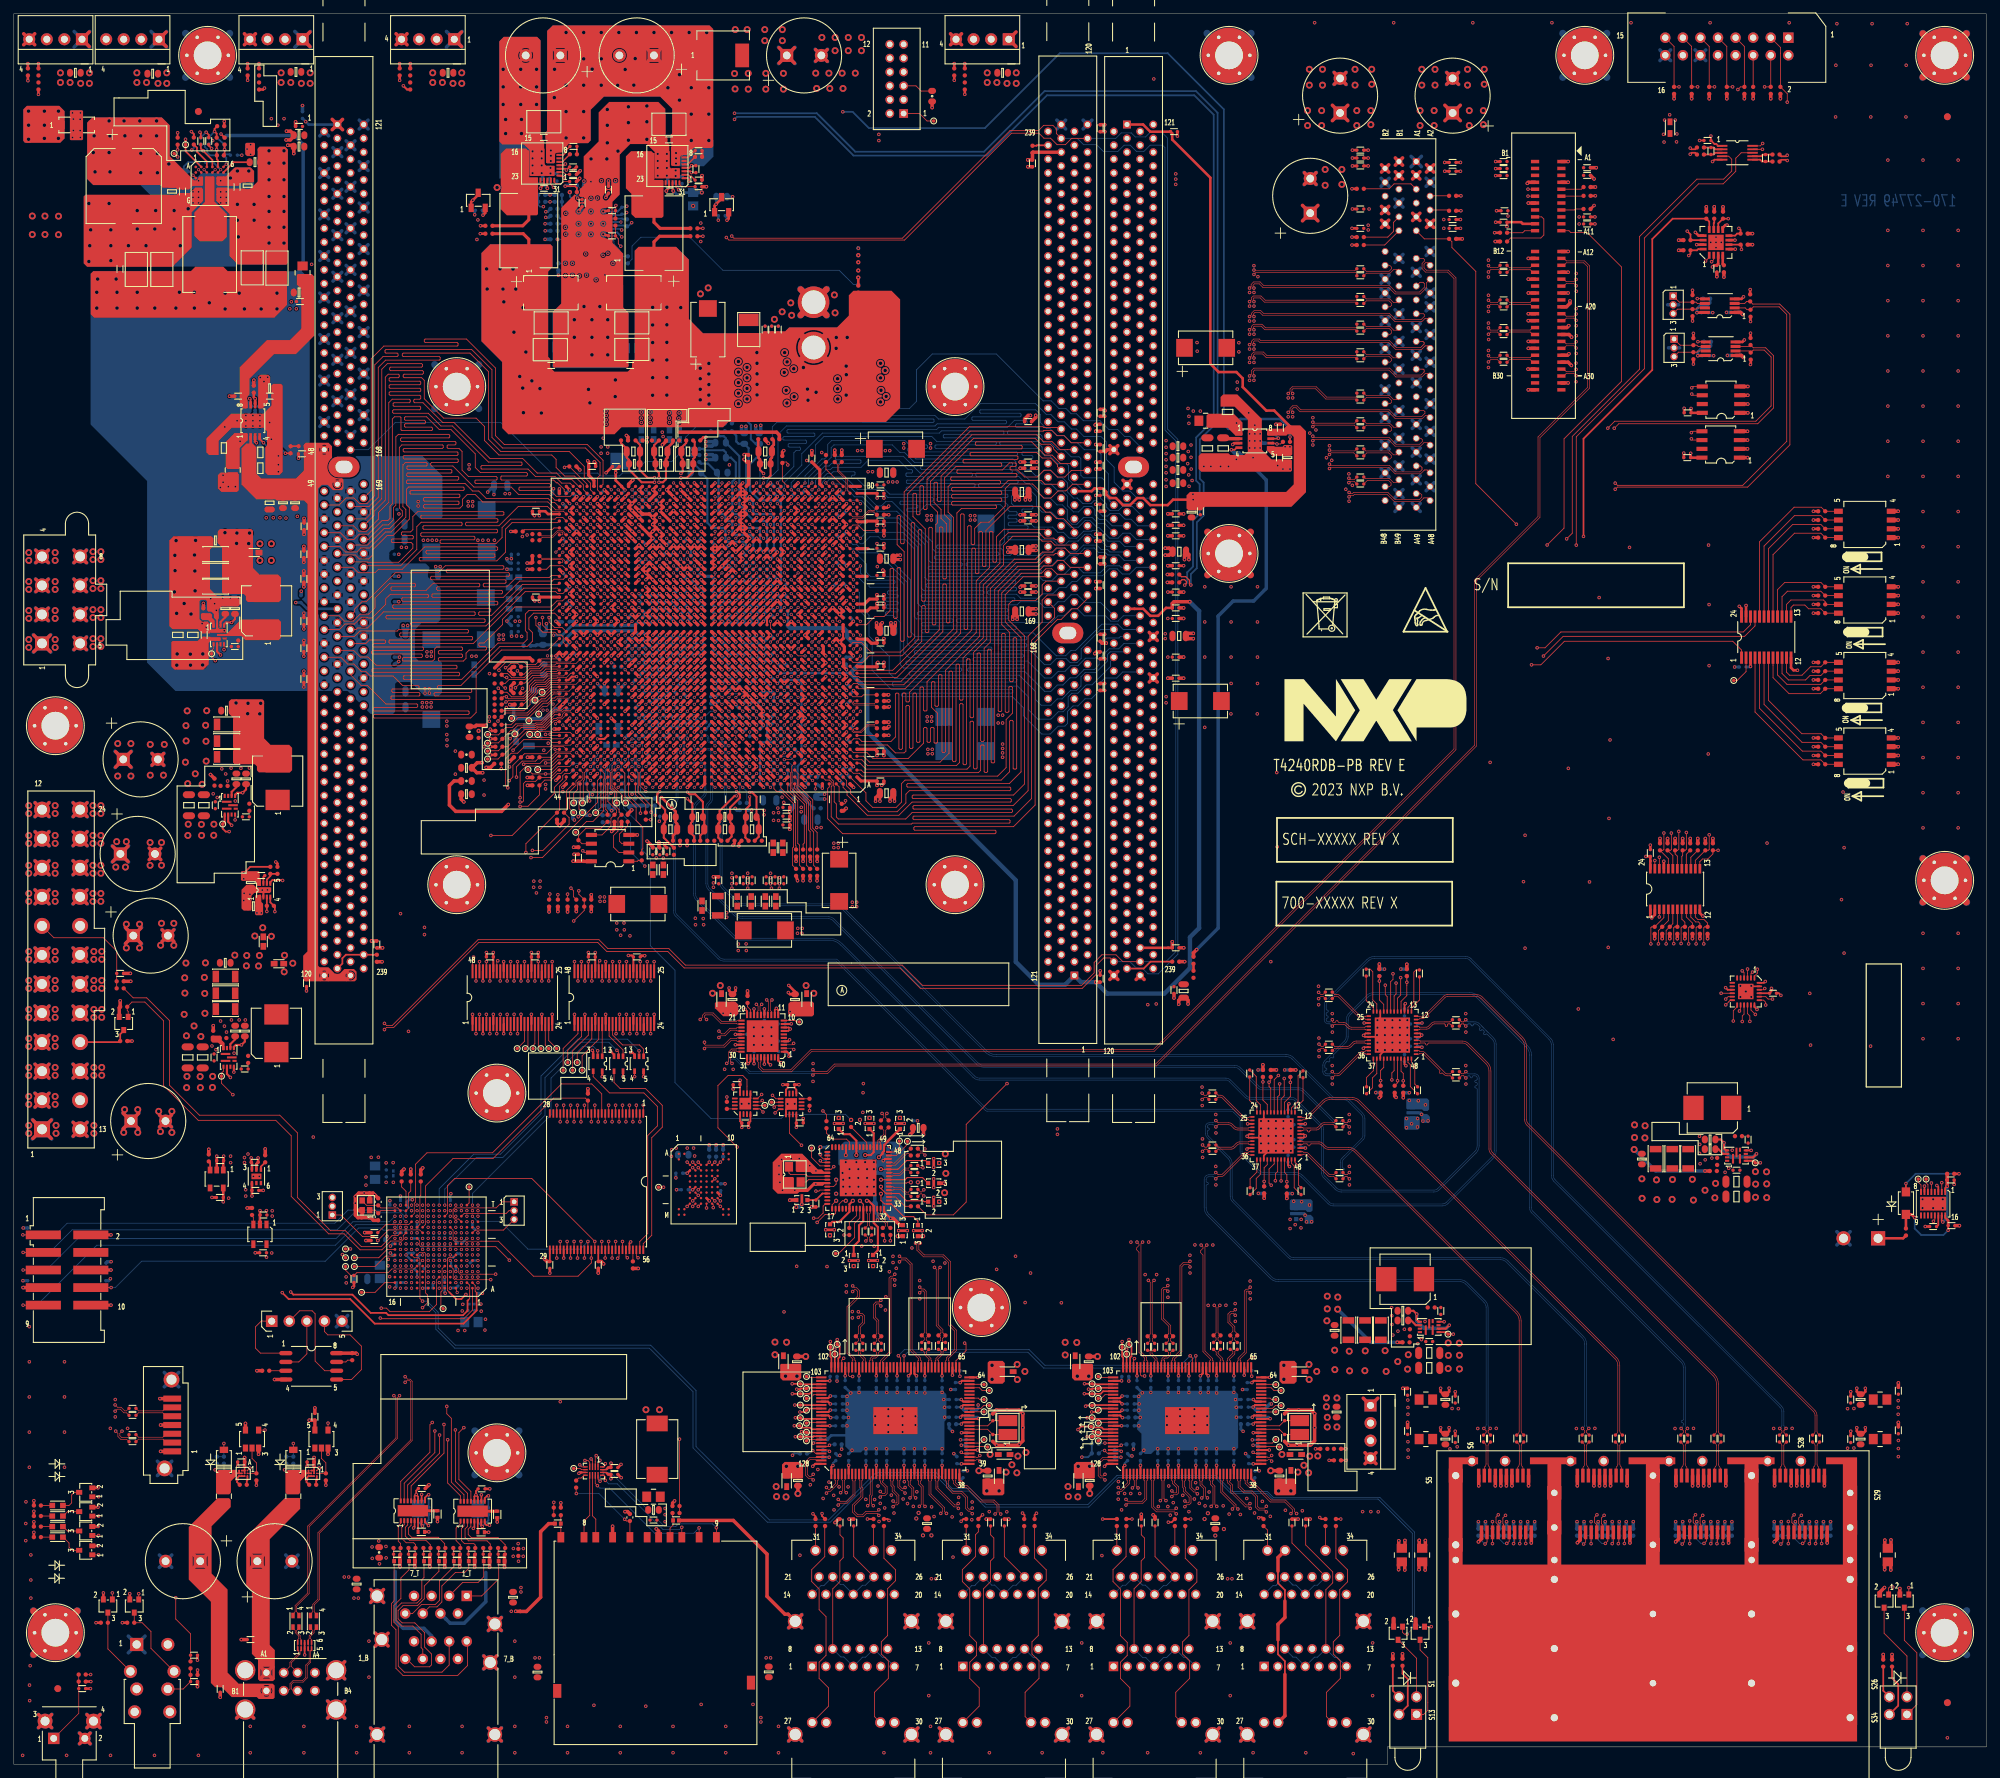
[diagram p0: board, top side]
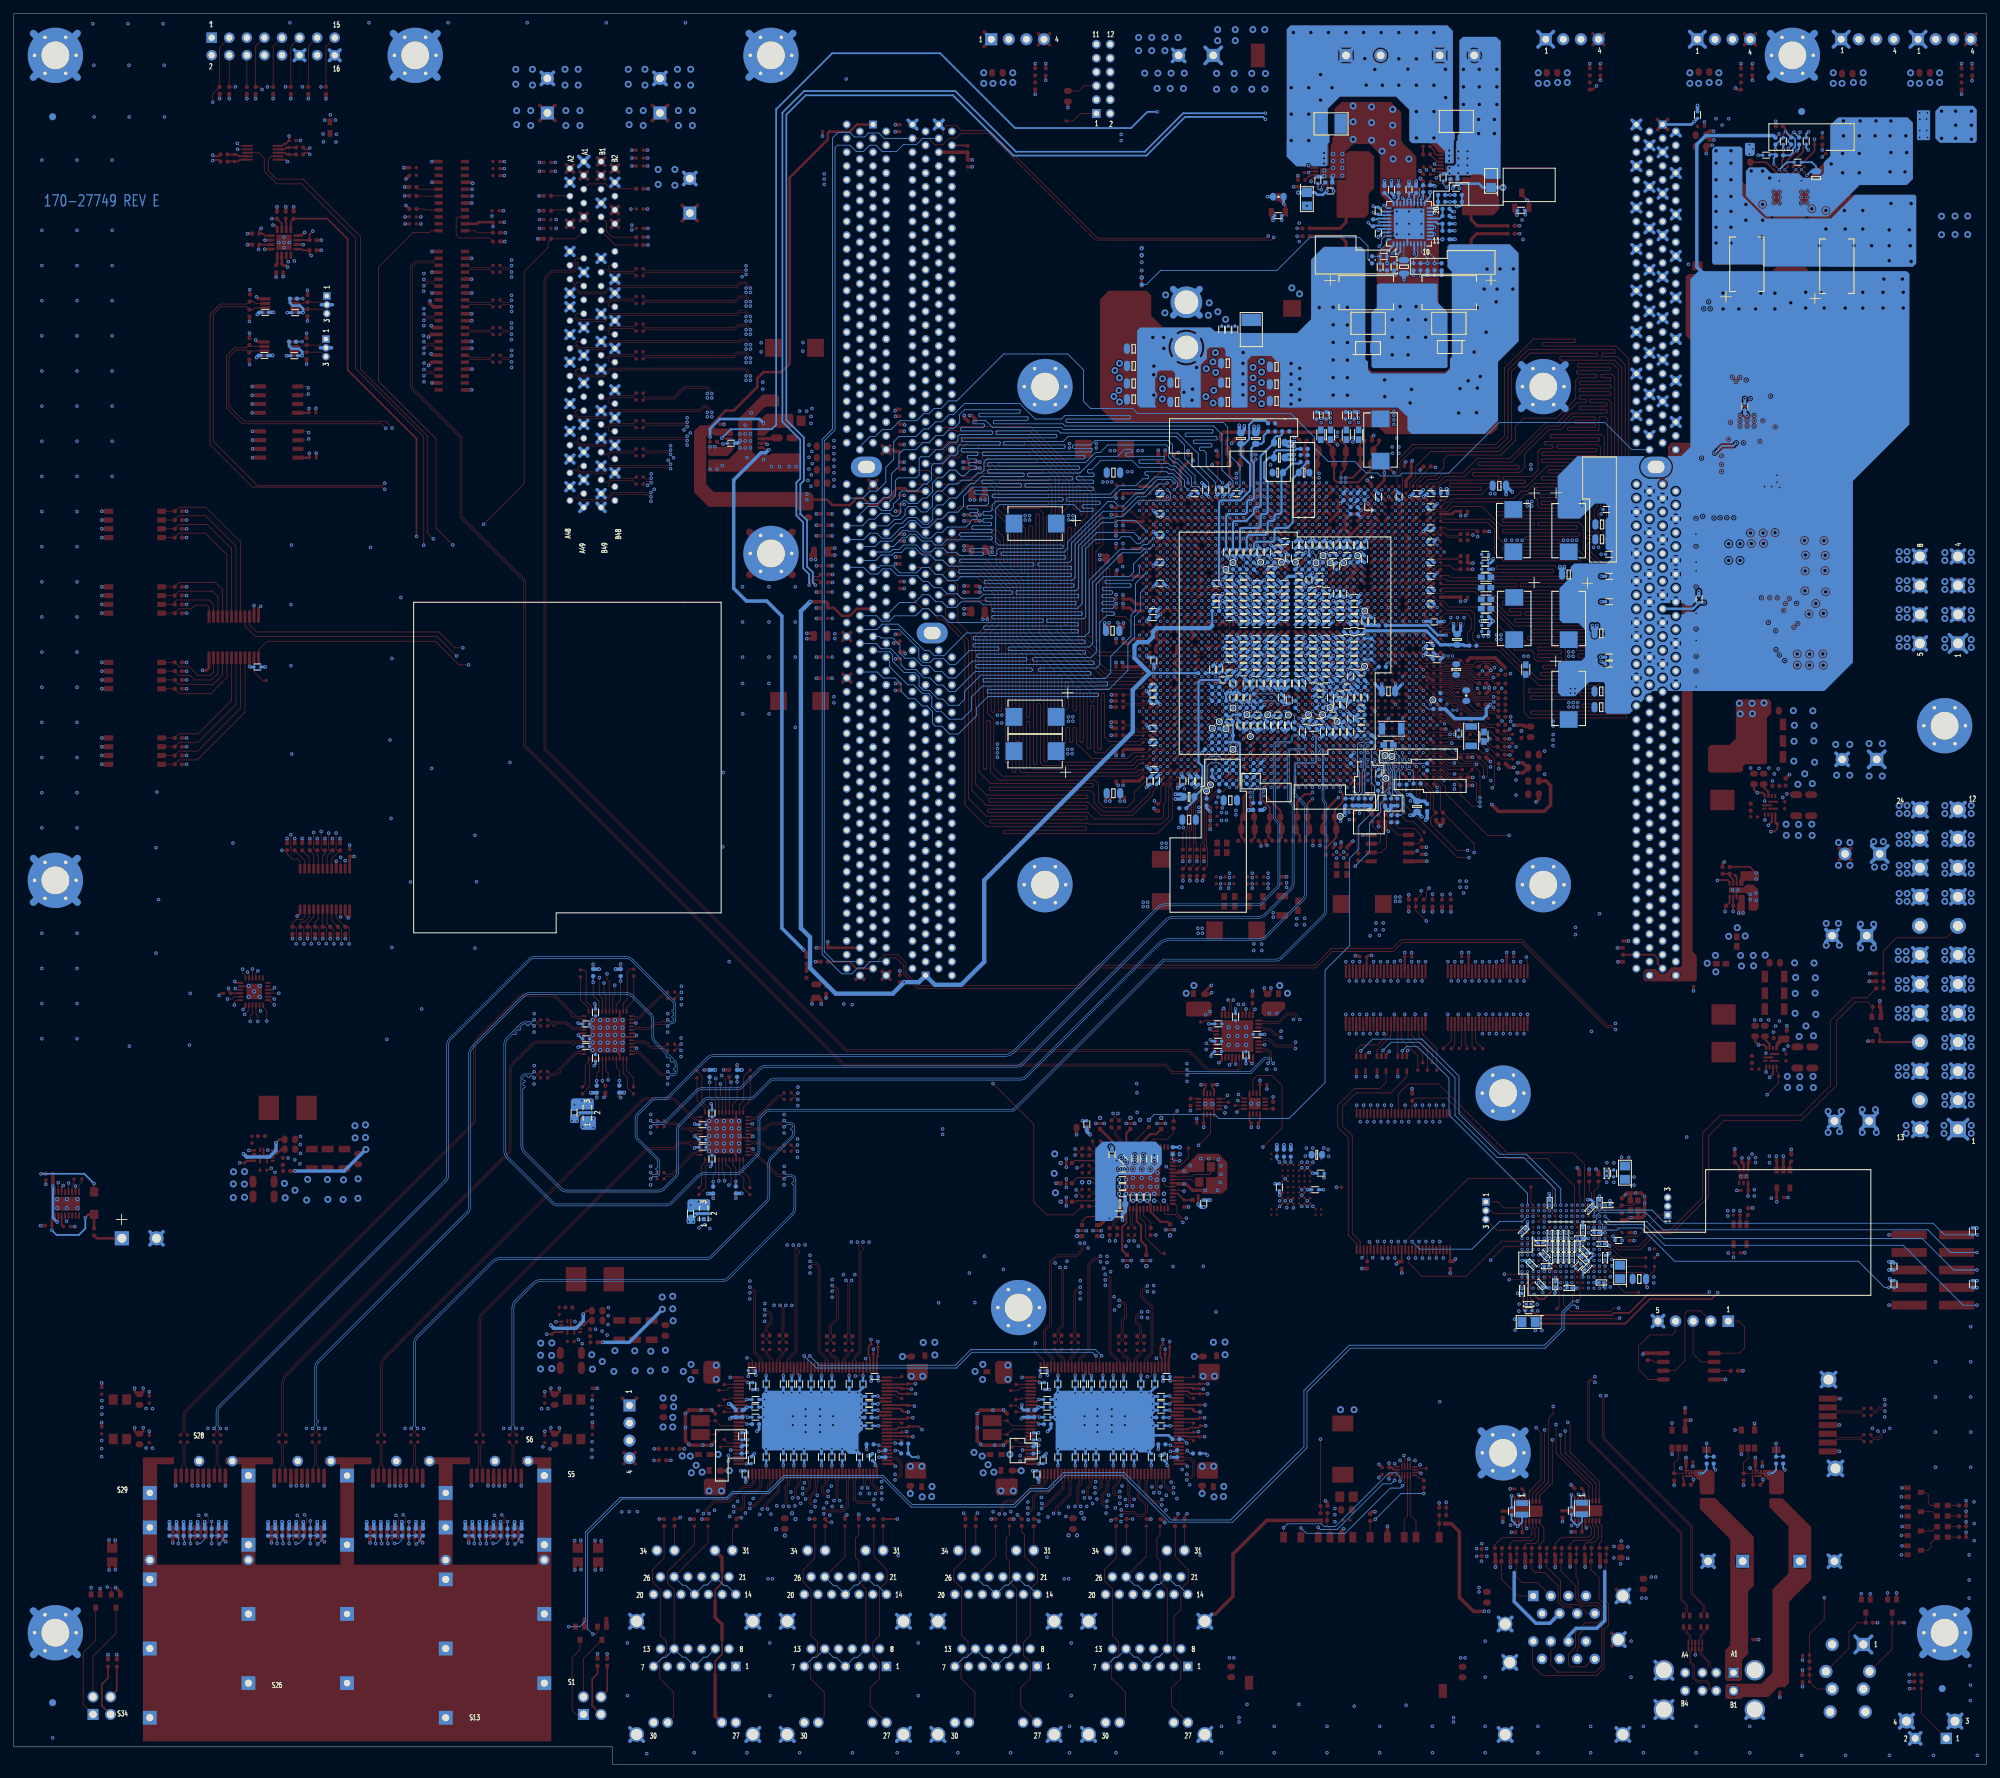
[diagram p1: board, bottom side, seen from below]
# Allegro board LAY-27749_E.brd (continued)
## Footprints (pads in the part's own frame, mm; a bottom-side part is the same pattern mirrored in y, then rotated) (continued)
CAP_5X19P2_TH
  rect 2.057x2.057 hole 1.295: 1(2.5,0)
  round 2.057 hole 1.295: 2(-2.5,0)
CAP_10P5_RAD
  rect 1.88x1.88 hole 1.118: 1(0,0)
  round 1.88 hole 1.118: 2(5,0)
CC0201
  rect 0.47x0.381 smd: 1(-0.343,0) 2(0.343,0)
CC0402_25
  round 0.635 smd: 1(-0.508,0) 2(0.508,0)
CC0402_HD
  round 0.508 smd: 1(-0.5,0) 2(0.5,0)
CC0402_TOL0P2
  rect 0.457x0.61 smd: 1(-0.475,0) 2(0.475,0)
CC0603_NFM18PC
  rect 0.61x0.61 smd: 1(-0.8,0) 3(0.8,0)
  rect 0.406x1.702 smd: 2(0,0)
CC0603_OV
  oval 0.889x1.143 smd: 1(-0.762,0) 2(0.762,0)
CC0805
  rect 1.295x1.499 smd: 1(-0.965,0) 2(0.965,0)
CC0805_OV
  oval 0.889x1.524 smd: 1(-0.965,0) 2(0.965,0)
CC1206_OV
  oval 1.016x1.778 smd: 1(-1.524,0) 2(1.524,0)
CC1210
  rect 1.778x2.845 smd: 1(-1.397,0) 2(1.397,0)
CC7343A
  rect 2.413x2.591 smd: 1(-3.05,0) 2(3.05,0)
CC7343A_LP
  rect 2.413x2.591 smd: 1(-3.05,0) 2(3.05,0)
CC_NFM41P_1806
  rect 1.295x1.219 smd: 1(-2.375,0) 3(2.375,0)
  rect 1.524x1.016 smd: 2A(0,-0.813) 2B(0,0.813)
CCE10_3X10_3
  rect 4.394x1.905 smd: 1(-4.343,0) 2(4.343,0)
CON12_SHRD_2MM_TH
  rect 1.27x1.27 hole 0.813: 1(0,0)
  round 1.27 hole 0.813: 2(0,2) 3(2,0) 4(2,2) 5(4,0) 6(4,2) 7(6,0) 8(6,2) 9(8,0) 10(8,2) 11(10,0) 12(10,2)
CON16_RJ45_JACK_50MIL_RA_TH
  round 0 hole 3.251 unplated: (-10.16,-15.46) (1.27,-15.46)
  round 1.524 hole 0.889: 1_B(-8.89,-9.11) 2_B(-7.62,-6.57) 2_T(-1.27,-2.54) 3_B(-6.35,-9.11) 3_T(-2.54,0) 4_B(-5.08,-6.57) 4_T(-3.81,-2.54) 5_B(-3.81,-9.11) 5_T(-5.08,0) 6_B(-2.54,-6.57) 6_T(-6.35,-2.54) 7_B(-1.27,-9.11) 7_T(-7.62,0) 8_B(0,-6.57) 8_T(-8.89,-2.54)
  rect 1.524x1.524 hole 0.889: 1_T(0,0)
  round 2.108 hole 1.6: S1(-12.95,0) S2(4.06,-4.06) S3(-12.285,-6.31) S4(3.395,-9.61) S5(-12.95,-20.03) S6(4.06,-20.03)
CON64_1MM_SM_PCIE_LP
  round 0 hole 1.27 unplated: (-17.85,0) (17.85,-1)
  rect 0.508x1.194 smd: A1(-16.5,1.9) A2(-15.5,1.9) A3(-14.5,1.9) A4(-13.5,1.9) A5(-12.5,1.9) A6(-11.5,1.9) A7(-10.5,1.9) A8(-9.5,1.9) A9(-8.5,1.9) A10(-7.5,1.9) A11(-6.5,1.9) A12(-3.5,1.9) A13(-2.5,1.9) A14(-1.5,1.9) A15(-0.5,1.9) A16(0.5,1.9) A17(1.5,1.9) A18(2.5,1.9) A19(3.5,1.9) A20(4.5,1.9) A21(5.5,1.9) A22(6.5,1.9) A23(7.5,1.9) A24(8.5,1.9) A25(9.5,1.9) A26(10.5,1.9) A27(11.5,1.9) A28(12.5,1.9) A29(13.5,1.9) A30(14.5,1.9) A31(15.5,1.9) A32(16.5,1.9) B1(-16.5,-1.9) B2(-15.5,-1.9) B3(-14.5,-1.9) B4(-13.5,-1.9) B5(-12.5,-1.9) B6(-11.5,-1.9) B7(-10.5,-1.9) B8(-9.5,-1.9) B9(-8.5,-1.9) B10(-7.5,-1.9) B11(-6.5,-1.9) B12(-3.5,-1.9) B13(-2.5,-1.9) B14(-1.5,-1.9) B15(-0.5,-1.9) B16(0.5,-1.9) B17(1.5,-1.9) B18(2.5,-1.9) B19(3.5,-1.9) B20(4.5,-1.9) B21(5.5,-1.9) B22(6.5,-1.9) B23(7.5,-1.9) B24(8.5,-1.9) B25(9.5,-1.9) B26(10.5,-1.9) B27(11.5,-1.9) B28(12.5,-1.9) B29(13.5,-1.9) B30(14.5,-1.9) B31(15.5,-1.9) B32(16.5,-1.9)
CON_7_SATA_V_SM
  rect 0.889x2.591 smd: 1(3.81,0.1) 2(2.54,0.1) 3(1.27,0.1) 4(0,0.1) 5(-1.27,0.1) 6(-2.54,0.1) 7(-3.81,0.1)
  round 2.286 hole 1.448: M1(-6.56,0) M2(6.27,-1)
CON_240_DDR3_DIMM_SKT
  round 0 hole 2.438 unplated: (-7.5,0.95) (130.5,0.95)
  oval 2.997x4.496 hole 1.803x2.438: (49.5,0.95)
  rect 1.143x1.143 hole 0.711: 1(0,0)
  round 1.143 hole 0.711: 2(1,-1.9) 3(2,0) 4(3,-1.9) 5(4,0) 6(5,-1.9) 7(6,0) 8(7,-1.9) 9(8,0) 10(9,-1.9) 11(10,0) 12(11,-1.9) 13(12,0) 14(13,-1.9) 15(14,0) 16(15,-1.9) 17(16,0) 18(17,-1.9) 19(18,0) 20(19,-1.9) 21(20,0) 22(21,-1.9) 23(22,0) 24(23,-1.9) 25(24,0) 26(25,-1.9) 27(26,0) 28(27,-1.9) 29(28,0) 30(29,-1.9) 31(30,0) 32(31,-1.9) 33(32,0) 34(33,-1.9) 35(34,0) 36(35,-1.9) 37(36,0) 38(37,-1.9) 39(38,0) 40(39,-1.9) 41(40,0) 42(41,-1.9) 43(42,0) 44(43,-1.9) 45(44,0) 46(45,-1.9) 47(46,0) 48(47,-1.9) 49(52,0) 50(53,-1.9) 51(54,0) 52(55,-1.9) 53(56,0) 54(57,-1.9) 55(58,0) 56(59,-1.9) 57(60,0) 58(61,-1.9) 59(62,0) 60(63,-1.9) 61(64,0) 62(65,-1.9) 63(66,0) 64(67,-1.9) 65(68,0) 66(69,-1.9) 67(70,0) 68(71,-1.9) 69(72,0) 70(73,-1.9) 71(74,0) 72(75,-1.9) 73(76,0) 74(77,-1.9) 75(78,0) 76(79,-1.9) 77(80,0) 78(81,-1.9) 79(82,0) 80(83,-1.9) 81(84,0) 82(85,-1.9) 83(86,0) 84(87,-1.9) 85(88,0) 86(89,-1.9) 87(90,0) 88(91,-1.9) 89(92,0) 90(93,-1.9) 91(94,0) 92(95,-1.9) 93(96,0) 94(97,-1.9) 95(98,0) 96(99,-1.9) 97(100,0) 98(101,-1.9) 99(102,0) 100(103,-1.9) 101(104,0) 102(105,-1.9) 103(106,0) 104(107,-1.9) 105(108,0) 106(109,-1.9) 107(110,0) 108(111,-1.9) 109(112,0) 110(113,-1.9) 111(114,0) 112(115,-1.9) 113(116,0) 114(117,-1.9) 115(118,0) 116(119,-1.9) 117(120,0) 118(121,-1.9) 119(122,0) 120(123,-1.9) 121(0,3.8) 122(1,1.9) 123(2,3.8) 124(3,1.9) 125(4,3.8) 126(5,1.9) 127(6,3.8) 128(7,1.9) 129(8,3.8) 130(9,1.9) 131(10,3.8) 132(11,1.9) 133(12,3.8) 134(13,1.9) 135(14,3.8) 136(15,1.9) 137(16,3.8) 138(17,1.9) 139(18,3.8) 140(19,1.9) 141(20,3.8) 142(21,1.9) 143(22,3.8) 144(23,1.9) 145(24,3.8) 146(25,1.9) 147(26,3.8) 148(27,1.9) 149(28,3.8) 150(29,1.9) 151(30,3.8) 152(31,1.9) 153(32,3.8) 154(33,1.9) 155(34,3.8) 156(35,1.9) 157(36,3.8) 158(37,1.9) 159(38,3.8) 160(39,1.9) 161(40,3.8) 162(41,1.9) 163(42,3.8) 164(43,1.9) 165(44,3.8) 166(45,1.9) 167(46,3.8) 168(47,1.9) 169(52,3.8) 170(53,1.9) 171(54,3.8) 172(55,1.9) 173(56,3.8) 174(57,1.9) 175(58,3.8) 176(59,1.9) 177(60,3.8) 178(61,1.9) 179(62,3.8) 180(63,1.9) 181(64,3.8) 182(65,1.9) 183(66,3.8) 184(67,1.9) 185(68,3.8) 186(69,1.9) 187(70,3.8) 188(71,1.9) 189(72,3.8) 190(73,1.9) 191(74,3.8) 192(75,1.9) 193(76,3.8) 194(77,1.9) 195(78,3.8) 196(79,1.9) 197(80,3.8) 198(81,1.9) 199(82,3.8) 200(83,1.9) 201(84,3.8) 202(85,1.9) 203(86,3.8) 204(87,1.9) 205(88,3.8) 206(89,1.9) 207(90,3.8) 208(91,1.9) 209(92,3.8) 210(93,1.9) 211(94,3.8) 212(95,1.9) 213(96,3.8) 214(97,1.9) 215(98,3.8) 216(99,1.9) 217(100,3.8) 218(101,1.9) 219(102,3.8) 220(103,1.9) 221(104,3.8) 222(105,1.9) 223(106,3.8) 224(107,1.9) 225(108,3.8) 226(109,1.9) 227(110,3.8) 228(111,1.9) 229(112,3.8) 230(113,1.9) 231(114,3.8) 232(115,1.9) 233(116,3.8) 234(117,1.9) 235(118,3.8) 236(119,1.9) 237(120,3.8) 238(121,1.9) 239(122,3.8) 240(123,1.9)
CON_ATXPWR_2X12_A
  round 0 hole 3.048 unplated: (-5.04,4.7) (-5.04,-50.9)
  rect 2.311x2.311 hole 1.422: 1(0,0)
  round 2.311 hole 1.422: 2(0,-4.2) 3(0,-8.4) 4(0,-12.6) 5(0,-16.8) 6(0,-21) 7(0,-25.2) 8(0,-29.4) 9(0,-33.6) 10(0,-37.8) 11(0,-42) 12(0,-46.2) 13(-5.5,0) 14(-5.5,-4.2) 15(-5.5,-8.4) 16(-5.5,-12.6) 17(-5.5,-16.8) 18(-5.5,-21) 19(-5.5,-25.2) 20(-5.5,-29.4) 21(-5.5,-33.6) 22(-5.5,-37.8) 23(-5.5,-42) 24(-5.5,-46.2)
CON_PCIE_98_1MM_TH_122L
  round 0 hole 2.362 unplated: (11.65,-1.25) (51.8,-1.25)
  rect 0.991x0.991 hole 0.711: A1(0,0)
  round 0.991 hole 0.711: A2(1,2) A3(2,0) A4(3,2) A5(4,0) A6(5,2) A7(6,0) A8(7,2) A9(8,0) A10(9,2) A11(10,0) A12(13,2) A13(14,0) A14(15,2) A15(16,0) A16(17,2) A17(18,0) A18(19,2) A19(20,0) A20(21,2) A21(22,0) A22(23,2) A23(24,0) A24(25,2) A25(26,0) A26(27,2) A27(28,0) A28(29,2) A29(30,0) A30(31,2) A31(32,0) A32(33,2) A33(34,0) A34(35,2) A35(36,0) A36(37,2) A37(38,0) A38(39,2) A39(40,0) A40(41,2) A41(42,0) A42(43,2) A43(44,0) A44(45,2) A45(46,0) A46(47,2) A47(48,0) A48(49,2) A49(50,0) B1(0,-2.5) B2(1,-4.5) B3(2,-2.5) B4(3,-4.5) B5(4,-2.5) B6(5,-4.5) B7(6,-2.5) B8(7,-4.5) B9(8,-2.5) B10(9,-4.5) B11(10,-2.5) B12(13,-4.5) B13(14,-2.5) B14(15,-4.5) B15(16,-2.5) B16(17,-4.5) B17(18,-2.5) B18(19,-4.5) B19(20,-2.5) B20(21,-4.5) B21(22,-2.5) B22(23,-4.5) B23(24,-2.5) B24(25,-4.5) B25(26,-2.5) B26(27,-4.5) B27(28,-2.5) B28(29,-4.5) B29(30,-2.5) B30(31,-4.5) B31(32,-2.5) B32(33,-4.5) B33(34,-2.5) B34(35,-4.5) B35(36,-2.5) B36(37,-4.5) B37(38,-2.5) B38(39,-4.5) B39(40,-2.5) B40(41,-4.5) B41(42,-2.5) B42(43,-4.5) B43(44,-2.5) B44(45,-4.5) B45(46,-2.5) B46(47,-4.5) B47(48,-2.5) B48(49,-4.5) B49(50,-2.5)
CON_RJ45_2X1_MAG_LED
  round 0 hole 3.251 unplated: (-0.61,-5.258) (12.497,-5.258)
  rect 1.372x1.372 hole 0.889: 1(0,0)
  round 1.372 hole 0.889: 2(1.981,0) 3(3.962,0) 4(5.944,0) 5(7.925,0) 6(9.906,0) 7(11.887,0) 8(0.991,2.54) 9(2.972,2.54) 10(4.953,2.54) 11(6.934,2.54) 12(8.915,2.54) 13(10.897,2.54) 14(0,10.414) 15(1.981,10.414) 16(3.962,10.414) 17(5.944,10.414) 18(7.925,10.414) 19(9.906,10.414) 20(11.887,10.414) 21(0.991,12.954) 22(2.972,12.954) 23(4.953,12.954) 24(6.934,12.954) 25(8.915,12.954) 26(10.897,12.954)
  round 1.524 hole 1.016: 27(0,-8.103) 28(2.032,-8.103) 29(9.855,-8.103) 30(11.887,-8.103) 31(0.483,16.764) 32(3.023,16.764) 33(8.865,16.764) 34(11.405,16.764)
  round 2.134 hole 1.626: S1(14.338,-9.83) S2(-2.451,-9.83) S3(14.338,6.528) S4(-2.451,6.528)
CON_SDCARD_28P9X29_SM_RA
  round 0 hole 1.499 unplated: (-12.675,-9.05) (11.525,-9.05)
  rect 0.991x1.499 smd: 1(6.325,15.26) 2(3.825,15.26) 3(0.475,15.26) 4(-1.175,15.26) 5(-3.675,15.26) 6(-6.175,15.26) 7(-8.605,15.26) 8(-10.305,15.26) 9(8.825,15.26) 10(2.125,15.26) 11(-13.655,15.26)
  rect 1.194x2.007 smd: G1(-14.175,-6.95) G2(13.825,-5.75)
CON_USB_8F_TH_RA
  rect 1.422x1.422 hole 0.914: A1(0,0)
  round 1.422 hole 0.914: A2(2.5,0) A3(4.5,0) A4(7,0) B1(0,-2.62) B2(2.5,-2.62) B3(4.5,-2.62) B4(7,-2.62)
  round 2.946 hole 2.311: M1(-3.07,0.35) M2(10.07,0.35) M3(-3.07,-5.33) M4(10.07,-5.33)
CONN_2X4_165_TH
  round 0 hole 2.997 unplated: (-17.285,5.055) (4.712,5.055)
  rect 2.032x2.032 hole 1.422: 1(0,0)
  round 2.032 hole 1.422: 2(-4.191,0) 3(-8.382,0) 4(-12.573,0) 5(0,5.512) 6(-4.191,5.512) 7(-8.382,5.512) 8(-12.573,5.512)
DFN6_0P65_2X2_EP
  rect 0.356x0.635 smd: 1(-0.65,-0.967) 2(0,-0.967) 3(0.65,-0.967) 4(0.65,0.967) 5(0,0.967) 6(-0.65,0.967)
  rect 1.448x0.838 smd: 7(0,0)
DFN16_0P5_3X5
  rect 0.711x0.305 smd: 1(-1.425,1.75) 2(-1.425,1.25) 3(-1.425,0.75) 4(-1.425,0.25) 5(-1.425,-0.25) 6(-1.425,-0.75) 7(-1.425,-1.25) 8(-1.425,-1.75) 9(1.425,-1.75) 10(1.425,-1.25) 11(1.425,-0.75) 12(1.425,-0.25) 13(1.425,0.25) 14(1.425,0.75) 15(1.425,1.25) 16(1.425,1.75)
  rect 1.65x4.4 smd: 17(0,0)
DIODE_BIDIR_0402
  rect 0.559x0.61 smd: 1(-0.425,0) 2(0.425,0)
FUSE_SMD050
  rect 2.286x3.048 smd: 1(-3.708,0) 2(3.708,0)
HDR1X3_50MIL_335H
  rect 1.092x1.092 hole 0.66: 1(0,0)
  round 1.092 hole 0.66: 2(-1.27,0) 3(-2.54,0)
HDR4_2P54_TH
  rect 1.753x1.753 hole 1.016: 1(0,0)
  round 1.753 hole 1.016: 2(2.54,0) 3(5.08,0) 4(7.62,0)
HDR105
  rect 1.676x1.676 hole 1.016: 1(0,0)
  round 1.676 hole 1.016: 2(0,-2.54) 3(0,-5.08) 4(0,-7.62) 5(0,-10.16)
HDR205_HTST_SM
  rect 5.08x1.27 smd: 1(-3.429,5.08) 2(3.429,5.08) 3(-3.429,2.54) 4(3.429,2.54) 5(-3.429,0) 6(3.429,0) 7(-3.429,-2.54) 8(3.429,-2.54) 9(-3.429,-5.08) 10(3.429,-5.08)
HDR208_4W
  rect 1.524x1.524 hole 0.914: 1(0,0)
  round 1.524 hole 0.914: 2(2.54,0) 3(0,-2.54) 4(2.54,-2.54) 5(0,-5.08) 6(2.54,-5.08) 7(0,-7.62) 8(2.54,-7.62) 9(0,-10.16) 10(2.54,-10.16) 11(0,-12.7) 12(2.54,-12.7) 13(0,-15.24) 14(2.54,-15.24) 15(0,-17.78) 16(2.54,-17.78)
IND2_10P4X8
  rect 2.997x2.54 smd: 1(-3.85,0) 2(3.85,0)
IND2_744308033
  rect 2.591x3.607 smd: 1(0,3.8) 2(0,-3.8)
IND2_SQ6P9_3_SM
  rect 2.946x3.505 smd: 1(-2.725,0) 2(2.725,0)
IND_1P8X1MM_SM
  rect 0.991x0.711 smd: 1(-0.845,0) 2(0.845,0)
IND_0603
  rect 0.991x0.813 smd: 1(-0.69,0) 2(0.69,0)
IND_0805
  rect 1.295x1.499 smd: 1(-0.978,0) 2(0.978,0)
IND_0805_4P
  rect 0.813x0.508 smd: 1(0.835,0.435) 2(-0.835,0.435) 3(-0.835,-0.435) 4(0.835,-0.435)
IND_2016A
  rect 0.864x1.803 smd: 1(-0.835,0) 2(0.835,0)
IND_IHLP
  rect 2.007x3.429 smd: 1(-2.794,0) 2(2.743,0)
LED_0603
  rect 0.838x0.787 smd: A(-0.775,0) C(0.775,0)
LED_DUAL_553_TH
  rect 1.6x1.6 hole 1.092: 1(0,0)
  round 1.6 hole 1.092: 2(-2.54,0) 3(0,2.54) 4(-2.54,2.54)
LQFP128_0P5_20X14_EPAD
  rect 0.305x1.499 smd: 1(-9.25,-7.7) 2(-8.75,-7.7) 3(-8.25,-7.7) 4(-7.75,-7.7) 5(-7.25,-7.7) 6(-6.75,-7.7) 7(-6.25,-7.7) 8(-5.75,-7.7) 9(-5.25,-7.7) 10(-4.75,-7.7) 11(-4.25,-7.7) 12(-3.75,-7.7) 13(-3.25,-7.7) 14(-2.75,-7.7) 15(-2.25,-7.7) 16(-1.75,-7.7) 17(-1.25,-7.7) 18(-0.75,-7.7) 19(-0.25,-7.7) 20(0.25,-7.7) 21(0.75,-7.7) 22(1.25,-7.7) 23(1.75,-7.7) 24(2.25,-7.7) 25(2.75,-7.7) 26(3.25,-7.7) 27(3.75,-7.7) 28(4.25,-7.7) 29(4.75,-7.7) 30(5.25,-7.7) 31(5.75,-7.7) 32(6.25,-7.7) 33(6.75,-7.7) 34(7.25,-7.7) 35(7.75,-7.7) 36(8.25,-7.7) 37(8.75,-7.7) 38(9.25,-7.7) 65(9.25,7.7) 66(8.75,7.7) 67(8.25,7.7) 68(7.75,7.7) 69(7.25,7.7) 70(6.75,7.7) 71(6.25,7.7) 72(5.75,7.7) 73(5.25,7.7) 74(4.75,7.7) 75(4.25,7.7) 76(3.75,7.7) 77(3.25,7.7) 78(2.75,7.7) 79(2.25,7.7) 80(1.75,7.7) 81(1.25,7.7) 82(0.75,7.7) 83(0.25,7.7) 84(-0.25,7.7) 85(-0.75,7.7) 86(-1.25,7.7) 87(-1.75,7.7) 88(-2.25,7.7) 89(-2.75,7.7) 90(-3.25,7.7) 91(-3.75,7.7) 92(-4.25,7.7) 93(-4.75,7.7) 94(-5.25,7.7) 95(-5.75,7.7) 96(-6.25,7.7) 97(-6.75,7.7) 98(-7.25,7.7) 99(-7.75,7.7) 100(-8.25,7.7) 101(-8.75,7.7) 102(-9.25,7.7)
  rect 1.499x0.305 smd: 39(10.7,-6.25) 40(10.7,-5.75) 41(10.7,-5.25) 42(10.7,-4.75) 43(10.7,-4.25) 44(10.7,-3.75) 45(10.7,-3.25) 46(10.7,-2.75) 47(10.7,-2.25) 48(10.7,-1.75) 49(10.7,-1.25) 50(10.7,-0.75) 51(10.7,-0.25) 52(10.7,0.25) 53(10.7,0.75) 54(10.7,1.25) 55(10.7,1.75) 56(10.7,2.25) 57(10.7,2.75) 58(10.7,3.25) 59(10.7,3.75) 60(10.7,4.25) 61(10.7,4.75) 62(10.7,5.25) 63(10.7,5.75) 64(10.7,6.25) 103(-10.7,6.25) 104(-10.7,5.75) 105(-10.7,5.25) 106(-10.7,4.75) 107(-10.7,4.25) 108(-10.7,3.75) 109(-10.7,3.25) 110(-10.7,2.75) 111(-10.7,2.25) 112(-10.7,1.75) 113(-10.7,1.25) 114(-10.7,0.75) 115(-10.7,0.25) 116(-10.7,-0.25) 117(-10.7,-0.75) 118(-10.7,-1.25) 119(-10.7,-1.75) 120(-10.7,-2.25) 121(-10.7,-2.75) 122(-10.7,-3.25) 123(-10.7,-3.75) 124(-10.7,-4.25) 125(-10.7,-4.75) 126(-10.7,-5.25) 127(-10.7,-5.75) 128(-10.7,-6.25)
  rect 6.401x3.912 smd: 129(0,0)
MH180-135P
  round 4.572 hole 3.429: 1(0,0)
MH315-158T_6P
  round 8.001 hole 4.013: 1(0,0)
  round 1.016 hole 0.508: 2(1.502,2.601) 3(3.004,0) 4(1.502,-2.601) 5(-1.502,-2.601) 6(-3.004,0) 7(-1.502,2.601)
MSOP8_0P65_3P1X3P1_EPAD
  rect 1.016x0.406 smd: 1(-2.3,0.975) 2(-2.3,0.325) 3(-2.3,-0.325) 4(-2.3,-0.975) 5(2.3,-0.975) 6(2.3,-0.325) 7(2.3,0.325) 8(2.3,0.975)
  rect 2.007x2.591 smd: 9(0,0)
MSOP10_60X12
  rect 1.524x0.279 smd: 1(-2.197,1.001) 2(-2.197,0.501) 3(-2.197,0.001) 4(-2.197,-0.499) 5(-2.197,-0.999) 6(2.197,-0.999) 7(2.197,-0.499) 8(2.197,0.001) 9(2.197,0.501) 10(2.197,1.001)
POWERPAK_MLP55
  oval 0.762x0.305 smd: 1(-2.419,1.75)
  rect 0.762x0.305 smd: 2(-2.419,1.25) 3(-2.419,0.75) 4(-2.419,0.25) 5(-2.419,-0.25) 6(-2.419,-0.75) 7(-2.419,-1.25) 8(-2.419,-1.75)
  custom 0.188x0.188 smd: 16(2.215,0)
  custom 0.187x0.187 smd: 26(1.255,2.425)
  rect 0.305x0.762 smd: 27(0.255,2.419) 28(-0.245,2.419) 29(-0.745,2.419) 30(-1.245,2.419)
  oval 0.305x0.762 smd: 31(-1.745,2.419)
  rect 1.143x1.422 smd: 32(-1.19,1.041)
  custom 0.326x0.326 smd: 34(-1.19,-1.435)
  custom 0.544x0.544 smd: 35(0.74,-0.525)
QFN12_0P5_2P05X3P05MM
  rect 1.397x0.305 smd: 1(0.453,-0.5) 2(0.453,0.5) 8(-0.453,0)
  rect 0.305x0.61 smd: 3(0.75,1.35) 4(0.25,1.35) 5(-0.25,1.35) 6(-0.75,1.35) 9(-0.75,-1.35) 10(-0.25,-1.35) 11(0.25,-1.35) 12(0.75,-1.35)
  rect 0.61x0.305 smd: 7(-0.847,0.5)
QFN16_0P5_3X3MM
  custom 0.07x0.07 smd: 1(-1.496,0.75) 2(-1.496,0.25) 3(-1.496,-0.25) 4(-1.496,-0.75) 5(-0.75,-1.496) 6(-0.25,-1.496) 7(0.25,-1.496) 8(0.75,-1.496) 9(1.496,-0.75) 10(1.496,-0.25) 11(1.496,0.25) 12(1.496,0.75) 13(0.75,1.496) 14(0.25,1.496) 15(-0.25,1.496) 16(-0.75,1.496)
  rect 1.702x1.702 smd: 17(0,0)
QFN24_4X4_EP2P25MM
  oval 0.279x0.813 smd: 1(-1.25,-1.956) 2(-0.75,-1.956) 3(-0.25,-1.956) 4(0.25,-1.956) 5(0.75,-1.956) 6(1.25,-1.956) 13(1.25,1.956) 14(0.75,1.956) 15(0.25,1.956) 16(-0.25,1.956) 17(-0.75,1.956) 18(-1.25,1.956)
  oval 0.813x0.279 smd: 7(1.956,-1.25) 8(1.956,-0.75) 9(1.956,-0.25) 10(1.956,0.25) 11(1.956,0.75) 12(1.956,1.25) 19(-1.956,1.25) 20(-1.956,0.75) 21(-1.956,0.25) 22(-1.956,-0.25) 23(-1.956,-0.75) 24(-1.956,-1.25)
  rect 2.235x2.235 smd: 25(0,0)
QFN40_0P5_6P1X6P1
  rect 0.711x0.254 smd: 1(-2.9,2.25) 2(-2.9,1.75) 3(-2.9,1.25) 4(-2.9,0.75) 5(-2.9,0.25) 6(-2.9,-0.25) 7(-2.9,-0.75) 8(-2.9,-1.25) 9(-2.9,-1.75) 10(-2.9,-2.25) 21(2.9,-2.25) 22(2.9,-1.75) 23(2.9,-1.25) 24(2.9,-0.75) 25(2.9,-0.25) 26(2.9,0.25) 27(2.9,0.75) 28(2.9,1.25) 29(2.9,1.75) 30(2.9,2.25)
  rect 0.254x0.711 smd: 11(-2.25,-2.9) 12(-1.75,-2.9) 13(-1.25,-2.9) 14(-0.75,-2.9) 15(-0.25,-2.9) 16(0.25,-2.9) 17(0.75,-2.9) 18(1.25,-2.9) 19(1.75,-2.9) 20(2.25,-2.9) 31(2.25,2.9) 32(1.75,2.9) 33(1.25,2.9) 34(0.75,2.9) 35(0.25,2.9) 36(-0.25,2.9) 37(-0.75,2.9) 38(-1.25,2.9) 39(-1.75,2.9) 40(-2.25,2.9)
  custom 1.105x1.105 smd: 41(0,0)
QFN40_0P5_6X6_4P6EP
  rect 0.914x0.305 smd: 1(-3.057,2.25) 2(-3.057,1.75) 3(-3.057,1.25) 4(-3.057,0.75) 5(-3.057,0.25) 6(-3.057,-0.25) 7(-3.057,-0.75) 8(-3.057,-1.25) 9(-3.057,-1.75) 10(-3.057,-2.25) 21(3.057,-2.25) 22(3.057,-1.75) 23(3.057,-1.25) 24(3.057,-0.75) 25(3.057,-0.25) 26(3.057,0.25) 27(3.057,0.75) 28(3.057,1.25) 29(3.057,1.75) 30(3.057,2.25)
  rect 0.305x0.914 smd: 11(-2.25,-3.057) 12(-1.75,-3.057) 13(-1.25,-3.057) 14(-0.75,-3.057) 15(-0.25,-3.057) 16(0.25,-3.057) 17(0.75,-3.057) 18(1.25,-3.057) 19(1.75,-3.057) 20(2.25,-3.057) 31(2.25,3.057) 32(1.75,3.057) 33(1.25,3.057) 34(0.75,3.057) 35(0.25,3.057) 36(-0.25,3.057) 37(-0.75,3.057) 38(-1.25,3.057) 39(-1.75,3.057) 40(-2.25,3.057)
  rect 4.597x4.597 smd: 41(0,0)
QFN48_0P5_7X7_EP5P1
  rect 0.61x0.254 smd: 1(-3.4,2.75) 2(-3.4,2.25) 3(-3.4,1.75) 4(-3.4,1.25) 5(-3.4,0.75) 6(-3.4,0.25) 7(-3.4,-0.25) 8(-3.4,-0.75) 9(-3.4,-1.25) 10(-3.4,-1.75) 11(-3.4,-2.25) 12(-3.4,-2.75) 25(3.4,-2.75) 26(3.4,-2.25) 27(3.4,-1.75) 28(3.4,-1.25) 29(3.4,-0.75) 30(3.4,-0.25) 31(3.4,0.25) 32(3.4,0.75) 33(3.4,1.25) 34(3.4,1.75) 35(3.4,2.25) 36(3.4,2.75)
  rect 0.254x0.61 smd: 13(-2.75,-3.4) 14(-2.25,-3.4) 15(-1.75,-3.4) 16(-1.25,-3.4) 17(-0.75,-3.4) 18(-0.25,-3.4) 19(0.25,-3.4) 20(0.75,-3.4) 21(1.25,-3.4) 22(1.75,-3.4) 23(2.25,-3.4) 24(2.75,-3.4) 37(2.75,3.4) 38(2.25,3.4) 39(1.75,3.4) 40(1.25,3.4) 41(0.75,3.4) 42(0.25,3.4) 43(-0.25,3.4) 44(-0.75,3.4) 45(-1.25,3.4) 46(-1.75,3.4) 47(-2.25,3.4) 48(-2.75,3.4)
  rect 5.105x5.105 smd: 49(0,0)
QFN64_0P5_9X9C
  oval 0.889x0.305 smd: 1(-4.45,3.75) 2(-4.45,3.25) 3(-4.45,2.75) 4(-4.45,2.25) 5(-4.45,1.75) 6(-4.45,1.25) 7(-4.45,0.75) 8(-4.45,0.25) 9(-4.45,-0.25) 10(-4.45,-0.75) 11(-4.45,-1.25) 12(-4.45,-1.75) 13(-4.45,-2.25) 14(-4.45,-2.75) 15(-4.45,-3.25) 16(-4.45,-3.75) 33(4.45,-3.75) 34(4.45,-3.25) 35(4.45,-2.75) 36(4.45,-2.25) 37(4.45,-1.75) 38(4.45,-1.25) 39(4.45,-0.75) 40(4.45,-0.25) 41(4.45,0.25) 42(4.45,0.75) 43(4.45,1.25) 44(4.45,1.75) 45(4.45,2.25) 46(4.45,2.75) 47(4.45,3.25) 48(4.45,3.75)
  oval 0.305x0.889 smd: 17(-3.75,-4.45) 18(-3.25,-4.45) 19(-2.75,-4.45) 20(-2.25,-4.45) 21(-1.75,-4.45) 22(-1.25,-4.45) 23(-0.75,-4.45) 24(-0.25,-4.45) 25(0.25,-4.45) 26(0.75,-4.45) 27(1.25,-4.45) 28(1.75,-4.45) 29(2.25,-4.45) 30(2.75,-4.45) 31(3.25,-4.45) 32(3.75,-4.45) 49(3.75,4.45) 50(3.25,4.45) 51(2.75,4.45) 52(2.25,4.45) 53(1.75,4.45) 54(1.25,4.45) 55(0.75,4.45) 56(0.25,4.45) 57(-0.25,4.45) 58(-0.75,4.45) 59(-1.25,4.45) 60(-1.75,4.45) 61(-2.25,4.45) 62(-2.75,4.45) 63(-3.25,4.45) 64(-3.75,4.45)
  rect 5.309x5.309 smd: 65(0,0)
RC0402_25
  round 0.635 smd: 1(-0.508,0) 2(0.508,0)
RC0402_HD
  round 0.508 smd: 1(-0.5,0) 2(0.5,0)
RC0603_OV
  oval 0.889x1.143 smd: 1(-0.762,0) 2(0.762,0)
RC0805_OV
  oval 0.889x1.524 smd: 1(-0.965,0) 2(0.965,0)
SC70-5
  rect 0.406x0.813 smd: 1(-0.65,-1.079) 2(0,-1.079) 3(0.65,-1.079) 4(0.65,1.079) 5(-0.65,1.079)
SC70_3
  rect 0.711x0.889 smd: 1(-0.648,-0.952) 2(0.648,-0.952) 3(0,0.952)
SO8-25X75-200
  oval 0.635x1.905 smd: 1(-1.905,-3.67) 2(-0.635,-3.67) 3(0.635,-3.67) 4(1.905,-3.67) 5(1.905,3.67) 6(0.635,3.67) 7(-0.635,3.67) 8(-1.905,3.67)
SO8_1P27_4X5
  rect 1.6x0.61 smd: 1(-2.7,1.905) 2(-2.7,0.635) 3(-2.7,-0.635) 4(-2.7,-1.905) 5(2.7,-1.905) 6(2.7,-0.635) 7(2.7,0.635) 8(2.7,1.905)
SO16_0P5_3P5X4P5_MM
  rect 0.889x0.279 smd: 1(-1.7,1.75) 2(-1.7,1.25) 3(-1.7,0.75) 4(-1.7,0.25) 5(-1.7,-0.25) 6(-1.7,-0.75) 7(-1.7,-1.25) 8(-1.7,-1.75) 9(1.7,-1.75) 10(1.7,-1.25) 11(1.7,-0.75) 12(1.7,-0.25) 13(1.7,0.25) 14(1.7,0.75) 15(1.7,1.25) 16(1.7,1.75)
  rect 2x3.8 smd: 17(0,0)
SOD123_A
  rect 0.914x1.219 smd: A(1.7,0) C(-1.7,0)
SOD-123
  rect 1.321x1.219 smd: A(-1.626,0) C(1.626,0)
SOT23
  rect 0.762x1.219 smd: 1(-1.016,-1.092) 2(1.016,-1.092) 3(0,1.092)
SOT23-5
  rect 0.61x1.118 smd: 1(-0.95,-1.425) 2(0,-1.425) 3(0.95,-1.425) 4(0.95,1.425) 5(-0.95,1.425)
SOT23-5_A
  rect 1.016x0.762 smd: 1(-1.3,0.95) 2(-1.3,0) 3(-1.3,-0.95) 4(1.3,-0.95) 5(1.3,0.95)
SOT-23-5
  rect 0.686x0.991 smd: 1(-0.953,-1.295) 2(0,-1.295) 3(0.953,-1.295) 4(0.953,1.295) 5(-0.953,1.295)
SUBASSY_SFP_34_CAGE_1X4_49P8X61P85
  round 0 hole 1.549 unplated: (25.9,-2.325) (25.9,-11.925) (25.9,-16.575) (25.9,-26.175) (25.9,-30.825) (25.9,-40.425) (25.9,-45.075) (25.9,-54.675)
  rect 2.007x0.508 smd: 1A(21.8,-3.725) 1B(21.8,-17.975) 1C(21.8,-32.225) 1D(21.8,-46.475) 2A(21.8,-4.525) 2B(21.8,-18.775) 2C(21.8,-33.025) 2D(21.8,-47.275) 3A(21.8,-5.325) 3B(21.8,-19.575) 3C(21.8,-33.825) 3D(21.8,-48.075) 4A(21.8,-6.125) 4B(21.8,-20.375) 4C(21.8,-34.625) 4D(21.8,-48.875) 5A(21.8,-6.925) 5B(21.8,-21.175) 5C(21.8,-35.425) 5D(21.8,-49.675) 6A(21.8,-7.725) 6B(21.8,-21.975) 6C(21.8,-36.225) 6D(21.8,-50.475) 7A(21.8,-8.525) 7B(21.8,-22.775) 7C(21.8,-37.025) 7D(21.8,-51.275) 8A(21.8,-9.325) 8B(21.8,-23.575) 8C(21.8,-37.825) 8D(21.8,-52.075) 9A(21.8,-10.125) 9B(21.8,-24.375) 9C(21.8,-38.625) 9D(21.8,-52.875) 10A(21.8,-10.925) 10B(21.8,-25.175) 10C(21.8,-39.425) 10D(21.8,-53.675) 11A(30,-10.525) 11B(30,-24.775) 11C(30,-39.025) 11D(30,-53.275) 12A(30,-9.725) 12B(30,-23.975) 12C(30,-38.225) 12D(30,-52.475) 13A(30,-8.925) 13B(30,-23.175) 13C(30,-37.425) 13D(30,-51.675) 14A(30,-8.125) 14B(30,-22.375) 14C(30,-36.625) 14D(30,-50.875) 15A(30,-7.325) 15B(30,-21.575) 15C(30,-35.825) 15D(30,-50.075) 16A(30,-6.525) 16B(30,-20.775) 16C(30,-35.025) 16D(30,-49.275) 17A(30,-5.725) 17B(30,-19.975) 17C(30,-34.225) 17D(30,-48.475) 18A(30,-4.925) 18B(30,-19.175) 18C(30,-33.425) 18D(30,-47.675) 19A(30,-4.125) 19B(30,-18.375) 19C(30,-32.625) 19D(30,-46.875) 20A(30,-3.325) 20B(30,-17.575) 20C(30,-31.825) 20D(30,-46.075)
  rect 2.007x2.007 hole 1.041: S1(0,0) S2(10,0) S4(20,0) S5(30,0) S11(15,-14.25) S12(5,-14.25) S13(-5,-14.25) S22(30,-42.75) S23(20,-42.75) S25(10,-42.75) S26(0,-42.75) S32(15,-57) S33(5,-57) S34(-5,-57)
  round 1.524 hole 0.94: S3(17.8,0) S6(32.1,-2.33) S7(32.1,-7.13) S10(17.8,-14.25) S14(32.1,-16.58) S15(32.1,-21.38) S20(32.1,-30.83) S21(32.1,-35.63) S24(17.8,-42.75) S27(32.1,-45.08) S28(32.1,-49.88) S31(17.8,-57)
  rect 2.007x2.007 hole 0.94: S8(27.5,-14.25) S9(22.5,-14.25) S16(30,-28.5) S17(20,-28.5) S18(10,-28.5) S19(0,-28.5) S29(27.5,-57) S30(22.5,-57)
SW2_TL1105S
  rect 1.651x1.651 hole 0.991: 1(0,0)
  round 1.651 hole 0.991: 2(4.5,0)
  round 2.159 hole 1.295: 3(-1.25,2.5) 4(5.75,2.5)
SW4_DIP_1P27_6P3X5P7
  rect 0.762x1.27 smd: 1(-1.905,-3.81) 2(-0.635,-3.81) 3(0.635,-3.81) 4(1.905,-3.81) 5(1.905,3.81) 6(0.635,3.81) 7(-0.635,3.81) 8(-1.905,3.81)
SW6_TACT_LED_TH
  rect 1.905x1.905 hole 1.194: 1(0,0)
  round 1.905 hole 1.194: 2(-6.44,0) 3(0,-4.5) 4(-6.44,-4.5) 5(-3.9,0.9) 6(-3.9,-5.4) MH1(-9.74,0.29) MH2(-9.74,-4.79)
TDFN8_1P98_2P10X2P10
  rect 0.711x0.305 smd: 1(-0.99,0.75) 2(-0.99,0.25) 3(-0.99,-0.25) 4(-0.99,-0.75) 5(0.99,-0.75) 6(0.99,-0.25) 7(0.99,0.25) 8(0.99,0.75)
  rect 0.787x1.372 smd: 9(0,0)
TPAD_020_TOP
  round 0.508 smd: 1(0,0)
TQFN16_0P65_4X4MM_TAB
  rect 0.406x1.016 smd: 1(-0.975,-1.863) 2(-0.325,-1.863) 3(0.325,-1.863) 4(0.975,-1.863) 9(0.975,1.863) 10(0.325,1.863) 11(-0.325,1.863) 12(-0.975,1.863)
  rect 1.016x0.406 smd: 5(1.863,-0.975) 6(1.863,-0.325) 7(1.863,0.325) 8(1.863,0.975) 13(-1.863,0.975) 14(-1.863,0.325) 15(-1.863,-0.325) 16(-1.863,-0.975)
  rect 2.235x2.235 smd: 17(0,0)
TSOP56_0P5_14X18
  rect 1.219x0.279 smd: 1(-9.85,6.75) 2(-9.85,6.25) 3(-9.85,5.75) 4(-9.85,5.25) 5(-9.85,4.75) 6(-9.85,4.25) 7(-9.85,3.75) 8(-9.85,3.25) 9(-9.85,2.75) 10(-9.85,2.25) 11(-9.85,1.75) 12(-9.85,1.25) 13(-9.85,0.75) 14(-9.85,0.25) 15(-9.85,-0.25) 16(-9.85,-0.75) 17(-9.85,-1.25) 18(-9.85,-1.75) 19(-9.85,-2.25) 20(-9.85,-2.75) 21(-9.85,-3.25) 22(-9.85,-3.75) 23(-9.85,-4.25) 24(-9.85,-4.75) 25(-9.85,-5.25) 26(-9.85,-5.75) 27(-9.85,-6.25) 28(-9.85,-6.75) 29(9.85,-6.75) 30(9.85,-6.25) 31(9.85,-5.75) 32(9.85,-5.25) 33(9.85,-4.75) 34(9.85,-4.25) 35(9.85,-3.75) 36(9.85,-3.25) 37(9.85,-2.75) 38(9.85,-2.25) 39(9.85,-1.75) 40(9.85,-1.25) 41(9.85,-0.75) 42(9.85,-0.25) 43(9.85,0.25) 44(9.85,0.75) 45(9.85,1.25) 46(9.85,1.75) 47(9.85,2.25) 48(9.85,2.75) 49(9.85,3.25) 50(9.85,3.75) 51(9.85,4.25) 52(9.85,4.75) 53(9.85,5.25) 54(9.85,5.75) 55(9.85,6.25) 56(9.85,6.75)
TSSOP8_A
  rect 1.448x0.457 smd: 1(-2.15,0.975) 2(-2.15,0.325) 3(-2.15,-0.325) 4(-2.15,-0.975) 5(2.15,-0.975) 6(2.15,-0.325) 7(2.15,0.325) 8(2.15,0.975)
TSSOP24_0P65_7P9X4P5
  rect 1.372x0.406 smd: 1(-2.927,3.575) 2(-2.927,2.925) 3(-2.927,2.275) 4(-2.927,1.625) 5(-2.927,0.975) 6(-2.927,0.325) 7(-2.927,-0.325) 8(-2.927,-0.975) 9(-2.927,-1.625) 10(-2.927,-2.275) 11(-2.927,-2.925) 12(-2.927,-3.575) 13(2.927,-3.575) 14(2.927,-2.925) 15(2.927,-2.275) 16(2.927,-1.625) 17(2.927,-0.975) 18(2.927,-0.325) 19(2.927,0.325) 20(2.927,0.975) 21(2.927,1.625) 22(2.927,2.275) 23(2.927,2.925) 24(2.927,3.575)
TSSOP48_PH
  rect 2.032x0.305 smd: 1(-3.81,5.753) 2(-3.81,5.253) 3(-3.81,4.752) 4(-3.81,4.252) 5(-3.81,3.752) 6(-3.81,3.251) 7(-3.81,2.751) 8(-3.81,2.25) 9(-3.81,1.75) 10(-3.81,1.25) 11(-3.81,0.749) 12(-3.81,0.249) 13(-3.81,-0.251) 14(-3.81,-0.752) 15(-3.81,-1.252) 16(-3.81,-1.753) 17(-3.81,-2.253) 18(-3.81,-2.753) 19(-3.81,-3.254) 20(-3.81,-3.754) 21(-3.81,-4.255) 22(-3.81,-4.755) 23(-3.81,-5.255) 24(-3.81,-5.756) 25(3.81,-5.756) 26(3.81,-5.255) 27(3.81,-4.755) 28(3.81,-4.255) 29(3.81,-3.754) 30(3.81,-3.254) 31(3.81,-2.753) 32(3.81,-2.253) 33(3.81,-1.753) 34(3.81,-1.252) 35(3.81,-0.752) 36(3.81,-0.251) 37(3.81,0.249) 38(3.81,0.749) 39(3.81,1.25) 40(3.81,1.75) 41(3.81,2.25) 42(3.81,2.751) 43(3.81,3.251) 44(3.81,3.752) 45(3.81,4.252) 46(3.81,4.752) 47(3.81,5.253) 48(3.81,5.753)
TSSOP_24_0P65_8X4
  rect 1.778x0.432 smd: 1(-2.97,3.575) 2(-2.97,2.925) 3(-2.97,2.275) 4(-2.97,1.625) 5(-2.97,0.975) 6(-2.97,0.325) 7(-2.97,-0.325) 8(-2.97,-0.975) 9(-2.97,-1.625) 10(-2.97,-2.275) 11(-2.97,-2.925) 12(-2.97,-3.575) 13(2.97,-3.575) 14(2.97,-2.925) 15(2.97,-2.275) 16(2.97,-1.625) 17(2.97,-0.975) 18(2.97,-0.325) 19(2.97,0.325) 20(2.97,0.975) 21(2.97,1.625) 22(2.97,2.275) 23(2.97,2.925) 24(2.97,3.575)
unnamed#2
  round 1.016 smd: (0,0)
VFBGA63_0P8_9X11
  round 0.356 smd: A1(-3.6,4.4) A2(-2.8,4.4) A9(2.8,4.4) A10(3.6,4.4) B1(-3.6,3.6) B9(2.8,3.6) B10(3.6,3.6) C3(-2,2.8) C4(-1.2,2.8) C5(-0.4,2.8) C6(0.4,2.8) C7(1.2,2.8) C8(2,2.8) D3(-2,2) D4(-1.2,2) D5(-0.4,2) D6(0.4,2) D7(1.2,2) D8(2,2) E3(-2,1.2) E4(-1.2,1.2) E5(-0.4,1.2) E6(0.4,1.2) E7(1.2,1.2) E8(2,1.2) F3(-2,0.4) F4(-1.2,0.4) F5(-0.4,0.4) F6(0.4,0.4) F7(1.2,0.4) F8(2,0.4) G3(-2,-0.4) G4(-1.2,-0.4) G5(-0.4,-0.4) G6(0.4,-0.4) G7(1.2,-0.4) G8(2,-0.4) H3(-2,-1.2) H4(-1.2,-1.2) H5(-0.4,-1.2) H6(0.4,-1.2) H7(1.2,-1.2) H8(2,-1.2) J3(-2,-2) J4(-1.2,-2) J5(-0.4,-2) J6(0.4,-2) J7(1.2,-2) J8(2,-2) K3(-2,-2.8) K4(-1.2,-2.8) K5(-0.4,-2.8) K6(0.4,-2.8) K7(1.2,-2.8) K8(2,-2.8) L1(-3.6,-3.6) L2(-2.8,-3.6) L9(2.8,-3.6) L10(3.6,-3.6) M1(-3.6,-4.4) M2(-2.8,-4.4) M9(2.8,-4.4) M10(3.6,-4.4)
WLCSP12_0P4_1P38X1P68MM_SMDP
  round 0.254 smd: A1(-0.4,0.6) A2(0,0.6) A3(0.4,0.6) B1(-0.4,0.2) B2(0,0.2) B3(0.4,0.2) C1(-0.4,-0.2) C2(0,-0.2) C3(0.4,-0.2) D1(-0.4,-0.6) D2(0,-0.6) D3(0.4,-0.6)
XQFN16_0P4_2P7X1P9
  rect 0.203x0.965 smd: 1(-0.6,-0.625) 2(-0.2,-0.625) 3(0.2,-0.625) 4(0.6,-0.625) 9(0.6,0.625) 10(0.2,0.625) 11(-0.2,0.625) 12(-0.6,0.625)
  rect 0.66x0.203 smd: 5(1.21,-0.6) 6(1.21,-0.2) 7(1.21,0.2) 8(1.21,0.6) 13(-1.21,0.6) 14(-1.21,0.2) 15(-1.21,-0.2) 16(-1.21,-0.6)
XSON10_0P5_1P1X2P6MM
  rect 0.711x0.254 smd: 1(-0.457,1) 2(-0.457,0.5) 3(-0.457,0) 4(-0.457,-0.5) 5(-0.457,-1) 6(0.457,-1) 7(0.457,-0.5) 8(0.457,0) 9(0.457,0.5) 10(0.457,1)
XTAL2_3P3X2P6
  rect 1.6x2.718 smd: 1(-1,0) 2(1,0)
XTAL4_2P1X1P7
  rect 0.914x0.813 smd: 1(-0.7,-0.55) 2(0.7,-0.55) 3(0.7,0.55) 4(-0.7,0.55)
XTAL_4_3P3X2P6MM
  rect 1.397x1.194 smd: 1(-1.1,-0.85) 2(1.1,-0.85) 3(1.1,0.85) 4(-1.1,0.85)

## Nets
1V2_SB: C3725.1 C3728.1 C3729.1 C3730.1 C3731.1 C3732.1 C3733.1 C3734.1 C3735.1 C3736.1 C3737.1 C3738.1 C3739.1 C3742.1 C3744.1 C5121.1 U27.F7 U27.F9 U27.G6 U27.G8 U27.G10 U27.H7 U27.H9 U27.J8 U27.J10 U27.K7 U27.K9 U27.L8 U607.5(VOUT)
1V2SB_EN: R5729.2 U607.3
1V8_SB: C3836.1 C3837.1 C3838.1 C3839.1 C3840.1 C3841.1 C3842.1 C3843.1 C5118.1 R671.1 U27.A11 U27.B14 U27.C7 U27.D10 U27.H2 U27.J6 U27.L1 U27.L6 U27.L10 U27.M4 U27.N7 U27.P10 U27.R3 U27.R13 U27.T6 U606.5(VOUT)
1V8SB_EN: R5728.2 U606.3
2V5: C805.1 C806.1 C848.1 C1265.1 C5245.1 C5246.1 C5247.1 C5248.2 FL14.3(OUT_IN) FL19.3(OUT_IN) FL25.1 FL26.1 L57.2 R2.1 R734.1 R735.1 R740.1 R744.1 R757.1 R5815.1 R5817.1 R5825.1 R5826.1 R5827.1 R5828.1 R5838.1 R5839.1 R5840.1 U22.L14 U22.R16 U22.R17
3V3_SB: C7.1 C65.1 C412.1 C3699.1 C3700.1 C3701.1 C3702.1 C3703.1 C3710.1 C3711.1 C3712.1 C3713.1 C3714.1 C3716.1 C3717.1 C3718.1 C3719.1 C3720.1 C3721.1 C3722.1 C3723.1 C3724.1 C3743.1 C3745.1 C3747.1 C5117.1 C5120.1 D46.A J3.B10 J105.6 J105.7 R151.2 R206.2 R332.1 R333.1 R335.1 R341.1 R672.1 R992.1 R993.1 R994.1 R995.1 R1969.1 R5582.1 R5583.1 R5588.1 R5589.1 R5667.1 R5671.1 R5729.1 SW1.1 SW1.2 SW1.3 SW1.4 SW2.1 SW2.2 SW2.3 SW2.4 SW3.1 SW3.2 SW3.3 SW3.4 SW4.1 SW4.2 SW4.3 SW4.4 U2.1(VDD) U27.A1 U27.B4 U27.E3 U27.E13 U27.F6 U27.F16 U27.G11 U27.H11 U27.H12 U27.J15 U27.K5 U27.K11 U27.L12 U27.M14 U27.T15 U27.T16 U55.B10 U250.8 U605.4(VOUT) U607.1 U610.3 U610.24(VDD)
3V3SB_EN: R5727.2 U605.1
5V0_SB: C5116.1 C5119.1 CT31.1 J9.9(VSTDBY) R394.2 R665.1 R666.1 R5727.1 R5728.1 U605.3 U606.1
12V0_2_VDD_FLT: C5276.1 C5277.1 C5278.1 C5279.1 C5286.1 C5287.1 C5288.1 C5289.1 L3.1 R43.2 U7.8 U7.34 U9.8 U9.34
12V0_FILTERED_PS_GVDD: C2679.1 C2680.1 C5122.1 C5125.1 C5126.1 FL6.3(OUTPUT) R92.1 U631.C2 U631.C5 U631.C6 U631.D1 U631.D2 U631.D5 U631.D6
AGND_SRDS1_PLL1: C263.2 C271.2 C841.2 R316.1 U22.L18
AGND_SRDS1_PLL2: C262.2 C270.2 C842.2 R315.1 U22.L20
AGND_SRDS2_PLL1: C261.2 C269.2 C845.2 R312.1 U22.L25
AGND_SRDS2_PLL2: C260.2 C268.2 C843.2 R311.1 U22.L27
AGND_SRDS3_PLL1: C123.2 C136.2 C617.2 R181.1 U22.AP21
AGND_SRDS3_PLL2: C122.2 C135.2 C616.2 R176.1 U22.AP23
AGND_SRDS4_PLL1: C121.2 C134.2 C618.2 R180.1 U22.AP28
AGND_SRDS4_PLL2: C120.2 C133.2 C619.2 R177.1 U22.AP30
AVDD_CGA1: C567.1 C607.1 R686.2 U22.AP13
AVDD_CGA2: C568.1 C608.1 R687.2 U22.AR13
AVDD_CGA3: C569.1 C609.1 R689.2 U22.AR14
AVDD_CGB1: C572.1 C611.1 R691.2 U22.AR16
AVDD_CGB2: C571.1 C610.1 R690.2 U22.AR15
AVDD_DDR1: C800.1 C878.1 R770.2 U22.T13
AVDD_DDR2: C566.1 C638.1 R685.2 U22.AJ13
AVDD_DDR3: C715.1 C728.1 R708.2 U22.AC32
AVDD_PLAT: C802.1 C879.1 R769.2 U22.T28
AVDD_SRDS1_PLL1: C263.1 C271.1 C841.1 R317.1 U22.L17
AVDD_SRDS1_PLL2: C262.1 C270.1 C842.1 R314.1 U22.L21
AVDD_SRDS2_PLL1: C261.1 C269.1 C845.1 R313.1 U22.L24
AVDD_SRDS2_PLL2: C260.1 C268.1 C843.1 R319.1 U22.L28
AVDD_SRDS3_PLL1: C123.1 C136.1 C617.1 R182.1 U22.AP20
AVDD_SRDS3_PLL2: C122.1 C135.1 C616.1 R175.1 U22.AP24
AVDD_SRDS4_PLL1: C121.1 C134.1 C618.1 R179.1 U22.AP27
AVDD_SRDS4_PLL2: C120.1 C133.1 C619.1 R178.1 U22.AP31
GND: BH10.1 C1.1 C3.2 C4.2 C5.1 C6.2 C7.2 C8.2 C10.2 C15.2 C16.2 C17.2 C18.2 C25.2 C26.2 C27.2 C28.2 C35.2 C40.2 C41.2 C42.2 C43.2 C58.2 C60.2 C65.2 C66.2 C83.2 C84.2 C85.2 C89.1 C91.2 C94.2 C97.2 C98.2 C102.2 C104.1 C105.2 C106.1 C107.2 C109.2 C110.2 C112.2 C113.2 C114.2 C117.2 C119.2 C125.1 C127.2 C128.2 C129.2 C130.1 C131.2 C137.2 C138.2 C141.2 C143.2 C144.2 C145.2 C148.2 C150.2 C151.2 C152.2 C153.1 C157.2 C158.1 C159.1 C161.2 C162.1 C163.2 C164.2 C165.2 C166.1 C167.1 C168.2 C169.1 C170.2 C171.2 C172.2 C173.2 C176.2 C179.1 C182.2 C185.2 C186.2 C187.1 C189.1 C190.2 C191.2 C192.2 C196.2 C197.2 C199.2 C201.1 C202.2 C205.2 C207.1 C208.2 C209.2 C211.2 C215.2 C216.2 C218.2 C220.2 C221.1 C240.2 C246.2 C250.2 C251.2 C252.2 C253.2 C255.2 C256.2 C258.2 C259.2 C265.2 C273.2 C274.2 C275.2 C276.2 C280.2 C281.2 C282.2 C283.2 C284.2 C285.2 C286.2 C288.2 C295.2 C296.2 C297.2 C299.2 C300.2 C303.2 C304.2 C305.2 C309.2 C310.2 C332.2 C334.2 C341.2 C345.2 C346.2 C347.2 C412.2 C433.2 C434.2 C467.2 C472.2 C485.2 C505.2 C515.2 C516.2 C518.2 C519.2 C520.2 C522.2 C523.2 C546.2 C547.2 C548.2 C549.2 C550.2 C551.2 C552.2 C553.2 C554.2 C555.2 C556.2 C557.2 C562.2 C563.2 C564.2 C565.2 C566.2 C567.2 C568.2 C569.2 C570.2 C571.2 C572.2 C573.2 C574.2 C575.2 C576.2 C577.2 C578.2 C579.2 C580.2 C581.2 C582.2 C583.2 C584.2 C585.2 C586.1 C587.2 C588.2 C590.2 C591.2 C592.2 C593.2 C594.2 C595.2 C596.2 C597.2 C598.2 C599.2 C600.2 C601.2 C602.2 C603.2 C604.2 C605.2 C606.2 C607.2 C608.2 C609.2 C610.2 C611.2 C612.2 C613.2 C614.2 C615.1 C620.2 C621.2 C622.2 C623.2 C624.2 C625.2 C626.2 C627.2 C628.2 C629.2 C630.2 C631.2 C632.2 C633.2 C634.2 C635.2 C636.2 C637.2 C638.2 C639.2 C640.2 C641.2 C642.2 C643.2 C644.2 C645.2 C646.2 C647.2 C648.2 C649.2 C650.2 C651.2 C652.2 C653.2 C654.2 C655.2 C656.2 C657.2 C658.2 C659.2 C660.2 C661.2 C662.2 C663.2 C664.2 C665.2 C666.2 C667.2 C668.2 C669.2 C670.2 C671.2 C672.2 C673.2 C674.2 C675.2 C676.2 C677.2 C678.2 C679.2 C680.2 C681.2 C682.2 C683.2 C684.2 C685.2 C686.2 C687.2 C688.2 C689.2 C690.2 C691.2 C692.2 C693.2 C694.2 C695.2 C696.2 C697.2 C698.2 C699.2 C700.2 C701.2 C702.2 C703.2 C704.2 C705.2 C706.2 C707.2 C708.2 C709.2 C710.2 C711.2 C712.2 C713.2 C714.2 C715.2 C716.2 C717.1 C718.2 C719.2 C720.2 C721.2 C722.2 C723.2 C724.2 C725.2 C726.2 C727.2 C728.2 C729.2 C730.2 C731.2 C732.2 C733.2 C734.2 C735.2 C736.2 C737.2 C741.2 C742.2 C743.2 C744.2 C745.2 C746.2 C747.2 C748.2 C749.2 C750.2 C751.2 C752.2 C753.2 C754.1 C755.2 C756.2 C757.2 C758.2 C759.2 C760.2 C761.2 C762.2 C763.2 C764.2 C765.2 C766.2 C770.1 C771.2 C772.2 C773.2 C774.2 C775.2 C776.2 C777.2 C778.2 C779.2 C780.2 C781.2 C782.2 C786.2 C787.2 C788.2 C789.2 C790.2 C791.2 C792.2 C793.2 C794.2 C795.2 C796.2 C800.2 C801.2 C802.2 C803.2 C804.2 C805.2 C806.2 C807.2 C808.2 C809.2 C810.2 C811.2 C812.2 C813.2 C817.2 C818.2 C819.2 C821.2 C822.2 C823.2 C824.2 C825.2 C827.2 C828.2 C829.2 C830.2 C831.2 C832.2 C833.2 C834.2 C835.2 C836.2 C837.2 C838.2 C839.2 C840.2 C844.2 C846.2 C847.2 C848.2 C849.2 C850.2 C851.2 C852.2 C853.2 C854.2 C855.2 C856.2 C857.2 C858.2 C859.2 C860.2 C861.2 C862.2 C863.2 C864.2 C865.2 C866.2 C867.2 C868.2 C869.2 C870.2 C871.1 C872.2 C873.2 C874.2 C875.2 C876.2 C877.2 C878.2 C879.2 C880.2 C900.2 C924.2 C932.2 C936.2 C940.2 C944.2 C947.2 C950.2 C961.2 C965.2 C987.2 C991.2 C992.2 C993.2 C1002.2 C1109.2 C1110.2 C1111.2 C1112.2 C1113.2 C1141.2 C1142.2 C1143.2 C1144.2 C1145.2 C1146.2 C1147.2 C1148.2 C1149.2 C1150.2 C1151.2 C1152.2 C1158.2 C1240.1 C1241.2 C1242.2 C1243.2 C1247.1 C1250.1 C1251.2 C1252.2 C1253.2 C1254.2 C1256.2 C1257.1 C1259.2 C1260.2 C1261.2 C1262.2 C1263.2 C1264.2 C1265.2 C1266.2 C2636.2 C2637.2 C2673.2 C2679.2 C2680.2 C2704.2 C2705.2 C3690.2 C3691.2 C3699.2 C3700.2 C3701.2 C3702.2 C3703.2 C3710.2 C3711.2 C3712.2 C3713.2 C3714.2 C3716.2 C3717.2 C3718.2 C3719.2 C3720.2 C3721.2 C3722.2 C3723.2 C3724.2 C3725.2 C3728.2 C3729.2 C3730.2 C3731.2 C3732.2 C3733.2 C3734.2 C3735.2 C3736.2 C3737.2 C3738.2 C3739.2 C3742.2 C3743.2 C3744.2 C3745.2 C3747.2 C3831.2 C3836.2 C3837.2 C3838.2 C3839.2 C3840.2 C3841.2 C3842.2 C3843.2 C3844.2 C3847.2 C3848.2 C3849.2 C3850.2 C3851.2 C3852.2 C3853.2 C3854.2 C3855.2 C3856.2 C3857.2 C3858.2 C3859.2 C3860.2 C3861.2 C3862.2 C3863.2 C3864.2 C3865.2 C3866.2 C3867.2 C3868.2 C3869.2 C3870.2 C3889.2 C3890.2 C3891.2 C3892.2 C3894.2 C3895.2 C3897.2 C3898.2 C3899.2 C3900.2 C5116.2 C5117.2 C5118.2 C5119.2 C5120.2 C5121.2 C5122.2 C5123.2 C5124.2 C5125.2 C5126.2 C5127.2 C5128.2 C5129.2 C5130.2 C5134.2 C5138.2 C5139.1 C5140.2 C5141.1 C5142.2 C5143.1 C5144.2 C5145.2 C5146.2 C5147.2 C5148.2 C5150.1 C5151.2 C5152.2 C5153.1 C5154.2 C5155.2 C5156.2 C5157.1 C5158.2 C5160.1 C5161.2 C5162.2 C5163.1 C5164.2 C5165.2 C5166.2 C5167.1 C5168.2 C5171.2 C5174.1 C5175.1 C5176.2 C5178.2 C5179.2 C5180.2 C5181.2 C5182.2 C5183.2 C5184.2 C5185.2 C5186.2 C5187.2 C5188.2 C5189.2 C5190.2 C5191.2 C5192.2 C5193.2 C5194.2 C5195.2 C5196.2 C5197.2 C5198.2 C5199.2 C5200.2 C5201.2 C5203.1 C5204.2 C5205.2 C5206.1 C5207.2 C5208.2 C5209.2 C5210.1 C5211.2 C5213.2 C5214.2 C5215.2 C5216.2 C5217.2 C5218.2 C5219.2 C5220.2 C5221.2 C5222.2 C5223.2 C5224.2 C5225.2 C5226.2 C5227.2 C5228.2 C5229.2 C5230.2 C5231.2 C5232.2 C5233.2 C5234.2 C5235.2 C5236.2 C5237.2 C5238.2 C5239.2 C5240.2 C5241.2 C5242.2 C5244.1 C5245.2 C5246.2 C5247.2 C5248.1 C5249.2 C5250.2 C5251.2 C5252.1 C5253.2 C5254.1 C5255.1 C5256.2 C5257.2 C5258.2 C5259.2 C5260.2 C5261.2 C5262.2 C5263.2 C5264.2 C5265.2 C5266.2 C5267.2 C5268.2 C5273.2 C5274.2 C5276.2 C5277.2 C5278.2 C5279.2 C5280.2 C5281.2 C5282.2 C5283.2 C5284.2 C5285.2 C5286.2 C5287.2 C5288.2 C5289.2 C5290.2 C5291.2 C5292.2 C5293.2 C5294.2 C5295.2 C5296.2 C5297.2 C5298.2 C5299.2 C5300.2 C5301.2 C5302.2 C5303.2 C5304.2 C5305.2 C5306.2 C5307.2 C5308.2 C5309.2 C5320.2 C5321.2 C5324.2 C5327.2 C5328.2 C5329.2 C5330.2 C5333.2 C5334.2 C5337.2 C5338.2 C5339.2 C5340.2 C5341.2 C5342.2 C5343.2 C5344.2 C5345.2 CN3.3 CN3.6 CN4.A4 CN4.B4 CT24.2 CT28.2 CT29.2 CT30.2 CT31.2 CT32.2 CT35.2 CT40.2 CT41.2 CT42.2 CT43.2 CT44.2 CT45.2 CT46.2 CT47.2 CT48.2 CT54.2 CT55.2 FAN1.1 FAN2.1 FAN3.1 FAN4.1 FAN5.1 FAN12.1 FB70.1 FB71.1 FB72.1 FL6.2A FL6.2B FL13.2 FL14.2 FL15.2 FL16.2 FL17.2 FL18.2 FL19.2 FL20.2 FL21.2 FL22.2 FL23.2 FL24.2 FL25.2 FL26.2 H1.1 H1.2 H1.3 H1.4 H1.5 H1.6 H1.7(GND7) H2.1 H2.2 H2.3 H2.4 H2.5 H2.6 H2.7(GND7) H3.1 H3.2 H3.3 H3.4 H3.5 H3.6 H3.7(GND7) H4.1 H4.2 H4.3 H4.4 H4.5 H4.6 H4.7(GND7) H5.1 H5.2 H5.3 H5.4 H5.5 H5.6 H5.7(GND7) H6.1 H6.2 H6.3 H6.4 H6.5 H6.6 H6.7(GND7) H7.1 H7.2 H7.3 H7.4 H7.5 H7.6 H7.7(GND7) H8.1 H8.2 H8.3 H8.4 H8.5 H8.6 H8.7(GND7) H9.1 H9.2 H9.3 H9.4 H9.5 H9.6 H9.7(GND7) H10.1 H10.2 H10.3 H10.4 H10.5 H10.6 H10.7(GND7) H11.1 H11.2 H11.3 H11.4 H11.5 H11.6 H11.7(GND7) H12.1 H12.2 H12.3 H12.4 H12.5 H12.6 H12.7(GND7) H13.1 H13.2 H13.3 H13.4 H13.5 H13.6 H13.7(GND7) H14.1 H14.2 H14.3 H14.4 H14.5 H14.6 H14.7(GND7) H15.1 H15.2 H15.3 H15.4 H15.5 H15.6 H15.7(GND7) H16.1 H16.2 H16.3 H16.4 H16.5 H16.6 H16.7(GND7) J2.12 J2.16(B8) J3.A1 J3.A4 J3.A12 J3.A15 J3.A18 J3.A20 J3.A23 J3.A24 J3.A27 J3.A28 J3.A31 J3.A34 J3.A37 J3.A38 J3.A41 J3.A42 J3.A45 J3.A46 J3.A49 J3.B4 J3.B7 J3.B13 J3.B16 J3.B18 J3.B21 J3.B22 J3.B25 J3.B26 J3.B29 J3.B32 J3.B35 J3.B36 J3.B39 J3.B40 J3.B43 J3.B44 J3.B47 J3.B49 J4.2 J5.2 J5.5 J5.8 J5.11 J5.14 J5.17 J5.20 J5.23 J5.26 J5.29 J5.32 J5.35 J5.38 J5.41 J5.44 J5.47 J5.80 J5.83 J5.86 J5.89 J5.92 J5.95 J5.98 J5.101 J5.104 J5.107 J5.110 J5.113 J5.116 J5.117 J5.121 J5.124 J5.127 J5.130 J5.133 J5.136 J5.139 J5.142 J5.145 J5.148 J5.151 J5.154 J5.157 J5.160 J5.163 J5.166 J5.199 J5.202 J5.205 J5.208 J5.211 J5.214 J5.217 J5.220 J5.223 J5.226 J5.229 J5.232 J5.235 J5.239 J6.2 J6.5 J6.8 J6.11 J6.14 J6.17 J6.20 J6.23 J6.26 J6.29 J6.32 J6.35 J6.38 J6.41 J6.44 J6.47 J6.80 J6.83 J6.86 J6.89 J6.92 J6.95 J6.98 J6.101 J6.104 J6.107 J6.110 J6.113 J6.116 J6.117 J6.119 J6.121 J6.124 J6.127 J6.130 J6.133 J6.136 J6.139 J6.142 J6.145 J6.148 J6.151 J6.154 J6.157 J6.160 J6.163 J6.166 J6.199 J6.202 J6.205 J6.208 J6.211 J6.214 J6.217 J6.220 J6.223 J6.226 J6.229 J6.232 J6.235 J6.239 J7.2 J7.5 J7.8 J7.11 J7.14 J7.17 J7.20 J7.23 J7.26 J7.29 J7.32 J7.35 J7.38 J7.41 J7.44 J7.47 J7.80 J7.83 J7.86 J7.89 J7.92 J7.95 J7.98 J7.101 J7.104 J7.107 J7.110 J7.113 J7.116 J7.117 J7.121 J7.124 J7.127 J7.130 J7.133 J7.136 J7.139 J7.142 J7.145 J7.148 J7.151 J7.154 J7.157 J7.160 J7.163 J7.166 J7.199 J7.202 J7.205 J7.208 J7.211 J7.214 J7.217 J7.220 J7.223 J7.226 J7.229 J7.232 J7.235 J7.237 J7.239 J8.1 J8.2 J8.3 J8.4(GND4) J9.3 J9.5 J9.7 J9.15 J9.17 J9.18 J9.19 J9.24 J10.1 J10.4 J10.7 J10.M1 J10.M2 J11.1 J11.20 J12.1 J12.20 J13.1 J13.20 J14.1 J14.20 J16.1A J16.1B J16.1C J16.1D J16.10A J16.10B J16.10C J16.10D J16.11A J16.11B J16.11C J16.11D J16.14A J16.14B J16.14C J16.14D J16.17A J16.17B J16.17C J16.17D J16.20A J16.20B J16.20C J16.20D J55.2 J69.5 J105.2 J105.10 J106.3 J106.10 JP7.2 Q3.2(SOURCE) Q4.2(SOURCE) Q5.2(SOURCE) Q6.2(SOURCE) Q7.2(SOURCE) Q8.2(SOURCE) Q9.2(SOURCE) Q10.2(SOURCE) Q11.2(SOURCE) Q12.2(SOURCE) Q13.2(SOURCE) R3.2 R46.2 R50.2 R54.2 R78.2 R102.2 R103.2 R119.2 R124.2 R142.1 R146.1 R176.2 R177.2 R180.2 R181.2 R199.1 R200.1 R211.1 R213.1 R218.2 R221.1 R224.1 R229.1 R230.1 R232.2 R234.2 R259.2 R261.1 R264.1 R267.1 R269.1 R270.2 R306.2 R307.1 R308.1 R309.2 R310.2 R311.2 R312.2 R315.2 R316.2 R320.2 R321.1 R322.1 R323.2 R508.2 R659.2 R663.2 R700.2 R701.2 R714.2 R715.2 R718.2 R722.2 R730.2 R731.2 R736.2 R739.2 R741.2 R742.2 R746.2 R747.2 R748.2 R751.2 R753.2 R756.2 R796.2 R816.1 R817.1 R926.1 R927.1 R930.1 R935.1 R936.1 R939.1 R944.1 R945.1 R948.1 R953.1 R954.1 R957.1 R5584.2 R5585.2 R5698.2 R5699.2 R5700.2 R5701.2 R5702.2 R5710.2 R5711.2 R5712.2 R5721.2 R5725.2 R5731.2 R5739.2 R5748.2 R5751.2 R5754.2 R5762.2 R5767.2 R5768.2 R5769.2 R5770.2 R5772.1 R5773.1 R5774.1 R5775.1 R5776.1 R5777.1 R5778.1 R5779.1 R5780.1 R5781.1 R5782.1 R5783.1 R5784.1 R5785.1 R5786.1 R5787.1 R5791.1 R5792.1 R5793.1 R5804.2 R5805.2 R5813.2 R5816.2 R5818.2 R5819.2 R5820.2 R5829.2 R5830.2 R5831.2 R5832.2 R5837.2 R5875.2 R5876.1 R5877.1 R5878.1 R5879.1 R5880.1 R5881.1 R5882.1 R5883.1 R5884.1 R5885.1 R5886.1 R5887.1 R5888.1 R5889.1 R5890.2 R5891.2 R5893.2 R5897.2 SW5.1 SW6.2 SW6.3 SW6.4 U1.1 U1.11 U2.5 U7.4 U7.28 U7.32 U7.35 U9.4 U9.28 U9.32 U9.35 U14.3 U14.9 U16.3 U16.7(VSS) U16.17 U17.3 U17.9 U18.4 U22.A15 U22.A17 U22.A19 U22.A21 U22.A23 U22.A25 U22.A27 U22.A29 U22.A31 U22.A43 U22.AA3 U22.AA6 U22.AA10 U22.AA11 U22.AA12 U22.AA13 U22.AA14 U22.AA16 U22.AA18 U22.AA20 U22.AA22 U22.AA24 U22.AA26 U22.AA28 U22.AA31 U22.AA35 U22.AA42 U22.AB3 U22.AB4 U22.AB8 U22.AB14 U22.AB17 U22.AB19 U22.AB21 U22.AB23 U22.AB25 U22.AB27 U22.AB29 U22.AB31 U22.AB32 U22.AB33 U22.AB34 U22.AB35 U22.AB42 U22.AC3 U22.AC6 U22.AC8 U22.AC14 U22.AC16 U22.AC18 U22.AC20 U22.AC22 U22.AC24 U22.AC26 U22.AC28 U22.AC31 U22.AC33 U22.AC36 U22.AC37 U22.AC38 U22.AC39 U22.AC40 U22.AC41 U22.AC42 U22.AD3 U22.AD5 U22.AD8 U22.AD10 U22.AD11 U22.AD12 U22.AD13 U22.AD14 U22.AD17 U22.AD19 U22.AD21 U22.AD23 U22.AD25 U22.AD27 U22.AD29 U22.AD31 U22.AD33 U22.AD36 U22.AD39 U22.AD42 U22.AE3 U22.AE7 U22.AE9 U22.AE14 U22.AE16 U22.AE18 U22.AE20 U22.AE22 U22.AE24 U22.AE26 U22.AE28 U22.AE31 U22.AE33 U22.AE36 U22.AE39 U22.AE42 U22.AF3 U22.AF4 U22.AF5 U22.AF6 U22.AF9 U22.AF14 U22.AF17 U22.AF19 U22.AF21 U22.AF23 U22.AF25 U22.AF27 U22.AF29 U22.AF31 U22.AF33 U22.AF36 U22.AF39 U22.AF42 U22.AG3 U22.AG8 U22.AG11 U22.AG12 U22.AG13 U22.AG14 U22.AG16 U22.AG18 U22.AG20 U22.AG22 U22.AG24 U22.AG26 U22.AG28 U22.AG31 U22.AG33 U22.AG36 U22.AG39 U22.AG42 U22.AH3 U22.AH9 U22.AH12 U22.AH14 U22.AH17 U22.AH19 U22.AH21 U22.AH23 U22.AH25 U22.AH27 U22.AH29 U22.AH31 U22.AH33 U22.AH36 U22.AH39 U22.AH42 U22.AJ3 U22.AJ4 U22.AJ5 U22.AJ6 U22.AJ7 U22.AJ8 U22.AJ9 U22.AJ10 U22.AJ11 U22.AJ12 U22.AJ14 U22.AJ16 U22.AJ18 U22.AJ20 U22.AJ30 U22.AJ31 U22.AJ34 U22.AJ35 U22.AJ36 U22.AJ39 U22.AJ42 U22.AK3 U22.AK6 U22.AK9 U22.AK12 U22.AK13 U22.AK15 U22.AK17 U22.AK19 U22.AK21 U22.AK22 U22.AK23 U22.AK24 U22.AK25 U22.AK26 U22.AK27 U22.AK28 U22.AK29 U22.AK30 U22.AK33 U22.AK36 U22.AK37 U22.AK38 U22.AK39 U22.AK40 U22.AK41 U22.AK42 U22.AL3 U22.AL6 U22.AL9 U22.AL12 U22.AL20 U22.AL31 U22.AL33 U22.AL34 U22.AL39 U22.AL42 U22.AM3 U22.AM6 U22.AM9 U22.AM12 U22.AM19 U22.AM21 U22.AM22 U22.AM23 U22.AM25 U22.AM26 U22.AM28 U22.AM29 U22.AM30 U22.AM31 U22.AM32 U22.AM33 U22.AM36 U22.AM39 U22.AM42 U22.AN3 U22.AN6 U22.AN9 U22.AN12 U22.AN18 U22.AN20 U22.AN22 U22.AN24 U22.AN27 U22.AN29 U22.AN31 U22.AN34 U22.AN35 U22.AN36 U22.AN39 U22.AN42 U22.AP3 U22.AP6 U22.AP9 U22.AP12 U22.AP14 U22.AP15 U22.AP16 U22.AP18 U22.AP22 U22.AP29 U22.AP33 U22.AP37 U22.AP39 U22.AP42 U22.AR3 U22.AR6 U22.AR9 U22.AR12 U22.AR17 U22.AR39 U22.AR42 U22.AT3 U22.AT4 U22.AT5 U22.AT6 U22.AT7 U22.AT8 U22.AT9 U22.AT10 U22.AT11 U22.AT12 U22.AT13 U22.AT14 U22.AT15 U22.AT16 U22.AT17 U22.AT19 U22.AT21 U22.AT23 U22.AT25 U22.AT27 U22.AT29 U22.AT31 U22.AT33 U22.AT34 U22.AT35 U22.AT36 U22.AT39 U22.AT42 U22.AU3 U22.AU10 U22.AU17 U22.AU19 U22.AU21 U22.AU23 U22.AU25 U22.AU27 U22.AU29 U22.AU31 U22.AU33 U22.AU34 U22.AU37 U22.AU39 U22.AU41 U22.AU42 U22.AV3 U22.AV10 U22.AV17 U22.AV18 U22.AV20 U22.AV22 U22.AV24 U22.AV26 U22.AV28 U22.AV30 U22.AV32 U22.AV34 U22.AV38 U22.AV42 U22.AW3 U22.AW4 U22.AW5 U22.AW6 U22.AW7 U22.AW8 U22.AW9 U22.AW10 U22.AW11 U22.AW12 U22.AW13 U22.AW14 U22.AW15 U22.AW16 U22.AW18 U22.AW20 U22.AW22 U22.AW24 U22.AW26 U22.AW28 U22.AW30 U22.AW32 U22.AW34 U22.AW35 U22.AW36 U22.AW38 U22.AW40 U22.AW42 U22.AY3 U22.AY10 U22.AY17 U22.AY18 U22.AY19 U22.AY20 U22.AY21 U22.AY22 U22.AY23 U22.AY24 U22.AY25 U22.AY26 U22.AY27 U22.AY28 U22.AY29 U22.AY30 U22.AY31 U22.AY32 U22.AY33 U22.AY34 U22.AY38 U22.AY42 U22.B11 U22.B13 U22.B14 U22.B15 U22.B17 U22.B19 U22.B21 U22.B23 U22.B25 U22.B27 U22.B29 U22.B31 U22.B33 U22.B36 U22.B39 U22.B42 U22.B44 U22.BA3 U22.BA10 U22.BA17 U22.BA19 U22.BA21 U22.BA23 U22.BA25 U22.BA27 U22.BA29 U22.BA31 U22.BA33 U22.BA34 U22.BA38 U22.BA42 U22.BB3 U22.BB4 U22.BB5 U22.BB6 U22.BB7 U22.BB8 U22.BB9 U22.BB10 U22.BB11 U22.BB12 U22.BB13 U22.BB14 U22.BB15 U22.BB16 U22.BB17 U22.BB19 U22.BB21 U22.BB23 U22.BB25 U22.BB27 U22.BB29 U22.BB31 U22.BB33 U22.BB34 U22.BB35 U22.BB36 U22.BB37 U22.BB38 U22.BB39 U22.BB40 U22.BB41 U22.BB42 U22.BC17 U22.BC18 U22.BC20 U22.BC22 U22.BC24 U22.BC26 U22.BC28 U22.BC30 U22.BC32 U22.BC34 U22.BD18 U22.BD20 U22.BD22 U22.BD24 U22.BD26 U22.BD28 U22.BD30 U22.BD32 U22.BD34 U22.C3 U22.C4 U22.C5 U22.C6 U22.C7 U22.C8 U22.C9 U22.C14 U22.C16 U22.C18 U22.C20 U22.C22 U22.C24 U22.C26 U22.C28 U22.C30 U22.C31 U22.D3 U22.D9 U22.D14 U22.D16 U22.D18 U22.D20 U22.D22 U22.D24 U22.D26 U22.D28 U22.D30 U22.D32 U22.D34 U22.D37 U22.D40 U22.D43 U22.E3 U22.E6 U22.E9 U22.E11 U22.E14 U22.E15 U22.E16 U22.E17 U22.E18 U22.E19 U22.E20 U22.E21 U22.E22 U22.E23 U22.E24 U22.E25 U22.E26 U22.E27 U22.E28 U22.E29 U22.E30 U22.E31 U22.F3 U22.F4 U22.F8 U22.F9 U22.F13 U22.F15 U22.F17 U22.F19 U22.F21 U22.F23 U22.F25 U22.F27 U22.F29 U22.F31 U22.F33 U22.F36 U22.F39 U22.F41 U22.G3 U22.G6 U22.G9 U22.G14 U22.G15 U22.G17 U22.G19 U22.G21 U22.G23 U22.G25 U22.G27 U22.G29 U22.G31 U22.G43 U22.H3 U22.H9 U22.H11 U22.H14 U22.H16 U22.H18 U22.H20 U22.H22 U22.H24 U22.H26 U22.H28 U22.H30 U22.H31 U22.H34 U22.H37 U22.H39 U22.J3 U22.J5 U22.J7 U22.J9 U22.J13 U22.J14 U22.J16 U22.J18 U22.J20 U22.J22 U22.J24 U22.J26 U22.J28 U22.J30 U22.J32 U22.J41 U22.J44 U22.K3 U22.K6 U22.K9 U22.K14 U22.K33 U22.K36 U22.K43 U22.L3 U22.L6 U22.L9 U22.L11 U22.L15 U22.L19 U22.L26 U22.L30 U22.L31 U22.L39 U22.M3 U22.M6 U22.M9 U22.M13 U22.M15 U22.M17 U22.M19 U22.M21 U22.M24 U22.M26 U22.M28 U22.M32 U22.M34 U22.M41 U22.M44 U22.N3 U22.N6 U22.N9 U22.N16 U22.N18 U22.N19 U22.N20 U22.N22 U22.N23 U22.N25 U22.N26 U22.N27 U22.N28 U22.N29 U22.N30 U22.N37 U22.N43 U22.P3 U22.P6 U22.P9 U22.P11 U22.P14 U22.P15 U22.P16 U22.P17 U22.P28 U22.P33 U22.P39 U22.R3 U22.R6 U22.R9 U22.R18 U22.R19 U22.R20 U22.R21 U22.R22 U22.R23 U22.R24 U22.R25 U22.R26 U22.R27 U22.R31 U22.R41 U22.T3 U22.T6 U22.T9 U22.T10 U22.T11 U22.T12 U22.T14 U22.T17 U22.T31 U22.T37 U22.T43 U22.U3 U22.U6 U22.U13 U22.U14 U22.U16 U22.U18 U22.U20 U22.U22 U22.U24 U22.U26 U22.U28 U22.U31 U22.U33 U22.U39 U22.V3 U22.V6 U22.V9 U22.V12 U22.V14 U22.V17 U22.V19 U22.V21 U22.V23 U22.V25 U22.V27 U22.V29 U22.V31 U22.V34 U22.V41 U22.W3 U22.W6 U22.W9 U22.W12 U22.W13 U22.W14 U22.W16 U22.W18 U22.W20 U22.W22 U22.W24 U22.W26 U22.W28 U22.W31 U22.W33 U22.W37 U22.W43 U22.Y3 U22.Y6 U22.Y9 U22.Y14 U22.Y17 U22.Y19 U22.Y21 U22.Y23 U22.Y25 U22.Y27 U22.Y29 U22.Y31 U22.Y35 U22.Y36 U22.Y37 U22.Y38 U22.Y39 U22.Y40 U22.Y41 U22.Y42 U23.1 U23.11 U25.1 U25.11 U26.4 U27.A6 U27.A16 U27.B9 U27.C2 U27.C12 U27.D5 U27.D15 U27.F1 U27.F8 U27.F10 U27.G4 U27.G7 U27.G9 U27.G14 U27.H6 U27.H8 U27.H10 U27.J7 U27.J9 U27.J11(VSSNVM) U27.K3 U27.K6 U27.K8 U27.K10 U27.K13 U27.L7 U27.L9 U27.L16 U27.N2 U27.N12 U27.P5 U27.P15 U27.R8 U27.T1 U27.T11 U32.7 U32.8 U32.11 U32.12 U32.20 U32.31 U32.32 U32.36 U32.41 U36.65 U37.33 U37.52 U38.C5 U38.F7 U38.K3 U38.K8 U42.67 U42.129 U45.7 U46.8 U47.B3 U47.C3 U47.D3 U48.B3 U48.C3 U48.D3 U55.A1 U55.A4 U55.A12 U55.A15 U55.A18 U55.A20 U55.A23 U55.A24 U55.A27 U55.A28 U55.A31 U55.B4 U55.B7 U55.B13 U55.B16 U55.B18 U55.B21 U55.B22 U55.B25 U55.B26 U55.B29 U55.B32 U58.4 U65.22 U65.27 U65.30 U65.31 U65.34 U65.39 U65.49 U68.1 U68.11 U69.1 U69.11 U82.12(VSS) U95.8 U105.17 U250.4 U589.1 U589.2 U589.3 U589.4(VSS) U593.1 U593.4 U593.10 U593.15 U593.21 U593.24 U593.28 U593.34 U593.39 U593.45 U594.1 U594.4 U594.10 U594.15 U594.21 U594.24 U594.28 U594.34 U594.39 U594.45 U595.3 U596.3 U598.3 U605.2 U605.7 U606.2 U607.2 U608.3 U608.8 U610.12 U610.23 U620.67 U620.129 U622.22 U622.27 U622.30 U622.31 U622.34 U622.39 U622.49 U624.9(VSS) U624.18 U624.23 U624.24 U624.25 U625.4(VSS) U626.1 U626.9 U626.17 U627.1 U627.9 U627.17 U628.3 U629.3 U630.2 U630.4 U630.9 U631.E1 U631.E2 U631.E5 U631.E6 U631.F1 U631.F2 U631.F5 U631.F6 U631.G1 U631.G2 U631.G5 U631.G6 Y19.2 Y19.4
P1V8_AVDD: FB26.2 R685.1 R686.1 R687.1 R689.1 R690.1 R691.1 R708.1 R769.1 R770.1
P3V3_SFP+_1: C1142.1 C1143.1 J16.15A J16.16A L29.2 R922.1 R923.2 R924.2 R925.1 R1082.1
P3V3_SFP+_2: C1145.1 C1146.1 J16.15B J16.16B L30.2 R931.1 R932.2 R933.2 R934.1 R938.1
P3V3_SFP+_3: C1148.1 C1149.1 J16.15C J16.16C L31.2 R940.1 R941.2 R942.2 R943.1 R947.1
P3V3_SFP+_4: C1151.1 C1152.1 J16.15D J16.16D L32.2 R949.1 R950.2 R951.2 R952.1 R956.1
SVDD: C5154.1 C5155.1 C5156.1 C5157.2 CT32.1 CT44.1 FB16.1 FB17.1 FB18.1 FB19.1 FB51.1 FB52.1 FB53.1 FB54.1 FB101.1 L54.2 R5737.2
VBUS_POWER1: D9.C(CATHODE) L26.1 R662.1 U48.C2 U48.D1 U48.D2
VBUS_POWER2: D10.C(CATHODE) L27.1 R664.1 U47.C2 U47.D1 U47.D2
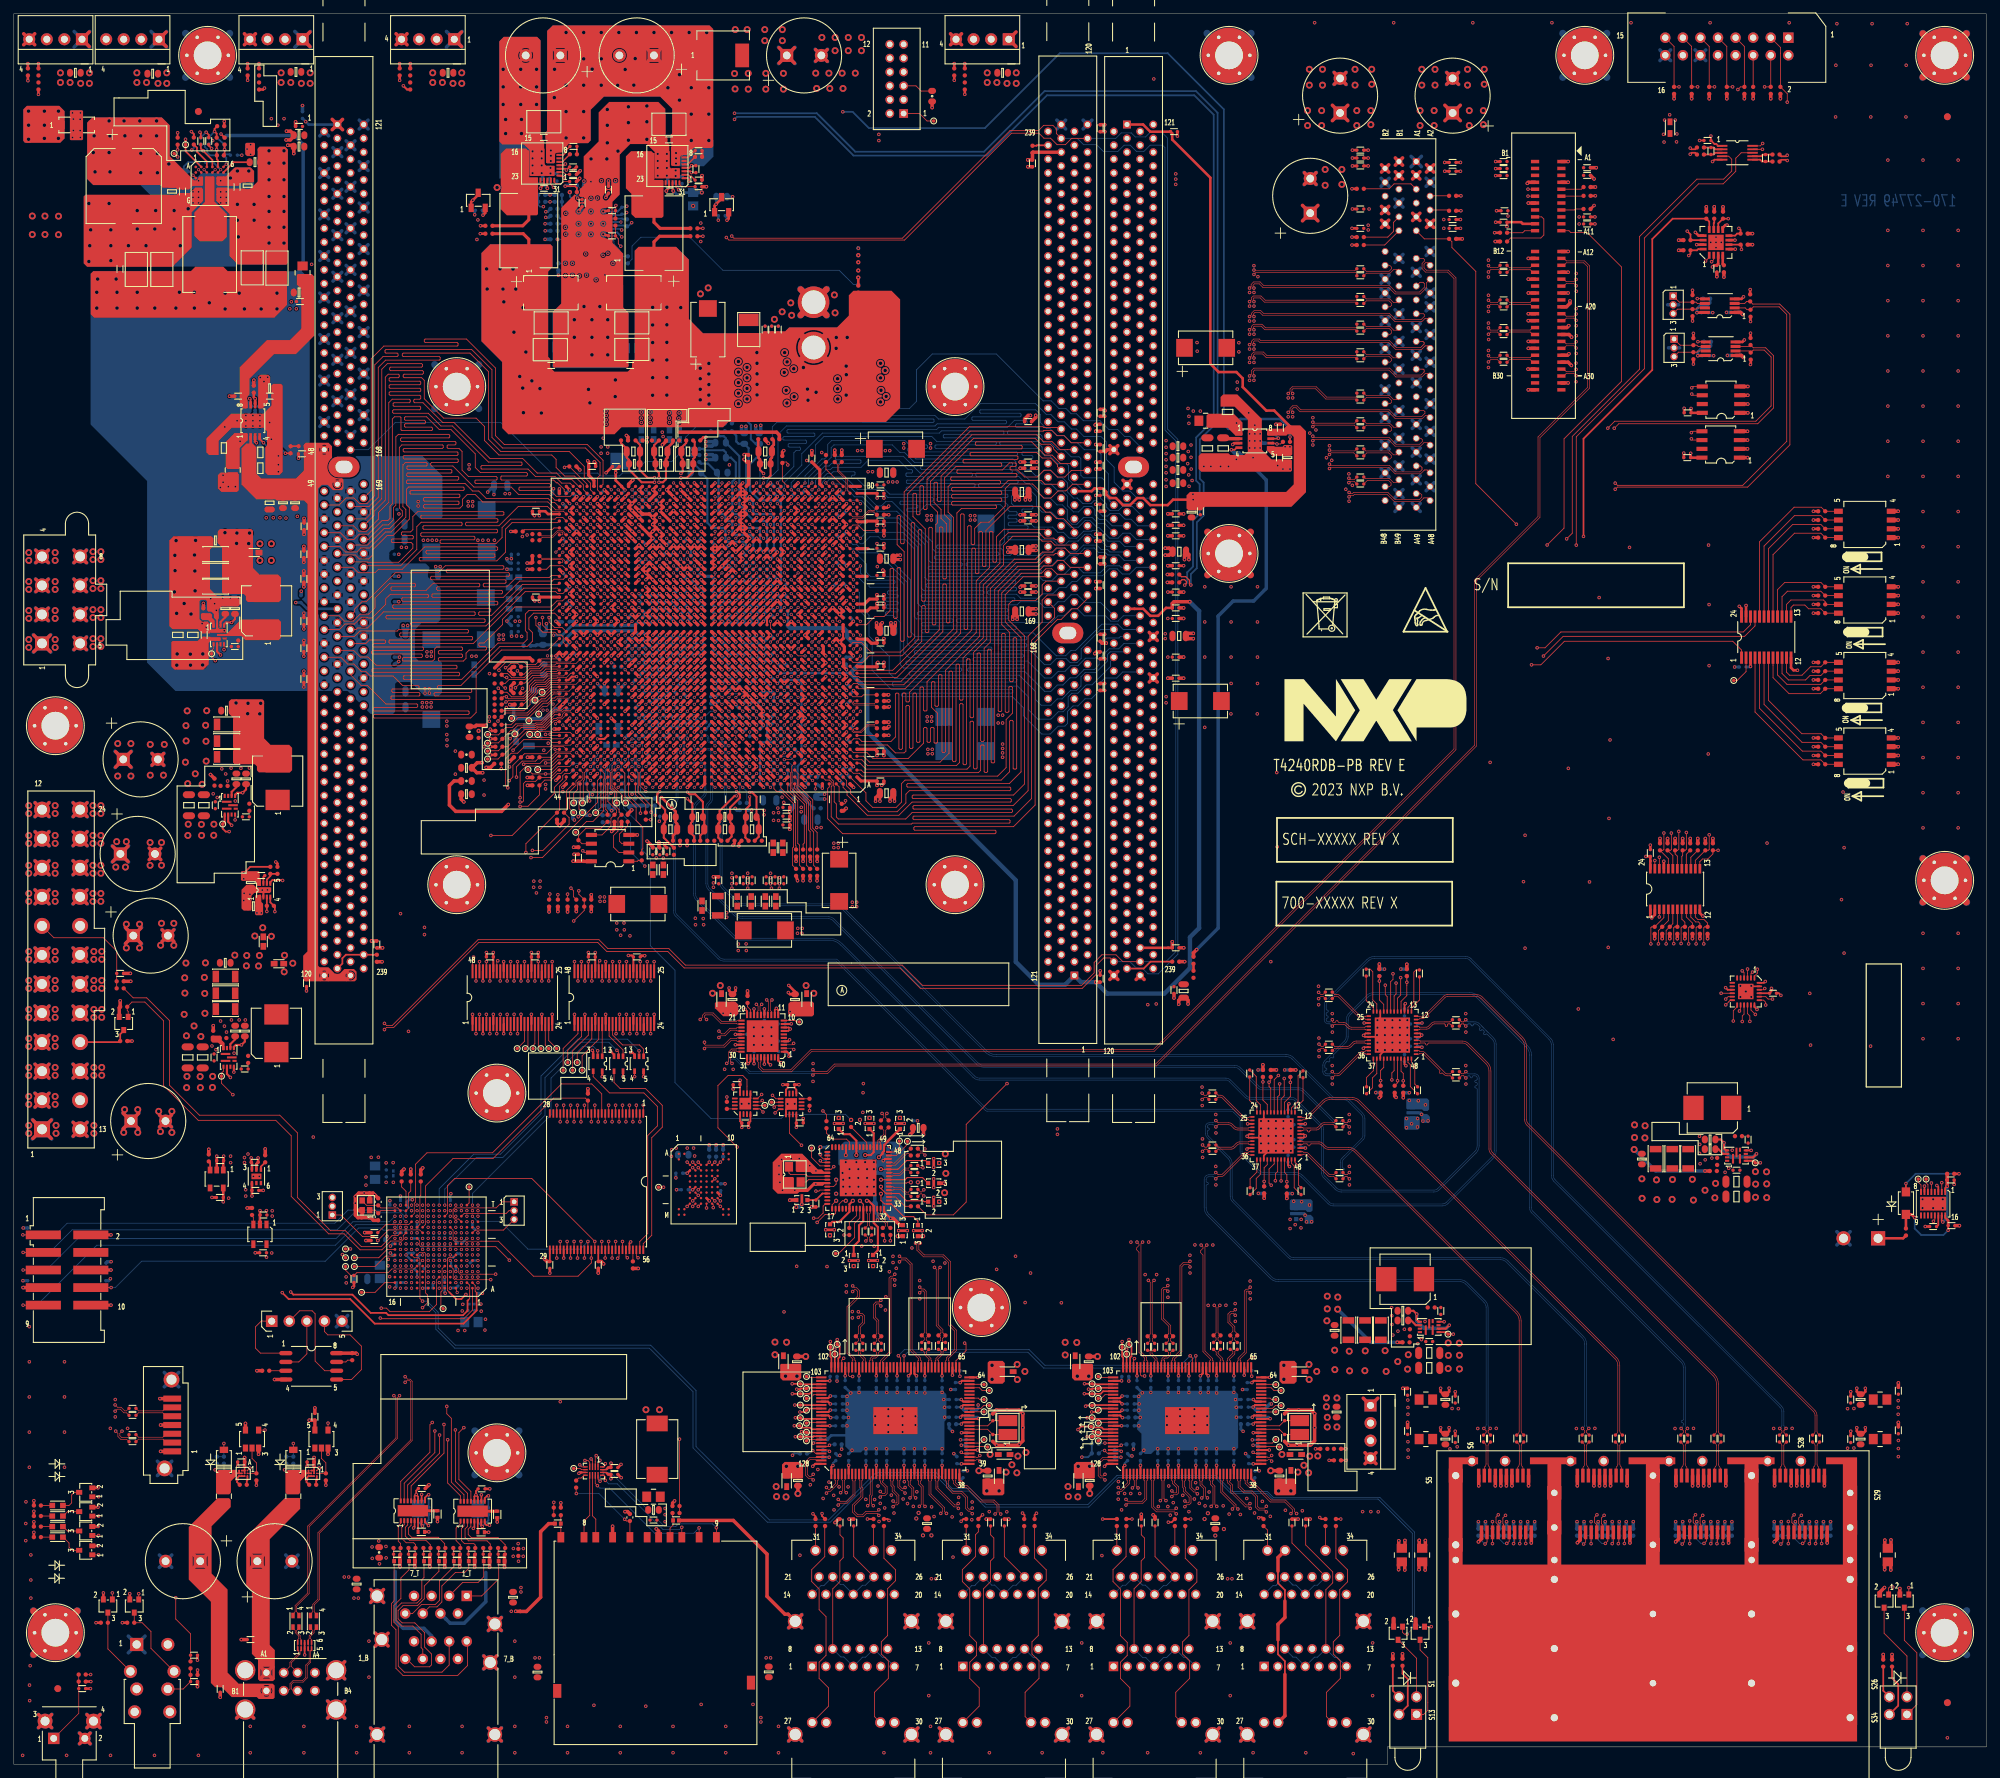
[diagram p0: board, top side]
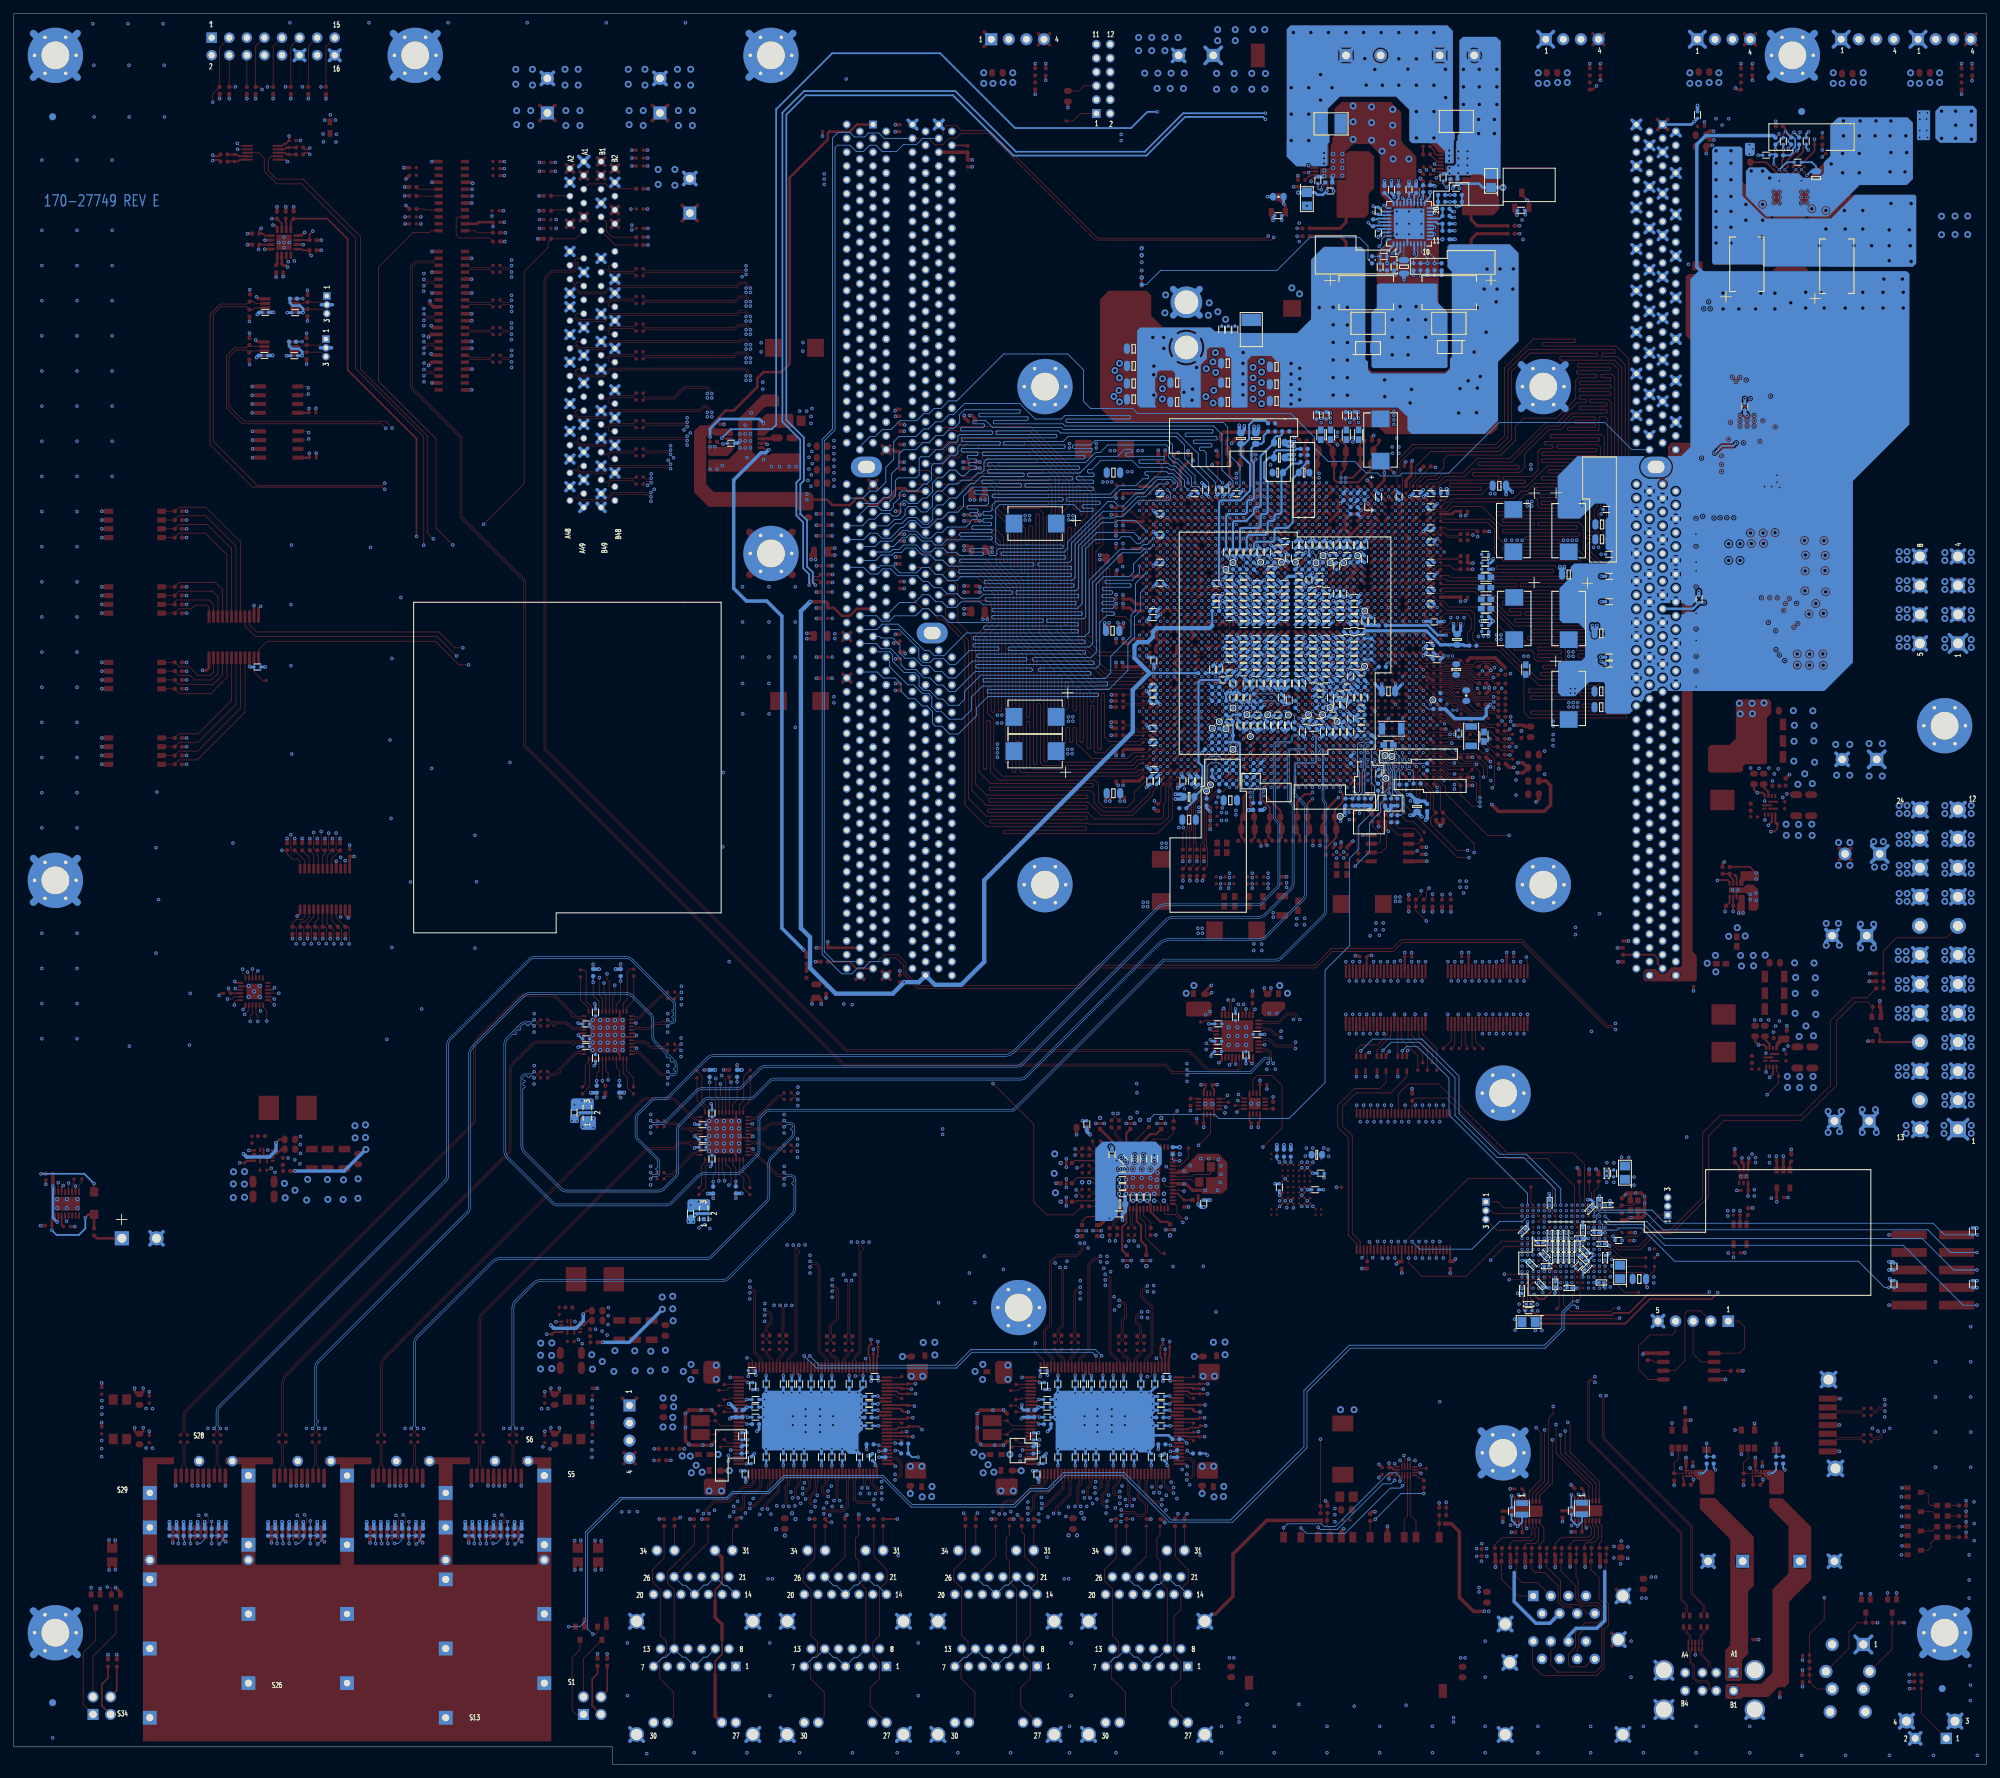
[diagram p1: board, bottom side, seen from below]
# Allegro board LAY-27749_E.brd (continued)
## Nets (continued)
VCC_3.3: C42.1 C58.1 C60.1 C66.1 C84.1 C92.1 C93.1 C105.1 C113.1 C256.1 C296.1 C297.1 C434.1 C505.1 C900.1 C965.1 C1002.1 C1141.1 C1144.1 C1147.1 C1150.1 C1240.2 C1250.2 C3844.1 C3848.1 C3865.1 C5260.1 C5309.1 C5321.1 C5324.1 C5328.1 C5329.1 C5333.1 C5338.1 CT35.1 F1.1 FB23.1 FB56.2 FB87.1 FB89.1 FB90.1 FB96.1 FB98.1 FL18.3(OUT_IN) FL20.1 J3.A9 J3.A10 J3.B8 J5.236 J6.236 J7.236 J9.1 J9.2 J9.12 J9.13 J11.28 J11.32 J12.28 J12.32 J13.28 J13.32 J14.28 J14.32 L29.1 L30.1 L31.1 L32.1 R42.1 R47.1 R48.1 R49.1 R58.1 R113.2 R120.2 R125.2 R128.2 R143.2 R145.2 R191.1 R192.1 R203.1 R217.1 R222.1 R336.2 R337.1 R338.2 R519.1 R520.1 R521.1 R522.1 R523.1 R526.1 R527.1 R528.1 R529.1 R530.1 R531.1 R628.1 R629.1 R660.1 R661.1 R830.1 R5680.1 R5681.1 R5682.1 R5683.1 R5684.1 R5690.1 R5704.1 R5705.1 R5706.1 R5790.1 R5870.1 R5871.1 R5872.1 R5873.1 R5874.1 R5892.1 U3.25 U3.26 U14.5 U17.5 U18.8(VCCB) U45.14(VCCB) U55.A9 U55.A10 U55.B8 U58.8(VCCB) U82.1 U82.2 U82.21 U82.24 U105.3(VDD) U589.8 U624.21 U625.1 U625.2 U625.3 U625.8 U626.4 U627.4 U628.5 U629.5 U630.1
VCC_3.3_F: F1.2 FB38.2
VCC_3.3_SD: C3899.1 C3900.1 CN3.4 FB38.1
VCC_5: C85.1 C515.1 C516.1 C5266.1 C5273.1 C5274.1 C5284.1 C5285.1 C5343.1 C5344.1 CT28.1 J9.4 J9.6 J9.21 J9.22 J9.23 R40.1 R41.1 R5811.1 R5812.1 U7.3 U7.29 U9.3 U9.29 U47.B1 U47.B2 U47.C1(VINT3) U48.B1 U48.B2 U48.C1(VINT3)
VCC_12: C3.1 C4.1 C5.2 C15.1 C16.1 C17.1 C18.1 C25.1 C26.1 C40.1 C41.1 C43.1 C145.1 C171.1 C467.1 C991.1 C992.1 C993.1 C1266.1 C5151.1 C5152.1 C5153.2 C5161.1 C5162.1 C5163.2 C5204.1 C5205.1 C5206.2 C5250.1 C5251.1 C5252.2 C5337.1 C5339.1 C5340.1 FAN1.2 FAN2.2 FAN3.2 FAN4.2 FAN5.2 FAN12.2 FL6.1 J3.A2 J3.A3 J3.B1 J3.B2 J3.B3 J9.10 J9.11 R5685.1 R5686.1 R5687.1 R5688.1 R5689.1 U1.2(VIN) U23.2(VIN) U25.2(VIN) U55.A2 U55.A3 U55.B1 U55.B2 U55.B3 U68.2(VIN) U69.2(VIN)
VCC_12_8P: C5283.1 J8.5 J8.6 J8.7 J8.8 L3.2
VCC_DVDD: C112.1 C144.1 C827.1 C828.1 C880.1 C2704.1 C2705.1 FB24.1 L52.1 L53.1 R190.1 R196.1 R205.1 R208.1 R720.1 R726.1 U18.1 U22.R14 U22.R15 U46.5 U46.10 U46.11 U46.12(VL) U58.1 U95.5 U95.10 U95.11 U95.12(VL)
VDD: BH9.1 C91.1 C98.1 C107.1 C109.1 C110.1 C114.1 C131.1 C546.1 C547.1 C548.1 C549.1 C550.1 C551.1 C552.1 C553.1 C554.1 C555.1 C556.1 C557.1 C630.1 C631.1 C640.1 C641.1 C642.1 C647.1 C648.1 C649.1 C658.1 C659.1 C660.1 C661.1 C662.1 C663.1 C664.1 C669.1 C670.1 C671.1 C672.1 C673.1 C674.1 C675.1 C676.1 C681.1 C682.1 C683.1 C684.1 C685.1 C686.1 C687.1 C688.1 C694.1 C695.1 C696.1 C697.1 C698.1 C699.1 C700.1 C701.1 C706.1 C707.1 C711.1 C712.1 C713.1 C720.1 C721.1 C722.1 C723.1 C724.1 C725.1 C726.1 C729.1 C730.1 C731.1 C732.1 C733.1 C734.1 C735.1 C736.1 C744.1 C745.1 C746.1 C747.1 C748.1 C749.1 C750.1 C751.1 C756.1 C757.1 C758.1 C759.1 C760.1 C761.1 C762.1 C763.1 C771.1 C772.1 C773.1 C774.1 C775.1 C776.1 C777.1 C778.1 C789.1 C790.1 C791.1 C792.1 C793.1 C794.1 C795.1 C804.1 C987.1 C2636.1 C2637.1 C5261.1 C5262.1 C5263.1 C5264.1 C5265.1 C5267.1 C5268.1 C5280.1 C5281.1 C5282.1 C5290.1 C5291.1 C5292.1 C5293.1 FB20.2 L4.1 L5.1 R46.1 R52.1 R53.1 R76.1 R285.2 U22.AA17 U22.AA19 U22.AA21 U22.AA23 U22.AA25 U22.AA27 U22.AA29 U22.AB16 U22.AB18 U22.AB20 U22.AB22 U22.AB24 U22.AB26 U22.AB28 U22.AC17 U22.AC19 U22.AC21 U22.AC23 U22.AC25 U22.AC27 U22.AC29 U22.AD16 U22.AD18 U22.AD20 U22.AD22 U22.AD24 U22.AD26 U22.AD28 U22.AE17 U22.AE19 U22.AE21 U22.AE23 U22.AE25 U22.AE27 U22.AE29 U22.AF16 U22.AF18 U22.AF20 U22.AF22 U22.AF24 U22.AF26 U22.AF28 U22.AG17 U22.AG19 U22.AG21 U22.AG23 U22.AG25 U22.AG27 U22.AG29 U22.AH16 U22.AH18 U22.AH20 U22.AH22 U22.AH24 U22.AH26 U22.AH28 U22.AJ17 U22.AJ19 U22.AJ21 U22.AK16 U22.AK18 U22.AK20 U22.T16 U22.U17 U22.U19 U22.U21 U22.U23 U22.U25 U22.U27 U22.U29 U22.V16 U22.V18 U22.V20 U22.V22 U22.V24 U22.V26 U22.V28 U22.W17 U22.W19 U22.W21 U22.W23 U22.W25 U22.W27 U22.W29 U22.Y16 U22.Y18 U22.Y20 U22.Y22 U22.Y24 U22.Y26 U22.Y28
VDD_2V5_AUX: C86.1 R60.1 R61.1 R62.1 R63.1 R64.1 U3.22
VDD_ALERT_B: R49.2 U3.11 U27.M15
VDD_ASEL0: R60.2 R5806.1 U3.16
VDD_ASEL1: R61.2 R5808.1 U3.17
VDD_COMP0: C5270.1 R55.1 R57.1 U3.1
VDD_COMP1: R57.2 U3.29
VDD_FA_VDD: R722.1 U22.R33
VDD_FB0: C5270.2 C5271.2 C5272.1 U3.40
VDD_FB1: R58.2 U3.30
VDD_FREQ_CFG: R63.2 R5809.1 U3.20
VDD_IAVG0: C115.1 R66.2 U3.39
VDD_IAVG1: C116.1 R66.1 U3.31
VDD_ISENSE0+: C99.2 R5814.2 U3.38
VDD_ISENSE0-: C99.1 R52.2 U3.37
VDD_ISENSE1+: C5275.2 R75.2 U3.32
VDD_ISENSE1-: C5275.1 R76.2 U3.33
VDD_LP: C252.1 C831.1 R285.1 R717.2 U22.R28
VDD_OVDD_P1V8: C629.1 C737.1 C752.1 C764.1 C779.1 C796.1 C819.1 C821.1 C832.1 FB25.1 U22.AA30 U22.AK14 U22.R30 U22.T30 U22.U30 U22.V30 U22.W30 U22.Y30
VDD_PH1_FLT: L4.2 R5814.1 U9.16 U9.26
VDD_PH2_FLT: L5.2 R75.1 U7.16 U7.26
VDD_PHAS_CFG: R64.2 R5810.1 U3.21
VDD_PWM0: U3.7 U9.1
VDD_PWM1: U3.27 U7.1
VDD_S1VDD: C284.1 C285.1 C286.1 C807.1 C808.1 C809.1 C810.1 C811.1 C829.1 C830.1 FB18.2 FB19.2 R733.2 U22.N17 U22.P20 U22.P22 U22.T19 U22.T20 U22.T21 U22.T22
VDD_S2VDD: C281.1 C282.1 C283.1 C801.1 C812.1 C813.1 C818.1 C824.1 C835.1 FB16.2 FB17.2 R727.2 U22.P23 U22.P25 U22.T23 U22.T24 U22.T25 U22.T26
VDD_S3VDD: C626.1 C632.1 C636.1 C643.1 C644.1 C650.1 C651.1 C691.1 C709.1 C716.1 FB53.2 FB54.2 R694.2 U22.AJ22 U22.AJ23 U22.AJ24 U22.AJ25 U22.AL23 U22.AL25 U22.AM20
VDD_S4VDD: C614.1 C624.1 C625.1 C627.1 C633.1 C645.1 C652.1 C654.1 C655.1 FB51.2 FB52.2 R697.2 U22.AJ26 U22.AJ27 U22.AJ28 U22.AJ29 U22.AL26 U22.AL28
VDD_SCL: J106.4 R627.1 R628.2 U3.9
VDD_SDA: J106.2(SDA) R629.2 R630.1 U3.10
VDD_SENSE0+: R53.2 R56.2 R65.1 R631.2 U3.36
VDD_SENSE0-: R54.1 R632.2 U3.35
VDD_SENSE_N: R632.1 R696.2 R706.2 R707.2 R716.2
VDD_SENSE_P: R631.1 R699.2 R709.2 R710.2 R725.2
VDD_SGND: C86.2 C92.2 C93.2 C101.1 C115.2 C116.2 C5269.1 Q1.1 Q1.3 Q2.1 Q2.3 R59.2 R5806.2 R5807.2 R5808.2 R5809.2 R5810.2 R5813.1 U3.5 U3.41
VDD_SH_CLK: R48.2 U3.24
VDD_SH_SYNC: R47.2 U3.8
VDD_SH_WP: R59.1 U3.23(WP)
VDD_TH_VDD: C782.1 C788.1 R712.1 U22.V32
VDD_TMON0: C97.1 R50.1 U9.30
VDD_TMON1: C127.1 R78.1 U7.30
VDD_TSNS0: C101.2 Q1.2(E) U3.2
VDD_TSNS1: C5269.2 Q2.2(E) U3.3
VDD_VOUT_CFG: R62.2 R5807.1 U3.18 U3.19
VDD_VSENSE1+: R65.2 U3.34
VDD_X1VDD: C258.1 C259.1 C265.1 C849.1 C850.1 C851.1 C852.1 C853.1 C854.1 C855.1 C856.1 FB9.1 FB10.1 R738.2 U22.K15 U22.K16 U22.K17 U22.K18 U22.K19 U22.K20 U22.K21 U22.K22
VDD_X2VDD: C273.1 C274.1 C275.1 C844.1 C846.1 C858.1 C861.1 C862.1 C863.1 C864.1 C865.1 C866.1 FB11.1 FB12.1 R737.2 U22.K23 U22.K24 U22.K25 U22.K26 U22.K27 U22.K28 U22.K29 U22.K30 U22.M30
VDD_X3VDD: C562.1 C563.1 C593.1 C595.1 C596.1 C597.1 C606.1 C612.1 C613.1 C620.1 FB47.1 FB48.1 R693.2 U22.AR18 U22.AR19 U22.AR20 U22.AR21 U22.AR22 U22.AR23 U22.AR24 U22.AR25
VDD_X4VDD: C564.1 C565.1 C598.1 C599.1 C600.1 C601.1 C602.1 C603.1 C604.1 C605.1 C621.1 FB49.1 FB50.1 R695.2 U22.AN33 U22.AR26 U22.AR27 U22.AR28 U22.AR29 U22.AR30 U22.AR31 U22.AR32 U22.AR33
1G_P0_LED_ACT_N: R642.1 TP230.1(TP) U42.100
1G_P0_LINK10_100_N: J11.34 R5796.1 TP231.1(TP) U42.101
1G_P0_LINK1000_N: R644.1 TP232.1(TP) U42.102
1G_P0_TXVA_N: J11.13 U42.127
1G_P0_TXVA_P: J11.6 U42.126
1G_P0_TXVB_N: J11.5 U42.3
1G_P0_TXVB_P: J11.11 U42.2
1G_P0_TXVC_N: J11.10 U42.5
1G_P0_TXVC_P: J11.3 U42.4
1G_P0_TXVD_N: J11.2(TRD4-) U42.8
1G_P0_TXVD_P: J11.8 U42.7
1G_P1_LED_ACT_N: R641.1 TP237.1(TP) U42.105
1G_P1_LINK10_100_N: R643.1 TP236.1(TP) U42.106
1G_P1_LINK1000_N: J11.30 TP235.1(TP) U42.107
1G_P1_TXVA_N: J11.21 U42.18
1G_P1_TXVA_P: J11.15 U42.19
1G_P1_TXVB_N: J11.16 U42.15
1G_P1_TXVB_P: J11.23 U42.16
1G_P1_TXVC_N: J11.24 U42.12
1G_P1_TXVC_P: J11.18 U42.13
1G_P1_TXVD_N: J11.19 U42.9
1G_P1_TXVD_P: J11.26 U42.10
1G_P2_LED_ACT_N: R646.1 TP241.1(TP) U42.111
1G_P2_LINK10_100_N: R648.1 TP240.1(TP) U42.112
1G_P2_LINK1000_N: J12.34 TP239.1(TP) U42.115
1G_P2_TXVA_N: J12.13 U42.21
1G_P2_TXVA_P: J12.6 U42.20
1G_P2_TXVB_N: J12.5 U42.24
1G_P2_TXVB_P: J12.11 U42.23
1G_P2_TXVC_N: J12.10 U42.27
1G_P2_TXVC_P: J12.3 U42.26
1G_P2_TXVD_N: J12.2(TRD4-) U42.30
1G_P2_TXVD_P: J12.8 U42.29
1G_P3_LED_ACT_N: R645.1 TP245.1(TP) U42.118
1G_P3_LINK10_100_N: R647.1 TP244.1(TP) U42.119
1G_P3_LINK1000_N: J12.30 TP243.1(TP) U42.120
1G_P3_TXVA_N: J12.21 U42.40
1G_P3_TXVA_P: J12.15 U42.41
1G_P3_TXVB_N: J12.16 U42.36
1G_P3_TXVB_P: J12.23 U42.37
1G_P3_TXVC_N: J12.24 U42.34
1G_P3_TXVC_P: J12.18 U42.35
1G_P3_TXVD_N: J12.19 U42.31
1G_P3_TXVD_P: J12.26 U42.32
1G_P4_LED_ACT_N: R650.1 TP283.1(TP) U620.100
1G_P4_LINK10_100_N: R652.1 R5797.1 R5800.1 TP282.1(TP) U620.101
1G_P4_LINK1000_N: J13.34 TP281.1(TP) U620.102
1G_P4_TXVA_N: J13.13 U620.127
1G_P4_TXVA_P: J13.6 U620.126
1G_P4_TXVB_N: J13.5 U620.3
1G_P4_TXVB_P: J13.11 U620.2
1G_P4_TXVC_N: J13.10 U620.5
1G_P4_TXVC_P: J13.3 U620.4
1G_P4_TXVD_N: J13.2(TRD4-) U620.8
1G_P4_TXVD_P: J13.8 U620.7
1G_P5_LED_ACT_N: R649.1 TP279.1(TP) U620.105
1G_P5_LINK10_100_N: R651.1 TP278.1(TP) U620.106
1G_P5_LINK1000_N: J13.30 TP277.1(TP) U620.107
1G_P5_TXVA_N: J13.21 U620.18
1G_P5_TXVA_P: J13.15 U620.19
1G_P5_TXVB_N: J13.16 U620.15
1G_P5_TXVB_P: J13.23 U620.16
1G_P5_TXVC_N: J13.24 U620.12
1G_P5_TXVC_P: J13.18 U620.13
1G_P5_TXVD_N: J13.19 U620.9
1G_P5_TXVD_P: J13.26 U620.10
1G_P6_LED_ACT_N: R654.1 TP275.1(TP) U620.111
1G_P6_LINK10_100_N: R656.1 TP274.1(TP) U620.112
1G_P6_LINK1000_N: J14.34 TP273.1(TP) U620.115
1G_P6_TXVA_N: J14.13 U620.21
1G_P6_TXVA_P: J14.6 U620.20
1G_P6_TXVB_N: J14.5 U620.24
1G_P6_TXVB_P: J14.11 U620.23
1G_P6_TXVC_N: J14.10 U620.27
1G_P6_TXVC_P: J14.3 U620.26
1G_P6_TXVD_N: J14.2(TRD4-) U620.30
1G_P6_TXVD_P: J14.8 U620.29
1G_P7_LED_ACT_N: J14.27 TP271.1(TP) U620.118
1G_P7_LINK10_100_N: R655.1 TP270.1(TP) U620.119
1G_P7_LINK1000_N: J14.30 TP269.1(TP) U620.120
1G_P7_TXVA_N: J14.21 U620.40
1G_P7_TXVA_P: J14.15 U620.41
1G_P7_TXVB_N: J14.16 U620.36
1G_P7_TXVB_P: J14.23 U620.37
1G_P7_TXVC_N: J14.24 U620.34
1G_P7_TXVC_P: J14.18 U620.35
1G_P7_TXVD_N: J14.19 U620.31
1G_P7_TXVD_P: J14.26 U620.32
10G_LAN_GPIO0_N: LED6.1 Q3.3
10G_LAN_GPIO1_N: LED6.3(CATHODE2) Q4.3
10G_LAN_GPIO2_N: LED5.1 Q5.3
10G_LAN_GPIO3_N: LED5.3(CATHODE2) Q6.3
ALT_RST_B: C3831.1 JP7.1 R5671.2 U27.L11
ASLEEP: R762.2 R5762.1 U22.G34 U27.B13
ATX_PWROK: R342.2 U27.L15
ATXPWRGD: C299.1 J9.8 R337.2 R342.1
CFG_DDRCLK: U27.M1 U627.8
CFG_SYSCLK: U27.P3 U626.8
CFG_TESTSEL_B: R765.2 U22.F34 U27.J3
CFG_VBANK0: U27.T8 U595.2
CFG_VBANK1: U27.T7 U596.2
CFG_VBANK2: U27.T2 U598.2
CGND: C1259.1 C1260.1 C1261.1 C1262.1 C1263.1 C1264.1 CN3.G1 CN3.G2 CN4.M1 CN4.M2 CN4.M3 CN4.M4 ESD9.2(A2) ESD10.2(A2) FB70.2 FB71.2 FB72.2 J11.S1 J11.S2 J11.S3 J11.S4 J12.S1 J12.S2 J12.S3 J12.S4 J13.S1 J13.S2 J13.S3 J13.S4 J14.S1 J14.S2 J14.S3 J14.S4 J16.S1 J16.S2 J16.S3 J16.S4 J16.S5 J16.S6 J16.S7 J16.S8 J16.S9 J16.S10 J16.S11 J16.S12 J16.S13 J16.S14 J16.S15 J16.S16 J16.S17 J16.S18 J16.S19 J16.S20 J16.S21 J16.S22 J16.S23 J16.S24 J16.S25 J16.S26 J16.S27 J16.S28 J16.S29 J16.S30 J16.S31 J16.S32 J16.S33 J16.S34 LAN1.S1 LAN1.S2 LAN1.S3 LAN1.S4 LAN1.S5 LAN1.S6
CKGEN_VDDO0: C3853.1 FL13.1 U36.22
CKGEN_VDDO1: C3855.1 FL16.1 U36.26
CKGEN_VDDO2: C3863.1 FL18.1 U36.29
CKGEN_VDDO3: C3867.1 FL21.1 U36.33
CKGEN_VDDO4: C3869.1 FL23.1 U36.36
CKGEN_VDDO5: C3854.1 FL14.1 U36.40
CKGEN_VDDO6: C3856.1 FL17.1 U36.43
CKGEN_VDDO7: C3864.1 FL19.1 U36.49
CKGEN_VDDO8: C3868.1 FL22.1 U36.52
CKGEN_VDDO9: C3870.1 FL24.1 U36.57
CKSTPO_B: J2.15 R67.1 TP213.1(TP) U22.L44
CLK_ENET1: R5849.2 U42.66
CLK_ENET2: R5850.2 U620.66
CLK_PCIE_REF_N: C3874.2 U32.3
CLK_PCIE_REF_P: C3873.2 U32.2
CLK_RETIMER: C5310.2 U65.19
CLK_SE1_100MHZ: R5708.2 U626.7
CLK_SE2_100MHZ: R5726.2 U627.7
CLK_SE_66MHZ: R5707.2 U626.5
CLK_SE_133MHZ: R5724.2 U627.5
CLK_USB: R761.2 R5713.2
CLK_USB_DUT: C871.2 R761.1 U22.E34
CLKU0_P: R5707.1 U36.24
CLKU1_N: C3882.1 U36.27
CLKU1_P: C3881.1 U36.28
CLKU2_N: R5850.1 U36.30
CLKU2_P: R5849.1 U36.31
CLKU3_P: R5722.1 U36.35
CLKU4_N: C3874.1 U36.37
CLKU4_P: C3873.1 U36.38
CLKU5_N: C5311.1 U36.41
CLKU5_P: C5310.1 U36.42
CLKU6_N: R5726.1 U36.44
CLKU6_P: R5708.1 U36.45
CLKU7_N: R5848.1 U36.50
CLKU7_P: R5847.1 U36.51
CLKU8_P: R5713.1 U36.54
CLKU9_P: R5724.1 U36.59
COP_HRST_B: J2.13 R68.1 U27.K1
COP_SRST_B: J2.11 R69.1 U27.K2
COP_TCK: J2.7 R71.1 U22.K44
COP_TDI: J2.3 R74.1 U22.J43
COP_TDO: J2.1 U22.K42
COP_TMS: J2.9 R70.1 U22.K41
COP_TRST_B: J2.4 R73.1 U27.H3
COP_VDD_SNS: J2.6 R72.2
D1TPA: TP82.1(TP) U22.AL13
D2TPA: TP78.1(TP) U22.AM13
D3TPA: TP83.1(TP) U22.AF32
DDRCLK: R698.1 R5896.2
DEBUG_LED1_B: LED1.C(CATHODE) Q7.3
DEBUG_LED2_B: LED2.C(CATHODE) Q8.3
DEBUG_LED3_B: LED3.C(CATHODE) Q9.3
DEBUG_LED4_B: LED4.C(CATHODE) Q10.3
DIMM1_SA1: J6.237 R113.1
DIMM2_SA2: J7.119 R338.1
DIMM3_SA: J5.119 J5.237 R336.1
DUT_DMA0: R268.1 U22.P43
DUT_DMA1: TP2.1(TP) U22.R43
DUT_DMA2: TP1.1(TP) U22.R44
DUT_DMA3: R732.1 U22.N41
DUT_DMA4: TP4.1(TP) U22.P44
DUT_DMA5: TP3.1(TP) U22.P42
DUT_HRESET_B: R767.2 U22.D35 U27.H5
DUT_PORESET_B: R766.2 U22.F35 U27.H1
DUT_RESET_REQ_B: R763.2 U22.G33 U27.G1
DUT_TRST_B: U22.J42 U27.H4
DUT_UART1_CTS_B: U22.N11 U46.16
DUT_UART1_RTS_B: U22.M10 U46.13
DUT_UART1_RXD: U22.M11 U46.15
DUT_UART1_TXD: U22.L10 U46.14
DUT_UART2_CTS_B: U22.K11 U95.16
DUT_UART2_RTS_B: U22.K10 U95.13
DUT_UART2_RXD: U22.J11 U95.15
DUT_UART2_TXD: U22.J10 U95.14
EC1_GTX_CLK125: R5847.2 U22.D12
EC1_RX_CLK: R756.1 U22.B12
EC1_RX_DV: R320.1 U22.A13
EC1_RXD0: R751.1 U22.C12
EC1_RXD1: R746.1 U22.E12
EC1_RXD2: R306.1 U22.A12
EC1_RXD3: R739.1 U22.G12
EC1_TX_CTL_S: R753.1 U22.C13
EC2_GTX_CLK125: R5848.2 U22.E10
EC2_RX_CLK: R323.1 U22.B10
EC2_RX_DV: R309.1 U22.C10
EC2_RXD0: R308.2 U22.A10
EC2_RXD1: R321.2 U22.A11
EC2_RXD2: R307.2 U22.C11
EC2_RXD3: R322.2 U22.D10
EC2_TX_CTL_S: R742.1 U22.G10
EMI2_MDC: TP284.1(TP) U22.D13
EMI2_MDIO: R5875.1 TP285.1(TP) U22.E13
EVT0_B: R5853.2 TP86.1(TP) U22.N42
EVT1_B: R5854.2 TP6.1(TP) U22.M43
EVT2_B: R5855.2 TP7.1(TP) U22.M42
EVT3_B: R5856.2 TP9.1(TP) U22.L43
EVT4_B: R5857.2 TP8.1(TP) U22.L42
FA_ANALOG_G_V: R718.1 U22.R32
FA_ANALOG_PIN: R715.1 U22.T32
FAN1_PWM: FAN1.4 R5680.2 U105.5
FAN1_TACH: FAN1.3 R5685.2 R5691.2
FAN2_PWM: FAN2.4 R5681.2 U105.7
FAN2_TACH: FAN2.3 R5686.2 R5692.2
FAN3_PWM: FAN3.4 R5682.2 U105.9
FAN3_TACH: FAN3.3 R5687.2 R5693.2
FAN4_PWM: FAN4.4 R5683.2 U105.13
FAN4_TACH: FAN4.3 R5688.2 R5694.2
FAN5_PWM: FAN5.4 R5684.2 U105.15
FAN5_TACH: FAN5.3 R5689.2 R5695.2
FAN_ADDR: R5690.2 U105.4
FAN_DEF: R5790.2 U105.11
FPGA_EXTAL: C3691.1 U27.R16 Y19.1
FPGA_JTSEL: R5583.2 U27.N13
FPGA_PLL: C3697.1 C3698.1 R5582.2 U27.E10
FPGA_PRB: JP7.3 U27.C14
FPGA_TCK: J105.1 R5585.1 U27.P14
FPGA_TDI: J105.9 U27.N16
FPGA_TDO: J105.3 U27.N14
FPGA_TMS: J105.5 U27.P16
FPGA_TRST_B: J105.8 R5584.1 U27.N15
FPGA_XTAL: C3690.1 U27.R15 Y19.3
FPGAUPD_SCK: J69.2 U27.F15 U250.6
FPGAUPD_SCS_B: J69.1 U27.D16 U250.1
FPGAUPD_SDI: J69.3 U27.F14 U250.2
FPGAUPD_SDO: J69.4 U27.E16 U250.5
FUPD_B: R5667.2 TP197.1(TP) U27.E12
GVDD: C102.1 C104.2 C106.2 C128.1 C129.1 C130.2 C137.1 C138.1 C141.1 C143.1 C150.1 C151.1 C153.2 C157.1 C158.2 C159.2 C161.1 C162.2 C163.1 C164.1 C165.1 C166.2 C167.2 C168.1 C169.2 C170.1 C172.1 C173.1 C176.1 C179.2 C182.1 C185.1 C186.1 C187.2 C189.2 C190.1 C191.1 C192.1 C196.1 C201.2 C202.1 C205.1 C207.2 C208.1 C209.1 C211.1 C216.1 C218.1 C220.1 C221.2 C240.1 C246.1 C251.1 C253.1 C295.1 C570.1 C573.1 C574.1 C575.1 C576.1 C577.1 C578.1 C579.1 C580.1 C581.1 C582.1 C583.1 C584.1 C585.1 C586.2 C587.1 C588.1 C590.1 C591.1 C592.1 C594.1 C615.2 C622.1 C623.1 C628.1 C634.1 C635.1 C637.1 C639.1 C646.1 C653.1 C657.1 C665.1 C667.1 C668.1 C677.1 C678.1 C680.1 C689.1 C690.1 C692.1 C693.1 C702.1 C705.1 C708.1 C710.1 C714.1 C717.2 C718.1 C719.1 C727.1 C741.1 C742.1 C743.1 C753.1 C754.2 C755.1 C765.1 C766.1 C770.2 C786.1 C787.1 C803.1 C817.1 C822.1 C823.1 C836.1 C839.1 C857.1 C869.1 C870.1 C872.1 C873.1 C874.1 C875.1 C876.1 C877.1 C2673.1 C5123.1 C5124.1 C5127.1 C5128.1 C5129.1 C5130.1 CT24.1 CT29.1 CT41.1 CT42.1 CT43.1 CT45.1 CT46.1 CT47.1 CT48.1 CT54.1 CT55.1 FB81.1 FB84.1 J5.51 J5.54 J5.57 J5.60 J5.62 J5.65 J5.66 J5.69 J5.72(VDD9) J5.75 J5.78 J5.170 J5.173 J5.176 J5.179 J5.182 J5.183 J5.186 J5.189 J5.191 J5.194 J5.197 J6.51 J6.54 J6.57 J6.60 J6.62 J6.65 J6.66 J6.69 J6.72(VDD9) J6.75 J6.78 J6.170 J6.173 J6.176 J6.179 J6.182 J6.183 J6.186 J6.189 J6.191 J6.194 J6.197 J7.51 J7.54 J7.57 J7.60 J7.62 J7.65 J7.66 J7.69 J7.72(VDD9) J7.75 J7.78 J7.170 J7.173 J7.176 J7.179 J7.182 J7.183 J7.186 J7.189 J7.191 J7.194 J7.197 L7.2 R93.1 R197.1 R198.2 R202.1 R219.2 R233.2 R271.2 R291.1 U22.A2 U22.A6 U22.A9 U22.AA15 U22.AB1 U22.AB15 U22.AB30 U22.AB43 U22.AC15 U22.AC30 U22.AD2 U22.AD15 U22.AD30 U22.AD44 U22.AE15 U22.AE30 U22.AF1 U22.AF2 U22.AF15 U22.AF30 U22.AF43 U22.AG1 U22.AG15 U22.AG30 U22.AH15 U22.AH30 U22.AH44 U22.AJ2 U22.AJ15 U22.AK43 U22.AL1 U22.AM44 U22.AN2 U22.AP43 U22.AR1 U22.AT44 U22.AU2 U22.AV43 U22.AW1 U22.AY44 U22.B1 U22.B4 U22.B9 U22.BA2 U22.BB43 U22.BC1 U22.BC4 U22.BC8 U22.BC12 U22.BC16 U22.BC37 U22.BC41 U22.BC44 U22.BD2 U22.BD6 U22.BD10 U22.BD14 U22.BD17 U22.BD35 U22.BD39 U22.BD43 U22.D2 U22.F1 U22.H2 U22.K1 U22.M2 U22.P1 U22.T2 U22.T15 U22.U15 U22.V1 U22.V15 U22.W15 U22.Y2 U22.Y15 U22.Y43 U22.Y44
GVDD_FB: C5132.2 R96.2 R100.1 U631.A5
GVDD_FDIVH: C5132.1 R93.2 R96.1 R98.2
GVDD_FDIVL: R99.2 R100.2 R101.1 R102.1
GVDD_GND: C5131.2 C5133.2 C5135.2 C5136.2 C5137.2 R95.2 R97.2 R103.1 U631.B5
GVDD_INTVCC: C5134.1 U631.B6
GVDD_ITH: C5136.1 R104.1 U631.A4
GVDD_ITHX: C5137.1 R104.2
GVDD_MS: R95.1 U631.B3
GVDD_RT: R97.1 U631.A3
GVDD_SENSE: R98.1 R233.1
GVDD_SVIN: C5131.1 R92.2 U631.C1
GVDD_SW: L7.1 U631.C3 U631.C4 U631.D3 U631.D4 U631.E3 U631.E4 U631.F3 U631.F4 U631.G3 U631.G4
GVDD_TRK: C5133.1 U631.B4
GVDD_VOUTM: C5135.1 R101.2 U631.A6(VOUTM)
GVSS_SENSE: R99.1 R234.1
I2C1_CH0_SCL: R519.2 U65.17 U82.5 U622.17
I2C1_CH0_SDA: R520.2 U65.18 U82.4 U622.18
I2C1_CH1_SCL: J16.5A R521.2 U82.7
I2C1_CH1_SDA: J16.4A R522.2 U82.6
I2C1_CH2_SCL: J16.5B R523.2 U82.9
I2C1_CH2_SDA: J16.4B R5870.2 U82.8
I2C1_CH3_SCL: J16.5C R5871.2 U82.11
I2C1_CH3_SDA: J16.4C R526.2 U82.10
I2C1_CH4_SCL: J16.5D R527.2 U82.14
I2C1_CH4_SDA: J16.4D R528.2 U82.13
I2C1_CH5_SCL: R529.2 U82.16
I2C1_CH5_SDA: R530.2 U82.15
I2C1_CH6_SCL: R531.2 U55.B5 U82.18
I2C1_CH6_SDA: R5872.2 U55.B6 U82.17
I2C1_CH7_SCL: R5873.2 U82.20 U624.19
I2C1_CH7_SDA: R5874.2 U82.19 U624.20
I2C1_EN: R830.2 U58.5
I2C1_PROC_SCL: R208.2 U22.R10 U58.2
I2C1_PROC_SDA: R205.2 U22.R11 U58.3
I2C1_SCL: J5.118 J6.118 J7.118 J55.3 R217.2 R627.2 U2.10 U16.2 U27.E14 U36.16 U58.7 U82.22 U105.2 U589.6 U625.6
I2C1_SDA: J5.238 J6.238 J7.238 J55.1 R222.2 R630.2 U2.9 U16.5 U27.E15 U36.18 U58.6 U82.23 U105.1 U589.5 U625.5
I2C2_EN: R191.2 U18.5
I2C2_PROC_SCL: R196.2 U18.2 U22.N10
I2C2_PROC_SDA: R190.2 U18.3 U22.P10
I2C2_SCL: J3.B5 J4.3 R203.2 U18.7
I2C2_SDA: J3.B6 J4.1 R192.2 U18.6
I2C4_SCL: R726.2 U22.N12
I2C4_SDA: R720.2 U22.P12
IFC_A0: TP200.1(TP) U593.2
IFC_A1: TP201.1(TP) U593.3
IFC_A2: TP202.1(TP) U593.5
IFC_A3: TP203.1(TP) U593.6
IFC_A4: TP204.1(TP) U593.8
IFC_A5: U593.9 U598.1
IFC_A6: U593.11 U596.1
IFC_A7: U593.12 U595.1
IFC_A8: U37.2 U593.13
IFC_A9: U37.15 U593.14
IFC_A10: U37.12 U593.16
IFC_A11: U37.11 U593.17
IFC_A12: U37.18 U593.19
IFC_A13: U37.19 U593.20
IFC_A14: U37.54 U593.22
IFC_A15: U37.3 U593.23
IFC_A16: U37.4 U594.2
IFC_A17: U37.5 U594.3
IFC_A18: U37.6 U594.5
IFC_A19: U37.7 U594.6
IFC_A20: U37.8 U594.8
IFC_A21: U37.9 U594.9
IFC_A22: U37.10 U594.11
IFC_A23: U37.20 U594.12
IFC_A24: U37.21 U594.13
IFC_A25: U37.22 U594.14
IFC_A26: U22.B40 U37.23
IFC_A27: U22.A40 U37.24
IFC_A28: U22.D39 U37.25
IFC_A29: U22.C39 U37.26
IFC_A30: U22.A39 U37.31
IFC_A31: TP258.1(TP) U22.C38
IFC_AD0: U22.W39 U27.L4 U37.51 U38.J8 U593.47
IFC_AD1: U22.W40 U27.R4 U37.49 U38.K7 U593.46
IFC_AD2: U22.V39 U27.R5 U37.47 U38.J7 U593.44
IFC_AD3: U22.V40 U27.P6 U37.45 U38.K6 U593.43
IFC_AD4: U22.U40 U27.P7 U37.42 U38.K5 U593.41
IFC_AD5: U22.U41 U27.P2 U37.40 U38.K4 U593.40
IFC_AD6: U22.T39 U27.R2 U37.38 U38.J4 U593.38
IFC_AD7: U22.T40 U27.P1 U37.36 U38.H4 U593.37
IFC_AD8: U22.R39 U27.R1 U37.50 U593.36
IFC_AD9: U22.R40 U27.R6 U37.48 U593.35
IFC_AD10: U22.P40 U27.R7 U37.46 U593.33
IFC_AD11: U22.P41 U27.M7 U37.44 U593.32
IFC_AD12: U22.N39 U27.M6 U37.41 U593.30
IFC_AD13: U22.N40 U27.M8 U37.39 U593.29
IFC_AD14: U22.M39 U27.N8 U37.37 U593.27
IFC_AD15: U22.M40 U27.N6 U37.35 U593.26
IFC_AD16: U22.L40 U27.N5 U594.47
IFC_AD17: R5904.2 U22.L41 U27.T5 U594.46
IFC_AD18: R5903.2 U22.K39 U594.44
IFC_AD19: R5902.2 U22.K40 U594.43
IFC_AD20: R5898.2 U22.J39 U594.41
IFC_AD21: R796.1 R5771.2 U22.J40 U27.T4 U594.40
IFC_AD22: U22.H40 U594.38
IFC_AD23: U22.H41 U594.37
IFC_AD24: U22.G40 U594.36
IFC_AD25: U22.G41 U594.35
IFC_AD26: U22.G39 U594.33
IFC_AD27: U22.F40 U594.32
IFC_AD28: U22.E41 U594.30
IFC_AD29: U22.E40 U594.29
IFC_AD30: U22.E39 U594.27
IFC_AD31: U22.D41 U594.26
IFC_AVD: U22.H44 U27.R10 U38.C4 U593.25 U593.48 U594.25 U594.48
IFC_BCTL: U22.G44 U27.P9
IFC_CLE: U22.E43 U27.K4 U38.D5
IFC_CLK: U22.B38 U27.L5
IFC_CS0_B: R280.2 U22.C43 U27.T10
IFC_CS1_B: R279.2 U22.C44 U27.N9
IFC_CS2_B: R294.2 U22.B43 U27.N10
IFC_CS3_B: R295.2 U22.A42 U27.P11
IFC_CS_B4: TP15.1(TP) U22.C41
IFC_CS_B5: TP20.1(TP) U22.B41
IFC_CS_B6: TP21.1(TP) U22.A41
IFC_CS_B7: TP16.1(TP) U22.C40
IFC_NAND_CS_B: R524.2 U27.R12 U38.C6
IFC_NAND_RB_B: R818.2 U27.T13 U38.C8
IFC_NAND_WE_B: R525.2 U27.T12 U38.C7
IFC_NOR_CS_B: U27.P12 U37.32
IFC_NOR_RB_B: R5858.2 U27.M11 U37.17
IFC_NOR_WE_B: U27.P13 U37.13
IFC_OE_B: U22.E42 U27.R9 U37.34 U38.D4
IFC_RB0_B: R276.2 U22.F43 U27.M10
IFC_RB1_B: R277.2 U22.F42 U27.R11
IFC_TE: U22.G42 U27.T9
IFC_VBANK0: U37.1 U595.4(Y)
IFC_VBANK1: U37.56 U596.4(Y)
IFC_VBANK2: U37.55 U598.4(Y)
IFC_WE0_B: U22.E44 U27.N11
IFC_WE2_B: TP13.1(TP) U22.D42 U27.M9
IFC_WE3_B: TP14.1(TP) U22.D44
IFC_WP_B: U22.F44 U27.P8 U37.16(W\P\/ACC) U38.C3
INJ_DDRCLK: R698.2 U22.AL14
INJ_SYSCLK: R711.2 U22.U34
INT_PHY0_B: U27.A13 U42.99
INT_PHY1_B: U27.A14 U620.99
INT_RETIMER_B: U27.J12 U65.43 U622.43
IRQ0_B: R254.2 U22.V43 U27.D9
IRQ1_B: R253.2 U22.V44 U27.E9
IRQ2_B: R257.2 U22.U43 U27.B10
IRQ3_B: R251.2 U22.W42 U27.C10
IRQ4_B: R258.2 U22.U44 U27.D8
IRQ5_B: R266.2 U22.R42 U27.E8
IRQ6_B: R252.2 U22.W41 U27.C8
IRQ7_B: R263.2 U22.T42 U27.C9
IRQ8_B: R262.2 U22.T44 U27.A8
IRQ9_B: R255.2 U22.V42 U27.B8
IRQ10_B: R250.2 U22.W44 U27.D6
IRQ11_B: R260.2 U22.U42 U27.D7
IRQ_CLOCK_B: U27.K12 U36.12
IRQ_FAN_B: R5892.2 U27.K16 U105.12
IRQ_OUT_B: R265.2 U22.T41
IRQ_RTC_B: U16.13 U27.C4
ISOSDHC_CLK: R614.1 U45.8
ISOSDHC_CMD: CN3.2 U45.13
ISOSDHC_DAT0: CN3.7 U45.10
ISOSDHC_DAT1: CN3.8 U45.9
ISOSDHC_DAT2: CN3.9 U45.12
ISOSDHC_DAT3: CN3.1 U45.11
LED0: Q3.1 U27.G13
LED1: Q4.1 U27.G12
LED2: Q5.1 U27.H14
LED3: Q6.1 U27.H13
LED4: Q7.1 U27.J14
LED5: Q8.1 U27.J13
LED6: Q9.1 U27.K15
LED7: Q10.1 U27.K14
LP_TMP_DETECT_B: R717.1 TP206.1(TP) U22.T27
LRST_BUTTON_B: C522.1 R669.1 R671.2 SW6.1
LV_TACH1: R5691.1 R5698.1 U105.6
LV_TACH2: R5692.1 R5699.1 U105.8
LV_TACH3: R5693.1 R5700.1 U105.10
LV_TACH4: R5694.1 R5701.1 U105.14
LV_TACH5: R5695.1 R5702.1 U105.16
M1_MA0: J6.188 U22.R2
M1_MA1: J6.181 U22.G1
M1_MA2: J6.61 U22.G2
M1_MA3: J6.180 U22.F2
M1_MA4: J6.59 U22.E1
M1_MA5: J6.58 U22.E2
M1_MA6: J6.178 U22.D1
M1_MA7: J6.56 U22.C2
M1_MA8: J6.177 U22.C1
M1_MA9: J6.175 U22.B3
M1_MA10: J6.70 U22.T1
M1_MA11: J6.55 U22.B2
M1_MA12: J6.174 U22.A3
M1_MA13: J6.196 U22.AD1
M1_MA14: J6.172 U22.B5
M1_MA15: J6.171 U22.B6
M1_MBA0: J6.71 U22.U1
M1_MBA1: J6.190 U22.U2
M1_MBA2: J6.52 U22.A5
M1_MCAS_B: J6.74 U22.AA2
M1_MCKE0: J6.50 U22.A7
M1_MCKE1: J6.169 U22.B8
M1_MCLK0_N: J6.185 U22.L2
M1_MCLK0_P: J6.184 U22.K2
M1_MCLK1_N: J6.64 U22.M1
M1_MCLK1_P: J6.63 U22.L1
M1_MCLK2_N: R261.2 U22.N1
M1_MCLK2_P: R264.2 U22.N2
M1_MCLK3_N: R267.2 U22.J1
M1_MCLK3_P: R269.2 U22.J2
M1_MCS_B0: J6.193 U22.Y1
M1_MCS_B1: J6.76 U22.AC2
M1_MCS_B2: J6.79 U22.W1
M1_MCS_B3: J6.198 U22.AC1
M1_MDIC_0: R259.1 U22.P2
M1_MDIC_1: R271.1 U22.H1
M1_MDQ0: J6.3 U22.F7
M1_MDQ1: J6.4 U22.E7
M1_MDQ2: J6.9 U22.D4
M1_MDQ3: J6.10 U22.E4
M1_MDQ4: J6.122 U22.E8
M1_MDQ5: J6.123 U22.D8
M1_MDQ6: J6.128 U22.D5
M1_MDQ7: J6.129 U22.E5
M1_MDQ8: J6.12 U22.J8
M1_MDQ9: J6.13 U22.G7
M1_MDQ10: J6.18 U22.G4
M1_MDQ11: J6.19 U22.H4
M1_MDQ12: J6.131 U22.H8
M1_MDQ13: J6.132 U22.G8
M1_MDQ14: J6.137 U22.J6
M1_MDQ15: J6.138 U22.J4
M1_MDQ16: J6.21 U22.L8
M1_MDQ17: J6.22 U22.L7
M1_MDQ18: J6.27 U22.R8
M1_MDQ19: J6.28 U22.R7
M1_MDQ20: J6.140 U22.K8
M1_MDQ21: J6.141 U22.K7
M1_MDQ22: J6.146 U22.P8
M1_MDQ23: J6.147 U22.P7
M1_MDQ24: J6.30 U22.L5
M1_MDQ25: J6.31 U22.L4
M1_MDQ26: J6.36 U22.R5
M1_MDQ27: J6.37 U22.R4
M1_MDQ28: J6.149 U22.K5
M1_MDQ29: J6.150 U22.K4
M1_MDQ30: J6.155 U22.P5
M1_MDQ31: J6.156 U22.P4
M1_MDQ32: J6.81 U22.U7
M1_MDQ33: J6.82 U22.U8
M1_MDQ34: J6.87 U22.AA7
M1_MDQ35: J6.88 U22.AA8
M1_MDQ36: J6.200 U22.T7
M1_MDQ37: J6.201 U22.T8
M1_MDQ38: J6.206 U22.Y7
M1_MDQ39: J6.207 U22.Y8
M1_MDQ40: J6.90 U22.U11
M1_MDQ41: J6.91 U22.U12
M1_MDQ42: J6.96 U22.Y12
M1_MDQ43: J6.97 U22.Y13
M1_MDQ44: J6.209 U22.U9
M1_MDQ45: J6.210 U22.U10
M1_MDQ46: J6.215 U22.Y10
M1_MDQ47: J6.216 U22.Y11
M1_MDQ48: J6.99 U22.AB7
M1_MDQ49: J6.100 U22.AC7
M1_MDQ50: J6.105 U22.AE6
M1_MDQ51: J6.106 U22.AD7
M1_MDQ52: J6.218 U22.AB5
M1_MDQ53: J6.219 U22.AB6
M1_MDQ54: J6.224 U22.AE5
M1_MDQ55: J6.225 U22.AD6
M1_MDQ56: J6.108 U22.AC9
M1_MDQ57: J6.109 U22.AD9
M1_MDQ58: J6.114 U22.AB13
M1_MDQ59: J6.115 U22.AC13
M1_MDQ60: J6.227 U22.AB9
M1_MDQ61: J6.228 U22.AA9
M1_MDQ62: J6.233 U22.AB12
M1_MDQ63: J6.234 U22.AC12
M1_MDQS_N0: J6.6 U22.F6
M1_MDQS_N1: J6.15 U22.H5
M1_MDQS_N2: J6.24 U22.N8
M1_MDQS_N3: J6.33 U22.N5
M1_MDQS_N4: J6.84 U22.W7
M1_MDQS_N5: J6.93 U22.W10
M1_MDQS_N6: J6.102 U22.AD4
M1_MDQS_N7: J6.111 U22.AB11
M1_MDQS_N8: J6.42 U22.W5
M1_MDQS_N9: J6.126 U22.D6
M1_MDQS_N10: J6.135 U22.H6
M1_MDQS_N11: J6.144 U22.M7
M1_MDQS_N12: J6.153 U22.M4
M1_MDQS_N13: J6.204 U22.V8
M1_MDQS_N14: J6.213 U22.V11
M1_MDQS_N15: J6.222 U22.AC5
M1_MDQS_N16: J6.231 U22.AC10
M1_MDQS_N17: J6.162 U22.V4
M1_MDQS_P0: J6.7 U22.F5
M1_MDQS_P1: J6.16 U22.G5
M1_MDQS_P2: J6.25 U22.N7
M1_MDQS_P3: J6.34 U22.N4
M1_MDQS_P4: J6.85 U22.W8
M1_MDQS_P5: J6.94 U22.W11
M1_MDQS_P6: J6.103 U22.AE4
M1_MDQS_P7: J6.112 U22.AC11
M1_MDQS_P8: J6.43 U22.W4
M1_MDQS_P9: J6.125 U22.D7
M1_MDQS_P10: J6.134 U22.H7
M1_MDQS_P11: J6.143 U22.M8
M1_MDQS_P12: J6.152 U22.M5
M1_MDQS_P13: J6.203 U22.V7
M1_MDQS_P14: J6.212 U22.V10
M1_MDQS_P15: J6.221 U22.AC4
M1_MDQS_P16: J6.230 U22.AB10
M1_MDQS_P17: J6.161 U22.V5
M1_MECC0: J6.39 U22.U5
M1_MECC1: J6.40 U22.U4
M1_MECC2: J6.45 U22.AA5
M1_MECC3: J6.46 U22.AA4
M1_MECC4: J6.158 U22.T5
M1_MECC5: J6.159 U22.T4
M1_MECC6: J6.164 U22.Y5
M1_MECC7: J6.165 U22.Y4
M1_MODT0: J6.195 U22.AA1
M1_MODT1: J6.77 U22.AE1
M1_MRAS_B: J6.192 U22.V2
M1_MWE_B: J6.73 U22.W2
M1_PARERR_B: J6.53 R291.2 U22.A4
M1_PAROUT: J6.68 U22.R1
M1_VREF_ISO: C780.1 C781.1 R713.1 U22.V13
M2_MA0: J7.188 U22.AU1
M2_MA1: J7.181 U22.BC5
M2_MA2: J7.61 U22.BD4
M2_MA3: J7.180 U22.BD5
M2_MA4: J7.59 U22.BC6
M2_MA5: J7.58 U22.BC7
M2_MA6: J7.178 U22.BD7
M2_MA7: J7.56 U22.BC9
M2_MA8: J7.177 U22.BD8
M2_MA9: J7.175 U22.BC10
M2_MA10: J7.70 U22.AT2
M2_MA11: J7.55 U22.BD9
M2_MA12: J7.174 U22.BC11
M2_MA13: J7.196 U22.AK2
M2_MA14: J7.172 U22.BC13
M2_MA15: J7.171 U22.BC14
M2_MBA0: J7.71 U22.AR2
M2_MBA1: J7.190 U22.AT1
M2_MBA2: J7.52 U22.BD12
M2_MCAS_B: J7.74 U22.AM2
M2_MCKE0: J7.50 U22.BD15
M2_MCKE1: J7.169 U22.BD16
M2_MCLK0_N: J7.185 U22.AY1
M2_MCLK0_P: J7.184 U22.BA1
M2_MCLK1_N: J7.64 U22.BB2
M2_MCLK1_P: J7.63 U22.BB1
M2_MCLK2_N: R213.2 U22.AW2
M2_MCLK2_P: R211.2 U22.AY2
M2_MCLK3_N: R199.2 U22.BC3
M2_MCLK3_P: R200.2 U22.BC2
M2_MCS_B0: J7.193 U22.AP2
M2_MCS_B1: J7.76 U22.AH2
M2_MCS_B2: J7.79 U22.AN1
M2_MCS_B3: J7.198 U22.AJ1
M2_MDIC_0: R218.1 U22.AV2
M2_MDIC_1: R198.1 U22.BD3
M2_MDQ0: J7.3 U22.AY15
M2_MDQ1: J7.4 U22.BA15
M2_MDQ2: J7.9 U22.AY11
M2_MDQ3: J7.10 U22.BA11
M2_MDQ4: J7.122 U22.AY16
M2_MDQ5: J7.123 U22.BA16
M2_MDQ6: J7.128 U22.AY12
M2_MDQ7: J7.129 U22.BA12
M2_MDQ8: J7.12 U22.AU15
M2_MDQ9: J7.13 U22.AV15
M2_MDQ10: J7.18 U22.AU11
M2_MDQ11: J7.19 U22.AV11
M2_MDQ12: J7.131 U22.AU16
M2_MDQ13: J7.132 U22.AV16
M2_MDQ14: J7.137 U22.AU12
M2_MDQ15: J7.138 U22.AV12
M2_MDQ16: J7.21 U22.AU8
M2_MDQ17: J7.22 U22.AV8
M2_MDQ18: J7.27 U22.AU4
M2_MDQ19: J7.28 U22.AV4
M2_MDQ20: J7.140 U22.AU9
M2_MDQ21: J7.141 U22.AV9
M2_MDQ22: J7.146 U22.AU5
M2_MDQ23: J7.147 U22.AV5
M2_MDQ24: J7.30 U22.AY8
M2_MDQ25: J7.31 U22.BA8
M2_MDQ26: J7.36 U22.AY4
M2_MDQ27: J7.37 U22.BA4
M2_MDQ28: J7.149 U22.AY9
M2_MDQ29: J7.150 U22.BA9
M2_MDQ30: J7.155 U22.AY5
M2_MDQ31: J7.156 U22.BA5
M2_MDQ32: J7.81 U22.AP8
M2_MDQ33: J7.82 U22.AP7
M2_MDQ34: J7.87 U22.AK8
M2_MDQ35: J7.88 U22.AK7
M2_MDQ36: J7.200 U22.AR8
M2_MDQ37: J7.201 U22.AR7
M2_MDQ38: J7.206 U22.AL8
M2_MDQ39: J7.207 U22.AL7
M2_MDQ40: J7.90 U22.AP4
M2_MDQ41: J7.91 U22.AP5
M2_MDQ42: J7.96 U22.AK4
M2_MDQ43: J7.97 U22.AK5
M2_MDQ44: J7.209 U22.AR4
M2_MDQ45: J7.210 U22.AR5
M2_MDQ46: J7.215 U22.AL4
M2_MDQ47: J7.216 U22.AL5
M2_MDQ48: J7.99 U22.AH6
M2_MDQ49: J7.100 U22.AH5
M2_MDQ50: J7.105 U22.AF8
M2_MDQ51: J7.106 U22.AE8
M2_MDQ52: J7.218 U22.AH8
M2_MDQ53: J7.219 U22.AH7
M2_MDQ54: J7.224 U22.AF7
M2_MDQ55: J7.225 U22.AG7
M2_MDQ56: J7.108 U22.AG9
M2_MDQ57: J7.109 U22.AG10
M2_MDQ58: J7.114 U22.AF13
M2_MDQ59: J7.115 U22.AE13
M2_MDQ60: J7.227 U22.AH10
M2_MDQ61: J7.228 U22.AH11
M2_MDQ62: J7.233 U22.AF12
M2_MDQ63: J7.234 U22.AE12
M2_MDQS_N0: J7.6 U22.AY13
M2_MDQS_N1: J7.15 U22.AU13
M2_MDQS_N2: J7.24 U22.AU6
M2_MDQS_N3: J7.33 U22.AY6
M2_MDQS_N4: J7.84 U22.AM8
M2_MDQS_N5: J7.93 U22.AM4
M2_MDQS_N6: J7.102 U22.AG5
M2_MDQS_N7: J7.111 U22.AE10
M2_MDQS_N8: J7.42 U22.AM11
M2_MDQS_N9: J7.126 U22.BA14
M2_MDQS_N10: J7.135 U22.AV14
M2_MDQS_N11: J7.144 U22.AV7
M2_MDQS_N12: J7.153 U22.BA7
M2_MDQS_N13: J7.204 U22.AN7
M2_MDQS_N14: J7.213 U22.AN5
M2_MDQS_N15: J7.222 U22.AG4
M2_MDQS_N16: J7.231 U22.AF11
M2_MDQS_N17: J7.162 U22.AN10
M2_MDQS_P0: J7.7 U22.BA13
M2_MDQS_P1: J7.16 U22.AV13
M2_MDQS_P2: J7.25 U22.AV6
M2_MDQS_P3: J7.34 U22.BA6
M2_MDQS_P4: J7.85 U22.AM7
M2_MDQS_P5: J7.94 U22.AM5
M2_MDQS_P6: J7.103 U22.AG6
M2_MDQS_P7: J7.112 U22.AE11
M2_MDQS_P8: J7.43 U22.AM10
M2_MDQS_P9: J7.125 U22.AY14
M2_MDQS_P10: J7.134 U22.AU14
M2_MDQS_P11: J7.143 U22.AU7
M2_MDQS_P12: J7.152 U22.AY7
M2_MDQS_P13: J7.203 U22.AN8
M2_MDQS_P14: J7.212 U22.AN4
M2_MDQS_P15: J7.221 U22.AH4
M2_MDQS_P16: J7.230 U22.AF10
M2_MDQS_P17: J7.161 U22.AN11
M2_MECC0: J7.39 U22.AP11
M2_MECC1: J7.40 U22.AP10
M2_MECC2: J7.45 U22.AK11
M2_MECC3: J7.46 U22.AK10
M2_MECC4: J7.158 U22.AR11
M2_MECC5: J7.159 U22.AR10
M2_MECC6: J7.164 U22.AL11
M2_MECC7: J7.165 U22.AL10
M2_MODT0: J7.195 U22.AL2
M2_MODT1: J7.77 U22.AG2
M2_MRAS_B: J7.192 U22.AP1
M2_MWE_B: J7.73 U22.AM1
M2_PARERR_B: J7.53 R197.2 U22.BD11
M2_PAROUT: J7.68 U22.AV1
M2_VREF_ISO: C656.1 C679.1 R703.1 U22.AH13
M3_MA0: J5.188 U22.AL44
M3_MA1: J5.181 U22.AW43
M3_MA2: J5.61 U22.AW44
M3_MA3: J5.180 U22.AY43
M3_MA4: J5.59 U22.BA43
M3_MA5: J5.58 U22.BA44
M3_MA6: J5.178 U22.BB44
M3_MA7: J5.56 U22.BC43
M3_MA8: J5.177 U22.BC42
M3_MA9: J5.175 U22.BD41
M3_MA10: J5.70 U22.AK44
M3_MA11: J5.55 U22.BD42
M3_MA12: J5.174 U22.BC40
M3_MA13: J5.196 U22.AB44
M3_MA14: J5.172 U22.BC39
M3_MA15: J5.171 U22.BD38
M3_MBA0: J5.71 U22.AJ43
M3_MBA1: J5.190 U22.AJ44
M3_MBA2: J5.52 U22.BC38
M3_MCAS_B: J5.74 U22.AE44
M3_MCKE0: J5.50 U22.BD37
M3_MCKE1: J5.169 U22.BC35
M3_MCLK0_N: J5.185 U22.AR43
M3_MCLK0_P: J5.184 U22.AT43
M3_MCLK1_N: J5.64 U22.AP44
M3_MCLK1_P: J5.63 U22.AR44
M3_MCLK2_N: R229.2 U22.AN43
M3_MCLK2_P: R230.2 U22.AN44
M3_MCLK3_N: R221.2 U22.AU43
M3_MCLK3_P: R224.2 U22.AU44
M3_MCS_B0: J5.193 U22.AF44
M3_MCS_B1: J5.76 U22.AC44
M3_MCS_B2: J5.79 U22.AG43
M3_MCS_B3: J5.198 U22.AC43
M3_MDIC_0: R232.1 U22.AM43
M3_MDIC_1: R219.1 U22.AV44
M3_MDQ0: J5.3 U22.AY35
M3_MDQ1: J5.4 U22.BA35
M3_MDQ2: J5.9 U22.AW37
M3_MDQ3: J5.10 U22.AV37
M3_MDQ4: J5.122 U22.AU35
M3_MDQ5: J5.123 U22.AV35
M3_MDQ6: J5.128 U22.BA37
M3_MDQ7: J5.129 U22.AY37
M3_MDQ8: J5.12 U22.AP35
M3_MDQ9: J5.13 U22.AR35
M3_MDQ10: J5.18 U22.AR38
M3_MDQ11: J5.19 U22.AP38
M3_MDQ12: J5.131 U22.AP34
M3_MDQ13: J5.132 U22.AR34
M3_MDQ14: J5.137 U22.AT38
M3_MDQ15: J5.138 U22.AU38
M3_MDQ16: J5.21 U22.BA40
M3_MDQ17: J5.22 U22.AY40
M3_MDQ18: J5.27 U22.AV40
M3_MDQ19: J5.28 U22.AU40
M3_MDQ20: J5.140 U22.BA39
M3_MDQ21: J5.141 U22.AY39
M3_MDQ22: J5.146 U22.AW41
M3_MDQ23: J5.147 U22.AV41
M3_MDQ24: J5.30 U22.AR40
M3_MDQ25: J5.31 U22.AR41
M3_MDQ26: J5.36 U22.AL40
M3_MDQ27: J5.37 U22.AL41
M3_MDQ28: J5.149 U22.AT40
M3_MDQ29: J5.150 U22.AT41
M3_MDQ30: J5.155 U22.AM40
M3_MDQ31: J5.156 U22.AM41
M3_MDQ32: J5.81 U22.AH40
M3_MDQ33: J5.82 U22.AH41
M3_MDQ34: J5.87 U22.AD40
M3_MDQ35: J5.88 U22.AD41
M3_MDQ36: J5.200 U22.AJ40
M3_MDQ37: J5.201 U22.AJ41
M3_MDQ38: J5.206 U22.AE40
M3_MDQ39: J5.207 U22.AE41
M3_MDQ40: J5.90 U22.AH38
M3_MDQ41: J5.91 U22.AH37
M3_MDQ42: J5.96 U22.AD38
M3_MDQ43: J5.97 U22.AD37
M3_MDQ44: J5.209 U22.AJ38
M3_MDQ45: J5.210 U22.AJ37
M3_MDQ46: J5.215 U22.AE38
M3_MDQ47: J5.216 U22.AE37
M3_MDQ48: J5.99 U22.AG35
M3_MDQ49: J5.100 U22.AG34
M3_MDQ50: J5.105 U22.AC35
M3_MDQ51: J5.106 U22.AC34
M3_MDQ52: J5.218 U22.AH35
M3_MDQ53: J5.219 U22.AH34
M3_MDQ54: J5.224 U22.AD35
M3_MDQ55: J5.225 U22.AD34
M3_MDQ56: J5.108 U22.AB40
M3_MDQ57: J5.109 U22.AA40
M3_MDQ58: J5.114 U22.AB36
M3_MDQ59: J5.115 U22.AA36
M3_MDQ60: J5.227 U22.AB41
M3_MDQ61: J5.228 U22.AA41
M3_MDQ62: J5.233 U22.AB37
M3_MDQ63: J5.234 U22.AA37
M3_MDQS_N0: J5.6 U22.BA36
M3_MDQS_N1: J5.15 U22.AR37
M3_MDQS_N2: J5.24 U22.AW39
M3_MDQS_N3: J5.33 U22.AN40
M3_MDQS_N4: J5.84 U22.AF40
M3_MDQS_N5: J5.93 U22.AF38
M3_MDQS_N6: J5.102 U22.AE35
M3_MDQS_N7: J5.111 U22.AB38
M3_MDQS_N8: J5.42 U22.AL37
M3_MDQS_N9: J5.126 U22.AV36
M3_MDQS_N10: J5.135 U22.AR36
M3_MDQS_N11: J5.144 U22.AY41
M3_MDQS_N12: J5.153 U22.AP41
M3_MDQS_N13: J5.204 U22.AG41
M3_MDQS_N14: J5.213 U22.AG37
M3_MDQS_N15: J5.222 U22.AF34
M3_MDQS_N16: J5.231 U22.AA39
M3_MDQS_N17: J5.162 U22.AM38
M3_MDQS_P0: J5.7 U22.AY36
M3_MDQS_P1: J5.16 U22.AT37
M3_MDQS_P2: J5.25 U22.AV39
M3_MDQS_P3: J5.34 U22.AN41
M3_MDQS_P4: J5.85 U22.AF41
M3_MDQS_P5: J5.94 U22.AF37
M3_MDQS_P6: J5.103 U22.AE34
M3_MDQS_P7: J5.112 U22.AA38
M3_MDQS_P8: J5.43 U22.AL38
M3_MDQS_P9: J5.125 U22.AU36
M3_MDQS_P10: J5.134 U22.AP36
M3_MDQS_P11: J5.143 U22.BA41
M3_MDQS_P12: J5.152 U22.AP40
M3_MDQS_P13: J5.203 U22.AG40
M3_MDQS_P14: J5.212 U22.AG38
M3_MDQS_P15: J5.221 U22.AF35
M3_MDQS_P16: J5.230 U22.AB39
M3_MDQS_P17: J5.161 U22.AM37
M3_MECC0: J5.39 U22.AN37
M3_MECC1: J5.40 U22.AN38
M3_MECC2: J5.45 U22.AK35
M3_MECC3: J5.46 U22.AK34
M3_MECC4: J5.158 U22.AM34
M3_MECC5: J5.159 U22.AM35
M3_MECC6: J5.164 U22.AL36
M3_MECC7: J5.165 U22.AL35
M3_MODT0: J5.195 U22.AE43
M3_MODT1: J5.77 U22.AA43
M3_MRAS_B: J5.192 U22.AH43
M3_MWE_B: J5.73 U22.AG44
M3_PARERR_B: J5.53 R202.2 U22.BD40
M3_PAROUT: J5.68 U22.AL43
M3_VREF_ISO: C703.1 C704.1 R705.1 U22.AD32
M_VREF_A: C35.1 C125.2 C152.1 C197.1 C304.1 C1247.2 C1254.1 J6.1 J6.67 J7.1 J7.67 R703.2 R713.2 U17.8
M_VREF_B: C27.1 C666.1 C1252.1 C1256.1 C1257.2 FB86.2 J5.1 J5.67 R705.2
M_VTT_A: C28.1 C117.1 C148.1 C199.1 C215.1 C303.1 C1241.1 C1242.1 C1243.1 C5144.1 C5145.1 C5146.1 J6.48 J6.49 J6.120 J6.240 J7.48 J7.49 J7.120 J7.240 R5905.1 U17.2
M_VTT_B: C119.1 C300.1 C305.1 C1251.1 C1253.1 C5147.1 C5148.1 J5.48 J5.49 J5.120 J5.240 R5906.1 U14.2
MON_DDRCLK: U27.A15 U627.10
MON_SYSCLK: U27.C13 U626.10
NAND_LOCK: TP222.1(TP) U38.G5
ORIENT_ERR_B: U22.C42(NC_DET) U27.L13
OVDD: C6.1 C8.1 C276.1 C341.1 C345.1 C346.1 C347.1 C433.1 C3849.1 C3850.1 C3851.1 C3852.1 C3857.1 C3858.1 C5138.1 C5139.2 C5171.1 C5320.1 C5327.1 C5330.1 FB1.1 FB24.2 FB25.2 FB26.1 FB55.2 FL13.3(OUT_IN) FL15.1 FL16.3(OUT_IN) FL17.3(OUT_IN) FL21.3(OUT_IN) FL22.3(OUT_IN) FL23.3(OUT_IN) FL24.3(OUT_IN) L1.2 R250.1 R251.1 R252.1 R253.1 R254.1 R255.1 R257.1 R258.1 R260.1 R262.1 R263.1 R265.1 R266.1 R268.2 R276.1 R277.1 R279.1 R280.1 R294.1 R295.1 R297.1 R298.1 R299.1 R524.1 R525.1 R712.2 R732.2 R743.1 R750.1 R758.1 R759.1 R762.1 R763.1 R764.1 R765.1 R766.1 R767.1 R768.1 R771.1 R772.1 R818.1 R5703.1 R5730.2 R5771.1 R5851.1 R5852.1 R5853.1 R5854.1 R5855.1 R5856.1 R5857.1 R5858.1 R5898.1 R5902.1 R5903.1 R5904.1 U26.8 U37.29 U37.43 U38.D3 U38.G4 U38.H8 U38.J6 U45.15 U593.7 U593.18 U593.31 U593.42(VCC4) U594.7 U594.18 U594.31 U594.42(VCC4) U595.5 U596.5 U598.5 U626.12(VDDO) U627.12(VDDO)
P1_LINKACT_P: LED6.2 R994.2
P2_LINKACT_P: LED6.4 R995.2
P3_LINKACT_P: LED5.2 R992.2
P4_LINKACT_P: LED5.4 R993.2
PCBVER0: R5770.1 U27.R14
PCBVER1: R5769.1 U27.T14
PCBVER2: R5897.1 U27.M12
PCIE_4X_TCK: R124.1 U55.A5
PCIE_4X_TDI: R125.1 U55.A6
PCIE_4X_TMS: R143.1 U55.A8
PCIE_4X_TRST_B: R146.2 U55.B9
PCIE_REFCLK_N: J3.A14 U32.34
PCIE_REFCLK_P: J3.A13 U32.35
PCIE_X4_CLK_N: U32.29 U55.A14
PCIE_X4_CLK_P: U32.30 U55.A13
PCIEX4_WAKE_B: R206.1 U55.B11(WAKE#)
PCIEX8_WAKE_B: J3.B11(W\A\K\E\) R151.1
PEXBUFCOREV: C309.1 C310.1 C332.1 C334.1 FB23.2 U32.1(VDD_DIG) U32.4 U32.9 U32.37
PEXBUFIOV: C3889.1 C3890.1 C3891.1 C3892.1 FB87.2 U32.15 U32.18 U32.25 U32.28 U32.33 U32.40
PHY0_AVDD18: C5197.1 C5231.1 C5232.1 C5233.1 C5234.1 C5235.1 C5236.1 C5237.1 C5238.1 C5239.1 C5240.1 C5241.1 C5242.1 FB91.2 U42.6 U42.11 U42.17 U42.22 U42.28 U42.33 U42.39 U42.70 U42.75 U42.78 U42.89 U42.94 U42.128
PHY0_AVDD33: C5184.1 C5227.1 C5228.1 C5229.1 C5230.1 FB90.2 U42.1 U42.14 U42.25 U42.38
PHY0_CF0: R5793.2 U42.122
PHY0_CF1: R5794.2 U42.123
PHY0_CF2: R5795.2 U42.124
PHY0_CF3: R5796.2 U42.125
PHY0_CKRN: C5176.1 U42.65
PHY0_CLKSEL0: R5755.2 U42.51
PHY0_CLKSEL1: R5753.2 R5754.1 U42.52
PHY0_HTN: TP224.1(TP) U42.44
PHY0_HTP: TP223.1(TP) U42.45
PHY0_NTRST: TP229.1(TP) U42.62
PHY0_RSET: R5751.1 U42.42
PHY0_TCK: TP225.1(TP) U42.54
PHY0_TDI: TP226.1(TP) U42.58
PHY0_TDO: TP227.1(TP) U42.61
PHY0_TMS: TP228.1(TP) U42.55
PHY0_VDDORL: C5214.1 C5215.1 C5216.1 C5217.1 C5218.1 FB89.2 R5753.1 R5755.1 R5794.1 R5795.1 U42.56 U42.64 U42.83 U42.98 U42.110 U42.117
PHY1_AVDD18: C5185.1 C5186.1 C5187.1 C5188.1 C5189.1 C5190.1 C5191.1 C5192.1 C5193.1 C5194.1 C5195.1 C5196.1 C5258.1 FB97.2 U620.6 U620.11 U620.17 U620.22 U620.28 U620.33 U620.39 U620.70 U620.75 U620.78 U620.89 U620.94 U620.128
PHY1_AVDD33: C5180.1 C5181.1 C5182.1 C5183.1 C5257.1 FB96.2 U620.1 U620.14 U620.25 U620.38
PHY1_CF0: R5797.2 U620.122
PHY1_CF1: R5798.2 U620.123
PHY1_CF2: R5799.2 U620.124
PHY1_CF3: R5800.2 U620.125
PHY1_CKRN: C5253.1 U620.65
PHY1_CLKSEL0: R5803.2 U620.51
PHY1_CLKSEL1: R5802.2 R5804.1 U620.52
PHY1_HTN: TP262.1(TP) U620.44
PHY1_HTP: TP261.1(TP) U620.45
PHY1_NTRST: TP267.1(TP) U620.62
PHY1_RSET: R5805.1 U620.42
PHY1_TCK: TP263.1(TP) U620.54
PHY1_TDI: TP264.1(TP) U620.58
PHY1_TDO: TP265.1(TP) U620.61
PHY1_TMS: TP266.1(TP) U620.55
PHY1_VDDORL: C5178.1 C5179.1 C5198.1 C5199.1 C5200.1 FB98.2 R5798.1 R5799.1 R5802.1 R5803.1 U620.56 U620.64 U620.83 U620.98 U620.110 U620.117
PHY_1V0: FB93.1 FB95.1 FB101.2
PHY_1V8: C5207.1 C5208.1 C5209.1 C5210.2 FB91.1 FB92.1 FB97.1 FB99.1 L56.2 R5766.2
PHY_EMI1_MDC: R744.2 R745.2 U42.82 U620.82
PHY_EMI1_MDIO: R740.2 U22.H13 U42.81 U620.81
PLED_P0WER_ON_GRE: Q12.3 R665.2 SW5.5
PLED_POWER_ON: Q12.1 U27.A5
PLED_STANDBY: Q11.1 U27.B5
PLED_STANDBY_YEL: Q11.3 R666.2 SW5.6
PORT1_TX_DISABLE: R928.1 U624.1
PORT1_TXFAULT: J16.2A R1082.2 U624.10
PORT2_TX_DISABLE: R937.1 U624.2
PORT2_TXFAULT: J16.2B R938.2 U624.11
PORT3_TX_DISABLE: R946.1 U624.3
PORT3_TXFAULT: J16.2C R947.2 U624.12
PORT4_TX_DISABLE: R955.2 U624.4
PORT4_TXFAULT: J16.2D R956.2 U624.13
POVDD: C250.1 C254.1 C255.1 R278.2 R5747.1 U630.8
PROC_IFC_CLK1: TP10.1(TP) U22.H42
PROC_IFC_CLK2: TP22.1(TP) U22.A38
PROC_IFC_NDDDR_CLK: TP11.1(TP) U22.H43
PROC_IFC_NDDQS: TP101.1(TP) U22.E36
PROC_IFC_PAR0: R759.2 U22.E38
PROC_IFC_PAR1: R758.2 U22.D38
PROC_IFC_PAR2: R750.2 U22.F38
PROC_IFC_PAR3: R772.2 U22.F37
PROC_IFC_PERR_B: R771.2 U22.E37
PROG_MTR: R273.1 R714.1 U22.T29
PROG_SFP: C825.1 R270.1 R273.2 R278.1 U22.R29
PS_1V0_EN: TP218.1(TP) U23.3 U27.D13
PS_1V0_PG: U23.6 U27.D14
PS_2V5_EN: TP260.1(TP) U27.C1 U68.3
PS_2V5_PG: U27.B1 U68.6
PS_GVDD_EN: TP215.1(TP) U27.A2 U631.B2
PS_GVDD_PG: TP216.1(TP) U27.D1 U631.A2
PS_ON: Q13.1 R748.1 U27.L14
PS_ON_B: J9.16 Q13.3 R394.1
PS_OVDD_EN: TP217.1(TP) U1.3 U27.D2
PS_OVDD_PG: U1.6 U27.E2
PS_PHY_1V8_EN: TP246.1(TP) U27.D4 U69.3
PS_PHY_1V8_PG: U27.D3 U69.6
PS_POVDD_EN: R5768.1 U27.M5 U630.3
PS_POVDD_PG: U27.N3 U630.5(P\O\K\)
PS_VDD_EN: U3.14 U3.15 U27.B3
PS_VDD_PG: U3.12 U3.13 U27.B2
PS_VTT_EN: U14.7 U17.7 U27.E1
PS_XVDD_EN: TP219.1(TP) U25.3 U27.G5
PS_XVDD_PG: U25.6 U27.F5
QSC_CLK: TP193.1(TP) U27.G16
QSC_SDI: TP194.1(TP) U27.G15
QSC_SDO: TP195.1(TP) U27.H16
QSC_SS: TP192.1(TP) U27.H15
QT2: TP290.1(TP) U27.B16
QT3: TP259.1(TP) U27.T3
R_SD1_RX0_N: R5877.2 U22.D15
R_SD1_RX0_P: R5876.2 U22.C15
R_SD1_RX1_N: R5879.2 U22.B16
R_SD1_RX1_P: R5878.2 U22.A16
R_SD1_RX2_N: R5881.2 U22.D17
R_SD1_RX2_P: R5880.2 U22.C17
R_SD1_RX3_N: R5883.2 U22.B18
R_SD1_RX3_P: R5882.2 U22.A18
R_SD1_RX4_N: C443.1 R532.2 U22.D19
R_SD1_RX4_P: C444.1 R532.1 U22.C19
R_SD1_RX5_N: C445.1 R533.2 U22.B20
R_SD1_RX5_P: C446.1 R533.1 U22.A20
R_SD1_RX6_N: C448.1 R534.2 U22.D21
R_SD1_RX6_P: C447.1 R534.1 U22.C21
R_SD1_RX7_N: C449.1 R535.2 U22.B22
R_SD1_RX7_P: C450.1 R535.1 U22.A22
R_SD2_RX4_N: C451.1 R536.2 U22.D27
R_SD2_RX4_P: C452.1 R536.1 U22.C27
R_SD2_RX5_N: C453.1 R537.2 U22.B28
R_SD2_RX5_P: C454.1 R537.1 U22.A28
R_SD2_RX6_N: C456.1 R538.2 U22.D29
R_SD2_RX6_P: C455.1 R538.1 U22.C29
R_SD2_RX7_N: C457.1 R539.2 U22.B30
R_SD2_RX7_P: C458.1 R539.1 U22.A30
R_SD2_TX0_N: C230.1 U22.J23
R_SD2_TX0_P: C231.1 U22.H23
R_SD2_TX1_N: C228.1 U22.G24
R_SD2_TX1_P: C229.1 U22.F24
R_SD2_TX2_N: C226.1 U22.J25
R_SD2_TX2_P: C227.1 U22.H25
R_SD2_TX3_N: C224.1 U22.G26
R_SD2_TX3_P: C225.1 U22.F26
R_SD4_RX4_N: R5885.2 U22.BA30
R_SD4_RX4_P: R5884.2 U22.BB30
R_SD4_RX5_N: R5887.2 U22.BC31
R_SD4_RX5_P: R5886.2 U22.BD31
R_SD4_RX7_N: R5889.2 U22.BC33
R_SD4_RX7_P: R5888.2 U22.BD33
RST_CLKGEN_B: U27.A3 U36.6
RST_I2CMUX_B: U27.A4 U82.3 U624.22
RST_IFC_B: U27.J1 U37.14
RST_MEM_B: J5.168 J6.168 J7.168 U27.C5
RST_PCIE_X4_B: U27.E5 U55.A11
RST_PCIE_X8_B: J3.A11 R145.1 U27.E6
RST_PHY_1G_B: U27.C3 U42.97 U620.97
RST_SPI_B: U26.7 U27.J2
RT1_2V5: C1109.1 C1110.1 C1111.1 C1112.1 C1113.1 C5302.1 FL25.3(OUT_IN) U65.3 U65.6 U65.7 U65.10 U65.15 U65.46(VDD6)
RT1_ADDR0: R5825.2 R5829.1 U65.45
RT1_ADDR1: R5826.2 R5830.1 U65.40
RT1_ADDR2: R5827.2 R5831.1 U65.21
RT1_ADDR3: R5828.2 R5832.1 U65.16
RT2_2V5: C5303.1 C5304.1 C5305.1 C5306.1 C5307.1 C5308.1 FL26.3(OUT_IN) U622.3 U622.6 U622.7 U622.10 U622.15 U622.46(VDD6)
RT2_ADDR0: R5817.2 R5837.1 U622.45
RT2_ADDR1: R5818.1 R5838.2 U622.40
RT2_ADDR2: R5819.1 R5839.2 U622.21
RT2_ADDR3: R5820.1 R5840.2 U622.16
RTCCLK_DUT: R5722.2 U22.V33
RTCLK: TP115.1(TP) U16.6
RTCTS: TP289.1(TP) U16.8
RTCVSB: C1158.1 R1969.2 U16.1 U16.15
RX1_L0_N: C1209.1 U65.5
RX1_L0_N_DC: C1209.2 J16.12A
RX1_L0_P: C1208.1 U65.4
RX1_L0_P_DC: C1208.2 J16.13A
RX1_LOS: J16.8A R922.2 U624.14
RX2_L0_N: C1212.1 U65.12
RX2_L0_N_DC: C1212.2 J16.12B
RX2_L0_P: C1213.1 U65.11
RX2_L0_P_DC: C1213.2 J16.13B
RX2_LOS: J16.8B R931.2 U624.15
RX3_L0_N: C1217.1 U622.5
RX3_L0_N_DC: C1217.2 J16.12C
RX3_L0_P: C1216.1 U622.4
RX3_L0_P_DC: C1216.2 J16.13C
RX3_LOS: J16.8C R940.2 U624.16
RX4_L0_N: C1220.1 U622.12
RX4_L0_N_DC: C1220.2 J16.12D
RX4_L0_P: C1221.1 U622.11
RX4_L0_P_DC: C1221.2 J16.13D
RX4_LOS: J16.8D R949.2 U624.17
SCANMODE: R764.2 U22.E33
SD1_IMP_CAL_RX: R733.1 U22.M16
SD1_IMP_CAL_TX: R738.1 U22.M22
SD1_PLL1_TPA: TP88.1(TP) U22.M18
SD1_PLL1_TPD: TP91.1(TP) U22.L16
SD1_PLL2_TPA: TP92.1(TP) U22.M20
SD1_PLL2_TPD: TP95.1(TP) U22.L22
SD1_REF_CLK2_N: R5891.1 U22.N21
SD1_REF_CLK2_P: R5890.1 U22.P21
SD1_REFCLK1_N: U22.P19 U32.13
SD1_REFCLK1_P: U22.P18 U32.14
SD1_RX4_N: C443.2 U42.92
SD1_RX4_P: C444.2 U42.93
SD1_RX5_N: C445.2 U42.91
SD1_RX5_P: C446.2 U42.90
SD1_RX6_N: C448.2 U42.73
SD1_RX6_P: C447.2 U42.74
SD1_RX7_N: C449.2 U42.72
SD1_RX7_P: C450.2 U42.71
SD1_TX4_N: U22.J19 U42.95
SD1_TX4_P: U22.H19 U42.96
SD1_TX5_N: U22.G20 U42.88
SD1_TX5_P: U22.F20 U42.87
SD1_TX6_N: U22.J21 U42.76
SD1_TX6_P: U22.H21 U42.77
SD1_TX7_N: U22.G22 U42.69
SD1_TX7_P: U22.F22 U42.68
SD2_IMP_CAL_RX: R727.1 U22.M23
SD2_IMP_CAL_TX: R737.1 U22.M29
SD2_PLL1_TPA: TP94.1(TP) U22.M25
SD2_PLL1_TPD: TP93.1(TP) U22.L23
SD2_PLL2_TPA: TP89.1(TP) U22.M27
SD2_PLL2_TPD: TP97.1(TP) U22.L29
SD2_REFCLK1_N: C3882.2 U22.N24
SD2_REFCLK1_P: C3881.2 U22.P24
SD2_REFCLK2_N: R730.1 U22.P26 U32.16
SD2_REFCLK2_P: R731.1 U22.P27 U32.17
SD2_RX0_N: C1033.2 U22.D23
SD2_RX0_P: C1032.2 U22.C23
SD2_RX1_N: C1034.2 U22.B24
SD2_RX1_P: C1031.2 U22.A24
SD2_RX2_N: C1036.1 U22.D25
SD2_RX2_P: C1035.1 U22.C25
SD2_RX3_N: C1038.1 U22.B26
SD2_RX3_P: C1037.1 U22.A26
SD2_RX4_N: C451.2 U620.92
SD2_RX4_P: C452.2 U620.93
SD2_RX5_N: C453.2 U620.91
SD2_RX5_P: C454.2 U620.90
SD2_RX6_N: C456.2 U620.73
SD2_RX6_P: C455.2 U620.74
SD2_RX7_N: C457.2 U620.72
SD2_RX7_P: C458.2 U620.71
SD2_TX0_N: C230.2 U65.2
SD2_TX0_P: C231.2 U65.1
SD2_TX1_N: C228.2 U65.9
SD2_TX1_P: C229.2 U65.8
SD2_TX2_N: C226.2 U622.2
SD2_TX2_P: C227.2 U622.1
SD2_TX3_N: C224.2 U622.9
SD2_TX3_P: C225.2 U622.8
SD2_TX4_N: U22.J27 U620.95
SD2_TX4_P: U22.H27 U620.96
SD2_TX5_N: U22.G28 U620.88
SD2_TX5_P: U22.F28 U620.87
SD2_TX6_N: U22.J29 U620.76
SD2_TX6_P: U22.H29 U620.77
SD2_TX7_N: U22.G30 U620.69
SD2_TX7_P: U22.F30 U620.68
SD3_IMP_CAL_RX: R694.1 U22.AN19
SD3_IMP_CAL_TX: R693.1 U22.AN25
SD3_PLL1_TPA: TP76.1(TP) U22.AN21
SD3_PLL1_TPD: TP75.1(TP) U22.AP19
SD3_PLL2_TPA: TP77.1(TP) U22.AN23
SD3_PLL2_TPD: TP79.1(TP) U22.AP25
SD3_REFCLK1_N: U22.AL22 U32.21
SD3_REFCLK1_P: U22.AL21 U32.22
SD3_REFCLK2_N: R700.1 U22.AM24
SD3_REFCLK2_P: R701.1 U22.AL24
SD3_RX0_N: J3.A17 U22.BA18
SD3_RX0_P: J3.A16 U22.BB18
SD3_RX1_N: J3.A22 U22.BC19
SD3_RX1_P: J3.A21 U22.BD19
SD3_RX2_N: J3.A26 U22.BA20
SD3_RX2_P: J3.A25 U22.BB20
SD3_RX3_N: J3.A30 U22.BC21
SD3_RX3_P: J3.A29 U22.BD21
SD3_RX4_N: J3.A36 U22.BA22
SD3_RX4_P: J3.A35 U22.BB22
SD3_RX5_N: J3.A40 U22.BC23
SD3_RX5_P: J3.A39 U22.BD23
SD3_RX6_N: J3.A44 U22.BA24
SD3_RX6_P: J3.A43 U22.BB24
SD3_RX7_N: J3.A48 U22.BC25
SD3_RX7_P: J3.A47 U22.BD25
SD3_TX0_N: C78.1 U22.AT18
SD3_TX0_P: C76.1 U22.AU18
SD3_TX1_N: C80.1 U22.AV19
SD3_TX1_P: C79.1 U22.AW19
SD3_TX2_N: C82.1 U22.AT20
SD3_TX2_P: C81.1 U22.AU20
SD3_TX3_N: C90.1 U22.AV21
SD3_TX3_P: C88.1 U22.AW21
SD3_TX4_N: C96.1 U22.AT22
SD3_TX4_P: C95.1 U22.AU22
SD3_TX5_N: C108.1 U22.AV23
SD3_TX5_P: C103.1 U22.AW23
SD3_TX6_N: C126.1 U22.AT24
SD3_TX6_P: C118.1 U22.AU24
SD3_TX7_N: C149.1 U22.AV25
SD3_TX7_P: C147.1 U22.AW25
SD3_TXC0_N: C78.2 J3.B15
SD3_TXC0_P: C76.2 J3.B14
SD3_TXC1_N: C80.2 J3.B20
SD3_TXC1_P: C79.2 J3.B19
SD3_TXC2_N: C82.2 J3.B24
SD3_TXC2_P: C81.2 J3.B23
SD3_TXC3_N: C90.2 J3.B28
SD3_TXC3_P: C88.2 J3.B27
SD3_TXC4_N: C96.2 J3.B34
SD3_TXC4_P: C95.2 J3.B33
SD3_TXC5_N: C108.2 J3.B38
SD3_TXC5_P: C103.2 J3.B37
SD3_TXC6_N: C126.2 J3.B42
SD3_TXC6_P: C118.2 J3.B41
SD3_TXC7_N: C149.2 J3.B46
SD3_TXC7_P: C147.2 J3.B45
SD4_IMP_CAL_RX: R697.1 U22.AN26
SD4_IMP_CAL_TX: R695.1 U22.AN32
SD4_PLL1_TPA: TP80.1(TP) U22.AN28
SD4_PLL1_TPD: TP73.1(TP) U22.AP26
SD4_PLL2_TPA: TP81.1(TP) U22.AN30
SD4_PLL2_TPD: TP74.1(TP) U22.AP32
SD4_REFCLK1_N: U22.AM27 U32.23
SD4_REFCLK1_P: U22.AL27 U32.24
SD4_REFCLK2_N: U22.AL29 U32.26
SD4_REFCLK2_P: U22.AL30 U32.27
SD4_RX0_N: U22.BA26 U55.A17
SD4_RX0_P: U22.BB26 U55.A16
SD4_RX1_N: U22.BC27 U55.A22
SD4_RX1_P: U22.BD27 U55.A21
SD4_RX2_N: U22.BA28 U55.A26
SD4_RX2_P: U22.BB28 U55.A25
SD4_RX3_N: U22.BC29 U55.A30
SD4_RX3_P: U22.BD29 U55.A29
SD4_RX6_N: C402.1 U22.BA32
SD4_RX6_P: C406.1 U22.BB32
SD4_RXC6_N: C406.2 J10.5
SD4_RXC6_P: C402.2 J10.6
SD4_TX0_N: C482.1 U22.AT26
SD4_TX0_P: C481.1 U22.AU26
SD4_TX1_N: C997.1 U22.AV27
SD4_TX1_P: C996.1 U22.AW27
SD4_TX2_N: C999.1 U22.AT28
SD4_TX2_P: C998.1 U22.AU28
SD4_TX3_N: C1001.1 U22.AV29
SD4_TX3_P: C1000.1 U22.AW29
SD4_TX6_N: C422.1 U22.AT32
SD4_TX6_P: C425.1 U22.AU32
SD4_TXC0_N: C482.2 U55.B15
SD4_TXC0_P: C481.2 U55.B14
SD4_TXC1_N: C997.2 U55.B20
SD4_TXC1_P: C996.2 U55.B19
SD4_TXC2_N: C999.2 U55.B24
SD4_TXC2_P: C998.2 U55.B23
SD4_TXC3_N: C1001.2 U55.B28
SD4_TXC3_P: C1000.2 U55.B27
SD4_TXC6_N: C422.2 J10.3
SD4_TXC6_P: C425.2 J10.2(TXP)
SD_CD#: CN3.10 ESD10.1 R637.2
SD_WP: CN3.11(WP) ESD9.1 R667.2
SDCK: C485.1 CN3.5 R614.2
SDHC_CD_B: R637.1 R5851.2 U22.A34 U22.N13
SDHC_CLK: R301.2 U45.5
SDHC_CMD: R743.2 U22.D33 U45.16
SDHC_DAT0: U22.B34 U45.3
SDHC_DAT1: U22.C34 U45.4
SDHC_DAT2: U22.A35 U45.1
SDHC_DAT3: U22.B35 U45.2
SDHC_WP: R667.1 R5852.2 U22.C33 U22.P13
SDP1_CLKF: TP72.1(TP) U45.6
SENSEGND_CA_S_N: R716.1 U22.R13
SENSEGND_CB_S_N: R696.1 U22.AM17
SENSEGND_CC_S_N: R707.1 U22.AA33
SENSEGND_PL_S_N: R706.1 U22.AA32
SENSEVDD_CA_S_P: R725.1 U22.R12
SENSEVDD_CB_S_P: R699.1 U22.AM16
SENSEVDD_CC_S_P: R710.1 U22.Y33
SENSEVDD_PL_S_P: R709.1 U22.Y32
SER1_CTS_B: R1055.1 U46.1
SER1_CTS_B_T: C1226.1 ESD3.1 LAN1.8_T R1055.2
SER1_GND: C1224.2 C1225.2 C1226.2 C1227.2 ESD1.2(A2) ESD2.2(A2) ESD3.2(A2) ESD4.2(A2) LAN1.4_T R816.2
SER1_RTS_B: R1052.1 U46.4
SER1_RTS_B_T: C1224.1 ESD1.1 LAN1.1_T R1052.2
SER1_RXD: R1054.1 U46.2
SER1_RXD_T: C1227.1 ESD4.1 LAN1.6_T R1054.2
SER1_TXD: R1053.1 U46.3
SER1_TXD_T: C1225.1 ESD2.1 LAN1.3_T R1053.2
SER2_CTS_B: R1059.1 U95.1
SER2_CTS_B_T: C1232.1 ESD8.1 LAN1.8_B R1059.2
SER2_GND: C1229.2 C1230.2 C1231.2 C1232.2 ESD5.2(A2) ESD6.2(A2) ESD7.2(A2) ESD8.2(A2) LAN1.4_B R817.2
SER2_RTS_B: R1056.1 U95.4
SER2_RTS_B_T: C1229.1 ESD5.1 LAN1.1_B R1056.2
SER2_RXD: R1058.1 U95.2
SER2_RXD_T: C1231.1 ESD7.1 LAN1.6_B R1058.2
SER2_TXD: R1057.1 U95.3
SER2_TXD_T: C1230.1 ESD6.1 LAN1.3_B R1057.2
SI5341_A0CS: R5711.1 U36.19
SI5341_A1SDO: R5710.1 U36.17
SI5341_FDEC: TP209.1(TP) U36.25
SI5341_FINC: TP208.1(TP) U36.48
SI5341_I2CSEL: R5704.2 U36.39
SI5341_INSEL0: R5706.2 U36.3
SI5341_INSEL1: R5705.2 U36.4
SI5341_LOL_B: TP214.1(TP) U36.47
SI5341_OE_B: R5712.1 U36.11
SI5341_SYNC_B: TP210.1(TP) U36.5
SI5341_VDD: C3859.1 C3860.1 C3861.1 C3862.1 FL15.3(OUT_IN) U36.32 U36.46 U36.60
SI5341_VDDA: C3866.1 FL20.3(OUT_IN) U36.13
SLOT6_TCK: J3.A5 R119.1
SLOT6_TDI: J3.A6 R120.1
SLOT6_TMS: J3.A8 R128.1
SLOT6_TRST_B: J3.B9 R142.2
SP1_MODA: J16.6A R925.2
SP1_RS0: J16.9A R923.1 R926.2
SP1_RS1: J16.7A R924.1 R927.2
SP1_TXDIS: J16.3A R928.2 R930.2
SP2_MODA: J16.6B R934.2
SP2_RS0: J16.9B R932.1 R935.2
SP2_RS1: J16.7B R933.1 R936.2
SP2_TXDIS: J16.3B R937.2 R939.2
SP3_MODA: J16.6C R943.2
SP3_RS0: J16.9C R941.1 R944.2
SP3_RS1: J16.7C R942.1 R945.2
SP3_TXDIS: J16.3C R946.2 R948.2
SP4_MODA: J16.6D R952.2
SP4_RS0: J16.9D R951.1 R954.2
SP4_RS1: J16.7D R950.1 R953.2
SP4_TXDIS: J16.3D R955.1 R957.2
SPI_CE_B: R318.1 U26.1
SPI_CLK: R296.1 R310.1 U26.6
SPI_CS0_B: R318.2 U22.C35
SPI_CS1_B: TP19.1(TP) U22.A36
SPI_CS2_B: TP103.1(TP) U22.C36
SPI_CS3_B: TP18.1(TP) U22.D36
SPI_MISO: R298.2 U22.C37 U26.2
SPI_MOSI: R297.2 U22.A37 U26.5
SPI_WP_B: R299.2 U26.3(W\P\)
SW1_1: R5772.2 SW1.8 U610.4
SW1_2: R5773.2 SW1.7 U610.5
SW1_3: R5774.2 SW1.6 U610.6
SW1_4: R5775.2 SW1.5(B4) U610.7
SW1_5: R5776.2 SW2.8 U610.8
SW1_6: R5777.2 SW2.7 U610.9
SW1_7: R5778.2 SW2.6 U610.10
SW1_8: R5779.2 SW2.5(B4) U610.11
SW2_1: R5780.2 SW3.8 U610.13
SW2_2: R5781.2 SW3.7 U610.14
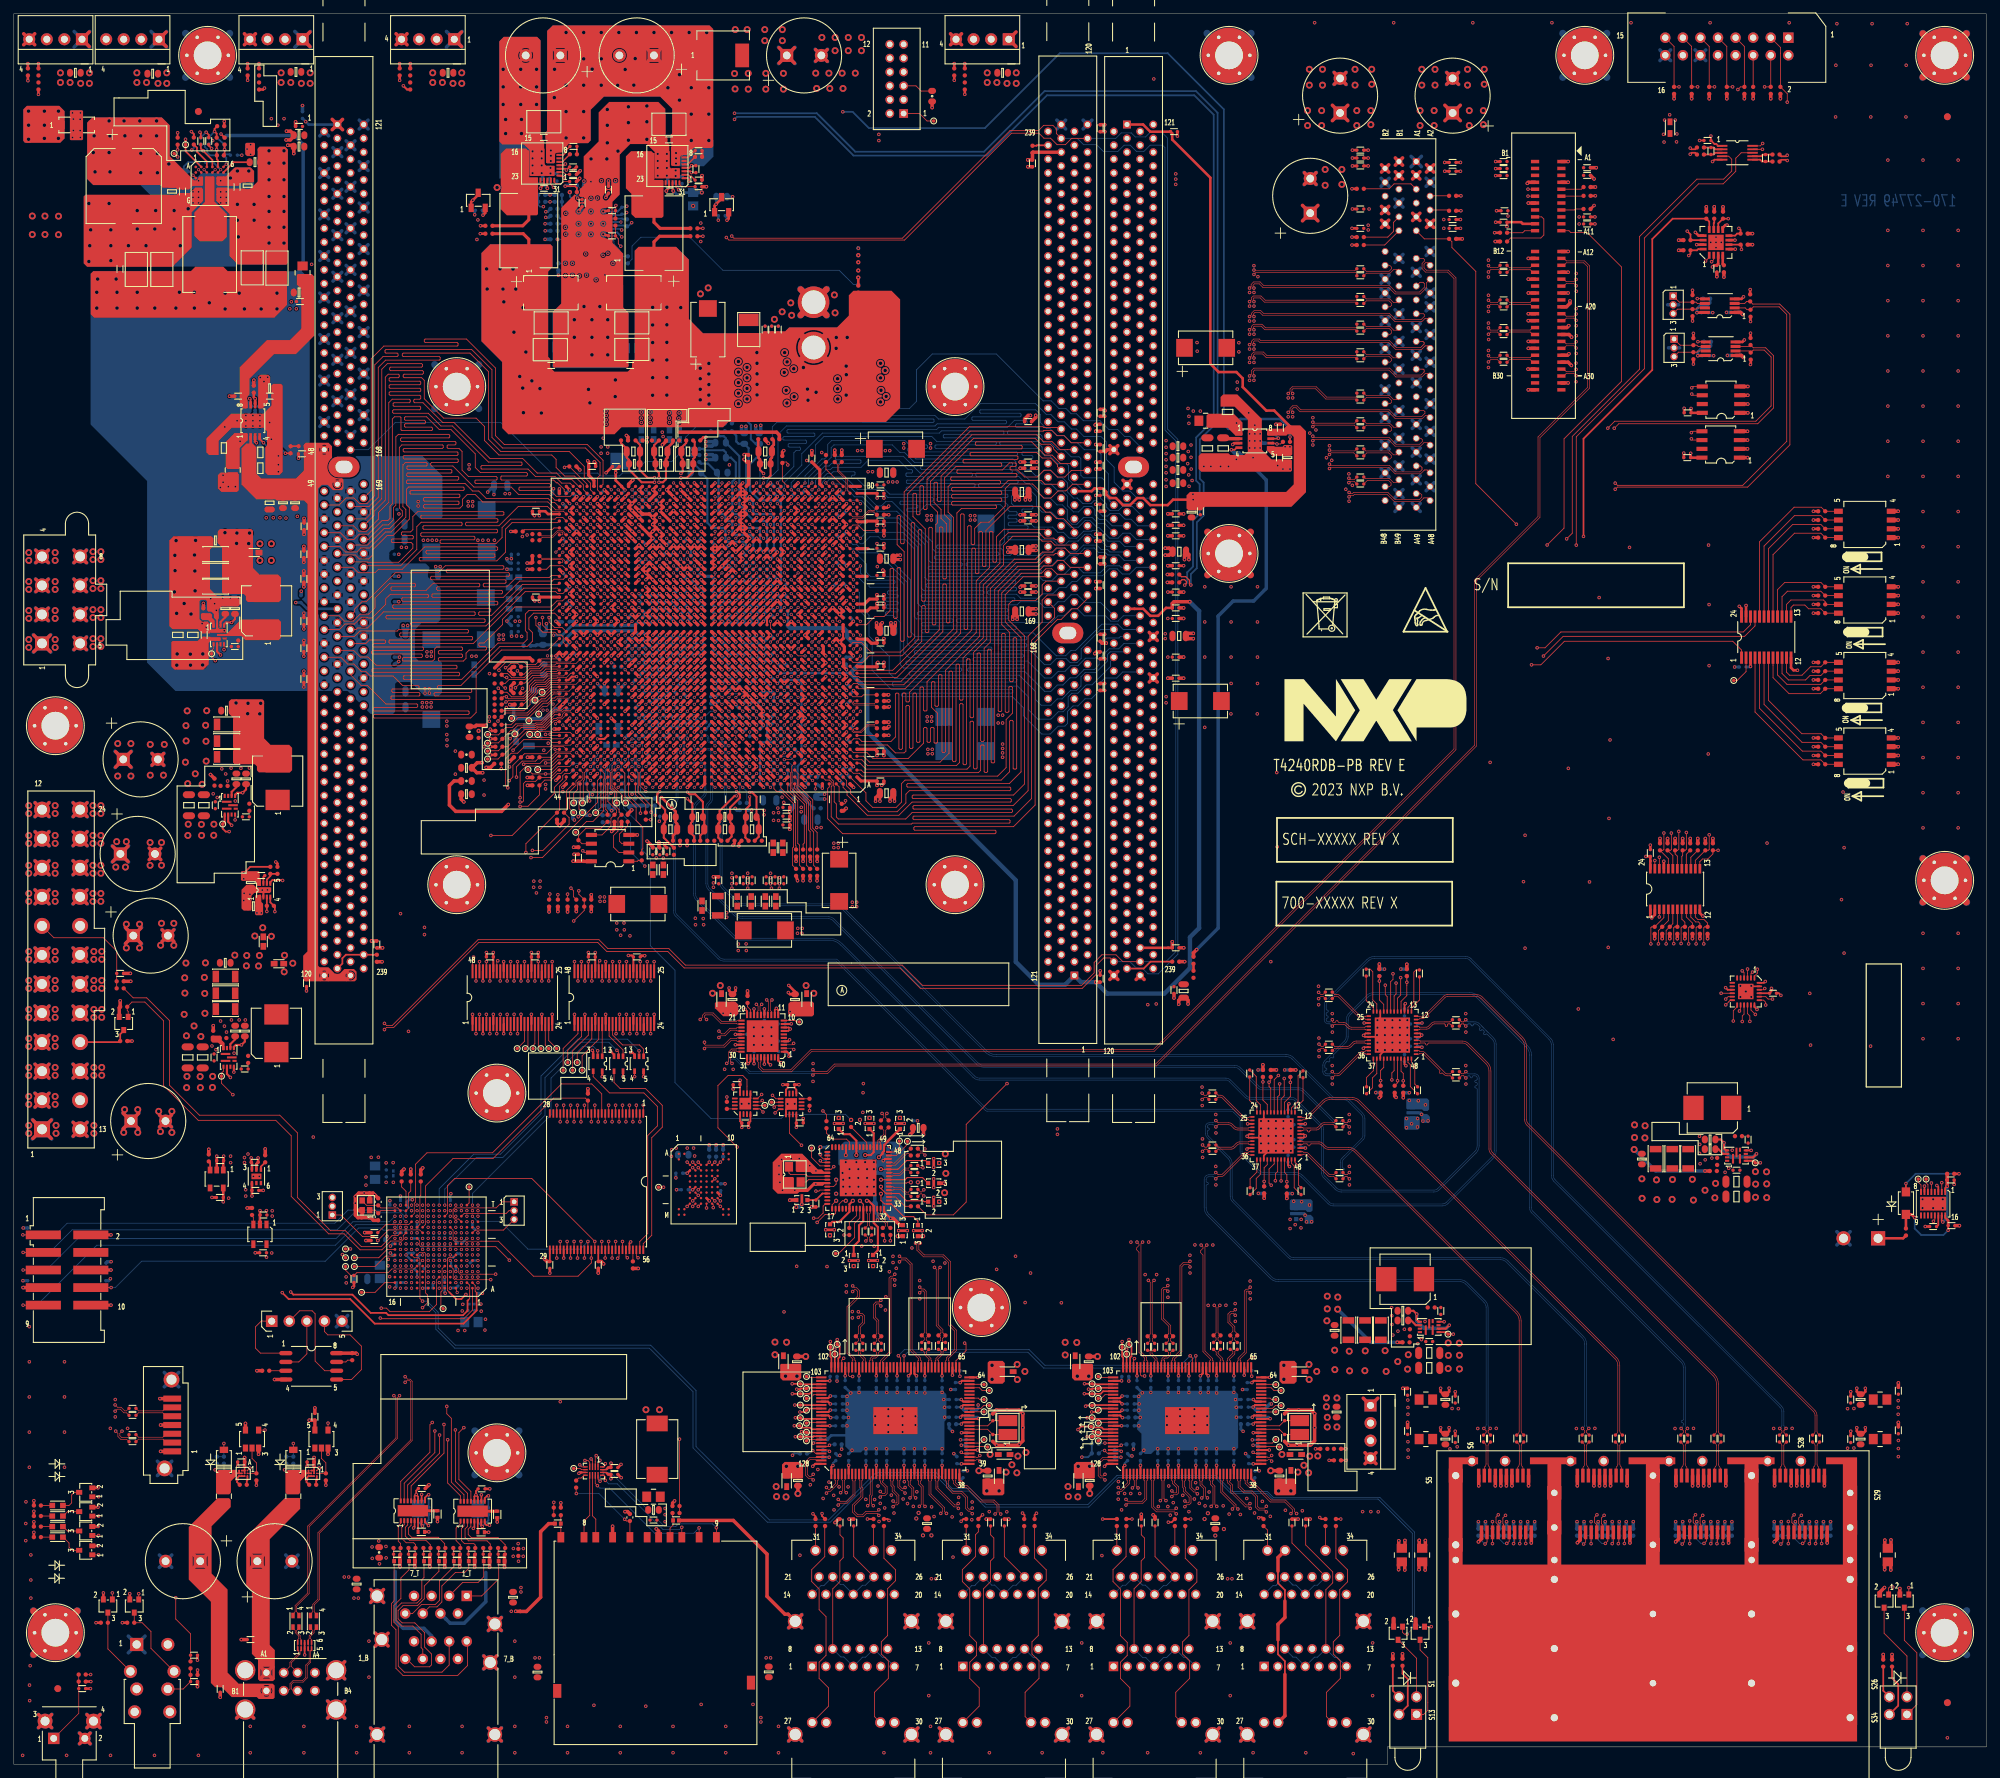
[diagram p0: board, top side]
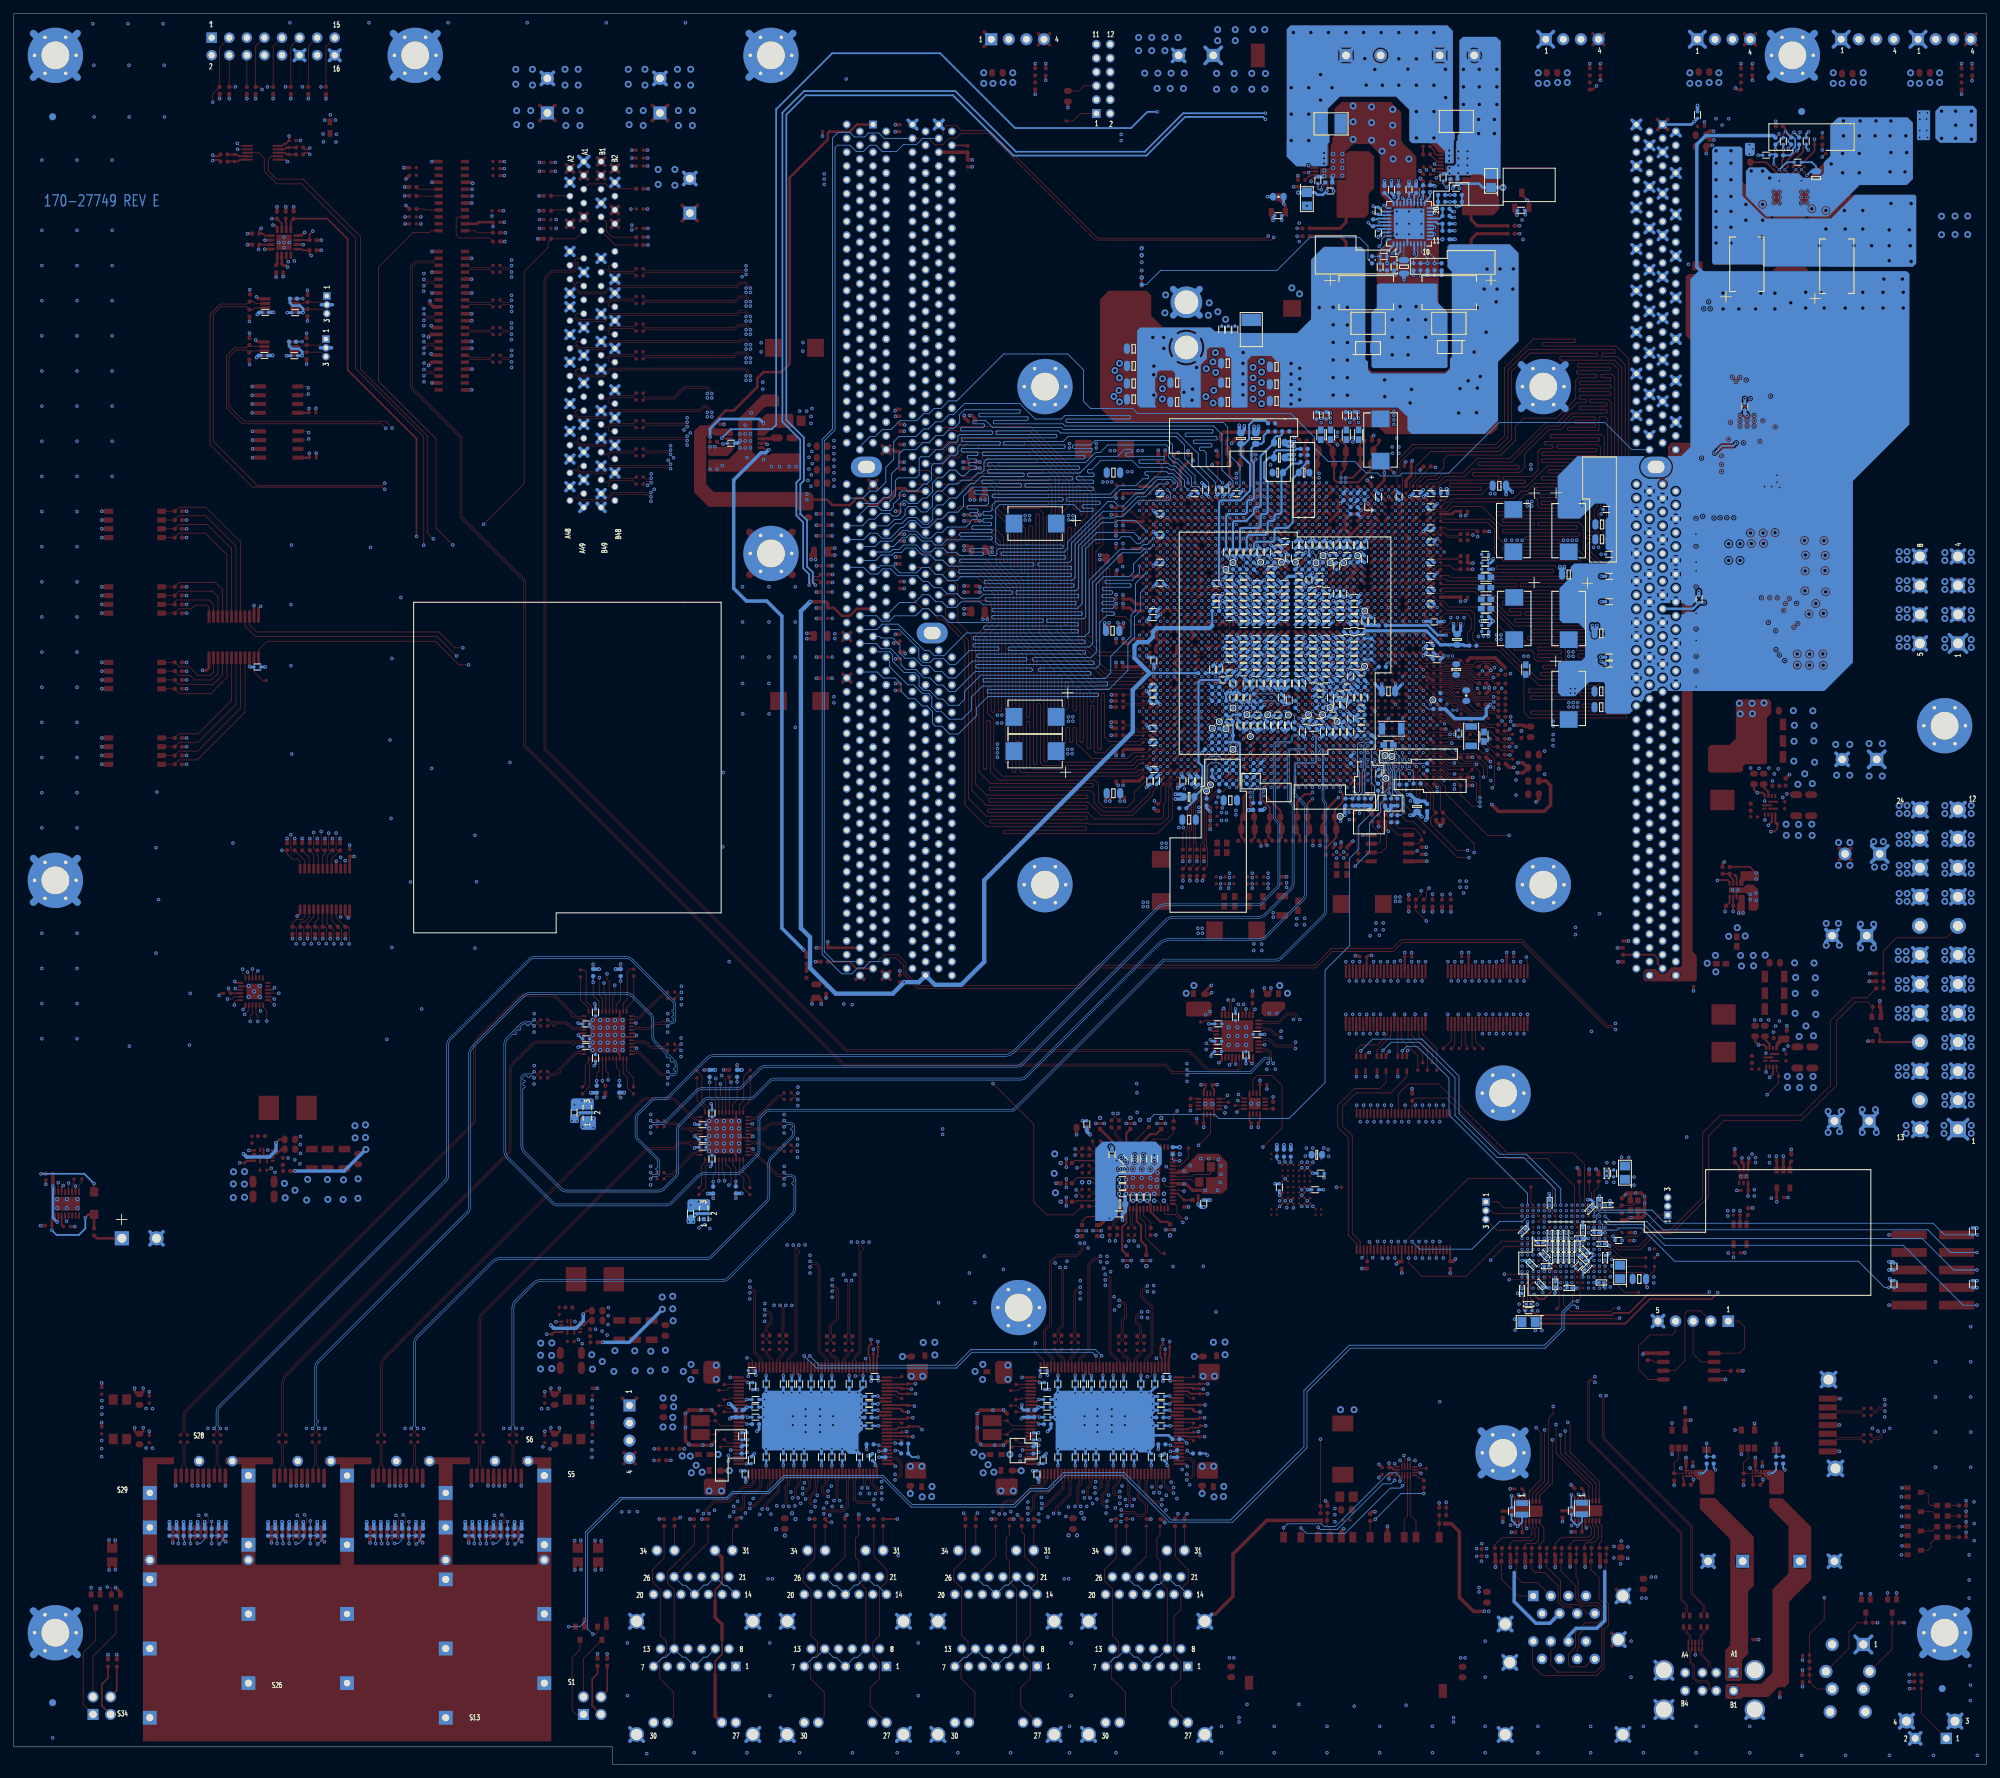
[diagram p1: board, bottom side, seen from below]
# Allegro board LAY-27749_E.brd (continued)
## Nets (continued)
SW2_3: R5782.2 SW3.6 U610.15
SW2_4: R5783.2 SW3.5(B4) U610.16
SW2_5: R5784.2 SW4.8 U610.17
SW2_6: R5785.2 SW4.7 U610.18
SW2_7: R5786.2 SW4.6 U610.19
SW2_8: R5787.2 SW4.5(B4) U610.20
SW_PWR_B: C520.1 R670.1 U27.F3
SW_PWR_OUT: C523.1 R670.2 R672.2 SW5.4
SW_RST_B: R669.2 U27.L3
SWS_CLK: U27.G3 U610.22
SWS_CS_B: U27.E4 U610.21
SWS_IRQ_B: TP249.1(TP) U610.2
SWS_MISO: U27.G2 U610.1
SYSCLK: R711.1 R5895.2
TEMP_ANODE1_ADT: C9.1 R30.1 U2.2
TEMP_ANODE2_ADT: C12.1 R36.1 U2.7
TEMP_CATHODE1_ADT: C9.2 R35.1 U2.3
TEMP_CATHODE2_ADT: C12.2 R51.1 U2.6
TEMP_DIODE1_N: R35.2 U22.Y34
TEMP_DIODE1_P: R30.2 U22.AA34
TEMP_DIODE2_N: R51.2 U22.AL17
TEMP_DIODE2_P: R36.2 U22.AL16
TH_TPA: TP84.1(TP) U22.W32
THERM_FAULT_B: U2.4 U27.M13
THERM_WARN_B: U2.8 U27.M16
TSEC_1588_ALARM1_S: TP99.1(TP) U22.K13
TSEC_1588_ALARM2_S: TP98.1(TP) U22.J12
TSEC_1588_CLK_IN: R757.2 U22.A14
TSEC_1588_CLKOUT_S: TP100.1(TP) U22.F14
TSEC_1588_PULSE1_S: TP90.1(TP) U22.M14
TSEC_1588_PULSE2_S: TP96.1(TP) U22.L13
TSEC_1588_TRIG_IN1: R735.2 U22.N15
TSEC_1588_TRIG_IN2: R734.2 U22.N14
TX1_L0_N: C1211.1 U65.35
TX1_L0_N_DC: C1211.2 J16.19A
TX1_L0_P: C1210.1 U65.36
TX1_L0_P_DC: C1210.2 J16.18A
TX2_L0_N: C1215.1 U65.28
TX2_L0_N_DC: C1215.2 J16.19B
TX2_L0_P: C1214.1 U65.29
TX2_L0_P_DC: C1214.2 J16.18B
TX3_L0_N: C1219.1 U622.35
TX3_L0_N_DC: C1219.2 J16.19C
TX3_L0_P: C1218.1 U622.36
TX3_L0_P_DC: C1218.2 J16.18C
TX4_L0_N: C1223.1 U622.28
TX4_L0_N_DC: C1223.2 J16.19D
TX4_L0_P: C1222.1 U622.29
TX4_L0_P_DC: C1222.2 J16.18D
UART1_SW: C3893.2 L52.2 U46.7
UART2_SW: C3896.2 L53.2 U95.7
USB1_DN: L23.1 U22.J31
USB1_DP: L23.4 U22.K31
USB1_ID: R736.1 U22.L32
USB1_ILIM: R5725.1 U48.A3
USB1_ISON: CN4.B2 L23.2 U608.4 U608.7
USB1_ISOP: CN4.B3 L23.3 U608.5 U608.6
USB1_ISOPWR: C518.1 C5342.1 CN4.B1(VBUS_B) L26.2
USB1_PWREN: U22.E32 U48.A1
USB1_PWRFAULT: U22.F32 U629.4(Y)
USB1_PWRFLT_B: R661.2 U48.A2 U629.2
USB1_VBUSCLMP: D9.A R659.1 R662.2 U22.G32
USB2_DN: L24.1 U22.M31
USB2_DP: L24.4 U22.N31
USB2_ID: R741.1 U22.H32
USB2_ILIM: R508.1 U47.A3
USB2_ISON: CN4.A2 L24.2 U608.1 U608.10(NC4)
USB2_ISOP: CN4.A3 L24.3 U608.2 U608.9
USB2_ISOPWR: C519.1 C5341.1 CN4.A1 L27.2
USB2_PWREN: U22.A32 U47.A1
USB2_PWRFAULT: U22.B32 U628.4(Y)
USB2_PWRFLT_B: R660.2 U47.A2 U628.2
USB2_VBUSCLMP: D10.A R663.1 R664.2 U22.C32
USB_BIAS: R747.1 U22.D31
USB_HVDD: C840.1 C847.1 C859.1 C860.1 FB56.1 U22.K32 U22.N32
USB_OVDD: C833.1 C834.1 C867.1 C868.1 FB55.1 U22.P31 U22.P32
USB_SVDD: C280.1 C288.1 C837.1 C838.1 FB20.1 U22.P29 U22.P30
UT_SDHCCLK: R301.1 U22.A33
UT_SPICLK: R296.2 U22.B37
UTCKO: TP5.1(TP) U22.N44
UTEMI1_MDC: R745.1 U22.G13
VBBS: C5334.1 U16.14
VTT_A_SENSE: R5734.1 R5905.2
VTT_B_SENSE: R5735.1 R5906.2
X1_GND: U36.7 U36.10 Y7.2 Y7.4
XA_SI5341B: U36.8 Y7.1
XB_SI5341B: U36.9(XB) Y7.3
XFCFG_CLKO: U65.42 U622.19
XFCFG_ENSMB: R5815.2 U65.20 U622.20
XFCFG_READEN: R5816.1 U65.44 U622.44
XIFC_A26: TP253.1(TP) U594.16
XIFC_A27: TP254.1(TP) U594.17
XIFC_A28: TP255.1(TP) U594.19
XIFC_A29: TP256.1(TP) U594.20
XIFC_A30: TP257.1(TP) U594.22
XIFC_A31: TP252.1(TP) U594.23
XRT_CP0: C5316.1 U65.47
XRT_CP1: C5317.1 U65.38
XRT_CP2: C5318.1 U65.23
XRT_CP3: C5319.1 U65.14
XRT_CP4: C5312.1 U622.47
XRT_CP5: C5313.1 U622.38
XRT_CP6: C5314.1 U622.23
XRT_CP7: C5315.1 U622.14
XRT_REF0: C5316.2 U65.48
XRT_REF1: C5317.2 U65.37
XRT_REF2: C5318.2 U65.24
XRT_REF3: C5319.2 U65.13
XRT_REF4: C5312.2 U622.48
XRT_REF5: C5313.2 U622.37
XRT_REF6: C5314.2 U622.24
XRT_REF7: C5315.2 U622.13
XRX1_DOUTN: C1033.1 U65.32
XRX1_DOUTP: C1032.1 U65.33
XRX2_DOUTN: C1034.1 U65.25
XRX2_DOUTP: C1031.1 U65.26
XRX3_DOUTN: C1036.2 U622.32
XRX3_DOUTP: C1035.2 U622.33
XRX4_DOUTN: C1038.2 U622.25
XRX4_DOUTP: C1037.2 U622.26
XVDD: C5164.1 C5165.1 C5166.1 C5167.2 CT30.1 CT40.1 FB9.2 FB10.2 FB11.2 FB12.2 FB47.2 FB48.2 FB49.2 FB50.2 L55.2 R175.2 R178.2 R179.2 R182.2 R313.2 R314.2 R317.2 R319.2 R5894.1
Z4901: LED4.A R341.2
Z4902: LED3.A R335.2
Z4903: LED2.A R333.2
Z4904: LED1.A R332.2
Z5402: FB1.2 R67.2 R68.2 R69.2 R70.2 R71.2 R72.1 R73.2 R74.2
N16616368: C83.1 C89.2 C5259.1 FB86.1 U14.8
N16862198: R768.2 TP205.1(TP) U22.E35
N18838531: C94.1 R43.1 U3.4
N18839314: C87.2 R44.2
N18839320: C87.1 U9.7
N18839399: C5271.1 R55.2
N18839410: C5272.2 R56.1
N18839524: R77.1 U7.5
N18839526: C124.2 R77.2
N18839532: C124.1 U7.7
N20471515: J11.27 R641.2
N20471595: J11.29 R643.2
N30740588: TP196.1(TP) U27.E7
N30741197: C3697.2 C3698.2 U27.F11
N30744842: R5588.2 U250.7
N30744844: R5589.2 U250.3(WPE#)
N30954766: R5703.2 U37.53
N31081508: TP212.1(TP) U32.10
N31116021: R5721.1 U32.19
N31148954: C3894.1 U46.6
N31148956: C3895.1 U46.17
N31149103: C3897.1 U95.6
N31149105: C3898.1 U95.17
N31714319: C1.2 U1.4 U1.9
N31714350: C2.1 U1.7
N31714354: C2.2 R1.1
N31714416: L1.1 R1.2 U1.8
N31714501: R5730.1 R5731.1 U1.12
N31714572: C10.1 U1.10
N31717308: C5140.1 FB81.2 R5788.1 U17.1
N31718323: C5142.1 FB84.2 R5789.1 U14.1
N31722569: C5141.2 R5788.2 U17.6
N31724252: C5143.2 R5789.2 U14.6
N31726596: R5734.2 U17.4(VTTSEN)
N31727679: R5735.2 U14.4(VTTSEN)
N31789752: C5150.2 U23.4 U23.9
N31789783: C5149.1 U23.7
N31789787: C5149.2 R5736.1
N31789873: L54.1 R5736.2 U23.8
N31789971: R5737.1 R5739.1 U23.12
N31790039: C5158.1 U23.10
N31884769: C5160.2 U25.4 U25.9
N31884800: C5159.1 U25.7
N31884804: C5159.2 R5740.1
N31884868: L55.1 R5740.2 U25.8
N31884952: R5893.1 R5894.2 U25.12
N31885020: C5168.1 U25.10
N31888256: C5244.2 U68.4 U68.9
N31888261: C5243.1 U68.7
N31888263: C5243.2 R5801.1
N31888274: L57.1 R5801.2 U68.8
N31888295: R2.2 R3.1 U68.12
N31888301: C5249.1 U68.10
N32062690: J11.33 R644.2
N32062836: J11.31 R642.2
N32065877: J12.31 R646.2
N32065910: J12.33 R648.2
N32070236: J13.31 R650.2
N32070242: J13.33 R652.2
N32070301: J13.27 R649.2
N32070307: J13.29 R651.2
N32070366: J14.31 R654.2
N32070372: J14.33 R656.2
N32070429: J14.29 R655.2
N32074017: J12.29 R647.2
N32074023: J12.27 R645.2
N32074313: C5174.2 U42.49 Y20.1
N32074325: C5175.2 U42.50(XTAL_OUT) Y20.2
N32105138: C472.1 C5219.1 C5220.1 C5221.1 C5222.1 C5223.1 C5224.1 C5225.1 C5226.1 FB93.2 U42.53 U42.57 U42.63 U42.79 U42.86 U42.104 U42.109 U42.113
N32110539: R5791.2 U42.114
N32112200: C5213.1 FB92.2 U42.43 U42.48
N32113835: TP233.1(TP) U42.103
N32113861: TP234.1(TP) U42.108
N32113887: TP238.1(TP) U42.116
N32114066: TP242.1(TP) U42.121
N32114156: C5254.2 U620.49 Y21.1
N32114159: C5255.2 U620.50(XTAL_OUT) Y21.2
N32114233: C924.1 C932.1 C936.1 C940.1 C944.1 C947.1 C950.1 C961.1 C5256.1 FB95.2 U620.53 U620.57 U620.63 U620.79 U620.86 U620.104 U620.109 U620.113
N32114429: R5792.2 U620.114
N32114439: C5201.1 FB99.2 U620.43 U620.48
N32114457: TP280.1(TP) U620.103
N32114465: TP276.1(TP) U620.108
N32114473: TP272.1(TP) U620.116
N32114475: TP268.1(TP) U620.121
N32122553: C254.2 U630.7
N32122566: R5747.2 R5748.1 U630.6
N32123048: C5203.2 U69.4 U69.9
N32123083: C5202.1 U69.7
N32123087: C5202.2 R5763.1
N32123169: L56.1 R5763.2 U69.8
N32123255: R5766.1 R5767.1 U69.12
N32123323: C5211.1 U69.10
N32124491: JP8.1 U27.N4
N32124494: JP8.2 U27.P4
N33496283: R44.1 U9.5
N33510179: R40.2 U9.31
N33510235: R41.2 U9.2(Z\C\D\_\E\N\)
N33521269: R5812.2 U7.31
N33521274: R5811.2 U7.2(Z\C\D\_\E\N\)
N33883272: C5294.1 J11.4 J11.7 J11.9 J11.12
N33883466: C5295.1 J11.14 J11.17 J11.22 J11.25
N33883565: C5296.1 J12.4 J12.7 J12.9 J12.12
N33883665: C5297.1 J12.14 J12.17 J12.22 J12.25
N33884495: C5298.1 J13.4 J13.7 J13.9 J13.12
N33884597: C5299.1 J13.14 J13.17 J13.22 J13.25
N33884700: C5300.1 J14.4 J14.7 J14.9 J14.12
N33884804: C5301.1 J14.14 J14.17 J14.22 J14.25
N34046443: JP8.3 U27.L2
N34055964: J106.1 TP286.1(TP)
N34055974: J106.5 R42.2
N34216244: R5895.1 U626.16
N34216367: TP287.1(TP) U626.6
N34216393: TP288.1(TP) U627.6
N34216534: R5896.1 U627.16
N34325441: C3847.1 D46.C R5907.1 U16.16
N37212649: C5345.1 R5907.2
N311488790: C3893.1 U46.9
N311490280: C3896.1 U95.9

Pads without a net: C5311 2; FAN12 3 4; J2 2 5 8 10 14; J3 A7 A19 A32 A33 B12 B17 B30 B31 B48; J5 167 187; J6 167 187; J7 167 187; J9 14 20; J105 4; J106 6 7 8 9 11 12; LAN1 2_B 2_T 5_B 5_T 7_B 7_T; SW5 2 3 MH1 MH2; U1 5; U3 6 28; U7 6 27; U9 6 27; U16 4 9 10 11 12; U22 A8 AA44 AB2 AD43 AE2 AE32 AG32 AH1 AH32 AJ32 AJ33 AK1 AK31 AK32 AL15 AL18 AL19 AL32 AM14 AM15 AM18 AN13 AN14 AN15 AN16 AN17 AP17 AT30 AU30 AV31 AV33 AW17 AW31 AW33 B7 BC15 BC36 BD13 BD36 D11 F10 F11 F12 F16 F18 G11 G16 G18 G35 G36 G37 G38 H10 H12 H15 H17 H33 H35 H36 H38 J15 J17 J33 J34 J35 J36 J37 J38 K12 K34 K35 K37 K38 L12 L33 L34 L35 L36 L37 L38 M12 M33 M35 M36 M37 M38 N33 N34 N35 N36 N38 P34 P35 P36 P37 P38 R34 R35 R36 R37 R38 T18 T33 T34 T35 T36 T38 U32 U35 U36 U37 U38 V35 V36 V37 V38 W34 W35 W36 W38; U23 5; U25 5; U27 A7 A9 A10 A12 B6 B7 B11 B12 B15 C6 C11 C15 C16 D11 D12 E11 F2 F4 F12 F13 J4 J5 J16 M2 M3 N1; U32 5 6 38 39; U36 1 2 14 15 20 21 23 34 53 55 56 58 61 62 63 64; U37 27 28 30; U38 A1 A2 A9 A10 B1 B9 B10 D6 D7 D8 E3 E4 E5 E6 E7 E8 F3 F4 F5 F6 F8 G3 G6 G7 G8 H3 H5 H6 H7 J3 J5 L1 L2 L9 L10 M1 M2 M9 M10; U42 46 47 59 60 80 84 85; U55 A7 A19 A32 B12 B17 B30 B31; U65 41; U68 5; U69 5; U589 7; U605 5 6; U606 4; U607 4; U620 46 47 59 60 80 84 85; U622 41 42; U624 5 6 7 8; U625 7; U626 2 3 11 13 14 15; U627 2 3 11 13 14 15; U628 1; U629 1; U631 A1 B1

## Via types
v1: diameter 0.457, hole 0.257, TOP to BOTTOM, 200 vias
v2: diameter 0.508, hole 0.254, TOP to BOTTOM, 2667 vias
v3: diameter 0.457, hole 0.254, TOP to BOTTOM, 1636 vias
v4: diameter 1.016, hole 0.508, TOP to BOTTOM, 676 vias
v5: diameter 0.61, hole 0.307, TOP to BOTTOM, 184 vias
v6: diameter 0.508, hole 0.257, TOP to BOTTOM, 70 vias
v7: diameter 0.61, hole 0.305, TOP to BOTTOM, 14 vias

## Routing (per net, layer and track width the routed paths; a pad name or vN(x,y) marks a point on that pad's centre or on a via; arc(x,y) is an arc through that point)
1V2_SB: length 0.6
  BOTTOM w0.118: v1(63.07,73.6) 63.22,73.6 C3730.1
  vias: v1(59.87,75.2) v1(59.87,73.6) v1(60.67,76) v1(60.67,74.4) v1(60.67,72.8) v1(61.47,76.8) v1(61.47,75.2) v1(61.47,73.6) v1(62.27,76) v1(62.27,74.4) v1(62.27,72.8) v2(36.51,73.28) v2(37.26,73.89) v2(64.19,62.69) v2(64.8,65.51) v2(64.87,66.47) v2(65.15,62.69)
1V2SB_EN: length 1.5
  TOP w0.118: R5729.2 34.42,79.25 34.61,79.06 U607.3
1V8_SB: length 111.3
  TOP w0.381: U606.5 C5118.1 v2(30.26,81.28) ; R671.1 v2(11.13,11.94)
  L3_INT_1 w0.508: v2(11.13,11.94) 12.35,11.94 14.22,13.8 14.22,21.6 15.59,22.98 15.59,28.33 19.42,32.17 43.04,32.17 46.52,35.65 46.52,50.64 31.23,65.93 31.23,78.88 30.26,79.85 v2(30.26,81.28) 30.8,81.81 v2(31.04,81.81)
  BOTTOM w0.381: C3839.1 56.65,69.62 v1(56.67,69.6) ; v1(59.07,68.8) 59.85,68.8 C3843.1 ; C3838.1 62.26,70.39 v1(62.27,70.4)
  vias: v1(57.47,80) v1(59.87,79.2) v1(59.87,76.8) v1(59.87,71.2) v1(62.27,78.4) v1(63.07,80.79) v1(63.07,76.8) v1(63.07,75.2) v1(64.67,77.6) v1(65.47,80) v1(66.27,74.4) v1(67.07,76.8)
1V8SB_EN: length 1.3
  TOP w0.254: U606.3 28.36,86.93 R5728.2
2V5: length 37.4
  TOP w0.457: U22.R17 v3(106.33,155.2) ; U22.R16 v3(107.33,155.2) ; U22.L14 v3(109.33,151.2)
  TOP w0.508: v2(244.37,85.74) R2.1 ; FL14.3 v2(134.4,83.97) ; R5815.1 v2(182.44,100.35)
  BOTTOM w0.305: 108.84,147.96 109.09,147.7 R744.1 ; 108.84,147.96 R740.1 108.84,149.31 108.85,149.32 C848.1 ; 108.84,147.96 108.58,147.7 108.08,147.7 107.82,147.45 107.82,141.73 ; R735.1 U22.L14 v3(109.33,151.2)
  BOTTOM w0.457: R734.1 109.79,151.64 109.77,151.64 v3(109.33,151.2) 108.85,150.71 C848.1 ; C806.1 v3(106.33,155.2) ; C805.1 v3(107.33,155.2)
  BOTTOM w0.508: R5838.1 196.85,97.08 196.85,97.08 v2(196.8,97.08) ; R5828.1 v2(183.63,100.35) ; v4(234.14,88.85) 237.25,85.74 v2(244.37,85.74) ; R5827.1 v2(179.79,100.35) ; R5817.1 v2(201.65,97.05) ; R5840.1 v2(200.42,114.92) ; R5826.1 v2(179.83,82.5) ; R5825.1 v2(184.73,82.47) ; R5839.1 v2(198.05,114.92)
  vias: v2(108.41,137.86) v2(108.41,137.22) v2(184.42,78.74) v2(184.42,77.42) v2(185.15,77.98) v2(186.02,78.74) v2(185.99,77.52) v2(201.24,93.32) v2(201.24,92) v2(201.98,92.56) v2(202.84,93.32) v2(202.82,92.1) v4(134.49,82.6) v4(134.59,88.21) v4(134.67,85.39) v4(234.19,92.41) v4(234.19,90.58) v4(235.71,92.28) v4(235.69,90.53) v5(128.04,93.41)
3V3_SB: length 161.5
  TOP w0.254: v2(245.23,235.33) C7.1 245.74,234.19 246,234.19 246.27,233.92 U2.1 ; D46.A v2(273.41,83.92)
  TOP w0.381: v2(34.42,82.12) 34.4,82.13 C5117.1 U605.4 ; R672.1 v2(26.54,13.6) ; v2(215.76,222.25) C412.1 217.81,222.88 218.04,222.65 U55.B10 ; R1969.1 v2(281.08,85.33) ; R5667.1 49.15,69.09 v2(48.97,68.91) ; v2(249.33,167.36) 249.65,167.03 U610.24 ; R332.1 v2(2.9,33.52) ; U610.3 v2(250.95,158.67) ; R206.2 v2(213.97,221.36) ; R341.1 v2(2.9,38.09) ; R333.1 v2(2.9,35.04) ; R151.2 v2(193.36,219.58) ; R335.1 v2(2.9,36.56)
  TOP w0.457: J105.6 v2(14.04,71.43)
  TOP w0.508: SW1.4 v2(272.29,148.34) ; 197.62,222.12 J3.B10 ; J3.B10 198.67,223.18 ; J3.B10 197.62,223.18 ; J3.B10 198.67,222.12 ; R992.1 v2(271.4,15.85) ; SW2.1 v2(272.29,155.45) ; SW1.2 v2(272.29,145.8) ; SW4.4 v2(272.29,181.1) ; SW3.4 v2(272.29,170.18) ; R5589.1 v2(35.13,56.87) ; R993.1 v2(270.13,15.85) ; R5729.1 v2(33.72,80.39) ; R995.1 v2(199.26,15.95) ; SW2.3 v2(272.29,157.99) ; U250.8 R5588.1 49.45,59.41 v2(49.61,59.26) ; SW2.4 v2(272.29,159.26) ; J105.7 v2(1.34,68.89) ; SW4.1 v2(272.29,177.29) ; R5671.1 v2(50.88,75.69) ; SW3.3 v2(272.29,168.91) ; R5583.1 v2(50.7,76.83) ; SW1.1 v2(272.29,144.53) ; SW3.2 v2(272.29,167.64) ; SW1.3 v2(272.29,147.07) ; SW4.3 v2(272.29,179.83) ; SW3.1 v2(272.29,166.37) ; SW2.2 v2(272.29,156.72) ; R994.1 v2(200.66,15.95) ; SW4.2 v2(272.29,178.56)
  L3_INT_1 w0.508: J3.B10 198.67,222.12 ; J3.B10 197.62,222.12 ; J3.B10 197.62,223.18 ; J3.B10 198.67,223.18 ; v2(33.5,82.12) v2(34.42,82.12) 34.42,82.09 34.85,81.66 34.85,79.48 33.77,78.41 33.77,65.44 47.77,51.44 47.77,32.76 40.67,25.65 34.77,25.65 28.14,19.02 28.14,15.2 v2(26.54,13.6)
  L8_PWR_1 w0.508: 197.62,222.12 J3.B10 ; J3.B10 198.67,223.18 ; J3.B10 198.67,222.12 ; J3.B10 197.62,223.18
  BOTTOM w0.254: v2(281.08,85.33) 274.82,85.33 v2(273.41,83.92)
  BOTTOM w0.305: C3722.1 58.72,73.6 v1(59.07,73.6) ; C3723.1 63.18,72.69 v1(63.07,72.8)
  BOTTOM w0.381: v2(250.95,158.67) 250.87,158.59 C3747.1 ; v1(56.67,77.6) 56.65,77.59 C3711.1 ; v1(63.87,76) 63.87,75.51 C3710.1
  BOTTOM w0.457: v2(14.04,71.43) 14.03,71.44 C3700.1
  BOTTOM w0.508: v2(1.34,68.89) C3699.1
  vias: v1(55.07,80.8) v1(55.07,72.8) v1(55.87,80.8) v1(55.87,75.2) v1(57.47,72) v1(58.27,76.8) v1(58.27,74.4) v1(59.07,76) v1(59.07,74.4) v1(64.67,69.6) v1(65.47,72) v1(67.07,68.8) v2(33.5,83.03) v2(36.5,80.01) v2(37.34,79.98) v2(37.34,79.22) v2(48.01,70.43) v2(48.04,69.57) v2(50.88,84.86) v2(50.88,83.69) v2(53.8,84.1) v2(54.84,84.1) v2(194.89,36.5) v2(195.71,222.45) v2(195.71,221.77) v2(196.09,36.5) v2(197.15,36.47)
3V3SB_EN: length 1.3
  TOP w0.254: U605.1 35.7,86.37 R5727.2
5V0_SB: length 59.7
  TOP w0.381: v2(34.3,87.63) C5116.1 34.4,86.89 U605.3 ; R666.1 v2(15.68,20.45) ; R665.1 v2(11.87,20.45) ; v2(30.32,87.88) C5119.1 30.26,87.19 U606.1
  TOP w0.457: R394.2 v2(17.08,104.52)
  TOP w0.508: 3.08,126.36 J9.9 ; J9.9 5.07,124.37 ; J9.9 5.07,126.36 ; J9.9 3.08,124.37 ; R5727.1 v2(36.32,88.93) ; CT31.1 18.39,120.88 ; CT31.1 16.15,118.64 ; CT31.1 18.39,118.64 ; CT31.1 16.15,120.88 ; R5728.1 v2(28.17,88.87)
  L3_INT_1 w0.508: J9.9 5.07,124.37 ; J9.9 3.08,124.37 ; J9.9 5.07,126.36 ; J9.9 3.08,126.36
  L5_INT_2 w0.508: 3.08,124.37 J9.9 ; J9.9 5.07,126.36 ; J9.9 3.08,126.36 ; J9.9 5.07,124.37
  L10_INT_4 w0.508: 16.43,118.92 CT31.1 ; CT31.1 16.43,120.6 ; CT31.1 18.11,118.92 ; CT31.1 18.11,120.6 ; J9.9 5.07,126.36 ; J9.9 3.08,126.36 ; J9.9 5.07,124.37 ; J9.9 3.08,124.37
  L14_INT_6 w0.508: J9.9 5.12,124.32 ; J9.9 5.12,126.42 ; J9.9 3.02,126.42 ; J9.9 3.02,124.32
  BOTTOM w0.508: CT31.1 18.47,118.57 ; CT31.1 16.08,118.57 ; CT31.1 18.47,120.96 ; CT31.1 16.08,120.96 ; J9.9 5.12,124.32 ; J9.9 3.02,124.32 ; J9.9 3.02,126.42 ; J9.9 5.12,126.42
  vias: v2(31.32,87.88) v2(31.32,86.94) v2(33.32,87.68) v2(33.32,86.97) v2(33.83,88.19) v4(2.16,125.86) v4(2.16,124.71) v4(5.97,125.86) v4(5.97,124.71) v4(16.26,121.41) v4(16.26,117.98) v4(18.16,121.41) v4(18.16,117.98)
12V0_2_VDD_FLT: length 36.6
  TOP w0.508: 77.85,248.11 C5289.1 ; C5289.1 77.85,245.87 ; C5289.1 80.08,248.11 ; C5289.1 80.08,245.87 ; 91.38,245.87 C5279.1 ; C5279.1 91.38,248.11 ; C5279.1 93.62,245.87 ; C5279.1 93.62,248.11
  L5_INT_2 w0.508: 78.12,247.83 C5289.1 ; C5289.1 79.81,247.83 ; C5289.1 79.81,246.15 ; C5289.1 78.12,246.15 ; 91.66,247.83 C5279.1 ; C5279.1 91.66,246.15 ; C5279.1 93.34,246.15 ; C5279.1 93.34,247.83
  BOTTOM w0.508: C5279.1 93.69,248.18 ; C5279.1 93.69,245.8 ; C5279.1 91.31,248.18 ; C5279.1 91.31,245.8 ; C5289.1 80.16,245.8 ; C5289.1 77.77,248.18 ; C5289.1 80.16,248.18 ; C5289.1 77.77,245.8 ; v2(84.14,214.55) R43.2
  vias: v4(78.13,244.98) v4(78.1,240.89) v4(79.8,250.3) v4(79.8,242.68) v4(79.8,238.87) v4(79.8,235.06) v4(82.34,250.3) v4(82.34,246.49) v4(82.34,242.68) v4(82.34,238.87) v4(82.34,235.06) v4(83.57,245.01) v4(84.88,250.3) v4(84.88,246.49) v4(84.88,242.68) v4(87.25,242.67) v4(87.42,250.3) v4(88.34,244.96) v4(89.59,242.7) v4(89.79,246.53) v4(89.96,250.3) v4(92.5,250.3) v4(94.51,242.32) v4(95.04,250.3) v4(96.18,244.21) v4(96.18,240.52) v4(97.58,250.3) v4(97.88,242.31) v4(97.88,238.5) v4(97.88,234.69) v4(100.12,250.3) v4(100.42,242.31) v4(100.42,238.5) v4(100.42,234.69) v5(77.6,233.25) v5(77.6,232.49) v5(77.6,231.72) v5(95.68,232.88) v5(95.68,232.12) v5(95.68,231.35)
12V0_FILTERED_PS_GVDD: length 0.6
  TOP w0.152: U631.D2 v3(26.69,228.87)
  vias: v3(29.89,228.87) v4(11.48,232.95) v4(11.6,235.36) v4(11.73,230.16) v4(13.76,237.52) v4(13.76,232.95) v4(13.89,235.36) v4(13.89,230.16) v4(15.92,237.52) v4(16.05,235.36) v4(18.21,237.52) v4(18.33,235.36) v4(18.33,232.82) v4(18.33,230.03) v4(20.62,237.52) v4(20.62,235.36) v4(20.75,232.82) v4(20.75,230.03) v4(22.4,231.3) v4(31.29,229.27) v4(32.3,230.28) v4(33.96,230.28)
AGND_SRDS1_PLL1: length 20.7
  TOP w0.305: U22.L18 v3(105.33,151.2) ; R316.1 105.7,133.95 C271.2 105.7,136.82 C263.2 105.79,138.05 106.33,138.59 v3(106.33,139.83)
  L3_INT_1 w0.305: v3(106.33,139.83) 105.92,139.83 104.83,140.92 104.83,150.69 v3(105.33,151.2)
  BOTTOM w0.457: C841.2 v3(105.33,151.2)
AGND_SRDS1_PLL2: length 20.8
  TOP w0.305: U22.L20 v3(103.33,151.2) ; R315.1 103.72,134.07 C270.2 103.72,135.93 103.5,136.14 C262.2 103.5,138.28 104.9,139.68 104.9,140.15 104.47,140.59 v3(104.42,140.59)
  L3_INT_1 w0.305: v3(104.42,140.59) 104.14,140.59 103.84,140.89 103.84,150.69 v3(103.33,151.2)
  BOTTOM w0.457: C842.2 v3(103.33,151.2)
AGND_SRDS2_PLL1: length 20.1
  TOP w0.305: v3(97.33,139.53) 97.71,139.16 97.77,139.16 98.04,138.88 C261.2 98.04,136.9 98.04,136.27 97.83,136.06 C269.2 97.82,135.12 97.82,134.59 98.3,134.11 R312.1
  TOP w0.457: v3(97.33,151.2) U22.L25
  L3_INT_1 w0.305: v3(97.33,151.2) 96.82,150.69 96.82,140.13 96.95,140 96.95,139.91 v3(97.33,139.53)
  BOTTOM w0.457: v3(97.33,151.2) C845.2
AGND_SRDS2_PLL2: length 21.2
  TOP w0.381: R311.1 95.25,134.21 95.85,134.81 C268.2 95.85,135.93 95.63,136.14 C260.2 95.63,137.69 93.61,139.72 v2(93.6,139.72)
  TOP w0.457: v3(95.33,151.2) U22.L27
  L3_INT_1 w0.305: v2(93.6,139.72) 93.64,139.72 93.88,139.95 94.26,139.95 94.84,140.54 94.84,150.71 v3(95.33,151.2)
  BOTTOM w0.457: C843.2 v3(95.33,151.2)
AGND_SRDS3_PLL1: length 22.9
  TOP w0.305: v2(108.33,186.56) 107.82,187.07 C136.2 ; U22.AP21 v3(102.33,175.2)
  TOP w0.381: C136.2 107.82,188.59 107.61,188.81 C123.2 107.57,189.78 R181.1
  L5_INT_2 w0.305: v2(108.33,186.56) 107.87,186.56 106.83,185.52 106.83,176.01 106.53,175.71 106.51,175.71 106.49,175.7 102.83,175.7 v3(102.33,175.2)
  BOTTOM w0.457: v3(102.33,175.2) C617.2
AGND_SRDS3_PLL2: length 21
  TOP w0.305: R176.1 98.38,191.13 98.39,191.11 C122.2 98.39,188.89 98.17,188.67 C135.2 98.17,186.84 97.26,185.93 v2(96.39,185.93)
  TOP w0.457: v3(99.33,175.19) U22.AP23
  L5_INT_2 w0.305: v3(99.33,175.19) 98.85,175.68 98.85,176.41 98.56,176.69 97.14,176.69 96.83,177 96.83,185.49 v2(96.39,185.93)
  BOTTOM w0.457: v3(99.33,175.19) C616.2
AGND_SRDS4_PLL1: length 19.2
  TOP w0.305: C134.2 94.23,185.72 93.8,185.29 v2(93.22,185.29)
  TOP w0.381: R180.1 95.25,191.06 94.45,190.26 C121.2 94.45,188.86 94.23,188.65 C134.2
  TOP w0.457: v3(94.33,175.19) U22.AP28
  L5_INT_2 w0.305: v2(93.22,185.29) 93.83,184.68 93.83,175.7 v3(94.33,175.19)
  BOTTOM w0.457: C618.2 93.86,174.73 v3(94.33,175.19)
AGND_SRDS4_PLL2: length 21
  TOP w0.305: v2(92.58,185.29) 90.72,185.29 88.9,187.11 C133.2 88.9,188.52 88.56,188.86 C120.2 88.56,190.13 87.73,190.96 R177.1
  TOP w0.457: v3(92.33,175.19) U22.AP30
  L12_INT_5 w0.33: v3(92.33,175.19) 92.83,175.7 92.83,184.54 92.58,184.78 v2(92.58,185.29)
  BOTTOM w0.33: v3(92.33,175.19) C619.2
AVDD_CGA1: length 23.4
  TOP w0.457: U22.AP13 v3(110.33,175.2)
  BOTTOM w0.305: C607.1 109.83,175.73 109.83,180.39 109.52,180.7 107.09,180.7 106.83,180.95 106.83,182.45 106.58,182.7 106.1,182.7 105.83,182.97 105.83,188.12 106.17,188.47 106.17,190.22 C567.1 104.72,190.86 104.39,191.19 104.39,192.02 R686.2
  BOTTOM w0.381: C607.1 109.83,175.7 v3(110.33,175.2)
AVDD_CGA2: length 22.9
  TOP w0.457: U22.AR13 v3(109.33,175.2)
  BOTTOM w0.305: C608.1 108.84,179.45 108.61,179.68 106.96,179.68 105.83,180.81 105.83,181.42 105.56,181.69 105.11,181.69 104.83,181.96 104.83,189.07 C568.1 102.9,191.64 102.59,191.95 102.03,191.95 101.73,192.25 101.73,192.66
  BOTTOM w0.381: C608.1 108.84,175.69 v3(109.33,175.2)
AVDD_CGA3: length 24
  TOP w0.457: v3(108.33,175.2) U22.AR14
  BOTTOM w0.305: R689.2 99.66,190.12 99.86,189.92 102.56,189.92 102.9,189.59 C569.1 103.62,188.85 104.33,188.14 104.33,185.89 103.82,185.38 103.82,180.97 104.11,180.69 104.62,180.69 104.83,180.47 104.83,178.96 105.11,178.69 107.57,178.69 107.82,178.44 C609.1
  BOTTOM w0.381: C609.1 107.83,175.7 v3(108.33,175.2)
AVDD_CGB1: length 19.5
  TOP w0.457: v3(106.33,175.2) U22.AR16
  BOTTOM w0.254: 105.51,176.68 105.79,176.39 C611.1
  BOTTOM w0.305: R691.2 99.31,186.94 C572.1 100.2,185.8 100.2,179.45 100.96,178.69 102.56,178.69 102.83,178.42 102.83,176.95 103.08,176.7 105.49,176.7 105.51,176.68
  BOTTOM w0.381: C611.1 v3(106.33,175.2)
AVDD_CGB2: length 19.8
  TOP w0.457: v3(107.33,175.2) U22.AR15
  BOTTOM w0.305: C610.1 106.85,175.74 106.85,177.36 106.53,177.68 106.52,177.68 106.5,177.7 104.11,177.7 103.82,177.99 103.82,179.44 103.56,179.71 103.07,179.71 102.83,179.95 102.83,180.43 102.57,180.7 102.08,180.7 101.83,180.95 101.83,186.46 C571.1 100.3,187.99 99.29,187.99 R690.2
  BOTTOM w0.381: v3(107.33,175.2) 107.31,175.2 C610.1
AVDD_DDR1: length 24
  TOP w0.305: U22.T13 v3(110.33,156.2)
  BOTTOM w0.305: v3(110.33,156.2) 110.85,156.72 C800.1 110.87,156.71 113.5,156.71 113.82,156.39 113.82,144.81 113.26,144.25 113.26,140.98 C878.1 114.41,139.33 R770.2
AVDD_DDR2: length 32.3
  TOP w0.457: U22.AJ13 v3(110.33,170.2)
  BOTTOM w0.305: R685.2 104.14,194.18 105.92,194.18 106.5,193.6 106.5,191.52 107.16,190.86 C566.1 107.7,189.23 106.36,187.9 106.36,184.09 107.77,182.68 110.53,182.68 110.85,182.36 110.85,170.78 C638.1 v3(110.33,170.2)
AVDD_DDR3: length 17.5
  TOP w0.457: U22.AC32 v3(90.33,163.2)
  BOTTOM w0.457: R708.2 75.4,161.67 75.53,161.8 C728.1 78.87,161.8 80.9,163.83 89.67,163.83 89.8,163.7 C715.1 v3(90.33,163.2)
AVDD_PLAT: length 4.9
  TOP w0.457: v3(94.33,156.2) U22.T28
  BOTTOM w0.457: v3(94.33,156.2) C802.1
  BOTTOM w0.508: v2(83.6,140.13) 83.19,140.13 C879.1 81.18,139.19 R769.2
AVDD_SRDS1_PLL1: length 20.5
  TOP w0.305: v3(106.33,140.46) 106.68,140.46 107.31,139.83 C263.1 107.63,136.59 C271.1 107.63,134.05 R317.1 ; U22.L17 v3(106.33,151.2)
  L3_INT_1 w0.305: v3(106.33,140.46) 105.82,140.98 105.82,150.68 v3(106.33,151.2)
  BOTTOM w0.457: C841.1 v3(106.33,151.2)
AVDD_SRDS1_PLL2: length 21.8
  TOP w0.305: R314.1 101.79,133.92 C270.1 101.79,135.95 101.98,136.14 C262.1 101.98,137.79 104.14,139.95 v3(104.42,139.95) ; U22.L21 v3(102.33,151.2)
  L3_INT_1 w0.305: v3(104.42,139.95) 103.76,139.95 102.82,140.89 102.82,150.71 v3(102.33,151.2)
  BOTTOM w0.457: C842.1 v3(102.33,151.2)
AVDD_SRDS2_PLL1: length 21.3
  TOP w0.305: v3(97.33,140.5) 97.63,140.2 98.46,140.2 99.57,139.09 C261.1 99.76,136.72 C269.1 99.76,134.81 99.19,134.24 R313.1
  TOP w0.457: v3(98.33,151.2) U22.L24
  L3_INT_1 w0.305: v3(98.33,151.2) 97.83,150.7 97.83,140.84 97.53,140.54 97.41,140.54 97.37,140.5 v3(97.33,140.5)
  BOTTOM w0.457: v3(98.33,151.2) C845.1
AVDD_SRDS2_PLL2: length 21.8
  TOP w0.305: R319.1 93.92,133.92 C268.1 93.92,135.95 94.11,136.14 C260.1 94.11,137.95 92.99,139.07 92.99,140.23 v3(93.34,140.59)
  TOP w0.457: v3(94.33,151.2) U22.L28
  L3_INT_1 w0.305: v3(94.33,151.2) 93.85,150.72 93.85,150.4 93.85,150.4 93.85,141 93.44,140.59 v3(93.34,140.59)
  BOTTOM w0.457: C843.1 v3(94.33,151.2)
AVDD_SRDS3_PLL1: length 24.1
  TOP w0.305: U22.AP20 v3(103.33,175.2) ; C136.1 109.35,186.26 108.99,185.9 108.36,185.9 v2(108.33,185.93)
  TOP w0.381: R182.1 109.81,191.31 109.81,190.71 109.54,190.44 C123.1 109.54,188.86 109.35,188.67 C136.1
  L5_INT_2 w0.305: v2(108.33,185.93) 107.83,185.43 107.83,175.01 107.51,174.7 103.83,174.7 v3(103.33,175.2)
  BOTTOM w0.381: C617.1 v3(103.33,175.2)
AVDD_SRDS3_PLL2: length 20.4
  TOP w0.305: v2(96.39,186.56) 96.65,186.82 C135.1 96.65,188.65 96.46,188.84 C122.1 96.46,190.28 97.16,190.98 R175.1
  TOP w0.457: v3(98.33,175.19) U22.AP24
  L5_INT_2 w0.305: v3(98.33,175.19) 97.83,175.69 96.15,175.69 95.83,176.01 95.83,186.25 96.14,186.56 v2(96.39,186.56)
  BOTTOM w0.457: C616.1 v3(98.33,175.19)
AVDD_SRDS4_PLL1: length 19.4
  TOP w0.305: v2(93.22,185.93) 93.22,186.64 92.71,187.15 C134.1 92.71,188.65 92.52,188.84 C121.1 92.52,190.64 R179.1
  TOP w0.457: v3(95.33,175.19) U22.AP27
  L5_INT_2 w0.305: v2(93.22,185.93) 93.9,185.93 94.83,185 94.83,175.7 v3(95.33,175.19)
  BOTTOM w0.33: C618.1 v3(95.33,175.19)
AVDD_SRDS4_PLL2: length 21
  TOP w0.305: v2(92.58,185.93) 91.57,185.93 90.42,187.07 C133.1 90.42,189.67 C120.1 90.49,190.69 R178.1
  TOP w0.457: U22.AP31 v3(92.33,174.19)
  L5_INT_2 w0.305: v2(92.58,185.93) 92.28,185.93 91.83,185.48 U22.AP31 v3(92.33,174.19)
  BOTTOM w0.33: C619.1 v3(92.33,174.19)
GND: length 12685.5
  TOP w0.152: U631.E5 v3(29.89,227.27) ; U38.K3 v2(97.29,80.62) ; U631.G1 v3(25.89,225.67) ; U631.E1 v3(25.89,227.27) ; U631.F6 v3(30.69,226.47) ; U38.C5 v2(98.9,87.02) ; U38.F7 v2(101.29,84.62) ; U631.G5 v3(29.89,225.67) ; U631.E6 v3(30.69,227.27) ; U38.K8 v2(102.1,80.62) ; U631.G2 v3(26.69,225.67) ; U631.E2 v3(26.69,227.27) ; U631.F1 v3(25.89,226.47) ; U631.F5 v3(29.89,226.47) ; U631.G6 v3(30.69,225.67) ; U631.F2 v3(26.69,226.47)
  TOP w0.203: 82.04,42.17 U45.7
  TOP w0.254: U630.4 37.06,124.58 R5768.2 37.72,123.92 v2(37.72,123.23) ; v2(253.09,113.14) 252.88,112.93 U624.24 ; U32.11 110.45,108.98 v2(110.19,109.25) 109.95,109.01 U32.12 ; v5(181.29,88.65) 180.62,87.98 U65.39 ; U32.8 111.97,106.48 v2(112.19,106.26) 111.91,105.98 U32.7 ; v2(42.02,15.79) U608.3 U608.8 ; C5343.2 97.93,231.05 v2(97.93,231.06) 97.61,230.74 U7.4 ; C5328.2 104.94,92.93 U626.1 ; v2(251.89,109.09) 251.52,109.46 U624.18 ; U65.22 180.62,93.37 v5(180.21,92.96) ; U95.8 59.41,35 v2(59.92,34.49) ; v2(89.13,75.49) 88.95,75.31 U37.52 ; U16.3 278.09,83.43 v2(277.88,83.64) ; v2(195.01,103.48) 195.16,103.63 U622.34 ; U32.31 105.95,101.41 v2(106.1,101.27) 106.12,101.27 106.45,101.6 U32.32 ; U32.20 105.95,108.83 v2(105.66,109.12) ; v2(255.35,111.12) 255.04,111.43 C5309.2 ; U622.22 197.45,107.95 v5(197.04,107.54) ; U7.28 94.68,227.78 v6(94.29,227.39) ; U48.B3 U48.C3 U48.D3 32.26,41.35 v2(32.26,41.15) 32.26,40.77 32.64,40.39 ; v5(106.21,95.48) 106.21,96.03 106.44,96.27 U626.9 ; U46.8 68.04,34.8 68.3,34.54 v2(68.73,34.54) ; v5(196.98,105.38) 196.73,105.13 U622.31 195.24,105.13 v2(195.03,105.34) 195.33,105.63 U622.30 ; v2(247.35,112.24) 247.65,111.93 U624.9 ; U627.9 111.57,94.63 111.8,94.87 v5(111.8,95.42) ; v2(178.18,88.9) 178.34,89.05 U65.34 ; v5(250.27,111.68) 251.02,112.43 U624.23 ; v6(76.1,227.79) 76.59,228.28 U9.28 ; U65.30 178.5,91.05 v2(178.21,90.76) 178.41,90.56 U65.31 179.9,90.56 v5(180.15,90.81) ; U2.5 245.74,231.92 v2(245.47,231.65) ; U65.27 v2(178.29,92.56) ; U32.36 v2(108.45,101.19) ; R508.2 42.29,40.77 v2(42.29,41.15) 42.29,41.35 U47.D3 U47.C3 U47.B3 ; C7.2 v2(243.59,234.7) ; U627.1 113.07,97.5 112.82,97.75 C5329.2 ; U622.27 v2(195.11,107.13) ; v5(198.12,103.22) 197.45,102.55 U622.39 ; U16.7 v2(276.09,83.56) ; U9.4 79.52,231.11 v2(79.7,231.29) ; U37.33 v2(79.45,73.15)
  TOP w0.305: U594.24 77.79,108.15 77.79,108.15 v2(77.79,108.38) ; U594.1 v2(66.28,108.38) ; U594.21 v2(76.29,108.38) ; U22.AE14 U22.AD14 ; U620.67 v2(177.79,56.23) ; v2(89.14,102.87) 89.38,102.87 89.7,102.56 U595.3 ; v6(35.89,126.34) 36.06,126.17 U630.2 ; U593.39 v2(85.52,116) ; U594.4 v2(67.78,105.59) ; U594.39 v2(70.78,116) ; U593.10 v2(85.52,108.38) ; U593.15 v2(88.02,105.59) ; U22.H37 85.33,148.2 v3(84.33,148.2) ; U22.AB3 119.83,163.69 ; U593.28 v2(91.02,113.21) ; U22.T43 80.13,156.69 80.63,157.2 v3(81.33,157.2) ; U594.34 v2(73.29,113.21) ; v2(92.52,108.38) 92.52,108.15 92.52,108.15 U593.24 ; U598.3 83.72,103.05 v2(83.59,103.17) ; U593.21 v2(91.02,105.59) ; U42.67 v2(135.63,56.23) ; U596.3 86.73,102.56 v2(86.25,103.04) ; U594.15 v2(73.29,108.38) ; U593.45 v2(82.51,113.21) ; U593.4 v2(82.51,108.38) ; U593.1 v2(81.01,108.38) ; U593.34 v2(88.02,113.21) ; U594.28 v2(76.29,113.21) ; U594.45 v2(67.78,113.21) ; U594.10 v2(70.78,105.59)
  TOP w0.381: R5772.1 v2(260.03,144.53) ; C152.2 156.34,183.4 v2(156.34,183.4) ; R5748.2 38.09,130.16 v2(37.85,130.4) ; v2(81.66,42.04) 81.79,42.17 82.04,42.17 ; v2(35.3,87.63) C5116.2 35.05,86.75 U605.2 ; U18.4 249.77,205.57 v2(250.06,205.87) ; v2(168.14,235.33) C35.2 ; C60.2 v2(209.03,223.27) ; v2(103.92,132.81) 103.94,132.83 103.94,132.87 104.14,133.07 R315.2 ; C3897.2 v2(59.97,33.58) ; v2(35.57,80.01) C5120.2 35.56,79.37 U607.2 ; U610.23 v2(250.3,167.48) ; C3894.2 v2(68.61,33.52) ; R5777.1 v2(260.03,156.72) ; U14.3 34.87,191.19 35.06,191 v2(35.06,190.99) ; C345.2 v2(77.45,70.98) ; v2(266.31,48.63) 266.31,48.13 266.69,47.75 C1151.2 267.16,47.75 267.54,48.13 v2(267.54,48.62) ; v2(156.34,182.11) 156.34,182.11 C159.1 ; R5782.1 v2(260.03,168.91) ; C434.2 v2(228.47,222.63) ; v2(41.91,160.15) C211.2 ; C520.2 v2(26.53,15.04) ; v2(207.4,54.35) 207.4,53.85 207.02,53.47 C1145.2 206.55,53.47 206.17,53.85 v2(206.17,54.33) ; C2704.2 v2(68.78,39.8) ; C1158.2 v2(280.38,83.81) ; Q9.2 v2(12.17,37.15) ; v2(257.73,158.12) 257.16,158.12 256.8,158.47 U610.12 ; R5778.1 v2(260.03,157.99) ; v2(104.78,132.72) 104.78,133.1 R316.2 ; R102.2 30.4,237.46 v2(30.4,237.46) ; C304.2 v2(156.97,114.68) ; C157.2 125.72,183.69 v2(125.72,183.01) ; C221.1 v2(41.91,157.99) ; C5117.2 v2(36.04,82.93) ; C5118.2 v2(28.63,81.92) ; C5334.2 v2(276.19,77.71) ; R5785.1 v2(260.03,178.56) ; v2(104.29,112.19) 104.29,111.75 C3889.2 103.35,111.78 v2(103.35,112.19) ; R5779.1 v2(260.03,159.26) ; C5329.2 v2(113.45,98.22) ; C58.2 v2(193.42,224.79) ; C1143.2 v2(208.28,48.12) ; v2(126.42,181.84) 126.19,181.61 R211.1 ; C202.2 v2(41.91,164.08) ; C275.2 94.06,132.76 v2(94.06,133.02) ; C5324.2 v2(236.47,132.84) ; Q11.2 v2(16.75,24.64) ; v2(111.98,112.56) 112.88,111.66 C334.2 112.15,111.3 v2(111.91,111.53) ; C41.2 v2(209.04,231.52) ; R213.1 v2(126.42,180.59) ; C993.2 v2(214.12,230.63) ; U22.C16 v3(107.33,144.2) ; C992.2 v2(214.12,231.65) ; C43.2 v2(193.42,232.16) ; R142.1 v2(193.36,220.73) ; C3844.2 v2(241.36,195.98) ; U17.3 176.34,190.94 176.15,190.75 v2(176.14,190.75) ; v3(88.33,183.19) 88.83,183.69 U22.BC34 ; U606.2 29.31,87.24 C5119.2 v2(29.32,87.88) ; Q7.2 v2(12.17,31.56) ; U82.12 243.62,123.02 v2(244.07,122.58) ; C26.2 v2(209.04,230.25) ; R5787.1 v2(260.03,181.1) ; U22.BB34 v3(89.33,182.19) ; R5773.1 v2(260.03,145.8) ; C5330.2 v2(114.07,93.32) ; U58.4 249.64,211.8 v2(249.94,212.09) ; C119.2 v2(41.13,188.77) ; Q12.2 v2(12.94,24.75) ; v2(266.31,54.35) 266.31,53.85 266.69,53.47 C1148.2 267.16,53.47 267.54,53.85 v2(267.54,54.33) ; R5780.1 v2(260.03,166.37) ; C991.2 v2(214.12,229.62) ; R176.2 99.64,191.8 v2(99.99,191.8) ; C3849.2 90.68,116.85 v2(91.16,116.85) ; R312.2 v2(97.28,132.78) ; C40.2 v2(193.42,231.01) ; C965.2 v2(228.47,223.65) ; R5783.1 v2(260.03,170.18) ; C66.2 v2(209.04,222) ; C3850.2 v2(83.02,117.32) ; C5320.2 v2(87.74,43.33) ; C179.1 v2(169.04,173.23) ; C5321.2 v2(87.76,41.41) ; C3851.2 v2(75.79,117.32) ; C522.2 v2(11.07,10.92) ; C5328.2 v2(105.19,92.05) ; R5774.1 v2(260.03,147.07) ; Q8.2 v2(12.17,34.35) ; R119.2 v2(193.36,227.71) ; C412.2 v2(214.12,222.88) ; C1146.2 v2(208.28,53.84) ; C516.2 v2(32.35,43.05) ; R5781.1 v2(260.03,167.64) ; C5327.2 v2(103.94,97.58) ; R5775.1 v2(260.03,148.34) ; v2(80.86,230.43) C5344.2 ; C3852.2 v2(68.28,117.32) ; C1149.2 v2(265.43,53.84) ; v2(206.17,48.62) 206.17,48.13 206.55,47.75 C1142.2 207.02,47.75 207.4,48.13 v2(207.4,48.63) ; C5121.2 v2(34.88,73.92) ; Q10.2 v2(12.17,39.94) ; C900.2 v2(214.25,224.54) ; C1152.2 v2(265.43,48.12) ; C25.2 v2(193.42,233.3) ; C300.2 v2(42.29,111.77) ; R5776.1 v2(260.03,155.45) ; R5784.1 v2(260.03,177.29) ; C65.2 v2(193.37,222) ; C515.2 v2(42.38,43.05) ; R5786.1 v2(260.03,179.83) ; C5333.2 v2(241.31,189.51) ; C295.2 v2(85.58,186.66) ; R311.2 v2(96.27,132.78)
  TOP w0.457: U22.AW13 v3(110.33,180.2) ; U22.C22 v3(101.33,143.2) ; v3(105.33,180.2) U22.AY18 v3(105.33,181.2) ; v3(105.33,180.2) U22.AW18 v3(105.33,179.2) ; v3(105.33,180.2) U22.AY17 v3(105.33,181.2) ; U22.E16 v3(107.33,145.2) ; v2(126.4,154.57) 126.32,154.57 126.31,154.56 R259.2 ; v3(103.33,163.19) U22.AC20 ; v3(108.33,151.2) U22.L15 v3(108.33,152.2) U22.M15 v3(107.33,153.2) U22.N16 v3(106.33,154.2) U22.P17 ; U22.AY27 v3(95.33,181.19) U22.AY28 ; U22.B23 U22.A23 v3(99.33,141.2) ; U22.N22 v3(101.33,153.2) 101.83,152.7 U22.M21 v3(102.33,152.2) ; U22.AW3 v3(120.33,179.2) U22.AV3 ; U22.AK15 v3(108.33,171.2) ; v2(125.41,141.49) 125.72,141.8 C251.2 ; U22.AW10 v3(113.33,180.2) ; U22.T14 v3(109.33,156.2) ; U22.J16 v3(107.33,149.2) ; v3(91.33,156.2) U22.T31 ; U22.AK41 v3(81.33,171.19) ; v3(98.33,174.19) U22.AN24 v3(99.33,173.19) U22.AM23 ; U22.AW26 v3(96.33,180.19) ; U22.AJ34 v3(88.33,170.19) ; U22.G15 v3(108.33,147.2) ; U22.AG12 v3(110.33,168.2) U22.AG13 v3(109.33,167.2) U22.AF14 ; v3(78.05,149.62) 78.25,149.62 78.26,149.62 78.76,149.62 U22.J44 ; U22.AE9 v3(113.33,166.2) ; U22.R20 v3(102.33,155.2) U22.R21 ; v3(104.33,172.2) U22.AM19 v3(103.33,172.2) U22.AL20 ; U22.R22 v3(101.33,155.2) ; U22.AN36 v3(86.33,174.19) ; U22.U16 v3(107.33,157.2) ; U22.N43 v3(79.33,153.2) U22.M44 ; U22.AG3 v3(120.33,168.2) ; U22.AV20 v3(103.33,179.2) ; U22.P17 v3(105.33,154.2) ; U22.P17 105.83,154.7 v3(105.33,155.2) U22.R18 v3(104.33,155.2) U22.R19 ; U22.BB16 v3(106.33,183.2) U22.BB17 ; U22.AA11 v3(112.33,161.2) U22.AA10 ; v3(93.33,167.19) U22.AF29 ; U22.AT35 v3(87.33,177.19) ; U22.AV38 v3(84.33,179.19) ; U22.Y17 v3(106.33,160.2) ; U22.AA18 v3(105.33,161.2) ; U22.AA14 v3(109.33,161.2) ; v3(90.33,152.2) U22.M32 ; U22.AP16 v3(106.33,174.2) ; U22.P3 v3(120.33,154.2) ; v3(120.33,146.2) 120.33,146.2 119.83,146.69 U22.F3 ; U22.BB29 93.33,182.2 v3(93.33,182.19) U22.BA29 93.83,181.69 v3(93.33,181.19) U22.AY29 U22.AW28 ; U22.AW30 v3(92.33,180.19) U22.AY31 ; v3(94.33,159.2) U22.W28 ; U22.AP3 v3(119.33,174.2) U22.AN3 ; R323.2 v2(116.06,127.68) ; U22.AY10 v3(113.33,181.2) U22.BA10 ; v3(87.33,143.2) 86.83,142.7 U22.B36 ; v3(92.33,149.2) U22.J30 ; U22.R3 v3(120.33,155.2) ; v3(97.33,167.19) U22.AF25 ; v3(114.33,146.2) 113.83,146.7 U22.F9 ; v3(86.33,151.2) 86.33,151.19 U22.K36 ; U22.AE39 v3(84.33,165.19) U22.AD39 ; v3(95.33,182.19) U22.BA27 ; v3(95.33,165.19) U22.AD27 ; U22.R9 113.83,155.7 v3(114.33,155.2) ; U22.J20 v3(103.33,149.2) ; U22.P11 v3(111.33,154.2) ; U22.AB19 v3(104.33,162.2) ; v3(97.33,145.2) U22.E25 ; v3(120.33,149.2) U22.H3 ; U22.AE36 v3(87.33,165.19) U22.AD36 ; v3(97.33,147.2) U22.G25 ; U22.C31 91.83,143.7 v3(92.33,144.2) ; v3(119.33,167.2) U22.AF3 v3(119.33,166.2) ; U22.AR3 v3(119.33,176.2) ; U22.E18 v3(105.33,145.2) ; U22.AP9 v3(114.33,175.2) ; C168.2 v2(125.72,176.43) ; v3(97.33,169.19) U22.AH25 ; U22.AE31 v3(91.33,166.19) 91.83,166.69 U22.AF31 ; v3(98.33,171.19) U22.AK24 ; v3(103.33,176.2) U22.AT19 v3(104.33,176.2) ; v2(127.25,139.2) 127.25,139.88 127.08,140.06 ; U22.AN9 v3(113.33,174.2) ; v3(119.33,166.2) 119.33,166.19 U22.AE3 ; v3(119.33,166.2) U22.AF4 v3(118.33,167.2) U22.AF5 ; U22.K43 79.83,150.7 v3(80.33,151.2) ; U22.AT8 v3(115.33,177.2) ; U22.J5 117.83,149.68 118.32,149.2 v3(118.33,149.2) ; U22.AD21 v3(102.33,165.2) ; U22.T3 v3(120.33,157.2) U22.U3 ; U22.AC28 v3(94.33,163.2) ; U22.AK36 v3(86.33,171.19) ; v3(95.33,171.19) U22.AK27 ; U22.AW7 v3(116.33,180.2) ; v3(99.33,153.2) U22.N23 ; U22.AH31 v3(91.33,169.19) 91.33,169.2 U22.AJ31 v3(91.33,170.19) ; v3(113.33,150.2) 113.83,149.7 U22.J9 v3(114.33,149.2) ; v3(105.33,181.2) U22.BA17 v3(105.33,182.2) U22.BB17 ; U22.AT12 v3(111.33,177.2) ; U22.AE7 v3(115.33,166.2) ; v3(96.33,145.2) U22.E26 ; U22.AH36 v3(86.33,169.19) ; U22.AH12 v3(111.33,169.2) ; U22.AK33 v3(90.33,171.19) ; v3(99.33,178.19) U22.AU23 ; U22.AM25 v3(97.33,173.19) U22.AM26 v3(96.33,173.19) U22.AN27 v3(95.33,174.19) ; U22.AM12 v3(110.33,173.2) ; v3(93.33,153.2) U22.N29 ; 127.08,140.06 C253.2 ; 127.08,140.06 126.62,139.6 v2(126.62,139.19) ; U22.AC36 86.83,163.69 v3(86.33,163.19) U22.AC37 ; U22.AM28 v3(94.33,173.19) U22.AN29 ; U22.AN35 v3(87.33,174.19) ; U22.AV30 92.33,178.2 v3(92.33,178.19) U22.AU31 ; U22.AV30 v3(92.33,179.19) ; U22.AV30 v3(93.33,178.19) U22.AU29 93.83,177.69 v3(93.33,177.19) U22.AT29 v3(94.33,176.19) ; v3(119.33,162.2) U22.AB4 v3(118.33,162.2) ; v3(119.33,162.2) 119.83,161.7 U22.AA3 120.01,161.52 120.01,160.87 U22.Y3 ; v3(119.33,162.2) U22.AB3 ; U22.AW38 v3(84.33,180.19) ; v3(96.33,157.2) U22.U26 ; U22.J3 v3(120.33,150.2) U22.K3 ; U22.AT42 v3(80.33,177.19) ; U22.AW16 v3(107.33,180.2) ; U22.AW15 v3(108.33,180.2) ; U22.AM22 v3(101.33,173.2) U22.AN22 v3(101.33,174.2) U22.AP22 ; U22.U22 v3(101.33,157.2) ; U22.AR12 v3(111.33,175.2) U22.AP12 ; U22.B31 v3(91.33,142.2) 91.33,142.19 U22.A31 ; U22.BD22 v3(101.33,185.2) ; v3(95.33,160.2) U22.Y27 ; v3(94.33,143.2) U22.C28 ; U22.V17 v3(106.33,158.2) ; v3(109.33,166.2) U22.AE14 ; U22.AW12 v3(111.33,180.2) ; U22.AK19 v3(104.33,171.2) ; U22.AK3 v3(119.33,170.2) U22.AJ4 ; U22.J18 v3(105.33,149.2) ; U22.AT21 v3(102.33,177.2) ; U22.H22 v3(101.33,148.2) ; U22.D18 v3(105.33,144.2) ; v2(125.72,167.77) 125.72,167.77 C196.2 ; v3(92.33,170.19) U22.AJ30 ; U22.AA20 v3(103.33,161.2) ; v3(99.33,171.19) U22.AK23 ; U22.D32 90.83,144.7 v3(91.33,145.2) U22.E31 ; U22.H11 v3(112.33,148.2) ; v3(92.33,151.2) U22.L30 ; U22.BB13 v3(110.33,183.2) ; v3(98.33,185.19) U22.BD24 ; U22.F4 v3(119.33,146.2) ; U22.AG16 v3(107.33,168.2) ; U22.AY19 v3(103.33,180.2) U22.AW20 ; U22.AC41 v3(82.33,163.19) 82.83,163.69 U22.AC40 ; U22.W16 v3(107.33,159.2) ; v3(91.33,168.19) U22.AG31 ; C161.2 74.94,180.77 v2(75.24,180.47) ; U22.J7 v3(116.33,149.2) ; U22.B44 v3(78.33,142.2) ; U22.AJ10 v3(112.33,170.2) ; U22.BB17 v3(105.33,183.2) ; U22.Y42 v3(80.33,160.2) 79.83,159.7 U22.W43 ; U22.AF6 v3(117.33,167.2) ; U22.E6 v3(117.33,145.2) ; U22.AF17 v3(106.33,167.2) ; U22.AE20 v3(103.33,166.2) ; U22.K6 v3(117.33,150.2) ; U22.BA21 v3(102.33,182.2) ; U22.C30 v3(92.33,143.2) ; U22.AW11 v3(112.33,180.2) ; v3(103.33,174.2) U22.AN20 v3(102.33,173.2) U22.AM21 ; C162.1 v2(169.04,180.72) ; U22.N19 v3(104.33,153.2) ; v3(99.33,182.19) U22.BA23 ; v3(95.33,162.2) U22.AB27 ; U22.AM30 v3(92.33,173.19) U22.AN31 91.83,173.69 v3(91.33,173.19) U22.AM32 v3(91.33,172.19) ; v3(94.33,145.2) U22.E28 ; U22.E14 v3(109.33,145.2) ; v3(89.33,143.2) 89.33,143.19 U22.B33 ; v3(105.33,179.2) U22.AV18 ; v3(105.33,179.2) U22.AV17 v3(105.33,178.2) ; U22.AV18 v3(105.33,178.2) ; U22.AV18 v3(104.33,178.2) U22.AU19 ; U22.AC31 v3(91.33,163.2) 91.33,163.19 91.83,162.69 U22.AB31 v3(91.33,162.2) 91.33,162.19 U22.AA31 ; U22.H34 88.83,148.7 v3(89.33,149.2) ; U22.AJ7 v3(115.33,170.2) ; U22.A43 v3(79.33,141.2) ; U22.V14 v3(109.33,158.2) 109.83,157.7 U22.U13 ; U22.F17 v3(106.33,146.2) ; U22.AR39 v3(83.33,176.19) ; v3(113.33,152.2) 113.83,151.7 U22.L9 ; U22.AH21 v3(102.33,169.2) ; v3(92.33,145.2) U22.E30 ; v3(85.33,160.2) U22.Y37 ; U22.AH39 v3(83.33,169.19) ; U22.P14 v3(108.33,154.2) U22.P15 ; U22.B11 v3(111.33,142.2) ; U22.AH33 v3(89.33,169.19) ; U22.BB19 v3(104.33,183.2) U22.BC18 ; U22.N18 v3(105.33,153.2) ; U22.AK6 v3(116.33,171.2) ; U22.U39 v3(84.33,157.2) ; J105.2 v2(14.04,76.51) ; R321.1 v2(114.05,127.7) ; v3(97.33,158.2) U22.V25 ; U22.AH42 v3(80.33,169.19) 80.83,169.69 U22.AJ42 ; U22.BB10 v3(113.33,183.2) ; v3(113.33,148.2) U22.H9 113.83,148.7 v3(114.33,148.2) 113.83,147.7 U22.G9 ; v3(89.33,154.2) U22.P33 ; v2(126.44,153.71) 126.4,153.67 R261.1 ; U22.AT4 v3(118.33,176.2) ; U22.AM29 v3(93.33,173.19) ; v3(97.33,177.19) U22.AT25 ; U22.V6 v3(117.33,159.2) U22.W6 ; v3(114.33,165.2) 114.33,165.19 U22.AD8 ; v3(96.33,166.19) U22.AE26 ; U22.AT7 v3(116.33,177.2) ; U22.W14 v3(109.33,159.2) ; U22.AH19 v3(104.33,169.2) ; U22.AK21 v3(102.33,171.2) ; U22.F13 v3(110.33,146.2) ; U22.T9 v3(114.33,156.2) ; U22.BB37 v3(86.33,183.19) ; U22.AC24 v3(98.33,163.2) ; U22.AT6 v3(117.33,177.2) ; v3(118.33,143.2) 118.31,143.21 U22.C5 ; U22.L6 v3(117.33,151.2) ; v3(105.33,178.2) U22.AU17 v3(106.33,177.2) U22.AT17 ; v2(75.27,168.15) 74.94,168.48 C191.2 ; U22.G21 v3(102.33,147.2) ; U22.T11 v3(111.33,156.2) U22.T12 ; U22.AA42 v3(81.33,161.2) ; U22.W9 v3(114.33,159.2) ; v3(98.33,166.19) U22.AE24 ; U22.AE42 v3(81.33,166.19) 80.83,166.69 U22.AF42 ; U22.AA26 v3(96.33,161.2) ; v3(98.33,149.2) U22.J24 ; U22.F21 v3(102.33,146.2) ; U22.J22 v3(101.33,149.2) ; v2(127.38,164.97) 127.38,164.52 127.08,164.21 ; v3(99.33,177.19) U22.AT23 ; U22.AP15 v3(107.33,174.2) ; v3(117.33,165.2) 117.33,165.19 U22.AD5 ; C209.2 v2(125.72,162.69) ; U22.R6 v3(117.33,155.2) ; U22.F19 v3(104.33,146.2) ; U22.AD17 v3(106.33,165.2) ; U22.K9 v3(114.33,151.2) U22.L9 ; U22.E17 v3(106.33,145.2) ; v3(94.33,149.2) U22.J28 ; U22.AN34 v3(88.33,174.19) ; U22.AJ8 v3(114.33,170.2) ; U22.L9 v3(113.33,151.2) ; U22.AK12 v3(110.33,171.2) U22.AK13 ; U22.H16 v3(107.33,148.2) ; v3(89.33,163.2) U22.AC33 U22.AD33 ; U22.AU37 v3(85.33,178.19) ; U22.AU31 v3(92.33,177.19) U22.AT31 v3(91.33,176.19) ; U22.AU31 U22.AV32 v3(90.33,179.19) ; U22.BC22 v3(101.33,184.2) ; v3(81.33,160.2) U22.Y41 ; v3(91.33,172.19) U22.AL31 ; v3(91.33,172.19) 91.83,172.69 U22.AM31 ; U22.AL31 v3(92.33,171.19) U22.AK30 ; U22.AL31 91.83,171.69 v3(91.33,171.19) ; v3(105.33,185.2) U22.BD18 v3(105.33,184.2) ; U22.G19 v3(104.33,147.2) ; v3(95.33,153.2) U22.N27 ; v3(105.33,175.2) U22.AP18 v3(105.33,174.2) U22.AN18 ; v3(95.33,167.19) U22.AF27 ; U22.P16 v3(107.33,154.2) ; U22.AM3 v3(119.33,173.2) ; U22.AL42 v3(80.33,172.19) ; U22.BA42 v3(80.33,181.19) U22.AY42 ; C138.2 84.07,188.04 v2(83.87,188.24) ; U22.D16 v3(107.33,144.2) ; U22.N20 v3(103.33,153.2) 103.83,152.7 U22.M19 ; U22.D14 v3(109.33,144.2) ; v2(128.09,174.75) 127.58,174.75 C173.2 127.2,174.12 v2(128.09,174.12) ; U22.AU3 v3(119.33,177.2) U22.AT3 ; U22.E9 113.83,145.7 v3(113.33,146.2) ; v3(93.33,146.2) U22.F29 ; v3(97.33,171.19) U22.AK25 ; v3(105.33,184.2) U22.BC18 ; v3(105.33,184.2) U22.BC17 v3(105.33,183.2) ; U22.H14 v3(109.33,148.2) ; U22.AV22 v3(101.33,179.2) ; v3(94.33,161.2) U22.AA28 ; U22.BC18 v3(105.33,183.2) ; R306.2 v2(113.03,130.49) ; U22.AJ16 v3(107.33,170.2) ; U22.AT33 v3(89.33,177.19) U22.AU34 v3(88.33,178.19) ; U22.W12 v3(111.33,159.2) ; U22.M6 v3(117.33,152.2) ; v3(96.33,155.2) U22.R26 ; v3(98.33,179.19) U22.AV24 ; U22.AP39 v3(83.33,175.19) ; v3(105.33,163.19) U22.AC18 ; v3(89.33,166.19) U22.AE33 v3(90.33,166.19) ; v3(91.33,159.2) U22.W31 ; U22.AF39 v3(83.33,167.19) ; C3895.2 v2(69.85,35.01) ; U22.AL34 v3(88.33,172.19) ; U22.B39 83.83,142.7 v3(84.33,143.2) ; v3(97.33,155.2) U22.R25 ; C182.2 125.72,172.45 v2(125.58,172.59) ; U22.AP37 v3(85.33,175.19) ; v3(93.33,171.19) U22.AK29 ; v2(74.17,173.61) 74.8,173.61 R230.1 R229.1 ; v3(98.33,159.2) U22.W24 ; U22.AL39 v3(83.33,172.19) ; U22.A15 v3(108.33,141.2) ; U22.AJ12 v3(111.33,170.2) U22.AJ11 ; C166.1 v2(169.04,177.55) ; U22.AL3 v3(119.33,172.2) ; v3(97.33,181.19) U22.AY25 ; v3(82.33,160.2) U22.Y40 ; v3(103.33,159.2) 103.31,159.2 102.83,159.68 U22.W20 ; U22.B42 80.83,142.7 v3(81.33,143.2) ; U22.F41 v3(82.33,146.2) ; U22.AC39 v3(84.33,163.19) 84.83,163.69 U22.AC38 ; U22.J14 v3(109.33,149.2) ; U22.V21 v3(102.33,158.2) ; U22.Y21 v3(102.33,160.2) ; U22.AH17 v3(106.33,169.2) ; U22.U6 v3(117.33,158.2) ; v3(88.33,152.2) U22.M34 ; v3(91.33,155.2) U22.R31 ; U22.H18 v3(105.33,148.2) ; U22.BC30 v3(92.33,184.19) 92.33,184.2 U22.BD30 ; U22.BB27 v3(95.33,183.19) U22.BC28 v3(94.33,184.19) 94.83,184.69 U22.BD28 ; U22.AR6 v3(117.33,176.2) ; U22.D3 v3(120.33,144.19) ; U22.M13 v3(110.33,152.2) ; v3(99.33,167.19) U22.AF23 ; v3(93.33,145.2) U22.E29 ; v3(92.33,153.2) U22.N30 ; U22.AG8 v3(114.33,168.2) ; U22.AT15 v3(107.33,177.2) U22.AT16 ; U22.AB21 v3(102.33,162.2) ; U22.AD13 v3(110.33,165.2) U22.AD12 ; U22.AG36 86.83,167.69 v3(86.33,167.19) U22.AF36 ; U22.AK9 v3(113.33,171.2) U22.AL9 ; U22.AL33 v3(90.33,172.19) ; U22.AA16 v3(107.33,161.2) ; U22.H20 v3(103.33,148.2) ; U22.AA12 v3(111.33,161.2) ; U22.G14 v3(109.33,147.2) ; v3(80.33,145.2) 79.83,144.7 U22.D43 ; U22.AP6 v3(117.33,175.2) ; v3(95.33,147.2) U22.G27 ; U22.AK17 v3(106.33,171.2) ; U22.C9 v3(114.33,143.2) ; U22.AG14 v3(109.33,168.2) ; v3(96.33,149.2) U22.J26 ; U22.AD10 v3(112.33,165.2) U22.AD11 ; U22.AK22 v3(101.33,171.2) ; U22.AE18 v3(105.33,166.2) ; U22.U14 v3(109.33,157.2) ; v3(99.33,169.19) U22.AH23 ; v3(97.33,162.2) U22.AB25 ; U22.AU21 v3(102.33,178.2) ; v3(107.33,163.19) U22.AC16 ; C153.1 v2(169.04,179.07) ; v3(96.33,148.2) U22.H26 ; U22.BB12 v3(111.33,183.2) ; U22.BB33 v3(89.33,182.19) ; v3(96.33,185.19) U22.BD26 ; U22.AU33 v3(89.33,178.19) U22.AV34 v3(88.33,179.19) ; U22.AW6 v3(117.33,180.2) ; U22.AB42 v3(81.33,163.19) U22.AC42 ; v3(85.33,159.2) U22.W37 ; U22.AY21 v3(102.33,181.2) ; U22.BC20 v3(103.33,184.2) ; U22.AJ6 v3(116.33,170.2) ; U22.AG39 v3(83.33,168.19) ; U22.P6 v3(117.33,154.2) ; v3(91.33,147.2) U22.G31 ; U22.AJ5 v3(118.33,170.2) ; U22.AT11 v3(112.33,177.2) ; U22.E20 v3(103.33,145.2) ; U22.AL6 v3(116.33,172.2) ; v3(98.33,145.2) U22.E24 ; U22.AA35 87.33,162.19 v3(87.33,162.2) U22.AB35 ; v3(96.33,151.2) U22.L26 ; U22.AW14 v3(109.33,180.2) ; U22.E22 v3(101.33,145.2) ; U22.P9 113.83,154.7 v3(114.33,154.2) U22.N9 ; v3(95.33,155.2) U22.R27 ; U22.AJ18 v3(105.33,170.2) ; U22.V9 v3(114.33,158.2) ; U22.AU10 v3(112.33,178.2) ; U22.AG20 v3(103.33,168.2) ; v3(95.33,158.2) U22.V27 ; v3(99.33,158.2) U22.V23 ; v3(98.33,181.19) U22.AY24 ; U22.Y9 v3(114.33,161.2) ; v3(96.33,184.19) U22.BC26 v3(97.33,183.19) U22.BB25 ; U22.C7 v3(116.33,143.2) ; U22.U33 v3(90.33,157.2) ; v3(117.33,160.2) U22.Y6 116.97,160.83 116.97,161.56 U22.AA6 ; U22.BB14 v3(109.33,183.2) ; v3(94.33,157.2) U22.U28 ; U22.AJ20 v3(103.33,170.2) ; U22.AB14 v3(109.33,163.19) U22.AC14 ; U22.B13 v3(109.33,143.2) U22.C14 ; U22.C8 v3(115.33,143.2) ; v3(96.33,181.19) U22.AY26 ; U22.V19 v3(104.33,158.2) ; U22.AT5 v3(118.33,177.2) ; U22.AH14 v3(109.33,169.2) ; U22.AT36 v3(86.33,177.19) ; U22.BB21 v3(102.33,183.2) ; U22.AT34 v3(88.33,177.19) ; v3(109.33,174.2) U22.AP14 v3(108.33,174.2) ; U22.B15 v3(108.33,142.2) ; U22.AM33 v3(90.33,173.19) ; U22.E3 v3(120.33,145.2) ; U22.BB11 v3(112.33,183.2) ; v3(88.33,183.19) U22.BB35 ; v3(96.33,159.2) U22.W26 ; U22.N6 v3(116.33,153.2) ; v3(97.33,165.19) U22.AD25 ; C192.2 v2(125.72,169.04) ; U22.T6 v3(117.33,157.2) ; U22.V12 v3(111.33,158.2) ; v3(98.33,155.2) U22.R24 ; U22.B21 v3(102.33,142.2) ; U22.AG33 v3(89.33,168.19) ; U22.AJ9 v3(113.33,170.2) ; U22.AT14 v3(109.33,177.2) ; U22.C4 v3(119.33,143.2) ; U22.E15 v3(108.33,145.2) ; U22.AR17 v3(106.33,176.2) ; U22.G17 v3(106.33,147.2) ; U22.AE16 v3(107.33,166.2) ; U22.AJ14 v3(109.33,170.2) ; U22.AK38 v3(84.33,171.19) ; v3(96.33,179.19) U22.AV26 ; U22.BB6 v3(117.33,183.2) ; R307.1 v2(114.05,130.49) ; U22.AT10 v3(113.33,177.2) ; U22.BB4 v3(118.33,183.2) U22.BB5 ; U22.BB15 v3(108.33,183.2) ; v3(96.33,168.19) U22.AG26 ; v3(97.33,182.19) U22.BA25 ; v3(94.33,153.2) U22.N28 ; v3(94.33,168.19) U22.AG28 ; U22.AJ3 v3(119.33,169.2) ; U22.AJ39 v3(83.33,170.19) ; v3(99.33,181.19) U22.AY23 ; U22.BB8 v3(115.33,183.2) ; U22.W3 119.91,159.61 119.91,158.78 U22.V3 v3(120.33,158.2) ; U22.AA24 v3(98.33,161.2) ; U22.A21 v3(102.33,141.2) ; U22.AW22 v3(101.33,180.2) ; U22.AG18 v3(105.33,168.2) ; v3(99.33,145.2) U22.E23 ; v3(98.33,168.19) U22.AG24 ; U22.A19 v3(104.33,141.2) ; U22.AG22 v3(101.33,168.2) ; U22.AA22 v3(101.33,161.2) ; v3(90.33,149.2) U22.J32 ; U22.W18 v3(105.33,159.2) ; U22.B19 v3(104.33,142.2) ; U22.AA13 v3(110.33,161.2) ; U22.L11 v3(111.33,151.2) ; U22.M17 v3(106.33,152.2) ; R232.2 v2(74.19,172.72) ; v3(86.33,160.2) U22.Y36 ; v3(96.33,143.2) U22.C26 ; U22.AR9 v3(114.33,176.2) ; U22.B14 v3(109.33,142.2) ; U22.AW5 v3(118.33,180.2) U22.AW4 ; v3(94.33,166.19) U22.AE28 ; U22.AM6 v3(116.33,173.2) ; v3(98.33,157.2) U22.U24 ; U22.F8 v3(115.33,146.2) ; v3(114.33,152.2) 113.83,152.7 U22.M9 ; v3(80.33,148.2) 79.83,147.7 U22.G43 ; U22.E21 v3(102.33,145.2) ; v3(93.33,175.19) U22.AP29 ; U22.D9 v3(114.33,145.2) ; U22.AJ35 v3(87.33,170.19) ; v3(93.33,160.2) U22.Y29 ; v3(88.33,144.2) U22.D34 ; U22.W22 v3(101.33,159.2) ; U22.C20 v3(103.33,143.2) ; U22.L39 v3(84.33,151.2) ; U22.AM9 v3(113.33,173.2) ; v3(91.33,182.19) U22.BA31 ; U22.AV28 v3(95.33,178.19) U22.AU27 ; v3(80.33,171.19) U22.AK42 ; U22.AM36 v3(86.33,173.19) ; U22.AJ36 v3(86.33,170.19) ; U22.BA3 v3(120.33,182.2) ; v3(95.33,169.19) U22.AH27 ; U22.AF21 v3(102.33,167.2) ; C3898.2 v2(61.21,35.07) ; U22.AY22 v3(101.33,181.2) ; v3(99.33,155.2) U22.R23 ; U22.AH3 v3(119.33,168.2) ; U22.G3 v3(120.33,147.2) ; v3(97.33,160.2) U22.Y25 ; v3(93.33,165.19) U22.AD29 ; U22.BD32 v3(90.33,184.19) U22.BC32 ; v3(97.33,178.19) U22.AU25 ; U22.AD19 v3(104.33,165.2) ; U22.T10 v3(113.33,156.2) ; U22.J13 v3(110.33,149.2) ; U22.AK39 v3(83.33,171.19) ; U22.AL12 v3(110.33,172.2) ; U22.BA19 v3(103.33,181.2) U22.AY20 ; U22.AN12 v3(110.33,174.2) ; C218.2 125.73,158.63 v2(125.73,159.26) ; U22.D22 v3(101.33,144.2) ; U22.BB3 v3(119.33,183.2) ; v3(95.33,145.2) U22.E27 ; U22.E11 v3(112.33,146.2) ; v3(98.33,148.2) U22.H24 ; U22.L3 v3(120.33,152.2) ; U22.AF19 v3(104.33,167.2) ; U22.AY3 v3(119.33,180.2) ; U22.AC26 v3(96.33,163.2) ; v2(126.49,152.86) 126.42,152.78 R264.1 ; v3(84.33,160.2) U22.Y38 ; U22.D20 v3(103.33,144.2) ; v3(93.33,169.19) U22.AH29 ; C165.2 v2(125.72,179.02) ; v3(99.33,146.2) U22.F23 ; R308.1 v2(115.11,130.49) ; U22.F15 v3(108.33,146.2) ; U22.BD20 v3(103.33,185.2) ; U22.AB34 v3(89.33,162.2) ; v3(98.33,143.2) U22.C24 ; v3(91.33,151.2) U22.L31 ; U22.AB23 v3(99.33,162.2) ; U22.K14 v3(109.33,150.2) ; U22.AW9 v3(114.33,180.2) ; R322.1 v2(115.06,127.7) ; U22.AW8 v3(115.33,180.2) ; v3(96.33,153.2) U22.N26 ; U22.AW24 v3(98.33,180.19) ; U22.BB36 v3(87.33,183.19) ; R218.2 v2(125.73,177.55) ; U22.C6 v3(117.33,143.2) ; U22.T17 v3(106.33,156.2) ; v3(92.33,148.2) U22.H30 ; U22.AD42 v3(81.33,165.19) ; v3(94.33,148.2) U22.H28 ; R309.2 v2(116.08,130.49) ; U22.AB17 v3(106.33,162.2) ; J105.10 v2(14.04,66.35) ; U22.B17 v3(106.33,142.2) ; U22.AG11 v3(111.33,168.2) ; U22.AN39 v3(83.33,174.19) ; U22.Y14 v3(109.33,160.2) ; U22.C3 v3(120.33,143.2) ; v3(94.33,171.19) U22.AK28 ; v3(85.33,156.2) U22.T37 ; U22.L19 v3(104.33,151.2) ; U22.BB38 v3(85.33,183.19) ; U22.AT13 v3(110.33,177.2) ; U22.AK37 v3(85.33,171.19) ; v3(91.33,165.19) U22.AD31 ; R320.2 v2(113.25,127.7) ; U22.AG42 v3(80.33,168.19) ; v3(95.33,177.19) U22.AT27 ; U22.A17 v3(106.33,141.2) ; v3(93.33,158.2) U22.V29 ; U22.N3 v3(119.33,153.2) 119.83,152.7 U22.M3 ; U22.C18 v3(105.33,143.2) ; 119.83,163.69 U22.AC3 U22.AD3 ; v3(89.33,150.2) U22.K33 ; U22.AB32 v3(90.33,162.2) ; v3(87.33,160.2) U22.Y35 ; v3(93.33,147.2) U22.G29 ; v3(96.33,171.19) U22.AK26 ; U22.BB9 v3(114.33,183.2) ; U22.U20 v3(103.33,157.2) ; U22.AE22 v3(101.33,166.2) ; v3(83.33,160.2) U22.Y39 ; U22.AT9 v3(114.33,177.2) ; v3(91.33,148.2) U22.H31 ; v3(93.33,162.2) U22.AB29 ; U22.AK40 v3(82.33,171.19) ; U22.G6 v3(117.33,147.2) ; U22.W13 v3(110.33,159.2) ; U22.AV42 v3(80.33,179.19) ; U22.AV10 v3(112.33,179.2) ; v3(91.33,157.2) U22.U31 ; U22.Y19 v3(104.33,160.2) ; U22.BB7 v3(116.33,183.2) ; U22.AM39 v3(83.33,173.19) ; U22.AP33 v3(90.33,175.19) ; v3(91.33,158.2) U22.V31 ; U22.U18 v3(105.33,157.2) ; v3(91.33,160.2) U22.Y31
  TOP w0.508: 8.58,117.96 J9.19 ; J9.19 10.57,117.96 ; J9.19 8.58,115.98 ; J9.19 10.57,115.98 ; 3.57,7.16 SW6.3 ; SW6.3 5.45,7.16 ; SW6.3 3.57,5.28 ; SW6.3 5.45,5.28 ; v3(83.33,154.2) U22.P39 ; J16.20C v2(240.18,40.23) ; C346.2 v2(84.45,70.99) ; v2(169.16,174.12) 169.16,174.88 169.38,175.09 C170.2 169.8,174.84 v2(169.8,174.12) ; v2(40.45,232.8) C1256.2 40.25,234.01 v2(39.57,234.01) ; J16.11C v2(247.38,40.23) ; C190.2 v2(169.04,169.42) ; 246.98,224.41 v2(246.98,225.11) ; v3(89.33,146.2) U22.F33 ; v3(95.33,141.2) U22.A27 ; 49.35,80.14 49.42,80.07 Y19.4 50.33,79.08 50.24,78.99 ; 49.35,80.14 v3(49.35,81.09) v3(49.35,82.04) 49.86,82.55 v3(50.62,82.55) 51.38,82.55 ; 49.35,80.14 49.35,79.38 49.73,78.99 50.24,78.99 ; J9.18 10.57,111.77 ; J9.18 8.58,111.77 ; J9.18 8.58,113.76 ; J9.18 10.57,113.76 ; U55.B18 v2(218.84,212.65) ; U22.AW35 v3(88.33,180.19) ; U22.AC8 v3(114.33,163.2) 114.33,163.19 U22.AB8 ; 21.43,118.92 CT31.2 ; CT31.2 21.43,120.6 ; CT31.2 23.11,120.6 ; CT31.2 23.11,118.92 ; C5255.1 183.63,50.66 v2(184.15,51.18) v2(185.67,51.18) 187.45,51.18 v2(187.96,50.67) v2(187.96,48.64) 187.96,46.74 v2(187.45,46.23) 187.32,46.1 v2(185.42,46.1) v2(184.18,46.1) C5254.1 ; U55.B32 v2(218.84,198.65) ; 42.79,250.38 FAN3.1 42.79,248.27 ; U22.BB40 v3(83.33,183.19) ; v2(203.96,32.33) 203.96,31.62 203.54,31.2 FB71.1 203.49,31.2 203.07,31.62 203.07,32.34 v2(203.08,32.35) ; U55.A23 224.41,207.65 v2(224.69,207.92) ; SW6.2 11.02,4.48 ; SW6.2 11.02,2.96 ; SW6.2 9.5,4.48 ; SW6.2 9.5,2.96 ; v2(145.41,187.32) C141.2 ; R146.1 v2(214.06,220.09) ; v2(93.73,190.7) 94.23,191.21 R180.2 ; 186.48,228.35 C5338.2 ; C5338.2 188.17,230.04 ; C5338.2 188.17,228.35 ; C5338.2 186.48,230.04 ; J9.7 5.07,115.98 ; J9.7 3.08,117.96 ; J9.7 5.07,117.96 ; J9.7 3.08,115.98 ; v3(83.33,148.2) U22.H39 ; U55.B25 v2(218.84,205.65) ; C1257.1 v2(40.71,237.39) ; 3.18,175.47 J8.4 ; J8.4 3.18,173.68 ; J8.4 4.97,173.68 ; J8.4 4.97,175.47 ; J9.5 5.07,109.56 ; J9.5 5.07,107.58 ; J9.5 3.08,109.56 ; J9.5 3.08,107.58 ; 190.8,242.83 C5339.2 ; C5339.2 192.48,244.51 ; C5339.2 192.48,242.83 ; C5339.2 190.8,244.51 ; v2(51.69,118.99) 51.69,118.99 C296.2 ; v2(157.61,159.77) 157.61,159.77 C215.2 ; U628.3 v2(45.4,44.8) ; 207.06,242.83 C5337.2 ; C5337.2 208.74,244.51 ; C5337.2 207.06,244.51 ; C5337.2 208.74,242.83 ; v3(89.33,167.19) U22.AF33 ; C5299.2 164.9,35.76 v2(164.63,36.03) ; v2(112.13,137.67) 112.13,138.3 C258.2 ; C518.2 v2(29.82,9.68) ; SW6.4 12.45,7.16 ; SW6.4 10.57,7.16 ; SW6.4 10.57,5.28 ; SW6.4 12.45,5.28 ; J16.1C 240.58,32.58 v2(240.13,32.13) ; v3(98.33,152.2) U22.M24 ; C3847.2 v2(281.14,77.84) ; v3(81.33,155.2) U22.R41 ; v2(156.34,190.75) C117.2 ; U22.AM42 v3(80.33,173.19) U22.AN42 ; 2.88,163.19 J8.1 ; J8.1 5.27,163.19 ; J8.1 5.27,160.8 ; J8.1 2.88,160.8 ; v2(145.41,188.21) C130.1 ; 73.12,247.83 C5289.2 ; C5289.2 74.81,247.83 ; C5289.2 74.81,246.15 ; C5289.2 73.12,246.15 ; U22.BD34 88.83,184.99 v2(89.43,185.6) ; v3(96.33,144.2) U22.D26 ; 115.85,246.15 C5283.2 ; C5283.2 115.85,247.83 ; C5283.2 117.53,247.83 ; C5283.2 117.53,246.15 ; C1144.2 v2(200.71,54.32) ; U55.A28 224.6,202.65 v2(225.07,202.18) ; v2(39.34,234.77) 39.94,234.77 40.45,235.28 C1252.2 40.45,235.57 39.98,236.04 v2(39.4,236.04) ; 8.58,107.58 J9.17 ; J9.17 10.57,109.56 ; J9.17 8.58,109.56 ; J9.17 10.57,107.58 ; J8.3 4.97,171.27 ; J8.3 3.18,171.27 ; J8.3 4.97,169.48 ; J8.3 3.18,169.48 ; R5820.2 v2(201.29,115.62) ; v3(94.33,144.2) U22.D28 ; U589.1 v2(250.56,195.33) ; 10.9,248.27 FAN5.1 10.9,250.38 ; C5256.2 v4(156.59,58.93) ; U22.AH9 v3(113.33,169.2) ; C5300.2 v2(187.31,35.42) ; U55.A24 224.72,206.65 v2(225.09,206.27) ; J16.1B 226.33,32.4 v2(225.93,32) ; v3(97.33,146.2) U22.F25 ; v2(156.34,187.21) C137.2 ; 8.58,99.18 J9.15 ; J9.15 10.57,99.18 ; J9.15 10.57,101.16 ; J9.15 8.58,101.16 ; v2(118.67,34.92) 119.17,35.42 C5294.2 ; 64.7,248.27 FAN4.1 64.7,250.38 ; 66.19,144.02 C250.2 ; 66.19,144.02 66.22,144.02 66.95,144.75 v2(67.67,144.75) ; 66.19,144.02 66.9,143.31 v2(67.74,143.31) ; v3(93.33,141.2) U22.A29 ; v3(94.33,154.2) U22.P28 ; v2(126.44,149.99) 126.19,149.73 R269.1 ; v3(92.33,179.19) 92.33,179.2 U22.AW30 ; v2(105.54,189.29) 106.11,189.29 C128.2 ; C5340.2 21.65,144.4 ; C5340.2 19.97,144.4 ; C5340.2 21.65,146.08 ; C5340.2 19.97,146.08 ; 3.18,165.29 J8.2 ; J8.2 3.18,167.08 ; J8.2 4.97,165.29 ; J8.2 4.97,167.08 ; 144.82,248.27 FAN2.1 144.82,250.38 ; U22.AN6 v3(116.33,174.2) ; Y19.2 51.43,82.51 51.38,82.55 ; C3857.2 v2(131.45,90.98) ; 19.55,132.41 CT28.2 ; CT28.2 19.55,130.73 ; CT28.2 21.23,130.73 ; CT28.2 21.23,132.41 ; C42.2 v2(146.52,230.89) ; 3.08,99.18 J9.3 ; J9.3 5.07,99.18 ; J9.3 5.07,101.16 ; J9.3 3.08,101.16 ; U629.3 v2(35.37,44.8) ; v2(224.87,211.51) 224.87,211.16 224.36,210.65 U55.A20 ; C1147.2 v2(272.31,55.11) ; C246.2 125.72,146.43 v2(125.72,145.8) ; v2(166.69,170.81) R234.2 ; J9.24 10.57,138.96 ; J9.24 10.57,136.98 ; J9.24 8.58,138.96 ; J9.24 8.58,136.98 ; 51.38,82.55 51.89,82.55 v3(52.13,82.31) C3690.2 ; v3(101.33,163.19) U22.AC22 ; C2705.2 v2(59.98,40.38) ; v3(116.33,163.2) U22.AC6 ; U55.A4 v2(224.6,228.65) ; v3(94.33,152.2) U22.M28 ; R796.2 v2(83.44,125.67) ; v3(98.33,144.2) U22.D24 ; R124.2 v2(228.54,227.97) ; R5698.2 v2(251.23,219.64) ; J16.10D v2(262.03,31.98) ; R5721.2 v2(106.02,111.76) ; U22.BC30 U22.BB31 ; v3(99.33,165.19) U22.AD23 ; v3(80.33,180.19) U22.AW42 ; 50.24,78.99 v3(51.31,78.99) 51.57,78.99 51.96,78.61 C3691.2 ; C220.2 v2(169.04,156.97) ; R5897.2 58.8,85.9 v2(59.08,86.18) ; v3(97.33,142.2) U22.B25 ; C205.2 127.08,164.24 126.75,164.57 v2(126.75,164.97) ; v3(84.33,147.2) 83.83,146.7 U22.F39 ; C3866.2 v2(115.27,80.54) ; v3(99.33,160.2) U22.Y23 ; C5184.2 v4(139.45,42.42) ; v2(169.67,109.88) 169.67,110.41 169.29,110.79 C148.2 168.73,110.79 168.33,110.39 v2(168.33,109.86) ; C106.1 156.35,193.67 v2(156.26,193.58) ; J16.17A v2(214.08,40.23) ; 144.69,166.23 144.97,165.95 v2(144.97,165.48) ; 144.69,166.23 C199.2 ; 144.69,166.23 144.34,165.87 v2(144.34,165.48) ; U26.4 v2(90.09,134.32) ; 194.99,52.9 FAN1.1 197.09,52.9 ; v3(86.33,180.19) U22.AW36 ; v2(270.36,32.38) 270.36,31.62 270.78,31.2 FB70.1 271.25,31.66 v2(271.25,32.41) ; U55.A12 v2(224.6,218.65) ; U55.B26 v2(218.84,204.65) ; C265.2 112.13,135.76 v2(112.13,135.13) ; C5298.2 v2(162.92,36.11) ; U22.AW32 v3(90.33,180.19) U22.AY33 v3(89.33,181.19) U22.BA34 v3(89.33,182.19) ; U55.B13 v2(218.84,217.65) ; U22.BA33 v3(90.33,181.19) U22.AY32 U22.AY31 ; v3(81.33,158.2) U22.V41 ; Q13.2 15.23,109.33 R748.2 v2(15.37,110.34) ; v2(156.34,169.93) 156.34,169.93 C186.2 ; R267.1 v2(126.44,150.62) ; J16.20A v2(211.68,40.23) ; R5769.2 56.03,85.66 v2(56.38,86) ; CN3.6 v2(86.52,34.38) ; U55.A18 v2(224.6,212.65) ; U22.AU42 v3(81.34,178.19) U22.AU41 ; v3(97.33,153.2) U22.N25 ; Q6.2 269.61,24.83 v2(270.31,25.53) ; v3(99.33,183.19) U22.BB23 ; U55.A27 224.5,203.65 v2(224.71,203.86) ; U250.4 v2(37.67,55.6) ; J10.4 v2(21.2,49.02) ; J16.20B v2(225.93,40.23) ; v2(145.41,170.13) 145.59,170.31 C187.1 ; J10.7 v2(21.11,52.83) ; C252.2 64.64,139.47 v2(65.02,139.09) ; J16.14C v2(244.98,40.23) ; v3(92.33,180.19) 92.33,180.2 U22.AY30 ; v2(157.61,163.31) 157.61,163.31 C208.2 ; v2(170.43,163.45) 169.74,163.45 C207.1 169.74,162.69 v2(170.43,162.69) ; R5818.2 197.5,96.53 v2(197.31,96.34) ; v2(211.63,32.13) 212.08,32.58 J16.1A ; v2(88.52,192.05) 88.75,191.82 R177.2 ; C523.2 v2(26.53,11.21) ; R5816.2 199.53,96.58 v2(199.73,96.38) ; C3848.2 v2(246.09,215.01) ; v3(85.33,144.2) U22.D37 ; v2(93.22,133.27) 93.22,132.58 C274.2 ; v3(98.33,184.19) U22.BC24 ; C125.1 v2(182.37,193.67) ; J16.1D 254.83,32.58 v2(254.38,32.13) ; v3(113.33,166.2) U22.AF9 ; v3(81.33,149.2) U22.J41 ; v3(81.33,152.2) U22.M41 ; v3(92.33,144.2) U22.D30 ; v2(92.84,34.01) 93.17,33.68 CN3.3 ; J16.11D v2(261.63,40.23) ; C1141.2 v2(201.4,49.4) ; U55.B21 v2(218.84,209.65) ; J16.17D v2(256.83,40.23) ; v2(218.69,228.5) 218.85,228.65 U55.B4 ; C297.2 v2(169.05,118) ; 21.07,93.81 CT35.2 ; CT35.2 22.76,92.12 ; CT35.2 21.07,92.12 ; CT35.2 22.76,93.81 ; v2(88.32,36.5) 88.69,36.5 C485.2 ; C1150.2 v2(272.31,49.39) ; U55.A1 v2(224.6,231.65) ; v2(145.29,182.75) 145.29,183.03 144.69,183.63 C151.2 144.65,183.86 v2(144.65,182.75) ; C5197.2 v4(113.3,39.12) ; R5832.2 v2(185.24,100.35) ; C102.2 157.61,194.83 v2(157.61,194.83) ; C216.2 v2(169.04,160.02) ; C259.2 112.13,137.03 v2(112.13,136.4) ; U55.B7 v2(218.84,225.65) ; C163.2 v2(145.41,180.59) ; C189.1 v2(145.41,169.42) ; C104.1 146.06,194.44 146.57,194.95 v2(146.9,194.95) ; C5297.2 v2(143.77,35.42) ; v2(157.61,155.2) C240.2 ; C519.2 v2(32.87,18.01) ; C197.2 v2(169.04,167.13) ; U589.2 v2(250.56,196.6) ; U22.AT39 v3(83.33,177.19) U22.AU39 ; v3(99.33,147.2) U22.G23 ; R310.2 v2(80.89,132.54) ; R5837.2 v2(200.77,96.33) ; R5701.2 v2(240.56,220.29) ; U55.A15 v2(224.6,215.65) ; Q5.2 v2(272.53,25.39) ; J16.11A v2(218.88,40.23) ; R5831.2 v2(180.49,101.09) ; R200.1 v2(119.63,189.93) ; R181.2 108.58,191.36 v2(109.03,190.92) ; U22.AP42 v3(80.33,175.19) U22.AR42 ; U22.E19 v3(104.33,145.2) ; R5702.2 v2(240.56,218.82) ; C303.2 v2(167.64,110.74) ; U625.4 v2(250.52,192.66) ; C201.1 v2(169.04,165.61) ; R5829.2 v2(183.95,81.78) ; v3(97.33,141.2) U22.A25 ; U22.AW34 v3(89.33,179.19) ; v3(96.33,152.2) U22.M26 ; R5819.2 v2(197.32,115.65) ; R5770.2 v2(57.35,86) ; U22.AB33 v3(90.33,162.2) ; C505.2 v2(43.5,51.5) ; U22.W33 v3(89.33,159.2) 88.83,158.7 U22.V34 ; U55.B29 v2(218.8,201.65) ; R5830.2 v2(180.67,81.8) ; v2(200.13,32.28) 200.13,31.63 FB72.1 200.59,31.2 201.02,31.62 v2(201.02,32.33) ; U55.A31 v2(224.6,199.65) ; C164.2 v2(145.41,179.71) ; J16.10B v2(233.53,31.98) ; C5174.1 v2(142.02,46.1) v2(143.26,46.1) 145.16,46.1 v2(145.29,46.23) 145.8,46.74 v2(145.8,48.64) v2(145.8,50.67) 145.29,51.18 v2(143.51,51.18) v2(141.99,51.18) 141.47,50.66 C5175.1 ; v3(82.33,180.19) U22.AW40 ; U55.B16 v2(218.84,214.65) ; J16.10C v2(247.78,31.98) ; v3(81.33,183.19) U22.BB42 ; v3(86.33,146.2) U22.F36 ; C172.2 v2(41.91,176.02) ; J16.10A v2(219.28,31.98) ; C171.2 v2(228.35,229.13) ; U589.3 v2(250.56,197.87) ; J16.17B v2(228.33,40.23) ; v3(91.33,146.2) U22.F31 ; C89.1 v2(31.16,197.74) ; v2(143.64,175.83) 144.37,175.83 C169.1 144.37,175.2 v2(143.64,175.2) ; v3(85.33,153.2) U22.N37 ; C5301.2 v2(185.57,35.42) ; J16.20D v2(254.43,40.23) ; v2(91.5,133.41) 92.33,132.59 C273.2 ; U22.BB41 v3(82.33,183.19) ; v3(89.33,180.19) U22.AY34 ; v2(41.91,170.18) C185.2 ; J16.11B v2(233.13,40.23) ; R199.1 v2(118.62,189.93) ; C299.2 v2(16.84,114.3) ; C5295.2 v2(120.69,35.42) ; C5258.2 v4(155.46,39.12) ; U22.BB39 v3(84.33,183.19) ; v2(156.34,176.79) C167.1 ; v3(84.33,182.19) U22.BA38 ; 22.01,248.27 FAN12.1 22.01,250.38 ; U55.B22 v2(218.83,208.65) ; J16.17C v2(242.58,40.23) ; U589.4 v2(250.56,199.14) ; v3(93.33,142.2) U22.B29 ; v3(95.33,146.2) U22.F27 ; C5257.2 v4(181.61,42.42) ; J16.14D v2(259.23,40.23) ; J16.14A v2(216.48,40.23) ; C276.2 v2(80.95,131.51) ; v3(84.33,181.19) U22.AY38 ; C129.2 v2(115.32,189.86) ; v2(157.61,174.49) C176.2 ; C472.2 v4(114.43,58.93) ; R5699.2 v2(251.23,221.23) ; J10.1 v2(21.2,45.21) ; J16.14B v2(230.73,40.23) ; v2(101.09,128.26) C280.2 ; C145.2 v2(228.65,230.76) ; v3(82.33,144.2) U22.D40 ; C158.1 v2(41.94,180.06) ; C28.2 v2(157.64,235.97) ; v3(95.33,142.2) U22.B27 ; C5296.2 v2(140.51,35.42)
  TOP w0.635: Q4.2 199.38,21.02 ; Q3.2 202.55,20.94
  TOP w0.914: BH10.1 117.43,209.45 ; BH10.1 113.7,213.18 ; BH10.1 113.7,209.45 ; BH10.1 117.43,213.18
  TOP w1.016: 2.87,22.13 H16.1 ; H16.1 9.13,22.13 ; H16.1 9.13,15.87 ; H16.1 2.87,15.87 ; H8.1 282.13,124.62 ; H8.1 282.13,130.88 ; H8.1 275.87,130.88 ; H8.1 275.87,124.62 ; 275.87,250.13 H3.1 ; H3.1 282.13,243.87 ; H3.1 282.13,250.13 ; H3.1 275.87,243.87 ; H6.1 178.69,171.9 ; H6.1 178.69,178.1 ; H6.1 172.5,178.1 ; H6.1 172.5,171.9
  L2_GND_1 w0.508: 164.07,194.42 J7.163 ; J7.163 165.23,195.58 ; J7.163 164.07,195.58 ; J7.163 165.23,194.42 ; 164.07,155.58 J7.199 ; J7.199 164.07,154.42 ; J7.199 165.23,154.42 ; J7.199 165.23,155.58 ; J7.23 161.43,214.42 ; J7.23 160.27,214.42 ; J7.23 160.27,215.58 ; J7.23 161.43,215.58 ; J5.5 47.33,233.58 ; J5.5 47.33,232.42 ; J5.5 46.17,233.58 ; J5.5 46.17,232.42 ; 3.18,173.68 J8.4 ; J8.4 4.97,175.47 ; J8.4 3.18,175.47 ; J8.4 4.97,173.68 ; 204.12,229.18 J3.A4 ; J3.A4 205.17,229.18 ; J3.A4 204.12,228.12 ; J3.A4 205.17,228.12 ; J3.A46 205.17,185.18 ; J3.A46 204.12,184.12 ; J3.A46 204.12,185.18 ; J3.A46 205.17,184.12 ; J5.95 47.33,139.58 ; J5.95 46.17,139.58 ; J5.95 46.17,138.42 ; J5.95 47.33,138.42 ; 204.12,202.12 J3.A28 ; J3.A28 205.17,202.12 ; J3.A28 204.12,203.18 ; J3.A28 205.17,203.18 ; J5.202 49.23,151.42 ; J5.202 48.07,152.58 ; J5.202 49.23,152.58 ; J5.202 48.07,151.42 ; 158.37,123.42 J7.110 ; J7.110 159.53,123.42 ; J7.110 158.37,124.58 ; J7.110 159.53,124.58 ; J14.1 181.33,13.46 ; J14.1 180.01,14.79 ; J14.1 181.33,14.79 ; J14.1 180.01,13.46 ; SW5.1 18.6,16.45 ; SW5.1 18.6,18.15 ; SW5.1 16.9,16.45 ; SW5.1 16.9,18.15 ; 148.87,201.42 J6.205 ; J6.205 150.03,201.42 ; J6.205 150.03,202.58 ; J6.205 148.87,202.58 ; 10.57,7.16 SW6.4 ; SW6.4 12.45,5.28 ; SW6.4 12.45,7.16 ; SW6.4 10.57,5.28 ; 44.27,153.42 J5.80 ; J5.80 45.43,154.58 ; J5.80 45.43,153.42 ; J5.80 44.27,154.58 ; J7.235 165.23,119.58 ; J7.235 165.23,118.42 ; J7.235 164.07,119.58 ; J7.235 164.07,118.42 ; 160.27,120.42 J7.113 ; J7.113 161.43,120.42 ; J7.113 161.43,121.58 ; J7.113 160.27,121.58 ; 150.77,135.58 J6.142 ; J6.142 151.93,134.42 ; J6.142 150.77,134.42 ; J6.142 151.93,135.58 ; J3.A24 205.17,207.18 ; J3.A24 204.12,206.12 ; J3.A24 204.12,207.18 ; J3.A24 205.17,206.12 ; 154.57,145.58 J6.32 ; J6.32 154.57,144.42 ; J6.32 155.73,145.58 ; J6.32 155.73,144.42 ; 154.57,197.58 J6.80 ; J6.80 154.57,196.42 ; J6.80 155.73,196.42 ; J6.80 155.73,197.58 ; 160.27,202.42 J7.35 ; J7.35 160.27,203.58 ; J7.35 161.43,202.42 ; J7.35 161.43,203.58 ; 199.62,226.18 J3.B7 ; J3.B7 200.67,226.18 ; J3.B7 200.67,225.12 ; J3.B7 199.62,225.12 ; J6.151 150.03,143.42 ; J6.151 148.87,143.42 ; J6.151 150.03,144.58 ; J6.151 148.87,144.58 ; 158.37,142.58 J7.92 ; J7.92 159.53,141.42 ; J7.92 159.53,142.58 ; J7.92 158.37,141.42 ; 44.27,130.58 J5.104 ; J5.104 44.27,129.42 ; J5.104 45.43,129.42 ; J5.104 45.43,130.58 ; J3.B18 198.67,212.12 ; J3.B18 197.62,212.12 ; J3.B18 197.62,213.18 ; J3.B18 198.67,213.18 ; J7.214 163.33,139.42 ; J7.214 163.33,140.58 ; J7.214 162.17,139.42 ; J7.214 162.17,140.58 ; J6.89 153.83,205.42 ; J6.89 153.83,206.58 ; J6.89 152.67,205.42 ; J6.89 152.67,206.58 ; 49.97,201.58 J5.157 ; J5.157 51.13,201.58 ; J5.157 51.13,200.42 ; J5.157 49.97,200.42 ; 46.17,202.42 J5.35 ; J5.35 47.33,203.58 ; J5.35 47.33,202.42 ; J5.35 46.17,203.58 ; 158.37,235.42 J7.2 ; J7.2 159.53,235.42 ; J7.2 158.37,236.58 ; J7.2 159.53,236.58 ; J5.38 45.43,200.58 ; J5.38 44.27,200.58 ; J5.38 44.27,199.42 ; J5.38 45.43,199.42 ; 44.27,118.58 J5.116 ; J5.116 44.27,117.42 ; J5.116 45.43,117.42 ; J5.116 45.43,118.58 ; 162.17,128.58 J7.226 ; J7.226 163.33,127.42 ; J7.226 162.17,127.42 ; J7.226 163.33,128.58 ; CT31.2 23.11,120.6 ; CT31.2 23.11,118.92 ; CT31.2 21.43,118.92 ; CT31.2 21.43,120.6 ; 73.12,247.83 C5289.2 ; C5289.2 74.81,246.15 ; C5289.2 73.12,246.15 ; C5289.2 74.81,247.83 ; 162.17,122.58 J7.232 ; J7.232 163.33,121.42 ; J7.232 163.33,122.58 ; J7.232 162.17,121.42 ; J9.7 5.07,117.96 ; J9.7 3.08,117.96 ; J9.7 5.07,115.98 ; J9.7 3.08,115.98 ; 44.27,218.58 J5.20 ; J5.20 44.27,217.42 ; J5.20 45.43,218.58 ; J5.20 45.43,217.42 ; 148.87,195.42 J6.199 ; J6.199 150.03,195.42 ; J6.199 150.03,196.58 ; J6.199 148.87,196.58 ; 202.12,186.18 J3.A45 ; J3.A45 202.12,185.12 ; J3.A45 203.17,185.12 ; J3.A45 203.17,186.18 ; J6.44 155.73,156.42 ; J6.44 154.57,156.42 ; J6.44 154.57,157.58 ; J6.44 155.73,157.58 ; J6.163 150.03,155.42 ; J6.163 148.87,155.42 ; J6.163 150.03,156.58 ; J6.163 148.87,156.58 ; 199.62,187.12 J3.B43 ; J3.B43 200.67,187.12 ; J3.B43 199.62,188.18 ; J3.B43 200.67,188.18 ; J5.110 45.43,124.58 ; J5.110 44.27,124.58 ; J5.110 44.27,123.42 ; J5.110 45.43,123.42 ; 204.12,210.12 J3.A20 ; J3.A20 205.17,210.12 ; J3.A20 204.12,211.18 ; J3.A20 205.17,211.18 ; 191.9,25.2 J14.20 ; J14.20 193.22,25.2 ; J14.20 191.9,23.88 ; 197.62,214.12 J3.B16 ; J3.B16 198.67,215.18 ; J3.B16 197.62,215.18 ; J3.B16 198.67,214.12 ; 154.57,114.42 J6.2 ; J6.2 155.73,115.58 ; J6.2 154.57,115.58 ; J6.2 155.73,114.42 ; 158.37,224.58 J7.14 ; J7.14 159.53,223.42 ; J7.14 159.53,224.58 ; J7.14 158.37,223.42 ; 42.82,11.28 CN4.B4 42.82,9.93 ; 148.87,131.42 J6.139 ; J6.139 150.03,131.42 ; J6.139 148.87,132.58 ; J6.139 150.03,132.58 ; 150.77,117.58 J6.124 ; J6.124 151.93,117.58 ; J6.124 150.77,116.42 ; J6.124 151.93,116.42 ; SW6.3 5.45,7.16 ; SW6.3 3.57,7.16 ; SW6.3 5.45,5.28 ; SW6.3 3.57,5.28 ; 162.17,192.58 J7.166 ; J7.166 163.33,191.42 ; J7.166 163.33,192.58 ; J7.166 162.17,191.42 ; 158.37,148.58 J7.86 ; J7.86 158.37,147.42 ; J7.86 159.53,147.42 ; J7.86 159.53,148.58 ; J5.83 47.33,151.58 ; J5.83 46.17,151.58 ; J5.83 46.17,150.42 ; J5.83 47.33,150.42 ; J6.117 153.83,233.42 ; J6.117 153.83,234.58 ; J6.117 152.67,233.42 ; J6.117 152.67,234.58 ; J6.47 153.83,160.58 ; J6.47 152.67,159.42 ; J6.47 153.83,159.42 ; J6.47 152.67,160.58 ; J3.A38 205.17,192.12 ; J3.A38 204.12,193.18 ; J3.A38 205.17,193.18 ; J3.A38 204.12,192.12 ; J6.20 155.73,133.58 ; J6.20 154.57,132.42 ; J6.20 154.57,133.58 ; J6.20 155.73,132.42 ; FAN3.1 42.53,248.53 ; FAN3.1 42.53,250.12 ; FAN3.1 40.94,250.12 ; FAN3.1 40.94,248.53 ; J7.17 161.43,221.58 ; J7.17 160.27,220.42 ; J7.17 160.27,221.58 ; J7.17 161.43,220.42 ; J3.B47 200.67,184.18 ; J3.B47 199.62,184.18 ; J3.B47 199.62,183.12 ; J3.B47 200.67,183.12 ; J7.26 159.53,212.58 ; J7.26 158.37,212.58 ; J7.26 158.37,211.42 ; J7.26 159.53,211.42 ; 8.58,101.16 J9.15 ; J9.15 10.57,99.18 ; J9.15 8.58,99.18 ; J9.15 10.57,101.16 ; J3.B40 198.67,191.18 ; J3.B40 197.62,190.12 ; J3.B40 198.67,190.12 ; J3.B40 197.62,191.18 ; J5.166 49.23,192.58 ; J5.166 49.23,191.42 ; J5.166 48.07,191.42 ; J5.166 48.07,192.58 ; 202.12,190.18 J3.A41 ; J3.A41 203.17,189.12 ; J3.A41 202.12,189.12 ; J3.A41 203.17,190.18 ; J6.235 150.03,232.58 ; J6.235 148.87,232.58 ; J6.235 148.87,231.42 ; J6.235 150.03,231.42 ; 49.97,194.42 J5.163 ; J5.163 49.97,195.58 ; J5.163 51.13,194.42 ; J5.163 51.13,195.58 ; J6.119 153.83,235.42 ; J6.119 152.67,236.58 ; J6.119 153.83,236.58 ; J6.119 152.67,235.42 ; 164.07,231.58 J7.127 ; J7.127 165.23,231.58 ; J7.127 164.07,230.42 ; J7.127 165.23,230.42 ; 19.97,146.08 C5340.2 ; C5340.2 21.65,144.4 ; C5340.2 19.97,144.4 ; C5340.2 21.65,146.08 ; 154.57,120.42 J6.8 ; J6.8 155.73,120.42 ; J6.8 154.57,121.58 ; J6.8 155.73,121.58 ; 164.07,206.42 J7.151 ; J7.151 165.23,207.58 ; J7.151 164.07,207.58 ; J7.151 165.23,206.42 ; 150.77,229.58 J6.232 ; J6.232 151.93,228.42 ; J6.232 150.77,228.42 ; J6.232 151.93,229.58 ; 186.48,230.04 C5338.2 ; C5338.2 188.17,230.04 ; C5338.2 186.48,228.35 ; C5338.2 188.17,228.35 ; 160.27,151.58 J7.83 ; J7.83 160.27,150.42 ; J7.83 161.43,150.42 ; J7.83 161.43,151.58 ; J9.17 10.57,107.58 ; J9.17 8.58,107.58 ; J9.17 8.58,109.56 ; J9.17 10.57,109.56 ; 152.67,123.42 J6.11 ; J6.11 152.67,124.58 ; J6.11 153.83,124.58 ; J6.11 153.83,123.42 ; J3.B26 198.67,204.12 ; J3.B26 197.62,204.12 ; J3.B26 197.62,205.18 ; J3.B26 198.67,205.18 ; 48.07,228.58 J5.130 ; J5.130 49.23,227.42 ; J5.130 49.23,228.58 ; J5.130 48.07,227.42 ; CT35.2 22.76,93.81 ; CT35.2 21.07,93.81 ; CT35.2 22.76,92.12 ; CT35.2 21.07,92.12 ; 243.71,247.01 244.43,246.3 ; 243.71,247.01 244.43,247.73 ; 243.71,247.01 243,247.73 ; 243.71,247.01 243,246.3 ; J5.121 51.13,236.42 ; J5.121 51.13,237.58 ; J5.121 49.97,237.58 ; J5.121 49.97,236.42 ; J5.32 45.43,205.42 ; J5.32 44.27,205.42 ; J5.32 44.27,206.58 ; J5.32 45.43,206.58 ; 204.12,219.18 J3.A12 ; J3.A12 205.17,219.18 ; J3.A12 205.17,218.12 ; J3.A12 204.12,218.12 ; 115.85,246.15 C5283.2 ; C5283.2 115.85,247.83 ; C5283.2 117.53,246.15 ; C5283.2 117.53,247.83 ; J6.92 155.73,208.42 ; J6.92 155.73,209.58 ; J6.92 154.57,208.42 ; J6.92 154.57,209.58 ; 127.95,239.97 J106.3 ; J106.3 129.2,241.22 ; J106.3 127.95,241.22 ; J106.3 129.2,239.97 ; J6.208 151.93,204.42 ; J6.208 150.77,204.42 ; J6.208 151.93,205.58 ; J6.208 150.77,205.58 ; J6.17 153.83,129.42 ; J6.17 152.67,130.58 ; J6.17 152.67,129.42 ; J6.17 153.83,130.58 ; 207.06,242.83 C5337.2 ; C5337.2 208.74,242.83 ; C5337.2 208.74,244.51 ; C5337.2 207.06,244.51 ; J6.130 151.93,122.42 ; J6.130 150.77,122.42 ; J6.130 151.93,123.58 ; J6.130 150.77,123.58 ; 162.17,198.58 J7.160 ; J7.160 163.33,198.58 ; J7.160 163.33,197.42 ; J7.160 162.17,197.42 ; 86.66,246.15 C5279.2 ; C5279.2 88.34,247.83 ; C5279.2 88.34,246.15 ; C5279.2 86.66,247.83 ; 48.07,139.42 J5.214 ; J5.214 49.23,140.58 ; J5.214 49.23,139.42 ; J5.214 48.07,140.58 ; 160.27,138.42 J7.95 ; J7.95 161.43,138.42 ; J7.95 161.43,139.58 ; J7.95 160.27,139.58 ; 202.12,232.18 J3.A1 ; J3.A1 202.12,231.12 ; J3.A1 203.17,231.12 ; J3.A1 203.17,232.18 ; 49.97,155.58 J5.199 ; J5.199 51.13,155.58 ; J5.199 51.13,154.42 ; J5.199 49.97,154.42 ; 164.07,149.58 J7.205 ; J7.205 165.23,148.42 ; J7.205 164.07,148.42 ; J7.205 165.23,149.58 ; 150.77,199.58 J6.202 ; J6.202 151.93,199.58 ; J6.202 151.93,198.42 ; J6.202 150.77,198.42 ; 48.07,216.58 J5.142 ; J5.142 48.07,215.42 ; J5.142 49.23,216.58 ; J5.142 49.23,215.42 ; J7.208 163.33,146.58 ; J7.208 163.33,145.42 ; J7.208 162.17,146.58 ; J7.208 162.17,145.42 ; 46.17,190.42 J5.47 ; J5.47 47.33,190.42 ; J5.47 46.17,191.58 ; J5.47 47.33,191.58 ; 197.62,228.12 J3.B4 ; J3.B4 198.67,229.18 ; J3.B4 198.67,228.12 ; J3.B4 197.62,229.18 ; 190.8,242.83 C5339.2 ; C5339.2 192.48,242.83 ; C5339.2 190.8,244.51 ; C5339.2 192.48,244.51 ; 49.97,225.58 J5.133 ; J5.133 51.13,225.58 ; J5.133 49.97,224.42 ; J5.133 51.13,224.42 ; J6.217 150.03,214.58 ; J6.217 148.87,213.42 ; J6.217 148.87,214.58 ; J6.217 150.03,213.42 ; 9.5,2.96 SW6.2 ; SW6.2 11.02,2.96 ; SW6.2 11.02,4.48 ; SW6.2 9.5,4.48 ; 126.59,25.2 J11.20 ; J11.20 126.59,23.88 ; J11.20 127.91,23.88 ; J11.20 127.91,25.2 ; J6.239 150.03,236.58 ; J6.239 148.87,235.42 ; J6.239 150.03,235.42 ; J6.239 148.87,236.58 ; 204.12,189.18 J3.A42 ; J3.A42 205.17,189.18 ; J3.A42 204.12,188.12 ; J3.A42 205.17,188.12 ; J6.226 151.93,222.42 ; J6.226 150.77,222.42 ; J6.226 150.77,223.58 ; J6.226 151.93,223.58 ; J3.A31 203.17,199.12 ; J3.A31 202.12,199.12 ; J3.A31 202.12,200.18 ; J3.A31 203.17,200.18 ; J6.86 155.73,203.58 ; J6.86 154.57,202.42 ; J6.86 155.73,202.42 ; J6.86 154.57,203.58 ; J6.38 155.73,150.42 ; J6.38 154.57,151.58 ; J6.38 155.73,151.58 ; J6.38 154.57,150.42 ; 152.67,117.42 J6.5 ; J6.5 153.83,117.42 ; J6.5 153.83,118.58 ; J6.5 152.67,118.58 ; 152.67,136.58 J6.23 ; J6.23 153.83,135.42 ; J6.23 152.67,135.42 ; J6.23 153.83,136.58 ; C5341.2 41.02,30.18 ; C5341.2 39.34,30.18 ; C5341.2 41.02,28.5 ; C5341.2 39.34,28.5 ; 202.12,208.18 J3.A23 ; J3.A23 203.17,208.18 ; J3.A23 203.17,207.12 ; J3.A23 202.12,207.12 ; J5.154 49.23,204.58 ; J5.154 48.07,204.58 ; J5.154 49.23,203.42 ; J5.154 48.07,203.42 ; 148.87,120.58 J6.127 ; J6.127 150.03,120.58 ; J6.127 150.03,119.42 ; J6.127 148.87,119.42 ; J5.239 51.13,114.42 ; J5.239 51.13,115.58 ; J5.239 49.97,115.58 ; J5.239 49.97,114.42 ; J7.107 161.43,127.58 ; J7.107 161.43,126.42 ; J7.107 160.27,126.42 ; J7.107 160.27,127.58 ; J5.139 51.13,218.42 ; J5.139 51.13,219.58 ; J5.139 49.97,219.58 ; J5.139 49.97,218.42 ; J3.A34 205.17,197.18 ; J3.A34 205.17,196.12 ; J3.A34 204.12,197.18 ; J3.A34 204.12,196.12 ; J6.154 151.93,146.42 ; J6.154 151.93,147.58 ; J6.154 150.77,146.42 ; J6.154 150.77,147.58 ; J6.160 151.93,153.58 ; J6.160 150.77,152.42 ; J6.160 150.77,153.58 ; J6.160 151.93,152.42 ; 164.07,212.42 J7.145 ; J7.145 165.23,212.42 ; J7.145 165.23,213.58 ; J7.145 164.07,213.58 ; 48.07,221.42 J5.136 ; J5.136 49.23,222.58 ; J5.136 48.07,222.58 ; J5.136 49.23,221.42 ; 237.92,247.73 J2.16 ; J2.16 239.35,246.3 ; J2.16 239.35,247.73 ; J2.16 237.92,246.3 ; J6.14 155.73,127.58 ; J6.14 154.57,126.42 ; J6.14 154.57,127.58 ; J6.14 155.73,126.42 ; 160.27,190.42 J7.47 ; J7.47 161.43,191.58 ; J7.47 161.43,190.42 ; J7.47 160.27,191.58 ; 44.27,193.42 J5.44 ; J5.44 45.43,193.42 ; J5.44 44.27,194.58 ; J5.44 45.43,194.58 ; 48.07,234.58 J5.124 ; J5.124 49.23,234.58 ; J5.124 49.23,233.42 ; J5.124 48.07,233.42 ; 164.07,219.58 J7.139 ; J7.139 165.23,219.58 ; J7.139 165.23,218.42 ; J7.139 164.07,218.42 ; J5.127 51.13,231.58 ; J5.127 49.97,231.58 ; J5.127 51.13,230.42 ; J5.127 49.97,230.42 ; 152.67,229.42 J6.113 ; J6.113 153.83,229.42 ; J6.113 152.67,230.58 ; J6.113 153.83,230.58 ; 46.17,127.58 J5.107 ; J5.107 47.33,127.58 ; J5.107 46.17,126.42 ; J5.107 47.33,126.42 ; J5.205 51.13,148.42 ; J5.205 49.97,148.42 ; J5.205 51.13,149.58 ; J5.205 49.97,149.58 ; J3.A37 203.17,194.18 ; J3.A37 202.12,193.12 ; J3.A37 203.17,193.12 ; J3.A37 202.12,194.18 ; J6.110 155.73,226.42 ; J6.110 154.57,227.58 ; J6.110 155.73,227.58 ; J6.110 154.57,226.42 ; J6.107 153.83,224.58 ; J6.107 153.83,223.42 ; J6.107 152.67,224.58 ; J6.107 152.67,223.42 ; J6.98 155.73,214.42 ; J6.98 154.57,215.58 ; J6.98 155.73,215.58 ; J6.98 154.57,214.42 ; 148.87,149.42 J6.157 ; J6.157 148.87,150.58 ; J6.157 150.03,150.58 ; J6.157 150.03,149.42 ; 199.62,202.18 J3.B29 ; J3.B29 200.67,201.12 ; J3.B29 199.62,201.12 ; J3.B29 200.67,202.18 ; 152.67,200.58 J6.83 ; J6.83 153.83,199.42 ; J6.83 153.83,200.58 ; J6.83 152.67,199.42 ; 162.17,228.58 J7.130 ; J7.130 162.17,227.42 ; J7.130 163.33,228.58 ; J7.130 163.33,227.42 ; J10.M2 22.77,43.74 ; J10.M2 20.8,43.74 ; J10.M2 20.8,41.77 ; J10.M2 22.77,41.77 ; J5.217 51.13,137.58 ; J5.217 49.97,137.58 ; J5.217 51.13,136.42 ; J5.217 49.97,136.42 ; 3.18,171.27 J8.3 ; J8.3 3.18,169.48 ; J8.3 4.97,169.48 ; J8.3 4.97,171.27 ; 199.62,195.12 J3.B35 ; J3.B35 200.67,196.18 ; J3.B35 200.67,195.12 ; J3.B35 199.62,196.18 ; 48.07,198.58 J5.160 ; J5.160 48.07,197.42 ; J5.160 49.23,197.42 ; J5.160 49.23,198.58 ; J5.117 47.33,116.42 ; J5.117 47.33,117.58 ; J5.117 46.17,116.42 ; J5.117 46.17,117.58 ; 148.87,126.58 J6.133 ; J6.133 150.03,126.58 ; J6.133 150.03,125.42 ; J6.133 148.87,125.42 ; J9.5 5.07,107.58 ; J9.5 3.08,109.56 ; J9.5 3.08,107.58 ; J9.5 5.07,109.56 ; 239.18,204.72 J4.2 240.63,204.72 ; J7.41 161.43,197.58 ; J7.41 160.27,196.42 ; J7.41 160.27,197.58 ; J7.41 161.43,196.42 ; J5.86 45.43,147.42 ; J5.86 44.27,147.42 ; J5.86 45.43,148.58 ; J5.86 44.27,148.58 ; 49.97,213.58 J5.145 ; J5.145 51.13,212.42 ; J5.145 51.13,213.58 ; J5.145 49.97,212.42 ; J6.41 153.83,153.42 ; J6.41 152.67,153.42 ; J6.41 152.67,154.58 ; J6.41 153.83,154.58 ; 150.77,140.42 J6.148 ; J6.148 151.93,140.42 ; J6.148 151.93,141.58 ; J6.148 150.77,141.58 ; 142.97,250.12 FAN2.1 ; FAN2.1 144.56,250.12 ; FAN2.1 144.56,248.53 ; FAN2.1 142.97,248.53 ; J5.235 51.13,118.42 ; J5.235 49.97,119.58 ; J5.235 49.97,118.42 ; J5.235 51.13,119.58 ; 195.24,51.05 FAN1.1 ; FAN1.1 196.84,52.65 ; FAN1.1 195.24,52.65 ; FAN1.1 196.84,51.05 ; J5.2 45.43,236.58 ; J5.2 44.27,236.58 ; J5.2 45.43,235.42 ; J5.2 44.27,235.42 ; J6.95 153.83,212.58 ; J6.95 152.67,212.58 ; J6.95 153.83,211.42 ; J6.95 152.67,211.42 ; 170.13,25.2 J13.20 ; J13.20 171.45,23.88 ; J13.20 170.13,23.88 ; J13.20 171.45,25.2 ; 46.17,220.42 J5.17 ; J5.17 46.17,221.58 ; J5.17 47.33,220.42 ; J5.17 47.33,221.58 ; J8.2 4.97,165.29 ; J8.2 4.97,167.08 ; J8.2 3.18,167.08 ; J8.2 3.18,165.29 ; 204.12,213.18 J3.A18 ; J3.A18 204.12,212.12 ; J3.A18 205.17,213.18 ; J3.A18 205.17,212.12 ; J7.202 163.33,151.42 ; J7.202 163.33,152.58 ; J7.202 162.17,152.58 ; J7.202 162.17,151.42 ; J5.29 47.33,208.42 ; J5.29 46.17,209.58 ; J5.29 46.17,208.42 ; J5.29 47.33,209.58 ; 199.62,205.12 J3.B25 ; J3.B25 199.62,206.18 ; J3.B25 200.67,205.12 ; J3.B25 200.67,206.18 ; J9.18 10.57,111.77 ; J9.18 8.58,111.77 ; J9.18 10.57,113.76 ; J9.18 8.58,113.76 ; 162.17,203.42 J7.154 ; J7.154 163.33,203.42 ; J7.154 163.33,204.58 ; J7.154 162.17,204.58 ; J7.104 159.53,130.58 ; J7.104 159.53,129.42 ; J7.104 158.37,130.58 ; J7.104 158.37,129.42 ; J5.232 49.23,122.58 ; J5.232 48.07,122.58 ; J5.232 49.23,121.42 ; J5.232 48.07,121.42 ; 150.77,217.58 J6.220 ; J6.220 151.93,216.42 ; J6.220 151.93,217.58 ; J6.220 150.77,216.42 ; 46.65,63.26 J69.5 ; J69.5 48.19,63.26 ; J69.5 46.65,64.8 ; J69.5 48.19,64.8 ; J7.223 165.23,131.58 ; J7.223 165.23,130.42 ; J7.223 164.07,131.58 ; J7.223 164.07,130.42 ; 150.77,210.42 J6.214 ; J6.214 150.77,211.58 ; J6.214 151.93,210.42 ; J6.214 151.93,211.58 ; 44.27,212.58 J5.26 ; J5.26 45.43,212.58 ; J5.26 45.43,211.42 ; J5.26 44.27,211.42 ; J5.92 45.43,142.58 ; J5.92 45.43,141.42 ; J5.92 44.27,142.58 ; J5.92 44.27,141.42 ; J6.223 150.03,219.42 ; J6.223 148.87,219.42 ; J6.223 148.87,220.58 ; J6.223 150.03,220.58 ; 154.57,221.58 J6.104 ; J6.104 155.73,221.58 ; J6.104 155.73,220.42 ; J6.104 154.57,220.42 ; 199.62,181.12 J3.B49 ; J3.B49 200.67,182.18 ; J3.B49 199.62,182.18 ; J5.23 47.33,214.42 ; J5.23 47.33,215.58 ; J5.23 46.17,214.42 ; J5.23 46.17,215.58 ; J3.B44 198.67,186.12 ; J3.B44 197.62,186.12 ; J3.B44 198.67,187.18 ; J3.B44 197.62,187.18 ; 152.67,147.42 J6.35 ; J6.35 153.83,148.58 ; J6.35 152.67,148.58 ; J6.35 153.83,147.42 ; 164.07,125.58 J7.229 ; J7.229 165.23,125.58 ; J7.229 164.07,124.42 ; J7.229 165.23,124.42 ; 8.58,115.98 J9.19 ; J9.19 10.57,115.98 ; J9.19 8.58,117.96 ; J9.19 10.57,117.96 ; 199.62,192.18 J3.B39 ; J3.B39 200.67,192.18 ; J3.B39 200.67,191.12 ; J3.B39 199.62,191.12 ; J6.229 150.03,226.58 ; J6.229 150.03,225.42 ; J6.229 148.87,226.58 ; J6.229 148.87,225.42 ; 197.62,195.18 J3.B36 ; J3.B36 198.67,195.18 ; J3.B36 198.67,194.12 ; J3.B36 197.62,194.12 ; J5.41 47.33,196.42 ; J5.41 46.17,197.58 ; J5.41 47.33,197.58 ; J5.41 46.17,196.42 ; C5342.2 22.77,30.18 ; C5342.2 22.77,28.5 ; C5342.2 21.08,30.18 ; C5342.2 21.08,28.5 ; J13.1 159.56,14.79 ; J13.1 158.24,13.46 ; J13.1 158.24,14.79 ; J13.1 159.56,13.46 ; 164.07,114.42 J7.239 ; J7.239 165.23,114.42 ; J7.239 165.23,115.58 ; J7.239 164.07,115.58 ; 158.37,206.58 J7.32 ; J7.32 159.53,206.58 ; J7.32 159.53,205.42 ; J7.32 158.37,205.42 ; J6.101 153.83,217.42 ; J6.101 152.67,217.42 ; J6.101 153.83,218.58 ; J6.101 152.67,218.58 ; 21.8,56.57 J10.M1 ; J10.M1 23.77,54.6 ; J10.M1 23.77,56.57 ; J10.M1 21.8,54.6 ; J9.3 5.07,101.16 ; J9.3 3.08,99.18 ; J9.3 5.07,99.18 ; J9.3 3.08,101.16 ; 158.37,217.42 J7.20 ; J7.20 158.37,218.58 ; J7.20 159.53,217.42 ; J7.20 159.53,218.58 ; 263.48,75.11 C5345.2 ; C5345.2 263.48,76.91 ; C5345.2 265.29,76.91 ; C5345.2 265.29,75.11 ; 162.17,234.58 J7.124 ; J7.124 162.17,233.42 ; J7.124 163.33,234.58 ; J7.124 163.33,233.42 ; J7.220 163.33,134.58 ; J7.220 162.17,134.58 ; J7.220 162.17,133.42 ; J7.220 163.33,133.42 ; 46.17,226.42 J5.11 ; J5.11 46.17,227.58 ; J5.11 47.33,227.58 ; J5.11 47.33,226.42 ; 202.12,204.18 J3.A27 ; J3.A27 203.17,204.18 ; J3.A27 203.17,203.12 ; J3.A27 202.12,203.12 ; J7.217 165.23,137.58 ; J7.217 164.07,136.42 ; J7.217 164.07,137.58 ; J7.217 165.23,136.42 ; 44.27,135.42 J5.98 ; J5.98 45.43,135.42 ; J5.98 44.27,136.58 ; J5.98 45.43,136.58 ; 148.87,114.58 J6.121 ; J6.121 148.87,113.42 ; J6.121 150.03,113.42 ; J6.121 150.03,114.58 ; 164.07,236.42 J7.121 ; J7.121 165.23,236.42 ; J7.121 165.23,237.58 ; J7.121 164.07,237.58 ; J106.10 127.2,247.22 ; J106.10 127.2,245.97 ; J106.10 125.95,247.22 ; J106.10 125.95,245.97 ; 48.07,128.58 J5.226 ; J5.226 49.23,128.58 ; J5.226 48.07,127.42 ; J5.226 49.23,127.42 ; J5.148 49.23,210.58 ; J5.148 49.23,209.42 ; J5.148 48.07,209.42 ; J5.148 48.07,210.58 ; J6.145 150.03,138.58 ; J6.145 148.87,137.42 ; J6.145 148.87,138.58 ; J6.145 150.03,137.42 ; 150.77,158.42 J6.166 ; J6.166 150.77,159.58 ; J6.166 151.93,158.42 ; J6.166 151.93,159.58 ; J5.223 51.13,131.58 ; J5.223 49.97,131.58 ; J5.223 49.97,130.42 ; J5.223 51.13,130.42 ; 49.97,124.42 J5.229 ; J5.229 51.13,125.58 ; J5.229 51.13,124.42 ; J5.229 49.97,125.58 ; 202.12,215.12 J3.A15 ; J3.A15 203.17,216.18 ; J3.A15 203.17,215.12 ; J3.A15 202.12,216.18 ; J5.8 45.43,229.42 ; J5.8 45.43,230.58 ; J5.8 44.27,229.42 ; J5.8 44.27,230.58 ; J7.136 163.33,221.42 ; J7.136 162.17,221.42 ; J7.136 162.17,222.58 ; J7.136 163.33,222.58 ; 114.7,14.79 J11.1 ; J11.1 114.7,13.46 ; J11.1 116.02,14.79 ; J11.1 116.02,13.46 ; J7.8 159.53,230.58 ; J7.8 158.37,230.58 ; J7.8 159.53,229.42 ; J7.8 158.37,229.42 ; J6.116 155.73,232.42 ; J6.116 154.57,233.58 ; J6.116 155.73,233.58 ; J6.116 154.57,232.42 ; 158.37,117.42 J7.116 ; J7.116 159.53,117.42 ; J7.116 159.53,118.58 ; J7.116 158.37,118.58 ; 46.17,120.42 J5.113 ; J5.113 47.33,120.42 ; J5.113 47.33,121.58 ; J5.113 46.17,121.58 ; 158.37,135.42 J7.98 ; J7.98 158.37,136.58 ; J7.98 159.53,135.42 ; J7.98 159.53,136.58 ; 158.37,199.42 J7.38 ; J7.38 159.53,199.42 ; J7.38 158.37,200.58 ; J7.38 159.53,200.58 ; 154.57,139.58 J6.26 ; J6.26 155.73,139.58 ; J6.26 155.73,138.42 ; J6.26 154.57,138.42 ; 160.27,232.42 J7.5 ; J7.5 161.43,233.58 ; J7.5 160.27,233.58 ; J7.5 161.43,232.42 ; 162.17,210.58 J7.148 ; J7.148 163.33,210.58 ; J7.148 162.17,209.42 ; J7.148 163.33,209.42 ; 164.07,143.58 J7.211 ; J7.211 165.23,142.42 ; J7.211 165.23,143.58 ; J7.211 164.07,142.42 ; 48.07,134.58 J5.220 ; J5.220 49.23,133.42 ; J5.220 49.23,134.58 ; J5.220 48.07,133.42 ; 160.27,145.58 J7.89 ; J7.89 161.43,144.42 ; J7.89 161.43,145.58 ; J7.89 160.27,144.42 ; J6.29 153.83,142.58 ; J6.29 152.67,141.42 ; J6.29 152.67,142.58 ; J6.29 153.83,141.42 ; 199.62,210.18 J3.B21 ; J3.B21 200.67,210.18 ; J3.B21 200.67,209.12 ; J3.B21 199.62,209.12 ; 162.17,215.42 J7.142 ; J7.142 162.17,216.58 ; J7.142 163.33,215.42 ; J7.142 163.33,216.58 ; 46.75,80.64 JP7.2 45.3,80.64 ; 160.27,117.58 J7.117 ; J7.117 161.43,116.42 ; J7.117 161.43,117.58 ; J7.117 160.27,116.42 ; FAN12.1 21.75,248.53 ; FAN12.1 20.16,248.53 ; FAN12.1 20.16,250.12 ; FAN12.1 21.75,250.12 ; J7.237 165.23,116.42 ; J7.237 164.07,117.58 ; J7.237 164.07,116.42 ; J7.237 165.23,117.58 ; 136.47,14.79 J12.1 ; J12.1 137.79,14.79 ; J12.1 136.47,13.46 ; J12.1 137.79,13.46 ; J7.44 159.53,193.42 ; J7.44 158.37,194.58 ; J7.44 159.53,194.58 ; J7.44 158.37,193.42 ; 148.36,25.2 J12.20 ; J12.20 149.68,23.88 ; J12.20 148.36,23.88 ; J12.20 149.68,25.2 ; 3.18,161.1 J8.1 ; J8.1 4.97,161.1 ; J8.1 3.18,162.89 ; J8.1 4.97,162.89 ; 49.97,143.58 J5.211 ; J5.211 49.97,142.42 ; J5.211 51.13,143.58 ; J5.211 51.13,142.42 ; J6.211 150.03,208.58 ; J6.211 150.03,207.42 ; J6.211 148.87,208.58 ; J6.211 148.87,207.42 ; FAN4.1 64.44,250.12 ; FAN4.1 64.44,248.53 ; FAN4.1 62.85,248.53 ; FAN4.1 62.85,250.12 ; 150.77,128.42 J6.136 ; J6.136 151.93,128.42 ; J6.136 151.93,129.58 ; J6.136 150.77,129.58 ; J7.101 161.43,133.58 ; J7.101 161.43,132.42 ; J7.101 160.27,132.42 ; J7.101 160.27,133.58 ; J7.157 165.23,201.58 ; J7.157 164.07,200.42 ; J7.157 164.07,201.58 ; J7.157 165.23,200.42 ; J7.11 161.43,227.58 ; J7.11 161.43,226.42 ; J7.11 160.27,226.42 ; J7.11 160.27,227.58 ; 239.05,210.95 J55.2 240.5,210.95 ; J3.B22 198.67,209.18 ; J3.B22 197.62,209.18 ; J3.B22 198.67,208.12 ; J3.B22 197.62,208.12 ; 197.62,199.18 J3.B32 ; J3.B32 198.67,199.18 ; J3.B32 197.62,198.12 ; J3.B32 198.67,198.12 ; J5.101 47.33,132.42 ; J5.101 46.17,132.42 ; J5.101 47.33,133.58 ; J5.101 46.17,133.58 ; 202.12,182.18 J3.A49 ; J3.A49 203.17,182.18 ; J3.A49 203.17,181.12 ; 49.97,207.58 J5.151 ; J5.151 49.97,206.42 ; J5.151 51.13,206.42 ; J5.151 51.13,207.58 ; 199.62,218.18 J3.B13 ; J3.B13 200.67,217.12 ; J3.B13 200.67,218.18 ; J3.B13 199.62,217.12 ; 44.27,223.42 J5.14 ; J5.14 45.43,224.58 ; J5.14 44.27,224.58 ; J5.14 45.43,223.42 ; 48.07,146.58 J5.208 ; J5.208 48.07,145.42 ; J5.208 49.23,146.58 ; J5.208 49.23,145.42 ; 8.58,138.96 J9.24 ; J9.24 8.58,136.98 ; J9.24 10.57,136.98 ; J9.24 10.57,138.96 ; 160.27,209.58 J7.29 ; J7.29 161.43,208.42 ; J7.29 160.27,208.42 ; J7.29 161.43,209.58 ; 158.37,153.42 J7.80 ; J7.80 159.53,154.58 ; J7.80 159.53,153.42 ; J7.80 158.37,154.58 ; J7.133 165.23,224.42 ; J7.133 164.07,225.58 ; J7.133 164.07,224.42 ; J7.133 165.23,225.58 ; 9.04,248.53 FAN5.1 ; FAN5.1 10.64,248.53 ; FAN5.1 10.64,250.12 ; FAN5.1 9.04,250.12 ; 19.55,130.73 CT28.2 ; CT28.2 21.23,132.41 ; CT28.2 19.55,132.41 ; CT28.2 21.23,130.73 ; 42.82,12.55 CN4.A4 42.82,13.9 ; 46.17,144.42 J5.89 ; J5.89 47.33,144.42 ; J5.89 47.33,145.58 ; J5.89 46.17,145.58
  L2_GND_1 w0.914: 113.7,213.18 BH10.1 ; BH10.1 117.43,213.18 ; BH10.1 117.43,209.45 ; BH10.1 113.7,209.45
  L2_GND_1 w1.016: H13.1 142.93,62.87 ; H13.1 142.93,69.13 ; H13.1 136.67,62.87 ; H13.1 136.67,69.13 ; 172.47,243.87 H2.1 ; H2.1 178.73,243.87 ; H2.1 178.73,250.13 ; H2.1 172.47,250.13 ; H3.1 282.13,250.13 ; H3.1 275.87,243.87 ; H3.1 275.87,250.13 ; H3.1 282.13,243.87 ; H1.1 31.13,243.87 ; H1.1 24.87,243.87 ; H1.1 31.13,250.13 ; H1.1 24.87,250.13 ; 66.67,48.13 H14.1 ; H14.1 66.67,41.87 ; H14.1 72.93,48.13 ; H14.1 72.93,41.87 ; H11.1 139.13,123.99 ; H11.1 139.13,130.25 ; H11.1 132.87,130.25 ; H11.1 132.87,123.99 ; 2.87,153.23 H9.1 ; H9.1 9.13,153.23 ; H9.1 2.87,146.97 ; H9.1 9.13,146.97 ; H8.1 282.13,124.62 ; H8.1 282.13,130.88 ; H8.1 275.87,124.62 ; H8.1 275.87,130.88 ; H16.1 9.13,15.87 ; H16.1 9.13,22.13 ; H16.1 2.87,22.13 ; H16.1 2.87,15.87 ; 223.87,243.87 H7.1 ; H7.1 230.13,250.13 ; H7.1 230.13,243.87 ; H7.1 223.87,250.13 ; H10.1 67.13,123.99 ; H10.1 67.13,130.25 ; H10.1 60.87,130.25 ; H10.1 60.87,123.99 ; H12.1 72.93,93.87 ; H12.1 66.67,93.87 ; H12.1 66.67,100.13 ; H12.1 72.93,100.13 ; 132.87,202.25 H5.1 ; H5.1 139.13,195.99 ; H5.1 139.13,202.25 ; H5.1 132.87,195.99 ; 60.87,195.99 H4.1 ; H4.1 67.13,202.25 ; H4.1 67.13,195.99 ; H4.1 60.87,202.25 ; 275.87,22.13 H15.1 ; H15.1 282.13,15.87 ; H15.1 282.13,22.13 ; H15.1 275.87,15.87 ; H6.1 178.69,178.1 ; H6.1 172.5,178.1 ; H6.1 178.69,171.9 ; H6.1 172.5,171.9
  L3_INT_1 w0.508: 9.5,4.48 SW6.2 ; SW6.2 9.5,2.96 ; SW6.2 11.02,4.48 ; SW6.2 11.02,2.96 ; 49.97,207.58 J5.151 ; J5.151 51.13,206.42 ; J5.151 49.97,206.42 ; J5.151 51.13,207.58 ; J3.B25 200.67,206.18 ; J3.B25 199.62,205.12 ; J3.B25 199.62,206.18 ; J3.B25 200.67,205.12 ; J3.B43 200.67,187.12 ; J3.B43 200.67,188.18 ; J3.B43 199.62,187.12 ; J3.B43 199.62,188.18 ; J3.A27 203.17,204.18 ; J3.A27 202.12,203.12 ; J3.A27 203.17,203.12 ; J3.A27 202.12,204.18 ; 204.12,206.12 J3.A24 ; J3.A24 205.17,206.12 ; J3.A24 204.12,207.18 ; J3.A24 205.17,207.18 ; 44.27,200.58 J5.38 ; J5.38 45.43,199.42 ; J5.38 44.27,199.42 ; J5.38 45.43,200.58 ; J5.44 45.43,193.42 ; J5.44 44.27,193.42 ; J5.44 45.43,194.58 ; J5.44 44.27,194.58 ; J3.B47 200.67,184.18 ; J3.B47 200.67,183.12 ; J3.B47 199.62,183.12 ; J3.B47 199.62,184.18 ; J5.157 51.13,200.42 ; J5.157 49.97,201.58 ; J5.157 49.97,200.42 ; J5.157 51.13,201.58 ; J5.29 47.33,208.42 ; J5.29 46.17,209.58 ; J5.29 47.33,209.58 ; J5.29 46.17,208.42 ; C5338.2 188.17,228.35 ; C5338.2 188.17,230.04 ; C5338.2 186.48,228.35 ; C5338.2 186.48,230.04 ; J5.26 45.43,212.58 ; J5.26 44.27,212.58 ; J5.26 45.43,211.42 ; J5.26 44.27,211.42 ; 10.57,7.16 SW6.4 ; SW6.4 12.45,7.16 ; SW6.4 10.57,5.28 ; SW6.4 12.45,5.28 ; 204.12,188.12 J3.A42 ; J3.A42 204.12,189.18 ; J3.A42 205.17,188.12 ; J3.A42 205.17,189.18 ; J5.23 47.33,215.58 ; J5.23 46.17,215.58 ; J5.23 47.33,214.42 ; J5.23 46.17,214.42 ; 3.57,5.28 SW6.3 ; SW6.3 5.45,5.28 ; SW6.3 3.57,7.16 ; SW6.3 5.45,7.16 ; J5.32 45.43,206.58 ; J5.32 45.43,205.42 ; J5.32 44.27,206.58 ; J5.32 44.27,205.42 ; J5.139 51.13,218.42 ; J5.139 49.97,218.42 ; J5.139 51.13,219.58 ; J5.139 49.97,219.58 ; 49.97,230.42 J5.127 ; J5.127 51.13,230.42 ; J5.127 49.97,231.58 ; J5.127 51.13,231.58 ; J5.145 51.13,213.58 ; J5.145 49.97,213.58 ; J5.145 49.97,212.42 ; J5.145 51.13,212.42 ; J5.11 47.33,227.58 ; J5.11 46.17,226.42 ; J5.11 46.17,227.58 ; J5.11 47.33,226.42 ; J5.160 49.23,198.58 ; J5.160 49.23,197.42 ; J5.160 48.07,197.42 ; J5.160 48.07,198.58 ; J3.A23 203.17,207.12 ; J3.A23 202.12,207.12 ; J3.A23 202.12,208.18 ; J3.A23 203.17,208.18 ; 46.17,233.58 J5.5 ; J5.5 46.17,232.42 ; J5.5 47.33,233.58 ; J5.5 47.33,232.42 ; J3.A45 203.17,185.12 ; J3.A45 202.12,185.12 ; J3.A45 202.12,186.18 ; J3.A45 203.17,186.18 ; 197.62,190.12 J3.B40 ; J3.B40 198.67,190.12 ; J3.B40 198.67,191.18 ; J3.B40 197.62,191.18 ; J3.A37 203.17,193.12 ; J3.A37 203.17,194.18 ; J3.A37 202.12,193.12 ; J3.A37 202.12,194.18 ; 197.62,204.12 J3.B26 ; J3.B26 198.67,205.18 ; J3.B26 198.67,204.12 ; J3.B26 197.62,205.18 ; J5.136 49.23,221.42 ; J5.136 48.07,222.58 ; J5.136 48.07,221.42 ; J5.136 49.23,222.58 ; J3.B36 198.67,195.18 ; J3.B36 198.67,194.12 ; J3.B36 197.62,194.12 ; J3.B36 197.62,195.18 ; J8.1 4.97,161.1 ; J8.1 3.18,161.1 ; J8.1 4.97,162.89 ; J8.1 3.18,162.89 ; J5.14 45.43,224.58 ; J5.14 45.43,223.42 ; J5.14 44.27,223.42 ; J5.14 44.27,224.58 ; 49.97,194.42 J5.163 ; J5.163 51.13,194.42 ; J5.163 49.97,195.58 ; J5.163 51.13,195.58 ; J3.B18 198.67,213.18 ; J3.B18 197.62,213.18 ; J3.B18 197.62,212.12 ; J3.B18 198.67,212.12 ; J5.41 47.33,196.42 ; J5.41 47.33,197.58 ; J5.41 46.17,197.58 ; J5.41 46.17,196.42 ; J8.3 4.97,171.27 ; J8.3 3.18,169.48 ; J8.3 3.18,171.27 ; J8.3 4.97,169.48 ; 197.62,208.12 J3.B22 ; J3.B22 198.67,208.12 ; J3.B22 197.62,209.18 ; J3.B22 198.67,209.18 ; 197.62,187.18 J3.B44 ; J3.B44 198.67,186.12 ; J3.B44 197.62,186.12 ; J3.B44 198.67,187.18 ; J3.B39 200.67,192.18 ; J3.B39 199.62,191.12 ; J3.B39 199.62,192.18 ; J3.B39 200.67,191.12 ; J3.A38 205.17,192.12 ; J3.A38 204.12,192.12 ; J3.A38 205.17,193.18 ; J3.A38 204.12,193.18 ; 45.43,235.42 J5.2 44.27,235.42 ; J3.B32 198.67,198.12 ; J3.B32 197.62,198.12 ; J3.B32 197.62,199.18 ; J3.B32 198.67,199.18 ; J3.A49 203.17,181.12 ; J3.A49 202.12,182.18 ; J3.A49 203.17,182.18 ; 19.97,144.4 C5340.2 ; C5340.2 21.65,146.08 ; C5340.2 19.97,146.08 ; C5340.2 21.65,144.4 ; 204.12,202.12 J3.A28 ; J3.A28 205.17,202.12 ; J3.A28 204.12,203.18 ; J3.A28 205.17,203.18 ; 199.62,209.12 J3.B21 ; J3.B21 200.67,210.18 ; J3.B21 199.62,210.18 ; J3.B21 200.67,209.12 ; J8.2 4.97,165.29 ; J8.2 3.18,165.29 ; J8.2 3.18,167.08 ; J8.2 4.97,167.08 ; J3.B35 200.67,196.18 ; J3.B35 200.67,195.12 ; J3.B35 199.62,196.18 ; J3.B35 199.62,195.12 ; J5.130 49.23,228.58 ; J5.130 48.07,228.58 ; J5.130 49.23,227.42 ; J5.130 48.07,227.42 ; J5.148 49.23,209.42 ; J5.148 48.07,209.42 ; J5.148 49.23,210.58 ; J5.148 48.07,210.58 ; J5.8 45.43,229.42 ; J5.8 45.43,230.58 ; J5.8 44.27,229.42 ; J5.8 44.27,230.58 ; J3.A18 205.17,212.12 ; J3.A18 204.12,213.18 ; J3.A18 205.17,213.18 ; J3.A18 204.12,212.12 ; 199.62,202.18 J3.B29 ; J3.B29 200.67,202.18 ; J3.B29 199.62,201.12 ; J3.B29 200.67,201.12 ; 46.17,221.58 J5.17 ; J5.17 47.33,220.42 ; J5.17 47.33,221.58 ; J5.17 46.17,220.42 ; 202.12,200.18 J3.A31 ; J3.A31 203.17,199.12 ; J3.A31 203.17,200.18 ; J3.A31 202.12,199.12 ; J5.133 51.13,224.42 ; J5.133 49.97,225.58 ; J5.133 49.97,224.42 ; J5.133 51.13,225.58 ; 199.62,217.12 J3.B13 200.67,217.12 ; J5.142 49.23,215.42 ; J5.142 48.07,216.58 ; J5.142 49.23,216.58 ; J5.142 48.07,215.42 ; 197.62,215.18 J3.B16 ; J3.B16 197.62,214.12 ; J3.B16 198.67,214.12 ; J3.B16 198.67,215.18 ; 204.12,211.18 J3.A20 ; J3.A20 205.17,211.18 ; J3.A20 205.17,210.12 ; J3.A20 204.12,210.12 ; 8.58,136.98 J9.24 ; J9.24 10.57,138.96 ; J9.24 8.58,138.96 ; J9.24 10.57,136.98 ; J3.A46 205.17,184.12 ; J3.A46 204.12,184.12 ; J3.A46 205.17,185.18 ; J3.A46 204.12,185.18 ; J8.4 4.97,175.47 ; J8.4 3.18,173.68 ; J8.4 3.18,175.47 ; J8.4 4.97,173.68 ; 46.17,191.58 J5.47 ; J5.47 47.33,190.42 ; J5.47 47.33,191.58 ; J5.47 46.17,190.42 ; 204.12,196.12 J3.A34 ; J3.A34 205.17,196.12 ; J3.A34 205.17,197.18 ; J3.A34 204.12,197.18 ; 48.07,204.58 J5.154 ; J5.154 49.23,204.58 ; J5.154 49.23,203.42 ; J5.154 48.07,203.42 ; 48.07,233.42 J5.124 ; J5.124 48.07,234.58 ; J5.124 49.23,234.58 ; J5.124 49.23,233.42 ; 199.62,181.12 J3.B49 ; J3.B49 200.67,182.18 ; J3.B49 199.62,182.18 ; 44.27,217.42 J5.20 ; J5.20 44.27,218.58 ; J5.20 45.43,217.42 ; J5.20 45.43,218.58 ; J5.35 47.33,202.42 ; J5.35 47.33,203.58 ; J5.35 46.17,202.42 ; J5.35 46.17,203.58 ; 202.12,189.12 J3.A41 ; J3.A41 203.17,189.12 ; J3.A41 203.17,190.18 ; J3.A41 202.12,190.18 ; 48.07,192.58 J5.166 ; J5.166 48.07,191.42 ; J5.166 49.23,191.42 ; J5.166 49.23,192.58 ; 202.12,215.12 J3.A15 ; J3.A15 203.17,215.12 ; J3.A15 203.17,216.18 ; J3.A15 202.12,216.18
  L3_INT_1 w1.016: H16.1 9.13,15.87 ; H16.1 9.13,22.13 ; H16.1 2.87,15.87 ; H16.1 2.87,22.13 ; 136.67,69.13 H13.1 ; H13.1 136.67,62.87 ; H13.1 142.93,62.87 ; H13.1 142.93,69.13 ; H3.1 282.13,243.87 ; H3.1 275.87,250.13 ; H3.1 275.87,243.87 ; H3.1 282.13,250.13 ; H6.1 178.69,178.1 ; H6.1 178.69,171.9 ; H6.1 172.5,171.9 ; 66.67,48.13 H14.1 ; H14.1 72.93,48.13 ; H14.1 72.93,41.87 ; 275.87,124.62 H8.1 ; H8.1 282.13,124.62 ; H8.1 282.13,130.88 ; H8.1 275.87,130.88 ; 2.87,153.23 H9.1 ; H9.1 9.13,146.97 ; H9.1 2.87,146.97 ; H9.1 9.13,153.23
  L4_GND_2 w0.508: J6.14 155.73,127.58 ; J6.14 155.73,126.42 ; J6.14 154.57,126.42 ; J6.14 154.57,127.58 ; 49.97,130.42 J5.223 ; J5.223 51.13,131.58 ; J5.223 49.97,131.58 ; J5.223 51.13,130.42 ; 148.87,126.58 J6.133 ; J6.133 150.03,125.42 ; J6.133 150.03,126.58 ; J6.133 148.87,125.42 ; 49.97,207.58 J5.151 ; J5.151 51.13,206.42 ; J5.151 49.97,206.42 ; J5.151 51.13,207.58 ; 49.97,114.42 J5.239 ; J5.239 51.13,114.42 ; J5.239 51.13,115.58 ; J5.239 49.97,115.58 ; 162.17,221.42 J7.136 ; J7.136 162.17,222.58 ; J7.136 163.33,222.58 ; J7.136 163.33,221.42 ; J6.214 151.93,211.58 ; J6.214 151.93,210.42 ; J6.214 150.77,210.42 ; J6.214 150.77,211.58 ; 86.66,246.15 C5279.2 ; C5279.2 86.66,247.83 ; C5279.2 88.34,246.15 ; C5279.2 88.34,247.83 ; J106.10 127.2,247.22 ; J106.10 125.95,247.22 ; J106.10 125.95,245.97 ; J106.10 127.2,245.97 ; J7.20 159.53,217.42 ; J7.20 158.37,217.42 ; J7.20 159.53,218.58 ; J7.20 158.37,218.58 ; J5.83 47.33,150.42 ; J5.83 47.33,151.58 ; J5.83 46.17,150.42 ; J5.83 46.17,151.58 ; J7.130 163.33,228.58 ; J7.130 162.17,227.42 ; J7.130 162.17,228.58 ; J7.130 163.33,227.42 ; 162.17,140.58 J7.214 ; J7.214 163.33,140.58 ; J7.214 163.33,139.42 ; J7.214 162.17,139.42 ; 152.67,117.42 J6.5 ; J6.5 152.67,118.58 ; J6.5 153.83,117.42 ; J6.5 153.83,118.58 ; 115.85,247.83 C5283.2 ; C5283.2 115.85,246.15 ; C5283.2 117.53,246.15 ; C5283.2 117.53,247.83 ; J3.B25 200.67,206.18 ; J3.B25 199.62,206.18 ; J3.B25 199.62,205.12 ; J3.B25 200.67,205.12 ; J5.101 47.33,133.58 ; J5.101 46.17,133.58 ; J5.101 46.17,132.42 ; J5.101 47.33,132.42 ; J7.92 159.53,142.58 ; J7.92 159.53,141.42 ; J7.92 158.37,142.58 ; J7.92 158.37,141.42 ; J3.A24 205.17,206.12 ; J3.A24 205.17,207.18 ; J3.A24 204.12,206.12 ; J3.A24 204.12,207.18 ; 44.27,142.58 J5.92 ; J5.92 45.43,142.58 ; J5.92 45.43,141.42 ; J5.92 44.27,141.42 ; 164.07,224.42 J7.133 ; J7.133 165.23,224.42 ; J7.133 165.23,225.58 ; J7.133 164.07,225.58 ; J6.121 150.03,113.42 ; J6.121 148.87,113.42 ; J6.121 148.87,114.58 ; J6.121 150.03,114.58 ; J9.3 5.07,101.16 ; J9.3 3.08,101.16 ; J9.3 3.08,99.18 ; J9.3 5.07,99.18 ; 158.37,193.42 J7.44 ; J7.44 159.53,193.42 ; J7.44 158.37,194.58 ; J7.44 159.53,194.58 ; J7.116 159.53,118.58 ; J7.116 158.37,117.42 ; J7.116 159.53,117.42 ; J7.116 158.37,118.58 ; C5342.2 22.77,28.5 ; C5342.2 21.08,30.18 ; C5342.2 22.77,30.18 ; C5342.2 21.08,28.5 ; J7.220 163.33,134.58 ; J7.220 163.33,133.42 ; J7.220 162.17,134.58 ; J7.220 162.17,133.42 ; 152.67,154.58 J6.41 ; J6.41 152.67,153.42 ; J6.41 153.83,153.42 ; J6.41 153.83,154.58 ; J9.17 10.57,109.56 ; J9.17 8.58,107.58 ; J9.17 8.58,109.56 ; J9.17 10.57,107.58 ; 164.07,230.42 J7.127 ; J7.127 164.07,231.58 ; J7.127 165.23,231.58 ; J7.127 165.23,230.42 ; J3.B32 198.67,199.18 ; J3.B32 197.62,198.12 ; J3.B32 197.62,199.18 ; J3.B32 198.67,198.12 ; 207.06,244.51 C5337.2 ; C5337.2 208.74,244.51 ; C5337.2 207.06,242.83 ; C5337.2 208.74,242.83 ; J5.26 45.43,211.42 ; J5.26 45.43,212.58 ; J5.26 44.27,211.42 ; J5.26 44.27,212.58 ; 202.12,232.18 J3.A1 ; J3.A1 203.17,231.12 ; J3.A1 202.12,231.12 ; J3.A1 203.17,232.18 ; J7.80 159.53,153.42 ; J7.80 158.37,154.58 ; J7.80 159.53,154.58 ; J7.80 158.37,153.42 ; J5.8 45.43,230.58 ; J5.8 44.27,230.58 ; J5.8 45.43,229.42 ; J5.8 44.27,229.42 ; 199.62,202.18 J3.B29 ; J3.B29 200.67,201.12 ; J3.B29 199.62,201.12 ; J3.B29 200.67,202.18 ; 195.24,52.65 FAN1.1 ; FAN1.1 196.84,51.05 ; FAN1.1 195.24,51.05 ; FAN1.1 196.84,52.65 ; 8.58,113.76 J9.18 ; J9.18 10.57,111.77 ; J9.18 8.58,111.77 ; J9.18 10.57,113.76 ; 3.08,117.96 J9.7 ; J9.7 3.08,115.98 ; J9.7 5.07,115.98 ; J9.7 5.07,117.96 ; J6.2 155.73,115.58 ; J6.2 155.73,114.42 ; J6.2 154.57,115.58 ; J6.2 154.57,114.42 ; J6.89 153.83,205.42 ; J6.89 152.67,206.58 ; J6.89 153.83,206.58 ; J6.89 152.67,205.42 ; C5341.2 41.02,28.5 ; C5341.2 39.34,28.5 ; C5341.2 39.34,30.18 ; C5341.2 41.02,30.18 ; J7.17 161.43,220.42 ; J7.17 161.43,221.58 ; J7.17 160.27,221.58 ; J7.17 160.27,220.42 ; 162.17,192.58 J7.166 ; J7.166 163.33,192.58 ; J7.166 162.17,191.42 ; J7.166 163.33,191.42 ; J3.A20 205.17,211.18 ; J3.A20 205.17,210.12 ; J3.A20 204.12,211.18 ; J3.A20 204.12,210.12 ; CT28.2 21.23,132.41 ; CT28.2 19.55,132.41 ; CT28.2 19.55,130.73 ; CT28.2 21.23,130.73 ; 160.27,227.58 J7.11 ; J7.11 160.27,226.42 ; J7.11 161.43,227.58 ; J7.11 161.43,226.42 ; 150.77,223.58 J6.226 ; J6.226 151.93,223.58 ; J6.226 150.77,222.42 ; J6.226 151.93,222.42 ; J11.1 116.02,13.46 ; J11.1 114.7,13.46 ; J11.1 114.7,14.79 ; J11.1 116.02,14.79 ; 197.62,186.12 J3.B44 ; J3.B44 198.67,187.18 ; J3.B44 197.62,187.18 ; J3.B44 198.67,186.12 ; 160.27,144.42 J7.89 ; J7.89 161.43,144.42 ; J7.89 160.27,145.58 ; J7.89 161.43,145.58 ; J5.104 45.43,130.58 ; J5.104 45.43,129.42 ; J5.104 44.27,130.58 ; J5.104 44.27,129.42 ; J6.199 150.03,196.58 ; J6.199 150.03,195.42 ; J6.199 148.87,195.42 ; J6.199 148.87,196.58 ; J7.208 163.33,145.42 ; J7.208 162.17,146.58 ; J7.208 162.17,145.42 ; J7.208 163.33,146.58 ; 158.37,230.58 J7.8 ; J7.8 159.53,229.42 ; J7.8 159.53,230.58 ; J7.8 158.37,229.42 ; 243,247.73 243.71,247.01 ; 243.71,247.01 243,246.3 ; 243.71,247.01 244.43,247.73 ; 243.71,247.01 244.43,246.3 ; J3.A12 205.17,219.18 ; J3.A12 204.12,218.12 ; J3.A12 204.12,219.18 ; J3.A12 205.17,218.12 ; 46.65,63.26 J69.5 ; J69.5 48.19,63.26 ; J69.5 48.19,64.8 ; J69.5 46.65,64.8 ; 148.36,25.2 J12.20 ; J12.20 149.68,23.88 ; J12.20 149.68,25.2 ; J12.20 148.36,23.88 ; J6.117 153.83,233.42 ; J6.117 153.83,234.58 ; J6.117 152.67,233.42 ; J6.117 152.67,234.58 ; J6.104 155.73,221.58 ; J6.104 155.73,220.42 ; J6.104 154.57,220.42 ; J6.104 154.57,221.58 ; J8.1 4.97,161.1 ; J8.1 3.18,161.1 ; J8.1 3.18,162.89 ; J8.1 4.97,162.89 ; 150.77,117.58 J6.124 ; J6.124 151.93,117.58 ; J6.124 151.93,116.42 ; J6.124 150.77,116.42 ; J7.107 161.43,127.58 ; J7.107 160.27,127.58 ; J7.107 161.43,126.42 ; J7.107 160.27,126.42 ; 204.12,229.18 J3.A4 ; J3.A4 205.17,228.12 ; J3.A4 205.17,229.18 ; J3.A4 204.12,228.12 ; 44.27,194.58 J5.44 ; J5.44 44.27,193.42 ; J5.44 45.43,193.42 ; J5.44 45.43,194.58 ; J5.166 49.23,192.58 ; J5.166 48.07,191.42 ; J5.166 48.07,192.58 ; J5.166 49.23,191.42 ; J6.44 155.73,157.58 ; J6.44 154.57,156.42 ; J6.44 154.57,157.58 ; J6.44 155.73,156.42 ; J7.98 159.53,135.42 ; J7.98 159.53,136.58 ; J7.98 158.37,135.42 ; J7.98 158.37,136.58 ; J6.20 155.73,132.42 ; J6.20 155.73,133.58 ; J6.20 154.57,132.42 ; J6.20 154.57,133.58 ; J6.145 150.03,137.42 ; J6.145 150.03,138.58 ; J6.145 148.87,138.58 ; J6.145 148.87,137.42 ; 154.57,120.42 J6.8 ; J6.8 154.57,121.58 ; J6.8 155.73,120.42 ; J6.8 155.73,121.58 ; 199.62,191.12 J3.B39 ; J3.B39 200.67,191.12 ; J3.B39 200.67,192.18 ; J3.B39 199.62,192.18 ; J5.217 51.13,136.42 ; J5.217 51.13,137.58 ; J5.217 49.97,136.42 ; J5.217 49.97,137.58 ; J6.130 151.93,122.42 ; J6.130 150.77,123.58 ; J6.130 150.77,122.42 ; J6.130 151.93,123.58 ; J5.121 51.13,237.58 ; J5.121 51.13,236.42 ; J5.121 49.97,236.42 ; J5.121 49.97,237.58 ; 160.27,196.42 J7.41 ; J7.41 161.43,197.58 ; J7.41 160.27,197.58 ; J7.41 161.43,196.42 ; J6.107 153.83,223.42 ; J6.107 152.67,224.58 ; J6.107 153.83,224.58 ; J6.107 152.67,223.42 ; 49.97,218.42 J5.139 ; J5.139 51.13,218.42 ; J5.139 49.97,219.58 ; J5.139 51.13,219.58 ; 46.17,226.42 J5.11 ; J5.11 47.33,227.58 ; J5.11 46.17,227.58 ; J5.11 47.33,226.42 ; J7.205 165.23,148.42 ; J7.205 164.07,149.58 ; J7.205 165.23,149.58 ; J7.205 164.07,148.42 ; 48.07,140.58 J5.214 ; J5.214 49.23,139.42 ; J5.214 48.07,139.42 ; J5.214 49.23,140.58 ; 20.8,41.77 J10.M2 ; J10.M2 22.77,43.74 ; J10.M2 20.8,43.74 ; J10.M2 22.77,41.77 ; 204.12,196.12 J3.A34 ; J3.A34 205.17,197.18 ; J3.A34 204.12,197.18 ; J3.A34 205.17,196.12 ; 148.87,156.58 J6.163 ; J6.163 148.87,155.42 ; J6.163 150.03,155.42 ; J6.163 150.03,156.58 ; J6.17 153.83,130.58 ; J6.17 152.67,129.42 ; J6.17 152.67,130.58 ; J6.17 153.83,129.42 ; J7.139 165.23,218.42 ; J7.139 164.07,218.42 ; J7.139 164.07,219.58 ; J7.139 165.23,219.58 ; J5.157 51.13,201.58 ; J5.157 49.97,201.58 ; J5.157 49.97,200.42 ; J5.157 51.13,200.42 ; 199.62,187.12 J3.B43 ; J3.B43 199.62,188.18 ; J3.B43 200.67,188.18 ; J3.B43 200.67,187.12 ; 162.17,128.58 J7.226 ; J7.226 163.33,127.42 ; J7.226 162.17,127.42 ; J7.226 163.33,128.58 ; J7.239 165.23,114.42 ; J7.239 165.23,115.58 ; J7.239 164.07,115.58 ; J7.239 164.07,114.42 ; J6.116 155.73,233.58 ; J6.116 154.57,233.58 ; J6.116 154.57,232.42 ; J6.116 155.73,232.42 ; 180.01,13.46 J14.1 ; J14.1 181.33,14.79 ; J14.1 180.01,14.79 ; J14.1 181.33,13.46 ; J9.19 10.57,117.96 ; J9.19 8.58,115.98 ; J9.19 8.58,117.96 ; J9.19 10.57,115.98 ; 162.17,197.42 J7.160 ; J7.160 163.33,198.58 ; J7.160 163.33,197.42 ; J7.160 162.17,198.58 ; 158.37,235.42 J7.2 ; J7.2 159.53,236.58 ; J7.2 158.37,236.58 ; J7.2 159.53,235.42 ; J6.217 150.03,214.58 ; J6.217 148.87,214.58 ; J6.217 148.87,213.42 ; J6.217 150.03,213.42 ; J7.83 161.43,151.58 ; J7.83 160.27,150.42 ; J7.83 160.27,151.58 ; J7.83 161.43,150.42 ; J7.223 165.23,131.58 ; J7.223 164.07,130.42 ; J7.223 165.23,130.42 ; J7.223 164.07,131.58 ; 3.57,5.28 SW6.3 ; SW6.3 3.57,7.16 ; SW6.3 5.45,5.28 ; SW6.3 5.45,7.16 ; 202.12,204.18 J3.A27 ; J3.A27 203.17,204.18 ; J3.A27 203.17,203.12 ; J3.A27 202.12,203.12 ; 158.37,130.58 J7.104 ; J7.104 159.53,129.42 ; J7.104 158.37,129.42 ; J7.104 159.53,130.58 ; 204.12,203.18 J3.A28 ; J3.A28 204.12,202.12 ; J3.A28 205.17,203.18 ; J3.A28 205.17,202.12 ; 199.62,183.12 J3.B47 ; J3.B47 200.67,184.18 ; J3.B47 200.67,183.12 ; J3.B47 199.62,184.18 ; J3.B35 200.67,196.18 ; J3.B35 199.62,196.18 ; J3.B35 200.67,195.12 ; J3.B35 199.62,195.12 ; 150.77,217.58 J6.220 ; J6.220 150.77,216.42 ; J6.220 151.93,217.58 ; J6.220 151.93,216.42 ; 48.07,197.42 J5.160 ; J5.160 49.23,198.58 ; J5.160 49.23,197.42 ; J5.160 48.07,198.58 ; J3.B21 200.67,209.12 ; J3.B21 199.62,209.12 ; J3.B21 200.67,210.18 ; J3.B21 199.62,210.18 ; 160.27,120.42 J7.113 ; J7.113 161.43,121.58 ; J7.113 160.27,121.58 ; J7.113 161.43,120.42 ; 142.97,248.53 FAN2.1 ; FAN2.1 144.56,250.12 ; FAN2.1 142.97,250.12 ; FAN2.1 144.56,248.53 ; J5.116 45.43,118.58 ; J5.116 44.27,118.58 ; J5.116 44.27,117.42 ; J5.116 45.43,117.42 ; J5.130 49.23,228.58 ; J5.130 48.07,227.42 ; J5.130 48.07,228.58 ; J5.130 49.23,227.42 ; 164.07,200.42 J7.157 ; J7.157 164.07,201.58 ; J7.157 165.23,201.58 ; J7.157 165.23,200.42 ; 164.07,118.42 J7.235 ; J7.235 164.07,119.58 ; J7.235 165.23,118.42 ; J7.235 165.23,119.58 ; 20.16,250.12 FAN12.1 ; FAN12.1 21.75,248.53 ; FAN12.1 20.16,248.53 ; FAN12.1 21.75,250.12 ; 158.37,223.42 J7.14 ; J7.14 158.37,224.58 ; J7.14 159.53,224.58 ; J7.14 159.53,223.42 ; J5.202 49.23,151.42 ; J5.202 48.07,151.42 ; J5.202 49.23,152.58 ; J5.202 48.07,152.58 ; J6.95 153.83,211.42 ; J6.95 152.67,212.58 ; J6.95 153.83,212.58 ; J6.95 152.67,211.42 ; 154.57,139.58 J6.26 ; J6.26 154.57,138.42 ; J6.26 155.73,138.42 ; J6.26 155.73,139.58 ; J5.80 45.43,153.42 ; J5.80 44.27,154.58 ; J5.80 45.43,154.58 ; J5.80 44.27,153.42 ; 204.12,185.18 J3.A46 ; J3.A46 204.12,184.12 ; J3.A46 205.17,184.12 ; J3.A46 205.17,185.18 ; 148.87,225.42 J6.229 ; J6.229 150.03,226.58 ; J6.229 148.87,226.58 ; J6.229 150.03,225.42 ; 150.77,198.42 J6.202 ; J6.202 150.77,199.58 ; J6.202 151.93,198.42 ; J6.202 151.93,199.58 ; 164.07,154.42 J7.199 ; J7.199 164.07,155.58 ; J7.199 165.23,155.58 ; J7.199 165.23,154.42 ; 49.97,142.42 J5.211 ; J5.211 51.13,143.58 ; J5.211 49.97,143.58 ; J5.211 51.13,142.42 ; 152.67,229.42 J6.113 ; J6.113 152.67,230.58 ; J6.113 153.83,229.42 ; J6.113 153.83,230.58 ; 158.37,147.42 J7.86 ; J7.86 159.53,148.58 ; J7.86 159.53,147.42 ; J7.86 158.37,148.58 ; J6.32 155.73,145.58 ; J6.32 154.57,145.58 ; J6.32 154.57,144.42 ; J6.32 155.73,144.42 ; 237.92,246.3 J2.16 ; J2.16 239.35,246.3 ; J2.16 239.35,247.73 ; J2.16 237.92,247.73 ; 162.17,210.58 J7.148 ; J7.148 163.33,210.58 ; J7.148 163.33,209.42 ; J7.148 162.17,209.42 ; 49.97,230.42 J5.127 ; J5.127 51.13,230.42 ; J5.127 49.97,231.58 ; J5.127 51.13,231.58 ; C5338.2 188.17,230.04 ; C5338.2 186.48,230.04 ; C5338.2 188.17,228.35 ; C5338.2 186.48,228.35 ; 44.27,147.42 J5.86 ; J5.86 45.43,148.58 ; J5.86 45.43,147.42 ; J5.86 44.27,148.58 ; 160.27,232.42 J7.5 ; J7.5 160.27,233.58 ; J7.5 161.43,233.58 ; J7.5 161.43,232.42 ; J6.239 150.03,235.42 ; J6.239 150.03,236.58 ; J6.239 148.87,236.58 ; J6.239 148.87,235.42 ; 197.62,205.18 J3.B26 ; J3.B26 198.67,204.12 ; J3.B26 198.67,205.18 ; J3.B26 197.62,204.12 ; 197.62,194.12 J3.B36 ; J3.B36 198.67,195.18 ; J3.B36 197.62,195.18 ; J3.B36 198.67,194.12 ; 162.17,215.42 J7.142 ; J7.142 163.33,215.42 ; J7.142 162.17,216.58 ; J7.142 163.33,216.58 ; J6.98 155.73,215.58 ; J6.98 154.57,215.58 ; J6.98 155.73,214.42 ; J6.98 154.57,214.42 ; 46.17,215.58 J5.23 ; J5.23 47.33,215.58 ; J5.23 47.33,214.42 ; J5.23 46.17,214.42 ; J5.232 49.23,122.58 ; J5.232 48.07,121.42 ; J5.232 48.07,122.58 ; J5.232 49.23,121.42 ; J6.223 150.03,219.42 ; J6.223 150.03,220.58 ; J6.223 148.87,219.42 ; J6.223 148.87,220.58 ; J7.47 161.43,190.42 ; J7.47 161.43,191.58 ; J7.47 160.27,190.42 ; J7.47 160.27,191.58 ; J7.32 159.53,206.58 ; J7.32 158.37,206.58 ; J7.32 159.53,205.42 ; J7.32 158.37,205.42 ; 44.27,135.42 J5.98 ; J5.98 45.43,135.42 ; J5.98 44.27,136.58 ; J5.98 45.43,136.58 ; 164.07,137.58 J7.217 ; J7.217 164.07,136.42 ; J7.217 165.23,136.42 ; J7.217 165.23,137.58 ; J106.3 129.2,241.22 ; J106.3 129.2,239.97 ; J106.3 127.95,241.22 ; J106.3 127.95,239.97 ; 164.07,207.58 J7.151 ; J7.151 165.23,206.42 ; J7.151 165.23,207.58 ; J7.151 164.07,206.42 ; J3.A23 203.17,207.12 ; J3.A23 203.17,208.18 ; J3.A23 202.12,208.18 ; J3.A23 202.12,207.12 ; 160.27,133.58 J7.101 ; J7.101 160.27,132.42 ; J7.101 161.43,133.58 ; J7.101 161.43,132.42 ; J5.35 47.33,203.58 ; J5.35 47.33,202.42 ; J5.35 46.17,202.42 ; J5.35 46.17,203.58 ; C5340.2 21.65,144.4 ; C5340.2 19.97,144.4 ; C5340.2 21.65,146.08 ; C5340.2 19.97,146.08 ; J5.235 51.13,119.58 ; J5.235 49.97,119.58 ; J5.235 51.13,118.42 ; J5.235 49.97,118.42 ; J7.110 159.53,123.42 ; J7.110 158.37,123.42 ; J7.110 158.37,124.58 ; J7.110 159.53,124.58 ; 164.07,116.42 J7.237 ; J7.237 164.07,117.58 ; J7.237 165.23,117.58 ; J7.237 165.23,116.42 ; J6.232 151.93,228.42 ; J6.232 150.77,229.58 ; J6.232 150.77,228.42 ; J6.232 151.93,229.58 ; J3.A31 203.17,200.18 ; J3.A31 202.12,199.12 ; J3.A31 203.17,199.12 ; J3.A31 202.12,200.18 ; J13.20 171.45,25.2 ; J13.20 171.45,23.88 ; J13.20 170.13,25.2 ; J13.20 170.13,23.88 ; J10.M1 23.77,56.57 ; J10.M1 23.77,54.6 ; J10.M1 21.8,56.57 ; J10.M1 21.8,54.6 ; J5.110 45.43,124.58 ; J5.110 44.27,124.58 ; J5.110 44.27,123.42 ; J5.110 45.43,123.42 ; 148.87,119.42 J6.127 ; J6.127 148.87,120.58 ; J6.127 150.03,120.58 ; J6.127 150.03,119.42 ; J5.17 47.33,220.42 ; J5.17 46.17,221.58 ; J5.17 47.33,221.58 ; J5.17 46.17,220.42 ; J5.113 47.33,120.42 ; J5.113 46.17,121.58 ; J5.113 46.17,120.42 ; J5.113 47.33,121.58 ; J6.208 151.93,204.42 ; J6.208 151.93,205.58 ; J6.208 150.77,205.58 ; J6.208 150.77,204.42 ; 150.77,134.42 J6.142 ; J6.142 150.77,135.58 ; J6.142 151.93,135.58 ; J6.142 151.93,134.42 ; 44.27,199.42 J5.38 ; J5.38 45.43,199.42 ; J5.38 45.43,200.58 ; J5.38 44.27,200.58 ; 9.04,248.53 FAN5.1 ; FAN5.1 9.04,250.12 ; FAN5.1 10.64,250.12 ; FAN5.1 10.64,248.53 ; 9.5,2.96 SW6.2 ; SW6.2 11.02,2.96 ; SW6.2 9.5,4.48 ; SW6.2 11.02,4.48 ; 191.9,25.2 J14.20 ; J14.20 193.22,25.2 ; J14.20 191.9,23.88 ; J5.32 45.43,206.58 ; J5.32 44.27,205.42 ; J5.32 44.27,206.58 ; J5.32 45.43,205.42 ; J7.232 163.33,121.42 ; J7.232 163.33,122.58 ; J7.232 162.17,121.42 ; J7.232 162.17,122.58 ; J3.B4 198.67,228.12 ; J3.B4 197.62,228.12 ; J3.B4 197.62,229.18 ; J3.B4 198.67,229.18 ; 204.12,213.18 J3.A18 ; J3.A18 205.17,212.12 ; J3.A18 204.12,212.12 ; J3.A18 205.17,213.18 ; J6.136 151.93,129.58 ; J6.136 150.77,129.58 ; J6.136 151.93,128.42 ; J6.136 150.77,128.42 ; 46.17,197.58 J5.41 ; J5.41 47.33,196.42 ; J5.41 46.17,196.42 ; J5.41 47.33,197.58 ; 164.07,213.58 J7.145 ; J7.145 165.23,212.42 ; J7.145 165.23,213.58 ; J7.145 164.07,212.42 ; 49.97,154.42 J5.199 ; J5.199 49.97,155.58 ; J5.199 51.13,154.42 ; J5.199 51.13,155.58 ; 46.17,127.58 J5.107 ; J5.107 46.17,126.42 ; J5.107 47.33,127.58 ; J5.107 47.33,126.42 ; 197.62,208.12 J3.B22 ; J3.B22 198.67,209.18 ; J3.B22 198.67,208.12 ; J3.B22 197.62,209.18 ; 199.62,226.18 J3.B7 ; J3.B7 200.67,226.18 ; J3.B7 200.67,225.12 ; J3.B7 199.62,225.12 ; J6.110 155.73,227.58 ; J6.110 154.57,227.58 ; J6.110 154.57,226.42 ; J6.110 155.73,226.42 ; 199.62,217.12 J3.B13 ; J3.B13 199.62,218.18 ; J3.B13 200.67,218.18 ; J3.B13 200.67,217.12 ; 164.07,142.42 J7.211 ; J7.211 165.23,143.58 ; J7.211 164.07,143.58 ; J7.211 165.23,142.42 ; J6.29 153.83,141.42 ; J6.29 153.83,142.58 ; J6.29 152.67,142.58 ; J6.29 152.67,141.42 ; 202.12,189.12 J3.A41 ; J3.A41 203.17,189.12 ; J3.A41 203.17,190.18 ; J3.A41 202.12,190.18 ; J6.80 155.73,196.42 ; J6.80 154.57,196.42 ; J6.80 154.57,197.58 ; J6.80 155.73,197.58 ; 154.57,151.58 J6.38 ; J6.38 154.57,150.42 ; J6.38 155.73,150.42 ; J6.38 155.73,151.58 ; J5.29 47.33,209.58 ; J5.29 47.33,208.42 ; J5.29 46.17,209.58 ; J5.29 46.17,208.42 ; J12.1 137.79,14.79 ; J12.1 137.79,13.46 ; J12.1 136.47,13.46 ; J12.1 136.47,14.79 ; 202.12,216.18 J3.A15 ; J3.A15 203.17,215.12 ; J3.A15 203.17,216.18 ; J3.A15 202.12,215.12 ; 148.87,131.42 J6.139 ; J6.139 148.87,132.58 ; J6.139 150.03,132.58 ; J6.139 150.03,131.42 ; J7.163 165.23,194.42 ; J7.163 165.23,195.58 ; J7.163 164.07,194.42 ; J7.163 164.07,195.58 ; J5.47 47.33,190.42 ; J5.47 46.17,191.58 ; J5.47 46.17,190.42 ; J5.47 47.33,191.58 ; J7.35 161.43,203.58 ; J7.35 161.43,202.42 ; J7.35 160.27,202.42 ; J7.35 160.27,203.58 ; J7.29 161.43,208.42 ; J7.29 160.27,208.42 ; J7.29 161.43,209.58 ; J7.29 160.27,209.58 ; 148.87,231.42 J6.235 ; J6.235 150.03,232.58 ; J6.235 148.87,232.58 ; J6.235 150.03,231.42 ; 3.18,167.08 J8.2 ; J8.2 4.97,167.08 ; J8.2 3.18,165.29 ; J8.2 4.97,165.29 ; J5.148 49.23,210.58 ; J5.148 48.07,210.58 ; J5.148 49.23,209.42 ; J5.148 48.07,209.42 ; J6.35 153.83,147.42 ; J6.35 153.83,148.58 ; J6.35 152.67,148.58 ; J6.35 152.67,147.42 ; 160.27,214.42 J7.23 ; J7.23 160.27,215.58 ; J7.23 161.43,214.42 ; J7.23 161.43,215.58 ; J7.124 163.33,234.58 ; J7.124 162.17,234.58 ; J7.124 162.17,233.42 ; J7.124 163.33,233.42 ; J6.160 151.93,152.42 ; J6.160 150.77,153.58 ; J6.160 150.77,152.42 ; J6.160 151.93,153.58 ; 164.07,237.58 J7.121 ; J7.121 165.23,237.58 ; J7.121 165.23,236.42 ; J7.121 164.07,236.42 ; J6.92 155.73,208.42 ; J6.92 154.57,208.42 ; J6.92 155.73,209.58 ; J6.92 154.57,209.58 ; J3.B40 198.67,191.18 ; J3.B40 197.62,190.12 ; J3.B40 197.62,191.18 ; J3.B40 198.67,190.12 ; 49.97,212.42 J5.145 ; J5.145 51.13,213.58 ; J5.145 51.13,212.42 ; J5.145 49.97,213.58 ; J8.4 4.97,175.47 ; J8.4 4.97,173.68 ; J8.4 3.18,173.68 ; J8.4 3.18,175.47 ; 202.12,186.18 J3.A45 ; J3.A45 202.12,185.12 ; J3.A45 203.17,186.18 ; J3.A45 203.17,185.12 ; J6.166 151.93,158.42 ; J6.166 151.93,159.58 ; J6.166 150.77,158.42 ; J6.166 150.77,159.58 ; 162.17,152.58 J7.202 ; J7.202 162.17,151.42 ; J7.202 163.33,152.58 ; J7.202 163.33,151.42 ; J5.117 47.33,116.42 ; J5.117 47.33,117.58 ; J5.117 46.17,117.58 ; J5.117 46.17,116.42 ; 48.07,233.42 J5.124 ; J5.124 49.23,234.58 ; J5.124 48.07,234.58 ; J5.124 49.23,233.42 ; J5.226 49.23,128.58 ; J5.226 49.23,127.42 ; J5.226 48.07,128.58 ; J5.226 48.07,127.42 ; 150.77,147.58 J6.154 ; J6.154 150.77,146.42 ; J6.154 151.93,146.42 ; J6.154 151.93,147.58 ; J7.229 165.23,125.58 ; J7.229 165.23,124.42 ; J7.229 164.07,125.58 ; J7.229 164.07,124.42 ; 8.58,138.96 J9.24 ; J9.24 10.57,136.98 ; J9.24 10.57,138.96 ; J9.24 8.58,136.98 ; 154.57,202.42 J6.86 ; J6.86 154.57,203.58 ; J6.86 155.73,203.58 ; J6.86 155.73,202.42 ; J6.47 153.83,159.42 ; J6.47 152.67,160.58 ; J6.47 153.83,160.58 ; J6.47 152.67,159.42 ; J5.142 49.23,215.42 ; J5.142 48.07,216.58 ; J5.142 48.07,215.42 ; J5.142 49.23,216.58 ; J6.119 153.83,236.58 ; J6.119 152.67,236.58 ; J6.119 153.83,235.42 ; J6.119 152.67,235.42 ; J5.208 49.23,146.58 ; J5.208 48.07,145.42 ; J5.208 49.23,145.42 ; J5.208 48.07,146.58 ; J5.154 49.23,203.42 ; J5.154 49.23,204.58 ; J5.154 48.07,204.58 ; J5.154 48.07,203.42 ; SW6.4 12.45,5.28 ; SW6.4 10.57,5.28 ; SW6.4 12.45,7.16 ; SW6.4 10.57,7.16 ; 158.37,211.42 J7.26 ; J7.26 158.37,212.58 ; J7.26 159.53,212.58 ; J7.26 159.53,211.42 ; 152.67,124.58 J6.11 ; J6.11 153.83,123.42 ; J6.11 153.83,124.58 ; J6.11 152.67,123.42 ; 48.07,222.58 J5.136 ; J5.136 49.23,222.58 ; J5.136 49.23,221.42 ; J5.136 48.07,221.42 ; J5.220 49.23,133.42 ; J5.220 48.07,133.42 ; J5.220 49.23,134.58 ; J5.220 48.07,134.58 ; 240.63,204.72 J4.2 239.18,204.72 ; J5.95 47.33,138.42 ; J5.95 46.17,138.42 ; J5.95 47.33,139.58 ; J5.95 46.17,139.58 ; J5.89 47.33,145.58 ; J5.89 46.17,145.58 ; J5.89 47.33,144.42 ; J5.89 46.17,144.42 ; J6.83 153.83,199.42 ; J6.83 153.83,200.58 ; J6.83 152.67,200.58 ; J6.83 152.67,199.42 ; 197.62,213.18 J3.B18 ; J3.B18 198.67,213.18 ; J3.B18 197.62,212.12 ; J3.B18 198.67,212.12 ; J9.15 10.57,99.18 ; J9.15 8.58,99.18 ; J9.15 10.57,101.16 ; J9.15 8.58,101.16 ; 16.9,18.15 SW5.1 ; SW5.1 16.9,16.45 ; SW5.1 18.6,18.15 ; SW5.1 18.6,16.45 ; 240.5,210.95 J55.2 239.05,210.95 ; 3.08,107.58 J9.5 ; J9.5 5.07,107.58 ; J9.5 5.07,109.56 ; J9.5 3.08,109.56 ; J6.205 150.03,201.42 ; J6.205 148.87,201.42 ; J6.205 150.03,202.58 ; J6.205 148.87,202.58 ; J5.163 51.13,194.42 ; J5.163 49.97,194.42 ; J5.163 49.97,195.58 ; J5.163 51.13,195.58 ; J6.148 151.93,141.58 ; J6.148 151.93,140.42 ; J6.148 150.77,140.42 ; J6.148 150.77,141.58 ; 160.27,116.42 J7.117 ; J7.117 160.27,117.58 ; J7.117 161.43,116.42 ; J7.117 161.43,117.58 ; J6.151 150.03,144.58 ; J6.151 150.03,143.42 ; J6.151 148.87,144.58 ; J6.151 148.87,143.42 ; J3.A37 203.17,194.18 ; J3.A37 202.12,193.12 ; J3.A37 203.17,193.12 ; J3.A37 202.12,194.18 ; FAN4.1 64.44,250.12 ; FAN4.1 64.44,248.53 ; FAN4.1 62.85,248.53 ; FAN4.1 62.85,250.12 ; CT35.2 22.76,92.12 ; CT35.2 22.76,93.81 ; CT35.2 21.07,93.81 ; CT35.2 21.07,92.12 ; J3.A49 203.17,181.12 ; J3.A49 202.12,182.18 ; J3.A49 203.17,182.18 ; 44.27,236.58 J5.2 ; J5.2 44.27,235.42 ; J5.2 45.43,236.58 ; J5.2 45.43,235.42 ; FAN3.1 42.53,250.12 ; FAN3.1 40.94,250.12 ; FAN3.1 40.94,248.53 ; FAN3.1 42.53,248.53 ; 44.27,217.42 J5.20 ; J5.20 45.43,217.42 ; J5.20 44.27,218.58 ; J5.20 45.43,218.58 ; J6.157 150.03,150.58 ; J6.157 148.87,150.58 ; J6.157 150.03,149.42 ; J6.157 148.87,149.42 ; 42.82,12.55 CN4.A4 42.82,13.9 ; J7.154 163.33,204.58 ; J7.154 162.17,204.58 ; J7.154 163.33,203.42 ; J7.154 162.17,203.42 ; 158.24,13.46 J13.1 ; J13.1 158.24,14.79 ; J13.1 159.56,14.79 ; J13.1 159.56,13.46 ; J5.229 51.13,124.42 ; J5.229 49.97,125.58 ; J5.229 51.13,125.58 ; J5.229 49.97,124.42 ; 158.37,199.42 J7.38 ; J7.38 159.53,199.42 ; J7.38 158.37,200.58 ; J7.38 159.53,200.58 ; 46.17,232.42 J5.5 ; J5.5 46.17,233.58 ; J5.5 47.33,233.58 ; J5.5 47.33,232.42 ; J6.23 153.83,135.42 ; J6.23 152.67,135.42 ; J6.23 153.83,136.58 ; J6.23 152.67,136.58 ; J5.205 51.13,149.58 ; J5.205 49.97,148.42 ; J5.205 49.97,149.58 ; J5.205 51.13,148.42 ; 42.82,11.28 CN4.B4 42.82,9.93 ; 44.27,224.58 J5.14 ; J5.14 45.43,223.42 ; J5.14 44.27,223.42 ; J5.14 45.43,224.58 ; 204.12,188.12 J3.A42 ; J3.A42 204.12,189.18 ; J3.A42 205.17,188.12 ; J3.A42 205.17,189.18 ; 21.43,118.92 CT31.2 ; CT31.2 23.11,118.92 ; CT31.2 21.43,120.6 ; CT31.2 23.11,120.6 ; 263.48,76.91 C5345.2 ; C5345.2 263.48,75.11 ; C5345.2 265.29,75.11 ; C5345.2 265.29,76.91 ; 160.27,139.58 J7.95 ; J7.95 160.27,138.42 ; J7.95 161.43,139.58 ; J7.95 161.43,138.42 ; J3.B16 198.67,215.18 ; J3.B16 197.62,214.12 ; J3.B16 197.62,215.18 ; J3.B16 198.67,214.12 ; J11.20 127.91,23.88 ; J11.20 127.91,25.2 ; J11.20 126.59,25.2 ; J11.20 126.59,23.88 ; J6.101 153.83,218.58 ; J6.101 152.67,217.42 ; J6.101 153.83,217.42 ; J6.101 152.67,218.58 ; J3.A38 205.17,192.12 ; J3.A38 204.12,193.18 ; J3.A38 205.17,193.18 ; J3.A38 204.12,192.12 ; J8.3 4.97,169.48 ; J8.3 3.18,169.48 ; J8.3 4.97,171.27 ; J8.3 3.18,171.27 ; 49.97,225.58 J5.133 ; J5.133 49.97,224.42 ; J5.133 51.13,225.58 ; J5.133 51.13,224.42 ; J6.211 150.03,208.58 ; J6.211 148.87,207.42 ; J6.211 150.03,207.42 ; J6.211 148.87,208.58 ; 190.8,242.83 C5339.2 ; C5339.2 190.8,244.51 ; C5339.2 192.48,244.51 ; C5339.2 192.48,242.83 ; 199.62,181.12 J3.B49 ; J3.B49 200.67,182.18 ; J3.B49 199.62,182.18 ; 73.12,246.15 C5289.2 ; C5289.2 73.12,247.83 ; C5289.2 74.81,247.83 ; C5289.2 74.81,246.15 ; 46.75,80.64 JP7.2 45.3,80.64
  L4_GND_2 w0.914: 113.7,209.45 BH10.1 ; BH10.1 113.7,213.18 ; BH10.1 117.43,209.45 ; BH10.1 117.43,213.18
  L4_GND_2 w1.016: H5.1 139.13,195.99 ; H5.1 132.87,195.99 ; H5.1 139.13,202.25 ; H5.1 132.87,202.25 ; 223.87,250.13 H7.1 ; H7.1 230.13,250.13 ; H7.1 230.13,243.87 ; H7.1 223.87,243.87 ; 2.87,153.23 H9.1 ; H9.1 9.13,153.23 ; H9.1 9.13,146.97 ; H9.1 2.87,146.97 ; H14.1 72.93,41.87 ; H14.1 66.67,41.87 ; H14.1 72.93,48.13 ; H14.1 66.67,48.13 ; H16.1 9.13,22.13 ; H16.1 9.13,15.87 ; H16.1 2.87,22.13 ; H16.1 2.87,15.87 ; 132.87,123.99 H11.1 ; H11.1 139.13,130.25 ; H11.1 139.13,123.99 ; H11.1 132.87,130.25 ; H2.1 178.73,250.13 ; H2.1 172.47,250.13 ; H2.1 172.47,243.87 ; H2.1 178.73,243.87 ; H4.1 67.13,202.25 ; H4.1 60.87,195.99 ; H4.1 67.13,195.99 ; H4.1 60.87,202.25 ; H6.1 178.69,171.9 ; H6.1 178.69,178.1 ; H6.1 172.5,171.9 ; H6.1 172.5,178.1 ; 66.67,100.13 H12.1 ; H12.1 72.93,100.13 ; H12.1 66.67,93.87 ; H12.1 72.93,93.87 ; H8.1 282.13,124.62 ; H8.1 282.13,130.88 ; H8.1 275.87,130.88 ; H8.1 275.87,124.62 ; H1.1 31.13,250.13 ; H1.1 24.87,250.13 ; H1.1 31.13,243.87 ; H1.1 24.87,243.87 ; H15.1 282.13,15.87 ; H15.1 275.87,15.87 ; H15.1 282.13,22.13 ; H15.1 275.87,22.13 ; H13.1 142.93,69.13 ; H13.1 142.93,62.87 ; H13.1 136.67,62.87 ; H13.1 136.67,69.13 ; H10.1 67.13,130.25 ; H10.1 67.13,123.99 ; H10.1 60.87,123.99 ; H10.1 60.87,130.25 ; H3.1 282.13,250.13 ; H3.1 275.87,243.87 ; H3.1 275.87,250.13 ; H3.1 282.13,243.87
  L5_INT_2 w0.508: J7.86 159.53,148.58 ; J7.86 159.53,147.42 ; J7.86 158.37,148.58 ; J7.86 158.37,147.42 ; SW6.4 12.45,7.16 ; SW6.4 10.57,7.16 ; SW6.4 10.57,5.28 ; SW6.4 12.45,5.28 ; J3.A20 205.17,211.18 ; J3.A20 204.12,210.12 ; J3.A20 204.12,211.18 ; J3.A20 205.17,210.12 ; J3.A34 205.17,196.12 ; J3.A34 204.12,196.12 ; J3.A34 204.12,197.18 ; J3.A34 205.17,197.18 ; J3.B43 200.67,187.12 ; J3.B43 200.67,188.18 ; J3.B43 199.62,187.12 ; J3.B43 199.62,188.18 ; J7.232 163.33,122.58 ; J7.232 162.17,122.58 ; J7.232 162.17,121.42 ; J7.232 163.33,121.42 ; J3.B18 198.67,212.12 ; J3.B18 197.62,213.18 ; J3.B18 198.67,213.18 ; J3.B18 197.62,212.12 ; J3.A42 205.17,188.12 ; J3.A42 204.12,188.12 ; J3.A42 204.12,189.18 ; J3.A42 205.17,189.18 ; 202.12,185.12 J3.A45 ; J3.A45 203.17,186.18 ; J3.A45 203.17,185.12 ; J3.A45 202.12,186.18 ; J7.95 161.43,138.42 ; J7.95 161.43,139.58 ; J7.95 160.27,138.42 ; J7.95 160.27,139.58 ; J7.104 159.53,129.42 ; J7.104 158.37,130.58 ; J7.104 159.53,130.58 ; J7.104 158.37,129.42 ; 8.58,109.56 J9.17 ; J9.17 10.57,109.56 ; J9.17 8.58,107.58 ; J9.17 10.57,107.58 ; 164.07,154.42 J7.199 ; J7.199 165.23,154.42 ; J7.199 165.23,155.58 ; J7.199 164.07,155.58 ; J9.3 5.07,101.16 ; J9.3 3.08,101.16 ; J9.3 5.07,99.18 ; J9.3 3.08,99.18 ; 62.85,248.53 FAN4.1 ; FAN4.1 64.44,250.12 ; FAN4.1 62.85,250.12 ; FAN4.1 64.44,248.53 ; 204.12,185.18 J3.A46 ; J3.A46 204.12,184.12 ; J3.A46 205.17,184.12 ; J3.A46 205.17,185.18 ; J7.211 165.23,142.42 ; J7.211 164.07,142.42 ; J7.211 165.23,143.58 ; J7.211 164.07,143.58 ; 195.24,52.65 FAN1.1 ; FAN1.1 195.24,51.05 ; FAN1.1 196.84,52.65 ; FAN1.1 196.84,51.05 ; 8.58,136.98 J9.24 ; J9.24 8.58,138.96 ; J9.24 10.57,138.96 ; J9.24 10.57,136.98 ; FAN12.1 21.75,250.12 ; FAN12.1 21.75,248.53 ; FAN12.1 20.16,250.12 ; FAN12.1 20.16,248.53 ; 204.12,192.12 J3.A38 ; J3.A38 205.17,193.18 ; J3.A38 205.17,192.12 ; J3.A38 204.12,193.18 ; 164.07,130.42 J7.223 ; J7.223 165.23,131.58 ; J7.223 165.23,130.42 ; J7.223 164.07,131.58 ; 199.62,206.18 J3.B25 ; J3.B25 199.62,205.12 ; J3.B25 200.67,205.12 ; J3.B25 200.67,206.18 ; J7.217 165.23,136.42 ; J7.217 164.07,137.58 ; J7.217 165.23,137.58 ; J7.217 164.07,136.42 ; 239.18,204.72 J4.2 240.63,204.72 ; 3.18,175.47 J8.4 ; J8.4 3.18,173.68 ; J8.4 4.97,173.68 ; J8.4 4.97,175.47 ; J7.205 165.23,148.42 ; J7.205 164.07,148.42 ; J7.205 165.23,149.58 ; J7.205 164.07,149.58 ; 3.08,117.96 J9.7 ; J9.7 5.07,115.98 ; J9.7 3.08,115.98 ; J9.7 5.07,117.96 ; 202.12,190.18 J3.A41 ; J3.A41 203.17,190.18 ; J3.A41 202.12,189.12 ; J3.A41 203.17,189.12 ; 204.12,206.12 J3.A24 ; J3.A24 205.17,207.18 ; J3.A24 204.12,207.18 ; J3.A24 205.17,206.12 ; 202.12,208.18 J3.A23 ; J3.A23 202.12,207.12 ; J3.A23 203.17,208.18 ; J3.A23 203.17,207.12 ; 199.62,201.12 J3.B29 ; J3.B29 200.67,202.18 ; J3.B29 199.62,202.18 ; J3.B29 200.67,201.12 ; 199.62,226.18 J3.B7 ; J3.B7 200.67,226.18 ; J3.B7 199.62,225.12 ; J3.B7 200.67,225.12 ; C5337.2 208.74,244.51 ; C5337.2 208.74,242.83 ; C5337.2 207.06,244.51 ; C5337.2 207.06,242.83 ; 190.8,242.83 C5339.2 ; C5339.2 190.8,244.51 ; C5339.2 192.48,244.51 ; C5339.2 192.48,242.83 ; J3.A27 203.17,203.12 ; J3.A27 202.12,204.18 ; J3.A27 203.17,204.18 ; J3.A27 202.12,203.12 ; J7.80 159.53,154.58 ; J7.80 158.37,154.58 ; J7.80 159.53,153.42 ; J7.80 158.37,153.42 ; J7.107 161.43,126.42 ; J7.107 161.43,127.58 ; J7.107 160.27,126.42 ; J7.107 160.27,127.58 ; J3.B39 200.67,192.18 ; J3.B39 199.62,192.18 ; J3.B39 199.62,191.12 ; J3.B39 200.67,191.12 ; J3.A49 203.17,182.18 ; J3.A49 203.17,181.12 ; J3.A49 202.12,182.18 ; 202.12,193.12 J3.A37 ; J3.A37 203.17,193.12 ; J3.A37 203.17,194.18 ; J3.A37 202.12,194.18 ; J7.226 163.33,128.58 ; J7.226 162.17,128.58 ; J7.226 162.17,127.42 ; J7.226 163.33,127.42 ; J7.92 159.53,142.58 ; J7.92 158.37,141.42 ; J7.92 158.37,142.58 ; J7.92 159.53,141.42 ; 9.5,4.48 SW6.2 ; SW6.2 11.02,4.48 ; SW6.2 9.5,2.96 ; SW6.2 11.02,2.96 ; 197.62,204.12 J3.B26 ; J3.B26 198.67,204.12 ; J3.B26 197.62,205.18 ; J3.B26 198.67,205.18 ; 243,247.73 243.71,247.01 ; 243.71,247.01 244.43,247.73 ; 243.71,247.01 243,246.3 ; 243.71,247.01 244.43,246.3 ; J7.83 161.43,150.42 ; J7.83 161.43,151.58 ; J7.83 160.27,150.42 ; J7.83 160.27,151.58 ; J3.B16 198.67,215.18 ; J3.B16 198.67,214.12 ; J3.B16 197.62,215.18 ; J3.B16 197.62,214.12 ; J3.B13 200.67,218.18 ; J3.B13 199.62,218.18 ; J3.B13 199.62,217.12 ; J3.B13 200.67,217.12 ; 204.12,219.18 J3.A12 ; J3.A12 204.12,218.12 ; J3.A12 205.17,219.18 ; J3.A12 205.17,218.12 ; J7.98 159.53,135.42 ; J7.98 158.37,135.42 ; J7.98 159.53,136.58 ; J7.98 158.37,136.58 ; J3.A1 203.17,232.18 ; J3.A1 203.17,231.12 ; J3.A1 202.12,232.18 ; J3.A1 202.12,231.12 ; 162.17,151.42 J7.202 ; J7.202 163.33,152.58 ; J7.202 163.33,151.42 ; J7.202 162.17,152.58 ; SW6.3 5.45,5.28 ; SW6.3 3.57,7.16 ; SW6.3 5.45,7.16 ; SW6.3 3.57,5.28 ; FAN5.1 10.64,250.12 ; FAN5.1 9.04,250.12 ; FAN5.1 10.64,248.53 ; FAN5.1 9.04,248.53 ; 20.8,41.77 J10.M2 ; J10.M2 22.77,41.77 ; J10.M2 20.8,43.74 ; J10.M2 22.77,43.74 ; 19.97,144.4 C5340.2 ; C5340.2 19.97,146.08 ; C5340.2 21.65,146.08 ; C5340.2 21.65,144.4 ; 199.62,195.12 J3.B35 ; J3.B35 200.67,196.18 ; J3.B35 199.62,196.18 ; J3.B35 200.67,195.12 ; 160.27,145.58 J7.89 ; J7.89 161.43,145.58 ; J7.89 161.43,144.42 ; J7.89 160.27,144.42 ; 40.94,250.12 FAN3.1 ; FAN3.1 42.53,250.12 ; FAN3.1 40.94,248.53 ; FAN3.1 42.53,248.53 ; J3.B49 200.67,182.18 ; J3.B49 199.62,181.12 ; J3.B49 199.62,182.18 ; 8.58,115.98 J9.19 ; J9.19 10.57,115.98 ; J9.19 8.58,117.96 ; J9.19 10.57,117.96 ; 3.18,171.27 J8.3 ; J8.3 4.97,169.48 ; J8.3 4.97,171.27 ; J8.3 3.18,169.48 ; 8.58,101.16 J9.15 ; J9.15 10.57,101.16 ; J9.15 8.58,99.18 ; J9.15 10.57,99.18 ; J9.5 5.07,107.58 ; J9.5 3.08,107.58 ; J9.5 5.07,109.56 ; J9.5 3.08,109.56 ; J7.101 161.43,133.58 ; J7.101 160.27,132.42 ; J7.101 161.43,132.42 ; J7.101 160.27,133.58 ; 42.82,13.9 CN4.A4 42.82,12.55 ; J3.A18 205.17,213.18 ; J3.A18 204.12,213.18 ; J3.A18 204.12,212.12 ; J3.A18 205.17,212.12 ; 39.34,30.18 C5341.2 ; C5341.2 39.34,28.5 ; C5341.2 41.02,28.5 ; C5341.2 41.02,30.18 ; J3.A4 205.17,228.12 ; J3.A4 204.12,228.12 ; J3.A4 204.12,229.18 ; J3.A4 205.17,229.18 ; 164.07,124.42 J7.229 ; J7.229 165.23,124.42 ; J7.229 164.07,125.58 ; J7.229 165.23,125.58 ; C5342.2 22.77,28.5 ; C5342.2 21.08,30.18 ; C5342.2 21.08,28.5 ; C5342.2 22.77,30.18 ; 202.12,200.18 J3.A31 ; J3.A31 203.17,199.12 ; J3.A31 203.17,200.18 ; J3.A31 202.12,199.12 ; 162.17,134.58 J7.220 ; J7.220 162.17,133.42 ; J7.220 163.33,134.58 ; J7.220 163.33,133.42 ; 8.58,111.77 J9.18 ; J9.18 10.57,111.77 ; J9.18 8.58,113.76 ; J9.18 10.57,113.76 ; C5338.2 188.17,228.35 ; C5338.2 188.17,230.04 ; C5338.2 186.48,230.04 ; C5338.2 186.48,228.35 ; 162.17,139.42 J7.214 ; J7.214 163.33,140.58 ; J7.214 163.33,139.42 ; J7.214 162.17,140.58 ; J2.16 239.35,246.3 ; J2.16 237.92,247.73 ; J2.16 239.35,247.73 ; J2.16 237.92,246.3 ; J3.B47 200.67,184.18 ; J3.B47 199.62,183.12 ; J3.B47 199.62,184.18 ; J3.B47 200.67,183.12 ; J3.B21 200.67,210.18 ; J3.B21 199.62,210.18 ; J3.B21 199.62,209.12 ; J3.B21 200.67,209.12 ; J8.1 4.97,162.89 ; J8.1 3.18,161.1 ; J8.1 4.97,161.1 ; J8.1 3.18,162.89 ; J3.A15 203.17,216.18 ; J3.A15 202.12,216.18 ; J3.A15 203.17,215.12 ; J3.A15 202.12,215.12 ; 160.27,121.58 J7.113 161.43,121.58 ; 162.17,146.58 J7.208 ; J7.208 163.33,145.42 ; J7.208 162.17,145.42 ; J7.208 163.33,146.58 ; 197.62,199.18 J3.B32 ; J3.B32 198.67,198.12 ; J3.B32 197.62,198.12 ; J3.B32 198.67,199.18 ; 42.82,11.28 CN4.B4 42.82,9.93 ; 158.37,123.42 J7.110 ; J7.110 159.53,124.58 ; J7.110 158.37,124.58 ; J7.110 159.53,123.42 ; 21.8,56.57 J10.M1 ; J10.M1 23.77,54.6 ; J10.M1 23.77,56.57 ; J10.M1 21.8,54.6 ; 263.48,76.91 C5345.2 ; C5345.2 263.48,75.11 ; C5345.2 265.29,76.91 ; C5345.2 265.29,75.11 ; J8.2 4.97,167.08 ; J8.2 4.97,165.29 ; J8.2 3.18,165.29 ; J8.2 3.18,167.08 ; 197.62,228.12 J3.B4 ; J3.B4 198.67,229.18 ; J3.B4 197.62,229.18 ; J3.B4 198.67,228.12 ; J3.B44 198.67,186.12 ; J3.B44 198.67,187.18 ; J3.B44 197.62,186.12 ; J3.B44 197.62,187.18 ; 197.62,190.12 J3.B40 ; J3.B40 197.62,191.18 ; J3.B40 198.67,191.18 ; J3.B40 198.67,190.12 ; 197.62,209.18 J3.B22 ; J3.B22 198.67,208.12 ; J3.B22 197.62,208.12 ; J3.B22 198.67,209.18 ; SW5.1 18.6,18.15 ; SW5.1 18.6,16.45 ; SW5.1 16.9,16.45 ; SW5.1 16.9,18.15 ; 197.62,194.12 J3.B36 ; J3.B36 197.62,195.18 ; J3.B36 198.67,194.12 ; J3.B36 198.67,195.18 ; J3.A28 205.17,202.12 ; J3.A28 205.17,203.18 ; J3.A28 204.12,202.12 ; J3.A28 204.12,203.18
  L5_INT_2 w1.016: 24.87,250.13 H1.1 ; H1.1 24.87,243.87 ; H1.1 31.13,250.13 ; H1.1 31.13,243.87 ; 2.87,15.87 H16.1 ; H16.1 9.13,15.87 ; H16.1 2.87,22.13 ; H16.1 9.13,22.13 ; 223.87,250.13 H7.1 ; H7.1 230.13,250.13 ; H7.1 223.87,243.87 ; H7.1 230.13,243.87 ; 2.87,153.23 H9.1 ; H9.1 2.87,146.97 ; H9.1 9.13,153.23 ; H9.1 9.13,146.97 ; 275.87,130.88 H8.1 ; H8.1 275.87,124.62 ; H8.1 282.13,124.62 ; H8.1 282.13,130.88 ; H6.1 178.69,171.9 ; H6.1 172.5,171.9 ; H6.1 172.5,178.1 ; H6.1 178.69,178.1 ; 275.87,250.13 H3.1 ; H3.1 275.87,243.87 ; H3.1 282.13,243.87 ; H3.1 282.13,250.13
  L6_GND_3 w0.508: 197.62,186.12 J3.B44 ; J3.B44 198.67,187.18 ; J3.B44 198.67,186.12 ; J3.B44 197.62,187.18 ; 8.58,115.98 J9.19 ; J9.19 8.58,117.96 ; J9.19 10.57,115.98 ; J9.19 10.57,117.96 ; 49.97,200.42 J5.157 ; J5.157 51.13,200.42 ; J5.157 51.13,201.58 ; J5.157 49.97,201.58 ; 49.97,143.58 J5.211 ; J5.211 51.13,143.58 ; J5.211 49.97,142.42 ; J5.211 51.13,142.42 ; J6.205 150.03,202.58 ; J6.205 150.03,201.42 ; J6.205 148.87,202.58 ; J6.205 148.87,201.42 ; J5.101 47.33,133.58 ; J5.101 46.17,132.42 ; J5.101 46.17,133.58 ; J5.101 47.33,132.42 ; 46.17,117.58 J5.117 ; J5.117 46.17,116.42 ; J5.117 47.33,117.58 ; J5.117 47.33,116.42 ; 164.07,136.42 J7.217 ; J7.217 165.23,136.42 ; J7.217 165.23,137.58 ; J7.217 164.07,137.58 ; 150.77,129.58 J6.136 ; J6.136 151.93,129.58 ; J6.136 151.93,128.42 ; J6.136 150.77,128.42 ; 204.12,185.18 J3.A46 ; J3.A46 204.12,184.12 ; J3.A46 205.17,185.18 ; J3.A46 205.17,184.12 ; J3.A34 205.17,197.18 ; J3.A34 205.17,196.12 ; J3.A34 204.12,197.18 ; J3.A34 204.12,196.12 ; 42.82,12.55 CN4.A4 42.82,13.9 ; J7.8 159.53,230.58 ; J7.8 158.37,230.58 ; J7.8 158.37,229.42 ; J7.8 159.53,229.42 ; 160.27,203.58 J7.35 ; J7.35 161.43,203.58 ; J7.35 161.43,202.42 ; J7.35 160.27,202.42 ; FAN2.1 144.56,250.12 ; FAN2.1 142.97,250.12 ; FAN2.1 144.56,248.53 ; FAN2.1 142.97,248.53 ; 199.62,181.12 J3.B49 ; J3.B49 199.62,182.18 ; J3.B49 200.67,182.18 ; 48.07,222.58 J5.136 ; J5.136 48.07,221.42 ; J5.136 49.23,221.42 ; J5.136 49.23,222.58 ; 158.37,200.58 J7.38 ; J7.38 159.53,200.58 ; J7.38 158.37,199.42 ; J7.38 159.53,199.42 ; 49.97,194.42 J5.163 ; J5.163 51.13,195.58 ; J5.163 51.13,194.42 ; J5.163 49.97,195.58 ; 44.27,124.58 J5.110 ; J5.110 45.43,123.42 ; J5.110 45.43,124.58 ; J5.110 44.27,123.42 ; 199.62,202.18 J3.B29 ; J3.B29 200.67,202.18 ; J3.B29 199.62,201.12 ; J3.B29 200.67,201.12 ; J3.B21 200.67,210.18 ; J3.B21 199.62,210.18 ; J3.B21 200.67,209.12 ; J3.B21 199.62,209.12 ; 44.27,235.42 J5.2 ; J5.2 44.27,236.58 ; J5.2 45.43,235.42 ; J5.2 45.43,236.58 ; 3.08,107.58 J9.5 ; J9.5 5.07,107.58 ; J9.5 3.08,109.56 ; J9.5 5.07,109.56 ; 199.62,184.18 J3.B47 ; J3.B47 200.67,184.18 ; J3.B47 199.62,183.12 ; J3.B47 200.67,183.12 ; 199.62,188.18 J3.B43 ; J3.B43 200.67,188.18 ; J3.B43 200.67,187.12 ; J3.B43 199.62,187.12 ; J7.116 159.53,118.58 ; J7.116 159.53,117.42 ; J7.116 158.37,118.58 ; J7.116 158.37,117.42 ; 44.27,223.42 J5.14 ; J5.14 45.43,224.58 ; J5.14 45.43,223.42 ; J5.14 44.27,224.58 ; 152.67,229.42 J6.113 ; J6.113 153.83,230.58 ; J6.113 153.83,229.42 ; J6.113 152.67,230.58 ; J12.1 137.79,13.46 ; J12.1 136.47,13.46 ; J12.1 137.79,14.79 ; J12.1 136.47,14.79 ; J3.A28 205.17,202.12 ; J3.A28 204.12,203.18 ; J3.A28 205.17,203.18 ; J3.A28 204.12,202.12 ; J6.130 151.93,122.42 ; J6.130 150.77,123.58 ; J6.130 150.77,122.42 ; J6.130 151.93,123.58 ; 150.77,199.58 J6.202 ; J6.202 151.93,199.58 ; J6.202 150.77,198.42 ; J6.202 151.93,198.42 ; 46.17,208.42 J5.29 ; J5.29 46.17,209.58 ; J5.29 47.33,209.58 ; J5.29 47.33,208.42 ; J6.98 155.73,214.42 ; J6.98 155.73,215.58 ; J6.98 154.57,214.42 ; J6.98 154.57,215.58 ; J7.127 165.23,230.42 ; J7.127 164.07,231.58 ; J7.127 165.23,231.58 ; J7.127 164.07,230.42 ; J3.B40 198.67,190.12 ; J3.B40 197.62,191.18 ; J3.B40 198.67,191.18 ; J3.B40 197.62,190.12 ; J7.113 161.43,120.42 ; J7.113 160.27,120.42 ; J7.113 161.43,121.58 ; J7.113 160.27,121.58 ; J6.116 155.73,232.42 ; J6.116 154.57,233.58 ; J6.116 155.73,233.58 ; J6.116 154.57,232.42 ; J6.101 153.83,218.58 ; J6.101 153.83,217.42 ; J6.101 152.67,217.42 ; J6.101 152.67,218.58 ; 158.37,148.58 J7.86 ; J7.86 159.53,148.58 ; J7.86 159.53,147.42 ; J7.86 158.37,147.42 ; 44.27,130.58 J5.104 ; J5.104 45.43,130.58 ; J5.104 44.27,129.42 ; J5.104 45.43,129.42 ; 46.17,150.42 J5.83 ; J5.83 47.33,151.58 ; J5.83 46.17,151.58 ; J5.83 47.33,150.42 ; J7.148 163.33,209.42 ; J7.148 162.17,210.58 ; J7.148 162.17,209.42 ; J7.148 163.33,210.58 ; J7.11 161.43,226.42 ; J7.11 160.27,227.58 ; J7.11 161.43,227.58 ; J7.11 160.27,226.42 ; J6.157 150.03,149.42 ; J6.157 148.87,149.42 ; J6.157 148.87,150.58 ; J6.157 150.03,150.58 ; J6.86 155.73,203.58 ; J6.86 155.73,202.42 ; J6.86 154.57,203.58 ; J6.86 154.57,202.42 ; 204.12,228.12 J3.A4 ; J3.A4 205.17,229.18 ; J3.A4 204.12,229.18 ; J3.A4 205.17,228.12 ; J5.5 47.33,233.58 ; J5.5 46.17,233.58 ; J5.5 46.17,232.42 ; J5.5 47.33,232.42 ; J3.A42 205.17,188.12 ; J3.A42 204.12,189.18 ; J3.A42 205.17,189.18 ; J3.A42 204.12,188.12 ; J7.145 165.23,212.42 ; J7.145 164.07,212.42 ; J7.145 164.07,213.58 ; J7.145 165.23,213.58 ; J9.24 10.57,136.98 ; J9.24 8.58,136.98 ; J9.24 10.57,138.96 ; J9.24 8.58,138.96 ; J3.A15 203.17,215.12 ; J3.A15 203.17,216.18 ; J3.A15 202.12,215.12 ; J3.A15 202.12,216.18 ; 49.97,115.58 J5.239 ; J5.239 51.13,115.58 ; J5.239 51.13,114.42 ; J5.239 49.97,114.42 ; 186.48,230.04 C5338.2 ; C5338.2 186.48,228.35 ; C5338.2 188.17,228.35 ; C5338.2 188.17,230.04 ; 44.27,153.42 J5.80 ; J5.80 44.27,154.58 ; J5.80 45.43,153.42 ; J5.80 45.43,154.58 ; 160.27,196.42 J7.41 ; J7.41 160.27,197.58 ; J7.41 161.43,197.58 ; J7.41 161.43,196.42 ; J5.17 47.33,221.58 ; J5.17 46.17,221.58 ; J5.17 46.17,220.42 ; J5.17 47.33,220.42 ; J7.110 159.53,123.42 ; J7.110 158.37,124.58 ; J7.110 159.53,124.58 ; J7.110 158.37,123.42 ; J7.166 163.33,191.42 ; J7.166 162.17,192.58 ; J7.166 162.17,191.42 ; J7.166 163.33,192.58 ; 49.97,207.58 J5.151 ; J5.151 51.13,207.58 ; J5.151 51.13,206.42 ; J5.151 49.97,206.42 ; 21.08,28.5 C5342.2 ; C5342.2 21.08,30.18 ; C5342.2 22.77,28.5 ; C5342.2 22.77,30.18 ; 162.17,197.42 J7.160 ; J7.160 162.17,198.58 ; J7.160 163.33,197.42 ; J7.160 163.33,198.58 ; SW6.3 5.45,7.16 ; SW6.3 3.57,7.16 ; SW6.3 5.45,5.28 ; SW6.3 3.57,5.28 ; J5.121 51.13,237.58 ; J5.121 49.97,237.58 ; J5.121 49.97,236.42 ; J5.121 51.13,236.42 ; 150.77,117.58 J6.124 ; J6.124 151.93,117.58 ; J6.124 150.77,116.42 ; J6.124 151.93,116.42 ; J7.239 165.23,114.42 ; J7.239 164.07,114.42 ; J7.239 165.23,115.58 ; J7.239 164.07,115.58 ; J5.160 49.23,198.58 ; J5.160 49.23,197.42 ; J5.160 48.07,198.58 ; J5.160 48.07,197.42 ; 48.07,233.42 J5.124 ; J5.124 48.07,234.58 ; J5.124 49.23,234.58 ; J5.124 49.23,233.42 ; 240.5,210.95 J55.2 239.05,210.95 ; J106.3 129.2,241.22 ; J106.3 127.95,239.97 ; J106.3 127.95,241.22 ; J106.3 129.2,239.97 ; FAN1.1 196.84,51.05 ; FAN1.1 195.24,51.05 ; FAN1.1 195.24,52.65 ; FAN1.1 196.84,52.65 ; 44.27,193.42 J5.44 ; J5.44 44.27,194.58 ; J5.44 45.43,193.42 ; J5.44 45.43,194.58 ; J5.214 49.23,140.58 ; J5.214 49.23,139.42 ; J5.214 48.07,139.42 ; J5.214 48.07,140.58 ; J3.B13 200.67,218.18 ; J3.B13 200.67,217.12 ; J3.B13 199.62,217.12 ; J3.B13 199.62,218.18 ; 263.48,76.91 C5345.2 ; C5345.2 265.29,75.11 ; C5345.2 265.29,76.91 ; C5345.2 263.48,75.11 ; 150.77,217.58 J6.220 ; J6.220 151.93,217.58 ; J6.220 151.93,216.42 ; J6.220 150.77,216.42 ; J6.235 150.03,231.42 ; J6.235 148.87,232.58 ; J6.235 148.87,231.42 ; J6.235 150.03,232.58 ; 202.12,231.12 J3.A1 ; J3.A1 203.17,231.12 ; J3.A1 202.12,232.18 ; J3.A1 203.17,232.18 ; J3.B7 200.67,226.18 ; J3.B7 200.67,225.12 ; J3.B7 199.62,226.18 ; J3.B7 199.62,225.12 ; J3.B39 200.67,191.12 ; J3.B39 199.62,191.12 ; J3.B39 200.67,192.18 ; J3.B39 199.62,192.18 ; J6.2 155.73,115.58 ; J6.2 155.73,114.42 ; J6.2 154.57,114.42 ; J6.2 154.57,115.58 ; J7.26 159.53,212.58 ; J7.26 158.37,212.58 ; J7.26 158.37,211.42 ; J7.26 159.53,211.42 ; 158.37,135.42 J7.98 ; J7.98 159.53,136.58 ; J7.98 159.53,135.42 ; J7.98 158.37,136.58 ; J6.44 155.73,156.42 ; J6.44 154.57,157.58 ; J6.44 154.57,156.42 ; J6.44 155.73,157.58 ; 162.17,146.58 J7.208 ; J7.208 162.17,145.42 ; J7.208 163.33,145.42 ; J7.208 163.33,146.58 ; J5.220 49.23,134.58 ; J5.220 48.07,133.42 ; J5.220 48.07,134.58 ; J5.220 49.23,133.42 ; J8.3 4.97,171.27 ; J8.3 3.18,169.48 ; J8.3 3.18,171.27 ; J8.3 4.97,169.48 ; 21.07,92.12 CT35.2 ; CT35.2 21.07,93.81 ; CT35.2 22.76,93.81 ; CT35.2 22.76,92.12 ; 40.94,250.12 FAN3.1 ; FAN3.1 42.53,248.53 ; FAN3.1 40.94,248.53 ; FAN3.1 42.53,250.12 ; CT28.2 21.23,132.41 ; CT28.2 19.55,130.73 ; CT28.2 19.55,132.41 ; CT28.2 21.23,130.73 ; J5.232 49.23,122.58 ; J5.232 49.23,121.42 ; J5.232 48.07,121.42 ; J5.232 48.07,122.58 ; J6.121 150.03,114.58 ; J6.121 148.87,113.42 ; J6.121 148.87,114.58 ; J6.121 150.03,113.42 ; J3.A45 203.17,186.18 ; J3.A45 203.17,185.12 ; J3.A45 202.12,185.12 ; J3.A45 202.12,186.18 ; 10.57,5.28 SW6.4 ; SW6.4 12.45,7.16 ; SW6.4 12.45,5.28 ; SW6.4 10.57,7.16 ; J6.26 155.73,139.58 ; J6.26 154.57,139.58 ; J6.26 154.57,138.42 ; J6.26 155.73,138.42 ; J2.16 239.35,247.73 ; J2.16 237.92,246.3 ; J2.16 239.35,246.3 ; J2.16 237.92,247.73 ; 8.58,107.58 J9.17 ; J9.17 10.57,109.56 ; J9.17 10.57,107.58 ; J9.17 8.58,109.56 ; J5.166 49.23,191.42 ; J5.166 48.07,192.58 ; J5.166 48.07,191.42 ; J5.166 49.23,192.58 ; 150.77,223.58 J6.226 ; J6.226 151.93,222.42 ; J6.226 151.93,223.58 ; J6.226 150.77,222.42 ; J3.B4 198.67,229.18 ; J3.B4 197.62,228.12 ; J3.B4 197.62,229.18 ; J3.B4 198.67,228.12 ; J3.A37 203.17,194.18 ; J3.A37 203.17,193.12 ; J3.A37 202.12,194.18 ; J3.A37 202.12,193.12 ; 202.12,208.18 J3.A23 ; J3.A23 202.12,207.12 ; J3.A23 203.17,207.12 ; J3.A23 203.17,208.18 ; 49.97,148.42 J5.205 ; J5.205 49.97,149.58 ; J5.205 51.13,148.42 ; J5.205 51.13,149.58 ; J6.160 151.93,152.42 ; J6.160 150.77,152.42 ; J6.160 151.93,153.58 ; J6.160 150.77,153.58 ; J6.47 153.83,160.58 ; J6.47 152.67,160.58 ; J6.47 152.67,159.42 ; J6.47 153.83,159.42 ; 164.07,237.58 J7.121 ; J7.121 164.07,236.42 ; J7.121 165.23,236.42 ; J7.121 165.23,237.58 ; 148.87,120.58 J6.127 ; J6.127 150.03,120.58 ; J6.127 150.03,119.42 ; J6.127 148.87,119.42 ; 20.16,250.12 FAN12.1 ; FAN12.1 20.16,248.53 ; FAN12.1 21.75,250.12 ; FAN12.1 21.75,248.53 ; 164.07,154.42 J7.199 ; J7.199 165.23,155.58 ; J7.199 165.23,154.42 ; J7.199 164.07,155.58 ; 148.87,225.42 J6.229 ; J6.229 150.03,226.58 ; J6.229 148.87,226.58 ; J6.229 150.03,225.42 ; J6.163 150.03,155.42 ; J6.163 148.87,155.42 ; J6.163 150.03,156.58 ; J6.163 148.87,156.58 ; 73.12,246.15 C5289.2 ; C5289.2 73.12,247.83 ; C5289.2 74.81,246.15 ; C5289.2 74.81,247.83 ; 9.5,2.96 SW6.2 ; SW6.2 11.02,2.96 ; SW6.2 11.02,4.48 ; SW6.2 9.5,4.48 ; 19.97,146.08 C5340.2 ; C5340.2 21.65,144.4 ; C5340.2 21.65,146.08 ; C5340.2 19.97,144.4 ; 158.37,218.58 J7.20 ; J7.20 159.53,217.42 ; J7.20 159.53,218.58 ; J7.20 158.37,217.42 ; J8.4 4.97,173.68 ; J8.4 3.18,173.68 ; J8.4 3.18,175.47 ; J8.4 4.97,175.47 ; 3.08,101.16 J9.3 ; J9.3 3.08,99.18 ; J9.3 5.07,101.16 ; J9.3 5.07,99.18 ; J5.127 51.13,231.58 ; J5.127 49.97,230.42 ; J5.127 51.13,230.42 ; J5.127 49.97,231.58 ; 158.37,193.42 J7.44 ; J7.44 159.53,193.42 ; J7.44 159.53,194.58 ; J7.44 158.37,194.58 ; 162.17,122.58 J7.232 ; J7.232 162.17,121.42 ; J7.232 163.33,121.42 ; J7.232 163.33,122.58 ; 164.07,117.58 J7.237 ; J7.237 165.23,116.42 ; J7.237 164.07,116.42 ; J7.237 165.23,117.58 ; 190.8,242.83 C5339.2 ; C5339.2 190.8,244.51 ; C5339.2 192.48,244.51 ; C5339.2 192.48,242.83 ; 207.06,242.83 C5337.2 ; C5337.2 208.74,242.83 ; C5337.2 207.06,244.51 ; C5337.2 208.74,244.51 ; J6.151 150.03,144.58 ; J6.151 150.03,143.42 ; J6.151 148.87,144.58 ; J6.151 148.87,143.42 ; 148.87,131.42 J6.139 ; J6.139 148.87,132.58 ; J6.139 150.03,131.42 ; J6.139 150.03,132.58 ; SW5.1 18.6,16.45 ; SW5.1 18.6,18.15 ; SW5.1 16.9,16.45 ; SW5.1 16.9,18.15 ; 46.65,64.8 J69.5 ; J69.5 48.19,63.26 ; J69.5 48.19,64.8 ; J69.5 46.65,63.26 ; J7.104 159.53,129.42 ; J7.104 159.53,130.58 ; J7.104 158.37,130.58 ; J7.104 158.37,129.42 ; 44.27,211.42 J5.26 ; J5.26 45.43,212.58 ; J5.26 44.27,212.58 ; J5.26 45.43,211.42 ; J3.B26 198.67,205.18 ; J3.B26 197.62,205.18 ; J3.B26 197.62,204.12 ; J3.B26 198.67,204.12 ; 150.77,134.42 J6.142 ; J6.142 151.93,134.42 ; J6.142 150.77,135.58 ; J6.142 151.93,135.58 ; J5.139 51.13,219.58 ; J5.139 51.13,218.42 ; J5.139 49.97,219.58 ; J5.139 49.97,218.42 ; J6.208 151.93,204.42 ; J6.208 150.77,205.58 ; J6.208 151.93,205.58 ; J6.208 150.77,204.42 ; 164.07,207.58 J7.151 ; J7.151 165.23,206.42 ; J7.151 165.23,207.58 ; J7.151 164.07,206.42 ; J11.1 116.02,14.79 ; J11.1 116.02,13.46 ; J11.1 114.7,13.46 ; J11.1 114.7,14.79 ; 158.24,14.79 J13.1 ; J13.1 159.56,14.79 ; J13.1 158.24,13.46 ; J13.1 159.56,13.46 ; J6.95 153.83,211.42 ; J6.95 152.67,211.42 ; J6.95 153.83,212.58 ; J6.95 152.67,212.58 ; 152.67,234.58 J6.117 ; J6.117 153.83,234.58 ; J6.117 152.67,233.42 ; J6.117 153.83,233.42 ; 164.07,149.58 J7.205 ; J7.205 165.23,149.58 ; J7.205 165.23,148.42 ; J7.205 164.07,148.42 ; 162.17,151.42 J7.202 ; J7.202 163.33,151.42 ; J7.202 162.17,152.58 ; J7.202 163.33,152.58 ; 158.37,154.58 J7.80 ; J7.80 159.53,154.58 ; J7.80 159.53,153.42 ; J7.80 158.37,153.42 ; J7.17 161.43,220.42 ; J7.17 160.27,220.42 ; J7.17 160.27,221.58 ; J7.17 161.43,221.58 ; J7.101 161.43,133.58 ; J7.101 160.27,132.42 ; J7.101 160.27,133.58 ; J7.101 161.43,132.42 ; 154.57,133.58 J6.20 ; J6.20 155.73,133.58 ; J6.20 155.73,132.42 ; J6.20 154.57,132.42 ; 46.17,191.58 J5.47 ; J5.47 46.17,190.42 ; J5.47 47.33,191.58 ; J5.47 47.33,190.42 ; 164.07,219.58 J7.139 ; J7.139 165.23,219.58 ; J7.139 165.23,218.42 ; J7.139 164.07,218.42 ; 154.57,221.58 J6.104 ; J6.104 155.73,221.58 ; J6.104 155.73,220.42 ; J6.104 154.57,220.42 ; 202.12,189.12 J3.A41 ; J3.A41 203.17,189.12 ; J3.A41 203.17,190.18 ; J3.A41 202.12,190.18 ; 148.87,219.42 J6.223 ; J6.223 148.87,220.58 ; J6.223 150.03,219.42 ; J6.223 150.03,220.58 ; J7.211 165.23,142.42 ; J7.211 164.07,142.42 ; J7.211 164.07,143.58 ; J7.211 165.23,143.58 ; J5.235 51.13,119.58 ; J5.235 51.13,118.42 ; J5.235 49.97,118.42 ; J5.235 49.97,119.58 ; 150.77,146.42 J6.154 ; J6.154 151.93,146.42 ; J6.154 151.93,147.58 ; J6.154 150.77,147.58 ; 125.95,245.97 J106.10 ; J106.10 125.95,247.22 ; J106.10 127.2,247.22 ; J106.10 127.2,245.97 ; 158.37,141.42 J7.92 ; J7.92 159.53,141.42 ; J7.92 158.37,142.58 ; J7.92 159.53,142.58 ; J3.B25 200.67,206.18 ; J3.B25 199.62,205.12 ; J3.B25 200.67,205.12 ; J3.B25 199.62,206.18 ; 154.57,145.58 J6.32 ; J6.32 155.73,145.58 ; J6.32 154.57,144.42 ; J6.32 155.73,144.42 ; J9.15 10.57,99.18 ; J9.15 8.58,99.18 ; J9.15 8.58,101.16 ; J9.15 10.57,101.16 ; 160.27,117.58 J7.117 ; J7.117 160.27,116.42 ; J7.117 161.43,117.58 ; J7.117 161.43,116.42 ; 164.07,124.42 J7.229 ; J7.229 164.07,125.58 ; J7.229 165.23,125.58 ; J7.229 165.23,124.42 ; 150.77,228.42 J6.232 ; J6.232 150.77,229.58 ; J6.232 151.93,228.42 ; J6.232 151.93,229.58 ; 154.57,197.58 J6.80 ; J6.80 154.57,196.42 ; J6.80 155.73,196.42 ; J6.80 155.73,197.58 ; J3.A24 205.17,206.12 ; J3.A24 205.17,207.18 ; J3.A24 204.12,206.12 ; J3.A24 204.12,207.18 ; 48.07,204.58 J5.154 ; J5.154 49.23,203.42 ; J5.154 48.07,203.42 ; J5.154 49.23,204.58 ; 3.18,162.89 J8.1 ; J8.1 4.97,161.1 ; J8.1 3.18,161.1 ; J8.1 4.97,162.89 ; 162.17,233.42 J7.124 ; J7.124 162.17,234.58 ; J7.124 163.33,234.58 ; J7.124 163.33,233.42 ; 48.07,151.42 J5.202 ; J5.202 48.07,152.58 ; J5.202 49.23,152.58 ; J5.202 49.23,151.42 ; J5.11 47.33,227.58 ; J5.11 47.33,226.42 ; J5.11 46.17,227.58 ; J5.11 46.17,226.42 ; J6.166 151.93,159.58 ; J6.166 150.77,159.58 ; J6.166 151.93,158.42 ; J6.166 150.77,158.42 ; J5.92 45.43,142.58 ; J5.92 44.27,142.58 ; J5.92 44.27,141.42 ; J5.92 45.43,141.42 ; 46.17,121.58 J5.113 ; J5.113 46.17,120.42 ; J5.113 47.33,121.58 ; J5.113 47.33,120.42 ; J10.M1 23.77,54.6 ; J10.M1 21.8,54.6 ; J10.M1 23.77,56.57 ; J10.M1 21.8,56.57 ; 152.67,223.42 J6.107 ; J6.107 153.83,223.42 ; J6.107 152.67,224.58 ; J6.107 153.83,224.58 ; 46.17,127.58 J5.107 ; J5.107 46.17,126.42 ; J5.107 47.33,127.58 ; J5.107 47.33,126.42 ; J9.7 5.07,117.96 ; J9.7 3.08,117.96 ; J9.7 5.07,115.98 ; J9.7 3.08,115.98 ; J7.29 161.43,209.58 ; J7.29 161.43,208.42 ; J7.29 160.27,208.42 ; J7.29 160.27,209.58 ; 49.97,124.42 J5.229 ; J5.229 51.13,124.42 ; J5.229 51.13,125.58 ; J5.229 49.97,125.58 ; 152.67,147.42 J6.35 ; J6.35 153.83,147.42 ; J6.35 153.83,148.58 ; J6.35 152.67,148.58 ; 21.43,120.6 CT31.2 ; CT31.2 23.11,118.92 ; CT31.2 23.11,120.6 ; CT31.2 21.43,118.92 ; 8.58,113.76 J9.18 ; J9.18 8.58,111.77 ; J9.18 10.57,113.76 ; J9.18 10.57,111.77 ; 39.34,30.18 C5341.2 ; C5341.2 39.34,28.5 ; C5341.2 41.02,30.18 ; C5341.2 41.02,28.5 ; 204.12,211.18 J3.A20 ; J3.A20 204.12,210.12 ; J3.A20 205.17,211.18 ; J3.A20 205.17,210.12 ; 115.85,247.83 C5283.2 ; C5283.2 115.85,246.15 ; C5283.2 117.53,247.83 ; C5283.2 117.53,246.15 ; J13.20 171.45,23.88 ; J13.20 171.45,25.2 ; J13.20 170.13,25.2 ; J13.20 170.13,23.88 ; J6.29 153.83,142.58 ; J6.29 153.83,141.42 ; J6.29 152.67,142.58 ; J6.29 152.67,141.42 ; J6.23 153.83,135.42 ; J6.23 153.83,136.58 ; J6.23 152.67,136.58 ; J6.23 152.67,135.42 ; 44.27,135.42 J5.98 ; J5.98 45.43,135.42 ; J5.98 45.43,136.58 ; J5.98 44.27,136.58 ; 202.12,203.12 J3.A27 ; J3.A27 203.17,203.12 ; J3.A27 202.12,204.18 ; J3.A27 203.17,204.18 ; 164.07,119.58 J7.235 ; J7.235 164.07,118.42 ; J7.235 165.23,119.58 ; J7.235 165.23,118.42 ; J5.89 47.33,145.58 ; J5.89 46.17,144.42 ; J5.89 47.33,144.42 ; J5.89 46.17,145.58 ; 150.77,140.42 J6.148 ; J6.148 150.77,141.58 ; J6.148 151.93,140.42 ; J6.148 151.93,141.58 ; 197.62,194.12 J3.B36 ; J3.B36 197.62,195.18 ; J3.B36 198.67,194.12 ; J3.B36 198.67,195.18 ; FAN5.1 10.64,250.12 ; FAN5.1 9.04,250.12 ; FAN5.1 9.04,248.53 ; FAN5.1 10.64,248.53 ; J5.116 45.43,118.58 ; J5.116 44.27,117.42 ; J5.116 45.43,117.42 ; J5.116 44.27,118.58 ; J7.133 165.23,224.42 ; J7.133 164.07,224.42 ; J7.133 164.07,225.58 ; J7.133 165.23,225.58 ; J6.145 150.03,137.42 ; J6.145 148.87,138.58 ; J6.145 148.87,137.42 ; J6.145 150.03,138.58 ; 160.27,215.58 J7.23 ; J7.23 161.43,215.58 ; J7.23 160.27,214.42 ; J7.23 161.43,214.42 ; J7.130 163.33,227.42 ; J7.130 163.33,228.58 ; J7.130 162.17,228.58 ; J7.130 162.17,227.42 ; 243.71,247.01 244.43,247.73 ; 243.71,247.01 243,247.73 ; 243.71,247.01 243,246.3 ; 243.71,247.01 244.43,246.3 ; 152.67,117.42 J6.5 ; J6.5 153.83,117.42 ; J6.5 153.83,118.58 ; J6.5 152.67,118.58 ; J7.157 165.23,201.58 ; J7.157 164.07,201.58 ; J7.157 165.23,200.42 ; J7.157 164.07,200.42 ; J11.20 127.91,23.88 ; J11.20 126.59,25.2 ; J11.20 127.91,25.2 ; J11.20 126.59,23.88 ; 62.85,248.53 FAN4.1 ; FAN4.1 62.85,250.12 ; FAN4.1 64.44,250.12 ; FAN4.1 64.44,248.53 ; J7.83 161.43,151.58 ; J7.83 160.27,151.58 ; J7.83 161.43,150.42 ; J7.83 160.27,150.42 ; J6.217 150.03,213.42 ; J6.217 148.87,214.58 ; J6.217 150.03,214.58 ; J6.217 148.87,213.42 ; 148.87,207.42 J6.211 ; J6.211 150.03,207.42 ; J6.211 150.03,208.58 ; J6.211 148.87,208.58 ; J7.89 161.43,144.42 ; J7.89 160.27,144.42 ; J7.89 161.43,145.58 ; J7.89 160.27,145.58 ; 44.27,230.58 J5.8 ; J5.8 45.43,229.42 ; J5.8 44.27,229.42 ; J5.8 45.43,230.58 ; J7.220 163.33,133.42 ; J7.220 162.17,133.42 ; J7.220 163.33,134.58 ; J7.220 162.17,134.58 ; J7.95 161.43,139.58 ; J7.95 160.27,139.58 ; J7.95 161.43,138.42 ; J7.95 160.27,138.42 ; 158.37,206.58 J7.32 ; J7.32 159.53,206.58 ; J7.32 158.37,205.42 ; J7.32 159.53,205.42 ; J3.B35 200.67,196.18 ; J3.B35 200.67,195.12 ; J3.B35 199.62,196.18 ; J3.B35 199.62,195.12 ; J3.B16 198.67,214.12 ; J3.B16 197.62,214.12 ; J3.B16 198.67,215.18 ; J3.B16 197.62,215.18 ; 162.17,222.58 J7.136 ; J7.136 163.33,221.42 ; J7.136 163.33,222.58 ; J7.136 162.17,221.42 ; 150.77,210.42 J6.214 ; J6.214 151.93,211.58 ; J6.214 150.77,211.58 ; J6.214 151.93,210.42 ; J3.A49 203.17,182.18 ; J3.A49 203.17,181.12 ; J3.A49 202.12,182.18 ; J7.47 161.43,191.58 ; J7.47 161.43,190.42 ; J7.47 160.27,191.58 ; J7.47 160.27,190.42 ; 49.97,225.58 J5.133 ; J5.133 51.13,224.42 ; J5.133 51.13,225.58 ; J5.133 49.97,224.42 ; J10.M2 22.77,41.77 ; J10.M2 20.8,41.77 ; J10.M2 22.77,43.74 ; J10.M2 20.8,43.74 ; J5.35 47.33,203.58 ; J5.35 46.17,203.58 ; J5.35 47.33,202.42 ; J5.35 46.17,202.42 ; J5.142 49.23,215.42 ; J5.142 48.07,216.58 ; J5.142 48.07,215.42 ; J5.142 49.23,216.58 ; J3.B32 198.67,198.12 ; J3.B32 198.67,199.18 ; J3.B32 197.62,198.12 ; J3.B32 197.62,199.18 ; 152.67,200.58 J6.83 ; J6.83 152.67,199.42 ; J6.83 153.83,199.42 ; J6.83 153.83,200.58 ; 240.63,204.72 J4.2 239.18,204.72 ; J6.239 150.03,236.58 ; J6.239 150.03,235.42 ; J6.239 148.87,235.42 ; J6.239 148.87,236.58 ; 152.67,123.42 J6.11 ; J6.11 153.83,123.42 ; J6.11 152.67,124.58 ; J6.11 153.83,124.58 ; J5.208 49.23,145.42 ; J5.208 49.23,146.58 ; J5.208 48.07,146.58 ; J5.208 48.07,145.42 ; J6.110 155.73,227.58 ; J6.110 154.57,227.58 ; J6.110 154.57,226.42 ; J6.110 155.73,226.42 ; J7.214 163.33,139.42 ; J7.214 163.33,140.58 ; J7.214 162.17,139.42 ; J7.214 162.17,140.58 ; 46.17,214.42 J5.23 ; J5.23 47.33,215.58 ; J5.23 47.33,214.42 ; J5.23 46.17,215.58 ; 148.87,196.58 J6.199 ; J6.199 150.03,196.58 ; J6.199 148.87,195.42 ; J6.199 150.03,195.42 ; 49.97,130.42 J5.223 ; J5.223 49.97,131.58 ; J5.223 51.13,131.58 ; J5.223 51.13,130.42 ; 152.67,206.58 J6.89 ; J6.89 153.83,205.42 ; J6.89 152.67,205.42 ; J6.89 153.83,206.58 ; J3.B22 198.67,209.18 ; J3.B22 197.62,209.18 ; J3.B22 198.67,208.12 ; J3.B22 197.62,208.12 ; 44.27,199.42 J5.38 ; J5.38 45.43,199.42 ; J5.38 45.43,200.58 ; J5.38 44.27,200.58 ; 160.27,233.58 J7.5 ; J7.5 161.43,233.58 ; J7.5 160.27,232.42 ; J7.5 161.43,232.42 ; J7.163 165.23,194.42 ; J7.163 165.23,195.58 ; J7.163 164.07,195.58 ; J7.163 164.07,194.42 ; J3.B18 198.67,213.18 ; J3.B18 198.67,212.12 ; J3.B18 197.62,212.12 ; J3.B18 197.62,213.18 ; 158.37,223.42 J7.14 ; J7.14 158.37,224.58 ; J7.14 159.53,224.58 ; J7.14 159.53,223.42 ; J6.133 150.03,125.42 ; J6.133 148.87,125.42 ; J6.133 150.03,126.58 ; J6.133 148.87,126.58 ; J12.20 149.68,25.2 ; J12.20 149.68,23.88 ; J12.20 148.36,25.2 ; J12.20 148.36,23.88 ; 204.12,193.18 J3.A38 ; J3.A38 204.12,192.12 ; J3.A38 205.17,192.12 ; J3.A38 205.17,193.18 ; 44.27,205.42 J5.32 ; J5.32 45.43,206.58 ; J5.32 45.43,205.42 ; J5.32 44.27,206.58 ; 44.27,217.42 J5.20 ; J5.20 44.27,218.58 ; J5.20 45.43,218.58 ; J5.20 45.43,217.42 ; 154.57,151.58 J6.38 ; J6.38 155.73,151.58 ; J6.38 154.57,150.42 ; J6.38 155.73,150.42 ; J7.223 165.23,131.58 ; J7.223 164.07,130.42 ; J7.223 164.07,131.58 ; J7.223 165.23,130.42 ; 3.18,165.29 J8.2 ; J8.2 3.18,167.08 ; J8.2 4.97,167.08 ; J8.2 4.97,165.29 ; J7.142 163.33,215.42 ; J7.142 163.33,216.58 ; J7.142 162.17,215.42 ; J7.142 162.17,216.58 ; J6.92 155.73,208.42 ; J6.92 154.57,208.42 ; J6.92 154.57,209.58 ; J6.92 155.73,209.58 ; 49.97,136.42 J5.217 ; J5.217 51.13,136.42 ; J5.217 51.13,137.58 ; J5.217 49.97,137.58 ; 152.67,235.42 J6.119 ; J6.119 153.83,236.58 ; J6.119 153.83,235.42 ; J6.119 152.67,236.58 ; 158.37,236.58 J7.2 ; J7.2 158.37,235.42 ; J7.2 159.53,235.42 ; J7.2 159.53,236.58 ; 162.17,203.42 J7.154 ; J7.154 162.17,204.58 ; J7.154 163.33,204.58 ; J7.154 163.33,203.42 ; 191.9,23.88 J14.20 ; J14.20 191.9,25.2 ; J14.20 193.22,25.2 ; 46.17,197.58 J5.41 ; J5.41 47.33,196.42 ; J5.41 47.33,197.58 ; J5.41 46.17,196.42 ; 86.66,247.83 C5279.2 ; C5279.2 88.34,246.15 ; C5279.2 88.34,247.83 ; C5279.2 86.66,246.15 ; J6.14 155.73,126.42 ; J6.14 154.57,127.58 ; J6.14 155.73,127.58 ; J6.14 154.57,126.42 ; J5.130 49.23,228.58 ; J5.130 48.07,228.58 ; J5.130 48.07,227.42 ; J5.130 49.23,227.42 ; J7.107 161.43,127.58 ; J7.107 160.27,127.58 ; J7.107 161.43,126.42 ; J7.107 160.27,126.42 ; 46.17,139.58 J5.95 ; J5.95 46.17,138.42 ; J5.95 47.33,139.58 ; J5.95 47.33,138.42 ; J5.226 49.23,127.42 ; J5.226 48.07,127.42 ; J5.226 48.07,128.58 ; J5.226 49.23,128.58 ; J3.A31 203.17,200.18 ; J3.A31 202.12,199.12 ; J3.A31 203.17,199.12 ; J3.A31 202.12,200.18 ; J3.A18 205.17,212.12 ; J3.A18 204.12,213.18 ; J3.A18 205.17,213.18 ; J3.A18 204.12,212.12 ; 42.82,11.28 CN4.B4 42.82,9.93 ; J3.A12 205.17,218.12 ; J3.A12 205.17,219.18 ; J3.A12 204.12,219.18 ; J3.A12 204.12,218.12 ; 162.17,127.42 J7.226 ; J7.226 162.17,128.58 ; J7.226 163.33,127.42 ; J7.226 163.33,128.58 ; J14.1 181.33,13.46 ; J14.1 180.01,13.46 ; J14.1 181.33,14.79 ; J14.1 180.01,14.79 ; 154.57,121.58 J6.8 ; J6.8 154.57,120.42 ; J6.8 155.73,121.58 ; J6.8 155.73,120.42 ; 44.27,147.42 J5.86 ; J5.86 45.43,148.58 ; J5.86 45.43,147.42 ; J5.86 44.27,148.58 ; 152.67,130.58 J6.17 ; J6.17 152.67,129.42 ; J6.17 153.83,129.42 ; J6.17 153.83,130.58 ; J6.41 153.83,154.58 ; J6.41 152.67,153.42 ; J6.41 152.67,154.58 ; J6.41 153.83,153.42 ; 49.97,155.58 J5.199 ; J5.199 51.13,155.58 ; J5.199 51.13,154.42 ; J5.199 49.97,154.42 ; 45.3,80.64 JP7.2 46.75,80.64 ; 49.97,212.42 J5.145 ; J5.145 51.13,213.58 ; J5.145 49.97,213.58 ; J5.145 51.13,212.42 ; J5.148 49.23,210.58 ; J5.148 48.07,210.58 ; J5.148 49.23,209.42 ; J5.148 48.07,209.42
  L6_GND_3 w0.914: 113.7,213.18 BH10.1 ; BH10.1 117.43,213.18 ; BH10.1 113.7,209.45 ; BH10.1 117.43,209.45
  L6_GND_3 w1.016: H13.1 142.93,69.13 ; H13.1 136.67,69.13 ; H13.1 142.93,62.87 ; H13.1 136.67,62.87 ; 66.67,100.13 H12.1 ; H12.1 72.93,93.87 ; H12.1 66.67,93.87 ; H12.1 72.93,100.13 ; 172.5,178.1 H6.1 ; H6.1 172.5,171.9 ; H6.1 178.69,171.9 ; H6.1 178.69,178.1 ; H10.1 67.13,123.99 ; H10.1 60.87,123.99 ; H10.1 60.87,130.25 ; H10.1 67.13,130.25 ; H9.1 9.13,146.97 ; H9.1 2.87,153.23 ; H9.1 2.87,146.97 ; H9.1 9.13,153.23 ; 172.47,243.87 H2.1 ; H2.1 178.73,250.13 ; H2.1 172.47,250.13 ; H2.1 178.73,243.87 ; 66.67,48.13 H14.1 ; H14.1 66.67,41.87 ; H14.1 72.93,41.87 ; H14.1 72.93,48.13 ; H11.1 139.13,123.99 ; H11.1 132.87,123.99 ; H11.1 139.13,130.25 ; H11.1 132.87,130.25 ; H3.1 282.13,243.87 ; H3.1 275.87,250.13 ; H3.1 275.87,243.87 ; H3.1 282.13,250.13 ; H8.1 282.13,130.88 ; H8.1 282.13,124.62 ; H8.1 275.87,130.88 ; H8.1 275.87,124.62 ; 2.87,15.87 H16.1 ; H16.1 9.13,22.13 ; H16.1 9.13,15.87 ; H16.1 2.87,22.13 ; H1.1 31.13,243.87 ; H1.1 31.13,250.13 ; H1.1 24.87,250.13 ; H1.1 24.87,243.87 ; 223.87,250.13 H7.1 ; H7.1 223.87,243.87 ; H7.1 230.13,250.13 ; H7.1 230.13,243.87 ; 132.87,195.99 H5.1 ; H5.1 139.13,195.99 ; H5.1 132.87,202.25 ; H5.1 139.13,202.25 ; 275.87,15.87 H15.1 ; H15.1 282.13,22.13 ; H15.1 275.87,22.13 ; H15.1 282.13,15.87 ; H4.1 67.13,202.25 ; H4.1 60.87,202.25 ; H4.1 67.13,195.99 ; H4.1 60.87,195.99
  L7_INT_3 w0.508: J7.5 161.43,232.42 ; J7.5 160.27,232.42 ; J7.5 160.27,233.58 ; J7.5 161.43,233.58 ; J6.136 151.93,129.58 ; J6.136 150.77,128.42 ; J6.136 151.93,128.42 ; J6.136 150.77,129.58 ; 202.12,207.12 J3.A23 ; J3.A23 203.17,207.12 ; J3.A23 202.12,208.18 ; J3.A23 203.17,208.18 ; J3.A42 205.17,189.18 ; J3.A42 205.17,188.12 ; J3.A42 204.12,188.12 ; J3.A42 204.12,189.18 ; 49.97,207.58 J5.151 ; J5.151 49.97,206.42 ; J5.151 51.13,206.42 ; J5.151 51.13,207.58 ; 186.48,228.35 C5338.2 ; C5338.2 186.48,230.04 ; C5338.2 188.17,228.35 ; C5338.2 188.17,230.04 ; 152.67,124.58 J6.11 ; J6.11 153.83,123.42 ; J6.11 152.67,123.42 ; J6.11 153.83,124.58 ; 160.27,215.58 J7.23 ; J7.23 160.27,214.42 ; J7.23 161.43,214.42 ; J7.23 161.43,215.58 ; 162.17,233.42 J7.124 ; J7.124 163.33,234.58 ; J7.124 162.17,234.58 ; J7.124 163.33,233.42 ; J3.A38 205.17,192.12 ; J3.A38 204.12,193.18 ; J3.A38 204.12,192.12 ; J3.A38 205.17,193.18 ; J3.B49 200.67,182.18 ; J3.B49 199.62,181.12 ; J3.B49 199.62,182.18 ; 160.27,202.42 J7.35 ; J7.35 160.27,203.58 ; J7.35 161.43,202.42 ; J7.35 161.43,203.58 ; J3.A15 203.17,215.12 ; J3.A15 202.12,216.18 ; J3.A15 203.17,216.18 ; J3.A15 202.12,215.12 ; J6.14 155.73,127.58 ; J6.14 154.57,126.42 ; J6.14 155.73,126.42 ; J6.14 154.57,127.58 ; 162.17,215.42 J7.142 ; J7.142 162.17,216.58 ; J7.142 163.33,216.58 ; J7.142 163.33,215.42 ; 158.37,218.58 J7.20 ; J7.20 158.37,217.42 ; J7.20 159.53,218.58 ; J7.20 159.53,217.42 ; J7.223 165.23,131.58 ; J7.223 164.07,130.42 ; J7.223 164.07,131.58 ; J7.223 165.23,130.42 ; J7.232 163.33,121.42 ; J7.232 162.17,122.58 ; J7.232 163.33,122.58 ; J7.232 162.17,121.42 ; 49.97,200.42 J5.157 ; J5.157 49.97,201.58 ; J5.157 51.13,201.58 ; J5.157 51.13,200.42 ; J7.199 165.23,155.58 ; J7.199 164.07,154.42 ; J7.199 165.23,154.42 ; J7.199 164.07,155.58 ; 202.12,204.18 J3.A27 ; J3.A27 203.17,204.18 ; J3.A27 203.17,203.12 ; J3.A27 202.12,203.12 ; J3.A4 205.17,229.18 ; J3.A4 204.12,229.18 ; J3.A4 205.17,228.12 ; J3.A4 204.12,228.12 ; J3.B26 198.67,204.12 ; J3.B26 197.62,205.18 ; J3.B26 198.67,205.18 ; J3.B26 197.62,204.12 ; J3.B25 200.67,205.12 ; J3.B25 200.67,206.18 ; J3.B25 199.62,206.18 ; J3.B25 199.62,205.12 ; J7.163 165.23,195.58 ; J7.163 164.07,195.58 ; J7.163 165.23,194.42 ; J7.163 164.07,194.42 ; J3.B7 200.67,225.12 ; J3.B7 199.62,225.12 ; J3.B7 199.62,226.18 ; J3.B7 200.67,226.18 ; J7.157 165.23,200.42 ; J7.157 164.07,201.58 ; J7.157 164.07,200.42 ; J7.157 165.23,201.58 ; J7.237 165.23,116.42 ; J7.237 165.23,117.58 ; J7.237 164.07,116.42 ; J7.237 164.07,117.58 ; J5.145 51.13,213.58 ; J5.145 49.97,213.58 ; J5.145 51.13,212.42 ; J5.145 49.97,212.42 ; J7.116 159.53,117.42 ; J7.116 158.37,118.58 ; J7.116 158.37,117.42 ; J7.116 159.53,118.58 ; J7.14 159.53,223.42 ; J7.14 158.37,223.42 ; J7.14 158.37,224.58 ; J7.14 159.53,224.58 ; 164.07,136.42 J7.217 ; J7.217 165.23,136.42 ; J7.217 165.23,137.58 ; J7.217 164.07,137.58 ; 158.37,136.58 J7.98 ; J7.98 159.53,135.42 ; J7.98 158.37,135.42 ; J7.98 159.53,136.58 ; 154.57,139.58 J6.26 ; J6.26 155.73,138.42 ; J6.26 154.57,138.42 ; J6.26 155.73,139.58 ; J6.139 150.03,131.42 ; J6.139 148.87,132.58 ; J6.139 148.87,131.42 ; J6.139 150.03,132.58 ; 162.17,198.58 J7.160 ; J7.160 162.17,197.42 ; J7.160 163.33,197.42 ; J7.160 163.33,198.58 ; J3.A46 205.17,185.18 ; J3.A46 205.17,184.12 ; J3.A46 204.12,184.12 ; J3.A46 204.12,185.18 ; J7.205 165.23,148.42 ; J7.205 164.07,149.58 ; J7.205 164.07,148.42 ; J7.205 165.23,149.58 ; 202.12,194.18 J3.A37 ; J3.A37 202.12,193.12 ; J3.A37 203.17,193.12 ; J3.A37 203.17,194.18 ; J7.38 159.53,199.42 ; J7.38 158.37,199.42 ; J7.38 158.37,200.58 ; J7.38 159.53,200.58 ; 48.07,216.58 J5.142 ; J5.142 49.23,216.58 ; J5.142 48.07,215.42 ; J5.142 49.23,215.42 ; 164.07,125.58 J7.229 ; J7.229 165.23,125.58 ; J7.229 165.23,124.42 ; J7.229 164.07,124.42 ; J6.23 153.83,135.42 ; J6.23 152.67,136.58 ; J6.23 153.83,136.58 ; J6.23 152.67,135.42 ; 204.12,196.12 J3.A34 ; J3.A34 204.12,197.18 ; J3.A34 205.17,196.12 ; J3.A34 205.17,197.18 ; J7.104 159.53,129.42 ; J7.104 159.53,130.58 ; J7.104 158.37,129.42 ; J7.104 158.37,130.58 ; J3.A45 203.17,186.18 ; J3.A45 202.12,185.12 ; J3.A45 203.17,185.12 ; J3.A45 202.12,186.18 ; 197.62,195.18 J3.B36 ; J3.B36 198.67,195.18 ; J3.B36 197.62,194.12 ; J3.B36 198.67,194.12 ; J7.95 161.43,139.58 ; J7.95 160.27,138.42 ; J7.95 161.43,138.42 ; J7.95 160.27,139.58 ; 44.27,206.58 J5.32 ; J5.32 45.43,206.58 ; J5.32 44.27,205.42 ; J5.32 45.43,205.42 ; J5.38 45.43,199.42 ; J5.38 44.27,199.42 ; J5.38 44.27,200.58 ; J5.38 45.43,200.58 ; J5.44 45.43,194.58 ; J5.44 45.43,193.42 ; J5.44 44.27,193.42 ; J5.44 44.27,194.58 ; 197.62,191.18 J3.B40 ; J3.B40 198.67,191.18 ; J3.B40 198.67,190.12 ; J3.B40 197.62,190.12 ; J3.B47 200.67,184.18 ; J3.B47 199.62,184.18 ; J3.B47 199.62,183.12 ; J3.B47 200.67,183.12 ; J7.211 165.23,142.42 ; J7.211 165.23,143.58 ; J7.211 164.07,143.58 ; J7.211 164.07,142.42 ; J6.145 150.03,138.58 ; J6.145 148.87,137.42 ; J6.145 150.03,137.42 ; J6.145 148.87,138.58 ; J6.142 151.93,134.42 ; J6.142 151.93,135.58 ; J6.142 150.77,135.58 ; J6.142 150.77,134.42 ; 197.62,228.12 J3.B4 ; J3.B4 197.62,229.18 ; J3.B4 198.67,229.18 ; J3.B4 198.67,228.12 ; J5.154 49.23,203.42 ; J5.154 48.07,204.58 ; J5.154 49.23,204.58 ; J5.154 48.07,203.42 ; J3.B16 198.67,215.18 ; J3.B16 197.62,215.18 ; J3.B16 197.62,214.12 ; J3.B16 198.67,214.12 ; 48.07,191.42 J5.166 ; J5.166 49.23,192.58 ; J5.166 48.07,192.58 ; J5.166 49.23,191.42 ; 46.17,203.58 J5.35 ; J5.35 47.33,203.58 ; J5.35 47.33,202.42 ; J5.35 46.17,202.42 ; 148.87,125.42 J6.133 ; J6.133 148.87,126.58 ; J6.133 150.03,125.42 ; J6.133 150.03,126.58 ; J7.139 165.23,219.58 ; J7.139 164.07,218.42 ; J7.139 164.07,219.58 ; J7.139 165.23,218.42 ; 199.62,195.12 J3.B35 ; J3.B35 200.67,195.12 ; J3.B35 199.62,196.18 ; J3.B35 200.67,196.18 ; 204.12,219.18 J3.A12 ; J3.A12 205.17,218.12 ; J3.A12 204.12,218.12 ; J3.A12 205.17,219.18 ; SW6.3 5.45,5.28 ; SW6.3 3.57,5.28 ; SW6.3 5.45,7.16 ; SW6.3 3.57,7.16 ; 204.12,212.12 J3.A18 ; J3.A18 205.17,212.12 ; J3.A18 204.12,213.18 ; J3.A18 205.17,213.18 ; 160.27,151.58 J7.83 ; J7.83 160.27,150.42 ; J7.83 161.43,150.42 ; J7.83 161.43,151.58 ; J5.23 47.33,215.58 ; J5.23 47.33,214.42 ; J5.23 46.17,214.42 ; J5.23 46.17,215.58 ; 160.27,117.58 J7.117 ; J7.117 161.43,117.58 ; J7.117 161.43,116.42 ; J7.117 160.27,116.42 ; J7.239 165.23,115.58 ; J7.239 164.07,115.58 ; J7.239 164.07,114.42 ; J7.239 165.23,114.42 ; J7.8 159.53,229.42 ; J7.8 158.37,230.58 ; J7.8 159.53,230.58 ; J7.8 158.37,229.42 ; 162.17,191.42 J7.166 ; J7.166 163.33,192.58 ; J7.166 162.17,192.58 ; J7.166 163.33,191.42 ; J3.B18 198.67,213.18 ; J3.B18 197.62,212.12 ; J3.B18 197.62,213.18 ; J3.B18 198.67,212.12 ; J3.A1 203.17,232.18 ; J3.A1 203.17,231.12 ; J3.A1 202.12,231.12 ; J3.A1 202.12,232.18 ; J7.89 161.43,145.58 ; J7.89 160.27,145.58 ; J7.89 161.43,144.42 ; J7.89 160.27,144.42 ; 243.71,247.01 244.43,246.3 ; 243.71,247.01 243,246.3 ; 243.71,247.01 244.43,247.73 ; 243.71,247.01 243,247.73 ; 154.57,114.42 J6.2 ; J6.2 154.57,115.58 ; J6.2 155.73,115.58 ; J6.2 155.73,114.42 ; 158.37,194.58 J7.44 ; J7.44 158.37,193.42 ; J7.44 159.53,194.58 ; J7.44 159.53,193.42 ; J7.113 161.43,120.42 ; J7.113 160.27,120.42 ; J7.113 160.27,121.58 ; J7.113 161.43,121.58 ; J6.8 155.73,121.58 ; J6.8 154.57,120.42 ; J6.8 154.57,121.58 ; J6.8 155.73,120.42 ; J7.26 159.53,211.42 ; J7.26 159.53,212.58 ; J7.26 158.37,212.58 ; J7.26 158.37,211.42 ; 162.17,203.42 J7.154 ; J7.154 163.33,204.58 ; J7.154 162.17,204.58 ; J7.154 163.33,203.42 ; 162.17,209.42 J7.148 ; J7.148 162.17,210.58 ; J7.148 163.33,209.42 ; J7.148 163.33,210.58 ; 204.12,206.12 J3.A24 ; J3.A24 205.17,207.18 ; J3.A24 204.12,207.18 ; J3.A24 205.17,206.12 ; 162.17,222.58 J7.136 ; J7.136 163.33,221.42 ; J7.136 162.17,221.42 ; J7.136 163.33,222.58 ; 51.13,218.42 J5.139 49.97,218.42 ; J5.29 47.33,209.58 ; J5.29 46.17,208.42 ; J5.29 46.17,209.58 ; J5.29 47.33,208.42 ; 48.07,210.58 J5.148 ; J5.148 49.23,210.58 ; J5.148 49.23,209.42 ; J5.148 48.07,209.42 ; 162.17,134.58 J7.220 ; J7.220 163.33,134.58 ; J7.220 163.33,133.42 ; J7.220 162.17,133.42 ; 46.17,191.58 J5.47 ; J5.47 47.33,190.42 ; J5.47 46.17,190.42 ; J5.47 47.33,191.58 ; 158.37,148.58 J7.86 ; J7.86 159.53,148.58 ; J7.86 158.37,147.42 ; J7.86 159.53,147.42 ; 164.07,230.42 J7.127 ; J7.127 164.07,231.58 ; J7.127 165.23,230.42 ; J7.127 165.23,231.58 ; J7.202 163.33,152.58 ; J7.202 162.17,151.42 ; J7.202 163.33,151.42 ; J7.202 162.17,152.58 ; J6.127 150.03,119.42 ; J6.127 150.03,120.58 ; J6.127 148.87,119.42 ; J6.127 148.87,120.58 ; J6.130 151.93,123.58 ; J6.130 151.93,122.42 ; J6.130 150.77,122.42 ; J6.130 150.77,123.58 ; J5.41 47.33,197.58 ; J5.41 47.33,196.42 ; J5.41 46.17,196.42 ; J5.41 46.17,197.58 ; 160.27,133.58 J7.101 ; J7.101 160.27,132.42 ; J7.101 161.43,132.42 ; J7.101 161.43,133.58 ; 160.27,208.42 J7.29 ; J7.29 160.27,209.58 ; J7.29 161.43,209.58 ; J7.29 161.43,208.42 ; J7.80 159.53,153.42 ; J7.80 159.53,154.58 ; J7.80 158.37,153.42 ; J7.80 158.37,154.58 ; 202.12,200.18 J3.A31 ; J3.A31 202.12,199.12 ; J3.A31 203.17,199.12 ; J3.A31 203.17,200.18 ; J7.214 163.33,139.42 ; J7.214 162.17,140.58 ; J7.214 162.17,139.42 ; J7.214 163.33,140.58 ; 148.87,114.58 J6.121 ; J6.121 150.03,113.42 ; J6.121 150.03,114.58 ; J6.121 148.87,113.42 ; 160.27,220.42 J7.17 ; J7.17 161.43,220.42 ; J7.17 160.27,221.58 ; J7.17 161.43,221.58 ; 44.27,212.58 J5.26 ; J5.26 45.43,211.42 ; J5.26 45.43,212.58 ; J5.26 44.27,211.42 ; 164.07,207.58 J7.151 ; J7.151 165.23,206.42 ; J7.151 165.23,207.58 ; J7.151 164.07,206.42 ; 48.07,198.58 J5.160 ; J5.160 49.23,198.58 ; J5.160 49.23,197.42 ; J5.160 48.07,197.42 ; J3.B39 200.67,192.18 ; J3.B39 199.62,192.18 ; J3.B39 199.62,191.12 ; J3.B39 200.67,191.12 ; 150.77,116.42 J6.124 ; J6.124 151.93,116.42 ; J6.124 151.93,117.58 ; J6.124 150.77,117.58 ; C5345.2 265.29,76.91 ; C5345.2 263.48,76.91 ; C5345.2 263.48,75.11 ; C5345.2 265.29,75.11 ; 199.62,188.18 J3.B43 ; J3.B43 200.67,187.12 ; J3.B43 199.62,187.12 ; J3.B43 200.67,188.18 ; 237.92,247.73 J2.16 ; J2.16 239.35,247.73 ; J2.16 237.92,246.3 ; J2.16 239.35,246.3 ; 160.27,197.58 J7.41 ; J7.41 161.43,197.58 ; J7.41 161.43,196.42 ; J7.41 160.27,196.42 ; 164.07,213.58 J7.145 ; J7.145 164.07,212.42 ; J7.145 165.23,212.42 ; J7.145 165.23,213.58 ; SW6.2 11.02,4.48 ; SW6.2 9.5,2.96 ; SW6.2 9.5,4.48 ; SW6.2 11.02,2.96 ; SW6.4 12.45,7.16 ; SW6.4 12.45,5.28 ; SW6.4 10.57,7.16 ; SW6.4 10.57,5.28 ; J7.235 165.23,119.58 ; J7.235 164.07,118.42 ; J7.235 165.23,118.42 ; J7.235 164.07,119.58 ; J7.110 159.53,124.58 ; J7.110 158.37,123.42 ; J7.110 158.37,124.58 ; J7.110 159.53,123.42 ; 158.37,141.42 J7.92 ; J7.92 158.37,142.58 ; J7.92 159.53,141.42 ; J7.92 159.53,142.58 ; 239.05,210.95 J55.2 240.5,210.95 ; J3.A20 205.17,211.18 ; J3.A20 205.17,210.12 ; J3.A20 204.12,210.12 ; J3.A20 204.12,211.18 ; J3.B44 198.67,186.12 ; J3.B44 197.62,186.12 ; J3.B44 197.62,187.18 ; J3.B44 198.67,187.18 ; J5.163 51.13,194.42 ; J5.163 49.97,194.42 ; J5.163 49.97,195.58 ; J5.163 51.13,195.58 ; J7.133 165.23,224.42 ; J7.133 164.07,224.42 ; J7.133 165.23,225.58 ; J7.133 164.07,225.58 ; J3.A49 203.17,182.18 ; J3.A49 203.17,181.12 ; J3.A49 202.12,182.18 ; 44.27,217.42 J5.20 ; J5.20 45.43,217.42 ; J5.20 45.43,218.58 ; 197.62,199.18 J3.B32 ; J3.B32 198.67,199.18 ; J3.B32 198.67,198.12 ; J3.B32 197.62,198.12 ; 152.67,118.58 J6.5 ; J6.5 153.83,117.42 ; J6.5 153.83,118.58 ; J6.5 152.67,117.42 ; J7.130 163.33,227.42 ; J7.130 163.33,228.58 ; J7.130 162.17,228.58 ; J7.130 162.17,227.42 ; J7.208 163.33,145.42 ; J7.208 163.33,146.58 ; J7.208 162.17,145.42 ; J7.208 162.17,146.58 ; J3.A28 205.17,203.18 ; J3.A28 205.17,202.12 ; J3.A28 204.12,203.18 ; J3.A28 204.12,202.12 ; 158.37,206.58 J7.32 ; J7.32 159.53,206.58 ; J7.32 159.53,205.42 ; J7.32 158.37,205.42 ; J3.B13 200.67,218.18 ; J3.B13 200.67,217.12 ; J3.B13 199.62,217.12 ; J3.B13 199.62,218.18 ; J7.107 161.43,126.42 ; J7.107 160.27,126.42 ; J7.107 160.27,127.58 ; J7.107 161.43,127.58 ; 199.62,209.12 J3.B21 ; J3.B21 200.67,209.12 ; J3.B21 199.62,210.18 ; J3.B21 200.67,210.18 ; J7.226 163.33,128.58 ; J7.226 162.17,127.42 ; J7.226 163.33,127.42 ; J7.226 162.17,128.58 ; 197.62,208.12 J3.B22 ; J3.B22 198.67,208.12 ; J3.B22 197.62,209.18 ; J3.B22 198.67,209.18 ; J3.B29 200.67,201.12 ; J3.B29 200.67,202.18 ; J3.B29 199.62,202.18 ; J3.B29 199.62,201.12 ; 150.77,140.42 J6.148 151.93,140.42 ; J7.47 161.43,191.58 ; J7.47 160.27,190.42 ; J7.47 161.43,190.42 ; J7.47 160.27,191.58 ; 152.67,130.58 J6.17 ; J6.17 152.67,129.42 ; J6.17 153.83,130.58 ; J6.17 153.83,129.42 ; 160.27,227.58 J7.11 ; J7.11 160.27,226.42 ; J7.11 161.43,227.58 ; J7.11 161.43,226.42 ; J6.20 155.73,133.58 ; J6.20 154.57,132.42 ; J6.20 154.57,133.58 ; J6.20 155.73,132.42 ; 240.63,204.72 J4.2 239.18,204.72 ; J3.A41 203.17,190.18 ; J3.A41 202.12,190.18 ; J3.A41 203.17,189.12 ; J3.A41 202.12,189.12
  L7_INT_3 w1.016: 2.87,22.13 H16.1 ; H16.1 2.87,15.87 ; H16.1 9.13,22.13 ; H16.1 9.13,15.87 ; 172.5,178.1 H6.1 ; H6.1 172.5,171.9 ; H6.1 178.69,178.1 ; H6.1 178.69,171.9 ; H7.1 230.13,243.87 ; H7.1 223.87,243.87 ; H7.1 230.13,250.13 ; H7.1 223.87,250.13 ; H8.1 282.13,124.62 ; H8.1 275.87,130.88 ; H8.1 282.13,130.88 ; H8.1 275.87,124.62 ; H11.1 139.13,123.99 ; H11.1 132.87,123.99 ; H11.1 132.87,130.25 ; H11.1 139.13,130.25 ; 60.87,195.99 H4.1 ; H4.1 67.13,195.99 ; H4.1 60.87,202.25 ; H4.1 67.13,202.25 ; H3.1 282.13,250.13 ; H3.1 275.87,243.87 ; H3.1 282.13,243.87 ; H3.1 275.87,250.13
  L8_PWR_1 w0.508: J6.113 153.83,230.58 ; J6.113 153.83,229.42 ; J6.113 152.67,230.58 ; J6.113 152.67,229.42 ; J6.107 153.83,223.42 ; J6.107 153.83,224.58 ; J6.107 152.67,223.42 ; J6.107 152.67,224.58 ; J6.101 153.83,217.42 ; J6.101 153.83,218.58 ; J6.101 152.67,217.42 ; J6.101 152.67,218.58 ; 125.95,245.97 J106.10 ; J106.10 127.2,245.97 ; J106.10 127.2,247.22 ; J106.10 125.95,247.22 ; 237.92,246.3 J2.16 ; J2.16 237.92,247.73 ; J2.16 239.35,246.3 ; J2.16 239.35,247.73 ; 154.57,221.58 J6.104 ; J6.104 154.57,220.42 ; J6.104 155.73,220.42 ; J6.104 155.73,221.58 ; 148.87,196.58 J6.199 ; J6.199 150.03,195.42 ; J6.199 150.03,196.58 ; J6.199 148.87,195.42 ; 154.57,226.42 J6.110 ; J6.110 155.73,226.42 ; J6.110 154.57,227.58 ; J6.110 155.73,227.58 ; J6.117 153.83,233.42 ; J6.117 152.67,233.42 ; J6.117 152.67,234.58 ; J6.117 153.83,234.58 ; J6.157 150.03,150.58 ; J6.157 148.87,150.58 ; J6.157 148.87,149.42 ; J6.157 150.03,149.42 ; 154.57,203.58 J6.86 ; J6.86 155.73,203.58 ; J6.86 155.73,202.42 ; J6.86 154.57,202.42 ; 243.71,247.01 244.43,246.3 ; 243.71,247.01 243,246.3 ; 243.71,247.01 244.43,247.73 ; 243.71,247.01 243,247.73 ; J6.29 153.83,141.42 ; J6.29 152.67,141.42 ; J6.29 153.83,142.58 ; J6.29 152.67,142.58 ; J6.235 150.03,231.42 ; J6.235 148.87,231.42 ; J6.235 148.87,232.58 ; J6.235 150.03,232.58 ; 152.67,160.58 J6.47 ; J6.47 153.83,159.42 ; J6.47 153.83,160.58 ; J6.47 152.67,159.42 ; J106.3 129.2,241.22 ; J106.3 129.2,239.97 ; J106.3 127.95,241.22 ; J106.3 127.95,239.97 ; 148.87,225.42 J6.229 ; J6.229 150.03,225.42 ; J6.229 148.87,226.58 ; J6.229 150.03,226.58 ; C5339.2 192.48,244.51 ; C5339.2 192.48,242.83 ; C5339.2 190.8,242.83 ; C5339.2 190.8,244.51 ; 150.77,222.42 J6.226 ; J6.226 151.93,222.42 ; J6.226 150.77,223.58 ; J6.226 151.93,223.58 ; 150.77,152.42 J6.160 ; J6.160 151.93,152.42 ; J6.160 150.77,153.58 ; J6.160 151.93,153.58 ; 148.87,214.58 J6.217 ; J6.217 150.03,213.42 ; J6.217 148.87,213.42 ; J6.217 150.03,214.58 ; 115.85,246.15 C5283.2 ; C5283.2 117.53,246.15 ; C5283.2 117.53,247.83 ; 154.57,196.42 J6.80 ; J6.80 154.57,197.58 ; J6.80 155.73,197.58 ; J6.80 155.73,196.42 ; 150.77,205.58 J6.208 ; J6.208 151.93,204.42 ; J6.208 151.93,205.58 ; J6.208 150.77,204.42 ; 152.67,205.42 J6.89 ; J6.89 152.67,206.58 ; J6.89 153.83,206.58 ; J6.89 153.83,205.42 ; 150.77,158.42 J6.166 ; J6.166 151.93,158.42 ; J6.166 151.93,159.58 ; J6.166 150.77,159.58 ; 154.57,232.42 J6.116 ; J6.116 155.73,232.42 ; J6.116 154.57,233.58 ; J6.116 155.73,233.58 ; 150.77,228.42 J6.232 ; J6.232 151.93,228.42 ; J6.232 150.77,229.58 ; J6.232 151.93,229.58 ; 154.57,145.58 J6.32 ; J6.32 155.73,145.58 ; J6.32 154.57,144.42 ; J6.32 155.73,144.42 ; 152.67,235.42 J6.119 ; J6.119 153.83,236.58 ; J6.119 153.83,235.42 ; J6.119 152.67,236.58 ; J6.205 150.03,202.58 ; J6.205 148.87,201.42 ; J6.205 150.03,201.42 ; J6.205 148.87,202.58 ; J6.214 151.93,210.42 ; J6.214 151.93,211.58 ; J6.214 150.77,210.42 ; J6.214 150.77,211.58 ; J6.38 155.73,150.42 ; J6.38 154.57,150.42 ; J6.38 155.73,151.58 ; J6.38 154.57,151.58 ; 154.57,209.58 J6.92 ; J6.92 154.57,208.42 ; J6.92 155.73,208.42 ; J6.92 155.73,209.58 ; J6.41 153.83,154.58 ; J6.41 152.67,153.42 ; J6.41 153.83,153.42 ; J6.41 152.67,154.58 ; 148.87,144.58 J6.151 ; J6.151 148.87,143.42 ; J6.151 150.03,144.58 ; J6.151 150.03,143.42 ; 154.57,156.42 J6.44 ; J6.44 155.73,157.58 ; J6.44 155.73,156.42 ; J6.44 154.57,157.58 ; J7.121 165.23,236.42 ; J7.121 165.23,237.58 ; J7.121 164.07,236.42 ; J7.121 164.07,237.58 ; FAN2.1 144.56,250.12 ; FAN2.1 142.97,250.12 ; FAN2.1 142.97,248.53 ; FAN2.1 144.56,248.53 ; C5337.2 208.74,244.51 ; C5337.2 208.74,242.83 ; C5337.2 207.06,242.83 ; C5337.2 207.06,244.51 ; J6.35 153.83,148.58 ; J6.35 152.67,148.58 ; J6.35 152.67,147.42 ; J6.35 153.83,147.42 ; J6.239 150.03,235.42 ; J6.239 148.87,235.42 ; J6.239 148.87,236.58 ; J6.239 150.03,236.58 ; 151.93,141.58 J6.148 150.77,141.58 ; J6.154 151.93,147.58 ; J6.154 150.77,146.42 ; J6.154 150.77,147.58 ; J6.154 151.93,146.42 ; 152.67,199.42 J6.83 ; J6.83 152.67,200.58 ; J6.83 153.83,200.58 ; J6.83 153.83,199.42 ; 158.37,236.58 J7.2 159.53,236.58 ; 148.87,156.58 J6.163 ; J6.163 148.87,155.42 ; J6.163 150.03,155.42 ; J6.163 150.03,156.58 ; 148.87,208.58 J6.211 ; J6.211 150.03,208.58 ; J6.211 150.03,207.42 ; J6.211 148.87,207.42 ; 150.77,198.42 J6.202 ; J6.202 151.93,199.58 ; J6.202 151.93,198.42 ; J6.202 150.77,199.58 ; 154.57,214.42 J6.98 ; J6.98 155.73,214.42 ; J6.98 155.73,215.58 ; J6.98 154.57,215.58 ; 150.77,216.42 J6.220 ; J6.220 150.77,217.58 ; J6.220 151.93,216.42 ; J6.220 151.93,217.58 ; 148.87,219.42 J6.223 ; J6.223 150.03,219.42 ; J6.223 148.87,220.58 ; J6.223 150.03,220.58 ; 152.67,212.58 J6.95 ; J6.95 153.83,211.42 ; J6.95 152.67,211.42 ; J6.95 153.83,212.58
  L8_PWR_1 w0.914: 113.7,213.18 BH10.1 ; BH10.1 117.43,213.18 ; BH10.1 113.7,209.45 ; BH10.1 117.43,209.45
  L8_PWR_1 w1.016: H3.1 282.13,243.87 ; H3.1 275.87,250.13 ; H3.1 275.87,243.87 ; H3.1 282.13,250.13 ; 223.87,250.13 H7.1 ; H7.1 230.13,250.13 ; H7.1 230.13,243.87 ; H7.1 223.87,243.87 ; H2.1 178.73,250.13 ; H2.1 172.47,243.87 ; H2.1 178.73,243.87 ; H2.1 172.47,250.13 ; H5.1 139.13,202.25 ; H5.1 139.13,195.99 ; H5.1 132.87,202.25 ; H5.1 132.87,195.99 ; H13.1 142.93,62.87 ; H13.1 142.93,69.13 ; H13.1 136.67,69.13 ; H13.1 136.67,62.87
  L10_INT_4 w0.508: J3.B40 198.67,191.18 ; J3.B40 197.62,191.18 ; J3.B40 197.62,190.12 ; J3.B40 198.67,190.12 ; J3.B26 198.67,204.12 ; J3.B26 197.62,205.18 ; J3.B26 198.67,205.18 ; J3.B26 197.62,204.12 ; J3.B25 200.67,205.12 ; J3.B25 200.67,206.18 ; J3.B25 199.62,205.12 ; J3.B25 199.62,206.18 ; J2.16 239.35,246.3 ; J2.16 237.92,247.73 ; J2.16 237.92,246.3 ; J2.16 239.35,247.73 ; 44.27,199.42 J5.38 ; J5.38 45.43,200.58 ; J5.38 44.27,200.58 ; J5.38 45.43,199.42 ; J3.A38 205.17,193.18 ; J3.A38 204.12,192.12 ; J3.A38 204.12,193.18 ; J3.A38 205.17,192.12 ; J3.B44 198.67,186.12 ; J3.B44 197.62,186.12 ; J3.B44 197.62,187.18 ; J3.B44 198.67,187.18 ; 204.12,188.12 J3.A42 ; J3.A42 205.17,189.18 ; J3.A42 205.17,188.12 ; J3.A42 204.12,189.18 ; 8.58,138.96 J9.24 ; J9.24 10.57,136.98 ; J9.24 8.58,136.98 ; J9.24 10.57,138.96 ; J3.A45 203.17,186.18 ; J3.A45 202.12,185.12 ; J3.A45 202.12,186.18 ; J3.A45 203.17,185.12 ; C5340.2 21.65,144.4 ; C5340.2 19.97,146.08 ; C5340.2 19.97,144.4 ; C5340.2 21.65,146.08 ; J3.A27 203.17,204.18 ; J3.A27 202.12,203.12 ; J3.A27 202.12,204.18 ; J3.A27 203.17,203.12 ; J3.A20 205.17,211.18 ; J3.A20 204.12,210.12 ; J3.A20 204.12,211.18 ; J3.A20 205.17,210.12 ; 3.18,171.27 J8.3 ; J8.3 4.97,169.48 ; J8.3 3.18,169.48 ; J8.3 4.97,171.27 ; 46.17,203.58 J5.35 ; J5.35 46.17,202.42 ; J5.35 47.33,203.58 ; J5.35 47.33,202.42 ; J3.A24 205.17,206.12 ; J3.A24 204.12,207.18 ; J3.A24 204.12,206.12 ; J3.A24 205.17,207.18 ; 202.12,207.12 J3.A23 ; J3.A23 203.17,207.12 ; J3.A23 202.12,208.18 ; J3.A23 203.17,208.18 ; 46.17,214.42 J5.23 ; J5.23 47.33,215.58 ; J5.23 46.17,215.58 ; J5.23 47.33,214.42 ; J3.B47 200.67,183.12 ; J3.B47 200.67,184.18 ; J3.B47 199.62,183.12 ; J3.B47 199.62,184.18 ; 48.07,210.58 J5.148 ; J5.148 49.23,210.58 ; J5.148 48.07,209.42 ; J5.148 49.23,209.42 ; J8.4 4.97,175.47 ; J8.4 4.97,173.68 ; J8.4 3.18,175.47 ; J8.4 3.18,173.68 ; J5.29 47.33,209.58 ; J5.29 46.17,209.58 ; J5.29 46.17,208.42 ; J5.29 47.33,208.42 ; J5.154 49.23,204.58 ; J5.154 48.07,204.58 ; J5.154 49.23,203.42 ; J5.154 48.07,203.42 ; 48.07,198.58 J5.160 ; J5.160 48.07,197.42 ; J5.160 49.23,197.42 ; J5.160 49.23,198.58 ; J8.2 4.97,167.08 ; J8.2 4.97,165.29 ; J8.2 3.18,165.29 ; J8.2 3.18,167.08 ; 19.55,132.41 CT28.2 ; CT28.2 21.23,132.41 ; CT28.2 21.23,130.73 ; CT28.2 19.55,130.73 ; J3.A34 205.17,197.18 ; J3.A34 205.17,196.12 ; J3.A34 204.12,196.12 ; J3.A34 204.12,197.18 ; J3.A49 203.17,181.12 ; J3.A49 203.17,182.18 ; J3.A49 202.12,182.18 ; 49.97,201.58 J5.157 ; J5.157 51.13,201.58 ; J5.157 51.13,200.42 ; J5.157 49.97,200.42 ; J3.A18 205.17,213.18 ; J3.A18 204.12,213.18 ; J3.A18 204.12,212.12 ; J3.A18 205.17,212.12 ; 49.97,212.42 J5.145 ; J5.145 49.97,213.58 ; J5.145 51.13,212.42 ; J5.145 51.13,213.58 ; J3.B16 198.67,215.18 ; J3.B16 197.62,215.18 ; J3.B16 198.67,214.12 ; J3.B16 197.62,214.12 ; C5345.2 265.29,76.91 ; C5345.2 263.48,75.11 ; C5345.2 263.48,76.91 ; C5345.2 265.29,75.11 ; J5.139 51.13,219.58 ; J5.139 49.97,218.42 ; J5.139 49.97,219.58 ; J5.139 51.13,218.42 ; 197.62,208.12 J3.B22 ; J3.B22 198.67,208.12 ; J3.B22 197.62,209.18 ; J3.B22 198.67,209.18 ; 240.63,204.72 J4.2 239.18,204.72 ; J3.B36 198.67,194.12 ; J3.B36 198.67,195.18 ; J3.B36 197.62,194.12 ; J3.B36 197.62,195.18 ; 199.62,196.18 J3.B35 ; J3.B35 200.67,195.12 ; J3.B35 199.62,195.12 ; J3.B35 200.67,196.18 ; 48.07,191.42 J5.166 ; J5.166 49.23,191.42 ; J5.166 49.23,192.58 ; J5.166 48.07,192.58 ; J3.B39 200.67,192.18 ; J3.B39 200.67,191.12 ; J3.B39 199.62,192.18 ; J3.B39 199.62,191.12 ; 204.12,218.12 J3.A12 ; J3.A12 205.17,219.18 ; J3.A12 205.17,218.12 ; J3.A12 204.12,219.18 ; 197.62,213.18 J3.B18 ; J3.B18 198.67,212.12 ; J3.B18 198.67,213.18 ; J3.B18 197.62,212.12 ; 44.27,193.42 J5.44 ; J5.44 44.27,194.58 ; J5.44 45.43,194.58 ; J5.44 45.43,193.42 ; 204.12,185.18 J3.A46 ; J3.A46 204.12,184.12 ; J3.A46 205.17,185.18 ; J3.A46 205.17,184.12 ; 44.27,205.42 J5.32 ; J5.32 44.27,206.58 ; J5.32 45.43,206.58 ; J5.32 45.43,205.42 ; 199.62,218.18 J3.B13 ; J3.B13 200.67,218.18 ; J3.B13 199.62,217.12 ; J3.B13 200.67,217.12 ; 46.17,191.58 J5.47 ; J5.47 47.33,190.42 ; J5.47 47.33,191.58 ; J5.47 46.17,190.42 ; 202.12,215.12 J3.A15 ; J3.A15 203.17,216.18 ; J3.A15 203.17,215.12 ; J3.A15 202.12,216.18 ; 202.12,199.12 J3.A31 ; J3.A31 203.17,199.12 ; J3.A31 203.17,200.18 ; J3.A31 202.12,200.18 ; J5.26 45.43,212.58 ; J5.26 45.43,211.42 ; J5.26 44.27,211.42 ; J5.26 44.27,212.58 ; J5.20 45.43,217.42 ; J5.20 45.43,218.58 ; J5.20 44.27,217.42 ; J5.20 44.27,218.58 ; 3.18,161.1 J8.1 ; J8.1 4.97,161.1 ; J8.1 4.97,162.89 ; J8.1 3.18,162.89 ; 243,246.3 243.71,247.01 ; 243.71,247.01 244.43,247.73 ; 243.71,247.01 244.43,246.3 ; 243.71,247.01 243,247.73 ; 46.17,196.42 J5.41 ; J5.41 47.33,197.58 ; J5.41 47.33,196.42 ; J5.41 46.17,197.58 ; J3.A37 203.17,193.12 ; J3.A37 202.12,193.12 ; J3.A37 203.17,194.18 ; J3.A37 202.12,194.18 ; J5.142 49.23,216.58 ; J5.142 49.23,215.42 ; J5.142 48.07,216.58 ; J5.142 48.07,215.42 ; 202.12,189.12 J3.A41 ; J3.A41 202.12,190.18 ; J3.A41 203.17,190.18 ; J3.A41 203.17,189.12 ; J5.163 51.13,195.58 ; J5.163 49.97,194.42 ; J5.163 49.97,195.58 ; J5.163 51.13,194.42 ; J3.B21 200.67,210.18 ; J3.B21 200.67,209.12 ; J3.B21 199.62,209.12 ; J3.B21 199.62,210.18 ; 199.62,181.12 J3.B49 ; J3.B49 200.67,182.18 ; J3.B49 199.62,182.18 ; 199.62,201.12 J3.B29 ; J3.B29 200.67,201.12 ; J3.B29 199.62,202.18 ; J3.B29 200.67,202.18 ; 204.12,202.12 J3.A28 ; J3.A28 205.17,203.18 ; J3.A28 205.17,202.12 ; J3.A28 204.12,203.18 ; 199.62,188.18 J3.B43 ; J3.B43 200.67,187.12 ; J3.B43 199.62,187.12 ; J3.B43 200.67,188.18 ; 49.97,207.58 J5.151 ; J5.151 51.13,207.58 ; J5.151 51.13,206.42 ; J5.151 49.97,206.42 ; 197.62,198.12 J3.B32 ; J3.B32 198.67,198.12 ; J3.B32 197.62,199.18 ; J3.B32 198.67,199.18 ; 239.05,210.95 J55.2 240.5,210.95
  L10_INT_4 w1.016: 66.67,93.87 H12.1 ; H12.1 66.67,100.13 ; H12.1 72.93,93.87 ; H12.1 72.93,100.13 ; H3.1 282.13,250.13 ; H3.1 282.13,243.87 ; H3.1 275.87,243.87 ; H3.1 275.87,250.13 ; H8.1 282.13,130.88 ; H8.1 275.87,130.88 ; H8.1 282.13,124.62 ; H8.1 275.87,124.62 ; 60.87,195.99 H4.1 ; H4.1 67.13,195.99 ; H4.1 67.13,202.25 ; H4.1 60.87,202.25 ; 178.69,171.9 H6.1 178.69,178.1 ; 223.87,250.13 H7.1 ; H7.1 230.13,250.13 ; H7.1 230.13,243.87 ; H7.1 223.87,243.87 ; 60.87,130.25 H10.1 ; H10.1 60.87,123.99 ; H10.1 67.13,130.25 ; H10.1 67.13,123.99 ; 2.87,146.97 H9.1 ; H9.1 2.87,153.23 ; H9.1 9.13,146.97 ; H9.1 9.13,153.23
  L11_GND_4 w0.508: 162.17,134.58 J7.220 ; J7.220 163.33,133.42 ; J7.220 162.17,133.42 ; J7.220 163.33,134.58 ; J6.133 150.03,126.58 ; J6.133 148.87,126.58 ; J6.133 148.87,125.42 ; J6.133 150.03,125.42 ; J7.83 161.43,150.42 ; J7.83 160.27,150.42 ; J7.83 160.27,151.58 ; J7.83 161.43,151.58 ; J6.117 153.83,233.42 ; J6.117 152.67,233.42 ; J6.117 152.67,234.58 ; J6.117 153.83,234.58 ; J5.136 49.23,221.42 ; J5.136 48.07,221.42 ; J5.136 48.07,222.58 ; J5.136 49.23,222.58 ; J9.3 5.07,101.16 ; J9.3 3.08,99.18 ; J9.3 5.07,99.18 ; J9.3 3.08,101.16 ; 3.08,117.96 J9.7 ; J9.7 5.07,115.98 ; J9.7 5.07,117.96 ; J9.7 3.08,115.98 ; J12.20 149.68,23.88 ; J12.20 149.68,25.2 ; J12.20 148.36,25.2 ; J12.20 148.36,23.88 ; C5341.2 41.02,28.5 ; C5341.2 41.02,30.18 ; C5341.2 39.34,30.18 ; C5341.2 39.34,28.5 ; J3.B43 200.67,188.18 ; J3.B43 199.62,188.18 ; J3.B43 200.67,187.12 ; J3.B43 199.62,187.12 ; 8.58,101.16 J9.15 ; J9.15 10.57,101.16 ; J9.15 10.57,99.18 ; J9.15 8.58,99.18 ; 49.97,207.58 J5.151 ; J5.151 51.13,207.58 ; J5.151 49.97,206.42 ; J5.151 51.13,206.42 ; J3.B39 200.67,191.12 ; J3.B39 200.67,192.18 ; J3.B39 199.62,192.18 ; J3.B39 199.62,191.12 ; J5.2 45.43,235.42 ; J5.2 44.27,236.58 ; J5.2 45.43,236.58 ; J5.2 44.27,235.42 ; 49.97,142.42 J5.211 ; J5.211 51.13,142.42 ; J5.211 51.13,143.58 ; J5.211 49.97,143.58 ; J6.11 153.83,123.42 ; J6.11 152.67,123.42 ; J6.11 153.83,124.58 ; J6.11 152.67,124.58 ; 164.07,124.42 J7.229 ; J7.229 165.23,124.42 ; J7.229 165.23,125.58 ; J7.229 164.07,125.58 ; 160.27,209.58 J7.29 ; J7.29 160.27,208.42 ; J7.29 161.43,208.42 ; J7.29 161.43,209.58 ; 46.17,209.58 J5.29 ; J5.29 47.33,209.58 ; J5.29 46.17,208.42 ; J5.29 47.33,208.42 ; J5.226 49.23,127.42 ; J5.226 49.23,128.58 ; J5.226 48.07,127.42 ; J5.226 48.07,128.58 ; 237.92,247.73 J2.16 ; J2.16 239.35,246.3 ; J2.16 239.35,247.73 ; J2.16 237.92,246.3 ; J6.136 151.93,129.58 ; J6.136 150.77,128.42 ; J6.136 150.77,129.58 ; J6.136 151.93,128.42 ; J7.26 159.53,211.42 ; J7.26 158.37,211.42 ; J7.26 158.37,212.58 ; J7.26 159.53,212.58 ; J7.35 161.43,203.58 ; J7.35 161.43,202.42 ; J7.35 160.27,202.42 ; J7.35 160.27,203.58 ; J5.127 51.13,231.58 ; J5.127 49.97,230.42 ; J5.127 49.97,231.58 ; J5.127 51.13,230.42 ; J6.8 155.73,121.58 ; J6.8 154.57,121.58 ; J6.8 154.57,120.42 ; J6.8 155.73,120.42 ; J7.98 159.53,135.42 ; J7.98 158.37,135.42 ; J7.98 159.53,136.58 ; J7.98 158.37,136.58 ; J5.239 51.13,114.42 ; J5.239 49.97,114.42 ; J5.239 49.97,115.58 ; J5.239 51.13,115.58 ; J6.163 150.03,156.58 ; J6.163 148.87,155.42 ; J6.163 148.87,156.58 ; J6.163 150.03,155.42 ; J7.205 165.23,149.58 ; J7.205 164.07,148.42 ; J7.205 165.23,148.42 ; J7.205 164.07,149.58 ; 150.77,140.42 J6.148 ; J6.148 151.93,141.58 ; J6.148 150.77,141.58 ; J6.148 151.93,140.42 ; 152.67,154.58 J6.41 ; J6.41 153.83,153.42 ; J6.41 153.83,154.58 ; J6.41 152.67,153.42 ; 162.17,127.42 J7.226 ; J7.226 163.33,128.58 ; J7.226 163.33,127.42 ; J7.226 162.17,128.58 ; J6.32 155.73,144.42 ; J6.32 154.57,144.42 ; J6.32 154.57,145.58 ; J6.32 155.73,145.58 ; 49.97,237.58 J5.121 ; J5.121 51.13,236.42 ; J5.121 49.97,236.42 ; J5.121 51.13,237.58 ; 46.17,214.42 J5.23 ; J5.23 46.17,215.58 ; J5.23 47.33,214.42 ; J5.23 47.33,215.58 ; J7.151 165.23,206.42 ; J7.151 165.23,207.58 ; J7.151 164.07,206.42 ; J7.151 164.07,207.58 ; 44.27,205.42 J5.32 ; J5.32 44.27,206.58 ; J5.32 45.43,206.58 ; J5.32 45.43,205.42 ; J5.117 47.33,116.42 ; J5.117 46.17,117.58 ; J5.117 47.33,117.58 ; J5.117 46.17,116.42 ; J7.95 161.43,138.42 ; J7.95 161.43,139.58 ; J7.95 160.27,139.58 ; J7.95 160.27,138.42 ; 158.37,235.42 J7.2 ; J7.2 159.53,236.58 ; J7.2 158.37,236.58 ; J7.2 159.53,235.42 ; 115.85,247.83 C5283.2 ; C5283.2 115.85,246.15 ; C5283.2 117.53,246.15 ; C5283.2 117.53,247.83 ; J9.19 10.57,117.96 ; J9.19 10.57,115.98 ; J9.19 8.58,115.98 ; J9.19 8.58,117.96 ; J5.208 49.23,145.42 ; J5.208 48.07,146.58 ; J5.208 49.23,146.58 ; J5.208 48.07,145.42 ; 199.62,218.18 J3.B13 ; J3.B13 200.67,218.18 ; J3.B13 200.67,217.12 ; J3.B13 199.62,217.12 ; J7.127 165.23,230.42 ; J7.127 164.07,230.42 ; J7.127 164.07,231.58 ; J7.127 165.23,231.58 ; J6.14 155.73,127.58 ; J6.14 154.57,126.42 ; J6.14 154.57,127.58 ; J6.14 155.73,126.42 ; J5.166 49.23,192.58 ; J5.166 48.07,192.58 ; J5.166 48.07,191.42 ; J5.166 49.23,191.42 ; 191.9,25.2 J14.20 ; J14.20 193.22,25.2 ; J14.20 191.9,23.88 ; J5.145 51.13,212.42 ; J5.145 49.97,213.58 ; J5.145 51.13,213.58 ; J5.145 49.97,212.42 ; J3.A28 205.17,202.12 ; J3.A28 204.12,202.12 ; J3.A28 205.17,203.18 ; J3.A28 204.12,203.18 ; 49.97,224.42 J5.133 ; J5.133 51.13,224.42 ; J5.133 49.97,225.58 ; J5.133 51.13,225.58 ; J6.239 150.03,236.58 ; J6.239 148.87,236.58 ; J6.239 150.03,235.42 ; J6.239 148.87,235.42 ; 3.18,161.1 J8.1 ; J8.1 3.18,162.89 ; J8.1 4.97,161.1 ; J8.1 4.97,162.89 ; J6.199 150.03,195.42 ; J6.199 148.87,196.58 ; J6.199 148.87,195.42 ; J6.199 150.03,196.58 ; 164.07,136.42 J7.217 ; J7.217 164.07,137.58 ; J7.217 165.23,136.42 ; J7.217 165.23,137.58 ; 46.17,190.42 J5.47 ; J5.47 47.33,190.42 ; J5.47 47.33,191.58 ; J5.47 46.17,191.58 ; J7.160 163.33,198.58 ; J7.160 163.33,197.42 ; J7.160 162.17,198.58 ; J7.160 162.17,197.42 ; 152.67,235.42 J6.119 ; J6.119 153.83,235.42 ; J6.119 152.67,236.58 ; J6.119 153.83,236.58 ; J5.229 51.13,125.58 ; J5.229 49.97,124.42 ; J5.229 49.97,125.58 ; J5.229 51.13,124.42 ; J7.113 161.43,120.42 ; J7.113 160.27,121.58 ; J7.113 161.43,121.58 ; J7.113 160.27,120.42 ; 148.87,225.42 J6.229 ; J6.229 150.03,226.58 ; J6.229 150.03,225.42 ; J6.229 148.87,226.58 ; SW6.3 5.45,5.28 ; SW6.3 5.45,7.16 ; SW6.3 3.57,5.28 ; SW6.3 3.57,7.16 ; J5.199 51.13,155.58 ; J5.199 49.97,155.58 ; J5.199 49.97,154.42 ; J5.199 51.13,154.42 ; CT28.2 21.23,132.41 ; CT28.2 21.23,130.73 ; CT28.2 19.55,130.73 ; CT28.2 19.55,132.41 ; 48.07,203.42 J5.154 ; J5.154 48.07,204.58 ; J5.154 49.23,203.42 ; J5.154 49.23,204.58 ; J7.202 163.33,151.42 ; J7.202 162.17,152.58 ; J7.202 163.33,152.58 ; J7.202 162.17,151.42 ; 154.57,197.58 J6.80 ; J6.80 155.73,196.42 ; J6.80 155.73,197.58 ; J6.80 154.57,196.42 ; 204.12,193.18 J3.A38 ; J3.A38 204.12,192.12 ; J3.A38 205.17,192.12 ; J3.A38 205.17,193.18 ; 150.77,135.58 J6.142 ; J6.142 150.77,134.42 ; J6.142 151.93,134.42 ; J6.142 151.93,135.58 ; 40.94,250.12 FAN3.1 ; FAN3.1 40.94,248.53 ; FAN3.1 42.53,248.53 ; FAN3.1 42.53,250.12 ; J6.104 155.73,221.58 ; J6.104 154.57,220.42 ; J6.104 155.73,220.42 ; J6.104 154.57,221.58 ; 154.57,156.42 J6.44 ; J6.44 154.57,157.58 ; J6.44 155.73,157.58 ; J6.44 155.73,156.42 ; J7.223 165.23,130.42 ; J7.223 164.07,130.42 ; J7.223 164.07,131.58 ; J7.223 165.23,131.58 ; J14.1 181.33,14.79 ; J14.1 180.01,13.46 ; J14.1 181.33,13.46 ; J14.1 180.01,14.79 ; J6.160 151.93,153.58 ; J6.160 151.93,152.42 ; J6.160 150.77,152.42 ; J6.160 150.77,153.58 ; J3.A46 205.17,185.18 ; J3.A46 205.17,184.12 ; J3.A46 204.12,185.18 ; J3.A46 204.12,184.12 ; 197.62,209.18 J3.B22 ; J3.B22 198.67,209.18 ; J3.B22 197.62,208.12 ; J3.B22 198.67,208.12 ; 164.07,219.58 J7.139 ; J7.139 165.23,218.42 ; J7.139 164.07,218.42 ; J7.139 165.23,219.58 ; 160.27,133.58 J7.101 ; J7.101 160.27,132.42 ; J7.101 161.43,132.42 ; J7.101 161.43,133.58 ; 49.97,201.58 J5.157 ; J5.157 51.13,201.58 ; J5.157 49.97,200.42 ; J5.157 51.13,200.42 ; 16.9,16.45 SW5.1 ; SW5.1 18.6,18.15 ; SW5.1 18.6,16.45 ; SW5.1 16.9,18.15 ; J6.23 153.83,135.42 ; J6.23 152.67,135.42 ; J6.23 153.83,136.58 ; J6.23 152.67,136.58 ; 150.77,216.42 J6.220 ; J6.220 151.93,216.42 ; J6.220 150.77,217.58 ; J6.220 151.93,217.58 ; 150.77,222.42 J6.226 ; J6.226 151.93,223.58 ; J6.226 151.93,222.42 ; J6.226 150.77,223.58 ; J6.157 150.03,149.42 ; J6.157 148.87,149.42 ; J6.157 150.03,150.58 ; J6.157 148.87,150.58 ; 162.17,216.58 J7.142 ; J7.142 163.33,215.42 ; J7.142 162.17,215.42 ; J7.142 163.33,216.58 ; J9.5 5.07,107.58 ; J9.5 5.07,109.56 ; J9.5 3.08,107.58 ; J9.5 3.08,109.56 ; J5.41 47.33,196.42 ; J5.41 46.17,197.58 ; J5.41 46.17,196.42 ; J5.41 47.33,197.58 ; 197.62,205.18 J3.B26 ; J3.B26 198.67,205.18 ; J3.B26 198.67,204.12 ; J3.B26 197.62,204.12 ; J9.17 10.57,109.56 ; J9.17 8.58,107.58 ; J9.17 8.58,109.56 ; J9.17 10.57,107.58 ; 148.87,201.42 J6.205 ; J6.205 150.03,201.42 ; J6.205 148.87,202.58 ; J6.205 150.03,202.58 ; 42.82,11.28 CN4.B4 42.82,9.93 ; 202.12,207.12 J3.A23 ; J3.A23 202.12,208.18 ; J3.A23 203.17,207.12 ; J3.A23 203.17,208.18 ; J5.163 51.13,195.58 ; J5.163 49.97,194.42 ; J5.163 51.13,194.42 ; J5.163 49.97,195.58 ; SW6.2 11.02,2.96 ; SW6.2 11.02,4.48 ; SW6.2 9.5,2.96 ; SW6.2 9.5,4.48 ; J7.23 161.43,214.42 ; J7.23 160.27,214.42 ; J7.23 160.27,215.58 ; J7.23 161.43,215.58 ; 164.07,116.42 J7.237 ; J7.237 165.23,117.58 ; J7.237 165.23,116.42 ; J7.237 164.07,117.58 ; J6.86 155.73,203.58 ; J6.86 154.57,203.58 ; J6.86 154.57,202.42 ; J6.86 155.73,202.42 ; J7.14 159.53,224.58 ; J7.14 158.37,224.58 ; J7.14 159.53,223.42 ; J7.14 158.37,223.42 ; J5.110 45.43,124.58 ; J5.110 44.27,123.42 ; J5.110 45.43,123.42 ; J5.110 44.27,124.58 ; 204.12,189.18 J3.A42 ; J3.A42 204.12,188.12 ; J3.A42 205.17,189.18 ; J3.A42 205.17,188.12 ; J5.44 45.43,194.58 ; J5.44 44.27,194.58 ; J5.44 44.27,193.42 ; J5.44 45.43,193.42 ; 199.62,205.12 J3.B25 ; J3.B25 199.62,206.18 ; J3.B25 200.67,205.12 ; J3.B25 200.67,206.18 ; J5.205 51.13,148.42 ; J5.205 49.97,149.58 ; J5.205 49.97,148.42 ; J5.205 51.13,149.58 ; J6.98 155.73,214.42 ; J6.98 155.73,215.58 ; J6.98 154.57,215.58 ; J6.98 154.57,214.42 ; 48.07,228.58 J5.130 ; J5.130 48.07,227.42 ; J5.130 49.23,227.42 ; J5.130 49.23,228.58 ; 150.77,210.42 J6.214 ; J6.214 151.93,210.42 ; J6.214 151.93,211.58 ; J6.214 150.77,211.58 ; J5.38 45.43,200.58 ; J5.38 44.27,200.58 ; J5.38 44.27,199.42 ; J5.38 45.43,199.42 ; 150.77,147.58 J6.154 ; J6.154 151.93,147.58 ; J6.154 151.93,146.42 ; J6.154 150.77,146.42 ; 154.57,227.58 J6.110 ; J6.110 155.73,227.58 ; J6.110 155.73,226.42 ; J6.110 154.57,226.42 ; J3.A41 203.17,190.18 ; J3.A41 202.12,190.18 ; J3.A41 203.17,189.12 ; J3.A41 202.12,189.12 ; FAN4.1 64.44,250.12 ; FAN4.1 62.85,248.53 ; FAN4.1 62.85,250.12 ; FAN4.1 64.44,248.53 ; 160.27,144.42 J7.89 ; J7.89 161.43,145.58 ; J7.89 160.27,145.58 ; J7.89 161.43,144.42 ; 202.12,216.18 J3.A15 ; J3.A15 202.12,215.12 ; J3.A15 203.17,215.12 ; J3.A15 203.17,216.18 ; J11.20 127.91,25.2 ; J11.20 126.59,25.2 ; J11.20 126.59,23.88 ; J11.20 127.91,23.88 ; J6.232 151.93,228.42 ; J6.232 150.77,228.42 ; J6.232 151.93,229.58 ; J6.232 150.77,229.58 ; J5.35 47.33,203.58 ; J5.35 47.33,202.42 ; J5.35 46.17,202.42 ; J5.35 46.17,203.58 ; 199.62,184.18 J3.B47 ; J3.B47 200.67,184.18 ; J3.B47 199.62,183.12 ; J3.B47 200.67,183.12 ; J5.86 45.43,147.42 ; J5.86 44.27,147.42 ; J5.86 45.43,148.58 ; J5.86 44.27,148.58 ; 158.24,13.46 J13.1 ; J13.1 159.56,13.46 ; J13.1 159.56,14.79 ; J13.1 158.24,14.79 ; J5.160 49.23,197.42 ; J5.160 48.07,198.58 ; J5.160 49.23,198.58 ; J5.160 48.07,197.42 ; 158.37,206.58 J7.32 ; J7.32 158.37,205.42 ; J7.32 159.53,206.58 ; J7.32 159.53,205.42 ; 48.07,134.58 J5.220 ; J5.220 49.23,133.42 ; J5.220 49.23,134.58 ; J5.220 48.07,133.42 ; 73.12,247.83 C5289.2 ; C5289.2 73.12,246.15 ; C5289.2 74.81,246.15 ; C5289.2 74.81,247.83 ; 44.27,230.58 J5.8 ; J5.8 45.43,230.58 ; J5.8 45.43,229.42 ; J5.8 44.27,229.42 ; 158.37,123.42 J7.110 ; J7.110 159.53,124.58 ; J7.110 159.53,123.42 ; J7.110 158.37,124.58 ; J7.199 165.23,155.58 ; J7.199 165.23,154.42 ; J7.199 164.07,154.42 ; J7.199 164.07,155.58 ; J6.151 150.03,143.42 ; J6.151 148.87,144.58 ; J6.151 148.87,143.42 ; J6.151 150.03,144.58 ; 162.17,227.42 J7.130 ; J7.130 162.17,228.58 ; J7.130 163.33,228.58 ; J7.130 163.33,227.42 ; J6.130 151.93,123.58 ; J6.130 150.77,123.58 ; J6.130 151.93,122.42 ; J6.130 150.77,122.42 ; J7.86 159.53,147.42 ; J7.86 159.53,148.58 ; J7.86 158.37,148.58 ; J7.86 158.37,147.42 ; 158.37,130.58 J7.104 ; J7.104 159.53,129.42 ; J7.104 158.37,129.42 ; J7.104 159.53,130.58 ; 152.67,147.42 J6.35 ; J6.35 153.83,147.42 ; J6.35 153.83,148.58 ; J6.35 152.67,148.58 ; J5.11 47.33,226.42 ; J5.11 46.17,227.58 ; J5.11 47.33,227.58 ; J5.11 46.17,226.42 ; 152.67,159.42 J6.47 ; J6.47 152.67,160.58 ; J6.47 153.83,159.42 ; J6.47 153.83,160.58 ; J7.8 159.53,230.58 ; J7.8 159.53,229.42 ; J7.8 158.37,230.58 ; J7.8 158.37,229.42 ; J6.139 150.03,132.58 ; J6.139 148.87,131.42 ; J6.139 148.87,132.58 ; J6.139 150.03,131.42 ; SW6.4 12.45,5.28 ; SW6.4 10.57,5.28 ; SW6.4 12.45,7.16 ; SW6.4 10.57,7.16 ; J5.89 47.33,144.42 ; J5.89 46.17,145.58 ; J5.89 46.17,144.42 ; J5.89 47.33,145.58 ; 136.47,14.79 J12.1 ; J12.1 137.79,13.46 ; J12.1 136.47,13.46 ; J12.1 137.79,14.79 ; J7.157 165.23,201.58 ; J7.157 165.23,200.42 ; J7.157 164.07,201.58 ; J7.157 164.07,200.42 ; 8.58,113.76 J9.18 ; J9.18 8.58,111.77 ; J9.18 10.57,111.77 ; J9.18 10.57,113.76 ; J5.232 49.23,121.42 ; J5.232 48.07,122.58 ; J5.232 48.07,121.42 ; J5.232 49.23,122.58 ; 148.87,113.42 J6.121 ; J6.121 148.87,114.58 ; J6.121 150.03,113.42 ; J6.121 150.03,114.58 ; 44.27,153.42 J5.80 ; J5.80 44.27,154.58 ; J5.80 45.43,153.42 ; J5.80 45.43,154.58 ; 154.57,132.42 J6.20 ; J6.20 155.73,132.42 ; J6.20 155.73,133.58 ; J6.20 154.57,133.58 ; J7.136 163.33,221.42 ; J7.136 162.17,221.42 ; J7.136 162.17,222.58 ; J7.136 163.33,222.58 ; J7.163 165.23,195.58 ; J7.163 164.07,195.58 ; J7.163 164.07,194.42 ; J7.163 165.23,194.42 ; CT35.2 22.76,93.81 ; CT35.2 21.07,93.81 ; CT35.2 21.07,92.12 ; CT35.2 22.76,92.12 ; 150.77,117.58 J6.124 ; J6.124 151.93,116.42 ; J6.124 151.93,117.58 ; J6.124 150.77,116.42 ; 170.13,23.88 J13.20 ; J13.20 170.13,25.2 ; J13.20 171.45,23.88 ; J13.20 171.45,25.2 ; 160.27,127.58 J7.107 ; J7.107 161.43,126.42 ; J7.107 160.27,126.42 ; J7.107 161.43,127.58 ; J5.104 45.43,130.58 ; J5.104 44.27,129.42 ; J5.104 45.43,129.42 ; J5.104 44.27,130.58 ; 197.62,191.18 J3.B40 ; J3.B40 198.67,190.12 ; J3.B40 198.67,191.18 ; J3.B40 197.62,190.12 ; 162.17,203.42 J7.154 ; J7.154 163.33,203.42 ; J7.154 162.17,204.58 ; J7.154 163.33,204.58 ; 150.77,159.58 J6.166 ; J6.166 151.93,159.58 ; J6.166 150.77,158.42 ; J6.166 151.93,158.42 ; 45.3,80.64 JP7.2 46.75,80.64 ; J3.A45 203.17,186.18 ; J3.A45 202.12,186.18 ; J3.A45 202.12,185.12 ; J3.A45 203.17,185.12 ; 202.12,204.18 J3.A27 ; J3.A27 203.17,204.18 ; J3.A27 203.17,203.12 ; J3.A27 202.12,203.12 ; 150.77,199.58 J6.202 ; J6.202 151.93,199.58 ; J6.202 150.77,198.42 ; J6.202 151.93,198.42 ; J6.211 150.03,208.58 ; J6.211 148.87,207.42 ; J6.211 150.03,207.42 ; J6.211 148.87,208.58 ; J5.148 49.23,210.58 ; J5.148 48.07,210.58 ; J5.148 49.23,209.42 ; J5.148 48.07,209.42 ; 160.27,197.58 J7.41 ; J7.41 161.43,196.42 ; J7.41 161.43,197.58 ; J7.41 160.27,196.42 ; 3.18,167.08 J8.2 ; J8.2 4.97,165.29 ; J8.2 4.97,167.08 ; J8.2 3.18,165.29 ; 46.17,221.58 J5.17 ; J5.17 47.33,220.42 ; J5.17 46.17,220.42 ; J5.17 47.33,221.58 ; 243.71,247.01 244.43,247.73 ; 243.71,247.01 243,247.73 ; 243.71,247.01 243,246.3 ; 243.71,247.01 244.43,246.3 ; 44.27,118.58 J5.116 ; J5.116 45.43,118.58 ; J5.116 44.27,117.42 ; J5.116 45.43,117.42 ; 162.17,233.42 J7.124 ; J7.124 163.33,234.58 ; J7.124 163.33,233.42 ; J7.124 162.17,234.58 ; J6.101 153.83,218.58 ; J6.101 153.83,217.42 ; J6.101 152.67,218.58 ; J6.101 152.67,217.42 ; 21.43,118.92 CT31.2 ; CT31.2 23.11,120.6 ; CT31.2 21.43,120.6 ; CT31.2 23.11,118.92 ; J3.A18 205.17,213.18 ; J3.A18 205.17,212.12 ; J3.A18 204.12,212.12 ; J3.A18 204.12,213.18 ; J7.116 159.53,117.42 ; J7.116 159.53,118.58 ; J7.116 158.37,118.58 ; J7.116 158.37,117.42 ; J5.235 51.13,118.42 ; J5.235 51.13,119.58 ; J5.235 49.97,118.42 ; J5.235 49.97,119.58 ; J5.20 45.43,217.42 ; J5.20 44.27,217.42 ; J5.20 44.27,218.58 ; J5.20 45.43,218.58 ; C5338.2 188.17,230.04 ; C5338.2 186.48,230.04 ; C5338.2 188.17,228.35 ; C5338.2 186.48,228.35 ; 154.57,151.58 J6.38 ; J6.38 155.73,151.58 ; J6.38 154.57,150.42 ; J6.38 155.73,150.42 ; 197.62,186.12 J3.B44 ; J3.B44 197.62,187.18 ; J3.B44 198.67,187.18 ; J3.B44 198.67,186.12 ; J5.139 51.13,219.58 ; J5.139 49.97,218.42 ; J5.139 49.97,219.58 ; J5.139 51.13,218.42 ; 20.16,250.12 FAN12.1 ; FAN12.1 21.75,250.12 ; FAN12.1 20.16,248.53 ; FAN12.1 21.75,248.53 ; 202.12,193.12 J3.A37 ; J3.A37 203.17,193.12 ; J3.A37 202.12,194.18 ; J3.A37 203.17,194.18 ; 152.67,117.42 J6.5 ; J6.5 153.83,118.58 ; J6.5 153.83,117.42 ; J6.5 152.67,118.58 ; 48.07,152.58 J5.202 ; J5.202 49.23,151.42 ; J5.202 49.23,152.58 ; J5.202 48.07,151.42 ; 9.04,250.12 FAN5.1 ; FAN5.1 9.04,248.53 ; FAN5.1 10.64,248.53 ; FAN5.1 10.64,250.12 ; J6.217 150.03,213.42 ; J6.217 148.87,214.58 ; J6.217 148.87,213.42 ; J6.217 150.03,214.58 ; J7.232 163.33,122.58 ; J7.232 162.17,122.58 ; J7.232 162.17,121.42 ; J7.232 163.33,121.42 ; 125.95,245.97 J106.10 ; J106.10 127.2,247.22 ; J106.10 127.2,245.97 ; J106.10 125.95,247.22 ; J3.A20 205.17,210.12 ; J3.A20 204.12,210.12 ; J3.A20 205.17,211.18 ; J3.A20 204.12,211.18 ; J7.17 161.43,221.58 ; J7.17 161.43,220.42 ; J7.17 160.27,221.58 ; J7.17 160.27,220.42 ; J5.26 45.43,211.42 ; J5.26 45.43,212.58 ; J5.26 44.27,211.42 ; J5.26 44.27,212.58 ; 197.62,198.12 J3.B32 ; J3.B32 198.67,199.18 ; J3.B32 198.67,198.12 ; J3.B32 197.62,199.18 ; J7.208 163.33,146.58 ; J7.208 162.17,146.58 ; J7.208 163.33,145.42 ; J7.208 162.17,145.42 ; J7.38 159.53,200.58 ; J7.38 158.37,200.58 ; J7.38 158.37,199.42 ; J7.38 159.53,199.42 ; 46.17,139.58 J5.95 ; J5.95 46.17,138.42 ; J5.95 47.33,139.58 ; J5.95 47.33,138.42 ; J7.214 163.33,140.58 ; J7.214 162.17,139.42 ; J7.214 163.33,139.42 ; J7.214 162.17,140.58 ; J7.47 161.43,190.42 ; J7.47 160.27,190.42 ; J7.47 161.43,191.58 ; J7.47 160.27,191.58 ; 49.97,131.58 J5.223 ; J5.223 49.97,130.42 ; J5.223 51.13,130.42 ; J5.223 51.13,131.58 ; J6.95 153.83,212.58 ; J6.95 152.67,211.42 ; J6.95 152.67,212.58 ; J6.95 153.83,211.42 ; 240.63,204.72 J4.2 239.18,204.72 ; J5.217 51.13,136.42 ; J5.217 51.13,137.58 ; J5.217 49.97,136.42 ; J5.217 49.97,137.58 ; 114.7,13.46 J11.1 ; J11.1 116.02,13.46 ; J11.1 114.7,14.79 ; J11.1 116.02,14.79 ; C5342.2 22.77,30.18 ; C5342.2 21.08,30.18 ; C5342.2 22.77,28.5 ; C5342.2 21.08,28.5 ; FAN1.1 196.84,51.05 ; FAN1.1 195.24,52.65 ; FAN1.1 196.84,52.65 ; FAN1.1 195.24,51.05 ; J3.B4 198.67,229.18 ; J3.B4 198.67,228.12 ; J3.B4 197.62,229.18 ; J3.B4 197.62,228.12 ; 46.17,120.42 J5.113 ; J5.113 46.17,121.58 ; J5.113 47.33,120.42 ; J5.113 47.33,121.58 ; J7.44 159.53,193.42 ; J7.44 159.53,194.58 ; J7.44 158.37,194.58 ; J7.44 158.37,193.42 ; 204.12,197.18 J3.A34 ; J3.A34 204.12,196.12 ; J3.A34 205.17,197.18 ; J3.A34 205.17,196.12 ; 44.27,142.58 J5.92 ; J5.92 45.43,142.58 ; J5.92 45.43,141.42 ; J5.92 44.27,141.42 ; J7.11 161.43,227.58 ; J7.11 161.43,226.42 ; J7.11 160.27,227.58 ; J7.11 160.27,226.42 ; J7.211 165.23,143.58 ; J7.211 164.07,142.42 ; J7.211 164.07,143.58 ; J7.211 165.23,142.42 ; 154.57,233.58 J6.116 ; J6.116 154.57,232.42 ; J6.116 155.73,232.42 ; J6.116 155.73,233.58 ; C5340.2 21.65,146.08 ; C5340.2 21.65,144.4 ; C5340.2 19.97,146.08 ; C5340.2 19.97,144.4 ; J6.83 153.83,199.42 ; J6.83 152.67,200.58 ; J6.83 153.83,200.58 ; J6.83 152.67,199.42 ; 162.17,210.58 J7.148 ; J7.148 163.33,209.42 ; J7.148 162.17,209.42 ; J7.148 163.33,210.58 ; J8.4 4.97,175.47 ; J8.4 4.97,173.68 ; J8.4 3.18,173.68 ; J8.4 3.18,175.47 ; 158.37,153.42 J7.80 ; J7.80 159.53,154.58 ; J7.80 159.53,153.42 ; J7.80 158.37,154.58 ; J6.145 150.03,137.42 ; J6.145 150.03,138.58 ; J6.145 148.87,138.58 ; J6.145 148.87,137.42 ; 3.18,169.48 J8.3 ; J8.3 4.97,169.48 ; J8.3 4.97,171.27 ; J8.3 3.18,171.27 ; J7.20 159.53,218.58 ; J7.20 158.37,218.58 ; J7.20 159.53,217.42 ; J7.20 158.37,217.42 ; 204.12,229.18 J3.A4 ; J3.A4 205.17,229.18 ; J3.A4 205.17,228.12 ; J3.A4 204.12,228.12 ; J6.107 153.83,224.58 ; J6.107 152.67,223.42 ; J6.107 153.83,223.42 ; J6.107 152.67,224.58 ; 46.17,132.42 J5.101 ; J5.101 46.17,133.58 ; J5.101 47.33,133.58 ; J5.101 47.33,132.42 ; J3.B21 200.67,209.12 ; J3.B21 200.67,210.18 ; J3.B21 199.62,210.18 ; J3.B21 199.62,209.12 ; J7.92 159.53,142.58 ; J7.92 159.53,141.42 ; J7.92 158.37,141.42 ; J7.92 158.37,142.58 ; 46.17,126.42 J5.107 ; J5.107 47.33,127.58 ; J5.107 47.33,126.42 ; J5.107 46.17,127.58 ; 148.87,220.58 J6.223 ; J6.223 150.03,219.42 ; J6.223 150.03,220.58 ; J6.223 148.87,219.42 ; J3.A24 205.17,206.12 ; J3.A24 205.17,207.18 ; J3.A24 204.12,206.12 ; J3.A24 204.12,207.18 ; J6.29 153.83,141.42 ; J6.29 152.67,142.58 ; J6.29 153.83,142.58 ; J6.29 152.67,141.42 ; J7.239 165.23,115.58 ; J7.239 164.07,114.42 ; J7.239 165.23,114.42 ; J7.239 164.07,115.58 ; J3.B16 198.67,214.12 ; J3.B16 198.67,215.18 ; J3.B16 197.62,214.12 ; J3.B16 197.62,215.18 ; J5.98 45.43,135.42 ; J5.98 44.27,135.42 ; J5.98 44.27,136.58 ; J5.98 45.43,136.58 ; 127.95,239.97 J106.3 ; J106.3 127.95,241.22 ; J106.3 129.2,241.22 ; J106.3 129.2,239.97 ; 46.17,150.42 J5.83 ; J5.83 47.33,151.58 ; J5.83 47.33,150.42 ; J5.83 46.17,151.58 ; C5345.2 265.29,76.91 ; C5345.2 263.48,76.91 ; C5345.2 265.29,75.11 ; C5345.2 263.48,75.11 ; 202.12,199.12 J3.A31 ; J3.A31 203.17,200.18 ; J3.A31 203.17,199.12 ; J3.A31 202.12,200.18 ; 48.07,233.42 J5.124 ; J5.124 49.23,233.42 ; J5.124 49.23,234.58 ; J5.124 48.07,234.58 ; 152.67,230.58 J6.113 ; J6.113 153.83,229.42 ; J6.113 152.67,229.42 ; J6.113 153.83,230.58 ; 240.5,210.95 J55.2 239.05,210.95 ; J3.B49 200.67,182.18 ; J3.B49 199.62,182.18 ; J3.B49 199.62,181.12 ; J7.5 161.43,232.42 ; J7.5 161.43,233.58 ; J7.5 160.27,233.58 ; J7.5 160.27,232.42 ; J9.24 10.57,136.98 ; J9.24 8.58,136.98 ; J9.24 10.57,138.96 ; J9.24 8.58,138.96 ; 154.57,209.58 J6.92 ; J6.92 155.73,209.58 ; J6.92 154.57,208.42 ; J6.92 155.73,208.42 ; 152.67,130.58 J6.17 ; J6.17 153.83,129.42 ; J6.17 152.67,129.42 ; J6.17 153.83,130.58 ; C5279.2 88.34,246.15 ; C5279.2 86.66,247.83 ; C5279.2 86.66,246.15 ; C5279.2 88.34,247.83 ; J6.26 155.73,138.42 ; J6.26 154.57,138.42 ; J6.26 154.57,139.58 ; J6.26 155.73,139.58 ; J7.133 165.23,225.58 ; J7.133 165.23,224.42 ; J7.133 164.07,224.42 ; J7.133 164.07,225.58 ; J5.142 49.23,216.58 ; J5.142 48.07,216.58 ; J5.142 48.07,215.42 ; J5.142 49.23,215.42 ; J7.166 163.33,191.42 ; J7.166 162.17,191.42 ; J7.166 163.33,192.58 ; J7.166 162.17,192.58 ; J10.M2 22.77,41.77 ; J10.M2 20.8,43.74 ; J10.M2 20.8,41.77 ; J10.M2 22.77,43.74 ; J3.A49 203.17,181.12 ; J3.A49 202.12,182.18 ; J3.A49 203.17,182.18 ; 154.57,115.58 J6.2 ; J6.2 155.73,115.58 ; J6.2 154.57,114.42 ; J6.2 155.73,114.42 ; 48.07,139.42 J5.214 ; J5.214 49.23,139.42 ; J5.214 48.07,140.58 ; J5.214 49.23,140.58 ; J5.5 47.33,233.58 ; J5.5 46.17,233.58 ; J5.5 47.33,232.42 ; J5.5 46.17,232.42 ; 204.12,219.18 J3.A12 ; J3.A12 204.12,218.12 ; J3.A12 205.17,218.12 ; J3.A12 205.17,219.18 ; J7.145 165.23,213.58 ; J7.145 164.07,213.58 ; J7.145 165.23,212.42 ; J7.145 164.07,212.42 ; J6.235 150.03,232.58 ; J6.235 148.87,231.42 ; J6.235 148.87,232.58 ; J6.235 150.03,231.42 ; 199.62,225.12 J3.B7 ; J3.B7 200.67,226.18 ; J3.B7 199.62,226.18 ; J3.B7 200.67,225.12 ; 199.62,201.12 J3.B29 ; J3.B29 199.62,202.18 ; J3.B29 200.67,202.18 ; J3.B29 200.67,201.12 ; 199.62,195.12 J3.B35 ; J3.B35 200.67,195.12 ; J3.B35 200.67,196.18 ; J3.B35 199.62,196.18 ; J6.89 153.83,206.58 ; J6.89 152.67,206.58 ; J6.89 153.83,205.42 ; J6.89 152.67,205.42 ; 190.8,244.51 C5339.2 ; C5339.2 190.8,242.83 ; C5339.2 192.48,242.83 ; C5339.2 192.48,244.51 ; J3.B18 198.67,212.12 ; J3.B18 197.62,213.18 ; J3.B18 197.62,212.12 ; J3.B18 198.67,213.18 ; J3.B36 198.67,195.18 ; J3.B36 197.62,194.12 ; J3.B36 197.62,195.18 ; J3.B36 198.67,194.12 ; FAN2.1 144.56,248.53 ; FAN2.1 142.97,250.12 ; FAN2.1 142.97,248.53 ; FAN2.1 144.56,250.12 ; 207.06,244.51 C5337.2 ; C5337.2 208.74,242.83 ; C5337.2 208.74,244.51 ; C5337.2 207.06,242.83 ; 160.27,116.42 J7.117 ; J7.117 161.43,116.42 ; J7.117 160.27,117.58 ; J7.117 161.43,117.58 ; J7.121 165.23,237.58 ; J7.121 164.07,237.58 ; J7.121 164.07,236.42 ; J7.121 165.23,236.42 ; J6.127 150.03,119.42 ; J6.127 150.03,120.58 ; J6.127 148.87,119.42 ; J6.127 148.87,120.58 ; J69.5 48.19,63.26 ; J69.5 48.19,64.8 ; J69.5 46.65,63.26 ; J69.5 46.65,64.8 ; J5.14 45.43,224.58 ; J5.14 44.27,224.58 ; J5.14 44.27,223.42 ; J5.14 45.43,223.42 ; J10.M1 23.77,56.57 ; J10.M1 21.8,56.57 ; J10.M1 21.8,54.6 ; J10.M1 23.77,54.6 ; 42.82,12.55 CN4.A4 42.82,13.9 ; J3.A1 203.17,232.18 ; J3.A1 202.12,231.12 ; J3.A1 203.17,231.12 ; J3.A1 202.12,232.18 ; 150.77,204.42 J6.208 ; J6.208 151.93,205.58 ; J6.208 150.77,205.58 ; J6.208 151.93,204.42 ; J7.235 165.23,119.58 ; J7.235 165.23,118.42 ; J7.235 164.07,119.58 ; J7.235 164.07,118.42
  L11_GND_4 w0.914: 113.7,209.45 BH10.1 ; BH10.1 113.7,213.18 ; BH10.1 117.43,213.18 ; BH10.1 117.43,209.45
  L11_GND_4 w1.016: H9.1 9.13,153.23 ; H9.1 2.87,146.97 ; H9.1 9.13,146.97 ; H9.1 2.87,153.23 ; 66.67,48.13 H14.1 ; H14.1 66.67,41.87 ; H14.1 72.93,48.13 ; H14.1 72.93,41.87 ; H16.1 9.13,22.13 ; H16.1 2.87,22.13 ; H16.1 9.13,15.87 ; H16.1 2.87,15.87 ; 223.87,250.13 H7.1 ; H7.1 223.87,243.87 ; H7.1 230.13,243.87 ; H7.1 230.13,250.13 ; 24.87,243.87 H1.1 ; H1.1 31.13,250.13 ; H1.1 31.13,243.87 ; H1.1 24.87,250.13 ; H2.1 178.73,243.87 ; H2.1 178.73,250.13 ; H2.1 172.47,250.13 ; H2.1 172.47,243.87 ; H15.1 282.13,22.13 ; H15.1 275.87,15.87 ; H15.1 275.87,22.13 ; H15.1 282.13,15.87 ; 172.5,178.1 H6.1 ; H6.1 178.69,178.1 ; H6.1 178.69,171.9 ; H6.1 172.5,171.9 ; H12.1 72.93,100.13 ; H12.1 66.67,100.13 ; H12.1 66.67,93.87 ; H12.1 72.93,93.87 ; 275.87,250.13 H3.1 ; H3.1 282.13,250.13 ; H3.1 275.87,243.87 ; H3.1 282.13,243.87 ; H13.1 142.93,69.13 ; H13.1 136.67,69.13 ; H13.1 136.67,62.87 ; H13.1 142.93,62.87 ; 275.87,124.62 H8.1 ; H8.1 275.87,130.88 ; H8.1 282.13,130.88 ; H8.1 282.13,124.62 ; H4.1 67.13,195.99 ; H4.1 60.87,195.99 ; H4.1 60.87,202.25 ; H4.1 67.13,202.25 ; 60.87,123.99 H10.1 ; H10.1 60.87,130.25 ; H10.1 67.13,123.99 ; H10.1 67.13,130.25 ; 132.87,195.99 H5.1 ; H5.1 132.87,202.25 ; H5.1 139.13,195.99 ; H5.1 139.13,202.25 ; 132.87,130.25 H11.1 ; H11.1 132.87,123.99 ; H11.1 139.13,123.99 ; H11.1 139.13,130.25
  L12_INT_5 w0.254: 86.97,222.12 86.97,223.24 87.22,223.49 87.57,223.49 87.86,223.78 ; 86.97,222.12 87.4,222.12 87.55,222.27 88.37,222.27 88.67,221.97 ; 86.97,222.12 85.32,220.47 80.79,220.47 79.83,219.51 66.66,219.51 66.45,219.71 66.45,220.07 66.76,220.38 v2(66.92,220.38) 67.65,220.38 68.28,221.01 68.28,222.66 67.72,223.22 v2(67.06,223.22) 66.37,222.53 65.76,222.53 64.77,221.54 64.77,219.24 66.03,217.98 80.46,217.98 81.37,218.9 85.99,218.9 87.34,220.25 88.04,220.25 88.39,220.6 88.39,221.69 88.67,221.97 ; 89.31,223.49 88.15,223.49 87.86,223.78 ; 89.31,223.49 93.59,219.22 104.1,219.22 107.48,222.6 122.67,222.6 125.3,219.97 125.3,217.25 122.29,214.24 121.73,214.24 121.31,214.66 121.31,215.24 120.85,215.7 119.91,215.7 119,214.78 109.52,214.78 103.53,208.79 103.53,188.42 103.4,188.29 v2(103.4,187.81) ; 89.31,223.49 89.67,223.85 90.98,223.85 94.07,220.75 98.6,220.75 v2(99.26,220.09) 100.03,220.09 100.46,220.52 100.46,222.1 99.82,222.73 99.8,222.73 99.77,222.76 v2(99.26,222.76) 98.78,222.28 94.71,222.28 91.53,225.45 89.31,225.45 89,225.76 88.24,225.76 87.86,225.37 87.86,223.78 ; 88.67,221.97 88.68,221.97 92.95,217.69 104.73,217.69 108.11,221.07 122.04,221.07 123.72,219.39 123.72,218.47 123.44,218.19 122.96,218.19 v6(122.02,219.13) 121.31,218.41 121.31,217.63 120.87,217.19 119.35,217.19 118.28,216.12 108.68,216.12 102.18,209.63 102.18,186.34 v3(103.33,185.2)
  L12_INT_5 w0.508: 186.48,228.35 C5338.2 ; C5338.2 188.17,230.04 ; C5338.2 186.48,230.04 ; C5338.2 188.17,228.35 ; 164.07,201.58 J7.157 ; J7.157 164.07,200.42 ; J7.157 165.23,200.42 ; J7.157 165.23,201.58 ; J3.A20 205.17,211.18 ; J3.A20 204.12,211.18 ; J3.A20 205.17,210.12 ; J3.A20 204.12,210.12 ; 199.62,201.12 J3.B29 ; J3.B29 199.62,202.18 ; J3.B29 200.67,201.12 ; J3.B29 200.67,202.18 ; 197.62,191.18 J3.B40 ; J3.B40 198.67,191.18 ; J3.B40 198.67,190.12 ; J3.B40 197.62,190.12 ; 199.62,217.12 J3.B13 ; J3.B13 199.62,218.18 ; J3.B13 200.67,218.18 ; J3.B13 200.67,217.12 ; 199.62,182.18 J3.B49 ; J3.B49 199.62,181.12 ; J3.B49 200.67,182.18 ; J3.A45 203.17,185.12 ; J3.A45 202.12,185.12 ; J3.A45 203.17,186.18 ; J3.A45 202.12,186.18 ; J3.B44 198.67,186.12 ; J3.B44 197.62,187.18 ; J3.B44 198.67,187.18 ; J3.B44 197.62,186.12 ; 162.17,191.42 J7.166 ; J7.166 163.33,191.42 ; J7.166 162.17,192.58 ; J7.166 163.33,192.58 ; J7.163 165.23,195.58 ; J7.163 165.23,194.42 ; J7.163 164.07,194.42 ; J7.163 164.07,195.58 ; 197.62,194.12 J3.B36 ; J3.B36 198.67,195.18 ; J3.B36 198.67,194.12 ; J3.B36 197.62,195.18 ; 204.12,202.12 J3.A28 ; J3.A28 205.17,202.12 ; J3.A28 205.17,203.18 ; J3.A28 204.12,203.18 ; J3.A46 205.17,185.18 ; J3.A46 204.12,185.18 ; J3.A46 205.17,184.12 ; J3.A46 204.12,184.12 ; J3.A34 205.17,197.18 ; J3.A34 204.12,196.12 ; J3.A34 205.17,196.12 ; J3.A34 204.12,197.18 ; 197.62,215.18 J3.B16 ; J3.B16 198.67,214.12 ; J3.B16 197.62,214.12 ; J3.B16 198.67,215.18 ; SW6.2 11.02,2.96 ; SW6.2 11.02,4.48 ; SW6.2 9.5,2.96 ; SW6.2 9.5,4.48 ; 204.12,206.12 J3.A24 ; J3.A24 204.12,207.18 ; J3.A24 205.17,206.12 ; J3.A24 205.17,207.18 ; FAN1.1 196.84,51.05 ; FAN1.1 196.84,52.65 ; FAN1.1 195.24,51.05 ; FAN1.1 195.24,52.65 ; J7.41 161.43,196.42 ; J7.41 161.43,197.58 ; J7.41 160.27,196.42 ; J7.41 160.27,197.58 ; C5341.2 41.02,28.5 ; C5341.2 39.34,28.5 ; C5341.2 41.02,30.18 ; J3.A23 203.17,207.12 ; J3.A23 202.12,208.18 ; J3.A23 203.17,208.18 ; J3.A23 202.12,207.12 ; 199.62,205.12 J3.B25 ; J3.B25 199.62,206.18 ; J3.B25 200.67,206.18 ; J3.B25 200.67,205.12 ; 204.12,189.18 J3.A42 ; J3.A42 204.12,188.12 ; J3.A42 205.17,188.12 ; J3.A42 205.17,189.18 ; 3.57,7.16 SW6.3 ; SW6.3 3.57,5.28 ; SW6.3 5.45,5.28 ; SW6.3 5.45,7.16 ; 202.12,193.12 J3.A37 ; J3.A37 203.17,193.12 ; J3.A37 203.17,194.18 ; J3.A37 202.12,194.18 ; 199.62,196.18 J3.B35 ; J3.B35 200.67,196.18 ; J3.B35 199.62,195.12 ; J3.B35 200.67,195.12 ; J3.B18 198.67,212.12 ; J3.B18 198.67,213.18 ; J3.B18 197.62,213.18 ; J3.B18 197.62,212.12 ; 162.17,197.42 J7.160 ; J7.160 162.17,198.58 ; J7.160 163.33,198.58 ; J7.160 163.33,197.42 ; 204.12,219.18 J3.A12 ; J3.A12 205.17,218.12 ; J3.A12 204.12,218.12 ; J3.A12 205.17,219.18 ; J3.A49 203.17,182.18 ; J3.A49 202.12,182.18 ; J3.A49 203.17,181.12 ; J3.B32 198.67,199.18 ; J3.B32 197.62,199.18 ; J3.B32 198.67,198.12 ; J3.B32 197.62,198.12 ; J3.B39 200.67,192.18 ; J3.B39 199.62,191.12 ; J3.B39 200.67,191.12 ; J3.B39 199.62,192.18 ; SW6.4 12.45,5.28 ; SW6.4 12.45,7.16 ; SW6.4 10.57,7.16 ; SW6.4 10.57,5.28 ; 199.62,188.18 J3.B43 ; J3.B43 199.62,187.12 ; J3.B43 200.67,187.12 ; J3.B43 200.67,188.18 ; 197.62,208.12 J3.B22 ; J3.B22 197.62,209.18 ; J3.B22 198.67,209.18 ; J3.B22 198.67,208.12 ; 204.12,213.18 J3.A18 ; J3.A18 205.17,212.12 ; J3.A18 204.12,212.12 ; J3.A18 205.17,213.18 ; SW5.1 18.6,18.15 ; SW5.1 16.9,18.15 ; SW5.1 18.6,16.45 ; SW5.1 16.9,16.45 ; 202.12,189.12 J3.A41 ; J3.A41 203.17,190.18 ; J3.A41 203.17,189.12 ; J3.A41 202.12,190.18 ; 42.82,11.28 CN4.B4 42.82,9.93 ; J3.A15 203.17,215.12 ; J3.A15 203.17,216.18 ; J3.A15 202.12,216.18 ; J3.A15 202.12,215.12 ; J3.A31 203.17,200.18 ; J3.A31 202.12,199.12 ; J3.A31 203.17,199.12 ; J3.A31 202.12,200.18 ; 161.43,202.42 J7.35 160.27,202.42 ; J7.38 159.53,199.42 ; J7.38 159.53,200.58 ; J7.38 158.37,200.58 ; J7.38 158.37,199.42 ; 42.82,13.9 CN4.A4 42.82,12.55 ; J3.A27 203.17,204.18 ; J3.A27 202.12,204.18 ; J3.A27 202.12,203.12 ; J3.A27 203.17,203.12 ; C5345.2 265.29,75.11 ; C5345.2 265.29,76.91 ; C5345.2 263.48,75.11 ; C5345.2 263.48,76.91 ; 158.37,194.58 J7.44 ; J7.44 159.53,193.42 ; J7.44 158.37,193.42 ; J7.44 159.53,194.58 ; J7.47 161.43,191.58 ; J7.47 160.27,190.42 ; J7.47 160.27,191.58 ; J7.47 161.43,190.42 ; J3.B26 198.67,205.18 ; J3.B26 197.62,204.12 ; J3.B26 197.62,205.18 ; J3.B26 198.67,204.12 ; 240.5,210.95 J55.2 239.05,210.95 ; J3.B47 200.67,183.12 ; J3.B47 199.62,183.12 ; J3.B47 199.62,184.18 ; J3.B47 200.67,184.18 ; 204.12,192.12 J3.A38 ; J3.A38 204.12,193.18 ; J3.A38 205.17,192.12 ; J3.A38 205.17,193.18 ; 199.62,210.18 J3.B21 ; J3.B21 200.67,209.12 ; J3.B21 200.67,210.18 ; J3.B21 199.62,209.12 ; 155.73,196.42 J6.80 155.73,197.58
  L12_INT_5 w1.016: 66.67,48.13 H14.1 ; H14.1 66.67,41.87 ; H14.1 72.93,41.87 ; H14.1 72.93,48.13 ; H6.1 178.69,178.1 ; H6.1 178.69,171.9 ; H6.1 172.5,178.1 ; H6.1 172.5,171.9 ; 2.87,22.13 H16.1 ; H16.1 9.13,22.13 ; H16.1 9.13,15.87 ; H16.1 2.87,15.87 ; H8.1 282.13,124.62 ; H8.1 275.87,124.62 ; H8.1 282.13,130.88 ; H8.1 275.87,130.88 ; H3.1 282.13,243.87 ; H3.1 275.87,250.13 ; H3.1 282.13,250.13 ; H3.1 275.87,243.87
  L13_GND_5 w0.508: 160.27,233.58 J7.5 ; J7.5 160.27,232.42 ; J7.5 161.43,233.58 ; J7.5 161.43,232.42 ; J5.223 51.13,131.58 ; J5.223 51.13,130.42 ; J5.223 49.97,130.42 ; J5.223 49.97,131.58 ; J7.235 165.23,119.58 ; J7.235 164.07,119.58 ; J7.235 165.23,118.42 ; J7.235 164.07,118.42 ; 19.55,132.41 CT28.2 ; CT28.2 21.23,130.73 ; CT28.2 19.55,130.73 ; CT28.2 21.23,132.41 ; J3.A34 205.17,197.18 ; J3.A34 204.12,196.12 ; J3.A34 204.12,197.18 ; J3.A34 205.17,196.12 ; 48.07,210.58 J5.148 ; J5.148 48.07,209.42 ; J5.148 49.23,210.58 ; J5.148 49.23,209.42 ; 148.87,226.58 J6.229 ; J6.229 148.87,225.42 ; J6.229 150.03,225.42 ; J6.229 150.03,226.58 ; 46.17,150.42 J5.83 ; J5.83 46.17,151.58 ; J5.83 47.33,150.42 ; J5.83 47.33,151.58 ; J6.119 153.83,236.58 ; J6.119 153.83,235.42 ; J6.119 152.67,236.58 ; J6.119 152.67,235.42 ; J6.202 151.93,198.42 ; J6.202 150.77,198.42 ; J6.202 151.93,199.58 ; J6.202 150.77,199.58 ; J6.226 151.93,222.42 ; J6.226 151.93,223.58 ; J6.226 150.77,222.42 ; J6.226 150.77,223.58 ; 158.37,124.58 J7.110 ; J7.110 159.53,124.58 ; J7.110 158.37,123.42 ; J7.110 159.53,123.42 ; 197.62,213.18 J3.B18 ; J3.B18 198.67,213.18 ; J3.B18 198.67,212.12 ; J3.B18 197.62,212.12 ; FAN2.1 144.56,248.53 ; FAN2.1 144.56,250.12 ; FAN2.1 142.97,250.12 ; FAN2.1 142.97,248.53 ; J7.232 163.33,121.42 ; J7.232 163.33,122.58 ; J7.232 162.17,122.58 ; J7.232 162.17,121.42 ; 150.77,217.58 J6.220 ; J6.220 151.93,217.58 ; J6.220 150.77,216.42 ; J6.220 151.93,216.42 ; 48.07,127.42 J5.226 ; J5.226 48.07,128.58 ; J5.226 49.23,127.42 ; J5.226 49.23,128.58 ; J5.113 47.33,120.42 ; J5.113 46.17,121.58 ; J5.113 47.33,121.58 ; J5.113 46.17,120.42 ; J6.217 150.03,213.42 ; J6.217 150.03,214.58 ; J6.217 148.87,213.42 ; J6.217 148.87,214.58 ; 154.57,221.58 J6.104 ; J6.104 155.73,221.58 ; J6.104 154.57,220.42 ; J6.104 155.73,220.42 ; J6.208 151.93,204.42 ; J6.208 150.77,205.58 ; J6.208 150.77,204.42 ; J6.208 151.93,205.58 ; J5.89 47.33,145.58 ; J5.89 47.33,144.42 ; J5.89 46.17,144.42 ; J5.89 46.17,145.58 ; J6.86 155.73,202.42 ; J6.86 155.73,203.58 ; J6.86 154.57,203.58 ; J6.86 154.57,202.42 ; 46.17,227.58 J5.11 ; J5.11 47.33,226.42 ; J5.11 46.17,226.42 ; J5.11 47.33,227.58 ; 150.77,153.58 J6.160 ; J6.160 151.93,152.42 ; J6.160 150.77,152.42 ; J6.160 151.93,153.58 ; J9.18 10.57,113.76 ; J9.18 10.57,111.77 ; J9.18 8.58,113.76 ; J9.18 8.58,111.77 ; 49.97,207.58 J5.151 ; J5.151 49.97,206.42 ; J5.151 51.13,207.58 ; J5.151 51.13,206.42 ; J7.133 165.23,225.58 ; J7.133 165.23,224.42 ; J7.133 164.07,225.58 ; J7.133 164.07,224.42 ; 152.67,159.42 J6.47 ; J6.47 153.83,159.42 ; J6.47 152.67,160.58 ; J6.47 153.83,160.58 ; 44.27,217.42 J5.20 ; J5.20 45.43,218.58 ; J5.20 45.43,217.42 ; J5.20 44.27,218.58 ; 158.37,130.58 J7.104 ; J7.104 159.53,130.58 ; J7.104 158.37,129.42 ; J7.104 159.53,129.42 ; J5.145 51.13,213.58 ; J5.145 49.97,212.42 ; J5.145 51.13,212.42 ; J5.145 49.97,213.58 ; 46.17,203.58 J5.35 ; J5.35 46.17,202.42 ; J5.35 47.33,202.42 ; J5.35 47.33,203.58 ; J6.199 150.03,195.42 ; J6.199 148.87,196.58 ; J6.199 150.03,196.58 ; J6.199 148.87,195.42 ; 148.87,207.42 J6.211 ; J6.211 150.03,207.42 ; J6.211 148.87,208.58 ; J6.211 150.03,208.58 ; 152.67,230.58 J6.113 ; J6.113 152.67,229.42 ; J6.113 153.83,230.58 ; J6.113 153.83,229.42 ; 150.77,135.58 J6.142 ; J6.142 151.93,135.58 ; J6.142 151.93,134.42 ; J6.142 150.77,134.42 ; 150.77,122.42 J6.130 ; J6.130 151.93,122.42 ; J6.130 150.77,123.58 ; J6.130 151.93,123.58 ; J3.A24 205.17,206.12 ; J3.A24 204.12,206.12 ; J3.A24 204.12,207.18 ; J3.A24 205.17,207.18 ; J7.38 159.53,199.42 ; J7.38 159.53,200.58 ; J7.38 158.37,199.42 ; J7.38 158.37,200.58 ; J7.98 159.53,135.42 ; J7.98 158.37,136.58 ; J7.98 159.53,136.58 ; J7.98 158.37,135.42 ; J5.101 47.33,133.58 ; J5.101 47.33,132.42 ; J5.101 46.17,132.42 ; J5.101 46.17,133.58 ; 162.17,222.58 J7.136 ; J7.136 163.33,222.58 ; J7.136 163.33,221.42 ; J7.136 162.17,221.42 ; J3.A46 205.17,184.12 ; J3.A46 204.12,185.18 ; J3.A46 205.17,185.18 ; J3.A46 204.12,184.12 ; 160.27,215.58 J7.23 ; J7.23 161.43,214.42 ; J7.23 160.27,214.42 ; J7.23 161.43,215.58 ; J7.220 163.33,133.42 ; J7.220 163.33,134.58 ; J7.220 162.17,133.42 ; J7.220 162.17,134.58 ; J3.A31 203.17,199.12 ; J3.A31 202.12,199.12 ; J3.A31 202.12,200.18 ; J3.A31 203.17,200.18 ; J5.235 51.13,119.58 ; J5.235 51.13,118.42 ; J5.235 49.97,119.58 ; J5.235 49.97,118.42 ; 3.57,5.28 SW6.3 ; SW6.3 5.45,7.16 ; SW6.3 3.57,7.16 ; SW6.3 5.45,5.28 ; J7.139 165.23,218.42 ; J7.139 164.07,218.42 ; J7.139 164.07,219.58 ; J7.139 165.23,219.58 ; J6.157 150.03,150.58 ; J6.157 148.87,149.42 ; J6.157 150.03,149.42 ; J6.157 148.87,150.58 ; C5341.2 41.02,30.18 ; C5341.2 39.34,30.18 ; C5341.2 41.02,28.5 ; C5341.2 39.34,28.5 ; J7.239 165.23,115.58 ; J7.239 164.07,115.58 ; J7.239 165.23,114.42 ; J7.239 164.07,114.42 ; J9.5 5.07,109.56 ; J9.5 3.08,107.58 ; J9.5 5.07,107.58 ; J9.5 3.08,109.56 ; 148.87,143.42 J6.151 ; J6.151 148.87,144.58 ; J6.151 150.03,144.58 ; J6.151 150.03,143.42 ; J6.154 151.93,147.58 ; J6.154 150.77,147.58 ; J6.154 151.93,146.42 ; J6.154 150.77,146.42 ; 49.97,230.42 J5.127 ; J5.127 49.97,231.58 ; J5.127 51.13,230.42 ; J5.127 51.13,231.58 ; 190.8,242.83 C5339.2 ; C5339.2 190.8,244.51 ; C5339.2 192.48,244.51 ; C5339.2 192.48,242.83 ; C5279.2 88.34,247.83 ; C5279.2 88.34,246.15 ; C5279.2 86.66,247.83 ; C5279.2 86.66,246.15 ; 164.07,131.58 J7.223 ; J7.223 165.23,130.42 ; J7.223 165.23,131.58 ; J7.223 164.07,130.42 ; J3.B13 200.67,217.12 ; J3.B13 199.62,218.18 ; J3.B13 200.67,218.18 ; J3.B13 199.62,217.12 ; J6.89 153.83,206.58 ; J6.89 152.67,206.58 ; J6.89 153.83,205.42 ; J6.89 152.67,205.42 ; 199.62,225.12 J3.B7 ; J3.B7 200.67,226.18 ; J3.B7 199.62,226.18 ; J3.B7 200.67,225.12 ; J5.166 49.23,192.58 ; J5.166 49.23,191.42 ; J5.166 48.07,192.58 ; J5.166 48.07,191.42 ; 46.17,117.58 J5.117 ; J5.117 47.33,116.42 ; J5.117 47.33,117.58 ; J5.117 46.17,116.42 ; 148.87,219.42 J6.223 ; J6.223 150.03,219.42 ; J6.223 148.87,220.58 ; J6.223 150.03,220.58 ; 197.62,191.18 J3.B40 ; J3.B40 198.67,191.18 ; J3.B40 198.67,190.12 ; J3.B40 197.62,190.12 ; 204.12,229.18 J3.A4 ; J3.A4 205.17,228.12 ; J3.A4 205.17,229.18 ; J3.A4 204.12,228.12 ; 44.27,148.58 J5.86 ; J5.86 44.27,147.42 ; J5.86 45.43,148.58 ; J5.86 45.43,147.42 ; 150.77,128.42 J6.136 ; J6.136 151.93,129.58 ; J6.136 151.93,128.42 ; J6.136 150.77,129.58 ; 152.67,211.42 J6.95 ; J6.95 152.67,212.58 ; J6.95 153.83,211.42 ; J6.95 153.83,212.58 ; J6.44 155.73,157.58 ; J6.44 154.57,156.42 ; J6.44 155.73,156.42 ; J6.44 154.57,157.58 ; 164.07,155.58 J7.199 ; J7.199 165.23,155.58 ; J7.199 165.23,154.42 ; J7.199 164.07,154.42 ; 8.58,107.58 J9.17 ; J9.17 10.57,107.58 ; J9.17 8.58,109.56 ; J9.17 10.57,109.56 ; 202.12,232.18 J3.A1 ; J3.A1 203.17,231.12 ; J3.A1 202.12,231.12 ; J3.A1 203.17,232.18 ; 154.57,151.58 J6.38 ; J6.38 155.73,150.42 ; J6.38 154.57,150.42 ; J6.38 155.73,151.58 ; J10.M2 22.77,43.74 ; J10.M2 20.8,43.74 ; J10.M2 22.77,41.77 ; J10.M2 20.8,41.77 ; J6.32 155.73,144.42 ; J6.32 155.73,145.58 ; J6.32 154.57,145.58 ; J6.32 154.57,144.42 ; 21.8,56.57 J10.M1 ; J10.M1 23.77,56.57 ; J10.M1 23.77,54.6 ; J10.M1 21.8,54.6 ; J6.163 150.03,156.58 ; J6.163 148.87,156.58 ; J6.163 148.87,155.42 ; J6.163 150.03,155.42 ; J8.2 4.97,167.08 ; J8.2 3.18,165.29 ; J8.2 4.97,165.29 ; J8.2 3.18,167.08 ; J7.47 161.43,190.42 ; J7.47 160.27,191.58 ; J7.47 160.27,190.42 ; J7.47 161.43,191.58 ; 160.27,227.58 J7.11 ; J7.11 160.27,226.42 ; J7.11 161.43,227.58 ; J7.11 161.43,226.42 ; J5.229 51.13,124.42 ; J5.229 51.13,125.58 ; J5.229 49.97,124.42 ; J5.229 49.97,125.58 ; 152.67,124.58 J6.11 ; J6.11 153.83,124.58 ; J6.11 153.83,123.42 ; J6.11 152.67,123.42 ; J5.208 49.23,145.42 ; J5.208 48.07,146.58 ; J5.208 48.07,145.42 ; J5.208 49.23,146.58 ; J3.B22 198.67,208.12 ; J3.B22 198.67,209.18 ; J3.B22 197.62,209.18 ; J3.B22 197.62,208.12 ; 160.27,203.58 J7.35 ; J7.35 161.43,202.42 ; J7.35 161.43,203.58 ; J7.35 160.27,202.42 ; 204.12,203.18 J3.A28 ; J3.A28 205.17,203.18 ; J3.A28 205.17,202.12 ; J3.A28 204.12,202.12 ; J3.A38 205.17,193.18 ; J3.A38 205.17,192.12 ; J3.A38 204.12,193.18 ; J3.A38 204.12,192.12 ; 44.27,123.42 J5.110 ; J5.110 45.43,124.58 ; J5.110 45.43,123.42 ; J5.110 44.27,124.58 ; 162.17,140.58 J7.214 ; J7.214 162.17,139.42 ; J7.214 163.33,140.58 ; J7.214 163.33,139.42 ; J3.B26 198.67,204.12 ; J3.B26 197.62,205.18 ; J3.B26 198.67,205.18 ; J3.B26 197.62,204.12 ; J5.2 45.43,235.42 ; J5.2 45.43,236.58 ; J5.2 44.27,235.42 ; J5.2 44.27,236.58 ; 3.18,173.68 J8.4 ; J8.4 3.18,175.47 ; J8.4 4.97,175.47 ; J8.4 4.97,173.68 ; J5.80 45.43,154.58 ; J5.80 44.27,153.42 ; J5.80 44.27,154.58 ; J5.80 45.43,153.42 ; J7.148 163.33,210.58 ; J7.148 163.33,209.42 ; J7.148 162.17,209.42 ; J7.148 162.17,210.58 ; 152.67,141.42 J6.29 ; J6.29 152.67,142.58 ; J6.29 153.83,141.42 ; J6.29 153.83,142.58 ; J7.151 165.23,206.42 ; J7.151 164.07,206.42 ; J7.151 164.07,207.58 ; J7.151 165.23,207.58 ; 49.97,194.42 J5.163 ; J5.163 49.97,195.58 ; J5.163 51.13,194.42 ; J5.163 51.13,195.58 ; 49.97,200.42 J5.157 ; J5.157 51.13,201.58 ; J5.157 49.97,201.58 ; J5.157 51.13,200.42 ; SW6.4 12.45,5.28 ; SW6.4 12.45,7.16 ; SW6.4 10.57,5.28 ; SW6.4 10.57,7.16 ; 148.87,138.58 J6.145 ; J6.145 148.87,137.42 ; J6.145 150.03,137.42 ; J6.145 150.03,138.58 ; J6.20 155.73,132.42 ; J6.20 155.73,133.58 ; J6.20 154.57,133.58 ; J6.20 154.57,132.42 ; 162.17,197.42 J7.160 ; J7.160 162.17,198.58 ; J7.160 163.33,197.42 ; J7.160 163.33,198.58 ; J6.205 150.03,201.42 ; J6.205 148.87,202.58 ; J6.205 150.03,202.58 ; J6.205 148.87,201.42 ; J3.B39 200.67,191.12 ; J3.B39 200.67,192.18 ; J3.B39 199.62,192.18 ; J3.B39 199.62,191.12 ; C5289.2 74.81,247.83 ; C5289.2 74.81,246.15 ; C5289.2 73.12,246.15 ; C5289.2 73.12,247.83 ; J3.A27 203.17,204.18 ; J3.A27 203.17,203.12 ; J3.A27 202.12,204.18 ; J3.A27 202.12,203.12 ; 46.17,233.58 J5.5 ; J5.5 47.33,232.42 ; J5.5 47.33,233.58 ; J5.5 46.17,232.42 ; J3.B32 198.67,198.12 ; J3.B32 198.67,199.18 ; J3.B32 197.62,199.18 ; J3.B32 197.62,198.12 ; 180.01,14.79 J14.1 ; J14.1 180.01,13.46 ; J14.1 181.33,14.79 ; J14.1 181.33,13.46 ; 199.62,206.18 J3.B25 ; J3.B25 200.67,205.12 ; J3.B25 199.62,205.12 ; J3.B25 200.67,206.18 ; J5.124 49.23,234.58 ; J5.124 48.07,233.42 ; J5.124 48.07,234.58 ; J5.124 49.23,233.42 ; 46.17,127.58 J5.107 ; J5.107 46.17,126.42 ; J5.107 47.33,127.58 ; J5.107 47.33,126.42 ; J5.136 49.23,221.42 ; J5.136 48.07,221.42 ; J5.136 48.07,222.58 ; J5.136 49.23,222.58 ; 199.62,183.12 J3.B47 ; J3.B47 199.62,184.18 ; J3.B47 200.67,184.18 ; J3.B47 200.67,183.12 ; 191.9,25.2 J14.20 ; J14.20 191.9,23.88 ; J14.20 193.22,25.2 ; J6.139 150.03,131.42 ; J6.139 150.03,132.58 ; J6.139 148.87,131.42 ; J6.139 148.87,132.58 ; 204.12,212.12 J3.A18 ; J3.A18 205.17,212.12 ; J3.A18 204.12,213.18 ; J3.A18 205.17,213.18 ; J6.8 155.73,120.42 ; J6.8 154.57,120.42 ; J6.8 155.73,121.58 ; J6.8 154.57,121.58 ; J8.1 4.97,162.89 ; J8.1 3.18,161.1 ; J8.1 3.18,162.89 ; J8.1 4.97,161.1 ; 46.65,63.26 J69.5 ; J69.5 48.19,64.8 ; J69.5 48.19,63.26 ; J69.5 46.65,64.8 ; J6.148 151.93,140.42 ; J6.148 151.93,141.58 ; J6.148 150.77,141.58 ; J6.148 150.77,140.42 ; 162.17,151.42 J7.202 ; J7.202 163.33,151.42 ; J7.202 163.33,152.58 ; J7.202 162.17,152.58 ; J5.133 51.13,224.42 ; J5.133 51.13,225.58 ; J5.133 49.97,224.42 ; J5.133 49.97,225.58 ; 44.27,193.42 J5.44 ; J5.44 44.27,194.58 ; J5.44 45.43,193.42 ; J5.44 45.43,194.58 ; J7.8 159.53,229.42 ; J7.8 158.37,230.58 ; J7.8 158.37,229.42 ; J7.8 159.53,230.58 ; 152.67,147.42 J6.35 ; J6.35 153.83,148.58 ; J6.35 153.83,147.42 ; J6.35 152.67,148.58 ; 204.12,188.12 J3.A42 ; J3.A42 205.17,189.18 ; J3.A42 204.12,189.18 ; J3.A42 205.17,188.12 ; 240.5,210.95 J55.2 239.05,210.95 ; 46.17,197.58 J5.41 ; J5.41 46.17,196.42 ; J5.41 47.33,196.42 ; J5.41 47.33,197.58 ; J3.A15 203.17,216.18 ; J3.A15 203.17,215.12 ; J3.A15 202.12,216.18 ; J3.A15 202.12,215.12 ; 148.87,125.42 J6.133 ; J6.133 150.03,125.42 ; J6.133 148.87,126.58 ; J6.133 150.03,126.58 ; J5.98 45.43,136.58 ; J5.98 44.27,136.58 ; J5.98 44.27,135.42 ; J5.98 45.43,135.42 ; J5.202 49.23,151.42 ; J5.202 49.23,152.58 ; J5.202 48.07,151.42 ; J5.202 48.07,152.58 ; 202.12,194.18 J3.A37 ; J3.A37 203.17,194.18 ; J3.A37 202.12,193.12 ; J3.A37 203.17,193.12 ; 48.07,139.42 J5.214 ; J5.214 49.23,140.58 ; J5.214 48.07,140.58 ; J5.214 49.23,139.42 ; J6.41 153.83,153.42 ; J6.41 152.67,153.42 ; J6.41 153.83,154.58 ; J6.41 152.67,154.58 ; J3.A12 205.17,218.12 ; J3.A12 205.17,219.18 ; J3.A12 204.12,218.12 ; J3.A12 204.12,219.18 ; J5.104 45.43,130.58 ; J5.104 44.27,129.42 ; J5.104 44.27,130.58 ; J5.104 45.43,129.42 ; 49.97,148.42 J5.205 ; J5.205 49.97,149.58 ; J5.205 51.13,149.58 ; J5.205 51.13,148.42 ; 160.27,221.58 J7.17 ; J7.17 161.43,220.42 ; J7.17 160.27,220.42 ; J7.17 161.43,221.58 ; J3.A20 205.17,210.12 ; J3.A20 204.12,210.12 ; J3.A20 204.12,211.18 ; J3.A20 205.17,211.18 ; 158.37,193.42 J7.44 ; J7.44 159.53,194.58 ; J7.44 158.37,194.58 ; J7.44 159.53,193.42 ; CT35.2 22.76,92.12 ; CT35.2 22.76,93.81 ; CT35.2 21.07,93.81 ; CT35.2 21.07,92.12 ; 154.57,127.58 J6.14 ; J6.14 155.73,126.42 ; J6.14 154.57,126.42 ; J6.14 155.73,127.58 ; 202.12,186.18 J3.A45 ; J3.A45 203.17,185.12 ; J3.A45 202.12,185.12 ; J3.A45 203.17,186.18 ; J7.124 163.33,234.58 ; J7.124 162.17,233.42 ; J7.124 163.33,233.42 ; J7.124 162.17,234.58 ; 158.37,206.58 J7.32 ; J7.32 159.53,205.42 ; J7.32 158.37,205.42 ; J7.32 159.53,206.58 ; J7.113 161.43,121.58 ; J7.113 161.43,120.42 ; J7.113 160.27,120.42 ; J7.113 160.27,121.58 ; J7.14 159.53,223.42 ; J7.14 158.37,224.58 ; J7.14 158.37,223.42 ; J7.14 159.53,224.58 ; J6.107 153.83,223.42 ; J6.107 152.67,224.58 ; J6.107 153.83,224.58 ; J6.107 152.67,223.42 ; J12.20 149.68,25.2 ; J12.20 149.68,23.88 ; J12.20 148.36,25.2 ; J12.20 148.36,23.88 ; J7.205 165.23,149.58 ; J7.205 164.07,149.58 ; J7.205 164.07,148.42 ; J7.205 165.23,148.42 ; 164.07,136.42 J7.217 ; J7.217 164.07,137.58 ; J7.217 165.23,136.42 ; J7.217 165.23,137.58 ; J5.29 47.33,208.42 ; J5.29 46.17,208.42 ; J5.29 47.33,209.58 ; J5.29 46.17,209.58 ; J7.211 165.23,143.58 ; J7.211 164.07,142.42 ; J7.211 165.23,142.42 ; J7.211 164.07,143.58 ; 164.07,124.42 J7.229 ; J7.229 164.07,125.58 ; J7.229 165.23,125.58 ; J7.229 165.23,124.42 ; J6.83 153.83,200.58 ; J6.83 152.67,199.42 ; J6.83 152.67,200.58 ; J6.83 153.83,199.42 ; J6.17 153.83,130.58 ; J6.17 152.67,130.58 ; J6.17 153.83,129.42 ; J6.17 152.67,129.42 ; 115.85,247.83 C5283.2 ; C5283.2 117.53,246.15 ; C5283.2 115.85,246.15 ; C5283.2 117.53,247.83 ; C5338.2 188.17,230.04 ; C5338.2 186.48,230.04 ; C5338.2 186.48,228.35 ; C5338.2 188.17,228.35 ; J6.117 153.83,234.58 ; J6.117 152.67,233.42 ; J6.117 153.83,233.42 ; J6.117 152.67,234.58 ; J5.47 47.33,190.42 ; J5.47 46.17,191.58 ; J5.47 47.33,191.58 ; J5.47 46.17,190.42 ; J9.3 5.07,101.16 ; J9.3 5.07,99.18 ; J9.3 3.08,101.16 ; J9.3 3.08,99.18 ; 46.17,220.42 J5.17 ; J5.17 47.33,220.42 ; J5.17 46.17,221.58 ; J5.17 47.33,221.58 ; 114.7,14.79 J11.1 ; J11.1 116.02,13.46 ; J11.1 116.02,14.79 ; J11.1 114.7,13.46 ; C5342.2 22.77,28.5 ; C5342.2 22.77,30.18 ; C5342.2 21.08,30.18 ; C5342.2 21.08,28.5 ; 164.07,201.58 J7.157 ; J7.157 165.23,201.58 ; J7.157 164.07,200.42 ; J7.157 165.23,200.42 ; 126.59,23.88 J11.20 ; J11.20 127.91,25.2 ; J11.20 126.59,25.2 ; J11.20 127.91,23.88 ; J5.121 51.13,237.58 ; J5.121 49.97,237.58 ; J5.121 49.97,236.42 ; J5.121 51.13,236.42 ; J7.41 161.43,196.42 ; J7.41 160.27,196.42 ; J7.41 160.27,197.58 ; J7.41 161.43,197.58 ; 154.57,233.58 J6.116 ; J6.116 154.57,232.42 ; J6.116 155.73,232.42 ; J6.116 155.73,233.58 ; 160.27,139.58 J7.95 ; J7.95 161.43,139.58 ; J7.95 160.27,138.42 ; J7.95 161.43,138.42 ; 162.17,192.58 J7.166 ; J7.166 163.33,191.42 ; J7.166 162.17,191.42 ; J7.166 163.33,192.58 ; 154.57,209.58 J6.92 ; J6.92 155.73,209.58 ; J6.92 154.57,208.42 ; J6.92 155.73,208.42 ; J7.116 159.53,117.42 ; J7.116 158.37,117.42 ; J7.116 158.37,118.58 ; J7.116 159.53,118.58 ; 199.62,188.18 J3.B43 ; J3.B43 200.67,187.12 ; J3.B43 199.62,187.12 ; J3.B43 200.67,188.18 ; J12.1 137.79,13.46 ; J12.1 137.79,14.79 ; J12.1 136.47,13.46 ; J12.1 136.47,14.79 ; 44.27,206.58 J5.32 ; J5.32 45.43,206.58 ; J5.32 44.27,205.42 ; J5.32 45.43,205.42 ; 170.13,23.88 J13.20 ; J13.20 171.45,25.2 ; J13.20 170.13,25.2 ; J13.20 171.45,23.88 ; 44.27,230.58 J5.8 ; J5.8 44.27,229.42 ; J5.8 45.43,229.42 ; J5.8 45.43,230.58 ; J5.199 51.13,154.42 ; J5.199 49.97,155.58 ; J5.199 49.97,154.42 ; J5.199 51.13,155.58 ; J6.214 151.93,210.42 ; J6.214 150.77,211.58 ; J6.214 150.77,210.42 ; J6.214 151.93,211.58 ; J9.15 10.57,101.16 ; J9.15 10.57,99.18 ; J9.15 8.58,101.16 ; J9.15 8.58,99.18 ; 42.82,13.9 CN4.A4 42.82,12.55 ; 160.27,208.42 J7.29 ; J7.29 161.43,208.42 ; J7.29 161.43,209.58 ; J7.29 160.27,209.58 ; 158.37,154.58 J7.80 ; J7.80 158.37,153.42 ; J7.80 159.53,154.58 ; J7.80 159.53,153.42 ; 62.85,248.53 FAN4.1 ; FAN4.1 64.44,248.53 ; FAN4.1 64.44,250.12 ; FAN4.1 62.85,250.12 ; 158.24,14.79 J13.1 ; J13.1 159.56,14.79 ; J13.1 158.24,13.46 ; J13.1 159.56,13.46 ; 9.5,4.48 SW6.2 ; SW6.2 11.02,4.48 ; SW6.2 9.5,2.96 ; SW6.2 11.02,2.96 ; 197.62,194.12 J3.B36 ; J3.B36 198.67,195.18 ; J3.B36 197.62,195.18 ; J3.B36 198.67,194.12 ; SW5.1 18.6,18.15 ; SW5.1 16.9,16.45 ; SW5.1 18.6,16.45 ; SW5.1 16.9,18.15 ; 202.12,189.12 J3.A41 ; J3.A41 203.17,190.18 ; J3.A41 202.12,190.18 ; J3.A41 203.17,189.12 ; 48.07,215.42 J5.142 ; J5.142 48.07,216.58 ; J5.142 49.23,216.58 ; J5.142 49.23,215.42 ; J7.107 161.43,127.58 ; J7.107 161.43,126.42 ; J7.107 160.27,126.42 ; J7.107 160.27,127.58 ; J5.38 45.43,200.58 ; J5.38 44.27,199.42 ; J5.38 45.43,199.42 ; J5.38 44.27,200.58 ; 9.04,248.53 FAN5.1 ; FAN5.1 10.64,248.53 ; FAN5.1 9.04,250.12 ; FAN5.1 10.64,250.12 ; J5.211 51.13,142.42 ; J5.211 51.13,143.58 ; J5.211 49.97,143.58 ; J5.211 49.97,142.42 ; 46.17,139.58 J5.95 ; J5.95 46.17,138.42 ; J5.95 47.33,138.42 ; J5.95 47.33,139.58 ; 125.95,247.22 J106.10 ; J106.10 125.95,245.97 ; J106.10 127.2,245.97 ; J106.10 127.2,247.22 ; 44.27,211.42 J5.26 ; J5.26 44.27,212.58 ; J5.26 45.43,212.58 ; J5.26 45.43,211.42 ; 197.62,228.12 J3.B4 ; J3.B4 198.67,228.12 ; J3.B4 197.62,229.18 ; J3.B4 198.67,229.18 ; J6.121 150.03,113.42 ; J6.121 150.03,114.58 ; J6.121 148.87,113.42 ; J6.121 148.87,114.58 ; 150.77,158.42 J6.166 ; J6.166 151.93,158.42 ; J6.166 151.93,159.58 ; J6.166 150.77,159.58 ; 164.07,231.58 J7.127 ; J7.127 165.23,231.58 ; J7.127 165.23,230.42 ; J7.127 164.07,230.42 ; J3.B49 200.67,182.18 ; J3.B49 199.62,182.18 ; J3.B49 199.62,181.12 ; 21.43,120.6 CT31.2 ; CT31.2 23.11,120.6 ; CT31.2 21.43,118.92 ; CT31.2 23.11,118.92 ; 162.17,145.42 J7.208 ; J7.208 163.33,146.58 ; J7.208 162.17,146.58 ; J7.208 163.33,145.42 ; J6.23 153.83,135.42 ; J6.23 153.83,136.58 ; J6.23 152.67,136.58 ; J6.23 152.67,135.42 ; J7.226 163.33,127.42 ; J7.226 162.17,128.58 ; J7.226 162.17,127.42 ; J7.226 163.33,128.58 ; 199.62,209.12 J3.B21 ; J3.B21 200.67,209.12 ; J3.B21 200.67,210.18 ; J3.B21 199.62,210.18 ; 46.17,214.42 J5.23 ; J5.23 46.17,215.58 ; J5.23 47.33,214.42 ; J5.23 47.33,215.58 ; J6.101 153.83,217.42 ; J6.101 152.67,218.58 ; J6.101 152.67,217.42 ; J6.101 153.83,218.58 ; 160.27,116.42 J7.117 ; J7.117 160.27,117.58 ; J7.117 161.43,116.42 ; J7.117 161.43,117.58 ; J6.2 155.73,115.58 ; J6.2 154.57,115.58 ; J6.2 155.73,114.42 ; J6.2 154.57,114.42 ; J5.139 51.13,219.58 ; J5.139 49.97,218.42 ; J5.139 49.97,219.58 ; J5.139 51.13,218.42 ; J5.154 49.23,204.58 ; J5.154 48.07,203.42 ; J5.154 48.07,204.58 ; J5.154 49.23,203.42 ; 263.48,76.91 C5345.2 ; C5345.2 265.29,75.11 ; C5345.2 265.29,76.91 ; C5345.2 263.48,75.11 ; J7.154 163.33,203.42 ; J7.154 162.17,204.58 ; J7.154 162.17,203.42 ; J7.154 163.33,204.58 ; 150.77,228.42 J6.232 ; J6.232 150.77,229.58 ; J6.232 151.93,228.42 ; J6.232 151.93,229.58 ; J5.217 51.13,136.42 ; J5.217 51.13,137.58 ; J5.217 49.97,136.42 ; J5.217 49.97,137.58 ; J3.B29 200.67,201.12 ; J3.B29 199.62,201.12 ; J3.B29 200.67,202.18 ; J3.B29 199.62,202.18 ; 158.37,218.58 J7.20 ; J7.20 158.37,217.42 ; J7.20 159.53,218.58 ; J7.20 159.53,217.42 ; 19.97,144.4 C5340.2 ; C5340.2 19.97,146.08 ; C5340.2 21.65,144.4 ; C5340.2 21.65,146.08 ; 3.18,169.48 J8.3 ; J8.3 4.97,169.48 ; J8.3 3.18,171.27 ; J8.3 4.97,171.27 ; 160.27,144.42 J7.89 ; J7.89 161.43,145.58 ; J7.89 160.27,145.58 ; J7.89 161.43,144.42 ; 48.07,134.58 J5.220 ; J5.220 48.07,133.42 ; J5.220 49.23,133.42 ; J5.220 49.23,134.58 ; 199.62,195.12 J3.B35 ; J3.B35 199.62,196.18 ; J3.B35 200.67,195.12 ; J3.B35 200.67,196.18 ; 44.27,224.58 J5.14 ; J5.14 44.27,223.42 ; J5.14 45.43,224.58 ; J5.14 45.43,223.42 ; J6.239 150.03,236.58 ; J6.239 148.87,235.42 ; J6.239 148.87,236.58 ; J6.239 150.03,235.42 ; 3.08,115.98 J9.7 ; J9.7 5.07,115.98 ; J9.7 3.08,117.96 ; J9.7 5.07,117.96 ; FAN12.1 21.75,248.53 ; FAN12.1 21.75,250.12 ; FAN12.1 20.16,250.12 ; FAN12.1 20.16,248.53 ; J6.127 150.03,119.42 ; J6.127 150.03,120.58 ; J6.127 148.87,120.58 ; J6.127 148.87,119.42 ; 44.27,117.42 J5.116 ; J5.116 44.27,118.58 ; J5.116 45.43,118.58 ; J5.116 45.43,117.42 ; FAN3.1 42.53,248.53 ; FAN3.1 42.53,250.12 ; FAN3.1 40.94,248.53 ; FAN3.1 40.94,250.12 ; 49.97,114.42 J5.239 ; J5.239 51.13,115.58 ; J5.239 49.97,115.58 ; J5.239 51.13,114.42 ; J7.83 161.43,151.58 ; J7.83 161.43,150.42 ; J7.83 160.27,150.42 ; J7.83 160.27,151.58 ; J3.B44 198.67,186.12 ; J3.B44 197.62,186.12 ; J3.B44 198.67,187.18 ; J3.B44 197.62,187.18 ; 158.37,211.42 J7.26 ; J7.26 159.53,212.58 ; J7.26 159.53,211.42 ; J7.26 158.37,212.58 ; 197.62,214.12 J3.B16 ; J3.B16 197.62,215.18 ; J3.B16 198.67,215.18 ; J3.B16 198.67,214.12 ; J6.235 150.03,232.58 ; J6.235 148.87,232.58 ; J6.235 148.87,231.42 ; J6.235 150.03,231.42 ; J5.92 45.43,142.58 ; J5.92 45.43,141.42 ; J5.92 44.27,142.58 ; J5.92 44.27,141.42 ; 48.07,122.58 J5.232 ; J5.232 49.23,122.58 ; J5.232 48.07,121.42 ; J5.232 49.23,121.42 ; J7.142 163.33,215.42 ; J7.142 163.33,216.58 ; J7.142 162.17,215.42 ; J7.142 162.17,216.58 ; 202.12,208.18 J3.A23 ; J3.A23 203.17,207.12 ; J3.A23 203.17,208.18 ; J3.A23 202.12,207.12 ; 240.63,204.72 J4.2 239.18,204.72 ; 195.24,52.65 FAN1.1 ; FAN1.1 195.24,51.05 ; FAN1.1 196.84,52.65 ; FAN1.1 196.84,51.05 ; 154.57,138.42 J6.26 ; J6.26 155.73,138.42 ; J6.26 154.57,139.58 ; J6.26 155.73,139.58 ; 48.07,198.58 J5.160 ; J5.160 49.23,197.42 ; J5.160 48.07,197.42 ; J5.160 49.23,198.58 ; J5.130 49.23,228.58 ; J5.130 48.07,228.58 ; J5.130 48.07,227.42 ; J5.130 49.23,227.42 ; 8.58,136.98 J9.24 ; J9.24 10.57,138.96 ; J9.24 8.58,138.96 ; J9.24 10.57,136.98 ; J7.130 163.33,227.42 ; J7.130 163.33,228.58 ; J7.130 162.17,228.58 ; J7.130 162.17,227.42 ; 237.92,247.73 J2.16 ; J2.16 237.92,246.3 ; J2.16 239.35,247.73 ; J2.16 239.35,246.3 ; 154.57,227.58 J6.110 ; J6.110 155.73,227.58 ; J6.110 155.73,226.42 ; J6.110 154.57,226.42 ; J6.5 153.83,118.58 ; J6.5 152.67,118.58 ; J6.5 153.83,117.42 ; J6.5 152.67,117.42 ; C5337.2 208.74,244.51 ; C5337.2 207.06,244.51 ; C5337.2 207.06,242.83 ; C5337.2 208.74,242.83 ; 42.82,9.93 CN4.B4 42.82,11.28 ; J7.101 161.43,133.58 ; J7.101 160.27,132.42 ; J7.101 160.27,133.58 ; J7.101 161.43,132.42 ; 164.07,236.42 J7.121 ; J7.121 164.07,237.58 ; J7.121 165.23,236.42 ; J7.121 165.23,237.58 ; J7.86 159.53,148.58 ; J7.86 158.37,148.58 ; J7.86 159.53,147.42 ; J7.86 158.37,147.42 ; J7.145 165.23,213.58 ; J7.145 165.23,212.42 ; J7.145 164.07,212.42 ; J7.145 164.07,213.58 ; J9.19 10.57,115.98 ; J9.19 8.58,117.96 ; J9.19 10.57,117.96 ; J9.19 8.58,115.98 ; J6.80 155.73,197.58 ; J6.80 154.57,196.42 ; J6.80 154.57,197.58 ; J6.80 155.73,196.42 ; 243,246.3 243.71,247.01 ; 243.71,247.01 244.43,247.73 ; 243.71,247.01 244.43,246.3 ; 243.71,247.01 243,247.73 ; 150.77,117.58 J6.124 ; J6.124 151.93,117.58 ; J6.124 150.77,116.42 ; J6.124 151.93,116.42 ; 158.37,141.42 J7.92 ; J7.92 158.37,142.58 ; J7.92 159.53,142.58 ; J7.92 159.53,141.42 ; 46.75,80.64 JP7.2 45.3,80.64 ; J7.2 159.53,235.42 ; J7.2 159.53,236.58 ; J7.2 158.37,236.58 ; J7.2 158.37,235.42 ; 164.07,194.42 J7.163 ; J7.163 165.23,195.58 ; J7.163 165.23,194.42 ; J7.163 164.07,195.58 ; 202.12,182.18 J3.A49 ; J3.A49 203.17,182.18 ; J3.A49 203.17,181.12 ; 154.57,215.58 J6.98 ; J6.98 155.73,214.42 ; J6.98 155.73,215.58 ; J6.98 154.57,214.42 ; 127.95,239.97 J106.3 ; J106.3 127.95,241.22 ; J106.3 129.2,239.97 ; J106.3 129.2,241.22 ; 164.07,116.42 J7.237 ; J7.237 165.23,116.42 ; J7.237 164.07,117.58 ; J7.237 165.23,117.58
  L13_GND_5 w0.914: 113.7,213.18 BH10.1 ; BH10.1 117.43,213.18 ; BH10.1 117.43,209.45 ; BH10.1 113.7,209.45
  L13_GND_5 w1.016: H12.1 72.93,100.13 ; H12.1 66.67,100.13 ; H12.1 66.67,93.87 ; H12.1 72.93,93.87 ; 24.87,243.87 H1.1 ; H1.1 31.13,250.13 ; H1.1 31.13,243.87 ; H1.1 24.87,250.13 ; 60.87,123.99 H10.1 ; H10.1 67.13,123.99 ; H10.1 60.87,130.25 ; H10.1 67.13,130.25 ; 275.87,124.62 H8.1 ; H8.1 282.13,130.88 ; H8.1 275.87,130.88 ; H8.1 282.13,124.62 ; 275.87,243.87 H3.1 ; H3.1 282.13,250.13 ; H3.1 282.13,243.87 ; H3.1 275.87,250.13 ; H5.1 139.13,202.25 ; H5.1 132.87,202.25 ; H5.1 139.13,195.99 ; H5.1 132.87,195.99 ; 132.87,130.25 H11.1 ; H11.1 139.13,130.25 ; H11.1 139.13,123.99 ; H11.1 132.87,123.99 ; 66.67,41.87 H14.1 ; H14.1 66.67,48.13 ; H14.1 72.93,48.13 ; H14.1 72.93,41.87 ; 172.47,250.13 H2.1 ; H2.1 178.73,250.13 ; H2.1 172.47,243.87 ; H2.1 178.73,243.87 ; 172.5,171.9 H6.1 ; H6.1 172.5,178.1 ; H6.1 178.69,178.1 ; H6.1 178.69,171.9 ; 223.87,250.13 H7.1 ; H7.1 230.13,250.13 ; H7.1 230.13,243.87 ; H7.1 223.87,243.87 ; 2.87,153.23 H9.1 ; H9.1 9.13,146.97 ; H9.1 2.87,146.97 ; H9.1 9.13,153.23 ; H13.1 142.93,69.13 ; H13.1 142.93,62.87 ; H13.1 136.67,69.13 ; H13.1 136.67,62.87 ; H4.1 67.13,202.25 ; H4.1 67.13,195.99 ; H4.1 60.87,202.25 ; H4.1 60.87,195.99 ; 2.87,15.87 H16.1 ; H16.1 9.13,22.13 ; H16.1 9.13,15.87 ; H16.1 2.87,22.13 ; H15.1 282.13,15.87 ; H15.1 275.87,22.13 ; H15.1 275.87,15.87 ; H15.1 282.13,22.13
  L14_INT_6 w0.508: 204.07,188.07 J3.A42 ; J3.A42 205.23,189.23 ; J3.A42 205.23,188.07 ; J3.A42 204.07,189.23 ; 199.57,210.23 J3.B21 ; J3.B21 200.73,210.23 ; J3.B21 199.57,209.07 ; J3.B21 200.73,209.07 ; 197.57,209.23 J3.B22 ; J3.B22 198.73,208.07 ; J3.B22 197.57,208.07 ; J3.B22 198.73,209.23 ; J3.B39 200.73,191.07 ; J3.B39 199.57,192.23 ; J3.B39 200.73,192.23 ; J3.B39 199.57,191.07 ; 10.52,7.22 SW6.4 ; SW6.4 10.52,5.23 ; SW6.4 12.5,5.23 ; SW6.4 12.5,7.22 ; J7.211 165.28,142.36 ; J7.211 165.28,143.63 ; J7.211 164.01,143.63 ; J7.211 164.01,142.36 ; 199.57,195.07 J3.B35 ; J3.B35 199.57,196.23 ; J3.B35 200.73,196.23 ; J3.B35 200.73,195.07 ; J7.101 161.48,132.36 ; J7.101 160.21,132.36 ; J7.101 161.48,133.63 ; J7.101 160.21,133.63 ; J3.A41 203.23,189.07 ; J3.A41 202.07,189.07 ; J3.A41 203.23,190.23 ; J3.A41 202.07,190.23 ; 202.07,215.07 J3.A15 ; J3.A15 203.23,216.23 ; J3.A15 202.07,216.23 ; J3.A15 203.23,215.07 ; J3.A28 205.23,202.07 ; J3.A28 204.07,202.07 ; J3.A28 205.23,203.23 ; J3.A28 204.07,203.23 ; 202.07,207.07 J3.A23 ; J3.A23 202.07,208.23 ; J3.A23 203.23,207.07 ; J3.A23 203.23,208.23 ; J9.7 5.12,118.02 ; J9.7 3.02,115.92 ; J9.7 5.12,115.92 ; J9.7 3.02,118.02 ; 202.07,231.07 J3.A1 ; J3.A1 203.23,232.23 ; J3.A1 203.23,231.07 ; J3.A1 202.07,232.23 ; C5345.2 265.35,75.05 ; C5345.2 263.43,75.05 ; C5345.2 263.43,76.97 ; C5345.2 265.35,76.97 ; 158.31,124.64 J7.110 ; J7.110 159.58,124.64 ; J7.110 158.31,123.37 ; J7.110 159.58,123.37 ; C5338.2 188.22,228.3 ; C5338.2 188.22,230.09 ; C5338.2 186.43,230.09 ; 239.1,204.72 J4.2 240.7,204.72 ; C5339.2 192.54,244.57 ; C5339.2 190.75,242.78 ; C5339.2 190.75,244.57 ; C5339.2 192.54,242.78 ; 204.07,184.07 J3.A46 ; J3.A46 205.23,185.23 ; J3.A46 205.23,184.07 ; J3.A46 204.07,185.23 ; 8.52,107.52 J9.17 ; J9.17 10.62,109.62 ; J9.17 10.62,107.52 ; J9.17 8.52,109.62 ; 162.11,140.63 J7.214 ; J7.214 163.38,140.63 ; J7.214 163.38,139.36 ; J7.214 162.11,139.36 ; C5337.2 208.79,242.78 ; C5337.2 207,242.78 ; C5337.2 208.79,244.57 ; C5337.2 207,244.57 ; 197.57,213.23 J3.B18 ; J3.B18 198.73,213.23 ; J3.B18 198.73,212.07 ; J3.B18 197.57,212.07 ; J7.116 159.58,117.37 ; J7.116 158.31,117.37 ; J7.116 158.31,118.64 ; J7.116 159.58,118.64 ; 162.11,151.36 J7.202 ; J7.202 162.11,152.63 ; J7.202 163.38,152.63 ; J7.202 163.38,151.36 ; FAN1.1 196.89,52.7 ; FAN1.1 196.89,51 ; FAN1.1 195.19,51 ; FAN1.1 195.19,52.7 ; 204.07,210.07 J3.A20 ; J3.A20 205.23,210.07 ; J3.A20 204.07,211.23 ; J3.A20 205.23,211.23 ; 240.58,210.95 J55.2 238.98,210.95 ; J7.229 165.28,125.64 ; J7.229 164.01,124.37 ; J7.229 164.01,125.64 ; J7.229 165.28,124.37 ; 160.21,144.36 J7.89 ; J7.89 160.21,145.63 ; J7.89 161.48,144.36 ; J7.89 161.48,145.63 ; J3.A31 203.23,199.07 ; J3.A31 202.07,200.23 ; J3.A31 203.23,200.23 ; J3.A31 202.07,199.07 ; 8.52,139.02 J9.24 ; J9.24 10.62,136.92 ; J9.24 8.52,136.92 ; J9.24 10.62,139.02 ; 164.01,118.37 J7.235 ; J7.235 164.01,119.64 ; J7.235 165.28,119.64 ; J7.235 165.28,118.37 ; J3.A34 205.23,197.23 ; J3.A34 204.07,196.07 ; J3.A34 205.23,196.07 ; J3.A34 204.07,197.23 ; J3.B26 198.73,204.07 ; J3.B26 197.57,205.23 ; J3.B26 197.57,204.07 ; J3.B26 198.73,205.23 ; J7.217 165.28,136.36 ; J7.217 165.28,137.63 ; J7.217 164.01,136.36 ; J7.217 164.01,137.63 ; 158.31,142.63 J7.92 ; J7.92 158.31,141.36 ; J7.92 159.58,141.36 ; J7.92 159.58,142.63 ; J7.86 159.58,147.36 ; J7.86 158.31,147.36 ; J7.86 159.58,148.63 ; J7.86 158.31,148.63 ; J7.205 165.28,149.63 ; J7.205 164.01,149.63 ; J7.205 165.28,148.36 ; J7.205 164.01,148.36 ; J3.B40 198.73,191.23 ; J3.B40 197.57,190.07 ; J3.B40 197.57,191.23 ; J3.B40 198.73,190.07 ; J3.A38 205.23,193.23 ; J3.A38 204.07,192.07 ; J3.A38 204.07,193.23 ; J3.A38 205.23,192.07 ; J3.B4 198.73,228.07 ; J3.B4 198.73,229.23 ; J3.B4 197.57,229.23 ; J3.B4 197.57,228.07 ; 202.07,186.23 J3.A45 ; J3.A45 203.23,186.23 ; J3.A45 203.23,185.07 ; J3.A45 202.07,185.07 ; 8.52,118.02 J9.19 ; J9.19 8.52,115.92 ; J9.19 10.62,118.02 ; J9.19 10.62,115.92 ; 197.57,199.23 J3.B32 ; J3.B32 198.73,198.07 ; J3.B32 198.73,199.23 ; J3.B32 197.57,198.07 ; J7.83 161.48,151.63 ; J7.83 161.48,150.36 ; J7.83 160.21,150.36 ; J7.83 160.21,151.63 ; 199.57,187.07 J3.B43 ; J3.B43 200.73,188.23 ; J3.B43 199.57,188.23 ; J3.B43 200.73,187.07 ; J7.208 163.38,145.36 ; J7.208 162.11,145.36 ; J7.208 162.11,146.63 ; J7.208 163.38,146.63 ; 204.07,207.23 J3.A24 ; J3.A24 205.23,206.07 ; J3.A24 204.07,206.07 ; J3.A24 205.23,207.23 ; J3.B44 198.73,186.07 ; J3.B44 197.57,187.23 ; J3.B44 197.57,186.07 ; J3.B44 198.73,187.23 ; J7.232 163.38,122.64 ; J7.232 162.11,121.37 ; J7.232 162.11,122.64 ; J7.232 163.38,121.37 ; 243.71,247.01 244.48,247.78 ; 243.71,247.01 244.48,246.25 ; 243.71,247.01 242.94,246.25 ; 243.71,247.01 242.94,247.78 ; 204.07,219.23 J3.A12 ; J3.A12 204.07,218.07 ; J3.A12 205.23,218.07 ; J3.A12 205.23,219.23 ; 202.07,204.23 J3.A27 ; J3.A27 203.23,204.23 ; J3.A27 202.07,203.07 ; J3.A27 203.23,203.07 ; J7.95 161.48,139.63 ; J7.95 160.21,138.36 ; J7.95 161.48,138.36 ; J7.95 160.21,139.63 ; J7.117 161.48,116.37 ; J7.117 160.21,116.37 ; J7.117 160.21,117.64 ; J7.117 161.48,117.64 ; 202.07,194.23 J3.A37 ; J3.A37 203.23,194.23 ; J3.A37 202.07,193.07 ; J3.A37 203.23,193.07 ; 8.52,111.72 J9.18 ; J9.18 10.62,111.72 ; J9.18 10.62,113.82 ; J9.18 8.52,113.82 ; J3.B47 200.73,183.07 ; J3.B47 199.57,184.23 ; J3.B47 199.57,183.07 ; J3.B47 200.73,184.23 ; J7.239 165.28,114.37 ; J7.239 165.28,115.64 ; J7.239 164.01,115.64 ; J7.239 164.01,114.37 ; J7.226 163.38,128.63 ; J7.226 163.38,127.36 ; J7.226 162.11,128.63 ; J7.226 162.11,127.36 ; J7.113 161.48,120.37 ; J7.113 161.48,121.64 ; J7.113 160.21,121.64 ; J7.113 160.21,120.37 ; 199.57,218.23 J3.B13 ; J3.B13 200.73,217.07 ; J3.B13 199.57,217.07 ; J3.B13 200.73,218.23 ; J3.B29 200.73,201.07 ; J3.B29 199.57,202.23 ; J3.B29 200.73,202.23 ; J3.B29 199.57,201.07 ; 199.57,205.07 J3.B25 ; J3.B25 200.73,205.07 ; J3.B25 199.57,206.23 ; J3.B25 200.73,206.23 ; J3.B49 200.73,182.23 ; J3.B49 199.57,182.23 ; J3.B49 199.57,181.07 ; 3.02,101.22 J9.3 ; J9.3 5.12,99.12 ; J9.3 3.02,99.12 ; J9.3 5.12,101.22 ; 204.07,212.07 J3.A18 ; J3.A18 205.23,212.07 ; J3.A18 204.07,213.23 ; J3.A18 205.23,213.23 ; 9.45,4.54 SW6.2 ; SW6.2 11.08,2.91 ; SW6.2 11.08,4.54 ; SW6.2 9.45,2.91 ; 199.57,226.23 J3.B7 ; J3.B7 200.73,225.07 ; J3.B7 199.57,225.07 ; J3.B7 200.73,226.23 ; 162.11,134.63 J7.220 ; J7.220 163.38,133.36 ; J7.220 163.38,134.63 ; J7.220 162.11,133.36 ; J2.16 239.4,246.25 ; J2.16 239.4,247.78 ; J2.16 237.86,246.25 ; J2.16 237.86,247.78 ; 197.57,215.23 J3.B16 ; J3.B16 198.73,214.07 ; J3.B16 197.57,214.07 ; J3.B16 198.73,215.23 ; J9.5 5.12,107.52 ; J9.5 5.12,109.62 ; J9.5 3.02,107.52 ; J9.5 3.02,109.62 ; 204.07,229.23 J3.A4 ; J3.A4 204.07,228.07 ; J3.A4 205.23,229.23 ; J3.A4 205.23,228.07 ; 160.21,126.36 J7.107 ; J7.107 161.48,126.36 ; J7.107 161.48,127.64 ; J7.107 160.21,127.64 ; J7.237 165.28,117.64 ; J7.237 165.28,116.37 ; J7.237 164.01,116.37 ; J7.237 164.01,117.64 ; J3.B36 198.73,194.07 ; J3.B36 198.73,195.23 ; J3.B36 197.57,195.23 ; J3.B36 197.57,194.07 ; 164.01,131.63 J7.223 ; J7.223 164.01,130.36 ; J7.223 165.28,131.63 ; J7.223 165.28,130.36 ; J9.15 10.62,101.22 ; J9.15 8.52,99.12 ; J9.15 10.62,99.12 ; J9.15 8.52,101.22 ; J3.A49 203.23,181.07 ; J3.A49 203.23,182.23 ; J3.A49 202.07,182.23 ; 158.31,130.63 J7.104 ; J7.104 159.58,130.63 ; J7.104 159.58,129.36 ; J7.104 158.31,129.36 ; 158.31,136.63 J7.98 ; J7.98 159.58,135.36 ; J7.98 159.58,136.63 ; J7.98 158.31,135.36 ; SW6.3 5.5,5.23 ; SW6.3 5.5,7.22 ; SW6.3 3.52,7.22 ; SW6.3 3.52,5.23
  L14_INT_6 w1.016: H8.1 282.19,130.93 ; H8.1 275.81,130.93 ; H8.1 275.81,124.56 ; H8.1 282.19,124.56 ; 223.81,243.81 H7.1 ; H7.1 230.18,243.81 ; H7.1 230.18,250.18 ; H7.1 223.81,250.18 ; H16.1 9.19,22.18 ; H16.1 2.81,15.81 ; H16.1 9.19,15.81 ; H16.1 2.81,22.18 ; 275.81,243.81 H3.1 ; H3.1 282.19,243.81 ; H3.1 275.81,250.18 ; H3.1 282.19,250.18
  L15_GND_6 w0.508: 9.04,248.53 FAN5.1 ; FAN5.1 10.64,250.12 ; FAN5.1 9.04,250.12 ; FAN5.1 10.64,248.53 ; J5.127 51.13,231.58 ; J5.127 49.97,230.42 ; J5.127 51.13,230.42 ; J5.127 49.97,231.58 ; J7.23 161.43,215.58 ; J7.23 160.27,215.58 ; J7.23 160.27,214.42 ; J7.23 161.43,214.42 ; J5.44 45.43,194.58 ; J5.44 44.27,193.42 ; J5.44 45.43,193.42 ; J5.44 44.27,194.58 ; 21.08,30.18 C5342.2 ; C5342.2 22.77,30.18 ; C5342.2 22.77,28.5 ; C5342.2 21.08,28.5 ; J6.95 153.83,211.42 ; J6.95 153.83,212.58 ; J6.95 152.67,211.42 ; J6.95 152.67,212.58 ; 237.92,247.73 J2.16 ; J2.16 239.35,247.73 ; J2.16 239.35,246.3 ; J2.16 237.92,246.3 ; 204.12,218.12 J3.A12 ; J3.A12 204.12,219.18 ; J3.A12 205.17,218.12 ; J3.A12 205.17,219.18 ; J7.127 165.23,230.42 ; J7.127 165.23,231.58 ; J7.127 164.07,231.58 ; J7.127 164.07,230.42 ; 162.17,203.42 J7.154 ; J7.154 163.33,204.58 ; J7.154 162.17,204.58 ; J7.154 163.33,203.42 ; J7.2 159.53,236.58 ; J7.2 158.37,236.58 ; J7.2 158.37,235.42 ; J7.2 159.53,235.42 ; J5.133 51.13,225.58 ; J5.133 49.97,225.58 ; J5.133 51.13,224.42 ; J5.133 49.97,224.42 ; 20.16,248.53 FAN12.1 ; FAN12.1 21.75,250.12 ; FAN12.1 20.16,250.12 ; FAN12.1 21.75,248.53 ; 10.57,7.16 SW6.4 ; SW6.4 12.45,5.28 ; SW6.4 12.45,7.16 ; SW6.4 10.57,5.28 ; 48.07,145.42 J5.208 ; J5.208 49.23,146.58 ; J5.208 49.23,145.42 ; J5.208 48.07,146.58 ; J3.B43 200.67,188.18 ; J3.B43 199.62,187.12 ; J3.B43 200.67,187.12 ; J3.B43 199.62,188.18 ; 44.27,148.58 J5.86 ; J5.86 45.43,148.58 ; J5.86 44.27,147.42 ; J5.86 45.43,147.42 ; J6.89 153.83,206.58 ; J6.89 153.83,205.42 ; J6.89 152.67,205.42 ; J6.89 152.67,206.58 ; 48.07,134.58 J5.220 ; J5.220 49.23,134.58 ; J5.220 48.07,133.42 ; J5.220 49.23,133.42 ; 154.57,202.42 J6.86 ; J6.86 155.73,203.58 ; J6.86 154.57,203.58 ; J6.86 155.73,202.42 ; J3.B26 198.67,205.18 ; J3.B26 197.62,204.12 ; J3.B26 198.67,204.12 ; J3.B26 197.62,205.18 ; J6.226 151.93,223.58 ; J6.226 150.77,222.42 ; J6.226 151.93,222.42 ; J6.226 150.77,223.58 ; J5.17 47.33,220.42 ; J5.17 47.33,221.58 ; J5.17 46.17,221.58 ; J5.17 46.17,220.42 ; J5.89 47.33,145.58 ; J5.89 47.33,144.42 ; J5.89 46.17,144.42 ; J5.89 46.17,145.58 ; 148.87,126.58 J6.133 ; J6.133 148.87,125.42 ; J6.133 150.03,125.42 ; J6.133 150.03,126.58 ; 49.97,148.42 J5.205 ; J5.205 51.13,149.58 ; J5.205 49.97,149.58 ; J5.205 51.13,148.42 ; 114.7,14.79 J11.1 ; J11.1 116.02,14.79 ; J11.1 114.7,13.46 ; J11.1 116.02,13.46 ; FAN2.1 144.56,248.53 ; FAN2.1 142.97,248.53 ; FAN2.1 144.56,250.12 ; FAN2.1 142.97,250.12 ; J6.139 150.03,131.42 ; J6.139 150.03,132.58 ; J6.139 148.87,132.58 ; J6.139 148.87,131.42 ; 44.27,142.58 J5.92 ; J5.92 45.43,141.42 ; J5.92 45.43,142.58 ; J5.92 44.27,141.42 ; FAN1.1 196.84,52.65 ; FAN1.1 195.24,52.65 ; FAN1.1 195.24,51.05 ; FAN1.1 196.84,51.05 ; 49.97,119.58 J5.235 ; J5.235 49.97,118.42 ; J5.235 51.13,118.42 ; J5.235 51.13,119.58 ; 44.27,136.58 J5.98 ; J5.98 45.43,135.42 ; J5.98 45.43,136.58 ; J5.98 44.27,135.42 ; J7.202 163.33,151.42 ; J7.202 163.33,152.58 ; J7.202 162.17,151.42 ; J7.202 162.17,152.58 ; J5.136 49.23,221.42 ; J5.136 49.23,222.58 ; J5.136 48.07,221.42 ; J5.136 48.07,222.58 ; 46.17,151.58 J5.83 ; J5.83 47.33,151.58 ; J5.83 47.33,150.42 ; J5.83 46.17,150.42 ; J3.B16 198.67,215.18 ; J3.B16 197.62,215.18 ; J3.B16 198.67,214.12 ; J3.B16 197.62,214.12 ; 158.37,129.42 J7.104 ; J7.104 159.53,129.42 ; J7.104 159.53,130.58 ; J7.104 158.37,130.58 ; 162.17,128.58 J7.226 ; J7.226 163.33,128.58 ; J7.226 163.33,127.42 ; J7.226 162.17,127.42 ; SW6.3 5.45,7.16 ; SW6.3 3.57,5.28 ; SW6.3 3.57,7.16 ; SW6.3 5.45,5.28 ; 204.12,184.12 J3.A46 ; J3.A46 204.12,185.18 ; J3.A46 205.17,184.12 ; J3.A46 205.17,185.18 ; J7.199 165.23,154.42 ; J7.199 164.07,154.42 ; J7.199 165.23,155.58 ; J7.199 164.07,155.58 ; J7.32 159.53,206.58 ; J7.32 159.53,205.42 ; J7.32 158.37,205.42 ; J7.32 158.37,206.58 ; 150.77,146.42 J6.154 ; J6.154 150.77,147.58 ; J6.154 151.93,146.42 ; J6.154 151.93,147.58 ; 164.07,213.58 J7.145 ; J7.145 164.07,212.42 ; J7.145 165.23,213.58 ; J7.145 165.23,212.42 ; 191.9,23.88 J14.20 ; J14.20 191.9,25.2 ; J14.20 193.22,25.2 ; 148.87,226.58 J6.229 ; J6.229 150.03,226.58 ; J6.229 148.87,225.42 ; J6.229 150.03,225.42 ; J5.20 45.43,217.42 ; J5.20 44.27,218.58 ; J5.20 44.27,217.42 ; J5.20 45.43,218.58 ; 158.37,118.58 J7.116 ; J7.116 159.53,118.58 ; J7.116 158.37,117.42 ; J7.116 159.53,117.42 ; J7.208 163.33,145.42 ; J7.208 162.17,145.42 ; J7.208 163.33,146.58 ; J7.208 162.17,146.58 ; J106.10 127.2,245.97 ; J106.10 127.2,247.22 ; J106.10 125.95,247.22 ; J106.10 125.95,245.97 ; J5.232 49.23,122.58 ; J5.232 49.23,121.42 ; J5.232 48.07,121.42 ; J5.232 48.07,122.58 ; 199.62,182.18 J3.B49 ; J3.B49 200.67,182.18 ; J3.B49 199.62,181.12 ; 150.77,140.42 J6.148 ; J6.148 151.93,140.42 ; J6.148 151.93,141.58 ; J6.148 150.77,141.58 ; 150.77,204.42 J6.208 ; J6.208 151.93,205.58 ; J6.208 151.93,204.42 ; J6.208 150.77,205.58 ; 148.87,156.58 J6.163 ; J6.163 150.03,156.58 ; J6.163 148.87,155.42 ; J6.163 150.03,155.42 ; J6.110 155.73,227.58 ; J6.110 154.57,227.58 ; J6.110 155.73,226.42 ; J6.110 154.57,226.42 ; C5345.2 265.29,75.11 ; C5345.2 265.29,76.91 ; C5345.2 263.48,75.11 ; C5345.2 263.48,76.91 ; 8.58,107.58 J9.17 ; J9.17 10.57,107.58 ; J9.17 10.57,109.56 ; J9.17 8.58,109.56 ; 48.07,210.58 J5.148 ; J5.148 49.23,210.58 ; J5.148 49.23,209.42 ; J5.148 48.07,209.42 ; J7.229 165.23,125.58 ; J7.229 165.23,124.42 ; J7.229 164.07,124.42 ; J7.229 164.07,125.58 ; 44.27,229.42 J5.8 ; J5.8 44.27,230.58 ; J5.8 45.43,230.58 ; J5.8 45.43,229.42 ; J8.1 4.97,162.89 ; J8.1 3.18,161.1 ; J8.1 3.18,162.89 ; J8.1 4.97,161.1 ; J6.11 153.83,123.42 ; J6.11 152.67,124.58 ; J6.11 153.83,124.58 ; J6.11 152.67,123.42 ; 42.82,12.55 CN4.A4 42.82,13.9 ; 148.87,236.58 J6.239 ; J6.239 150.03,235.42 ; J6.239 148.87,235.42 ; J6.239 150.03,236.58 ; 154.57,139.58 J6.26 ; J6.26 155.73,138.42 ; J6.26 154.57,138.42 ; J6.26 155.73,139.58 ; J5.160 49.23,198.58 ; J5.160 49.23,197.42 ; J5.160 48.07,198.58 ; J5.160 48.07,197.42 ; 152.67,223.42 J6.107 ; J6.107 153.83,223.42 ; J6.107 153.83,224.58 ; J6.107 152.67,224.58 ; J3.B18 198.67,212.12 ; J3.B18 197.62,212.12 ; J3.B18 198.67,213.18 ; J3.B18 197.62,213.18 ; 164.07,218.42 J7.139 ; J7.139 165.23,219.58 ; J7.139 165.23,218.42 ; J7.139 164.07,219.58 ; J7.101 161.43,132.42 ; J7.101 161.43,133.58 ; J7.101 160.27,133.58 ; J7.101 160.27,132.42 ; J7.205 165.23,148.42 ; J7.205 164.07,148.42 ; J7.205 165.23,149.58 ; J7.205 164.07,149.58 ; 19.55,132.41 CT28.2 ; CT28.2 21.23,132.41 ; CT28.2 19.55,130.73 ; CT28.2 21.23,130.73 ; 150.77,228.42 J6.232 ; J6.232 150.77,229.58 ; J6.232 151.93,228.42 ; J6.232 151.93,229.58 ; 49.97,130.42 J5.223 ; J5.223 51.13,130.42 ; J5.223 51.13,131.58 ; J5.223 49.97,131.58 ; 148.87,220.58 J6.223 ; J6.223 150.03,219.42 ; J6.223 150.03,220.58 ; J6.223 148.87,219.42 ; J6.23 153.83,136.58 ; J6.23 152.67,135.42 ; J6.23 153.83,135.42 ; J6.23 152.67,136.58 ; 21.8,56.57 J10.M1 ; J10.M1 21.8,54.6 ; J10.M1 23.77,54.6 ; J10.M1 23.77,56.57 ; 49.97,194.42 J5.163 ; J5.163 51.13,195.58 ; J5.163 51.13,194.42 ; J5.163 49.97,195.58 ; 150.77,134.42 J6.142 ; J6.142 151.93,135.58 ; J6.142 151.93,134.42 ; J6.142 150.77,135.58 ; J3.B29 200.67,202.18 ; J3.B29 199.62,201.12 ; J3.B29 199.62,202.18 ; J3.B29 200.67,201.12 ; 148.87,196.58 J6.199 ; J6.199 148.87,195.42 ; J6.199 150.03,196.58 ; J6.199 150.03,195.42 ; 162.17,215.42 J7.142 ; J7.142 163.33,216.58 ; J7.142 162.17,216.58 ; J7.142 163.33,215.42 ; 150.77,117.58 J6.124 ; J6.124 150.77,116.42 ; J6.124 151.93,117.58 ; J6.124 151.93,116.42 ; 158.37,211.42 J7.26 ; J7.26 159.53,211.42 ; J7.26 159.53,212.58 ; J7.26 158.37,212.58 ; J3.A45 203.17,186.18 ; J3.A45 202.12,186.18 ; J3.A45 202.12,185.12 ; J3.A45 203.17,185.12 ; J5.151 51.13,207.58 ; J5.151 49.97,206.42 ; J5.151 49.97,207.58 ; J5.151 51.13,206.42 ; J5.41 47.33,196.42 ; J5.41 47.33,197.58 ; J5.41 46.17,197.58 ; J5.41 46.17,196.42 ; J7.107 161.43,127.58 ; J7.107 161.43,126.42 ; J7.107 160.27,127.58 ; J7.107 160.27,126.42 ; 202.12,208.18 J3.A23 ; J3.A23 203.17,208.18 ; J3.A23 203.17,207.12 ; J3.A23 202.12,207.12 ; J7.151 165.23,206.42 ; J7.151 165.23,207.58 ; J7.151 164.07,206.42 ; J7.151 164.07,207.58 ; 160.27,121.58 J7.113 ; J7.113 161.43,121.58 ; J7.113 161.43,120.42 ; J7.113 160.27,120.42 ; 164.07,131.58 J7.223 ; J7.223 164.07,130.42 ; J7.223 165.23,130.42 ; J7.223 165.23,131.58 ; 46.17,138.42 J5.95 ; J5.95 47.33,138.42 ; J5.95 46.17,139.58 ; J5.95 47.33,139.58 ; J6.5 153.83,118.58 ; J6.5 152.67,118.58 ; J6.5 152.67,117.42 ; J6.5 153.83,117.42 ; 152.67,153.42 J6.41 ; J6.41 153.83,154.58 ; J6.41 153.83,153.42 ; J6.41 152.67,154.58 ; J3.A34 205.17,197.18 ; J3.A34 205.17,196.12 ; J3.A34 204.12,197.18 ; J3.A34 204.12,196.12 ; 186.48,228.35 C5338.2 ; C5338.2 186.48,230.04 ; C5338.2 188.17,228.35 ; C5338.2 188.17,230.04 ; J7.5 161.43,233.58 ; J7.5 161.43,232.42 ; J7.5 160.27,232.42 ; J7.5 160.27,233.58 ; J6.121 150.03,114.58 ; J6.121 150.03,113.42 ; J6.121 148.87,113.42 ; J6.121 148.87,114.58 ; J5.139 51.13,218.42 ; J5.139 49.97,219.58 ; J5.139 49.97,218.42 ; J5.139 51.13,219.58 ; J3.B44 198.67,186.12 ; J3.B44 197.62,187.18 ; J3.B44 197.62,186.12 ; J3.B44 198.67,187.18 ; 207.06,244.51 C5337.2 ; C5337.2 208.74,242.83 ; C5337.2 208.74,244.51 ; C5337.2 207.06,242.83 ; 197.62,194.12 J3.B36 ; J3.B36 197.62,195.18 ; J3.B36 198.67,194.12 ; J3.B36 198.67,195.18 ; J6.117 153.83,234.58 ; J6.117 152.67,233.42 ; J6.117 153.83,233.42 ; J6.117 152.67,234.58 ; J5.110 45.43,124.58 ; J5.110 45.43,123.42 ; J5.110 44.27,124.58 ; J5.110 44.27,123.42 ; 42.82,9.93 CN4.B4 42.82,11.28 ; J5.239 51.13,114.42 ; J5.239 49.97,115.58 ; J5.239 49.97,114.42 ; J5.239 51.13,115.58 ; J7.235 165.23,119.58 ; J7.235 164.07,118.42 ; J7.235 165.23,118.42 ; J7.235 164.07,119.58 ; 180.01,14.79 J14.1 ; J14.1 181.33,13.46 ; J14.1 181.33,14.79 ; J14.1 180.01,13.46 ; SW6.2 11.02,4.48 ; SW6.2 9.5,4.48 ; SW6.2 9.5,2.96 ; SW6.2 11.02,2.96 ; J6.8 155.73,120.42 ; J6.8 155.73,121.58 ; J6.8 154.57,120.42 ; J6.8 154.57,121.58 ; 162.17,234.58 J7.124 ; J7.124 162.17,233.42 ; J7.124 163.33,233.42 ; J7.124 163.33,234.58 ; 150.77,153.58 J6.160 ; J6.160 151.93,153.58 ; J6.160 150.77,152.42 ; J6.160 151.93,152.42 ; J3.B13 200.67,217.12 ; J3.B13 199.62,217.12 ; J3.B13 200.67,218.18 ; J3.B13 199.62,218.18 ; 152.67,236.58 J6.119 ; J6.119 153.83,235.42 ; J6.119 152.67,235.42 ; J6.119 153.83,236.58 ; 3.18,165.29 J8.2 ; J8.2 3.18,167.08 ; J8.2 4.97,165.29 ; J8.2 4.97,167.08 ; J6.104 155.73,220.42 ; J6.104 154.57,221.58 ; J6.104 154.57,220.42 ; J6.104 155.73,221.58 ; J5.35 47.33,203.58 ; J5.35 46.17,202.42 ; J5.35 46.17,203.58 ; J5.35 47.33,202.42 ; J7.47 161.43,191.58 ; J7.47 161.43,190.42 ; J7.47 160.27,191.58 ; J7.47 160.27,190.42 ; 46.75,80.64 JP7.2 45.3,80.64 ; J3.B47 200.67,184.18 ; J3.B47 200.67,183.12 ; J3.B47 199.62,184.18 ; J3.B47 199.62,183.12 ; 49.97,212.42 J5.145 ; J5.145 51.13,213.58 ; J5.145 49.97,213.58 ; J5.145 51.13,212.42 ; J5.226 49.23,128.58 ; J5.226 48.07,128.58 ; J5.226 49.23,127.42 ; J5.226 48.07,127.42 ; 158.24,13.46 J13.1 ; J13.1 159.56,13.46 ; J13.1 159.56,14.79 ; J13.1 158.24,14.79 ; J5.23 47.33,214.42 ; J5.23 46.17,214.42 ; J5.23 46.17,215.58 ; J5.23 47.33,215.58 ; 190.8,242.83 C5339.2 ; C5339.2 190.8,244.51 ; C5339.2 192.48,244.51 ; C5339.2 192.48,242.83 ; J5.5 47.33,232.42 ; J5.5 46.17,233.58 ; J5.5 46.17,232.42 ; J5.5 47.33,233.58 ; 49.97,155.58 J5.199 ; J5.199 51.13,155.58 ; J5.199 49.97,154.42 ; J5.199 51.13,154.42 ; 150.77,122.42 J6.130 ; J6.130 151.93,122.42 ; J6.130 151.93,123.58 ; J6.130 150.77,123.58 ; 158.37,193.42 J7.44 ; J7.44 159.53,194.58 ; J7.44 158.37,194.58 ; J7.44 159.53,193.42 ; 162.17,139.42 J7.214 ; J7.214 162.17,140.58 ; J7.214 163.33,139.42 ; J7.214 163.33,140.58 ; 197.62,209.18 J3.B22 ; J3.B22 197.62,208.12 ; J3.B22 198.67,208.12 ; J3.B22 198.67,209.18 ; J7.239 165.23,115.58 ; J7.239 165.23,114.42 ; J7.239 164.07,114.42 ; J7.239 164.07,115.58 ; J6.98 155.73,214.42 ; J6.98 154.57,214.42 ; J6.98 154.57,215.58 ; J6.98 155.73,215.58 ; 44.27,236.58 J5.2 ; J5.2 45.43,235.42 ; J5.2 45.43,236.58 ; J5.2 44.27,235.42 ; J7.89 161.43,144.42 ; J7.89 160.27,144.42 ; J7.89 161.43,145.58 ; J7.89 160.27,145.58 ; C5279.2 88.34,246.15 ; C5279.2 88.34,247.83 ; C5279.2 86.66,247.83 ; C5279.2 86.66,246.15 ; 44.27,200.58 J5.38 ; J5.38 45.43,199.42 ; J5.38 45.43,200.58 ; J5.38 44.27,199.42 ; J5.124 49.23,234.58 ; J5.124 48.07,233.42 ; J5.124 49.23,233.42 ; J5.124 48.07,234.58 ; 202.12,232.18 J3.A1 ; J3.A1 203.17,231.12 ; J3.A1 202.12,231.12 ; J3.A1 203.17,232.18 ; J6.113 153.83,229.42 ; J6.113 152.67,229.42 ; J6.113 152.67,230.58 ; J6.113 153.83,230.58 ; J9.5 5.07,109.56 ; J9.5 5.07,107.58 ; J9.5 3.08,107.58 ; J9.5 3.08,109.56 ; 199.62,196.18 J3.B35 ; J3.B35 199.62,195.12 ; J3.B35 200.67,195.12 ; J3.B35 200.67,196.18 ; J7.20 159.53,217.42 ; J7.20 158.37,217.42 ; J7.20 158.37,218.58 ; J7.20 159.53,218.58 ; J7.163 165.23,195.58 ; J7.163 165.23,194.42 ; J7.163 164.07,195.58 ; J7.163 164.07,194.42 ; J6.101 153.83,217.42 ; J6.101 153.83,218.58 ; J6.101 152.67,218.58 ; J6.101 152.67,217.42 ; 160.27,138.42 J7.95 ; J7.95 161.43,139.58 ; J7.95 161.43,138.42 ; J7.95 160.27,139.58 ; J7.110 159.53,124.58 ; J7.110 159.53,123.42 ; J7.110 158.37,124.58 ; J7.110 158.37,123.42 ; 158.37,229.42 J7.8 ; J7.8 159.53,229.42 ; J7.8 158.37,230.58 ; J7.8 159.53,230.58 ; 158.37,136.58 J7.98 ; J7.98 158.37,135.42 ; J7.98 159.53,135.42 ; J7.98 159.53,136.58 ; 46.17,133.58 J5.101 ; J5.101 46.17,132.42 ; J5.101 47.33,132.42 ; J5.101 47.33,133.58 ; 204.12,192.12 J3.A38 ; J3.A38 204.12,193.18 ; J3.A38 205.17,192.12 ; J3.A38 205.17,193.18 ; J7.160 163.33,197.42 ; J7.160 162.17,198.58 ; J7.160 163.33,198.58 ; J7.160 162.17,197.42 ; 48.07,139.42 J5.214 ; J5.214 48.07,140.58 ; J5.214 49.23,140.58 ; J5.214 49.23,139.42 ; J5.32 45.43,205.42 ; J5.32 45.43,206.58 ; J5.32 44.27,205.42 ; J5.32 44.27,206.58 ; J6.116 155.73,232.42 ; J6.116 155.73,233.58 ; J6.116 154.57,232.42 ; J6.116 154.57,233.58 ; J7.232 163.33,121.42 ; J7.232 163.33,122.58 ; J7.232 162.17,122.58 ; J7.232 162.17,121.42 ; 202.12,190.18 J3.A41 ; J3.A41 203.17,189.12 ; J3.A41 203.17,190.18 ; J3.A41 202.12,189.12 ; J6.20 155.73,133.58 ; J6.20 154.57,133.58 ; J6.20 155.73,132.42 ; J6.20 154.57,132.42 ; J6.145 150.03,137.42 ; J6.145 148.87,137.42 ; J6.145 148.87,138.58 ; J6.145 150.03,138.58 ; J7.117 161.43,116.42 ; J7.117 161.43,117.58 ; J7.117 160.27,116.42 ; J7.117 160.27,117.58 ; 73.12,246.15 C5289.2 ; C5289.2 73.12,247.83 ; C5289.2 74.81,246.15 ; C5289.2 74.81,247.83 ; J6.217 150.03,213.42 ; J6.217 150.03,214.58 ; J6.217 148.87,214.58 ; J6.217 148.87,213.42 ; 3.18,173.68 J8.4 ; J8.4 3.18,175.47 ; J8.4 4.97,173.68 ; J8.4 4.97,175.47 ; J6.83 153.83,200.58 ; J6.83 152.67,200.58 ; J6.83 152.67,199.42 ; J6.83 153.83,199.42 ; J7.237 165.23,116.42 ; J7.237 165.23,117.58 ; J7.237 164.07,117.58 ; J7.237 164.07,116.42 ; J106.3 129.2,239.97 ; J106.3 129.2,241.22 ; J106.3 127.95,241.22 ; J106.3 127.95,239.97 ; 21.43,118.92 CT31.2 ; CT31.2 23.11,118.92 ; CT31.2 23.11,120.6 ; CT31.2 21.43,120.6 ; J7.83 161.43,150.42 ; J7.83 161.43,151.58 ; J7.83 160.27,150.42 ; J7.83 160.27,151.58 ; J13.20 171.45,23.88 ; J13.20 170.13,23.88 ; J13.20 171.45,25.2 ; J13.20 170.13,25.2 ; J5.142 49.23,216.58 ; J5.142 48.07,216.58 ; J5.142 49.23,215.42 ; J5.142 48.07,215.42 ; 240.63,204.72 J4.2 239.18,204.72 ; 48.07,204.58 J5.154 ; J5.154 48.07,203.42 ; J5.154 49.23,204.58 ; J5.154 49.23,203.42 ; 154.57,127.58 J6.14 ; J6.14 154.57,126.42 ; J6.14 155.73,126.42 ; J6.14 155.73,127.58 ; 148.36,23.88 J12.20 ; J12.20 149.68,23.88 ; J12.20 148.36,25.2 ; J12.20 149.68,25.2 ; 8.58,138.96 J9.24 ; J9.24 10.57,138.96 ; J9.24 8.58,136.98 ; J9.24 10.57,136.98 ; 46.17,126.42 J5.107 ; J5.107 47.33,127.58 ; J5.107 46.17,127.58 ; J5.107 47.33,126.42 ; 3.18,171.27 J8.3 ; J8.3 4.97,169.48 ; J8.3 4.97,171.27 ; J8.3 3.18,169.48 ; J6.166 151.93,158.42 ; J6.166 150.77,159.58 ; J6.166 151.93,159.58 ; J6.166 150.77,158.42 ; J3.A24 205.17,206.12 ; J3.A24 205.17,207.18 ; J3.A24 204.12,207.18 ; J3.A24 204.12,206.12 ; SW5.1 18.6,16.45 ; SW5.1 18.6,18.15 ; SW5.1 16.9,18.15 ; SW5.1 16.9,16.45 ; J6.35 153.83,148.58 ; J6.35 152.67,147.42 ; J6.35 153.83,147.42 ; J6.35 152.67,148.58 ; 49.97,142.42 J5.211 ; J5.211 51.13,143.58 ; J5.211 51.13,142.42 ; J5.211 49.97,143.58 ; J7.86 159.53,148.58 ; J7.86 158.37,147.42 ; J7.86 159.53,147.42 ; J7.86 158.37,148.58 ; 158.37,199.42 J7.38 ; J7.38 159.53,199.42 ; J7.38 159.53,200.58 ; J7.38 158.37,200.58 ; J9.18 10.57,111.77 ; J9.18 8.58,113.76 ; J9.18 8.58,111.77 ; J9.18 10.57,113.76 ; J6.205 150.03,201.42 ; J6.205 148.87,202.58 ; J6.205 148.87,201.42 ; J6.205 150.03,202.58 ; 202.12,203.12 J3.A27 ; J3.A27 202.12,204.18 ; J3.A27 203.17,204.18 ; J3.A27 203.17,203.12 ; 49.97,237.58 J5.121 ; J5.121 51.13,237.58 ; J5.121 51.13,236.42 ; J5.121 49.97,236.42 ; 160.27,220.42 J7.17 ; J7.17 160.27,221.58 ; J7.17 161.43,220.42 ; J7.17 161.43,221.58 ; J5.166 49.23,192.58 ; J5.166 48.07,191.42 ; J5.166 49.23,191.42 ; J5.166 48.07,192.58 ; 154.57,151.58 J6.38 ; J6.38 155.73,151.58 ; J6.38 154.57,150.42 ; J6.38 155.73,150.42 ; 136.47,14.79 J12.1 ; J12.1 137.79,13.46 ; J12.1 136.47,13.46 ; J12.1 137.79,14.79 ; 158.37,154.58 J7.80 ; J7.80 159.53,154.58 ; J7.80 159.53,153.42 ; J7.80 158.37,153.42 ; J6.202 151.93,198.42 ; J6.202 151.93,199.58 ; J6.202 150.77,198.42 ; J6.202 150.77,199.58 ; J7.92 159.53,142.58 ; J7.92 158.37,142.58 ; J7.92 158.37,141.42 ; J7.92 159.53,141.42 ; 160.27,226.42 J7.11 ; J7.11 160.27,227.58 ; J7.11 161.43,227.58 ; J7.11 161.43,226.42 ; 49.97,137.58 J5.217 ; J5.217 51.13,137.58 ; J5.217 51.13,136.42 ; J5.217 49.97,136.42 ; J6.2 155.73,114.42 ; J6.2 155.73,115.58 ; J6.2 154.57,114.42 ; J6.2 154.57,115.58 ; 150.77,216.42 J6.220 ; J6.220 151.93,217.58 ; J6.220 150.77,217.58 ; J6.220 151.93,216.42 ; 164.07,143.58 J7.211 ; J7.211 165.23,142.42 ; J7.211 165.23,143.58 ; J7.211 164.07,142.42 ; J6.80 155.73,196.42 ; J6.80 154.57,197.58 ; J6.80 155.73,197.58 ; J6.80 154.57,196.42 ; J11.20 127.91,25.2 ; J11.20 126.59,23.88 ; J11.20 126.59,25.2 ; J11.20 127.91,23.88 ; 21.07,93.81 CT35.2 ; CT35.2 22.76,92.12 ; CT35.2 21.07,92.12 ; CT35.2 22.76,93.81 ; 162.17,227.42 J7.130 ; J7.130 162.17,228.58 ; J7.130 163.33,228.58 ; J7.130 163.33,227.42 ; J3.B32 198.67,199.18 ; J3.B32 197.62,198.12 ; J3.B32 197.62,199.18 ; J3.B32 198.67,198.12 ; J3.A15 203.17,215.12 ; J3.A15 203.17,216.18 ; J3.A15 202.12,215.12 ; J3.A15 202.12,216.18 ; 199.62,191.12 J3.B39 ; J3.B39 199.62,192.18 ; J3.B39 200.67,192.18 ; J3.B39 200.67,191.12 ; 44.27,223.42 J5.14 ; J5.14 44.27,224.58 ; J5.14 45.43,223.42 ; J5.14 45.43,224.58 ; 164.07,236.42 J7.121 ; J7.121 165.23,237.58 ; J7.121 164.07,237.58 ; J7.121 165.23,236.42 ; 158.37,223.42 J7.14 ; J7.14 159.53,223.42 ; J7.14 158.37,224.58 ; J7.14 159.53,224.58 ; J5.26 45.43,212.58 ; J5.26 45.43,211.42 ; J5.26 44.27,211.42 ; J5.26 44.27,212.58 ; J7.133 165.23,224.42 ; J7.133 164.07,225.58 ; J7.133 165.23,225.58 ; J7.133 164.07,224.42 ; J7.136 163.33,221.42 ; J7.136 163.33,222.58 ; J7.136 162.17,221.42 ; J7.136 162.17,222.58 ; C5341.2 41.02,28.5 ; C5341.2 39.34,30.18 ; C5341.2 39.34,28.5 ; C5341.2 41.02,30.18 ; 202.12,182.18 J3.A49 ; J3.A49 203.17,181.12 ; J3.A49 203.17,182.18 ; 49.97,124.42 J5.229 ; J5.229 51.13,124.42 ; J5.229 51.13,125.58 ; J5.229 49.97,125.58 ; J5.113 47.33,121.58 ; J5.113 47.33,120.42 ; J5.113 46.17,121.58 ; J5.113 46.17,120.42 ; J9.3 5.07,99.18 ; J9.3 3.08,101.16 ; J9.3 5.07,101.16 ; J9.3 3.08,99.18 ; J5.117 47.33,116.42 ; J5.117 47.33,117.58 ; J5.117 46.17,116.42 ; J5.117 46.17,117.58 ; J3.B25 200.67,206.18 ; J3.B25 199.62,206.18 ; J3.B25 200.67,205.12 ; J3.B25 199.62,205.12 ; J3.B40 198.67,191.18 ; J3.B40 197.62,191.18 ; J3.B40 197.62,190.12 ; J3.B40 198.67,190.12 ; 204.12,213.18 J3.A18 ; J3.A18 205.17,212.12 ; J3.A18 204.12,212.12 ; J3.A18 205.17,213.18 ; J6.29 153.83,141.42 ; J6.29 152.67,141.42 ; J6.29 152.67,142.58 ; J6.29 153.83,142.58 ; 160.27,197.58 J7.41 ; J7.41 161.43,197.58 ; J7.41 160.27,196.42 ; J7.41 161.43,196.42 ; 62.85,248.53 FAN4.1 ; FAN4.1 62.85,250.12 ; FAN4.1 64.44,248.53 ; FAN4.1 64.44,250.12 ; 8.58,101.16 J9.15 ; J9.15 10.57,101.16 ; J9.15 10.57,99.18 ; J9.15 8.58,99.18 ; J6.17 153.83,129.42 ; J6.17 152.67,129.42 ; J6.17 152.67,130.58 ; J6.17 153.83,130.58 ; 199.62,225.12 J3.B7 ; J3.B7 200.67,225.12 ; J3.B7 200.67,226.18 ; J3.B7 199.62,226.18 ; J3.A31 203.17,199.12 ; J3.A31 203.17,200.18 ; J3.A31 202.12,199.12 ; J3.A31 202.12,200.18 ; J3.B4 198.67,228.12 ; J3.B4 198.67,229.18 ; J3.B4 197.62,228.12 ; J3.B4 197.62,229.18 ; J6.127 150.03,120.58 ; J6.127 148.87,119.42 ; J6.127 150.03,119.42 ; J6.127 148.87,120.58 ; J5.47 47.33,190.42 ; J5.47 46.17,190.42 ; J5.47 47.33,191.58 ; J5.47 46.17,191.58 ; J9.19 10.57,115.98 ; J9.19 10.57,117.96 ; J9.19 8.58,115.98 ; J9.19 8.58,117.96 ; J6.47 153.83,159.42 ; J6.47 152.67,160.58 ; J6.47 152.67,159.42 ; J6.47 153.83,160.58 ; 204.12,229.18 J3.A4 ; J3.A4 204.12,228.12 ; J3.A4 205.17,228.12 ; J3.A4 205.17,229.18 ; J5.80 45.43,154.58 ; J5.80 44.27,154.58 ; J5.80 44.27,153.42 ; J5.80 45.43,153.42 ; 48.07,228.58 J5.130 ; J5.130 48.07,227.42 ; J5.130 49.23,228.58 ; J5.130 49.23,227.42 ; 148.87,144.58 J6.151 ; J6.151 150.03,144.58 ; J6.151 148.87,143.42 ; J6.151 150.03,143.42 ; 164.07,201.58 J7.157 ; J7.157 164.07,200.42 ; J7.157 165.23,200.42 ; J7.157 165.23,201.58 ; 115.85,246.15 C5283.2 ; C5283.2 117.53,246.15 ; C5283.2 117.53,247.83 ; C5283.2 115.85,247.83 ; J7.220 163.33,133.42 ; J7.220 163.33,134.58 ; J7.220 162.17,134.58 ; J7.220 162.17,133.42 ; 19.97,144.4 C5340.2 ; C5340.2 19.97,146.08 ; C5340.2 21.65,144.4 ; C5340.2 21.65,146.08 ; J3.A42 205.17,188.12 ; J3.A42 204.12,189.18 ; J3.A42 205.17,189.18 ; J3.A42 204.12,188.12 ; 199.62,209.12 J3.B21 ; J3.B21 200.67,210.18 ; J3.B21 200.67,209.12 ; J3.B21 199.62,210.18 ; 154.57,209.58 J6.92 ; J6.92 155.73,209.58 ; J6.92 154.57,208.42 ; J6.92 155.73,208.42 ; 150.77,210.42 J6.214 ; J6.214 151.93,211.58 ; J6.214 150.77,211.58 ; J6.214 151.93,210.42 ; 150.77,129.58 J6.136 ; J6.136 151.93,128.42 ; J6.136 151.93,129.58 ; J6.136 150.77,128.42 ; 243,246.3 243.71,247.01 ; 243.71,247.01 244.43,247.73 ; 243.71,247.01 244.43,246.3 ; 243.71,247.01 243,247.73 ; J5.11 47.33,226.42 ; J5.11 47.33,227.58 ; J5.11 46.17,226.42 ; J5.11 46.17,227.58 ; 46.17,209.58 J5.29 ; J5.29 47.33,209.58 ; J5.29 46.17,208.42 ; J5.29 47.33,208.42 ; J6.32 155.73,144.42 ; J6.32 154.57,144.42 ; J6.32 155.73,145.58 ; J6.32 154.57,145.58 ; J6.211 150.03,208.58 ; J6.211 150.03,207.42 ; J6.211 148.87,207.42 ; J6.211 148.87,208.58 ; J3.A20 205.17,211.18 ; J3.A20 204.12,210.12 ; J3.A20 204.12,211.18 ; J3.A20 205.17,210.12 ; 49.97,200.42 J5.157 ; J5.157 51.13,201.58 ; J5.157 49.97,201.58 ; J5.157 51.13,200.42 ; 162.17,192.58 J7.166 ; J7.166 162.17,191.42 ; J7.166 163.33,191.42 ; J7.166 163.33,192.58 ; 40.94,248.53 FAN3.1 ; FAN3.1 42.53,248.53 ; FAN3.1 40.94,250.12 ; FAN3.1 42.53,250.12 ; 48.07,151.42 J5.202 ; J5.202 48.07,152.58 ; J5.202 49.23,151.42 ; J5.202 49.23,152.58 ; J6.157 150.03,150.58 ; J6.157 150.03,149.42 ; J6.157 148.87,150.58 ; J6.157 148.87,149.42 ; J6.235 150.03,231.42 ; J6.235 148.87,232.58 ; J6.235 148.87,231.42 ; J6.235 150.03,232.58 ; 3.08,115.98 J9.7 ; J9.7 3.08,117.96 ; J9.7 5.07,115.98 ; J9.7 5.07,117.96 ; J69.5 48.19,63.26 ; J69.5 48.19,64.8 ; J69.5 46.65,64.8 ; J69.5 46.65,63.26 ; 202.12,193.12 J3.A37 ; J3.A37 203.17,194.18 ; J3.A37 202.12,194.18 ; J3.A37 203.17,193.12 ; 160.27,208.42 J7.29 ; J7.29 161.43,209.58 ; J7.29 160.27,209.58 ; J7.29 161.43,208.42 ; J10.M2 22.77,41.77 ; J10.M2 22.77,43.74 ; J10.M2 20.8,41.77 ; J10.M2 20.8,43.74 ; 44.27,130.58 J5.104 ; J5.104 45.43,130.58 ; J5.104 44.27,129.42 ; J5.104 45.43,129.42 ; 160.27,202.42 J7.35 ; J7.35 161.43,203.58 ; J7.35 160.27,203.58 ; J7.35 161.43,202.42 ; 154.57,157.58 J6.44 ; J6.44 154.57,156.42 ; J6.44 155.73,156.42 ; J6.44 155.73,157.58 ; 164.07,137.58 J7.217 ; J7.217 165.23,137.58 ; J7.217 165.23,136.42 ; J7.217 164.07,136.42 ; J7.148 163.33,210.58 ; J7.148 163.33,209.42 ; J7.148 162.17,210.58 ; J7.148 162.17,209.42 ; 204.12,203.18 J3.A28 ; J3.A28 204.12,202.12 ; J3.A28 205.17,203.18 ; J3.A28 205.17,202.12 ; 44.27,118.58 J5.116 ; J5.116 45.43,118.58 ; J5.116 44.27,117.42 ; J5.116 45.43,117.42 ; 240.5,210.95 J55.2 239.05,210.95
  L15_GND_6 w0.914: 113.7,209.45 BH10.1 ; BH10.1 113.7,213.18 ; BH10.1 117.43,213.18 ; BH10.1 117.43,209.45
  L15_GND_6 w1.016: 2.87,22.13 H16.1 ; H16.1 2.87,15.87 ; H16.1 9.13,22.13 ; H16.1 9.13,15.87 ; 60.87,123.99 H10.1 ; H10.1 67.13,130.25 ; H10.1 67.13,123.99 ; H10.1 60.87,130.25 ; 132.87,195.99 H5.1 ; H5.1 139.13,195.99 ; H5.1 132.87,202.25 ; H5.1 139.13,202.25 ; H3.1 282.13,243.87 ; H3.1 282.13,250.13 ; H3.1 275.87,250.13 ; H3.1 275.87,243.87 ; H14.1 72.93,48.13 ; H14.1 72.93,41.87 ; H14.1 66.67,48.13 ; H14.1 66.67,41.87 ; H11.1 139.13,123.99 ; H11.1 132.87,130.25 ; H11.1 132.87,123.99 ; H11.1 139.13,130.25 ; 66.67,93.87 H12.1 ; H12.1 72.93,100.13 ; H12.1 72.93,93.87 ; H12.1 66.67,100.13 ; 223.87,243.87 H7.1 ; H7.1 223.87,250.13 ; H7.1 230.13,243.87 ; H7.1 230.13,250.13 ; 60.87,202.25 H4.1 ; H4.1 67.13,195.99 ; H4.1 60.87,195.99 ; H4.1 67.13,202.25 ; 24.87,243.87 H1.1 ; H1.1 31.13,250.13 ; H1.1 24.87,250.13 ; H1.1 31.13,243.87 ; H13.1 142.93,69.13 ; H13.1 136.67,69.13 ; H13.1 142.93,62.87 ; H13.1 136.67,62.87 ; H9.1 9.13,146.97 ; H9.1 2.87,146.97 ; H9.1 2.87,153.23 ; H9.1 9.13,153.23 ; H8.1 282.13,130.88 ; H8.1 275.87,124.62 ; H8.1 275.87,130.88 ; H8.1 282.13,124.62 ; H2.1 178.73,250.13 ; H2.1 178.73,243.87 ; H2.1 172.47,243.87 ; H2.1 172.47,250.13 ; H15.1 282.13,22.13 ; H15.1 275.87,22.13 ; H15.1 282.13,15.87 ; H15.1 275.87,15.87 ; 172.5,178.1 H6.1 ; H6.1 178.69,171.9 ; H6.1 172.5,171.9 ; H6.1 178.69,178.1
  BOTTOM w0.254: R5880.1 104.83,143.7 v3(105.33,143.2) 105.82,142.7 R5879.1 106.32,142.2 v3(106.33,142.2) ; 109.83,143.69 v3(109.33,143.2) ; 109.83,143.69 v3(109.33,144.2) ; 109.83,143.69 R5876.1 ; R663.2 39.37,42.8 v2(39.12,42.55) ; R739.2 110.33,149.22 v3(110.33,149.2) ; R659.2 29.34,42.8 v2(29.08,42.55) ; R751.2 R753.2 111.33,142.2 v3(111.33,142.2) ; v3(109.33,145.2) 109.35,145.2 109.86,144.69 ; v3(106.33,141.2) 105.83,141.69 R5878.1 ; v3(112.33,148.2) 111.85,148.68 R742.2
  BOTTOM w0.305: v1(65.47,76) 64.78,75.31 C3710.2 ; v3(95.33,153.2) 95.33,153.17 R731.2 ; v3(97.33,173.19) 96.83,172.69 R701.2 ; C3717.2 58.27,71.2 v1(58.27,70.4) ; C5213.2 v2(136.8,46.88) ; C5201.2 v2(178.96,46.88) ; C5253.2 177.79,56.83 v2(177.79,56.23) ; C5176.2 135.63,56.83 v2(135.63,56.23) ; v3(99.33,173.19) 99.35,173.19 R700.2 ; R730.2 96.33,153.17 v3(96.33,153.2) ; C3722.2 57.49,72.78 v1(56.67,73.6) ; 41.53,168.95 C666.2
  BOTTOM w0.381: C699.2 v3(98.33,163.2) ; v2(63.15,82.46) 63.15,82.46 63.07,82.38 63.07,81.48 C3836.2 ; v1(66.27,78.4) 66.27,77.62 C3840.2 ; C3838.2 62.26,68.15 v2(62.33,68.07) ; R5887.1 92.84,182.69 v3(93.33,182.19) ; C614.2 71.89,174.88 v2(71.89,174.24) ; v1(55.07,68.8) 55.26,68.99 C3839.2 ; C5224.2 129.29,54.4 ; C3721.2 63.9,68.83 63.1,68.83 v1(63.07,68.8) ; C5232.2 124.63,54.43 ; v3(93.33,177.19) 93.81,176.71 C601.2 ; v3(88.33,183.19) 87.82,182.68 C580.2 ; v2(134.48,51.58) 134.5,51.61 C5216.2 ; C603.2 91.85,176.71 v3(92.33,177.19) 92.81,176.71 C602.2 ; C3730.2 64.5,73.78 v1(64.67,73.6) ; v1(60.67,69.6) 60.57,69.5 C3843.2 ; C1002.2 v2(245.49,209.8) ; C433.2 v2(95.76,83.03) ; C3711.2 55.96,76.8 v1(55.07,76.8) ; v5(77.55,229.92) 78.39,229.92 C97.2 ; v1(63.87,71.2) C3723.2 ; R5793.1 118.11,47.52 120.4,47.52 ; C5199.2 v2(163.07,53.67) ; v3(113.33,146.2) 112.85,146.68 R746.2 ; R741.2 v3(91.33,148.2) ; v2(54.42,74.89) 54.74,75.21 C3703.2 ; C924.2 168.3,54.43 ; R5881.1 104.82,144.7 v3(104.33,145.2) ; v2(179.07,46.1) 179.64,46.1 R5805.2 ; C3858.2 v2(130.58,92.99) ; v3(89.33,154.2) 89.79,154.65 C834.2 ; v2(120.93,53.64) 120.93,53.64 C5215.2 ; v3(90.33,180.19) 90.82,180.68 R5885.1 ; R5875.2 112.65,138.18 v2(112.13,137.67) ; C3702.2 v2(55.87,82.11) ; R5884.1 90.82,181.68 v3(90.33,181.19) ; C113.2 v2(245.62,203.58) ; v2(139.34,51.92) 139.34,51.38 139.14,51.18 138.43,51.18 ; C5191.2 164.3,54.43 ; C5234.2 131.64,54.36 ; v3(103.33,174.2) C613.2 ; v2(169.8,53.72) 169.79,53.73 C5200.2 ; C3720.2 v2(67.7,68.06) ; C5238.2 130.43,54.43 ; R5751.2 137.48,46.1 v2(136.91,46.1) ; v2(71.25,174.24) 71.25,173.99 71.63,173.61 C624.2 ; R5888.1 90.84,183.81 90.46,184.19 v3(90.33,184.19) ; v2(127.64,53.72) 127.63,53.73 C5217.2 ; C3718.2 56.94,73.87 v1(56.67,73.6) ; C3701.2 v2(54.34,81.46) ; C5185.2 172.59,54.43 ; C5240.2 122.13,54.43 ; v2(53.92,76.3) 53.61,75.99 C3831.2 ; v3(85.33,183.19) 84.84,182.7 C581.2 ; C347.2 v2(102.77,83.89) ; C5198.2 176.67,51.61 v2(176.64,51.58) ; v3(97.33,162.2) C724.2 ; C5226.2 126.13,54.43 ; R5813.2 v2(103.87,226.57) ; C5187.2 173.81,54.36 ; v1(67.07,72.8) 66.28,72.8 C3719.2 ; C3713.2 v1(58.27,78.4) ; C3712.2 57.47,76 v1(57.47,76) ; R5886.1 92.84,183.81 92.46,184.19 v3(92.33,184.19) ; C3716.2 54.75,73.55 v2(54.41,73.89) ; C840.2 90.79,152.65 v3(90.33,152.2) ; C859.2 v3(90.33,149.2) ; R5889.1 90.84,182.69 v3(91.33,182.19) ; C961.2 171.45,54.4 ; v2(57.58,81.58) 57.11,81.58 56.77,81.24 56.77,80.7 C3837.2 ; C3747.2 v2(248.66,158.59) ; R5891.2 104.7,152.68 104.33,153.08 v3(104.33,153.2) ; C5171.2 v2(95.66,84.75) ; C5188.2 166.79,54.43
  BOTTOM w0.406: 168.3,54.43 v2(168.3,53.72) ; C5194.2 v2(165.3,45.59) ; C950.2 v2(176.66,50.15) ; C5235.2 v2(134.13,45.59) ; C5181.2 v2(172.3,45.59) ; 173.81,54.36 v2(173.81,53.66) ; C944.2 v2(177.55,54.15) ; 164.3,54.43 v2(164.3,53.72) ; C940.2 v2(162.56,53.16) ; C5214.2 v2(120.4,48.91) ; C5195.2 v2(176.3,45.59) ; v2(120.4,51.16) C5219.2 ; R5791.1 v2(120.61,50.11) ; C5189.2 v2(173.79,45.59) ; v2(176.3,53.73) C5196.2 ; 166.79,54.43 v2(166.79,53.72) ; C5223.2 v2(134.37,52.7) ; v2(161.57,44.55) 161.26,44.55 C5183.2 ; C5221.2 v2(118.95,55.37) ; C5178.2 v2(162.61,52.07) ; C5218.2 v2(120.44,52.07) ; 130.43,54.43 v2(130.43,53.72) ; C5186.2 v2(177.99,44.89) ; C947.2 v2(176.53,52.7) ; C5182.2 v2(166.79,45.59) ; C5180.2 v2(179.96,42.4) ; C5236.2 v2(128.63,45.59) ; R5792.1 v2(162.77,50.11) ; C5225.2 v2(135.38,54.15) ; C5192.2 v2(168.3,45.59) ; C5193.2 v2(163.28,45.38) ; C5227.2 v2(124.63,45.59) ; 122.13,54.43 v2(122.13,53.72) ; C5190.2 v2(170.79,45.59) ; C5242.2 v2(126.13,45.59) ; C5230.2 v2(137.79,42.4) ; C5241.2 v2(131.63,45.59) ; v2(162.56,51.16) C932.2 ; 171.45,54.4 v2(171.45,53.7) ; C5220.2 v2(120.4,53.16) ; C5231.2 v2(135.82,44.89) ; C5179.2 v2(162.56,48.91) ; v2(134.13,53.73) C5233.2 ; C5222.2 v2(134.49,50.15) ; C5229.2 v2(130.13,45.59) ; 126.13,54.43 v2(126.13,53.72) ; C936.2 v2(161.11,55.37) ; 124.63,54.43 v2(124.63,53.72) ; C5228.2 119.02,44.63 v2(119.35,44.63) ; 131.64,54.36 v2(131.64,53.66) ; C5237.2 v2(123.13,45.59) ; 172.59,54.43 v2(172.59,53.72) ; 129.29,54.4 v2(129.29,53.7) ; C5239.2 v2(121.12,45.38)
  BOTTOM w0.457: v3(105.33,157.2) C698.2 v3(104.33,158.2) ; v3(91.33,157.2) C796.2 ; v3(103.33,170.2) C642.2 ; v2(60.96,173.1) 60.96,172.85 61.29,172.52 61.29,172.54 61.59,172.85 v2(61.59,173.1) ; C594.2 v3(80.33,177.19) ; v3(106.33,162.2) C658.2 ; C754.1 v2(55.73,160.02) ; C790.2 v3(103.33,157.2) C808.2 ; v2(69.37,183.51) C573.2 v2(68.47,183.88) ; v3(120.33,143.2) C872.2 ; C674.2 v3(97.33,167.19) ; C732.2 v3(101.33,161.2) C747.2 ; v3(90.33,157.2) C788.2 v3(91.33,158.2) ; C755.2 v3(109.33,159.2) ; C680.2 v3(109.33,167.2) ; C644.2 v3(99.33,171.19) ; C688.2 v3(93.33,167.19) ; C645.2 v3(96.33,171.19) ; C712.2 v3(101.33,168.2) ; C870.2 v3(120.33,144.19) ; C627.2 v2(71.25,172.72) ; C726.2 v3(95.33,165.19) C736.2 ; C583.2 v3(81.33,183.19) ; C686.2 v3(103.33,161.2) ; C578.2 v3(115.33,183.2) ; C695.2 v3(107.33,161.2) ; C636.2 v3(98.33,171.19) ; C679.2 v3(111.33,168.2) ; v3(96.33,155.2) C818.2 v3(97.33,155.2) ; C727.2 v3(91.33,162.2) ; C730.2 v3(105.33,161.2) ; v3(102.33,177.2) 101.86,176.72 C593.2 ; C649.2 v3(102.33,169.2) C804.2 ; C677.2 v3(90.33,168.19) ; v3(109.33,168.2) C657.2 ; v3(89.33,156.2) R715.2 ; v3(106.33,174.2) C610.2 ; v3(95.33,155.2) C824.2 ; C667.2 v2(55.63,168.02) ; C707.2 v3(93.33,162.2) ; C716.2 71.89,163.09 v2(71.93,163.04) ; C800.2 v3(109.33,157.2) ; v3(95.33,158.2) C794.2 ; C706.2 v3(99.33,165.19) ; C795.2 v3(93.33,165.19) ; C662.2 v3(99.33,169.19) C650.2 ; v3(84.33,156.2) C821.2 v3(85.33,156.2) ; C780.2 v3(111.33,159.2) ; C741.2 v3(110.33,161.2) ; C731.2 v3(102.33,162.2) ; C791.2 v3(101.33,157.2) ; C634.2 v3(80.33,171.19) ; C774.2 v3(102.33,158.2) ; C647.2 v3(107.33,170.2) ; C852.2 104.91,149.61 v3(105.33,149.2) 105.75,149.61 C851.2 ; C711.2 v3(106.33,169.2) ; v3(109.33,169.2) C646.2 ; v3(104.33,155.2) C807.2 ; C702.2 v3(91.33,166.19) C689.2 ; v3(101.33,171.2) 100.82,171.7 C632.2 ; C587.2 v3(119.33,180.2) ; C710.2 127.2,164.19 127.38,164.36 v2(127.38,164.97) ; C600.2 v3(94.33,176.19) ; C709.2 71.88,164.59 v2(71.25,165.23) 71.88,165.86 C691.2 ; C751.2 v3(104.33,165.2) C744.2 ; C762.2 v3(96.33,159.2) ; C720.2 v3(105.33,163.19) ; C866.2 v3(92.33,149.2) ; v3(107.33,153.2) C828.2 ; C770.1 v2(55.63,159.38) ; C837.2 v3(94.33,152.2) ; C700.2 v3(94.33,163.2) ; v3(89.33,177.19) 89.79,176.74 C605.2 ; v3(94.33,166.19) C687.2 ; C863.2 v3(94.33,149.2) ; C723.2 v3(97.33,165.19) C778.2 ; C745.2 v3(103.33,166.2) ; v3(106.33,167.2) C669.2 ; C701.2 v3(93.33,158.2) C987.2 ; R714.2 93.84,156.71 v3(94.33,157.2) ; v3(104.33,162.2) 104.33,162.23 C721.2 103.37,163.19 v3(103.33,163.19) ; v3(97.33,171.19) 96.83,171.7 C633.2 ; C847.2 90.88,150.75 v3(91.33,151.2) 90.84,151.69 R736.2 ; C759.2 v3(101.33,159.2) ; v3(102.33,160.2) C758.2 ; v3(119.33,153.2) C836.2 ; C715.2 v3(91.33,163.2) C714.2 ; v3(91.33,176.19) 91.33,176.25 C604.2 ; C665.2 v3(90.33,169.19) ; C703.2 v3(90.33,166.19) ; C819.2 v3(91.33,155.2) C833.2 ; C661.2 v3(94.33,161.2) ; C629.2 v3(110.33,171.2) ; C781.2 v3(110.33,159.2) ; C694.2 v3(106.33,165.2) C763.2 ; C718.2 v3(109.33,163.19) ; C697.2 100.85,162.71 v3(101.33,163.19) ; C673.2 v3(99.33,167.19) C685.2 ; C622.2 v3(119.33,173.2) ; v3(99.33,155.2) C812.2 ; C869.2 v3(120.33,147.2) ; C865.2 v3(92.33,148.2) ; v3(105.33,170.2) C648.2 ; C854.2 v3(103.33,149.2) ; C719.2 v3(107.33,163.19) ; C670.2 v3(105.33,168.2) ; v3(94.33,153.2) C831.2 ; v3(109.33,156.2) C803.2 ; v3(111.33,169.2) C656.2 ; R718.2 v3(91.33,156.2) ; C612.2 v3(105.33,174.2) ; C3700.2 13.5,72.62 v2(14.06,72.62) ; C773.2 v3(103.33,159.2) ; v3(87.33,143.2) 87.76,142.77 C871.1 ; C729.2 v3(107.33,168.2) ; C862.2 v3(96.33,148.2) ; v2(76.96,164.85) 76.96,163.83 C728.2 75.95,163.83 v2(75.95,164.85) ; v3(96.33,161.2) C749.2 ; C771.2 v3(101.33,166.2) ; C793.2 v3(96.33,157.2) C802.2 ; v3(92.33,151.2) 91.82,150.69 C844.2 ; v3(107.33,174.2) C609.2 ; C725.2 v3(96.33,163.2) ; C626.2 v3(102.33,173.2) ; C651.2 v3(97.33,169.19) ; C598.2 96.85,176.71 v3(97.33,177.19) 97.81,176.71 C597.2 ; v3(109.33,160.2) C743.2 ; C737.2 v3(91.33,161.2) ; v3(95.33,169.19) C652.2 ; C653.2 v3(80.33,169.19) ; C753.2 v3(81.33,160.2) ; C742.2 v3(81.33,161.2) ; v3(107.33,157.2) C805.2 v3(106.33,156.2) C806.2 ; C664.2 v3(96.33,168.19) ; v3(81.33,165.19) 80.35,165.19 C705.2 ; C777.2 v3(94.33,159.2) ; C764.2 v3(91.33,159.2) C779.2 ; C735.2 v3(95.33,162.2) ; v2(91.95,195.45) 92.58,195.45 C564.2 ; C829.2 v3(107.33,154.2) ; C750.2 v3(95.33,160.2) ; R5584.2 13.68,69.89 v2(13.95,70.16) ; v3(93.33,160.2) C659.2 ; v3(91.33,146.2) 91.82,145.7 R747.2 ; C858.2 v3(96.33,149.2) ; C637.2 v3(118.33,170.2) ; C873.2 v3(119.33,143.2) ; C789.2 v3(98.33,166.19) ; C856.2 v3(101.33,149.2) C855.2 ; v3(104.33,160.2) C683.2 ; v3(98.33,159.2) C760.2 ; C631.2 v3(103.33,172.2) ; v3(108.33,174.2) C608.2 ; C776.2 v3(97.33,158.2) ; v3(95.33,177.19) 95.81,176.71 C599.2 ; C585.2 v3(80.33,181.19) ; v3(101.33,174.2) C620.2 ; C857.2 v3(120.33,150.2) ; C575.2 v3(111.33,183.2) ; C765.2 v3(80.33,160.2) ; C654.2 v3(93.33,169.19) C655.2 ; C786.2 v3(109.33,158.2) ; C577.2 v3(119.33,183.2) ; C625.2 v3(94.33,173.19) ; C848.2 v3(109.33,150.2) ; v3(120.33,158.2) 120.27,158.26 C766.2 ; C690.2 v3(119.33,167.2) ; C722.2 v3(102.33,165.2) C713.2 ; C579.2 v3(109.33,183.2) ; R5585.2 v2(1.36,77.51) ; C811.2 v3(101.33,155.2) C810.2 v3(102.33,155.2) C809.2 ; C606.2 v3(103.33,176.2) ; C835.2 v3(101.33,153.2) C830.2 ; C590.2 v3(81.34,178.19) ; C611.2 v3(105.33,175.2) ; v3(106.33,160.2) C672.2 ; C640.2 v3(108.33,171.2) ; C746.2 v3(96.33,166.19) ; C663.2 v3(98.33,168.19) ; C752.2 v3(91.33,160.2) ; C668.2 v3(110.33,168.2) ; R5890.2 v3(105.33,153.2) ; C704.2 v3(89.33,166.19) ; v3(90.33,175.19) 89.85,174.72 C621.2 ; C660.2 v3(104.33,169.2) ; C832.2 v3(92.33,153.2) ; v3(98.33,155.2) C813.2 ; C692.2 v3(119.33,166.2) ; C696.2 v3(105.33,159.2) C757.2 ; v3(120.33,155.2) C817.2 ; C775.2 v3(99.33,158.2) ; C748.2 v3(99.33,160.2) ; C576.2 v3(110.33,183.2) ; C684.2 v3(107.33,159.2) ; v2(96.14,195.32) C562.2 ; v3(95.33,167.19) C675.2 ; v3(111.33,170.2) C638.2 ; v3(80.33,173.19) C623.2 ; C756.2 v3(102.33,167.2) ; C582.2 v3(83.33,183.19) ; v3(107.33,166.2) C681.2 ; C596.2 98.85,176.71 v3(99.33,177.19) 99.81,176.71 C595.2 ; C635.2 v2(55.63,171.7) ; C678.2 v3(80.33,168.19) ; v3(109.33,170.2) C639.2 ; C3699.2 v2(1.31,69.89) ; C630.2 v3(106.33,171.2) ; C849.2 v3(108.33,151.2) ; v3(96.33,151.2) C846.2 ; v2(90.68,195.45) 90.68,195.44 C565.2 ; C801.2 v3(98.33,157.2) C792.2 ; C733.2 v3(99.33,162.2) ; C850.2 v3(107.33,149.2) ; C827.2 v3(108.33,154.2) ; C861.2 v3(98.33,148.2) ; v3(105.33,166.2) C682.2 ; C734.2 v3(98.33,161.2) ; C671.2 v3(103.33,168.2) ; C641.2 v3(104.33,171.2) ; v3(109.33,174.2) C607.2 ; C823.2 v3(120.33,154.2) ; C772.2 v3(104.33,167.2) ; C864.2 v3(94.33,148.2) ; v3(106.33,158.2) C787.2 ; C574.2 v3(112.33,183.2) ; C693.2 v3(109.33,166.2) ; C676.2 v3(94.33,168.19) ; v2(94.74,195.32) C563.2 ; C825.2 v3(94.33,154.2) ; C708.2 v3(91.33,165.19) ; C591.2 v3(119.33,177.2) ; C838.2 v3(93.33,153.2) ; C853.2 v3(104.33,151.2) ; C761.2 v3(97.33,160.2) ; C643.2 v3(102.33,171.2)
  BOTTOM w0.508: J69.5 48.25,63.21 ; J69.5 48.25,64.86 ; J69.5 46.6,63.21 ; J69.5 46.6,64.86 ; J9.7 5.12,115.92 ; J9.7 3.02,118.02 ; J9.7 5.12,118.02 ; J9.7 3.02,115.92 ; J3.B49 200.73,182.23 ; J3.B49 199.57,181.07 ; J3.B49 199.57,182.23 ; J5.38 45.48,200.63 ; J5.38 45.48,199.36 ; J5.38 44.21,200.63 ; J5.38 44.21,199.36 ; v7(76.28,229.97) 76.4,229.84 R50.2 ; J3.A4 205.23,229.23 ; J3.A4 204.07,229.23 ; J3.A4 205.23,228.07 ; J3.A4 204.07,228.07 ; 62.51,250.46 FAN4.1 ; FAN4.1 62.51,248.2 ; FAN4.1 64.77,248.2 ; FAN4.1 64.77,250.46 ; 20.74,41.71 J10.M2 ; J10.M2 22.82,43.79 ; J10.M2 20.74,43.79 ; J10.M2 22.82,41.71 ; R945.1 v2(244.2,35.05) ; 16.54,18.51 SW5.1 ; SW5.1 16.54,16.09 ; SW5.1 18.96,18.51 ; SW5.1 18.96,16.09 ; 197.57,208.07 J3.B22 ; J3.B22 198.73,208.07 ; J3.B22 197.57,209.23 ; J3.B22 198.73,209.23 ; 202.07,186.23 J3.A45 ; J3.A45 203.23,185.07 ; J3.A45 202.07,185.07 ; J3.A45 203.23,186.23 ; J3.B25 200.73,206.23 ; J3.B25 200.73,205.07 ; J3.B25 199.57,205.07 ; J3.B25 199.57,206.23 ; 49.91,213.63 J5.145 ; J5.145 49.91,212.36 ; J5.145 51.18,212.36 ; J5.145 51.18,213.63 ; 199.57,217.07 J3.B13 ; J3.B13 199.57,218.23 ; J3.B13 200.73,217.07 ; J3.B13 200.73,218.23 ; J3.A12 205.23,218.07 ; J3.A12 205.23,219.23 ; J3.A12 204.07,218.07 ; J3.A12 204.07,219.23 ; 204.07,197.23 J3.A34 ; J3.A34 204.07,196.07 ; J3.A34 205.23,196.07 ; J3.A34 205.23,197.23 ; J3.B40 198.73,190.07 ; J3.B40 197.57,191.23 ; J3.B40 197.57,190.07 ; J3.B40 198.73,191.23 ; 199.57,202.23 J3.B29 ; J3.B29 199.57,201.07 ; J3.B29 200.73,202.23 ; J3.B29 200.73,201.07 ; 202.07,200.23 J3.A31 ; J3.A31 202.07,199.07 ; J3.A31 203.23,200.23 ; J3.A31 203.23,199.07 ; 197.57,212.07 J3.B18 ; J3.B18 198.73,213.23 ; J3.B18 197.57,213.23 ; J3.B18 198.73,212.07 ; 49.91,195.63 J5.163 ; J5.163 51.18,195.63 ; J5.163 49.91,194.36 ; J5.163 51.18,194.36 ; J5.136 49.28,221.36 ; J5.136 49.28,222.63 ; J5.136 48.01,221.36 ; J5.136 48.01,222.63 ; J2.16 239.4,247.78 ; J2.16 239.4,246.25 ; J2.16 237.86,246.25 ; J2.16 237.86,247.78 ; J9.15 10.62,99.12 ; J9.15 8.52,99.12 ; J9.15 10.62,101.22 ; J9.15 8.52,101.22 ; J5.157 51.18,200.36 ; J5.157 49.91,201.63 ; J5.157 49.91,200.36 ; J5.157 51.18,201.63 ; C5141.1 180.41,190.94 v6(180.09,191.27) ; 44.21,230.63 J5.8 ; J5.8 45.48,230.63 ; J5.8 45.48,229.36 ; J5.8 44.21,229.36 ; J5.151 51.18,207.63 ; J5.151 49.91,206.36 ; J5.151 51.18,206.36 ; J5.151 49.91,207.63 ; 39.28,30.23 C5341.2 ; C5341.2 41.07,28.44 ; C5341.2 41.07,30.23 ; C5341.2 39.28,28.44 ; J8.4 5.02,175.52 ; J8.4 5.02,173.62 ; J8.4 3.12,175.52 ; J8.4 3.12,173.62 ; J3.B7 200.73,226.23 ; J3.B7 200.73,225.07 ; J3.B7 199.57,225.07 ; J3.B7 199.57,226.23 ; 48.01,192.63 J5.166 49.28,192.63 ; J3.A20 205.23,210.07 ; J3.A20 205.23,211.23 ; J3.A20 204.07,210.07 ; J3.A20 204.07,211.23 ; SW6.3 5.5,5.23 ; SW6.3 5.5,7.22 ; SW6.3 3.52,5.23 ; SW6.3 3.52,7.22 ; R78.2 94.49,229.48 v7(94.36,229.6) ; J8.2 5.02,165.24 ; J8.2 3.12,165.24 ; J8.2 5.02,167.14 ; J8.2 3.12,167.14 ; J5.35 47.38,202.36 ; J5.35 46.11,203.63 ; J5.35 46.11,202.36 ; J5.35 47.38,203.63 ; v2(56.26,164.59) 56.26,164.19 56.58,163.87 56.58,163.79 ; J3.A46 205.23,185.23 ; J3.A46 204.07,185.23 ; J3.A46 204.07,184.07 ; J3.A46 205.23,184.07 ; J9.24 10.62,136.92 ; J9.24 8.52,139.02 ; J9.24 8.52,136.92 ; J9.24 10.62,139.02 ; C628.2 61.29,172.52 ; J3.B43 200.73,188.23 ; J3.B43 200.73,187.07 ; J3.B43 199.57,188.23 ; J3.B43 199.57,187.07 ; v2(107.92,193.52) 107.92,192.61 C566.2 107.2,192.88 v2(107.2,193.45) ; 48.01,204.63 J5.154 ; J5.154 49.28,203.36 ; J5.154 48.01,203.36 ; J5.154 49.28,204.63 ; v5(124.28,82.45) 124.41,82.32 C3859.2 124.41,79.91 C3862.2 v2(124.79,78.65) ; 197.57,195.23 J3.B36 ; J3.B36 198.73,195.23 ; J3.B36 198.73,194.07 ; J3.B36 197.57,194.07 ; J9.17 10.62,109.62 ; J9.17 10.62,107.52 ; J9.17 8.52,109.62 ; J9.17 8.52,107.52 ; J5.130 49.28,227.36 ; J5.130 48.01,228.63 ; J5.130 49.28,228.63 ; J5.130 48.01,227.36 ; J3.B35 200.73,196.23 ; J3.B35 199.57,196.23 ; J3.B35 199.57,195.07 ; J3.B35 200.73,195.07 ; J3.A1 203.4,232.4 ; J3.A1 203.4,230.9 ; J3.A1 201.9,232.4 ; J3.A1 201.9,230.9 ; J3.B4 198.73,229.23 ; J3.B4 198.73,228.07 ; J3.B4 197.57,228.07 ; J3.B4 197.57,229.23 ; J9.19 10.62,118.02 ; J9.19 8.52,118.02 ; J9.19 10.62,115.92 ; J9.19 8.52,115.92 ; FAN12.1 22.09,250.46 ; FAN12.1 19.83,250.46 ; FAN12.1 19.83,248.2 ; FAN12.1 22.09,248.2 ; 44.21,205.36 J5.32 ; J5.32 44.21,206.63 ; J5.32 45.48,205.36 ; J5.32 45.48,206.63 ; 44.21,194.63 J5.44 ; J5.44 45.48,193.36 ; J5.44 45.48,194.63 ; J5.44 44.21,193.36 ; 44.21,223.36 J5.14 ; J5.14 44.21,224.63 ; J5.14 45.48,224.63 ; J5.14 45.48,223.36 ; v2(85.42,215.26) 85.55,215.4 C94.2 ; J3.A18 205.23,213.23 ; J3.A18 204.07,213.23 ; J3.A18 204.07,212.07 ; J3.A18 205.23,212.07 ; R5882.1 v2(106.62,137.92) ; 48.01,209.36 J5.148 ; J5.148 49.28,210.63 ; J5.148 49.28,209.36 ; J5.148 48.01,210.63 ; C144.2 v2(247.48,209.84) ; 180.67,51.18 180.67,51.26 181.48,52.07 v2(181.71,52.07) ; J5.124 49.28,234.63 ; J5.124 48.01,233.36 ; J5.124 48.01,234.63 ; J5.124 49.28,233.36 ; C875.2 v3(115.33,143.2) ; C27.2 v2(41.71,239.75) ; J3.A28 205.23,202.07 ; J3.A28 204.07,203.23 ; J3.A28 205.23,203.23 ; J3.A28 204.07,202.07 ; C876.2 v3(114.33,143.2) ; 186.43,230.09 C5338.2 ; C5338.2 188.22,228.3 ; C5338.2 188.22,230.09 ; C5338.2 186.43,228.3 ; v2(100,189.29) 100,189.29 100.93,189.29 C569.2 101.12,188.59 v2(100,188.59) ; J9.3 5.12,99.12 ; J9.3 3.02,99.12 ; J9.3 3.02,101.22 ; J9.3 5.12,101.22 ; C5260.2 v2(83.39,228.74) ; J3.A27 203.23,204.23 ; J3.A27 202.07,203.07 ; J3.A27 203.23,203.07 ; J3.A27 202.07,204.23 ; C5342.2 22.82,30.23 ; C5342.2 21.03,30.23 ; C5342.2 21.03,28.44 ; C5342.2 22.82,28.44 ; R939.1 v2(226.9,35.05) ; 44.21,218.63 J5.20 ; J5.20 45.48,218.63 ; J5.20 45.48,217.36 ; J5.20 44.21,217.36 ; R5762.2 92.68,138.46 v2(92.68,137.16) ; J3.B32 198.73,199.23 ; J3.B32 197.57,199.23 ; J3.B32 197.57,198.07 ; J3.B32 198.73,198.07 ; J5.133 51.18,224.36 ; J5.133 49.91,224.36 ; J5.133 49.91,225.63 ; J5.133 51.18,225.63 ; FAN3.1 42.86,248.2 ; FAN3.1 40.6,250.46 ; FAN3.1 42.86,250.46 ; FAN3.1 40.6,248.2 ; J3.B16 198.73,214.07 ; J3.B16 198.73,215.23 ; J3.B16 197.57,215.23 ; J3.B16 197.57,214.07 ; 21.74,54.54 J10.M1 ; J10.M1 23.82,54.54 ; J10.M1 21.74,56.62 ; J10.M1 23.82,56.62 ; v2(117.16,140.21) 116.32,140.21 C878.2 116.26,139.51 v2(117.16,139.51) ; 239.1,204.72 J4.2 240.7,204.72 ; J3.A42 205.23,189.23 ; J3.A42 204.07,188.07 ; J3.A42 205.23,188.07 ; J3.A42 204.07,189.23 ; R954.1 v2(262.51,35.05) ; 8.71,248.2 FAN5.1 ; FAN5.1 10.97,248.2 ; FAN5.1 10.97,250.46 ; FAN5.1 8.71,250.46 ; 21.38,118.87 CT31.2 ; CT31.2 21.38,120.66 ; CT31.2 23.17,118.87 ; CT31.2 23.17,120.66 ; CT35.2 22.81,93.86 ; CT35.2 22.81,92.07 ; CT35.2 21.02,93.86 ; CT35.2 21.02,92.07 ; C5345.2 265.35,76.97 ; C5345.2 263.43,76.97 ; C5345.2 263.43,75.05 ; C5345.2 265.35,75.05 ; 44.21,235.36 J5.2 45.48,235.36 ; J5.41 47.38,197.63 ; J5.41 47.38,196.36 ; J5.41 46.11,196.36 ; J5.41 46.11,197.63 ; C127.2 95.72,229.47 v5(95.63,229.55) ; 204.07,207.23 J3.A24 ; J3.A24 205.23,206.07 ; J3.A24 205.23,207.23 ; J3.A24 204.07,206.07 ; 3.12,169.43 J8.3 ; J8.3 5.02,169.43 ; J8.3 3.12,171.33 ; J8.3 5.02,171.33 ; C5289.2 74.86,247.88 ; C5289.2 74.86,246.09 ; C5289.2 73.07,246.09 ; C5289.2 73.07,247.88 ; SW6.2 11.08,4.54 ; SW6.2 9.45,2.91 ; SW6.2 11.08,2.91 ; SW6.2 9.45,4.54 ; v2(104.24,138.15) 104.47,137.92 R5883.1 ; 202.07,190.23 J3.A41 ; J3.A41 202.07,189.07 ; J3.A41 203.23,189.07 ; J3.A41 203.23,190.23 ; 48.01,215.36 J5.142 ; J5.142 49.28,216.63 ; J5.142 49.28,215.36 ; J5.142 48.01,216.63 ; J3.A37 203.23,193.07 ; J3.A37 203.23,194.23 ; J3.A37 202.07,194.23 ; J3.A37 202.07,193.07 ; 197.57,187.23 J3.B44 ; J3.B44 198.73,186.07 ; J3.B44 197.57,186.07 ; J3.B44 198.73,187.23 ; v2(105.79,193.37) 105.79,192.63 C567.2 105.16,192.76 v2(105.16,193.37) ; 46.11,233.63 J5.5 ; J5.5 46.11,232.36 ; J5.5 47.38,232.36 ; J5.5 47.38,233.63 ; C5283.2 117.58,247.88 ; C5283.2 115.79,246.09 ; C5283.2 115.79,247.88 ; C5283.2 117.58,246.09 ; J3.A15 203.23,215.07 ; J3.A15 202.07,215.07 ; J3.A15 203.23,216.23 ; J3.A15 202.07,216.23 ; 202.07,207.07 J3.A23 ; J3.A23 203.23,207.07 ; J3.A23 202.07,208.23 ; J3.A23 203.23,208.23 ; J3.B47 200.73,184.23 ; J3.B47 199.57,183.07 ; J3.B47 199.57,184.23 ; J3.B47 200.73,183.07 ; v2(56.9,164.59) 56.9,164.11 56.58,163.79 ; C5340.2 21.71,146.13 ; C5340.2 21.71,144.34 ; C5340.2 19.92,144.34 ; C5340.2 19.92,146.13 ; C5337.2 208.79,244.57 ; C5337.2 207,242.78 ; C5337.2 208.79,242.78 ; C5337.2 207,244.57 ; J5.26 45.48,211.36 ; J5.26 44.21,211.36 ; J5.26 45.48,212.63 ; J5.26 44.21,212.63 ; J8.1 5.34,163.27 ; J8.1 2.8,163.27 ; J8.1 5.34,160.73 ; J8.1 2.8,160.73 ; 49.91,230.36 J5.127 ; J5.127 51.18,230.36 ; J5.127 49.91,231.63 ; J5.127 51.18,231.63 ; 46.11,226.36 J5.11 ; J5.11 47.38,227.63 ; J5.11 46.11,227.63 ; J5.11 47.38,226.36 ; v2(126.52,89.28) 126.31,89.08 C3860.2 ; J9.18 10.62,111.72 ; J9.18 8.52,113.82 ; J9.18 8.52,111.72 ; J9.18 10.62,113.82 ; 190.75,242.78 C5339.2 ; C5339.2 192.54,244.57 ; C5339.2 190.75,244.57 ; C5339.2 192.54,242.78 ; 242.94,246.25 243.71,247.01 ; 243.71,247.01 242.94,247.78 ; 243.71,247.01 244.48,246.25 ; 243.71,247.01 244.48,247.78 ; v6(34.54,194.94) 34.87,195.27 C5143.1 ; C584.2 77.83,184.21 v2(77.98,184.35) ; 10.52,7.22 SW6.4 ; SW6.4 12.5,5.23 ; SW6.4 12.5,7.22 ; SW6.4 10.52,5.23 ; 49.91,219.63 J5.139 ; J5.139 51.18,219.63 ; J5.139 49.91,218.36 ; J5.139 51.18,218.36 ; 199.57,210.23 J3.B21 ; J3.B21 199.57,209.07 ; J3.B21 200.73,210.23 ; J3.B21 200.73,209.07 ; 202.07,182.23 J3.A49 ; J3.A49 203.23,182.23 ; J3.A49 203.23,181.07 ; 204.07,192.07 J3.A38 ; J3.A38 205.23,193.23 ; J3.A38 204.07,193.23 ; J3.A38 205.23,192.07 ; R953.1 v2(258.44,35.05) ; 48.01,197.36 J5.160 ; J5.160 49.28,198.63 ; J5.160 49.28,197.36 ; J5.160 48.01,198.63 ; J5.29 47.38,208.36 ; J5.29 46.11,208.36 ; J5.29 47.38,209.63 ; J5.29 46.11,209.63 ; v2(81.55,136.95) 82.25,137.64 C879.2 82.75,137.16 v2(83.25,137.16) ; J5.121 51.18,237.63 ; J5.121 49.91,236.36 ; J5.121 51.18,236.36 ; J5.121 49.91,237.63 ; J5.23 47.38,215.63 ; J5.23 46.11,215.63 ; J5.23 47.38,214.36 ; J5.23 46.11,214.36 ; J9.5 5.12,109.62 ; J9.5 3.02,109.62 ; J9.5 5.12,107.52 ; J9.5 3.02,107.52 ; R957.1 v2(255.4,35.05) ; R948.1 v2(241.15,35.05) ; R930.1 v2(212.65,35.05) ; C874.2 v3(116.33,143.2) ; 46.11,220.36 J5.17 ; J5.17 47.38,220.36 ; J5.17 46.11,221.63 ; J5.17 47.38,221.63 ; v2(99.98,190.53) 100.89,190.53 C568.2 101.22,191.16 v2(99.99,191.16) ; R935.1 v2(234.01,35.05) ; v2(41.53,169.54) 41.53,168.95 ; R926.1 v2(219.76,35.05) ; v6(113.87,80.93) 113.46,80.53 v5(113.06,80.53) ; R944.1 v2(248.26,35.05) ; 56.58,163.79 C717.1 ; R936.1 v2(229.94,35.05) ; C112.2 v2(247.61,203.62) ; R927.1 v2(215.7,35.05) ; 197.57,205.23 J3.B26 ; J3.B26 198.73,204.07 ; J3.B26 197.57,204.07 ; J3.B26 198.73,205.23 ; 238.98,210.95 J55.2 240.58,210.95 ; 199.57,192.23 J3.B39 ; J3.B39 200.73,191.07 ; J3.B39 200.73,192.23 ; J3.B39 199.57,191.07
  BOTTOM w0.914: BH10.1 117.48,213.23 ; BH10.1 113.64,213.23 ; BH10.1 113.64,209.4 ; BH10.1 117.48,209.4
  BOTTOM w1.016: 275.81,15.81 H15.1 ; H15.1 282.19,22.18 ; H15.1 275.81,22.18 ; H15.1 282.19,15.81 ; H14.1 72.99,41.81 ; H14.1 72.99,48.19 ; H14.1 66.62,41.81 ; H14.1 66.62,48.19 ; H4.1 67.18,195.93 ; H4.1 60.81,202.3 ; H4.1 67.18,202.3 ; H4.1 60.81,195.93 ; 223.81,243.81 H7.1 ; H7.1 230.18,243.81 ; H7.1 223.81,250.18 ; H7.1 230.18,250.18 ; 172.41,250.18 H2.1 ; H2.1 178.78,250.18 ; H2.1 178.78,243.81 ; H8.1 282.19,130.93 ; H8.1 282.19,124.56 ; H8.1 275.81,130.93 ; H8.1 275.81,124.56 ; 24.81,243.81 H1.1 ; H1.1 31.19,243.81 ; H1.1 31.19,250.18 ; H1.1 24.81,250.18 ; H3.1 282.19,250.18 ; H3.1 275.81,243.81 ; H3.1 275.81,250.18 ; H3.1 282.19,243.81 ; H16.1 9.19,22.18 ; H16.1 2.81,22.18 ; H16.1 2.81,15.81 ; H16.1 9.19,15.81
  vias: v1(34.62,84.96) v1(35.46,84.96) v1(55.87,79.2) v1(55.87,71.2) v1(59.07,80.8) v1(59.07,75.2) v1(59.87,76) v1(59.87,74.4) v1(59.87,72.8) v1(60.67,76.8) v1(60.67,75.2) v1(60.67,73.6) v1(61.47,80) v1(61.47,76) v1(61.47,74.4) v1(61.47,72.8) v1(62.27,76.8) v1(62.27,75.2) v1(62.27,73.6) v1(63.07,76) v1(63.07,74.4) v1(63.87,79.2) v1(66.27,70.4) v1(67.07,80.8) v2(1.27,1.27) v2(1.72,34.78) v2(1.72,32.31) v2(1.75,37.92) v2(2.24,63.24) v2(2.24,58.16) v2(2.24,53.08) v2(2.24,48) v2(2.24,42.92) v2(2.27,11.43) v2(2.29,9.18) v2(2.36,14.23) v2(2.45,30.25) v2(2.45,26.62) v2(2.45,24) v2(7.32,58.16) v2(7.32,53.08) v2(7.32,48) v2(7.32,42.92) v2(7.62,1.27) v2(8.48,238.68) v2(8.48,235.12) v2(9.62,238.68) v2(9.62,235.12) v2(13.94,48.54) v2(13.97,1.27) v2(14.66,52.7) v2(14.66,50.19) v2(16.43,48.54) v2(20.32,1.27) v2(26.67,1.27) v2(27.2,164.87) v2(27.79,164.34) v2(28.45,168.48) v2(28.63,103.81) v2(28.81,140.26) v2(29.01,167.74) v2(29.21,103.28) v2(29.26,166.78) v2(29.39,139.73) v2(29.87,107.42) v2(30.05,143.87) v2(30.18,168.58) v2(30.4,163.83) v2(30.43,106.68) v2(30.48,193.29) v2(30.61,143.13) v2(30.73,105.82) v2(30.89,142.11) v2(31.27,168.58) v2(31.39,143.97) v2(31.45,107.57) v2(31.83,102.77) v2(32.01,139.22) v2(32.26,194.18) v2(32.46,168.58) v2(32.56,107.57) v2(32.82,143.94) v2(33.22,124.84) v2(33.27,125.88) v2(33.45,107.57) v2(34.04,143.99) v2(34.11,125.73) v2(34.09,124.99) v2(36.47,180.16) v2(36.96,193.93) v2(37.22,191.51) v2(37.49,180.16) v2(38.23,189.1) v2(38.23,187.83) v2(38.23,186.81) v2(38.46,180.16) v2(39.32,180.11) v2(39.88,210.36) v2(40.11,211.38) v2(40.82,210.36) v2(40.97,180.37) v2(47.75,27.05) v2(48.39,27.05) v2(51.64,87.71) v2(51.77,31.39) v2(52.68,87.73) v2(52.73,32.26) v2(53.8,86.92) v2(53.77,31.47) v2(54.81,86.94) v2(55.64,180.72) v2(55.63,174.88) v2(55.88,122.94) v2(56.01,175.9) v2(56.72,175.87) v2(57.02,105.92) v2(59.03,153.44) v2(59.03,152.81) v2(59.18,176.91) v2(59.69,160.78) v2(59.69,160.15) v2(59.66,153.44) v2(59.66,152.81) v2(59.82,176.91) v2(60.33,160.78) v2(60.33,160.15) v2(60.3,153.44) v2(60.3,152.81) v2(60.45,176.91) v2(61.09,176.91) v2(67.06,176.91) v2(67.49,66.5) v2(67.54,65.48) v2(67.77,176.91) v2(68.15,64.31) v2(68.07,62.74) v2(68.55,176.91) v2(69.44,176.91) v2(70.1,163.22) v2(70.1,162.59) v2(70.74,163.22) v2(70.74,162.59) v2(70.99,183.64) v2(71.63,183.64) v2(71.63,144.15) v2(72.19,31.17) v2(72.87,31.88) v2(73.28,25.53) v2(73.28,24.89) v2(73.48,177.44) v2(73.63,31.17) v2(74.17,177.67) v2(75.31,15.37) v2(75.95,15.37) v2(76.58,146.56) v2(76.83,148.84) v2(77.22,147.57) v2(78.96,52.39) v2(79.33,140.59) v2(84.71,125.35) v2(84.71,124.71) v2(85.34,125.35) v2(85.34,124.71) v2(85.57,195.58) v2(85.6,194.94) v2(85.6,194.31) v2(85.6,193.68) v2(89.34,140.21) v2(94.11,36.96) v2(94.11,36.07) v2(94.11,35.05) v2(95.02,87.86) v2(95.07,88.82) v2(95.71,89.05) v2(102.71,100.45) v2(103.01,123.06) v2(103.01,122.43) v2(103.76,128.78) v2(103.76,128.14) v2(103.94,100.44) v2(106.05,128.78) v2(106.05,128.14) v2(108.71,15.37) v2(109.35,128.78) v2(109.35,128.14) v2(109.35,15.37) v2(110.39,138.2) v2(110.62,128.14) v2(111.01,139.78) v2(111.25,139.01) v2(111.29,65.38) v2(113.12,71.96) v2(113.23,120.1) v2(113.28,120.82) v2(113.92,120.82) v2(113.87,120.1) v2(115.09,40.39) v2(115.49,101.27) v2(115.48,98.69) v2(116.01,135.38) v2(116.18,42.6) v2(116.65,135.38) v2(116.94,38.4) v2(117.5,71.93) v2(117.78,40.77) v2(118.47,38.86) v2(118.52,36.75) v2(119.25,40.08) v2(120.3,69.18) v2(120.3,68.25) v2(120.55,40.08) v2(121.16,124.59) v2(121.16,123.95) v2(121.16,65.41) v2(121.17,64.51) v2(121.79,124.59) v2(121.79,123.95) v2(122.51,74.89) v2(123.11,38.28) v2(124.32,74.87) v2(124.38,38.25) v2(124.87,40.21) v2(125.02,35.08) v2(125.2,37.69) v2(125.83,37.03) v2(125.95,65.64) v2(126.01,67.56) v2(126.36,185.34) v2(126.52,71.18) v2(126.8,38.89) v2(127,185.34) v2(127.04,73.4) v2(127.04,72.51) v2(127.18,36.3) v2(127.27,69.21) v2(127.51,71.68) v2(127.64,185.34) v2(128.5,38.33) v2(128.59,190.88) v2(128.59,190.25) v2(128.68,40.83) v2(129.13,37.67) v2(129.77,74.62) v2(129.97,37.26) v2(130.48,39.37) v2(130.9,69.91) v2(130.9,67.27) v2(132.46,190.88) v2(132.46,190.25) v2(132.61,37.19) v2(132.83,72.7) v2(132.97,35.79) v2(134.53,72.44) v2(135.59,35.74) v2(136.53,38.56) v2(136.91,36.17) v2(138.23,180.47) v2(138.23,179.83) v2(138.43,35.33) v2(138.48,37.9) v2(138.86,180.47) v2(138.86,179.83) v2(140.94,36.5) v2(142.01,71.52) v2(142.24,151.63) v2(142.24,150.5) v2(142.88,151.63) v2(142.88,150.5) v2(142.88,147.45) v2(142.88,146.81) v2(142.88,146.18) v2(142.88,145.54) v2(143.48,36.47) v2(144.75,73.42) v2(146.13,66.73) v2(146.92,70.99) v2(151.37,66.69) v2(159.61,40.84) v2(159.59,38.3) v2(160.07,36.75) v2(160.5,39.12) v2(161.42,75.45) v2(161.39,39.12) v2(162.69,39.12) v2(163.47,70.76) v2(163.98,75.47) v2(164.72,243.59) v2(165.13,70.76) v2(165.38,37.24) v2(166.74,70.05) v2(166.76,67.49) v2(166.75,37.24) v2(166.88,40.21) v2(167.11,35.99) v2(167.54,37.8) v2(168.91,38.86) v2(169.62,187.99) v2(169.7,189.74) v2(169.77,186.36) v2(169.82,184.71) v2(169.8,36.5) v2(169.94,73.56) v2(169.96,70.99) v2(170.1,190.68) v2(170.1,188.9) v2(170.13,187.2) v2(170.26,185.55) v2(170.59,38.33) v2(170.66,75.06) v2(170.76,40.69) v2(171.3,37.69) v2(171.7,97.87) v2(171.72,95.2) v2(171.76,90.37) v2(171.78,87.7) v2(171.96,187.58) v2(172.09,170.18) v2(172.09,165.1) v2(172.09,160.02) v2(172.09,149.86) v2(172.14,37.34) v2(172.58,66.31) v2(172.72,39.34) v2(172.97,187.58) v2(173.25,75.04) v2(173.69,93.9) v2(173.7,91.24) v2(173.68,86.4) v2(173.69,83.73) v2(174.37,187.58) v2(174.75,37.34) v2(175.15,66.33) v2(175.51,187.58) v2(175.62,36.14) v2(175.9,170.18) v2(175.9,165.1) v2(175.9,160.02) v2(175.9,156.21) v2(175.87,151.82) v2(176.48,66.57) v2(176.5,64.01) v2(176.66,188.59) v2(176.78,199.77) v2(176.78,198.75) v2(177.01,205.46) v2(177.01,204.14) v2(177.24,36.09) v2(178.16,38.4) v2(178.44,195.33) v2(178.56,212.72) v2(178.56,210.76) v2(178.56,208.6) v2(178.56,206.69) v2(178.56,204.55) v2(178.56,202.62) v2(178.56,200.03) v2(178.64,69.82) v2(178.66,67.26) v2(179.07,188.85) v2(179.2,216.6) v2(179.2,212.72) v2(179.2,210.76) v2(179.2,208.6) v2(179.2,206.69) v2(179.2,204.55) v2(179.2,202.62) v2(179.2,200.03) v2(179.32,193.55) v2(179.28,36.31) v2(179.71,170.18) v2(179.71,165.1) v2(179.71,160.02) v2(179.71,156.21) v2(179.68,151.82) v2(179.77,215.01) v2(180.41,37.99) v2(181.56,35.81) v2(182.49,143.33) v2(182.63,187.71) v2(182.56,132.59) v2(183.39,187.2) v2(183.74,36.7) v2(184.15,197.49) v2(184.15,194.75) v2(184.4,187.2) v2(184.78,197.49) v2(184.78,194.75) v2(186.18,36.63) v2(186.59,79.35) v2(186.79,78.38) v2(187.26,192.41) v2(187.53,78.41) v2(187.71,194.63) v2(187.71,190.68) v2(187.96,251.71) v2(188.15,192.85) v2(188.53,112.44) v2(188.54,109.77) v2(188.58,104.95) v2(188.6,102.28) v2(189.67,188.84) v2(190.11,190.58) v2(190.44,188.47) v2(190.51,108.48) v2(190.53,105.81) v2(190.5,100.98) v2(190.52,98.31) v2(192.47,184.28) v2(192.91,186.51) v2(192.94,182.55) v2(192.97,93.91) v2(192.99,91.24) v2(192.98,86.4) v2(193,83.73) v2(193.42,184.85) v2(199.09,65.99) v2(199.11,64.82) v2(199.14,63.55) v2(199.26,62.03) v2(199.39,251.71) v2(200,62.59) v2(200.94,62.87) v2(202.87,60.78) v2(203.42,93.93) v2(203.4,61.37) v2(203.62,92.96) v2(203.91,63.98) v2(204.36,92.99) v2(209.8,108.48) v2(209.81,105.81) v2(209.81,100.98) v2(209.82,98.31) v2(210.82,251.71) v2(211.54,48.52) v2(213.08,217.4) v2(213.08,214.96) v2(213.08,212.32) v2(213.08,209.98) v2(213.08,208.31) v2(213.11,205.92) v2(213.08,204.34) v2(213.08,201.88) v2(213.32,144.8) v2(214.21,48.54) v2(218.14,127.56) v2(218.37,134.26) v2(218.37,117.94) v2(222.25,251.71) v2(224.62,143.93) v2(225.73,202.51) v2(225.73,199.82) v2(225.76,215.47) v2(225.78,212.9) v2(225.76,210.39) v2(225.76,207.92) v2(225.78,206.48) v2(225.76,203.91) v2(225.79,48.52) v2(226.07,109.16) v2(227.68,127.52) v2(228.46,48.54) v2(229.07,168.63) v2(230.37,159.82) v2(230.39,118.06) v2(230.5,136.7) v2(230.65,148.04) v2(231.1,104.76) v2(233.47,175.87) v2(233.68,251.71) v2(240.04,48.52) v2(242.71,48.54) v2(243.59,90.75) v2(243.61,89.59) v2(243.59,88.29) v2(243.66,86.79) v2(244.4,87.35) v2(244.85,146.02) v2(244.88,176.21) v2(244.96,167.61) v2(244.96,158.79) v2(245.11,251.71) v2(245.36,87.61) v2(247.27,85.55) v2(247.8,86.13) v2(248.31,88.75) v2(253.34,133.14) v2(254.29,48.52) v2(256.54,251.71) v2(256.96,48.54) v2(259.51,111.41) v2(259.63,103.94) v2(263.25,238.09) v2(263.28,245.57) v2(263.43,251.58) v2(264.09,124.97) v2(264.32,140.52) v2(264.47,132.48) v2(264.47,117.23) v2(268.33,238.09) v2(268.3,103.79) v2(268.36,245.57) v2(268.51,251.58) v2(270.79,231.86) v2(270.79,221.7) v2(270.79,216.62) v2(270.79,211.54) v2(270.79,206.46) v2(270.79,201.38) v2(270.79,196.3) v2(270.79,191.22) v2(270.79,186.14) v2(273.44,245.57) v2(273.41,238.09) v2(273.59,251.58) v2(275.87,231.86) v2(275.87,221.7) v2(275.87,216.62) v2(275.87,211.54) v2(275.87,206.46) v2(275.87,201.38) v2(275.87,196.3) v2(275.87,191.22) v2(275.87,186.14) v2(275.87,181.06) v2(275.87,175.98) v2(275.87,170.9) v2(275.87,165.82) v2(275.87,160.74) v2(275.87,155.66) v2(275.87,150.58) v2(275.87,145.5) v2(275.87,140.42) v2(275.87,135.34) v2(275.87,120.1) v2(275.87,115.02) v2(275.87,109.94) v2(275.87,104.86) v2(279.4,3.81) v2(280.95,231.86) v2(280.95,221.7) v2(280.95,216.62) v2(280.95,211.54) v2(280.95,206.46) v2(280.95,201.38) v2(280.95,196.3) v2(280.95,191.22) v2(280.95,186.14) v2(280.95,181.06) v2(280.95,175.98) v2(280.95,170.9) v2(280.95,165.82) v2(280.95,160.74) v2(280.95,155.66) v2(280.95,150.58) v2(280.95,145.5) v2(280.95,140.42) v2(280.95,135.34) v2(280.95,120.1) v2(280.95,115.02) v2(280.95,109.94) v2(280.95,104.86) v3(76.48,152.35) v3(77.11,160.2) v3(77.06,152.35) v3(77.72,160.18) v3(77.91,153.23) v4(2.16,175.13) v4(2.16,173.99) v4(2.16,170.94) v4(2.16,169.8) v4(2.16,166.75) v4(2.16,165.61) v4(2.16,162.56) v4(2.16,161.42) v4(2.16,117.47) v4(2.16,116.33) v4(2.16,109.09) v4(2.16,107.95) v4(2.16,100.71) v4(2.16,99.57) v4(5.97,175.13) v4(5.97,173.99) v4(5.97,170.94) v4(5.97,169.8) v4(5.97,166.75) v4(5.97,165.61) v4(5.97,162.56) v4(5.97,161.42) v4(5.97,117.47) v4(5.97,116.33) v4(5.97,109.09) v4(5.97,107.95) v4(5.97,100.71) v4(5.97,99.57) v4(9.65,242.95) v4(10.84,225.58) v4(10.84,217.2) v4(10.92,244.47) v4(10.92,242.95) v4(10.97,219.49) v4(11.1,221.77) v4(11.43,138.56) v4(11.43,137.41) v4(11.56,117.47) v4(11.56,116.33) v4(11.56,113.28) v4(11.56,112.14) v4(11.56,109.09) v4(11.56,107.95) v4(11.56,100.71) v4(11.56,99.57) v4(12.57,138.56) v4(12.57,137.41) v4(12.7,117.47) v4(12.7,116.33) v4(12.7,113.28) v4(12.7,112.14) v4(12.7,109.09) v4(12.7,107.95) v4(12.7,100.71) v4(12.7,99.57) v4(13.76,225.58) v4(14.02,221.77) v4(14.02,219.49) v4(14.02,217.33) v4(16.56,219.49) v4(17.83,224.57) v4(17.83,221.9) v4(19.1,219.49) v4(19.71,147.4) v4(19.71,142.95) v4(19.68,133.22) v4(19.68,129.92) v4(20.37,221.9) v4(20.49,224.57) v4(20.83,242.95) v4(20.93,94.36) v4(21.21,118.36) v4(21.18,91.44) v4(21.34,133.22) v4(21.34,129.92) v4(21.34,121.54) v4(21.62,142.95) v4(21.74,147.4) v4(22.1,244.47) v4(22.1,242.95) v4(22.83,94.36) v4(22.83,91.31) v4(23.11,121.54) v4(23.11,118.36) v4(23.16,224.57) v4(23.16,221.9) v4(23.19,169.44) v4(23.27,174.73) v4(23.29,172.52) v4(23.44,176.86) v4(23.52,166.34) v4(24.05,219.49) v4(24.61,167.77) v4(24.61,108.38) v4(24.69,113.67) v4(24.72,111.46) v4(24.79,144.83) v4(24.87,150.11) v4(24.89,147.9) v4(24.87,115.8) v4(24.94,105.28) v4(25.05,152.25) v4(25.12,141.73) v4(25.19,224.82) v4(25.6,166.24) v4(26.04,106.71) v4(26.11,174.78) v4(26.16,172.47) v4(26.19,169.6) v4(26.21,143.15) v4(26.26,176.89) v4(27.03,105.18) v4(27.2,141.63) v4(27.54,113.72) v4(27.59,111.4) v4(27.61,108.53) v4(27.71,150.16) v4(27.69,115.82) v4(27.76,147.85) v4(27.79,144.98) v4(27.87,152.27) v4(32.3,225.46) v4(32.3,223.17) v4(32.43,220.76) v4(34.72,225.46) v4(34.72,223.17) v4(36.88,233.2) v4(36.88,231.43) v4(36.88,229.01) v4(36.88,226.6) v4(36.88,224.44) v4(36.88,222.15) v4(36.88,219.87) v4(39.04,233.2) v4(39.04,231.43) v4(39.04,229.01) v4(39.04,226.6) v4(39.04,224.44) v4(39.04,222.15) v4(39.04,219.87) v4(41.54,242.95) v4(42.81,244.47) v4(42.81,242.95) v4(63.45,242.95) v4(64.72,244.47) v4(64.72,242.95) v4(70.71,244.98) v4(70.71,242.44) v4(70.71,239.9) v4(71.06,237.73) v4(71.06,235.7) v4(73.25,244.98) v4(73.25,242.44) v4(73.25,239.9) v4(73.35,237.73) v4(73.35,235.7) v4(75.53,244.98) v4(75.53,242.44) v4(75.53,239.9) v4(80.99,208.79) v4(80.99,206.25) v4(82.39,210.69) v4(83.41,232.03) v4(83.53,208.79) v4(83.53,206.25) v4(83.53,203.71) v4(84.68,210.69) v4(85.69,232.03) v4(85.76,239.18) v4(85.76,236.89) v4(85.76,234.35) v4(85.82,208.79) v4(85.82,206.25) v4(85.82,203.71) v4(87.29,233.16) v4(88.81,239.56) v4(88.81,237.27) v4(88.81,234.73) v4(91.47,239.69) v4(91.47,237.4) v4(91.47,234.86) v4(99.21,212.52) v4(100.33,213.39) v4(104.7,202.74) v4(104.7,201.22) v4(104.7,199.69) v4(104.7,198.17) v4(104.7,196.65) v4(105.94,201.9) v4(105.94,200.38) v4(105.94,198.86) v4(105.94,197.33) v4(109.91,208.84) v4(111.02,209.93) v4(111.33,201.17) v4(111.38,204.04) v4(111.61,198.58) v4(111.73,202.69) v4(111.71,196.75) v4(112.27,211.23) v4(112.39,209.42) v4(112.7,201.7) v4(112.75,197.66) v4(115.87,244.42) v4(116,242.21) v4(116.76,249.58) v4(117.78,244.42) v4(117.91,242.21) v4(118.57,212.37) v4(118.67,249.58) v4(118.67,247.68) v4(118.67,209.78) v4(119.02,200.25) v4(119.02,198.81) v4(119.05,197.33) v4(119.68,244.42) v4(119.81,242.21) v4(120.57,249.58) v4(120.57,247.68) v4(121.59,244.42) v4(122.48,249.58) v4(122.48,247.68) v4(125.23,202.49) v4(125.25,200.38) v4(125.23,196.9) v4(125.31,198.58) v4(125.91,201.45) v4(126.05,197.7) v4(143.51,242.95) v4(144.85,244.47) v4(144.85,242.95) v4(187.2,244.98) v4(187.2,242.7) v4(189.1,244.98) v4(189.1,242.7) v4(189.48,230.5) v4(189.48,228.22) v4(189.66,52.93) v4(189.66,51.66) v4(190.86,59.84) v4(190.88,57.02) v4(191.19,52.93) v4(191.9,230.5) v4(191.9,228.35) v4(192.96,59.69) v4(193.01,56.85) v4(193.8,244.98) v4(193.8,242.7) v4(195.22,56.87) v4(195.28,59.74) v4(196.22,244.98) v4(196.22,242.82) v4(198.15,59.77) v4(198.3,56.77) v4(199.97,58.19) v4(201.4,57.1) v4(201.5,59.18) v4(203.45,244.98) v4(203.45,242.7) v4(205.36,244.98) v4(205.36,242.7) v4(210.06,244.98) v4(210.06,242.7) v4(212.47,244.98) v4(212.47,242.82) v4(235.25,84.61) v4(235.28,81.79) v4(237.36,84.46) v4(237.41,81.61) v4(239.62,81.64) v4(239.67,84.51) v4(242.54,84.53) v4(242.7,81.54) v4(244.37,82.96) v4(245.8,81.87) v4(245.9,83.95) v5(74.96,233.12) v5(74.96,232.11) v5(74.96,231.09) v5(74.96,229.97) v5(76.28,233.12) v5(76.28,232.11) v5(76.28,231.09) v5(77.55,230.73) v5(93.04,232.75) v5(93.04,231.74) v5(93.04,230.72) v5(93.04,229.6) v5(94.36,232.75) v5(94.36,231.74) v5(94.36,230.72) v5(95.63,230.36) v5(98.16,225.24) v5(105.17,95.45) v5(106.93,106.5) v5(106.93,105.23) v5(106.93,103.96) v5(108.2,106.5) v5(108.2,105.23) v5(108.2,103.96) v5(109.47,106.5) v5(109.47,105.23) v5(109.47,103.96) v5(112.84,95.45) v5(118.82,82.45) v5(119.75,85.46) v5(119.84,84.48) v5(119.84,83.46) v5(120.22,87.02) v5(120.22,82.45) v5(120.75,86) v5(120.75,84.73) v5(120.78,83.46) v5(121.23,82.45) v5(121.74,87.02) v5(122.02,86) v5(122.02,84.73) v5(122.05,83.46) v5(122.25,82.45) v5(123.01,87.02) v5(123.29,86) v5(123.29,84.73) v5(123.32,83.46) v5(123.27,82.45) v5(124.28,87.02) v5(124.28,86) v5(124.28,84.48) v5(124.28,83.46) v5(124.46,50.29) v5(124.46,49.02) v5(126.35,51.31) v5(126.35,50.29) v5(126.35,49.02) v5(126.35,48.01) v5(128.42,51.31) v5(128.42,50.29) v5(128.42,49.02) v5(128.42,48.01) v5(130.28,50.29) v5(130.28,49.02) v5(166.62,50.29) v5(166.62,49.02) v5(168.52,51.31) v5(168.52,50.29) v5(168.52,49.02) v5(168.52,48.01) v5(170.59,51.31) v5(170.59,50.29) v5(170.59,49.02) v5(170.59,48.01) v5(172.44,50.29) v5(172.44,49.02) v5(180.21,91.88) v5(180.21,89.73) v5(180.21,88.65) v5(181.29,92.96) v5(181.29,91.88) v5(181.29,90.81) v5(181.29,89.73) v5(182.37,92.96) v5(182.37,91.88) v5(182.37,90.81) v5(182.37,89.73) v5(182.37,88.65) v5(183.45,92.96) v5(183.45,91.88) v5(183.45,90.81) v5(183.45,89.73) v5(183.45,88.65) v5(184.53,92.96) v5(184.53,91.88) v5(184.53,90.81) v5(184.53,89.73) v5(184.53,88.65) v5(197.04,106.46) v5(197.04,104.3) v5(197.04,103.22) v5(198.12,107.54) v5(198.12,106.46) v5(198.12,105.38) v5(198.12,104.3) v5(199.2,107.54) v5(199.2,106.46) v5(199.2,105.38) v5(199.2,104.3) v5(199.2,103.22) v5(200.28,107.54) v5(200.28,106.46) v5(200.28,105.38) v5(200.28,104.3) v5(200.28,103.22) v5(201.36,107.54) v5(201.36,106.46) v5(201.36,105.38) v5(201.36,104.3) v5(201.36,103.22) v5(249.48,112.5) v5(249.48,110.9) v5(251.05,112.5) v5(251.05,110.9) v5(275.81,81.65) v5(275.81,80.38) v5(277.34,81.65) v5(277.34,80.38) v5(278.73,81.65) v5(278.73,80.38) v6(8.6,237.79) v6(8.6,236.14) v6(9.58,237.75) v6(9.58,236.13) v6(33.53,194.94) v6(33.53,194.18) v6(33.53,193.42) v6(34.54,194.18) v6(34.54,193.42) v6(35.56,194.94) v6(35.56,194.18) v6(35.56,193.42) v6(36.65,126.36) v6(67.16,149.35) v6(117.32,77.24) v6(118.54,77.24) v6(118.59,92.61) v6(119.81,92.61) v6(120.75,72.8) v6(121.97,72.8) v6(123.04,92.61) v6(123.55,72.8) v6(124.26,92.61) v6(124.76,72.8) v6(127.43,92.61) v6(127.86,77.11) v6(128.65,92.61) v6(129.08,77.11) v6(130.02,77.11) v6(131.24,77.11) v6(132.92,87.5) v6(132.92,86.28) v6(132.92,84.58) v6(132.92,83.36) v6(132.92,81.92) v6(132.92,80.7) v6(178.57,192.28) v6(178.57,191.27) v6(178.57,190.25) v6(179.33,192.28) v6(179.33,191.27) v6(179.33,190.25) v6(180.09,192.28) v6(180.09,190.25) v6(245.2,219.96) v6(245.96,220.73) v6(245.96,219.96) v6(245.96,219.2) v6(246.72,219.96) v7(122.27,93.13) v7(130.4,35.51) v7(130.73,36.32) v7(172.06,35.43) v7(172.54,36.27)
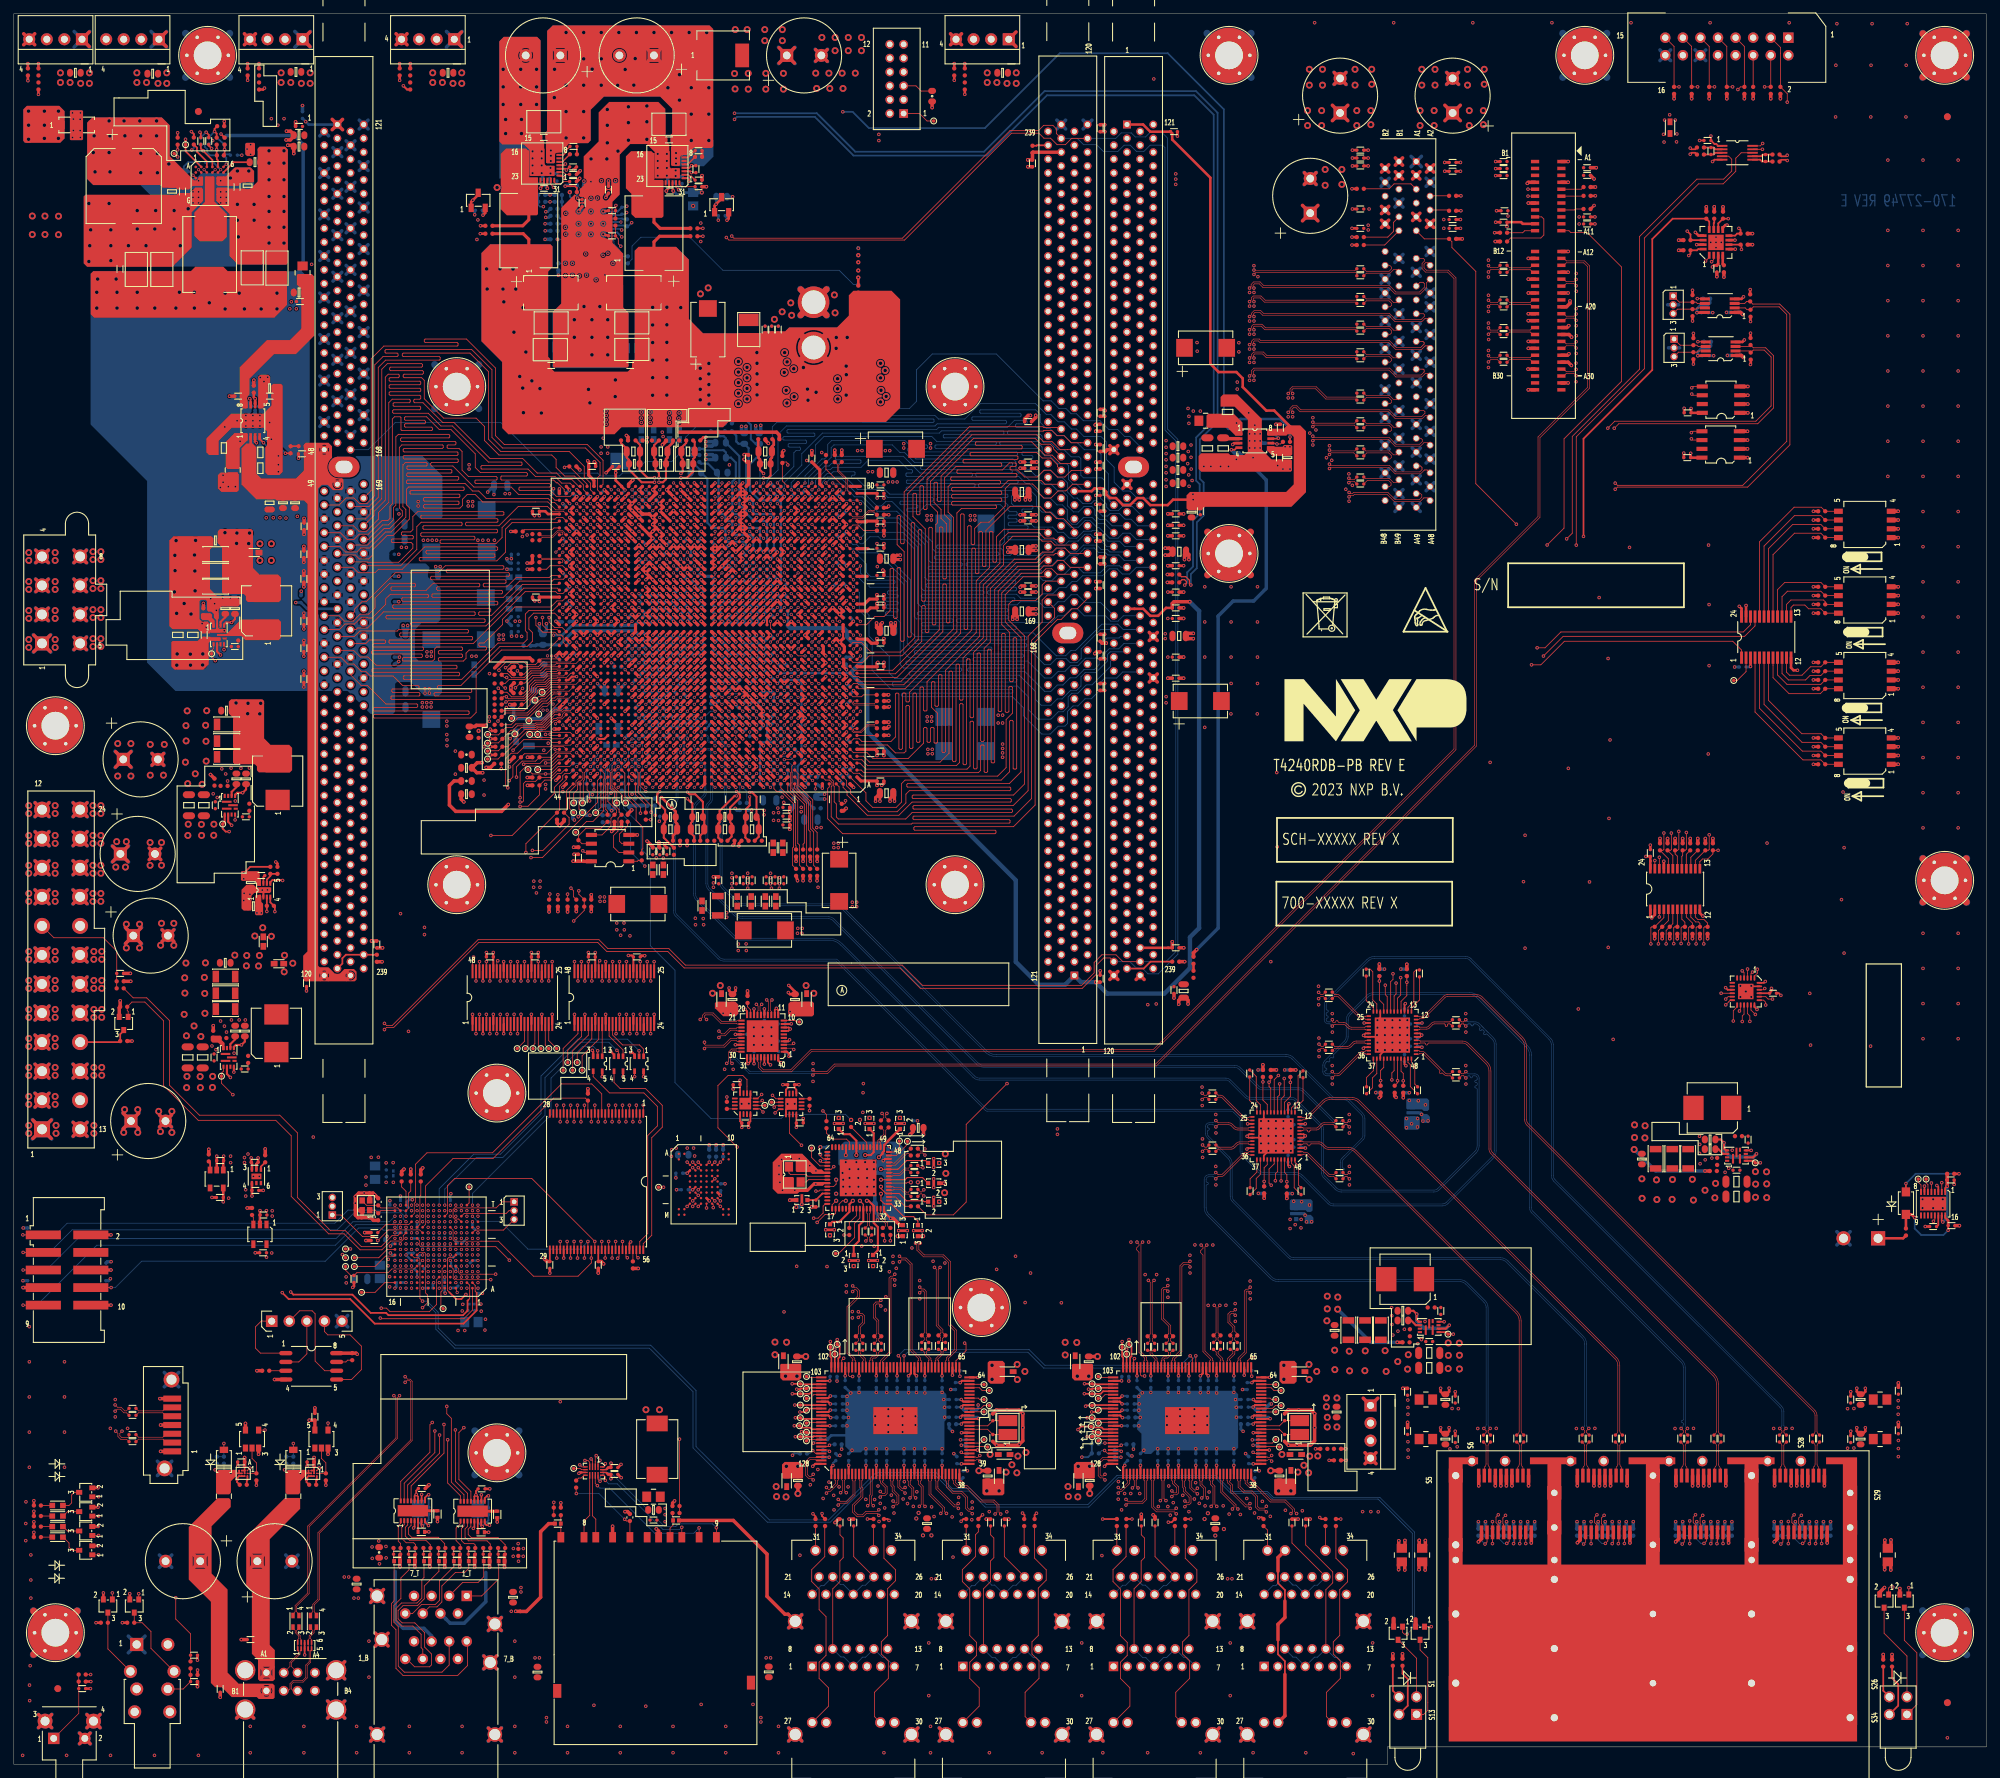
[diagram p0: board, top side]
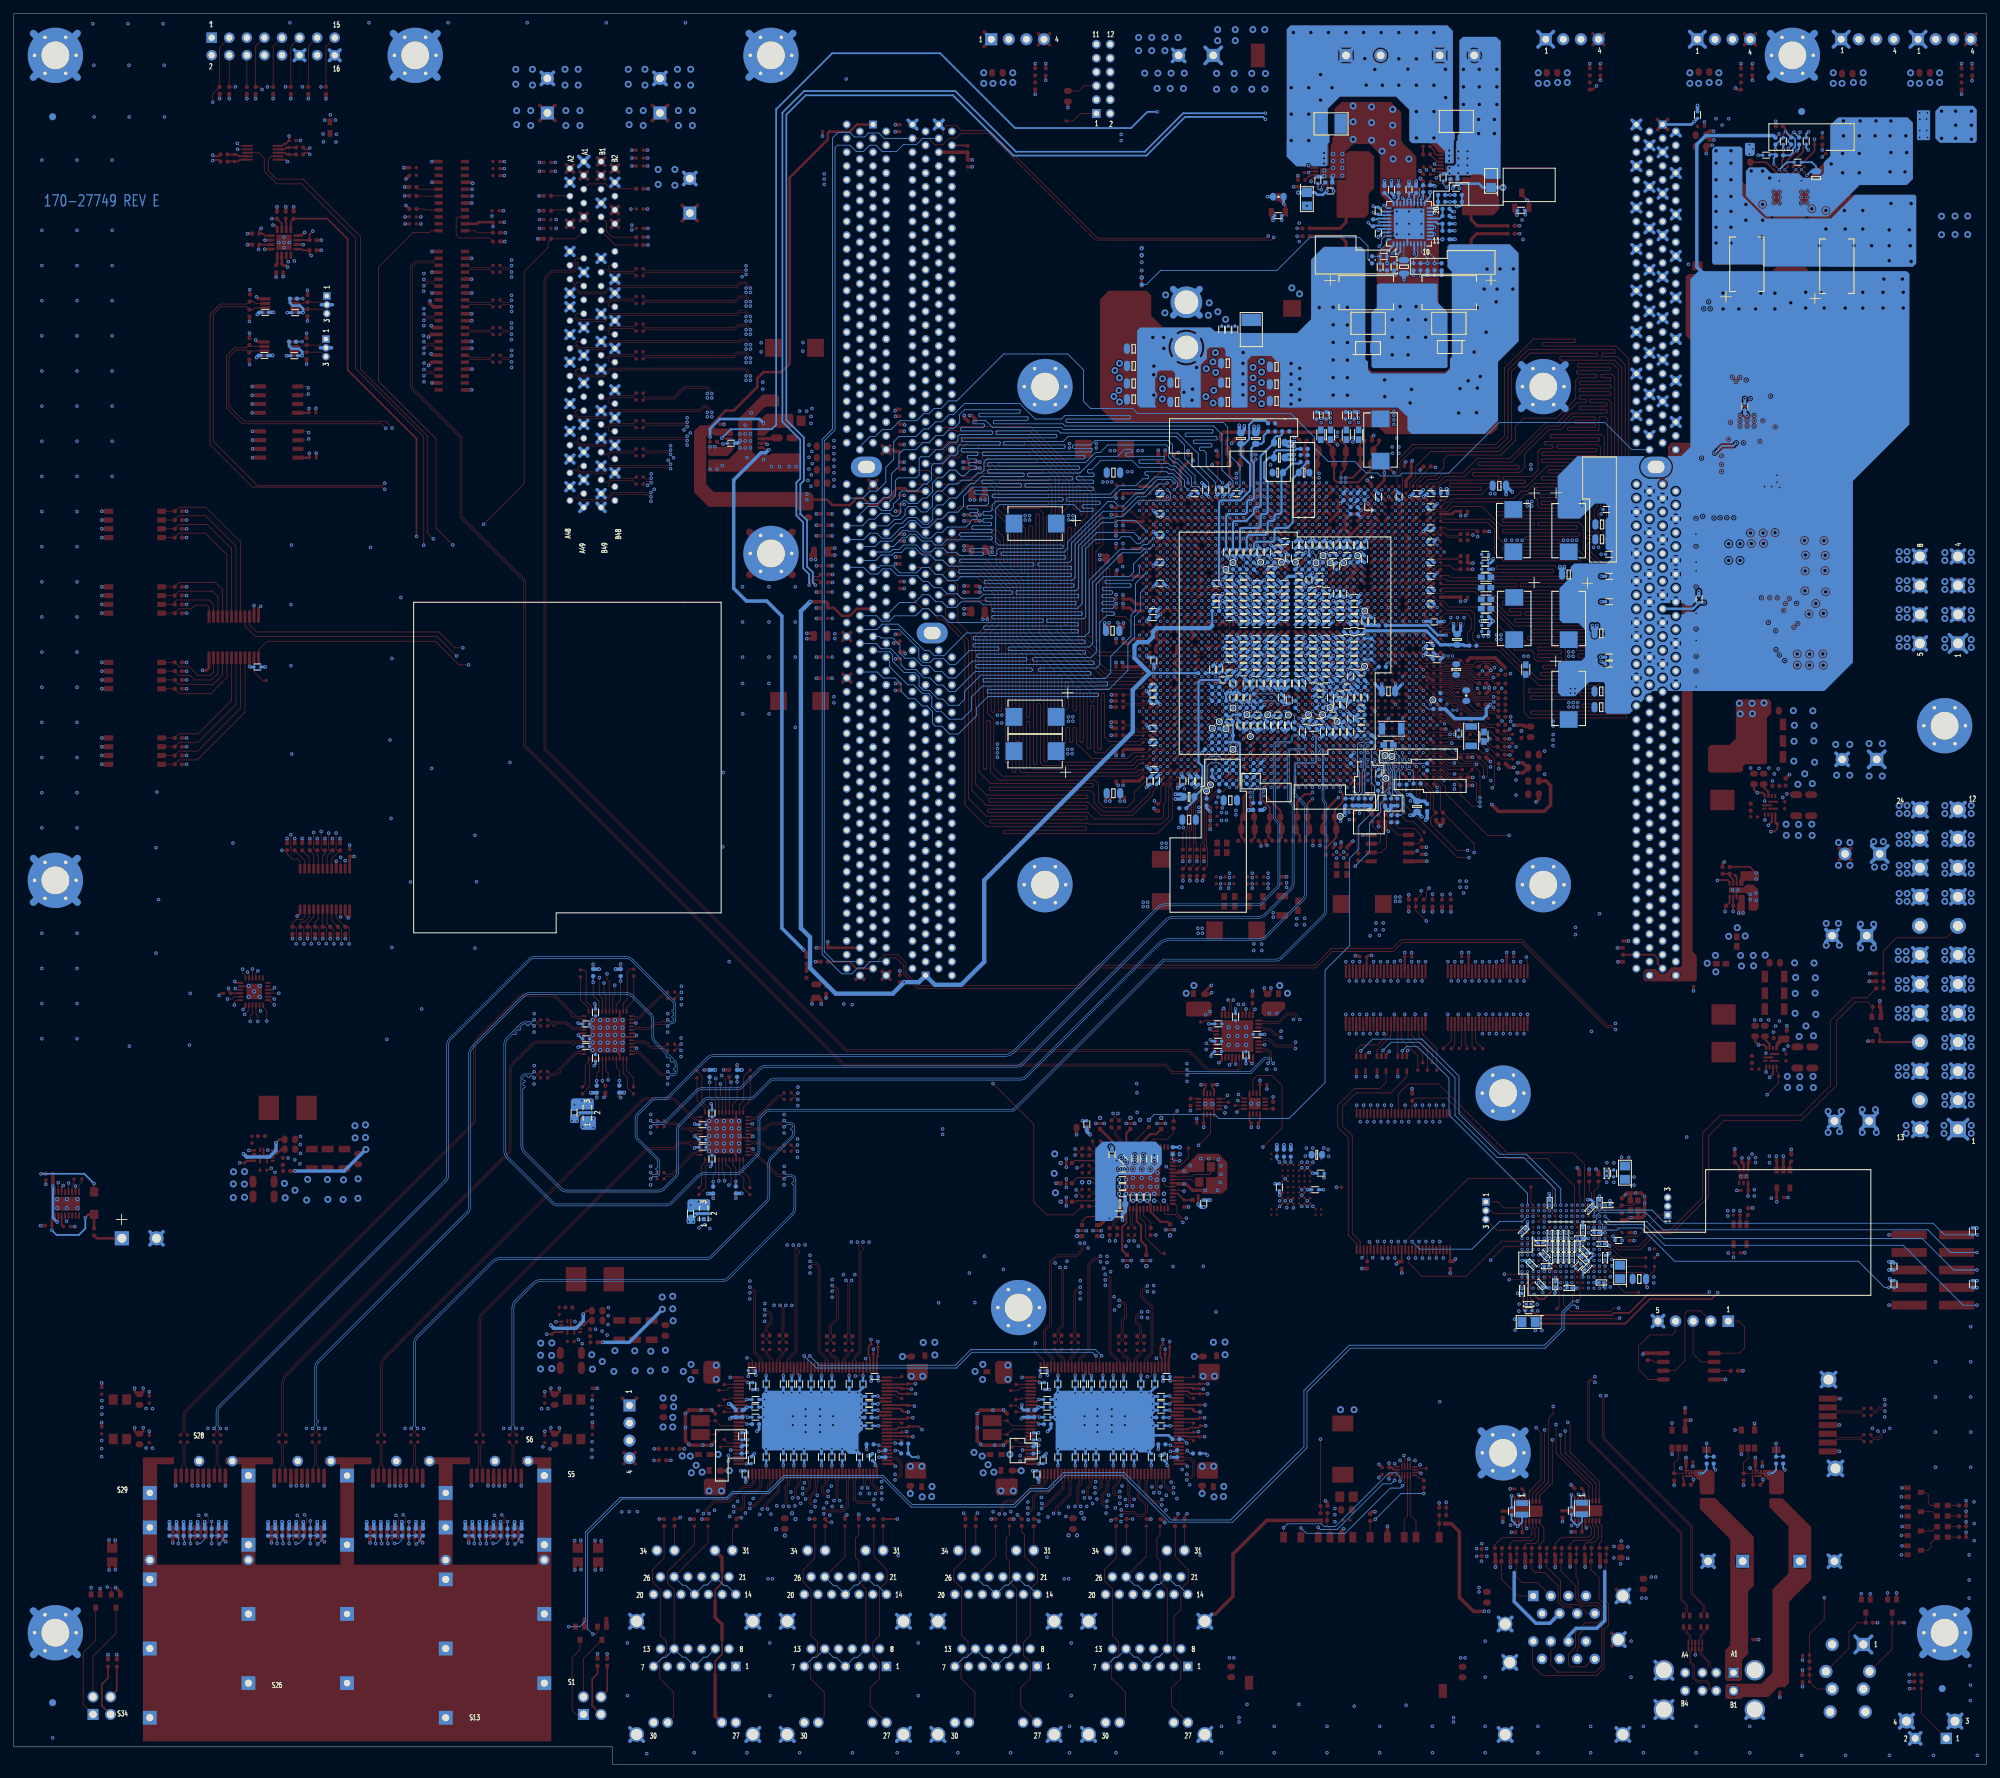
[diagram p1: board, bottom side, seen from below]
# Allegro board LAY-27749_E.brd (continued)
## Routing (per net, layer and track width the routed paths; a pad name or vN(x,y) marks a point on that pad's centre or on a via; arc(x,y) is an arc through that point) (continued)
P1V8_AVDD: length 1.4
  BOTTOM w0.508: 116.58,138.18 R770.1 ; v2(81,136.47) 80.77,136.7 R769.1
  vias: v2(65.79,187.83) v2(65.79,187.2) v2(66.17,160.15) v2(66.8,160.15) v2(116.2,126.75)
P3V3_SFP+_1: length 8
  TOP w0.508: J16.15A v2(215.68,40.23) ; J16.16A v2(214.88,40.23)
  BOTTOM w0.508: R922.1 v2(217.73,35.05) ; R923.2 v2(218.74,35.05) ; R925.1 v2(214.68,35.05) ; R1082.1 v2(211.63,35.05) ; R924.2 v2(216.71,35.05)
  vias: v2(207.52,45.57) v2(208.56,45.87)
P3V3_SFP+_2: length 8
  TOP w0.508: J16.16B v2(229.13,40.23) ; J16.15B v2(229.93,40.23)
  BOTTOM w0.508: R932.2 v2(232.99,35.05) ; R938.1 v2(225.88,35.05) ; R931.1 v2(231.98,35.05) ; R933.2 v2(230.96,35.05) ; R934.1 v2(228.93,35.05)
  vias: v2(207.82,51.41) v2(208.74,51.38)
P3V3_SFP+_3: length 8
  TOP w0.508: J16.16C v2(243.38,40.23) ; J16.15C v2(244.18,40.23)
  BOTTOM w0.508: R942.2 v2(245.21,35.05) ; R940.1 v2(246.23,35.05) ; R947.1 v2(240.13,35.05) ; R943.1 v2(243.18,35.05) ; R941.2 v2(247.24,35.05)
  vias: v2(264.97,51.38) v2(265.89,51.41)
P3V3_SFP+_4: length 8
  TOP w0.508: J16.15D v2(258.43,40.23) ; J16.16D v2(257.63,40.23)
  BOTTOM w0.508: R950.2 v2(259.46,35.05) ; R956.1 v2(254.38,35.05) ; R951.2 v2(261.49,35.05) ; R949.1 v2(260.48,35.05) ; R952.1 v2(257.43,35.05)
  vias: v2(264.97,45.67) v2(265.89,45.69)
SVDD: length 12.2
  TOP w0.508: R5737.2 v2(27.39,167.78)
  L3_INT_1 w0.508: v2(27.39,167.78) 27.39,168.77 29.06,170.43 29.06,176.56 v4(30.51,178)
  vias: v2(62.56,150.75) v2(62.56,150.06) v2(62.56,148.82) v2(62.59,148.06) v2(62.59,147.22) v2(104.7,118.54) v2(104.67,117.6) v2(105.82,118.57) v2(105.84,117.6) v4(32.23,177.95) v4(32.18,176.45) v4(33.93,176.43) v4(34.06,177.95)
VBUS_POWER1: length 3.7
  TOP w0.254: U48.D1 U48.D2 ; U48.D2 31.75,42.04 ; U48.D2 U48.C2
  BOTTOM w0.254: R662.1 30.35,42.55 30.86,42.04 v2(31.37,42.04)
VBUS_POWER2: length 4.1
  TOP w0.254: U47.D1 U47.D2 ; U47.D2 v2(41.4,42.04) ; U47.D2 U47.C2
  BOTTOM w0.254: R664.1 40.39,42.55 40.89,42.04 v2(41.4,42.04)
VCC_3.3: length 502.4
  TOP w0.203: U45.14 85.59,42.17 85.72,42.04
  TOP w0.254: 183.67,23.57 183.67,25.17 182.67,26.17 182.67,27.9 ; C5329.1 111.82,97.75 111.57,97.5 U627.4 ; U624.21 C5309.1 253.97,111.71 v2(253.97,112.14) ; U626.4 106.44,92.93 C5328.1 ; 183.67,12.98 183.67,14.88 182.67,15.88 182.67,17.97
  TOP w0.381: U589.8 C3844.1 v2(242.36,195.96) ; v2(86.28,41.25) C5321.1 85.88,41.88 85.72,42.04 ; R128.2 v2(209.11,224.54) ; U82.24 236.47,130.53 236.47,130.53 C5324.1 v2(235.84,131.21) ; R661.1 v2(35.05,40.32) ; R5682.1 v2(33.78,243.4) ; R5680.1 v2(190.06,43.92) ; R125.2 v2(228.54,226.69) ; v2(228.35,225.3) R143.2 ; U82.21 v2(238.42,130.51) ; R192.1 v2(242.7,206.82) ; U625.8 C5333.1 v2(242.31,189.48) ; U82.1 236.47,122.53 v2(236.68,122.33) 237.12,122.77 U82.2 ; U18.8 243.88,203.62 243.84,203.58 v2(243.33,203.58) ; R5684.1 v2(2.03,243.33) ; R203.1 v2(242.7,202.37) ; C5328.1 v2(106.19,92.05) ; R217.1 v2(242.57,208.6) ; C297.1 166.82,118 J7.236 ; R5683.1 v2(55.75,243.4) ; R5681.1 v2(135.89,243.4) ; R120.2 v2(209.11,226.69) ; v2(243.21,209.8) 243.71,209.8 243.75,209.84 U58.8 ; v2(245.45,216.41) 245.69,216.64 246.07,216.64 C3848.1 246.29,216.85 U105.3 ; R660.1 v2(45.09,40.32) ; C93.1 v2(85.93,228.85) ; C5329.1 v2(111.12,98.22) ; R222.1 v2(242.57,213.04)
  TOP w0.508: 202.12,223.12 J3.A9 ; J3.A9 202.12,224.18 ; J3.A9 203.17,224.18 ; J3.A9 203.17,223.12 ; C5338.1 188.44,225.31 ; C5338.1 186.21,225.31 ; C5338.1 188.44,223.08 ; C5338.1 186.21,223.08 ; 182.67,17.97 182.67,20.21 183.67,21.21 183.67,23.57 ; C297.1 v2(167.39,118.88) ; R5874.1 v2(238.96,133.8) ; R337.1 v2(16.89,113.16) ; J9.12 5.07,138.96 ; J9.12 5.07,136.98 ; J9.12 3.08,138.96 ; J9.12 3.08,136.98 ; 2.74,90.44 J9.1 ; J9.1 2.74,93.1 ; J9.1 5.41,90.44 ; J9.1 5.41,93.1 ; R338.2 v2(169.19,116) ; R336.2 v2(53.21,115.98) ; U625.3 v2(250.52,191.39) ; R5690.1 v2(247.1,214.95) ; R42.1 v2(132.69,239.45) ; R5871.1 v2(244.74,119.32) ; 204.12,222.12 J3.A10 ; J3.A10 205.17,223.18 ; J3.A10 205.17,222.12 ; J3.A10 204.12,223.18 ; 244.56,224.41 v2(244.56,225.11) ; 15.8,94.08 CT35.1 ; CT35.1 15.8,91.85 ; CT35.1 18.03,91.85 ; CT35.1 18.03,94.08 ; 197.62,224.12 J3.B8 ; J3.B8 198.67,224.12 ; J3.B8 197.62,225.18 ; J3.B8 198.67,225.18 ; R528.1 v2(245.51,133.8) ; 183.67,12.98 183.67,6.99 J14.28 ; J9.13 10.57,90.78 ; J9.13 8.58,92.76 ; J9.13 8.58,90.78 ; J9.13 10.57,92.76 ; R521.1 v2(240.37,119.32) ; 182.67,27.9 182.67,29.87 J14.32 ; R530.1 v2(243.33,133.8) ; R526.1 v2(243.64,119.32) ; v2(146.51,231.89) C42.1 R113.2 147.27,233 J6.236 ; R520.1 v2(237.1,119.32) ; R522.1 v2(239.28,119.32) ; J9.2 5.07,96.96 ; J9.2 3.08,94.97 ; J9.2 5.07,94.97 ; J9.2 3.08,96.96 ; C296.1 v2(53.28,117.99) ; R5872.1 v2(241.15,133.8) ; FL20.1 112.15,81.54 v2(112.13,81.53) ; 245.71,224.41 v2(245.71,225.11) ; R529.1 v2(242.24,133.8) ; U625.1 v2(250.52,188.85) ; v2(42.69,49.72) C505.1 U628.5 ; R523.1 v2(242.56,119.32) ; R5870.1 v2(241.47,119.32) ; R519.1 v2(238.19,119.32) ; R527.1 v2(244.42,133.8) ; U625.2 v2(250.52,190.12) ; R5873.1 v2(237.87,133.8) ; R531.1 v2(240.05,133.8) ; U629.5 v2(33.47,49.25) ; R145.2 v2(209.3,220.47)
  L3_INT_1 w0.508: J9.13 10.57,92.76 ; J9.13 8.58,90.78 ; J9.13 10.57,90.78 ; J9.13 8.58,92.76 ; J9.12 5.07,136.98 ; J9.12 3.08,138.96 ; J9.12 5.07,138.96 ; J9.12 3.08,136.98 ; CT35.1 17.76,93.81 ; CT35.1 16.07,93.81 ; CT35.1 17.76,92.12 ; CT35.1 16.07,92.12 ; 2.74,93.1 J9.1 ; J9.1 5.41,93.1 ; J9.1 2.74,90.44 ; J9.1 5.41,90.44 ; J9.2 5.07,94.97 ; J9.2 3.08,96.96 ; J9.2 5.07,96.96 ; J9.2 3.08,94.97
  L5_INT_2 w0.508: 16.07,93.81 CT35.1 ; CT35.1 17.76,92.12 ; CT35.1 16.07,92.12 ; CT35.1 17.76,93.81 ; v2(167.39,118.88) 167.39,117.79 v2(169.19,116) v2(181.63,116) ; J9.13 10.57,90.78 ; J9.13 10.57,92.76 ; J9.13 8.58,92.76 ; J9.13 8.58,90.78 ; J9.2 5.07,96.96 ; J9.2 5.07,94.97 ; J9.2 3.08,96.96 ; J9.2 3.08,94.97 ; J9.12 5.07,136.98 ; J9.12 5.07,138.96 ; J9.12 3.08,136.98 ; J9.12 3.08,138.96 ; 2.74,93.1 J9.1 ; J9.1 2.74,90.44 ; J9.1 5.41,93.1 ; J9.1 5.41,90.44
  L7_INT_3 w0.508: J9.13 10.57,90.78 ; J9.13 8.58,92.76 ; J9.13 10.57,92.76 ; J9.13 8.58,90.78 ; J9.2 5.07,96.96 ; J9.2 3.08,96.96 ; J9.2 3.08,94.97 ; J9.2 5.07,94.97 ; 2.74,93.1 J9.1 ; J9.1 5.41,93.1 ; J9.1 5.41,90.44 ; J9.1 2.74,90.44
  L9_PWR_2 w0.508: J9.13 10.57,90.78 ; J9.13 8.58,90.78 ; J9.13 8.58,92.76 ; J9.13 10.57,92.76 ; 48.07,118.58 J5.236 ; J5.236 49.23,117.42 ; J5.236 49.23,118.58 ; J5.236 48.07,117.42 ; 150.77,232.42 J6.236 ; J6.236 150.77,233.58 ; J6.236 151.93,232.42 ; J6.236 151.93,233.58 ; J3.B8 198.67,224.12 ; J3.B8 198.67,225.18 ; J3.B8 197.62,224.12 ; J3.B8 197.62,225.18 ; J14.32 184.41,30.17 ; J14.32 182.98,30.17 ; J14.32 182.98,31.61 ; J14.32 184.41,31.61 ; 3.08,94.97 J9.2 ; J9.2 5.07,96.96 ; J9.2 5.07,94.97 ; J9.2 3.08,96.96 ; 186.48,225.04 C5338.1 ; C5338.1 188.17,223.35 ; C5338.1 186.48,223.35 ; C5338.1 188.17,225.04 ; 117.67,31.61 J11.32 ; J11.32 119.1,30.17 ; J11.32 117.67,30.17 ; J11.32 119.1,31.61 ; J3.A10 205.17,222.12 ; J3.A10 204.12,223.18 ; J3.A10 205.17,223.18 ; J3.A10 204.12,222.12 ; J9.1 5.41,93.1 ; J9.1 5.41,90.44 ; J9.1 2.74,90.44 ; J9.1 2.74,93.1 ; 16.07,92.12 CT35.1 ; CT35.1 16.07,93.81 ; CT35.1 17.76,92.12 ; CT35.1 17.76,93.81 ; 3.08,136.98 J9.12 ; J9.12 3.08,138.96 ; J9.12 5.07,136.98 ; J9.12 5.07,138.96 ; J12.32 140.87,31.61 ; J12.32 139.44,30.17 ; J12.32 139.44,31.61 ; J12.32 140.87,30.17 ; 161.21,30.17 J13.32 ; J13.32 162.64,31.61 ; J13.32 161.21,31.61 ; J13.32 162.64,30.17 ; J3.A9 203.17,224.18 ; J3.A9 202.12,223.12 ; J3.A9 202.12,224.18 ; J3.A9 203.17,223.12
  L10_INT_4 w0.508: J9.13 10.57,92.76 ; J9.13 8.58,92.76 ; J9.13 10.57,90.78 ; J9.13 8.58,90.78 ; J9.1 5.41,93.1 ; J9.1 2.74,90.44 ; J9.1 5.41,90.44 ; J9.1 2.74,93.1 ; J9.2 5.07,96.96 ; J9.2 3.08,94.97 ; J9.2 5.07,94.97 ; J9.2 3.08,96.96
  L12_INT_5 w0.254: 159.91,23.47 159.91,25.26 159.17,26 ; J11.28 118.36,6.99 118.36,14.9 117.36,15.9 117.36,21.44 116.37,22.43 116.37,25.26 114.43,27.2 114.43,29.36 v2(113.59,30.2) ; J12.28 140.13,6.99 140.13,14.9 139.13,15.9 139.13,21.44 138.14,22.43 138.14,25.26 135.71,27.69 v2(135.71,29.92) ; 161.9,13.08 161.9,14.9 160.9,15.9 160.9,17.7
  L12_INT_5 w0.381: 161.9,13.08 161.9,6.99 J13.28 ; 159.91,23.47 159.91,22.43 160.9,21.44 160.9,17.7 ; 159.17,26 157.23,27.94 v2(157.23,30.15)
  L12_INT_5 w0.508: 3.08,96.96 J9.2 ; J9.2 5.07,96.96 ; J9.2 5.07,94.97 ; J9.2 3.08,94.97 ; J9.13 10.57,92.76 ; J9.13 8.58,90.78 ; J9.13 8.58,92.76 ; J9.13 10.57,90.78 ; 2.74,93.1 J9.1 ; J9.1 2.74,90.44 ; J9.1 5.41,93.1 ; J9.1 5.41,90.44
  L14_INT_6 w0.508: J9.2 5.12,97.02 ; J9.2 3.02,97.02 ; J9.2 5.12,94.92 ; J9.2 3.02,94.92 ; 3.02,139.02 J9.12 ; J9.12 5.12,136.92 ; J9.12 5.12,139.02 ; J9.12 3.02,136.92 ; 4.06,139.7 4.07,139.71 ; 8.52,92.82 J9.13 ; J9.13 10.62,90.72 ; J9.13 10.62,92.82 ; J9.13 8.52,90.72 ; CT35.1 17.81,93.86 ; CT35.1 16.02,93.86 ; CT35.1 17.81,92.07 ; CT35.1 16.02,92.07 ; J9.1 5.48,93.18 ; J9.1 5.48,90.36 ; J9.1 2.66,93.18 ; J9.1 2.66,90.36
  BOTTOM w0.254: v2(83.39,226.34) 83.64,226.09 U3.26 ; v2(83.39,226.34) 83.14,226.09 U3.25 ; v2(83.39,226.34) C5260.1
  BOTTOM w0.381: C1002.1 v2(243.21,209.8) 243.21,210.38 243.65,210.82 244.73,210.82 245.11,211.2 R830.1 ; C113.1 v2(243.33,203.58) 243.33,204.15 243.78,204.6 244.86,204.6 245.24,204.98 245.24,205.61 ; R5705.1 v5(116.54,89.18)
  BOTTOM w0.508: R48.1 v2(82.37,228.82) ; 15.72,94.16 CT35.1 ; CT35.1 18.11,91.77 ; CT35.1 18.11,94.16 ; CT35.1 15.72,91.77 ; J9.12 5.12,136.92 ; J9.12 3.02,139.02 ; J9.12 5.12,139.02 ; J9.12 3.02,136.92 ; R58.1 v2(86.94,228.89) ; 8.52,90.72 J9.13 ; J9.13 8.52,92.82 ; J9.13 10.62,92.82 ; J9.13 10.62,90.72 ; R49.1 v2(76.76,220.41) ; R628.1 v2(80.72,215.21) ; C3865.1 v2(112.13,81.53) ; C93.1 v2(85.93,228.85) ; 2.66,90.36 J9.1 ; J9.1 2.66,93.18 ; J9.1 5.48,90.36 ; J9.1 5.48,93.18 ; R629.1 v2(78.69,215.22) ; 3.02,94.92 J9.2 ; J9.2 5.12,94.92 ; J9.2 5.12,97.02 ; J9.2 3.02,97.02 ; R47.1 v2(82.75,215.23)
  vias: v2(35.13,123.04) v2(35.61,200.43) v2(35.76,123.04) v2(36.14,199.85) v2(36.68,200.48) v2(37.21,237.85) v2(38.15,236.91) v2(39.04,237.85) v2(76.83,141.6) v2(76.83,140.97) v2(183.69,190.42) v2(184.4,190.42) v2(195.83,224.79) v2(201.42,52.63) v2(201.45,51.56) v2(201.45,50.57) v2(201.45,46.61) v2(201.47,45.42) v2(201.47,44.35) v2(206.63,223.27) v2(206.63,222) v2(215.91,223.77) v2(226.19,223.65) v2(226.19,222.63) v2(272.29,52.55) v2(272.29,51.56) v2(272.29,50.57) v2(272.31,46.79) v2(272.31,45.62) v2(272.31,44.45) v4(2.16,138.56) v4(2.16,137.41) v4(2.16,96.52) v4(2.16,95.38) v4(2.16,92.33) v4(2.16,91.19) v4(5.97,138.56) v4(5.97,137.41) v4(5.97,96.52) v4(5.97,95.38) v4(6.1,92.33) v4(6.1,91.19) v4(11.56,92.33) v4(11.56,91.19) v4(15.88,91.31) v4(16,94.61) v4(17.91,94.61) v4(17.91,91.31) v4(91.34,51.23) v4(93.29,51.23) v4(100.96,111.43) v4(102.08,112.55) v4(114.48,112.55) v4(115.6,111.43) v4(143.38,42.21) v4(144.22,43.28) v4(144.93,42.11) v4(144.98,57.78) v4(145.01,55.6) v4(146.1,56.77) v4(185.55,42.21) v4(186.41,43.21) v4(187.15,57.78) v4(187.1,42.11) v4(187.17,55.6) v4(188.26,56.77) v5(124.16,72) v5(130.63,84.11)
VCC_5: length 252.9
  TOP w0.254: 43.38,43.05 U47.B1 ; U47.B1 U47.B2 ; U47.B1 U47.C1 ; U7.3 97.72,230.24 v2(97.91,230.05) C5343.1 ; U9.29 v6(77.09,227.79) ; U9.3 79.64,230.61 v2(79.84,230.41) 80.3,230.88 C5344.1 ; v6(95.29,227.39) 95.18,227.51 U7.29 ; U48.C1 U48.B1 ; U48.B1 33.35,43.05 ; U48.B1 U48.B2
  TOP w0.508: J9.23 10.57,134.76 ; J9.23 8.58,134.76 ; J9.23 10.57,132.77 ; J9.23 8.58,132.77 ; 33.35,43.05 C516.1 v2(33.35,44.32) ; R5811.1 v2(99.44,229.61) ; J9.21 10.57,124.37 ; J9.21 8.58,126.36 ; J9.21 8.58,124.37 ; J9.21 10.57,126.36 ; 14.27,130.45 CT28.1 ; CT28.1 16.51,130.45 ; CT28.1 14.27,132.69 ; CT28.1 16.51,132.69 ; 8.58,128.58 J9.22 ; J9.22 10.57,128.58 ; J9.22 10.57,130.56 ; J9.22 8.58,130.56 ; v2(43.38,44.32) C515.1 43.38,43.05 ; 3.08,103.37 J9.4 ; J9.4 5.07,105.36 ; J9.4 3.08,105.36 ; J9.4 5.07,103.37 ; R5812.1 v2(100.08,228.01) ; 3.08,111.77 J9.6 ; J9.6 5.07,111.77 ; J9.6 5.07,113.76 ; J9.6 3.08,113.76 ; v2(81.76,229.21) R40.1 ; R41.1 v2(81.83,230.31)
  L3_INT_1 w0.508: 8.58,126.36 J9.21 ; J9.21 10.57,126.36 ; J9.21 8.58,124.37 ; J9.21 10.57,124.37 ; J9.23 10.57,134.76 ; J9.23 10.57,132.77 ; J9.23 8.58,134.76 ; J9.23 8.58,132.77 ; 3.08,103.37 J9.4 ; J9.4 5.07,103.37 ; J9.4 3.08,105.36 ; J9.4 5.07,105.36 ; J9.6 5.07,113.76 ; J9.6 3.08,113.76 ; J9.6 5.07,111.77 ; J9.6 3.08,111.77 ; 14.55,130.73 CT28.1 ; CT28.1 14.55,132.41 ; CT28.1 16.23,132.41 ; CT28.1 16.23,130.73 ; J9.22 10.57,128.58 ; J9.22 8.58,130.56 ; J9.22 8.58,128.58 ; J9.22 10.57,130.56
  L5_INT_2 w0.508: J9.4 5.07,103.37 ; J9.4 3.08,105.36 ; J9.4 3.08,103.37 ; J9.4 5.07,105.36 ; CT28.1 16.23,132.41 ; CT28.1 14.55,132.41 ; CT28.1 16.23,130.73 ; CT28.1 14.55,130.73 ; 3.08,113.76 J9.6 ; J9.6 3.08,111.77 ; J9.6 5.07,113.76 ; J9.6 5.07,111.77 ; J9.23 10.57,132.77 ; J9.23 8.58,132.77 ; J9.23 10.57,134.76 ; J9.23 8.58,134.76 ; 8.58,128.58 J9.22 ; J9.22 10.57,128.58 ; J9.22 10.57,130.56 ; J9.22 8.58,130.56 ; J9.21 10.57,124.37 ; J9.21 8.58,126.36 ; J9.21 8.58,124.37 ; J9.21 10.57,126.36
  L7_INT_3 w0.508: 3.08,111.77 J9.6 ; J9.6 3.08,113.76 ; J9.6 5.07,111.77 ; J9.6 5.07,113.76 ; J9.4 5.07,103.37 ; J9.4 5.07,105.36 ; J9.4 3.08,103.37 ; J9.4 3.08,105.36
  L10_INT_4 w0.508: 3.08,113.76 J9.6 ; J9.6 5.07,113.76 ; J9.6 3.08,111.77 ; J9.6 5.07,111.77 ; J9.4 5.07,103.37 ; J9.4 3.08,105.36 ; J9.4 5.07,105.36 ; J9.4 3.08,103.37
  L12_INT_5 w0.508: 8.58,134.76 J9.23 ; J9.23 8.58,132.77 ; J9.23 10.57,132.77 ; J9.23 10.57,134.76 ; 14.55,132.41 CT28.1 ; CT28.1 14.55,130.73 ; CT28.1 16.23,132.41 ; CT28.1 16.23,130.73 ; 8.58,130.56 J9.22 ; J9.22 8.58,128.58 ; J9.22 10.57,130.56 ; J9.22 10.57,128.58 ; J9.6 5.07,111.77 ; J9.6 3.08,111.77 ; J9.6 3.08,113.76 ; J9.6 5.07,113.76 ; 8.58,126.36 J9.21 ; J9.21 10.57,124.37 ; J9.21 10.57,126.36 ; J9.21 8.58,124.37 ; J9.4 5.07,105.36 ; J9.4 3.08,103.37 ; J9.4 5.07,103.37 ; J9.4 3.08,105.36
  L14_INT_6 w0.508: 3.02,103.32 J9.4 ; J9.4 3.02,105.42 ; J9.4 5.12,105.42 ; J9.4 5.12,103.32 ; CT28.1 16.29,130.68 ; CT28.1 16.29,132.47 ; CT28.1 14.5,132.47 ; CT28.1 14.5,130.68 ; 3.02,111.72 J9.6 ; J9.6 5.12,113.82 ; J9.6 3.02,113.82 ; J9.6 5.12,111.72 ; J9.21 10.62,126.42 ; J9.21 8.52,124.32 ; J9.21 10.62,124.32 ; J9.21 8.52,126.42 ; J9.22 10.62,128.52 ; J9.22 8.52,128.52 ; J9.22 10.62,130.62 ; J9.22 8.52,130.62 ; J9.23 10.62,134.82 ; J9.23 8.52,132.72 ; J9.23 10.62,132.72 ; J9.23 8.52,134.82
  BOTTOM w0.381: v6(77.09,227.79) 76.43,228.45 73.28,228.45 72.73,227.9 C5284.1 ; v6(95.29,227.39) 95.84,226.85 96.65,226.85 96.97,227.17 C5266.1
  BOTTOM w0.508: 8.52,124.32 J9.21 ; J9.21 10.62,124.32 ; J9.21 8.52,126.42 ; J9.21 10.62,126.42 ; 8.52,132.72 J9.23 ; J9.23 8.52,134.82 ; J9.23 10.62,132.72 ; J9.23 10.62,134.82 ; CT28.1 16.59,130.38 ; CT28.1 14.2,132.77 ; CT28.1 14.2,130.38 ; CT28.1 16.59,132.77 ; J9.4 5.12,105.42 ; J9.4 3.02,105.42 ; J9.4 3.02,103.32 ; J9.4 5.12,103.32 ; J9.6 5.12,111.72 ; J9.6 3.02,111.72 ; J9.6 3.02,113.82 ; J9.6 5.12,113.82 ; C5284.1 v4(69.82,227.9) ; J9.22 10.62,128.52 ; J9.22 8.52,130.62 ; J9.22 8.52,128.52 ; J9.22 10.62,130.62 ; v7(99.42,227.17) C5266.1
  vias: v4(2.16,113.28) v4(2.16,112.14) v4(2.16,104.9) v4(2.16,103.76) v4(5.97,113.28) v4(5.97,112.14) v4(5.97,104.9) v4(5.97,103.76) v4(11.43,134.24) v4(11.43,133.1) v4(11.43,129.92) v4(11.43,128.78) v4(11.43,125.86) v4(11.43,124.71) v4(12.57,134.24) v4(12.57,133.1) v4(12.57,129.92) v4(12.57,128.78) v4(12.57,125.86) v4(12.57,124.71) v4(14.73,129.67) v4(14.86,133.35) v4(16.13,129.67) v4(16.26,133.35)
VCC_12: length 145.2
  TOP w0.381: R5688.1 v2(57.28,245.81) ; R5685.1 v2(192.47,45.58) ; C25.1 v2(195.71,233.3) ; C40.1 v2(195.71,231.01) ; R5686.1 v2(137.41,245.81) ; R5687.1 v2(35.43,245.81) ; C43.1 v2(195.71,232.16) ; C26.1 v2(206.76,230.25) ; C41.1 v2(206.76,231.52) ; R5689.1 v2(3.56,245.81)
  TOP w0.508: 190.52,239.79 C5339.1 ; C5339.1 190.52,237.55 ; C5339.1 192.76,239.79 ; C5339.1 192.76,237.55 ; J9.10 5.07,128.58 ; J9.10 5.07,130.56 ; J9.10 3.08,130.56 ; J9.10 3.08,128.58 ; 206.78,239.79 C5337.1 ; C5337.1 206.78,237.55 ; C5337.1 209.02,237.55 ; C5337.1 209.02,239.79 ; 199.62,230.18 J3.B3 ; J3.B3 200.67,229.12 ; J3.B3 199.62,229.12 ; J3.B3 200.67,230.18 ; 202.12,229.12 J3.A3 ; J3.A3 203.17,229.12 ; J3.A3 203.17,230.18 ; J3.A3 202.12,230.18 ; 14.7,146.36 C5340.1 ; C5340.1 16.93,144.12 ; C5340.1 14.7,144.12 ; C5340.1 16.93,146.36 ; J9.11 5.07,134.76 ; J9.11 5.07,132.77 ; J9.11 3.08,132.77 ; J9.11 3.08,134.76 ; J3.A2 205.17,230.12 ; J3.A2 205.17,231.18 ; J3.A2 204.12,231.18 ; J3.A2 204.12,230.12 ; 197.62,230.12 J3.B2 ; J3.B2 198.67,231.18 ; J3.B2 198.67,230.12 ; J3.B2 197.62,231.18 ; 199.62,231.12 J3.B1 ; J3.B1 199.62,232.18 ; J3.B1 200.67,232.18 ; J3.B1 200.67,231.12
  L3_INT_1 w0.508: 3.08,134.76 J9.11 ; J9.11 5.07,132.77 ; J9.11 3.08,132.77 ; J9.11 5.07,134.76 ; 3.08,128.58 J9.10 ; J9.10 5.07,130.56 ; J9.10 5.07,128.58 ; J9.10 3.08,130.56
  L5_INT_2 w0.508: J9.11 5.07,134.76 ; J9.11 5.07,132.77 ; J9.11 3.08,134.76 ; J9.11 3.08,132.77 ; J9.10 5.07,130.56 ; J9.10 3.08,130.56 ; J9.10 3.08,128.58 ; J9.10 5.07,128.58
  L7_INT_3 w0.508: 3.08,130.56 J9.10 ; J9.10 3.08,128.58 ; J9.10 5.07,130.56 ; J9.10 5.07,128.58 ; 3.08,132.77 J9.11 ; J9.11 5.07,132.77 ; J9.11 3.08,134.76 ; J9.11 5.07,134.76 ; 14.97,144.4 C5340.1 ; C5340.1 16.65,146.08 ; C5340.1 14.97,146.08 ; C5340.1 16.65,144.4
  L10_INT_4 w0.508: 207.06,239.51 C5337.1 ; C5337.1 208.74,239.51 ; C5337.1 208.74,237.83 ; C5337.1 207.06,237.83 ; 204.12,231.18 J3.A2 ; J3.A2 205.17,231.18 ; J3.A2 204.12,230.12 ; J3.A2 205.17,230.12 ; J3.B1 200.67,231.12 ; J3.B1 199.62,232.18 ; J3.B1 199.62,231.12 ; J3.B1 200.67,232.18 ; J3.A3 203.17,230.18 ; J3.A3 202.12,229.12 ; J3.A3 202.12,230.18 ; J3.A3 203.17,229.12 ; 197.62,231.18 J3.B2 ; J3.B2 198.67,231.18 ; J3.B2 197.62,230.12 ; J3.B2 198.67,230.12 ; C5339.1 192.48,237.83 ; C5339.1 190.8,237.83 ; C5339.1 190.8,239.51 ; C5339.1 192.48,239.51 ; 199.62,230.18 J3.B3 ; J3.B3 199.62,229.12 ; J3.B3 200.67,229.12 ; J3.B3 200.67,230.18
  L14_INT_6 w0.508: 3.02,128.52 J9.10 ; J9.10 5.12,128.52 ; J9.10 3.02,130.62 ; J9.10 5.12,130.62 ; 3.02,134.82 J9.11 ; J9.11 5.12,134.82 ; J9.11 3.02,132.72 ; J9.11 5.12,132.72
  BOTTOM w0.508: 14.62,144.04 C5340.1 ; C5340.1 17.01,146.43 ; C5340.1 17.01,144.04 ; C5340.1 14.62,146.43 ; 3.02,134.82 J9.11 ; J9.11 5.12,132.72 ; J9.11 5.12,134.82 ; J9.11 3.02,132.72 ; J9.10 5.12,128.52 ; J9.10 5.12,130.62 ; J9.10 3.02,130.62 ; J9.10 3.02,128.52
  vias: v4(2.13,238.93) v4(2.13,236.9) v4(2.13,234.87) v4(2.16,134.24) v4(2.16,133.1) v4(2.16,129.92) v4(2.16,128.78) v4(4.41,238.93) v4(4.41,236.9) v4(4.41,235) v4(5.97,134.24) v4(5.97,133.1) v4(5.97,129.92) v4(5.97,128.78) v4(6.45,238.93) v4(6.45,235) v4(6.73,244.47) v4(6.73,243.08) v4(8.13,243.08) v4(15.01,147.52) v4(15.01,142.82) v4(16.92,147.52) v4(16.92,142.82) v4(17.78,244.47) v4(17.78,243.08) v4(19.18,243.08) v4(23.55,158.85) v4(23.6,160.48) v4(25.02,99.42) v4(24.97,97.79) v4(25.15,134.24) v4(25.2,135.86) v4(25.5,160.45) v4(25.53,158.85) v4(26.93,99.39) v4(26.95,97.79) v4(27.1,135.84) v4(27.13,134.24) v4(27.3,160.48) v4(27.28,158.88) v4(28.73,99.42) v4(28.7,97.82) v4(28.91,135.86) v4(28.88,134.26) v4(38.62,244.47) v4(38.62,243.08) v4(40.02,243.08) v4(60.53,244.47) v4(60.53,243.08) v4(61.93,243.08) v4(140.65,244.47) v4(140.65,243.08) v4(142.05,243.08) v4(186.94,239.01) v4(186.94,236.85) v4(188.98,239.01) v4(188.98,236.85) v4(189.79,50.14) v4(189.79,48.74) v4(191.19,48.74) v4(194.06,239.01) v4(194.06,236.85) v4(196.09,239.01) v4(196.09,236.98) v4(203.2,239.01) v4(203.2,236.85) v4(205.23,239.01) v4(205.23,236.85) v4(207.26,60.89) v4(207.29,59.08) v4(207.26,57.18) v4(208.86,60.86) v4(208.89,59.11) v4(208.89,57.13) v4(210.31,239.01) v4(210.31,236.85) v4(212.34,239.01) v4(212.34,236.98) v4(251.66,85.65) v4(251.69,83.85) v4(251.66,81.94) v4(253.26,85.62) v4(253.29,83.87) v4(253.29,81.89)
VCC_12_8P: length 86.1
  TOP w0.508: 8.69,173.68 J8.8 ; J8.8 8.69,175.47 ; J8.8 10.48,175.47 ; J8.8 10.48,173.68 ; J8.5 10.48,161.1 ; J8.5 8.69,161.1 ; J8.5 8.69,162.89 ; J8.5 10.48,162.89 ; 110.57,248.11 C5283.1 ; C5283.1 110.57,245.87 ; C5283.1 112.8,245.87 ; C5283.1 112.8,248.11 ; J8.6 10.48,165.29 ; J8.6 8.69,165.29 ; J8.6 10.48,167.08 ; J8.6 8.69,167.08 ; 8.69,169.48 J8.7 ; J8.7 10.48,169.48 ; J8.7 8.69,171.27 ; J8.7 10.48,171.27
  L8_PWR_1 w0.508: 110.85,246.15 C5283.1 ; C5283.1 112.53,246.15 ; C5283.1 110.85,247.83 ; C5283.1 112.53,247.83
  L14_INT_6 w0.508: J8.6 10.53,167.14 ; J8.6 8.63,167.14 ; J8.6 10.53,165.24 ; J8.6 8.63,165.24 ; J8.5 10.53,162.95 ; J8.5 8.63,161.05 ; J8.5 8.63,162.95 ; J8.5 10.53,161.05 ; J8.7 10.53,171.33 ; J8.7 8.63,169.43 ; J8.7 10.53,169.43 ; J8.7 8.63,171.33 ; 110.79,247.88 C5283.1 ; C5283.1 110.79,246.09 ; C5283.1 112.58,246.09 ; C5283.1 112.58,247.88 ; J8.8 10.53,175.52 ; J8.8 10.53,173.62 ; J8.8 8.63,175.52 ; J8.8 8.63,173.62
  BOTTOM w0.508: 110.49,248.18 C5283.1 ; C5283.1 110.49,245.8 ; C5283.1 112.88,245.8 ; C5283.1 112.88,248.18 ; J8.5 10.53,162.95 ; J8.5 8.63,161.05 ; J8.5 10.53,161.05 ; J8.5 8.63,162.95 ; J8.7 10.53,169.43 ; J8.7 10.53,171.33 ; J8.7 8.63,169.43 ; J8.7 8.63,171.33 ; J8.6 10.53,165.24 ; J8.6 10.53,167.14 ; J8.6 8.63,167.14 ; J8.6 8.63,165.24 ; 8.63,173.62 J8.8 ; J8.8 8.63,175.52 ; J8.8 10.53,173.62 ; J8.8 10.53,175.52
  vias: v4(2.67,223.77) v4(2.67,221.11) v4(4.5,223.77) v4(4.5,221.11) v4(6.45,223.75) v4(6.45,221.08) v4(11.43,175.26) v4(11.43,174.12) v4(11.43,171.07) v4(11.43,169.93) v4(11.43,166.88) v4(11.43,165.74) v4(11.43,162.69) v4(11.43,161.54) v4(12.57,175.26) v4(12.57,174.12) v4(12.57,171.07) v4(12.57,169.93) v4(12.57,166.88) v4(12.57,165.74) v4(12.57,162.69) v4(12.57,161.54) v4(104.14,244.37) v4(104.24,250.72) v4(104.22,242.14) v4(105.97,250.72) v4(106.12,244.4) v4(106.12,242.11) v4(108.51,250.72) v4(108.51,249.12) v4(108.66,244.4) v4(108.66,242.11) v4(111.05,250.72) v4(111.05,249.12) v4(111.2,244.4) v4(111.2,242.11)
VCC_DVDD: length 22.5
  TOP w0.254: C2705.1 58.14,39.54 v2(58.14,38.99) ; C2704.1 66.78,39.48 v2(66.78,38.93) ; v2(66.78,38.93) 66.54,38.7 U46.12 ; v2(66.78,38.93) 66.78,38.91 67.04,38.65 U46.11 ; U95.5 57.91,34.29 v2(57.76,34.14) ; U95.10 58.93,38.07 v2(58.93,38.99) ; v2(58.14,38.99) 58.14,38.94 58.41,38.67 U95.11 ; v2(58.14,38.99) 57.91,38.76 U95.12 ; v2(67.56,38.93) 67.56,38.02 U46.10 ; U46.5 66.54,34.23 v2(66.4,34.08)
  TOP w0.381: v2(250.94,202.31) 250.94,202.41 250.99,202.47 250.99,203.01 R196.1 ; R190.1 v2(250.95,206.84) ; R208.1 v2(250.95,208.52) ; R205.1 v2(250.9,213.14)
  TOP w0.457: U22.R14 v3(109.33,155.2) ; U22.R15 v3(108.33,155.2)
  TOP w0.508: v2(249.81,209.55) 249.51,209.84 U58.1 ; v2(249.94,203.33) 249.64,203.62 U18.1
  BOTTOM w0.305: R726.1 109.83,153.72 R720.1
  BOTTOM w0.457: R720.1 109.83,154.71 v3(109.33,155.2) C827.1 v3(108.33,155.2) C828.1
  BOTTOM w0.508: v2(249.94,203.33) 249.64,203.62 C112.1 ; C144.1 249.51,209.84 v2(249.81,209.55)
  vias: v2(113.78,138.3) v2(113.78,137.67) v4(39.12,116.92) v4(39.07,114.53) v4(40.31,115.77)
VDD: length 225.2
  TOP w0.457: v3(95.33,168.19) U22.AG27 ; v3(94.33,165.19) U22.AD28 ; v3(93.33,161.2) U22.AA29 ; L5.1 92.5,220.04 93.31,220.85 R76.1 ; U22.W21 v3(102.33,159.2) ; U22.U19 v3(104.33,157.2) ; U22.AA19 v3(104.33,161.2) ; v3(99.33,168.19) U22.AG23 ; v3(96.33,169.19) U22.AH26 ; v3(93.33,159.2) U22.W29 ; v3(97.33,159.2) U22.W25 ; v3(96.33,160.2) U22.Y26 ; v3(98.33,158.2) U22.V24 ; U22.AD18 v3(105.33,165.2) ; v3(93.33,157.2) U22.U29 ; U22.AH16 v3(107.33,169.2) ; U22.V18 v3(105.33,158.2) ; v3(99.33,159.2) U22.W23 ; U22.V28 v3(94.33,158.2) ; U22.AJ17 v3(106.33,170.2) ; U22.AK16 v3(107.33,171.2) ; v3(98.33,169.19) U22.AH24 ; v3(97.33,157.2) U22.U25 ; U22.V20 v3(103.33,158.2) ; U22.AF16 v3(107.33,167.2) ; U22.AF18 v3(105.33,167.2) ; U22.AC29 v3(93.33,163.2) ; U22.W17 v3(106.33,159.2) ; U22.AC23 v3(99.33,163.2) ; v3(96.33,165.19) U22.AD26 ; v3(104.33,163.19) U22.AC19 ; U22.V16 v3(107.33,158.2) ; U22.AA23 v3(99.33,161.2) ; U22.AK18 v3(105.33,171.2) ; U22.AJ19 v3(104.33,170.2) ; U22.AG21 v3(102.33,168.2) ; v3(96.33,167.19) U22.AF26 ; v3(106.33,163.19) U22.AC17 ; U22.AC25 v3(97.33,163.2) ; v3(96.33,162.2) U22.AB26 ; U22.AA21 v3(102.33,161.2) ; U22.AE29 v3(93.33,166.19) ; v3(95.33,157.2) U22.U27 ; v3(95.33,166.19) U22.AE27 ; U22.AD20 v3(103.33,165.2) ; U22.U17 v3(106.33,157.2) ; v3(93.33,168.19) U22.AG29 ; v3(98.33,162.2) U22.AB24 ; U22.T16 v3(107.33,156.2) ; v3(98.33,165.19) U22.AD24 ; U22.AF20 v3(103.33,167.2) ; U22.Y16 v3(107.33,160.2) ; v3(94.33,167.19) U22.AF28 ; v3(96.33,158.2) U22.V26 ; R52.1 73.6,221.22 74.41,220.41 L4.1 ; U22.U21 v3(102.33,157.2) ; v3(94.33,169.19) U22.AH28 ; v3(94.33,162.2) U22.AB28 ; U22.AA17 v3(106.33,161.2) ; U22.AK20 v3(103.33,171.2) ; U22.V22 v3(101.33,158.2) ; U22.AG17 v3(106.33,168.2) ; U22.AB22 v3(101.33,162.2) ; U22.AB16 v3(107.33,162.2) ; U22.AD16 v3(107.33,165.2) ; v3(94.33,160.2) U22.Y28 ; v3(97.33,168.19) U22.AG25 ; U22.AG19 v3(104.33,168.2) ; v3(97.33,166.19) U22.AE25 ; U22.AF22 v3(101.33,167.2) ; U22.W19 v3(104.33,159.2) ; U22.AH22 v3(101.33,169.2) ; U22.AA25 v3(97.33,161.2) ; v3(95.33,159.2) U22.W27 ; U22.Y20 v3(103.33,160.2) ; v3(98.33,167.19) U22.AF24 ; v3(99.33,157.2) U22.U23 ; U22.AE19 v3(104.33,166.2) ; U22.AC27 v3(95.33,163.2) ; U22.Y22 v3(101.33,160.2) ; U22.AH18 v3(105.33,169.2) ; U22.AD22 v3(101.33,165.2) ; U22.AB18 v3(105.33,162.2) ; v3(99.33,166.19) U22.AE23 ; U22.AB20 v3(103.33,162.2) ; U22.AH20 v3(103.33,169.2) ; v3(102.33,163.19) U22.AC21 ; U22.Y24 v3(98.33,160.2) ; U22.AE17 v3(106.33,166.2) ; v3(95.33,161.2) U22.AA27 ; U22.AJ21 v3(102.33,170.2) ; U22.AE21 v3(102.33,166.2) ; U22.Y18 v3(105.33,160.2)
  TOP w0.508: R285.2 63.6,142.11 62.94,141.45 62.94,138.63 63.86,137.72 70.46,137.72 v2(71.45,138.71)
  TOP w0.914: 113.7,206.63 BH9.1 ; BH9.1 117.43,206.63 ; BH9.1 113.7,202.9 ; BH9.1 117.43,202.9
  L7_INT_3 w0.914: BH9.1 117.43,206.63 ; BH9.1 117.43,202.9 ; BH9.1 113.7,202.9 ; BH9.1 113.7,206.63
  L8_PWR_1 w0.914: BH9.1 117.43,202.9 ; BH9.1 117.43,206.63 ; BH9.1 113.7,202.9 ; BH9.1 113.7,206.63
  L9_PWR_2 w0.914: BH9.1 117.43,206.63 ; BH9.1 113.7,202.9 ; BH9.1 117.43,202.9 ; BH9.1 113.7,206.63
  L10_INT_4 w0.914: 113.7,206.63 BH9.1 ; BH9.1 117.43,202.9 ; BH9.1 113.7,202.9 ; BH9.1 117.43,206.63
  BOTTOM w0.381: v3(96.33,162.2) C724.1 v3(97.33,163.2) ; C699.1 v3(99.33,163.2)
  BOTTOM w0.457: C642.1 v3(102.33,170.2) ; C789.1 v3(99.33,166.19) ; v3(106.33,166.2) C681.1 ; v3(105.33,171.2) C641.1 ; C725.1 v3(95.33,163.2) ; v3(103.33,171.2) C631.1 ; v3(93.33,157.2) C701.1 ; v3(99.33,159.2) C760.1 ; C630.1 v3(107.33,171.2) ; v3(103.33,162.2) 102.88,162.65 C721.1 102.84,162.69 v3(102.33,163.19) ; C687.1 v3(96.33,167.19) ; C763.1 v3(107.33,165.2) C694.1 ; C688.1 v3(94.33,167.19) ; C736.1 v3(94.33,165.19) ; C744.1 v3(105.33,165.2) C751.1 ; C682.1 v3(104.33,166.2) ; C758.1 v3(104.33,159.2) ; C757.1 v3(106.33,159.2) ; v3(94.33,169.19) C664.1 ; v3(101.33,162.2) 101.82,162.69 C697.1 ; C659.1 v3(93.33,159.2) ; v3(94.33,160.2) C762.1 ; v3(97.33,159.2) C761.1 ; C756.1 v3(101.33,167.2) ; C778.1 v3(96.33,165.19) C723.1 ; C750.1 v3(96.33,160.2) ; C706.1 v3(98.33,165.19) ; C661.1 v3(93.33,161.2) ; C759.1 v3(102.33,159.2) ; C672.1 v3(107.33,160.2) ; C734.1 v3(97.33,161.2) ; C700.1 v3(93.33,163.2) ; C790.1 v3(104.33,157.2) ; v3(105.33,167.2) C670.1 ; C749.1 v3(98.33,160.2) ; C647.1 v3(107.33,169.2) ; v3(106.33,161.2) C695.1 ; C722.1 v3(101.33,165.2) ; C676.1 v3(93.33,168.19) ; C720.1 v3(106.33,163.19) ; C746.1 v3(97.33,166.19) ; C771.1 v3(102.33,166.2) ; C774.1 v3(101.33,158.2) ; C662.1 v3(98.33,169.19) ; C733.1 v3(98.33,162.2) ; C745.1 v3(103.33,165.2) C713.1 ; C696.1 v3(105.33,158.2) ; v3(95.33,161.2) C735.1 ; C729.1 v3(106.33,168.2) ; v3(104.33,168.2) C711.1 ; C712.1 v3(101.33,169.2) C804.1 ; C726.1 v3(95.33,166.19) ; C748.1 v3(99.33,161.2) ; C747.1 v3(101.33,160.2) ; v3(107.33,167.2) C669.1 ; C732.1 v3(102.33,161.2) ; C772.1 v3(103.33,167.2) ; C773.1 v3(103.33,158.2) ; C685.1 v3(98.33,167.19) ; v3(96.33,169.19) C663.1 ; C777.1 v3(95.33,159.2) ; C775.1 v3(98.33,158.2) ; C673.1 v3(99.33,168.19) ; v3(107.33,162.2) C658.1 ; C684.1 v3(107.33,158.2) ; C791.1 v3(102.33,157.2) ; C671.1 v3(102.33,168.2) ; v3(105.33,162.2) C730.1 ; v3(99.33,157.2) C792.1 ; C674.1 v3(97.33,168.19) ; v3(106.33,170.2) C640.1 ; C698.1 v3(106.33,157.2) ; v3(104.33,170.2) C649.1 ; v3(95.33,157.2) C794.1 ; C793.1 v3(97.33,157.2) ; C660.1 v3(103.33,169.2) ; C675.1 v3(95.33,168.19) ; C686.1 v3(103.33,160.2) ; C648.1 v3(105.33,169.2) ; C731.1 v3(104.33,161.2) ; v3(105.33,160.2) C683.1 ; C707.1 v3(94.33,162.2) ; C795.1 v3(93.33,166.19) ; C987.1 v3(94.33,158.2) ; C776.1 v3(96.33,158.2)
  BOTTOM w0.914: 113.64,206.69 BH9.1 ; BH9.1 117.48,202.85 ; BH9.1 117.48,206.69 ; BH9.1 113.64,202.85
  vias: v2(98.48,122.28) v2(98.5,121.34) v2(99.62,122.22) v2(99.67,121.34) v4(68.32,216.13) v4(68.39,213.22) v4(70.25,216.13) v4(70.68,213.22) v4(70.81,211.36) v4(72.13,216.11) v4(72.26,206.98) v4(72.53,213.22) v4(73.1,200.58) v4(73.53,198.91) v4(73.58,210.53) v4(73.63,195.35) v4(73.99,204.11) v4(74.85,199.95) v4(76.02,198.83) v4(76.23,195.3) v4(83.04,198.72) v4(83.24,196.76) v4(86.92,200.09) v4(86.9,197.67) v4(92.3,210.57) v4(92.3,208.03) v4(92.3,205.49) v4(92.3,202.95) v4(92.3,200.41) v4(92.3,197.87) v4(94.36,210.59) v4(94.36,208.05) v4(94.36,205.51) v4(94.36,202.97) v4(94.36,200.43) v4(94.36,197.89) v4(96.37,210.54) v4(99.19,201.78) v4(99.19,200.25) v4(99.19,198.73) v4(99.19,197.21) v4(100.43,202.46) v4(100.43,200.94) v4(100.43,199.42) v4(100.43,197.89) v4(100.46,196.6) v4(107.37,204.04) v4(107.39,202.49) v4(107.39,200.96) v4(107.39,199.44) v4(107.39,197.92) v4(114.1,201.88) v4(114.68,198.75) v4(114.76,197.15) v4(115.93,198.3) v4(118.85,206.22) v4(118.82,204.65) v4(120.27,202.08) v4(120.29,200.84) v4(120.27,197.89) v4(120.42,206.22)
VDD_2V5_AUX: length 5.6
  TOP w0.254: v2(81.46,226.36) 81.67,226.15 C86.1
  BOTTOM w0.254: U3.22 81.64,226.18 v2(81.46,226.36) 81.36,226.47 R64.1 ; R62.1 v2(77.48,225.83) R63.1
  BOTTOM w0.381: v2(76.87,224.4) 77.13,224.4 R61.1 ; R60.1 v2(76.78,221.64)
VDD_ALERT_B: length 221.1
  L5_INT_2 w0.087: v1(55.87,77.6) 55.44,78.03 45.52,78.03 41.12,82.42 41.12,123.11 37.95,126.29 37.95,127.91 38.71,128.68 38.71,172.87 40.31,174.47 40.31,186.08 41.96,187.73 41.96,235.86 44.48,238.38 55.35,238.38 74.4,219.33 77.48,219.33 v6(78.56,220.41)
  BOTTOM w0.118: U3.11 v6(78.56,220.41)
VDD_ASEL0: length 3
  BOTTOM w0.254: U3.16 79.49,222.91 79.24,222.66 R5806.1 R60.2
VDD_ASEL1: length 3.1
  BOTTOM w0.254: U3.17 78.96,223.41 R5808.1 R61.2
VDD_COMP0: length 16.6
  L5_INT_2 w0.102: v6(86.56,216.94) 86.56,227.24 v2(84.91,228.89)
  BOTTOM w0.254: v6(86.56,216.94) 86.57,216.95 C5270.1 86.57,218.58 85.64,219.52 U3.1 ; R57.1 v2(84.91,228.89)
VDD_COMP1: length 1.6
  BOTTOM w0.254: U3.29 85.14,226.07 84.91,226.29 R57.2
VDD_FA_VDD: length 0.7
  TOP w0.457: v3(89.33,155.2) U22.R33
VDD_FB0: length 5.3
  BOTTOM w0.118: C5272.1 88.71,217.96 C5270.2 ; C5270.2 87.57,218.85 86.71,219.71 86.71,220.14 86.58,220.27 86.43,220.27 U3.40 ; C5270.2 C5271.2
VDD_FB1: length 2.1
  BOTTOM w0.254: R58.2 85.64,225.8 U3.30
VDD_FREQ_CFG: length 3
  BOTTOM w0.254: U3.20 79.55,224.91 79.2,225.26 R63.2 R5809.1
VDD_IAVG0: length 5.7
  TOP w0.118: R66.2 C115.1 87.35,220.5 87.35,219.76 v2(87.7,219.41)
  BOTTOM w0.118: U3.39 86.86,220.91 87.35,220.42 87.35,219.76 v2(87.7,219.41)
VDD_IAVG1: length 2.8
  TOP w0.118: R66.1 C116.1 86.99,224.6 86.99,225.29 v2(87,225.3)
  BOTTOM w0.118: v2(87,225.3) 86.6,224.91 U3.31
VDD_ISENSE0+: length 31
  TOP w0.381: R5814.2 v2(67.43,222.36)
  L12_INT_5 w0.254: v6(87.83,220.76) 87.64,220.95 87.33,220.95 85.78,219.41 81.16,219.41 80.25,218.49 66.24,218.49 65.28,219.45 65.28,221.29 65.96,221.97 67.03,221.97 v2(67.43,222.36)
  BOTTOM w0.254: U3.38 87.19,221.41 v6(87.83,220.76)
VDD_ISENSE0-: length 29.1
  TOP w0.381: R52.2 v2(67.4,221.22)
  L12_INT_5 w0.254: v6(87.83,221.76) 87.54,221.46 87.11,221.46 85.62,219.96 81,219.96 80.04,219 66.45,219 65.79,219.66 65.79,221.08 66.17,221.46 67.15,221.46 v2(67.4,221.22)
  BOTTOM w0.254: U3.37 87.69,221.91 v6(87.83,221.76)
VDD_ISENSE1+: length 15.9
  TOP w0.254: R75.2 v2(99.57,221.99)
  L12_INT_5 w0.254: v2(99.57,221.99) 99.34,221.77 94.5,221.77 91.32,224.94 88.82,224.94 v2(88.57,225.2)
  BOTTOM w0.254: v2(88.57,225.2) 88.46,225.09 87.91,225.09 C5275.2 87.22,224.41 U3.32
VDD_ISENSE1-: length 15.8
  TOP w0.254: R76.2 v2(99.57,220.85)
  L12_INT_5 w0.254: v2(88.54,224.28) 89.05,224.28 89.2,224.43 91.11,224.43 94.28,221.26 99.16,221.26 v2(99.57,220.85)
  BOTTOM w0.254: v2(88.54,224.28) 88.29,224.04 C5275.1 87.72,223.91 U3.33
VDD_LP: length 2.1
  TOP w0.457: v3(94.33,155.2) U22.R28
  BOTTOM w0.305: R717.2 93.83,155.7 v3(94.33,155.2)
  BOTTOM w0.457: C831.1 v3(94.33,155.2)
  vias: v2(67.94,142.24) v2(67.94,140.08)
VDD_OVDD_P1V8: length 14.1
  TOP w0.457: v3(92.33,157.2) U22.U30 ; v3(92.33,159.2) U22.W30 ; U22.AK14 v3(109.33,171.2) ; v3(92.33,156.2) U22.T30 ; v3(92.33,161.2) U22.AA30 ; v3(92.33,160.2) U22.Y30 ; v3(92.33,155.2) U22.R30 ; v3(92.33,158.2) U22.V30
  BOTTOM w0.457: C737.1 v3(92.33,161.2) ; C629.1 v3(109.33,171.2) ; v3(92.33,156.2) C819.1 ; C796.1 v3(92.33,157.2) ; v3(92.33,155.2) C832.1 ; C752.1 v3(92.33,160.2) ; C779.1 v3(92.33,158.2) ; C764.1 v3(92.33,159.2) ; v3(87.33,156.2) C821.1 v3(88.33,156.2)
  vias: v4(34.82,119.71) v4(35.97,120.9) v4(37.21,119.66)
VDD_PH1_FLT: length 7.9
  TOP w0.457: R5814.1 73.54,222.36 74.41,223.24 L4.2
VDD_PH2_FLT: length 7.9
  TOP w0.457: L5.2 92.5,222.87 93.38,221.99 R75.1
VDD_PHAS_CFG: length 2
  BOTTOM w0.254: U3.21 81.14,225.78 80.34,226.58 v6(80.34,227.23)
VDD_PWM0: length 15.2
  TOP w0.254: v2(79.46,229.29) 79.13,229.61 U9.1
  L3_INT_1 w0.254: v2(79.46,229.29) 80.52,229.29 82.64,227.17 v2(82.64,218.29)
  BOTTOM w0.254: U3.7 v2(82.64,218.29)
VDD_PWM1: length 17.2
  TOP w0.254: v2(97.55,228.78) 97.55,229.05 97.35,229.24 U7.1
  L3_INT_1 w0.254: v2(97.55,228.78) 97.55,227.69 96.27,226.42 87.54,226.42 86.99,225.87 84.85,225.87 v2(84.34,226.38)
  BOTTOM w0.254: v2(84.34,226.38) 84.14,226.18 U3.27
VDD_S1VDD: length 12.2
  TOP w0.457: U22.P20 v3(103.33,155.2) ; U22.N17 v3(106.33,153.2) ; U22.T19 v3(104.33,156.2) ; U22.T21 v3(102.33,156.2) ; U22.T22 v3(101.33,156.2) ; U22.P22 v3(101.33,154.2) ; U22.T20 v3(103.33,156.2)
  BOTTOM w0.305: R733.2 105.83,152.69 v3(106.33,153.2)
  BOTTOM w0.457: v3(103.33,155.2) C808.1 ; v3(101.33,154.2) C830.1 ; v3(103.33,156.2) C809.1 v3(102.33,156.2) C810.1 v3(101.33,156.2) C811.1 ; v3(104.33,156.2) C807.1 ; v3(106.33,153.2) C829.1
  vias: v2(109.35,127.25) v2(109.47,126.62) v2(110.62,127.25) v2(110.62,126.62)
VDD_S2VDD: length 7.9
  TOP w0.457: v3(99.33,154.2) U22.P23 ; v3(97.33,156.2) U22.T25 ; v3(97.33,154.2) U22.P25 ; v3(98.33,156.2) U22.T24 ; v3(96.33,156.2) U22.T26 ; v3(99.33,156.2) U22.T23
  BOTTOM w0.457: C818.1 v3(96.33,156.2) ; C824.1 v3(97.33,154.2) ; C813.1 v3(98.33,156.2) ; C801.1 v3(97.33,156.2) ; C812.1 v3(99.33,156.2)
  vias: v2(103.76,127.25) v2(103.76,126.62) v2(106.05,127.25) v2(106.05,126.62)
VDD_S3VDD: length 10.7
  TOP w0.457: v3(99.33,172.19) U22.AL23 ; v3(99.33,170.19) U22.AJ23 ; v3(97.33,172.19) U22.AL25 ; U22.AJ22 v3(101.33,170.2) ; v3(97.33,170.19) U22.AJ25 ; U22.AM20 v3(103.33,173.2) ; v3(98.33,170.19) U22.AJ24
  BOTTOM w0.305: R694.2 102.82,173.71 v3(103.33,173.2)
  BOTTOM w0.457: C644.1 v3(98.33,170.19) ; C651.1 v3(97.33,170.19) ; C626.1 v3(103.33,173.2) ; v3(97.33,172.19) C636.1 ; C632.1 v3(99.33,172.19) ; C650.1 v3(99.33,170.19) ; v3(101.33,170.2) C643.1
  vias: v2(72.45,165.2) v2(72.64,163.07) v2(73.09,165.2) v2(73.37,163.02)
VDD_S4VDD: length 4.2
  TOP w0.457: v3(95.33,170.19) U22.AJ27 ; v3(96.33,170.19) U22.AJ26 ; U22.AL26 v3(96.33,172.19) ; v3(94.33,170.19) U22.AJ28 ; v3(93.33,170.19) U22.AJ29 ; U22.AL28 v3(94.33,172.19)
VDD_SCL: length 60
  L3_INT_1 w0.087: J106.4 126.55,240.59 125.81,239.85 124.87,239.85 113.47,228.45 102.32,228.45 94.08,220.22 85.95,220.22 82.52,216.79 81.38,216.79 81.23,216.94 v6(80.72,216.94)
  BOTTOM w0.118: U3.9 81.64,218.62 80.72,217.7 v6(80.72,216.94) R627.1
VDD_SDA: length 61.3
  L3_INT_1 w0.087: J106.2 126.57,238.6 125.81,239.37 124.97,239.37 113.77,228.17 102.49,228.17 94.21,219.89 86.03,219.89 82.66,216.52 80.13,216.52 v6(79.71,216.94)
  BOTTOM w0.118: U3.10 81.14,219.14 79.71,217.7 v6(79.71,216.94) R629.2
VDD_SENSE0+: length 50
  TOP w0.381: v6(122.02,214.88) R53.2
  L12_INT_5 w0.254: v2(89.28,222.81) 93.38,218.71 104.31,218.71 107.69,222.09 122.46,222.09 124.74,219.81 124.74,217.6 v6(122.02,214.88)
  BOTTOM w0.254: U3.36 88.46,222.41 R65.1 88.74,222.28 v2(89.28,222.81)
VDD_SENSE0-: length 46.7
  L12_INT_5 w0.254: v3(87.73,222.91) 88.46,222.91 93.17,218.2 104.52,218.2 107.9,221.58 122.25,221.58 124.23,219.6 124.23,217.83 123.67,217.27 122.87,217.27 v6(122.02,218.11)
  BOTTOM w0.254: U3.35 v3(87.73,222.91)
VDD_SENSE_N: length 116.6
  L5_INT_2 w0.152: v3(112.33,156.2) 111.86,156.66 111.86,163.5 110.87,164.49 107.26,164.49 106.83,164.92 106.83,172.42 106.54,172.71 105.82,172.71 v3(105.33,173.2)
  L12_INT_5 w0.102: 103.1,186.15 103.18,186.15 103.73,185.6 103.73,176.89 104.01,176.61 105.55,176.61 105.74,176.42 105.74,172.93 105.61,172.8 105.44,172.8 105.33,172.9 v3(105.33,173.2)
  L12_INT_5 w0.152: v6(122.02,217.09) 121.64,216.71 119.57,216.71 118.5,215.65 109.17,215.65 109.12,215.6 108.98,215.6 102.64,209.26 102.64,188.99 102.67,188.96 102.67,186.59 103.1,186.15
  L14_INT_6 w0.152: v3(112.33,156.2) 111.84,156.69 111.84,160.26 111.45,160.66 89.18,160.66 88.82,161.01 88.82,161.7 v3(88.33,162.2)
  BOTTOM w0.254: R716.2 v3(112.33,156.2) ; R696.2 v3(105.33,173.2) ; v3(88.33,162.2) R707.2 R706.2
VDD_SENSE_P: length 117.4
  L5_INT_2 w0.152: v3(112.33,154.2) 111.84,154.69 111.07,154.69 110.82,154.94 110.82,163.55 110.39,163.98 106.43,163.98 105.84,164.57 105.84,171.68 v3(105.33,172.2)
  L12_INT_5 w0.102: v3(105.33,172.2) 105.33,172.49 105.43,172.59 105.69,172.59 105.94,172.84 105.94,176.51 105.64,176.81 104.1,176.81 103.94,176.97 103.94,185.68 103.27,186.35 103.27,186.39
  L12_INT_5 w0.152: 103.27,186.39 102.92,186.74 102.92,188.93 103.05,189.06 103.05,209.09 109.14,215.19 109.28,215.19 109.34,215.24 118.67,215.24 119.74,216.31 121.62,216.31 v6(122.02,215.9)
  L14_INT_6 w0.152: v3(112.33,154.2) 111.89,154.64 111.89,155.45 111.63,155.7 111.07,155.7 110.79,155.98 110.79,159.38 110.46,159.72 88.85,159.72 v3(88.33,159.2)
  BOTTOM w0.254: v3(112.33,154.2) 111.84,153.7 R725.2 ; v3(88.33,159.2) R710.2 R709.2 ; v3(105.33,172.2) R699.2
VDD_SGND: length 19.2
  TOP w0.254: v2(79.66,228.09) 81.1,228.09 81.36,227.83 R5810.2
  TOP w0.381: Q1.3 102.28,226.31 101.47,225.5 v2(101.47,225.49) 101.26,225.28 Q1.1 ; C93.2 v2(85.55,226.47) ; Q2.3 67.1,226.84 v2(66.32,226.06) 66.08,225.82 Q2.1 ; v5(85.17,224.43) C116.2 ; v5(85.17,221.13) C115.2 ; v5(81.61,224.43) C86.2
  BOTTOM w0.254: R5809.2 v2(77.48,226.82) R5807.2 ; v5(83.39,221.13) 83.39,220.88 83.64,220.63 U3.5
  BOTTOM w0.381: C93.2 85.55,226.7 v2(85.55,226.47) ; R5806.2 v2(76.76,222.66) ; R5808.2 77.32,223.58 v2(76.86,223.58) ; R5813.1 101.52,225.53 v2(101.47,225.49) ; C5269.1 66.6,224.5 v2(66.6,223.96) ; R59.2 79.82,228.24 v2(79.66,228.09) ; C101.1 v2(101.8,223.17)
  vias: v5(81.61,222.66) v5(81.61,221.13) v5(83.39,224.43) v5(83.39,222.66) v5(85.17,222.66)
VDD_SH_CLK: length 1.7
  BOTTOM w0.254: U3.24 82.64,226.84 R48.2
VDD_SH_SYNC: length 3.1
  BOTTOM w0.118: R47.2 82.75,217.5 82.14,218.11 U3.8
VDD_SH_WP: length 3
  BOTTOM w0.118: U3.23 82.14,226.45 81.86,226.72 81.86,227.74 R59.1
VDD_TH_VDD: length 0.7
  TOP w0.457: v3(90.33,158.2) U22.V32
VDD_TMON0: length 3.7
  TOP w0.118: U9.30 77.59,228.32 v2(77.97,227.94)
  BOTTOM w0.118: R50.1 77.42,228.49 v2(77.97,227.94) 78.48,228.45 C97.1
VDD_TMON1: length 3.8
  TOP w0.118: U7.30 95.68,227.95 v2(96.06,227.57)
  BOTTOM w0.118: C127.1 96.56,227.7 96.43,227.57 v2(96.06,227.57) 96.06,228.07 R78.1
VDD_TSNS0: length 23.6
  TOP w0.381: v2(103.05,223.16) 103.29,223.41 Q1.2
  L3_INT_1 w0.254: v2(85.84,218.39) 86.35,218.39 86.45,218.29 99.29,218.29 103.05,222.05 v2(103.05,223.16)
  BOTTOM w0.254: U3.2 85.14,219.09 v2(85.84,218.39)
  BOTTOM w0.381: v2(103.05,223.16) 103.05,223.57 C101.2
VDD_TSNS1: length 23.6
  TOP w0.381: v2(67.79,223.9) 68.12,224.22 Q2.2
  L5_INT_2 w0.254: v2(67.79,223.9) 72.9,218.8 84.45,218.8 v2(85.15,218.1)
  BOTTOM w0.254: v2(85.15,218.1) 84.64,218.61 U3.3
  BOTTOM w0.381: v2(67.79,223.9) 67.79,224.51 C5269.2
VDD_VOUT_CFG: length 7.6
  L12_INT_5 w0.203: v2(76.52,225.13) 78,225.13 78.96,224.17 v2(79.75,224.17)
  BOTTOM w0.203: R62.2 75.77,225.38 76.02,225.13 v2(76.52,225.13) ; U3.18 80.01,223.91 v2(79.75,224.17) 79.75,224.2 79.95,224.41 U3.19
  BOTTOM w0.254: R5807.1 R62.2
VDD_VSENSE1+: length 2.4
  BOTTOM w0.254: U3.34 87.91,223.41 88.02,223.29 R65.2
VDD_X1VDD: length 12.5
  TOP w0.457: U22.K16 v3(107.33,150.2) ; U22.K21 v3(102.33,150.2) ; U22.K15 v3(108.33,150.2) ; U22.K19 v3(104.33,150.2) ; U22.K17 v3(106.33,150.2) ; U22.K18 v3(105.33,150.2) ; U22.K20 v3(103.33,150.2) ; U22.K22 v3(101.33,150.2)
  BOTTOM w0.305: R738.2 100.46,150.12 100.46,150.24 C856.1
  BOTTOM w0.457: C854.1 v3(103.33,150.2) ; C852.1 v3(105.33,150.2) ; C850.1 v3(107.33,150.2) ; C853.1 v3(104.33,150.2) ; C856.1 v3(101.33,150.2) ; v3(102.33,150.2) C855.1 ; C851.1 v3(106.33,150.2) ; C849.1 v3(108.33,150.2)
  vias: v2(109.78,137.52) v2(109.78,136.42) v2(110.49,137.54) v2(110.49,136.4)
VDD_X2VDD: length 13.4
  TOP w0.457: v3(92.33,150.2) U22.K30 ; v3(96.33,150.2) U22.K26 ; v3(94.33,150.2) U22.K28 ; v3(95.33,150.2) U22.K27 ; v3(98.33,150.2) U22.K24 ; v3(97.33,150.2) U22.K25 ; v3(93.33,150.2) U22.K29 ; v3(92.33,152.2) U22.M30 ; v3(99.33,150.2) U22.K23
  BOTTOM w0.457: C865.1 v3(93.33,150.2) R737.2 ; C858.1 v3(98.33,150.2) ; C844.1 91.82,151.69 v3(92.33,152.2) ; v3(95.33,150.2) C863.1 ; C846.1 v3(97.33,150.2) ; C866.1 v3(92.33,150.2) ; v3(96.33,150.2) C862.1 ; C861.1 v3(99.33,150.2) ; v3(94.33,150.2) C864.1
  vias: v2(92.84,131.86) v2(92.84,130.99) v2(93.85,131.86) v2(93.85,130.96)
VDD_X3VDD: length 17.8
  TOP w0.457: U22.AR23 v3(99.33,176.19) U22.AR24 v3(98.33,176.19) U22.AR25 v3(97.33,176.19) ; U22.AR21 v3(102.33,176.2) U22.AR20 ; U22.AR21 v3(101.33,176.2) U22.AR22 v3(101.33,175.2) U22.AR21 ; U22.AR19 v3(104.33,175.2) U22.AR18 v3(105.33,176.2)
  L12_INT_5 w0.33: v3(105.33,176.2) v3(104.33,175.2)
  BOTTOM w0.305: C597.1 97.83,175.69 R693.2
  BOTTOM w0.457: C596.1 v3(99.33,176.19) C595.1 ; C612.1 v3(105.33,176.2) ; C606.1 v3(102.33,176.2) ; v3(101.33,176.2) 100.8,176.72 C593.1 ; v3(104.33,175.2) C613.1 ; C620.1 v3(101.33,175.2) ; C597.1 v3(98.33,176.19)
  vias: v2(94.74,194.56) v2(94.74,193.93) v2(96.09,194.54) v2(96.09,193.9)
VDD_X4VDD: length 15.6
  TOP w0.457: U22.AR26 v3(96.33,176.19) U22.AR27 v3(95.33,176.19) U22.AR28 ; U22.AR32 v3(90.33,176.19) U22.AR33 ; U22.AR29 v3(93.33,176.19) U22.AR30 v3(92.33,176.19) U22.AR31 ; v3(90.33,174.19) U22.AN33
  BOTTOM w0.457: C603.1 91.85,175.71 v3(92.33,176.19) 92.81,175.71 C602.1 92.85,175.71 v3(93.33,176.19) 93.81,175.71 C601.1 ; C605.1 89.85,175.71 v3(90.33,176.19) 90.81,175.71 C604.1 ; C598.1 v3(96.33,176.19) C599.1 ; C621.1 v3(90.33,174.19) 90.84,173.7 R695.2 ; v3(95.33,176.19) 94.85,175.71 C600.1
  vias: v2(90.68,194.56) v2(90.68,193.93) v2(91.95,194.56) v2(91.95,193.93)
1G_P0_LED_ACT_N: length 42.6
  TOP w0.254: v2(115.47,36.19) 115.85,35.8 115.85,35.44 R642.1 ; U42.100 119.13,58.65 119.33,58.86 119.33,60.32 TP230.1 v2(118.97,61.37)
  L12_INT_5 w0.254: v2(115.47,36.19) 110.7,36.19 108.58,38.3 108.58,54.84 114,60.25 118.01,60.25 118.97,61.21 v2(118.97,61.37)
1G_P0_LINK10_100_N: length 47.6
  TOP w0.254: U42.101 TP231.1 v2(118.63,59.98)
  L3_INT_1 w0.254: v2(118.63,59.98) 114.6,55.96 114.6,46.66 112.6,44.65 v2(112.52,44.65)
  L12_INT_5 w0.254: J11.34 127.66,31.79 127.66,34.98 126.49,36.14 126.49,37.85 125.93,38.4 125.93,40.59 124.76,41.76 117.86,41.76 115.95,43.66 114.02,43.66 113.03,44.65 v2(112.52,44.65)
  BOTTOM w0.254: R5796.1 112.78,44.92 v2(112.52,44.65)
1G_P0_LINK1000_N: length 52.9
  TOP w0.254: R644.1 v2(123.34,35.43) ; v2(117.99,61.08) TP232.1 117.99,58.93 118.13,58.78 U42.102
  L12_INT_5 w0.254: v2(117.99,61.08) 113.41,61.08 107.52,55.19 107.52,37.49 110.77,34.24 122.15,34.24 v2(123.34,35.43)
1G_P0_TXVA_N: length 42
  TOP w0.091: U42.127 115.93,43.91 115.82,44.02 115.06,44.02 114.71,43.66 114.71,41.83 114.94,41.61 115.21,41.61 v2(115.51,41.9)
  L5_INT_2 w0.086: J11.13 126.26,15.33 126.15,15.22 125.96,15.22 125.39,15.8 125.39,17.07 125.45,17.14 125.45,22 124.45,23 124.45,23.97 124.38,24.03 124.38,24.82 124.45,24.89 124.45,25.3 123.46,26.29 123.46,26.65 123.39,26.71 123.39,27.43 123.46,27.5 123.46,29.78 122.63,30.61 122.63,40.97 121.3,42.3 117.15,42.3 116.48,41.63 115.77,41.63 v2(115.51,41.9)
1G_P0_TXVA_P: length 42.1
  TOP w0.091: U42.126 115.93,44.41 115.82,44.3 114.95,44.3 114.43,43.78 114.43,41.72 114.82,41.33 115.27,41.33 v2(115.51,41.08)
  L5_INT_2 w0.086: v2(115.51,41.08) 115.71,41.29 116.62,41.29 117.3,41.96 121.16,41.96 122.29,40.83 122.29,30.46 123.11,29.64 123.11,27.5 123.18,27.43 123.18,26.71 123.11,26.65 123.11,26.14 124.1,25.16 124.1,24.89 124.17,24.82 124.17,24.03 124.1,23.97 124.1,22.86 125.11,21.85 125.11,17.14 125.17,17.07 125.17,15.71 125.87,15.01 125.87,14.73 J11.6
1G_P0_TXVB_N: length 41.9
  TOP w0.091: v2(117.43,39.18) 117.69,39.45 118,39.45 119.02,40.47 119.02,40.97 119.13,41.08 U42.3
  L5_INT_2 w0.086: v2(117.43,39.18) 117.66,39.41 118.2,39.41 118.72,39.93 118.72,40.54 118.95,40.77 120.78,40.77 121.22,40.32 121.22,34.59 120.8,34.16 119.08,34.16 118.62,33.71 118.62,32.59 119.06,32.14 120.41,32.14 120.83,31.72 120.83,28.73 121.14,28.41 121.14,27.53 121.21,27.46 121.21,26.74 121.14,26.68 121.14,26.28 122.12,25.3 122.12,24.91 122.18,24.85 122.18,24.03 122.12,23.96 122.12,23.32 122.77,22.67 122.77,20.08 121.13,18.44 121.13,16.98 121.19,16.92 121.19,15.76 121.68,15.27 123.03,15.27 123.28,15.02 J11.5
1G_P0_TXVB_P: length 42
  TOP w0.091: U42.2 118.63,41.08 118.75,40.97 118.75,40.59 117.88,39.72 117.69,39.72 v2(117.43,39.99)
  L5_INT_2 w0.086: J11.11 123.1,15.86 123.1,15.58 123,15.48 121.77,15.48 121.41,15.85 121.41,16.92 121.47,16.98 121.47,18.3 123.11,19.94 123.11,22.81 122.46,23.46 122.46,23.96 122.4,24.03 122.4,24.85 122.46,24.91 122.46,25.45 121.49,26.42 121.49,26.68 121.42,26.74 121.42,27.46 121.49,27.53 121.49,28.55 121.17,28.87 121.17,31.87 120.55,32.49 119.2,32.49 118.96,32.73 118.96,33.56 119.22,33.82 120.94,33.82 121.57,34.45 121.57,40.46 120.92,41.11 118.81,41.11 118.38,40.68 118.38,40.07 118.06,39.75 117.67,39.75 v2(117.43,39.99)
1G_P0_TXVC_N: length 43.3
  TOP w0.091: U42.5 120.13,41.14 120.02,41.02 120.02,39.51 v2(120.28,39.24)
  L5_INT_2 w0.086: v2(120.28,39.24) 120.07,39.03 120.07,36.35 119.53,35.81 118.16,35.81 117.61,35.27 113.93,35.27 113.72,35.05 113.72,34.24 113.96,33.99 117.01,33.99 117.39,33.62 117.39,32.78 117.01,32.41 114.7,32.41 114.48,32.18 114.48,29.62 114.87,29.22 116.59,29.22 117.52,28.3 117.52,27.52 117.45,27.46 117.45,26.79 117.52,26.72 117.52,26.36 118.5,25.38 118.5,24.92 118.43,24.86 118.43,24.04 118.5,23.97 118.5,22.71 119.49,21.72 119.49,17.14 119.43,17.08 119.43,15.92 119.98,15.36 120.19,15.36 120.31,15.48 J11.10
1G_P0_TXVC_P: length 43.3
  TOP w0.091: v2(119.47,39.24) 119.74,39.51 119.74,41 119.63,41.1 U42.4
  L5_INT_2 w0.086: v2(119.47,39.24) 119.73,38.98 119.73,36.49 119.39,36.16 118.02,36.16 117.47,35.61 113.79,35.61 113.37,35.19 113.37,34.1 113.82,33.65 116.87,33.65 117.04,33.47 117.04,32.92 116.87,32.75 114.56,32.75 114.13,32.32 114.13,29.47 114.73,28.88 116.45,28.88 117.17,28.15 117.17,27.52 117.24,27.46 117.24,26.79 117.17,26.72 117.17,26.22 118.16,25.24 118.16,24.92 118.22,24.86 118.22,24.04 118.16,23.97 118.16,22.57 119.15,21.58 119.15,17.15 119.21,17.08 119.21,15.83 119.93,15.11 119.93,14.7 119.36,14.13 J11.3
1G_P0_TXVD_N: length 42.2
  TOP w0.091: v2(119.13,37.45) 119.39,37.72 120.41,37.72 121.54,38.85 121.54,40.94 121.63,41.04 U42.8
  L5_INT_2 w0.086: v2(119.13,37.45) 118.9,37.68 118.1,37.68 117.58,37.16 111.84,37.16 111.23,36.55 111.23,27.38 112.03,26.58 115.39,26.58 116.53,25.44 116.53,24.93 116.46,24.87 116.46,23.8 116.52,23.74 116.52,21.63 117.51,20.64 117.51,17.21 117.44,17.15 117.44,15.81 116.79,15.15 116.79,14.68 J11.2
1G_P0_TXVD_P: length 42.3
  TOP w0.091: U42.7 121.13,41.07 121.26,40.94 121.26,38.96 120.29,38 119.39,38 v2(119.13,38.27)
  L5_INT_2 w0.086: J11.8 116.35,15.58 116.49,15.44 116.77,15.44 117.23,15.89 117.23,17.15 117.17,17.21 117.17,20.5 116.18,21.49 116.18,23.74 116.25,23.81 116.25,24.87 116.18,24.93 116.18,25.3 115.24,26.24 111.88,26.24 110.88,27.24 110.88,36.69 111.69,37.5 117.43,37.5 117.96,38.02 118.88,38.02 v2(119.13,38.27)
1G_P1_LED_ACT_N: length 29.5
  TOP w0.254: v2(112.47,54.98) TP237.1 113.72,54.91 U42.105 ; v2(116.79,36.22) 116.79,35.86 R641.1
  L12_INT_5 w0.254: v2(116.79,36.22) 116.79,36.93 113.51,40.21 112.01,40.21 109.47,42.75 109.47,52.58 111.88,54.98 v2(112.47,54.98)
1G_P1_LINK10_100_N: length 39.5
  TOP w0.254: U42.106 114.65,54.41 TP236.1 113.7,54.29 113.61,54.2 v2(113.13,54.2) ; R643.1 126.26,35.43 v2(126.47,35.23)
  L12_INT_5 w0.254: v2(113.13,54.2) 112.17,54.2 110.19,52.22 110.19,42.88 112.29,40.77 113.72,40.77 117.42,37.06 117.42,36.25 117.83,35.84 119.58,35.84 120.27,36.53 123.67,36.53 124.26,35.94 124.26,34.72 124.64,34.34 125.58,34.34 v2(126.47,35.23)
1G_P1_LINK1000_N: length 68.7
  TOP w0.254: U42.107 115.35,53.91 114.97,53.53 TP235.1 v2(112.5,53.53)
  L12_INT_5 w0.254: J11.30 124.28,8.99 124.28,14.78 125.27,15.77 125.27,22.35 126.26,23.34 126.26,25.27 129.06,28.07 129.06,35.69 127.64,37.11 127.64,40.18 125.42,42.39 118.03,42.39 116.23,44.2 114.33,44.2 110.85,47.68 110.85,51.55 112.5,53.2 v2(112.5,53.53)
1G_P1_TXVA_N: length 37.3
  TOP w0.091: v2(127.05,38.04) 127.33,37.75 127.52,37.75 127.61,37.85 127.61,38.75 126.92,39.43 126.92,40.06 126.74,40.24 126.74,40.92 126.63,41.03 U42.18
  L14_INT_6 w0.086: v2(127.05,38.04) 126.81,37.8 126.57,37.8 126.35,38.01 126.35,40.73 124.95,42.14 117.6,42.14 115.97,40.51 115.97,32.67 116.97,31.67 116.97,29.18 117.17,28.98 117.17,27.57 117.24,27.51 117.24,26.41 116.71,25.88 116.46,25.88 116.35,25.99 J11.21
1G_P1_TXVA_P: length 37.3
  TOP w0.091: v2(127.05,37.22) 127.08,37.22 127.33,37.47 127.63,37.47 127.89,37.73 127.89,38.86 127.2,39.55 127.2,40.17 127.02,40.35 127.02,40.92 127.13,41.03 U42.19
  L14_INT_6 w0.086: v2(127.05,37.22) 126.82,37.45 126.43,37.45 126.01,37.87 126.01,40.59 124.8,41.8 117.74,41.8 116.31,40.37 116.31,32.81 117.31,31.82 117.31,29.32 117.51,29.12 117.51,27.57 117.45,27.51 117.45,26.32 116.79,25.66 116.79,25.09 J11.15
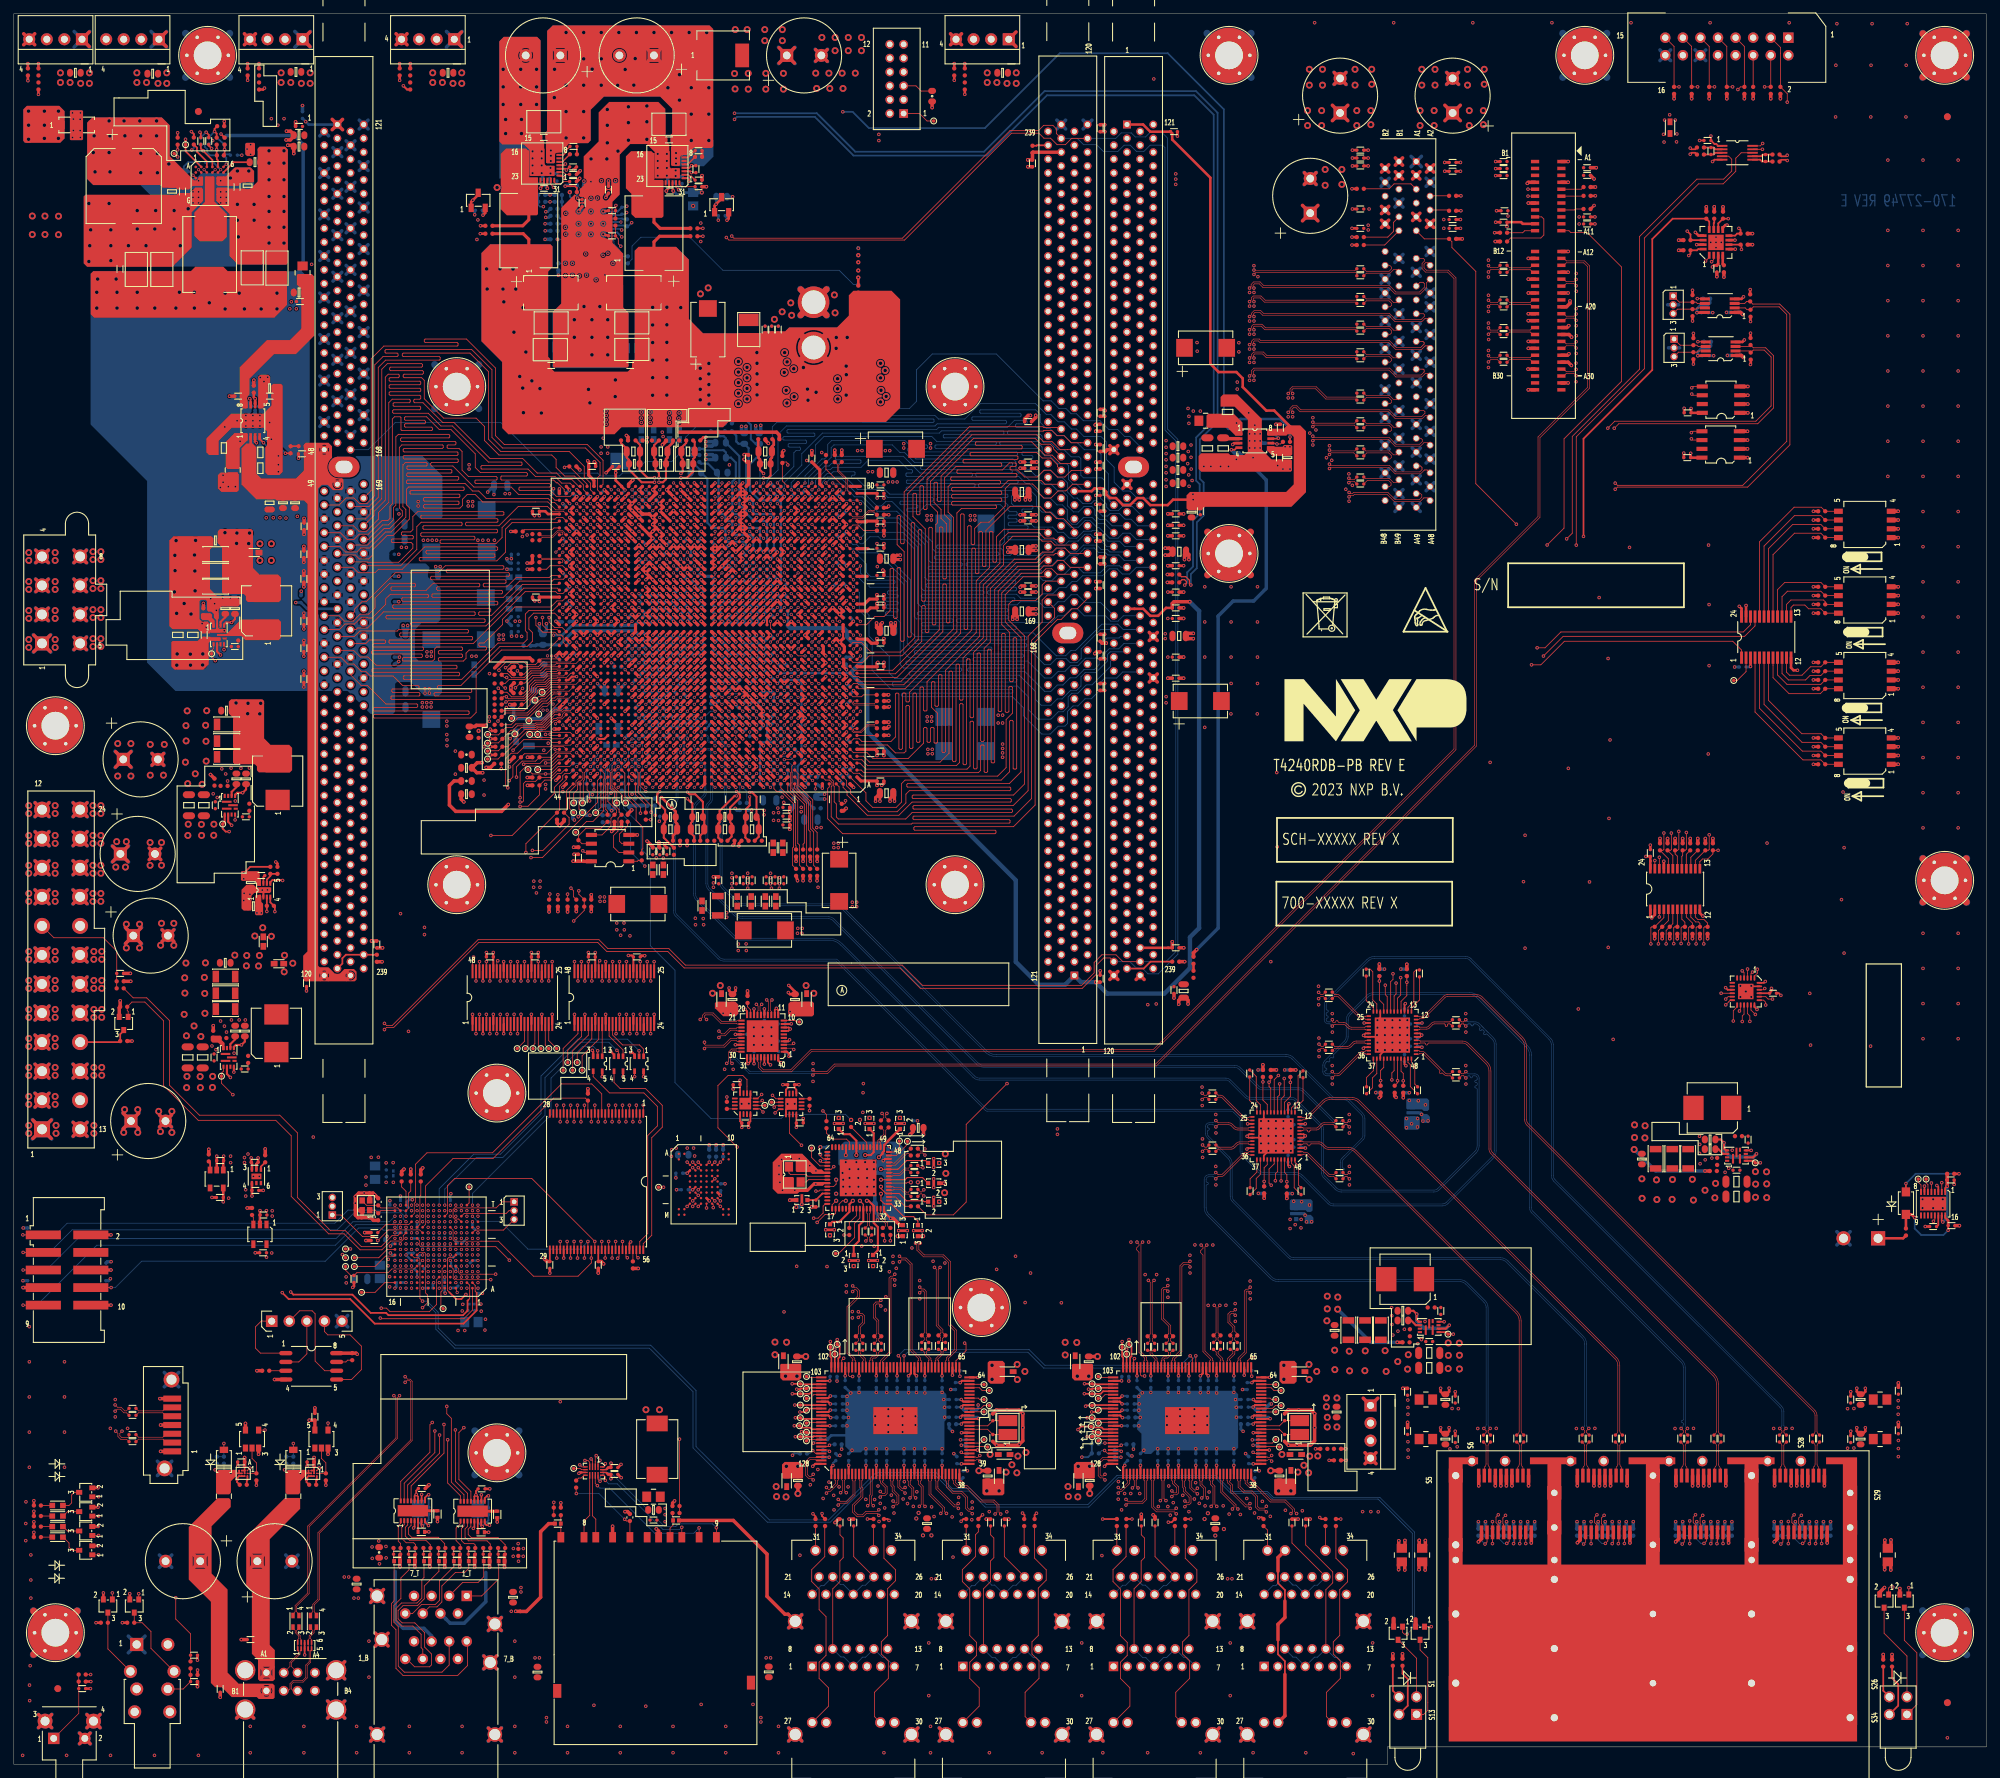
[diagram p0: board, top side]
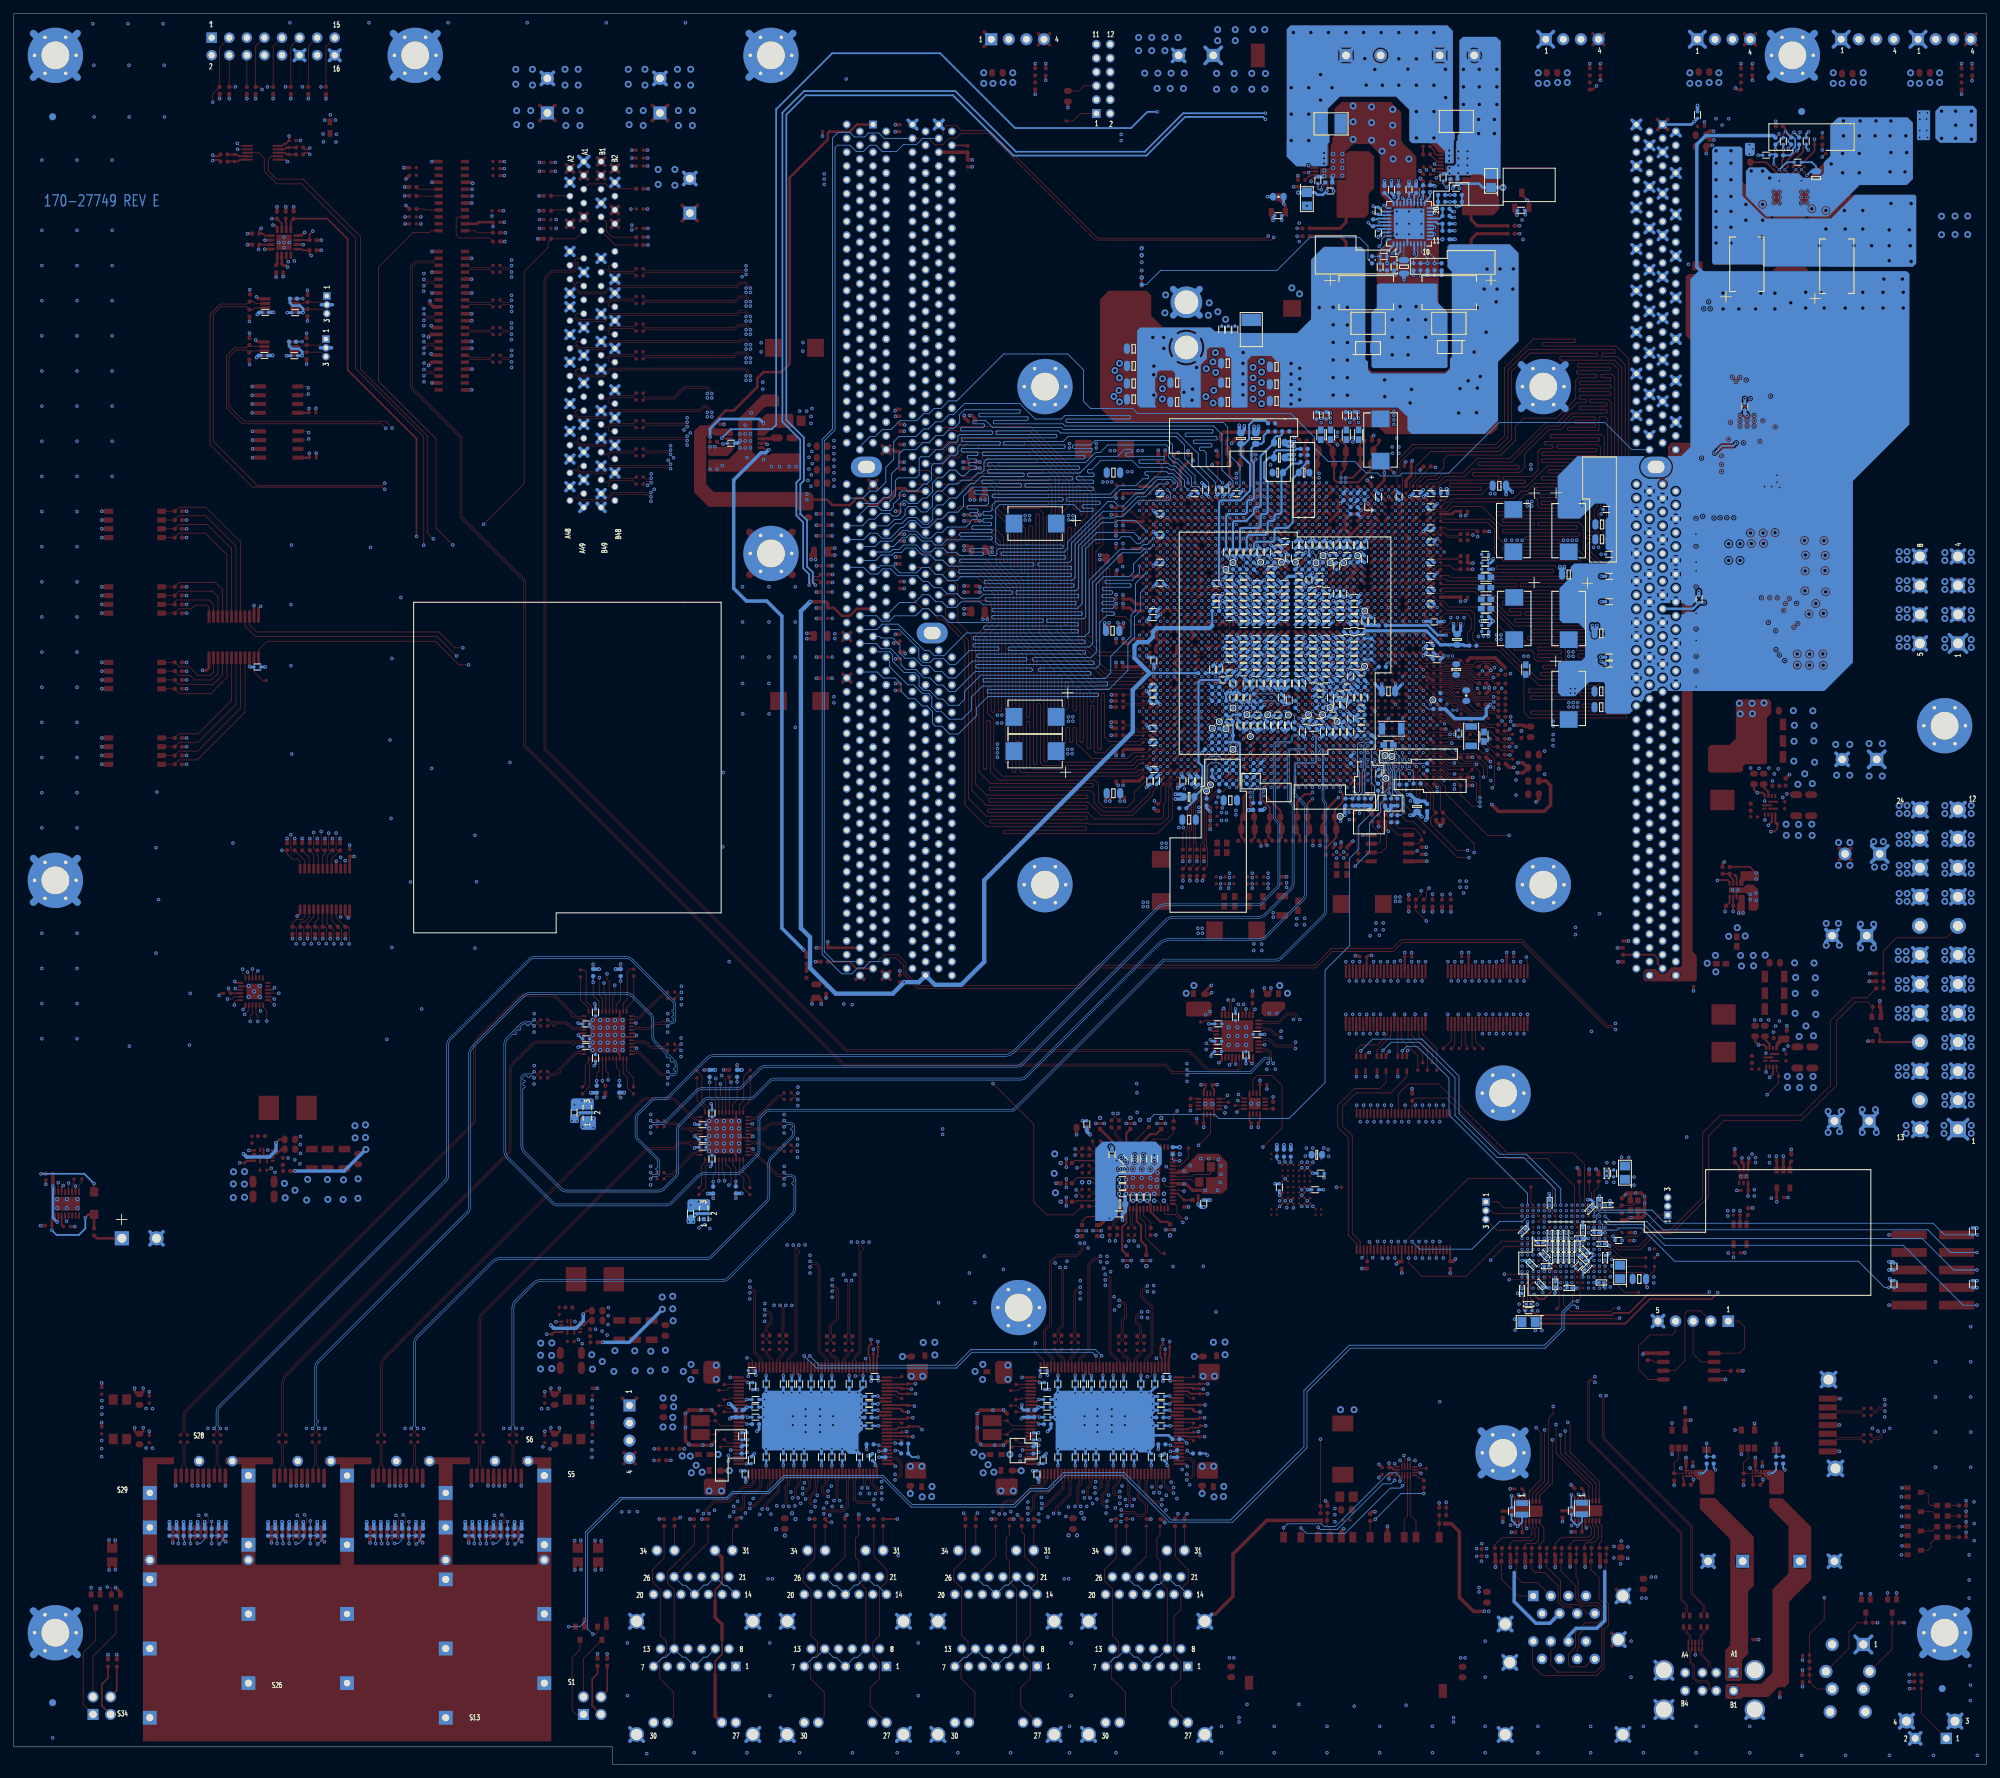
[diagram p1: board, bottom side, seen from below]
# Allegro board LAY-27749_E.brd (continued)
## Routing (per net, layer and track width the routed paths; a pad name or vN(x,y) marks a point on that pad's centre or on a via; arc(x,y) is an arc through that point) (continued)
1G_P1_TXVB_N: length 37.4
  TOP w0.091: v2(125.19,39.41) 125.49,39.12 125.81,39.12 125.91,39.22 125.91,39.99 125.24,40.66 125.24,40.92 125.13,41.03 U42.15
  L14_INT_6 w0.086: J11.16 119.92,25.14 119.92,25.5 119.21,26.21 119.21,27.51 119.15,27.58 119.15,28.88 119.8,29.53 120.58,29.53 120.89,29.83 120.89,30.77 120.81,30.86 119.84,30.86 119.56,31.14 119.56,31.98 119.84,32.26 120.6,32.26 120.79,32.45 120.79,33.56 120.32,34.04 119.36,34.04 119.1,33.78 119.1,33.02 118.68,32.6 117.92,32.6 117.39,33.13 117.39,35.58 118.04,36.23 119.39,36.23 119.62,36.46 119.62,38.39 120.03,38.8 121.43,38.8 121.92,39.29 121.92,40.53 122.21,40.82 123.04,40.82 123.33,40.53 123.33,39.29 123.44,39.18 124.96,39.18 v2(125.19,39.41)
1G_P1_TXVB_P: length 37.5
  TOP w0.091: v2(125.19,38.6) 125.43,38.84 125.92,38.84 126.19,39.1 126.19,40.11 125.52,40.77 125.52,40.92 125.63,41.03 U42.16
  L14_INT_6 w0.086: J11.23 120.31,25.78 120.23,25.7 120.02,25.7 119.43,26.29 119.43,27.51 119.49,27.58 119.49,28.74 119.94,29.18 120.73,29.18 121.23,29.69 121.23,30.91 120.95,31.2 119.99,31.2 119.9,31.28 119.9,31.83 119.99,31.92 120.74,31.92 121.13,32.31 121.13,33.71 120.46,34.38 119.21,34.38 118.76,33.92 118.76,33.16 118.54,32.94 118.06,32.94 117.73,33.27 117.73,35.43 118.19,35.89 119.53,35.89 119.96,36.32 119.96,38.25 120.17,38.46 121.57,38.46 122.27,39.15 122.27,40.39 122.35,40.47 122.9,40.47 122.99,40.39 122.99,39.15 123.3,38.84 124.96,38.84 v2(125.19,38.6)
1G_P1_TXVC_N: length 37.5
  TOP w0.091: U42.12 123.63,41.34 123.75,41.22 123.75,38.98 123.62,38.85 123.62,37.6 v2(123.38,37.36)
  L14_INT_6 w0.086: v2(123.38,37.36) 123.62,37.12 123.62,36.42 123.49,36.3 122.66,36.3 122.48,36.47 122.48,37.34 122.1,37.72 121.23,37.72 120.85,37.34 120.85,35.94 121.88,34.91 121.88,33.72 122.29,33.31 123.29,33.31 123.58,33.6 123.58,34.17 123.66,34.25 124.21,34.25 124.3,34.17 124.3,33.6 124.58,33.31 125.42,33.31 125.7,33.6 125.7,34.17 125.79,34.25 126.34,34.25 126.42,34.17 126.42,33.6 126.71,33.31 127.46,33.31 127.55,33.23 127.55,32.56 127.46,32.47 122.69,32.47 122.22,32.01 122.22,29.66 123.13,28.76 123.13,27.65 123.19,27.58 123.19,26.31 122.59,25.71 122.4,25.71 122.29,25.82 J11.24
1G_P1_TXVC_P: length 37.4
  TOP w0.091: U42.13 124.13,41.33 124.03,41.22 124.03,38.86 123.9,38.73 123.9,37.66 v2(124.19,37.36)
  L14_INT_6 w0.086: v2(124.19,37.36) 123.96,37.13 123.96,36.28 123.64,35.95 122.51,35.95 122.14,36.33 122.14,37.2 121.96,37.38 121.37,37.38 121.2,37.2 121.2,36.08 122.22,35.05 122.22,33.86 122.43,33.66 123.15,33.66 123.23,33.74 123.23,34.31 123.52,34.59 124.35,34.59 124.64,34.31 124.64,33.74 124.73,33.66 125.28,33.66 125.36,33.74 125.36,34.31 125.65,34.59 126.48,34.59 126.77,34.31 126.77,33.74 126.85,33.66 127.6,33.66 127.89,33.37 127.89,32.42 127.6,32.13 122.83,32.13 122.57,31.86 122.57,29.81 123.47,28.91 123.47,27.65 123.4,27.58 123.4,26.22 122.67,25.49 122.67,25.15 J11.18
1G_P1_TXVD_N: length 37.5
  TOP w0.091: U42.9 122.13,41.11 122.25,41 122.25,39.97 122.4,39.81 122.4,38.68 121.18,37.46 121.18,36.43 121.85,35.76 122.73,35.76 123.22,36.25 124.75,36.25 124.85,36.14 124.85,36.09 v2(124.99,35.95)
  L14_INT_6 w0.086: v2(124.99,35.95) 125.22,36.18 126.15,36.18 127.37,34.96 127.98,34.96 128.33,35.32 128.33,36.66 128.49,36.82 129.2,36.82 129.55,36.46 129.55,34.81 128.78,34.04 128.78,30.87 128.69,30.78 128.21,30.78 127.85,30.42 127.85,29.7 128.18,29.38 128.64,29.38 128.78,29.23 128.78,28.04 128.68,27.94 128.12,27.94 126.29,29.77 125.58,29.77 125.09,29.29 125.09,27.59 125.16,27.52 125.16,26.25 125.86,25.55 125.86,25.13 J11.19
1G_P1_TXVD_P: length 37.6
  TOP w0.091: U42.10 122.63,41.07 122.53,40.97 122.53,40.08 122.68,39.93 122.68,38.57 121.46,37.35 121.46,36.55 121.97,36.04 122.62,36.04 123.1,36.53 124.75,36.53 v2(124.99,36.77)
  L14_INT_6 w0.086: v2(124.99,36.77) 125.23,36.53 126.29,36.53 127.51,35.31 127.84,35.31 127.99,35.46 127.99,36.81 128.34,37.16 129.34,37.16 129.9,36.6 129.9,34.67 129.12,33.9 129.12,30.72 128.83,30.44 128.36,30.44 128.19,30.28 128.19,29.84 128.32,29.72 128.78,29.72 129.12,29.37 129.12,27.9 128.82,27.6 127.98,27.6 126.15,29.43 125.72,29.43 125.43,29.14 125.43,27.59 125.37,27.52 125.37,26.34 125.94,25.77 126.16,25.77 126.26,25.87 J11.26
1G_P2_LED_ACT_N: length 40.1
  TOP w0.254: U42.111 TP241.1 v2(112.85,51.91) ; v2(136.88,35.1) 137.21,35.43 R646.1
  L12_INT_5 w0.254: v2(112.85,51.91) 111.51,50.56 111.51,47.83 114.6,44.73 116.64,44.73 117.55,43.81 126.21,43.81 128.52,41.5 129.16,41.5 132.23,38.43 133.68,38.43 136.52,35.59 136.52,35.46 v2(136.88,35.1)
1G_P2_LINK10_100_N: length 47.1
  TOP w0.254: v2(145.75,36.3) 146.04,36 146.04,35.48 R648.1 ; U42.112 114.78,51.41 TP240.1 114.28,50.9 v2(113.59,50.9)
  L12_INT_5 w0.254: v2(145.75,36.3) 145.75,38.22 143.15,40.82 137.62,40.82 132.79,45.64 132.79,49.68 130.45,52.02 123.65,52.02 122.28,50.65 114.81,50.65 114.55,50.9 v2(113.59,50.9)
1G_P2_LINK1000_N: length 56.2
  TOP w0.254: v2(112.94,50.07) TP239.1 113.81,49.91 U42.115
  L12_INT_5 w0.254: J12.34 148.53,37.32 144.48,41.38 138.05,41.38 134.92,44.5 134.92,48.62 130.91,52.63 114.5,52.63 112.94,51.06 v2(112.94,50.07)
1G_P2_TXVA_N: length 42.7
  TOP w0.091: v2(128.78,39.99) 128.59,39.8 128.4,39.8 128.02,40.18 128.02,41 128.09,41.07 128.09,41.92 U42.21
  L5_INT_2 w0.086: v2(128.78,39.99) 128.78,39.97 129.02,39.73 129.54,39.73 130.11,40.3 137.48,40.3 139.42,38.36 139.42,35.48 145.22,29.68 145.22,27.52 145.16,27.46 145.16,26.68 145.22,26.61 145.22,26.32 146.22,25.32 146.22,24.91 146.16,24.84 146.16,24.13 146.23,24.06 146.23,23.04 147.22,22.05 147.22,17.17 147.16,17.1 147.16,15.93 147.68,15.41 147.86,15.41 148.03,15.57 J12.13
1G_P2_TXVA_P: length 42.6
  TOP w0.091: U42.20 127.63,41.1 127.74,40.99 127.74,40.06 128.28,39.52 128.44,39.52 v2(128.78,39.18)
  L5_INT_2 w0.086: v2(128.78,39.18) 128.98,39.38 129.68,39.38 130.25,39.95 137.34,39.95 139.08,38.21 139.08,35.34 144.88,29.54 144.88,27.52 144.94,27.46 144.94,26.68 144.88,26.61 144.88,26.18 145.88,25.18 145.88,24.91 145.94,24.84 145.94,24.12 145.88,24.06 145.88,22.9 146.88,21.9 146.88,17.17 146.94,17.1 146.94,15.85 147.6,15.19 147.6,14.69 J12.6
1G_P2_TXVB_N: length 42.6
  TOP w0.091: U42.24 129.63,41.03 129.52,40.92 129.52,40.44 130.04,39.92 130.04,38.75 v2(130.31,38.49)
  L5_INT_2 w0.086: v2(130.31,38.49) 130.47,38.33 130.95,38.33 132,39.38 136.86,39.38 137.86,38.39 137.86,35.3 143.24,29.92 143.24,27.49 143.18,27.43 143.18,26.65 143.24,26.59 143.24,26.35 144.24,25.35 144.24,24.9 144.18,24.84 144.18,24.01 144.25,23.94 144.25,22.55 145.3,21.5 145.3,19.65 144.95,19.29 143.98,19.29 143.84,19.15 143.84,18.72 143.99,18.57 144.8,18.57 145.24,18.13 145.24,17.07 145.17,17.01 145.17,15.96 144.43,15.22 144.43,14.75 J12.5
1G_P2_TXVB_P: length 42.7
  TOP w0.091: U42.23 129.13,41.03 129.24,40.92 129.24,40.33 129.76,39.81 129.76,38.75 v2(129.5,38.49)
  L5_INT_2 w0.086: J12.11 144.06,15.62 144.18,15.51 144.42,15.51 144.96,16.05 144.96,17.01 144.9,17.07 144.9,17.99 144.66,18.23 143.85,18.23 143.5,18.58 143.5,19.29 143.84,19.63 144.8,19.63 144.96,19.79 144.96,21.36 143.91,22.41 143.91,23.88 143.97,23.94 143.97,24.83 143.89,24.9 143.89,25.21 142.9,26.2 142.9,26.59 142.97,26.65 142.97,27.43 142.9,27.49 142.9,29.78 137.52,35.16 137.52,38.25 136.72,39.04 132.15,39.04 131.09,37.98 130.01,37.98 129.51,38.49 v2(129.5,38.49)
1G_P2_TXVC_N: length 42.5
  TOP w0.091: U42.27 131.13,41.03 131.02,40.92 131.02,40.55 131.39,40.18 131.39,37.53 v2(131.66,37.26)
  L5_INT_2 w0.086: J12.10 142.08,15.39 142,15.3 141.81,15.3 141.19,15.93 141.19,16.97 141.26,17.04 141.26,19.67 141.45,19.86 142.28,19.86 142.63,20.21 142.63,20.92 142.28,21.27 141.39,21.27 141.3,21.35 141.3,22.45 140.28,23.48 140.28,23.99 140.21,24.06 140.21,24.87 140.28,24.93 140.28,25.38 139.28,26.37 139.28,26.49 139.22,26.56 139.22,27.41 139.28,27.47 139.28,28.13 139.5,28.35 141.25,28.35 141.62,28.71 141.62,29.45 141.28,29.79 139.32,29.79 139.12,30 139.12,32.23 136.42,34.93 136.42,36.32 135.52,37.22 133.33,37.22 132.69,36.58 131.67,36.58 131.45,36.79 131.45,37.05 v2(131.66,37.26)
1G_P2_TXVC_P: length 42.4
  TOP w0.091: v2(130.85,37.26) 131.11,37.52 131.11,40.06 130.74,40.43 130.74,40.92 130.63,41.03 U42.26
  L5_INT_2 w0.086: J12.3 141.69,14.72 141.69,15.13 140.98,15.84 140.98,16.97 140.92,17.04 140.92,19.81 141.31,20.2 142.14,20.2 142.29,20.35 142.29,20.77 142.14,20.92 141.25,20.92 140.96,21.21 140.96,22.31 139.93,23.34 139.93,23.99 140,24.06 140,24.87 139.93,24.93 139.93,25.24 138.94,26.23 138.94,26.49 139.01,26.56 139.01,27.41 138.94,27.47 138.94,28.28 139.35,28.69 141.11,28.69 141.27,28.85 141.27,29.31 141.14,29.45 139.18,29.45 138.77,29.86 138.77,32.09 136.08,34.78 136.08,36.18 135.38,36.88 133.48,36.88 132.83,36.23 131.53,36.23 131.11,36.65 131.11,37 v2(130.85,37.26)
1G_P2_TXVD_N: length 42.6
  TOP w0.091: v2(134.76,36.25) 134.49,36.51 134.49,37.08 132.52,39.06 132.52,40.92 132.63,41.03 U42.30
  L5_INT_2 w0.086: J12.2 139.11,14.14 138.5,14.76 138.5,15.13 139.22,15.86 139.22,17.11 139.28,17.17 139.28,18.98 139,19.27 137.55,19.27 137.4,19.42 137.4,19.85 137.54,19.99 139.5,19.99 140.07,20.56 140.07,21.96 139.49,22.54 138.49,22.54 138.29,22.74 138.29,23.96 138.23,24.02 138.23,24.97 138.29,25.04 138.29,25.39 137.47,26.21 136.02,26.21 135.79,26.44 135.79,27.91 135.94,28.07 137.77,28.07 138.15,28.45 138.15,29.39 137.77,29.77 136.78,29.77 136.65,29.9 136.65,30.82 136.37,31.11 135.84,31.11 135.75,31.2 135.75,31.71 135.89,31.85 136.77,31.85 137.06,32.14 137.06,32.77 134.58,35.25 134.58,36.06 v2(134.76,36.25)
1G_P2_TXVD_P: length 42.6
  TOP w0.091: U42.29 132.13,41.03 132.24,40.92 132.24,38.94 134.21,36.97 134.21,36.51 v2(133.95,36.25)
  L5_INT_2 w0.086: J12.8 138.12,15.54 138.23,15.44 138.5,15.44 139.01,15.94 139.01,17.11 138.94,17.17 138.94,18.84 138.85,18.93 137.41,18.93 137.06,19.28 137.06,19.99 137.4,20.33 139.36,20.33 139.73,20.7 139.73,21.82 139.34,22.2 138.35,22.2 137.95,22.6 137.95,23.96 138.01,24.02 138.01,24.97 137.95,25.04 137.95,25.24 137.32,25.87 135.87,25.87 135.45,26.3 135.45,28.06 135.8,28.41 137.63,28.41 137.81,28.59 137.81,29.25 137.63,29.43 136.64,29.43 136.31,29.75 136.31,30.68 136.22,30.77 135.69,30.77 135.41,31.05 135.41,31.85 135.75,32.19 136.63,32.19 136.72,32.28 136.72,32.62 134.23,35.11 134.23,35.96 v2(133.95,36.25)
1G_P3_LED_ACT_N: length 40.8
  TOP w0.254: R645.1 v2(139.98,36.04) ; U42.118 115.3,48.41 115.06,48.64 113.82,48.64 TP245.1 v2(112.78,48.92)
  L12_INT_5 w0.254: v2(112.78,48.92) 112.78,48.29 113.77,47.29 121.08,47.29 121.67,46.71 128.55,46.71 129.34,45.92 129.34,43.03 132.74,39.62 138.48,39.62 139.98,38.13 v2(139.98,36.04)
1G_P3_LINK10_100_N: length 45.7
  TOP w0.254: v2(147.77,36.28) 147.5,36 R647.1 ; v2(113.82,48.06) 113.91,47.97 TP244.1 114.6,47.91 U42.119
  L12_INT_5 w0.254: v2(147.77,36.28) 147.77,36.09 147.17,35.48 145.26,35.48 143.61,37.13 141.78,37.13 138.76,40.16 133.6,40.16 131.11,42.65 131.11,46.23 129.87,47.47 122.3,47.47 121.54,48.23 114.5,48.23 114.33,48.06 v2(113.82,48.06)
1G_P3_LINK1000_N: length 75
  TOP w0.254: v2(112.93,47.33) TP243.1 115.5,47.33 115.58,47.41 U42.120
  L12_INT_5 w0.254: J12.30 147.02,8.03 147.02,11.05 148.03,12.06 148.03,14.91 147.04,15.9 147.04,17.53 146.05,18.52 146.05,25.37 147.08,26.41 147.08,28.25 145.47,29.87 143.59,29.87 139.27,34.19 139.27,38.05 138.25,39.07 132.41,39.07 129.34,42.14 128.63,42.14 127.74,43.03 127.74,45.54 127.18,46.1 121.16,46.1 120.52,46.74 117.22,46.74 116.41,45.92 114.33,45.92 v2(112.93,47.33)
1G_P3_TXVA_N: length 37.9
  TOP w0.091: v2(139.59,43.8) 139.37,44.02 139.09,44.02 138.98,43.91 U42.40
  L14_INT_6 w0.086: J12.21 138.12,25.71 138.26,25.57 138.47,25.57 139,26.11 139,27.63 138.94,27.7 138.94,28.12 138.72,28.33 136.71,28.33 136.26,28.79 136.26,30.16 136.03,30.39 136.03,35.95 133.95,38.03 133.95,39.49 134.32,39.86 135.77,39.86 135.85,39.95 135.85,40.5 135.77,40.58 134.45,40.58 134.07,40.95 134.07,42.1 134.48,42.51 136.72,42.51 138.15,41.07 140.56,41.07 140.8,41.31 140.8,43.42 140.19,44.04 139.82,44.04 v2(139.59,43.8)
1G_P3_TXVA_P: length 38
  TOP w0.091: U42.41 138.96,44.41 139.07,44.3 139.27,44.3 v2(139.59,44.61)
  L14_INT_6 w0.086: v2(139.59,44.61) 139.82,44.38 140.33,44.38 141.15,43.56 141.15,41.17 140.71,40.73 138.01,40.73 136.58,42.16 134.62,42.16 134.42,41.96 134.42,41.1 134.59,40.93 135.91,40.93 136.19,40.64 136.19,39.81 135.91,39.52 134.46,39.52 134.29,39.34 134.29,38.18 136.37,36.09 136.37,30.53 136.6,30.3 136.6,28.93 136.86,28.68 138.86,28.68 139.28,28.26 139.28,27.7 139.22,27.63 139.22,26.02 138.62,25.42 138.62,25.03 J12.15
1G_P3_TXVB_N: length 37.9
  TOP w0.091: v2(141.79,36.16) 142.07,36.43 142.07,37.37 141.54,37.9 139.73,37.9 137.62,40.01 136.36,40.01 135.76,40.6 135.76,40.97 135.63,41.1 U42.36
  L14_INT_6 w0.086: J12.16 141.1,24.54 141.63,25.07 141.63,25.58 140.99,26.22 140.99,27.45 140.92,27.51 140.92,29.08 140.59,29.41 139.24,29.41 138.77,29.88 138.77,31.35 137.35,32.78 137.35,34.28 137.84,34.77 140.44,34.77 141,34.22 141,32.72 141.38,32.33 142.26,32.33 143.51,33.58 144.58,33.58 144.75,33.75 144.75,34.13 144.58,34.3 142.34,34.3 142.02,34.61 142.02,35.93 v2(141.79,36.16)
1G_P3_TXVB_P: length 38
  TOP w0.091: v2(142.61,36.16) 142.35,36.41 142.35,37.48 141.66,38.18 139.84,38.18 137.73,40.28 136.47,40.28 136.04,40.72 136.04,40.97 136.13,41.06 U42.37
  L14_INT_6 w0.086: v2(142.61,36.16) 142.37,35.92 142.37,34.75 142.48,34.64 144.72,34.64 145.1,34.27 145.1,33.61 144.72,33.24 143.65,33.24 142.41,31.99 141.23,31.99 140.65,32.57 140.65,34.07 140.3,34.43 137.99,34.43 137.69,34.14 137.69,32.92 139.12,31.5 139.12,30.02 139.38,29.76 140.73,29.76 141.27,29.22 141.27,27.51 141.2,27.45 141.2,26.3 141.72,25.78 141.92,25.78 142.08,25.94 J12.23
1G_P3_TXVC_N: length 37.9
  TOP w0.091: U42.34 134.63,41.03 134.75,40.91 134.75,40.04 135.62,39.17 136.86,39.17 137.54,38.48 137.54,36.94 137.91,36.58 138.13,36.58 v2(138.49,36.21)
  L14_INT_6 w0.086: v2(138.49,36.21) 138.68,36.4 139.17,36.4 139.7,36.93 148.21,36.93 148.81,36.33 148.81,35.58 148.48,35.25 147.5,35.25 147.22,34.96 147.22,34.13 147.5,33.84 148.58,33.84 148.81,33.61 148.81,32.63 148.65,32.47 145.2,32.47 144.46,31.74 144.46,29.5 144.88,29.09 144.88,27.59 144.95,27.53 144.95,26.33 144.41,25.8 144.22,25.8 144.06,25.95 J12.24
1G_P3_TXVC_P: length 38
  TOP w0.091: v2(138.49,37.02) 138.33,36.86 138.02,36.86 137.82,37.06 137.82,38.6 136.97,39.45 135.74,39.45 135.03,40.16 135.03,40.92 135.13,41.03 U42.35
  L14_INT_6 w0.086: v2(138.49,37.02) 138.77,36.74 139.02,36.74 139.56,37.27 148.35,37.27 149.15,36.48 149.15,35.43 148.62,34.91 147.65,34.91 147.56,34.82 147.56,34.27 147.65,34.18 148.72,34.18 149.15,33.76 149.15,32.48 148.8,32.13 145.34,32.13 144.81,31.6 144.81,29.65 145.22,29.23 145.22,27.59 145.16,27.53 145.16,26.24 144.48,25.56 144.48,25.09 145.03,24.54 J12.18
1G_P3_TXVD_N: length 38
  TOP w0.091: v2(136.49,36.97) 136.27,37.19 135.85,37.19 133.25,39.79 133.25,40.05 133.24,40.06 133.24,40.92 133.13,41.03 U42.31
  L14_INT_6 w0.086: v2(136.49,36.97) 136.65,37.13 137.06,37.13 138.3,38.38 148.97,38.38 150.81,36.54 150.81,30.01 150.09,29.29 147.42,29.29 146.86,28.72 146.86,27.54 146.92,27.48 146.92,26.31 147.59,25.64 147.59,25.1 J12.19
1G_P3_TXVD_P: length 38.1
  TOP w0.091: v2(136.46,37.67) 136.25,37.47 135.97,37.47 133.53,39.9 133.53,40.17 133.52,40.17 133.52,40.92 133.63,41.03 U42.32
  L14_INT_6 w0.086: v2(136.46,37.67) 136.65,37.48 136.92,37.48 138.16,38.72 149.11,38.72 151.16,36.68 151.16,29.87 150.23,28.94 147.56,28.94 147.2,28.58 147.2,27.54 147.14,27.48 147.14,26.39 147.73,25.8 147.92,25.8 148.03,25.91 J12.26
1G_P4_LED_ACT_N: length 45.6
  TOP w0.254: v2(161.14,61.37) TP283.1 161.5,60.32 161.5,58.96 161.3,58.76 U620.100 ; R650.1 v2(157.34,35.43)
  L12_INT_5 w0.254: v2(161.14,61.37) 161.53,60.98 161.53,59.22 160.12,57.81 153.34,57.81 150.55,55.01 150.55,39.04 154.15,35.43 v2(157.34,35.43)
1G_P4_LINK10_100_N: length 48.7
  TOP w0.254: v2(160.79,59.98) TP282.1 U620.101 ; v2(166.83,34.98) 167.31,34.98 R652.1
  L3_INT_1 w0.254: v2(160.79,59.98) 156.9,56.08 156.9,47.24 154.33,44.68 v2(154.33,44.37)
  L12_INT_5 w0.254: v2(154.33,44.37) 153.34,44.37 152.88,43.92 152.88,42.5 153.83,41.55 155.83,41.55 156.74,42.47 159,42.47 159.94,41.53 162.76,41.53 163.96,40.34 163.96,35.76 164.74,34.98 v2(166.83,34.98)
  BOTTOM w0.254: R5797.1 155.77,46.32 R5800.1 155.22,44.37 v2(154.33,44.37)
1G_P4_LINK1000_N: length 57.6
  TOP w0.254: U620.102 160.3,58.78 160.15,58.93 TP281.1 v2(160.15,61.08)
  L12_INT_5 w0.254: v2(160.15,61.08) 159.67,60.6 154.79,60.6 149.12,54.94 149.12,39.37 155.17,33.32 167.87,33.32 J13.34
1G_P4_TXVA_N: length 42.2
  TOP w0.091: U620.127 158.1,43.91 157.98,44.02 157.43,44.02 156.97,43.56 156.97,41.81 157.12,41.66 157.43,41.66 v2(157.67,41.9)
  L5_INT_2 w0.086: v2(157.67,41.9) 157.9,41.67 158.71,41.67 159.21,42.16 163.43,42.16 164.85,40.74 164.85,37.11 166.27,35.69 166.27,30.05 167,29.32 167,27.57 166.93,27.51 166.93,26.74 167,26.68 167,26.37 167.99,25.38 167.99,24.88 167.92,24.82 167.92,23.91 167.99,23.85 167.99,21.99 168.98,20.99 168.98,17.24 168.92,17.17 168.92,15.76 169.49,15.19 169.69,15.19 169.8,15.29 J13.13
1G_P4_TXVA_P: length 42.2
  TOP w0.091: v2(157.67,41.08) 157.38,41.38 157.01,41.38 156.69,41.69 156.69,43.68 157.31,44.3 157.99,44.3 158.1,44.41 U620.126
  L5_INT_2 w0.086: v2(157.67,41.08) 157.91,41.33 158.85,41.33 159.35,41.82 163.28,41.82 164.5,40.6 164.5,36.97 165.93,35.55 165.93,29.91 166.65,29.18 166.65,27.57 166.72,27.51 166.72,26.74 166.65,26.68 166.65,26.23 167.64,25.24 167.64,24.88 167.71,24.82 167.71,23.91 167.64,23.85 167.64,21.85 168.64,20.85 168.64,17.24 168.7,17.17 168.7,15.67 169.38,14.99 169.38,14.7 J13.6
1G_P4_TXVB_N: length 42.1
  TOP w0.091: U620.3 161.3,41.08 161.19,40.97 161.19,40.52 160.11,39.45 159.86,39.45 v2(159.59,39.18)
  L5_INT_2 w0.086: J13.5 166.82,14.96 166.51,15.27 165.23,15.27 164.74,15.76 164.74,16.96 164.67,17.03 164.67,18.26 165.66,19.26 165.66,24.09 165.73,24.15 165.73,24.83 165.66,24.9 165.66,25.19 164.67,26.18 164.67,26.56 164.74,26.62 164.74,27.41 164.67,27.48 164.67,28.14 163.44,29.37 163.44,31.54 163.88,31.98 164.77,31.98 164.86,32.06 164.86,32.61 164.77,32.7 163.73,32.7 163.44,32.98 163.44,33.82 163.73,34.1 164.77,34.1 164.86,34.19 164.86,34.74 164.77,34.82 163.83,34.82 163.44,35.21 163.44,40.14 162.92,40.67 161.44,40.67 160.19,39.41 159.83,39.41 v2(159.59,39.18)
1G_P4_TXVB_P: length 42.1
  TOP w0.091: U620.2 160.79,41.08 160.91,40.97 160.91,40.64 159.99,39.72 159.86,39.72 v2(159.59,39.99)
  L5_INT_2 w0.086: v2(159.59,39.99) 159.83,39.76 160.05,39.76 161.3,41.01 163.06,41.01 163.78,40.28 163.78,35.35 163.97,35.17 164.92,35.17 165.2,34.88 165.2,34.05 164.92,33.76 163.87,33.76 163.78,33.67 163.78,33.12 163.87,33.04 164.92,33.04 165.2,32.75 165.2,31.92 164.92,31.63 164.02,31.63 163.78,31.4 163.78,29.51 165.01,28.28 165.01,27.48 164.95,27.41 164.95,26.69 165.01,26.62 165.01,26.33 166.01,25.33 166.01,24.9 165.94,24.83 165.94,24.15 166.01,24.09 166.01,19.11 165.01,18.12 165.01,17.03 164.95,16.96 164.95,15.85 165.31,15.48 166.5,15.48 166.63,15.62 166.63,15.87 J13.11
1G_P4_TXVC_N: length 42.1
  TOP w0.091: v2(162.45,39.93) 162.18,40.2 162.18,41.02 162.3,41.14 U620.5
  L5_INT_2 w0.086: v2(162.45,39.93) 162.22,39.7 162.22,36.82 161.28,35.88 158.43,35.88 158.23,35.67 158.23,34.72 158.42,34.54 161.55,34.54 161.98,34.11 161.98,32.81 161.55,32.38 158.56,32.38 158.18,32 158.18,29.98 158.55,29.62 160.63,29.62 161.05,29.19 161.05,27.55 160.99,27.48 160.99,26.69 161.05,26.62 161.05,26.38 162.04,25.39 162.04,24.85 161.98,24.79 161.98,24.1 162.04,24.03 162.04,23.15 163.04,22.15 163.04,17.11 162.97,17.05 162.97,15.93 163.56,15.34 163.75,15.34 163.85,15.44 J13.10
1G_P4_TXVC_P: length 42
  TOP w0.091: U620.4 161.79,41.1 161.9,41 161.9,40.2 v2(161.63,39.93)
  L5_INT_2 w0.086: v2(161.63,39.93) 161.87,39.69 161.87,36.96 161.14,36.22 158.29,36.22 157.89,35.82 157.89,34.58 158.27,34.19 161.41,34.19 161.63,33.97 161.63,32.96 161.4,32.73 158.42,32.73 157.84,32.15 157.84,29.84 158.4,29.27 160.49,29.27 160.71,29.05 160.71,27.55 160.77,27.48 160.77,26.68 160.71,26.62 160.71,26.24 161.7,25.25 161.7,24.85 161.77,24.79 161.77,24.1 161.7,24.03 161.7,23.01 162.69,22.01 162.69,17.11 162.76,17.05 162.76,15.84 163.47,15.13 163.47,14.74 J13.3
1G_P4_TXVD_N: length 42
  TOP w0.091: v2(160.71,37.45) 160.97,37.72 163.14,37.72 163.7,38.28 163.7,40.94 163.79,41.04 U620.8
  L5_INT_2 w0.086: J13.2 160.88,14.14 160.32,14.7 160.32,15.24 160.99,15.91 160.99,17.12 161.05,17.18 161.05,21.5 160.06,22.49 160.06,23.97 160,24.04 160,24.94 160.06,25.01 160.06,25.63 159.62,26.07 155.23,26.07 154.58,26.72 154.58,36.63 155.24,37.29 159.82,37.29 160.21,37.68 160.48,37.68 v2(160.71,37.45)
1G_P4_TXVD_P: length 42.1
  TOP w0.091: v2(160.71,38.27) 160.97,38 163.03,38 163.42,38.39 163.42,40.94 163.3,41.07 U620.7
  L5_INT_2 w0.086: J13.8 159.9,16.66 159.9,15.55 160.02,15.43 160.21,15.43 160.78,15.99 160.78,17.12 160.71,17.18 160.71,21.35 159.72,22.35 159.72,23.97 159.78,24.04 159.78,24.94 159.72,25.01 159.72,25.49 159.48,25.73 155.09,25.73 154.24,26.58 154.24,36.77 155.1,37.63 159.67,37.63 160.07,38.02 160.46,38.02 v2(160.71,38.27)
1G_P5_LED_ACT_N: length 33
  TOP w0.254: U620.105 155.88,54.91 TP279.1 v2(154.71,54.98) ; R649.1 v2(161.57,35.43)
  L12_INT_5 w0.254: v2(154.71,54.98) 154.02,54.98 151.38,52.35 151.38,42.47 153.64,40.21 155.73,40.21 156.54,39.4 156.54,38.38 159.49,35.43 v2(161.57,35.43)
1G_P5_LINK10_100_N: length 40.5
  TOP w0.254: v2(155.3,54.2) 155.78,54.2 155.87,54.29 TP278.1 156.81,54.41 U620.106 ; R651.1 v2(170.05,35.43)
  L12_INT_5 w0.254: v2(170.05,35.43) 168.83,34.21 163.75,34.21 161.93,36.04 159.66,36.04 157.12,38.58 157.12,39.6 156.01,40.72 153.95,40.72 152.04,42.62 152.04,51.97 154.28,54.2 v2(155.3,54.2)
1G_P5_LINK1000_N: length 68.2
  TOP w0.254: U620.107 157.41,53.91 157.04,53.53 TP277.1 154.7,53.53 v2(154.69,53.54)
  L12_INT_5 w0.254: J13.30 167.82,8.99 167.82,14.86 168.81,15.85 168.81,21.59 169.77,22.56 169.77,25.35 171.5,27.08 171.5,36.12 169.98,37.64 169.98,38.89 168.02,40.84 164.29,40.84 163.07,42.06 160.22,42.06 158.19,44.09 155.93,44.09 152.88,47.14 152.88,51.42 154.69,53.23 v2(154.69,53.54)
1G_P5_TXVA_N: length 37.8
  TOP w0.091: v2(169.22,38.04) 169.47,37.78 169.73,37.78 169.82,37.87 169.82,38.58 169.03,39.38 169.03,39.87 168.91,40 168.91,40.92 168.79,41.03 U620.18
  L14_INT_6 w0.086: J13.21 159.89,25.95 160.01,25.83 160.32,25.83 160.78,26.29 160.78,27.6 160.72,27.66 160.72,28.03 160.45,28.3 159.84,28.3 157.95,30.19 157.95,40.37 159.22,41.64 166.82,41.64 168.47,39.99 168.47,38.04 168.7,37.81 168.99,37.81 v2(169.22,38.04)
1G_P5_TXVA_P: length 37.6
  TOP w0.091: v2(169.22,37.22) 169.49,37.5 169.85,37.5 170.1,37.76 170.1,38.7 169.31,39.5 169.31,39.99 169.18,40.11 169.18,40.92 169.3,41.03 U620.19
  L14_INT_6 w0.086: J13.15 160.35,25.07 160.35,25.56 161,26.2 161,27.6 161.06,27.66 161.06,28.17 160.59,28.64 159.98,28.64 158.29,30.33 158.29,40.23 159.36,41.3 166.67,41.3 168.12,39.85 168.12,37.9 168.55,37.47 168.98,37.47 v2(169.22,37.22)
1G_P5_TXVB_N: length 37.7
  TOP w0.091: U620.15 167.3,41.03 167.41,40.92 167.41,40.6 168.02,39.98 168.02,39.31 167.93,39.22 167.61,39.22 v2(167.33,39.5)
  L14_INT_6 w0.086: v2(167.33,39.5) 167.08,39.24 166.55,39.24 165.58,40.21 164.62,40.21 164.17,39.76 164.17,37.27 164.03,37.13 163.22,37.13 163.07,37.28 163.07,38.32 162.79,38.61 161.95,38.61 161.67,38.32 161.67,36.78 161.03,36.14 159.53,36.14 159.12,35.73 159.12,34.68 159.45,34.35 161.64,34.35 161.76,34.23 161.76,33.62 161.59,33.45 159.51,33.45 159.13,33.07 159.13,32.23 159.46,31.9 160.3,31.9 160.5,31.7 160.5,29.84 160.95,29.4 162.22,29.4 162.69,28.93 162.69,27.65 162.75,27.58 162.75,26.23 163.41,25.57 163.41,25.09 J13.16
1G_P5_TXVB_P: length 37.7
  TOP w0.091: v2(167.33,38.68) 167.58,38.94 168.05,38.94 168.3,39.19 168.3,40.1 167.68,40.71 167.68,40.92 167.79,41.03 U620.16
  L14_INT_6 w0.086: J13.23 163.85,25.85 163.74,25.74 163.54,25.74 162.96,26.32 162.96,27.58 163.03,27.65 163.03,29.07 162.36,29.74 161.09,29.74 160.85,29.99 160.85,31.84 160.44,32.25 159.6,32.25 159.47,32.37 159.47,32.93 159.65,33.1 161.73,33.1 162.1,33.48 162.1,34.37 161.78,34.69 159.6,34.69 159.46,34.82 159.46,35.59 159.68,35.8 161.18,35.8 162.01,36.63 162.01,38.18 162.09,38.27 162.64,38.27 162.73,38.18 162.73,37.14 163.08,36.79 164.18,36.79 164.52,37.13 164.52,39.61 164.77,39.87 165.44,39.87 166.41,38.9 167.11,38.9 v2(167.33,38.68)
1G_P5_TXVC_N: length 36.1
  TOP w0.091: v2(165.67,38.1) 165.91,38.34 165.91,40.94 165.79,41.06 U620.12
  L14_INT_6 w0.086: v2(165.67,38.1) 165.91,37.87 165.91,35.63 165.72,35.45 163.51,35.45 163.17,35.11 163.17,34.36 163.49,34.04 166.79,34.04 166.87,33.96 166.87,33.41 166.79,33.32 163.52,33.32 163.17,32.97 163.17,32.26 163.51,31.91 166.38,31.91 166.47,31.83 166.47,31.21 166.37,31.12 163.83,31.12 163.47,30.76 163.47,29.87 163.83,29.51 166.38,29.51 166.65,29.23 166.65,27.52 166.72,27.45 166.72,26.32 166.21,25.8 165.97,25.8 165.83,25.94 J13.24
1G_P5_TXVC_P: length 36.1
  TOP w0.091: U620.13 166.3,41.07 166.19,40.97 166.19,38.39 v2(166.48,38.1)
  L14_INT_6 w0.086: v2(166.48,38.1) 166.25,37.87 166.25,35.49 165.86,35.1 163.65,35.1 163.51,34.96 163.51,34.51 163.63,34.38 166.93,34.38 167.21,34.1 167.21,33.26 166.93,32.98 163.66,32.98 163.51,32.83 163.51,32.4 163.65,32.26 166.52,32.26 166.81,31.97 166.81,31.07 166.51,30.77 163.97,30.77 163.82,30.62 163.82,30.01 163.98,29.85 166.52,29.85 167,29.37 167,27.52 166.93,27.45 166.93,26.23 166.25,25.54 166.25,25.12 J13.18
1G_P5_TXVD_N: length 36.3
  TOP w0.091: v2(167.97,36.18) 167.68,36.47 165.09,36.47 164.43,37.13 164.43,40.98 164.3,41.11 U620.9
  L14_INT_6 w0.086: J13.19 169.42,25.16 169.42,25.63 168.71,26.35 168.71,27.47 168.65,27.53 168.65,29.25 169.22,29.83 170.86,29.83 171.33,29.36 171.33,28.57 171.57,28.33 172.04,28.33 172.26,28.55 172.26,31.17 170.97,32.46 170.97,34.56 170.88,34.65 170.38,34.65 170.25,34.51 170.25,32.25 169.9,31.9 168.65,31.9 168.25,32.31 168.25,34.67 169,35.42 169,35.94 168.54,36.4 168.19,36.4 v2(167.97,36.18)
1G_P5_TXVD_P: length 36.3
  TOP w0.091: U620.10 164.79,41.07 164.71,40.99 164.71,37.25 165.2,36.75 167.73,36.75 v2(167.97,37)
  L14_INT_6 w0.086: J13.26 169.8,25.91 169.7,25.81 169.55,25.81 168.92,26.43 168.92,27.47 168.99,27.53 168.99,29.11 169.37,29.49 170.71,29.49 170.99,29.22 170.99,28.43 171.42,27.99 172.19,27.99 172.61,28.41 172.61,31.31 171.31,32.6 171.31,34.7 171.02,34.99 170.24,34.99 169.9,34.65 169.9,32.39 169.76,32.25 168.8,32.25 168.59,32.45 168.59,34.53 169.34,35.28 169.34,36.08 168.68,36.74 168.22,36.74 v2(167.97,37)
1G_P6_LED_ACT_N: length 40.2
  TOP w0.254: U620.111 155.87,51.91 TP275.1 154.97,51.85 v2(154.86,51.74) ; v2(179.88,35.61) 179.96,35.69 180.33,35.69 R654.1
  L12_INT_5 w0.254: v2(154.86,51.74) 154.43,51.31 154.43,47.17 155.73,45.87 157.78,45.87 159.79,43.87 163.3,43.87 165.38,41.78 172.34,41.78 175.62,38.51 176.92,38.51 178.03,37.4 178.03,36.76 179.08,35.71 179.79,35.71 v2(179.88,35.61)
1G_P6_LINK10_100_N: length 48.1
  TOP w0.254: U620.112 156.95,51.41 TP274.1 156.44,50.9 v2(155.75,50.9) ; v2(188.7,35.66) 188.93,35.43 R656.1
  L12_INT_5 w0.254: v2(188.7,35.66) 188.7,36.17 188.89,36.36 188.89,37.78 186,40.67 180.14,40.67 176.78,44.02 176.78,47.15 171.86,52.07 165.38,52.07 163.91,50.6 156.57,50.6 156.26,50.9 v2(155.75,50.9)
1G_P6_LINK1000_N: length 58.4
  TOP w0.254: U620.115 155.98,49.91 TP273.1 v2(155.1,50.07)
  L12_INT_5 w0.254: J14.34 193.27,32.08 193.27,36.12 188.12,41.27 180.31,41.27 177.47,44.12 177.47,47.55 172.34,52.68 156.64,52.68 154.94,50.98 154.94,50.23 v2(155.1,50.07)
1G_P6_TXVA_N: length 43.1
  TOP w0.091: U620.21 170.3,41.03 170.21,40.95 170.21,40.02 170.6,39.62 170.76,39.62 v2(171.02,39.89)
  L5_INT_2 w0.086: v2(171.02,39.89) 171.29,39.62 171.65,39.62 172.15,40.12 179.49,40.12 182.54,37.07 182.54,35.75 188.77,29.52 188.77,27.62 188.7,27.56 188.7,26.65 188.77,26.59 188.77,26.27 189.76,25.28 189.76,24.84 189.69,24.77 189.69,24.18 189.76,24.11 189.76,23.53 190.75,22.54 190.75,17.13 190.68,17.07 190.68,15.93 191.21,15.4 191.47,15.4 191.57,15.5 J14.13
1G_P6_TXVA_P: length 43
  TOP w0.091: U620.20 169.79,41.03 169.93,40.9 169.93,39.9 170.49,39.34 170.7,39.34 170.97,39.08 v2(171.02,39.08)
  L5_INT_2 w0.086: J14.6 191.13,14.68 191.13,15.18 190.47,15.84 190.47,17.07 190.41,17.13 190.41,22.39 189.42,23.39 189.42,24.11 189.48,24.17 189.48,24.77 189.42,24.84 189.42,25.14 188.42,26.13 188.42,26.59 188.49,26.65 188.49,27.56 188.42,27.62 188.42,29.38 182.19,35.61 182.19,36.93 179.35,39.78 172.29,39.78 171.8,39.28 171.22,39.28 v2(171.02,39.08)
1G_P6_TXVB_N: length 42.7
  TOP w0.091: v2(172.47,38.49) 172.21,38.75 172.21,39.92 171.68,40.44 171.68,40.92 171.79,41.03 U620.24
  L5_INT_2 w0.086: J14.5 187.94,14.78 187.94,15.19 188.7,15.96 188.7,17.01 188.77,17.08 188.77,17.99 188.42,18.34 187.58,18.34 187.44,18.48 187.44,19.18 187.52,19.27 188.56,19.27 188.84,19.56 188.84,22.54 187.78,23.6 187.78,23.96 187.71,24.03 187.71,24.88 187.78,24.94 187.78,25.26 186.79,26.25 186.79,26.63 186.73,26.69 186.73,27.53 186.79,27.6 186.79,29.92 179.78,36.93 179.78,38 178.58,39.2 174.41,39.2 173.5,38.3 172.66,38.3 v2(172.47,38.49)
1G_P6_TXVB_P: length 42.8
  TOP w0.091: U620.23 171.3,41.03 171.41,40.92 171.41,40.33 171.93,39.81 171.93,38.75 v2(171.66,38.49)
  L5_INT_2 w0.086: J14.11 187.6,15.6 187.71,15.49 187.93,15.49 188.49,16.04 188.49,17.01 188.42,17.08 188.42,17.85 188.27,18 187.44,18 187.1,18.34 187.1,19.33 187.38,19.61 188.41,19.61 188.5,19.7 188.5,22.39 187.43,23.46 187.43,23.96 187.5,24.03 187.5,24.86 187.43,24.93 187.43,25.12 186.45,26.11 186.45,26.63 186.51,26.69 186.51,27.53 186.45,27.6 186.45,29.78 179.44,36.79 179.44,37.86 178.44,38.86 174.55,38.86 173.65,37.96 172.19,37.96 v2(171.66,38.49)
1G_P6_TXVC_N: length 43.5
  TOP w0.091: v2(173.82,37.26) 173.55,37.53 173.55,40.18 173.18,40.55 173.18,40.92 173.3,41.03 U620.27
  L5_INT_2 w0.086: J14.10 185.62,15.42 185.53,15.32 185.35,15.32 184.74,15.93 184.74,17 184.81,17.06 184.81,19.92 184.93,20.04 185.97,20.04 186.26,20.32 186.26,21.16 185.97,21.44 184.93,21.44 184.84,21.53 184.84,22.6 184.48,22.96 184.01,22.96 183.81,23.16 183.81,24.11 183.75,24.18 183.75,24.79 183.81,24.86 183.81,25.45 182.83,26.43 182.83,26.65 182.76,26.72 182.76,27.36 182.83,27.42 182.83,28.06 182.98,28.22 184.28,28.22 184.69,28.63 184.69,29.48 184.28,29.9 183.03,29.9 182.68,30.25 182.68,32.21 177.97,36.92 177.97,37.43 177.41,37.99 176.01,37.99 174.64,36.61 173.7,36.61 173.59,36.72 173.59,37.03 v2(173.82,37.26)
1G_P6_TXVC_P: length 43.4
  TOP w0.091: U620.26 172.79,41.03 172.91,40.92 172.91,40.43 173.27,40.06 173.27,37.52 v2(173.01,37.26)
  L5_INT_2 w0.086: v2(173.01,37.26) 173.25,37.03 173.25,36.58 173.56,36.27 174.78,36.27 176.15,37.64 177.27,37.64 177.62,37.29 177.62,36.78 182.33,32.06 182.33,30.11 182.89,29.55 184.13,29.55 184.35,29.34 184.35,28.78 184.13,28.56 182.84,28.56 182.49,28.21 182.49,27.42 182.55,27.36 182.55,26.72 182.49,26.65 182.49,26.29 183.47,25.31 183.47,24.86 183.53,24.79 183.53,24.18 183.47,24.11 183.47,23.02 183.87,22.62 184.34,22.62 184.5,22.46 184.5,21.39 184.79,21.1 185.83,21.1 185.92,21.02 185.92,20.47 185.83,20.38 184.79,20.38 184.46,20.06 184.46,17.06 184.53,17 184.53,15.84 185.24,15.13 185.24,14.73 J14.3
1G_P6_TXVD_N: length 43.2
  TOP w0.091: U620.30 174.79,41.03 174.68,40.92 174.68,39.41 176.61,37.49 176.61,37.15 v2(176.87,36.88)
  L5_INT_2 w0.086: J14.2 182.05,14.73 182.05,15.17 182.76,15.88 182.76,17 182.83,17.06 182.83,18.06 183.39,18.62 183.39,19.41 183.03,19.77 181,19.77 180.91,19.86 180.91,20.41 181,20.49 183.03,20.49 183.39,20.85 183.39,21.67 181.84,23.22 181.84,23.9 181.77,23.96 181.77,24.9 181.84,24.96 181.84,25.47 181.17,26.14 179.6,26.14 179.31,26.43 179.31,28.08 179.46,28.23 181.44,28.23 181.76,28.55 181.76,29.3 181.43,29.63 179.43,29.63 179.31,29.76 179.31,31.03 180.06,31.78 180.06,33.25 177.65,35.66 176.94,35.66 176.68,35.92 176.68,36.69 v2(176.87,36.88)
1G_P6_TXVD_P: length 43.2
  TOP w0.091: v2(176.09,36.88) 176.09,36.91 176.33,37.15 176.33,37.37 174.41,39.3 174.41,40.92 174.3,41.03 U620.29
  L5_INT_2 w0.086: v2(176.09,36.88) 176.34,36.63 176.34,35.77 176.79,35.32 177.51,35.32 179.72,33.11 179.72,31.92 178.97,31.17 178.97,29.61 179.29,29.29 181.28,29.29 181.42,29.16 181.42,28.69 181.3,28.57 179.32,28.57 178.97,28.22 178.97,26.29 179.46,25.79 181.03,25.79 181.49,25.33 181.49,24.96 181.56,24.9 181.56,23.96 181.49,23.9 181.49,23.08 183.05,21.52 183.05,21 182.88,20.83 180.85,20.83 180.57,20.55 180.57,19.71 180.85,19.43 182.88,19.43 183.05,19.27 183.05,18.77 182.49,18.21 182.49,17.06 182.55,17 182.55,15.97 181.95,15.37 181.77,15.37 181.66,15.48 J14.8
1G_P7_LED_ACT_N: length 69.5
  TOP w0.254: v2(153.77,48.36) 154.23,48.82 TP271.1 155.83,48.67 157.2,48.67 157.46,48.41 U620.118
  L12_INT_5 w0.254: J14.27 183.67,9.02 183.67,14.78 182.68,15.77 182.68,20.78 181.66,21.79 181.66,25.3 179.07,27.89 179.07,35 177.52,36.55 177.52,37.19 176.71,38 175.01,38 171.58,41.43 164.54,41.43 163.47,42.49 160.53,42.49 158.3,44.73 156.08,44.73 153.77,47.04 v2(153.77,48.36)
1G_P7_LINK10_100_N: length 49
  TOP w0.254: v2(155.98,48.06) 156.07,47.97 TP270.1 156.76,47.91 U620.119 ; R655.1 v2(191.74,35.43)
  L12_INT_5 w0.254: v2(155.98,48.06) 162.66,48.06 163.55,47.17 171.63,47.17 172.88,45.92 172.88,43.03 175.75,40.16 180.49,40.16 182.58,38.07 182.58,35.28 183.74,34.11 190.42,34.11 v2(191.74,35.43)
1G_P7_LINK1000_N: length 75.4
  TOP w0.254: U620.120 155.89,47.41 TP269.1 v2(155.09,47.33)
  L12_INT_5 w0.254: J14.30 190.25,8.33 190.25,10.74 191.57,12.06 191.57,14.91 190.6,15.88 190.6,17.5 189.61,18.5 189.61,25.27 190.58,26.24 190.58,28.3 189.64,29.24 187.76,29.24 182.07,34.93 182.07,37.67 180.26,39.47 175.54,39.47 172.67,42.34 172.01,42.34 171.53,42.83 171.53,45.69 170.71,46.51 163.05,46.51 162.31,47.24 155.18,47.24 v2(155.09,47.33)
1G_P7_TXVA_N: length 36.6
  TOP w0.091: U620.40 181.14,43.91 181.25,44.02 181.53,44.02 v2(181.75,43.8)
  L14_INT_6 w0.086: v2(181.75,43.8) 181.97,44.02 182.42,44.02 183.83,42.61 183.83,41.37 183.31,40.84 180.52,40.84 179.06,42.3 176.87,42.3 176.03,41.47 176.03,38.44 177.72,36.75 177.72,35.36 179.25,33.83 179.25,29.06 179.96,28.35 182.29,28.35 182.48,28.16 182.48,27.56 182.55,27.5 182.55,26.13 181.98,25.56 181.77,25.56 181.66,25.67 J14.21
1G_P7_TXVA_P: length 36.7
  TOP w0.091: v2(181.75,44.61) 181.43,44.3 181.23,44.3 181.12,44.41 U620.41
  L14_INT_6 w0.086: J14.15 182.65,24.54 182.14,25.04 182.14,25.42 182.76,26.04 182.76,27.5 182.82,27.56 182.82,28.3 182.44,28.69 180.1,28.69 179.59,29.2 179.59,33.98 178.07,35.5 178.07,36.89 176.38,38.58 176.38,41.33 177.01,41.96 178.92,41.96 180.38,40.5 183.45,40.5 184.18,41.22 184.18,42.75 182.57,44.36 182,44.36 v2(181.75,44.61)
1G_P7_TXVB_N: length 36.8
  TOP w0.091: v2(184.54,36.22) 184.78,36.47 184.78,36.75 183.64,37.9 181.56,37.9 179.48,39.98 178.55,39.98 177.93,40.6 177.93,40.97 177.79,41.1 U620.36
  L14_INT_6 w0.086: J14.16 185.21,25.12 185.21,25.54 184.53,26.21 184.53,27.41 184.47,27.48 184.47,29.2 184.25,29.41 182.78,29.41 182.3,29.9 182.3,31.75 181.99,32.05 180.82,32.05 180.4,32.47 180.4,33.26 180.82,33.68 188.17,33.68 188.33,33.84 188.33,34.39 188.19,34.53 185.25,34.53 184.8,34.99 184.8,35.97 v2(184.54,36.22)
1G_P7_TXVB_P: length 36.9
  TOP w0.091: U620.37 178.3,41.06 178.21,40.97 178.21,40.72 178.66,40.26 179.59,40.26 181.68,38.18 183.76,38.18 185.06,36.87 185.06,36.51 v2(185.35,36.22)
  L14_INT_6 w0.086: J14.23 185.62,25.86 185.52,25.75 185.3,25.75 184.75,26.3 184.75,27.41 184.81,27.48 184.81,29.34 184.39,29.76 182.92,29.76 182.64,30.04 182.64,31.89 182.13,32.4 180.96,32.4 180.75,32.61 180.75,33.12 180.96,33.34 188.31,33.34 188.67,33.7 188.67,34.53 188.33,34.87 185.39,34.87 185.14,35.13 185.14,36.01 v2(185.35,36.22)
1G_P7_TXVC_N: length 37.4
  TOP w0.091: v2(180.99,36.46) 180.72,36.73 179.84,36.73 179.43,37.15 179.43,38.61 178.82,39.22 177.73,39.22 176.91,40.04 176.91,40.91 176.79,41.03 U620.34
  L14_INT_6 w0.086: J14.24 187.6,25.94 187.77,25.78 187.95,25.78 188.49,26.32 188.49,27.48 188.43,27.54 188.43,28.94 188.06,29.31 186.66,29.31 186.07,29.91 186.07,31.59 186.76,32.28 190.37,32.28 190.88,32.79 190.88,36.73 190.47,37.13 182.55,37.13 182.09,36.68 181.2,36.68 v2(180.99,36.46)
1G_P7_TXVC_P: length 37.5
  TOP w0.091: v2(180.99,37.27) 180.72,37.01 179.96,37.01 179.71,37.26 179.71,38.72 178.93,39.5 177.85,39.5 177.19,40.16 177.19,40.92 177.3,41.03 U620.35
  L14_INT_6 w0.086: v2(180.99,37.27) 181.24,37.02 181.95,37.02 182.41,37.48 190.62,37.48 191.22,36.87 191.22,32.65 190.51,31.94 186.91,31.94 186.41,31.45 186.41,30.05 186.8,29.65 188.2,29.65 188.77,29.08 188.77,27.54 188.71,27.48 188.71,26.23 188.04,25.56 188.04,25.1 J14.18
1G_P7_TXVD_N: length 37.9
  TOP w0.091: U620.31 175.3,41.03 175.41,40.92 175.41,40.66 175.82,40.25 175.82,39.33 177.96,37.19 178.44,37.19 v2(178.65,36.97)
  L14_INT_6 w0.086: J14.19 190.58,24.54 191.16,25.12 191.16,25.57 190.47,26.26 190.47,27.36 190.4,27.42 190.4,28.94 190.87,29.4 192.52,29.4 193.64,30.52 193.64,36.03 191.21,38.46 180.04,38.46 179.71,38.13 179.71,37.57 179.3,37.16 178.84,37.16 v2(178.65,36.97)
1G_P7_TXVD_P: length 38
  TOP w0.091: U620.32 175.79,41.03 175.68,40.92 175.68,40.78 176.1,40.36 176.1,39.45 178.08,37.47 178.42,37.47 v2(178.62,37.67)
  L14_INT_6 w0.086: J14.26 191.57,25.9 191.47,25.8 191.22,25.8 190.68,26.34 190.68,27.36 190.75,27.42 190.75,28.79 191.01,29.06 192.66,29.06 193.98,30.38 193.98,36.17 191.35,38.8 179.89,38.8 179.36,38.27 179.36,37.71 179.16,37.5 178.79,37.5 v2(178.62,37.67)
10G_LAN_GPIO0_N: length 12.5
  TOP w0.118: Q3.3 203.2,16.51 204.32,15.39 204.32,7.8 203.71,7.19 LED6.1
10G_LAN_GPIO1_N: length 9.3
  TOP w0.118: Q4.3 202.69,15.3 LED6.3
10G_LAN_GPIO2_N: length 16.8
  TOP w0.118: LED5.1 274.98,8.61 274.98,16.1 273.18,17.91 Q5.3
10G_LAN_GPIO3_N: length 14.3
  TOP w0.118: LED5.3 273.56,15.62 270.26,18.92 Q6.3
ALT_RST_B: length 15.4
  TOP w0.102: U27.L11 59.06,76.8 58.64,77.22 54.81,77.22
  TOP w0.118: JP7.1 47.27,79.38 50.39,76.26 52.03,76.26 v1(52.6,75.69) 54.13,77.22 54.81,77.22
ASLEEP: length 156.3
  TOP w0.118: U22.G34 88.83,147.7 v3(89.33,148.2)
  L3_INT_1 w0.087: v3(89.33,148.2) 88.71,148.82 87.78,148.82 84.81,151.79 75.84,151.79 74.98,150.93 72.66,150.93 71.27,149.54 71.27,147.8 71.96,147.12 73.53,147.12 77.32,143.33 77.32,127.33 78.03,126.62 78.03,125.22 79.38,123.88 79.38,122.96 80.04,122.3 88.52,122.3 93.22,117.6 93.22,112.19 92.46,111.43 70.73,111.43 67.71,108.41 67.71,108.21 61.84,102.34 61.84,80.65 61.57,80.38 61.31,80.38 61.04,80.11 61.04,71.05 60.77,70.78 59.5,70.78 58.33,69.6 v1(57.47,69.6)
  BOTTOM w0.118: v3(89.33,148.2) 89.62,148.2 90.12,147.7 90.49,147.7 90.86,147.33 90.86,143.81 90.55,143.5 90.55,140.58 91.22,139.91 91.23,139.91 R762.2 R5762.1
ATX_PWROK: length 67.2
  TOP w0.118: U27.L15 55.87,76.8 55.48,76.41 54.67,76.41 53.06,74.8 50.22,74.8 47.9,77.11 45.77,77.11 40.97,81.92 40.97,91.26 38.43,93.8 26.82,93.8 22.48,98.15 22.48,107.49 19.2,110.77 17.25,110.77 R342.2
ATXPWRGD: length 17.7
  TOP w0.118: R342.1 R337.2 14.86,113.85 14.87,113.86 C299.1 14.87,117.52 12.93,119.46 5.79,119.46 J9.8
CFG_DDRCLK: length 50.8
  TOP w0.118: U627.8 110.54,94.68 v2(110,94.14)
  L3_INT_1 w0.087: v2(110,94.14) 109.51,93.65 93.83,93.65 87,86.82 76.28,86.82 v1(67.07,77.6)
CFG_SYSCLK: length 52.2
  TOP w0.118: v2(108.05,96.8) 107.47,96.22 U626.8
  L3_INT_1 w0.087: v2(108.05,96.8) 107.75,97.1 96.32,97.1 86.74,87.53 72.08,87.53 65.84,81.29 65.84,79.58 v1(65.47,79.2)
CFG_TESTSEL_B: length 98.8
  TOP w0.118: U22.F34 88.33,147.19 v3(88.33,147.2)
  L5_INT_2 w0.087: v3(88.33,147.2) 87.88,146.75 87.88,146.18 87.38,145.67 79.27,145.67 77.24,143.64 77.24,132.28 73.79,128.83 73.79,125.18 64.66,116.05 64.66,116.04 63.98,115.37 63.98,91.47 67.53,87.92 67.53,78.68 66.09,77.24 65.35,77.24 65.07,76.96 65.07,75.6 v1(65.47,75.2)
  BOTTOM w0.118: R765.2 88.39,140.08 88.39,141.37 88.82,141.8 88.82,146.7 v3(88.33,147.2)
CFG_VBANK0: length 44.9
  TOP w0.118: U595.2 v2(90.35,103.11)
  BOTTOM w0.118: v2(90.35,103.11) 88.66,104.8 81.51,104.8 76.17,99.47 76.17,94.03 70.31,88.16 66.45,88.16 61.47,83.18 v1(61.47,80.8)
CFG_VBANK1: length 40.6
  TOP w0.118: U596.2 87.38,102.95 v2(87.15,103.17)
  BOTTOM w0.118: v2(87.15,103.17) 85.98,104.34 81.86,104.34 76.76,99.24 76.76,93.8 70.64,87.68 66.83,87.68 62.27,83.12 v1(62.27,80.8)
CFG_VBANK2: length 32.8
  TOP w0.118: U598.2 v2(84.37,103.11)
  BOTTOM w0.118: v1(66.27,80.8) 66.27,82.5 77.62,93.85 77.62,99.16 82.22,103.76 83.72,103.76 v2(84.37,103.11)
CGND: length 3366.3
  TOP w0.508: J13.S1 174.17,3.36 ; J13.S1 172.31,3.36 ; J13.S1 174.17,5.23 ; J14.S4 179.15,19.72 ; J14.S4 179.15,21.58 ; J14.S4 177.29,19.72 ; J14.S4 177.29,21.58 ; 45.35,6.68 CN4.M4 ; CN4.M4 47.79,9.11 ; CN4.M4 47.79,6.68 ; CN4.M4 45.35,9.11 ; 155.52,3.36 J13.S2 ; J13.S2 157.38,3.36 ; J13.S2 155.52,5.23 ; J13.S4 157.38,19.72 ; J13.S4 155.52,19.72 ; J13.S4 157.38,21.58 ; J13.S4 155.52,21.58 ; 45.35,12.36 CN4.M2 ; CN4.M2 47.79,12.36 ; CN4.M2 47.79,14.79 ; J12.S1 152.4,3.36 ; J12.S1 150.54,3.36 ; J12.S1 152.4,5.23 ; J14.S1 195.94,3.36 ; J14.S1 194.08,3.36 ; J14.S1 195.94,5.23 ; 128.77,21.58 J11.S3 ; J11.S3 130.63,21.58 ; J11.S3 128.77,19.72 ; J11.S3 130.63,19.72 ; v2(203.05,28.11) 203.05,28.82 203.47,29.25 FB71.2 203.52,29.25 203.94,28.82 v2(203.94,28.06) ; J14.S3 195.94,21.58 ; J14.S3 194.08,19.72 ; J14.S3 194.08,21.58 ; J14.S3 195.94,19.72 ; 51.57,25.24 LAN1.S1 ; LAN1.S1 53.42,23.4 ; LAN1.S1 53.42,25.24 ; LAN1.S1 51.57,23.4 ; J11.S4 111.89,21.68 111.42,21.68 108.84,24.26 108.84,30.35 103.96,35.23 ESD10.2 ; J11.S4 111.98,19.72 ; J11.S4 113.84,19.72 ; J11.S4 113.84,21.58 ; J11.S1 130.63,5.23 ; J11.S1 130.63,3.36 ; J11.S1 128.77,3.36 ; LAN1.S5 53.42,5.21 ; LAN1.S5 51.57,3.37 ; LAN1.S5 53.42,3.37 ; LAN1.S5 51.57,5.21 ; v2(72.52,22.1) 73.15,22.1 73.18,22.07 74.07,22.07 76.12,24.13 76.12,33.6 77.29,34.77 ESD9.2 ; LAN1.S4 69.76,15.63 ; LAN1.S4 67.92,15.63 ; LAN1.S4 67.92,13.79 ; LAN1.S4 69.76,13.79 ; J11.S2 113.84,3.36 ; J11.S2 111.98,5.23 ; J11.S2 111.98,3.36 ; J12.S3 152.4,19.72 ; J12.S3 150.54,19.72 ; J12.S3 150.54,21.58 ; J12.S3 152.4,21.58 ; v2(200.1,28.11) 200.1,28.82 200.52,29.25 FB72.2 200.57,29.25 200.99,28.82 v2(200.99,28.06) ; LAN1.S3 54.08,18.93 ; LAN1.S3 52.24,17.09 ; LAN1.S3 54.08,17.09 ; LAN1.S3 52.24,18.93 ; 133.75,19.72 J12.S4 ; J12.S4 135.61,19.72 ; J12.S4 133.75,21.58 ; J12.S4 135.61,21.58 ; LAN1.S2 70.43,21.18 ; LAN1.S2 68.58,19.34 ; LAN1.S2 68.58,21.18 ; LAN1.S2 70.43,19.34 ; LAN1.S6 70.43,5.21 ; LAN1.S6 70.43,3.37 ; LAN1.S6 68.58,3.37 ; LAN1.S6 68.58,5.21 ; 172.31,19.72 J13.S3 ; J13.S3 174.17,19.72 ; J13.S3 172.31,21.58 ; J13.S3 174.17,21.58 ; 177.29,5.23 J14.S2 ; J14.S2 177.29,3.36 ; J14.S2 179.15,3.36 ; 133.75,5.23 J12.S2 ; J12.S2 133.75,3.36 ; J12.S2 135.61,3.36 ; v2(270.33,28.11) 270.33,28.82 270.75,29.25 FB70.2 270.8,29.25 271.22,28.82 v2(271.22,28.06) ; 32.21,6.68 CN4.M3 34.65,6.68
  L2_GND_1 w0.508: LAN1.S2 70.43,21.18 ; LAN1.S2 68.58,21.18 ; LAN1.S2 68.58,19.34 ; LAN1.S2 70.43,19.34 ; 221.71,15.82 J16.S12 ; J16.S12 223.49,17.6 ; J16.S12 223.49,15.82 ; J16.S12 221.71,17.6 ; 221.71,7.6 J16.S13 ; J16.S13 221.71,5.82 ; J16.S13 223.49,5.82 ; J16.S13 223.49,7.6 ; J14.S1 195.94,5.23 ; J14.S1 194.08,3.36 ; J14.S1 195.94,3.36 ; J14.S3 195.94,21.58 ; J14.S3 195.94,19.72 ; J14.S3 194.08,19.72 ; J14.S3 194.08,21.58 ; 67.92,13.79 LAN1.S4 ; LAN1.S4 69.76,13.79 ; LAN1.S4 69.76,15.63 ; LAN1.S4 67.92,15.63 ; J11.S4 113.84,19.72 ; J11.S4 111.98,19.72 ; J11.S4 113.84,21.58 ; J11.S4 111.98,21.58 ; J16.S32 266.24,25.82 ; J16.S32 264.46,25.82 ; J16.S32 264.46,27.6 ; J16.S32 266.24,27.6 ; J12.S2 135.61,3.36 ; J12.S2 133.75,3.36 ; J12.S2 133.75,5.23 ; J11.S1 130.63,5.23 ; J11.S1 130.63,3.36 ; J11.S1 128.77,3.36 ; 221.71,25.82 J16.S11 ; J16.S11 221.71,27.6 ; J16.S11 223.49,25.82 ; J16.S11 223.49,27.6 ; J11.S3 130.63,21.58 ; J11.S3 130.63,19.72 ; J11.S3 128.77,21.58 ; J11.S3 128.77,19.72 ; J12.S1 152.4,3.36 ; J12.S1 152.4,5.23 ; J12.S1 150.54,3.36 ; J13.S3 174.17,19.72 ; J13.S3 174.17,21.58 ; J13.S3 172.31,19.72 ; J13.S3 172.31,21.58 ; J16.S31 266.07,30.23 ; J16.S31 264.63,28.79 ; J16.S31 266.07,28.79 ; J16.S31 264.63,30.23 ; 150.54,19.72 J12.S3 ; J12.S3 150.54,21.58 ; J12.S3 152.4,21.58 ; J12.S3 152.4,19.72 ; J13.S2 157.38,3.36 ; J13.S2 155.52,5.23 ; J13.S2 155.52,3.36 ; 45.35,9.11 CN4.M4 ; CN4.M4 47.79,9.11 ; CN4.M4 47.79,6.68 ; CN4.M4 45.35,6.68 ; 250.39,30.23 J16.S24 ; J16.S24 250.39,28.79 ; J16.S24 251.82,30.23 ; J16.S24 251.82,28.79 ; 235.96,12.6 J16.S19 ; J16.S19 237.74,10.82 ; J16.S19 235.96,10.82 ; J16.S19 237.74,12.6 ; J16.S2 209.24,20.82 ; J16.S2 207.46,22.6 ; J16.S2 209.24,22.6 ; J16.S2 207.46,20.82 ; 51.57,5.21 LAN1.S5 ; LAN1.S5 53.42,5.21 ; LAN1.S5 53.42,3.37 ; LAN1.S5 51.57,3.37 ; 52.24,17.09 LAN1.S3 ; LAN1.S3 52.24,18.93 ; LAN1.S3 54.08,18.93 ; LAN1.S3 54.08,17.09 ; 264.46,7.6 J16.S34 ; J16.S34 264.46,5.82 ; J16.S34 266.24,5.82 ; J16.S34 266.24,7.6 ; LAN1.S1 53.42,23.4 ; LAN1.S1 51.57,25.24 ; LAN1.S1 51.57,23.4 ; LAN1.S1 53.42,25.24 ; J11.S2 113.84,3.36 ; J11.S2 111.98,3.36 ; J11.S2 111.98,5.23 ; 207.46,10.82 J16.S1 ; J16.S1 207.46,12.6 ; J16.S1 209.24,10.82 ; J16.S1 209.24,12.6 ; CN4.M3 34.65,6.68 ; CN4.M3 32.21,9.11 ; CN4.M3 32.21,6.68 ; CN4.M3 34.65,9.11 ; 250.21,12.6 J16.S26 ; J16.S26 251.99,12.6 ; J16.S26 250.21,10.82 ; J16.S26 251.99,10.82 ; 264.46,15.82 J16.S33 ; J16.S33 266.24,15.82 ; J16.S33 266.24,17.6 ; J16.S33 264.46,17.6 ; CN4.M2 47.79,14.79 ; CN4.M2 45.35,12.36 ; CN4.M2 47.79,12.36 ; J13.S1 174.17,5.23 ; J13.S1 172.31,3.36 ; J13.S1 174.17,3.36 ; 155.52,19.72 J13.S4 ; J13.S4 155.52,21.58 ; J13.S4 157.38,21.58 ; J13.S4 157.38,19.72 ; 207.64,28.79 J16.S3 ; J16.S3 209.07,30.23 ; J16.S3 209.07,28.79 ; J16.S3 207.64,30.23 ; J16.S10 223.32,30.23 ; J16.S10 221.89,30.23 ; J16.S10 221.89,28.79 ; J16.S10 223.32,28.79 ; 133.75,19.72 J12.S4 ; J12.S4 135.61,21.58 ; J12.S4 135.61,19.72 ; J12.S4 133.75,21.58 ; 235.96,22.6 J16.S18 ; J16.S18 237.74,22.6 ; J16.S18 237.74,20.82 ; J16.S18 235.96,20.82 ; LAN1.S6 70.43,5.21 ; LAN1.S6 70.43,3.37 ; LAN1.S6 68.58,5.21 ; LAN1.S6 68.58,3.37 ; 177.29,19.72 J14.S4 ; J14.S4 179.15,21.58 ; J14.S4 179.15,19.72 ; J14.S4 177.29,21.58 ; CN4.M1 34.65,12.36 ; CN4.M1 32.21,14.79 ; CN4.M1 34.65,14.79 ; CN4.M1 32.21,12.36 ; 177.29,5.23 J14.S2 ; J14.S2 177.29,3.36 ; J14.S2 179.15,3.36 ; 250.21,20.82 J16.S25 ; J16.S25 251.99,20.82 ; J16.S25 250.21,22.6 ; J16.S25 251.99,22.6
  L3_INT_1 w0.508: 250.21,12.6 J16.S26 ; J16.S26 250.21,10.82 ; J16.S26 251.99,10.82 ; J16.S26 251.99,12.6 ; J11.S3 130.63,19.72 ; J11.S3 130.63,21.58 ; J11.S3 128.77,21.58 ; J11.S3 128.77,19.72 ; CN4.M1 34.65,14.79 ; CN4.M1 32.21,14.79 ; CN4.M1 32.21,12.36 ; CN4.M1 34.65,12.36 ; J13.S4 157.38,19.72 ; J13.S4 155.52,21.58 ; J13.S4 157.38,21.58 ; J13.S4 155.52,19.72 ; 68.58,19.34 LAN1.S2 ; LAN1.S2 70.43,21.18 ; LAN1.S2 70.43,19.34 ; LAN1.S2 68.58,21.18 ; J16.S10 223.32,30.23 ; J16.S10 221.89,30.23 ; J16.S10 221.89,28.79 ; J16.S10 223.32,28.79 ; J12.S4 135.61,21.58 ; J12.S4 133.75,19.72 ; J12.S4 133.75,21.58 ; J12.S4 135.61,19.72 ; LAN1.S6 70.43,3.37 ; LAN1.S6 70.43,5.21 ; LAN1.S6 68.58,3.37 ; LAN1.S6 68.58,5.21 ; 235.96,20.82 J16.S18 ; J16.S18 235.96,22.6 ; J16.S18 237.74,22.6 ; J16.S18 237.74,20.82 ; J14.S2 179.15,3.36 ; J14.S2 177.29,5.23 ; J14.S2 177.29,3.36 ; 155.52,5.23 J13.S2 ; J13.S2 157.38,3.36 ; J13.S2 155.52,3.36 ; 177.29,21.58 J14.S4 ; J14.S4 179.15,21.58 ; J14.S4 177.29,19.72 ; J14.S4 179.15,19.72 ; J11.S1 130.63,5.23 ; J11.S1 130.63,3.36 ; J11.S1 128.77,3.36 ; 207.46,10.82 J16.S1 ; J16.S1 207.46,12.6 ; J16.S1 209.24,10.82 ; J16.S1 209.24,12.6 ; J13.S1 174.17,5.23 ; J13.S1 174.17,3.36 ; J13.S1 172.31,3.36 ; CN4.M4 47.79,6.68 ; CN4.M4 47.79,9.11 ; CN4.M4 45.35,9.11 ; CN4.M4 45.35,6.68 ; 264.46,17.6 J16.S33 ; J16.S33 266.24,17.6 ; J16.S33 266.24,15.82 ; J16.S33 264.46,15.82 ; 207.46,20.82 J16.S2 ; J16.S2 209.24,22.6 ; J16.S2 209.24,20.82 ; J16.S2 207.46,22.6 ; 235.96,10.82 J16.S19 ; J16.S19 235.96,12.6 ; J16.S19 237.74,12.6 ; J16.S19 237.74,10.82 ; 250.21,22.6 J16.S25 ; J16.S25 250.21,20.82 ; J16.S25 251.99,22.6 ; J16.S25 251.99,20.82 ; J14.S3 195.94,19.72 ; J14.S3 194.08,21.58 ; J14.S3 195.94,21.58 ; J14.S3 194.08,19.72 ; 172.31,21.58 J13.S3 ; J13.S3 172.31,19.72 ; J13.S3 174.17,19.72 ; J13.S3 174.17,21.58 ; 221.71,27.6 J16.S11 ; J16.S11 223.49,25.82 ; J16.S11 223.49,27.6 ; J16.S11 221.71,25.82 ; LAN1.S5 53.42,5.21 ; LAN1.S5 53.42,3.37 ; LAN1.S5 51.57,5.21 ; LAN1.S5 51.57,3.37 ; 250.39,28.79 J16.S24 ; J16.S24 251.82,28.79 ; J16.S24 250.39,30.23 ; J16.S24 251.82,30.23 ; J12.S2 135.61,3.36 ; J12.S2 133.75,5.23 ; J12.S2 133.75,3.36 ; J16.S3 209.07,28.79 ; J16.S3 209.07,30.23 ; J16.S3 207.64,28.79 ; J16.S3 207.64,30.23 ; J14.S1 195.94,5.23 ; J14.S1 194.08,3.36 ; J14.S1 195.94,3.36 ; J16.S34 266.24,7.6 ; J16.S34 264.46,7.6 ; J16.S34 264.46,5.82 ; J16.S34 266.24,5.82 ; J16.S13 223.49,7.6 ; J16.S13 223.49,5.82 ; J16.S13 221.71,5.82 ; J16.S13 221.71,7.6 ; J11.S2 113.84,3.36 ; J11.S2 111.98,5.23 ; J11.S2 111.98,3.36 ; J12.S1 152.4,5.23 ; J12.S1 152.4,3.36 ; J12.S1 150.54,3.36 ; CN4.M3 34.65,6.68 ; CN4.M3 32.21,9.11 ; CN4.M3 34.65,9.11 ; CN4.M3 32.21,6.68 ; LAN1.S3 54.08,18.93 ; LAN1.S3 54.08,17.09 ; LAN1.S3 52.24,17.09 ; LAN1.S3 52.24,18.93 ; 264.63,28.79 J16.S31 ; J16.S31 266.07,28.79 ; J16.S31 264.63,30.23 ; J16.S31 266.07,30.23 ; LAN1.S4 69.76,15.63 ; LAN1.S4 67.92,15.63 ; LAN1.S4 69.76,13.79 ; LAN1.S4 67.92,13.79 ; LAN1.S1 53.42,23.4 ; LAN1.S1 53.42,25.24 ; LAN1.S1 51.57,23.4 ; LAN1.S1 51.57,25.24 ; 45.35,12.36 CN4.M2 ; CN4.M2 47.79,14.79 ; CN4.M2 47.79,12.36 ; 111.98,19.72 J11.S4 ; J11.S4 111.98,21.58 ; J11.S4 113.84,19.72 ; J11.S4 113.84,21.58 ; 150.54,21.58 J12.S3 ; J12.S3 152.4,21.58 ; J12.S3 152.4,19.72 ; J12.S3 150.54,19.72 ; 264.46,27.6 J16.S32 ; J16.S32 264.46,25.82 ; J16.S32 266.24,25.82 ; J16.S32 266.24,27.6 ; J16.S12 223.49,17.6 ; J16.S12 221.71,17.6 ; J16.S12 221.71,15.82 ; J16.S12 223.49,15.82
  L4_GND_2 w0.508: J11.S1 130.63,3.36 ; J11.S1 130.63,5.23 ; J11.S1 128.77,3.36 ; LAN1.S6 70.43,5.21 ; LAN1.S6 70.43,3.37 ; LAN1.S6 68.58,5.21 ; LAN1.S6 68.58,3.37 ; J14.S4 179.15,19.72 ; J14.S4 177.29,21.58 ; J14.S4 179.15,21.58 ; J14.S4 177.29,19.72 ; 264.46,17.6 J16.S33 ; J16.S33 266.24,15.82 ; J16.S33 264.46,15.82 ; J16.S33 266.24,17.6 ; 51.57,3.37 LAN1.S5 ; LAN1.S5 53.42,3.37 ; LAN1.S5 53.42,5.21 ; LAN1.S5 51.57,5.21 ; J12.S1 152.4,5.23 ; J12.S1 152.4,3.36 ; J12.S1 150.54,3.36 ; J16.S24 251.82,30.23 ; J16.S24 250.39,28.79 ; J16.S24 251.82,28.79 ; J16.S24 250.39,30.23 ; J13.S4 157.38,21.58 ; J13.S4 157.38,19.72 ; J13.S4 155.52,21.58 ; J13.S4 155.52,19.72 ; J16.S18 237.74,20.82 ; J16.S18 235.96,20.82 ; J16.S18 235.96,22.6 ; J16.S18 237.74,22.6 ; J16.S31 266.07,30.23 ; J16.S31 266.07,28.79 ; J16.S31 264.63,28.79 ; J16.S31 264.63,30.23 ; J16.S11 223.49,25.82 ; J16.S11 221.71,25.82 ; J16.S11 223.49,27.6 ; J16.S11 221.71,27.6 ; J16.S19 237.74,12.6 ; J16.S19 237.74,10.82 ; J16.S19 235.96,12.6 ; J16.S19 235.96,10.82 ; 207.46,12.6 J16.S1 ; J16.S1 209.24,12.6 ; J16.S1 209.24,10.82 ; J16.S1 207.46,10.82 ; 150.54,21.58 J12.S3 ; J12.S3 150.54,19.72 ; J12.S3 152.4,19.72 ; J12.S3 152.4,21.58 ; J14.S1 195.94,3.36 ; J14.S1 195.94,5.23 ; J14.S1 194.08,3.36 ; J11.S3 130.63,21.58 ; J11.S3 130.63,19.72 ; J11.S3 128.77,19.72 ; J11.S3 128.77,21.58 ; 177.29,3.36 J14.S2 ; J14.S2 177.29,5.23 ; J14.S2 179.15,3.36 ; 221.71,7.6 J16.S13 ; J16.S13 223.49,7.6 ; J16.S13 221.71,5.82 ; J16.S13 223.49,5.82 ; LAN1.S1 53.42,23.4 ; LAN1.S1 51.57,23.4 ; LAN1.S1 53.42,25.24 ; LAN1.S1 51.57,25.24 ; J14.S3 195.94,19.72 ; J14.S3 195.94,21.58 ; J14.S3 194.08,19.72 ; J14.S3 194.08,21.58 ; 133.75,19.72 J12.S4 ; J12.S4 135.61,19.72 ; J12.S4 135.61,21.58 ; J12.S4 133.75,21.58 ; 111.98,21.58 J11.S4 ; J11.S4 113.84,21.58 ; J11.S4 111.98,19.72 ; J11.S4 113.84,19.72 ; 133.75,5.23 J12.S2 ; J12.S2 135.61,3.36 ; J12.S2 133.75,3.36 ; J13.S1 174.17,5.23 ; J13.S1 174.17,3.36 ; J13.S1 172.31,3.36 ; J13.S3 174.17,21.58 ; J13.S3 174.17,19.72 ; J13.S3 172.31,19.72 ; J13.S3 172.31,21.58 ; J16.S10 223.32,30.23 ; J16.S10 221.89,28.79 ; J16.S10 221.89,30.23 ; J16.S10 223.32,28.79 ; 264.46,7.6 J16.S34 ; J16.S34 266.24,5.82 ; J16.S34 264.46,5.82 ; J16.S34 266.24,7.6 ; J13.S2 157.38,3.36 ; J13.S2 155.52,5.23 ; J13.S2 155.52,3.36 ; 45.35,9.11 CN4.M4 ; CN4.M4 45.35,6.68 ; CN4.M4 47.79,6.68 ; CN4.M4 47.79,9.11 ; 250.21,22.6 J16.S25 ; J16.S25 250.21,20.82 ; J16.S25 251.99,22.6 ; J16.S25 251.99,20.82 ; 264.46,25.82 J16.S32 ; J16.S32 264.46,27.6 ; J16.S32 266.24,25.82 ; J16.S32 266.24,27.6 ; LAN1.S3 54.08,18.93 ; LAN1.S3 52.24,17.09 ; LAN1.S3 54.08,17.09 ; LAN1.S3 52.24,18.93 ; 207.64,30.23 J16.S3 ; J16.S3 209.07,28.79 ; J16.S3 207.64,28.79 ; J16.S3 209.07,30.23 ; J16.S12 223.49,15.82 ; J16.S12 221.71,17.6 ; J16.S12 221.71,15.82 ; J16.S12 223.49,17.6 ; 207.46,20.82 J16.S2 ; J16.S2 207.46,22.6 ; J16.S2 209.24,22.6 ; J16.S2 209.24,20.82 ; 67.92,15.63 LAN1.S4 ; LAN1.S4 67.92,13.79 ; LAN1.S4 69.76,13.79 ; LAN1.S4 69.76,15.63 ; LAN1.S2 70.43,19.34 ; LAN1.S2 70.43,21.18 ; LAN1.S2 68.58,19.34 ; LAN1.S2 68.58,21.18 ; CN4.M3 34.65,6.68 ; CN4.M3 32.21,9.11 ; CN4.M3 32.21,6.68 ; CN4.M3 34.65,9.11 ; 45.35,12.36 CN4.M2 ; CN4.M2 47.79,12.36 ; CN4.M2 47.79,14.79 ; J16.S26 251.99,10.82 ; J16.S26 251.99,12.6 ; J16.S26 250.21,12.6 ; J16.S26 250.21,10.82 ; 111.98,5.23 J11.S2 ; J11.S2 113.84,3.36 ; J11.S2 111.98,3.36 ; 32.21,14.79 CN4.M1 ; CN4.M1 32.21,12.36 ; CN4.M1 34.65,14.79 ; CN4.M1 34.65,12.36
  L5_INT_2 w0.508: 235.96,12.6 J16.S19 ; J16.S19 237.74,12.6 ; J16.S19 237.74,10.82 ; J16.S19 235.96,10.82 ; LAN1.S3 54.08,18.93 ; LAN1.S3 52.24,18.93 ; LAN1.S3 54.08,17.09 ; LAN1.S3 52.24,17.09 ; J11.S4 113.84,19.72 ; J11.S4 111.98,21.58 ; J11.S4 113.84,21.58 ; J11.S4 111.98,19.72 ; J16.S13 223.49,7.6 ; J16.S13 223.49,5.82 ; J16.S13 221.71,7.6 ; J16.S13 221.71,5.82 ; 207.64,28.79 J16.S3 ; J16.S3 209.07,30.23 ; J16.S3 207.64,30.23 ; J16.S3 209.07,28.79 ; 111.98,3.36 J11.S2 ; J11.S2 113.84,3.36 ; J11.S2 111.98,5.23 ; J13.S1 174.17,5.23 ; J13.S1 172.31,3.36 ; J13.S1 174.17,3.36 ; CN4.M2 47.79,12.36 ; CN4.M2 47.79,14.79 ; CN4.M2 45.35,12.36 ; J11.S1 130.63,5.23 ; J11.S1 128.77,3.36 ; J11.S1 130.63,3.36 ; J16.S33 266.24,17.6 ; J16.S33 266.24,15.82 ; J16.S33 264.46,17.6 ; J16.S33 264.46,15.82 ; 235.96,22.6 J16.S18 ; J16.S18 235.96,20.82 ; J16.S18 237.74,20.82 ; J16.S18 237.74,22.6 ; 221.71,15.82 J16.S12 ; J16.S12 221.71,17.6 ; J16.S12 223.49,15.82 ; J16.S12 223.49,17.6 ; 133.75,21.58 J12.S4 ; J12.S4 133.75,19.72 ; J12.S4 135.61,19.72 ; J12.S4 135.61,21.58 ; 177.29,3.36 J14.S2 ; J14.S2 177.29,5.23 ; J14.S2 179.15,3.36 ; 172.31,21.58 J13.S3 ; J13.S3 174.17,19.72 ; J13.S3 172.31,19.72 ; J13.S3 174.17,21.58 ; J16.S32 266.24,27.6 ; J16.S32 266.24,25.82 ; J16.S32 264.46,25.82 ; J16.S32 264.46,27.6 ; 221.71,27.6 J16.S11 ; J16.S11 223.49,25.82 ; J16.S11 221.71,25.82 ; J16.S11 223.49,27.6 ; CN4.M4 47.79,9.11 ; CN4.M4 47.79,6.68 ; CN4.M4 45.35,9.11 ; CN4.M4 45.35,6.68 ; 250.21,20.82 J16.S25 ; J16.S25 251.99,22.6 ; J16.S25 250.21,22.6 ; J16.S25 251.99,20.82 ; 207.46,20.82 J16.S2 ; J16.S2 209.24,22.6 ; J16.S2 209.24,20.82 ; J16.S2 207.46,22.6 ; J13.S4 157.38,21.58 ; J13.S4 155.52,21.58 ; J13.S4 157.38,19.72 ; J13.S4 155.52,19.72 ; LAN1.S5 53.42,5.21 ; LAN1.S5 51.57,5.21 ; LAN1.S5 53.42,3.37 ; LAN1.S5 51.57,3.37 ; 150.54,3.36 J12.S1 ; J12.S1 152.4,5.23 ; J12.S1 152.4,3.36 ; J16.S34 266.24,5.82 ; J16.S34 266.24,7.6 ; J16.S34 264.46,5.82 ; J16.S34 264.46,7.6 ; J14.S4 179.15,19.72 ; J14.S4 177.29,19.72 ; J14.S4 179.15,21.58 ; J14.S4 177.29,21.58 ; CN4.M1 34.65,14.79 ; CN4.M1 32.21,14.79 ; CN4.M1 32.21,12.36 ; CN4.M1 34.65,12.36 ; 264.63,30.23 J16.S31 ; J16.S31 266.07,30.23 ; J16.S31 266.07,28.79 ; J16.S31 264.63,28.79 ; 128.77,21.58 J11.S3 ; J11.S3 130.63,19.72 ; J11.S3 128.77,19.72 ; J11.S3 130.63,21.58 ; LAN1.S4 69.76,13.79 ; LAN1.S4 69.76,15.63 ; LAN1.S4 67.92,13.79 ; LAN1.S4 67.92,15.63 ; J14.S1 195.94,5.23 ; J14.S1 194.08,3.36 ; J14.S1 195.94,3.36 ; 68.58,19.34 LAN1.S2 ; LAN1.S2 70.43,21.18 ; LAN1.S2 70.43,19.34 ; LAN1.S2 68.58,21.18 ; 32.21,6.68 CN4.M3 ; CN4.M3 34.65,6.68 ; CN4.M3 32.21,9.11 ; CN4.M3 34.65,9.11 ; J14.S3 195.94,19.72 ; J14.S3 194.08,19.72 ; J14.S3 194.08,21.58 ; J14.S3 195.94,21.58 ; 250.39,30.23 J16.S24 ; J16.S24 251.82,28.79 ; J16.S24 251.82,30.23 ; J16.S24 250.39,28.79 ; 150.54,19.72 J12.S3 ; J12.S3 152.4,21.58 ; J12.S3 150.54,21.58 ; J12.S3 152.4,19.72 ; J16.S26 251.99,10.82 ; J16.S26 251.99,12.6 ; J16.S26 250.21,10.82 ; J16.S26 250.21,12.6 ; 221.89,28.79 J16.S10 ; J16.S10 221.89,30.23 ; J16.S10 223.32,30.23 ; J16.S10 223.32,28.79 ; 68.58,3.37 LAN1.S6 ; LAN1.S6 70.43,5.21 ; LAN1.S6 70.43,3.37 ; LAN1.S6 68.58,5.21 ; 51.57,23.4 LAN1.S1 ; LAN1.S1 53.42,23.4 ; LAN1.S1 53.42,25.24 ; LAN1.S1 51.57,25.24 ; J16.S1 209.24,12.6 ; J16.S1 207.46,10.82 ; J16.S1 207.46,12.6 ; J16.S1 209.24,10.82 ; J13.S2 157.38,3.36 ; J13.S2 155.52,5.23 ; J13.S2 155.52,3.36 ; J12.S2 135.61,3.36 ; J12.S2 133.75,5.23 ; J12.S2 133.75,3.36
  L6_GND_3 w0.508: J16.S1 209.24,10.82 ; J16.S1 207.46,12.6 ; J16.S1 207.46,10.82 ; J16.S1 209.24,12.6 ; 128.77,3.36 J11.S1 ; J11.S1 130.63,3.36 ; J11.S1 130.63,5.23 ; 250.21,12.6 J16.S26 ; J16.S26 251.99,10.82 ; J16.S26 251.99,12.6 ; J16.S26 250.21,10.82 ; 150.54,3.36 J12.S1 ; J12.S1 152.4,5.23 ; J12.S1 152.4,3.36 ; J16.S18 237.74,20.82 ; J16.S18 235.96,20.82 ; J16.S18 235.96,22.6 ; J16.S18 237.74,22.6 ; 111.98,19.72 J11.S4 ; J11.S4 113.84,19.72 ; J11.S4 111.98,21.58 ; J11.S4 113.84,21.58 ; LAN1.S2 70.43,21.18 ; LAN1.S2 70.43,19.34 ; LAN1.S2 68.58,19.34 ; LAN1.S2 68.58,21.18 ; 194.08,19.72 J14.S3 ; J14.S3 195.94,19.72 ; J14.S3 195.94,21.58 ; J14.S3 194.08,21.58 ; 264.63,30.23 J16.S31 ; J16.S31 264.63,28.79 ; J16.S31 266.07,28.79 ; J16.S31 266.07,30.23 ; J16.S19 237.74,12.6 ; J16.S19 235.96,10.82 ; J16.S19 237.74,10.82 ; J16.S19 235.96,12.6 ; 51.57,5.21 LAN1.S5 ; LAN1.S5 51.57,3.37 ; LAN1.S5 53.42,5.21 ; LAN1.S5 53.42,3.37 ; CN4.M4 47.79,6.68 ; CN4.M4 45.35,6.68 ; CN4.M4 45.35,9.11 ; CN4.M4 47.79,9.11 ; 264.46,25.82 J16.S32 ; J16.S32 266.24,27.6 ; J16.S32 266.24,25.82 ; J16.S32 264.46,27.6 ; J16.S33 266.24,15.82 ; J16.S33 264.46,15.82 ; J16.S33 264.46,17.6 ; J16.S33 266.24,17.6 ; 32.21,12.36 CN4.M1 ; CN4.M1 32.21,14.79 ; CN4.M1 34.65,14.79 ; CN4.M1 34.65,12.36 ; J11.S2 113.84,3.36 ; J11.S2 111.98,3.36 ; J11.S2 111.98,5.23 ; J13.S3 174.17,19.72 ; J13.S3 174.17,21.58 ; J13.S3 172.31,19.72 ; J13.S3 172.31,21.58 ; 221.71,7.6 J16.S13 ; J16.S13 223.49,5.82 ; J16.S13 221.71,5.82 ; J16.S13 223.49,7.6 ; 155.52,3.36 J13.S2 ; J13.S2 157.38,3.36 ; J13.S2 155.52,5.23 ; 177.29,3.36 J14.S2 ; J14.S2 177.29,5.23 ; J14.S2 179.15,3.36 ; J16.S24 251.82,30.23 ; J16.S24 250.39,30.23 ; J16.S24 250.39,28.79 ; J16.S24 251.82,28.79 ; 32.21,9.11 CN4.M3 ; CN4.M3 34.65,6.68 ; CN4.M3 34.65,9.11 ; CN4.M3 32.21,6.68 ; 133.75,21.58 J12.S4 ; J12.S4 135.61,19.72 ; J12.S4 135.61,21.58 ; J12.S4 133.75,19.72 ; CN4.M2 47.79,12.36 ; CN4.M2 45.35,12.36 ; CN4.M2 47.79,14.79 ; 68.58,5.21 LAN1.S6 ; LAN1.S6 70.43,3.37 ; LAN1.S6 68.58,3.37 ; LAN1.S6 70.43,5.21 ; LAN1.S3 54.08,17.09 ; LAN1.S3 52.24,17.09 ; LAN1.S3 54.08,18.93 ; LAN1.S3 52.24,18.93 ; J13.S4 157.38,19.72 ; J13.S4 155.52,21.58 ; J13.S4 155.52,19.72 ; J13.S4 157.38,21.58 ; 221.89,28.79 J16.S10 ; J16.S10 223.32,30.23 ; J16.S10 223.32,28.79 ; J16.S10 221.89,30.23 ; 150.54,19.72 J12.S3 ; J12.S3 150.54,21.58 ; J12.S3 152.4,19.72 ; J12.S3 152.4,21.58 ; J14.S1 195.94,3.36 ; J14.S1 194.08,3.36 ; J14.S1 195.94,5.23 ; J16.S3 209.07,28.79 ; J16.S3 207.64,30.23 ; J16.S3 209.07,30.23 ; J16.S3 207.64,28.79 ; J16.S11 223.49,25.82 ; J16.S11 223.49,27.6 ; J16.S11 221.71,27.6 ; J16.S11 221.71,25.82 ; J11.S3 130.63,21.58 ; J11.S3 130.63,19.72 ; J11.S3 128.77,19.72 ; J11.S3 128.77,21.58 ; 207.46,20.82 J16.S2 ; J16.S2 207.46,22.6 ; J16.S2 209.24,20.82 ; J16.S2 209.24,22.6 ; 177.29,19.72 J14.S4 ; J14.S4 179.15,21.58 ; J14.S4 179.15,19.72 ; J14.S4 177.29,21.58 ; LAN1.S1 53.42,23.4 ; LAN1.S1 51.57,25.24 ; LAN1.S1 53.42,25.24 ; LAN1.S1 51.57,23.4 ; 264.46,7.6 J16.S34 ; J16.S34 264.46,5.82 ; J16.S34 266.24,7.6 ; J16.S34 266.24,5.82 ; J16.S12 223.49,15.82 ; J16.S12 221.71,15.82 ; J16.S12 223.49,17.6 ; J16.S12 221.71,17.6 ; 67.92,15.63 LAN1.S4 ; LAN1.S4 67.92,13.79 ; LAN1.S4 69.76,15.63 ; LAN1.S4 69.76,13.79 ; J13.S1 174.17,5.23 ; J13.S1 172.31,3.36 ; J13.S1 174.17,3.36 ; 250.21,22.6 J16.S25 ; J16.S25 250.21,20.82 ; J16.S25 251.99,20.82 ; J16.S25 251.99,22.6 ; 133.75,3.36 J12.S2 ; J12.S2 135.61,3.36 ; J12.S2 133.75,5.23
  L7_INT_3 w0.508: J16.S1 209.24,10.82 ; J16.S1 209.24,12.6 ; J16.S1 207.46,12.6 ; J16.S1 207.46,10.82 ; J16.S3 209.07,28.79 ; J16.S3 209.07,30.23 ; J16.S3 207.64,30.23 ; J16.S3 207.64,28.79 ; J16.S26 251.99,12.6 ; J16.S26 250.21,12.6 ; J16.S26 250.21,10.82 ; J16.S26 251.99,10.82 ; 150.54,19.72 J12.S3 ; J12.S3 152.4,21.58 ; J12.S3 150.54,21.58 ; J12.S3 152.4,19.72 ; 128.77,3.36 J11.S1 ; J11.S1 130.63,5.23 ; J11.S1 130.63,3.36 ; 250.21,20.82 J16.S25 ; J16.S25 251.99,20.82 ; J16.S25 251.99,22.6 ; J16.S25 250.21,22.6 ; J13.S4 157.38,21.58 ; J13.S4 155.52,21.58 ; J13.S4 157.38,19.72 ; J13.S4 155.52,19.72 ; LAN1.S1 53.42,25.24 ; LAN1.S1 51.57,25.24 ; LAN1.S1 53.42,23.4 ; LAN1.S1 51.57,23.4 ; J13.S3 174.17,21.58 ; J13.S3 172.31,19.72 ; J13.S3 174.17,19.72 ; J13.S3 172.31,21.58 ; J14.S4 179.15,19.72 ; J14.S4 179.15,21.58 ; J14.S4 177.29,21.58 ; J14.S4 177.29,19.72 ; J11.S3 130.63,19.72 ; J11.S3 128.77,19.72 ; J11.S3 128.77,21.58 ; J11.S3 130.63,21.58 ; 264.46,15.82 J16.S33 ; J16.S33 264.46,17.6 ; J16.S33 266.24,17.6 ; J16.S33 266.24,15.82 ; J16.S31 266.07,30.23 ; J16.S31 264.63,30.23 ; J16.S31 264.63,28.79 ; J16.S31 266.07,28.79 ; 111.98,3.36 J11.S2 ; J11.S2 113.84,3.36 ; J11.S2 111.98,5.23 ; 194.08,19.72 J14.S3 ; J14.S3 195.94,19.72 ; J14.S3 195.94,21.58 ; J14.S3 194.08,21.58 ; CN4.M4 47.79,9.11 ; CN4.M4 45.35,6.68 ; CN4.M4 47.79,6.68 ; CN4.M4 45.35,9.11 ; 133.75,3.36 J12.S2 ; J12.S2 135.61,3.36 ; J12.S2 133.75,5.23 ; 264.46,5.82 J16.S34 ; J16.S34 266.24,5.82 ; J16.S34 264.46,7.6 ; J16.S34 266.24,7.6 ; 150.54,3.36 J12.S1 ; J12.S1 152.4,3.36 ; J12.S1 152.4,5.23 ; 250.39,28.79 J16.S24 ; J16.S24 251.82,28.79 ; J16.S24 250.39,30.23 ; J16.S24 251.82,30.23 ; 177.29,3.36 J14.S2 ; J14.S2 177.29,5.23 ; J14.S2 179.15,3.36 ; 68.58,21.18 LAN1.S2 ; LAN1.S2 70.43,19.34 ; LAN1.S2 68.58,19.34 ; LAN1.S2 70.43,21.18 ; 221.89,28.79 J16.S10 ; J16.S10 223.32,28.79 ; J16.S10 223.32,30.23 ; J16.S10 221.89,30.23 ; 221.71,5.82 J16.S13 ; J16.S13 223.49,5.82 ; J16.S13 223.49,7.6 ; J16.S13 221.71,7.6 ; LAN1.S3 54.08,17.09 ; LAN1.S3 52.24,18.93 ; LAN1.S3 54.08,18.93 ; LAN1.S3 52.24,17.09 ; 68.58,3.37 LAN1.S6 ; LAN1.S6 70.43,3.37 ; LAN1.S6 68.58,5.21 ; LAN1.S6 70.43,5.21 ; 207.46,22.6 J16.S2 ; J16.S2 209.24,20.82 ; J16.S2 209.24,22.6 ; J16.S2 207.46,20.82 ; 51.57,5.21 LAN1.S5 ; LAN1.S5 53.42,3.37 ; LAN1.S5 53.42,5.21 ; LAN1.S5 51.57,3.37 ; J12.S4 135.61,19.72 ; J12.S4 135.61,21.58 ; J12.S4 133.75,19.72 ; J12.S4 133.75,21.58 ; 32.21,6.68 CN4.M3 ; CN4.M3 34.65,9.11 ; CN4.M3 32.21,9.11 ; CN4.M3 34.65,6.68 ; J14.S1 195.94,5.23 ; J14.S1 194.08,3.36 ; J14.S1 195.94,3.36 ; J16.S32 266.24,27.6 ; J16.S32 264.46,27.6 ; J16.S32 266.24,25.82 ; J16.S32 264.46,25.82 ; J16.S18 237.74,22.6 ; J16.S18 235.96,22.6 ; J16.S18 235.96,20.82 ; J16.S18 237.74,20.82 ; 155.52,3.36 J13.S2 ; J13.S2 157.38,3.36 ; J13.S2 155.52,5.23 ; LAN1.S4 69.76,15.63 ; LAN1.S4 67.92,15.63 ; LAN1.S4 69.76,13.79 ; LAN1.S4 67.92,13.79 ; CN4.M2 47.79,14.79 ; CN4.M2 45.35,12.36 ; CN4.M2 47.79,12.36 ; 32.21,12.36 CN4.M1 ; CN4.M1 34.65,12.36 ; CN4.M1 32.21,14.79 ; CN4.M1 34.65,14.79 ; J16.S12 223.49,17.6 ; J16.S12 221.71,15.82 ; J16.S12 223.49,15.82 ; J16.S12 221.71,17.6 ; 235.96,10.82 J16.S19 ; J16.S19 237.74,12.6 ; J16.S19 235.96,12.6 ; J16.S19 237.74,10.82 ; 111.98,19.72 J11.S4 ; J11.S4 113.84,21.58 ; J11.S4 113.84,19.72 ; J11.S4 111.98,21.58 ; 221.71,27.6 J16.S11 ; J16.S11 223.49,25.82 ; J16.S11 221.71,25.82 ; J16.S11 223.49,27.6 ; 172.31,3.36 J13.S1 ; J13.S1 174.17,3.36 ; J13.S1 174.17,5.23
  L8_PWR_1 w0.508: 128.77,21.58 J11.S3 ; J11.S3 128.77,19.72 ; J11.S3 130.63,19.72 ; J11.S3 130.63,21.58 ; J12.S1 152.4,3.36 ; J12.S1 152.4,5.23 ; J12.S1 150.54,3.36 ; J11.S4 113.84,19.72 ; J11.S4 111.98,21.58 ; J11.S4 113.84,21.58 ; J11.S4 111.98,19.72 ; 111.98,3.36 J11.S2 ; J11.S2 113.84,3.36 ; J11.S2 111.98,5.23 ; 257.52,44.53 J16.S28 ; J16.S28 257.52,43.09 ; J16.S28 258.95,44.53 ; J16.S28 258.95,43.09 ; 235.96,22.6 J16.S18 ; J16.S18 237.74,20.82 ; J16.S18 237.74,22.6 ; J16.S18 235.96,20.82 ; J14.S4 179.15,19.72 ; J14.S4 179.15,21.58 ; J14.S4 177.29,21.58 ; J14.S4 177.29,19.72 ; LAN1.S4 69.76,15.63 ; LAN1.S4 67.92,13.79 ; LAN1.S4 67.92,15.63 ; LAN1.S4 69.76,13.79 ; J13.S1 174.17,3.36 ; J13.S1 172.31,3.36 ; J13.S1 174.17,5.23 ; 207.46,20.82 J16.S2 ; J16.S2 209.24,20.82 ; J16.S2 207.46,22.6 ; J16.S2 209.24,22.6 ; 221.89,28.79 J16.S10 ; J16.S10 223.32,30.23 ; J16.S10 221.89,30.23 ; J16.S10 223.32,28.79 ; 221.71,7.6 J16.S13 ; J16.S13 223.49,5.82 ; J16.S13 221.71,5.82 ; J16.S13 223.49,7.6 ; CN4.M3 34.65,9.11 ; CN4.M3 32.21,6.68 ; CN4.M3 34.65,6.68 ; CN4.M3 32.21,9.11 ; J16.S23 251.99,32.6 ; J16.S23 250.21,30.82 ; J16.S23 251.99,30.82 ; J16.S23 250.21,32.6 ; 207.46,30.82 J16.S4 ; J16.S4 209.24,32.6 ; J16.S4 209.24,30.82 ; J16.S4 207.46,32.6 ; 155.52,3.36 J13.S2 ; J13.S2 155.52,5.23 ; J13.S2 157.38,3.36 ; J14.S1 195.94,5.23 ; J14.S1 195.94,3.36 ; J14.S1 194.08,3.36 ; 207.46,42.6 J16.S5 ; J16.S5 209.24,40.82 ; J16.S5 207.46,40.82 ; J16.S5 209.24,42.6 ; 68.58,21.18 LAN1.S2 ; LAN1.S2 68.58,19.34 ; LAN1.S2 70.43,21.18 ; LAN1.S2 70.43,19.34 ; 207.46,12.6 J16.S1 ; J16.S1 209.24,10.82 ; J16.S1 207.46,10.82 ; J16.S1 209.24,12.6 ; J16.S22 251.99,40.82 ; J16.S22 250.21,40.82 ; J16.S22 250.21,42.6 ; J16.S22 251.99,42.6 ; 221.71,15.82 J16.S12 ; J16.S12 221.71,17.6 ; J16.S12 223.49,15.82 ; J16.S12 223.49,17.6 ; J16.S33 266.24,15.82 ; J16.S33 264.46,15.82 ; J16.S33 266.24,17.6 ; J16.S33 264.46,17.6 ; 133.75,19.72 J12.S4 ; J12.S4 135.61,19.72 ; J12.S4 135.61,21.58 ; J12.S4 133.75,21.58 ; J16.S17 237.74,32.6 ; J16.S17 235.96,32.6 ; J16.S17 235.96,30.82 ; J16.S17 237.74,30.82 ; 194.08,21.58 J14.S3 ; J14.S3 195.94,21.58 ; J14.S3 195.94,19.72 ; J14.S3 194.08,19.72 ; 221.71,35.1 J16.S9 ; J16.S9 223.49,33.32 ; J16.S9 223.49,35.1 ; J16.S9 221.71,33.32 ; J16.S32 266.24,25.82 ; J16.S32 264.46,25.82 ; J16.S32 264.46,27.6 ; J16.S32 266.24,27.6 ; 133.75,3.36 J12.S2 ; J12.S2 133.75,5.23 ; J12.S2 135.61,3.36 ; J16.S30 266.24,33.32 ; J16.S30 266.24,35.1 ; J16.S30 264.46,35.1 ; J16.S30 264.46,33.32 ; 238.47,44.53 J16.S20 ; J16.S20 239.9,43.09 ; J16.S20 238.47,43.09 ; J16.S20 239.9,44.53 ; 150.54,21.58 J12.S3 ; J12.S3 152.4,21.58 ; J12.S3 152.4,19.72 ; J12.S3 150.54,19.72 ; 52.24,17.09 LAN1.S3 ; LAN1.S3 52.24,18.93 ; LAN1.S3 54.08,18.93 ; LAN1.S3 54.08,17.09 ; J16.S16 237.74,40.82 ; J16.S16 235.96,42.6 ; J16.S16 235.96,40.82 ; J16.S16 237.74,42.6 ; J16.S3 209.07,28.79 ; J16.S3 207.64,30.23 ; J16.S3 209.07,30.23 ; J16.S3 207.64,28.79 ; 51.57,25.24 LAN1.S1 ; LAN1.S1 53.42,25.24 ; LAN1.S1 51.57,23.4 ; LAN1.S1 53.42,23.4 ; 177.29,5.23 J14.S2 ; J14.S2 179.15,3.36 ; J14.S2 177.29,3.36 ; 214.77,44.53 J16.S7 ; J16.S7 216.2,44.53 ; J16.S7 214.77,43.09 ; J16.S7 216.2,43.09 ; 45.35,9.11 CN4.M4 ; CN4.M4 47.79,9.11 ; CN4.M4 47.79,6.68 ; CN4.M4 45.35,6.68 ; J16.S29 266.24,40.1 ; J16.S29 266.24,38.32 ; J16.S29 264.46,40.1 ; J16.S29 264.46,38.32 ; J13.S3 174.17,19.72 ; J13.S3 172.31,21.58 ; J13.S3 174.17,21.58 ; J13.S3 172.31,19.72 ; 155.52,21.58 J13.S4 ; J13.S4 157.38,21.58 ; J13.S4 155.52,19.72 ; J13.S4 157.38,19.72 ; J16.S24 251.82,28.79 ; J16.S24 251.82,30.23 ; J16.S24 250.39,30.23 ; J16.S24 250.39,28.79 ; J16.S19 237.74,10.82 ; J16.S19 237.74,12.6 ; J16.S19 235.96,12.6 ; J16.S19 235.96,10.82 ; 243.27,44.53 J16.S21 ; J16.S21 244.7,44.53 ; J16.S21 244.7,43.09 ; J16.S21 243.27,43.09 ; 264.46,5.82 J16.S34 ; J16.S34 266.24,7.6 ; J16.S34 264.46,7.6 ; J16.S34 266.24,5.82 ; 252.72,44.53 J16.S27 ; J16.S27 254.15,43.09 ; J16.S27 252.72,43.09 ; J16.S27 254.15,44.53 ; 68.58,5.21 LAN1.S6 ; LAN1.S6 70.43,3.37 ; LAN1.S6 68.58,3.37 ; LAN1.S6 70.43,5.21 ; 264.63,28.79 J16.S31 ; J16.S31 266.07,30.23 ; J16.S31 264.63,30.23 ; J16.S31 266.07,28.79 ; 229.02,43.09 J16.S15 ; J16.S15 230.45,43.09 ; J16.S15 229.02,44.53 ; J16.S15 230.45,44.53 ; 45.35,12.36 CN4.M2 ; CN4.M2 47.79,12.36 ; CN4.M2 47.79,14.79 ; J16.S11 223.49,25.82 ; J16.S11 221.71,25.82 ; J16.S11 221.71,27.6 ; J16.S11 223.49,27.6 ; 221.71,38.32 J16.S8 ; J16.S8 223.49,38.32 ; J16.S8 223.49,40.1 ; J16.S8 221.71,40.1 ; 224.22,43.09 J16.S14 ; J16.S14 225.65,43.09 ; J16.S14 225.65,44.53 ; J16.S14 224.22,44.53 ; J16.S6 211.4,43.09 ; J16.S6 211.4,44.53 ; J16.S6 209.97,44.53 ; J16.S6 209.97,43.09 ; CN4.M1 34.65,14.79 ; CN4.M1 32.21,14.79 ; CN4.M1 34.65,12.36 ; CN4.M1 32.21,12.36 ; 250.21,10.82 J16.S26 ; J16.S26 251.99,10.82 ; J16.S26 251.99,12.6 ; J16.S26 250.21,12.6 ; 51.57,3.37 LAN1.S5 ; LAN1.S5 51.57,5.21 ; LAN1.S5 53.42,3.37 ; LAN1.S5 53.42,5.21 ; J16.S25 251.99,22.6 ; J16.S25 250.21,22.6 ; J16.S25 251.99,20.82 ; J16.S25 250.21,20.82 ; J11.S1 130.63,3.36 ; J11.S1 130.63,5.23 ; J11.S1 128.77,3.36
  L9_PWR_2 w0.508: J16.S14 225.65,43.09 ; J16.S14 225.65,44.53 ; J16.S14 224.22,44.53 ; J16.S14 224.22,43.09 ; 264.46,40.1 J16.S29 ; J16.S29 264.46,38.32 ; J16.S29 266.24,40.1 ; J16.S29 266.24,38.32 ; J16.S5 209.24,42.6 ; J16.S5 209.24,40.82 ; J16.S5 207.46,42.6 ; J16.S5 207.46,40.82 ; 221.71,15.82 J16.S12 ; J16.S12 223.49,17.6 ; J16.S12 221.71,17.6 ; J16.S12 223.49,15.82 ; J11.S2 113.84,3.36 ; J11.S2 111.98,3.36 ; J11.S2 111.98,5.23 ; 264.46,15.82 J16.S33 ; J16.S33 266.24,17.6 ; J16.S33 264.46,17.6 ; J16.S33 266.24,15.82 ; J16.S20 239.9,44.53 ; J16.S20 238.47,43.09 ; J16.S20 239.9,43.09 ; J16.S20 238.47,44.53 ; 250.39,28.79 J16.S24 ; J16.S24 251.82,28.79 ; J16.S24 251.82,30.23 ; J16.S24 250.39,30.23 ; J11.S3 130.63,21.58 ; J11.S3 128.77,21.58 ; J11.S3 128.77,19.72 ; J11.S3 130.63,19.72 ; 250.21,30.82 J16.S23 ; J16.S23 251.99,32.6 ; J16.S23 250.21,32.6 ; J16.S23 251.99,30.82 ; 177.29,21.58 J14.S4 ; J14.S4 179.15,21.58 ; J14.S4 179.15,19.72 ; J14.S4 177.29,19.72 ; 68.58,19.34 LAN1.S2 ; LAN1.S2 70.43,19.34 ; LAN1.S2 68.58,21.18 ; LAN1.S2 70.43,21.18 ; J11.S1 130.63,5.23 ; J11.S1 130.63,3.36 ; J11.S1 128.77,3.36 ; J16.S19 237.74,10.82 ; J16.S19 237.74,12.6 ; J16.S19 235.96,12.6 ; J16.S19 235.96,10.82 ; J16.S30 266.24,33.32 ; J16.S30 266.24,35.1 ; J16.S30 264.46,35.1 ; J16.S30 264.46,33.32 ; 45.35,6.68 CN4.M4 ; CN4.M4 47.79,9.11 ; CN4.M4 47.79,6.68 ; CN4.M4 45.35,9.11 ; J16.S32 266.24,25.82 ; J16.S32 264.46,27.6 ; J16.S32 266.24,27.6 ; J16.S32 264.46,25.82 ; J16.S25 251.99,22.6 ; J16.S25 251.99,20.82 ; J16.S25 250.21,20.82 ; J16.S25 250.21,22.6 ; J16.S1 209.24,12.6 ; J16.S1 207.46,12.6 ; J16.S1 207.46,10.82 ; J16.S1 209.24,10.82 ; J16.S4 209.24,32.6 ; J16.S4 207.46,30.82 ; J16.S4 209.24,30.82 ; J16.S4 207.46,32.6 ; J16.S22 251.99,42.6 ; J16.S22 251.99,40.82 ; J16.S22 250.21,42.6 ; J16.S22 250.21,40.82 ; 257.52,43.09 J16.S28 ; J16.S28 257.52,44.53 ; J16.S28 258.95,43.09 ; J16.S28 258.95,44.53 ; CN4.M1 34.65,14.79 ; CN4.M1 34.65,12.36 ; CN4.M1 32.21,12.36 ; CN4.M1 32.21,14.79 ; 221.71,7.6 J16.S13 ; J16.S13 223.49,5.82 ; J16.S13 223.49,7.6 ; J16.S13 221.71,5.82 ; J16.S3 209.07,30.23 ; J16.S3 209.07,28.79 ; J16.S3 207.64,30.23 ; J16.S3 207.64,28.79 ; J13.S1 174.17,5.23 ; J13.S1 174.17,3.36 ; J13.S1 172.31,3.36 ; 264.63,30.23 J16.S31 ; J16.S31 266.07,30.23 ; J16.S31 264.63,28.79 ; J16.S31 266.07,28.79 ; 243.27,43.09 J16.S21 ; J16.S21 244.7,43.09 ; J16.S21 244.7,44.53 ; J16.S21 243.27,44.53 ; LAN1.S1 53.42,25.24 ; LAN1.S1 53.42,23.4 ; LAN1.S1 51.57,25.24 ; LAN1.S1 51.57,23.4 ; 221.71,27.6 J16.S11 ; J16.S11 223.49,27.6 ; J16.S11 223.49,25.82 ; J16.S11 221.71,25.82 ; 32.21,9.11 CN4.M3 ; CN4.M3 32.21,6.68 ; CN4.M3 34.65,6.68 ; CN4.M3 34.65,9.11 ; 235.96,22.6 J16.S18 ; J16.S18 237.74,20.82 ; J16.S18 235.96,20.82 ; J16.S18 237.74,22.6 ; J12.S4 135.61,19.72 ; J12.S4 133.75,21.58 ; J12.S4 133.75,19.72 ; J12.S4 135.61,21.58 ; 177.29,3.36 J14.S2 ; J14.S2 179.15,3.36 ; J14.S2 177.29,5.23 ; 194.08,3.36 J14.S1 ; J14.S1 195.94,5.23 ; J14.S1 195.94,3.36 ; 235.96,40.82 J16.S16 ; J16.S16 235.96,42.6 ; J16.S16 237.74,40.82 ; J16.S16 237.74,42.6 ; 264.46,5.82 J16.S34 ; J16.S34 266.24,7.6 ; J16.S34 266.24,5.82 ; J16.S34 264.46,7.6 ; LAN1.S3 54.08,17.09 ; LAN1.S3 52.24,17.09 ; LAN1.S3 52.24,18.93 ; LAN1.S3 54.08,18.93 ; 250.21,10.82 J16.S26 ; J16.S26 251.99,10.82 ; J16.S26 251.99,12.6 ; J16.S26 250.21,12.6 ; J13.S3 174.17,21.58 ; J13.S3 174.17,19.72 ; J13.S3 172.31,19.72 ; J13.S3 172.31,21.58 ; 51.57,5.21 LAN1.S5 ; LAN1.S5 51.57,3.37 ; LAN1.S5 53.42,3.37 ; LAN1.S5 53.42,5.21 ; J16.S2 209.24,20.82 ; J16.S2 209.24,22.6 ; J16.S2 207.46,22.6 ; J16.S2 207.46,20.82 ; 133.75,3.36 J12.S2 ; J12.S2 133.75,5.23 ; J12.S2 135.61,3.36 ; J16.S6 211.4,44.53 ; J16.S6 209.97,44.53 ; J16.S6 211.4,43.09 ; J16.S6 209.97,43.09 ; 221.71,35.1 J16.S9 ; J16.S9 223.49,35.1 ; J16.S9 223.49,33.32 ; J16.S9 221.71,33.32 ; J14.S3 195.94,19.72 ; J14.S3 194.08,21.58 ; J14.S3 194.08,19.72 ; J14.S3 195.94,21.58 ; 45.35,12.36 CN4.M2 ; CN4.M2 47.79,14.79 ; CN4.M2 47.79,12.36 ; 221.89,28.79 J16.S10 ; J16.S10 223.32,28.79 ; J16.S10 223.32,30.23 ; J16.S10 221.89,30.23 ; 67.92,13.79 LAN1.S4 ; LAN1.S4 69.76,15.63 ; LAN1.S4 67.92,15.63 ; LAN1.S4 69.76,13.79 ; 252.72,43.09 J16.S27 ; J16.S27 254.15,44.53 ; J16.S27 252.72,44.53 ; J16.S27 254.15,43.09 ; 229.02,43.09 J16.S15 ; J16.S15 229.02,44.53 ; J16.S15 230.45,44.53 ; J16.S15 230.45,43.09 ; J12.S1 152.4,3.36 ; J12.S1 150.54,3.36 ; J12.S1 152.4,5.23 ; J12.S3 152.4,19.72 ; J12.S3 150.54,19.72 ; J12.S3 152.4,21.58 ; J12.S3 150.54,21.58 ; J16.S17 237.74,30.82 ; J16.S17 235.96,30.82 ; J16.S17 237.74,32.6 ; J16.S17 235.96,32.6 ; 214.77,44.53 J16.S7 ; J16.S7 216.2,43.09 ; J16.S7 214.77,43.09 ; J16.S7 216.2,44.53 ; 221.71,40.1 J16.S8 ; J16.S8 221.71,38.32 ; J16.S8 223.49,38.32 ; J16.S8 223.49,40.1 ; 155.52,3.36 J13.S2 ; J13.S2 155.52,5.23 ; J13.S2 157.38,3.36 ; 68.58,5.21 LAN1.S6 ; LAN1.S6 68.58,3.37 ; LAN1.S6 70.43,5.21 ; LAN1.S6 70.43,3.37 ; J13.S4 157.38,21.58 ; J13.S4 155.52,21.58 ; J13.S4 157.38,19.72 ; J13.S4 155.52,19.72 ; J11.S4 113.84,21.58 ; J11.S4 111.98,19.72 ; J11.S4 111.98,21.58 ; J11.S4 113.84,19.72
  L10_INT_4 w0.508: CN4.M4 47.79,6.68 ; CN4.M4 45.35,6.68 ; CN4.M4 47.79,9.11 ; CN4.M4 45.35,9.11 ; J11.S1 130.63,3.36 ; J11.S1 130.63,5.23 ; J11.S1 128.77,3.36 ; J16.S33 266.24,17.6 ; J16.S33 266.24,15.82 ; J16.S33 264.46,15.82 ; J16.S33 264.46,17.6 ; 221.71,7.6 J16.S13 ; J16.S13 223.49,5.82 ; J16.S13 223.49,7.6 ; J16.S13 221.71,5.82 ; 155.52,3.36 J13.S2 ; J13.S2 155.52,5.23 ; J13.S2 157.38,3.36 ; J13.S3 174.17,21.58 ; J13.S3 172.31,19.72 ; J13.S3 172.31,21.58 ; J13.S3 174.17,19.72 ; 194.08,21.58 J14.S3 ; J14.S3 195.94,21.58 ; J14.S3 195.94,19.72 ; J14.S3 194.08,19.72 ; 155.52,21.58 J13.S4 ; J13.S4 157.38,21.58 ; J13.S4 155.52,19.72 ; J13.S4 157.38,19.72 ; J16.S1 209.24,12.6 ; J16.S1 207.46,10.82 ; J16.S1 207.46,12.6 ; J16.S1 209.24,10.82 ; J16.S12 223.49,17.6 ; J16.S12 221.71,15.82 ; J16.S12 221.71,17.6 ; J16.S12 223.49,15.82 ; 207.46,22.6 J16.S2 ; J16.S2 209.24,22.6 ; J16.S2 207.46,20.82 ; J16.S2 209.24,20.82 ; 67.92,13.79 LAN1.S4 ; LAN1.S4 69.76,13.79 ; LAN1.S4 67.92,15.63 ; LAN1.S4 69.76,15.63 ; 128.77,21.58 J11.S3 ; J11.S3 128.77,19.72 ; J11.S3 130.63,21.58 ; J11.S3 130.63,19.72 ; J16.S11 223.49,27.6 ; J16.S11 223.49,25.82 ; J16.S11 221.71,27.6 ; J16.S11 221.71,25.82 ; 172.31,3.36 J13.S1 ; J13.S1 174.17,5.23 ; J13.S1 174.17,3.36 ; 250.21,12.6 J16.S26 ; J16.S26 251.99,10.82 ; J16.S26 251.99,12.6 ; J16.S26 250.21,10.82 ; J16.S24 251.82,30.23 ; J16.S24 251.82,28.79 ; J16.S24 250.39,28.79 ; J16.S24 250.39,30.23 ; J11.S2 113.84,3.36 ; J11.S2 111.98,3.36 ; J11.S2 111.98,5.23 ; CN4.M2 47.79,12.36 ; CN4.M2 45.35,12.36 ; CN4.M2 47.79,14.79 ; J16.S18 237.74,22.6 ; J16.S18 235.96,22.6 ; J16.S18 235.96,20.82 ; J16.S18 237.74,20.82 ; J11.S4 113.84,19.72 ; J11.S4 113.84,21.58 ; J11.S4 111.98,21.58 ; J11.S4 111.98,19.72 ; LAN1.S5 53.42,5.21 ; LAN1.S5 51.57,3.37 ; LAN1.S5 51.57,5.21 ; LAN1.S5 53.42,3.37 ; LAN1.S2 70.43,21.18 ; LAN1.S2 70.43,19.34 ; LAN1.S2 68.58,21.18 ; LAN1.S2 68.58,19.34 ; 194.08,3.36 J14.S1 ; J14.S1 195.94,5.23 ; J14.S1 195.94,3.36 ; 150.54,21.58 J12.S3 ; J12.S3 152.4,21.58 ; J12.S3 152.4,19.72 ; J12.S3 150.54,19.72 ; 52.24,17.09 LAN1.S3 ; LAN1.S3 54.08,18.93 ; LAN1.S3 54.08,17.09 ; LAN1.S3 52.24,18.93 ; J16.S10 223.32,30.23 ; J16.S10 221.89,28.79 ; J16.S10 221.89,30.23 ; J16.S10 223.32,28.79 ; J16.S19 237.74,10.82 ; J16.S19 235.96,12.6 ; J16.S19 237.74,12.6 ; J16.S19 235.96,10.82 ; J16.S25 251.99,20.82 ; J16.S25 250.21,22.6 ; J16.S25 251.99,22.6 ; J16.S25 250.21,20.82 ; J12.S4 135.61,19.72 ; J12.S4 135.61,21.58 ; J12.S4 133.75,21.58 ; J12.S4 133.75,19.72 ; J16.S31 266.07,28.79 ; J16.S31 264.63,30.23 ; J16.S31 264.63,28.79 ; J16.S31 266.07,30.23 ; J14.S4 179.15,21.58 ; J14.S4 179.15,19.72 ; J14.S4 177.29,19.72 ; J14.S4 177.29,21.58 ; 150.54,3.36 J12.S1 ; J12.S1 152.4,3.36 ; J12.S1 152.4,5.23 ; 264.46,27.6 J16.S32 ; J16.S32 266.24,27.6 ; J16.S32 264.46,25.82 ; J16.S32 266.24,25.82 ; J16.S34 266.24,5.82 ; J16.S34 264.46,7.6 ; J16.S34 264.46,5.82 ; J16.S34 266.24,7.6 ; CN4.M3 34.65,9.11 ; CN4.M3 32.21,6.68 ; CN4.M3 32.21,9.11 ; CN4.M3 34.65,6.68 ; 51.57,25.24 LAN1.S1 ; LAN1.S1 51.57,23.4 ; LAN1.S1 53.42,25.24 ; LAN1.S1 53.42,23.4 ; CN4.M1 34.65,14.79 ; CN4.M1 32.21,12.36 ; CN4.M1 32.21,14.79 ; CN4.M1 34.65,12.36 ; 68.58,5.21 LAN1.S6 ; LAN1.S6 70.43,5.21 ; LAN1.S6 70.43,3.37 ; LAN1.S6 68.58,3.37 ; 133.75,5.23 J12.S2 ; J12.S2 133.75,3.36 ; J12.S2 135.61,3.36 ; 177.29,3.36 J14.S2 ; J14.S2 177.29,5.23 ; J14.S2 179.15,3.36 ; 207.64,28.79 J16.S3 ; J16.S3 209.07,30.23 ; J16.S3 209.07,28.79 ; J16.S3 207.64,30.23
  L11_GND_4 w0.508: J16.S10 223.32,28.79 ; J16.S10 223.32,30.23 ; J16.S10 221.89,28.79 ; J16.S10 221.89,30.23 ; J13.S4 157.38,19.72 ; J13.S4 155.52,19.72 ; J13.S4 155.52,21.58 ; J13.S4 157.38,21.58 ; J14.S1 195.94,3.36 ; J14.S1 194.08,3.36 ; J14.S1 195.94,5.23 ; J16.S3 209.07,28.79 ; J16.S3 207.64,28.79 ; J16.S3 207.64,30.23 ; J16.S3 209.07,30.23 ; 51.57,23.4 LAN1.S1 ; LAN1.S1 53.42,25.24 ; LAN1.S1 51.57,25.24 ; LAN1.S1 53.42,23.4 ; 235.96,22.6 J16.S18 ; J16.S18 237.74,22.6 ; J16.S18 235.96,20.82 ; J16.S18 237.74,20.82 ; 111.98,5.23 J11.S2 ; J11.S2 113.84,3.36 ; J11.S2 111.98,3.36 ; LAN1.S5 53.42,3.37 ; LAN1.S5 51.57,5.21 ; LAN1.S5 51.57,3.37 ; LAN1.S5 53.42,5.21 ; J16.S11 223.49,25.82 ; J16.S11 221.71,25.82 ; J16.S11 221.71,27.6 ; J16.S11 223.49,27.6 ; J13.S3 174.17,19.72 ; J13.S3 174.17,21.58 ; J13.S3 172.31,21.58 ; J13.S3 172.31,19.72 ; CN4.M3 34.65,9.11 ; CN4.M3 34.65,6.68 ; CN4.M3 32.21,6.68 ; CN4.M3 32.21,9.11 ; J16.S26 251.99,10.82 ; J16.S26 251.99,12.6 ; J16.S26 250.21,12.6 ; J16.S26 250.21,10.82 ; 150.54,21.58 J12.S3 ; J12.S3 152.4,21.58 ; J12.S3 152.4,19.72 ; J12.S3 150.54,19.72 ; CN4.M1 34.65,12.36 ; CN4.M1 32.21,12.36 ; CN4.M1 32.21,14.79 ; CN4.M1 34.65,14.79 ; J16.S2 209.24,22.6 ; J16.S2 209.24,20.82 ; J16.S2 207.46,20.82 ; J16.S2 207.46,22.6 ; J16.S24 251.82,28.79 ; J16.S24 251.82,30.23 ; J16.S24 250.39,28.79 ; J16.S24 250.39,30.23 ; 221.71,7.6 J16.S13 ; J16.S13 223.49,7.6 ; J16.S13 221.71,5.82 ; J16.S13 223.49,5.82 ; 207.46,12.6 J16.S1 ; J16.S1 209.24,12.6 ; J16.S1 207.46,10.82 ; J16.S1 209.24,10.82 ; 133.75,21.58 J12.S4 ; J12.S4 133.75,19.72 ; J12.S4 135.61,21.58 ; J12.S4 135.61,19.72 ; 264.46,27.6 J16.S32 ; J16.S32 266.24,27.6 ; J16.S32 266.24,25.82 ; J16.S32 264.46,25.82 ; 68.58,21.18 LAN1.S2 ; LAN1.S2 70.43,21.18 ; LAN1.S2 70.43,19.34 ; LAN1.S2 68.58,19.34 ; 194.08,21.58 J14.S3 ; J14.S3 195.94,19.72 ; J14.S3 194.08,19.72 ; J14.S3 195.94,21.58 ; 177.29,3.36 J14.S2 ; J14.S2 179.15,3.36 ; J14.S2 177.29,5.23 ; CN4.M2 47.79,12.36 ; CN4.M2 45.35,12.36 ; CN4.M2 47.79,14.79 ; J11.S4 113.84,19.72 ; J11.S4 113.84,21.58 ; J11.S4 111.98,19.72 ; J11.S4 111.98,21.58 ; J16.S19 237.74,12.6 ; J16.S19 235.96,10.82 ; J16.S19 235.96,12.6 ; J16.S19 237.74,10.82 ; 264.46,17.6 J16.S33 ; J16.S33 264.46,15.82 ; J16.S33 266.24,17.6 ; J16.S33 266.24,15.82 ; J16.S31 266.07,30.23 ; J16.S31 266.07,28.79 ; J16.S31 264.63,30.23 ; J16.S31 264.63,28.79 ; J16.S34 266.24,7.6 ; J16.S34 266.24,5.82 ; J16.S34 264.46,7.6 ; J16.S34 264.46,5.82 ; 133.75,3.36 J12.S2 ; J12.S2 135.61,3.36 ; J12.S2 133.75,5.23 ; 68.58,3.37 LAN1.S6 ; LAN1.S6 70.43,3.37 ; LAN1.S6 68.58,5.21 ; LAN1.S6 70.43,5.21 ; 128.77,19.72 J11.S3 ; J11.S3 128.77,21.58 ; J11.S3 130.63,19.72 ; J11.S3 130.63,21.58 ; 45.35,9.11 CN4.M4 ; CN4.M4 47.79,6.68 ; CN4.M4 47.79,9.11 ; CN4.M4 45.35,6.68 ; J13.S2 157.38,3.36 ; J13.S2 155.52,3.36 ; J13.S2 155.52,5.23 ; 250.21,20.82 J16.S25 ; J16.S25 251.99,22.6 ; J16.S25 251.99,20.82 ; J16.S25 250.21,22.6 ; 177.29,19.72 J14.S4 ; J14.S4 179.15,21.58 ; J14.S4 179.15,19.72 ; J14.S4 177.29,21.58 ; J16.S12 223.49,17.6 ; J16.S12 223.49,15.82 ; J16.S12 221.71,15.82 ; J16.S12 221.71,17.6 ; J12.S1 152.4,3.36 ; J12.S1 150.54,3.36 ; J12.S1 152.4,5.23 ; J13.S1 174.17,3.36 ; J13.S1 172.31,3.36 ; J13.S1 174.17,5.23 ; J11.S1 130.63,5.23 ; J11.S1 128.77,3.36 ; J11.S1 130.63,3.36 ; 67.92,13.79 LAN1.S4 ; LAN1.S4 69.76,13.79 ; LAN1.S4 67.92,15.63 ; LAN1.S4 69.76,15.63 ; LAN1.S3 54.08,17.09 ; LAN1.S3 52.24,18.93 ; LAN1.S3 52.24,17.09 ; LAN1.S3 54.08,18.93
  L12_INT_5 w0.508: 150.54,19.72 J12.S3 ; J12.S3 152.4,19.72 ; J12.S3 152.4,21.58 ; J12.S3 150.54,21.58 ; J13.S4 157.38,21.58 ; J13.S4 155.52,19.72 ; J13.S4 157.38,19.72 ; J13.S4 155.52,21.58 ; 207.46,22.6 J16.S2 ; J16.S2 209.24,20.82 ; J16.S2 207.46,20.82 ; J16.S2 209.24,22.6 ; J16.S25 251.99,20.82 ; J16.S25 251.99,22.6 ; J16.S25 250.21,20.82 ; J16.S25 250.21,22.6 ; CN4.M2 47.79,12.36 ; CN4.M2 45.35,12.36 ; CN4.M2 47.79,14.79 ; CN4.M4 47.79,9.11 ; CN4.M4 45.35,9.11 ; CN4.M4 45.35,6.68 ; CN4.M4 47.79,6.68 ; 172.31,21.58 J13.S3 ; J13.S3 172.31,19.72 ; J13.S3 174.17,19.72 ; J13.S3 174.17,21.58 ; CN4.M3 34.65,9.11 ; CN4.M3 32.21,9.11 ; CN4.M3 34.65,6.68 ; CN4.M3 32.21,6.68 ; LAN1.S6 70.43,5.21 ; LAN1.S6 70.43,3.37 ; LAN1.S6 68.58,5.21 ; LAN1.S6 68.58,3.37 ; 207.64,28.79 J16.S3 ; J16.S3 209.07,28.79 ; J16.S3 209.07,30.23 ; J16.S3 207.64,30.23 ; 207.46,10.82 J16.S1 ; J16.S1 209.24,12.6 ; J16.S1 207.46,12.6 ; J16.S1 209.24,10.82 ; 194.08,3.36 J14.S1 ; J14.S1 195.94,5.23 ; J14.S1 195.94,3.36 ; J11.S4 113.84,21.58 ; J11.S4 111.98,21.58 ; J11.S4 111.98,19.72 ; J11.S4 113.84,19.72 ; 264.63,28.79 J16.S31 ; J16.S31 264.63,30.23 ; J16.S31 266.07,28.79 ; J16.S31 266.07,30.23 ; 250.39,28.79 J16.S24 ; J16.S24 250.39,30.23 ; J16.S24 251.82,28.79 ; J16.S24 251.82,30.23 ; J16.S34 266.24,5.82 ; J16.S34 264.46,5.82 ; J16.S34 266.24,7.6 ; J16.S34 264.46,7.6 ; J13.S1 174.17,3.36 ; J13.S1 174.17,5.23 ; J13.S1 172.31,3.36 ; LAN1.S5 53.42,5.21 ; LAN1.S5 51.57,5.21 ; LAN1.S5 51.57,3.37 ; LAN1.S5 53.42,3.37 ; J16.S13 223.49,5.82 ; J16.S13 221.71,7.6 ; J16.S13 221.71,5.82 ; J16.S13 223.49,7.6 ; J16.S10 223.32,28.79 ; J16.S10 223.32,30.23 ; J16.S10 221.89,30.23 ; J16.S10 221.89,28.79 ; J16.S18 237.74,22.6 ; J16.S18 237.74,20.82 ; J16.S18 235.96,20.82 ; J16.S18 235.96,22.6 ; J14.S4 179.15,21.58 ; J14.S4 177.29,19.72 ; J14.S4 179.15,19.72 ; J14.S4 177.29,21.58 ; J16.S19 237.74,12.6 ; J16.S19 235.96,12.6 ; J16.S19 237.74,10.82 ; J16.S19 235.96,10.82 ; J16.S32 266.24,27.6 ; J16.S32 264.46,27.6 ; J16.S32 264.46,25.82 ; J16.S32 266.24,25.82 ; J12.S4 135.61,19.72 ; J12.S4 133.75,19.72 ; J12.S4 133.75,21.58 ; J12.S4 135.61,21.58 ; J16.S26 251.99,10.82 ; J16.S26 250.21,12.6 ; J16.S26 250.21,10.82 ; J16.S26 251.99,12.6 ; 221.71,15.82 J16.S12 ; J16.S12 221.71,17.6 ; J16.S12 223.49,15.82 ; J16.S12 223.49,17.6 ; 128.77,19.72 J11.S3 ; J11.S3 128.77,21.58 ; J11.S3 130.63,19.72 ; J11.S3 130.63,21.58 ; LAN1.S2 70.43,19.34 ; LAN1.S2 68.58,21.18 ; LAN1.S2 70.43,21.18 ; LAN1.S2 68.58,19.34 ; 177.29,3.36 J14.S2 ; J14.S2 177.29,5.23 ; J14.S2 179.15,3.36 ; 32.21,14.79 CN4.M1 ; CN4.M1 34.65,12.36 ; CN4.M1 34.65,14.79 ; CN4.M1 32.21,12.36 ; 264.46,15.82 J16.S33 ; J16.S33 266.24,17.6 ; J16.S33 264.46,17.6 ; J16.S33 266.24,15.82 ; 111.98,3.36 J11.S2 ; J11.S2 113.84,3.36 ; J11.S2 111.98,5.23 ; J16.S11 223.49,27.6 ; J16.S11 221.71,25.82 ; J16.S11 221.71,27.6 ; J16.S11 223.49,25.82 ; J12.S1 152.4,5.23 ; J12.S1 152.4,3.36 ; J12.S1 150.54,3.36 ; 133.75,5.23 J12.S2 ; J12.S2 133.75,3.36 ; J12.S2 135.61,3.36 ; 51.57,25.24 LAN1.S1 ; LAN1.S1 51.57,23.4 ; LAN1.S1 53.42,25.24 ; LAN1.S1 53.42,23.4 ; 52.24,18.93 LAN1.S3 ; LAN1.S3 52.24,17.09 ; LAN1.S3 54.08,17.09 ; LAN1.S3 54.08,18.93 ; J13.S2 157.38,3.36 ; J13.S2 155.52,3.36 ; J13.S2 155.52,5.23 ; LAN1.S4 69.76,13.79 ; LAN1.S4 69.76,15.63 ; LAN1.S4 67.92,13.79 ; LAN1.S4 67.92,15.63 ; J14.S3 195.94,19.72 ; J14.S3 194.08,21.58 ; J14.S3 195.94,21.58 ; J14.S3 194.08,19.72 ; J11.S1 130.63,3.36 ; J11.S1 128.77,3.36 ; J11.S1 130.63,5.23
  L13_GND_5 w0.508: J11.S3 130.63,19.72 ; J11.S3 128.77,19.72 ; J11.S3 130.63,21.58 ; J11.S3 128.77,21.58 ; 51.57,25.24 LAN1.S1 ; LAN1.S1 51.57,23.4 ; LAN1.S1 53.42,23.4 ; LAN1.S1 53.42,25.24 ; 207.46,20.82 J16.S2 ; J16.S2 207.46,22.6 ; J16.S2 209.24,22.6 ; J16.S2 209.24,20.82 ; 32.21,14.79 CN4.M1 ; CN4.M1 34.65,14.79 ; CN4.M1 34.65,12.36 ; CN4.M1 32.21,12.36 ; 111.98,21.58 J11.S4 ; J11.S4 113.84,21.58 ; J11.S4 113.84,19.72 ; J11.S4 111.98,19.72 ; 52.24,18.93 LAN1.S3 ; LAN1.S3 54.08,18.93 ; LAN1.S3 52.24,17.09 ; LAN1.S3 54.08,17.09 ; 128.77,3.36 J11.S1 ; J11.S1 130.63,5.23 ; J11.S1 130.63,3.36 ; J16.S26 251.99,10.82 ; J16.S26 250.21,10.82 ; J16.S26 250.21,12.6 ; J16.S26 251.99,12.6 ; 32.21,9.11 CN4.M3 ; CN4.M3 32.21,6.68 ; CN4.M3 34.65,9.11 ; CN4.M3 34.65,6.68 ; 264.46,25.82 J16.S32 ; J16.S32 266.24,27.6 ; J16.S32 264.46,27.6 ; J16.S32 266.24,25.82 ; J16.S34 266.24,7.6 ; J16.S34 264.46,7.6 ; J16.S34 266.24,5.82 ; J16.S34 264.46,5.82 ; 194.08,21.58 J14.S3 ; J14.S3 194.08,19.72 ; J14.S3 195.94,19.72 ; J14.S3 195.94,21.58 ; J16.S3 209.07,28.79 ; J16.S3 209.07,30.23 ; J16.S3 207.64,30.23 ; J16.S3 207.64,28.79 ; CN4.M4 47.79,6.68 ; CN4.M4 47.79,9.11 ; CN4.M4 45.35,9.11 ; CN4.M4 45.35,6.68 ; CN4.M2 47.79,12.36 ; CN4.M2 47.79,14.79 ; CN4.M2 45.35,12.36 ; 221.71,7.6 J16.S13 ; J16.S13 221.71,5.82 ; J16.S13 223.49,7.6 ; J16.S13 223.49,5.82 ; J13.S2 157.38,3.36 ; J13.S2 155.52,3.36 ; J13.S2 155.52,5.23 ; 133.75,21.58 J12.S4 ; J12.S4 135.61,19.72 ; J12.S4 133.75,19.72 ; J12.S4 135.61,21.58 ; J11.S2 113.84,3.36 ; J11.S2 111.98,5.23 ; J11.S2 111.98,3.36 ; J16.S19 237.74,10.82 ; J16.S19 237.74,12.6 ; J16.S19 235.96,10.82 ; J16.S19 235.96,12.6 ; J16.S12 223.49,15.82 ; J16.S12 221.71,15.82 ; J16.S12 221.71,17.6 ; J16.S12 223.49,17.6 ; 133.75,3.36 J12.S2 ; J12.S2 135.61,3.36 ; J12.S2 133.75,5.23 ; J14.S2 179.15,3.36 ; J14.S2 177.29,3.36 ; J14.S2 177.29,5.23 ; 250.39,28.79 J16.S24 ; J16.S24 251.82,30.23 ; J16.S24 250.39,30.23 ; J16.S24 251.82,28.79 ; J12.S1 152.4,3.36 ; J12.S1 150.54,3.36 ; J12.S1 152.4,5.23 ; 68.58,21.18 LAN1.S2 ; LAN1.S2 70.43,19.34 ; LAN1.S2 68.58,19.34 ; LAN1.S2 70.43,21.18 ; 150.54,21.58 J12.S3 ; J12.S3 152.4,19.72 ; J12.S3 152.4,21.58 ; J12.S3 150.54,19.72 ; 221.89,28.79 J16.S10 ; J16.S10 221.89,30.23 ; J16.S10 223.32,30.23 ; J16.S10 223.32,28.79 ; J13.S3 174.17,21.58 ; J13.S3 174.17,19.72 ; J13.S3 172.31,19.72 ; J13.S3 172.31,21.58 ; LAN1.S6 70.43,5.21 ; LAN1.S6 68.58,5.21 ; LAN1.S6 68.58,3.37 ; LAN1.S6 70.43,3.37 ; LAN1.S4 69.76,13.79 ; LAN1.S4 69.76,15.63 ; LAN1.S4 67.92,15.63 ; LAN1.S4 67.92,13.79 ; J16.S25 251.99,20.82 ; J16.S25 251.99,22.6 ; J16.S25 250.21,20.82 ; J16.S25 250.21,22.6 ; 51.57,3.37 LAN1.S5 ; LAN1.S5 53.42,5.21 ; LAN1.S5 53.42,3.37 ; LAN1.S5 51.57,5.21 ; J14.S4 179.15,21.58 ; J14.S4 177.29,21.58 ; J14.S4 177.29,19.72 ; J14.S4 179.15,19.72 ; J13.S4 157.38,19.72 ; J13.S4 155.52,21.58 ; J13.S4 157.38,21.58 ; J13.S4 155.52,19.72 ; J13.S1 174.17,3.36 ; J13.S1 174.17,5.23 ; J13.S1 172.31,3.36 ; 235.96,22.6 J16.S18 ; J16.S18 237.74,22.6 ; J16.S18 235.96,20.82 ; J16.S18 237.74,20.82 ; J16.S33 266.24,15.82 ; J16.S33 266.24,17.6 ; J16.S33 264.46,15.82 ; J16.S33 264.46,17.6 ; J16.S31 266.07,28.79 ; J16.S31 264.63,28.79 ; J16.S31 266.07,30.23 ; J16.S31 264.63,30.23 ; J16.S11 223.49,25.82 ; J16.S11 221.71,27.6 ; J16.S11 223.49,27.6 ; J16.S11 221.71,25.82 ; J16.S1 209.24,12.6 ; J16.S1 207.46,10.82 ; J16.S1 207.46,12.6 ; J16.S1 209.24,10.82 ; J14.S1 195.94,3.36 ; J14.S1 194.08,3.36 ; J14.S1 195.94,5.23
  L14_INT_6 w0.508: 264.41,7.65 J16.S34 ; J16.S34 266.29,5.77 ; J16.S34 264.41,5.77 ; J16.S34 266.29,7.65 ; J11.S4 113.89,21.64 ; J11.S4 113.89,19.67 ; J11.S4 111.92,21.64 ; J11.S4 111.92,19.67 ; J16.S25 252.04,20.77 ; J16.S25 252.04,22.65 ; J16.S25 250.16,22.65 ; J16.S25 250.16,20.77 ; J16.S1 209.29,10.77 ; J16.S1 207.41,12.65 ; J16.S1 207.41,10.77 ; J16.S1 209.29,12.65 ; 177.23,19.67 J14.S4 ; J14.S4 179.2,21.64 ; J14.S4 177.23,21.64 ; J14.S4 179.2,19.67 ; 264.58,30.28 J16.S31 ; J16.S31 264.58,28.74 ; J16.S31 266.12,30.28 ; J16.S31 266.12,28.74 ; 221.66,7.65 J16.S13 ; J16.S13 223.54,5.77 ; J16.S13 223.54,7.65 ; J16.S13 221.66,5.77 ; 172.25,21.64 J13.S3 ; J13.S3 174.22,21.64 ; J13.S3 172.25,19.67 ; J13.S3 174.22,19.67 ; 235.91,12.65 J16.S19 ; J16.S19 235.91,10.77 ; J16.S19 237.79,10.77 ; J16.S19 237.79,12.65 ; J13.S1 174.22,5.28 ; J13.S1 174.22,3.31 ; J13.S1 172.25,3.31 ; 194.02,21.64 J14.S3 ; J14.S3 195.99,21.64 ; J14.S3 195.99,19.67 ; J14.S3 194.02,19.67 ; 250.33,30.28 J16.S24 ; J16.S24 251.87,30.28 ; J16.S24 251.87,28.74 ; J16.S24 250.33,28.74 ; 235.91,22.65 J16.S18 ; J16.S18 237.79,20.77 ; J16.S18 235.91,20.77 ; J16.S18 237.79,22.65 ; 133.69,5.28 J12.S2 ; J12.S2 133.69,3.31 ; J12.S2 135.66,3.31 ; J11.S1 130.68,3.31 ; J11.S1 130.68,5.28 ; J11.S1 128.71,3.31 ; 67.86,13.73 LAN1.S4 ; LAN1.S4 67.86,15.68 ; LAN1.S4 69.82,13.73 ; LAN1.S4 69.82,15.68 ; 51.52,25.29 LAN1.S1 ; LAN1.S1 51.52,23.34 ; LAN1.S1 53.47,23.34 ; J11.S3 130.68,21.64 ; J11.S3 130.68,19.67 ; J11.S3 128.71,19.67 ; J11.S3 128.71,21.64 ; J16.S33 266.29,17.65 ; J16.S33 266.29,15.77 ; J16.S33 264.41,17.65 ; J16.S33 264.41,15.77 ; 221.83,28.74 J16.S10 ; J16.S10 223.37,28.74 ; J16.S10 221.83,30.28 ; J16.S10 223.37,30.28 ; CN4.M1 34.7,14.85 ; CN4.M1 32.16,12.3 ; CN4.M1 34.7,12.3 ; CN4.M1 32.16,14.85 ; 32.16,9.17 CN4.M3 ; CN4.M3 34.7,6.62 ; CN4.M3 32.16,6.62 ; 250.16,12.65 J16.S26 ; J16.S26 252.04,12.65 ; J16.S26 250.16,10.77 ; J16.S26 252.04,10.77 ; 51.52,3.31 LAN1.S5 ; LAN1.S5 51.52,5.26 ; LAN1.S5 53.47,5.26 ; LAN1.S5 53.47,3.31 ; CN4.M4 47.84,9.17 ; CN4.M4 47.84,6.62 ; CN4.M4 45.3,9.17 ; CN4.M4 45.3,6.62 ; J13.S4 157.43,19.67 ; J13.S4 157.43,21.64 ; J13.S4 155.46,19.67 ; J13.S4 155.46,21.64 ; CN4.M2 47.84,14.85 ; CN4.M2 45.3,12.3 ; CN4.M2 47.84,12.3 ; J16.S32 266.29,25.77 ; J16.S32 266.29,27.65 ; J16.S32 264.41,25.77 ; J16.S32 264.41,27.65 ; 194.02,3.31 J14.S1 ; J14.S1 195.99,3.31 ; J14.S1 195.99,5.28 ; J16.S2 209.29,20.77 ; J16.S2 207.41,22.65 ; J16.S2 207.41,20.77 ; J16.S2 209.29,22.65 ; J11.S2 113.89,3.31 ; J11.S2 111.92,5.28 ; J11.S2 111.92,3.31 ; J16.S3 209.12,30.28 ; J16.S3 207.58,28.74 ; J16.S3 207.58,30.28 ; J16.S3 209.12,28.74 ; 221.66,25.77 J16.S11 ; J16.S11 223.54,27.65 ; J16.S11 223.54,25.77 ; J16.S11 221.66,27.65 ; LAN1.S2 70.48,19.28 ; LAN1.S2 68.53,21.23 ; LAN1.S2 68.53,19.28 ; LAN1.S2 70.48,21.23 ; 133.69,19.67 J12.S4 ; J12.S4 135.66,21.64 ; J12.S4 133.69,21.64 ; J12.S4 135.66,19.67 ; J12.S1 152.45,5.28 ; J12.S1 152.45,3.31 ; J12.S1 150.48,3.31 ; J12.S3 152.45,21.64 ; J12.S3 150.48,19.67 ; J12.S3 152.45,19.67 ; J12.S3 150.48,21.64 ; 177.23,5.28 J14.S2 ; J14.S2 177.23,3.31 ; J14.S2 179.2,3.31 ; 68.53,5.26 LAN1.S6 ; LAN1.S6 70.48,3.31 ; LAN1.S6 68.53,3.31 ; LAN1.S6 70.48,5.26 ; J16.S12 223.54,15.77 ; J16.S12 221.66,15.77 ; J16.S12 221.66,17.65 ; J16.S12 223.54,17.65 ; 155.46,3.31 J13.S2 ; J13.S2 157.43,3.31 ; J13.S2 155.46,5.28 ; 52.18,18.98 LAN1.S3 52.18,17.03
  L15_GND_6 w0.508: 264.46,25.82 J16.S32 ; J16.S32 264.46,27.6 ; J16.S32 266.24,27.6 ; J16.S32 266.24,25.82 ; J16.S18 237.74,22.6 ; J16.S18 235.96,22.6 ; J16.S18 235.96,20.82 ; J16.S18 237.74,20.82 ; 221.89,28.79 J16.S10 ; J16.S10 223.32,28.79 ; J16.S10 221.89,30.23 ; J16.S10 223.32,30.23 ; CN4.M1 34.65,12.36 ; CN4.M1 32.21,14.79 ; CN4.M1 32.21,12.36 ; CN4.M1 34.65,14.79 ; J14.S1 195.94,3.36 ; J14.S1 194.08,3.36 ; J14.S1 195.94,5.23 ; J16.S19 237.74,12.6 ; J16.S19 237.74,10.82 ; J16.S19 235.96,12.6 ; J16.S19 235.96,10.82 ; 221.71,5.82 J16.S13 ; J16.S13 221.71,7.6 ; J16.S13 223.49,7.6 ; J16.S13 223.49,5.82 ; 207.46,12.6 J16.S1 ; J16.S1 207.46,10.82 ; J16.S1 209.24,12.6 ; J16.S1 209.24,10.82 ; LAN1.S2 70.43,19.34 ; LAN1.S2 68.58,19.34 ; LAN1.S2 68.58,21.18 ; LAN1.S2 70.43,21.18 ; J11.S4 113.84,19.72 ; J11.S4 111.98,19.72 ; J11.S4 111.98,21.58 ; J11.S4 113.84,21.58 ; J14.S3 195.94,21.58 ; J14.S3 194.08,19.72 ; J14.S3 195.94,19.72 ; J14.S3 194.08,21.58 ; 250.21,22.6 J16.S25 ; J16.S25 250.21,20.82 ; J16.S25 251.99,20.82 ; J16.S25 251.99,22.6 ; 264.63,28.79 J16.S31 ; J16.S31 264.63,30.23 ; J16.S31 266.07,30.23 ; J16.S31 266.07,28.79 ; 150.54,19.72 J12.S3 ; J12.S3 152.4,19.72 ; J12.S3 152.4,21.58 ; J12.S3 150.54,21.58 ; LAN1.S5 53.42,3.37 ; LAN1.S5 53.42,5.21 ; LAN1.S5 51.57,5.21 ; LAN1.S5 51.57,3.37 ; 111.98,3.36 J11.S2 ; J11.S2 113.84,3.36 ; J11.S2 111.98,5.23 ; 133.75,21.58 J12.S4 ; J12.S4 135.61,19.72 ; J12.S4 133.75,19.72 ; J12.S4 135.61,21.58 ; 32.21,6.68 CN4.M3 ; CN4.M3 34.65,9.11 ; CN4.M3 34.65,6.68 ; CN4.M3 32.21,9.11 ; J11.S1 130.63,3.36 ; J11.S1 128.77,3.36 ; J11.S1 130.63,5.23 ; 207.64,30.23 J16.S3 ; J16.S3 209.07,30.23 ; J16.S3 207.64,28.79 ; J16.S3 209.07,28.79 ; 68.58,5.21 LAN1.S6 ; LAN1.S6 70.43,3.37 ; LAN1.S6 68.58,3.37 ; LAN1.S6 70.43,5.21 ; 250.39,28.79 J16.S24 ; J16.S24 250.39,30.23 ; J16.S24 251.82,28.79 ; J16.S24 251.82,30.23 ; LAN1.S1 53.42,23.4 ; LAN1.S1 51.57,23.4 ; LAN1.S1 53.42,25.24 ; LAN1.S1 51.57,25.24 ; CN4.M2 47.79,12.36 ; CN4.M2 45.35,12.36 ; CN4.M2 47.79,14.79 ; 221.71,25.82 J16.S11 ; J16.S11 223.49,25.82 ; J16.S11 223.49,27.6 ; J16.S11 221.71,27.6 ; J11.S3 130.63,19.72 ; J11.S3 128.77,21.58 ; J11.S3 128.77,19.72 ; J11.S3 130.63,21.58 ; 155.52,5.23 J13.S2 ; J13.S2 157.38,3.36 ; J13.S2 155.52,3.36 ; 45.35,9.11 CN4.M4 ; CN4.M4 47.79,6.68 ; CN4.M4 47.79,9.11 ; CN4.M4 45.35,6.68 ; 177.29,5.23 J14.S2 ; J14.S2 177.29,3.36 ; J14.S2 179.15,3.36 ; J13.S4 157.38,21.58 ; J13.S4 155.52,21.58 ; J13.S4 155.52,19.72 ; J13.S4 157.38,19.72 ; 221.71,17.6 J16.S12 ; J16.S12 223.49,17.6 ; J16.S12 221.71,15.82 ; J16.S12 223.49,15.82 ; 133.75,5.23 J12.S2 ; J12.S2 135.61,3.36 ; J12.S2 133.75,3.36 ; J13.S1 174.17,3.36 ; J13.S1 172.31,3.36 ; J13.S1 174.17,5.23 ; 250.21,12.6 J16.S26 ; J16.S26 251.99,12.6 ; J16.S26 251.99,10.82 ; J16.S26 250.21,10.82 ; J12.S1 152.4,3.36 ; J12.S1 152.4,5.23 ; J12.S1 150.54,3.36 ; 177.29,19.72 J14.S4 ; J14.S4 177.29,21.58 ; J14.S4 179.15,21.58 ; J14.S4 179.15,19.72 ; 264.46,15.82 J16.S33 ; J16.S33 264.46,17.6 ; J16.S33 266.24,17.6 ; J16.S33 266.24,15.82 ; 52.24,17.09 LAN1.S3 ; LAN1.S3 54.08,17.09 ; LAN1.S3 54.08,18.93 ; LAN1.S3 52.24,18.93 ; 207.46,22.6 J16.S2 ; J16.S2 209.24,22.6 ; J16.S2 207.46,20.82 ; J16.S2 209.24,20.82 ; J13.S3 174.17,19.72 ; J13.S3 172.31,19.72 ; J13.S3 172.31,21.58 ; J13.S3 174.17,21.58 ; 67.92,15.63 LAN1.S4 ; LAN1.S4 69.76,13.79 ; LAN1.S4 69.76,15.63 ; LAN1.S4 67.92,13.79 ; 264.46,5.82 J16.S34 ; J16.S34 264.46,7.6 ; J16.S34 266.24,7.6 ; J16.S34 266.24,5.82
  BOTTOM w0.508: J13.S4 157.43,21.64 ; J13.S4 155.46,21.64 ; J13.S4 155.46,19.67 ; J13.S4 157.43,19.67 ; J14.S2 179.2,3.31 ; J14.S2 177.23,5.28 ; J14.S2 177.23,3.31 ; J14.S3 195.99,19.67 ; J14.S3 194.02,19.67 ; J14.S3 194.02,21.64 ; J14.S3 195.99,21.64 ; 133.69,19.67 J12.S4 ; J12.S4 135.66,21.64 ; J12.S4 135.66,19.67 ; J12.S4 133.69,21.64 ; 133.69,3.31 J12.S2 ; J12.S2 133.69,5.28 ; J12.S2 135.66,3.31 ; 67.86,15.68 LAN1.S4 ; LAN1.S4 69.82,13.73 ; LAN1.S4 67.86,13.73 ; LAN1.S4 69.82,15.68 ; 68.53,3.31 LAN1.S6 ; LAN1.S6 70.48,3.31 ; LAN1.S6 68.53,5.26 ; LAN1.S6 70.48,5.26 ; J13.S1 174.22,3.31 ; J13.S1 172.25,3.31 ; J13.S1 174.22,5.28 ; 45.3,12.3 CN4.M2 ; CN4.M2 47.84,12.3 ; CN4.M2 47.84,14.85 ; J13.S3 174.22,21.64 ; J13.S3 172.25,19.67 ; J13.S3 172.25,21.64 ; J13.S3 174.22,19.67 ; 150.48,3.31 J12.S1 ; J12.S1 152.45,3.31 ; J12.S1 152.45,5.28 ; 111.92,5.28 J11.S2 ; J11.S2 113.89,3.31 ; J11.S2 111.92,3.31 ; 68.53,21.23 LAN1.S2 ; LAN1.S2 68.53,19.28 ; LAN1.S2 70.48,21.23 ; LAN1.S2 70.48,19.28 ; 51.52,23.34 LAN1.S1 ; LAN1.S1 51.52,25.29 ; LAN1.S1 53.47,23.34 ; 128.71,19.67 J11.S3 ; J11.S3 128.71,21.64 ; J11.S3 130.68,19.67 ; J11.S3 130.68,21.64 ; 177.23,21.64 J14.S4 ; J14.S4 177.23,19.67 ; J14.S4 179.2,19.67 ; J14.S4 179.2,21.64 ; J14.S1 195.99,3.31 ; J14.S1 194.02,3.31 ; J14.S1 195.99,5.28 ; 34.7,6.62 CN4.M3 32.16,6.62 ; CN4.M4 47.84,6.62 ; CN4.M4 45.3,9.17 ; CN4.M4 47.84,9.17 ; CN4.M4 45.3,6.62 ; LAN1.S5 53.47,5.26 ; LAN1.S5 51.52,5.26 ; LAN1.S5 51.52,3.31 ; LAN1.S5 53.47,3.31 ; 52.18,17.03 LAN1.S3 52.18,18.98 ; 150.48,19.67 J12.S3 ; J12.S3 152.45,21.64 ; J12.S3 152.45,19.67 ; J12.S3 150.48,21.64 ; J11.S1 130.68,5.28 ; J11.S1 130.68,3.31 ; J11.S1 128.71,3.31 ; J13.S2 157.43,3.31 ; J13.S2 155.46,5.28 ; J13.S2 155.46,3.31 ; J11.S4 113.89,19.67 ; J11.S4 111.92,21.64 ; J11.S4 111.92,19.67 ; J11.S4 113.89,21.64
  vias: v2(34.16,5.46) v2(34.16,1.65) v2(41.91,5.46) v2(41.91,1.65) v2(49.15,24) v2(49.53,5.46) v2(49.53,1.65) v2(49.78,24) v2(51.31,17.78) v2(51.31,12.57) v2(57.15,5.46) v2(57.15,1.65) v2(64.77,5.46) v2(64.77,1.65) v2(71.88,22.1) v2(72.39,17.78) v2(72.39,12.57) v2(72.39,5.46) v2(72.39,1.65) v2(76.96,6.73) v2(76.96,6.1) v2(80.01,5.46) v2(80.01,1.65) v2(83.82,8.51) v2(87.63,5.46) v2(87.63,1.65) v2(91.31,8.38) v2(95.25,5.46) v2(95.25,1.65) v2(99.31,8.64) v2(102.87,5.46) v2(102.87,1.65) v2(106.81,8.64) v2(107.95,6.73) v2(107.95,6.1) v2(110.49,5.46) v2(110.49,1.65) v2(125.73,1.65) v2(132.21,17.53) v2(132.21,9.91) v2(132.46,5.46) v2(132.46,1.65) v2(132.59,26.8) v2(133.22,26.8) v2(140.97,1.65) v2(148.59,1.65) v2(154.31,17.53) v2(154.31,9.91) v2(157.35,1.65) v2(163.83,1.65) v2(171.45,1.65) v2(175.39,26.8) v2(175.77,17.53) v2(175.77,9.91) v2(176.02,26.8) v2(179.07,1.65) v2(186.69,1.65) v2(193.55,1.52) v2(196.34,17.53) v2(196.34,9.91) v7(131.37,33.07) v7(132.59,33.07) v7(173.61,33.05) v7(174.85,33.99)
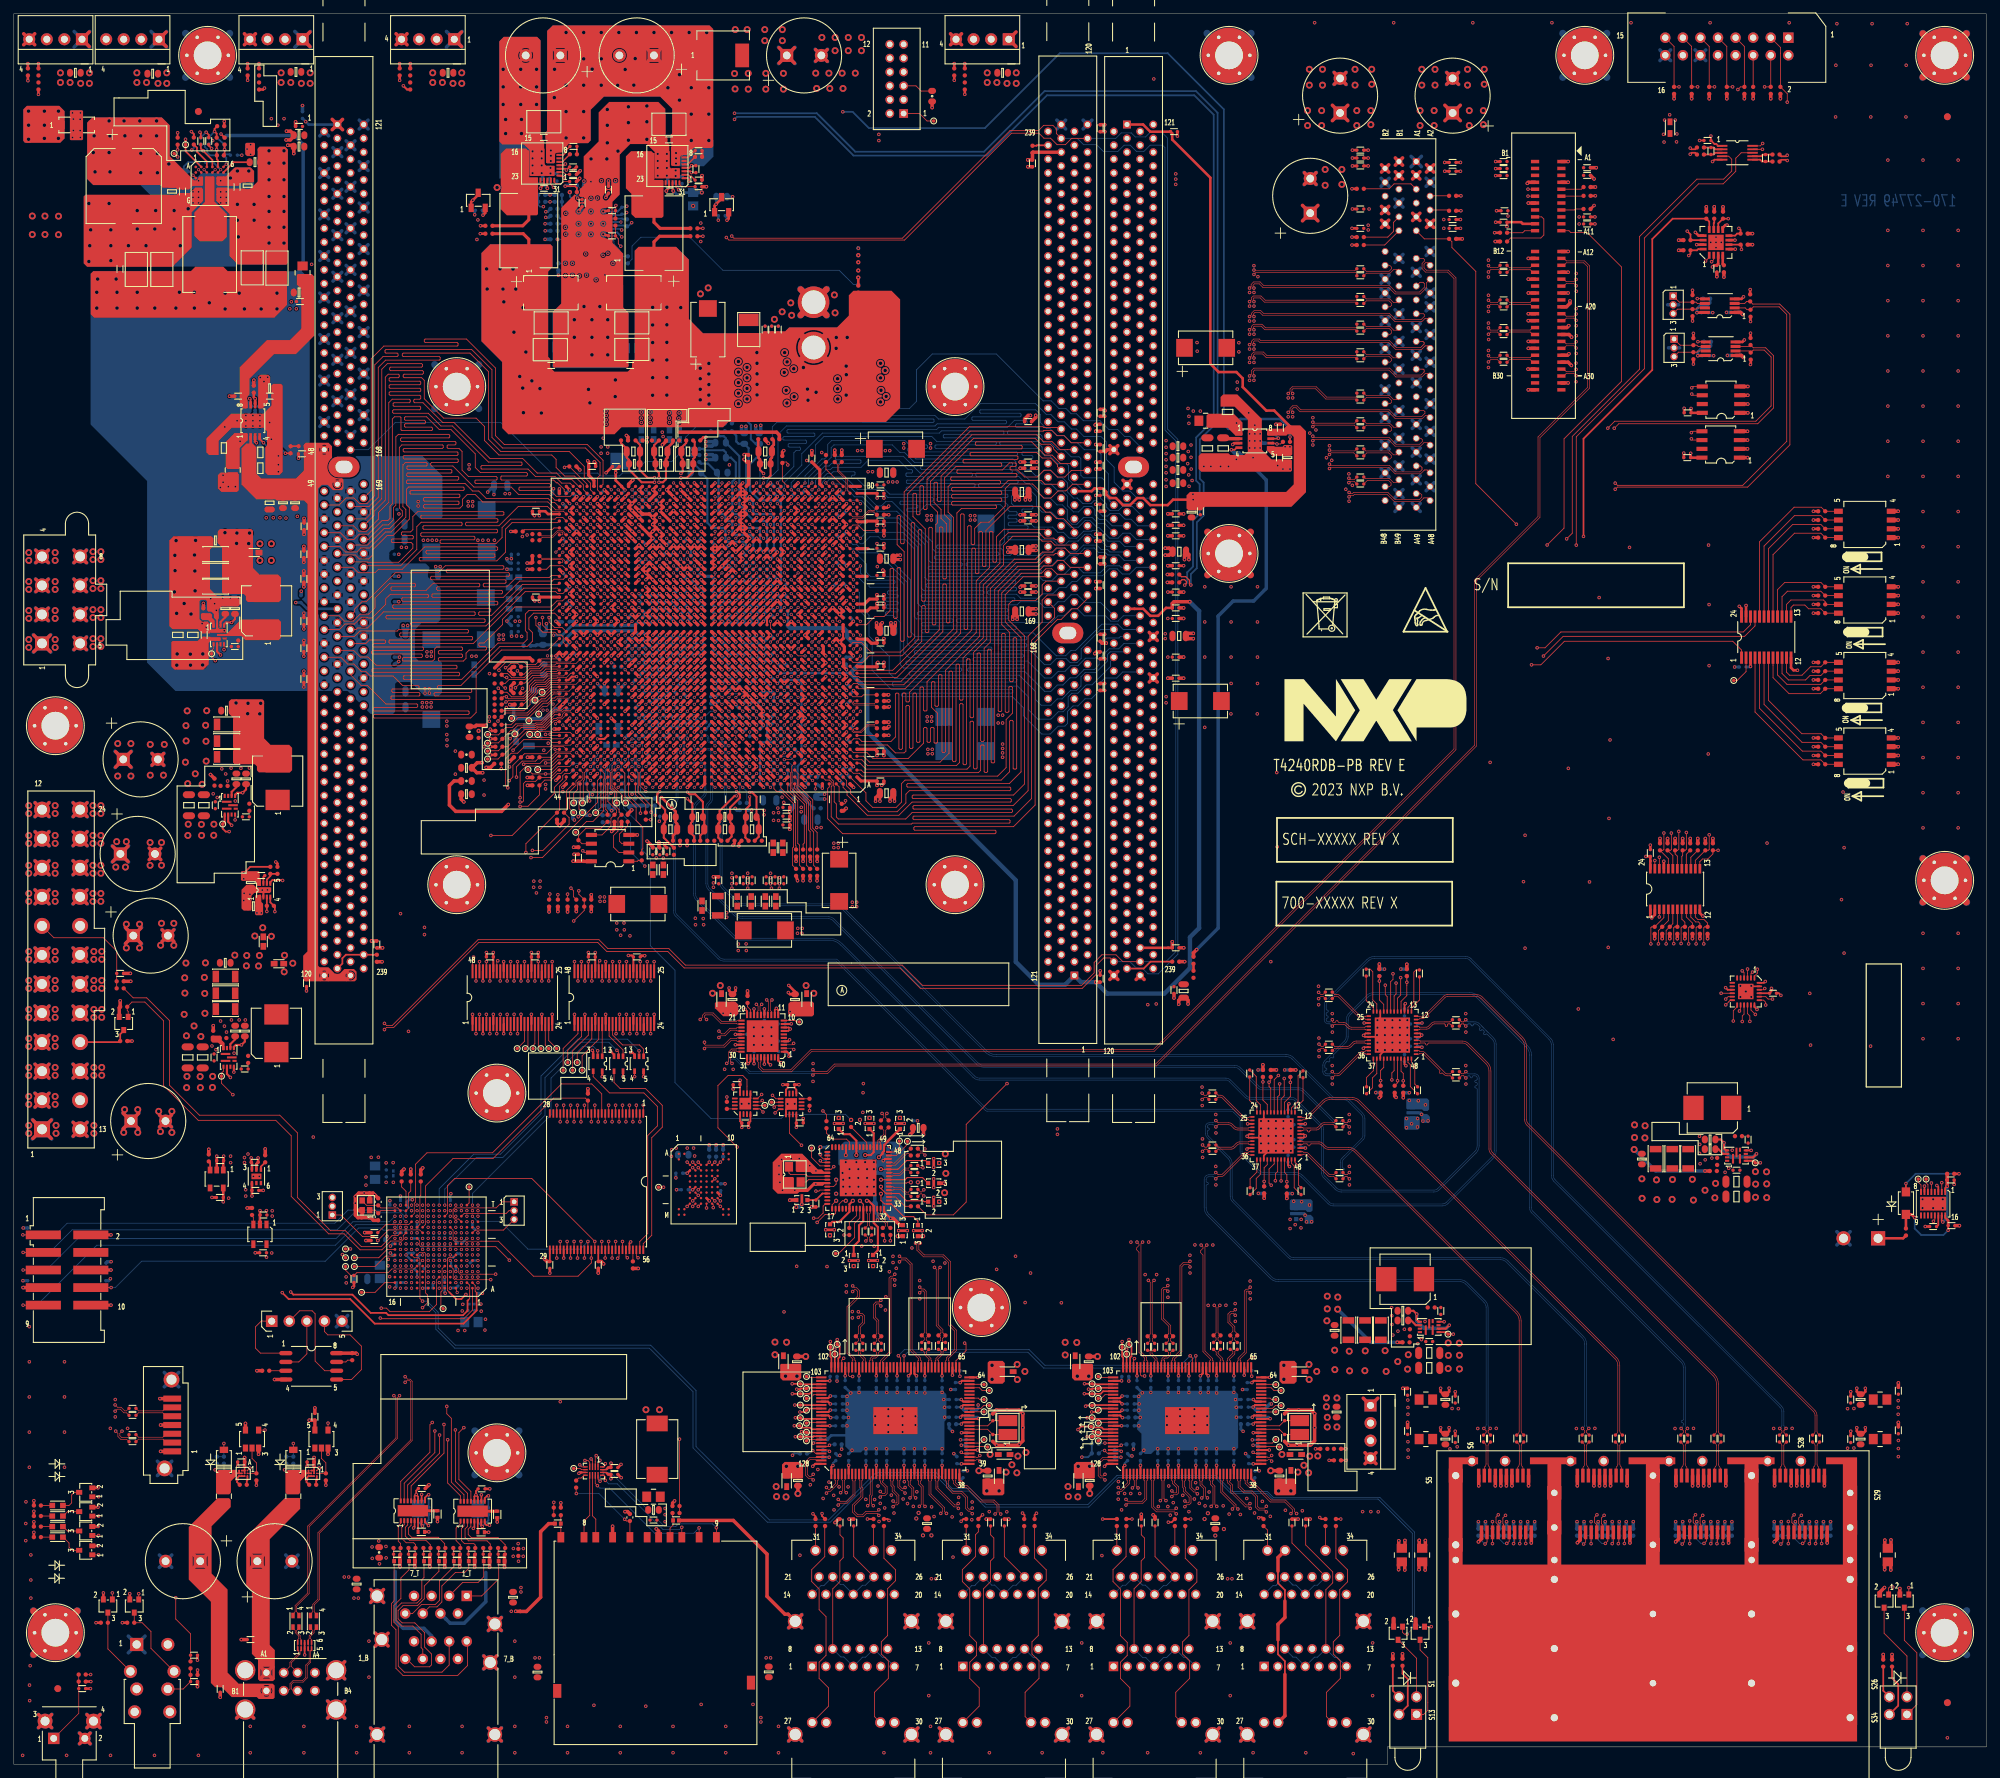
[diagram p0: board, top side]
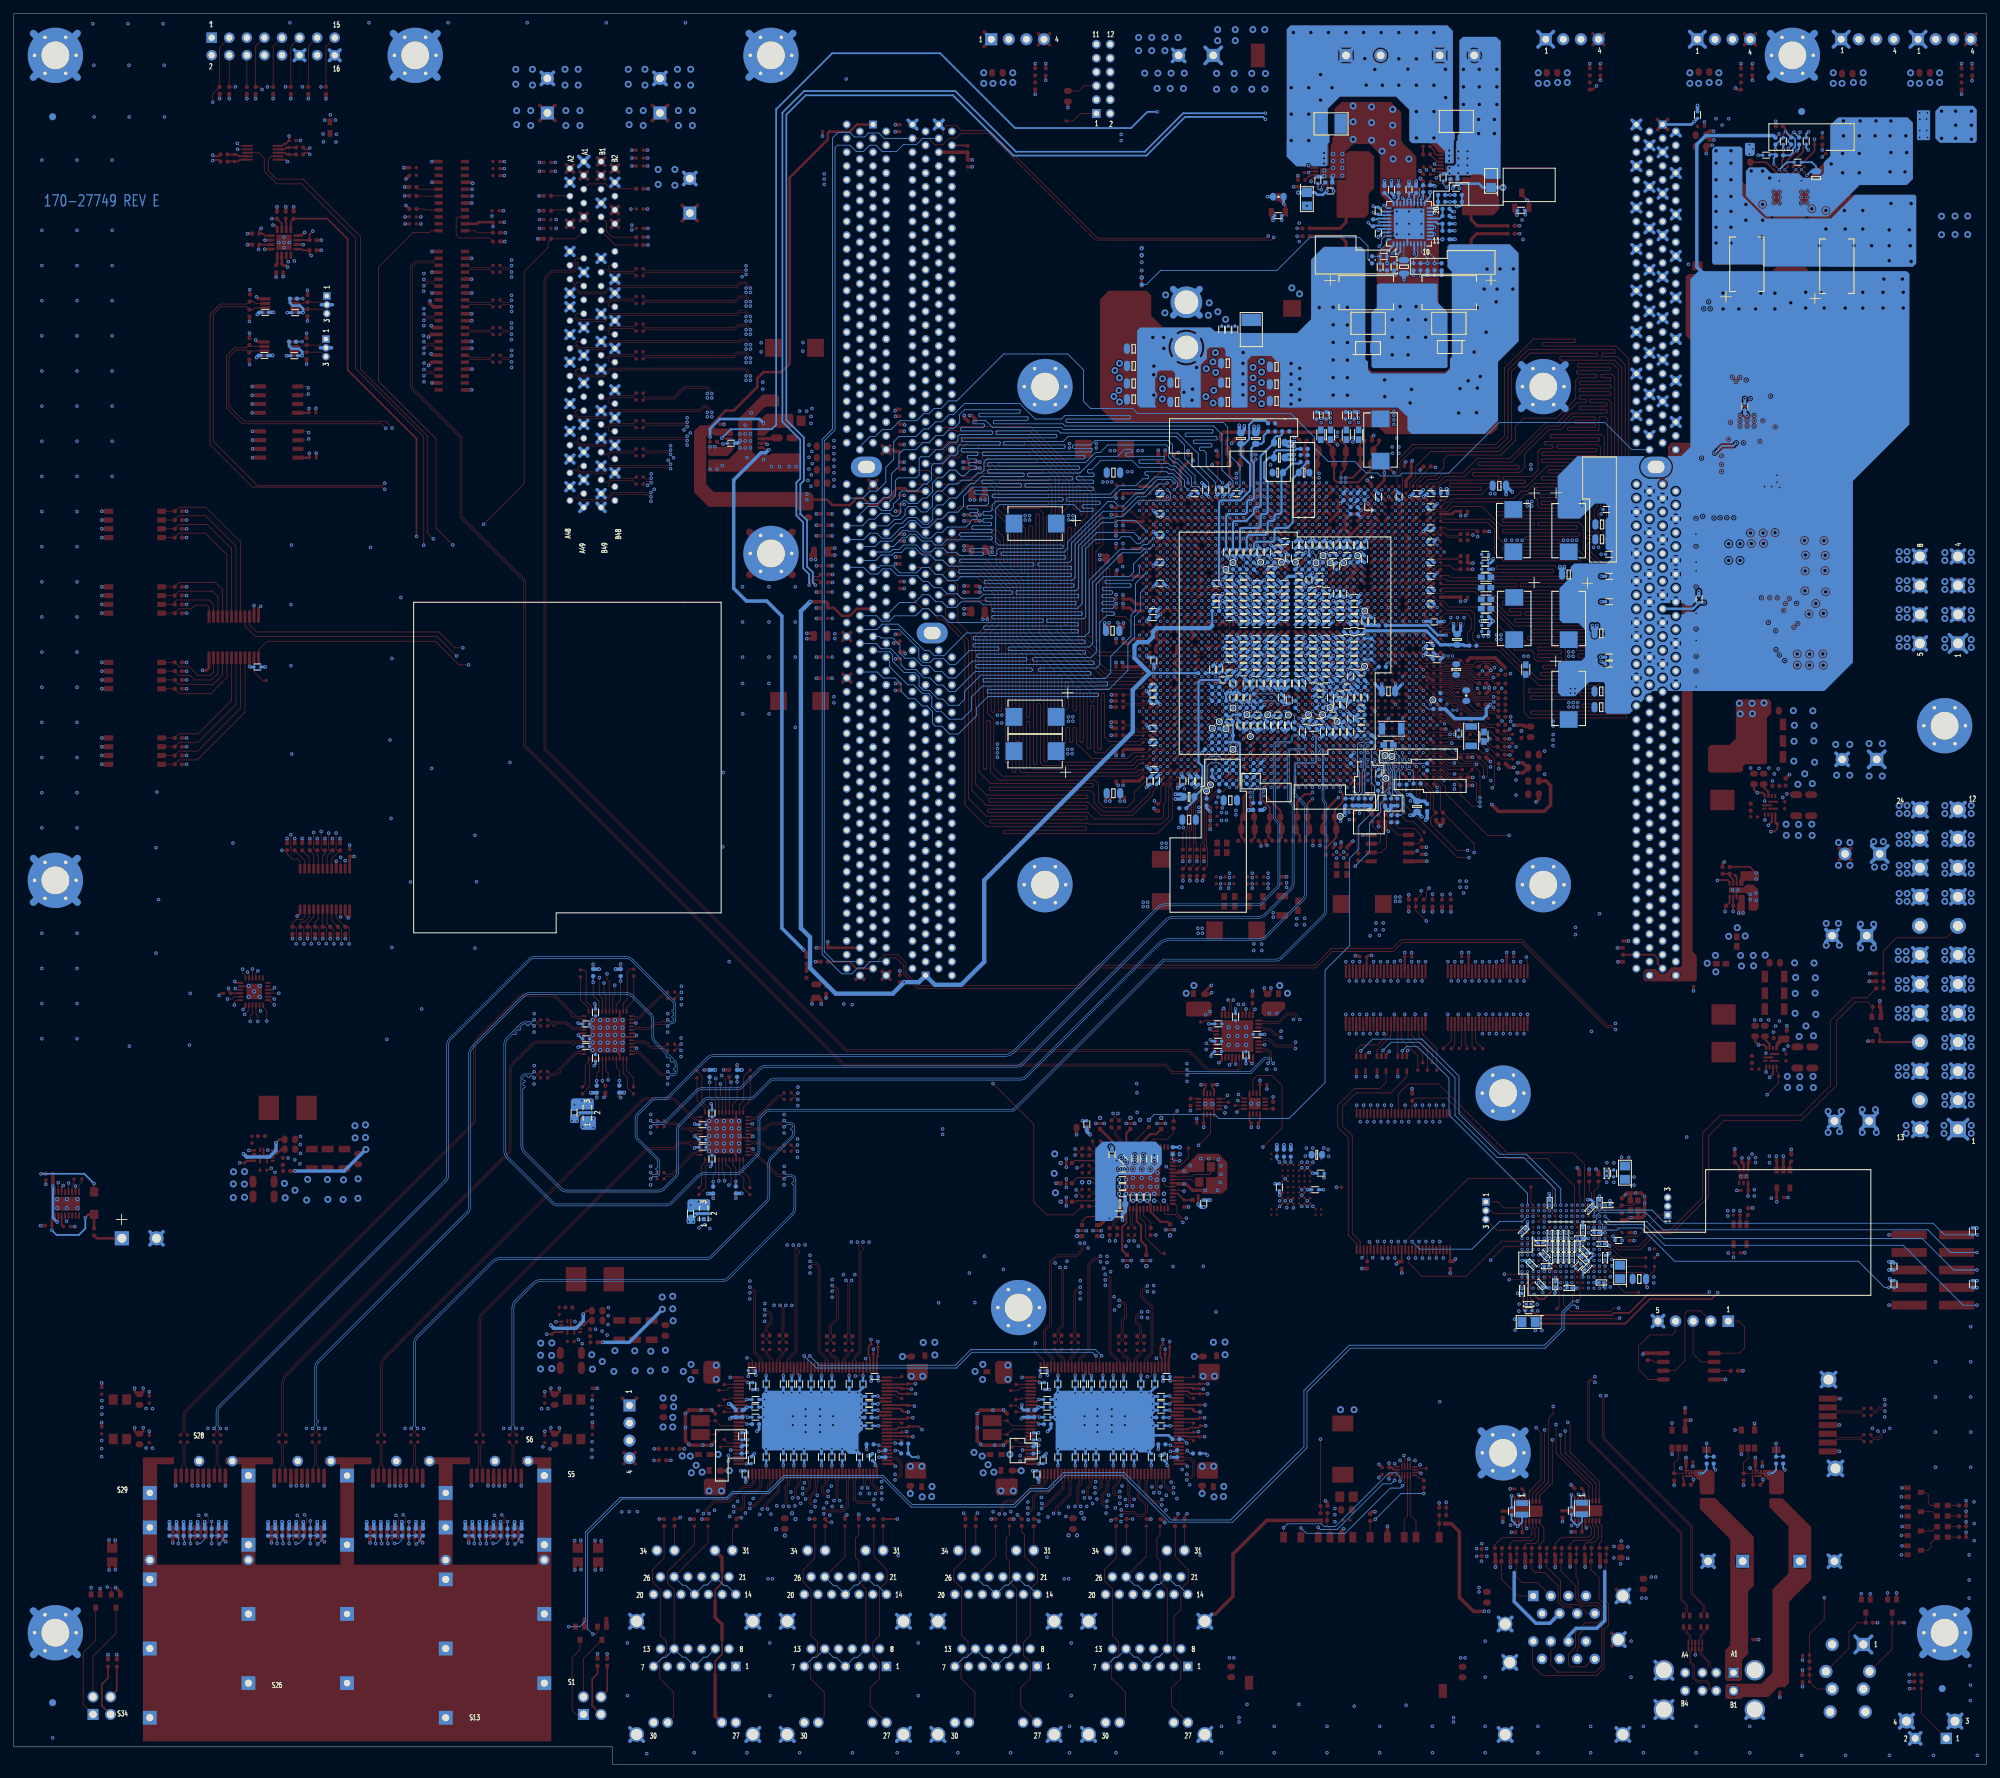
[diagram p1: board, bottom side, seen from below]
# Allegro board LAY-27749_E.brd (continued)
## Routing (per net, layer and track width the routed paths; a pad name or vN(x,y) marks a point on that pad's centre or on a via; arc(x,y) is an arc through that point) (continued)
CKGEN_VDDO0: length 5.3
  TOP w0.305: FL13.1 118.28,78.38 119.28,78.38 120.75,79.85 U36.22 120.75,80.94 v5(121.23,81.43)
CKGEN_VDDO1: length 8.6
  TOP w0.165: v5(122.25,81.43) 122.75,80.94 U36.26
  TOP w0.305: U36.26 122.75,78.5 122.12,77.88 122.12,75.63 121.36,74.87 FL16.1
CKGEN_VDDO2: length 8.9
  TOP w0.305: v5(123.27,81.43) 123.52,81.43 124.25,80.71 U36.29 124.25,78.24 124.85,77.64 124.85,74.29 FL18.1
CKGEN_VDDO3: length 8.1
  TOP w0.165: v5(125.3,82.45) 125.3,81.48 125.79,80.98 U36.33 126.76,80.98 128.6,79.15 130,79.15 130.63,78.51 FL21.1
CKGEN_VDDO4: length 7.9
  TOP w0.165: FL23.1 131.52,81.31 131.39,81.43 128.98,81.43 127.93,82.48 U36.36 126.02,82.48 125.3,83.21 v5(125.3,83.46)
CKGEN_VDDO5: length 7.3
  TOP w0.165: FL14.1 131.31,84.79 129.08,84.79 128.78,84.48 U36.40 125.3,84.48 v5(125.3,84.48)
CKGEN_VDDO6: length 7.5
  TOP w0.165: v5(125.3,86) 125.32,85.98 U36.43 127.74,85.98 129.01,87.25 131.76,87.25 FL17.1
CKGEN_VDDO7: length 5.3
  TOP w0.305: v5(125,87.73) 125.53,88.25 125.53,88.42 125.75,88.64 U36.49 125.75,89.48 126.26,89.99 126.26,90.03
  TOP w0.381: 126.26,90.03 FL19.1
CKGEN_VDDO8: length 5
  TOP w0.305: FL22.1 124.25,91.21 U36.52 124.25,88.46 123.82,88.04 v5(123.01,88.04)
CKGEN_VDDO9: length 5.3
  TOP w0.305: v5(121.74,88.04) 121.75,88.04 U36.57 121.75,90.12 120.8,91.06 119.95,91.06 FL24.1
CKSTPO_B: length 354.2
  TOP w0.118: J2.15 239.9,248.28 R67.1 v2(240.61,242.44) ; v2(71.7,148.23) 72.08,148.61 72.08,148.61 TP213.1 73.31,149.83 75.43,149.83 75.63,150.04 76.5,150.04 78.16,151.69 U22.L44
  L3_INT_1 w0.087: v2(240.61,242.44) 240.61,241.5 242.93,239.19 253.07,239.19 253.16,239.1 253.16,218.36 250.75,215.95 234.65,215.95 232.49,213.79 232.49,184.02 231.09,182.63 216.28,182.63 211.44,177.79 211.44,150.87 158.44,97.87 139.45,97.87 119.08,118.24 119.08,129.72 116.76,132.03 111.28,132.03 107.95,135.36 107.53,135.36 107.05,135.84 89.03,135.84 88.67,136.19 88.67,139.65 88.9,139.88 88.9,145.29 88.52,145.67 88.06,145.67 87.76,145.97 87.76,148.46 84.63,151.59 76.33,151.59 75.23,150.5 73.96,150.5 v2(71.7,148.23)
CLK_ENET1: length 25.9
  TOP w0.118: v2(137.39,60.86) 137.59,60.66 137.59,59.77 136.13,58.31 U42.66 ; R5849.2 v2(126.66,75.65)
  L14_INT_6 w0.087: v2(126.66,75.65) 127.86,75.65 132.54,70.97 132.54,64.16 135.84,60.86 v2(137.39,60.86)
CLK_ENET2: length 70.3
  TOP w0.118: R5850.2 125.83,76.22 v2(125.83,75.64) ; v2(179.07,58.72) 178.69,58.72 178.3,58.33 U620.66
  L14_INT_6 w0.087: v2(125.83,75.64) 125.83,75.23 126.16,74.9 127.58,74.9 131.82,70.67 131.82,63.86 135.54,60.14 142.25,60.14 145.82,63.7 174.09,63.7 v2(179.07,58.72)
CLK_PCIE_REF_N: length 42.4
  TOP w0.091: v2(131.5,82.13) 131.19,82.44 131,82.44 C3874.2 ; v2(112.67,104.19) 112.47,103.98 U32.3
  L12_INT_5 w0.086: v2(131.5,82.13) 131.23,82.4 129.57,82.4 128.02,83.95 128.02,90.12 121.46,96.67 111.35,96.67 109.91,98.12 109.91,102.54 111.28,103.92 112.1,103.92 112.19,104.01 112.19,104.1 112.28,104.19 v2(112.67,104.19)
CLK_PCIE_REF_P: length 41.3
  TOP w0.091: C3873.2 131,82.72 131.19,82.72 v2(131.5,83.02) ; v2(112.7,103.3) 112.52,103.48 U32.2
  L12_INT_5 w0.086: v2(112.7,103.3) 112.28,103.3 112.19,103.39 112.19,103.49 112.1,103.57 111.43,103.57 110.25,102.4 110.25,98.26 111.5,97.02 121.61,97.02 128.36,90.26 128.36,84.09 129.71,82.74 131.22,82.74 v2(131.5,83.02)
CLK_RETIMER: length 63.8
  TOP w0.118: v2(131.37,86.21) 130.95,86.21 C5310.2 ; v2(182.73,99.54) 182.12,98.94 U65.19
  L3_INT_1 w0.087: v2(131.37,86.21) 131.85,85.72 133.78,85.72 134.37,86.31 163.53,86.31 172.09,94.87 175.03,94.87 179.71,99.54 v2(182.73,99.54)
CLK_SE1_100MHZ: length 29.8
  TOP w0.091: R5708.2 130.98,88.62 131.34,88.62 v2(131.65,88.93) ; U626.7 107.93,95.72 v2(108.14,95.93)
  L14_INT_6 w0.086: v2(108.14,95.93) 108.51,95.55 108.79,95.55 109.28,96.04 110.44,96.04 110.9,96.49 121.87,96.49 129.72,88.65 131.37,88.65 v2(131.65,88.93)
CLK_SE2_100MHZ: length 29.7
  TOP w0.091: v2(109.87,94.97) 110.08,95.18 U627.7 ; R5726.2 130.98,88.34 131.35,88.34 v2(131.65,88.04)
  L14_INT_6 w0.086: v2(109.87,94.97) 109.2,94.97 109.08,95.08 109.08,95.36 109.42,95.69 110.58,95.69 111.04,96.15 121.73,96.15 129.58,88.3 131.38,88.3 v2(131.65,88.04)
CLK_SE_66MHZ: length 27.1
  TOP w0.118: v2(108.26,94.26) 107.8,94.72 U626.5 ; R5707.2 v2(119.97,76.49)
  L5_INT_2 w0.087: v2(119.97,76.49) 119.35,77.11 119.35,84.89 119.02,85.22 119.02,87.73 114.05,92.71 109.81,92.71 v2(108.26,94.26)
CLK_SE_133MHZ: length 11.6
  TOP w0.118: v2(109.63,96.67) 110.12,96.18 U627.5 ; v2(116.91,94.42) 117.42,93.9 R5724.2
  L5_INT_2 w0.087: v2(109.63,96.67) 115.08,96.67 116.91,94.85 v2(116.91,94.42)
CLK_USB: length 73.5
  BOTTOM w0.118: v5(120.98,93.12) 120.17,93.93 111.48,93.93 110.9,93.34 100.71,93.34 95.53,98.53 95.53,114.76 91.97,118.31 91.97,130.96 90.65,132.28 90.65,135.64 88.11,138.18 88.11,139.34 87.86,139.6 R761.2
CLK_USB_DUT: length 4.8
  TOP w0.118: v3(88.33,145.2) U22.E34
  BOTTOM w0.118: v3(88.33,145.2) 88.33,144.85 87.76,144.27 C871.2 88.27,143.25 88.27,142.14 R761.1
CLKU0_P: length 3.2
  TOP w0.118: R5707.1 120.73,78.26 121.75,79.28 U36.24
CLKU1_N: length 3
  TOP w0.091: C3882.1 123.36,77.84 123.36,79.55 123.25,79.66 U36.27
CLKU1_P: length 3
  TOP w0.091: U36.28 123.75,79.66 123.64,79.55 123.64,77.84 C3881.1
CLKU2_N: length 3.5
  TOP w0.091: U36.30 124.75,79.77 124.86,79.66 124.86,79.23 125.97,78.12 125.97,77.79 125.68,77.51 R5850.1
CLKU2_P: length 3.5
  TOP w0.091: U36.31 125.25,79.73 125.14,79.62 125.14,79.35 126.25,78.24 126.25,77.79 126.53,77.51 R5849.1
CLKU3_P: length 3.7
  TOP w0.118: U36.35 127.41,81.98 128.76,80.64 R5722.1
CLKU4_N: length 3.7
  TOP w0.091: U36.37 127.07,82.98 127.18,83.09 128.14,83.09 128.84,82.4 129.3,82.4 C3874.1
CLKU4_P: length 3.7
  TOP w0.091: U36.38 127.07,83.48 127.18,83.37 128.26,83.37 128.96,82.68 129.26,82.68 129.63,83.05 C3873.1
CLKU5_N: length 3.7
  TOP w0.091: U36.41 126.94,84.98 127.06,85.09 128.06,85.09 128.84,85.88 129.29,85.88 129.62,85.55 C5311.1
CLKU5_P: length 3.7
  TOP w0.091: U36.42 126.99,85.48 127.1,85.37 127.94,85.37 128.73,86.16 129.29,86.16 129.62,86.49 C5310.1
CLKU6_N: length 4
  TOP w0.091: R5726.1 129.29,88.29 129.07,88.29 127.37,86.59 127.02,86.59 126.92,86.48 U36.44
CLKU6_P: length 4.1
  TOP w0.091: U36.45 126.93,86.98 127.05,86.87 127.25,86.87 128.96,88.57 129.2,88.57 R5708.1
CLKU7_N: length 3.4
  TOP w0.091: U36.50 125.25,89.81 125.14,89.92 125.14,90.06 125.99,90.92 125.99,91.63 R5848.1
CLKU7_P: length 3.4
  TOP w0.091: U36.51 124.75,89.81 124.86,89.92 124.86,90.18 125.71,91.03 125.71,91.62 R5847.1
CLKU8_P: length 3.9
  TOP w0.118: R5713.1 123.25,89.83 U36.54
CLKU9_P: length 5.3
  TOP w0.118: R5724.1 117.42,91.21 118.29,90.35 120.32,90.35 120.75,89.92 U36.59
COP_HRST_B: length 329.7
  TOP w0.118: J2.13 242.42,248.31 242.42,247.93 242.44,247.9 R68.1 v2(243.31,242.44)
  L3_INT_1 w0.087: v1(67.07,76) 71.43,76 81.18,85.76 87.41,85.76 94.54,92.89 112.14,92.89 115.49,96.24 160.38,96.24 213.88,149.75 213.88,177.77 216.66,180.54 232.08,180.54 234.62,183.08 234.62,211.84 236.63,213.84 253.14,213.84 257.68,218.39 257.68,241.02 256.84,241.86 251.89,241.86 250.37,243.38 244.25,243.38 v2(243.31,242.44)
COP_SRST_B: length 326.7
  TOP w0.118: 243.71,249.56 244.98,248.28 R69.1 v2(245.75,242.44)
  L3_INT_1 w0.087: v1(66.27,76) 66.69,76.43 71.35,76.43 81.1,86.18 87.05,86.18 94.06,93.19 111.96,93.19 115.24,96.47 160.1,96.47 213.58,149.95 213.58,177.87 216.48,180.77 232,180.77 234.39,183.16 234.39,212.01 236.44,214.06 252.74,214.06 257.28,218.59 257.28,240.97 256.62,241.63 251.76,241.63 250.42,242.98 246.28,242.98 v2(245.75,242.44)
COP_TCK: length 337.8
  TOP w0.118: J2.7 250.06,248.28 R71.1 249.5,242.44 v2(249.12,242.06) ; U22.K44 78.58,150.69 v3(78.27,150.38)
  L3_INT_1 w0.087: v3(78.27,150.38) 78.87,149.78 78.87,148.44 79.6,147.7 83.39,147.7 83.92,147.17 83.92,142.39 84.45,141.86 84.45,135.84 86.44,133.86 90.58,133.86 91.14,134.42 105.61,134.42 111.46,128.57 116.31,128.57 117.44,127.44 117.44,117.31 137.97,96.77 159.77,96.77 213.3,150.31 213.3,177.94 216.43,181.08 231.94,181.08 234.09,183.22 234.09,213 235.36,214.27 251.92,214.27 256.9,219.25 256.9,240.44 256.06,241.27 249.91,241.27 v2(249.12,242.06)
COP_TDI: length 327.7
  TOP w0.118: v3(79.33,150.2) 79.83,149.7 U22.J43 ; v2(256.26,240.23) 256.26,241.45 R74.1 255.27,247.29 255.3,247.32 255.3,248.13 253.87,249.56
  L3_INT_1 w0.087: v2(256.26,240.23) 254.61,238.58 254.61,217.6 251.51,214.5 234.9,214.5 233.86,213.46 233.86,183.34 231.98,181.46 216.51,181.46 213.01,177.96 213.01,150.68 159.43,97.1 138.43,97.1 117.65,117.88 117.65,127.79 116.31,129.13 111.82,129.13 106.18,134.77 87.35,134.77 84.86,137.26 84.86,148.29 84.38,148.77 80.26,148.77 79.33,149.7 v3(79.33,150.2)
COP_TDO: length 344.7
  TOP w0.118: U22.K42 80.83,150.7 v3(81.33,151.2)
  L3_INT_1 w0.087: v3(81.33,151.2) 81.81,150.71 84.81,150.71 86.9,148.62 86.9,137.31 88.7,135.51 107.11,135.51 112.93,129.69 117.02,129.69 118.44,128.27 118.44,118.41 139.24,97.61 158.69,97.61 211.95,150.87 211.95,177.97 216.35,182.37 231.18,182.37 232.89,184.09 232.89,213.56 235.05,215.72 251.18,215.72 253.7,218.24 253.7,239.12 253.21,239.6 244.45,239.6 242.39,241.66 242.39,247.42 243.28,248.31 255.17,248.31 J2.1
COP_TMS: length 329.1
  TOP w0.118: v2(248.36,242.44) R70.1 247.52,248.28 J2.9 ; v3(81.33,150.2) U22.K41
  L3_INT_1 w0.087: v2(248.36,242.44) 248.36,240.97 249.35,239.98 253.47,239.98 254,239.45 254,218.03 251.46,215.49 235.33,215.49 233.25,213.41 233.25,183.41 231.6,181.76 216.5,181.76 212.52,177.78 212.52,150.81 159.07,97.36 138.87,97.36 118.06,118.17 118.06,128.07 116.71,129.41 112.32,129.41 106.68,135.05 87.43,135.05 85.22,137.26 85.22,142.93 85.72,143.43 85.72,148.13 84.12,149.73 81.79,149.73 v3(81.33,150.2)
COP_TRST_B: length 321
  TOP w0.118: 253.87,247.01 R73.1 v2(252.98,242.44)
  L3_INT_1 w0.087: v2(252.98,242.44) 257.02,242.44 258.44,241.02 258.44,218.34 253.68,213.57 236.86,213.57 235.23,211.94 235.23,182.27 232.77,179.81 216.45,179.81 214.25,177.6 214.25,149.38 160.9,96.02 117.51,96.02 114.07,92.58 94.72,92.58 87.41,85.28 81.45,85.28 70.18,74.02 65.86,74.02 v1(65.47,74.4)
COP_VDD_SNS: length 4.6
  TOP w0.118: R72.2 J2.6
D1TPA: length 1.4
  TOP w0.118: U22.AL13 109.33,172.19 v3(109.33,172.2)
  BOTTOM w0.118: TP82.1 109.36,172.2 v3(109.33,172.2)
D2TPA: length 1.4
  TOP w0.118: U22.AM13 v3(109.33,173.2)
  BOTTOM w0.118: v3(109.33,173.2) 109.33,173.2 TP78.1
D3TPA: length 1.5
  TOP w0.118: v3(90.33,167.19) U22.AF32
  BOTTOM w0.118: v3(90.33,167.19) 89.83,166.7 TP83.1
DDRCLK: length 89.1
  TOP w0.118: R5896.2 v2(114.98,94.46)
  L7_INT_3 w0.087: v2(114.98,94.46) 118.53,98.01 118.53,111.74 114.78,115.48 114.78,121.84 110.01,126.62 110.01,129.49 109.35,130.15 109.35,137.72 109.86,138.23 109.86,146.51 110.03,146.69 110.67,146.69 110.82,146.84 110.82,156.39 110.6,156.62 108.24,156.62 107.96,156.9 107.96,172.82 v3(108.33,173.2)
  BOTTOM w0.118: v3(108.33,173.2) R698.1
DEBUG_LED1_B: length 3.5
  TOP w0.118: Q7.3 8.42,30.91 7.98,31.36 7.98,31.97 7.12,32.82 LED1.C
DEBUG_LED2_B: length 2.6
  TOP w0.118: Q8.3 7.76,33.71 7.12,34.34 LED2.C
DEBUG_LED3_B: length 2.6
  TOP w0.118: Q9.3 7.76,36.5 7.12,35.86 LED3.C
DEBUG_LED4_B: length 3.8
  TOP w0.118: LED4.C 7.98,37.39 8.36,37.77 8.36,38.91 8.74,39.29 Q10.3
DIMM1_SA1: length 2.3
  TOP w0.254: R113.1 147.76,233.93 147.83,234 J6.237
DIMM2_SA2: length 7
  TOP w0.254: R338.1 164.26,116 163.26,115 J7.119
DIMM3_SA: length 7
  TOP w0.254: R336.1 J5.237 47.99,117 47.47,116.49 47.47,115.72 J5.119
DUT_DMA0: length 11.2
  TOP w0.102: 78.13,154.1 78.32,154.29 79.43,154.29 U22.P43
  TOP w0.118: 78.13,154.1 77.9,154.1 77.15,153.35 76.49,153.35 74.45,151.31 72.9,151.31 71.84,150.24 R268.1
DUT_DMA1: length 5.3
  TOP w0.102: 78.36,155.3 79.43,155.3 U22.R43
  TOP w0.118: 78.36,155.3 77.62,155.3 76.63,154.31 75.82,154.31 75.31,153.8 TP2.1
DUT_DMA2: length 2.8
  TOP w0.118: U22.R44 77.59,155.69 76.83,154.94 TP1.1
DUT_DMA3: length 2.4
  TOP w0.118: v3(81.33,153.2) U22.N41
  BOTTOM w0.118: v3(81.33,153.2) 80.66,152.53 R732.1
DUT_DMA4: length 8.4
  TOP w0.118: TP4.1 72.39,151.64 74.27,151.64 76.3,153.67 76.96,153.67 77.99,154.69 U22.P44
DUT_DMA5: length 6.5
  TOP w0.102: U22.P42 80.22,154.09 78.57,154.09 78.21,153.72 77.86,153.72 77.05,152.91 76.45,152.91 75.84,152.3 TP3.1
DUT_HRESET_B: length 99.3
  TOP w0.118: U22.D35 87.33,145.19 v3(87.33,145.2)
  L5_INT_2 w0.087: v2(86.29,140.37) 86.01,140.09 85.31,139.38 85.31,127.26 84.23,126.18 84.23,122.48 80.58,118.83 80.58,101.79 85.47,96.9 85.47,94.36 85.95,93.88 85.95,89.92 82.35,86.31 82.35,79.2 79.38,76.23 79.38,74.42 78.94,73.99 78.94,72.52 78.18,71.75 71.25,71.75 69.82,73.18 64.51,73.18 64.26,73.43 64.26,74.01 v1(63.87,74.4)
  BOTTOM w0.118: R767.2 85.98,140.06 v2(86.29,140.37) 86.29,140.81 86.03,141.07 86.03,143.43 86.42,143.83 86.42,144.29 v3(87.33,145.2)
DUT_PORESET_B: length 100.8
  TOP w0.118: v3(88.33,146.2) U22.F35
  L3_INT_1 w0.087: v1(67.07,74.4) 66.69,74.78 65.23,74.78 65.07,74.93 65.07,81.2 71.93,88.06 86.67,88.06 96.24,97.64 96.24,124.28 91.18,129.35 v2(91.18,129.81)
  BOTTOM w0.118: v2(91.18,129.81) 89.1,131.88 89.1,136.07 87.5,137.67 87.5,138.94 R766.2 86.87,140.59 86.31,141.15 86.31,143.27 86.77,143.73 86.77,144.23 87.25,144.72 87.46,144.72 87.82,145.07 87.82,145.69 v3(88.33,146.2)
DUT_RESET_REQ_B: length 101.7
  TOP w0.118: U22.G33 v3(89.33,147.2)
  L5_INT_2 w0.087: v3(89.33,147.2) 88.77,146.64 88.77,145.92 88.52,145.67 88.14,145.67 87.88,145.41 87.88,145.11 87.48,144.7 79.45,144.7 77.96,143.21 77.96,132.03 74.38,128.46 74.38,124.8 67.39,117.8 67.39,116.94 65.23,114.78 65.23,110.41 64.64,109.83 64.64,92.38 68.12,88.9 68.12,76.99 67.54,76.4 66.14,76.4 65.84,76.11 65.84,74.29 66.14,73.99 66.68,73.99 v1(67.07,73.6)
  BOTTOM w0.102: 90.04,143.76 89.94,143.87 89.94,144.55 89.71,144.78 89.71,146.81 v3(89.33,147.2)
  BOTTOM w0.118: R763.2 90.68,139.95 90.15,140.48 90.15,143.66 90.04,143.76
DUT_TRST_B: length 112.3
  TOP w0.118: U22.J42 80.33,150.19 v3(80.33,150.2)
  L3_INT_1 w0.087: v3(80.33,150.2) 79.65,150.88 76.94,150.88 75.97,149.91 75.97,146.33 77.83,144.48 77.83,127.33 82.5,122.66 88.75,122.66 93.6,117.8 93.6,111.79 92.56,110.74 79.32,110.74 76.53,107.95 76.53,93.32 64.24,81.03 64.24,74.83 v1(64.67,74.4)
DUT_UART1_CTS_B: length 193.1
  TOP w0.118: U22.N11 v3(112.33,153.2) ; v2(62.69,46.89) 62.69,40.64 64.54,38.78 U46.16
  L7_INT_3 w0.087: v2(62.69,46.89) 63.25,47.45 64.67,47.45 69.44,52.22 71.69,52.22 81.55,62.08 129.02,62.08 142.45,75.51 142.45,96.21 120.4,118.26 120.4,134.13 114.94,139.59 114.94,152.17 114.39,152.72 112.81,152.72 v3(112.33,153.2)
DUT_UART1_RTS_B: length 190.6
  TOP w0.118: v2(65.02,48.64) 64.31,47.93 64.31,41.15 66.04,39.42 U46.13 ; U22.M10 v3(112.33,152.2)
  L7_INT_3 w0.087: v3(112.33,152.2) 112.82,151.71 114.38,151.71 114.75,151.34 114.75,139.37 120.02,134.1 120.02,118.06 142.19,95.89 142.19,75.72 128.79,62.32 81.22,62.32 71.78,52.88 69.16,52.88 65.02,48.74 v2(65.02,48.64)
DUT_UART1_RXD: length 192.1
  TOP w0.118: v2(62.56,51.71) 62.56,50.65 63.22,49.99 63.22,40.77 65.04,38.94 U46.15 ; U22.M11 v3(111.33,152.2)
  L7_INT_3 w0.087: v2(62.56,51.71) 66.12,55.27 70.99,55.27 79.35,63.62 128.29,63.62 140.82,76.15 140.82,94.13 117.35,117.59 117.35,127.65 114.68,130.32 114.68,135.1 113.3,136.49 113.3,139.02 113.13,139.19 113.13,144.86 111.96,146.03 111.96,151.57 v3(111.33,152.2)
DUT_UART1_TXD: length 189.5
  TOP w0.118: U46.14 65.54,39.15 63.8,40.89 v2(63.8,48.31) ; U22.L10 v3(112.33,151.2)
  L7_INT_3 w0.087: v3(112.33,151.2) 112.85,150.67 113.54,150.67 113.92,150.29 113.92,139.88 117.68,136.12 117.68,130.73 119.38,129.03 119.38,118.06 141.94,95.5 141.94,75.86 128.65,62.57 80.76,62.57 71.48,53.29 68.35,53.29 63.8,48.74 v2(63.8,48.31)
DUT_UART2_CTS_B: length 192.5
  TOP w0.118: v2(60.46,49.39) 60.12,49.05 60.12,45.09 55.91,40.87 U95.16 ; U22.K11 v3(111.33,150.2)
  L7_INT_3 w0.087: v3(111.33,150.2) 111.73,149.79 111.73,145.9 112.94,144.69 112.94,136.33 113.51,135.76 113.51,130.07 115.24,128.35 116.05,128.35 116.84,127.56 116.84,117.45 140.56,93.73 140.56,76.25 128.21,63.91 79.11,63.91 70.98,55.78 65.46,55.78 60.73,51.05 60.73,49.66 v2(60.46,49.39)
DUT_UART2_RTS_B: length 190.3
  TOP w0.118: U22.K10 v3(112.33,150.2) ; U95.13 57.41,40.21 62.15,44.96 v2(62.15,49.1)
  L7_INT_3 w0.087: v3(112.33,150.2) 112.96,149.57 112.96,146.04 113.54,145.46 113.54,139.52 117.17,135.89 117.17,130.35 118.36,129.16 118.36,117.93 141.41,94.89 141.41,76.09 128.41,63.1 80.07,63.1 71.3,54.33 67.39,54.33 v2(62.15,49.1)
DUT_UART2_RXD: length 189.8
  TOP w0.118: U95.15 56.41,40.61 60.83,45.03 v2(60.83,48.16) ; U22.J11 v3(112.33,149.2)
  L7_INT_3 w0.087: v3(112.33,149.2) 112.73,148.8 112.73,146 113.35,145.38 113.35,139.34 115.59,137.09 115.59,130.16 117.86,127.89 117.86,117.81 141.1,94.56 141.1,76.11 128.35,63.36 79.64,63.36 71.04,54.76 66.85,54.76 60.93,48.84 60.93,48.26 v2(60.83,48.16)
DUT_UART2_TXD: length 189
  TOP w0.118: U95.14 56.91,40.35 61.52,44.96 v2(61.52,47.57) ; v3(113.33,149.2) U22.J10
  L7_INT_3 w0.087: v3(113.33,149.2) 113.73,148.8 113.73,139.74 117.4,136.07 117.4,130.51 118.87,129.03 118.87,118.06 141.65,95.28 141.65,76.01 128.47,62.83 80.44,62.83 71.4,53.8 67.74,53.8 v2(61.52,47.57)
EC1_GTX_CLK125: length 59.3
  TOP w0.091: U22.D12 v3(111.33,144.2) ; v2(125.45,94.06) 125.71,93.8 125.71,93.47 R5847.2
  L7_INT_3 w0.086: v2(125.45,94.06) 125.62,94.22 125.62,105.67 115.51,115.78 115.51,123.33 111.36,127.47 111.36,138.49 111.95,139.07 111.95,144.36 111.84,144.46 111.6,144.46 v3(111.33,144.2)
EC1_RX_CLK: length 1.5
  TOP w0.118: U22.B12 v3(110.33,142.2)
  BOTTOM w0.118: R756.1 110.83,141.7 v3(110.33,142.2)
EC1_RX_DV: length 14.1
  TOP w0.118: R320.1 112.52,129.92 112.52,132.42 112.65,132.55 112.66,132.59 112.66,138.82 110.9,140.59 110.24,140.59 109.83,140.99 U22.A13
EC1_RXD0: length 1.4
  TOP w0.102: U22.C12 v3(111.33,143.2)
  BOTTOM w0.118: v3(111.33,143.2) 111.16,143.36 R751.1
EC1_RXD1: length 1.4
  TOP w0.118: U22.E12 v3(111.33,146.2)
  BOTTOM w0.118: v3(111.33,146.2) 111.83,146.7 R746.1
EC1_RXD2: length 10.4
  TOP w0.118: U22.A12 110.83,141.11 112.97,138.98 112.97,132.78 113.03,132.72 R306.1
EC1_RXD3: length 1.4
  TOP w0.118: U22.G12 v3(111.33,148.2)
  BOTTOM w0.118: R739.1 v3(111.33,148.2)
EC1_TX_CTL_S: length 1.4
  TOP w0.118: U22.C13 v3(110.33,143.2)
  BOTTOM w0.118: v3(110.33,143.2) 110.82,142.71 R753.1
EC2_GTX_CLK125: length 61
  TOP w0.091: v2(126.16,94.06) 125.99,93.89 125.99,93.47 R5848.2 ; U22.E10 112.33,145.2 v3(111.33,145.2)
  L7_INT_3 w0.086: v2(126.16,94.06) 125.96,94.25 125.96,105.82 115.85,115.93 115.85,123.47 111.71,127.61 111.71,138.34 112.29,138.93 112.29,144.5 111.98,144.81 111.54,144.81 111.33,145.02 v3(111.33,145.2)
EC2_RX_CLK: length 14.7
  TOP w0.102: 113.16,141.1 113.16,141.45 113.22,141.52 113.22,142.3 U22.B10
  TOP w0.118: 113.16,141.1 115.14,139.12 115.14,135.18 115.57,134.75 115.57,129.92 R323.1
EC2_RX_DV: length 12.8
  TOP w0.102: U22.C10 113.44,143.09 113.44,141.38
  TOP w0.118: 113.44,141.38 115.44,139.37 115.44,135.31 116.08,134.67 R309.1
EC2_RXD0: length 10.4
  TOP w0.118: R308.2 115.06,134.81 114.83,135.04 114.83,139.06 112.83,141.07 U22.A10
EC2_RXD1: length 13.2
  TOP w0.118: U22.A11 111.83,140.7 113.27,139.26 113.27,133.11 113.54,132.84 113.54,129.92 R321.2
EC2_RXD2: length 12.6
  TOP w0.102: 112.23,140.75 112.23,143.29 U22.C11
  TOP w0.118: R307.2 114.05,132.97 114.22,133.15 114.22,138.76 112.23,140.75
EC2_RXD3: length 16.6
  TOP w0.102: 112.59,140.86 112.44,141 112.44,143.38 112.39,143.42 112.39,144.26 U22.D10
  TOP w0.118: 112.59,140.86 114.55,138.89 114.55,129.92 R322.2
EC2_TX_CTL_S: length 1.4
  TOP w0.118: U22.G10 v3(112.33,147.2)
  BOTTOM w0.118: R742.1 v3(112.33,147.2)
EMI2_MDC: length 6.3
  TOP w0.118: v3(110.33,144.2) U22.D13
  BOTTOM w0.118: TP284.1 112.57,142.04 112.57,144.25 112.09,144.73 110.86,144.73 v3(110.33,144.2)
EMI2_MDIO: length 9.2
  TOP w0.118: U22.E13 110.33,145.2 v3(110.33,145.19)
  BOTTOM w0.118: R5875.1 TP285.1 112.65,141.11 112.88,141.34 112.88,144.91 112.09,145.69 110.83,145.69 v3(110.33,145.19)
EVT0_B: length 20.5
  TOP w0.118: R5853.2 v2(70.43,143.89) ; v3(80.33,153.2) U22.N42
  L3_INT_1 w0.087: v3(80.33,153.2) 79.84,153.68 73.72,153.68 70.05,150.01 70.05,144.32 70.43,143.94 v2(70.43,143.89)
  BOTTOM w0.118: TP86.1 79.96,153.57 v3(80.33,153.2)
EVT1_B: length 13.1
  TOP w0.102: 78.49,152.4 78.59,152.3 79.12,152.3 79.52,152.69 U22.M43
  TOP w0.118: TP6.1 69.02,148.84 69.09,148.78 70.03,148.78 R5854.2 71.11,149.86 72.02,149.86 72.53,150.37 75.31,150.37 75.44,150.5 76.2,150.5 78.11,152.4 78.49,152.4
EVT2_B: length 14.5
  TOP w0.102: U22.M42 80.43,152.3 79.48,152.3 79.27,152.1 78.41,152.1
  TOP w0.118: TP7.1 69.02,147.57 69.08,147.62 70.01,147.62 R5855.2 71.85,149.46 72.14,149.46 72.77,150.09 75.36,150.09 75.53,150.27 76.33,150.27 78.16,152.1 78.41,152.1
EVT3_B: length 14
  TOP w0.102: 78.41,150.86 78.64,151.09 79.22,151.09 U22.L43
  TOP w0.118: TP9.1 69.96,145.29 R5856.2 70.79,145.92 74.17,149.3 75.54,149.3 75.82,149.58 76.81,149.58 78.09,150.86 78.41,150.86
EVT4_B: length 15
  TOP w0.102: 78.53,151.3 79.06,151.3 79.3,151.54 79.3,151.76 79.63,152.1 80.43,152.1 80.83,151.7 U22.L42
  TOP w0.118: 78.53,151.3 78.36,151.13 77.98,151.13 76.66,149.81 75.72,149.81 75.47,149.56 73.84,149.56 71.35,147.07 R5857.2 70.01,146.48 68.5,146.48 TP8.1
FA_ANALOG_G_V: length 1.4
  TOP w0.118: v3(90.33,155.2) U22.R32
  BOTTOM w0.118: R718.1 v3(90.33,155.2)
FA_ANALOG_PIN: length 1.4
  TOP w0.457: U22.T32 v3(90.33,156.2)
  BOTTOM w0.254: R715.1 v3(90.33,156.2)
FAN1_PWM: length 241.4
  TOP w0.254: R5680.2 v2(192.51,43.92)
  TOP w0.381: U105.5 v2(248.75,218.99)
  TOP w0.508: 195.24,45.03 FAN1.4 ; FAN1.4 195.24,43.43 ; FAN1.4 196.84,45.03 ; FAN1.4 196.84,43.43
  L14_INT_6 w0.254: v2(248.75,218.99) 249.27,219.51 250.14,219.51 257.23,212.42 257.23,68.81 243.71,55.3 199.42,55.3 198.41,54.28 194.43,54.28 193.29,53.13 193.29,44.59 192.61,43.92 v2(192.51,43.92)
FAN2_PWM: length 139.7
  TOP w0.381: R5681.2 v2(135.89,245.81) ; U105.7 v2(248.71,220.29)
  TOP w0.508: FAN2.4 136.94,250.12 ; FAN2.4 136.94,248.53 ; FAN2.4 135.35,250.12 ; FAN2.4 135.35,248.53
  L3_INT_1 w0.254: v2(135.89,245.81) 136.51,245.19 138.63,245.19 139.49,246.04 146.88,246.04 148.97,248.13 164.13,248.13 164.29,247.98 164.58,247.98 172.66,239.9 178.95,239.9 179.03,239.98 179.31,239.98 179.36,240.03 179.45,240.03 186.33,246.91 216.92,246.91 216.95,246.89 216.96,246.89 240.64,223.21 240.64,221.16 241.45,220.34 244.17,220.34 245.06,221.23 247.77,221.23 v2(248.71,220.29)
FAN3_PWM: length 244.1
  TOP w0.381: v2(247.56,222.46) 247.32,222.46 246.94,222.08 U105.9 ; R5682.2 v2(33.78,245.81)
  TOP w0.508: FAN3.4 34.91,248.53 ; FAN3.4 33.32,250.12 ; FAN3.4 33.32,248.53 ; FAN3.4 34.91,250.12
  L3_INT_1 w0.254: v2(33.78,245.81) 35.93,247.95 65.58,247.95 66.88,249.25 102.44,249.25 103.1,249.91 113.49,249.91 114.6,251.03 165.13,251.03 173.71,242.44 177.65,242.44 185,249.79 217.65,249.79 237.19,230.25 244.75,230.25 248.91,226.1 248.91,223.81 v2(247.56,222.46)
FAN4_PWM: length 218.7
  TOP w0.381: v2(242.98,221.41) 243.45,220.94 U105.13 ; R5683.2 v2(55.75,245.81)
  TOP w0.508: 55.23,248.53 FAN4.4 ; FAN4.4 56.82,248.53 ; FAN4.4 56.82,250.12 ; FAN4.4 55.23,250.12
  L3_INT_1 w0.254: v2(55.75,245.81) 56.43,246.48 66.88,246.48 69.55,243.81 91.72,243.81 94.54,246.63 106.53,246.63 107.62,245.54 121.77,245.54 125.91,249.68 130.76,249.68 132.54,247.9 145.31,247.9 147.29,249.89 164.83,249.89 173.29,241.43 178.32,241.43 178.44,241.55 178.51,241.55 185.52,248.56 217.44,248.56 242.42,223.59 242.42,221.97 v2(242.98,221.41)
FAN5_PWM: length 284.7
  TOP w0.381: R5684.2 v2(2.03,245.81) ; U105.15 v2(243.17,219.64)
  TOP w0.508: 1.42,248.53 FAN5.4 ; FAN5.4 3.02,248.53 ; FAN5.4 3.02,250.12 ; FAN5.4 1.42,250.12
  L3_INT_1 w0.254: v2(243.17,219.64) 242.93,219.41 236.07,219.41 234.47,221.01 234.47,228.66 216.75,246.38 186.51,246.38 179.61,239.48 179.24,239.48 179.16,239.4 172.45,239.4 164.37,247.47 149.5,247.47 147.45,245.41 140.52,245.41 139.14,244.04 139.14,242.01 137.64,240.51 134.34,240.51 129.37,245.48 125.98,245.48 121.44,240.94 103.91,240.94 99.52,245.34 95.55,245.34 91.14,240.92 79.81,240.92 77.7,238.81 67.18,238.81 64.36,241.63 6.22,241.63 2.4,245.45 2.39,245.45 v2(2.03,245.81)
FAN_ADDR: length 1.5
  TOP w0.381: U105.4 246.94,216.83 R5690.2
FAN_DEF: length 1.6
  TOP w0.254: R5790.2 245.71,222.82 245.64,222.75 U105.11
FPGA_EXTAL: length 4
  TOP w0.118: U27.R16 53.03,80 C3691.1 52.21,80.07 Y19.1
FPGA_JTSEL: length 5.5
  TOP w0.118: R5583.2 53.76,78 57.06,78 U27.N13
FPGA_PLL: length 0.7
  BOTTOM w0.118: C3698.1 59.66,72 v1(59.87,72)
  vias: v2(54.31,70.46) v2(54.31,68.99)
FPGA_PRB: length 23.1
  L12_INT_5 w0.087: JP7.3 47.02,81.92 48.92,80.01 56.49,80.01 57.51,78.99 57.51,78.36 58.69,77.17 58.69,71.57 57.9,70.78 57.04,70.78 v1(56.67,70.4)
FPGA_TCK: length 60.5
  TOP w0.118: J105.1 v2(1.3,76.51)
  BOTTOM w0.118: v2(1.3,76.51) R5585.1 6.02,76.51 7.7,78.18 46.38,78.18 48.29,80.09 56.29,80.09 56.67,79.7 v1(56.67,79.2)
FPGA_TDI: length 61.6
  TOP w0.118: J105.9 v2(1.34,66.35)
  BOTTOM w0.118: v2(1.34,66.35) 3.33,66.35 11.99,75.01 46.46,75.01 49.43,77.98 54.64,77.98 v1(55.07,78.4)
FPGA_TDO: length 61.5
  TOP w0.118: J105.3 v2(1.34,73.97)
  BOTTOM w0.118: v2(1.34,73.97) 5.16,73.97 8.43,77.24 46.71,77.24 49.17,79.71 55.92,79.71 56.26,79.37 56.26,78.81 v1(56.67,78.4)
FPGA_TMS: length 59.9
  TOP w0.118: J105.5 v2(1.34,71.43)
  BOTTOM w0.118: v2(1.34,71.43) 4.7,71.43 9.25,75.97 46.56,75.97 49,78.41 54.27,78.41 v1(55.07,79.2)
FPGA_TRST_B: length 50
  TOP w0.118: J105.8 v2(14.05,68.89)
  BOTTOM w0.118: R5584.1 v2(14.05,68.89) 14.66,68.89 18.47,72.69 45.01,72.69 49.81,77.5 53.06,77.5 53.36,77.2 55.22,77.2 55.46,77.44 55.46,78 v1(55.87,78.4)
FPGA_XTAL: length 6.2
  TOP w0.118: Y19.3 50.33,81.42 50.98,80.77 C3690.1 53.03,80.4 55.47,80.4 U27.R15
FPGAUPD_SCK: length 38.5
  TOP w0.118: U250.6 44.93,56.87 43.54,58.27 43.54,65.1 43.1,65.53 41.3,65.53 J69.2
  L5_INT_2 w0.087: J69.2 41.12,62.71 42.93,62.71 43.61,63.4 43.61,67.84 48.29,72.52 54.38,72.52 54.48,72.42 55.48,72.42 v1(55.87,72.8)
FPGAUPD_SCS_B: length 34.1
  TOP w0.118: J69.1 35.74,64.03 34.92,63.22 34.92,60.12 35.64,59.41 U250.1
  L5_INT_2 w0.087: J69.1 39.12,62.18 45.36,62.18 46.1,62.92 46.1,65.2 51.79,70.89 54.76,70.89 v1(55.07,71.2)
FPGAUPD_SDI: length 28.8
  TOP w0.118: J69.3 42.34,59.31 41.17,58.14 U250.2
  L5_INT_2 w0.087: v1(56.67,72.8) 56.27,73.2 55.42,73.2 55.16,73.46 53.47,73.46 53.14,73.13 47.98,73.13 42.34,67.49 J69.3
FPGAUPD_SDO: length 29.8
  TOP w0.118: U250.5 48.79,55.6 50.22,57.02 50.22,60.43 48.59,62.05 45.36,62.05 44.88,62.53 J69.4
  L5_INT_2 w0.087: v1(55.07,72) 54.24,71.17 50.24,71.17 44.88,65.81 J69.4
FUPD_B: length 11.8
  TOP w0.102: U27.E12 57.85,71.58 54.64,71.58
  TOP w0.118: 54.64,71.58 54.1,71.04 49.56,71.04 R5667.2 48.7,70.63 47.93,71.4 TP197.1
GVDD: length 803.4
  TOP w0.381: C253.1 125.15,140.02 v2(125.15,139.19) ; v2(124.74,183.01) 124.74,183.68 C157.1 U22.BC1 ; v2(41.91,162.43) C211.1 ; U22.AY44 77.19,180.7 76.78,181.1 C161.1 v2(75.94,180.47) ; C221.2 v2(41.91,155.7) ; v2(41.91,166.37) C202.1 ; v3(88.32,184.16) 87.83,184.66 U22.BD35 86.97,185.56 v2(86.97,186.66) 86.97,187.05 C295.1 ; v2(166.75,169.42) C190.1 ; U22.BB43 v3(80.33,182.19) ; U22.AV43 v3(80.33,178.19) ; U22.AT44 v3(79.33,177.19) ; U22.BD43 v3(80.31,184.17)
  TOP w0.457: U22.AJ2 v3(120.33,170.2) ; U22.BD6 116.46,185.07 116.46,187.08 C129.1 ; U22.AB30 v3(92.33,162.2) ; v3(78.33,160.2) U22.Y44 v3(79.33,160.2) U22.Y43 ; v2(124.72,167.77) 124.72,167.77 C196.1 123.77,167.13 123.34,166.7 U22.AF1 ; v2(124.72,162.69) C209.1 124.7,162.03 123.9,162.03 123.32,162.61 121.91,162.61 U22.AB1 ; U22.BC16 v3(107.33,184.2) ; U22.T2 v3(120.33,156.2) ; v3(79.33,172.19) U22.AM44 ; v2(124.72,141.48) C251.1 122.41,142.11 U22.B1 ; U22.BD14 v3(109.33,185.2) ; U22.A9 v3(114.33,141.2) ; U22.AA15 v3(108.33,161.2) ; v3(92.33,167.19) U22.AF30 ; U22.AR1 123.44,175.7 ; U22.BC12 v3(110.33,184.2) ; v2(75.95,168.06) 75.95,168.69 C191.1 U22.AH44 ; U22.AF15 v3(108.33,167.2) ; U22.AD2 v3(121.33,165.2) ; U22.AD15 v3(108.33,165.2) ; U22.AB15 v3(108.33,162.2) ; U22.BC8 v3(114.33,184.2) ; U22.H2 v3(120.33,148.2) ; v3(92.33,166.19) U22.AE30 ; v2(71.82,178.18) 72.52,178.18 ; C253.1 124.52,139.71 v2(124.52,139.19) ; U22.BA2 v3(120.33,181.2) ; U22.AH30 92.33,169.19 v3(92.33,169.2) ; U22.AD30 v3(92.33,165.19) ; U22.BC44 v3(78.83,184.33) ; R197.1 111.05,189.66 v2(111.25,189.87) ; U22.W15 v3(108.33,159.2) ; U22.B9 v3(114.33,142.2) ; v3(92.33,168.19) U22.AG30 ; U22.AU2 120.33,178.19 v3(120.33,178.2) ; U22.AK43 79.83,170.69 v3(80.33,170.19) ; U22.AG1 121.83,167.69 122.91,167.69 123.62,168.4 C192.1 v2(124.72,169.04) ; U22.AN2 v3(120.33,173.2) ; U22.AF2 v3(120.33,167.2) ; U22.BD10 v3(113.33,185.2) ; U22.B4 v3(119.33,142.2) ; 122.34,184.7 U22.BD2 ; v3(121.33,155.2) 121.33,155.19 U22.P1 ; U22.BC41 v3(81.33,184.19) ; U22.BD39 83.83,185.55 83.07,186.31 C138.1 83.07,188.21 82.92,188.35 v2(82.92,188.39) ; v3(120.33,153.2) 120.83,152.7 U22.M2 ; v2(124.85,159.26) 124.72,159.13 C218.1 121.9,158.62 U22.V1 ; v3(80.33,174.19) U22.AP43 ; U22.F1 124.46,146.69 C246.1 v2(124.72,145.8) ; U22.V15 v3(108.33,158.2) ; v3(108.33,168.2) U22.AG15 ; U22.T15 v3(108.33,156.2) ; v2(124.72,179.04) C165.1 123.29,179.68 123.19,179.58 121.95,179.58 U22.AW1 ; v3(80.33,162.2) U22.AB43 ; U22.K1 v3(121.33,150.2) ; v3(80.33,167.19) U22.AF43 ; v3(108.33,170.2) U22.AJ15 ; U22.AE15 v3(108.33,166.2) ; U22.Y2 v3(121.33,160.2) ; R271.2 v2(126.43,148.72) ; U22.A6 v3(116.83,141.08) ; U22.A2 121.1,141.42 121.13,141.42 v3(121.36,141.2) ; U22.BC37 v3(85.33,184.19) ; U22.AD44 v3(78.33,165.19) ; U22.BC4 v3(119.33,184.2) ; U22.AC15 v3(108.33,163.2) ; U22.AL1 123.32,171.7 ; U22.U15 v3(108.33,157.2) ; U22.D2 v3(121.33,144.2) ; U22.AH15 v3(108.33,169.2) ; R202.1 v2(81.79,187.07) ; U22.AC30 v3(92.33,163.2) ; U22.Y15 v3(108.33,160.2)
  TOP w0.508: v2(105.54,188.6) 105.54,188.59 105.91,188.22 C128.1 106.17,185.04 U22.BD17 ; v2(156.34,188.21) C137.1 ; C162.2 v2(166.75,180.72) ; C163.1 v2(147.7,180.59) ; v2(147.7,170.31) C187.2 ; C159.2 157.61,181.11 v2(157.61,181.11) ; v2(156.34,177.79) C167.2 ; 146.62,183.5 C151.1 ; 146.62,183.5 146.81,183.31 v2(146.81,182.75) ; 146.62,183.5 146.62,183.46 146.18,183.02 v2(146.18,182.75) ; v2(147.7,175.45) 146.69,175.45 C169.2 147.19,176.09 v2(147.7,176.09) ; 164.07,157.58 J7.197 ; J7.197 164.07,156.42 ; J7.197 165.23,156.42 ; J7.197 165.23,157.58 ; v2(120.26,138.16) 119.9,137.79 R291.1 ; C220.1 v2(166.75,156.97) ; v2(156.34,192.67) 156.34,192.67 C106.2 ; C186.1 156.34,170.93 v2(156.34,170.93) ; v2(147.7,169.42) C189.2 ; C179.2 v2(166.75,173.23) ; v2(147.66,194.96) 147.66,194.66 C104.2 ; v2(125.48,164.97) 125.27,164.77 125.27,163.96 C205.1 124.66,164.31 v2(124.66,164.95) ; C208.1 157.23,162.05 v2(157.86,162.05) ; C172.1 v2(41.91,173.74) ; v2(41.91,172.47) C185.1 ; v2(157.67,195.64) 157.48,195.83 C102.1 ; C153.2 v2(166.75,179.07) ; v2(166.37,175.77) 166.94,175.77 C170.1 166.94,174.75 v2(166.37,174.75) ; C130.2 v2(147.83,188.21) ; v2(157.61,156.2) C240.1 ; 164.07,163.58 J7.191 ; J7.191 165.23,162.42 ; J7.191 164.07,162.42 ; J7.191 165.23,163.58 ; v2(166.69,171.96) R233.2 ; C166.2 v2(166.75,177.55) ; C158.2 v2(41.94,177.77) ; v2(157.61,173.49) C176.1 ; C141.1 v2(147.83,187.32) ; C164.1 v2(147.7,179.71)
  L8_PWR_1 w0.508: J5.179 51.13,175.58 ; J5.179 49.97,174.42 ; J5.179 51.13,174.42 ; J5.179 49.97,175.58 ; 44.27,167.42 J5.66 ; J5.66 44.27,168.58 ; J5.66 45.43,168.58 ; J5.66 45.43,167.42 ; J5.176 49.23,177.42 ; J5.176 48.07,177.42 ; J5.176 48.07,178.58 ; J5.176 49.23,178.58 ; J5.57 47.33,176.42 ; J5.57 46.17,176.42 ; J5.57 46.17,177.58 ; J5.57 47.33,177.58 ; 160.27,159.58 J7.75 ; J7.75 161.43,159.58 ; J7.75 161.43,158.42 ; J7.75 160.27,158.42 ; J5.191 51.13,163.58 ; J5.191 49.97,163.58 ; J5.191 49.97,162.42 ; J5.191 51.13,162.42 ; J5.170 49.23,184.58 ; J5.170 48.07,184.58 ; J5.170 49.23,183.42 ; J5.170 48.07,183.42 ; 160.27,165.58 J7.69 ; J7.69 160.27,164.42 ; J7.69 161.43,165.58 ; J7.69 161.43,164.42 ; 49.97,165.58 J5.189 ; J5.189 51.13,164.42 ; J5.189 49.97,164.42 ; J5.189 51.13,165.58 ; 48.07,168.58 J5.186 ; J5.186 48.07,167.42 ; J5.186 49.23,167.42 ; J5.186 49.23,168.58 ; J7.176 163.33,178.58 ; J7.176 162.17,177.42 ; J7.176 163.33,177.42 ; J7.176 162.17,178.58 ; 46.17,158.42 J5.75 ; J5.75 46.17,159.58 ; J5.75 47.33,158.42 ; J5.75 47.33,159.58 ; J5.78 45.43,155.42 ; J5.78 44.27,155.42 ; J5.78 44.27,156.58 ; J5.78 45.43,156.58 ; J7.51 161.43,182.42 ; J7.51 161.43,183.58 ; J7.51 160.27,183.58 ; J7.51 160.27,182.42 ; 44.27,180.58 J5.54 ; J5.54 44.27,179.42 ; J5.54 45.43,180.58 ; J5.54 45.43,179.42 ; J7.182 163.33,172.58 ; J7.182 162.17,172.58 ; J7.182 162.17,171.42 ; J7.182 163.33,171.42 ; J7.194 163.33,160.58 ; J7.194 163.33,159.42 ; J7.194 162.17,160.58 ; J7.194 162.17,159.42 ; J7.60 159.53,173.42 ; J7.60 159.53,174.58 ; J7.60 158.37,173.42 ; J7.60 158.37,174.58 ; 48.07,172.58 J5.182 ; J5.182 49.23,171.42 ; J5.182 48.07,171.42 ; J5.182 49.23,172.58 ; 160.27,169.58 J7.65 ; J7.65 160.27,168.42 ; J7.65 161.43,169.58 ; J7.65 161.43,168.42 ; 44.27,171.42 J5.62 ; J5.62 45.43,172.58 ; J5.62 45.43,171.42 ; J5.62 44.27,172.58 ; J7.57 161.43,176.42 ; J7.57 160.27,177.58 ; J7.57 160.27,176.42 ; J7.57 161.43,177.58 ; J7.54 159.53,180.58 ; J7.54 159.53,179.42 ; J7.54 158.37,180.58 ; J7.54 158.37,179.42 ; J5.60 45.43,174.58 ; J5.60 44.27,174.58 ; J5.60 45.43,173.42 ; J5.60 44.27,173.42 ; 158.37,161.42 J7.72 ; J7.72 159.53,162.58 ; J7.72 158.37,162.58 ; J7.72 159.53,161.42 ; J5.197 51.13,156.42 ; J5.197 51.13,157.58 ; J5.197 49.97,156.42 ; J5.197 49.97,157.58 ; 158.37,168.58 J7.66 ; J7.66 159.53,168.58 ; J7.66 158.37,167.42 ; J7.66 159.53,167.42 ; J7.183 165.23,171.58 ; J7.183 165.23,170.42 ; J7.183 164.07,171.58 ; J7.183 164.07,170.42 ; J7.62 159.53,171.42 ; J7.62 159.53,172.58 ; J7.62 158.37,172.58 ; J7.62 158.37,171.42 ; 164.07,174.42 J7.179 ; J7.179 165.23,175.58 ; J7.179 165.23,174.42 ; J7.179 164.07,175.58 ; J7.197 165.23,157.58 ; J7.197 164.07,157.58 ; J7.197 164.07,156.42 ; J7.197 165.23,156.42 ; 48.07,160.58 J5.194 ; J5.194 48.07,159.42 ; J5.194 49.23,160.58 ; J5.194 49.23,159.42 ; 162.17,184.58 J7.170 ; J7.170 163.33,184.58 ; J7.170 163.33,183.42 ; J7.170 162.17,183.42 ; J7.186 163.33,168.58 ; J7.186 163.33,167.42 ; J7.186 162.17,167.42 ; J7.186 162.17,168.58 ; 158.37,155.42 J7.78 ; J7.78 159.53,156.58 ; J7.78 158.37,156.58 ; J7.78 159.53,155.42 ; 164.07,163.58 J7.191 ; J7.191 165.23,162.42 ; J7.191 164.07,162.42 ; J7.191 165.23,163.58 ; 164.07,164.42 J7.189 ; J7.189 165.23,165.58 ; J7.189 165.23,164.42 ; J7.189 164.07,165.58 ; 46.17,165.58 J5.69 ; J5.69 46.17,164.42 ; J5.69 47.33,165.58 ; J5.69 47.33,164.42 ; J7.173 165.23,181.58 ; J7.173 165.23,180.42 ; J7.173 164.07,181.58 ; J7.173 164.07,180.42 ; J5.51 47.33,182.42 ; J5.51 47.33,183.58 ; J5.51 46.17,182.42 ; J5.51 46.17,183.58 ; J5.65 47.33,168.42 ; J5.65 46.17,169.58 ; J5.65 47.33,169.58 ; J5.65 46.17,168.42 ; J5.183 51.13,171.58 ; J5.183 49.97,170.42 ; J5.183 51.13,170.42 ; J5.183 49.97,171.58 ; J5.173 51.13,181.58 ; J5.173 49.97,181.58 ; J5.173 51.13,180.42 ; J5.173 49.97,180.42 ; J5.72 45.43,161.42 ; J5.72 44.27,161.42 ; J5.72 44.27,162.58 ; J5.72 45.43,162.58
  L9_PWR_2 w0.508: J7.69 161.43,164.42 ; J7.69 160.27,164.42 ; J7.69 161.43,165.58 ; J7.69 160.27,165.58 ; 46.17,177.58 J5.57 ; J5.57 47.33,177.58 ; J5.57 47.33,176.42 ; J5.57 46.17,176.42 ; J7.75 161.43,158.42 ; J7.75 160.27,158.42 ; J7.75 160.27,159.58 ; J7.75 161.43,159.58 ; 150.77,173.58 J6.176 ; J6.176 150.77,172.42 ; J6.176 151.93,173.58 ; J6.176 151.93,172.42 ; J5.78 45.43,156.58 ; J5.78 45.43,155.42 ; J5.78 44.27,156.58 ; J5.78 44.27,155.42 ; 46.17,165.58 J5.69 ; J5.69 46.17,164.42 ; J5.69 47.33,165.58 ; J5.69 47.33,164.42 ; 148.87,185.42 J6.189 ; J6.189 150.03,186.58 ; J6.189 148.87,186.58 ; J6.189 150.03,185.42 ; 48.07,168.58 J5.186 ; J5.186 48.07,167.42 ; J5.186 49.23,167.42 ; J5.186 49.23,168.58 ; J7.176 163.33,178.58 ; J7.176 163.33,177.42 ; J7.176 162.17,178.58 ; J7.176 162.17,177.42 ; 154.57,188.42 J6.72 ; J6.72 154.57,189.58 ; J6.72 155.73,189.58 ; J6.72 155.73,188.42 ; 158.37,168.58 J7.66 ; J7.66 159.53,167.42 ; J7.66 158.37,167.42 ; J7.66 159.53,168.58 ; J6.65 153.83,182.58 ; J6.65 152.67,182.58 ; J6.65 152.67,181.42 ; J6.65 153.83,181.42 ; 48.07,160.58 J5.194 ; J5.194 49.23,160.58 ; J5.194 48.07,159.42 ; J5.194 49.23,159.42 ; 158.37,180.58 J7.54 ; J7.54 159.53,180.58 ; J7.54 158.37,179.42 ; J7.54 159.53,179.42 ; J6.62 155.73,179.58 ; J6.62 154.57,179.58 ; J6.62 154.57,178.42 ; J6.62 155.73,178.42 ; 154.57,194.42 J6.78 ; J6.78 155.73,194.42 ; J6.78 155.73,195.58 ; J6.78 154.57,195.58 ; J5.60 45.43,173.42 ; J5.60 44.27,174.58 ; J5.60 45.43,174.58 ; J5.60 44.27,173.42 ; J5.179 51.13,175.58 ; J5.179 49.97,174.42 ; J5.179 49.97,175.58 ; J5.179 51.13,174.42 ; J5.66 45.43,168.58 ; J5.66 44.27,167.42 ; J5.66 44.27,168.58 ; J5.66 45.43,167.42 ; 150.77,190.42 J6.194 ; J6.194 150.77,191.58 ; J6.194 151.93,191.58 ; J6.194 151.93,190.42 ; 148.87,187.42 J6.191 ; J6.191 148.87,188.58 ; J6.191 150.03,188.58 ; J6.191 150.03,187.42 ; J6.66 155.73,182.42 ; J6.66 154.57,183.58 ; J6.66 154.57,182.42 ; 152.67,168.58 J6.51 ; J6.51 152.67,167.42 ; J6.51 153.83,167.42 ; J6.51 153.83,168.58 ; J5.183 51.13,171.58 ; J5.183 49.97,170.42 ; J5.183 51.13,170.42 ; J5.183 49.97,171.58 ; 44.27,180.58 J5.54 ; J5.54 45.43,179.42 ; J5.54 44.27,179.42 ; J5.54 45.43,180.58 ; 150.77,179.58 J6.182 ; J6.182 151.93,179.58 ; J6.182 150.77,178.42 ; J6.182 151.93,178.42 ; 160.27,183.58 J7.51 ; J7.51 161.43,182.42 ; J7.51 160.27,182.42 ; J7.51 161.43,183.58 ; J7.191 165.23,162.42 ; J7.191 165.23,163.58 ; J7.191 164.07,162.42 ; J7.191 164.07,163.58 ; J7.170 163.33,184.58 ; J7.170 163.33,183.42 ; J7.170 162.17,183.42 ; J7.170 162.17,184.58 ; J5.72 45.43,162.58 ; J5.72 44.27,161.42 ; J5.72 45.43,161.42 ; J5.72 44.27,162.58 ; 148.87,193.42 J6.197 ; J6.197 150.03,193.42 ; J6.197 150.03,194.58 ; J6.197 148.87,194.58 ; J5.189 51.13,164.42 ; J5.189 51.13,165.58 ; J5.189 49.97,165.58 ; J5.189 49.97,164.42 ; J7.186 163.33,167.42 ; J7.186 162.17,168.58 ; J7.186 162.17,167.42 ; J7.186 163.33,168.58 ; 48.07,183.42 J5.170 ; J5.170 49.23,183.42 ; J5.170 48.07,184.58 ; J5.170 49.23,184.58 ; 48.07,171.42 J5.182 ; J5.182 49.23,172.58 ; J5.182 48.07,172.58 ; J5.182 49.23,171.42 ; J6.183 150.03,179.42 ; J6.183 148.87,179.42 ; J6.183 148.87,180.58 ; J6.183 150.03,180.58 ; 162.17,171.42 J7.182 ; J7.182 163.33,172.58 ; J7.182 163.33,171.42 ; J7.182 162.17,172.58 ; J5.62 45.43,172.58 ; J5.62 44.27,172.58 ; J5.62 45.43,171.42 ; J5.62 44.27,171.42 ; 49.97,181.58 J5.173 ; J5.173 51.13,181.58 ; J5.173 51.13,180.42 ; J5.173 49.97,180.42 ; 164.07,180.42 J7.173 ; J7.173 164.07,181.58 ; J7.173 165.23,180.42 ; J7.173 165.23,181.58 ; 150.77,182.42 J6.186 ; J6.186 151.93,182.42 ; J6.186 151.93,183.58 ; J6.186 150.77,183.58 ; 152.67,174.58 J6.57 ; J6.57 152.67,173.42 ; J6.57 153.83,173.42 ; J6.57 153.83,174.58 ; J5.197 51.13,157.58 ; J5.197 51.13,156.42 ; J5.197 49.97,156.42 ; J5.197 49.97,157.58 ; 164.07,157.58 J7.197 ; J7.197 165.23,156.42 ; J7.197 165.23,157.58 ; J7.197 164.07,156.42 ; J5.65 47.33,169.58 ; J5.65 46.17,169.58 ; J5.65 46.17,168.42 ; J5.65 47.33,168.42 ; 152.67,192.58 J6.75 ; J6.75 152.67,191.42 ; J6.75 153.83,191.42 ; J6.75 153.83,192.58 ; J7.62 159.53,171.42 ; J7.62 158.37,171.42 ; J7.62 158.37,172.58 ; J7.62 159.53,172.58 ; 154.57,171.58 J6.54 ; J6.54 155.73,171.58 ; J6.54 154.57,170.42 ; J6.54 155.73,170.42 ; 152.67,185.42 J6.69 ; J6.69 153.83,186.58 ; J6.69 152.67,186.58 ; J6.69 153.83,185.42 ; 148.87,175.42 J6.179 ; J6.179 150.03,175.42 ; J6.179 150.03,176.58 ; J6.179 148.87,176.58 ; J7.189 165.23,164.42 ; J7.189 165.23,165.58 ; J7.189 164.07,164.42 ; J7.189 164.07,165.58 ; J6.173 150.03,169.42 ; J6.173 150.03,170.58 ; J6.173 148.87,169.42 ; J6.173 148.87,170.58 ; J5.176 49.23,178.58 ; J5.176 49.23,177.42 ; J5.176 48.07,178.58 ; J5.176 48.07,177.42 ; 160.27,177.58 J7.57 ; J7.57 160.27,176.42 ; J7.57 161.43,176.42 ; J7.57 161.43,177.58 ; J7.60 159.53,173.42 ; J7.60 158.37,174.58 ; J7.60 158.37,173.42 ; J7.60 159.53,174.58 ; J7.179 165.23,175.58 ; J7.179 164.07,175.58 ; J7.179 164.07,174.42 ; J7.179 165.23,174.42 ; J5.191 51.13,162.42 ; J5.191 49.97,163.58 ; J5.191 49.97,162.42 ; J5.191 51.13,163.58 ; J6.60 155.73,177.58 ; J6.60 154.57,176.42 ; J6.60 155.73,176.42 ; J6.60 154.57,177.58 ; J6.170 151.93,166.42 ; J6.170 150.77,166.42 ; J6.170 151.93,167.58 ; J6.170 150.77,167.58 ; J7.183 165.23,170.42 ; J7.183 164.07,171.58 ; J7.183 165.23,171.58 ; J7.183 164.07,170.42 ; 46.17,182.42 J5.51 ; J5.51 47.33,183.58 ; J5.51 47.33,182.42 ; J5.51 46.17,183.58 ; 158.37,155.42 J7.78 ; J7.78 159.53,156.58 ; J7.78 158.37,156.58 ; J7.78 159.53,155.42 ; J7.194 163.33,159.42 ; J7.194 162.17,160.58 ; J7.194 163.33,160.58 ; J7.194 162.17,159.42 ; 158.37,162.58 J7.72 ; J7.72 159.53,161.42 ; J7.72 158.37,161.42 ; J7.72 159.53,162.58 ; J7.65 161.43,169.58 ; J7.65 161.43,168.42 ; J7.65 160.27,168.42 ; J7.65 160.27,169.58 ; 46.17,159.58 J5.75 ; J5.75 47.33,159.58 ; J5.75 47.33,158.42 ; J5.75 46.17,158.42
  L10_INT_4 w0.508: 160.27,168.42 J7.65 ; J7.65 161.43,169.58 ; J7.65 161.43,168.42 ; J7.65 160.27,169.58 ; 148.87,179.42 J6.183 ; J6.183 150.03,180.58 ; J6.183 150.03,179.42 ; J6.183 148.87,180.58 ; J7.191 165.23,163.58 ; J7.191 164.07,163.58 ; J7.191 165.23,162.42 ; J7.191 164.07,162.42 ; J7.173 165.23,180.42 ; J7.173 164.07,181.58 ; J7.173 165.23,181.58 ; J7.173 164.07,180.42 ; 164.07,157.58 J7.197 ; J7.197 164.07,156.42 ; J7.197 165.23,156.42 ; J7.197 165.23,157.58 ; J6.60 155.73,176.42 ; J6.60 154.57,176.42 ; J6.60 154.57,177.58 ; J6.60 155.73,177.58 ; 148.87,186.58 J6.189 ; J6.189 148.87,185.42 ; J6.189 150.03,185.42 ; J6.189 150.03,186.58 ; 158.37,162.58 J7.72 ; J7.72 158.37,161.42 ; J7.72 159.53,161.42 ; J7.72 159.53,162.58 ; J6.191 150.03,188.58 ; J6.191 148.87,187.42 ; J6.191 148.87,188.58 ; J6.191 150.03,187.42 ; J7.183 165.23,171.58 ; J7.183 164.07,170.42 ; J7.183 164.07,171.58 ; J7.183 165.23,170.42 ; J6.69 153.83,185.42 ; J6.69 152.67,186.58 ; J6.69 152.67,185.42 ; J6.69 153.83,186.58 ; J6.182 151.93,179.58 ; J6.182 150.77,178.42 ; J6.182 150.77,179.58 ; J6.182 151.93,178.42 ; J6.57 153.83,173.42 ; J6.57 152.67,174.58 ; J6.57 152.67,173.42 ; J6.57 153.83,174.58 ; J7.194 163.33,159.42 ; J7.194 162.17,159.42 ; J7.194 163.33,160.58 ; J7.194 162.17,160.58 ; J7.170 163.33,184.58 ; J7.170 162.17,183.42 ; J7.170 163.33,183.42 ; J7.170 162.17,184.58 ; 160.27,177.58 J7.57 ; J7.57 161.43,176.42 ; J7.57 161.43,177.58 ; J7.57 160.27,176.42 ; J7.179 165.23,175.58 ; J7.179 164.07,174.42 ; J7.179 165.23,174.42 ; J7.179 164.07,175.58 ; 160.27,159.58 J7.75 ; J7.75 161.43,158.42 ; J7.75 160.27,158.42 ; J7.75 161.43,159.58 ; J6.194 151.93,191.58 ; J6.194 150.77,191.58 ; J6.194 150.77,190.42 ; J6.194 151.93,190.42 ; J7.51 161.43,182.42 ; J7.51 160.27,183.58 ; J7.51 161.43,183.58 ; J7.51 160.27,182.42 ; J6.51 153.83,168.58 ; J6.51 153.83,167.42 ; J6.51 152.67,167.42 ; J6.51 152.67,168.58 ; J7.60 159.53,173.42 ; J7.60 158.37,174.58 ; J7.60 159.53,174.58 ; J7.60 158.37,173.42 ; J6.197 150.03,194.58 ; J6.197 148.87,193.42 ; J6.197 150.03,193.42 ; J6.197 148.87,194.58 ; 158.37,168.58 J7.66 ; J7.66 158.37,167.42 ; J7.66 159.53,168.58 ; J7.66 159.53,167.42 ; 162.17,168.58 J7.186 ; J7.186 163.33,168.58 ; J7.186 162.17,167.42 ; J7.186 163.33,167.42 ; J7.69 161.43,164.42 ; J7.69 160.27,165.58 ; J7.69 161.43,165.58 ; J7.69 160.27,164.42 ; 154.57,189.58 J6.72 ; J6.72 154.57,188.42 ; J6.72 155.73,188.42 ; J6.72 155.73,189.58 ; 152.67,181.42 J6.65 ; J6.65 153.83,181.42 ; J6.65 153.83,182.58 ; J6.65 152.67,182.58 ; 154.57,195.58 J6.78 ; J6.78 155.73,195.58 ; J6.78 155.73,194.42 ; J6.78 154.57,194.42 ; J7.54 159.53,179.42 ; J7.54 158.37,179.42 ; J7.54 158.37,180.58 ; J7.54 159.53,180.58 ; 150.77,183.58 J6.186 ; J6.186 151.93,183.58 ; J6.186 150.77,182.42 ; J6.186 151.93,182.42 ; J7.189 165.23,165.58 ; J7.189 164.07,165.58 ; J7.189 165.23,164.42 ; J7.189 164.07,164.42 ; 162.17,178.58 J7.176 ; J7.176 163.33,178.58 ; J7.176 163.33,177.42 ; J7.176 162.17,177.42 ; 148.87,170.58 J6.173 ; J6.173 150.03,169.42 ; J6.173 150.03,170.58 ; J6.173 148.87,169.42 ; 148.87,175.42 J6.179 ; J6.179 148.87,176.58 ; J6.179 150.03,176.58 ; J6.179 150.03,175.42 ; 154.57,170.42 J6.54 ; J6.54 155.73,170.42 ; J6.54 154.57,171.58 ; J6.54 155.73,171.58 ; 158.37,171.42 J7.62 ; J7.62 158.37,172.58 ; J7.62 159.53,171.42 ; J7.62 159.53,172.58 ; 158.37,155.42 J7.78 ; J7.78 159.53,155.42 ; J7.78 158.37,156.58 ; J7.78 159.53,156.58 ; 150.77,172.42 J6.176 ; J6.176 151.93,173.58 ; J6.176 151.93,172.42 ; J6.176 150.77,173.58 ; 154.57,178.42 J6.62 ; J6.62 155.73,179.58 ; J6.62 155.73,178.42 ; J6.62 154.57,179.58 ; 152.67,192.58 J6.75 ; J6.75 152.67,191.42 ; J6.75 153.83,192.58 ; J6.75 153.83,191.42 ; 154.57,182.42 J6.66 ; J6.66 154.57,183.58 ; J6.66 155.73,182.42 ; 150.77,166.42 J6.170 ; J6.170 150.77,167.58 ; J6.170 151.93,166.42 ; J6.170 151.93,167.58 ; J7.182 163.33,172.58 ; J7.182 163.33,171.42 ; J7.182 162.17,172.58 ; J7.182 162.17,171.42
  BOTTOM w0.381: v3(88.32,184.16) 87.84,183.68 C580.1 ; v3(85.33,184.19) 84.84,183.7 C581.1 ; v3(79.33,172.19) C634.1 ; v3(108.33,167.2) 108.34,167.2 C668.1 ; v3(79.33,177.19) C594.1 ; C590.1 v3(80.33,178.19) ; C693.1 108.33,165.22 v3(108.33,165.2)
  BOTTOM w0.457: v3(108.33,166.2) C680.1 ; C755.1 v3(108.33,159.2) ; C587.1 v3(120.33,181.2) ; C714.1 v3(92.33,163.2) ; C741.1 v3(108.33,161.2) ; C870.1 v3(121.33,144.2) ; C637.1 v3(120.33,170.2) ; v3(109.33,185.2) 109.33,185.17 C576.1 ; v3(80.31,184.17) 80.31,184.17 80.29,184.15 80.26,184.14 C583.1 ; C577.1 v3(119.33,184.2) ; C678.1 v3(80.33,167.19) ; v3(120.33,148.2) C869.1 ; v3(120.33,173.2) C622.1 ; C689.1 v3(92.33,167.19) ; C803.1 v3(108.33,156.2) ; C708.1 v3(92.33,165.19) ; v3(108.33,162.2) C718.1 ; C692.1 v3(121.33,165.2) ; C872.1 v3(121.36,141.2) ; v3(107.33,184.2) C579.1 ; v3(110.33,184.2) 110.42,184.2 C575.1 ; C786.1 v3(108.33,158.2) ; v3(120.33,153.2) C836.1 ; C702.1 v3(92.33,166.19) ; v3(119.33,142.2) C873.1 ; v3(80.33,174.19) C623.1 ; C690.1 v3(120.33,167.2) ; C591.1 v3(120.33,178.2) ; C876.1 v3(114.33,141.2) ; C753.1 v3(79.33,160.2) ; v3(79.33,182.19) C585.1 ; C742.1 v3(80.33,162.2) ; C787.1 v3(108.33,157.2) ; C857.1 v3(121.33,150.2) ; C574.1 v3(113.33,185.2) ; C823.1 v3(121.33,155.2) ; C578.1 v3(114.33,184.2) ; C727.1 v3(92.33,162.2) ; v3(108.33,160.2) C743.1 ; C653.1 v3(80.33,170.19) ; v3(116.83,141.08) 116.82,141.11 C874.1 ; v3(108.33,170.2) C639.1 ; C817.1 v3(120.33,156.2) ; C677.1 v3(92.33,168.19) ; C665.1 v3(92.33,169.2) ; v3(114.33,142.2) C875.1 ; C657.1 v3(108.33,168.2) ; C705.1 v3(78.33,165.19) ; C766.1 121.15,160.01 v3(121.33,160.2) ; v3(108.33,169.2) C646.1 ; v3(81.33,184.19) C582.1 ; C719.1 v3(108.33,163.2) ; C765.1 v3(78.33,160.2)
  BOTTOM w0.508: 46.11,158.36 J5.75 ; J5.75 47.38,159.63 ; J5.75 47.38,158.36 ; J5.75 46.11,159.63 ; J5.54 45.48,180.63 ; J5.54 45.48,179.36 ; J5.54 44.21,180.63 ; J5.54 44.21,179.36 ; J5.179 51.18,174.36 ; J5.179 51.18,175.63 ; J5.179 49.91,174.36 ; J5.179 49.91,175.63 ; 45.48,168.63 J5.66 44.21,168.63 ; 46.11,183.63 J5.51 ; J5.51 46.11,182.36 ; J5.51 47.38,182.36 ; J5.51 47.38,183.63 ; 46.11,169.63 J5.65 ; J5.65 46.11,168.36 ; J5.65 47.38,169.63 ; J5.65 47.38,168.36 ; J5.60 45.48,173.36 ; J5.60 45.48,174.63 ; J5.60 44.21,174.63 ; J5.60 44.21,173.36 ; 49.91,180.36 J5.173 ; J5.173 49.91,181.63 ; J5.173 51.18,180.36 ; J5.173 51.18,181.63 ; 48.01,183.36 J5.170 ; J5.170 49.28,184.63 ; J5.170 49.28,183.36 ; J5.170 48.01,184.63 ; J5.62 45.48,171.36 ; J5.62 45.48,172.63 ; J5.62 44.21,172.63 ; J5.62 44.21,171.36 ; v4(38.02,212.63) 41.81,216.42 41.81,234.11 40.51,235.41 30.75,235.41 R93.1 ; J5.69 47.38,164.36 ; J5.69 46.11,164.36 ; J5.69 46.11,165.63 ; J5.69 47.38,165.63 ; 48.01,177.36 J5.176 ; J5.176 48.01,178.63 ; J5.176 49.28,177.36 ; J5.176 49.28,178.63 ; J5.191 51.18,163.63 ; J5.191 49.91,163.63 ; J5.191 51.18,162.36 ; J5.191 49.91,162.36 ; 48.01,167.36 J5.186 ; J5.186 49.28,168.63 ; J5.186 48.01,168.63 ; J5.186 49.28,167.36 ; J5.189 51.18,164.36 ; J5.189 49.91,164.36 ; J5.189 49.91,165.63 ; J5.189 51.18,165.63 ; 49.91,157.63 J5.197 ; J5.197 51.18,156.36 ; J5.197 51.18,157.63 ; J5.197 49.91,156.36 ; 45.48,156.63 J5.78 44.21,156.63 ; 46.11,177.63 J5.57 ; J5.57 47.38,176.36 ; J5.57 47.38,177.63 ; J5.57 46.11,176.36 ; J5.194 49.28,159.36 ; J5.194 48.01,159.36 ; J5.194 49.28,160.63 ; J5.194 48.01,160.63 ; J5.182 49.28,171.36 ; J5.182 49.28,172.63 ; J5.182 48.01,172.63 ; J5.182 48.01,171.36 ; J5.183 51.18,170.36 ; J5.183 49.91,171.63 ; J5.183 49.91,170.36 ; J5.183 51.18,171.63 ; v3(78.83,184.33) 78.83,183.65 C584.1 ; 44.21,161.36 J5.72 ; J5.72 44.21,162.63 ; J5.72 45.48,161.36 ; J5.72 45.48,162.63
  vias: v2(29.85,184.53) v2(30.23,186.31) v2(30.23,185.29) v2(30.99,184.65) v2(32.01,184.65) v2(58.42,182.5) v2(58.42,181.86) v2(59.41,155.45) v2(59.41,154.81) v2(60.05,155.45) v2(60.05,154.81) v2(65.66,182.5) v2(65.66,181.86) v2(66.29,182.5) v2(66.29,181.86) v2(114.58,188.44) v2(116.74,189.59) v2(118.49,133.12) v2(118.49,132.49) v2(119.13,133.12) v2(119.13,132.49) v2(121.92,189.87) v2(122.56,189.87) v2(123.44,186.82) v2(124.08,186.82) v2(124.72,176.43) v2(124.77,173.1) v2(125.93,189.87) v2(126.57,189.87) v2(131.95,180.47) v2(131.95,179.83) v2(131.98,151.38) v2(131.98,150.75) v2(132.08,146.69) v2(132.08,146.05) v2(132.59,180.47) v2(132.59,179.83) v2(132.61,151.38) v2(132.61,150.75) v2(132.72,146.69) v2(132.72,146.05) v2(166.37,163.39) v2(166.37,162.7) v2(166.5,154.31) v2(166.5,153.42) v2(166.75,165.61) v2(166.75,160.02) v2(169.67,195.96) v2(169.8,194.82) v2(169.8,193.8) v2(170.43,195.58) v2(170.97,205.49) v2(170.99,204.24) v2(171.45,195.58) v4(11.98,212.76) v4(11.98,210.47) v4(12.11,214.66) v4(14.78,214.66) v4(14.91,212.76) v4(14.91,210.47) v4(17.83,212.76) v4(17.83,210.47) v4(20.37,210.47) v4(23.41,210.47) v4(23.92,212.76) v4(26.08,212.76) v4(26.08,210.47) v4(28.24,211.23) v4(30.53,212.63) v4(30.53,210.34) v4(32.56,212.63) v4(33.32,210.34) v4(35.73,210.34) v4(38.02,210.34)
GVDD_FB: length 4
  TOP w0.254: U631.A5 29.49,231.82 29.33,231.97 R96.2 29.33,232.67 29.31,232.7 v2(29.31,233.39) R100.1
  BOTTOM w0.254: C5132.2 v2(29.31,233.39)
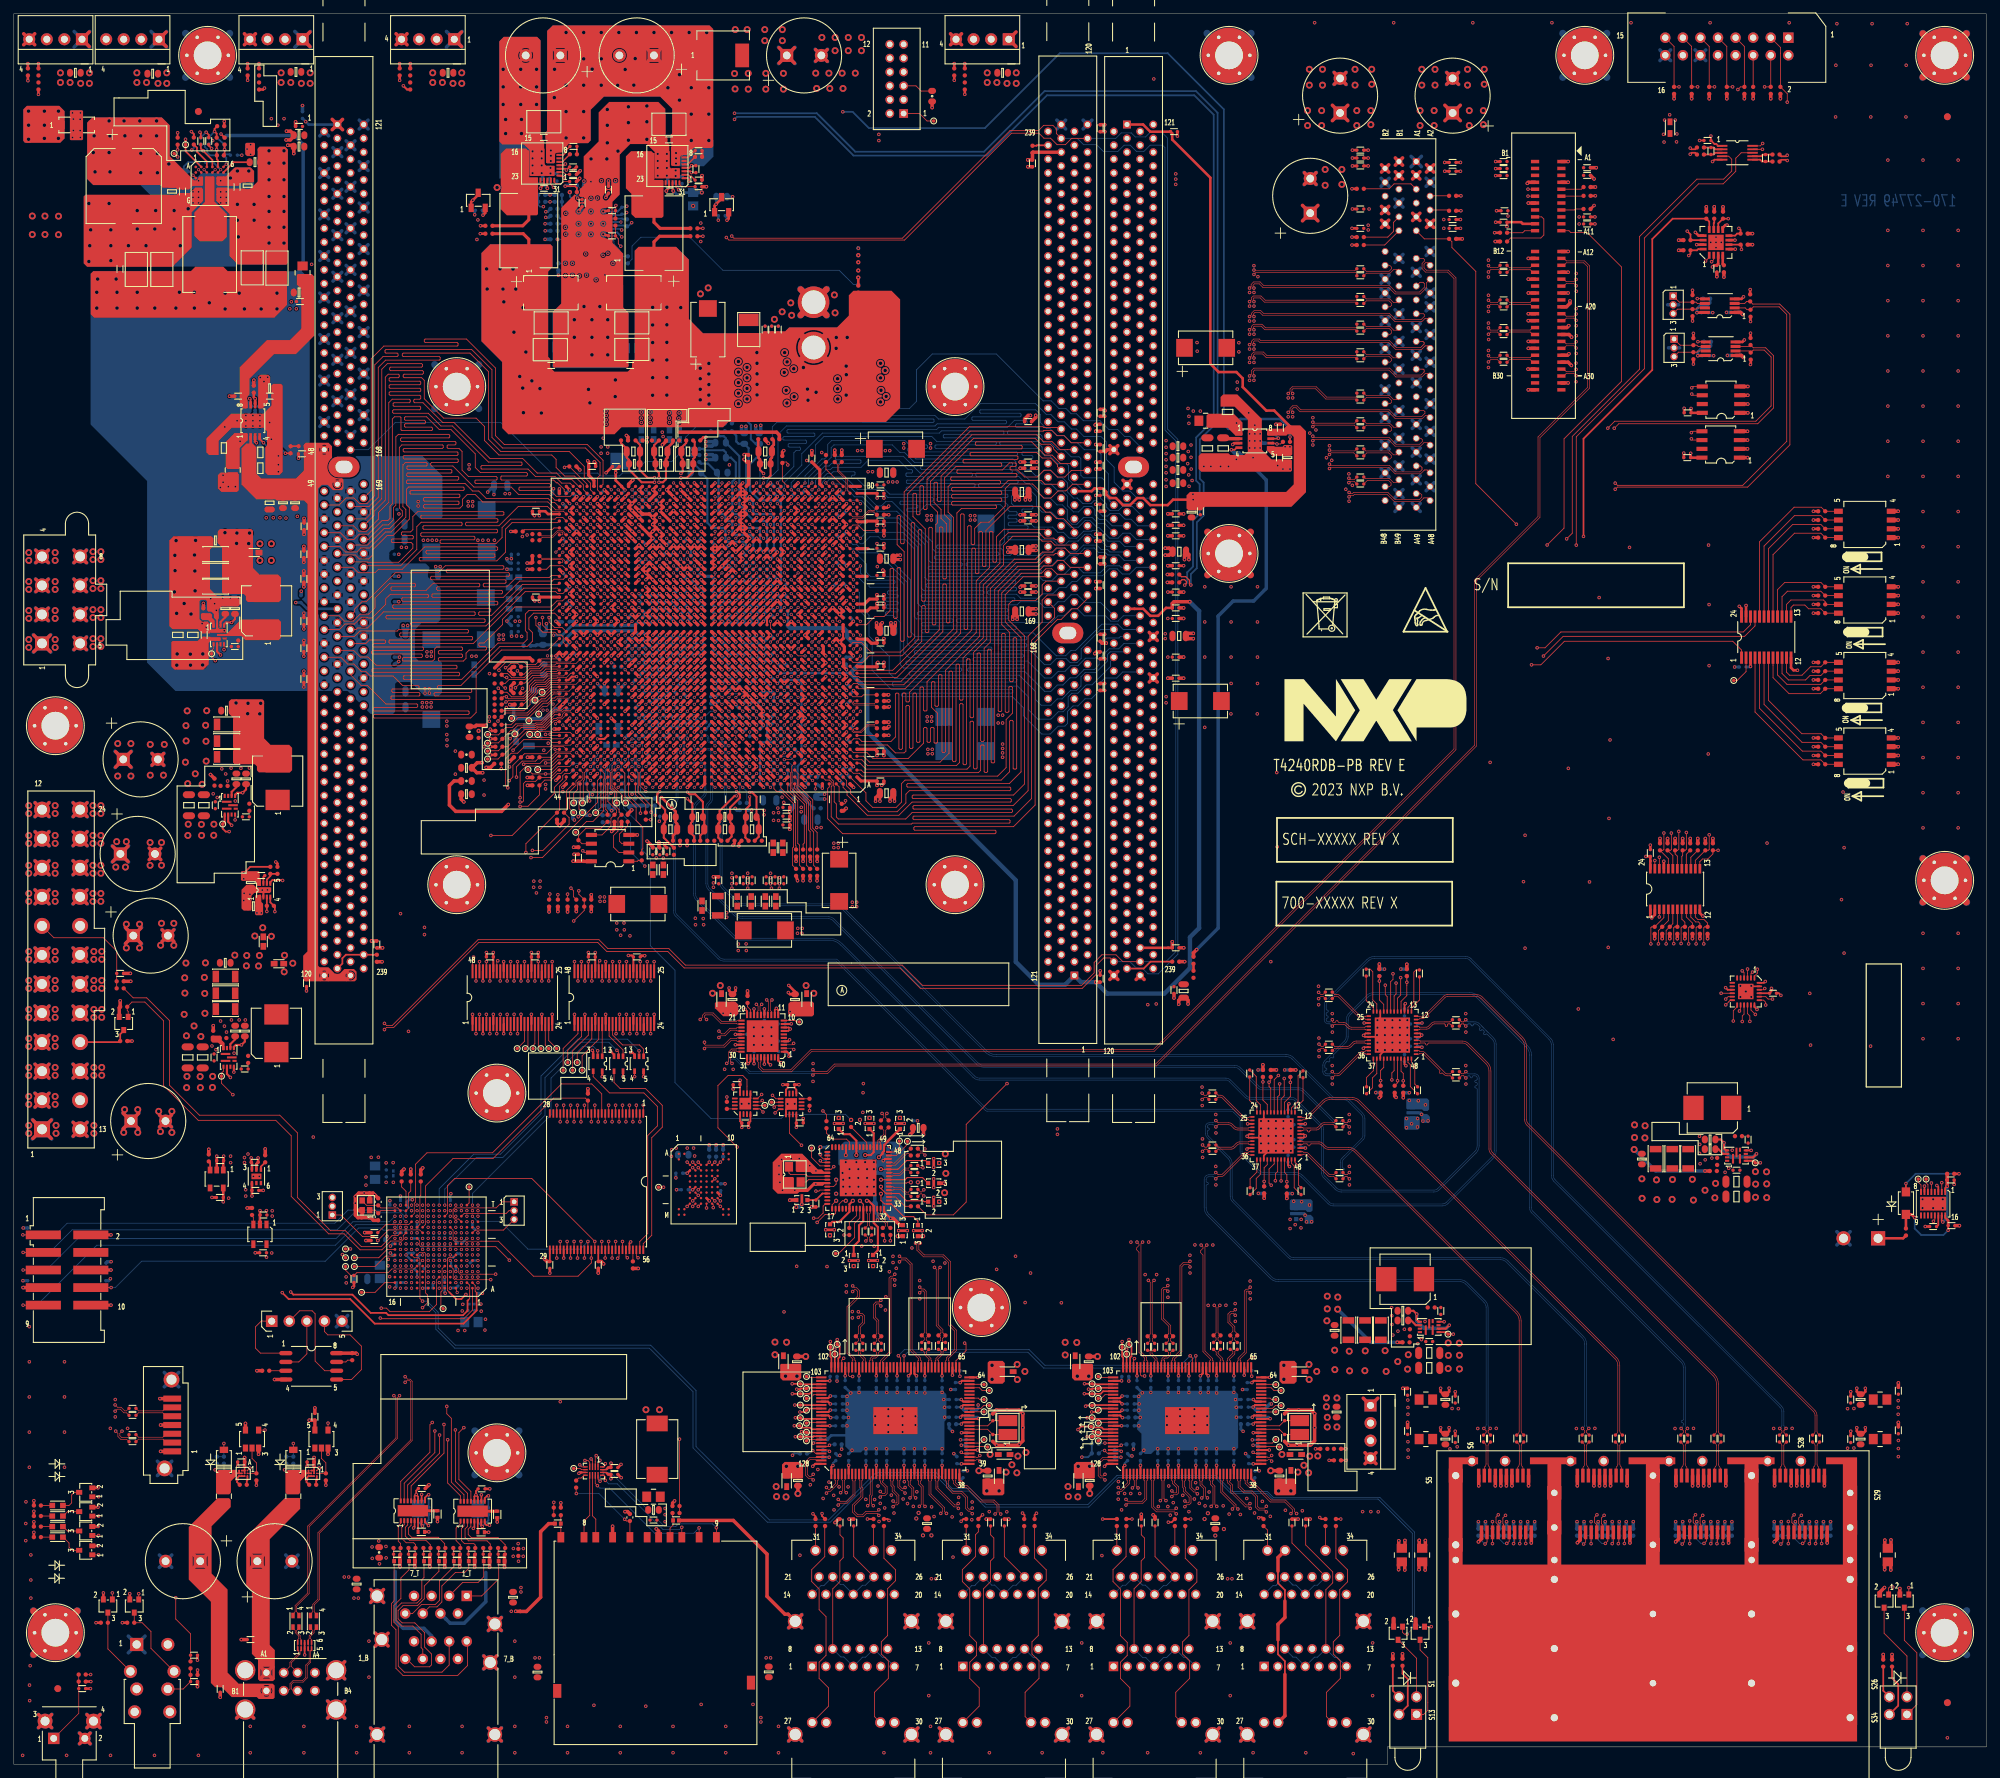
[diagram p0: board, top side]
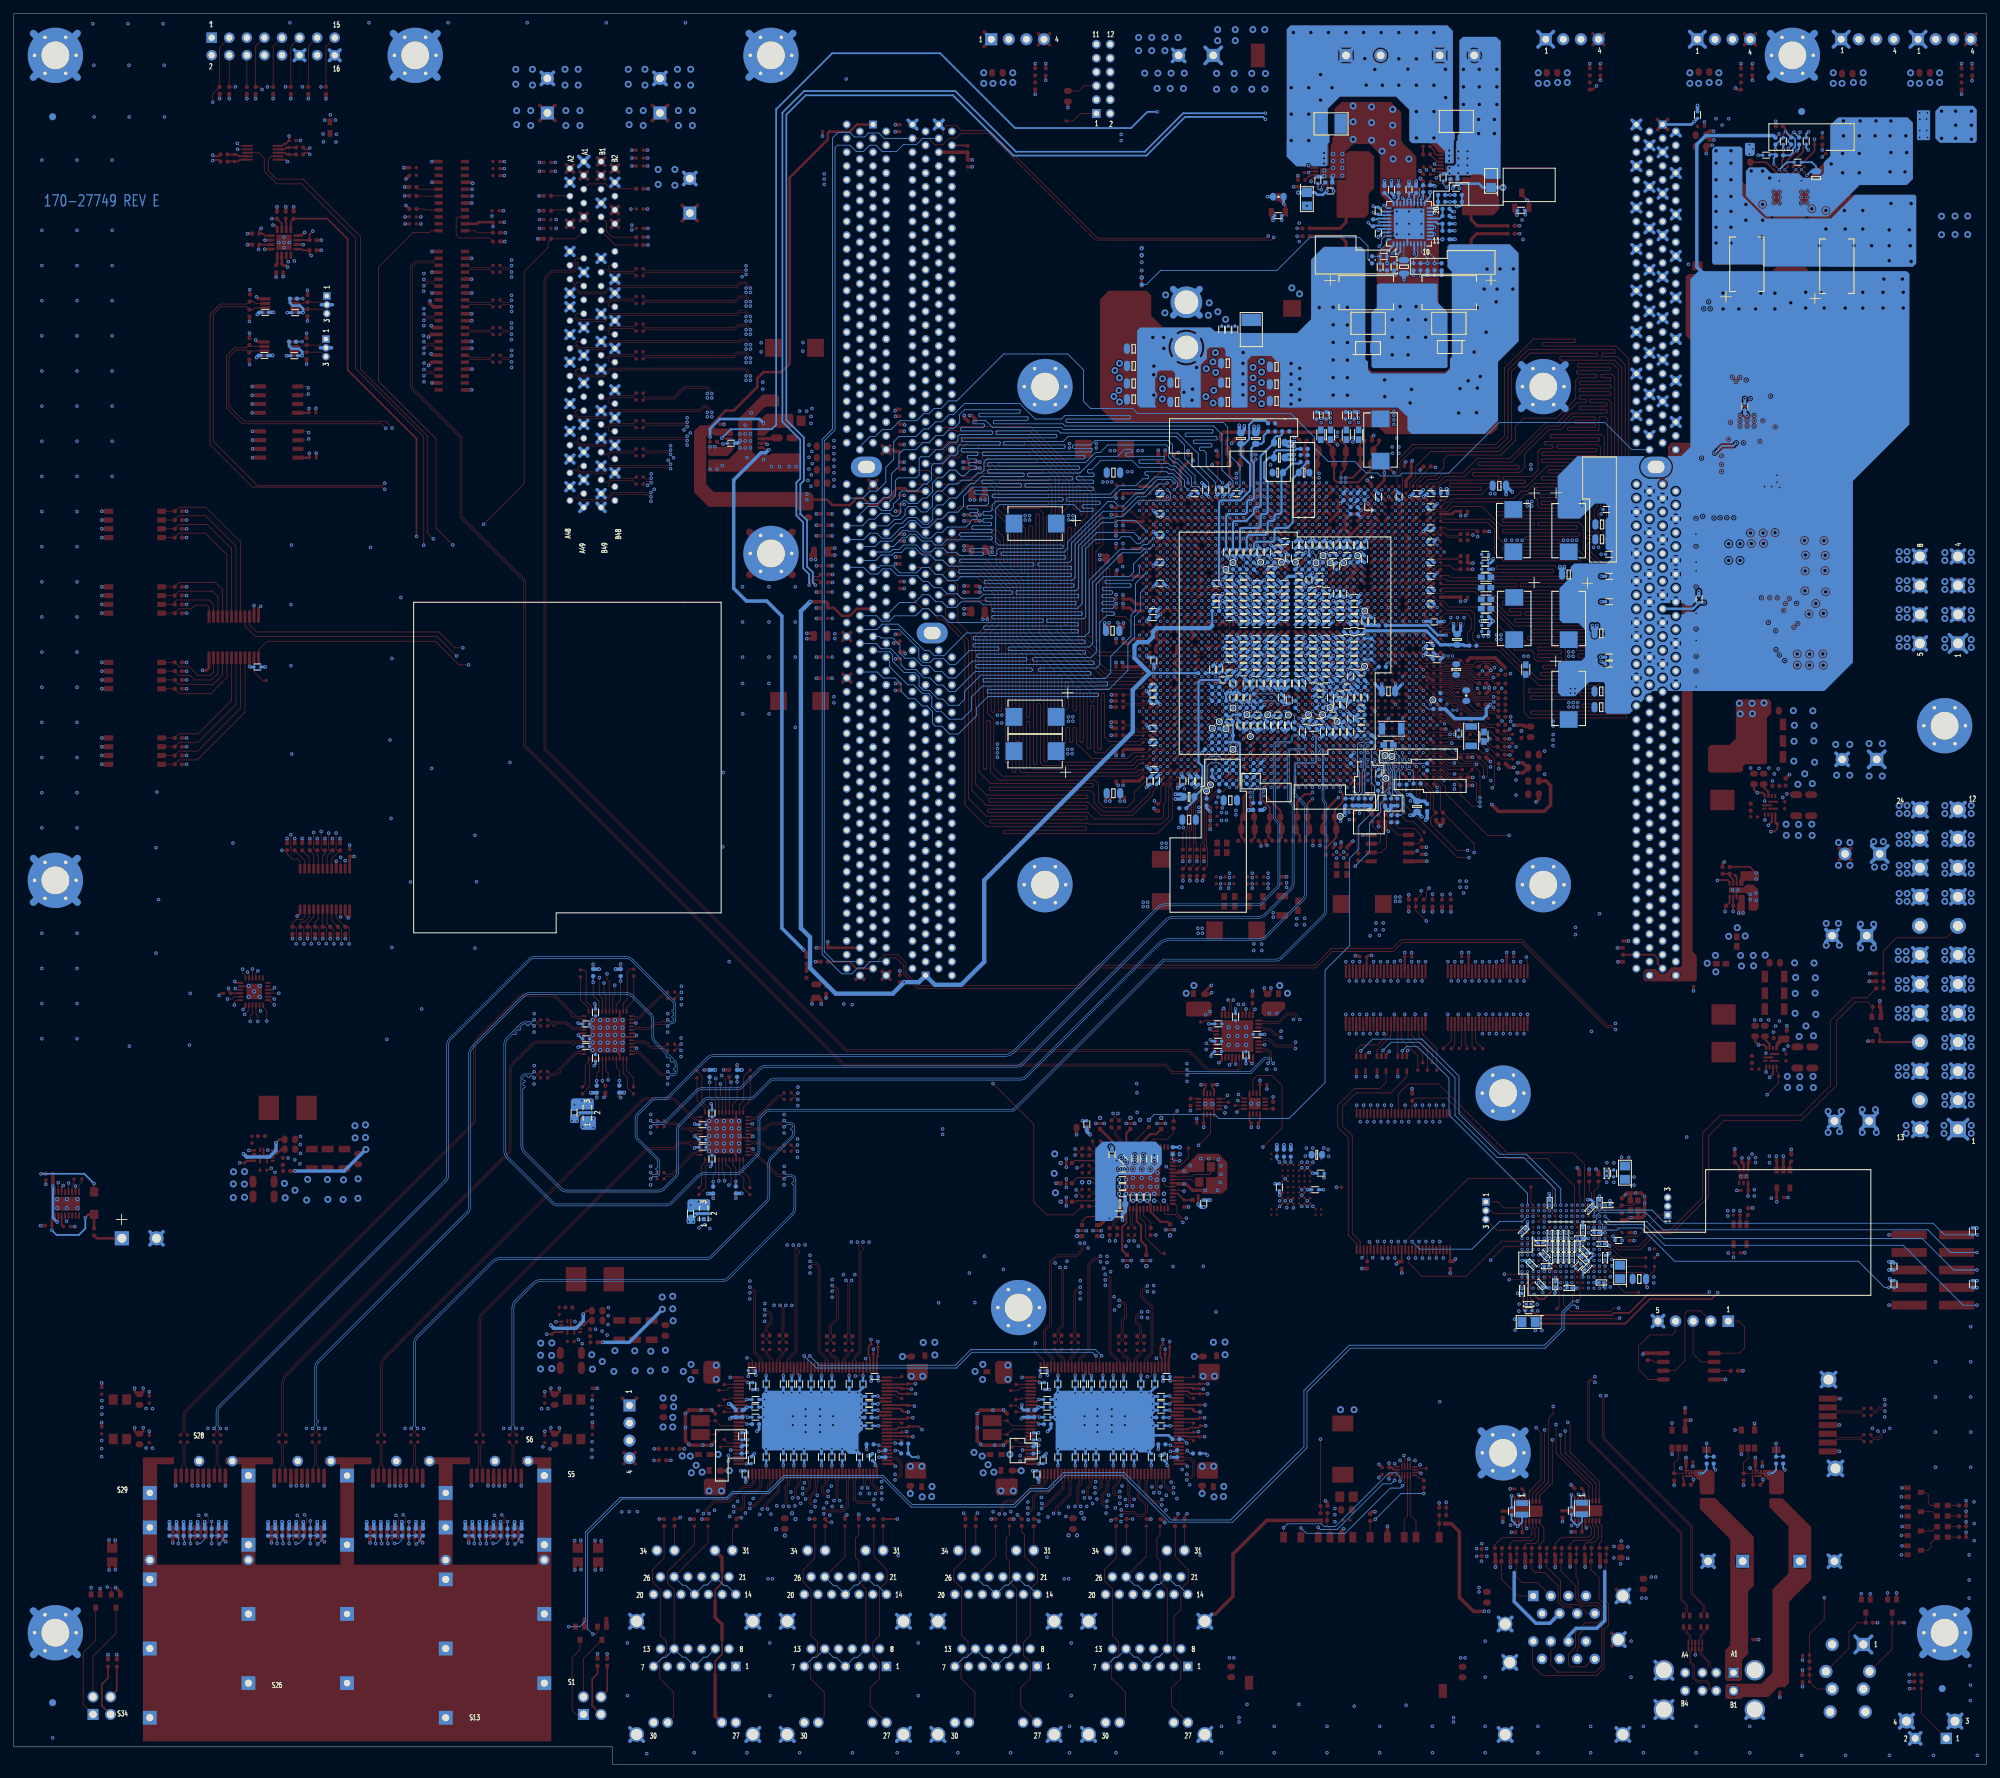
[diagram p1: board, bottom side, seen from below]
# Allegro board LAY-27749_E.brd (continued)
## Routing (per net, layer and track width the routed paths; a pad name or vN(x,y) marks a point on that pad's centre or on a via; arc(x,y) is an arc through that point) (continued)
GVDD_FDIVH: length 3.8
  TOP w0.254: R96.1 30.35,232.67 30.45,232.77 v2(30.45,233.38) R98.2
  BOTTOM w0.254: C5132.1 30.4,234.13 30.44,234.09 R98.2 v2(30.45,233.38)
GVDD_FDIVL: length 7.4
  TOP w0.254: R100.2 29.31,235.69 v2(29,236) 29,236.38 R102.1
  BOTTOM w0.254: R101.1 28.34,232.54 27.94,232.94 27.94,233.43 27.59,233.77 27.59,234.84 27.88,235.13 R99.2 v2(29,236)
GVDD_GND: length 8.1
  TOP w0.152: U631.B5 v3(29.89,230.47)
  TOP w0.254: v2(26.89,235.89) 27.02,235.76 C5136.2 ; C5137.2 28.16,233.97 28.55,233.58 28.55,233.57 v2(28.57,233.54) ; R97.2 26,235.63 v2(25.66,235.97) ; R95.2 v2(23.67,235.81)
  BOTTOM w0.254: C5135.2 v2(32.94,232.57) ; v3(29.89,230.47) 28.8,231.55 C5131.2 ; C5133.2 26,235.63 v2(25.66,235.97)
  vias: v2(33.7,233.46) v2(34.21,234.09) v2(34.21,232.7)
GVDD_INTVCC: length 4.4
  TOP w0.254: C5134.1 31.77,231.55 U631.B6
GVDD_ITH: length 5
  TOP w0.254: U631.A4 28.69,231.87 v2(27.35,233.2) 27.02,233.54 C5136.1
  BOTTOM w0.254: v2(27.35,233.2) 27.02,233.54 R104.1
GVDD_ITHX: length 2
  TOP w0.254: v2(27.79,235.89) 28.16,235.51 C5137.1
  BOTTOM w0.254: v2(27.79,235.89) 27.78,235.89 R104.2
GVDD_MS: length 6.3
  TOP w0.152: U631.B3 v3(27.49,230.47)
  TOP w0.254: R95.1 v2(23.67,233.33)
  L3_INT_1 w0.254: v2(23.67,233.33) 24.63,233.33 v3(27.49,230.47)
GVDD_RT: length 4
  TOP w0.254: R97.1 26.46,233.65 26.46,233.08 27.89,231.65 U631.A3
GVDD_SENSE: length 233.8
  TOP w0.178: R233.1 168.4,171.95 168.71,171.64 169.35,171.64 169.86,171.13 169.86,170.61 170.04,170.43 v2(170.08,170.43)
  TOP w0.254: R98.1 v2(29.94,235.62)
  L3_INT_1 w0.254: v2(29.94,235.62) 29.94,235.15 30.36,234.72 31.71,234.72 36.21,239.22 58.42,239.22 63.32,234.31 79.27,234.31 82.4,231.19 89.15,231.19 94.79,236.83 101.16,236.83 102.81,238.48 103.98,238.48 v2(104.14,238.63)
  BOTTOM w0.254: v2(104.14,238.63) 116.03,238.63 121.59,233.07 140.18,233.07 148.95,241.83 170.81,241.83 173.94,238.71 173.94,194.03 171.37,191.47 171.37,185.8 171.93,185.24 171.93,180.49 170.94,179.5 170.94,172.87 170.08,172.01 v2(170.08,170.43)
GVDD_SVIN: length 5.3
  TOP w0.152: U631.C1 v3(25.89,229.67)
  BOTTOM w0.254: v3(25.89,229.67) 25.33,230.23 R92.2 24.56,230.93 25.18,231.55 C5131.1
GVDD_TRK: length 6
  TOP w0.152: U631.B4 v3(29.09,230.47)
  L3_INT_1 w0.254: v3(29.09,230.47) 28.56,230.47 v2(25.71,233.32)
  BOTTOM w0.254: C5133.1 26,233.61 v2(25.71,233.32)
GVDD_VOUTM: length 3.1
  TOP w0.152: U631.A6 v3(30.69,231.27)
  BOTTOM w0.254: v3(30.69,231.27) 30.69,232.2 R101.2 30.35,232.67 30.37,232.7 31.17,232.7 C5135.1
GVSS_SENSE: length 233.3
  TOP w0.178: R234.1 168.8,171.21 169.18,171.21 169.43,170.95 169.43,170.68 v2(169.19,170.43)
  L3_INT_1 w0.254: v2(28.73,234.67) 28.77,234.72 29.57,234.72 30.15,234.15 31.99,234.15 36.55,238.71 58.12,238.71 63.02,233.81 79.06,233.81 82.19,230.68 89.43,230.68 95.05,236.3 101.35,236.3 103.02,237.97 103.92,237.97 v2(104.14,237.74)
  BOTTOM w0.254: v2(28.73,234.67) R99.1 ; v2(104.14,237.74) 104.5,238.1 115.74,238.1 121.34,232.51 140.58,232.51 149.29,241.22 170.57,241.22 173.38,238.41 173.38,194.3 170.84,191.76 170.84,185.52 171.35,185.01 171.35,180.74 170.38,179.77 170.38,173.1 169.55,172.27 169.55,170.79 v2(169.19,170.43)
I2C1_CH0_SCL: length 86.3
  TOP w0.118: v2(237.64,118.57) 237.64,120.49 R519.2 239.07,121.92 U82.5 ; U622.17 199.95,110.73 200.39,111.17 v2(200.39,113.69) ; v2(183.57,99.11) 183.57,96.6 183.12,96.15 U65.17
  L5_INT_2 w0.087: v2(237.64,118.57) 232.76,113.69 v2(200.39,113.69) 200.19,113.48 200.19,112.14 196.09,108.05 196.09,102.63 190.85,97.38 182.78,97.38 182.27,97.89 182.27,98.63 182.75,99.11 v2(183.57,99.11)
I2C1_CH0_SDA: length 81.1
  TOP w0.118: U622.18 199.45,111.04 199.73,111.33 v2(199.73,112.9) ; v2(182.91,98.32) 182.91,96.75 182.62,96.47 U65.18 ; U82.4 238.42,122.36 R520.2 236.68,121.04 236.55,120.91 v2(236.55,118.57)
  L5_INT_2 w0.087: v2(182.91,98.32) 183.46,97.76 190.68,97.76 195.76,102.84 195.76,108.3 199.73,112.28 v2(199.73,112.9) 199.73,113.81 200.21,114.29 232.27,114.29 v2(236.55,118.57)
I2C1_CH1_SCL: length 101.3
  TOP w0.118: v2(239.85,118.59) 239.85,120.9 239.99,121.04 R521.2 U82.7 ; v2(215.54,35.97) 215.16,35.59 215.16,34.75 215.28,34.63 J16.5A
  L5_INT_2 w0.087: v2(239.85,118.59) 240.49,117.96 240.49,77.9 219.79,57.2 219.79,40.21 v2(215.54,35.97)
I2C1_CH1_SDA: length 101.8
  TOP w0.118: v2(238.76,118.57) 238.76,120.52 R522.2 239.72,121.48 U82.6 ; J16.4A 214.48,34.62 214.17,34.92 214.17,35.71 v2(214.5,36.04)
  L5_INT_2 w0.087: v2(214.5,36.04) 213.23,37.31 213.23,43.81 215.95,46.53 215.95,54.38 238.76,77.19 v2(238.76,118.57)
I2C1_CH2_SCL: length 96.3
  TOP w0.118: J16.5B 229.53,34.63 229.41,34.75 229.41,35.59 v2(229.79,35.97) ; v2(242.01,118.57) 242.01,120.91 242.14,121.04 R523.2 242.56,121.58 241.67,122.46 U82.9
  L5_INT_2 w0.087: v2(229.79,35.97) 229.95,35.97 232.05,38.07 232.05,67.51 241.6,77.06 241.6,118.16 v2(242.01,118.57)
I2C1_CH2_SDA: length 96.1
  TOP w0.118: v2(240.92,118.62) 240.92,120.88 241.08,121.04 R5870.2 241.47,121.7 241.02,122.15 U82.8 ; J16.4B 228.73,34.62 228.42,34.92 228.42,35.71 v2(228.75,36.04)
  L5_INT_2 w0.087: v2(228.75,36.04) 231.52,38.81 231.52,67.56 241.05,77.09 241.05,118.07 240.92,118.19 v2(240.92,118.62)
I2C1_CH3_SCL: length 94.2
  TOP w0.118: v2(244.04,35.97) 243.66,35.59 243.66,34.75 243.78,34.63 J16.5C ; U82.11 242.97,122.46 243.33,122.1 244.22,122.1 244.74,121.58 R5871.2 244.32,121.04 244.2,120.91 v2(244.2,118.57)
  L5_INT_2 w0.087: v2(244.2,118.57) 244.47,118.29 244.47,109.12 245.9,107.7 245.9,85.24 246.74,84.4 246.74,40.44 244.04,37.74 v2(244.04,35.97)
I2C1_CH3_SDA: length 94.2
  TOP w0.118: v2(243,36.04) 242.67,35.71 242.67,34.92 242.98,34.62 J16.4C ; U82.10 242.32,122.45 243.03,121.74 243.43,121.74 243.64,121.54 R526.2 243.22,121.04 243.09,120.91 v2(243.09,118.57)
  L5_INT_2 w0.087: v2(243,36.04) 243,37.47 245.95,40.41 245.95,78.99 243.56,81.38 243.56,85.65 242.79,86.42 242.79,118.27 v2(243.09,118.57)
I2C1_CH4_SCL: length 115.1
  TOP w0.118: U82.14 242.97,130.64 R527.2 244.84,132.09 244.98,132.23 v2(244.98,134.34) ; J16.5D 258.03,34.63 257.91,34.75 257.91,35.59 v2(258.29,35.97)
  L5_INT_2 w0.087: v2(244.98,134.34) 245.87,134.34 256.11,124.1 256.11,79.78 253.62,77.29 253.62,48.21 256.13,45.69 256.13,38.13 v2(258.29,35.97)
I2C1_CH4_SDA: length 110.3
  TOP w0.118: J16.4D 257.23,34.62 256.92,34.92 256.92,35.71 v2(257.25,36.04) ; U82.13 243.62,130.45 244.01,130.84 244.77,130.84 245.51,131.58 R528.2 v2(246.26,132.09)
  L5_INT_2 w0.087: v2(257.25,36.04) 255.55,37.75 255.55,45.36 253.06,47.85 253.06,77.85 255.32,80.11 255.32,106.83 255.8,107.32 255.8,122.54 v2(246.26,132.09)
I2C1_CH5_SCL: length 2.9
  TOP w0.118: R529.2 241.67,131.52 U82.16
I2C1_CH5_SDA: length 3.1
  TOP w0.118: U82.15 242.32,131.08 R530.2
I2C1_CH6_SCL: length 110.2
  TOP w0.118: U82.18 240.37,131.26 240.05,131.58 R531.2 240.42,132.09 240.59,132.26 v2(240.59,134.82) ; U55.B5 v2(218.8,227.65)
  L5_INT_2 w0.087: v2(218.8,227.65) 221.04,227.65 221.79,226.9 221.79,201.09 226.39,196.49 226.39,151.1 240.59,136.91 v2(240.59,134.82)
I2C1_CH6_SDA: length 110.4
  TOP w0.118: U82.17 241.02,131.22 241.15,131.34 R5872.2 241.51,132.09 241.68,132.26 v2(241.68,134.67) ; U55.B6 v2(218.8,226.65)
  L5_INT_2 w0.087: v2(218.8,226.65) 220.49,226.65 221.18,225.96 221.18,201.07 225.35,196.9 225.35,151.54 240.16,136.72 240.16,134.65 240.44,134.37 241.38,134.37 v2(241.68,134.67)
I2C1_CH7_SCL: length 38.5
  TOP w0.118: U82.20 239.07,130.88 R5873.2 238.28,132.09 238.43,132.23 v2(238.43,134.59) ; U624.19 252.84,110.43 253.14,110.13 v2(253.14,109.73)
  L5_INT_2 w0.087: v2(238.43,134.59) 238.43,132.94 252.43,118.95 252.43,110.44 v2(253.14,109.73)
I2C1_CH7_SDA: length 38.6
  TOP w0.118: U82.19 239.72,131.32 R5874.2 239.38,132.09 239.51,132.22 v2(239.51,134.59) ; v2(254.13,110.59) 253.49,110.59 253.15,110.93 U624.20
  L5_INT_2 w0.087: v2(254.13,110.59) 254.79,111.25 254.79,117.83 239.51,133.1 v2(239.51,134.59)
I2C1_EN: length 2
  TOP w0.118: U58.5 243.86,211.8 243.82,211.84 v2(243.25,211.84)
  BOTTOM w0.118: v2(243.25,211.84) R830.2
I2C1_PROC_SCL: length 245.7
  TOP w0.118: U58.2 250.18,210.49 250.44,210.24 R208.2 251.36,210.65 255.09,210.65 256.18,209.55 256.18,191.21 249.82,184.85 231.71,184.85 v2(231.39,185.17) ; v3(113.33,155.2) U22.R10
  L3_INT_1 w0.087: v2(231.39,185.17) 231.09,184.86 217.47,184.86 210.52,177.91 210.52,151.52 170.6,111.59 143.55,111.59 119.25,135.89 118.24,135.89 112.93,141.2 112.93,154.79 v3(113.33,155.2)
I2C1_PROC_SDA: length 247.7
  TOP w0.118: v2(231.39,184.28) 231.71,184.59 250.53,184.59 256.64,190.7 256.64,209.58 255.17,211.05 251.28,211.05 R205.2 250.39,211.43 250.11,211.15 U58.3 ; U22.R11 v3(112.33,155.2)
  L3_INT_1 w0.087: v2(231.39,184.28) 231.09,184.58 217.49,184.58 210.78,177.87 210.78,151.44 170.71,111.37 143.4,111.37 119.13,135.64 118.11,135.64 112.6,141.15 112.6,144.81 112.73,144.93 112.73,154.8 v3(112.33,155.2)
I2C1_SCL: length 787.5
  TOP w0.118: v2(242.4,191.57) 242.42,191.57 242.6,191.39 U625.6 ; 239.78,209.68 240.41,210.31 R217.2 243.08,210.31 243.26,210.49 U58.7 ; U105.2 245.64,217.48 v2(245.33,217.17) ; v2(115.57,78.92) 116.2,78.92 116.94,79.65 116.94,80.67 117.25,80.98 U36.16 ; U82.22 v2(237.77,131.09) ; J6.118 152.86,235 151.94,234.09 150.75,234.09 149.81,235.03 148.84,235.03 148.12,235.75 144.16,235.75 128.71,220.3 103.33,220.3 v2(102.96,220.68) ; J7.118 158.41,116.54 157.48,116.54 156.41,115.47 156.41,114.17 154.38,112.14 130.99,112.14 128.04,115.09 96.88,115.09 94.49,117.47 85.67,117.47 84.38,118.77 67.17,118.77 54.9,106.5 53.87,106.5 v2(53.55,106.18) ; U2.10 252.36,233.92 v2(252.7,234.26) ; U16.2 v2(278.59,84.05) ; v2(242.45,198.04) 242.47,198.04 242.64,197.87 U589.6
  L3_INT_1 w0.087: v2(278.59,84.05) 278.1,84.53 278.1,99.51 250.15,127.46 240.04,127.46 238.09,129.41 238.09,130.24 237.77,130.55 v2(237.77,131.09) 237.47,131.4 237.47,133.02 236.31,134.18 236.31,179.62 239.28,182.59 239.28,190.23 240.98,191.94 242.04,191.94 v2(242.4,191.57) 242.71,191.87 243.38,191.87 244.26,192.75 244.26,195.67 242.93,197 241.81,197 241.35,197.46 241.35,197.97 241.76,198.37 242.12,198.37 v2(242.45,198.04) 242.76,198.35 245.34,198.35 246.76,199.77 246.76,204.47 243.61,207.62 238.1,207.62 237.06,208.66 237.06,210.19 237.64,210.77 238.68,210.77 239.78,209.68 ; v2(53.55,106.18) 53.23,106.5 52.86,106.5 52.5,106.15 52.5,105.13 55.91,101.73 55.91,84.35 56.59,83.67 56.59,80.29 56.26,79.96 56.26,72.41 v1(56.67,72) ; v2(115.57,78.92) 123.72,78.92 126.38,81.57 126.38,87.27 131.37,92.27 149.24,92.27 149.94,91.57 150.55,91.57 v2(150.8,91.82)
  L5_INT_2 w0.087: 239.78,209.68 240.87,210.77 243.87,210.77 244.75,211.66 244.75,216.6 v2(245.33,217.17) 245.64,217.49 251.45,217.49 254.08,220.12 254.08,233.63 253.75,233.96 253.01,233.96 v2(252.7,234.26) ; v2(102.96,220.68) 103.29,220.34 103.29,220 101.68,218.39 93.7,218.39 88.29,212.98 81.36,212.98 80.9,213.43 80.9,214.27 v2(81.74,215.11) ; v2(53.55,106.18) 53.21,106.53 52.6,106.53 46.74,112.39 46.74,113.74 45.49,114.99 45.49,115.36 J5.118 ; v2(150.8,91.82) 150.62,91.64 149.94,91.64 149.33,92.25 149.33,93.52 157.76,101.96 157.76,115.55 158.21,116 J7.118 161.16,116 162.08,115.09 163.19,115.09 163.98,115.87 166.12,115.87 167.74,114.25 183.57,114.25 195.1,125.78 234.8,125.78 237.69,128.68 237.69,130.46 237.77,130.54 v2(237.77,131.09)
  BOTTOM w0.118: J6.118 159.23,235 160.02,235.79 161.47,235.79 162.05,235.2 163.53,235.2 164.19,235.86 165.89,235.86 166.7,235.05 166.7,192.98 168.2,191.49 168.2,117.07 165.37,114.24 163.89,114.24 163.04,115.09 162.18,115.09 161.27,116 J7.118 ; R627.2 v2(81.74,215.11)
I2C1_SDA: length 786.9
  TOP w0.118: U589.5 242.67,199.14 242.48,198.95 v2(242.45,198.95) ; U82.23 v2(237.12,130.62) ; U105.1 244.99,217.8 v2(244.46,217.27) ; J7.238 160.25,116 159.26,116.99 157.22,116.99 156.11,115.88 156.11,114.38 154.31,112.57 131.29,112.57 128.37,115.49 97.04,115.49 94.66,117.88 85.84,117.88 84.55,119.18 67.08,119.18 54.66,106.76 53.87,106.76 v2(53.55,107.07) ; U16.5 v2(277.09,84) ; U36.18 118.75,79.65 118.55,79.45 117.22,79.45 v2(116.08,78.31) ; J6.238 150.65,235.7 150.65,236.37 150.14,236.88 148.82,236.88 148.06,236.12 143.94,236.12 128.39,220.57 104.04,220.57 v2(103.73,220.88) ; U2.9 v2(252.67,233.42) ; J55.1 240.66,211.33 R222.2 243.08,211.33 243.26,211.15 U58.6 ; v2(242.4,192.47) 242.43,192.47 242.62,192.66 U625.5
  L3_INT_1 w0.087: v2(53.55,107.07) 53.21,106.73 52.76,106.73 52.27,106.24 52.27,105.04 55.68,101.63 55.68,84.25 56.34,83.59 56.34,80.37 55.49,79.52 55.49,72.38 v1(55.87,72) ; v2(277.09,84) 277.83,84.74 277.83,99.39 250.04,127.18 239.93,127.18 237.87,129.24 237.87,130.12 237.68,130.32 237.43,130.32 v2(237.12,130.62) 237.12,131.04 237.25,131.17 237.25,132.93 236.09,134.09 236.09,179.71 239.06,182.68 239.06,190.32 240.89,192.15 242.09,192.15 v2(242.4,192.47) 242.77,192.1 243.28,192.1 244.03,192.84 244.03,195.57 242.83,196.77 241.71,196.77 241.12,197.36 241.12,198.06 241.66,198.61 242.11,198.61 v2(242.45,198.95) 242.8,198.6 245.23,198.6 246.51,199.88 246.51,204.36 243.51,207.37 237.99,207.37 236.8,208.56 236.8,210.29 237.54,211.02 238.58,211.02 J55.1 ; v2(150.8,91.03) 150.5,91.34 149.86,91.34 149.15,92.05 131.46,92.05 126.59,87.18 126.59,81.41 123.87,78.69 116.46,78.69 v2(116.08,78.31)
  L5_INT_2 w0.087: v2(79.71,215.17) 80.64,214.23 80.64,213.39 81.33,212.7 88.32,212.7 93.79,218.18 101.76,218.18 103.5,219.92 103.5,220.62 103.73,220.85 v2(103.73,220.88) ; v2(237.12,130.62) 237.43,130.32 237.43,128.81 234.72,126.11 194.89,126.11 183.29,114.5 167.92,114.5 166.27,116.15 163.86,116.15 163.7,116 J7.238 162.75,116.74 161.69,117.81 160.15,117.81 159.23,116.89 158.29,116.89 157.48,116.08 157.48,102.01 149.07,93.6 149.07,92.2 149.91,91.36 150.47,91.36 v2(150.8,91.03) ; v2(252.67,233.42) 252.97,233.72 253.6,233.72 253.8,233.53 253.8,220.19 251.31,217.7 244.89,217.7 v2(244.46,217.27) 244.46,211.9 243.69,211.12 240.87,211.12 J55.1 ; J5.238 47.85,115.2 47.85,114.58 47.14,113.87 47.14,112.32 52.7,106.76 53.24,106.76 v2(53.55,107.07)
  BOTTOM w0.118: J6.238 153.67,235 154.58,234.09 156.46,234.09 157.45,233.1 159.51,233.1 160.43,234.01 161.32,234.01 162.2,233.12 163.3,233.12 164.19,234.01 165.99,234.01 166.34,233.65 166.34,192.84 167.89,191.29 167.89,117.42 166.47,116 J7.238 ; R630.2 v2(79.71,215.17)
I2C2_EN: length 2
  TOP w0.118: v2(243.35,205.61) 243.95,205.61 243.99,205.57 U18.5
  BOTTOM w0.118: v2(243.35,205.61) R191.2
I2C2_PROC_SCL: length 229
  TOP w0.118: U18.2 250.74,204.27 R196.2 251.34,204.4 252.93,204.4 253.92,203.4 253.92,196.32 251.73,194.12 231.33,194.12 v2(230.33,193.12) ; v3(113.33,153.2) U22.N10
  L3_INT_1 w0.087: v2(230.33,193.12) 225.27,193.12 210.28,178.12 210.28,151.62 170.48,111.82 143.7,111.82 119.38,136.14 118.36,136.14 113.59,140.92 113.59,144.83 113.72,144.96 113.72,152.81 v3(113.33,153.2)
I2C2_PROC_SDA: length 231.1
  TOP w0.118: v2(231.26,193.1) 231.91,193.75 251.99,193.75 254.28,196.04 254.28,203.58 253.14,204.72 251.36,204.72 R190.2 250.74,204.92 U18.3 ; U22.P10 v3(113.33,154.2)
  L3_INT_1 w0.087: v2(231.26,193.1) 230.68,193.68 225.51,193.68 209.95,178.11 209.95,151.62 170.38,112.05 143.85,112.05 119.51,136.4 118.49,136.4 113.92,140.97 113.92,153.61 v3(113.33,154.2)
I2C2_SCL: length 91.9
  TOP w0.118: J4.3 240.54,204.09 R203.2 243.21,204.09 243.39,204.27 U18.7
  L12_INT_5 w0.087: J4.3 241,204.55 241.41,204.55 241.63,204.33 241.63,200.7 229.45,188.52 212.64,188.52 208.25,192.9 208.25,224.19 206.72,225.73 204.34,225.73 203.3,226.77 201.03,226.77 J3.B5
I2C2_SDA: length 94.7
  TOP w0.118: J4.1 240.79,205.1 R192.2 243.21,205.1 243.39,204.92 U18.6
  L12_INT_5 w0.087: J4.1 241.07,204.83 241.53,204.83 241.91,204.44 241.91,200.58 229.57,188.24 212.52,188.24 207.98,192.79 207.98,224.08 206.6,225.45 204.14,225.45 203.12,226.47 199,226.47 198.81,226.65 J3.B6
I2C4_SCL: length 1.4
  TOP w0.118: U22.N12 v3(111.33,153.2)
  BOTTOM w0.118: R726.2 v3(111.33,153.2)
I2C4_SDA: length 1.4
  TOP w0.118: U22.P12 v3(110.33,154.2)
  BOTTOM w0.118: R720.2 v3(110.33,154.2)
IFC_A0: length 7.6
  TOP w0.118: U593.2 81.51,105.59 79.38,103.45 TP200.1
IFC_A1: length 6.4
  TOP w0.118: TP201.1 80.04,103.17 82.01,105.15 U593.3
IFC_A2: length 7.6
  TOP w0.118: U593.5 83.01,105.37 80.75,103.1 TP202.1
IFC_A3: length 6.4
  TOP w0.118: U593.6 83.52,104.85 81.41,102.74 TP203.1
IFC_A4: length 7.7
  TOP w0.118: TP204.1 82.12,102.39 84.52,104.79 U593.8
IFC_A5: length 4.7
  TOP w0.118: U593.9 U598.1
IFC_A6: length 5.5
  TOP w0.118: U596.1 88.03,103.24 86.02,105.24 U593.11
IFC_A7: length 7.9
  TOP w0.118: U593.12 86.52,105.4 87.96,103.96 90.4,103.96 91,103.36 U595.1
IFC_A8: length 16.8
  TOP w0.118: U593.13 v2(87.02,105.59) ; U37.2 v2(90.45,92.85)
  L14_INT_6 w0.087: v2(87.02,105.59) 88.06,104.54 88.06,102.29 89,101.35 89,97.05 89.56,96.49 89.56,95.46 89.53,95.43 89.53,93.94 90.45,93.01 v2(90.45,92.85)
IFC_A9: length 17.2
  TOP w0.118: U37.15 v2(83.95,95.25) ; U593.14 v2(87.52,108.38)
  L12_INT_5 w0.087: v2(83.95,95.25) 85.82,97.12 85.82,106.55 87.52,108.24 v2(87.52,108.38)
IFC_A10: length 21.2
  TOP w0.118: U37.12 v2(85.45,92.85) ; U593.16 v2(88.52,108.38)
  L12_INT_5 w0.087: v2(85.45,92.85) 86.6,94.01 87.93,94.01 88.47,94.54 88.47,97.28 88.9,97.71 88.9,100.71 89.79,101.6 89.79,104.24 89.51,104.52 89.51,107.39 v2(88.52,108.38)
IFC_A11: length 14.2
  TOP w0.118: U37.11 v2(85.95,95.25) ; U593.17 v2(89.02,105.59)
  L12_INT_5 w0.087: v2(89.02,105.59) 88.24,104.81 88.24,102.59 87.35,101.7 87.35,97.38 85.95,95.98 v2(85.95,95.25)
IFC_A12: length 26.5
  TOP w0.118: U37.18 v2(82.45,95.25) ; U593.19 v2(90.02,105.59)
  L12_INT_5 w0.087: v2(82.45,95.25) 82.45,96.04 84.38,97.97 84.38,99.49 85.24,100.36 85.24,107.51 87.19,109.45 90.37,109.45 91.01,108.81 91.01,106.58 v2(90.02,105.59)
IFC_A13: length 24.5
  TOP w0.118: U37.19 v2(81.95,92.85) ; U593.20 v2(90.52,108.38)
  L12_INT_5 w0.087: v2(81.95,92.85) 83.19,94.09 83.19,95.2 85.55,97.56 85.55,107.14 87.5,109.09 89.92,109.09 90.52,108.49 v2(90.52,108.38)
IFC_A14: length 53.6
  TOP w0.118: U37.54 89.95,73.45 v2(90.2,73.2) ; U593.22 v2(91.52,108.38)
  L14_INT_6 w0.087: v2(90.2,73.2) 90.91,72.49 95.05,72.49 103.28,80.72 103.28,87.73 101.96,89.05 99.16,89.05 93.42,94.79 93.42,106.4 91.52,108.3 v2(91.52,108.38)
IFC_A15: length 15.8
  TOP w0.118: U593.23 v2(92.02,105.59) ; U37.3 v2(89.95,95.25)
  L14_INT_6 w0.087: v2(92.02,105.59) 91.62,105.18 91.62,94.6 91.53,94.51 90.78,94.51 90.04,95.25 v2(89.95,95.25)
IFC_A16: length 36.8
  TOP w0.118: U37.4 v2(89.45,92.85) ; U594.2 v2(66.78,105.59)
  L14_INT_6 w0.087: v2(89.45,92.85) 87.43,90.83 78.99,90.83 76.53,93.29 76.53,101.12 74.27,103.38 68.99,103.38 v2(66.78,105.59)
IFC_A17: length 34.5
  TOP w0.118: U594.3 v2(67.28,108.38) ; U37.5 v2(88.95,95.25)
  L14_INT_6 w0.087: v2(67.28,108.38) 68.65,109.75 78.71,109.75 82.04,106.43 82.04,100.23 85.37,96.9 87.3,96.9 v2(88.95,95.25)
IFC_A18: length 35.1
  TOP w0.118: U37.6 v2(88.45,92.85) ; U594.5 v2(68.28,108.38)
  L14_INT_6 w0.087: v2(68.28,108.38) 68.58,108.68 68.58,108.69 69.34,109.45 78.51,109.45 81.69,106.27 81.69,100.15 85.24,96.6 87.21,96.6 88.45,95.35 v2(88.45,92.85)
IFC_A19: length 35.9
  TOP w0.118: U594.6 v2(68.78,105.59) ; U37.7 v2(87.95,95.25)
  L14_INT_6 w0.087: v2(87.95,95.25) 87.88,95.18 87.88,92.25 87.17,91.54 78.75,91.54 76.99,93.31 76.99,101.52 74.63,103.89 70.13,103.89 68.78,105.23 v2(68.78,105.59)
IFC_A20: length 31.4
  TOP w0.118: U37.8 v2(87.45,92.85) ; U594.8 v2(69.78,105.59)
  L14_INT_6 w0.087: v2(87.45,92.85) 86.45,91.85 78.94,91.85 77.39,93.4 77.39,101.45 74.47,104.37 70.54,104.37 69.78,105.12 v2(69.78,105.59)
IFC_A21: length 28.9
  TOP w0.118: U37.9 v2(86.95,95.25) ; U594.9 v2(70.28,108.38)
  L14_INT_6 w0.087: v2(86.95,95.25) 85.94,96.27 85.09,96.27 81.18,100.18 81.18,106.2 78.21,109.17 71.07,109.17 v2(70.28,108.38)
IFC_A22: length 30.4
  TOP w0.118: U594.11 v2(71.29,108.38) ; U37.10 v2(86.45,92.85)
  L14_INT_6 w0.087: v2(71.29,108.38) 71.79,108.89 78.11,108.89 80.96,106.03 80.96,98.84 83.82,95.99 85.82,95.99 86.53,95.28 86.53,92.93 v2(86.45,92.85)
IFC_A23: length 21.2
  TOP w0.118: U594.12 v2(71.79,105.59) ; U37.20 v2(81.45,95.25)
  L14_INT_6 w0.087: v2(71.79,105.59) 72.65,104.72 74.75,104.72 77.9,101.57 77.9,94.95 78.56,94.28 80.49,94.28 v2(81.45,95.25)
IFC_A24: length 24.1
  TOP w0.118: U594.13 v2(72.29,108.38) ; U37.21 v2(80.95,92.85)
  L14_INT_6 w0.087: v2(72.29,108.38) 72.29,106.99 72.87,106.4 75.29,106.4 79.55,102.13 79.55,98.45 82.07,95.94 82.07,95.47 82.03,95.43 82.03,95.07 82.07,95.03 82.07,93.97 v2(80.95,92.85)
IFC_A25: length 18.6
  TOP w0.118: U37.22 v2(80.45,95.25) ; U594.14 v2(72.79,105.59)
  L14_INT_6 w0.087: v2(72.79,105.59) 74.68,105.59 78.94,101.32 78.94,95.02 79.2,94.77 79.97,94.77 v2(80.45,95.25)
IFC_A26: length 54.1
  TOP w0.118: U22.B40 v3(83.33,142.2) ; U37.23 v2(79.95,92.85)
  L5_INT_2 w0.087: v3(83.33,142.2) 83.19,142.05 83.19,139.95 84.45,138.68 84.45,128.78 82.63,126.95 82.63,122.1 79.45,118.92 79.45,97.76 79.98,97.23 79.98,92.89 v2(79.95,92.85)
IFC_A27: length 71.2
  TOP w0.118: U37.24 v2(79.45,95.25) ; v2(83.2,139.24) 83.19,139.26 83.19,140.46 82.83,140.82 U22.A40
  L3_INT_1 w0.087: v2(79.45,95.25) 79.45,107.75 80.98,109.27 93.14,109.27 95.1,111.23 95.1,117.91 85.55,127.46 83.29,127.46 80.66,130.09 80.65,130.09 80.41,130.34 80.41,130.34 80.14,130.61 80.14,137.92 81.15,138.94 82.88,138.94 82.88,138.94 82.9,138.94 v2(83.2,139.24)
IFC_A28: length 76.4
  TOP w0.118: U37.25 v2(78.95,92.85) ; v3(83.33,144.2) U22.D39
  L3_INT_1 w0.087: v2(78.95,92.85) 78.95,93.28 78.97,93.3 78.97,107.89 80.88,109.8 93.12,109.8 94.77,111.46 94.77,117.91 85.58,127.1 82.96,127.1 79.5,130.56 79.5,139.39 82.09,141.99 82.09,142.96 v3(83.33,144.2)
IFC_A29: length 53
  TOP w0.118: v3(83.33,143.2) U22.C39 ; U37.26 v2(78.45,95.25)
  L5_INT_2 w0.087: v3(83.33,143.2) 83.25,143.2 82.63,142.57 82.63,138.61 83.95,137.29 83.95,128.88 82.3,127.23 82.3,122.4 78.99,119.1 78.99,95.79 v2(78.45,95.25)
IFC_A30: length 77.1
  TOP w0.118: U22.A39 v3(83.83,140.82) ; U37.31 v2(78.45,73.15)
  L5_INT_2 w0.087: v3(83.83,140.82) 84.71,139.94 84.71,128.52 82.96,126.77 82.96,122.07 79.98,119.1 79.98,101.54 84.43,97.1 84.43,94.03 84.94,93.52 84.94,89.74 81.56,86.37 81.56,79.5 78.13,76.07 78.13,73.47 v2(78.45,73.15)
IFC_A31: length 11.5
  TOP w0.102: U22.C38 85.34,143.18 85.34,142.5 85.22,142.38 85.22,141.26
  TOP w0.118: 85.22,141.26 85.22,137.8 83.69,136.27 82.77,136.27 TP258.1
IFC_AD0: length 176
  TOP w0.118: U37.51 88.45,73.4 v2(88.65,73.2) ; v3(83.33,159.2) U22.W39 ; U38.J8 v2(102.1,81.42) ; U593.47 v2(81.51,113.21)
  L12_INT_5 w0.087: v2(88.65,73.2) 88.65,71.93 86.68,69.96 86.67,69.96 86.58,69.86 73.16,69.86 68.71,74.32 68.71,76.5 68.03,77.18 65.04,77.18 v1(64.67,76.8) ; v2(81.51,113.21) 81.51,112.26 83.03,110.74 90.86,110.74 92.05,109.55 92.05,107.9 92.63,107.32 92.63,100.61 103.1,90.14 103.1,85.47 101.55,83.92 101.55,81.91 102.04,81.42 v2(102.1,81.42)
  L14_INT_6 w0.087: v2(81.51,113.21) 79.1,110.79 66.22,110.79 65.89,110.46 64.06,110.46 63.45,111.07 63.45,118.34 64.03,118.92 64.94,118.92 73.3,127.28 73.3,132.61 74.73,134.04 74.73,150.06 76,151.33 76,154.05 81.53,159.59 82.94,159.59 v3(83.33,159.2) ; v2(88.65,73.2) 89.26,73.81 95.45,73.81 101.6,79.96 101.6,80.92 v2(102.1,81.42)
IFC_AD1: length 184.3
  TOP w0.118: U38.K7 101.07,80.85 v2(101.07,80.44) ; U37.49 87.45,73.33 v2(87.25,73.13) ; U593.46 v2(82.01,116) ; v3(82.33,159.2) U22.W40
  L5_INT_2 w0.087: v2(82.01,116) 82.01,118.29 82.98,119.25 92.25,119.25 95.03,116.47 95.03,94.75 100,89.79 100,83.67 100.76,82.91 102.56,82.91 102.9,82.58 102.9,80.64 102.34,80.09 101.42,80.09 v2(101.07,80.44)
  L12_INT_5 w0.087: v1(64.67,80) 64.84,80 65.21,80.38 67.68,80.38 75.74,72.31 83.34,72.31 84.94,73.91 86.46,73.91 v2(87.25,73.13)
  L14_INT_6 w0.087: v2(82.01,116) 82.01,115.19 78.03,111.2 65.41,111.2 64.92,111.68 64.24,111.68 63.75,112.17 63.75,118.21 64.16,118.62 65.02,118.62 73.56,127.15 73.56,132.13 75.06,133.63 75.06,149.78 78.44,153.16 78.44,156.16 80.95,158.67 81.81,158.67 v3(82.33,159.2) ; v2(101.07,80.44) 101.07,80.02 95.14,74.09 88.21,74.09 v2(87.25,73.13)
IFC_AD2: length 178.3
  TOP w0.118: U593.44 v2(83.01,116) ; U37.47 v2(86.45,73.15) ; v3(83.33,158.2) U22.V39 ; U38.J7 v2(101.29,81.42)
  L5_INT_2 w0.087: v2(83.01,116) 82.4,116.62 82.4,118.26 83.11,118.97 92.1,118.97 94.82,116.26 94.82,94.51 99.78,89.55 99.78,82.93 v2(101.29,81.42)
  L12_INT_5 w0.087: v1(63.87,80) 64.29,79.58 67.94,79.58 75.59,71.93 83.57,71.93 85.21,73.58 85.99,73.58 86.42,73.15 v2(86.45,73.15)
  L14_INT_6 w0.087: v2(83.01,116) 82.48,116.54 81.95,116.54 81.59,116.18 81.59,115.32 77.8,111.53 66.27,111.53 65.15,112.65 65.15,118.34 73.81,127 73.81,128.96 75.36,130.5 75.36,149.6 78.69,152.93 78.69,155.19 81.23,157.73 82.87,157.73 v3(83.33,158.2) ; v2(101.29,81.42) 100.63,80.76 100.63,80.11 94.92,74.4 87.7,74.4 v2(86.45,73.15)
IFC_AD3: length 181.4
  TOP w0.118: U38.K6 v2(100.1,80.39) ; U37.45 v2(85.45,73.15) ; U593.43 v2(83.52,113.21) ; v3(82.33,158.2) U22.V40
  L12_INT_5 w0.087: v2(85.45,73.15) 83.86,71.56 75.37,71.56 68.16,78.78 63.49,78.78 v1(63.07,79.2) ; v2(83.52,113.21) 83.52,112.5 84.96,111.05 91.8,111.05 93.07,109.78 93.07,100.66 103.58,90.14 103.58,81.28 102.18,79.88 100.6,79.88 v2(100.1,80.39)
  L14_INT_6 w0.087: v2(85.45,73.15) 87.01,74.71 94.42,74.71 v2(100.1,80.39) ; v2(83.52,113.21) 80.37,110.06 79.25,110.06 78.96,110.35 66.74,110.35 66.45,110.06 63.88,110.06 63.45,110.49 63.45,110.77 63.23,110.98 63.23,118.95 64.32,120.04 65.61,120.04 73.03,127.45 73.03,132.89 74.32,134.19 74.32,140.21 73.74,140.79 73.74,143.64 74.32,144.22 74.32,144.87 73.82,145.38 73.82,147.58 74.32,148.08 74.32,150.14 75.69,151.5 75.69,154.25 81.25,159.82 83.24,159.82 83.7,159.35 83.7,158.84 83.46,158.6 83.13,158.6 82.73,158.2 v3(82.33,158.2)
IFC_AD4: length 177.6
  TOP w0.118: U593.41 84.52,115.99 v2(84.66,116.13) ; U38.K5 v2(98.9,80.62) ; U22.U40 v3(83.33,157.2) ; U27.P7 62.66,79.6 62.66,83.62 63.7,84.66 74.84,84.66 v2(83.95,75.55) U37.42
  L3_INT_1 w0.087: v2(98.9,80.62) 97.4,79.12 87.52,79.12 v2(83.95,75.55)
  L5_INT_2 w0.087: v2(84.66,116.13) 84.66,118.03 85.37,118.75 91.92,118.75 94.6,116.07 94.6,94.25 99.57,89.28 99.57,81.29 v2(98.9,80.62)
  L14_INT_6 w0.087: v3(83.33,157.2) 83.23,157.2 82.85,156.82 81.43,156.82 78.92,154.31 78.92,152.73 75.64,149.45 75.64,130.45 74.07,128.88 74.07,126.95 65.37,118.25 65.37,112.74 66.35,111.76 77.22,111.76 78.84,113.39 78.84,114.45 81.14,116.75 84.04,116.75 v2(84.66,116.13)
IFC_AD5: length 149.5
  TOP w0.118: U38.K4 v2(98.1,80.62) ; U22.U41 v3(82.33,157.2) ; U37.40 v2(82.95,75.55) ; U593.40 v2(85.02,113.21)
  L3_INT_1 w0.087: v2(82.95,75.55) 87.11,79.71 97.18,79.71 v2(98.1,80.62)
  L12_INT_5 w0.087: v2(85.02,113.21) 85.02,112.34 85.95,111.4 91.97,111.4 93.42,109.96 93.42,100.74 103.86,90.3 103.86,80.77 102.18,79.1 99.62,79.1 v2(98.1,80.62)
  L14_INT_6 w0.087: v3(82.33,157.2) 82.72,157.2 83.34,157.81 84.86,157.81 85.93,156.74 85.93,143.64 84.43,142.14 84.43,136.25 84.07,135.89 84.07,129.86 87.36,126.57 87.36,122.64 86.64,121.92 86.64,118.72 87.88,117.47 89,117.47 89.61,116.87 89.61,113.4 89.59,113.38 89.59,113.03 89.61,113.02 89.61,112.55 88.7,111.63 86.59,111.63 v2(85.02,113.21)
  BOTTOM w0.118: v1(66.27,79.2) 67.01,78.46 70.28,78.46 74.3,74.45 81.85,74.45 v2(82.95,75.55)
IFC_AD6: length 146.7
  TOP w0.118: U38.J4 v2(98.1,81.42) ; U37.38 v2(81.95,75.55) ; v3(83.33,156.2) U22.T39 ; U593.38 v2(86.02,113.21)
  L12_INT_5 w0.087: v2(81.95,75.55) 88.37,81.97 97.87,81.97 98.1,81.74 v2(98.1,81.42) 97.75,81.08 96.82,81.08 96.62,80.87 96.62,80.01 98.35,78.28 102.11,78.28 105.18,81.36 105.18,89.59 93.68,101.09 93.68,110.26 92.15,111.79 87.05,111.79 86.02,112.81 v2(86.02,113.21)
  L14_INT_6 w0.087: v3(83.33,156.2) 84.29,155.24 84.29,152.04 84.9,151.43 84.9,143.23 82.93,141.27 82.93,140.18 83.95,139.17 83.95,136.6 83.54,136.19 83.54,129.59 86.87,126.26 86.87,122.96 86.18,122.27 86.18,118.24 87.99,116.43 87.99,114.33 87.55,113.89 87.55,112.7 87.22,112.37 86.86,112.37 v2(86.02,113.21) ; v2(81.95,75.55) 80.36,77.14 70.64,77.14 68.2,79.58 66.69,79.58 v1(66.27,80)
IFC_AD7: length 132.7
  TOP w0.118: U593.37 v2(86.52,116) ; U38.H4 v2(98.89,82.22) ; U37.36 v2(80.95,75.55) ; v3(82.33,156.2) U22.T40
  L5_INT_2 w0.087: v2(86.52,116) 86.52,117.96 87.02,118.47 91.85,118.47 94.39,115.93 94.39,94.01 99.35,89.04 99.35,82.68 v2(98.89,82.22)
  L12_INT_5 w0.087: v2(80.95,75.55) 87.88,82.47 98.64,82.47 v2(98.89,82.22)
  L14_INT_6 w0.087: v1(67.07,79.2) 67.11,79.25 68,79.25 70.67,76.58 79.91,76.58 80.94,75.55 v2(80.95,75.55) ; v3(82.33,156.2) 81.94,155.81 81.94,155.02 82.18,154.77 83.4,154.77 83.7,154.47 83.7,144.82 83.54,144.65 83.19,144.65 82.7,144.17 82.7,143.64 81.64,142.57 81.64,137.64 82.7,136.58 82.7,129.31 86.16,125.86 86.16,123.32 85.53,122.69 85.53,116.99 v2(86.52,116)
IFC_AD8: length 135
  TOP w0.118: v3(83.33,155.2) U22.R39 ; U37.50 v2(87.95,75.55) ; U593.36 v2(87.02,113.21)
  L12_INT_5 w0.087: v2(87.95,75.55) 89.29,76.89 101.42,76.89 105.82,81.28 105.82,89.33 93.93,101.22 93.93,110.54 92.28,112.19 87.91,112.19 87.02,113.08 v2(87.02,113.21)
  L14_INT_6 w0.087: v2(87.02,113.21) 87.02,116.39 85.74,117.66 85.74,122.5 86.41,123.16 86.41,125.96 82.98,129.39 82.98,136.73 81.92,137.79 81.92,142.47 83.19,143.74 83.57,143.74 83.91,144.08 83.91,154.62 v3(83.33,155.2) ; v1(67.07,80) 68.23,80 70.64,77.6 84.51,77.6 86.38,75.73 86.38,75.42 86.69,75.11 87.51,75.11 v2(87.95,75.55)
IFC_AD9: length 127.9
  TOP w0.118: U593.35 v2(87.52,116) ; U37.48 v2(86.95,75.55) ; v3(82.33,155.2) U22.R40
  L5_INT_2 w0.087: v2(86.95,75.55) 86.95,79.2 94.17,86.42 94.17,115.76 91.87,118.06 88.16,118.06 87.52,117.41 v2(87.52,116)
  L14_INT_6 w0.087: v1(63.07,80) 63.44,80.38 68.26,80.38 70.71,77.93 84.57,77.93 v2(86.95,75.55) ; v3(82.33,155.2) 82.79,155.65 83.49,155.65 84.1,155.04 84.1,151.96 84.7,151.35 84.7,143.94 84.51,143.74 84.12,143.74 83.82,143.43 83.82,143.03 83.46,142.67 82.93,142.67 82.4,142.14 82.4,139.32 83.72,138 83.72,136.8 83.26,136.35 83.26,129.49 86.64,126.11 86.64,123.04 85.96,122.36 85.96,118.03 87.52,116.47 v2(87.52,116)
IFC_AD10: length 154.9
  TOP w0.118: v3(82.33,154.2) U22.P40 ; U37.46 v2(85.95,75.55) ; U593.33 v2(88.52,116)
  L3_INT_1 w0.087: v2(88.52,116) 86.23,118.29 79.98,118.29 74.09,124.18 74.09,128.52 75.49,129.92 75.49,140.13 74.9,140.72 74.9,142.52 74.27,143.15 71.55,143.15 70.99,142.6 69.75,142.6 68.86,143.48 68.86,144.46 67.45,145.88 67.45,148.85 67.58,148.99 67.58,152.6 70.05,155.07 73.85,155.07 74.46,155.68 82.5,155.68 82.83,155.35 U22.P40 v3(82.33,154.2)
  L5_INT_2 w0.087: v2(85.95,75.55) 85.95,78.74 93.9,86.69 93.9,115.6 91.75,117.75 88.56,117.75 88.09,117.27 88.09,116.43 v2(88.52,116)
  L12_INT_5 w0.087: v1(62.27,80) 62.68,80.42 64.85,80.42 65.05,80.62 65.05,81.1 65.25,81.31 67.51,81.31 73.84,74.98 83.13,74.98 83.49,75.34 83.49,75.95 83.72,76.18 85.32,76.18 v2(85.95,75.55)
IFC_AD11: length 150
  TOP w0.118: v3(81.33,154.2) U22.P41 ; U37.44 v2(84.95,75.55) ; U593.32 v2(89.02,113.21)
  L12_INT_5 w0.087: v2(84.95,75.55) 85.46,75.04 91.58,75.04 92.99,76.45 101.75,76.45 106.32,81.03 106.32,89.33 94.21,101.45 94.21,110.95 92.53,112.62 89.6,112.62 v2(89.02,113.21)
  L14_INT_6 w0.087: v1(62.27,77.6) 62.64,77.23 62.64,75.85 62.91,75.58 67.81,75.58 71.09,72.29 80.37,72.29 80.9,72.82 80.9,73.69 81.97,74.75 84.15,74.75 v2(84.95,75.55) ; v2(89.02,113.21) 89.18,113.37 89.18,116.1 88.82,116.47 88.39,116.47 86.39,118.46 86.39,122.1 87.1,122.81 87.1,126.44 83.79,129.74 83.79,136.04 84.2,136.45 84.2,142.24 85.72,143.76 85.72,156.33 85.43,156.63 81.79,156.63 80.96,155.8 80.96,154.57 v3(81.33,154.2)
IFC_AD12: length 183.9
  TOP w0.102: U27.M6 63.47,77.2 63.47,75.77 63.65,75.59 67.51,75.59
  TOP w0.118: v3(83.33,153.2) U22.N39 ; U593.30 v2(90.02,113.21) ; 67.51,75.59 70.03,75.59 75.08,70.54 81.53,70.54 83.45,72.45 v2(83.45,73.15) U37.41
  L12_INT_5 w0.087: v2(83.45,73.15) 85.03,74.73 91.9,74.73 93.19,76.02 102.11,76.02 106.76,80.67 106.76,89.31 94.46,101.6 94.46,111.58 92.41,113.63 90.45,113.63 v2(90.02,113.21)
  L14_INT_6 w0.087: v3(83.33,153.2) 82.84,152.7 79.32,152.7 75.9,149.28 75.9,130.12 74.3,128.52 74.3,126.75 65.68,118.14 65.68,113.26 66.95,111.99 76.99,111.99 78.63,113.63 78.63,116.8 80.09,118.26 84.4,118.26 85.09,117.58 85.09,114.55 84.59,114.05 84.59,113.03 84.59,113.03 84.59,112.26 85.6,111.25 89.53,111.25 90.02,111.74 v2(90.02,113.21)
IFC_AD13: length 148.9
  TOP w0.118: v3(82.33,153.2) U22.N40 ; U37.39 v2(82.45,73.15) ; U593.29 v2(90.52,116)
  L3_INT_1 w0.087: v3(82.33,153.2) 81.83,153.7 80.85,153.7 80.26,154.28 73.46,154.28 70.92,151.74 70.1,151.74 69.46,151.1 69.46,143.8 70,143.26 70.84,143.26 71.27,143.69 74.68,143.69 75.72,142.65 75.72,141 76.15,140.56 76.15,129.72 74.65,128.22 74.65,124.82 80.26,119.2 86.72,119.2 87.78,118.14 88.87,118.14 90.52,116.49 v2(90.52,116)
  L5_INT_2 w0.087: v2(82.45,73.15) 83.29,73.99 84.68,73.99 85.47,74.78 85.47,78.84 93.65,87.02 93.65,115.48 92.7,116.43 90.95,116.43 v2(90.52,116)
  L14_INT_6 w0.087: v2(82.45,73.15) 80.93,71.63 70.54,71.63 68.14,74.03 61.31,74.03 61.04,74.3 61.04,77.18 v1(61.47,77.6)
IFC_AD14: length 152.6
  TOP w0.118: U593.27 v2(91.52,116) ; v3(83.33,152.2) U22.M39 ; U37.37 v2(81.45,73.15)
  L3_INT_1 w0.087: v3(83.33,152.2) 82.88,152.65 82.88,153.34 82.55,153.67 82.24,153.67 81.89,154.03 81.89,154.33 81.46,154.76 70.15,154.76 67.84,152.45 67.84,148.92 68.35,148.41 68.35,145.46 69.14,144.67 69.14,143.64 69.82,142.95 70.97,142.95 71.42,143.41 74.47,143.41 75.34,142.55 75.34,140.82 75.82,140.34 75.82,129.84 74.43,128.46 74.43,124.4 80.09,118.75 86.61,118.75 87.68,117.68 88.8,117.68 89.66,116.81 89.66,115.98 90.17,115.47 90.99,115.47 v2(91.52,116)
  L5_INT_2 w0.087: v2(91.52,116) 93.37,114.15 93.37,87.33 84.53,78.48 84.53,75.03 84.1,74.6 82.9,74.6 v2(81.45,73.15)
  L14_INT_6 w0.087: v1(61.47,78.4) 61.47,78.38 61.84,78.01 61.84,75.06 62.13,74.78 67.92,74.78 70.76,71.93 80.72,71.93 81.45,72.66 v2(81.45,73.15)
IFC_AD15: length 132.9
  TOP w0.118: U37.35 v2(80.45,73.15) ; U593.26 v2(92.02,113.21) ; v3(82.33,152.2) U22.M40
  L3_INT_1 w0.087: v2(92.02,113.21) 92.02,116.61 90.04,118.59 88.06,118.59 86.84,119.81 81.36,119.81 76.5,124.66 76.5,140.73 76.17,141.06 76.17,142.93 73.25,145.85 71.83,145.85 70.68,147 70.68,149.79 73.97,153.09 77.19,153.09 77.6,152.68 81.85,152.68 v3(82.33,152.2)
  L5_INT_2 w0.087: v2(92.02,113.21) 93.07,112.16 93.07,87.66 81.46,76.05 81.46,74.16 v2(80.45,73.15)
  L14_INT_6 w0.087: v1(63.07,78.4) 63.45,78.02 63.45,77.49 63.75,77.19 67.69,77.19 70.84,74.04 79.56,74.04 v2(80.45,73.15)
IFC_AD16: length 91.5
  TOP w0.118: U594.47 v2(66.78,113.21) ; U22.L40 v3(83.33,151.2)
  L12_INT_5 w0.087: v1(63.87,78.4) 63.49,78.03 61.31,78.03 61.06,78.28 61.06,106.65 66.78,112.37 v2(66.78,113.21)
  L14_INT_6 w0.087: v2(66.78,113.21) 66.78,114.48 67.79,115.49 67.79,118.31 74.65,125.17 77.44,125.17 77.9,125.63 77.9,127.2 76.57,128.54 76.57,138.51 77.44,139.39 77.44,146.51 78.79,147.85 78.79,148.79 79.7,149.71 79.7,150.11 80.39,150.8 82.94,150.8 83.33,151.19 v3(83.33,151.2)
IFC_AD17: length 87.4
  TOP w0.118: R5904.2 77.44,125.07 v2(77.44,125.78) ; U594.46 v2(67.28,116) ; U22.L41 v3(82.33,151.2)
  L12_INT_5 w0.087: v2(67.28,116) 67.28,112.16 61.77,106.65 61.77,84.66 63.58,82.85 63.58,81.09 v1(63.87,80.8)
  L14_INT_6 w0.087: v2(67.28,116) 67.28,118.41 74.3,125.43 77.09,125.43 v2(77.44,125.78) 77.44,127.3 76.35,128.4 76.35,138.61 77.24,139.5 77.24,146.86 78.18,147.8 78.18,148.95 78.87,149.63 78.87,150.72 79.73,151.59 81.94,151.59 v3(82.33,151.2)
IFC_AD18: length 48.2
  TOP w0.118: v3(83.33,150.2) U22.K39 ; R5903.2 v2(78.61,125.68) ; U594.44 v2(68.28,116)
  L14_INT_6 w0.087: v2(68.28,116) 68.76,116.48 68.76,118.34 75.34,124.92 75.79,124.92 75.79,124.92 77.85,124.92 v2(78.61,125.68) 78.61,126.8 78.12,127.29 76.78,128.63 76.78,138.46 77.67,139.34 77.67,145.62 79.02,146.97 79.02,148.35 80.7,150.04 80.7,150.33 80.98,150.6 82.93,150.6 v3(83.33,150.2)
IFC_AD19: length 50.5
  TOP w0.118: v3(82.33,150.2) U22.K40 ; v2(80.01,125.76) R5902.2 ; U594.43 v2(68.78,113.21)
  L14_INT_6 w0.087: v2(68.78,113.21) 68.78,114.48 69.16,114.86 69.16,116.6 69.71,117.15 69.71,118.53 75.84,124.66 78.92,124.66 v2(80.01,125.76) 77,128.77 77,138.4 77.93,139.33 77.93,145.57 79.22,146.86 79.22,148.29 80.76,149.82 81.96,149.82 v3(82.33,150.2)
IFC_AD20: length 49.9
  TOP w0.118: R5898.2 80.87,125.37 80.87,126.25 v2(80.5,126.62) ; v3(83.33,149.2) U22.J39 ; U594.41 69.78,115.99 v2(69.93,116.13)
  L14_INT_6 w0.087: v2(69.93,116.13) 69.93,117.82 76.43,124.33 79.48,124.33 80.5,125.36 v2(80.5,126.62) 77.22,129.9 77.22,138.31 78.13,139.23 78.13,141.11 78.74,141.72 78.74,143.31 78.18,143.87 78.18,145.44 79.48,146.74 79.48,148.23 80.87,149.63 82.03,149.63 82.04,149.63 82.85,149.63 83.29,149.2 v3(83.33,149.2)
IFC_AD21: length 89
  TOP w0.118: U594.40 v2(70.28,113.21) ; v3(82.33,149.2) U22.J40 ; v2(81.64,126.24) 81.64,125.76 R796.1 R5771.2 82.42,123.4 v2(80.9,121.88)
  L12_INT_5 w0.087: v1(64.67,80.8) 64.67,82.7 62.61,84.76 62.61,106.71 68,112.09 69.17,112.09 v2(70.28,113.21)
  L14_INT_6 w0.087: v2(81.64,126.24) 81.64,126.97 77.88,130.73 77.88,137.87 79.73,139.73 79.73,141.86 79.32,142.27 79.32,143.84 78.94,144.22 78.94,145.26 80.21,146.53 80.21,147.04 80.87,147.7 82.47,147.7 82.73,147.96 82.73,148.8 v3(82.33,149.2) ; v2(70.28,113.21) 72.34,115.26 72.34,118.62 75.6,121.88 v2(80.9,121.88)
IFC_AD22: length 51.6
  TOP w0.118: v3(82.33,148.2) U22.H40 ; U594.38 v2(71.29,113.21)
  L14_INT_6 w0.087: v3(82.33,148.2) 81.83,148.69 80.29,148.69 79.76,148.16 79.76,146.66 78.44,145.34 78.44,143.99 78.93,143.49 78.93,141.64 78.32,141.03 78.32,139.12 77.43,138.23 77.43,130.39 80.95,126.87 80.95,125.17 79.86,124.08 76.76,124.08 70.35,117.67 70.35,115.21 69.7,114.55 69.7,112.9 69.98,112.62 70.7,112.62 v2(71.29,113.21)
IFC_AD23: length 43.7
  TOP w0.118: U594.37 v2(71.79,116) ; v3(81.33,148.2) U22.H41
  L14_INT_6 w0.087: v2(71.79,116) 71.79,118.55 76.96,123.72 80.19,123.72 81.2,124.74 81.2,127.05 77.65,130.61 77.65,138.15 78.51,139.01 78.51,140.95 79.12,141.56 79.12,143.66 78.69,144.09 78.69,145.29 79.98,146.58 79.98,147.27 80.91,148.2 v3(81.33,148.2)
IFC_AD24: length 47.8
  TOP w0.118: U594.36 v2(72.29,113.21) ; v3(82.33,147.2) U22.G40
  L14_INT_6 w0.087: v2(72.29,113.21) 72.29,114.48 73.36,115.55 73.36,118.67 75.59,120.9 81.1,120.9 82.3,122.1 82.3,127.02 79.11,130.21 79.11,130.21 78.33,130.99 78.33,137.71 80.14,139.52 80.14,142 79.71,142.43 79.71,144.2 79.53,144.37 79.53,145.3 81.04,146.81 81.95,146.81 v3(82.33,147.2)
IFC_AD25: length 44
  TOP w0.118: v3(81.33,147.2) U22.G41 ; U594.35 v2(72.79,116)
  L14_INT_6 w0.087: v2(72.79,116) 72.79,118.58 75.51,121.31 80.97,121.31 82.07,122.4 82.07,126.9 78.11,130.86 78.11,137.75 79.92,139.57 79.92,141.94 79.51,142.35 79.51,144.01 79.22,144.3 79.22,145.26 81.16,147.2 v3(81.33,147.2)
IFC_AD26: length 44.6
  TOP w0.118: v3(83.33,147.2) U22.G39 ; U594.33 v2(73.79,116)
  L14_INT_6 w0.087: v2(73.79,116) 73.79,118.72 75.72,120.65 81.33,120.65 82.51,121.83 82.51,127.11 79.32,130.3 79.32,138.43 80.33,139.44 80.33,142.08 79.96,142.44 79.96,144.35 79.78,144.53 79.78,145.24 81.13,146.58 82.72,146.58 83.33,147.19 v3(83.33,147.2)
IFC_AD27: length 47.7
  TOP w0.118: U22.F40 v3(83.33,146.2) ; U594.32 v2(74.29,113.21)
  L14_INT_6 w0.087: v2(74.29,113.21) 74.87,112.62 75.62,112.62 75.79,112.8 75.79,114.93 75.26,115.47 75.26,119 76.25,119.99 81.76,119.99 82.96,121.18 82.96,127.41 79.81,130.56 79.81,138.38 80.73,139.3 80.73,142.3 80.37,142.67 80.37,144.3 81.74,145.67 82.8,145.67 v3(83.33,146.2)
IFC_AD28: length 44.8
  TOP w0.118: U22.E41 81.33,146.19 v3(81.33,146.2) ; U594.30 v2(75.29,113.21)
  L14_INT_6 w0.087: v3(81.33,146.2) 81.33,145.59 80.16,144.42 80.16,142.59 80.54,142.21 80.54,139.38 79.55,138.39 79.55,130.4 82.73,127.23 82.73,121.74 82.47,121.49 82.47,121.11 81.69,120.32 75.87,120.32 74.27,118.72 74.27,115.46 74.56,115.16 74.6,115.16 75.29,114.48 v2(75.29,113.21)
IFC_AD29: length 40.9
  TOP w0.118: U594.29 v2(75.79,116) ; v3(82.33,145.2) U22.E40
  L14_INT_6 w0.087: v2(75.79,116) 76.3,116.51 76.3,118.64 77.29,119.63 82.25,119.63 84.02,121.41 84.02,126.7 80.09,130.63 80.09,138.33 80.98,139.22 80.98,142.42 80.59,142.8 80.59,144.17 81.62,145.2 v3(82.33,145.2)
IFC_AD30: length 41.4
  TOP w0.118: U594.27 v2(76.79,116) ; v3(83.33,145.2) U22.E39
  L14_INT_6 w0.087: v3(83.33,145.2) 82.81,144.68 82.12,144.68 81.84,144.4 81.84,143.1 81.41,142.67 81.41,138.94 80.54,138.07 80.54,135.99 81.64,134.9 81.64,130.02 85.9,125.76 85.9,123.44 85.22,122.76 85.22,120.04 83.87,118.69 79.48,118.69 v2(76.79,116)
IFC_AD31: length 42
  TOP w0.118: U594.26 v2(77.29,113.21) ; v3(81.33,144.2) U22.D41
  L14_INT_6 w0.087: v3(81.33,144.2) 81.25,144.2 80.82,143.76 80.82,142.93 81.18,142.57 81.18,139.06 80.31,138.2 80.31,135.81 81.38,134.75 81.38,129.97 84.28,127.08 84.28,120.98 82.5,119.2 77.6,119.2 76.86,118.47 76.86,116.67 76.36,116.18 76.36,115.4 77.29,114.48 v2(77.29,113.21)
IFC_AVD: length 175.1
  TOP w0.118: U594.25 v2(77.79,116) ; U593.25 v2(92.52,116) ; U22.H44 77.64,148.69 v2(77.48,148.86) ; U38.C4 v2(98.1,87.02) ; U594.48 66.28,116.07 66.43,116.22 v2(66.43,116.66) ; U593.48 v2(81.01,116)
  L3_INT_1 w0.087: v2(92.52,116) 92.52,112.66 92.1,112.24 82.6,112.24 81.99,112.85 81.99,115.02 v2(81.01,116) v2(77.79,116)
  L14_INT_6 w0.087: v2(77.79,116) 77.79,113.11 76.95,112.27 66.98,112.27 66.28,112.97 66.28,116.09 66.43,116.24 v2(66.43,116.66) 66.43,117.09 66.28,117.24 66.28,118.17 74.57,126.47 74.57,128.35 76.11,129.88 76.11,137.55 76.09,137.58 76.09,147.46 v2(77.48,148.86) ; v1(59.87,80) 60.25,80.38 60.25,81.31 60.93,81.99 71.98,81.99 71.99,82 72.59,82 72.59,81.99 89.56,81.99 91.49,80.06 99.06,80.06 99.47,80.47 99.47,81.23 102.68,84.44 102.68,87.48 101.82,88.34 99.42,88.34 v2(98.1,87.02) 96.75,88.37 96.75,90.62 92.82,94.55 92.82,94.58 92.82,105.98 91.9,106.91 90.83,106.91 90.07,107.67 90.07,108.71 92.89,111.53 92.89,115.64 v2(92.52,116)
IFC_BCTL: length 85.9
  TOP w0.118: v2(72.14,146.56) 73.66,148.08 77.41,148.08 77.79,147.69 U22.G44
  L14_INT_6 w0.087: v2(72.14,146.56) 72.14,140.18 71.93,139.98 71.93,135.53 70.66,134.26 70.66,127.62 65.6,122.56 63.3,122.56 61.09,120.34 61.09,86.77 56.72,82.4 56.72,80.21 57.33,79.6 60.27,79.6 v1(60.67,79.2)
IFC_CLE: length 153.6
  TOP w0.118: v2(73.15,139.7) 73.15,143.38 74.04,144.27 77.72,144.27 78.61,145.16 79.3,145.16 U22.E43 ; U38.D5 v2(98.9,86.22)
  L5_INT_2 w0.087: v2(98.9,86.22) 98.9,84.95 96.62,82.68 96.62,75.51 91.14,70.03 69.75,70.03 67.35,72.43 63.71,72.43 63.44,72.7 63.44,74.78 v1(64.67,76)
  L14_INT_6 w0.087: v2(98.9,86.22) 97.59,84.91 96.22,84.91 92.46,88.67 78.71,88.67 75.41,91.97 75.41,99.57 72.83,102.15 67.14,102.15 61.9,107.39 61.9,120.19 63.67,121.96 65.85,121.96 71.39,127.5 71.39,133.47 72.54,134.63 72.54,139.42 72.82,139.7 v2(73.15,139.7)
IFC_CLK: length 78.9
  TOP w0.118: v2(74.73,131.04) 76.37,131.04 84.33,139 84.33,142.19 U22.B38
  L5_INT_2 w0.087: v1(63.87,76.8) 64.29,77.23 64.86,77.23 65.15,77.52 65.92,77.52 66.64,78.25 66.64,87.7 63.61,90.73 63.61,116.37 65.21,117.97 65.42,117.97 73.27,125.81 73.27,129.58 v2(74.73,131.04)
IFC_CS0_B: length 73.2
  TOP w0.118: v2(73.15,138.43) 73.18,138.46 74.3,138.46 75.95,140.11 R280.2 76.71,142.24 77.6,142.24 78.55,143.19 79.06,143.19 79.56,143.69 U22.C43
  L3_INT_1 w0.087: v2(73.15,138.43) 71.11,136.39 71.11,123.86 67.71,120.46 67.71,115.82 68.25,115.28 68.25,111.81 60.3,103.86 60.3,82.75 59.87,82.32 v1(59.87,80.8)
IFC_CS1_B: length 76.3
  TOP w0.118: v2(73.15,139.06) 73.48,139.06 73.66,139.24 73.66,141.76 73.96,142.06 75.39,142.06 R279.2 77.53,142.62 78.61,143.69 U22.C44
  L3_INT_1 w0.087: v1(60.67,78.4) 60.29,78.78 60.29,82.04 60.69,82.44 60.69,103.75 69.37,112.42 69.37,114.91 68.78,115.49 68.78,120.5 71.82,123.53 71.82,133.31 73.89,135.38 73.89,138.33 v2(73.15,139.06)
IFC_CS2_B: length 73.4
  TOP w0.118: v2(73.99,131.78) 73.99,133.05 R294.2 78.87,137.92 78.87,141.38 79.83,142.34 U22.B43
  L5_INT_2 w0.087: v2(73.99,131.78) 72.11,129.9 72.11,126.19 64.92,119 63.55,119 62.59,118.03 62.59,90.12 60.68,88.21 60.68,81.89 60.29,81.5 60.29,78.83 v1(59.87,78.4)
IFC_CS3_B: length 74.8
  TOP w0.118: U22.A42 79.88,140.75 79.88,137.92 R295.2 80.24,136.8 80.24,135.86 76.45,132.08 v2(74.93,132.08)
  L5_INT_2 w0.087: v1(59.07,79.2) 59.49,79.63 59.49,81.36 60.2,82.07 60.2,88.49 62.13,90.42 62.13,118.24 64.01,120.12 65.28,120.12 71.6,126.44 71.6,130.1 73.89,132.38 74.63,132.38 v2(74.93,132.08)
IFC_CS_B4: length 5.6
  TOP w0.102: U22.C41 82.23,143.29 82.23,142.43 81.89,142.09 81.67,142.09 81.44,141.86 81.44,141.38
  TOP w0.118: 81.44,141.38 81.44,140.85 80.9,140.31 TP15.1
IFC_CS_B5: length 6
  TOP w0.102: 81,141.27 81.22,141.5 81.22,142.09 U22.B41
  TOP w0.118: TP20.1 80.31,138.13 80.31,140.59 81,141.27
IFC_CS_B6: length 4.4
  TOP w0.118: TP21.1 81.66,138.05 81.66,139.32 81.83,139.49 U22.A41
IFC_CS_B7: length 5
  TOP w0.102: U22.C40 82.44,143.3 82.44,142.29 82.28,142.13
  TOP w0.118: 82.28,142.13 82.28,139.05 TP16.1
IFC_NAND_CS_B: length 49.5
  TOP w0.118: U38.C6 v2(100.49,87.02)
  L14_INT_6 w0.087: v2(100.49,87.02) 100.7,86.82 100.7,86.25 98.17,83.72 94.39,83.72 93.78,84.33 60.05,84.33 58.22,82.49 58.22,81.33 57.89,81.01 57.89,80.38 v1(58.27,80)
  BOTTOM w0.118: v2(100.49,87.02) 100.48,87.03 R524.2
IFC_NAND_RB_B: length 51.8
  TOP w0.118: U38.C8 v2(102.1,87.02)
  L14_INT_6 w0.087: v2(102.1,87.02) 101.43,87.68 100.36,87.68 99.94,87.26 99.94,86.37 97.88,84.31 94.68,84.31 93.9,85.09 59.97,85.09 57.1,82.22 57.1,81.17 v1(57.47,80.8)
  BOTTOM w0.118: v2(102.1,87.02) 102.49,87.41 R818.2
IFC_NAND_WE_B: length 49.9
  TOP w0.118: U38.C7 v2(101.29,87.02)
  L14_INT_6 w0.087: v2(101.29,87.02) 101.29,86 100.18,84.88 100.18,82.78 99.13,81.74 98.42,81.74 97.74,82.42 90.6,82.42 90.02,83.01 60.47,83.01 v1(58.27,80.8)
  BOTTOM w0.118: R525.2 101.47,87.2 v2(101.29,87.02)
IFC_NOR_CS_B: length 23.9
  TOP w0.118: U37.32 v2(78.95,75.55)
  L14_INT_6 w0.087: v1(58.27,79.2) 58.27,79.17 58.65,78.79 64.9,78.79 65.09,78.59 65.09,78.25 65.31,78.03 67.53,78.03 70.3,75.26 78.66,75.26 v2(78.95,75.55)
IFC_NOR_RB_B: length 36.9
  TOP w0.102: U27.M11 59.49,78.02 59.49,80.92
  TOP w0.118: 59.49,80.92 59.49,83.57 63.45,87.53 69.22,87.53 77.97,96.27 82.59,96.27 R5858.2 U37.17
IFC_NOR_WE_B: length 42.9
  TOP w0.102: 57.86,81.05 57.86,79.6 U27.P13
  TOP w0.118: 57.86,81.05 58.04,81.23 58.04,86.72 59.69,88.37 69.16,88.37 79.12,98.32 83.52,98.32 84.95,96.89 U37.13
IFC_OE_B: length 145.5
  TOP w0.102: U22.E42 80.44,146.09 78.52,146.09 78.32,145.88
  TOP w0.118: U37.34 v2(79.95,75.55) ; 78.32,145.88 77.6,145.16 76.52,145.16 76.01,144.65 73.79,144.65 v2(73.66,144.53) ; U38.D4 v2(98.1,86.22)
  L12_INT_5 w0.087: v2(98.1,86.22) 90.46,86.22 79.95,75.71 v2(79.95,75.55)
  L14_INT_6 w0.087: v2(98.1,86.22) 95.97,86.22 92.51,89.69 78.54,89.69 76.01,92.22 76.01,99.82 73.08,102.74 67.39,102.74 62.85,107.28 62.85,110.52 62.64,110.74 62.64,119.74 64.26,121.36 66.09,121.36 71.98,127.25 71.98,133.17 73.72,134.91 73.72,140.02 73.18,140.56 73.18,144.04 v2(73.66,144.53) ; v2(79.95,75.55) 79.52,75.98 70.42,75.98 67.79,78.61 67.01,78.61 66.84,78.78 66.16,78.78 65.84,79.1 65.84,79.36 65.57,79.63 61.04,79.63 v1(60.67,80)
IFC_RB0_B: length 81.5
  TOP w0.102: U22.F43 79.44,147.09 78,147.09 77.72,146.81
  TOP w0.118: v2(71.57,142.16) 72.11,142.7 72.11,144.37 R276.2 73.64,145.9 73.64,145.91 73.78,146.05 76.96,146.05 77.72,146.81
  L3_INT_1 w0.087: v1(59.87,77.6) 59.49,77.98 59.49,82.51 59.97,82.98 59.97,104.04 67.21,111.28 67.21,115.19 66.86,115.54 66.86,120.53 70.56,124.23 70.56,141.15 v2(71.57,142.16)
IFC_RB1_B: length 80.7
  TOP w0.102: U22.F42 80.53,146.4 80.44,146.3 78.67,146.3 78.66,146.3 78.36,146.3
  TOP w0.118: 78.36,146.3 78.31,146.3 77.55,145.54 R277.2 75.39,144.98 73.46,144.98 72.63,144.16 v2(72.63,142.67)
  L3_INT_1 w0.087: v1(59.07,80) 58.69,80.38 58.69,82.24 59.64,83.18 59.64,104.24 66.18,110.78 66.18,115.21 65.41,115.98 65.41,119.91 69.88,124.38 69.88,141.07 71.48,142.67 v2(72.63,142.67)
IFC_TE: length 84.4
  TOP w0.102: U22.G42 80.43,147.29 77.72,147.29
  TOP w0.118: 77.72,147.29 77.5,147.07 73.74,147.07 72.8,146.13 71.86,146.13 71.07,145.34 71.07,141.43 v2(71.37,141.12)
  L3_INT_1 w0.087: v1(60.67,80.8) 61.29,81.43 61.29,102.59 66.75,108.05 66.75,108.61 70.76,112.62 70.76,114.35 69.96,115.15 69.96,115.16 69.47,115.65 69.47,116.61 69.98,117.12 69.98,120.52 72.42,122.96 72.42,132.92 74.8,135.31 74.8,138.73 72.42,141.12 v2(71.37,141.12)
IFC_VBANK0: length 6.6
  TOP w0.118: U37.1 v2(90.95,95.25) ; U595.4 v2(89.7,99.38)
  L14_INT_6 w0.087: v2(89.7,99.38) 89.7,97.83 90.91,96.62 90.91,95.29 v2(90.95,95.25)
IFC_VBANK1: length 32
  TOP w0.118: U596.4 86.73,98.54 87.6,97.66 91.26,97.66 93.7,95.22 93.7,92.08 92.18,90.55 92.18,76.45 90.95,75.23 U37.56
IFC_VBANK2: length 33.6
  TOP w0.118: U598.4 83.72,99.38 86.07,97.03 91.03,97.03 92.99,95.07 92.99,92.25 91.59,90.86 91.59,76.69 90.45,75.55 U37.55
IFC_WE0_B: length 77.1
  TOP w0.118: U22.E44 78.64,145.69 77.66,144.72 v2(76.83,144.72)
  L5_INT_2 w0.087: v2(76.83,144.72) 75.67,143.55 75.67,134.98 71.09,130.4 71.09,127.15 65.35,121.41 64.08,121.41 61.67,119 61.67,90.63 59.72,88.67 59.72,82.4 58.67,81.36 58.67,78.8 v1(59.07,78.4)
IFC_WE2_B: length 81.1
  TOP w0.118: TP13.1 74.93,143.13 v2(76.83,143.13) 77.6,143.13 78.68,144.21 80.33,144.21 80.81,144.69 U22.D42
  L5_INT_2 w0.087: v2(76.83,143.13) 76.33,142.62 76.33,132.41 75.55,131.64 74.48,131.64 72.67,129.83 72.67,126.06 65.18,118.57 63.83,118.57 63.02,117.75 63.02,89.81 61.06,87.86 61.06,78 v1(60.67,77.6)
IFC_WE3_B: length 3.5
  TOP w0.118: U22.D44 78.65,144.69 77.72,143.76 TP14.1
IFC_WP_B: length 155.8
  TOP w0.118: U37.16 v2(83.45,92.85) ; U38.C3 v2(97.29,87.02) ; U22.F44 78.82,146.69 v3(78.21,146.69)
  L3_INT_1 w0.087: v3(78.21,146.69) 79.02,145.87 79.02,141.96 78.44,141.38 78.44,132.08 78.9,131.62 78.9,130.31 82.71,126.5 85.33,126.5 94.06,117.78 94.06,111.59 92.87,110.4 80.63,110.4 77.44,107.21 77.44,92.94 78.71,91.67 82.27,91.67 v2(83.45,92.85) ; v1(61.47,79.2) 61.84,78.83 61.84,70.3 62.91,69.23 70.8,69.23 82.5,80.92 87.33,80.92 93.8,87.4 96.91,87.4 v2(97.29,87.02)
  L12_INT_5 w0.087: v2(97.29,87.02) 97.29,88.13 94.84,90.58 84.89,90.58 83.45,92.01 v2(83.45,92.85)
INJ_DDRCLK: length 1.4
  TOP w0.118: U22.AL14 v3(108.33,172.2)
  BOTTOM w0.118: v3(108.33,172.2) 108.33,172.21 R698.2
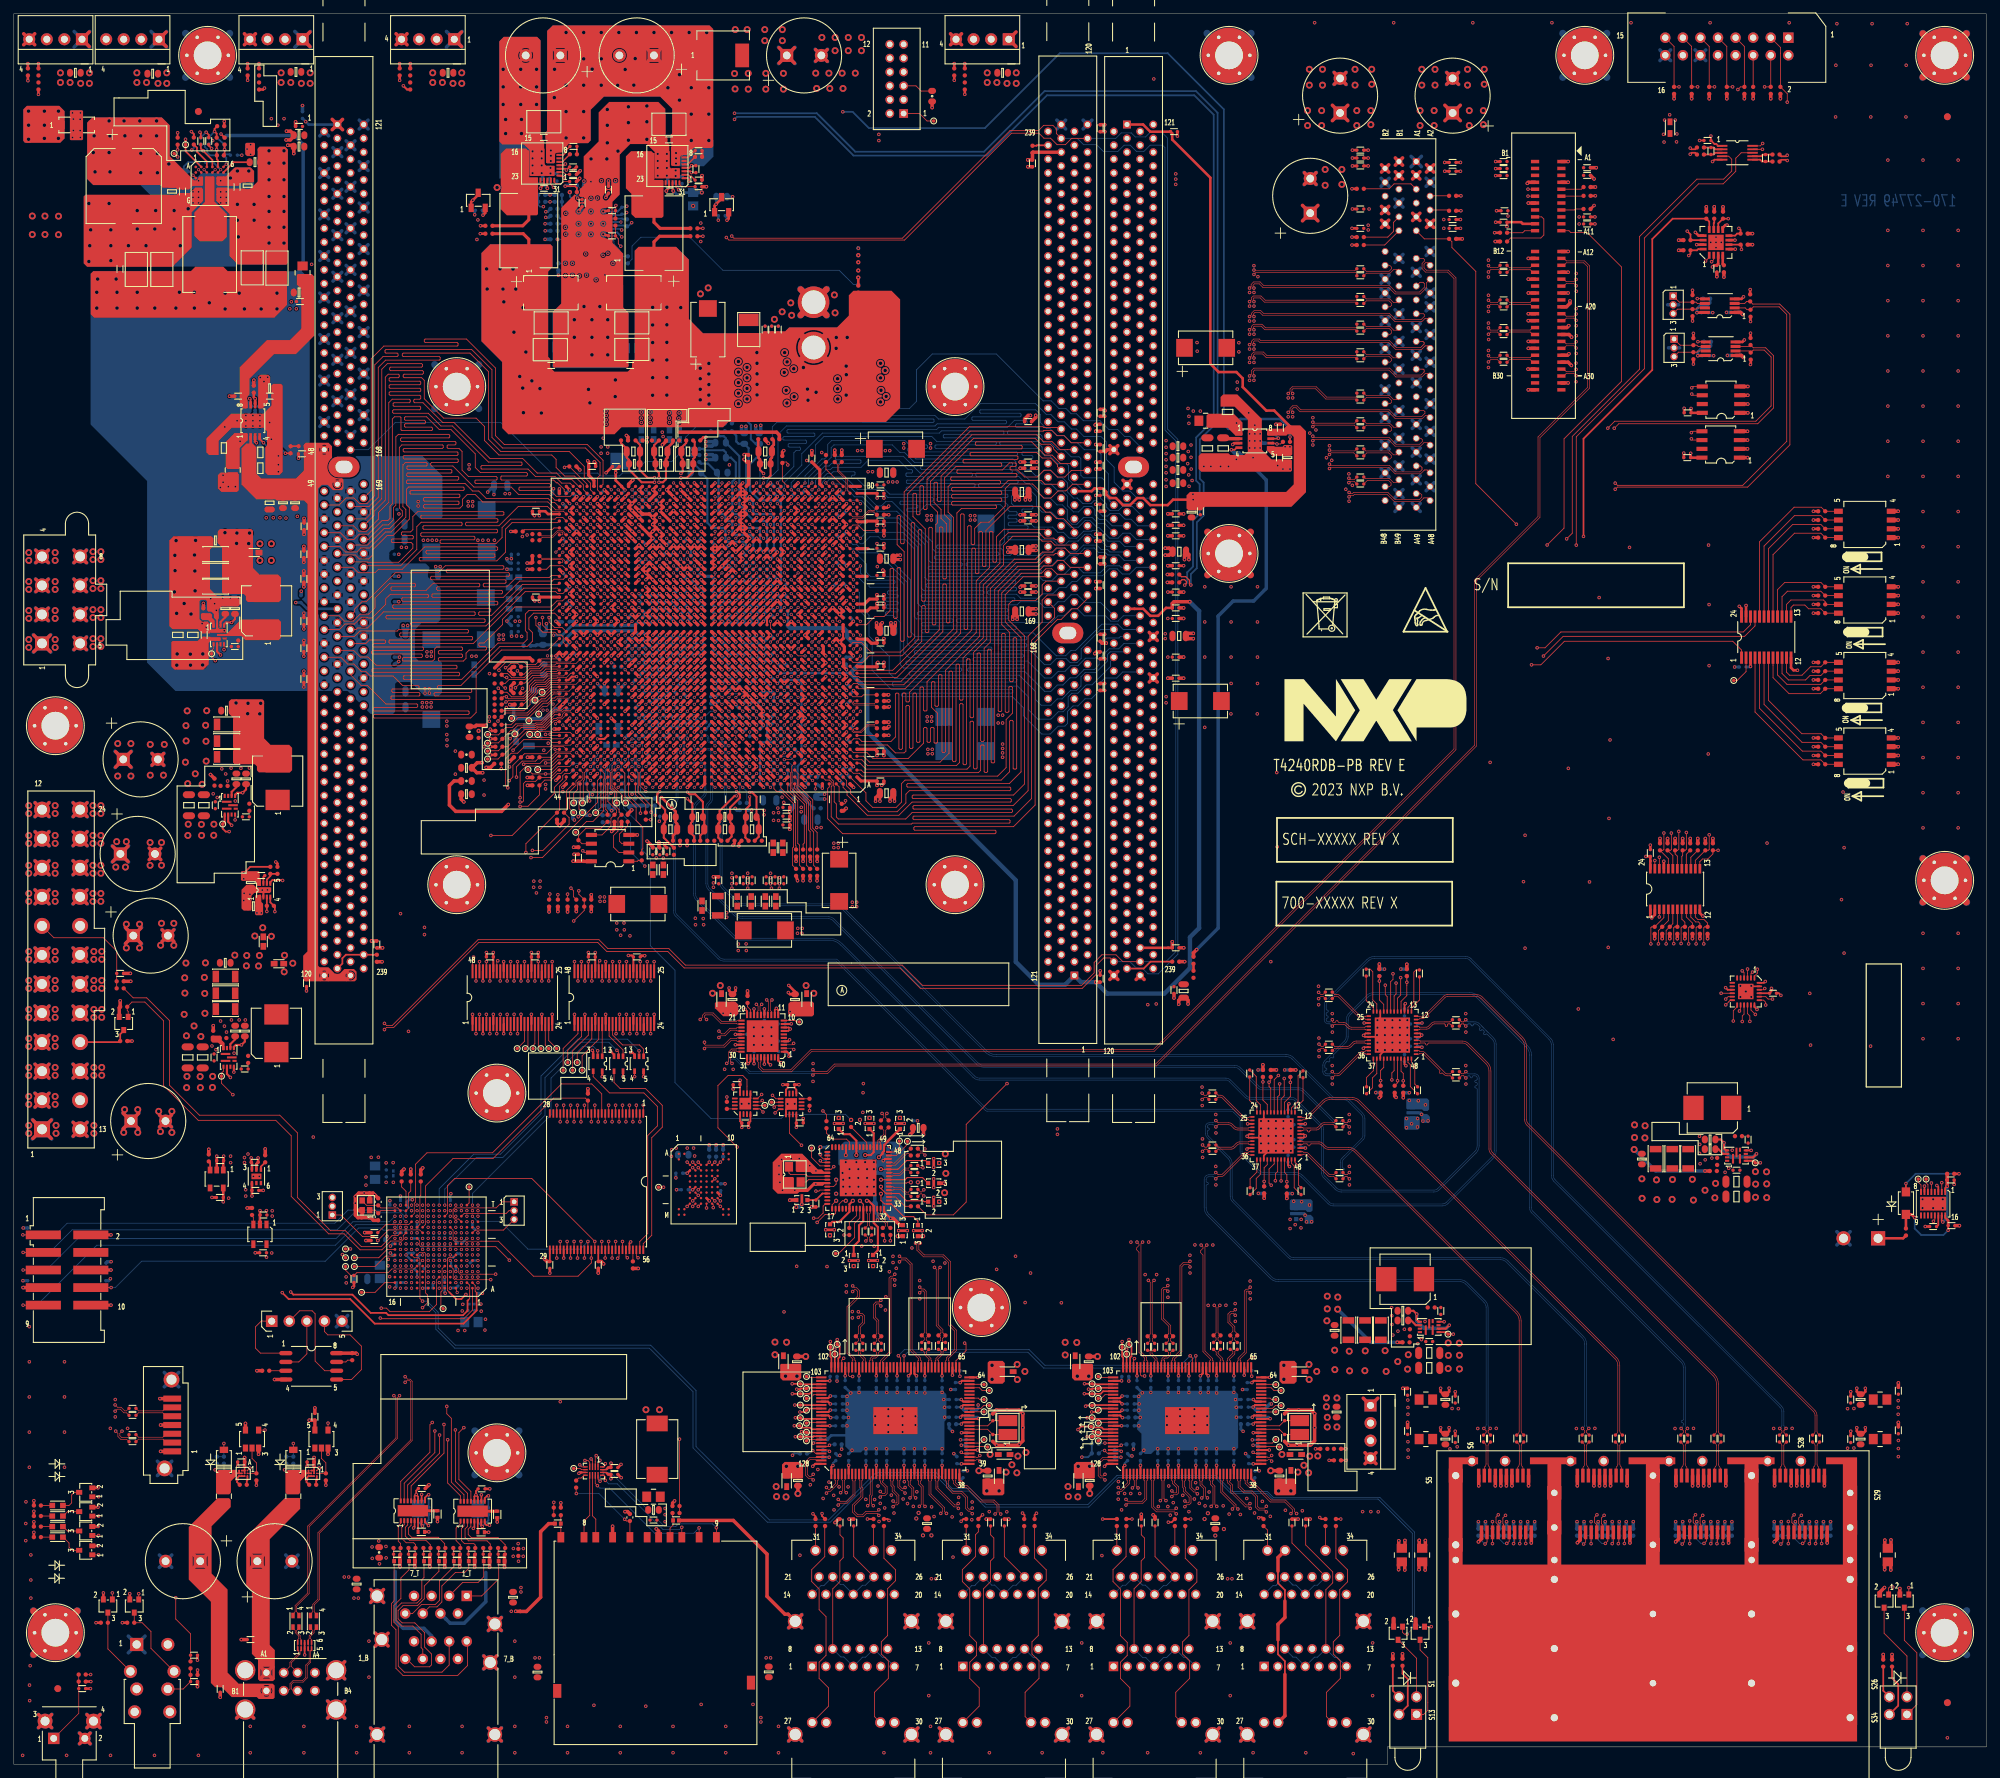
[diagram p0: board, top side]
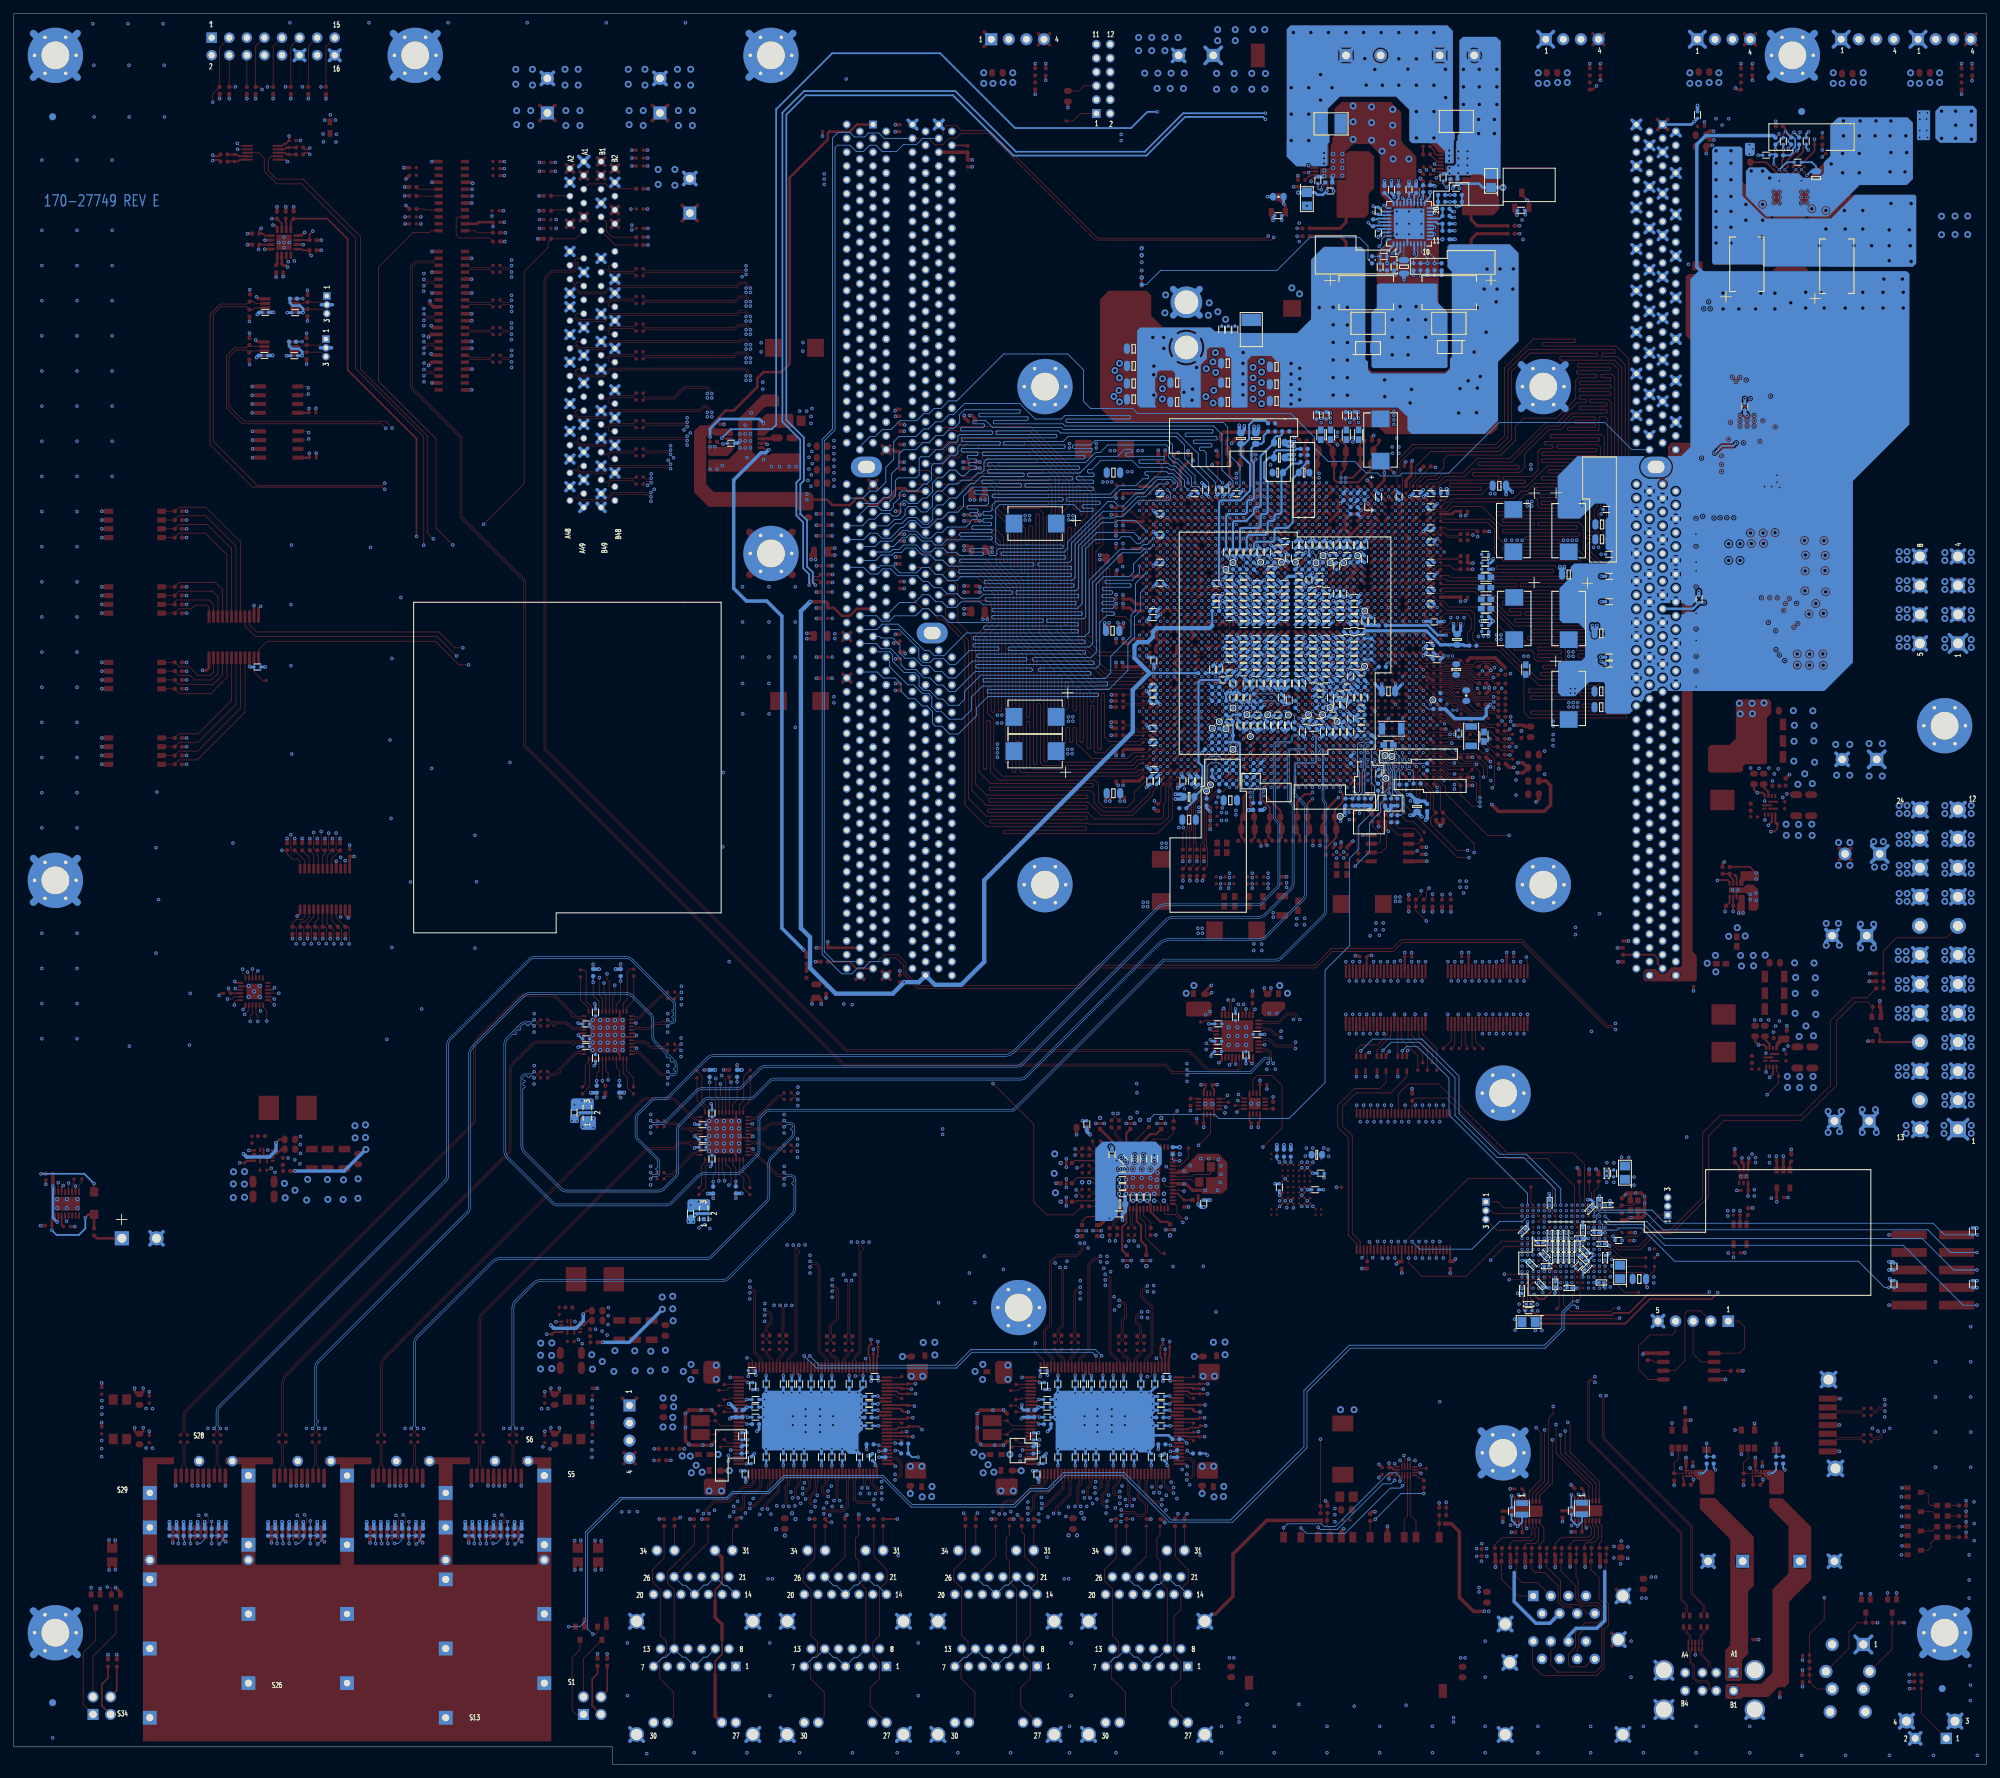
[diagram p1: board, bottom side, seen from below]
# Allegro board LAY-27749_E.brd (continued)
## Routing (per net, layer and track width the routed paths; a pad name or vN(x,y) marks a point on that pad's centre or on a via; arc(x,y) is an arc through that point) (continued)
INJ_SYSCLK: length 1.5
  TOP w0.118: U22.U34 88.33,158.19 v3(88.33,158.2)
  BOTTOM w0.118: R711.2 87.9,158.62 v3(88.33,158.2)
INT_PHY0_B: length 98.9
  TOP w0.118: U42.99 119.63,58.39 v2(119.91,58.67)
  L5_INT_2 w0.087: v1(57.47,68.8) 57.47,61.43 59.23,59.66 59.23,44.88 66.12,38 74.17,38 75.46,39.29 80.04,39.29 80.95,38.38 90.75,38.38 109.4,57.02 118.26,57.02 v2(119.91,58.67)
INT_PHY1_B: length 142.2
  TOP w0.118: U620.99 161.79,58.49 v2(161.93,58.62)
  L5_INT_2 w0.087: v2(161.93,58.62) 161.77,58.62 161.39,58.25 161.39,57.63 153.32,49.56 139.25,49.56 139.21,49.61 102.62,49.61 91.08,38.07 80.72,38.07 79.81,38.99 75.74,38.99 74.42,37.67 65.86,37.67 58.78,44.76 58.78,59.23 56.67,61.34 v1(56.67,68.8)
INT_RETIMER_B: length 223.4
  TOP w0.118: v2(199.12,98.9) 199.12,99.92 199.45,100.25 U622.43 ; v2(182.3,84.33) 182.3,85.34 182.62,85.67 U65.43
  L5_INT_2 w0.087: v2(199.12,98.9) 198.75,98.54 198.75,96.29 188.21,85.75 183.13,85.75 182.3,84.92 v2(182.3,84.33) 182.3,82.98 181.1,81.78 181.1,81.51 180.85,81.26 180.57,81.26 177.67,78.36 177.67,59.13 175.26,56.72 175.26,55.6 174.29,54.64 162.94,54.64 161.9,55.68 161.9,56.54 162.48,57.12 162.48,58.65 161.95,59.18 159.38,59.18 158.45,58.25 150.72,58.25 150.1,58.86 140.27,58.86 138.68,57.28 124.97,57.28 122.71,55.02 120.29,55.02 119.66,55.65 119.66,56.62 120.57,57.53 120.57,58.75 120.22,59.11 119.51,59.11 117.75,57.35 108.99,57.35 90.83,39.19 82.98,39.19 82.04,40.13 78.66,40.13 75.51,43.28 75.51,47.88 59.66,63.73 59.66,69.04 59.03,69.67 59.03,70.94 58.69,71.28 58.69,74.78 58.27,75.2 v1(58.27,75.2)
IRQ0_B: length 115.2
  TOP w0.102: U22.V43 79.43,158.29 78.49,158.29
  TOP w0.118: v2(71.02,155.55) 70.87,155.55 70.48,155.93 R254.2 70.99,156.21 71.56,156.78 73.85,156.78 74.79,157.72 76.31,157.72 76.89,158.29 78.49,158.29
  L14_INT_6 w0.087: v1(60.67,71.2) 60.4,71.2 60.02,71.58 58.7,71.58 57.9,70.78 54.62,70.78 52.09,73.31 52.09,81.05 53.11,82.07 53.11,84.12 57.76,88.77 57.76,128.27 69.95,140.46 69.95,144.73 70.59,145.36 70.59,146.43 72.95,148.79 72.95,155.28 73.08,155.41 73.08,155.91 72.77,156.21 71.68,156.21 v2(71.02,155.55)
IRQ1_B: length 110.8
  TOP w0.118: v2(71.22,157.06) 70.89,157.06 R253.2 70.65,157.63 71.35,157.63 71.95,157.04 73.72,157.04 74.72,158.03 76.12,158.03 76.71,158.62 78.76,158.62 U22.V44
  L14_INT_6 w0.087: v2(71.22,157.06) 73.47,157.06 74.19,156.34 74.19,154.89 73.53,154.23 73.53,148.62 71.15,146.23 71.15,143.28 70.45,142.58 70.45,140.35 58.32,128.22 58.32,86.11 55.24,83.03 55.24,81.33 55.47,81.1 55.47,80.16 56.24,79.39 56.24,74.3 56.56,73.98 60.82,73.98 61.04,73.76 61.04,72.38 v1(60.67,72)
IRQ2_B: length 118.4
  TOP w0.102: U22.U43 79.43,157.3 78.49,157.3
  TOP w0.118: v2(70,155.52) 70.48,155.04 R257.2 71.25,154.94 71.91,154.28 73.58,154.28 74.52,155.22 74.52,155.92 75.3,156.69 76.56,156.69 77.16,157.3 78.49,157.3
  L14_INT_6 w0.087: v1(59.87,69.6) 59.87,68.83 59.36,68.33 54.23,68.33 51.13,71.42 51.13,74.73 49.81,76.05 49.81,95.88 55.54,101.61 55.54,105.93 56.74,107.14 56.74,128.22 69.19,140.66 69.19,145.19 69.65,145.64 69.65,147.7 72.14,150.19 72.14,153.92 71.32,154.74 70.62,154.74 70,155.36 v2(70,155.52)
IRQ3_B: length 118.5
  TOP w0.102: U22.W42 80.44,159.3 78.45,159.3
  TOP w0.118: 78.45,159.3 76.45,159.3 75.78,158.62 R251.2 72.8,159.13 71.83,159.13 71.2,158.5 v2(71.04,158.5)
  L14_INT_6 w0.087: v2(71.04,158.5) 71.04,157.73 70.48,157.18 70.48,155.37 70.79,155.07 71.4,155.07 72.39,154.08 72.39,150.16 72.35,150.13 72.35,150.1 69.93,147.67 69.93,145.49 69.44,145.01 69.44,140.57 57.01,128.13 57.01,106.97 55.83,105.79 55.83,101.4 50.11,95.68 50.11,78.41 51.46,77.06 51.46,71.75 53.64,69.57 54.91,69.57 55.26,69.23 58.31,69.23 59.48,70.4 v1(59.87,70.4)
IRQ4_B: length 105.9
  TOP w0.118: v2(73.51,155.5) 73.19,155.18 73.19,154.85 R258.2 73.69,154.81 74.27,155.4 74.27,156.18 75.12,157.04 76.52,157.04 77.09,157.61 78.74,157.61 U22.U44
  L14_INT_6 w0.087: v2(73.51,155.5) 73.51,155.4 73.24,155.13 73.24,148.73 70.89,146.38 70.89,143.33 70.23,142.67 70.23,140.44 58.04,128.25 58.04,88.42 56.87,87.25 56.87,85.14 54.86,83.13 54.86,81.38 54.64,81.15 54.64,80.26 55.49,79.41 55.49,73.45 55.77,73.18 60.02,73.18 60.27,72.93 60.27,71.78 60.43,71.63 61.04,71.63 v1(61.47,71.2)
IRQ5_B: length 129.8
  TOP w0.102: U22.R42 80.23,155.09 78.61,155.09 78.49,154.97 78.16,154.97
  TOP w0.118: v2(69.96,150.77) 69.96,150.86 R266.2 71.04,151.94 74.17,151.94 76.21,153.99 76.77,153.99 77.75,154.97 78.16,154.97
  L14_INT_6 w0.087: v1(61.47,72) 62,72 62.64,71.36 62.64,70.96 62.92,70.69 62.92,70 62.51,69.6 62.51,68.66 62.79,68.38 62.79,67.77 60.43,65.41 52.15,65.41 49.68,67.87 49.68,72.59 47.68,74.59 47.68,96.88 52.45,101.65 52.45,128.85 66.62,143.03 66.62,147.83 67.84,149.05 67.84,151.51 68.45,152.12 69.39,152.12 70.05,151.46 70.05,150.86 v2(69.96,150.77)
IRQ6_B: length 132
  TOP w0.102: U27.C8 61.09,70.02 61.09,68.65 61.09,68.64 61.09,68.43 ; 78.18,158.88 78.38,159.07 78.55,159.07 78.56,159.09 81.22,159.09 U22.W41
  TOP w0.118: 61.09,68.43 61.09,66.45 60.05,65.41 54.36,65.41 53.85,65.91 v2(53.09,65.91) ; 78.18,158.88 76.45,158.88 75.92,158.34 74.52,158.34 73.72,157.54 R252.2 72.79,158.03 v2(72.77,158.03)
  L14_INT_6 w0.087: v2(53.09,65.91) 52.15,65.91 49.96,68.1 49.96,73.86 47.99,75.84 47.99,96.73 52.73,101.47 52.73,128.55 66.93,142.75 66.93,147.68 68.43,149.17 69.29,149.17 70.66,150.55 70.66,151.41 69.51,152.57 69.51,156.71 70.54,157.73 70.54,158.67 70.89,159.03 71.88,159.03 72.77,158.14 v2(72.77,158.03)
IRQ7_B: length 117.6
  TOP w0.102: U22.T42 80.44,156.3 78.67,156.3 78.66,156.31 78.61,156.31 78.56,156.36 78.28,156.36
  TOP w0.118: v2(71.17,152.73) 71.32,152.58 72.8,152.58 R263.2 73.63,153.16 75.36,154.89 75.36,155.42 75.72,155.78 76.91,155.78 77.5,156.36 78.28,156.36
  L14_INT_6 w0.087: v2(71.17,152.73) 71.88,152.02 71.88,150.32 69.34,147.78 69.34,145.78 68.99,145.42 68.99,145.29 68.97,145.28 68.97,141.97 55.32,128.32 55.32,102.26 48.9,95.83 48.9,76.4 50.77,74.52 50.77,70.87 53.62,68.02 60.02,68.02 61.06,69.06 61.06,69.74 60.67,70.13 v1(60.67,70.4)
IRQ8_B: length 117.4
  TOP w0.118: R262.2 70.66,153.16 71.04,153.54 v2(71.12,153.54) 71.27,153.54 71.45,153.72 73.77,153.72 75.08,155.04 75.08,155.57 75.59,156.08 76.84,156.08 77.42,156.67 78.8,156.67 U22.T44
  L14_INT_6 w0.087: v2(71.12,153.54) 70.97,153.54 70.75,153.32 70.75,152.55 71.42,151.87 71.42,150.32 69.74,148.63 68.71,148.63 68.35,148.28 68.35,145.31 68.76,144.91 68.76,142.14 55.11,128.49 55.11,102.73 48.59,96.21 48.59,76.25 50.5,74.35 50.5,70.61 53.42,67.69 60.36,67.69 v1(61.47,68.8)
IRQ9_B: length 113.7
  TOP w0.102: 78.42,157.92 78.59,158.09 80.22,158.09 U22.V42
  TOP w0.118: v2(72.48,155.57) 73.16,156.26 R255.2 73.84,156.26 74.93,157.35 76.45,157.35 77.03,157.92 78.42,157.92
  L14_INT_6 w0.087: v1(61.47,69.6) 61.47,70.41 61.06,70.82 59.33,70.82 58.52,70 53.9,70 51.81,72.09 51.81,81.25 52.81,82.24 52.81,84.34 56.13,87.66 56.13,105.69 57.23,106.78 57.23,128.04 69.7,140.52 69.7,144.86 70.21,145.36 70.21,147.57 72.67,150.04 72.67,155.38 v2(72.48,155.57)
IRQ10_B: length 130.4
  TOP w0.118: v2(70.1,158.12) 70.1,158.29 71.2,159.38 73.66,159.38 74.12,158.93 75.36,158.93 R250.2 76.2,159.77 78.76,159.77 U22.W44
  L14_INT_6 w0.087: v1(63.07,71.2) 63.35,70.92 63.35,69.31 63.58,69.09 63.58,68.25 60.43,65.1 51.79,65.1 49.4,67.49 49.4,72.49 47.4,74.49 47.4,97.03 52.17,101.8 52.17,128.93 66.32,143.08 66.32,147.9 67.58,149.17 67.58,155.59 v2(70.1,158.12)
IRQ11_B: length 126.3
  TOP w0.102: U22.U42 80.48,157.69 79.88,157.1 78.61,157.1 78.49,156.97
  TOP w0.118: R260.2 70.79,154.36 71.09,154.36 v2(71.17,154.28) 71.45,154 73.69,154 74.8,155.12 74.8,155.77 75.43,156.39 76.76,156.39 77.34,156.97 78.49,156.97
  L14_INT_6 w0.087: v2(71.17,154.28) 70.79,154.28 70.43,153.92 70.43,152.4 71.02,151.82 71.02,150.37 69.52,148.87 68.55,148.87 67.23,147.55 67.23,142.72 54.85,130.34 54.85,103.09 48.29,96.52 48.29,76.02 50.19,74.12 50.19,68.61 52.32,66.47 59.79,66.47 62.27,68.95 62.27,69.76 62.64,70.14 62.64,70.58 62.27,70.96 v1(62.27,71.2)
IRQ_CLOCK_B: length 67.8
  TOP w0.102: U27.K12 58.65,75.62 58.65,74.96 58.8,74.8 67.41,74.8
  TOP w0.118: v2(115.9,82.83) 116.33,82.83 116.48,82.98 U36.12 ; 67.41,74.8 69.65,74.8 v2(71.6,72.85)
  L12_INT_5 w0.087: v2(71.6,72.85) 73.99,70.46 86.33,70.46 88.01,72.14 88.01,73.33 88.34,73.66 102.39,73.66 110.74,82.02 115.09,82.02 v2(115.9,82.83)
IRQ_FAN_B: length 310.9
  TOP w0.254: v2(226.82,177.47) 226.82,191.59 236.75,201.52 236.75,220.45 239.7,223.39 R5892.2 244.99,222.97 U105.12
  L3_INT_1 w0.254: v2(226.82,177.47) 225.96,177.47 225.04,176.56 225.04,149.83 174.19,98.98 169.14,98.98 160.05,89.89 131.22,89.89 128.46,87.13 128.46,75.82 126.99,74.35 109.3,74.35 102.57,67.62 75.39,67.62 71.5,63.73 58.62,63.73 53.31,69.04 53.31,74.73 54.59,76 v1(55.07,76)
IRQ_OUT_B: length 13.7
  TOP w0.102: U22.T41 81.23,156.09 78.56,156.09 78.53,156.06
  TOP w0.118: R265.2 73.71,152.27 74.59,153.15 74.59,153.76 75.67,154.83 75.67,155.14 76,155.47 76.99,155.47 77.57,156.06 78.53,156.06
IRQ_RTC_B: length 232.8
  TOP w0.118: v2(277.38,78.48) 277.59,78.68 U16.13
  L12_INT_5 w0.087: v1(64.67,70.4) 65.21,69.86 65.21,69.33 65.35,69.19 65.63,69.19 67.74,67.08 114.16,67.08 123.67,57.58 139.78,57.58 140.74,58.54 147.72,58.54 150.99,61.81 162.14,61.81 163.32,60.64 195.69,60.64 196.55,61.49 199.92,61.49 200.53,62.1 203.78,62.1 206.3,59.59 206.3,58.6 206.76,58.14 210.52,58.14 219.96,67.59 245.87,67.59 256.76,78.48 v2(277.38,78.48)
ISOSDHC_CLK: length 1.7
  TOP w0.118: U45.8 82.38,41.77 81.97,41.36 81.61,41.36 R614.1
ISOSDHC_CMD: length 16.6
  TOP w0.118: v2(85.47,41.02) 85.47,41.53 85.23,41.77 U45.13 ; CN3.2 v2(96.52,34.24)
  BOTTOM w0.118: v2(96.52,34.24) 96.21,33.92 93.79,33.92 87.2,40.51 85.98,40.51 v2(85.47,41.02)
ISOSDHC_DAT0: length 9.1
  TOP w0.118: U45.10 83.62,35.89 84.09,35.42 CN3.7
ISOSDHC_DAT1: length 9.3
  TOP w0.118: U45.9 83.22,35.97 82.39,35.15 CN3.8
ISOSDHC_DAT2: length 23.6
  TOP w0.118: v2(84.71,40.89) 84.42,41.19 U45.12 ; CN3.9 v2(101.52,34.17)
  BOTTOM w0.118: v2(101.52,34.17) 100.94,34.75 96.04,34.75 95.66,34.37 94.03,34.37 86.28,42.11 85.29,42.11 84.71,41.53 v2(84.71,40.89)
ISOSDHC_DAT3: length 20.8
  TOP w0.118: CN3.1 v2(99.02,34.15) ; U45.11 84.02,40.57 v2(84.33,40.26)
  BOTTOM w0.118: v2(99.02,34.15) 98.24,33.38 92.61,33.38 86.08,39.9 84.68,39.9 v2(84.33,40.26)
LED0: length 196.7
  TOP w0.102: U27.G13 57.87,73.2 58.47,73.2 58.67,73 58.67,68.5
  TOP w0.118: v2(59.05,66.93) 58.67,67.31 58.67,68.5 ; Q3.1 v2(204.83,19.87)
  BOTTOM w0.118: v2(59.05,66.93) 59.72,66.93 61.32,65.33 61.32,63.04 63.8,60.55 92.03,60.55 98.58,54 98.58,45.9 109.17,35.31 117.73,35.31 124.56,42.14 133.3,42.14 135.61,39.83 138.2,39.83 140.51,37.52 155.19,37.52 159.41,41.73 173.71,41.73 176.02,39.42 181.13,39.42 181.99,38.56 197.38,38.56 202.41,33.53 202.41,20.65 203.19,19.87 v2(204.83,19.87)
LED1: length 198.3
  TOP w0.102: U27.G12 58.65,73.98 59.34,73.98 59.49,73.84 59.49,68.5
  TOP w0.118: v2(59.06,65.99) 59.77,66.7 59.77,67.84 59.49,68.12 59.49,68.5 ; Q4.1 200.67,19.05 200.93,18.8 v2(201.32,18.8)
  BOTTOM w0.118: v2(201.32,18.8) 202.08,19.56 202.08,33.38 197.14,38.32 181.89,38.32 181.07,39.14 175.87,39.14 173.58,41.43 159.59,41.43 155.32,37.16 140.36,37.16 138.05,39.47 135.43,39.47 133.15,41.76 124.76,41.76 117.98,34.98 108.89,34.98 98.15,45.72 98.15,53.82 91.85,60.12 63.73,60.12 60.99,62.87 60.99,65.23 59.84,66.37 59.44,66.37 v2(59.06,65.99)
LED2: length 271.4
  TOP w0.118: Q5.1 v2(273.82,25.51)
  L5_INT_2 w0.087: v2(273.82,25.51) 273.82,29.35 271.73,31.45 265.18,31.45 263.14,33.48 224.84,33.48 223.34,31.98 220.8,31.98 219.28,33.5 202.29,33.5 188.87,46.92 180.58,46.92 180.13,47.37 155.96,47.37 155.4,47.93 148.95,47.93 148.41,47.4 114.81,47.4 114.15,46.74 101.12,46.74 91.8,37.41 80.29,37.41 79.34,38.37 76.24,38.37 74.83,36.96 65.41,36.96 57.66,44.7 57.66,58.6 55.44,60.81 55.44,69.11 56.31,69.98 57.66,69.98 57.89,70.21 57.89,73.15 56.67,74.37 v1(56.67,74.4)
LED3: length 278
  TOP w0.118: v2(271.5,25.6) 271.06,25.6 270.9,25.45 Q6.1
  L5_INT_2 w0.087: v2(271.5,25.6) 271.5,24.92 271.86,24.56 273.84,24.56 274.47,25.2 274.47,29.35 271.87,31.95 265.35,31.95 263.42,33.88 224.64,33.88 223.22,32.46 220.9,32.46 219.3,34.06 203.12,34.06 189.85,47.33 180.95,47.33 179.77,48.51 164.31,48.51 163.75,47.96 157.43,47.96 156.32,49.07 148.33,49.07 147.19,47.93 138.4,47.93 137.85,48.49 113.36,48.49 113,48.13 101.78,48.13 91.39,37.74 80.49,37.74 79.55,38.68 76.05,38.68 74.65,37.29 65.68,37.29 58.22,44.75 58.22,59.16 56.29,61.09 56.29,68.99 56.52,69.22 58.15,69.22 58.7,69.76 58.7,70.71 58.24,71.17 58.24,73.63 v1(57.47,74.4)
LED4: length 72.4
  TOP w0.118: Q7.1 v2(12.24,30.26)
  L12_INT_5 w0.087: v2(12.24,30.26) 19.52,37.54 24.1,37.54 27.61,41.05 27.61,45.8 34.09,52.27 41.63,52.27 51.59,62.23 51.59,71.91 54.03,74.35 54.81,74.35 55.24,74.78 56.24,74.78 v1(56.67,75.2)
LED5: length 72.4
  TOP w0.118: Q8.1 v2(12.24,33.06)
  L12_INT_5 w0.087: v2(12.24,33.06) 17.16,37.97 23.93,37.97 27.25,41.3 27.25,45.95 33.93,52.63 41.27,52.63 51,62.36 51,72.24 54.34,75.58 57.09,75.58 v1(57.47,75.2)
LED6: length 69.6
  TOP w0.118: Q9.1 v2(12.24,35.85)
  L12_INT_5 w0.087: v1(55.87,76) 55.49,76.38 54.66,76.38 50.52,72.24 50.52,62.92 40.64,53.04 33.73,53.04 26.8,46.1 26.8,41.61 23.47,38.28 14.67,38.28 v2(12.24,35.85)
LED7: length 70.6
  TOP w0.118: Q10.1 v2(12.24,38.65)
  L12_INT_5 w0.087: v2(12.24,38.65) 23.13,38.65 26.26,41.78 26.26,46.23 33.48,53.44 40.13,53.44 50.16,63.47 50.16,74.09 53.26,77.19 55.48,77.19 v1(56.67,76)
LP_TMP_DETECT_B: length 22.9
  TOP w0.118: v3(95.33,156.2) U22.T27
  L14_INT_6 w0.087: v2(93.27,136.3) 94.77,137.79 94.77,155.63 v3(95.33,156.2)
  BOTTOM w0.118: v2(93.27,136.3) 93.34,136.37 TP206.1 ; v3(95.33,156.2) 95.23,156.09 R717.1
LRST_BUTTON_B: length 10.7
  TOP w0.102: SW6.1 9.38,7.34 C522.1 9.38,11.35 9.37,11.36 R671.2 R669.1
LV_TACH1: length 237.8
  TOP w0.254: v2(249.64,218.95) 249.64,219.51 R5698.1 U105.6
  TOP w0.381: R5691.1 v2(188.09,45.58)
  L14_INT_6 w0.254: v2(188.09,45.58) 188.97,46.46 191.85,46.46 192.7,47.31 192.7,53.55 194.12,54.97 198.18,54.97 199.12,55.91 243.49,55.91 256.55,68.97 256.55,212.04 v2(249.64,218.95)
LV_TACH2: length 143.8
  TOP w0.254: v2(249.26,222) 249.52,221.74 R5699.1 249.01,221.23 248.71,220.94 U105.8
  TOP w0.381: R5692.1 v2(137.41,241.36)
  L3_INT_1 w0.254: v2(249.26,222) 249.01,221.74 244.85,221.74 243.96,220.85 241.73,220.85 241.15,221.44 241.15,223.42 217.14,247.42 186.03,247.42 179.1,240.49 178.82,240.49 178.74,240.41 172.87,240.41 164.56,248.72 148.08,248.72 145.97,246.61 135.61,246.61 135.08,246.08 135.08,242.82 136.54,241.36 v2(137.41,241.36)
LV_TACH3: length 238.1
  TOP w0.254: v2(247.74,223.39) R5700.1 246.29,222.7 U105.10
  TOP w0.381: R5693.1 36.02,242.06 v2(36.22,242.27)
  L3_INT_1 w0.254: v2(36.22,242.27) 36.22,243.84 39.67,247.29 66.19,247.29 67.23,248.34 114.15,248.34 116.27,250.46 164.98,250.46 173.5,241.94 178.1,241.94 185.31,249.14 217.59,249.14 236.98,229.74 237.22,229.74 237.45,229.51 244.37,229.51 247.75,226.14 247.75,223.41 v2(247.74,223.39)
LV_TACH4: length 217.6
  TOP w0.254: v2(241.81,221.59) 242.28,221.12 R5701.1 U105.14
  TOP w0.305: v2(56.29,242.6) 56.82,242.06 R5694.1
  L3_INT_1 w0.254: v2(241.81,221.59) 241.81,223.48 217.33,247.95 185.84,247.95 185.84,247.95 185.67,247.95 178.79,241.07 178.74,241.07 178.72,241.04 178.65,241.04 178.53,240.92 173.08,240.92 164.65,249.35 147.8,249.35 145.75,247.29 135.1,247.29 134.57,246.76 131.83,246.76 130.99,247.6 126.24,247.6 121.89,243.26 103.63,243.26 100.84,246.05 95.02,246.05 90.75,241.78 78.97,241.78 77.52,243.23 68.73,243.23 66.19,245.77 59.46,245.77 v2(56.29,242.6)
LV_TACH5: length 276.5
  TOP w0.254: v2(242.02,218.06) 242.28,218.31 R5702.1 243.23,218.82 243.4,218.99 U105.16
  TOP w0.381: R5695.1 v2(3.56,241.36)
  L3_INT_1 w0.254: v2(242.02,218.06) 241.8,218.29 236.35,218.29 233.78,220.85 233.78,228.54 216.45,245.87 186.92,245.87 180.03,238.99 179.84,238.99 179.82,238.97 179.45,238.97 179.37,238.89 172.24,238.89 164.16,246.96 150.01,246.96 142.52,239.47 133.63,239.47 129.49,243.61 126.01,243.61 122.58,240.18 103.81,240.18 100.71,243.28 97.36,243.28 92.35,238.28 84.07,238.28 82.3,236.5 68.22,236.5 63.73,240.99 3.93,240.99 v2(3.56,241.36)
M1_MA0: length 96.1
  TOP w0.118: J6.188 149.01,185 148.46,185.55 143.69,185.55 142.67,184.53 135.64,184.53 135.51,184.4 135.51,184.15 135.64,184.02 142.62,184.02 142.75,183.9 142.75,183.64 142.62,183.52 135.64,183.52 135.51,183.39 135.51,183.13 135.64,183.01 142.62,183.01 142.75,182.88 142.75,182.63 142.62,182.5 135.64,182.5 135.51,182.37 135.51,182.12 135.64,181.99 141.87,181.99 142,181.86 142,181.61 141.87,181.48 136.91,181.48 136.27,180.85 136.27,163.7 128.59,156.02 122.1,156.02 121.91,156.21 121.35,156.21 U22.R2
M1_MA1: length 96
  TOP w0.118: U22.G1 122.2,147.32 126.24,147.32 127.38,146.18 128.65,146.18 128.91,146.43 128.91,152.91 129.03,153.04 129.29,153.04 129.41,152.91 129.41,146.94 129.54,146.81 129.79,146.81 129.92,146.94 129.92,154.69 130.05,154.81 130.3,154.81 130.43,154.69 130.43,147.83 130.56,147.7 130.81,147.7 130.94,147.83 130.94,155.58 131.06,155.7 131.32,155.7 131.44,155.58 131.44,152.36 131.57,152.24 131.83,152.24 131.95,152.36 131.95,156.46 139.06,163.58 139.06,171.04 140.97,172.95 140.97,178.05 141.1,178.18 141.35,178.18 141.48,178.05 141.48,173.86 141.6,173.74 141.86,173.74 141.99,173.86 141.99,177.42 143.07,178.5 148.95,178.5 J6.181
M1_MA2: length 96.1
  TOP w0.118: U22.G2 121.34,148.21 121.34,148.21 122.15,148.21 122.53,147.83 126.75,147.83 127.38,148.46 127.38,154.69 127.51,154.81 127.76,154.81 127.89,154.69 127.89,146.81 128.02,146.69 128.27,146.69 128.4,146.81 128.4,154.7 128.52,154.83 128.78,154.83 128.91,154.7 128.91,153.67 129.03,153.54 129.29,153.54 129.41,153.67 129.41,154.94 138.43,163.96 138.43,175.64 138.56,175.77 138.81,175.77 138.94,175.64 138.94,172.21 139.06,172.09 139.32,172.09 139.45,172.21 139.45,178.06 139.57,178.19 139.83,178.19 139.95,178.06 139.95,173.23 140.08,173.1 140.34,173.1 140.46,173.23 140.46,178.31 143.97,181.81 148.26,181.81 149.1,180.98 149.73,180.98 150.67,180.04 151.69,180.04 153.25,178.47 J6.61
M1_MA3: length 96
  TOP w0.118: J6.180 150.48,177 150.27,177.22 148.92,177.22 148.15,177.99 143.7,177.99 142.49,176.78 142.49,173.61 139.57,170.69 139.57,163.07 134.62,158.12 134.62,146.36 134.49,146.23 134.24,146.23 134.11,146.36 134.11,157.35 133.99,157.48 133.73,157.48 133.6,157.35 133.6,153.04 133.48,152.91 133.22,152.91 133.1,153.04 133.1,156.34 132.97,156.46 132.72,156.46 132.59,156.34 132.59,152.78 133.48,151.89 133.48,147.7 133.35,147.57 133.1,147.57 132.97,147.7 132.97,149.73 132.84,149.86 132.59,149.86 132.46,149.73 132.46,147.83 132.33,147.7 132.08,147.7 131.95,147.83 131.95,149.71 131.83,149.83 131.57,149.83 131.44,149.71 131.44,147.57 129.22,145.35 124.14,145.35 123.29,146.2 121.32,146.2 U22.F2
M1_MA4: length 96.1
  TOP w0.118: J6.59 153.03,176.22 150.43,176.22 149.86,176.78 148.59,176.78 147.89,177.48 144.34,177.48 143,176.15 143,173.36 140.08,170.43 140.08,162.81 137.16,159.89 137.16,153.92 137.03,153.8 136.78,153.8 136.65,153.92 136.65,158.88 136.53,159 136.27,159 136.14,158.88 136.14,145.03 136.02,144.91 135.76,144.91 135.64,145.03 135.64,157.86 135.51,157.99 135.25,157.99 135.13,157.86 135.13,146.13 133.85,144.84 123.63,144.84 122.78,145.7 122.78,145.69 U22.E1
M1_MA5: length 96.1
  TOP w0.118: U22.E2 121.34,145.19 122.53,145.19 123.38,144.34 136.21,144.34 136.65,144.78 136.65,153.16 136.78,153.29 137.03,153.29 137.16,153.16 137.16,144.59 137.29,144.46 137.54,144.46 137.67,144.59 137.67,159.64 137.79,159.77 138.05,159.77 138.18,159.64 138.18,151.38 138.3,151.26 138.56,151.26 138.68,151.38 138.68,160.7 140.59,162.6 140.59,170.18 144.58,174.18 147.61,174.18 148.38,174.95 148.64,175.21 150.06,175.21 150.64,175.79 151.87,175.79 152.66,175 154.18,175 J6.58
M1_MA6: length 96
  TOP w0.118: U22.D1 122.26,144.69 122.26,144.7 123.13,143.83 137.73,143.83 138.18,144.27 138.18,150.62 138.3,150.75 138.56,150.75 138.68,150.62 138.68,143.99 138.81,143.87 139.06,143.87 139.19,143.99 139.19,160.48 139.32,160.61 139.57,160.61 139.7,160.48 139.7,147.96 139.83,147.83 140.08,147.83 140.21,147.96 140.21,161.29 141.1,162.18 141.1,169.93 144.84,173.67 147.81,173.67 148.93,174.78 150.27,174.78 150.49,175 J6.178
M1_MA7: length 96
  TOP w0.118: J6.56 155.15,173 152.63,173 151.64,173.99 150.85,173.99 150.08,173.22 148.83,173.22 148.27,172.65 145.35,172.65 142.24,169.55 142.24,152.27 142.37,152.15 142.62,152.15 142.75,152.27 142.75,163.32 142.88,163.45 143.13,163.45 143.26,163.32 143.26,152.16 143.38,152.03 143.64,152.03 143.79,152.18 143.79,155.65 143.92,155.78 144.17,155.78 144.3,155.65 144.3,151.92 143.38,151 143.38,144.04 142.15,142.81 122.59,142.81 122.17,143.23 121.29,143.23 U22.C2
M1_MA8: length 96
  TOP w0.118: J6.177 148.85,174 148.01,173.16 145.09,173.16 141.73,169.8 141.73,144.86 141.6,144.73 141.35,144.73 141.22,144.86 141.22,161.04 141.1,161.16 140.84,161.16 140.72,161.04 140.72,143.47 140.59,143.35 140.34,143.35 140.21,143.47 140.21,147.19 140.08,147.32 139.83,147.32 139.7,147.19 139.7,143.64 139.38,143.32 122.82,143.32 122.45,143.69 U22.C1
M1_MA9: length 96
  TOP w0.118: J6.175 149.09,171.64 145.85,171.64 143.26,169.04 143.26,165.1 145.54,162.81 145.54,143.43 143.84,141.73 129.16,141.73 129.03,141.61 129.03,141.35 129.16,141.22 143.93,141.22 144.06,141.1 144.06,140.84 143.93,140.72 129.41,140.72 128.91,140.21 128.91,138.94 127.64,137.67 123.53,137.67 120.9,140.29 120.9,140.84 120.34,141.41 120.34,142.19 U22.B3
M1_MA10: length 96
  TOP w0.118: J6.70 152.81,187 151.87,186.06 150.8,186.06 149.83,187.02 148.84,187.02 147.88,186.06 146.05,186.06 145.03,187.07 144.08,187.07 143.95,187.2 143.95,187.45 144.08,187.58 144.72,187.58 144.84,187.71 144.84,187.96 144.72,188.09 143.87,188.09 142.85,187.07 136.4,187.07 136.27,186.94 136.27,186.69 136.4,186.56 144.82,186.56 144.95,186.44 144.95,186.18 144.82,186.06 135.51,186.06 135.38,185.93 135.38,185.67 135.51,185.55 142.44,185.55 142.57,185.42 142.57,185.17 142.44,185.04 135.38,185.04 135,184.66 135,180.98 135.76,180.21 135.76,164.08 128.21,156.53 122,156.53 U22.T1
M1_MA11: length 96.1
  TOP w0.118: U22.B2 121.16,142.37 123.13,140.4 123.13,139.26 124.08,138.3 127.51,138.3 128.27,139.07 128.27,141.73 128.78,142.24 142.67,142.24 143.89,143.46 143.89,150.75 144.02,150.88 144.27,150.88 144.4,150.75 144.4,143.96 144.53,143.83 144.79,143.83 144.91,143.96 144.91,162.69 144.79,162.81 144.53,162.81 144.4,162.69 144.4,156.59 144.28,156.46 144.02,156.46 143.9,156.59 143.9,163.58 142.75,164.73 142.75,169.29 145.6,172.14 148.49,172.14 149.13,172.78 149.98,172.78 150.76,172 153.25,172 J6.55
M1_MA12: length 96.2
  TOP w0.118: U22.A3 119.83,141.18 120.4,140.61 120.4,140.08 123.32,137.16 127.89,137.16 129.79,139.07 144.01,139.07 144.13,139.19 144.13,139.45 144.01,139.57 129.93,139.57 129.81,139.69 129.81,139.95 129.94,140.08 144.45,140.08 146.05,141.68 146.05,163.07 143.76,165.35 143.76,167.67 144.31,168.21 147.66,168.21 148.59,169.14 148.59,170.43 149.16,171 J6.174
M1_MA13: length 96.1
  TOP w0.118: U22.AD1 123.22,164.7 124.41,165.89 125.76,165.89 126.62,166.75 126.62,172.72 126.75,172.85 127,172.85 127.13,172.72 127.13,165.74 127.25,165.61 127.51,165.61 127.64,165.74 127.64,172.85 127.76,172.97 128.02,172.97 128.14,172.85 128.14,162.43 128.27,162.31 128.52,162.31 128.65,162.43 128.65,175.26 127.64,176.28 127.64,180.35 127.76,180.48 128.02,180.48 128.14,180.35 128.14,176.53 128.27,176.4 128.52,176.4 128.65,176.53 128.65,183.9 138.07,193.32 148.71,193.32 148.82,193.22 151.13,193.22 J6.196
M1_MA14: length 96.2
  TOP w0.102: 118.44,142.09 118.44,141.45 118.54,141.35
  TOP w0.118: U22.B5 118.44,142.09 ; 118.54,141.35 118.54,139.1 118.85,138.79 118.85,136.91 119.14,136.62 128.87,136.62 129.79,137.54 144.17,137.54 144.29,137.67 144.29,137.92 144.17,138.05 130.05,138.05 129.92,138.18 129.92,138.43 130.05,138.56 144.4,138.56 146.56,140.72 146.56,163.04 148.59,165.07 148.59,168.25 149.34,169 J6.172
M1_MA15: length 96.2
  TOP w0.102: 118.22,141.9 118.22,141.41
  TOP w0.118: J6.171 150.01,167.44 150.37,167.08 150.37,165.74 147.07,162.44 147.07,139.57 144.53,137.03 130.05,137.03 129.92,136.91 129.92,136.65 130.05,136.53 143.82,136.53 143.95,136.39 143.95,136.14 143.83,136.02 129.84,136.02 129.71,135.89 119.16,135.89 118.11,136.94 118.11,141.3 118.22,141.41 ; 118.22,141.9 117.88,142.24 117.29,142.24 U22.B6
M1_MBA0: length 96
  TOP w0.118: J6.71 151.24,188 150.03,189.22 148.98,189.22 147.07,191.14 139.06,191.14 138.94,191.01 138.94,190.75 139.06,190.63 145.58,190.63 145.71,190.5 145.71,190.25 145.58,190.12 137.92,190.12 133.99,186.18 133.99,182.63 133.86,182.5 133.6,182.5 133.48,182.63 133.48,185.17 133.35,185.29 133.1,185.29 132.97,185.17 132.97,182.37 133.99,181.36 133.99,180.09 134.75,179.32 134.75,171.45 134.62,171.32 134.37,171.32 134.24,171.45 134.24,178.7 134.11,178.83 133.86,178.83 133.73,178.7 133.73,163.96 127.38,157.61 121.92,157.61 U22.U1
M1_MBA1: length 96.1
  TOP w0.118: J6.190 150.8,187.55 150.8,187.83 149.84,188.79 148.59,188.79 147.78,189.61 138.3,189.61 138.18,189.48 138.18,189.23 138.3,189.1 144.97,189.1 145.1,188.98 145.1,188.72 144.97,188.6 137.29,188.6 137.16,188.47 137.16,188.21 137.29,188.09 142.62,188.09 142.75,187.96 142.75,187.71 142.62,187.58 136.14,187.58 134.49,185.93 134.49,180.59 135.25,179.83 135.25,165.1 135.13,164.97 134.87,164.97 134.75,165.1 134.75,170.46 134.62,170.59 134.37,170.59 134.24,170.46 134.24,163.7 127.61,157.07 122.22,157.07 122.1,157.2 121.32,157.2 U22.U2
M1_MBA2: length 96
  TOP w0.118: J6.52 155.15,168.48 153.67,167.01 152.88,167.01 151.36,165.48 150.82,165.48 147.57,162.23 147.57,138.63 144.45,135.51 130.18,135.51 130.05,135.38 130.05,135.13 130.18,135 141.8,135 141.92,134.88 141.92,134.63 141.78,134.49 119.76,134.49 117.6,136.65 117.6,141.04 117.83,141.26 U22.A5
M1_MCAS_B: length 96.1
  TOP w0.118: U22.AA2 120.83,161.7 121.25,162.11 122.49,162.11 123.86,160.74 128.1,160.74 130.18,162.81 130.18,179.34 130.05,179.46 129.79,179.46 129.67,179.34 129.67,163.04 129.54,162.92 129.29,162.92 129.16,163.04 129.16,183.64 138.2,192.68 148.74,192.68 148.85,192.79 149.99,192.79 150.75,192.02 151.76,192.02 152.79,191 154.18,191 J6.74
M1_MCKE0: length 96.2
  TOP w0.118: U22.A7 v3(115.83,140.97)
  L7_INT_3 w0.087: J6.50 152.9,167 151.98,167.92 150.9,167.92 149.99,167 149.1,167 148.59,166.5 148.59,165.75 147.94,165.1 147.94,147.31 144.74,144.11 130.24,144.11 130.15,144.02 130.15,143.8 130.24,143.71 144.56,143.71 144.64,143.63 144.64,143.41 144.56,143.32 132.02,143.32 125.6,136.91 120.04,136.91 118.64,138.3 118.64,140.23 118.21,140.67 116.13,140.67 v3(115.83,140.97)
M1_MCKE1: length 96.2
  TOP w0.118: v3(115.42,142.2) 115.33,142.2 U22.B8
  L7_INT_3 w0.087: J6.169 148.91,165.46 148.34,164.89 148.34,143.3 147.75,142.72 132.04,142.72 131.95,142.63 131.95,142.42 132.04,142.33 148.21,142.33 148.3,142.24 148.3,142.02 148.21,141.94 131.39,141.94 125.73,136.27 119.63,136.27 115.42,140.49 v3(115.42,142.2)
M1_MCLK0_N: length 96.1
  TOP w0.091: v3(120.33,151.2) U22.L2
  L7_INT_3 w0.1: J6.185 149.85,182 150.11,181.74 150.11,181.46 149.86,181.2 149.03,181.2 148.4,180.57 148.4,179.13 147.83,178.56 146.39,178.56 145.03,177.21 145.03,171.17 143.38,169.52 143.38,160.1 141.92,158.63 127.41,158.63 127.13,158.35 127.13,157.45 127.38,157.2 143.87,157.2 143.97,157.1 143.97,156.31 143.87,156.21 122.68,156.21 122.43,155.96 122.43,154.96 122.68,154.71 125.12,154.71 125.22,154.61 125.22,153.82 125.12,153.72 121.36,153.72 120.75,153.11 120.75,151.61 v3(120.33,151.2)
M1_MCLK0_P: length 96.1
  TOP w0.091: U22.K2 v3(121.33,151.19)
  L7_INT_3 w0.1: J6.184 151.35,181.01 151,181.36 150.75,181.36 150.75,181.36 150.37,181.36 149.96,180.95 149.14,180.95 148.65,180.47 148.65,179.03 147.93,178.31 146.49,178.31 145.29,177.1 145.29,171.07 143.64,169.42 143.64,159.99 142.02,158.38 127.52,158.38 127.39,158.25 127.39,157.56 127.49,157.45 143.97,157.45 144.22,157.2 144.22,156.21 143.97,155.96 122.79,155.96 122.69,155.85 122.69,155.07 122.79,154.97 125.23,154.97 125.48,154.72 125.48,153.72 125.23,153.47 121.46,153.47 120.95,152.95 120.95,152.35 120.95,152.35 120.95,151.58 v3(121.33,151.19)
M1_MCLK1_N: length 96
  TOP w0.091: U22.M1 v3(121.33,152.2)
  L7_INT_3 w0.1: J6.64 155.15,181 154.64,180.49 154.64,179.71 153.82,178.89 152.88,178.89 151.89,177.9 150.85,177.9 149.89,176.94 147.32,176.94 146.56,176.17 146.56,168.78 145.98,168.21 145.98,155.51 145.19,154.71 128.08,154.71 127.98,154.61 127.98,153.82 128.08,153.72 145.41,153.72 145.67,153.47 145.67,152.47 145.41,152.22 129.36,152.22 128.4,151.26 121.99,151.26 121.72,151.53 121.72,151.81 v3(121.33,152.2)
M1_MCLK1_P: length 96
  TOP w0.091: U22.L1 v3(122.33,152.19)
  L7_INT_3 w0.1: v3(122.33,152.19) 122.1,152.19 121.97,152.07 121.97,151.64 122.1,151.51 128.29,151.51 129.26,152.48 145.31,152.48 145.41,152.58 145.41,153.37 145.31,153.47 127.97,153.47 127.72,153.72 127.72,154.72 127.97,154.97 145.08,154.97 145.73,155.61 145.73,168.31 146.3,168.89 146.3,176.28 147.22,177.19 149.78,177.19 150.75,178.16 151.79,178.16 152.78,179.15 153.72,179.15 154.38,179.81 154.38,180.44 154.18,180.65 153.89,180.65 J6.63
M1_MCLK2_N: length 4.3
  TOP w0.091: U22.N1 121.44,153.69 121.35,153.6 121.35,153.4 121.45,153.29 124.34,153.29 R261.2
M1_MCLK2_P: length 4.4
  TOP w0.091: U22.N2 120.95,153.69 121.14,153.5 121.14,153.31 121.37,153.09 124.41,153.09 R264.2
M1_MCLK3_N: length 4.7
  TOP w0.091: U22.J1 121.42,149.69 121.33,149.6 121.33,149.39 121.42,149.3 122.33,149.3 123.3,150.28 124.37,150.28 R267.2
M1_MCLK3_P: length 4.8
  TOP w0.091: U22.J2 120.99,149.69 121.13,149.55 121.13,149.31 121.34,149.1 122.41,149.1 123.39,150.07 124.37,150.07 R269.2
M1_MCS_B0: length 96
  TOP w0.118: U22.Y1 v3(122.33,161.19)
  L7_INT_3 w0.087: v3(122.33,161.19) 122.66,160.86 141.92,160.86 142.01,160.95 142.01,161.17 141.92,161.26 125.95,161.26 125.86,161.35 125.86,161.56 125.95,161.65 141.83,161.65 141.92,161.74 141.92,161.96 141.83,162.05 137.05,162.05 136.96,162.13 136.96,162.35 137.05,162.44 141.55,162.44 142.01,162.89 142.01,170.33 142.8,171.12 142.8,179.17 144.12,180.49 144.12,187.68 146.44,190 148.68,190 J6.193
M1_MCS_B1: length 96.1
  TOP w0.118: v3(121.33,163.2) U22.AC2
  L7_INT_3 w0.087: v3(121.33,163.19) 122.08,162.45 123.08,162.45 124.13,163.5 125.71,163.5 125.98,163.23 130.56,163.23 130.65,163.32 130.65,163.53 130.56,163.62 129.12,163.62 129.03,163.71 129.03,163.93 129.12,164.01 140.88,164.01 140.97,164.1 140.97,164.32 140.88,164.41 130.01,164.41 129.92,164.5 129.92,164.71 130.01,164.8 141.01,164.8 141.1,164.89 141.1,165.11 141.01,165.2 136.36,165.2 136.27,165.28 136.27,165.5 136.36,165.59 140.9,165.59 141.22,165.91 141.22,170.81 142.01,171.6 142.01,179.55 143.21,180.75 143.21,188.34 147.64,192.77 150.13,192.77 150.88,192.02 151.89,192.02 152.87,193 J6.76
M1_MCS_B2: length 96.1
  TOP w0.118: U22.W1 v3(122.33,160.19)
  L7_INT_3 w0.087: J6.79 154.02,196 155.64,196 156.97,194.67 156.97,192.46 156.41,191.9 155.42,191.9 155.42,191.9 154.69,191.9 153.8,191.01 152.81,191.01 151.87,190.07 151.08,190.07 150.11,189.1 149.35,189.1 148.59,188.34 148.59,183.39 146.66,181.46 145.64,181.46 143.21,179.03 143.21,170.92 142.4,170.1 142.4,160.69 142.18,160.47 127.41,160.47 127.32,160.38 127.32,160.11 127.4,160.03 140.7,160.03 140.79,159.94 140.79,159.73 140.69,159.63 126.24,159.63 126.09,159.77 122.75,159.77 v3(122.33,160.19)
M1_MCS_B3: length 96
  TOP w0.118: v3(122.33,163.19) 121.83,163.69 U22.AC1
  L7_INT_3 w0.087: v3(122.33,163.19) 122.33,163.48 122.94,164.08 128.63,164.08 129.74,165.2 135.67,165.2 135.76,165.28 135.76,165.5 135.67,165.59 130.64,165.59 130.56,165.68 130.56,165.89 130.64,165.98 140.63,165.98 140.72,166.07 140.72,166.29 140.63,166.38 131.41,166.38 131.32,166.47 131.32,166.68 131.41,166.77 140.65,166.77 140.74,166.86 140.74,167.08 140.65,167.16 135.01,167.16 134.92,167.25 134.92,167.47 135.01,167.56 140.51,167.56 140.82,167.88 140.82,171.05 141.62,171.84 141.62,179.72 142.77,180.87 142.77,188.62 147.32,193.17 150.11,193.17 151.35,194.4 J6.198
M1_MDIC_0: length 4.1
  TOP w0.118: R259.1 122.76,154.56 122.49,154.29 121.24,154.29 U22.P2
M1_MDIC_1: length 2.9
  TOP w0.118: R271.1 124.69,148.69 U22.H1
M1_MDQ0: length 83.9
  TOP w0.118: U22.F7 v3(116.33,146.2)
  L12_INT_5 w0.087: J6.3 150.95,116 150.13,116.83 148.45,116.83 145.84,114.22 142.42,114.22 142.33,114.31 142.33,114.52 142.42,114.61 145.58,114.61 145.67,114.7 145.67,114.92 145.58,115 129.78,115 129.69,115.09 129.69,115.31 129.78,115.4 135.86,115.4 135.95,115.49 135.95,115.7 135.86,115.79 129.17,115.79 123.82,121.14 123.82,130.79 116.28,138.33 116.28,139.37 114.73,140.92 114.73,144.53 115.01,144.81 115.49,144.81 115.87,145.19 115.87,145.74 v3(116.33,146.2)
M1_MDQ1: length 83.8
  TOP w0.118: v3(116.33,145.2) 116.3,145.2 115.83,145.66 U22.E7
  L12_INT_5 w0.087: v3(116.33,145.2) 115.74,144.6 115.11,144.6 114.94,144.42 114.94,141.29 116.71,139.51 116.71,138.46 124.21,130.96 124.21,121.31 129.33,116.19 145.91,116.19 146,116.1 146,115.88 145.91,115.79 136.44,115.79 136.35,115.7 136.35,115.49 136.44,115.4 146.26,115.4 148.08,117.22 150.11,117.22 150.88,117.98 151.89,117.98 152.88,117 J6.4
M1_MDQ2: length 83.8
  TOP w0.118: v3(119.33,144.2) 119.3,144.2 118.83,144.67 U22.D4
  L12_INT_5 w0.087: v3(119.33,144.2) 119.79,144.65 120.47,144.65 120.85,145.03 121.67,145.03 122.66,144.04 125.55,144.04 128.47,141.13 128.47,136.33 128.73,136.07 133.11,136.07 133.2,135.98 133.2,135.76 133.11,135.68 128.56,135.68 128.47,135.59 128.47,135.37 128.56,135.28 140.52,135.28 140.61,135.19 140.61,134.98 140.52,134.89 128.59,134.89 128.5,134.8 128.5,134.58 128.59,134.49 141.22,134.49 146.56,129.16 146.56,125.22 148.55,123.23 149.95,123.23 151.18,122 J6.9
M1_MDQ3: length 83.8
  TOP w0.118: v3(119.33,145.2) 118.83,145.7 U22.E4
  L12_INT_5 w0.087: v3(119.33,145.2) 119.8,145.67 122.3,145.67 122.99,144.98 125.55,144.98 128.86,141.67 128.86,137.59 129.2,137.25 139.1,137.25 139.19,137.16 139.19,136.95 139.1,136.86 129.02,136.86 128.93,136.77 128.93,136.55 129.02,136.46 139.85,136.46 139.94,136.37 139.94,136.16 139.85,136.07 133.68,136.07 133.59,135.98 133.59,135.76 133.68,135.68 140.68,135.68 141,135.36 141,135.35 146.98,129.38 146.98,126.71 148.79,124.89 150.04,124.89 151.05,123.88 152.29,123.88 153.16,123 J6.10
M1_MDQ4: length 83.8
  TOP w0.118: v3(115.33,145.2) 114.83,145.7 U22.E8
  L12_INT_5 w0.087: v3(115.33,145.2) 114.89,145.2 114.36,144.67 114.19,144.67 113.67,144.15 113.67,140.59 115.47,138.79 115.47,138.02 123.03,130.46 123.03,120.63 130.23,113.43 143.8,113.43 143.89,113.34 143.89,113.12 143.8,113.03 133.81,113.03 133.72,112.94 133.72,112.73 133.81,112.64 149.72,112.64 151.35,114.27 J6.122
M1_MDQ5: length 83.8
  TOP w0.118: U22.D8 114.83,144.7 v3(114.33,144.2)
  L12_INT_5 w0.087: J6.123 146.49,113.04 144.51,113.04 144.42,113.13 144.42,113.34 144.51,113.43 145.07,113.43 145.16,113.52 145.16,113.73 145.07,113.82 130.44,113.82 130.35,113.91 130.35,114.13 130.44,114.22 141.85,114.22 141.94,114.31 141.94,114.52 141.85,114.61 129.61,114.61 123.42,120.8 123.42,130.63 115.87,138.18 115.87,139.09 113.92,141.04 113.92,143.79 v3(114.33,144.2)
M1_MDQ6: length 83.8
  TOP w0.118: v3(118.33,144.2) U22.D5
  L12_INT_5 w0.087: J6.128 150.81,121.54 150.81,121.81 149.81,122.81 148.21,122.81 146.16,124.85 146.16,129 142.63,132.53 138.16,132.53 138.07,132.61 138.07,132.83 138.16,132.92 141.83,132.92 141.92,133.01 141.92,133.22 141.83,133.31 128.16,133.31 128.07,133.4 128.07,133.62 128.16,133.71 141.01,133.71 141.1,133.8 141.1,134.01 141.01,134.1 128.4,134.1 128.07,134.42 128.07,140.66 125.09,143.64 118.89,143.64 v3(118.33,144.2)
M1_MDQ7: length 83.8
  TOP w0.118: U22.E5 v3(118.33,145.2)
  L12_INT_5 w0.087: J6.129 149.2,122.25 145.47,122.25 144.99,122.73 144.99,128.49 145.07,128.57 145.29,128.57 145.38,128.49 145.38,122.99 145.47,122.91 145.68,122.91 145.77,122.99 145.77,128.71 142.35,132.13 127.85,132.13 127.76,132.22 127.76,132.44 127.85,132.53 137.59,132.53 137.68,132.61 137.68,132.83 137.59,132.92 127.98,132.92 127.68,133.22 127.68,140.21 125.15,142.75 118.08,142.75 117.83,143 117.83,144.7 v3(118.33,145.2)
M1_MDQ8: length 84.8
  TOP w0.118: U22.J8 v3(115.33,149.2)
  L5_INT_2 w0.087: J6.12 155.15,125.44 153.62,126.97 152.79,126.97 152.05,126.24 151.67,126.24 151.67,126.23 150.77,126.23 149.77,125.23 148.47,125.23 147.57,124.33 147.57,120.52 146.28,119.23 130.33,119.23 130.24,119.15 130.24,118.93 130.33,118.84 137.68,118.84 137.77,118.75 137.77,118.54 137.68,118.45 130.14,118.45 117.6,130.99 117.6,141.38 115.93,143.05 115.93,148.6 v3(115.33,149.2)
M1_MDQ9: length 84.7
  TOP w0.118: U22.G7 v3(115.33,147.2)
  L5_INT_2 w0.087: v3(115.33,147.2) 115.72,146.8 115.72,142.6 116.33,141.99 116.33,138.68 117.09,137.92 117.09,130.89 129.93,118.05 147.88,118.05 147.97,118.14 147.97,118.36 147.88,118.45 138.4,118.45 138.32,118.54 138.32,118.75 138.4,118.84 147.29,118.84 148.08,119.63 148.08,124.21 148.71,124.84 149.93,124.84 149.93,124.84 149.99,124.84 150.91,125.77 152.25,125.77 152.48,126 J6.13
M1_MDQ10: length 84.7
  TOP w0.118: U22.G4 v3(119.33,147.2)
  L5_INT_2 w0.087: J6.18 153.1,131 151.89,129.79 150.75,129.79 149.75,130.8 148.55,130.8 145.93,133.42 123.48,133.42 123.39,133.51 123.39,133.72 123.48,133.81 140.44,133.81 140.53,133.9 140.53,134.12 140.44,134.21 123.39,134.21 122.85,134.75 122.85,141.56 122.12,142.29 122.12,145.64 120.95,146.81 119.71,146.81 v3(119.33,147.2)
M1_MDQ11: length 84.7
  TOP w0.118: U22.H4 118.84,148.69 119.33,148.21 v3(119.33,148.2)
  L5_INT_2 w0.087: v3(119.33,148.2) 119.8,147.73 120.93,147.73 122.52,146.14 122.52,142.53 123.32,141.73 123.32,136.53 124.45,135.39 136.94,135.39 137.03,135.3 137.03,135.08 136.94,134.99 124.29,134.99 124.21,134.91 124.21,134.69 124.29,134.6 146.25,134.6 146.34,134.51 146.34,134.3 146.25,134.21 141.22,134.21 141.14,134.12 141.14,133.9 141.22,133.81 146.48,133.81 149.07,131.22 150.05,131.22 151.03,130.23 151.69,130.23 152.71,131.24 152.71,131.46 J6.19
M1_MDQ12: length 84.7
  TOP w0.118: U22.H8 v3(115.33,148.2)
  L5_INT_2 w0.087: J6.131 150.37,123.08 150.37,119.61 149.86,119.1 148.95,119.1 148.36,118.52 148.36,117.25 147.99,116.87 138.12,116.87 138.03,116.96 138.03,117.18 138.12,117.27 147.55,117.27 147.64,117.35 147.64,117.57 147.55,117.66 129.74,117.66 115.7,131.7 115.7,133.73 115.44,133.99 115.44,140.21 114.81,140.84 114.81,147.67 v3(115.33,148.2)
M1_MDQ13: length 84.8
  TOP w0.118: v3(114.33,147.2) U22.G8
  L5_INT_2 w0.087: v3(114.33,147.2) 113.79,146.66 113.79,140.84 114.68,139.95 114.68,129.67 127.08,117.27 137.09,117.27 137.18,117.18 137.18,116.96 137.09,116.87 129.81,116.87 129.72,116.78 129.72,116.57 129.81,116.48 148.23,116.48 148.82,117.07 150.04,117.07 150.9,117.93 151.66,117.93 152.27,118.54 152.27,124.08 J6.132
M1_MDQ14: length 84.7
  TOP w0.118: U22.J6 v3(117.33,149.2)
  L5_INT_2 w0.087: J6.137 149.15,130.3 148.21,130.3 146.27,132.24 123.91,132.24 123.83,132.33 123.83,132.54 123.91,132.63 142.05,132.63 142.14,132.72 142.14,132.94 142.05,133.03 123.26,133.03 122.45,133.84 122.45,141.33 121.67,142.11 121.67,142.75 120.78,143.64 120.78,146.35 120.56,146.58 119.39,146.58 118.81,147.15 118.81,148.4 118.41,148.79 117.73,148.79 v3(117.33,149.2)
M1_MDQ15: length 84.8
  TOP w0.118: U22.J4 v3(119.33,149.2)
  L5_INT_2 w0.087: J6.138 151.35,131.43 149.94,132.84 148.97,132.84 146.82,134.99 137.57,134.99 137.48,135.08 137.48,135.3 137.57,135.39 146.34,135.39 146.43,135.48 146.43,135.69 146.34,135.78 128.04,135.78 127.95,135.87 127.95,136.09 128.04,136.18 140.27,136.18 140.36,136.26 140.36,136.48 140.27,136.57 131.02,136.57 122.92,144.67 122.92,146.32 120.52,148.72 119.72,148.72 119.33,149.11 v3(119.33,149.2)
M1_MDQ16: length 83.9
  TOP w0.118: U22.L8 v3(115.33,151.2)
  L14_INT_6 w0.087: J6.21 153.03,133.78 150.75,133.78 149.99,133.02 149.28,133.02 147.93,131.67 147.93,121.08 145.82,118.97 136.55,118.97 129.46,126.06 129.46,132.26 129.55,132.34 129.77,132.34 129.88,132.23 129.88,127.72 129.97,127.64 130.19,127.64 130.27,127.72 130.27,132.52 123.29,139.5 123.29,140.23 120.78,142.75 118.24,142.75 117.86,143.13 117.86,143.26 116.46,144.65 115.19,144.65 114.81,145.03 114.81,150.67 v3(115.33,151.2)
M1_MDQ17: length 83.8
  TOP w0.118: U22.L7 v3(116.33,151.2)
  L14_INT_6 w0.087: J6.22 152.66,135 151.84,134.19 150.93,134.19 150.24,134.87 149.12,134.87 147.12,132.87 147.12,121.62 146.25,120.75 142.04,120.75 141.13,121.65 141.13,130.01 137.59,133.56 134.93,133.56 133.36,135.13 131.76,135.13 131.67,135.22 131.67,135.44 131.76,135.53 133.97,135.53 134.06,135.62 134.06,135.83 133.97,135.92 128.21,135.92 128.12,136.01 128.12,136.23 128.21,136.32 130.22,136.32 130.31,136.4 130.31,136.62 130.22,136.71 127.4,136.71 126.16,137.95 126.16,139.43 122.17,143.42 122.17,144.4 120.78,145.8 118.11,145.8 117.86,146.05 117.86,146.3 117.47,146.69 117.22,146.69 115.95,147.96 115.95,150.81 v3(116.33,151.2)
M1_MDQ18: length 83.9
  TOP w0.118: U22.R8 v3(115.33,155.2)
  L14_INT_6 w0.087: J6.27 153.25,140.55 151.92,141.88 150.77,141.88 150.11,141.22 148.69,141.22 147.89,142.02 131.27,142.02 131.18,142.11 131.18,142.33 131.27,142.42 148.4,142.42 148.49,142.51 148.49,142.72 148.4,142.81 130.75,142.81 128.19,145.37 128.19,149.59 126.73,151.05 124.58,151.05 122.59,153.03 121.77,153.03 121.34,152.6 120.32,152.6 119.76,153.16 119.76,153.44 119.53,153.67 119.1,153.67 118.75,154.03 118.75,154.38 118.53,154.6 117.94,154.6 117.73,154.81 115.71,154.81 v3(115.33,155.2)
M1_MDQ19: length 83.8
  TOP w0.118: U22.R7 v3(116.33,155.2)
  L14_INT_6 w0.087: v3(116.33,155.2) 116.74,155.6 117.55,155.6 117.86,155.3 117.86,155.07 118.11,154.81 119,154.81 119.13,154.69 119.51,154.69 119.86,154.33 119.86,154 120.13,153.73 122.45,153.73 124.75,151.44 126.89,151.44 128.58,149.75 128.58,146.32 130.91,143.99 148.49,143.99 148.58,143.9 148.58,143.69 148.49,143.6 131.27,143.6 131.18,143.51 131.18,143.29 131.27,143.21 150.09,143.21 150.7,143.81 152.04,143.81 152.88,142.98 153.52,142.98 155.15,141.34 J6.28
M1_MDQ20: length 83.8
  TOP w0.118: v3(114.33,150.2) U22.K8
  L14_INT_6 w0.087: v3(114.33,150.2) 113.87,149.73 113.87,144.02 114.25,143.64 116.46,143.64 116.84,143.26 116.84,143 118.08,141.76 119.63,141.76 120.93,140.46 121.77,140.46 128.93,133.3 128.93,127.39 128.84,127.3 128.62,127.3 128.53,127.39 128.53,132.6 128.45,132.69 128.24,132.69 128.14,132.59 128.14,125.88 135.64,118.39 145.95,118.39 148.36,120.8 148.36,130.58 148.95,131.17 149.99,131.17 151.35,132.53 J6.140
M1_MDQ21: length 83.7
  TOP w0.118: v3(115.33,150.2) U22.K7
  L14_INT_6 w0.087: J6.141 147.51,132.06 147.51,121.3 146.41,120.19 141.96,120.19 140.74,121.41 140.74,129.77 137.34,133.17 132.92,133.17 132.83,133.25 132.83,133.47 132.92,133.56 133.94,133.56 134.03,133.65 134.03,133.86 133.94,133.95 129.4,133.95 129.31,134.04 129.31,134.26 129.4,134.35 133.18,134.35 133.27,134.44 133.27,134.65 133.18,134.74 128.69,134.74 128.6,134.83 128.6,135.05 128.69,135.13 131.19,135.13 131.28,135.22 131.28,135.44 131.19,135.53 127.95,135.53 125.77,137.71 125.77,139.26 123.05,141.99 122.17,141.99 120.52,143.64 118.11,143.64 116.84,144.91 116.84,146.3 115.71,147.43 115.71,149.81 v3(115.33,150.2)
M1_MDQ22: length 83.8
  TOP w0.118: U22.P8 v3(115.33,154.2)
  L14_INT_6 w0.087: J6.146 151.35,139.63 150.16,140.82 148.82,140.82 148.03,140.03 146.16,140.03 146.08,140.12 146.08,140.34 146.16,140.42 147.87,140.42 147.96,140.51 147.96,140.73 147.87,140.82 131.71,140.82 131.62,140.91 131.62,141.12 131.71,141.21 147.74,141.21 147.83,141.3 147.83,141.52 147.74,141.6 131.11,141.6 127.79,144.93 127.79,148.43 126.68,149.54 124.95,149.54 123.16,151.33 122.07,151.33 121.77,151.64 120.14,151.64 119.89,151.89 119.89,152.4 119.58,152.7 119.15,152.7 118.92,152.93 118.92,153.44 118.55,153.81 118.1,153.81 117.81,154.1 117.81,154.33 117.55,154.58 115.72,154.58 v3(115.33,154.2)
M1_MDQ23: length 83.8
  TOP w0.118: U22.P7 v3(116.33,154.2)
  L14_INT_6 w0.087: J6.147 148.58,140 147.43,138.85 140.65,138.85 140.56,138.94 140.56,139.15 140.65,139.24 147.23,139.24 147.35,139.36 147.35,139.55 147.26,139.64 132.32,139.64 132.21,139.75 132.21,139.94 132.29,140.03 145.59,140.03 145.68,140.12 145.68,140.34 145.59,140.42 131.53,140.42 127.4,144.56 127.4,146.53 123.06,150.88 121.92,150.88 121.79,150.75 120.19,150.75 119.81,151.13 119.81,151.33 119.48,151.66 119.15,151.66 118.72,152.1 118.72,153.37 118.47,153.62 116.91,153.62 v3(116.33,154.2)
M1_MDQ24: length 83.7
  TOP w0.118: U22.L5 117.83,151.7 v3(118.33,151.2)
  L5_INT_2 w0.087: J6.30 152.66,143 151.89,143.77 151.03,143.77 151.03,143.76 151,143.76 150.04,142.8 148.95,142.8 147.96,141.81 147.96,140.21 147.66,139.91 130.82,139.91 130.73,140 130.73,140.21 130.82,140.3 147.47,140.3 147.56,140.39 147.56,140.61 147.47,140.7 129.95,140.7 129.86,140.79 129.86,141 129.95,141.09 131.38,141.09 131.47,141.18 131.47,141.4 131.38,141.48 129.79,141.48 129.41,141.87 129.41,144.12 126.31,147.22 124.94,147.22 121.56,150.6 119.91,150.6 119.71,150.8 118.73,150.8 v3(118.33,151.2)
M1_MDQ25: length 83.8
  TOP w0.118: U22.L4 v3(119.33,151.2)
  L5_INT_2 w0.087: v3(119.33,151.2) 119.65,151.2 120.03,150.81 121.96,150.81 125.07,147.7 126.62,147.7 130.82,143.5 137.64,143.5 137.73,143.41 137.73,143.17 137.64,143.08 129.91,143.08 129.83,143 129.83,142.78 129.91,142.69 137.64,142.69 137.73,142.6 137.73,142.36 137.64,142.27 130.11,142.27 130.02,142.18 130.02,141.97 130.11,141.88 137.69,141.88 137.78,141.79 137.78,141.57 137.69,141.48 132.05,141.48 131.98,141.41 131.98,141.16 132.05,141.09 146.63,141.09 148.77,143.23 149.77,143.23 150.77,144.23 152.25,144.23 152.48,144 J6.31
M1_MDQ26: length 83.8
  TOP w0.118: U22.R5 v3(118.33,155.2)
  L5_INT_2 w0.087: v3(118.33,155.2) 118.93,154.6 122.21,154.6 122.35,154.74 125.17,154.74 125.78,154.13 130.68,154.13 136.76,160.21 145.17,160.21 145.26,160.12 145.26,159.91 145.17,159.82 136.99,159.82 136.91,159.73 136.91,159.51 136.99,159.42 145.53,159.42 145.62,159.33 145.62,159.12 145.53,159.03 136.26,159.03 136.17,158.94 136.17,158.75 136.28,158.64 145.91,158.64 147.57,156.97 147.57,154.69 149.05,153.21 149.91,153.21 151.1,152.02 151.64,152.02 152.12,151.54 152.12,149.71 152.83,149 J6.36
M1_MDQ27: length 83.7
  TOP w0.118: U22.R4 v3(119.33,155.2)
  L5_INT_2 w0.087: v3(119.33,155.2) 119.71,154.81 121.54,154.81 121.87,155.14 131.01,155.14 131.03,155.16 131.15,155.16 136.59,160.6 136.6,160.6 138.22,162.23 147.36,162.23 147.45,162.14 147.45,161.93 147.36,161.84 138.9,161.84 138.81,161.75 138.81,161.53 138.9,161.44 147.13,161.44 147.22,161.35 147.22,161.14 147.13,161.05 137.69,161.05 137.6,160.96 137.6,160.74 137.69,160.66 147.32,160.66 148.95,159.03 149.86,159.03 150.84,158.05 151.7,158.05 152.4,157.35 152.4,151.81 152.51,151.7 152.51,150.74 J6.37
M1_MDQ28: length 83.8
  TOP w0.118: U22.K5 v3(118.33,150.2)
  L5_INT_2 w0.087: J6.149 148.91,141.46 148.36,140.91 148.36,138.33 147.97,137.94 144.07,137.94 143.98,138.03 143.98,138.25 144.07,138.33 147.75,138.33 147.84,138.42 147.84,138.64 147.75,138.73 131.19,138.73 131.1,138.82 131.1,139.03 131.19,139.12 147.7,139.12 147.79,139.21 147.79,139.43 147.7,139.52 130.49,139.52 128.91,141.1 128.91,143.97 126.14,146.74 124.76,146.74 121.7,149.8 120.1,149.8 119.88,150.03 119.88,150.23 119.51,150.6 118.73,150.6 v3(118.33,150.2)
M1_MDQ29: length 83.8
  TOP w0.118: U22.K4 v3(119.33,150.2)
  L5_INT_2 w0.087: J6.150 150.47,142.12 150.47,137.52 149.99,137.03 149.23,137.03 148.95,136.76 141.36,136.76 141.27,136.85 141.27,137.06 141.36,137.15 148.37,137.15 148.46,137.24 148.46,137.46 148.37,137.55 131.51,137.55 131.42,137.64 131.42,137.85 131.51,137.94 143.5,137.94 143.59,138.03 143.59,138.25 143.5,138.33 130.65,138.33 123.9,145.08 123.9,146.86 121.18,149.58 119.94,149.58 v3(119.33,150.2)
M1_MDQ30: length 83.8
  TOP w0.118: U22.P5 v3(118.33,154.2)
  L5_INT_2 w0.087: J6.155 150.22,148.77 150.22,150.32 149.77,150.77 149.46,150.77 145.56,154.67 134.16,154.67 134.07,154.76 134.07,154.97 134.16,155.06 144.97,155.06 145.06,155.15 145.06,155.37 144.97,155.45 134.33,155.45 134.24,155.54 134.24,155.76 134.33,155.85 144.74,155.85 144.82,155.94 144.82,156.15 144.74,156.24 133.9,156.24 130,152.34 125.79,152.34 124.4,153.73 121.22,153.73 121.08,153.59 118.94,153.59 v3(118.33,154.2)
M1_MDQ31: length 83.8
  TOP w0.118: U22.P4 118.84,154.69 119.33,154.2 v3(119.33,154.2)
  L5_INT_2 w0.087: J6.156 151.35,149.77 150.5,150.62 150.5,152.07 149.79,152.78 148.84,152.78 144.96,156.67 134.84,156.67 134.75,156.76 134.75,156.97 134.84,157.06 145.71,157.06 145.8,157.15 145.8,157.37 145.71,157.45 135.6,157.45 135.51,157.54 135.51,157.76 135.6,157.85 145.73,157.85 145.82,157.94 145.82,158.15 145.73,158.24 135.35,158.24 130.39,153.28 125.66,153.28 124.76,154.18 121.16,154.18 120.79,153.81 119.72,153.81 v3(119.33,154.2)
M1_MDQ32: length 83.8
  TOP w0.118: v3(115.33,157.2) U22.U7
  L5_INT_2 w0.087: v3(115.33,157.2) 114.94,156.8 114.94,155.98 115.11,155.8 121.13,155.8 121.62,156.29 123.62,156.29 123.95,156.62 130.67,156.62 145.71,171.66 145.71,178.12 145.62,178.21 145.41,178.21 145.32,178.12 145.32,172.3 145.23,172.21 145.01,172.21 144.93,172.3 144.93,178.56 146.3,179.94 146.3,180.97 147.62,182.3 147.62,183.59 146.35,184.86 146.35,190.19 149.2,193.04 149.99,193.04 150.88,193.93 151.64,193.93 152.37,194.67 152.37,196.88 153.25,197.75 J6.81
M1_MDQ33: length 83.8
  TOP w0.118: U22.U8 v3(114.33,157.2)
  L5_INT_2 w0.087: v3(114.33,157.2) 114.73,156.79 114.73,155.8 114.94,155.6 121.56,155.6 121.84,155.88 123.8,155.88 124.05,156.13 130.74,156.13 146.11,171.5 146.11,176.6 146.19,176.68 146.41,176.68 146.5,176.59 146.5,172.18 146.59,172.09 146.81,172.09 146.89,172.18 146.89,180.93 148.03,182.07 148.03,183.82 146.81,185.04 146.81,189.1 148.59,190.88 149.86,190.88 151,192.02 151.89,192.02 152.91,193.04 153.85,193.04 154.37,193.56 154.37,198.22 J6.82
M1_MDQ34: length 83.9
  TOP w0.118: v3(116.33,161.2) U22.AA7
  L5_INT_2 w0.087: J6.87 150.85,204 150.08,204.77 148.46,204.77 143.38,199.69 143.38,196.71 138.85,192.17 138.31,192.17 136.27,190.13 136.27,182.75 136.18,182.66 135.96,182.66 135.88,182.75 135.88,189.39 135.79,189.48 135.6,189.48 135.48,189.36 135.48,169.57 127.72,161.81 123.81,161.81 123.57,162.05 122.1,162.05 121.74,161.7 121.13,161.7 120.04,160.6 116.92,160.6 116.61,160.91 v3(116.33,161.2)
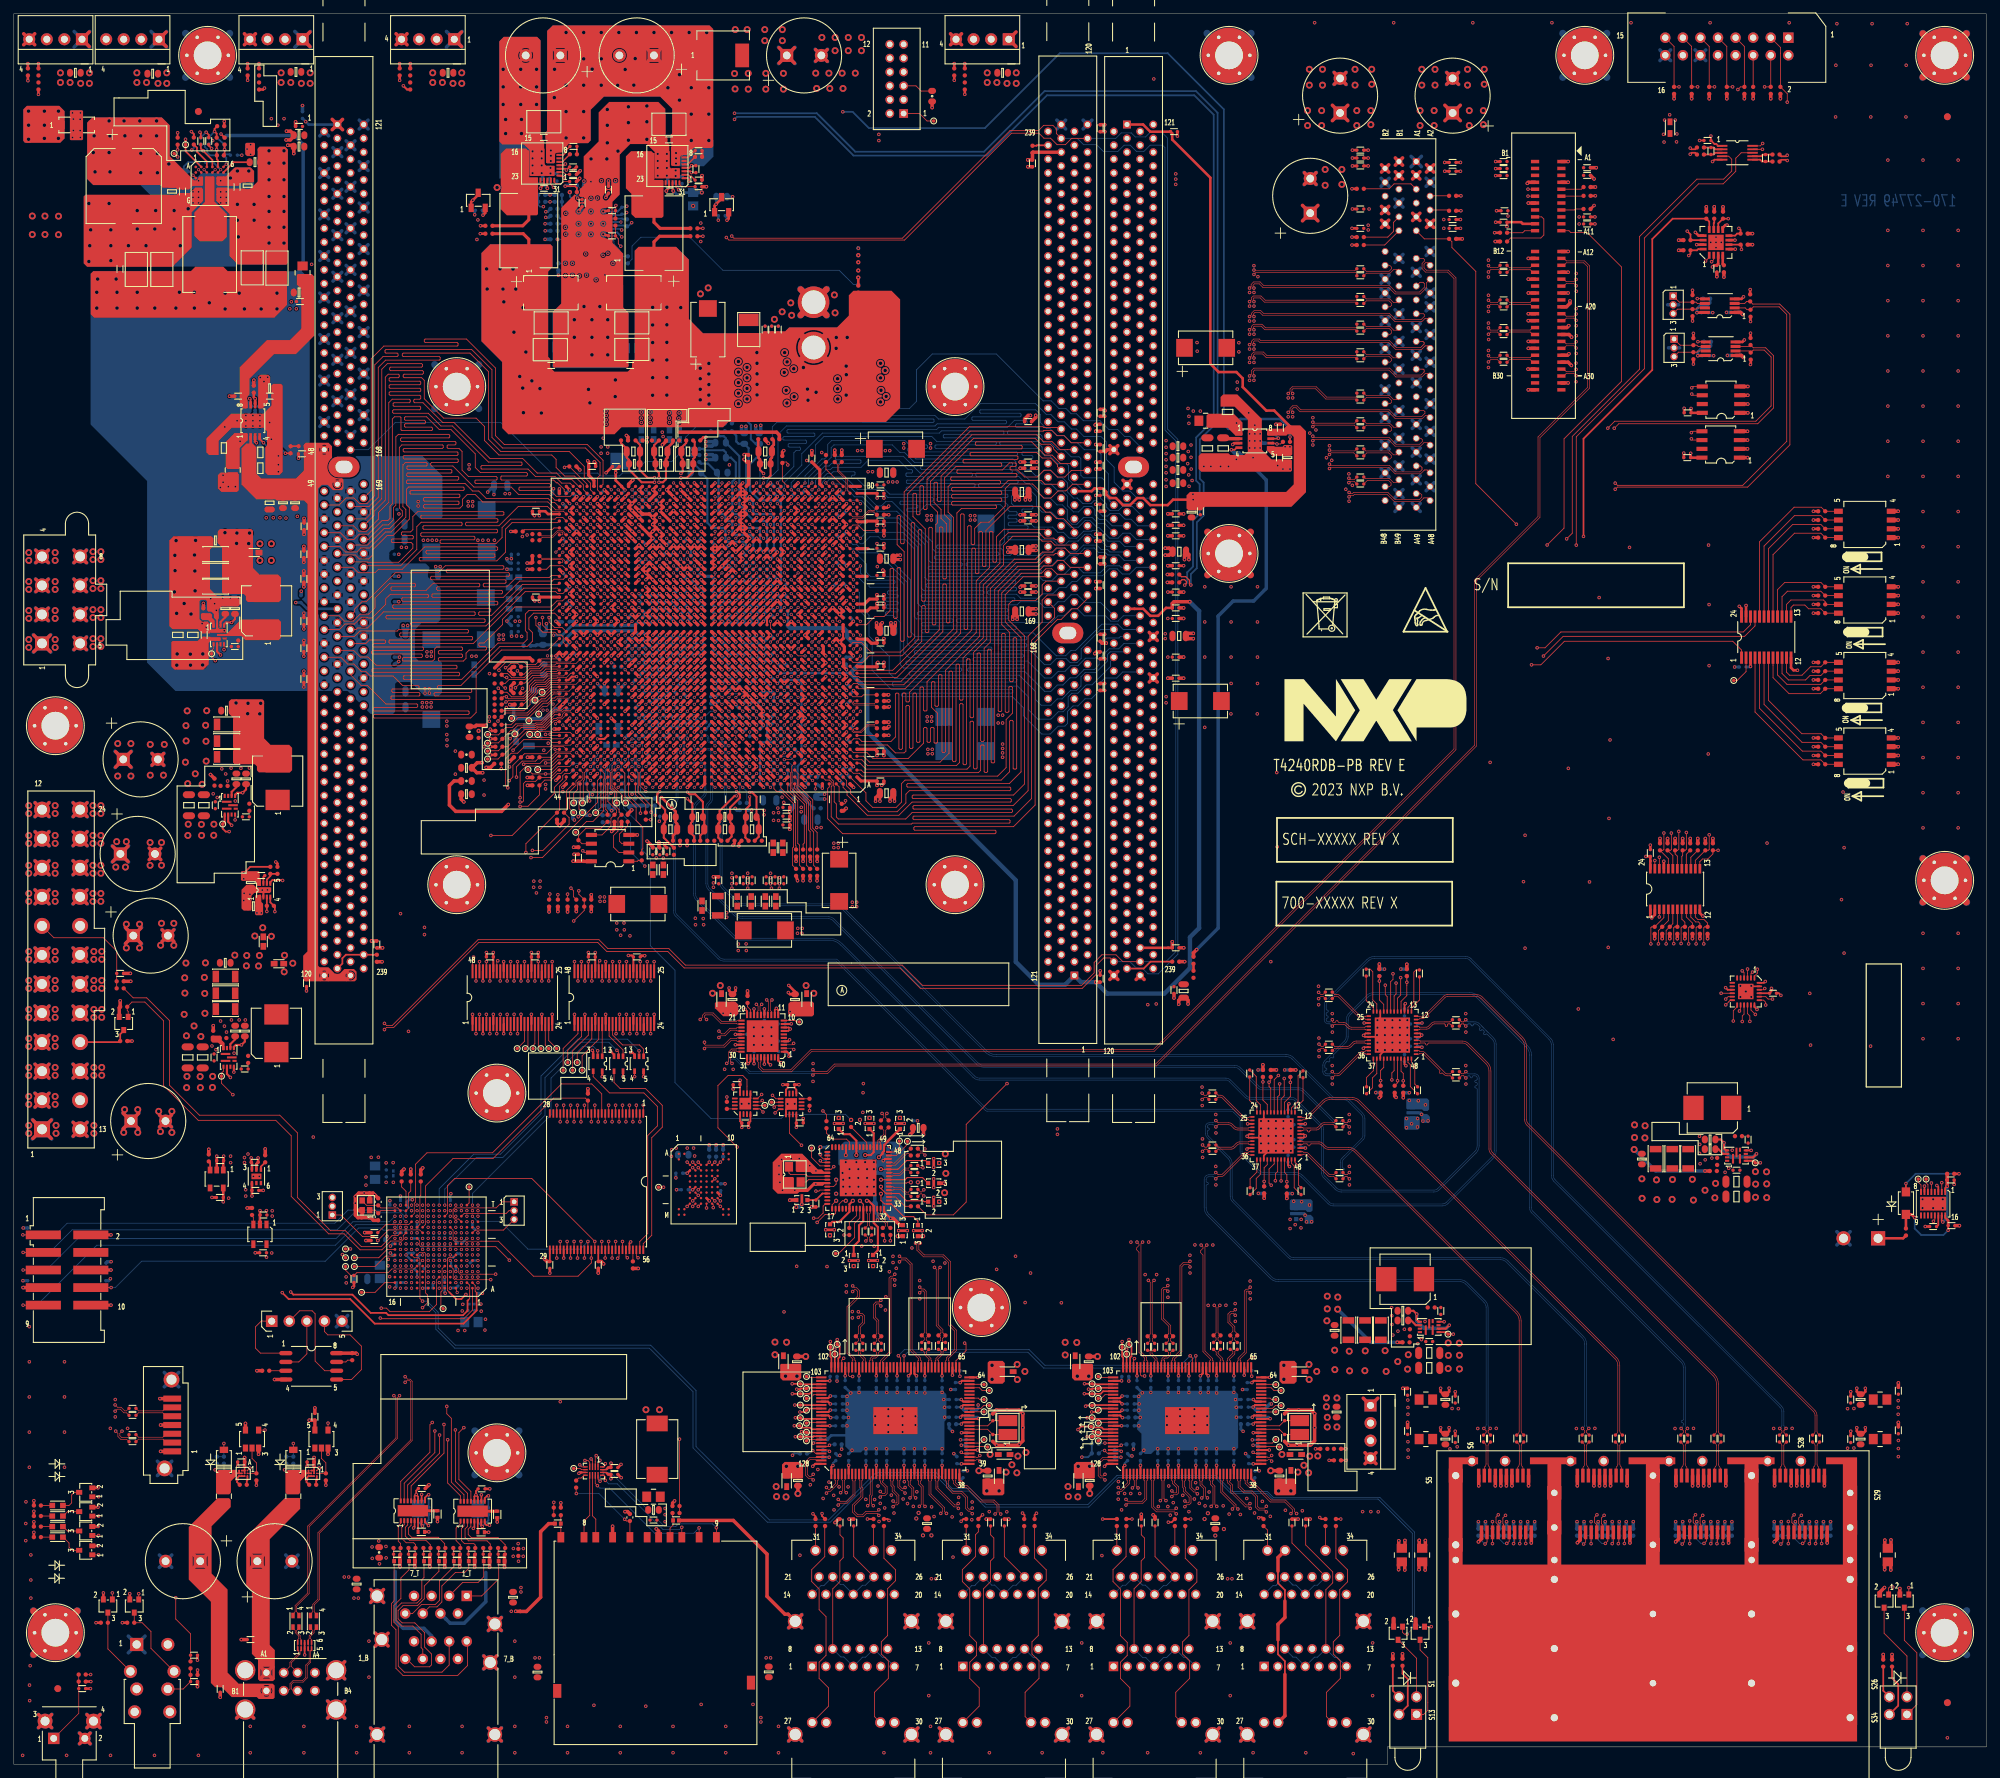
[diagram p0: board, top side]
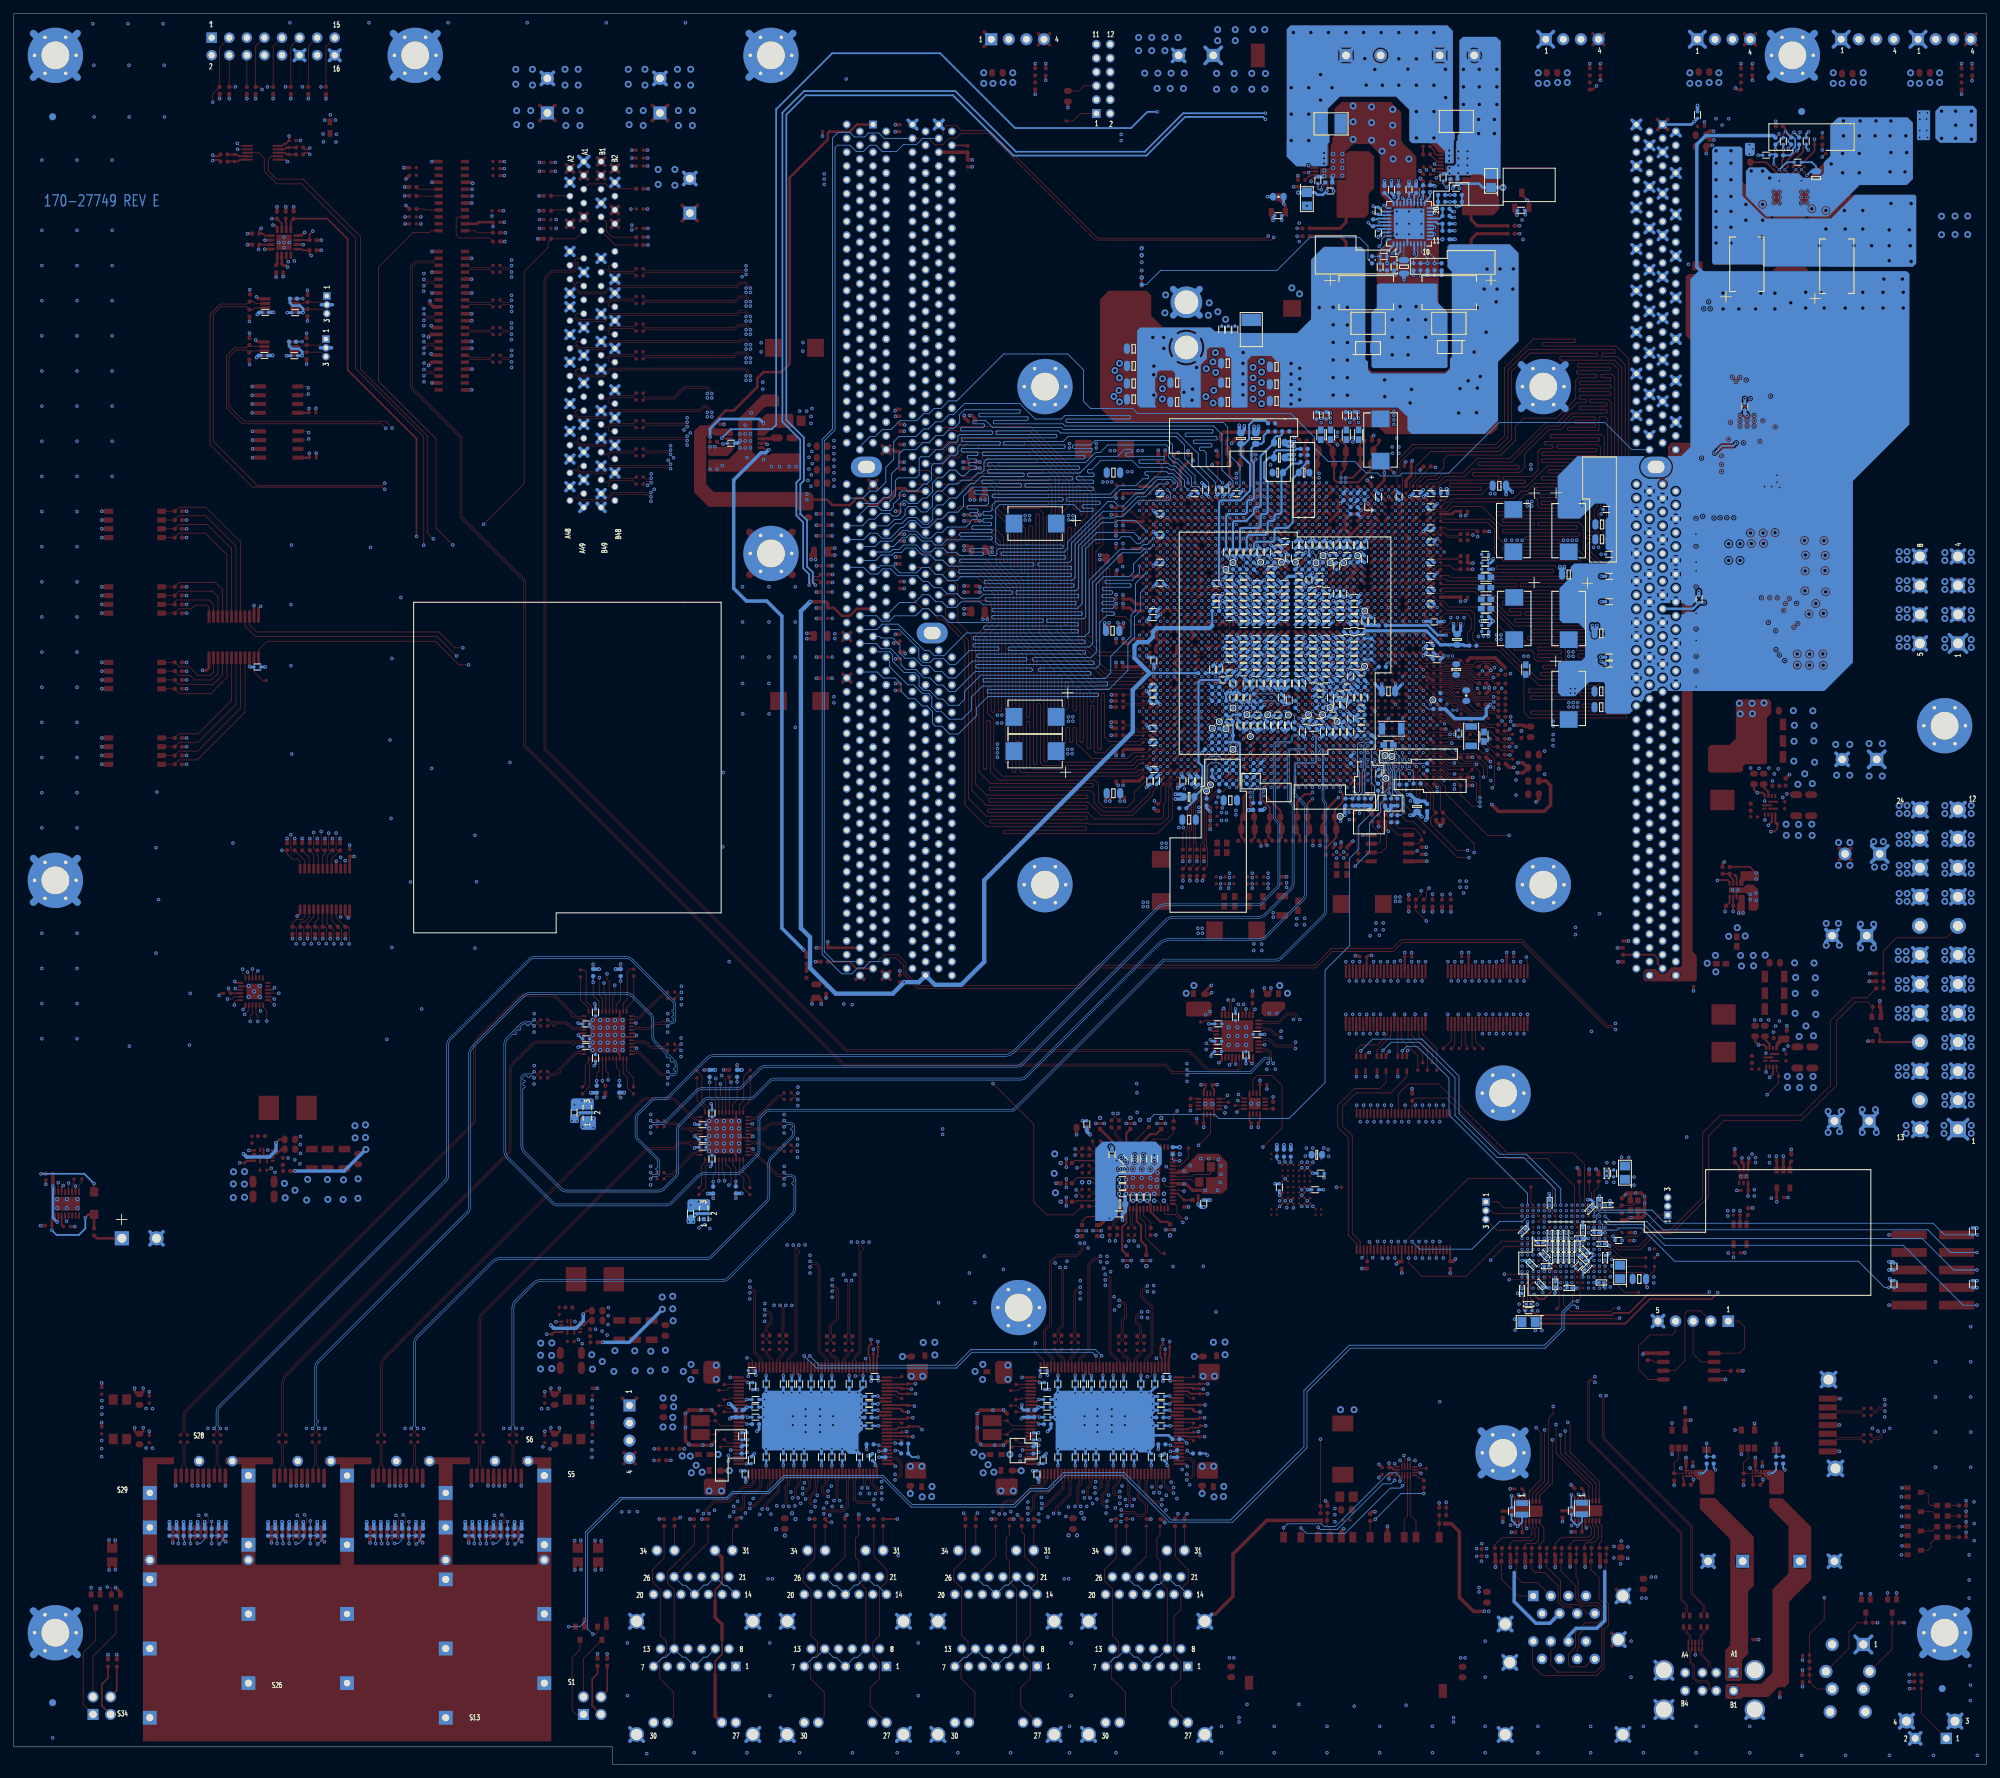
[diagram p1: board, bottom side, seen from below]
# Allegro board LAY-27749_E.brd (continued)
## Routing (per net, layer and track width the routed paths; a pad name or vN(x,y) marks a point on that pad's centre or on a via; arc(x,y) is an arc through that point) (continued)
M1_MDQ35: length 83.8
  TOP w0.118: v3(115.33,161.2) U22.AA8
  L5_INT_2 w0.087: J6.88 152.91,205 151.92,205.99 150.9,205.99 150.14,205.23 149.77,205.23 148.01,205.23 144.31,201.52 144.18,201.52 144.03,201.68 144.03,201.8 145.28,203.06 145.28,203.18 145.13,203.33 145.01,203.33 143.77,202.1 143.65,202.1 143.49,202.25 143.49,202.37 144.84,203.72 144.84,203.85 144.68,204.01 144.55,204.01 142.88,202.34 142.88,196.76 138.68,192.56 138.12,192.56 135.09,189.54 135.09,169.74 127.56,162.2 123.99,162.2 123.7,162.5 122.05,162.5 121.58,162.03 121.06,162.03 119.84,160.81 117.53,160.81 116.74,161.59 115.73,161.59 v3(115.33,161.2)
M1_MDQ36: length 83.8
  TOP w0.118: U22.T7 v3(116.33,156.2)
  L5_INT_2 w0.087: J6.200 151.35,196.31 149.99,194.94 149.1,194.94 144.99,190.84 144.99,183.35 144.9,183.26 144.68,183.26 144.6,183.35 144.6,188.84 144.51,188.93 144.29,188.93 144.2,188.84 144.2,171.03 144.11,170.94 143.9,170.94 143.81,171.03 143.81,174.63 143.69,174.75 143.5,174.75 143.41,174.66 143.41,169.92 130.54,157.05 123.77,157.05 123.47,156.74 121.41,156.74 121.26,156.59 116.73,156.59 v3(116.33,156.2)
M1_MDQ37: length 83.8
  TOP w0.118: U22.T8 v3(115.33,156.2)
  L5_INT_2 w0.087: v3(115.33,156.2) 115.93,156.79 120.85,156.79 121.21,157.15 123.27,157.15 123.57,157.45 130.39,157.45 143.02,170.08 143.02,187.45 143.11,187.53 143.33,187.53 143.41,187.45 143.41,178.23 143.5,178.14 143.72,178.14 143.81,178.23 143.81,190.29 148.08,194.56 148.08,196.63 J6.201
M1_MDQ38: length 83.8
  TOP w0.118: U22.Y7 v3(116.33,160.2)
  L5_INT_2 w0.087: v3(116.33,160.2) 116.94,159.59 120.17,159.59 120.35,159.77 121.67,159.77 121.84,159.94 121.84,160.45 122.07,160.68 122.68,160.68 123.02,161.02 128.74,161.02 136.28,168.56 136.28,181.03 137.07,181.82 137.07,184.36 137.08,184.37 137.08,184.43 137.85,185.2 137.85,186.82 137.94,186.91 138.15,186.91 138.24,186.82 138.24,185.28 138.33,185.19 138.55,185.19 138.64,185.28 138.64,191.27 138.73,191.36 138.94,191.36 139.03,191.27 139.03,185.28 139.12,185.18 139.39,185.18 139.5,185.29 139.5,191.67 144.35,196.52 144.35,199.21 148.14,203 J6.206
M1_MDQ39: length 83.9
  TOP w0.118: U22.Y8 v3(115.33,160.2)
  L5_INT_2 w0.087: J6.207 148.35,204 143.84,199.49 143.84,196.6 139.02,191.78 138.59,191.78 138.24,191.44 138.24,187.39 138.17,187.32 137.92,187.32 137.85,187.4 137.85,190.61 137.76,190.7 137.57,190.7 137.46,190.58 137.46,185.48 137.37,185.39 137.15,185.39 137.06,185.48 137.06,189.81 136.97,189.9 136.76,189.9 136.67,189.81 136.67,182.13 135.88,181.34 135.88,168.97 128.32,161.42 123.57,161.42 123.34,161.65 122.2,161.65 121.82,161.26 121.82,161.01 121.51,160.71 120.8,160.71 119.89,159.79 117.12,159.79 116.81,160.1 116.81,160.27 116.43,160.65 115.79,160.65 v3(115.33,160.2)
M1_MDQ40: length 87.6
  TOP w0.118: v3(111.33,157.2) U22.U11
  L7_INT_3 w0.087: J6.90 152.82,207 151.99,207.82 150.98,207.82 149.92,206.77 148.73,206.77 147.72,205.75 147.72,198.14 138.58,189.01 138.58,181.11 138.49,181.02 138.28,181.02 138.19,181.11 138.19,184.04 138.1,184.13 137.88,184.13 137.8,184.04 137.8,181.16 137.79,176.31 128.05,166.57 121.71,166.57 120.62,165.48 120.62,165.07 119.74,164.19 119.74,157.96 119.38,157.61 111.74,157.61 v3(111.33,157.2)
M1_MDQ41: length 87.6
  TOP w0.118: v3(110.33,157.2) U22.U12
  L7_INT_3 w0.087: v3(110.33,157.2) 110.95,157.81 118.63,157.81 118.87,158.05 118.87,163.96 120.12,165.2 120.12,165.43 121.65,166.96 127.89,166.96 137.36,176.43 137.36,188.19 137.46,188.29 137.67,188.29 137.76,188.2 137.76,184.73 137.85,184.65 138.06,184.65 138.15,184.73 138.15,189.14 147.32,198.31 147.32,206.28 148.21,207.16 149.76,207.16 150.83,208.23 152.25,208.23 152.48,208 J6.91
M1_MDQ42: length 87.6
  TOP w0.118: U22.Y12 v3(111.33,160.2)
  L7_INT_3 w0.087: J6.96 152.79,213 151.79,213.99 150.93,213.99 150.02,214.9 144.21,214.9 131.57,202.26 131.57,192.46 131.93,192.1 131.93,181.46 131.04,180.57 131.04,176.13 128.52,173.61 123.47,173.61 121.67,171.81 119.35,171.81 118.85,171.3 118.85,170.94 118.64,170.74 118.24,170.74 117.94,170.44 117.94,169.85 117.68,169.58 116.15,169.58 115.95,169.38 115.95,164.7 114.95,163.7 114.95,162.97 114.5,162.53 114.5,162 113.94,161.44 113.94,160.86 113.67,160.58 111.71,160.58 v3(111.33,160.2)
M1_MDQ43: length 87.6
  TOP w0.118: U22.Y13 109.83,160.7 v3(110.33,160.2)
  L7_INT_3 w0.087: v3(110.33,160.2) 110.92,160.78 113.49,160.78 113.72,161.01 113.72,161.52 114.27,162.08 114.27,162.59 114.73,163.04 114.73,163.83 115.72,164.82 115.72,169.47 116.06,169.81 117.49,169.81 117.71,170.04 117.71,171.18 118.24,171.7 118.44,171.7 118.87,172.14 118.87,172.34 119.2,172.67 120.35,172.67 120.93,173.25 120.93,173.38 121.28,173.74 121.67,173.74 122.17,174.24 126.75,174.24 130.65,178.15 130.65,180.74 131.53,181.62 131.53,191.94 131.11,192.37 131.11,202.42 145.66,216.96 150.07,216.96 150.95,216.08 151.71,216.08 153.25,214.54 J6.97
M1_MDQ44: length 87.6
  TOP w0.118: v3(113.33,157.2) U22.U9
  L7_INT_3 w0.087: J6.209 148.73,206 148.11,205.38 148.11,197.98 140.1,189.97 140.1,181.7 140.01,181.61 139.79,181.61 139.7,181.7 139.7,188.76 139.61,188.85 139.4,188.85 139.31,188.76 139.31,177.26 128.22,166.17 121.72,166.17 120.93,165.38 120.93,164.87 120.27,164.21 120.27,158.75 119.94,158.42 119.94,157.2 119.53,156.79 113.73,156.79 v3(113.33,157.2)
M1_MDQ45: length 87.6
  TOP w0.118: v3(112.33,157.2) U22.U10
  L7_INT_3 w0.087: v3(112.33,157.2) 112.93,156.59 120.52,156.59 120.78,156.84 120.78,163.75 121.79,164.77 121.79,165.38 122.19,165.78 128.38,165.78 139.95,177.35 139.95,180.72 140.49,181.26 140.49,187.36 140.58,187.45 140.79,187.45 140.88,187.36 140.88,182.11 140.97,182.02 141.19,182.02 141.28,182.11 141.28,190.59 148.5,197.82 148.5,204.67 148.81,204.98 149.76,204.98 151.35,206.57 J6.210
M1_MDQ46: length 87.6
  TOP w0.118: v3(114.33,160.2) 113.34,160.2 112.83,160.7 U22.Y10
  L7_INT_3 w0.087: v3(114.33,160.2) 114.92,160.78 115.7,160.78 115.93,161.01 115.93,163.7 116.94,164.72 116.94,168.43 117.12,168.6 118.61,168.6 118.92,168.91 118.92,169.47 119.15,169.7 121.46,169.7 123.34,171.58 127.6,171.58 133.86,177.83 133.86,189.75 140.58,196.47 141.37,197.26 141.37,208.98 141.28,209.06 141.06,209.06 140.97,208.98 140.97,206.22 140.89,206.14 140.68,206.14 140.58,206.23 140.58,209.96 143.23,212.61 144.64,212.61 144.73,212.52 144.73,212.3 144.64,212.21 143.7,212.21 143.61,212.13 143.61,211.91 143.7,211.82 145.03,211.82 145.82,212.61 148.84,212.61 J6.215
M1_MDQ47: length 87.6
  TOP w0.118: v3(112.33,160.2) U22.Y11
  L7_INT_3 w0.087: J6.216 142.97,213 140.07,210.09 140.07,206.07 140.85,205.29 140.85,202.32 140.76,202.23 140.55,202.23 140.46,202.32 140.46,204.86 140.37,204.95 140.15,204.95 140.07,204.86 140.07,201.69 140.77,200.99 140.77,197.22 133.3,189.75 133.3,177.83 127.55,172.08 122.89,172.08 121.54,170.74 119.3,170.74 118.72,170.15 118.72,168.99 118.53,168.8 117,168.8 116.71,168.52 116.71,164.85 115.72,163.86 115.72,162.03 115.5,161.8 115.03,161.8 114.73,161.5 114.73,161.04 114.39,160.69 114.19,160.69 113.69,160.19 113.69,160.2 v3(112.33,160.2)
M1_MDQ48: length 84.9
  TOP w0.118: U22.AB7 v3(115.33,162.2)
  L5_INT_2 w0.087: J6.99 152.37,215.12 152.37,212.57 151.89,212.09 151.31,212.09 150.01,210.79 149,210.79 147.92,209.71 147.92,208.41 147.31,207.8 143.22,207.8 143.13,207.71 143.13,207.5 143.23,207.4 145.31,207.4 145.4,207.31 145.4,207.1 145.31,207.01 143.63,207.01 141.9,205.28 141.9,197.16 138.28,193.54 137.65,193.54 134.1,189.99 134.1,170.19 127.51,163.6 122.17,163.6 121.87,163.3 121.87,163.19 121.39,162.71 121.06,162.71 119.94,161.59 117.14,161.59 116.94,161.8 115.72,161.8 v3(115.33,162.2)
M1_MDQ49: length 84.9
  TOP w0.118: v3(115.33,163.2) U22.AC7
  L5_INT_2 w0.087: J6.100 152.81,217 151.84,216.03 150.88,216.03 149.91,216.99 149.05,216.99 148.68,216.63 148.68,213.07 146.83,211.22 141.61,211.22 140.1,209.71 140.1,202.66 140.72,202.03 140.72,197.65 137.87,194.79 136.98,194.79 132.89,190.7 132.89,183.18 131.04,181.33 131.04,170.29 126.63,165.89 124.03,165.89 122.94,164.79 121.49,164.79 119.48,162.79 115.74,162.79 v3(115.33,163.19)
M1_MDQ50: length 84.9
  TOP w0.118: U22.AE6 v3(116.33,166.2)
  L5_INT_2 w0.087: J6.105 153.25,222.55 152,223.8 150.83,223.8 150.24,223.21 147.22,223.21 127.18,203.17 127.18,196.14 125.76,194.72 125.76,191.35 125.67,191.26 125.45,191.26 125.36,191.35 125.36,193.43 125.27,193.52 125.06,193.52 124.97,193.43 124.97,184.45 123.77,183.26 123.77,174.75 123.28,174.26 123.28,172.5 121.51,170.74 121.06,170.74 120.79,170.47 120.79,169.96 120.5,169.67 117.16,169.67 116.79,169.3 116.79,166.65 v3(116.33,166.2)
M1_MDQ51: length 84.8
  TOP w0.118: U22.AD7 115.33,165.19 v3(115.33,165.2)
  L5_INT_2 w0.087: v3(115.33,165.2) 115.82,165.69 115.82,169.42 116.08,169.67 116.46,169.67 116.84,170.05 116.84,170.43 117.16,170.75 119.7,170.75 120.52,171.58 120.52,172.12 121.12,172.72 121.54,172.72 121.92,173.1 121.92,175.01 123.11,176.2 123.11,183.85 122.64,184.32 122.64,188.17 123.34,188.87 123.34,192.94 126.77,196.37 126.77,203.32 148.34,224.89 149.89,224.89 150.57,224.21 152.15,224.21 152.86,224.92 153.65,224.92 155.15,223.41 J6.106
M1_MDQ52: length 84.8
  TOP w0.118: U22.AB5 v3(117.33,162.2)
  L5_INT_2 w0.087: v3(117.33,162.2) 117.61,161.91 117.73,161.8 119.61,161.8 120.13,162.32 120.13,162.67 121.49,164.03 127.3,164.03 133.71,170.43 133.71,190.15 137.49,193.93 138.12,193.93 141.51,197.32 141.51,206.95 142.86,208.31 147.23,208.31 147.33,208.4 147.33,208.61 147.24,208.7 142.92,208.7 142.83,208.79 142.83,209 142.92,209.09 146.63,209.09 148.77,211.23 149.77,211.23 150.5,211.96 150.5,213.23 150.81,213.54 150.81,214.46 J6.218
M1_MDQ53: length 84.8
  TOP w0.118: U22.AB6 v3(116.33,162.2)
  L5_INT_2 w0.087: v3(116.33,162.2) 116.72,162.59 119.66,162.59 121.48,164.4 123.13,164.4 124.18,165.46 127.08,165.46 133.27,171.65 133.27,183.01 133.28,183.02 133.28,190.28 137.32,194.32 137.95,194.32 141.12,197.49 141.12,208.14 142.8,209.83 146.33,209.83 146.42,209.92 146.42,210.14 146.34,210.22 142.1,210.22 142.01,210.32 142.01,210.52 142.11,210.62 146.81,210.62 149.3,213.11 149.73,213.11 150.24,213.61 150.24,215.21 J6.219
M1_MDQ54: length 84.9
  TOP w0.118: U22.AE5 v3(117.33,166.2)
  L5_INT_2 w0.087: v3(117.33,166.2) 117.86,166.72 117.86,168.4 118.17,168.72 120.08,168.72 121.01,169.65 121.54,169.65 123.6,171.7 125.73,171.7 126.87,172.85 126.87,182.63 125.48,184.02 125.48,187.58 127.33,189.43 127.33,190.55 127.1,190.78 127.1,194.53 127.19,194.62 127.41,194.62 127.5,194.53 127.5,191.81 127.58,191.72 127.8,191.72 127.97,191.88 127.97,203.4 147.37,222.81 150.03,222.81 151.35,221.49 J6.224
M1_MDQ55: length 84.9
  TOP w0.118: v3(116.33,165.2) 116.33,165.19 U22.AD6
  L5_INT_2 w0.087: v3(116.33,165.2) 116.87,165.74 117.73,165.74 118.75,166.75 118.75,167.26 119.13,167.64 120.4,167.64 120.8,168.05 120.8,168.4 121.11,168.71 121.44,168.71 123.95,171.22 126.83,171.22 127.36,171.74 127.36,183.24 128.52,184.4 128.52,189.75 128.44,189.84 128.22,189.84 128.13,189.75 128.13,185.82 128.04,185.73 127.83,185.73 127.74,185.82 127.74,190.73 128.4,191.39 128.4,203.27 147.12,222 J6.225
M1_MDQ56: length 95.9
  TOP w0.118: v3(113.33,163.2) U22.AC9
  L7_INT_3 w0.087: v3(113.33,163.19) 113.33,164.08 113.95,164.7 113.95,170.39 114.15,170.59 114.68,170.59 114.91,170.81 114.91,171.32 115.16,171.58 115.65,171.58 115.94,171.87 115.94,173.4 116.13,173.58 116.71,173.58 116.92,173.79 117.6,173.79 117.78,173.96 117.78,174.29 118.21,174.73 118.59,174.73 118.87,175.01 118.87,175.44 119.1,175.67 119.63,175.67 119.86,175.89 119.86,176.33 120.19,176.66 122.81,176.66 123.39,177.24 125.15,177.24 125.48,176.91 126.62,176.91 128.89,179.18 128.89,184.68 128.97,184.77 129.19,184.77 129.28,184.68 129.28,182.35 129.37,182.26 129.58,182.26 129.67,182.35 129.67,191.27 128.56,192.39 128.56,203.68 131.63,206.76 131.63,207.29 149.15,224.81 149.91,224.81 150.9,225.81 152.02,225.81 152.83,225 J6.108
M1_MDQ57: length 95.8
  TOP w0.118: U22.AD9 113.33,165.19 v3(113.33,165.2)
  L7_INT_3 w0.087: J6.109 152.48,226 152.25,226.23 150.77,226.23 149.79,225.25 149.78,225.25 149.77,225.23 149.01,225.23 131.24,207.45 131.24,206.92 128.16,203.85 128.16,192.23 129.27,191.12 129.27,185.65 128.41,184.8 128.41,180.53 128.32,180.44 128.1,180.44 128.02,180.53 128.02,183.02 127.93,183.11 127.7,183.11 127.61,183.02 127.61,179.53 127.52,179.44 127.3,179.44 127.22,179.53 127.22,181.6 127.13,181.69 126.91,181.69 126.82,181.6 126.82,179.4 125.2,177.77 120.27,177.77 119.84,177.34 119.84,177.09 119.46,176.71 119.2,176.71 118.82,176.33 118.82,176.05 118.49,175.72 118.16,175.72 117.83,175.39 117.83,175.06 117.4,174.62 117.07,174.62 116.76,174.32 116.76,174.04 116.53,173.81 116.03,173.81 115.71,173.49 115.71,171.97 115.55,171.81 115.06,171.81 114.71,171.45 114.71,170.99 114.5,170.79 114.02,170.79 113.72,170.49 113.72,165.59 113.61,165.48 v3(113.33,165.2)
M1_MDQ58: length 95.8
  TOP w0.118: U22.AB13 v3(109.33,162.2)
  L7_INT_3 w0.087: v3(109.33,162.2) 108.87,162.65 108.87,175.35 109.92,176.39 110.06,176.39 110.82,177.15 110.82,177.22 111.24,177.65 111.32,177.65 111.84,178.16 111.84,178.26 112.24,178.66 112.34,178.66 112.88,179.2 112.88,179.28 113.23,179.63 113.3,179.63 113.94,180.27 113.94,180.35 114.32,180.72 114.43,180.72 114.81,181.1 114.81,181.23 115.8,182.22 115.8,189.68 121.74,195.62 121.74,204.04 121.94,204.24 126.59,208.89 126.59,210.25 149.13,232.79 150.08,232.79 150.64,232.23 152.02,232.23 152.55,232.77 153.61,232.77 154.41,231.97 154.41,231.74 J6.114
M1_MDQ59: length 95.8
  TOP w0.118: v3(109.33,165.2) 109.33,164.19 U22.AC13
  L7_INT_3 w0.087: J6.115 152.48,232 152.26,231.78 150.5,231.78 149.95,231.23 148.36,231.23 126.98,209.85 126.98,208.72 122.33,204.08 122.13,203.87 122.13,194.92 117.55,190.34 117.55,186.16 117.46,186.07 117.25,186.07 117.16,186.16 117.16,188.77 117.07,188.86 116.86,188.86 116.76,188.76 116.76,182.09 116.28,181.61 116.08,181.61 115.84,181.37 115.84,181.06 115.52,180.75 115.27,180.75 114.81,180.29 114.81,180.09 114.4,179.68 114.2,179.68 113.84,179.32 113.84,179.1 113.41,178.66 113.18,178.66 112.83,178.31 112.83,178.1 112.45,177.72 112.19,177.72 111.84,177.37 111.84,177.09 111.46,176.71 111.15,176.71 109.96,175.51 109.96,175.35 109.96,175.35 109.96,165.82 v3(109.33,165.2)
M1_MDQ60: length 95.8
  TOP w0.118: U22.AB9 v3(113.33,162.2)
  L7_INT_3 w0.087: J6.227 148.89,224 132.02,207.13 132.02,206.44 129.74,204.16 129.74,197.97 129.65,197.88 129.43,197.88 129.34,197.97 129.34,203.46 129.25,203.55 129.04,203.55 128.95,203.46 128.95,192.55 130.15,191.35 130.15,182.17 129.28,181.3 129.28,178.94 125.9,175.55 124.29,175.55 123.6,176.25 121.08,176.25 119.56,174.73 119.28,174.73 118.9,174.35 118.9,173.94 118.54,173.58 117.14,173.58 116.71,173.15 116.71,170.96 116.56,170.81 116,170.81 115.75,170.56 115.75,170.08 115.47,169.8 114.99,169.8 114.71,169.52 114.71,164.75 113.72,163.75 113.72,162.58 v3(113.33,162.2)
M1_MDQ61: length 95.8
  TOP w0.118: v3(113.33,161.2) U22.AA9
  L7_INT_3 w0.087: v3(113.33,161.2) 113.33,161.54 113.94,162.15 113.94,163.49 114.94,164.48 114.94,169.42 115.12,169.6 115.57,169.6 115.95,169.98 115.95,170.43 116.1,170.58 116.66,170.58 116.94,170.87 116.94,172.39 117.13,172.59 118.64,172.59 118.82,172.77 118.82,173.48 119.05,173.71 119.79,173.71 120.78,174.7 121.74,174.7 122.2,175.16 126.14,175.16 129.67,178.7 129.67,181.14 130.56,182.02 130.56,191.5 129.34,192.72 129.34,197.27 129.43,197.36 129.65,197.36 129.74,197.27 129.74,193.17 129.83,193.08 130.04,193.08 130.13,193.17 130.13,203.92 132.42,206.2 132.42,206.91 148.52,223.01 150.11,223.01 151.35,224.25 J6.228
M1_MDQ62: length 95.8
  TOP w0.118: U22.AB12 v3(110.33,162.2)
  L7_INT_3 w0.087: v3(110.33,162.2) 110.7,162.57 110.7,164.4 110.91,164.6 110.91,174.38 111.23,174.7 111.43,174.7 111.91,175.18 111.91,176.33 112.17,176.58 113.36,176.58 113.84,177.06 113.84,177.32 114.22,177.7 114.48,177.7 114.91,178.13 114.91,179.32 115.16,179.58 116.41,179.58 116.87,180.03 116.87,180.37 117.2,180.7 117.53,180.7 117.83,181 117.83,181.36 118.21,181.74 118.54,181.74 118.82,182.02 118.82,182.3 119.28,182.75 119.63,182.75 120.14,183.26 120.14,191.47 120.25,191.57 120.45,191.57 120.54,191.48 120.54,187.68 120.62,187.59 120.84,187.59 120.93,187.68 120.93,191.8 122.92,193.78 122.92,203.55 127.77,208.4 127.77,209.25 148.52,230 J6.233
M1_MDQ63: length 95.8
  TOP w0.118: v3(110.33,163.2) U22.AC12
  L7_INT_3 w0.087: J6.234 150.58,231 150.42,230.84 148.53,230.84 127.37,209.68 127.37,208.56 122.73,203.91 122.52,203.71 122.52,194.61 119.14,191.22 119.14,185.73 119.05,185.65 118.84,185.65 118.74,185.75 118.74,189.06 118.65,189.15 118.44,189.15 118.35,189.06 118.35,186.21 117.94,185.8 117.94,182.48 117.82,182.36 117.82,182 117.47,181.66 117.14,181.66 116.84,181.36 116.84,181.03 116.48,180.67 116.23,180.67 115.84,180.28 115.84,180.02 115.6,179.78 115.06,179.78 114.71,179.43 114.71,178.89 114.53,178.71 114.22,178.71 113.83,178.32 113.83,178.02 113.49,177.67 113.16,177.67 112.8,177.32 112.8,176.99 112.62,176.81 112.12,176.81 111.71,176.4 111.71,175.89 111.48,175.67 111.2,175.67 110.72,175.18 110.72,164.9 110.33,164.51 v3(110.33,163.19)
M1_MDQS_N0: length 83.9
  TOP w0.091: v3(117.33,146.2) U22.F6
  L12_INT_5 w0.1: J6.6 154.79,119.35 154.43,119.35 153.92,118.85 152.76,118.85 151.78,119.82 150.89,119.82 149.81,120.9 130.07,120.9 128.93,122.04 128.93,130.68 128.83,130.78 128.04,130.78 127.94,130.68 127.94,123.76 127.69,123.51 126.69,123.51 126.44,123.76 126.44,137.81 126.34,137.91 125.55,137.91 125.45,137.81 125.45,134.39 125.2,134.14 124.2,134.14 123.95,134.39 123.95,136.88 119.7,141.13 118.91,141.13 118.14,141.91 117.61,141.91 116.72,142.79 116.72,143 116.74,143.02 116.74,145.49 117.04,145.79 117.61,145.79 117.73,145.91 117.73,146.08 117.61,146.2 v3(117.33,146.2)
M1_MDQS_N1: length 84.8
  TOP w0.091: U22.H5 v3(118.33,148.2)
  L5_INT_2 w0.1: v3(118.33,148.2) 118.33,147.92 118.19,147.79 117.97,147.79 117.72,147.54 117.72,145.95 118.08,145.59 119.55,145.59 119.74,145.41 119.74,142.97 119.71,142.95 119.71,142.69 120.17,142.24 120.17,140.08 121.21,139.04 121.21,132.86 123.08,130.99 130.81,130.99 130.91,130.89 130.91,130.1 130.81,130 124.84,130 124.59,129.75 124.59,128.75 124.84,128.5 129.81,128.5 129.91,128.4 129.91,127.61 129.81,127.51 126.97,127.51 126.72,127.26 126.72,126.26 126.97,126.01 129.13,126.01 133.6,121.54 138.03,121.54 141.35,124.86 141.35,128.27 142.02,128.94 149.83,128.94 150.89,127.87 151.95,127.87 152.9,128.83 153.82,128.83 154.13,128.52 154.13,128.24 153.88,128 J6.15
M1_MDQS_N2: length 83.8
  TOP w0.091: v3(114.33,153.2) U22.N8
  L14_INT_6 w0.1: v3(114.33,153.2) 114.57,153.2 114.66,153.11 114.66,152.83 114.9,152.59 117.52,152.59 117.73,152.37 117.73,149.96 118.08,149.61 121.56,149.61 121.59,149.58 122.6,149.58 126.16,146.02 126.16,144.04 131.88,138.32 139.43,138.32 140.87,136.88 140.87,133.5 141.12,133.25 142.12,133.25 142.37,133.5 142.37,137.51 142.47,137.61 143.26,137.61 143.36,137.51 143.36,125.66 143.61,125.41 144.61,125.41 144.86,125.66 144.86,136.91 145.56,137.61 147.95,137.61 149.11,138.77 149.89,138.77 150.84,137.82 151.69,137.82 152.65,136.86 153.92,136.86 154.33,137.26 154.89,137.26 J6.24
M1_MDQS_N3: length 83.8
  TOP w0.091: U22.N5 v3(117.33,153.2)
  L5_INT_2 w0.1: v3(117.33,153.2) 117.56,153.2 117.67,153.09 117.67,152.82 117.91,152.58 120.69,152.58 120.85,152.73 121.09,152.73 121.11,152.7 123.52,152.7 125.12,151.1 130.52,151.1 132.84,153.43 144.81,153.43 144.91,153.33 144.91,152.54 144.81,152.44 133.85,152.44 133.6,152.19 133.6,151.19 133.85,150.94 147.22,150.94 147.32,150.84 147.32,150.05 147.22,149.95 140.19,149.95 139.94,149.7 139.94,148.7 140.19,148.45 146.85,148.45 148.51,146.79 149.91,146.79 150.9,147.78 151.84,147.78 152.8,146.81 153.73,146.81 154.05,146.49 154.05,146.24 153.81,146 J6.33
M1_MDQS_N4: length 83.8
  TOP w0.091: U22.W7 v3(116.33,159.2)
  L5_INT_2 w0.1: v3(116.33,159.2) 116.05,159.2 115.98,159.12 115.98,158.95 116.13,158.79 119.6,158.79 119.81,159 119.81,159.03 119.96,159.18 122.17,159.18 123.02,160.03 129.19,160.03 137.41,168.25 137.41,180.7 138.05,181.33 138.05,183.95 138.3,184.2 139.3,184.2 139.55,183.95 139.55,179.38 139.65,179.28 140.44,179.28 140.54,179.38 140.54,191.32 145.36,196.14 145.36,197.69 148.9,201.22 149.98,201.22 150.84,202.08 151.56,202.08 152.5,203.02 153.84,203.02 154.43,202.43 154.43,201.29 154.73,201 J6.84
M1_MDQS_N5: length 87.7
  TOP w0.091: U22.W10 v3(113.33,159.2)
  L7_INT_3 w0.1: J6.93 154.12,210 154.31,210.18 154.31,210.46 153.89,210.87 152.75,210.87 151.74,211.89 151.03,211.89 150.02,210.87 148.44,210.87 145.09,207.52 145.09,205.3 144.84,205.05 143.84,205.05 143.59,205.3 143.59,207.13 143.49,207.23 142.71,207.23 142.6,207.13 142.6,196.74 135.13,189.27 135.13,177.35 128.57,170.79 123.93,170.79 121.72,168.58 121.51,168.58 121.49,168.6 120.17,168.6 119.94,168.38 119.94,167.92 119.61,167.59 118.12,167.59 117.92,167.39 117.92,164.66 116.92,163.65 116.92,159.88 116.63,159.6 113.13,159.6 112.96,159.43 112.96,159.33 113.09,159.19 113.33,159.19 v3(113.33,159.2)
M1_MDQS_N6: length 84.9
  TOP w0.091: U22.AD4 v3(118.33,165.2)
  L5_INT_2 w0.1: v3(118.33,165.2) 118.48,165.2 118.56,165.28 118.56,165.57 118.8,165.8 119.6,165.8 120.53,166.74 121.52,166.74 122.22,167.44 122.22,168.08 124.3,170.15 127.15,170.15 128.52,171.53 128.52,182.35 129.54,183.37 129.54,192.15 129.39,192.3 129.39,202.87 142.83,216.32 146.11,216.32 146.22,216.42 146.22,217.21 146.11,217.31 145.39,217.31 145.06,217.64 145.06,218.48 145.39,218.81 146.62,218.81 148.89,221.08 149.99,221.08 150.93,220.14 151.61,220.14 152.62,221.16 153.8,221.16 154.46,220.5 154.46,219.33 154.79,219 J6.102
M1_MDQS_N7: length 95.8
  TOP w0.091: U22.AB11 v3(111.33,162.2)
  L7_INT_3 w0.1: J6.111 153.86,228 154.04,228.18 154.04,228.54 153.72,228.86 152.84,228.86 151.95,227.97 150.89,227.97 150.09,228.77 149.04,228.77 129.01,208.74 129.01,207.88 124.16,203.03 124.16,193.27 123.62,192.74 123.62,188.82 122.37,187.57 122.37,186.03 123.9,184.51 123.9,181.23 122.66,179.98 120.98,179.98 120.57,179.58 119.56,179.58 119.53,179.6 117.75,179.6 116.94,178.79 116.94,177.9 116.64,177.6 116.14,177.6 115.93,177.39 115.93,176.89 115.62,176.58 115.12,176.58 114.94,176.39 114.94,175.87 114.66,175.59 114.13,175.59 113.92,175.38 113.92,173.89 113.61,173.58 112.14,173.58 111.94,173.38 111.94,162.84 111.69,162.59 111.46,162.59 111.33,162.46 v3(111.33,162.2)
M1_MDQS_N8: length 83.8
  TOP w0.091: U22.W5 v3(118.33,159.2)
  L14_INT_6 w0.1: v3(118.33,159.2) 118.61,159.2 118.73,159.08 118.73,158.84 118.99,158.58 120.84,158.58 120.88,158.55 121.44,158.55 122.27,159.38 123.2,159.38 124.4,158.18 126.3,158.18 127.31,159.18 146.9,159.18 146.98,159.11 146.98,158.32 146.88,158.22 128.05,158.22 127.69,157.86 127.69,157.03 128.03,156.69 146,156.69 146.33,156.36 146.33,155.32 146.71,154.94 147.45,154.94 147.83,155.32 147.83,156.6 148.15,156.92 149.71,156.92 150.79,155.84 151.62,155.84 152.62,154.85 154.01,154.85 154.48,155.32 154.83,155.32 J6.42
M1_MDQS_N9: length 83.8
  TOP w0.091: U22.D6 v3(116.33,144.2)
  L12_INT_5 w0.1: J6.126 150.89,118.54 150.52,118.54 149.94,119.13 148.21,119.13 146.51,117.42 132.88,117.42 132.78,117.53 132.78,118.31 132.88,118.41 146.08,118.41 146.33,118.66 146.33,119.66 146.08,119.91 127.99,119.91 125.45,122.45 125.45,131.47 117.98,138.94 117.98,140.92 115.96,142.93 115.96,143.09 115.93,143.12 115.93,143.8 v3(116.33,144.2)
M1_MDQS_N10: length 84.8
  TOP w0.091: U22.H6 v3(117.33,148.2)
  L5_INT_2 w0.1: v3(117.33,148.2) 117.05,148.2 116.94,148.08 116.94,144.63 117.95,143.62 117.95,143.04 117.98,143 117.98,142.42 119.18,141.22 119.18,135.15 120.19,134.14 120.19,131.37 131.09,120.47 145.63,120.47 145.73,120.57 145.73,121.36 145.63,121.46 142.89,121.46 142.64,121.71 142.64,122.71 142.89,122.96 145.88,122.96 145.99,123.06 145.99,123.85 145.88,123.95 142.62,123.95 142.37,124.2 142.37,125.2 142.62,125.45 146.84,125.45 146.94,125.55 146.94,126.34 146.84,126.44 142.59,126.44 142.34,126.69 142.34,127.69 142.59,127.94 147.65,127.94 148.44,127.15 150.24,127.15 150.52,127.44 150.52,127.64 150.16,128 J6.135
M1_MDQS_N11: length 83.8
  TOP w0.091: U22.M7 v3(116.33,152.2)
  L14_INT_6 w0.1: v3(116.33,152.2) 116.08,152.2 115.93,152.05 115.93,151.85 116.01,151.78 116.6,151.78 116.93,151.45 116.93,148.98 117.11,148.81 120.84,148.81 120.88,148.84 121.41,148.84 122.3,147.96 122.3,146.5 131.52,137.29 138.94,137.29 139.19,137.04 139.19,136.04 138.94,135.79 135.45,135.79 135.34,135.69 135.34,134.9 135.45,134.8 138.13,134.8 142.37,130.55 142.37,122.18 142.47,122.08 143.26,122.08 143.36,122.18 143.36,124.17 143.61,124.42 144.58,124.42 144.86,124.15 144.86,122.11 144.96,122.01 145.75,122.01 145.85,122.11 145.85,135.42 146.58,136.14 148.03,136.14 148.94,137.06 149.96,137.06 150.47,136.55 150.9,136.55 J6.144
M1_MDQS_N12: length 83.8
  TOP w0.091: U22.M4 v3(119.33,152.2)
  L5_INT_2 w0.1: J6.153 150.34,146 150.47,145.87 150.47,145.62 149.95,145.1 148.35,145.1 145.58,142.33 139.12,142.33 139.01,142.43 139.01,143.37 139.12,143.47 145.16,143.47 145.41,143.72 145.41,144.72 145.16,144.97 133.76,144.97 133.65,145.07 133.65,145.86 133.76,145.96 142.02,145.96 142.27,146.21 142.27,147.21 142.02,147.46 133.68,147.46 133.58,147.56 133.58,148.35 133.68,148.45 138.62,148.45 138.87,148.7 138.87,149.7 138.62,149.95 132.86,149.95 132.39,149.48 125.22,149.48 122.94,151.76 122.67,151.76 122.64,151.79 119.01,151.79 118.87,151.93 118.87,152.07 119,152.2 v3(119.33,152.2)
M1_MDQS_N13: length 83.8
  TOP w0.091: U22.V8 v3(115.33,158.2)
  L5_INT_2 w0.1: v3(115.33,158.2) 115.6,158.2 115.71,158.08 115.71,157.82 115.95,157.58 120.71,157.58 120.96,157.84 121.01,157.84 121.11,157.94 122.68,157.94 123.22,158.47 129.77,158.47 139.55,168.25 139.55,177.57 139.65,177.67 140.44,177.67 140.54,177.57 140.54,170.57 140.79,170.32 141.79,170.32 142.04,170.57 142.04,190.7 147.04,195.7 147.04,197.1 148.87,198.93 150.04,198.93 150.95,199.84 150.95,200.6 J6.204
M1_MDQS_N14: length 87.6
  TOP w0.091: U22.V11 v3(112.33,158.2)
  L7_INT_3 w0.1: J6.213 150.01,210 150.24,209.77 150.24,209.58 149.69,209.03 148.33,209.03 146.08,206.79 146.08,199.06 145.98,198.96 145.19,198.96 145.09,199.06 145.09,203.47 144.84,203.72 143.84,203.72 143.59,203.47 143.59,196.33 136.12,188.86 136.12,176.94 128.98,169.8 125.48,169.8 125.23,170.05 124.25,170.05 122.01,167.82 121.62,167.82 121.59,167.79 121.02,167.79 120.73,167.5 120.73,167.01 120.51,166.8 119.02,166.8 118.72,166.5 118.72,164.69 117.72,163.69 117.72,159 117.53,158.8 112.96,158.8 112.72,158.57 112.72,158.32 112.6,158.19 112.33,158.19 v3(112.33,158.2)
M1_MDQS_N15: length 84.9
  TOP w0.091: v3(118.33,163.19) U22.AC5
  L5_INT_2 w0.1: J6.222 151.04,218.69 150.52,218.69 150.16,219.05 148.71,219.05 147.46,217.8 147.46,215.43 146.98,214.95 143.29,214.95 143.04,214.7 143.04,213.7 143.29,213.45 146.28,213.45 146.38,213.35 146.38,212.56 146.28,212.46 140.73,212.46 130.66,202.38 130.66,193.24 131.17,192.73 131.17,183.21 129.77,181.82 129.77,170.99 125.91,167.13 123.67,167.13 122.4,165.86 121.03,165.86 119.68,164.52 119.1,164.52 118.69,164.11 118.69,163.56 118.62,163.48 v3(118.33,163.19)
M1_MDQS_N16: length 95.8
  TOP w0.091: v3(112.33,163.2) U22.AC10
  L7_INT_3 w0.1: J6.231 149.98,228 150.27,227.72 150.27,227.35 150.04,227.13 148.8,227.13 130,208.33 130,207.47 127,204.48 127,204.44 126.92,204.36 126.92,196.32 126.7,196.09 125.4,196.09 125.15,195.84 125.15,194.84 125.4,194.59 126.82,194.59 126.92,194.49 126.92,193.7 126.82,193.6 125.89,193.6 124.71,192.43 124.71,188.87 125.75,187.83 127.1,187.83 127.2,187.73 127.2,186.94 127.1,186.84 125.96,186.84 125.53,186.41 125.53,184.5 126.37,183.66 126.37,183.01 125.4,182.04 125.4,181.13 123.11,178.84 120.84,178.84 120.87,178.81 119.01,178.81 118.72,178.52 118.72,177.93 118.58,177.8 118.06,177.8 117.73,177.47 117.73,177 117.54,176.81 117.02,176.81 116.71,176.5 116.71,175.98 116.53,175.79 116.04,175.79 115.72,175.47 115.72,174.99 115.54,174.8 115.05,174.8 114.74,174.49 114.74,172.97 114.59,172.81 113.05,172.81 112.74,172.51 112.74,162.94 112.64,162.84 112.5,162.84 112.33,163.01 v3(112.33,163.19)
M1_MDQS_N17: length 83.9
  TOP w0.091: U22.V4 v3(119.33,158.2)
  L14_INT_6 w0.1: v3(119.33,158.2) 119.03,158.2 118.93,158.1 118.93,157.97 119.12,157.78 120.5,157.78 120.52,157.81 123.34,157.81 123.96,157.19 126.13,157.19 127.62,155.7 127.71,155.7 127.72,155.7 145.09,155.7 145.34,155.45 145.34,154.45 145.09,154.2 130.4,154.2 130.3,154.1 130.3,153.31 130.4,153.21 139.82,153.21 140.07,152.96 140.07,151.96 139.82,151.71 133.82,151.71 133.72,151.61 133.72,150.83 133.82,150.72 140.23,150.72 142.72,153.21 147.14,153.21 148.99,155.07 149.86,155.07 150.47,154.46 150.81,154.46 J6.162
M1_MDQS_P0: length 83.8
  TOP w0.091: v3(118.33,146.2) U22.F5
  L12_INT_5 w0.1: v3(118.33,146.2) 118.08,146.2 117.93,146.05 117.93,145.82 117.7,145.59 117.12,145.59 116.94,145.41 116.94,143.04 116.98,143 116.98,142.9 117.72,142.16 118.24,142.16 119.01,141.39 119.81,141.39 124.21,136.99 124.21,134.49 124.31,134.39 125.09,134.39 125.2,134.49 125.2,137.92 125.45,138.17 126.45,138.17 126.7,137.92 126.7,123.87 126.8,123.77 127.58,123.77 127.69,123.87 127.69,130.79 127.94,131.04 128.93,131.04 129.18,130.79 129.18,122.15 130.18,121.16 149.92,121.16 151,120.08 151.89,120.08 152.87,119.1 153.82,119.1 154.31,119.59 154.31,119.86 154.17,120 J6.7
M1_MDQS_P1: length 84.8
  TOP w0.091: v3(118.33,147.2) U22.G5
  L5_INT_2 w0.1: J6.16 155.15,128.48 154.89,128.22 154.51,128.22 154.38,128.35 154.38,128.63 153.93,129.08 152.8,129.08 151.84,128.13 151,128.13 149.93,129.19 141.92,129.19 141.1,128.38 141.1,124.97 137.92,121.79 133.71,121.79 129.24,126.26 127.08,126.26 126.97,126.36 126.97,127.15 127.08,127.25 129.91,127.25 130.16,127.5 130.16,128.5 129.91,128.75 124.94,128.75 124.84,128.85 124.84,129.64 124.94,129.74 130.92,129.74 131.17,129.99 131.17,130.99 130.92,131.24 123.19,131.24 121.46,132.97 121.46,139.14 120.42,140.18 120.42,142.34 119.96,142.8 119.96,142.95 119.94,142.97 119.94,145.49 119.63,145.8 118.16,145.8 117.92,146.03 117.92,147.46 118.05,147.58 118.2,147.58 118.33,147.46 v3(118.33,147.2)
M1_MDQS_P2: length 83.8
  TOP w0.091: U22.N7 v3(115.33,153.2)
  L14_INT_6 w0.1: J6.25 153.9,138 154.18,137.72 154.18,137.47 153.82,137.11 152.76,137.11 151.79,138.07 150.94,138.07 149.99,139.03 149.01,139.03 147.85,137.87 145.46,137.87 144.61,137.02 144.61,125.77 144.5,125.67 143.72,125.67 143.62,125.77 143.62,137.61 143.37,137.86 142.37,137.86 142.12,137.61 142.12,133.6 142.02,133.5 141.23,133.5 141.13,133.6 141.13,136.98 139.53,138.58 131.99,138.58 126.42,144.15 126.42,146.13 122.71,149.83 121.56,149.83 121.54,149.81 118.17,149.81 117.93,150.05 117.93,152.46 117.6,152.79 114.99,152.79 114.86,152.92 114.86,153.09 114.97,153.2 v3(115.33,153.2)
M1_MDQS_P3: length 83.8
  TOP w0.091: U22.N4 v3(118.33,153.2)
  L5_INT_2 w0.1: v3(118.33,153.2) 118,153.2 117.87,153.06 117.87,152.91 118,152.78 120.61,152.78 120.76,152.93 121.17,152.93 121.2,152.91 123.68,152.91 125.23,151.36 130.41,151.36 132.74,153.68 144.91,153.68 145.16,153.43 145.16,152.43 144.91,152.18 133.96,152.18 133.86,152.08 133.86,151.3 133.96,151.19 147.32,151.19 147.57,150.94 147.57,149.95 147.32,149.69 140.3,149.69 140.2,149.59 140.2,148.81 140.3,148.7 146.95,148.7 148.62,147.04 149.8,147.04 150.79,148.03 151.94,148.03 152.91,147.07 153.83,147.07 154.39,146.51 154.66,146.51 J6.34
M1_MDQS_P4: length 83.8
  TOP w0.091: U22.W8 v3(115.33,159.2)
  L5_INT_2 w0.1: J6.85 153.78,201.47 154.05,201.47 154.18,201.6 154.18,202.32 153.73,202.77 152.6,202.77 151.66,201.83 150.95,201.83 150.08,200.96 149,200.96 145.62,197.58 145.62,196.04 140.79,191.21 140.79,179.27 140.54,179.02 139.54,179.02 139.29,179.27 139.29,183.84 139.19,183.95 138.4,183.95 138.3,183.84 138.3,181.23 137.67,180.59 137.67,168.15 129.3,159.78 123.13,159.78 122.28,158.93 120.07,158.93 119.99,158.85 119.95,158.85 119.68,158.59 116.05,158.59 115.77,158.86 115.77,159.09 115.67,159.2 v3(115.33,159.2)
M1_MDQS_P5: length 87.7
  TOP w0.091: U22.W11 v3(112.33,159.2)
  L7_INT_3 w0.1: v3(112.33,159.2) 112.34,159.18 112.65,159.18 112.75,159.29 112.75,159.52 113.04,159.8 116.55,159.8 116.71,159.97 116.71,163.74 117.72,164.74 117.72,167.47 118.03,167.79 119.52,167.79 119.74,168 119.74,168.46 120.08,168.81 121.49,168.81 121.51,168.83 121.61,168.83 123.82,171.04 128.46,171.04 134.87,177.45 134.87,189.37 142.35,196.85 142.35,207.24 142.6,207.49 143.6,207.49 143.85,207.24 143.85,205.41 143.95,205.31 144.74,205.31 144.84,205.41 144.84,207.63 148.34,211.12 149.91,211.12 150.93,212.14 151.84,212.14 152.86,211.12 154,211.12 154.45,210.67 154.82,210.67 J6.94
M1_MDQS_P6: length 84.9
  TOP w0.091: U22.AE4 118.83,165.29 118.93,165.2 v3(119.33,165.2)
  L5_INT_2 w0.1: J6.103 153.84,219.4 154.08,219.4 154.2,219.53 154.2,220.39 153.69,220.9 152.73,220.9 151.71,219.89 150.82,219.89 149.88,220.83 149,220.83 146.72,218.55 145.49,218.55 145.31,218.37 145.31,217.75 145.49,217.56 146.22,217.56 146.47,217.31 146.47,216.32 146.22,216.06 142.94,216.06 129.64,202.77 129.64,192.4 129.79,192.25 129.79,183.26 128.78,182.24 128.78,171.42 127.25,169.9 124.41,169.9 122.48,167.97 122.48,167.33 121.63,166.48 120.64,166.48 120.07,165.92 120,165.92 120,165.92 119.68,165.6 119.16,165.6 118.88,165.6 118.77,165.48 118.77,165.28 118.85,165.2 v3(119.33,165.2)
M1_MDQS_P7: length 95.8
  TOP w0.091: v3(111.33,163.2) U22.AC11
  L7_INT_3 w0.1: J6.112 154.9,228.75 154.19,228.75 153.82,229.12 152.74,229.12 151.85,228.22 151,228.22 150.19,229.03 148.94,229.03 128.75,208.84 128.75,207.99 123.9,203.14 123.9,193.37 123.37,192.84 123.37,188.92 122.12,187.67 122.12,185.93 123.65,184.4 123.65,181.33 122.55,180.24 120.87,180.24 120.47,179.83 119.56,179.83 119.53,179.81 117.67,179.81 116.74,178.87 116.74,177.99 116.55,177.8 116.05,177.8 115.72,177.47 115.72,176.97 115.54,176.78 115.04,176.78 114.73,176.48 114.73,175.95 114.57,175.79 114.05,175.79 113.72,175.46 113.72,173.97 113.53,173.79 112.06,173.79 111.74,173.47 111.74,162.93 111.61,162.8 111.43,162.8 111.33,162.9 v3(111.33,163.19)
M1_MDQS_P8: length 83.8
  TOP w0.091: U22.W4 v3(119.33,159.2)
  L14_INT_6 w0.1: J6.43 154.01,156 154.25,155.75 154.25,155.5 154.25,155.45 153.91,155.11 152.72,155.11 151.73,156.1 150.89,156.1 149.82,157.18 148.05,157.18 147.57,156.7 147.57,155.42 147.35,155.19 146.81,155.19 146.58,155.42 146.58,156.46 146.1,156.95 128.13,156.95 127.95,157.13 127.95,157.75 128.16,157.96 146.98,157.96 147.23,158.21 147.23,159.21 147,159.44 127.2,159.44 126.2,158.43 124.5,158.43 123.3,159.63 122.17,159.63 121.34,158.8 120.78,158.8 120.76,158.79 119.07,158.79 118.93,158.93 118.93,159.11 119.02,159.2 v3(119.33,159.2)
M1_MDQS_P9: length 83.8
  TOP w0.091: U22.D7 v3(115.33,144.2)
  L12_INT_5 w0.1: J6.125 149.88,118 150.16,118.29 150.16,118.54 149.83,118.87 148.31,118.87 146.61,117.17 132.77,117.17 132.52,117.42 132.52,118.42 132.77,118.67 145.97,118.67 146.08,118.77 146.08,119.56 145.97,119.66 127.89,119.66 125.2,122.35 125.2,131.37 117.72,138.84 117.72,140.82 115.71,142.83 115.71,143.07 115.73,143.08 115.73,143.8 v3(115.33,144.2)
M1_MDQS_P10: length 84.8
  TOP w0.091: U22.H7 v3(116.33,148.2)
  L5_INT_2 w0.1: J6.134 151.04,127.3 150.75,127.3 150.34,126.9 148.33,126.9 147.54,127.69 142.7,127.69 142.6,127.58 142.6,126.8 142.7,126.7 146.94,126.7 147.19,126.45 147.19,125.45 146.94,125.2 142.72,125.2 142.62,125.09 142.62,124.31 142.72,124.21 145.99,124.21 146.24,123.96 146.24,122.96 145.99,122.71 142.99,122.71 142.89,122.61 142.89,121.82 142.99,121.72 145.74,121.72 145.99,121.47 145.99,120.47 145.74,120.22 130.98,120.22 119.94,131.26 119.94,134.03 118.92,135.05 118.92,141.12 117.73,142.31 117.73,143 117.75,143.02 117.75,143.54 116.74,144.54 116.74,148.08 116.63,148.2 v3(116.33,148.2)
M1_MDQS_P11: length 83.8
  TOP w0.091: U22.M8 v3(115.33,152.2)
  L14_INT_6 w0.1: J6.143 149.97,136 150.19,136.22 150.19,136.47 149.86,136.8 149.05,136.8 148.13,135.89 146.69,135.89 146.1,135.31 146.1,122.01 145.85,121.76 144.86,121.76 144.61,122.01 144.61,124.04 144.48,124.17 143.72,124.17 143.62,124.07 143.62,122.07 143.37,121.82 142.37,121.82 142.12,122.07 142.12,130.45 138.02,134.54 135.34,134.54 135.09,134.79 135.09,135.79 135.34,136.04 138.84,136.04 138.94,136.14 138.94,136.93 138.84,137.03 131.41,137.03 122.05,146.4 122.05,147.85 121.26,148.64 120.96,148.64 120.92,148.6 117.02,148.6 116.73,148.9 116.73,151.36 116.51,151.58 115.92,151.58 115.73,151.77 115.73,152.01 115.54,152.2 v3(115.33,152.2)
M1_MDQS_P12: length 83.8
  TOP w0.091: U22.M5 v3(118.33,152.2)
  L5_INT_2 w0.1: J6.152 150.93,145.41 150.62,145.41 150.05,144.84 148.45,144.84 145.69,142.07 139.01,142.07 138.76,142.33 138.76,143.48 139.01,143.73 145.06,143.73 145.16,143.83 145.16,144.61 145.06,144.72 133.65,144.72 133.4,144.97 133.4,145.96 133.65,146.22 141.91,146.22 142.01,146.32 142.01,147.1 141.91,147.21 133.58,147.21 133.33,147.46 133.33,148.45 133.58,148.7 138.52,148.7 138.62,148.81 138.62,149.59 138.52,149.69 132.97,149.69 132.5,149.22 125.12,149.22 122.78,151.56 122.58,151.56 122.56,151.59 118.93,151.59 118.67,151.85 118.67,152.07 118.54,152.2 v3(118.33,152.2)
M1_MDQS_P13: length 83.8
  TOP w0.091: U22.V7 v3(116.33,158.2)
  L5_INT_2 w0.1: J6.203 149.96,200.51 150.5,200.51 150.7,200.3 150.7,199.95 149.94,199.19 148.77,199.19 146.79,197.21 146.79,195.81 141.78,190.8 141.78,170.68 141.68,170.57 140.89,170.57 140.79,170.68 140.79,177.68 140.54,177.93 139.54,177.93 139.29,177.68 139.29,168.35 129.66,158.72 123.11,158.72 122.58,158.19 121,158.19 120.78,157.97 120.78,157.94 120.62,157.78 116.04,157.78 115.91,157.91 115.91,158.08 116.03,158.2 v3(116.33,158.2)
M1_MDQS_P14: length 87.6
  TOP w0.091: U22.V10 v3(113.33,158.2)
  L7_INT_3 w0.1: v3(113.33,158.2) 113.33,158.19 113.05,158.19 112.92,158.32 112.92,158.48 113.04,158.6 117.61,158.6 117.92,158.91 117.92,163.61 118.92,164.61 118.92,166.41 119.11,166.6 120.6,166.6 120.93,166.93 120.93,167.41 121.11,167.59 121.59,167.59 121.62,167.56 122.12,167.56 124.35,169.8 125.12,169.8 125.37,169.54 129.08,169.54 136.37,176.83 136.37,188.75 143.85,196.23 143.85,203.36 143.95,203.47 144.74,203.47 144.84,203.36 144.84,198.95 145.09,198.7 146.09,198.7 146.34,198.95 146.34,206.68 148.43,208.77 149.79,208.77 150.53,209.51 150.84,209.51 J6.212
M1_MDQS_P15: length 84.9
  TOP w0.091: v3(119.33,163.19) U22.AC4
  L5_INT_2 w0.1: J6.221 150.39,218 150.52,218.13 150.52,218.33 150.06,218.8 148.82,218.8 147.71,217.69 147.71,215.32 147.08,214.69 143.4,214.69 143.29,214.59 143.29,213.8 143.4,213.7 146.38,213.7 146.63,213.45 146.63,212.45 146.38,212.2 140.84,212.2 130.91,202.28 130.91,193.34 131.42,192.84 131.42,183.11 130.02,181.71 130.02,170.89 126.01,166.88 123.78,166.88 122.51,165.61 121.13,165.61 119.79,164.26 119.2,164.26 118.95,164.01 118.95,163.58 119.04,163.48 v3(119.33,163.19)
M1_MDQS_P16: length 95.8
  TOP w0.091: U22.AB10 v3(112.33,162.2)
  L7_INT_3 w0.1: J6.230 151.04,227.3 150.58,227.3 150.15,226.87 148.9,226.87 130.25,208.22 130.25,207.37 127.25,204.37 127.25,204.33 127.18,204.26 127.18,196.21 126.8,195.83 125.5,195.83 125.4,195.73 125.4,194.94 125.5,194.84 126.93,194.84 127.18,194.59 127.18,193.59 126.93,193.34 125.99,193.34 124.97,192.32 124.97,188.98 125.86,188.09 127.21,188.09 127.46,187.84 127.46,186.84 127.21,186.59 126.06,186.59 125.78,186.3 125.78,184.61 126.63,183.76 126.63,182.91 125.65,181.94 125.65,181.03 123.22,178.59 120.8,178.59 120.79,178.6 119.09,178.6 118.92,178.43 118.92,177.85 118.67,177.6 118.14,177.6 117.93,177.39 117.93,176.91 117.63,176.61 117.1,176.61 116.92,176.42 116.92,175.89 116.61,175.59 116.13,175.59 115.93,175.39 115.93,174.9 115.62,174.6 115.14,174.6 114.95,174.41 114.95,172.88 114.67,172.61 113.13,172.61 112.95,172.42 112.95,162.85 112.73,162.63 112.45,162.63 112.33,162.51 v3(112.33,162.2)
M1_MDQS_P17: length 83.8
  TOP w0.091: U22.V5 v3(118.33,158.2)
  L14_INT_6 w0.1: J6.161 150.11,154 150.24,154.13 150.24,154.33 149.75,154.81 149.1,154.81 147.24,152.96 142.82,152.96 140.34,150.47 133.71,150.47 133.46,150.72 133.46,151.72 133.71,151.97 139.71,151.97 139.81,152.07 139.81,152.86 139.71,152.96 130.3,152.96 130.05,153.21 130.05,154.21 130.3,154.46 144.98,154.46 145.08,154.56 145.08,155.35 144.98,155.45 127.61,155.45 127.61,155.45 127.51,155.45 126.03,156.93 123.86,156.93 123.24,157.56 120.63,157.56 120.6,157.58 119.04,157.58 118.73,157.89 118.73,158.08 118.61,158.2 v3(118.33,158.2)
M1_MECC0: length 83.8
  TOP w0.118: U22.U5 v3(118.33,157.2)
  L14_INT_6 w0.087: J6.39 154.18,151.07 154.18,147.45 153.77,147.04 152.81,147.04 151.71,145.95 150.79,145.95 149.91,146.82 148.84,146.82 148.75,146.73 145.84,146.73 145.09,147.48 143.4,147.48 143.31,147.39 143.31,147.17 143.4,147.09 144.93,147.09 145.02,147 145.02,146.78 144.93,146.69 143.36,146.69 143.28,146.6 143.28,146.39 143.36,146.3 148.28,146.3 148.37,146.21 148.37,145.97 148.28,145.88 143.47,145.88 143.38,145.8 143.38,145.58 143.47,145.49 148.42,145.49 148.51,145.4 148.51,145.19 148.42,145.1 131.76,145.1 131.15,145.71 131.15,148.63 131.06,148.72 130.84,148.72 130.75,148.63 130.75,146.43 130.67,146.34 130.45,146.34 130.36,146.43 130.36,149.31 130.27,149.4 130.05,149.4 129.97,149.31 129.97,148.53 129.88,148.44 129.66,148.44 129.57,148.53 129.57,150.18 127.32,152.43 125.14,152.43 122.78,154.79 120.17,154.79 119.86,155.09 119.86,155.4 119.68,155.57 118.24,155.57 117.93,155.88 117.93,156.8 v3(118.33,157.2)
M1_MECC1: length 83.8
  TOP w0.118: U22.U4 v3(119.33,157.2)
  L14_INT_6 w0.087: v3(119.33,157.2) 119.73,156.79 121.02,156.79 121.38,156.43 122.97,156.43 123.45,155.95 125.58,155.95 125.68,155.85 125.68,155.64 125.59,155.56 124.29,155.56 124.21,155.47 124.21,155.25 124.29,155.16 126.41,155.16 127.11,154.47 127.11,154.47 127.14,154.43 128.97,154.43 129.06,154.34 129.06,154.13 128.97,154.04 127.99,154.04 127.9,153.95 127.9,153.73 127.99,153.64 128.97,153.64 129.06,153.56 129.06,153.34 128.97,153.25 128.74,153.25 128.65,153.16 128.65,152.91 132.86,148.7 134.24,148.7 134.33,148.79 134.33,149 134.24,149.09 133.04,149.09 132.94,149.19 132.94,149.4 133.03,149.49 148.18,149.49 148.27,149.57 148.27,149.79 148.18,149.88 143.27,149.88 143.18,149.97 143.18,150.18 143.27,150.27 148.16,150.27 148.27,150.39 148.27,150.61 148.19,150.7 143.28,150.7 143.19,150.79 143.19,151 143.28,151.09 148.18,151.09 148.27,151.18 148.27,151.4 148.18,151.49 143.4,151.49 143.31,151.57 143.31,151.79 143.4,151.88 148.2,151.88 148.52,152.21 148.52,152.7 148.85,153.03 149.84,153.03 150.8,152.07 151.92,152.07 152.85,153 J6.40
M1_MECC2: length 83.8
  TOP w0.118: v3(118.33,161.2) U22.AA5
  L14_INT_6 w0.087: v3(118.33,161.2) 118.71,160.81 119.54,160.81 121.14,162.41 123.25,162.41 124.41,163.58 127.2,163.58 127.98,164.36 131.01,164.36 131.1,164.27 131.1,164.05 131.01,163.96 128.16,163.96 128.07,163.87 128.07,163.66 128.16,163.57 148.23,163.57 148.32,163.48 148.32,163.26 148.23,163.18 130.38,163.18 130.29,163.09 130.29,162.87 130.38,162.78 148.75,162.78 149.15,162.38 149.15,161.39 150.37,160.17 150.37,158.89 151.26,158 J6.45
M1_MECC3: length 83.8
  TOP w0.118: v3(119.33,161.2) U22.AA4
  L14_INT_6 w0.087: J6.46 152.89,159 151.87,160.02 151.13,160.02 149.61,161.54 149.61,162.81 148.46,163.96 131.58,163.96 131.49,164.05 131.49,164.27 131.58,164.36 146.02,164.36 146.11,164.45 146.11,164.66 146.02,164.75 128.72,164.75 128.63,164.84 128.63,165.06 128.72,165.14 134.13,165.14 134.22,165.23 134.22,165.45 134.13,165.54 128.56,165.54 127.18,164.16 120.35,164.16 119.76,163.58 119.76,161.63 v3(119.33,161.2)
M1_MECC4: length 83.8
  TOP w0.118: U22.T5 v3(118.33,156.2)
  L14_INT_6 w0.087: v3(118.33,156.2) 118.72,155.8 121.54,155.8 121.83,155.51 122.67,155.51 124.9,153.28 127.16,153.28 133.38,147.07 141.97,147.07 142.06,146.98 142.06,146.76 141.97,146.67 133.48,146.67 133.39,146.58 133.39,146.37 133.48,146.28 141.95,146.28 142.04,146.19 142.04,145.97 141.95,145.88 133.44,145.88 133.35,145.8 133.35,145.58 133.44,145.49 142.14,145.49 142.45,145.8 142.45,147.66 142.7,147.91 148.3,147.91 148.39,147.82 148.39,147.61 148.3,147.52 146.14,147.52 146.05,147.43 146.05,147.21 146.14,147.12 148.58,147.12 148.69,147.23 150.15,147.23 150.42,147.5 150.42,150.07 J6.158
M1_MECC5: length 83.8
  TOP w0.118: U22.T4 v3(119.33,156.2)
  L14_INT_6 w0.087: J6.159 148.68,151.23 148.68,149.32 148.46,149.09 134.81,149.09 134.72,149 134.72,148.79 134.81,148.7 148.35,148.7 148.44,148.61 148.44,148.39 148.35,148.3 133.65,148.3 133.56,148.22 133.56,148 133.65,147.91 141.97,147.91 142.06,147.82 142.06,147.61 141.97,147.52 133.48,147.52 126.87,154.13 126.03,154.13 125.86,154.31 125.86,154.68 125.77,154.77 125.55,154.77 125.46,154.68 125.46,154.17 125.27,153.97 124.82,153.97 122.63,156.16 121.15,156.16 120.71,156.59 119.73,156.59 v3(119.33,156.2)
M1_MECC6: length 83.8
  TOP w0.118: U22.Y5 v3(118.33,160.2)
  L14_INT_6 w0.087: v3(118.33,160.2) 118.71,160.58 119.94,160.58 121.23,161.87 125.51,161.87 126.81,163.18 129.43,163.18 129.51,163.09 129.51,162.87 129.43,162.78 127.48,162.78 127.37,162.68 127.37,162.48 127.46,162.39 148.48,162.39 148.56,162.3 148.56,162.08 148.48,161.99 128.45,161.99 128.36,161.91 128.36,161.69 128.45,161.6 147.9,161.6 148.68,160.82 148.68,159.17 148.97,158.88 149.73,158.88 150.81,157.8 150.81,157.54 J6.164
M1_MECC7: length 83.8
  TOP w0.118: U22.Y4 v3(119.33,160.2)
  L14_INT_6 w0.087: v3(119.33,160.2) 120.55,160.2 121.03,160.68 122.96,160.68 123.55,161.26 125.5,161.26 126.23,161.99 127.67,161.99 127.76,161.91 127.76,161.69 127.67,161.6 126.45,161.6 126.36,161.51 126.36,161.3 126.45,161.21 147.63,161.21 147.72,161.12 147.72,160.9 147.63,160.81 124.53,160.81 124.44,160.72 124.44,160.51 124.52,160.42 147.68,160.42 148.21,159.89 148.21,159.62 148.21,159.62 148.21,158.62 148.83,158 J6.165
M1_MODT0: length 96
  TOP w0.118: U22.AA1 v3(121.33,161.19)
  L7_INT_3 w0.087: v3(121.33,161.19) 122.02,161.89 125.56,161.89 125.72,162.05 136.31,162.05 136.4,162.13 136.4,162.35 136.31,162.44 126.33,162.44 126.24,162.53 126.24,162.74 126.33,162.83 141.39,162.83 141.48,162.92 141.48,163.14 141.39,163.23 131.23,163.23 131.14,163.32 131.14,163.53 131.23,163.62 141.14,163.62 141.61,164.09 141.61,170.52 142.41,171.31 142.41,179.36 143.64,180.59 143.64,188.21 147.42,192 148.68,192 J6.195
M1_MODT1: length 96.3
  TOP w0.118: U22.AE1 v3(122.33,165.2)
  L7_INT_3 w0.087: J6.77 153.25,194.77 152.11,195.91 150.75,195.91 149.83,195 149.15,195 147.96,193.8 147.32,193.8 142.34,188.82 142.34,181.05 141.01,179.72 141.01,171.88 139.46,170.32 134.43,170.32 134.34,170.23 134.34,170.02 134.43,169.93 139.85,169.93 139.93,169.84 139.93,169.62 139.85,169.53 133.57,169.53 133.48,169.44 133.48,169.22 133.57,169.13 140.25,169.13 140.34,169.04 140.34,168.83 140.25,168.74 132.73,168.74 132.65,168.65 132.65,168.43 132.73,168.35 140.19,168.35 140.28,168.26 140.28,168.04 140.19,167.95 131.94,167.95 128.46,164.48 123.05,164.48 v3(122.33,165.2)
M1_MRAS_B: length 96.1
  TOP w0.118: U22.V2 121.41,158.12 127,158.12 131.19,162.31 131.19,167.34 131.32,167.46 131.57,167.46 131.7,167.34 131.7,163.7 131.83,163.58 132.08,163.58 132.21,163.7 132.21,178.65 132.33,178.78 132.59,178.78 132.72,178.65 132.72,164.81 132.84,164.68 133.1,164.68 133.22,164.81 133.22,179.2 133.48,179.45 133.48,180.98 132.46,181.99 132.46,185.42 138.68,191.64 147.57,191.64 148.43,190.78 149.77,190.78 150.23,190.32 150.23,190.12 150.68,189.67 150.68,189.67 J6.192
M1_MWE_B: length 96
  TOP w0.118: J6.73 152.27,190 152.27,190 151.2,190 149.99,191.21 148.74,191.21 147.8,192.15 138.43,192.15 131.95,185.67 131.95,181.48 131.83,181.36 131.57,181.36 131.44,181.48 131.44,184.66 131.32,184.79 131.06,184.79 130.94,184.66 130.94,180.72 130.81,180.59 130.56,180.59 130.43,180.72 130.43,183.57 130.3,183.69 130.05,183.69 129.92,183.57 129.92,180.34 131.7,178.56 131.7,168.22 131.57,168.1 131.32,168.1 131.19,168.22 131.19,178.32 131.06,178.45 130.81,178.45 130.68,178.32 130.68,162.56 128.33,160.21 123.61,160.21 122.66,159.26 121.27,159.26 U22.W2
M1_PARERR_B: length 59.2
  TOP w0.118: v2(120.18,139.25) 120.18,138.94 120.05,138.81 R291.2 119.25,139.19 119.25,141.27 U22.A4
  L7_INT_3 w0.087: J6.53 152.51,170 150.82,170 149.86,169.04 148.21,169.04 146.96,167.79 146.96,152.04 144.02,149.1 130.56,149.1 120.71,139.25 v2(120.18,139.25)
M1_PAROUT: length 96.2
  TOP w0.118: U22.R1 122.08,155.45 128.78,155.45 136.81,163.48 136.81,180.59 136.94,180.72 137.19,180.72 137.32,180.59 137.32,164.14 137.45,164.01 137.7,164.01 137.83,164.14 137.83,178.88 137.95,179.01 138.21,179.01 138.33,178.88 138.33,176.4 138.46,176.28 138.72,176.28 138.84,176.4 138.84,178.62 139.74,179.51 140.91,179.51 143.26,181.86 143.26,184.35 143.94,185.04 147.21,185.04 148.02,184.23 148.02,183.83 148.84,183.01 149.86,183.01 150.9,184.05 152.02,184.05 152.97,185 J6.68
M1_VREF_ISO: length 3.5
  TOP w0.381: U22.V13 v3(110.33,158.2)
  BOTTOM w0.305: R713.1 112.81,157.71 111.79,157.71 C780.1 111.7,157.68 110.81,157.68 C781.1 v3(110.33,158.2)
M2_MA0: length 95
  TOP w0.118: U22.AU1 v3(122.33,177.2)
  BOTTOM w0.118: J7.188 160.34,166 159.55,165.22 158.51,165.22 157.73,165.99 154.69,165.99 153.67,167.01 152.78,167.01 151.76,165.99 150.88,165.99 149.92,165.04 136.36,165.04 136.23,165.16 136.23,165.42 136.36,165.54 143.55,165.54 143.67,165.67 143.67,165.93 143.55,166.05 130.75,166.05 130.62,166.18 130.62,166.43 130.75,166.56 143.51,166.56 143.64,166.69 143.64,166.94 143.51,167.07 131.32,167.07 130.62,167.77 130.62,175.9 128.47,178.05 123.19,178.05 v3(122.33,177.2)
M2_MA1: length 95.1
  TOP w0.118: U22.BC5 v3(118.33,184.2)
  BOTTOM w0.118: v3(118.33,184.2) 118.03,183.9 117.86,183.72 117.86,182.93 118.11,182.68 122.44,182.68 124.78,180.34 125.73,180.34 125.94,180.13 127.83,180.13 131.64,176.33 131.64,171.51 132.02,171.13 144.65,171.13 144.78,171.01 144.78,170.75 144.65,170.62 131.95,170.62 131.83,170.5 131.83,170.24 131.95,170.12 144.75,170.12 144.88,169.99 144.88,169.74 144.75,169.61 140.84,169.61 140.72,169.48 140.72,169.23 140.84,169.1 144.91,169.1 145.48,168.53 148.08,168.53 148.72,169.16 150.14,169.16 151.03,170.05 152.02,170.05 152.91,170.94 153.59,170.94 154.43,171.78 157.3,171.78 158.3,172.78 159.42,172.78 160.17,172.03 161.24,172.03 162.2,173 J7.181
M2_MA2: length 95
  TOP w0.118: U22.BD4 v3(118.33,185.2)
  BOTTOM w0.118: v3(118.33,185.2) 118.33,185.19 118.49,185.04 119.63,185.04 121.49,183.19 122.65,183.19 124.74,181.1 127.58,181.1 132.14,176.54 132.14,174.05 132.52,173.67 136.91,173.67 137.03,173.55 137.03,173.29 136.91,173.16 132.27,173.16 132.14,173.04 132.14,172.78 132.27,172.66 148.32,172.66 148.45,172.53 148.45,172.28 148.32,172.15 132.32,172.15 132.19,172.02 132.19,171.77 132.32,171.64 148.17,171.64 148.72,171.09 150.01,171.09 150.88,171.96 151.76,171.96 152.78,172.97 153.8,172.97 154.57,172.21 156.96,172.21 157.98,173.22 159.78,173.22 159.99,173 J7.61
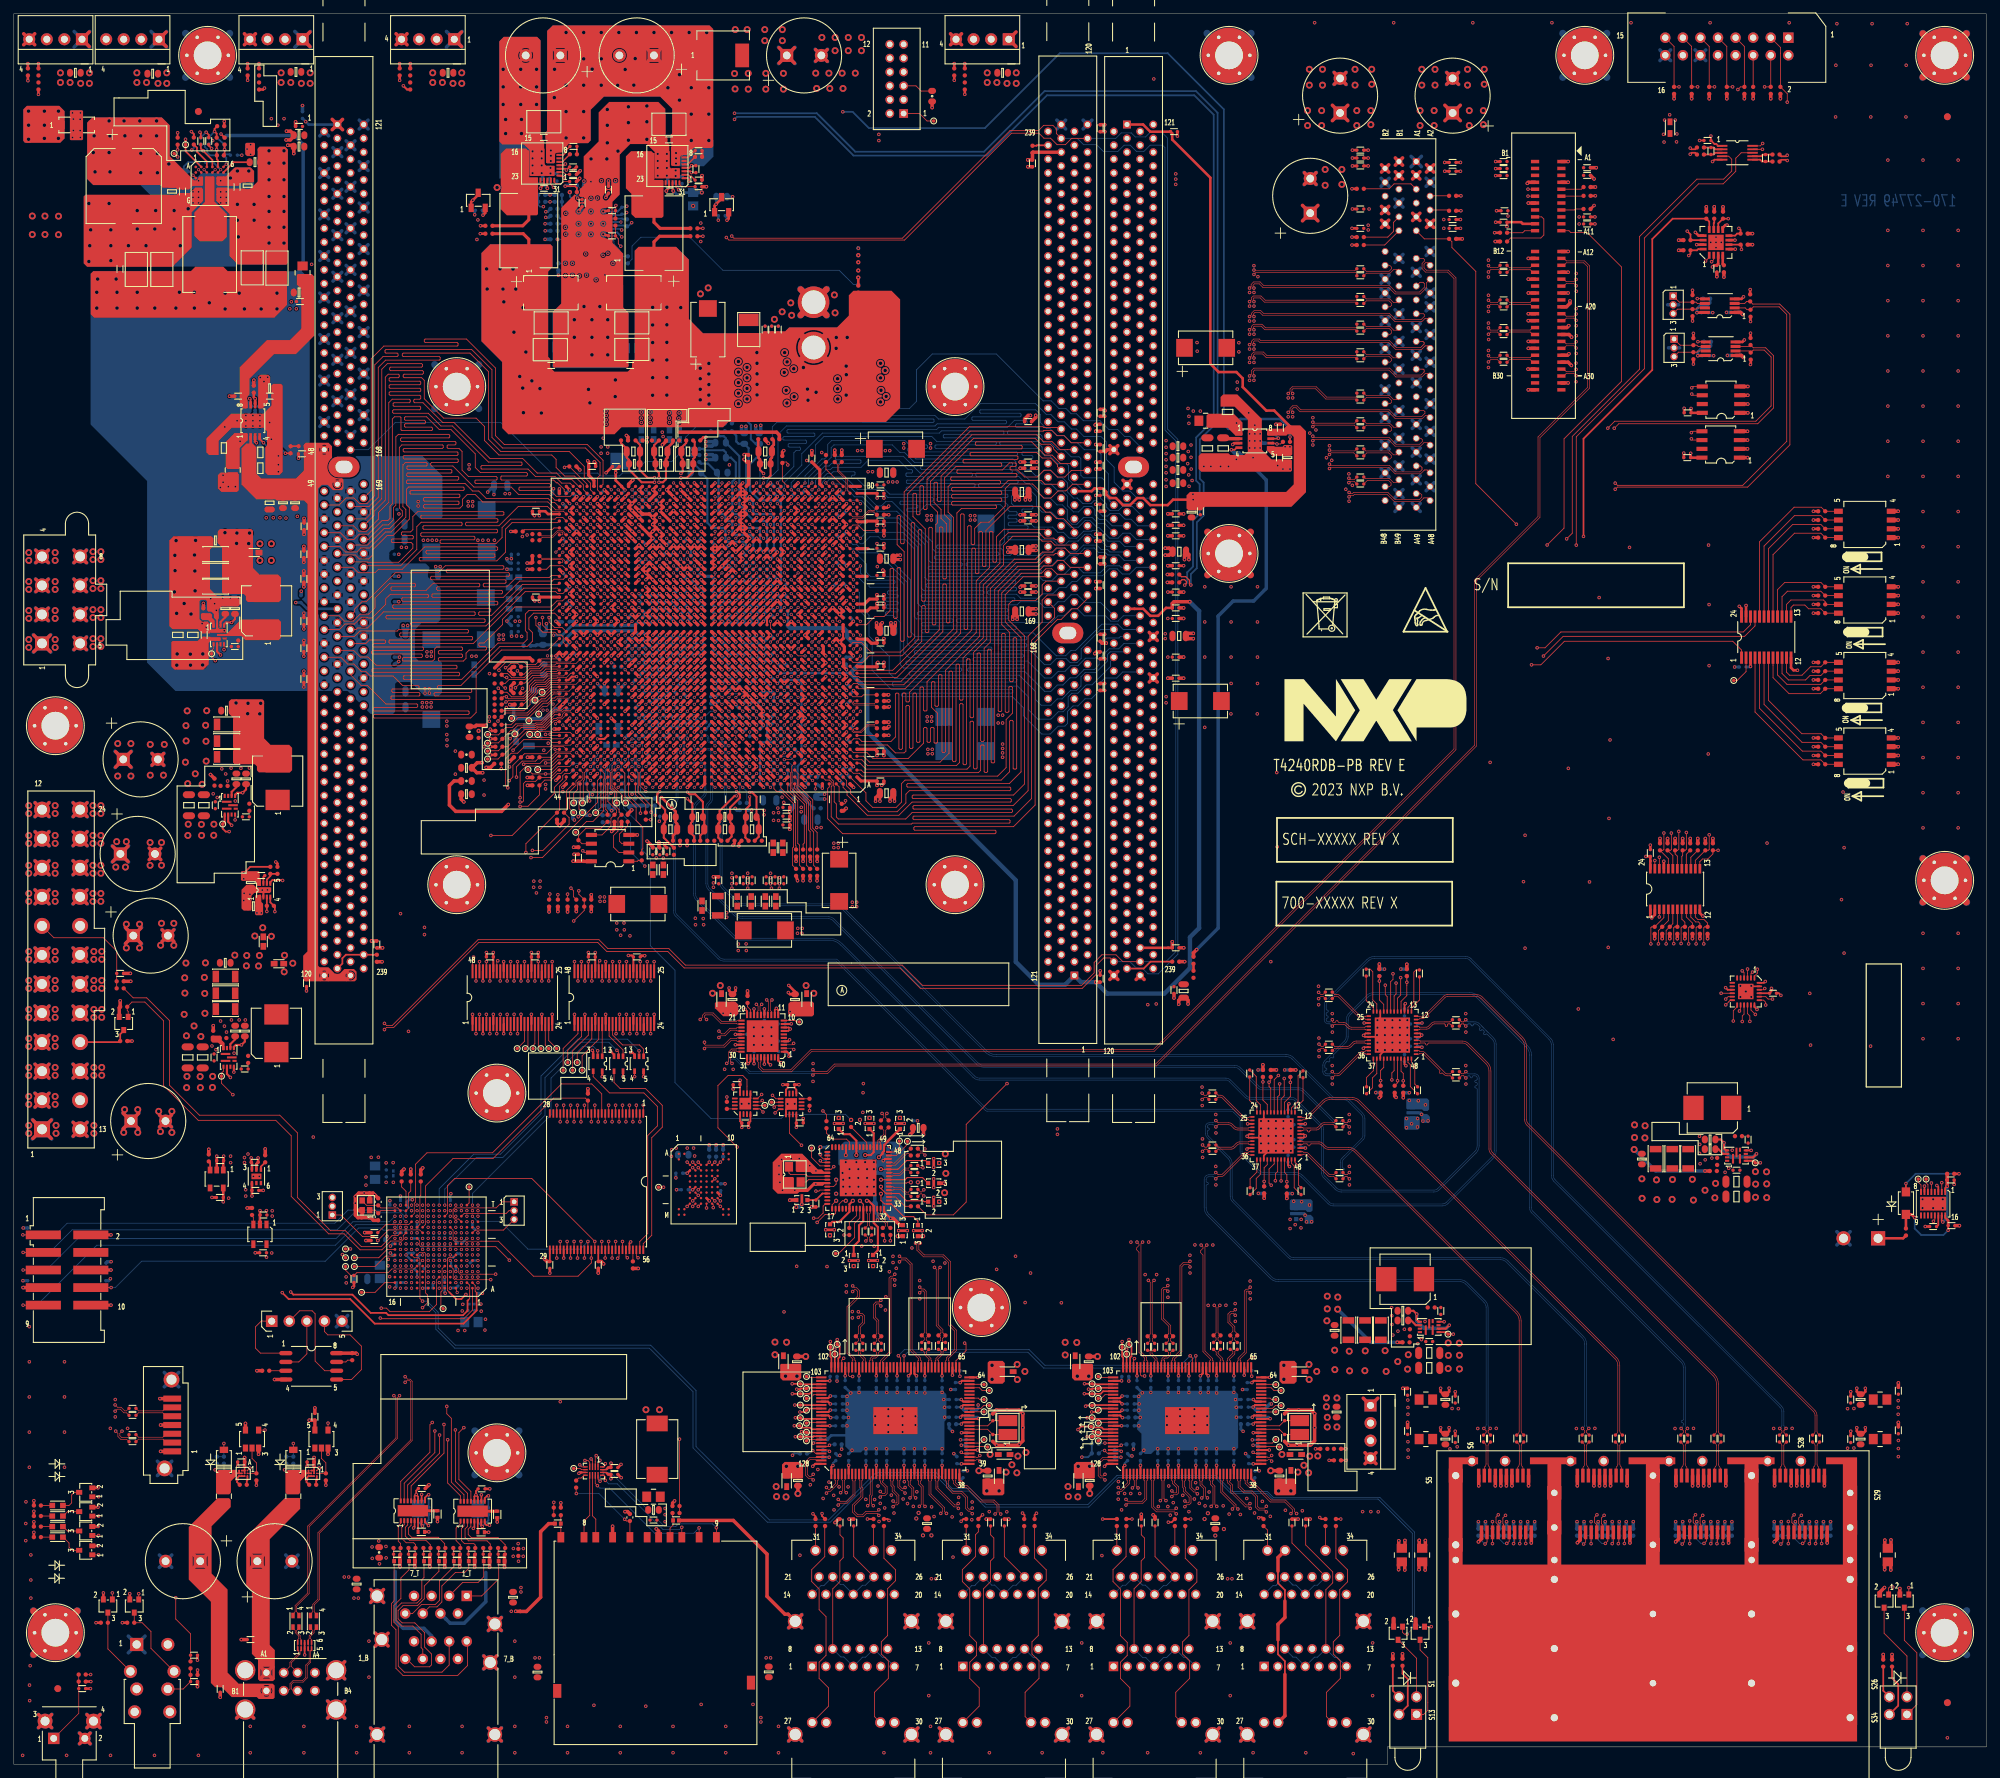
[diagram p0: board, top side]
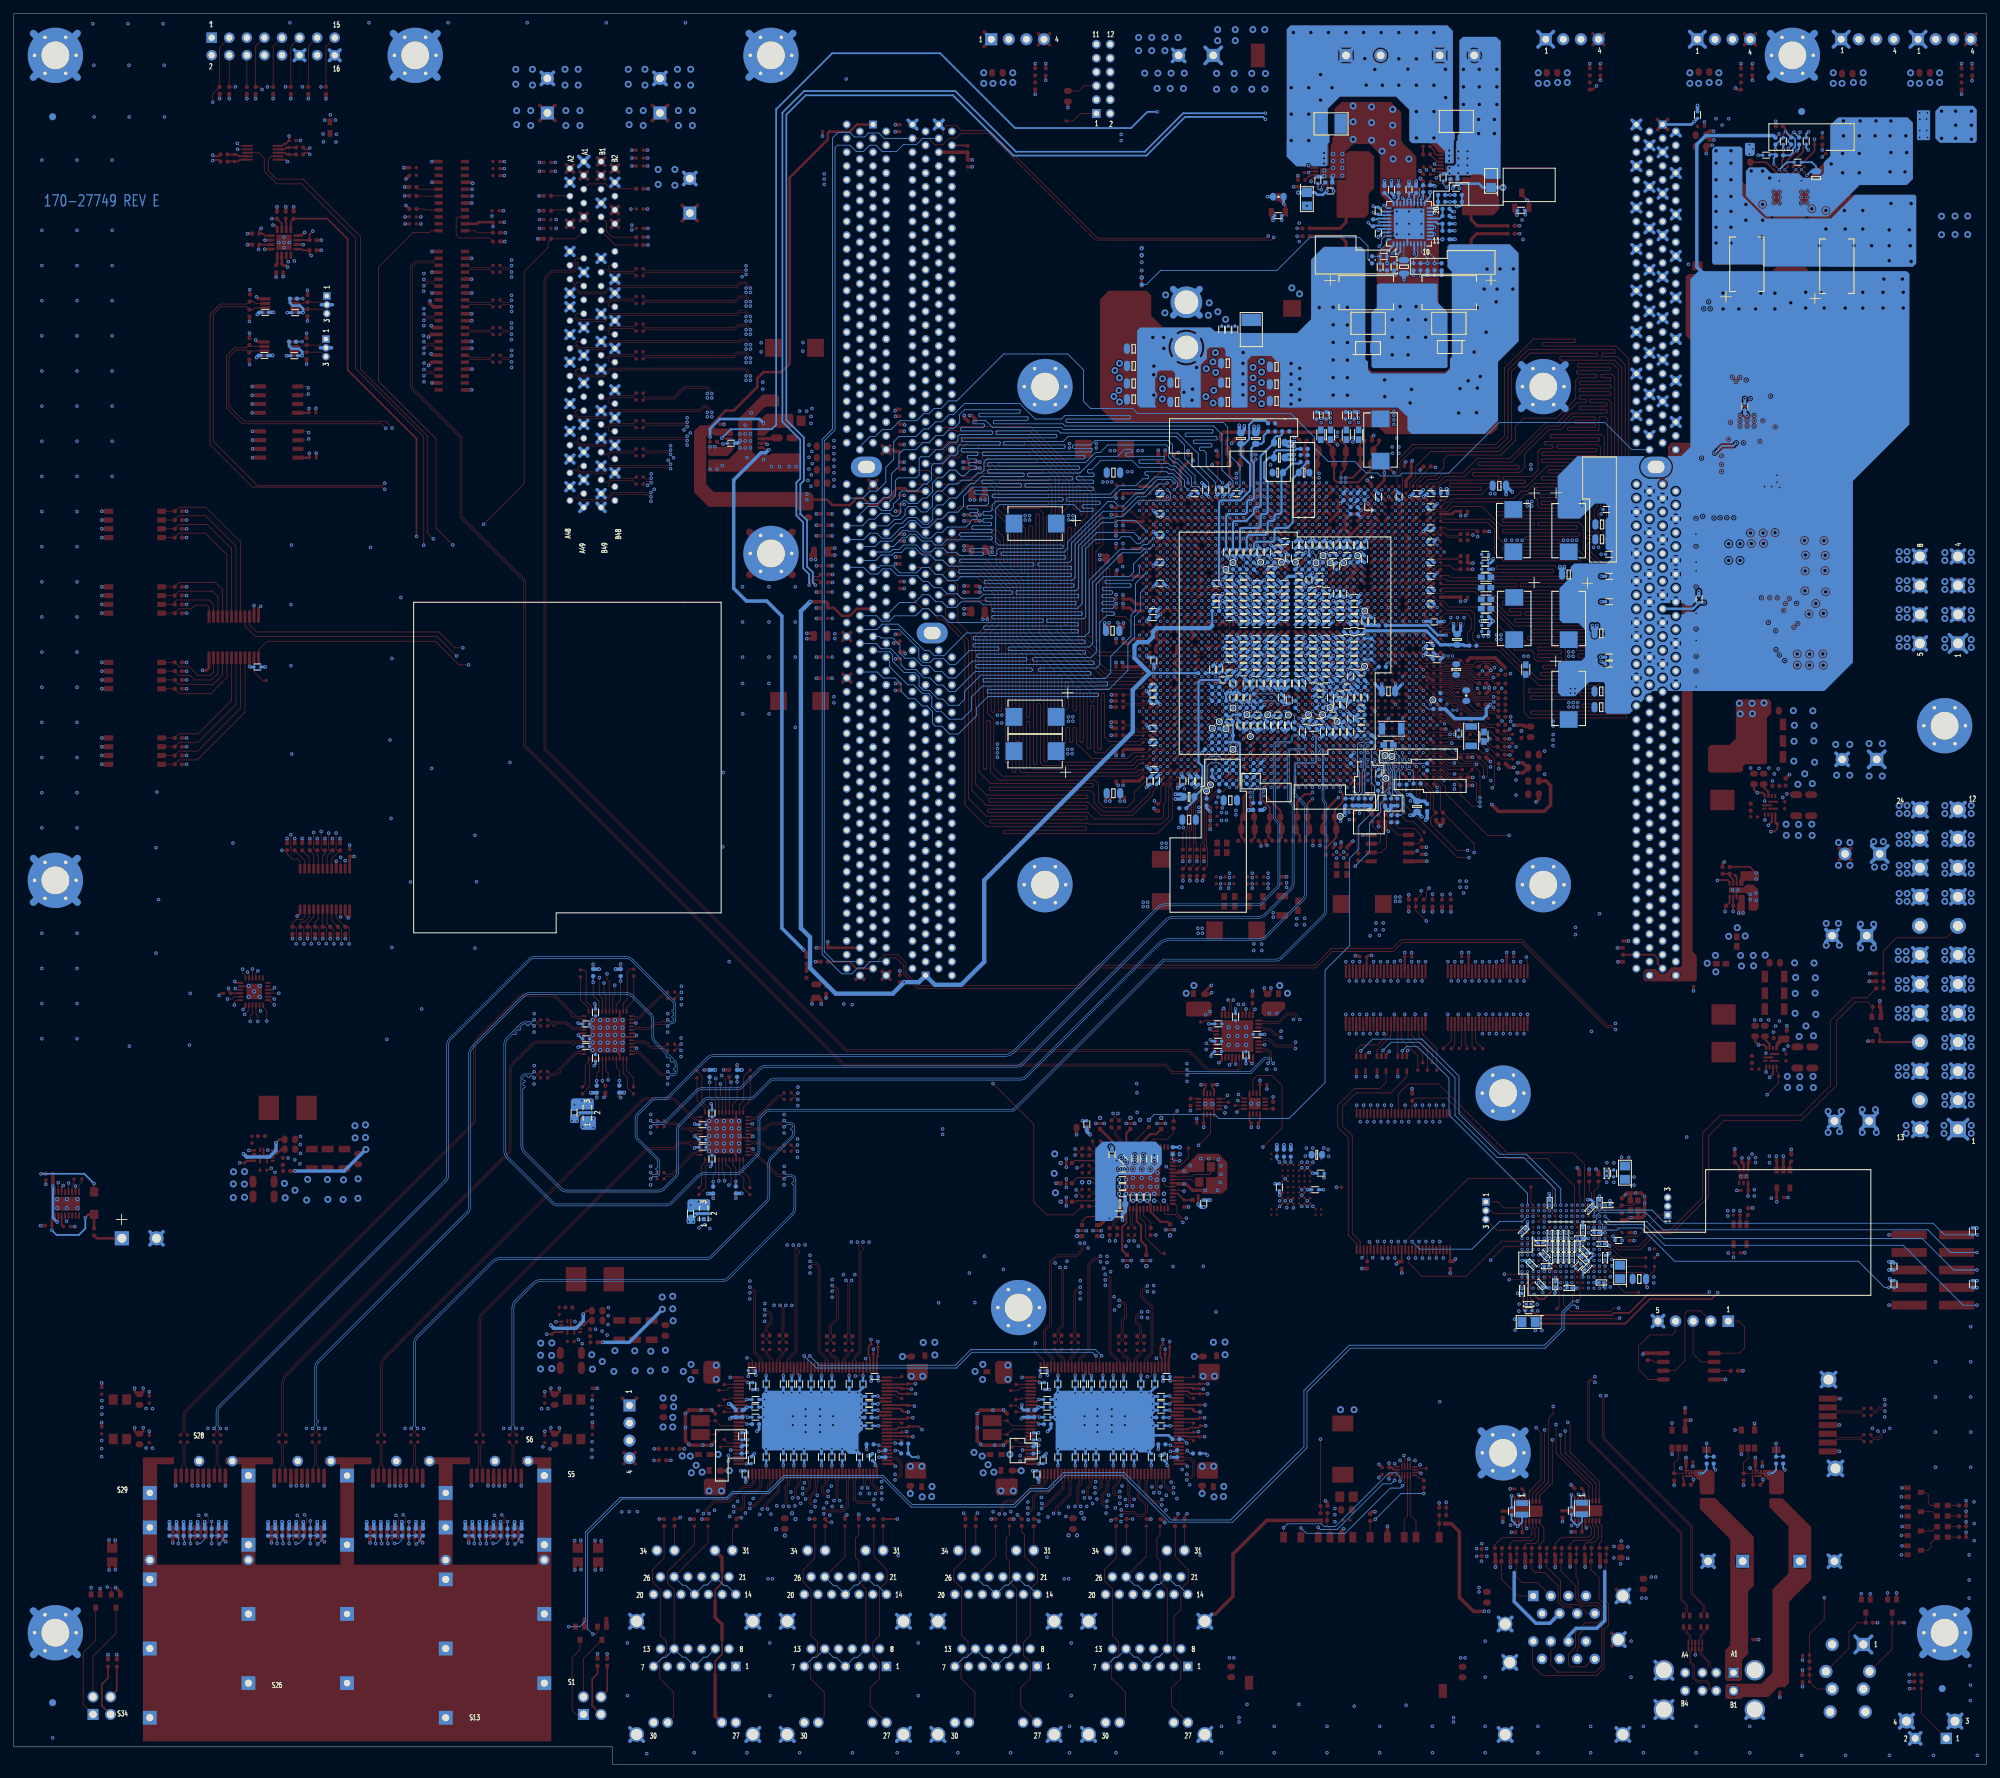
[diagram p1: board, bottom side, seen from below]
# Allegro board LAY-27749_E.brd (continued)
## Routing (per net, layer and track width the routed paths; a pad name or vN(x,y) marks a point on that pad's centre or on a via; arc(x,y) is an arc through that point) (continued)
M2_MA3: length 95.1
  TOP w0.118: U22.BD5 v3(117.33,185.2)
  BOTTOM w0.118: v3(117.33,185.2) 117.81,185.67 119.76,185.67 121.7,183.73 122.83,183.73 124.69,181.86 125.35,181.86 125.98,182.5 126.9,182.5 132.71,176.68 132.71,175.7 133.22,175.2 142.21,175.2 142.34,175.07 142.34,174.82 142.21,174.69 133.16,174.69 133.03,174.56 133.03,174.31 133.16,174.18 148.21,174.18 148.34,174.05 148.34,173.8 148.21,173.67 137.73,173.67 137.6,173.55 137.6,173.29 137.73,173.16 149.87,173.16 150.75,174.04 151.82,174.04 152.56,174.78 153.74,174.78 154.74,175.78 156.12,175.78 156.77,175.13 157.74,175.13 158.09,174.78 159.66,174.78 160.44,174 J7.180
M2_MA4: length 95
  TOP w0.118: U22.BC6 v3(117.33,184.2)
  BOTTOM w0.118: J7.59 160.63,175.22 158.38,175.22 158.03,175.56 157.12,175.56 156.47,176.22 154.57,176.22 153.57,175.22 152.44,175.22 151.88,175.78 150.79,175.78 150.11,175.11 148.82,175.11 148.4,174.69 145.06,174.69 144.93,174.82 144.93,175.07 145.06,175.2 146.75,175.2 146.88,175.32 146.88,175.58 146.75,175.7 144.46,175.7 144.21,175.45 144.21,174.94 143.95,174.69 143.19,174.69 142.94,174.94 142.94,175.45 142.68,175.7 133.49,175.7 133.36,175.83 133.36,176.09 133.49,176.21 142.68,176.21 143.13,176.66 143.13,181.48 142.56,182.05 131.84,182.05 130.82,181.04 129.16,181.04 129.03,181.17 129.03,181.42 129.16,181.55 130.49,181.55 130.62,181.67 130.62,181.93 130.49,182.05 128.17,182.05 128.04,182.18 128.04,182.44 128.17,182.56 132.74,182.56 132.87,182.69 132.87,182.94 132.74,183.07 126.3,183.07 125.13,184.24 121.96,184.24 120.14,186.06 117.6,186.06 116.84,185.3 116.84,184.69 v3(117.33,184.2)
M2_MA5: length 95.1
  TOP w0.118: U22.BC7 v3(116.33,184.2)
  BOTTOM w0.118: J7.58 157.91,176 156.64,177.27 156.08,177.27 155.57,177.78 154.77,177.78 153.78,176.79 152.43,176.79 151.86,176.22 150.94,176.22 150.18,176.97 143.76,176.97 143.64,177.1 143.64,177.36 143.76,177.48 148.21,177.48 148.34,177.61 148.34,177.86 148.21,177.99 143.76,177.99 143.64,178.12 143.64,178.37 143.76,178.5 146.43,178.5 146.56,178.63 146.56,178.88 146.43,179.01 143.83,179.01 143.7,179.13 143.7,179.39 143.83,179.51 144.84,179.51 144.97,179.64 144.97,179.9 144.84,180.02 143.76,180.02 143.64,180.15 143.64,180.4 143.76,180.53 144.84,180.53 144.97,180.66 144.97,180.91 144.84,181.04 143.9,181.04 143.64,181.31 143.64,181.99 143.07,182.56 133.5,182.56 133.38,182.69 133.38,182.94 133.5,183.07 143.51,183.07 143.64,183.2 143.64,183.45 143.51,183.58 126.56,183.58 125.35,184.79 122.87,184.79 121.85,185.8 121.16,185.8 121.03,185.93 121.03,186.18 121.16,186.31 121.42,186.31 121.55,186.44 121.55,186.69 121.42,186.82 118.4,186.82 118.15,186.56 117.54,186.56 116.33,185.36 116.33,185.36 v3(116.33,184.2)
M2_MA6: length 95
  TOP w0.118: U22.BD7 v3(115.33,184.2)
  BOTTOM w0.118: J7.178 160.55,176 159.77,176.78 158.09,176.78 156.54,178.33 155.85,178.33 155.74,178.22 154.57,178.22 153.57,177.22 152.5,177.22 151.66,178.05 150.85,178.05 150.09,178.82 147.42,178.82 146.77,179.46 146.77,179.64 146.52,179.9 145.92,179.9 145.8,180.02 145.8,180.28 145.92,180.4 146.75,180.4 146.88,180.53 146.88,180.78 146.75,180.91 145.8,180.91 145.67,181.04 145.67,181.29 145.8,181.42 147.13,181.42 147.26,181.55 147.26,181.8 147.13,181.93 144.46,181.93 144.18,182.21 144.18,183.29 144.46,183.58 146.04,183.58 146.17,183.71 146.17,183.97 146.05,184.09 129.07,184.09 128.94,184.21 128.94,184.47 129.07,184.59 138.76,184.59 138.89,184.72 138.89,184.98 138.76,185.1 129.1,185.1 128.97,185.23 128.97,185.48 129.1,185.61 131.34,185.61 131.46,185.74 131.46,185.99 131.34,186.12 129.03,186.12 128.9,186.25 128.9,186.5 129.03,186.63 129.73,186.63 129.86,186.75 129.86,187.01 129.73,187.13 129.22,187.13 127.89,188.47 123.44,188.47 122.43,187.45 118.32,187.45 118,187.13 117.39,187.13 115.84,185.58 115.84,184.7 v3(115.33,184.2)
M2_MA7: length 95.1
  TOP w0.118: U22.BC9 v3(113.33,184.2)
  BOTTOM w0.118: J7.56 157.63,179.32 156.69,179.32 155.8,180.21 154.58,180.21 153.59,179.22 152.93,179.22 152.22,179.92 152.22,181.32 151.52,182.02 150.75,182.02 149.76,183.01 148.84,183.01 146.75,185.1 146.24,185.1 145.22,186.12 139.14,186.12 139.01,186.25 139.01,186.5 139.14,186.63 144.14,186.63 144.27,186.75 144.27,187.01 144.14,187.13 131.17,187.13 131.04,187.26 131.04,187.52 131.17,187.64 144.18,187.64 144.3,187.77 144.3,188.02 144.18,188.15 130.15,188.15 128.69,189.61 128.02,189.61 126.94,190.69 118.49,190.69 118.11,190.31 118.11,188.89 117.37,188.15 116.97,188.15 114.82,186 114.82,184.8 114.68,184.66 113.79,184.66 v3(113.33,184.2)
M2_MA8: length 95
  TOP w0.118: U22.BD8 v3(115.33,185.2)
  BOTTOM w0.118: v3(115.33,185.2) 115.33,185.79 117.18,187.64 117.79,187.64 118.17,188.02 122.28,188.02 122.41,188.15 122.41,188.4 122.28,188.53 118.85,188.53 118.72,188.66 118.72,188.91 118.85,189.04 124.21,189.04 124.33,189.17 124.33,189.42 124.21,189.55 123.51,189.55 123.38,189.67 123.38,189.93 123.51,190.06 124.5,190.06 125.51,189.04 128.54,189.04 130.96,186.63 138.38,186.63 138.51,186.5 138.51,186.25 138.38,186.12 132.1,186.12 131.97,185.99 131.97,185.74 132.1,185.61 144.98,185.61 145.11,185.48 145.11,185.23 144.98,185.1 139.52,185.1 139.39,184.98 139.39,184.72 139.52,184.59 146.43,184.59 147.76,183.26 147.76,181.8 148.59,180.98 149.94,180.98 150.95,179.96 151.54,179.96 152.71,178.78 153.82,178.78 154.82,179.78 155.48,179.78 156.5,178.77 156.79,178.77 158.34,177.22 159.56,177.22 160.27,177.93 161.29,177.93 162.22,177 J7.177
M2_MA9: length 95
  TOP w0.118: U22.BC10 v3(112.33,184.2)
  BOTTOM w0.118: J7.175 162.38,179 161.42,179.96 160.58,179.96 159.76,180.78 158.43,180.78 158.06,180.42 157.3,180.42 156.84,180.87 156.84,182.25 156.46,182.63 156.08,182.63 155.67,182.22 154.46,182.22 153.67,183.01 153.13,183.01 152.27,183.87 152.27,185.18 151.53,185.93 150.88,185.93 149.73,187.07 148.97,187.07 148.13,186.23 147.65,186.23 146.75,187.13 145.99,187.13 145.86,187.26 145.86,187.51 145.99,187.64 146.87,187.64 147,187.77 147,188.02 146.87,188.15 145.99,188.15 145.86,188.28 145.86,188.53 145.99,188.66 147.12,188.66 147.25,188.78 147.25,189.04 147.12,189.17 145.81,189.17 145.68,189.29 145.68,189.55 145.81,189.67 147.95,189.67 148.08,189.8 148.08,190.06 147.95,190.18 133.22,190.18 133.1,190.31 133.1,190.56 133.22,190.69 141.83,190.69 141.96,190.82 141.96,191.07 141.83,191.2 133.35,191.2 132.65,191.9 117.05,191.9 115.82,190.67 115.82,188.73 112.33,185.24 112.33,184.61 v3(112.33,184.2)
M2_MA10: length 95
  TOP w0.118: U22.AT2 v3(120.33,177.2)
  BOTTOM w0.118: J7.70 157.04,164 154.23,161.19 154.23,159.83 153.62,159.22 152.64,159.22 152.07,159.79 150.62,159.79 149.76,158.93 148.95,158.93 146.9,160.97 142.8,160.97 142.67,161.1 142.67,161.35 142.8,161.48 146.24,161.48 146.37,161.61 146.37,161.86 146.24,161.99 130.32,161.99 130.19,162.12 130.19,162.38 130.31,162.5 146.22,162.5 146.36,162.64 146.36,162.89 146.24,163 130.25,163 129.6,163.65 129.6,171.13 125.13,175.6 122.47,175.6 121.79,176.28 121.25,176.28 v3(120.33,177.2)
M2_MA11: length 95
  TOP w0.118: U22.BD9 v3(114.33,185.2)
  BOTTOM w0.118: J7.55 158.69,179 157.78,179.91 156.87,179.91 156.21,180.57 156.21,181.36 155.78,181.79 154.63,181.79 153.85,181 153.14,181 152.27,181.86 152.27,183.26 151.51,184.02 150.88,184.02 149.86,185.04 148.59,185.04 148.02,185.61 146.75,185.61 145.73,186.63 145.17,186.63 144.81,186.99 144.81,188.23 144.39,188.66 130.36,188.66 130.23,188.79 130.23,189.04 130.36,189.17 144.89,189.17 145.03,189.31 145.03,189.56 144.91,189.67 129.35,189.67 129.17,189.85 129.17,190.11 129.24,190.18 131.89,190.18 132.02,190.31 132.02,190.56 131.89,190.69 129.41,190.69 128.77,191.33 118.17,191.33 117.6,190.75 117.6,189.1 117.16,188.66 116.76,188.66 114.33,186.23 v3(114.33,185.2)
M2_MA12: length 95.1
  TOP w0.118: U22.BC11 v3(111.33,184.2)
  BOTTOM w0.118: J7.174 162.75,180.66 161.62,181.79 160.2,181.79 159.63,181.22 158.38,181.22 157.91,181.69 157.91,182.11 157,183.03 157,183.74 156.72,184.02 154.56,184.02 153.54,185.04 153.07,185.04 152.4,185.71 152.4,187.71 152.15,187.96 150.88,187.96 149.73,189.1 148.97,189.1 148.59,189.48 148.59,190.37 148.27,190.69 142.6,190.69 142.47,190.82 142.47,191.07 142.6,191.2 147.95,191.2 148.08,191.33 148.08,191.58 147.95,191.71 134.43,191.71 134.3,191.83 134.3,192.09 134.43,192.21 142.94,192.21 143.07,192.34 143.07,192.6 142.94,192.72 134.05,192.72 133.73,192.41 116.84,192.41 113.86,189.42 113.86,187.77 111.33,185.24 v3(111.33,184.2)
M2_MA13: length 95
  TOP w0.118: U22.AK2 v3(121.33,170.2)
  BOTTOM w0.118: J7.196 162.61,157.86 160.22,157.86 159.36,157 157.66,157 156.79,156.13 156.79,155.09 155.7,154 154.79,154 153.75,152.96 153.05,152.96 152.25,152.16 152.25,150.42 151.87,150.04 150.9,150.04 149.76,148.89 148.54,148.89 145.87,151.56 145.87,152.71 144.27,154.31 128.4,154.31 128.27,154.43 128.27,154.69 128.4,154.81 144.22,154.81 144.35,154.95 144.35,155.2 144.23,155.32 126.81,155.32 124.02,158.11 124.02,161.89 123.06,162.85 123.06,165.86 122.17,166.75 122.17,169.35 v3(121.33,170.2)
M2_MA14: length 95.1
  TOP w0.118: U22.BC13 v3(109.33,184.2)
  BOTTOM w0.118: v3(109.33,184.2) 108.84,184.69 108.84,184.69 108.84,185.48 110.43,187.07 110.43,192.21 111.63,193.42 133.1,193.42 133.41,193.74 143.32,193.74 143.45,193.87 143.45,194.12 143.32,194.25 138.56,194.25 138.43,194.37 138.43,194.63 138.56,194.75 145.41,194.75 145.54,194.88 145.54,195.14 145.41,195.26 139.7,195.26 139.57,195.39 139.57,195.64 139.7,195.77 147.64,195.77 148.34,195.07 148.34,193.93 149.22,193.04 149.73,193.04 150.75,192.02 151.76,192.02 152.78,191.01 153.67,191.01 154.69,189.99 156.46,189.99 157.1,189.36 157.1,187.58 158.16,186.52 158.16,183.6 158.67,183.08 159.33,183.08 160.2,182.22 162.53,182.22 J7.172
M2_MA15: length 95
  TOP w0.118: U22.BC14 v3(108.33,184.2)
  BOTTOM w0.118: J7.171 162.31,183 161.29,184.02 160.27,184.02 159,185.29 159,187.45 157.86,188.6 157.86,191.14 157.1,191.9 154.63,191.9 153.54,192.99 152.83,192.99 151.79,194.03 150.9,194.03 149.86,195.07 149.22,195.07 147.64,196.66 139.64,196.66 137.41,194.44 133.6,194.44 133.1,194.95 123.75,194.95 123.62,194.82 123.62,194.56 123.75,194.44 132.84,194.44 132.97,194.31 132.97,194.06 132.84,193.93 122.72,193.93 122.72,193.93 110.24,193.93 109.6,193.29 109.6,189.48 107.82,187.71 107.82,184.7 108.03,184.49 v3(108.33,184.2)
M2_MBA0: length 95
  TOP w0.118: U22.AR2 v3(120.33,176.2)
  BOTTOM w0.118: v3(120.33,176.2) 120.88,175.64 121.67,175.64 122.21,175.1 124.83,175.1 129.1,170.83 129.1,161.99 129.6,161.48 141.19,161.48 141.33,161.34 141.33,161.09 141.21,160.97 130.26,160.97 130.14,160.85 130.14,160.59 130.26,160.46 145.73,160.46 145.86,160.34 145.86,160.08 145.73,159.96 138.76,159.96 138.62,159.82 138.62,159.57 138.74,159.45 146.49,159.45 148.95,157 149.94,157 150.9,157.96 151.89,157.96 152.71,158.78 153.78,158.78 154.86,159.87 156.24,159.87 156.97,160.6 156.97,161.79 157.97,162.78 159.68,162.78 159.9,163 J7.71
M2_MBA1: length 95
  TOP w0.118: U22.AT1 v3(121.33,177.2)
  BOTTOM w0.118: v3(121.33,177.2) 121.51,177.2 122.3,176.4 122.68,176.4 123.7,177.42 124.92,177.42 125.3,177.04 128.77,177.04 130.11,175.69 130.11,165.85 130.42,165.54 135.6,165.54 135.72,165.42 135.72,165.16 135.6,165.04 131.33,165.04 131.19,164.9 131.19,164.65 131.32,164.53 144.75,164.53 144.87,164.41 144.87,164.16 144.73,164.02 131.32,164.02 131.19,163.89 131.19,163.64 131.32,163.51 147.33,163.51 150.63,160.21 151.98,160.21 152.73,160.96 153.4,160.96 157.23,164.78 159.52,164.78 160.31,164 J7.190
M2_MBA2: length 95
  TOP w0.118: U22.BD12 110.33,185.19 v3(110.33,185.2)
  BOTTOM w0.118: J7.52 158.39,182.56 157.63,183.32 157.63,185.53 157.23,185.93 154.56,185.93 154.18,186.31 154.18,188.72 153.92,188.98 152.78,188.98 151.76,189.99 150.85,189.99 149.83,191.01 148.84,191.01 148.59,191.26 148.59,191.96 148.34,192.21 143.7,192.21 143.57,192.34 143.57,192.6 143.7,192.72 148.08,192.72 148.21,192.85 148.21,193.1 148.08,193.23 144.87,193.23 144.74,193.36 144.74,193.61 144.87,193.74 146.3,193.74 146.43,193.87 146.43,194.12 146.3,194.25 144.59,194.25 143.57,193.23 133.67,193.23 133.35,192.91 111.84,192.91 111.72,192.79 111.72,192.53 111.84,192.41 115.61,192.41 115.74,192.28 115.74,192.02 115.61,191.9 111.25,191.9 111.12,191.77 111.12,191.52 111.25,191.39 114.43,191.39 114.55,191.26 114.55,191.01 114.43,190.88 112.01,190.88 111.89,190.75 111.89,190.5 112.01,190.37 113.54,190.37 113.66,190.25 113.66,189.99 113.54,189.87 113.03,189.87 112.71,189.55 112.71,187.58 111.22,186.09 v3(110.33,185.2)
M2_MCAS_B: length 95
  TOP w0.118: U22.AM2 v3(121.33,172.2)
  BOTTOM w0.118: v3(121.33,172.2) 121.38,172.2 122.91,170.67 122.91,166.73 123.57,166.07 123.57,163.06 126.49,160.14 126.49,157.73 127.3,156.92 127.36,156.92 127.36,156.92 144.81,156.92 144.94,156.79 144.94,156.54 144.81,156.41 127.08,156.41 126.95,156.29 126.95,155.95 127.08,155.83 145.03,155.83 146.63,154.23 146.63,152.37 147.96,151.05 149.86,151.05 150.93,152.12 151.61,152.12 152.35,152.86 152.35,154.27 152.88,154.79 153.75,154.79 154.96,156.01 155.8,156.01 158.47,158.67 158.47,159.43 158.95,159.91 J7.74
M2_MCKE0: length 95.1
  TOP w0.118: U22.BD15 v3(108.33,185.2)
  L14_INT_6 w0.087: v3(108.33,185.2) 108.61,185.48 109.57,186.44 122.17,186.44 123.82,188.09 144.69,188.09 144.86,188.25 144.86,188.47 144.77,188.56 125.09,188.56 125.01,188.65 125.01,189.01 125.1,189.1 149.76,189.1 150.93,187.93 151.74,187.93 152.6,187.07 153.39,187.07 154.51,185.95 155.85,185.95 157.18,184.63 158.32,184.63 J7.50
M2_MCKE1: length 95.1
  TOP w0.118: U22.BD16 v3(107.33,185.2)
  L14_INT_6 w0.087: v3(107.33,185.2) 107.61,184.91 107.82,184.71 111.43,184.71 112.72,186 124.54,186 125.4,186.87 145.72,186.87 145.81,186.78 145.81,186.49 145.72,186.4 129.63,186.4 129.54,186.31 129.54,186.09 129.63,186 147.78,186 148.69,186.92 150.01,186.92 151,185.93 151.84,185.93 152.83,184.94 153.82,184.94 154.71,184.05 156.95,184.05 157.96,183.03 159.59,183.03 160.5,183.95 161.37,183.95 162.42,185 J7.169
M2_MCLK0_N: length 95
  TOP w0.091: U22.AY1 v3(121.33,181.2)
  L14_INT_6 w0.1: v3(121.33,181.2) 121.69,180.83 121.69,180.41 122.02,180.09 123.06,180.09 124,181.03 130.34,181.03 130.44,180.92 130.44,180.14 130.34,180.04 126.44,180.04 126.19,179.79 126.19,178.63 126.44,178.38 141.05,178.38 141.19,178.25 141.19,177.49 141.09,177.39 126.51,177.39 126.26,177.14 126.26,176.15 126.51,175.9 143,175.9 143.38,176.28 145.16,176.28 147.02,174.42 148.16,174.42 148.57,174.83 149.83,174.83 150.89,173.77 151.9,173.77 152.75,172.92 153.64,172.92 154.59,171.97 156.27,171.97 156.77,171.47 156.77,168.6 158.52,166.85 159.44,166.85 160.48,167.89 161.52,167.89 162.53,168.9 163.44,168.9 163.83,169.29 164.36,169.29 J7.185
M2_MCLK0_P: length 95
  TOP w0.091: U22.BA1 121.83,181.36 121.99,181.2 v3(122.33,181.2)
  L14_INT_6 w0.1: v3(122.33,181.2) 121.95,180.81 121.95,180.52 122.12,180.34 122.96,180.34 123.9,181.28 130.45,181.28 130.7,181.03 130.7,180.03 130.45,179.78 126.54,179.78 126.44,179.68 126.44,178.74 126.54,178.64 141.16,178.64 141.44,178.36 141.44,177.39 141.19,177.14 126.62,177.14 126.52,177.04 126.52,176.25 126.62,176.15 142.9,176.15 143.28,176.53 145.27,176.53 147.12,174.68 148.06,174.68 148.46,175.08 149.94,175.08 150.99,174.03 152.01,174.03 152.86,173.18 153.75,173.18 154.7,172.23 156.37,172.23 157.02,171.58 157.02,168.71 158.62,167.11 159.33,167.11 160.37,168.15 161.41,168.15 162.42,169.16 163.33,169.16 163.71,169.53 163.71,169.79 163.5,170 J7.184
M2_MCLK1_N: length 95.2
  TOP w0.091: U22.BB2 v3(121.33,182.2)
  L14_INT_6 w0.1: J7.64 159.38,170.43 159.74,170.43 159.91,170.26 159.91,169.55 159.4,169.04 158.42,169.04 157.94,169.52 157.94,172.11 155.91,174.14 154.64,174.14 153.65,175.13 152.81,175.13 151.79,176.15 150.85,176.15 149.84,177.17 147.07,177.17 144.19,180.04 139.67,180.04 139.57,180.14 139.57,180.93 139.67,181.03 144.03,181.03 144.27,181.28 144.27,182.28 144.02,182.53 129.32,182.53 129.21,182.63 129.21,183.42 129.32,183.52 145.02,183.52 145.28,183.77 145.28,184.77 145.02,185.02 128.02,185.02 127.78,184.79 122.43,184.79 121.68,184.03 121.68,182.54 v3(121.33,182.2)
M2_MCLK1_P: length 95.2
  TOP w0.091: U22.BB1 v3(122.33,182.2)
  L14_INT_6 w0.1: J7.63 160.55,171 160.17,170.61 160.17,169.44 159.51,168.78 158.31,168.78 157.68,169.41 157.68,172.01 155.8,173.89 154.53,173.89 153.54,174.88 152.7,174.88 151.69,175.9 150.75,175.9 149.73,176.91 146.96,176.91 144.08,179.79 139.57,179.79 139.32,180.04 139.32,181.04 139.57,181.29 143.92,181.29 144.02,181.38 144.02,182.17 143.91,182.28 129.21,182.28 128.96,182.53 128.96,183.53 129.21,183.78 144.92,183.78 145.02,183.88 145.02,184.66 144.92,184.77 128.12,184.77 127.89,184.53 122.53,184.53 121.93,183.93 121.93,182.59 v3(122.33,182.2)
M2_MCLK2_N: length 4.6
  TOP w0.091: R213.2 124.71,180.6 124.32,181 123.6,181 122.69,180.1 121.23,180.1 U22.AW2
M2_MCLK2_P: length 4.6
  TOP w0.091: R211.2 124.3,181.2 123.51,181.2 122.61,180.3 121.22,180.3 U22.AY2
M2_MCLK3_N: length 5.4
  TOP w0.091: R199.2 119,187.83 119,186.91 120.23,185.68 120.23,184.09 U22.BC3
M2_MCLK3_P: length 5.4
  TOP w0.091: R200.2 119.63,188.21 119.2,187.79 119.2,187 120.43,185.77 120.43,184.09 U22.BC2
M2_MCS_B0: length 95
  TOP w0.118: U22.AP2 v3(121.33,174.2)
  L14_INT_6 w0.087: v3(121.33,174.2) 125.41,174.2 125.5,174.28 125.5,174.5 125.41,174.59 123.02,174.59 122.93,174.67 122.93,174.89 123.02,174.98 126,174.98 127.29,173.69 145.99,173.69 146.07,173.6 146.07,173.4 145.97,173.3 127.37,173.3 127.26,173.19 127.26,172.99 127.35,172.9 150.01,172.9 150.83,172.09 151.71,172.09 152.58,171.22 153.75,171.22 154.79,170.18 155.3,170.18 156.11,169.37 156.11,168.38 158.12,166.37 158.12,165.38 158.37,165.13 159.49,165.13 160.78,163.83 161.54,163.83 162.43,162.94 163.48,162.94 164.65,161.77 J7.193
M2_MCS_B1: length 95
  TOP w0.118: U22.AH2 v3(121.33,168.2)
  L14_INT_6 w0.087: J7.76 158.18,158 156.72,159.46 156.72,160.78 156.13,161.37 156.13,164.34 153.66,166.82 152.41,166.82 151.71,166.12 150.72,166.12 149.83,165.23 149.02,165.23 148.51,165.74 147.07,165.74 145.89,166.91 139.79,166.91 139.71,167 139.71,167.2 139.81,167.3 144.37,167.3 144.48,167.42 144.48,167.61 144.4,167.7 127.09,167.7 127.01,167.79 127.01,168 127.09,168.09 144.37,168.09 144.46,168.18 144.46,168.4 144.37,168.48 126.93,168.48 126.56,168.11 126.56,167.07 125.96,166.47 121.34,166.47 120.88,166.93 120.88,167.74 v3(121.33,168.2)
M2_MCS_B2: length 95
  TOP w0.118: U22.AN1 v3(121.33,173.2)
  L14_INT_6 w0.087: v3(121.33,173.2) 121.05,172.91 119.86,171.73 119.86,166.9 120.7,166.07 126.19,166.07 127.43,167.3 138.47,167.3 138.56,167.21 138.56,167 138.47,166.91 127.6,166.91 127.51,166.82 127.51,166.61 127.6,166.52 143.67,166.52 143.76,166.43 143.76,166.21 143.67,166.12 137.2,166.12 137.11,166.03 137.11,165.82 137.2,165.73 143.86,165.73 144.2,166.07 146.1,166.07 146.81,165.35 146.89,165.35 146.9,165.34 148.35,165.34 148.86,164.84 150,164.84 150.76,165.6 152.28,165.6 152.65,165.23 153.87,165.23 154.81,164.29 154.81,161.98 154.28,161.44 154.28,160.17 154.43,160.02 155.57,160.02 158.62,156.97 159.65,156.97 160.85,155.77 J7.79
M2_MCS_B3: length 95
  TOP w0.118: U22.AJ1 v3(121.33,169.2)
  L14_INT_6 w0.087: J7.198 161.8,156.95 161.8,159.51 161.29,160.02 160.27,160.02 159.26,161.04 158.11,161.04 157.05,162.1 157.05,166.25 155.49,167.81 154.63,167.81 153.58,168.85 152.76,168.85 151.82,169.79 150.76,169.79 150.21,169.23 149.13,169.23 149.12,169.24 148.79,169.24 148.18,168.63 145.57,168.63 144.93,169.27 143.7,169.27 143.61,169.36 143.61,169.58 143.7,169.67 144.7,169.67 144.79,169.75 144.79,169.97 144.7,170.06 125.61,170.06 125.52,170.15 125.52,170.36 125.61,170.45 144.56,170.45 144.65,170.54 144.65,170.76 144.56,170.85 122.98,170.85 v3(121.33,169.2)
M2_MDIC_0: length 4.4
  TOP w0.118: U22.AV2 121.25,179.11 122,179.11 122.81,178.31 R218.1
M2_MDIC_1: length 4.5
  TOP w0.118: R198.1 117.35,187.18 U22.BD3
M2_MDQ0: length 92.7
  TOP w0.118: v3(107.33,181.2) 107.33,181.19 U22.AY15
  L12_INT_5 w0.087: J7.3 159.99,235 159.8,234.81 157.57,234.81 156.97,234.21 154.18,234.21 153.62,234.77 152.86,234.77 151.89,233.81 151.89,233.81 151.88,233.79 150.48,233.79 149.87,233.18 146.42,233.18 127.69,214.45 127.69,211.15 127.58,211.05 127.39,211.05 127.29,211.15 127.29,213.14 127.2,213.23 127.01,213.23 126.9,213.12 126.9,209.8 118.14,201.04 115.89,201.04 113.97,199.12 113.97,196.77 112.78,195.58 110.67,195.58 106.94,191.85 106.94,189.83 107.34,189.43 107.34,187.32 106.53,186.51 106.53,183.67 106.78,183.41 106.78,181.74 v3(107.33,181.2)
M2_MDQ1: length 92.7
  TOP w0.118: U22.BA15 v3(107.33,182.2)
  L12_INT_5 w0.087: J7.4 158.76,233.81 154.69,233.81 154.05,233.17 152.88,233.17 151.61,231.9 150.93,231.9 150.04,232.79 146.72,232.79 128.91,214.98 128.91,212.3 128.82,212.21 128.61,212.21 128.51,212.31 128.51,213.26 128.41,213.36 128.22,213.36 128.12,213.26 128.12,208.38 128.02,208.28 127.83,208.28 127.72,208.38 127.72,210.52 127.62,210.62 127.43,210.62 127.33,210.52 127.33,207.59 122.94,203.2 122.94,201.44 121.04,199.54 118.52,199.54 114.03,195.06 110.7,195.06 107.34,191.7 107.34,190.02 107.82,189.53 107.82,187.22 106.93,186.33 106.93,183.79 107.33,183.4 v3(107.33,182.2)
M2_MDQ2: length 92.7
  TOP w0.118: U22.AY11 v3(112.33,181.2)
  L12_INT_5 w0.087: J7.9 159.89,228.04 159.89,225.48 159.33,224.92 157.73,224.92 156.59,223.77 154.81,223.77 153.88,222.84 152.6,222.84 151.67,223.77 151.03,223.77 151.01,223.75 150.88,223.75 149.94,222.81 144.58,222.81 136.3,214.53 136.3,207.85 136.2,207.75 136.01,207.75 135.9,207.86 135.9,212.5 135.8,212.6 135.61,212.6 135.51,212.5 135.51,207.14 130.05,201.68 130.05,194.69 126.75,191.39 122.3,191.39 121.34,190.42 121.33,190.42 121.28,190.37 116.26,190.37 115.9,190 115.9,188.54 115.08,187.73 114.34,187.73 112.79,186.17 112.79,181.65 v3(112.33,181.2)
M2_MDQ3: length 92.7
  TOP w0.118: U22.BA11 v3(112.33,182.2)
  L12_INT_5 w0.087: v3(112.33,182.2) 112.05,182.48 112.05,182.48 111.76,182.77 111.76,184.53 112.37,185.14 112.37,186.44 113.92,187.99 113.92,189.99 114.69,190.76 121.11,190.76 122.25,191.9 126.52,191.9 129.54,194.92 129.54,201.8 134.21,206.48 134.21,212.5 134.32,212.6 134.51,212.6 134.61,212.5 134.61,207.29 134.71,207.19 134.91,207.19 135,207.27 135,213.89 135.1,214 135.29,214 135.39,213.89 135.39,213.18 135.5,213.08 135.69,213.08 135.79,213.18 135.79,214.66 144.35,223.22 149.76,223.22 150.75,224.21 151.84,224.21 152.82,223.23 153.69,223.23 154.69,224.23 155.95,224.23 158.95,227.23 J7.10
M2_MDQ4: length 92.7
  TOP w0.118: v3(106.33,181.2) 106.33,181.19 U22.AY16
  L12_INT_5 w0.087: v3(106.33,181.2) 105.71,181.81 105.71,186.99 106.05,187.33 106.05,192.27 106.29,192.51 106.29,193.73 106.9,194.34 107.75,194.34 110.69,197.28 110.69,199.46 111.33,200.1 113.35,200.1 115.32,202.06 117.55,202.06 125.65,210.16 125.65,213.94 146.94,235.23 150.11,235.23 150.98,236.09 151.87,236.09 152.76,236.99 153.79,236.99 154.56,236.22 156.08,236.22 156.36,236.5 158.09,236.5 158.59,237 159.5,237 160.26,236.23 161.75,236.23 161.98,236 J7.122
M2_MDQ5: length 92.7
  TOP w0.118: U22.BA16 v3(106.33,182.2)
  L12_INT_5 w0.087: J7.123 162.26,235 161.42,235.84 160.27,235.84 159.64,235.2 157.58,235.2 156.96,235.83 154.37,235.83 153.72,235.18 152.7,235.18 151.73,234.21 150.65,234.21 150.05,234.81 147.38,234.81 126.21,213.64 126.21,209.89 117.85,201.53 115.77,201.53 113.51,199.27 113.51,197.34 112.23,196.06 110.03,196.06 107.92,193.95 107.91,193.95 107.91,193.95 107.1,193.95 106.77,193.62 106.77,193.61 106.68,193.52 106.68,192.33 106.44,192.1 106.44,187.04 106.12,186.72 106.12,183.72 105.95,183.55 105.95,182.58 v3(106.33,182.2)
M2_MDQ6: length 92.7
  TOP w0.118: U22.AY12 v3(111.33,181.2)
  L12_INT_5 w0.087: J7.128 162.54,229.79 160.52,229.79 159.52,228.79 158.28,228.79 155.68,226.19 154.94,226.19 153.67,224.92 152.81,224.92 151.93,225.79 151.06,225.79 150.03,224.77 149.13,224.77 149.13,224.76 145.26,224.76 134.52,214.02 134.52,213.11 134.42,213 134.23,213 134.12,213.11 134.12,213.26 134.02,213.36 133.83,213.36 133.73,213.26 133.73,206.61 133.63,206.51 133.44,206.51 133.34,206.61 133.34,209.58 133.24,209.68 133.05,209.68 132.94,209.58 132.94,205.84 129.03,201.93 129.03,195.28 126.14,192.38 122.15,192.38 120.92,191.15 114.45,191.15 113.18,189.89 113.18,187.81 111.96,186.59 111.96,185.5 110.92,184.46 110.92,181.6 111.05,181.48 111.05,181.48 v3(111.33,181.2)
M2_MDQ7: length 92.7
  TOP w0.118: U22.BA12 v3(110.33,182.2)
  L12_INT_5 w0.087: J7.129 164.65,229.77 163.53,230.89 162.05,230.89 161.38,230.21 160.28,230.21 159.28,229.21 157.33,229.21 156.21,228.09 154.94,228.09 153.8,226.95 152.65,226.95 151.89,226.19 150.88,226.19 149.86,225.17 145.03,225.17 133.25,213.39 133.25,210.24 133.15,210.13 132.96,210.13 132.85,210.24 132.85,212.51 132.77,212.59 132.55,212.59 132.46,212.5 132.46,205.99 128.52,202.06 128.52,195.33 125.98,192.79 121.92,192.79 120.68,191.55 114.08,191.55 112.78,190.25 112.78,187.96 111.56,186.74 111.56,185.72 110.72,184.89 110.72,182.59 110.61,182.48 v3(110.33,182.2)
M2_MDQ8: length 94.2
  TOP w0.118: U22.AU15 v3(108.33,177.2)
  L3_INT_1 w0.087: J7.12 157.17,226 156.93,225.77 154.52,225.77 153.67,224.92 152.65,224.92 151.78,225.79 150.73,225.79 149.99,225.04 149.17,225.04 148.16,226.06 142.71,226.06 142.62,226.15 142.62,226.36 142.71,226.45 145.89,226.45 145.98,226.55 145.98,226.76 145.9,226.85 142.47,226.85 127.53,211.91 127.53,208.56 124.84,205.87 123.09,205.87 116.7,199.47 114.16,199.47 113.82,199.12 113.82,197.31 111.37,194.86 110.47,194.86 106.75,191.14 106.75,184.15 106.93,183.98 106.93,179.17 107.82,178.28 107.82,177.7 v3(108.33,177.2)
M2_MDQ9: length 94.2
  TOP w0.118: U22.AV15 v3(107.33,178.2)
  L3_INT_1 w0.087: J7.13 160.85,225.61 159.67,226.79 156.56,226.79 155.98,226.21 154.53,226.21 153.96,226.79 152.36,226.79 151.79,226.21 150.6,226.21 149.99,226.82 146.91,226.82 146.33,227.41 142.47,227.41 127.14,212.08 127.14,208.8 124.79,206.45 123.04,206.45 116.47,199.89 113.98,199.89 113.52,199.43 111.34,199.43 109.96,198.04 109.96,194.99 109.87,194.9 109.65,194.9 109.56,194.99 109.56,196.93 109.48,197.02 109.27,197.02 109.17,196.91 109.17,194.11 106.36,191.31 106.36,184.14 106.73,183.77 106.73,178.8 v3(107.33,178.2)
M2_MDQ10: length 94.2
  TOP w0.118: U22.AU11 111.33,178.19 v3(111.33,178.2)
  L3_INT_1 w0.087: J7.18 158.18,220 155.99,217.81 154.43,217.81 153.84,217.21 152.74,217.21 151.89,218.06 150.88,218.06 150.03,217.21 149.06,217.21 148.23,218.04 146.65,218.04 146.56,218.13 146.56,218.34 146.65,218.43 148.47,218.43 148.56,218.52 148.56,218.74 148.47,218.83 140.95,218.83 140.86,218.92 140.86,219.13 140.95,219.22 144.94,219.22 145.03,219.31 145.03,219.53 144.94,219.61 140.7,219.61 131.39,210.31 131.39,206.32 128.27,203.2 128.27,201.04 126.49,199.26 124.84,199.26 124.21,198.63 124.21,196.09 121.64,193.52 115.75,193.52 110.82,188.6 110.82,186.26 109.94,185.38 109.94,178.99 110.24,178.69 110.84,178.69 v3(111.33,178.2)
M2_MDQ11: length 94.2
  TOP w0.118: U22.AV11 v3(111.33,179.2)
  L3_INT_1 w0.087: J7.19 160.85,218.48 159.54,217.17 158.47,217.17 157.09,215.79 154.57,215.79 153.75,214.96 152.83,214.96 152.02,215.77 150.62,215.77 149.86,215.01 148.92,215.01 147.54,216.39 139.66,216.39 139.57,216.48 139.57,216.7 139.66,216.79 146.24,216.79 146.33,216.88 146.33,217.09 146.24,217.18 139.38,217.18 132.18,209.99 132.18,205.84 129.29,202.95 129.29,197.74 124.26,192.71 116.14,192.71 112.42,188.99 112.42,185.95 110.94,184.47 110.94,179.59 v3(111.33,179.2)
M2_MDQ12: length 94.2
  TOP w0.118: U22.AU16 v3(106.33,178.19)
  L3_INT_1 w0.087: J7.131 162.64,227 161.42,228.21 160.15,228.21 159.6,228.77 156.25,228.77 155.7,228.21 154.44,228.21 153.88,228.77 152.49,228.77 151.94,228.21 150.84,228.21 150.2,228.85 142.77,228.85 126.09,212.17 126.09,210.68 116.25,200.84 113.66,200.84 113.13,200.31 111.11,200.31 106.25,195.45 106.25,193.09 104.9,191.74 104.9,179.91 105.12,179.7 105.53,179.7 105.84,179.4 105.84,178.69 106.05,178.48 106.05,178.48 v3(106.33,178.19)
M2_MDQ13: length 94.2
  TOP w0.118: v3(106.33,179.2) 106.33,179.19 U22.AV16
  L3_INT_1 w0.087: v3(106.33,179.2) 106.33,180.32 105.79,180.86 105.79,184.07 105.97,184.25 105.97,192.2 106.68,192.91 106.68,195.33 111.25,199.89 113.42,199.89 113.92,200.4 116.38,200.4 122.88,206.91 124.61,206.91 126.67,208.97 126.67,212.17 142.56,228.05 148.52,228.05 148.61,227.97 148.61,227.75 148.52,227.66 147.42,227.66 147.33,227.57 147.33,227.36 147.47,227.22 150.25,227.22 150.82,227.79 152.2,227.79 152.77,227.21 153.68,227.21 154.25,227.79 157.84,227.79 158.41,227.21 159.65,227.21 160.22,227.79 161.21,227.79 162.75,226.25 J7.132
M2_MDQ14: length 94.2
  TOP w0.118: U22.AU12 v3(110.33,178.2)
  L3_INT_1 w0.087: v3(110.33,178.2) 109.74,178.79 109.74,185.68 110.26,186.21 110.26,189.64 111.07,190.45 111.91,190.45 115.39,193.93 121.28,193.93 123.8,196.44 123.8,198.98 124.49,199.67 126.16,199.67 127.63,201.15 127.63,203.33 131,206.69 131,210.48 140.53,220.01 148.48,220.01 148.57,219.92 148.57,219.7 148.48,219.61 145.57,219.61 145.48,219.53 145.48,219.31 145.57,219.22 150.13,219.22 150.88,219.96 151.89,219.96 152.86,219 153.75,219 154.53,218.21 155.57,218.21 158.34,220.98 159.56,220.98 160.43,221.84 161.44,221.84 162.29,221 J7.137
M2_MDQ15: length 94.2
  TOP w0.118: U22.AV12 v3(110.33,179.2)
  L3_INT_1 w0.087: v3(110.33,179.2) 110.74,179.6 110.74,185.03 111.23,185.52 111.23,188.4 115.94,193.12 124.03,193.12 128.78,197.87 128.78,203.11 131.79,206.12 131.79,210.15 140,218.36 145.69,218.36 145.78,218.27 145.78,218.06 145.69,217.97 140.2,217.97 140.11,217.88 140.11,217.66 140.2,217.57 148.06,217.57 148.85,216.79 150.01,216.79 150.57,216.23 152.06,216.23 152.61,216.79 153.96,216.79 154.53,216.21 155.76,216.21 158.5,218.95 159.26,218.95 160.31,220 J7.138
M2_MDQ16: length 85.4
  TOP w0.118: U22.AU8 114.33,178.19 v3(114.33,178.2)
  L12_INT_5 w0.087: v3(114.33,178.2) 113.92,178.61 113.92,179.45 114.17,179.71 114.43,179.71 114.71,179.99 114.71,185.83 115.02,186.14 119.12,186.14 121.14,188.16 133.43,188.16 141.21,195.94 141.21,210.91 141.3,211 141.51,211 141.6,210.91 141.6,210.02 141.69,209.93 141.9,209.93 141.99,210.02 141.99,212.52 142.08,212.61 142.3,212.61 142.39,212.52 142.39,210.73 142.48,210.64 142.69,210.64 142.78,210.73 142.78,213.39 146.43,217.04 150.24,217.04 151.26,218.06 151.89,218.06 152.91,217.04 153.8,217.04 154.55,217.79 155.97,217.79 156.76,217 J7.21
M2_MDQ17: length 85.4
  TOP w0.118: U22.AV8 114.33,179.19 v3(114.33,179.2)
  L12_INT_5 w0.087: v3(114.33,179.2) 114.95,179.81 114.95,185.43 115.26,185.75 119.3,185.75 121.31,187.76 133.65,187.76 141.6,195.7 141.6,208.78 143.28,210.46 143.28,213.27 143.37,213.36 143.59,213.36 143.67,213.27 143.67,209.38 143.76,209.3 143.98,209.3 144.07,209.38 144.07,213.78 144.16,213.87 144.37,213.87 144.46,213.78 144.46,212.28 144.55,212.19 144.77,212.19 144.86,212.28 144.86,213.94 145.8,214.88 149.86,214.88 150.9,215.93 151.79,215.93 152.7,215.01 153.8,215.01 154.79,216 J7.22
M2_MDQ18: length 85.3
  TOP w0.118: U22.AU4 v3(119.33,178.2)
  L12_INT_5 w0.087: J7.27 160.31,210.46 160.02,210.17 160.02,209.6 159.54,209.12 158.88,209.12 157.86,208.1 157.86,204.98 156.97,204.09 154.94,204.09 153.8,202.95 152.78,202.95 152.34,202.5 152.34,200.6 151.64,199.9 150.93,199.9 150.42,199.39 150.42,193.47 149.86,192.91 148.08,192.91 144.78,189.61 144.78,184.02 142.82,182.06 138.06,182.06 137.97,181.97 137.97,181.76 138.06,181.67 147.22,181.67 147.31,181.58 147.31,181.36 147.22,181.27 128.06,181.27 126.87,180.09 126.23,180.09 125.6,180.72 123.87,180.72 123.1,179.96 121.67,179.96 120.4,178.69 119.82,178.69 v3(119.33,178.2)
M2_MDQ19: length 85.3
  TOP w0.118: U22.AV4 v3(119.33,179.2)
  L12_INT_5 w0.087: J7.28 156.59,207.64 156.59,206.63 155.93,205.97 154.79,205.97 153.8,204.98 152.78,204.98 151.89,204.09 150.88,204.09 149.99,204.98 148.84,204.98 148.38,204.51 148.38,194.32 144.02,189.97 144.02,184.02 142.45,182.45 126.96,182.45 126.87,182.37 126.87,182.15 126.96,182.06 137.39,182.06 137.48,181.97 137.48,181.76 137.39,181.67 127.18,181.67 126.75,181.23 123.8,181.23 123.16,180.59 120.73,180.59 v3(119.33,179.2)
M2_MDQ20: length 85.4
  TOP w0.118: U22.AU9 v3(113.33,178.2)
  L12_INT_5 w0.087: v3(113.33,178.2) 112.78,178.75 112.78,180.21 113.16,180.59 113.54,180.59 113.73,180.78 113.73,185.99 114.68,186.94 118.77,186.94 120.88,189.05 133.17,189.05 140.42,196.3 140.42,212.33 149.07,220.98 150.04,220.98 151.05,222 151.79,222 152.68,221.11 153.8,221.11 154.69,222 155.7,222 156.72,220.98 159.38,220.98 160.35,220.01 161.24,220.01 162.75,218.5 J7.140
M2_MDQ21: length 85.4
  TOP w0.118: U22.AV9 113.33,179.19 v3(113.33,179.2)
  L12_INT_5 w0.087: J7.141 162.35,217 161.42,217.93 160.4,217.93 159.38,218.95 156.97,218.95 156.21,218.19 154.58,218.19 153.7,219.07 152.78,219.07 151.89,219.96 150.88,219.96 149.91,219 147.75,219 141.6,212.85 141.6,211.48 141.51,211.39 141.3,211.39 141.21,211.49 141.21,212.13 141.12,212.22 140.9,212.22 140.81,212.13 140.81,196.12 133.26,188.57 120.97,188.57 118.95,186.55 114.87,186.55 113.95,185.63 113.95,180.12 113.33,179.5 v3(113.33,179.2)
M2_MDQ22: length 85.3
  TOP w0.118: v3(118.33,178.2) U22.AU5
  L12_INT_5 w0.087: v3(118.33,178.2) 117.86,178.67 117.86,182.5 118.11,182.75 123.44,182.75 124.08,182.12 125.44,182.12 126.57,183.24 135.54,183.24 136.32,184.03 141.9,184.03 141.99,184.12 141.99,184.33 141.9,184.42 136.74,184.42 136.65,184.51 136.65,184.73 136.74,184.82 142.02,184.82 142.75,185.55 142.75,189.99 145.11,192.35 145.11,195.02 147.58,197.49 147.58,208.41 148.21,209.04 149.83,209.04 150.85,208.03 151.76,208.03 152.72,208.99 153.8,208.99 154.79,209.98 156.64,209.98 157.86,211.2 159.26,211.2 160.28,212.21 161.59,212.21 161.8,212 J7.146
M2_MDQ23: length 85.4
  TOP w0.118: U22.AV5 v3(118.33,179.2)
  L12_INT_5 w0.087: J7.147 162.13,211 161.31,211.82 160.44,211.82 159.43,210.81 158.36,210.81 155.55,208 154.79,208 153.77,206.98 152.76,206.98 151.76,205.99 150.85,205.99 149.71,207.14 148.46,207.14 147.98,206.66 147.98,197.23 145.92,195.17 145.54,194.79 145.54,192.15 143.51,190.12 143.51,184.53 142.61,183.64 136.49,183.64 136.4,183.55 136.4,183.33 136.49,183.24 142.28,183.24 142.37,183.15 142.37,182.94 142.28,182.85 126.75,182.85 125.62,181.71 119.1,181.71 118.74,181.36 118.74,179.61 v3(118.33,179.2)
M2_MDQ24: length 83.8
  TOP w0.118: U22.AY8 v3(115.33,181.2)
  L3_INT_1 w0.087: J7.30 154.58,208 153.8,208.79 152.78,208.79 152.2,208.2 150.86,208.2 150.28,208.79 148.92,208.79 147.59,210.12 147.59,212.71 146.06,214.23 139.48,214.23 136.7,211.45 136.7,205.22 136.61,205.13 136.4,205.13 136.31,205.22 136.31,210.58 136.22,210.67 136,210.67 135.92,210.58 135.92,205.66 131.47,201.22 131.47,196.68 125.3,190.5 117.98,190.5 117.47,189.99 117.47,189.48 114.81,186.82 114.81,186 114.92,185.89 114.92,181.6 v3(115.33,181.2)
M2_MDQ25: length 83.8
  TOP w0.118: U22.BA8 114.33,182.19 v3(114.33,182.2)
  L3_INT_1 w0.087: J7.31 160.85,207.7 159.51,209.04 157.99,209.04 157.1,209.93 154.45,209.93 153.73,209.21 152.61,209.21 151.76,210.06 150.75,210.06 150,210.81 148.5,210.81 147.98,211.33 147.98,212.87 146.23,214.63 139.32,214.63 135.52,210.83 135.52,205.84 135.43,205.75 135.22,205.75 135.13,205.84 135.13,210.01 135.04,210.1 134.82,210.1 134.73,210.01 134.73,205.27 131.08,201.62 131.08,196.89 125.09,190.91 117.37,190.91 116.26,189.79 116.26,189.15 114.4,187.3 114.4,185.94 114.72,185.62 114.72,182.59 v3(114.33,182.2)
M2_MDQ26: length 83.9
  TOP w0.118: U22.AY4 v3(119.33,181.2)
  L3_INT_1 w0.087: J7.36 157.26,202 155.48,200.21 154.82,200.21 153.82,201.21 152.68,201.21 151.69,200.23 150.73,200.23 150.17,200.79 148.59,200.79 146.43,202.95 146.43,204.31 146.34,204.4 146.11,204.4 146.02,204.31 146.02,201.68 145.93,201.59 145.71,201.59 145.62,201.68 145.62,204.35 145.54,204.44 145.32,204.44 145.23,204.35 145.23,195.81 145.14,195.72 144.93,195.72 144.84,195.81 144.84,204.4 144.75,204.49 144.53,204.49 144.44,204.4 144.44,195.6 144.18,195.33 143.14,195.33 136.66,188.86 132.72,188.86 129.62,185.76 125.95,185.76 125.49,185.31 121.17,185.31 119.63,183.77 119.25,183.77 118.87,183.39 118.87,181.65 v3(119.33,181.2)
M2_MDQ27: length 83.8
  TOP w0.118: U22.BA4 v3(119.33,182.2)
  L3_INT_1 w0.087: J7.37 160.67,201.18 157.44,201.18 156.05,199.79 154.58,199.79 153.58,200.79 152.92,200.79 151.92,199.79 151.02,199.79 150.27,199.03 148.53,199.03 147.99,198.5 147.99,197.29 147.9,197.21 147.68,197.21 147.59,197.29 147.59,201.19 147.5,201.28 147.29,201.28 147.2,201.19 147.2,195.66 147.11,195.57 146.89,195.57 146.81,195.66 146.81,201.57 146.72,201.66 146.5,201.66 146.41,201.57 146.41,195.66 146.32,195.57 146.11,195.57 146.02,195.66 146.02,201.1 145.93,201.19 145.71,201.19 145.62,201.1 145.62,195.64 144.93,194.94 143.33,194.94 136.85,188.47 132.88,188.47 129.33,184.91 121.65,184.91 119.33,182.6 v3(119.33,182.2)
M2_MDQ28: length 83.8
  TOP w0.118: U22.AY9 v3(114.33,181.2)
  L3_INT_1 w0.087: J7.149 164.65,209.62 163.32,210.95 162.31,210.95 161.29,211.96 160.27,211.96 159.38,212.85 158.11,212.85 156.84,214.12 154.81,214.12 153.67,212.98 152.78,212.98 151.76,214 150.88,214 149.99,213.11 148.97,213.11 146.66,215.42 138.99,215.42 133.95,210.37 133.95,208.88 133.86,208.79 133.64,208.79 133.55,208.88 133.55,209.54 133.47,209.63 133.25,209.63 133.16,209.54 133.16,205.32 130.27,202.43 130.27,197.25 124.74,191.72 116.53,191.72 113.41,188.59 113.41,186.08 112.85,185.52 112.85,182.04 113.16,181.74 113.79,181.74 v3(114.33,181.2)
M2_MDQ29: length 83.8
  TOP w0.118: U22.BA9 v3(113.33,182.2)
  L3_INT_1 w0.087: v3(113.33,182.2) 113.88,182.75 113.88,188.41 114.76,189.28 115.37,189.28 115.83,189.74 115.83,190.06 117.08,191.31 124.94,191.31 130.66,197.04 130.66,201.99 133.55,204.88 133.55,208.11 133.64,208.2 133.86,208.2 133.95,208.11 133.95,205.68 134.04,205.58 134.25,205.58 134.34,205.67 134.34,210.21 139.16,215.02 146.39,215.02 148.38,213.04 148.38,211.62 148.79,211.2 149.99,211.2 150.75,211.96 151.64,211.96 152.53,211.07 153.8,211.07 154.81,212.09 156.72,212.09 157.86,210.95 159.51,210.95 160.48,209.98 161.37,209.98 162.75,208.6 J7.150
M2_MDQ30: length 83.8
  TOP w0.118: v3(118.33,181.2) U22.AY5
  L3_INT_1 w0.087: J7.155 162.63,203 161.67,203.96 160.53,203.96 159.78,203.21 156.6,203.21 155.6,202.21 154.82,202.21 153.82,203.21 152.68,203.21 151.68,202.21 150.72,202.21 149.99,202.95 148.98,202.95 146.55,205.38 145.08,205.38 144.84,205.63 144.84,207.31 144.74,207.4 144.53,207.4 144.44,207.32 144.44,205.44 144.35,205.35 144.14,205.35 144.05,205.44 144.05,208.14 143.96,208.23 143.74,208.23 143.66,208.14 143.66,205.43 143.57,205.34 143.35,205.34 143.26,205.43 143.26,208.15 143.17,208.24 142.96,208.24 142.87,208.15 142.87,196.23 136.28,189.65 132.39,189.65 129.31,186.56 125.22,186.56 124.84,186.18 118.62,186.18 117.74,185.3 117.74,181.79 118.05,181.48 118.05,181.48 v3(118.33,181.2)
M2_MDQ31: length 83.8
  TOP w0.118: U22.BA5 v3(118.33,182.2)
  L3_INT_1 w0.087: J7.156 160.46,202 159.67,202.79 157.17,202.79 156.17,201.79 154.58,201.79 153.58,202.79 152.92,202.79 151.92,201.79 151.02,201.79 150.45,201.22 148.79,201.22 146.86,203.15 146.86,204.51 146.42,204.95 144.27,204.95 144.05,204.73 144.05,195.82 143.96,195.73 143.74,195.73 143.66,195.82 143.66,204.86 143.57,204.95 143.36,204.95 143.26,204.85 143.26,196.04 136.47,189.26 132.56,189.26 129.46,186.16 125.48,186.16 125.04,185.72 119.79,185.72 118.7,184.64 118.22,184.64 117.94,184.36 117.94,182.59 v3(118.33,182.2)
M2_MDQ32: length 82.8
  TOP w0.118: U22.AP8 v3(115.33,175.2)
  L12_INT_5 w0.087: J7.81 158.66,153 155.63,156.03 154.94,156.03 153.77,157.2 152.83,157.2 151.82,158.22 151.03,158.22 150.01,159.23 148.62,159.23 146.41,161.44 146.41,171.09 142.94,174.56 131.76,174.56 131.67,174.65 131.67,174.87 131.76,174.96 140.88,174.96 140.97,175.04 140.97,175.26 140.88,175.35 130.77,175.35 128.4,177.72 126.31,177.72 126.03,178 125.55,178 125.22,177.67 123.7,177.67 123.37,178 122.25,178 121.79,177.55 121.79,177.04 120.54,175.79 115.92,175.79 v3(115.33,175.2)
M2_MDQ33: length 82.8
  TOP w0.118: U22.AP7 v3(116.33,175.2)
  L12_INT_5 w0.087: v3(116.33,175.2) 116.72,175.59 120.85,175.59 122,176.73 122.81,176.73 123.32,177.24 125.17,177.24 125.48,176.94 128.63,176.94 131.39,174.17 142.7,174.17 142.79,174.08 142.79,173.86 142.7,173.77 132.23,173.77 132.14,173.69 132.14,173.47 132.23,173.38 143.42,173.38 144.84,171.96 144.84,169.23 145.92,168.15 145.92,161.29 148.34,158.88 148.41,158.88 148.45,158.84 149.8,158.84 150.82,157.81 151.64,157.81 152.65,156.79 153.57,156.79 154.08,156.29 154.08,154.53 154.63,153.98 156.29,153.98 158.26,152 J7.82
M2_MDQ34: length 82.8
  TOP w0.118: v3(114.33,171.2) U22.AK8
  L12_INT_5 w0.087: J7.87 160.85,146.37 159.51,145.03 156.84,145.03 155.96,144.15 154.81,144.15 153.67,143 152.78,143 151.99,143.79 150.65,143.79 149.99,143.13 146.05,143.13 144.14,145.03 144.14,152.96 144.06,153.05 143.84,153.05 143.75,152.96 143.75,145.82 143.66,145.73 143.45,145.73 143.36,145.82 143.36,155.35 128.12,170.59 123.84,170.59 123.08,171.35 121.77,171.35 121.51,171.6 116.1,171.6 115.82,171.32 115.82,171.11 115.4,170.69 114.84,170.69 114.33,171.19 v3(114.33,171.2)
M2_MDQ35: length 82.8
  TOP w0.118: v3(115.33,171.2) U22.AK7
  L12_INT_5 w0.087: v3(115.33,171.2) 115.94,171.8 123.2,171.8 124.01,170.99 128.35,170.99 143.75,155.59 143.75,153.56 143.84,153.47 144.06,153.47 144.15,153.56 144.15,154.58 144.24,154.67 144.45,154.67 144.54,154.58 144.54,145.2 144.63,145.11 144.85,145.11 144.93,145.2 144.93,153.85 145.02,153.93 145.24,153.93 145.33,153.85 145.33,145.25 146,144.58 148.7,144.58 149.14,145.01 149.78,145.01 150.6,144.2 151.82,144.2 152.78,145.16 153.64,145.16 154.48,146 J7.88
M2_MDQ36: length 82.8
  TOP w0.118: v3(115.33,176.2) 115.33,176.19 U22.AR8
  L12_INT_5 w0.087: v3(115.33,176.2) 115.82,176.69 115.82,177.42 116.08,177.67 120.65,177.67 120.9,177.93 120.9,178.44 121.33,178.86 123.49,178.86 124.37,179.74 125.72,179.74 126.92,178.54 137.53,178.54 137.62,178.45 137.62,178.23 137.53,178.14 130.06,178.14 129.97,178.05 129.97,177.84 130.06,177.75 142.67,177.75 148.54,171.88 148.54,163.69 150.43,161.8 152.91,161.8 154.69,160.02 155.83,160.02 156.84,159 159.44,159 160.45,157.99 161.29,157.99 161.8,157.48 161.8,155.32 162.75,154.37 J7.200
M2_MDQ37: length 82.8
  TOP w0.118: U22.AR7 116.33,176.19 v3(116.33,176.2)
  L12_INT_5 w0.087: v3(116.33,176.2) 116.61,176.48 116.79,176.66 120.65,176.66 120.9,176.91 120.9,177.42 121.16,177.67 121.41,177.67 122.17,178.44 123.52,178.44 123.82,178.13 125.09,178.13 125.4,178.44 126.24,178.44 126.54,178.13 128.8,178.13 130.4,176.53 138.96,176.53 139.05,176.44 139.05,176.23 138.96,176.14 131.11,176.14 131.03,176.05 131.03,175.83 131.11,175.74 142.33,175.74 146.81,171.26 146.81,164.06 150.98,159.89 151.89,159.89 152.78,159 153.8,159 154.81,157.99 157.1,157.99 158.11,156.97 159.51,156.97 159.89,156.59 159.89,154.43 160.27,154.05 161.16,154.05 162.21,153 J7.201
M2_MDQ38: length 82.8
  TOP w0.118: v3(114.33,172.2) U22.AL8
  L12_INT_5 w0.087: J7.206 161.98,148 161.8,148.18 160.32,148.18 159.36,147.21 157.49,147.21 156.48,148.22 154.55,148.22 153.75,149.02 152.55,149.02 151.59,149.99 150.88,149.99 149.73,151.13 148.59,151.13 148.08,150.62 148.08,146.72 147.99,146.63 147.78,146.63 147.69,146.72 147.69,152.58 147.6,152.67 147.39,152.67 147.3,152.58 147.3,146.53 147.21,146.44 146.99,146.44 146.9,146.53 146.9,153.71 128.77,171.84 124.32,171.84 123.36,172.79 114.92,172.79 v3(114.33,172.2)
M2_MDQ39: length 82.9
  TOP w0.118: U22.AL7 v3(115.33,172.2)
  L12_INT_5 w0.087: v3(115.33,172.2) 115.61,172.48 115.72,172.59 121.48,172.59 121.81,172.26 123.32,172.26 124.18,171.4 128.57,171.4 145.72,154.25 145.72,145.76 145.81,145.67 146.03,145.67 146.12,145.76 146.12,152.82 146.2,152.91 146.42,152.91 146.51,152.82 146.51,146.23 146.81,145.92 148.08,145.92 149.22,147.07 149.99,147.07 150.88,147.96 151.73,147.96 152.62,147.07 153.88,147.07 154.64,147.83 155.83,147.83 156.84,146.81 159.51,146.81 160.49,147.79 161.58,147.79 162.37,147 J7.207
M2_MDQ40: length 82.9
  TOP w0.118: U22.AP4 v3(118.33,174.2)
  L3_INT_1 w0.087: v3(118.33,174.2) 118.33,173.87 118.62,173.59 121.9,173.59 121.98,173.67 125.6,173.67 126.38,172.9 128.85,172.9 132.08,169.67 138.81,169.67 139.07,169.41 139.07,164.24 139.16,164.15 139.38,164.15 139.46,164.24 139.46,169.55 139.55,169.64 139.77,169.64 139.86,169.55 139.86,163.57 139.95,163.48 140.16,163.48 140.25,163.58 140.25,169.16 140.34,169.25 140.56,169.25 140.65,169.16 140.65,161.21 148.88,152.97 149.64,152.97 150.37,152.25 150.37,150.67 151.05,149.99 151.84,149.99 152.91,148.92 153.42,148.92 154.24,148.09 154.24,146.49 154.69,146.05 155.96,146.05 158.01,144 J7.90
M2_MDQ41: length 82.8
  TOP w0.118: U22.AP5 v3(117.33,174.2)
  L3_INT_1 w0.087: J7.91 160.85,143.62 159.39,145.07 158.36,145.07 157.48,145.95 157.48,147.07 156.51,148.03 154.99,148.03 154.38,148.64 154.38,150.04 153.42,151 152.73,151 151.61,152.12 151.13,152.12 150.5,152.76 150.5,154.24 149.75,154.98 147.43,154.98 141.89,160.52 141.89,169.73 141.8,169.82 141.59,169.82 141.5,169.73 141.5,161.46 141.41,161.37 141.19,161.37 141.1,161.46 141.1,170.05 140.84,170.31 132.08,170.31 129.1,173.29 126.62,173.29 125.86,174.05 121.86,174.05 121.59,173.79 119.07,173.79 118.87,173.99 118.87,174.24 118.49,174.63 117.76,174.63 v3(117.33,174.2)
M2_MDQ42: length 82.8
  TOP w0.118: U22.AK4 v3(119.33,171.2)
  L3_INT_1 w0.087: J7.96 157.02,139.93 154.84,139.93 153.69,141.07 152.8,141.07 151.8,140.07 150.9,140.07 150.04,139.2 144.54,139.2 141.56,142.18 141.56,153.32 141.47,153.41 141.26,153.41 141.17,153.32 141.17,143.85 141.06,143.74 140.87,143.74 140.77,143.84 140.77,156.03 127.28,169.52 124.05,169.52 122.91,170.66 121.94,170.66 121.79,170.81 119.71,170.81 119.33,171.19 v3(119.33,171.2)
M2_MDQ43: length 82.8
  TOP w0.118: U22.AK5 v3(117.33,170.2)
  L3_INT_1 w0.087: J7.97 160.85,136.52 159.46,135.13 156.84,135.13 155.64,133.93 154.7,133.93 153.56,135.07 152.84,135.07 151.72,133.96 150.8,133.96 149.71,135.05 146.64,135.05 138.8,142.89 138.8,155.54 138.72,155.63 138.5,155.63 138.41,155.54 138.41,149.31 138.32,149.22 138.11,149.22 138.02,149.31 138.02,157.11 127.89,167.23 124.6,167.23 122.39,169.44 121.77,169.44 121.61,169.6 121.06,169.6 120.85,169.39 119.79,169.39 119.58,169.6 117.92,169.6 v3(117.33,170.2)
M2_MDQ44: length 82.8
  TOP w0.118: U22.AR4 v3(119.33,175.2)
  L3_INT_1 w0.087: v3(119.33,175.2) 119.61,174.91 119.74,174.79 126.66,174.79 127.43,175.57 128.09,175.57 132.33,171.32 142.49,171.32 143.47,170.35 143.47,160.54 143.55,160.45 143.77,160.45 143.86,160.54 143.86,164.88 143.95,164.97 144.16,164.97 144.25,164.88 144.25,159.86 144.34,159.77 144.56,159.77 144.65,159.86 144.65,162.97 144.74,163.06 144.95,163.06 145.04,162.97 145.04,159.92 145.87,159.09 149.8,159.09 150.34,158.55 150.34,156.75 150.86,156.23 151.87,156.23 153.19,154.91 153.72,154.91 154.31,154.33 154.31,152.59 155,151.89 155.54,151.89 158.5,148.93 159.4,148.93 160.33,148.01 161.22,148.01 162.3,146.93 163.2,146.93 164.65,145.48 J7.209
M2_MDQ45: length 82.8
  TOP w0.118: U22.AR5 v3(118.33,175.2)
  L3_INT_1 w0.087: v3(118.33,175.2) 118.33,175.19 118.94,174.59 121.54,174.59 121.69,174.43 126.17,174.43 126.92,173.69 129.34,173.69 132.21,170.82 141.99,170.82 142.28,170.52 142.28,161.29 142.37,161.2 142.59,161.2 142.68,161.29 142.68,169.54 142.77,169.63 142.98,169.63 143.07,169.54 143.07,160.29 146.35,157.01 149.53,157.01 150.73,155.8 151.74,155.8 152.3,155.25 152.3,153.52 152.78,153.03 153.3,153.03 154.02,152.32 154.02,150.96 154.9,150.07 155.62,150.07 158.62,147.07 159.26,147.07 160.4,145.93 161.41,145.93 162.75,144.59 J7.210
M2_MDQ46: length 82.8
  TOP w0.118: U22.AL4 v3(118.33,171.2)
  L3_INT_1 w0.087: v3(118.33,171.2) 118.61,170.91 118.95,170.58 121.64,170.58 121.96,170.26 122.72,170.26 124.37,168.61 127.64,168.61 139.59,156.65 139.59,149.83 139.68,149.75 139.9,149.75 139.99,149.83 139.99,155.81 140.07,155.9 140.29,155.9 140.38,155.81 140.38,142.7 144.27,138.81 149.99,138.81 150.59,138.21 151.94,138.21 152.8,139.07 153.69,139.07 154.69,138.07 157.58,138.07 158.44,137.21 159.28,137.21 160.28,138.21 161.45,138.21 162.24,139 J7.215
M2_MDQ47: length 82.8
  TOP w0.118: U22.AL5 v3(117.33,171.2)
  L3_INT_1 w0.087: v3(117.33,171.2) 117.86,170.67 117.86,170.05 118.1,169.8 121.54,169.8 121.59,169.85 122.56,169.85 124.21,168.2 127.49,168.2 139.2,156.49 139.2,143.23 139.29,143.14 139.5,143.14 139.59,143.23 139.59,149.21 139.68,149.3 139.9,149.3 139.99,149.21 139.99,142.36 145.27,137.07 149.9,137.07 150.62,137.79 151.94,137.79 152.8,136.93 153.7,136.93 154.56,136.07 156.14,136.07 156.85,136.79 159.52,136.79 160.52,137.79 162.54,137.79 J7.216
M2_MDQ48: length 82.7
  TOP w0.118: U22.AH6 v3(116.33,169.2)
  L12_INT_5 w0.087: v3(116.33,169.2) 116.73,169.2 117.34,169.8 121.79,169.8 121.96,169.64 122.43,169.64 123.9,168.16 123.9,167.79 124.54,167.16 128.96,167.16 138.44,157.67 138.44,148.01 138.53,147.92 138.75,147.92 138.84,148.01 138.84,156.17 138.93,156.26 139.14,156.26 139.23,156.17 139.23,147.28 147.73,138.79 150.01,138.79 150.6,138.2 151.84,138.2 152.86,137.19 153.75,137.19 154.72,136.21 157.28,136.21 158.5,135 J7.99
M2_MDQ49: length 82.7
  TOP w0.118: U22.AH5 v3(117.33,169.2)
  L12_INT_5 w0.087: v3(117.33,169.2) 117.74,169.6 121.48,169.6 121.85,169.23 122.26,169.23 123.49,168 123.49,167.59 124.33,166.75 128.78,166.75 137.26,158.27 137.26,147.74 137.35,147.65 137.57,147.65 137.66,147.74 137.66,156.95 137.75,157.04 137.96,157.04 138.05,156.95 138.05,147.83 148.77,137.11 149.99,137.11 150.65,137.77 151.71,137.77 152.7,136.78 153.59,136.78 154.59,135.79 156.82,135.79 158.61,134 J7.100
M2_MDQ50: length 82.7
  TOP w0.118: v3(115.33,167.2) U22.AF8
  L12_INT_5 w0.087: J7.105 160.85,128.34 159.49,126.97 158.42,126.97 155.52,124.08 154.63,124.08 153.72,124.99 152.78,124.99 151.76,126.01 150.82,126.01 149.89,126.95 148.77,126.95 147.95,127.76 147.95,129.82 137.82,139.95 132.64,139.95 128.14,144.45 128.14,149.58 128.05,149.67 127.84,149.67 127.75,149.58 127.75,147.6 127.66,147.51 127.44,147.51 127.36,147.6 127.36,150.46 123.27,154.55 123.27,156.34 120.17,159.44 120.17,163.27 119.48,163.96 114.66,163.96 113.79,164.82 113.79,166.47 114.07,166.75 114.89,166.75 v3(115.33,167.2)
M2_MDQ51: length 82.7
  TOP w0.118: v3(114.33,166.2) U22.AE8
  L12_INT_5 w0.087: v3(114.33,166.2) 114.81,165.72 114.81,164.97 115.19,164.59 119.66,164.59 120.66,163.59 120.66,159.76 124.52,155.89 124.52,153.99 128.56,149.95 128.56,145.81 128.65,145.72 128.87,145.72 128.96,145.81 128.96,152.06 129.04,152.15 129.26,152.15 129.35,152.06 129.35,143.83 132.78,140.4 137.93,140.4 149.35,128.98 150.04,128.98 150.93,128.09 151.82,128.09 152.91,127 153.92,127 154.74,126.19 156.29,126.19 158.1,128 J7.106
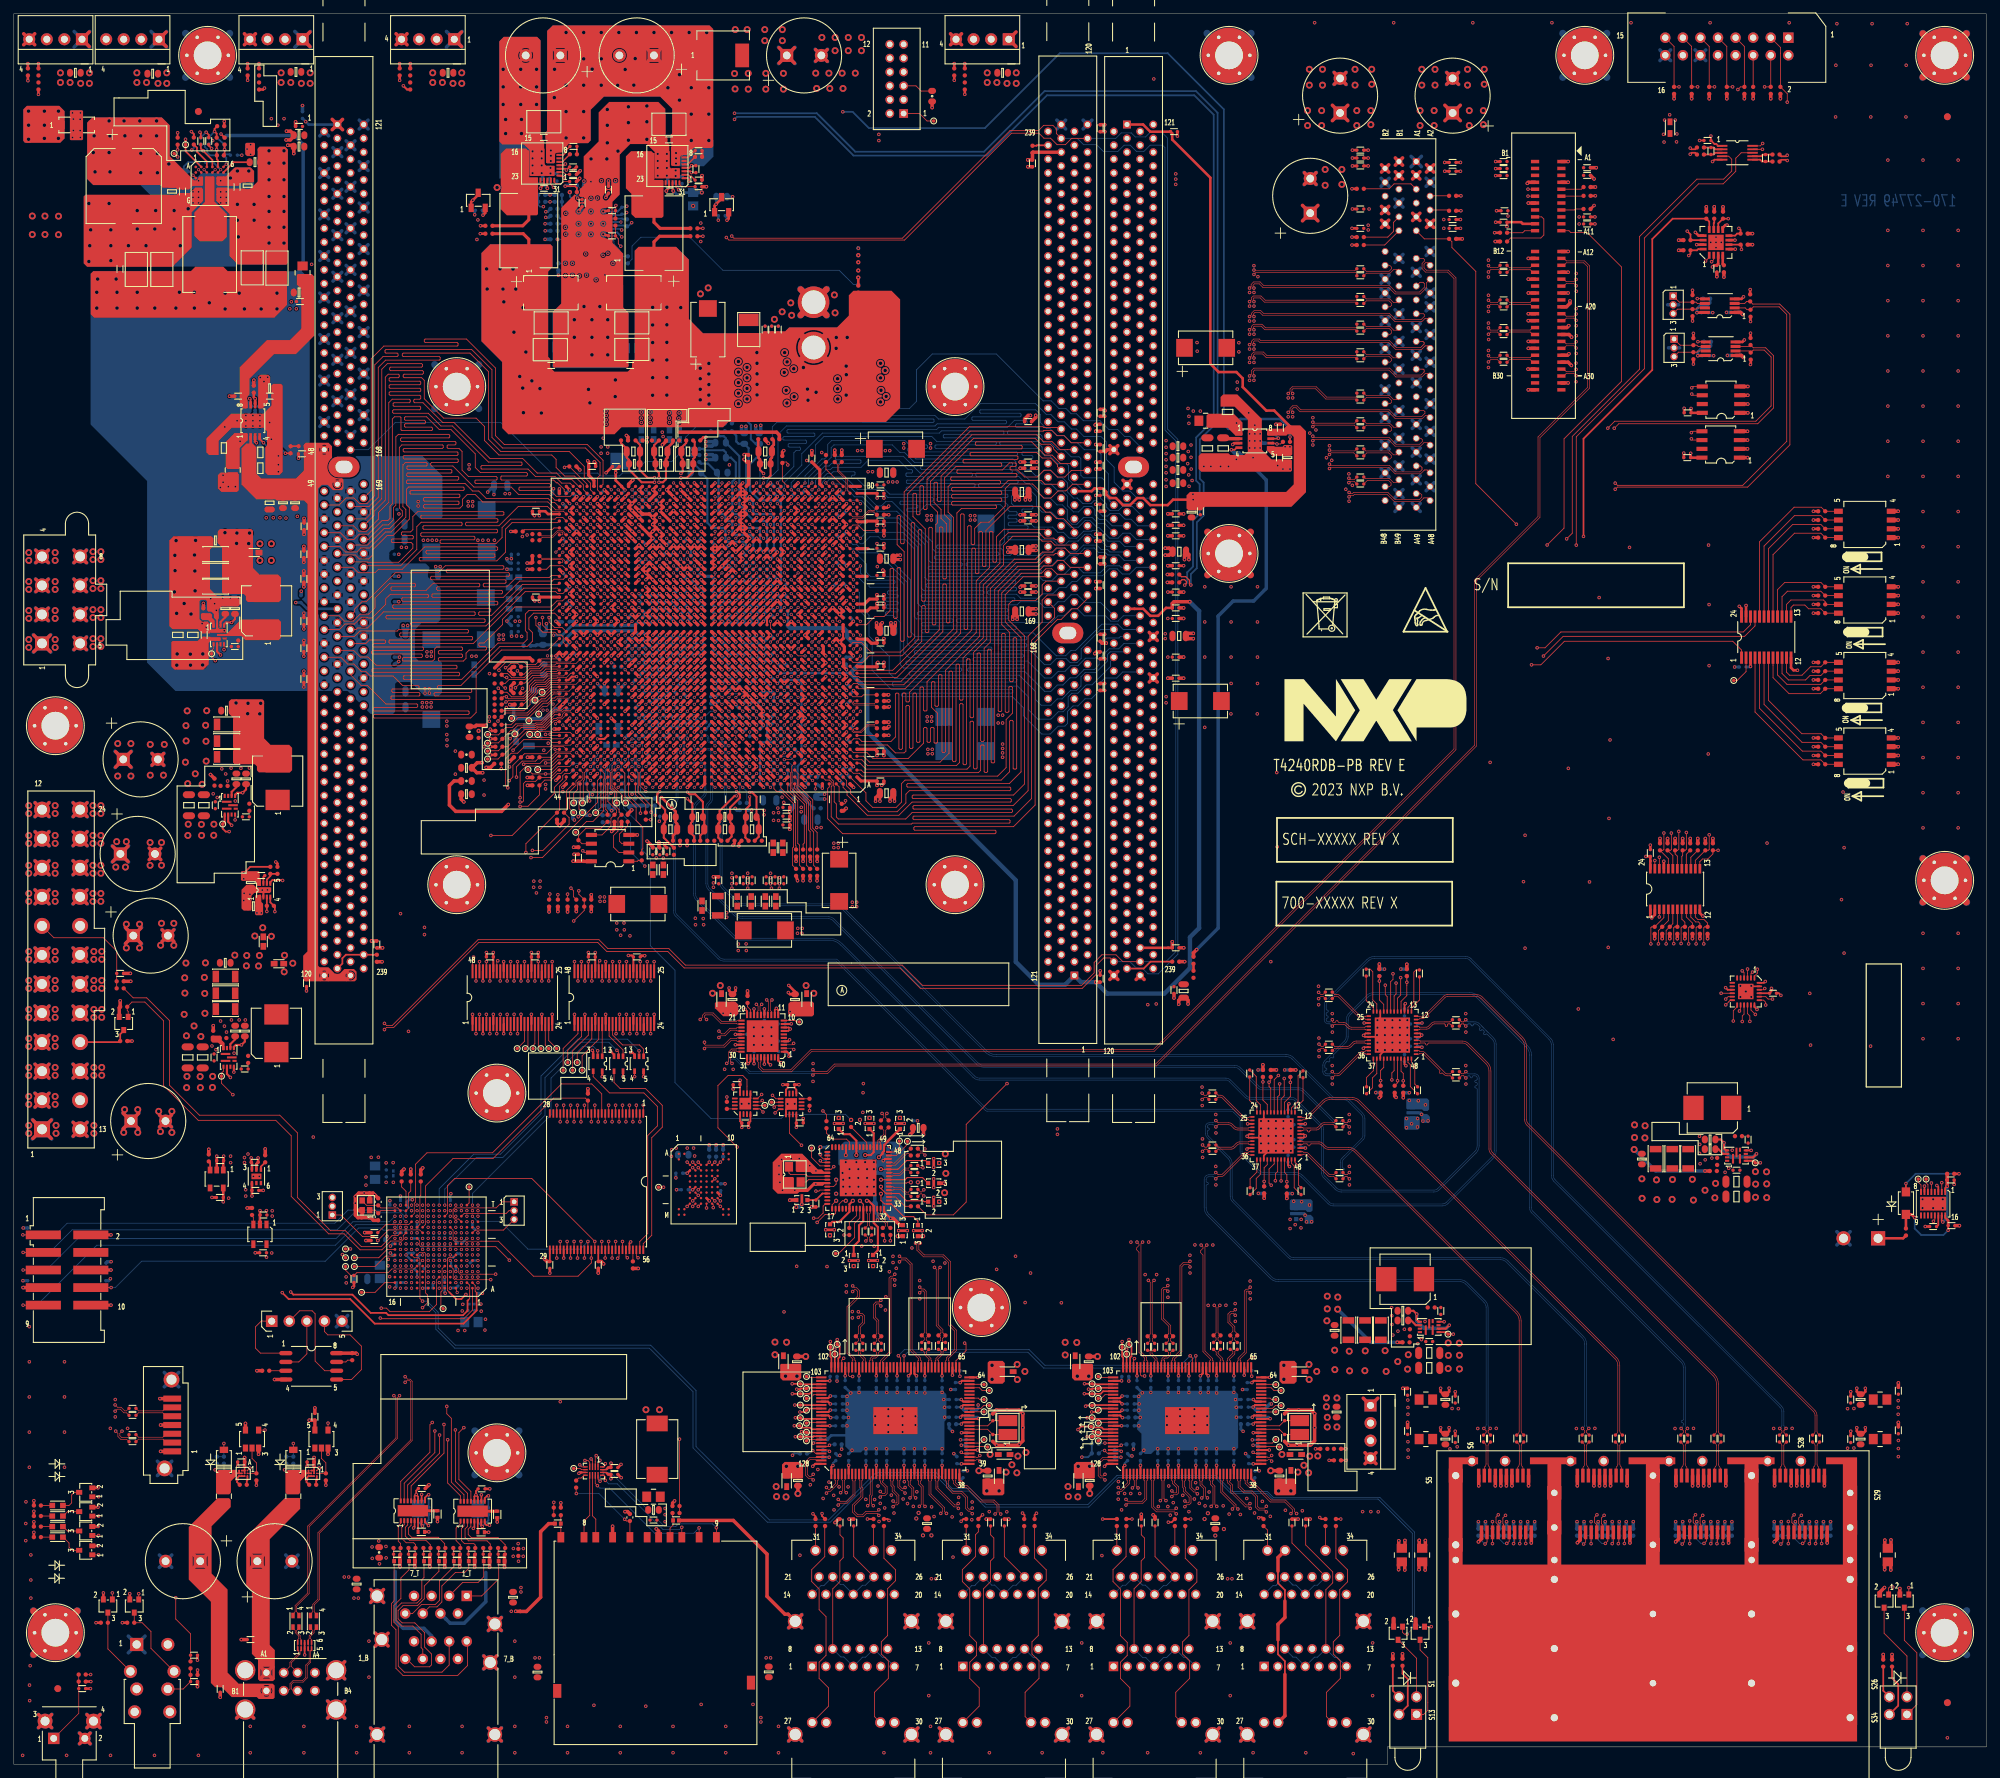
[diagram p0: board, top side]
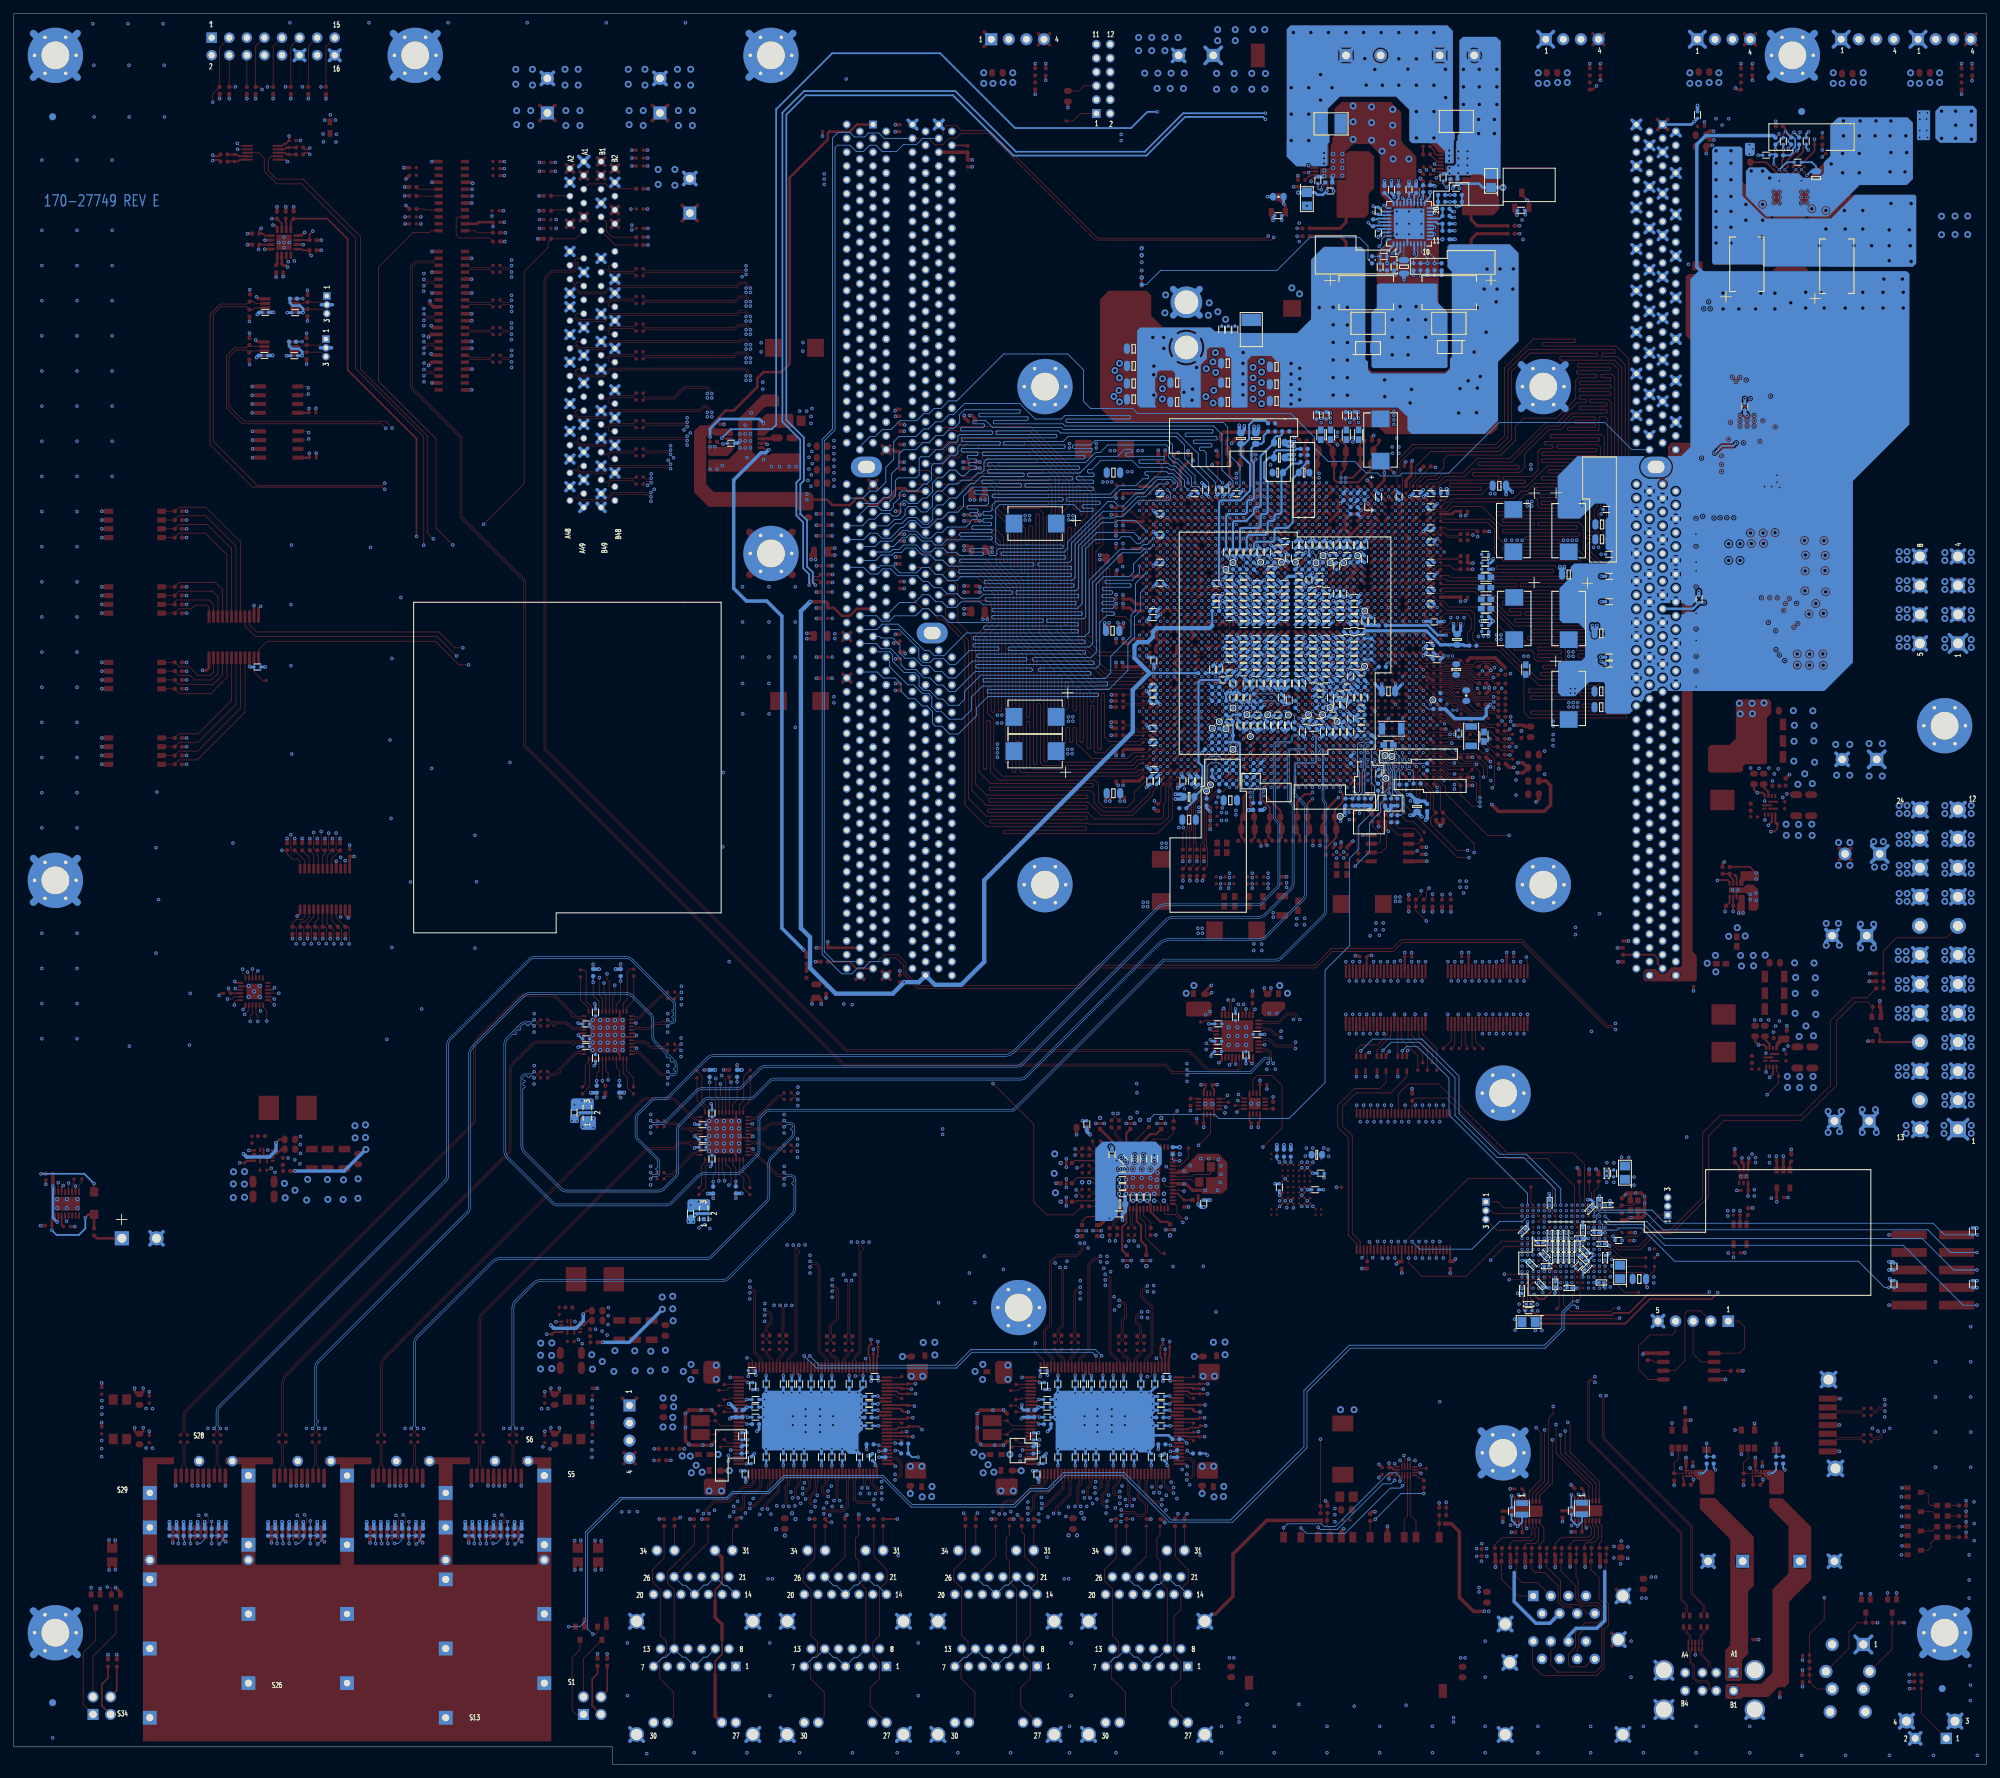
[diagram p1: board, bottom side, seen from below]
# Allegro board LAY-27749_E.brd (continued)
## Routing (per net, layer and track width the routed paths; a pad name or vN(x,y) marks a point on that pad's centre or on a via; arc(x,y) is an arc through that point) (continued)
M2_MDQ52: length 82.7
  TOP w0.118: v3(114.33,169.2) U22.AH8
  L12_INT_5 w0.087: v3(114.33,169.2) 114.81,169.67 115.38,169.67 115.82,170.11 115.82,170.26 116.35,170.79 121.82,170.79 122.16,170.45 122.76,170.45 123.62,169.6 127.69,169.6 140.81,156.47 140.81,148.12 140.9,148.03 141.11,148.03 141.2,148.12 141.2,153.7 141.29,153.78 141.51,153.78 141.59,153.7 141.59,146.19 146.81,140.97 149.86,140.97 150.75,141.86 151.76,141.86 152.53,141.1 153.57,141.1 154.61,140.06 157.02,140.06 158.01,139.07 159.64,139.07 160.78,137.92 161.42,137.92 162.75,136.59 J7.218
M2_MDQ53: length 82.7
  TOP w0.118: U22.AH7 v3(115.33,169.2)
  L12_INT_5 w0.087: v3(115.33,169.2) 115.61,169.48 115.81,169.67 116.46,169.67 116.84,170.05 116.84,170.43 116.99,170.59 121.51,170.59 122.05,170.05 122.59,170.05 124.21,168.43 128.27,168.43 139.63,157.07 139.63,149.24 139.71,149.15 139.93,149.15 140.02,149.24 140.02,154.38 140.11,154.47 140.32,154.47 140.41,154.38 140.41,146.73 147.95,139.19 149.99,139.19 150.75,139.95 151.76,139.95 152.65,139.07 153.67,139.07 154.66,138.07 157.02,138.07 158.06,137.03 159.38,137.03 160.4,136.02 161.24,136.02 162.26,135 J7.219
M2_MDQ54: length 82.8
  TOP w0.118: U22.AF7 v3(116.33,167.2)
  L12_INT_5 w0.087: J7.224 162.54,129.79 160.52,129.79 159.52,128.79 156.91,128.79 155.9,129.79 154.79,129.79 153.8,128.8 152.7,128.8 151.71,129.79 150.75,129.79 149.75,130.8 148.6,130.8 138.43,140.97 133.1,140.97 130.62,143.45 130.62,149.26 130.53,149.35 130.31,149.35 130.23,149.26 130.23,144.84 130.14,144.75 129.92,144.75 129.83,144.84 129.83,152.38 127.76,154.45 127.76,158.5 125.6,160.66 124.13,160.66 121.84,162.94 121.84,163.38 119.55,165.67 118.06,165.67 118.05,165.66 116.03,165.66 115.82,165.86 115.82,166.82 115.91,166.91 116.05,166.91 v3(116.33,167.2)
M2_MDQ55: length 82.7
  TOP w0.118: U22.AG7 v3(115.33,168.2)
  L12_INT_5 w0.087: J7.225 164.65,129.36 163.19,130.81 162.18,130.81 161.58,130.21 160.28,130.21 159.25,129.18 157.12,129.18 156.11,130.2 154.61,130.2 153.62,129.21 152.85,129.21 151.89,130.18 151.89,130.18 151.88,130.19 150.99,130.19 149.99,131.19 148.84,131.19 138.62,141.41 133.54,141.41 131.13,143.83 131.13,152.92 131.04,153.01 130.82,153.01 130.73,152.92 130.73,149.94 130.64,149.85 130.43,149.85 130.34,149.94 130.34,152.49 128.18,154.65 128.18,158.71 125.6,161.29 125.02,161.29 122.05,164.26 121.61,164.26 120.27,165.61 120.27,166.22 119.76,166.73 117.17,166.73 116.87,167.03 116.87,167.26 116.48,167.64 115.88,167.64 115.61,167.91 v3(115.33,168.2)
M2_MDQ56: length 88.8
  TOP w0.118: U22.AG9 v3(114.33,167.2)
  L3_INT_1 w0.087: v3(114.33,167.2) 114.72,167.59 121.48,167.59 121.79,167.27 121.79,166.66 124.95,163.5 127.41,163.5 133.5,157.41 133.5,147.65 133.58,147.56 133.8,147.56 133.89,147.65 133.89,155.41 133.98,155.5 134.19,155.5 134.28,155.41 134.28,144.33 147.59,131.02 147.59,128.34 149,126.93 149.9,126.93 150.76,126.07 151.8,126.07 152.8,127.07 153.69,127.07 154.77,126 J7.108
M2_MDQ57: length 88.8
  TOP w0.118: U22.AG10 v3(113.33,168.2)
  L3_INT_1 w0.087: v3(113.33,168.2) 113.33,168.19 113.74,167.79 121.85,167.79 122.2,167.44 122.2,166.83 125.12,163.91 127.71,163.91 134.68,156.94 134.68,148.39 134.77,148.3 134.98,148.3 135.07,148.39 135.07,154.33 135.16,154.42 135.38,154.42 135.46,154.33 135.46,143.7 147.98,131.19 147.98,129.95 148.86,129.07 149.89,129.07 150.89,128.07 151.8,128.07 152.8,129.07 153.7,129.07 154.42,129.79 155.71,129.79 158.5,127 159.51,127 160.85,125.66 J7.109
M2_MDQ58: length 88.8
  TOP w0.118: U22.AF13 v3(110.33,167.2)
  L3_INT_1 w0.087: J7.114 156.74,117.79 154.42,117.79 153.7,117.07 152.67,117.07 151.82,117.93 150.89,117.93 149.89,116.93 148.15,116.93 142.99,122.09 142.99,124.16 142.9,124.24 142.68,124.24 142.6,124.16 142.6,122.16 142.51,122.07 142.29,122.07 142.2,122.16 142.2,127.65 124.11,145.74 124.11,153.82 121.41,156.52 121.41,158.29 120.12,159.58 120.12,163.09 119.38,163.83 111.25,163.83 110.71,164.37 110.71,166.81 v3(110.33,167.2)
M2_MDQ59: length 88.8
  TOP w0.118: U22.AE13 v3(110.33,166.2)
  L3_INT_1 w0.087: J7.115 160.85,118.53 159.39,117.07 158.09,117.07 156.95,115.93 154.69,115.93 153.83,115.06 152.8,115.06 151.79,116.07 150.9,116.07 149.83,115 148.63,115 141.66,121.97 141.66,127.64 123.7,145.59 123.7,153.67 121.01,156.37 121.01,158.14 119.73,159.42 119.73,161.4 119.46,161.67 109.98,161.67 109.73,161.93 109.73,165.59 v3(110.33,166.2)
M2_MDQ60: length 88.8
  TOP w0.118: U22.AH10 v3(112.33,169.2)
  L3_INT_1 w0.087: J7.227 164.65,127.48 163.2,128.93 162.3,128.93 161.3,129.93 160.4,129.93 159.4,130.93 158.5,130.93 157.36,132.07 154.69,132.07 153.77,132.99 152.73,132.99 151.74,132 150.82,132 149.86,132.97 147.31,132.97 137.04,143.24 137.04,155.58 136.95,155.66 136.73,155.66 136.65,155.58 136.65,151.38 136.56,151.29 136.34,151.29 136.25,151.38 136.25,157.37 127.38,166.24 123.93,166.24 123.01,167.16 123.01,167.78 122,168.79 112.74,168.79 112.61,168.91 v3(112.33,169.2)
M2_MDQ61: length 88.8
  TOP w0.118: v3(112.33,168.2) U22.AH11
  L3_INT_1 w0.087: J7.228 162.75,126.68 161.54,127.89 160.58,127.89 159.39,129.07 158.2,129.07 157.06,130.21 154.39,130.21 153.8,130.81 152.68,130.81 151.79,129.93 150.9,129.93 149.73,131.1 148.62,131.1 136.65,143.08 136.65,150.68 136.56,150.77 136.34,150.77 136.25,150.68 136.25,145.68 136.16,145.59 135.95,145.59 135.86,145.68 135.86,157.13 127.25,165.74 123.87,165.74 122.61,167 122.61,167.61 121.63,168.58 112.71,168.58 v3(112.33,168.2)
M2_MDQ62: length 88.8
  TOP w0.118: U22.AF12 v3(111.33,167.2)
  L3_INT_1 w0.087: v3(111.33,167.2) 111.05,166.91 111.05,166.91 110.92,166.79 110.92,165.94 111.25,165.61 111.51,165.61 111.76,165.35 111.76,165.1 112.14,164.72 119.76,164.72 120.91,163.57 120.91,159.91 122.17,158.64 122.17,156.87 124.98,154.06 124.98,148.83 127.49,146.32 127.49,145.31 143.05,129.74 143.05,128.11 143.14,128.02 143.36,128.02 143.45,128.11 143.45,129.25 143.54,129.34 143.75,129.34 143.84,129.25 143.84,125.02 147.93,120.93 149.9,120.93 150.62,120.21 151.94,120.21 152.8,121.07 153.69,121.07 154.69,120.07 156.14,120.07 157.28,121.21 159.79,121.21 160.35,121.77 161.63,121.77 162.4,121 J7.233
M2_MDQ63: length 88.8
  TOP w0.118: U22.AE12 v3(111.33,165.2)
  L3_INT_1 w0.087: J7.234 160.47,120 159.69,120.78 158.24,120.78 155.7,118.23 154.4,118.23 153.7,118.93 152.8,118.93 151.94,119.79 150.62,119.79 149.96,119.13 148.46,119.13 143.38,124.21 143.38,127.41 143.29,127.5 143.08,127.5 142.99,127.41 142.99,124.93 142.9,124.84 142.68,124.84 142.6,124.93 142.6,129.31 126.59,145.31 126.59,146.46 124.57,148.48 124.57,153.91 121.79,156.69 121.79,158.47 120.52,159.74 120.52,163.28 119.51,164.29 111.81,164.29 111.33,164.77 111.33,165.19 v3(111.33,165.2)
M2_MDQS_N0: length 92.7
  TOP w0.091: U22.AY13 v3(109.33,181.2)
  L12_INT_5 w0.1: J7.6 159.44,232 159.64,231.8 159.64,231.54 159.19,231.09 156.76,231.09 155.85,230.17 154.76,230.17 153.74,229.16 152.85,229.16 151.85,228.17 150.91,228.17 149.97,229.11 147.22,229.11 131.22,213.11 131.22,206.96 127.25,203 127.25,195.81 125.57,194.13 124.24,194.13 124.03,194.34 124.03,196.48 123.66,196.84 122.93,196.84 122.53,196.44 122.53,194.44 122.28,194.18 121.54,194.18 120.14,192.79 111.71,192.79 110.19,191.26 110.19,189.05 110.39,188.85 110.39,186.19 109.99,185.79 109.99,185.77 109.73,185.5 109.73,183.04 109.5,182.81 109.07,182.81 108.72,182.47 108.72,181.77 108.93,181.56 109.25,181.56 109.33,181.47 v3(109.33,181.2)
M2_MDQS_N1: length 94.3
  TOP w0.091: U22.AU13 v3(109.33,178.2)
  L3_INT_1 w0.1: v3(109.33,178.2) 109.33,178.4 109.22,178.51 108.97,178.51 108.72,178.76 108.72,185.71 108.99,185.98 108.99,190.12 111.33,192.46 112.17,192.46 114.88,195.17 120.77,195.17 122.55,196.96 122.55,201.65 124.36,203.45 126.01,203.45 129.76,207.21 129.76,210.99 142.51,223.74 146.31,223.74 146.56,223.49 146.56,222.49 146.31,222.24 143.54,222.24 143.4,222.1 143.4,221.39 143.54,221.25 148.98,221.25 149.1,221.12 149.79,221.12 150.82,222.15 151.89,222.15 152.88,221.16 153.6,221.16 154.51,222.07 155.59,222.07 156.65,223.14 159.69,223.14 160.15,222.68 160.53,222.68 J7.15
M2_MDQS_N2: length 85.3
  TOP w0.091: U22.AU6 v3(116.33,178.2)
  L12_INT_5 w0.1: J7.24 159.48,214 159.69,213.79 159.69,213.47 159.3,213.08 158.18,213.08 157.19,212.09 154.63,212.09 153.69,211.15 152.81,211.15 151.87,212.09 150.82,212.09 149.83,211.1 147.49,211.1 146.33,209.93 146.33,198.21 146.23,198.11 145.44,198.11 145.34,198.21 145.34,204.49 145.09,204.74 144.09,204.74 143.84,204.49 143.84,194.51 134.06,184.73 121.96,184.73 121.05,183.82 119.61,183.82 119.6,183.81 117.08,183.81 116.73,183.46 116.73,178.59 v3(116.33,178.2)
M2_MDQS_N3: length 83.8
  TOP w0.091: U22.AY6 v3(117.33,181.2)
  L3_INT_1 w0.1: v3(117.33,181.2) 117.33,181.4 117.22,181.51 116.97,181.51 116.72,181.75 116.72,185.51 119.02,187.81 128.65,187.81 131.26,190.42 131.26,190.66 133.62,193.01 137.9,193.01 141.63,196.75 141.63,202.23 140.41,203.45 140.41,208.86 141.03,209.47 143.69,209.47 143.79,209.57 143.79,210.35 143.68,210.46 140.65,210.46 140.4,210.71 140.4,211.71 140.65,211.96 144.91,211.96 145.36,211.51 145.36,208.54 148.79,205.1 149.97,205.1 150.92,204.15 151.73,204.15 152.72,205.15 153.82,205.15 154.88,204.09 156.49,204.09 157.45,205.05 159.8,205.05 160.21,204.65 160.5,204.65 J7.33
M2_MDQS_N4: length 82.8
  TOP w0.091: v3(114.33,173.2) U22.AM8
  L12_INT_5 w0.1: v3(114.33,173.2) 114.62,173.2 114.73,173.3 114.73,173.58 114.96,173.81 121.57,173.81 121.79,174.04 122.48,174.04 122.5,174.07 126.14,174.07 127.08,173.13 129.26,173.13 133.85,168.54 142.32,168.54 142.57,168.29 142.57,167.29 142.32,167.04 136.37,167.04 136.27,166.94 136.27,166.2 136.43,166.05 142.36,166.05 142.61,165.8 142.61,164.8 142.36,164.55 138.91,164.55 138.81,164.45 138.81,163.66 138.91,163.56 142.55,163.56 143.28,162.83 143.28,159.23 148.21,154.31 148.21,153.85 148.48,153.58 148.89,153.16 149.86,153.16 150.88,152.15 151.76,152.15 152.78,151.13 153.7,151.13 154.72,150.11 156.26,150.11 157.25,149.12 159.24,149.12 159.71,149.6 159.71,149.78 159.5,150 J7.84
M2_MDQS_N5: length 82.8
  TOP w0.091: U22.AM4 v3(118.33,172.2)
  L3_INT_1 w0.1: J7.93 160.34,140.49 160,140.49 159.32,141.17 157.02,141.17 156.08,142.11 154.72,142.11 153.75,143.08 152.65,143.08 151.69,142.11 151,142.11 150.06,143.05 146.74,143.05 146.12,143.67 146.12,150.98 145.87,151.23 144.87,151.23 144.62,150.98 144.62,142.14 144.52,142.04 143.73,142.04 143.63,142.14 143.63,154.92 127.79,170.76 124.21,170.76 123.49,171.48 122.2,171.48 121.86,171.81 121.59,171.81 121.56,171.79 118.07,171.79 117.93,171.92 117.93,172.09 118.04,172.2 v3(118.33,172.2)
M2_MDQS_N6: length 82.7
  TOP w0.091: U22.AG5 v3(117.33,168.2)
  L12_INT_5 w0.1: J7.102 159.82,132 159.99,131.83 159.99,131.53 159.53,131.06 157.07,131.06 156.03,132.11 154.61,132.11 153.62,131.12 152.89,131.12 151.85,132.16 150.98,132.16 150.04,133.1 148.72,133.1 139.16,142.65 136.09,142.65 135,143.74 135,150.5 132.46,153.04 132.46,159.9 132.21,160.15 131.19,160.15 130.94,159.9 130.94,154.74 130.84,154.64 130.05,154.64 129.95,154.74 129.95,162.41 127.96,164.39 124.13,164.39 122.33,166.19 121.34,166.19 120.98,166.55 120.98,166.9 120.95,166.93 120.95,167.5 120.66,167.79 117.05,167.79 116.95,167.89 116.95,168.12 117.02,168.2 v3(117.33,168.2)
M2_MDQS_N7: length 88.8
  TOP w0.091: U22.AE10 v3(112.33,166.2)
  L3_INT_1 w0.1: v3(112.33,166.2) 112.09,166.2 111.94,166.04 111.94,165.92 112.07,165.79 119.91,165.79 121.93,163.77 121.93,162.92 121.95,162.89 121.95,162.66 123.49,161.12 123.49,158.6 127.3,154.79 127.3,149.3 127.41,149.2 128.19,149.2 128.3,149.3 128.3,153.52 128.55,153.77 129.54,153.77 129.79,153.52 129.79,145.16 145.28,129.67 145.28,125.94 148.09,123.13 150.03,123.13 150.95,122.21 151.75,122.21 152.75,123.21 153.65,123.21 154.81,122.05 155.8,122.05 156.89,123.14 159.23,123.14 159.87,122.5 160.35,122.5 J7.111
M2_MDQS_N8: length 82.8
  TOP w0.091: v3(111.33,173.2) U22.AM11
  L3_INT_1 w0.1: J7.42 159.55,196 159.74,195.81 159.74,195.57 159.29,195.12 158.59,195.12 157.23,193.76 157.23,192.26 156.74,191.77 156.11,191.77 155.76,192.13 154.68,192.13 153.69,191.13 152.8,191.13 151.79,190.12 150.9,190.12 149.98,189.2 148.57,189.2 148.4,189.37 147.32,189.37 146.5,188.55 146.5,185.63 143.26,182.38 143.26,177.8 141.93,176.48 134.34,176.48 134.24,176.58 134.24,177.37 134.34,177.47 139.84,177.47 140.09,177.72 140.09,178.72 139.84,178.97 133.63,178.97 133.41,178.75 130.77,178.75 129.54,179.98 124.68,179.98 122.65,177.95 121.89,177.95 121.87,177.92 121.66,177.92 121.55,177.81 116.1,177.81 115.71,177.43 115.71,177.03 115.47,176.78 115.05,176.78 114.74,176.47 114.74,174.01 114.53,173.8 111.93,173.8 111.69,173.56 111.69,173.33 111.55,173.19 111.55,173.2 v3(111.33,173.2)
M2_MDQS_N9: length 92.7
  TOP w0.091: U22.BA14 108.45,181.7 108.33,181.81 v3(108.33,182.2)
  L12_INT_5 w0.1: v3(108.33,182.2) 108.33,181.91 108.2,181.79 108.03,181.79 107.91,181.9 107.91,183.37 108.14,183.59 108.58,183.59 108.92,183.93 108.92,185.43 109.22,185.72 109.4,185.9 109.4,187.3 109.09,187.61 109.09,190.03 108.59,190.54 108.59,191.16 111.22,193.8 118.36,193.8 124.21,199.64 124.21,202.71 130.15,208.66 130.15,213.51 147.6,230.96 149.81,230.96 150.87,229.9 152.04,229.9 152.98,230.84 153.83,230.84 154.84,231.85 155.93,231.85 157.05,232.97 159.47,232.97 160.3,233.8 161.28,233.8 162.17,232.9 163.34,232.9 163.88,232.37 163.88,232.16 163.72,232 J7.126
M2_MDQS_N10: length 94.2
  TOP w0.091: U22.AV14 108.33,179.19 v3(108.33,179.2)
  L3_INT_1 w0.1: v3(108.33,179.2) 108.33,178.84 108.23,178.74 108.06,178.74 107.92,178.88 107.92,185.55 107.82,185.65 107.82,186.94 108,187.12 108,190.64 110.99,193.62 111.89,193.62 114.43,196.16 120.25,196.16 121.55,197.46 121.55,198.57 121.2,198.91 120.62,198.91 120.41,199.12 120.41,199.68 120.62,199.9 121.19,199.9 121.51,200.22 121.51,202.12 123.99,204.6 125.48,204.6 128.77,207.89 128.77,211.4 142.14,224.76 146.91,224.76 147.8,223.88 148.69,222.99 150.09,222.99 150.93,223.82 151.8,223.82 152.35,223.28 152.39,223.28 152.7,222.97 153.93,222.97 154.8,223.85 156.28,223.85 157.2,224.77 159.5,224.77 160.43,223.85 161.09,223.85 162.06,222.88 163.13,222.88 163.84,223.59 164.06,223.59 J7.135
M2_MDQS_N11: length 85.4
  TOP w0.091: U22.AV7 v3(115.33,179.2)
  L12_INT_5 w0.1: J7.144 163.28,214.53 163.43,214.68 163.68,214.68 163.78,214.58 163.78,213.8 163.14,213.16 162.33,213.16 161.26,214.23 160.53,214.23 159.62,215.14 157.7,215.14 156.76,214.2 154.73,214.2 153.64,213.11 152.85,213.11 151.84,214.12 150.84,214.12 149.83,213.11 147.09,213.11 145.08,211.1 145.08,206.08 144.98,205.98 144.2,205.98 144.09,206.08 144.09,208.04 143.84,208.29 142.85,208.29 142.6,208.04 142.6,195.15 134.13,186.69 125.5,186.69 124.81,186 121.26,186 120.09,184.84 118.47,184.84 118.44,184.81 116.1,184.81 115.74,184.44 115.74,178.92 115.63,178.82 115.42,178.82 115.33,178.9 115.33,179.19 v3(115.33,179.2)
M2_MDQS_N12: length 83.9
  TOP w0.091: v3(116.33,182.2) 116.33,181.86 116.16,181.7 U22.BA7
  L3_INT_1 w0.1: J7.153 164.06,205.59 163.83,205.59 163.07,204.83 162.39,204.83 161.27,205.94 160.43,205.94 159.49,206.88 157.28,206.88 156.34,205.94 154.68,205.94 153.76,206.86 152.69,206.86 151.77,205.94 150.72,205.94 149.73,206.93 148.48,206.93 146.35,209.07 146.35,212.01 145.37,213 140.25,213 139.19,211.94 139.19,202.97 140.64,201.52 140.64,197.16 137.59,194.11 133.3,194.11 130.12,190.93 130.12,190.69 128.24,188.8 118.59,188.8 116.05,186.26 116.05,184.89 116.03,184.86 116.03,184.51 115.92,184.4 115.92,181.83 116.01,181.75 116.21,181.75 116.33,181.86 v3(116.33,182.2)
M2_MDQS_N13: length 82.8
  TOP w0.091: U22.AN7 v3(115.33,174.2)
  L12_INT_5 w0.1: J7.204 163.59,150 163.78,150.19 163.78,150.42 163.39,150.8 162.31,150.8 161.29,151.82 160.45,151.82 159.54,150.9 157.55,150.9 156.59,151.87 154.68,151.87 153.69,152.86 152.78,152.86 152.17,153.47 152.17,155.44 151.74,155.88 150.69,155.88 149.73,156.85 147.09,156.85 144.53,159.41 144.53,163.6 143.64,164.49 143.64,168.68 142.79,169.53 135.19,169.53 134.94,169.78 134.94,170.77 135.19,171.02 141.01,171.02 141.11,171.13 141.11,171.91 141.01,172.02 131.79,172.02 128.24,175.57 126.11,175.57 125.86,175.31 124.33,175.31 124.15,175.49 122.61,175.49 121.92,174.8 121.88,174.8 121.68,174.6 115,174.6 114.89,174.49 114.89,174.3 114.99,174.2 v3(115.33,174.2)
M2_MDQS_N14: length 82.9
  TOP w0.091: U22.AN5 v3(117.33,173.2)
  L3_INT_1 w0.1: J7.213 164.42,141.22 163.9,141.22 163.5,140.82 162.38,140.82 161.34,141.86 160.28,141.86 159.35,142.79 157.18,142.79 156.02,143.95 154.64,143.95 153.76,144.83 152.78,144.83 151.87,143.92 150.73,143.92 149.74,144.91 147.85,144.91 147.14,145.61 147.14,152.93 147.04,153.04 146.25,153.04 146.15,152.93 146.15,152.47 145.9,152.22 144.9,152.22 144.65,152.47 144.65,155.32 137.83,162.14 137.83,168.2 137.73,168.3 136.94,168.3 136.84,168.2 136.84,164.61 136.59,164.36 135.59,164.36 135.34,164.61 135.34,168.17 135.24,168.28 134.45,168.28 134.35,168.17 134.35,167.13 134.1,166.88 133.1,166.88 132.85,167.13 132.85,168.02 132.6,168.28 131.72,168.28 128.25,171.75 124.36,171.75 123.9,172.21 122.32,172.21 121.98,172.55 121.73,172.55 121.76,172.58 117.96,172.58 117.73,172.81 117.73,173.08 117.61,173.2 v3(117.33,173.2)
M2_MDQS_N15: length 82.7
  TOP w0.091: U22.AG4 v3(118.33,168.2)
  L12_INT_5 w0.1: J7.222 163.34,132 163.58,132.23 163.58,132.51 163.29,132.8 162.15,132.8 161.12,133.83 160.4,133.83 159.44,132.87 156.76,132.87 155.75,133.88 154.78,133.88 153.82,132.92 152.73,132.92 151.79,133.86 150.82,133.86 149.8,134.87 148.66,134.87 139.89,143.65 136.64,143.65 136.02,144.27 136.02,157.7 135.92,157.8 135.13,157.8 135.03,157.7 135.03,153.37 134.78,153.12 133.78,153.12 133.53,153.37 133.53,160.24 128.27,165.51 124.07,165.51 121.87,167.71 121.87,168.17 121.89,168.2 121.89,168.5 121.78,168.61 118.75,168.61 v3(118.33,168.2)
M2_MDQS_N16: length 88.8
  TOP w0.091: v3(112.33,167.2) U22.AF11
  L3_INT_1 w0.1: v3(112.33,167.2) 112.61,167.2 112.73,167.08 112.73,166.82 112.97,166.59 120.58,166.59 121.74,165.42 121.74,164.75 122.05,164.44 122.05,164.41 123.53,162.92 123.53,162.65 128.32,157.86 128.32,155.3 128.57,155.05 129.57,155.05 129.82,155.3 129.82,157.89 129.92,157.99 130.71,157.99 130.81,157.89 130.81,145.56 146.35,130.02 146.35,126.32 147.72,124.95 149.8,124.95 150.88,123.88 151.93,123.88 152.87,124.82 153.63,124.82 154.57,123.87 156.29,123.87 157.21,124.79 159.35,124.79 160.27,123.87 161.29,123.87 162.35,122.81 163.52,122.81 163.98,123.27 164.38,123.27 J7.231
M2_MDQS_N17: length 82.8
  TOP w0.091: v3(112.33,174.2) 112.33,174.19 U22.AN10
  L3_INT_1 w0.1: J7.162 163.61,196 163.79,196.18 163.79,196.48 163.39,196.88 162.22,196.88 161.26,197.84 160.38,197.84 159.41,196.88 158.1,196.88 156.44,195.22 156.44,194.46 155.83,193.85 154.74,193.85 153.8,192.91 152.91,192.91 151.89,191.9 151,191.9 149.99,190.88 145.34,190.88 144.66,190.2 144.66,185.19 144.41,184.94 143.41,184.94 143.16,185.19 143.16,188.95 143.06,189.05 142.27,189.05 142.17,188.95 142.17,179.77 141.92,179.52 140.92,179.52 140.67,179.77 140.67,180.87 140.49,181.05 124.74,181.05 122.48,178.79 121.03,178.79 121.01,178.82 120.83,178.82 120.61,178.6 116.17,178.6 115.94,178.37 115.94,177.97 115.56,177.59 114.11,177.59 113.94,177.42 113.94,174.89 113.65,174.6 112.05,174.6 111.94,174.49 111.94,174.32 112.06,174.19 112.33,174.19 v3(112.33,174.2)
M2_MDQS_P0: length 92.7
  TOP w0.091: U22.BA13 109.52,181.7 109.33,181.88 v3(109.33,182.2)
  L12_INT_5 w0.1: v3(109.33,182.2) 109.33,181.87 109.22,181.76 109.02,181.76 108.92,181.86 108.92,182.38 109.15,182.61 109.59,182.61 109.93,182.96 109.93,185.42 110.2,185.68 110.25,185.68 110.64,186.08 110.64,188.95 110.44,189.15 110.44,191.16 111.81,192.53 120.25,192.53 121.64,193.93 122.38,193.93 122.78,194.33 122.78,196.34 123.03,196.59 123.56,196.59 123.77,196.37 123.77,194.23 124.13,193.88 125.68,193.88 127.51,195.71 127.51,202.9 131.47,206.86 131.47,213 147.32,228.85 149.86,228.85 150.8,227.91 151.96,227.91 152.95,228.9 153.85,228.9 154.86,229.92 155.96,229.92 156.87,230.84 159.3,230.84 159.98,231.52 160.33,231.52 J7.7
M2_MDQS_P1: length 94.2
  TOP w0.091: v3(109.33,179.2) 109.33,178.84 109.47,178.7 U22.AV13
  L3_INT_1 w0.1: v3(109.33,179.2) 109.33,178.8 109.25,178.72 109.05,178.72 108.92,178.84 108.92,185.63 109.25,185.95 109.25,190.01 111.43,192.2 112.27,192.2 114.99,194.92 120.88,194.92 122.81,196.85 122.81,201.55 124.46,203.2 126.11,203.2 130.02,207.11 130.02,210.88 142.61,223.48 146.2,223.48 146.3,223.38 146.3,222.59 146.2,222.49 143.44,222.49 143.15,222.2 143.15,221.28 143.44,220.99 148.87,220.99 149,220.87 149.9,220.87 150.93,221.89 151.79,221.89 152.78,220.9 153.7,220.9 154.62,221.82 155.69,221.82 156.76,222.88 159.58,222.88 159.97,222.5 159.97,222.27 159.7,222 J7.16
M2_MDQS_P2: length 85.3
  TOP w0.091: U22.AV6 v3(117.33,178.2)
  L12_INT_5 w0.1: J7.25 160.36,213.49 160.07,213.49 159.41,212.83 158.29,212.83 157.3,211.84 154.74,211.84 153.8,210.9 152.7,210.9 151.76,211.84 150.93,211.84 149.94,210.85 147.6,210.85 146.58,209.83 146.58,198.1 146.33,197.85 145.33,197.85 145.08,198.1 145.08,204.38 144.98,204.48 144.2,204.48 144.09,204.38 144.09,194.41 134.17,184.48 122.07,184.48 121.15,183.57 119.61,183.57 119.57,183.61 117.16,183.61 116.93,183.38 116.93,178.59 v3(117.33,178.2)
M2_MDQS_P3: length 83.9
  TOP w0.091: v3(117.33,182.2) 117.33,181.86 117.16,181.7 U22.BA6
  L3_INT_1 w0.1: v3(117.33,182.2) 117.33,181.82 117.22,181.71 117.05,181.71 116.92,181.84 116.92,185.35 119.13,187.55 128.75,187.55 131.52,190.32 131.52,190.56 133.72,192.76 138.01,192.76 141.89,196.64 141.89,202.33 140.66,203.56 140.66,208.75 141.13,209.22 143.8,209.22 144.04,209.47 144.04,210.46 143.78,210.72 140.76,210.72 140.66,210.82 140.66,211.61 140.76,211.71 144.8,211.71 145.11,211.4 145.11,208.43 148.69,204.85 149.86,204.85 150.81,203.9 151.83,203.9 152.83,204.89 153.71,204.89 154.77,203.84 156.59,203.84 157.56,204.8 159.69,204.8 160.02,204.47 160.02,204.24 159.78,204 J7.34
M2_MDQS_P4: length 82.8
  TOP w0.091: U22.AM7 v3(115.33,173.2)
  L12_INT_5 w0.1: v3(115.33,173.2) 115.07,173.2 114.93,173.33 114.93,173.5 115.05,173.61 121.65,173.61 121.88,173.84 122.48,173.84 122.5,173.81 126.03,173.81 126.97,172.87 129.15,172.87 133.75,168.28 142.21,168.28 142.32,168.18 142.32,167.39 142.21,167.29 136.27,167.29 136.02,167.04 136.02,166.1 136.32,165.79 142.26,165.79 142.36,165.69 142.36,164.9 142.26,164.8 138.81,164.8 138.56,164.55 138.56,163.55 138.81,163.3 142.45,163.3 143.03,162.73 143.03,159.13 147.95,154.2 147.95,153.74 148.3,153.4 148.79,152.91 149.75,152.91 150.77,151.89 151.66,151.89 152.68,150.88 153.6,150.88 154.61,149.86 156.16,149.86 157.15,148.87 159.34,148.87 159.94,149.47 160.38,149.47 J7.85
M2_MDQS_P5: length 82.8
  TOP w0.091: U22.AM5 v3(117.33,172.2)
  L3_INT_1 w0.1: J7.94 159.56,140 159.71,140.15 159.71,140.43 159.21,140.92 156.92,140.92 155.98,141.86 154.61,141.86 153.65,142.82 152.76,142.82 151.79,141.86 150.9,141.86 149.96,142.8 146.63,142.8 145.87,143.57 145.87,150.88 145.77,150.98 144.98,150.98 144.88,150.88 144.88,142.03 144.63,141.78 143.63,141.78 143.38,142.03 143.38,154.81 127.69,170.5 124.1,170.5 123.38,171.22 122.1,171.22 121.76,171.56 121.58,171.56 121.56,171.59 117.98,171.59 117.73,171.84 117.73,172.09 117.62,172.2 v3(117.33,172.2)
M2_MDQS_P6: length 82.7
  TOP w0.091: U22.AG6 v3(116.33,168.2)
  L12_INT_5 w0.1: J7.103 160.48,131.37 160.2,131.37 159.64,130.81 156.97,130.81 155.93,131.85 154.71,131.85 153.72,130.86 152.79,130.86 151.74,131.9 150.88,131.9 149.94,132.84 148.61,132.84 139.05,142.4 135.98,142.4 134.75,143.64 134.75,150.39 132.21,152.93 132.21,159.79 132.11,159.89 131.29,159.89 131.19,159.79 131.19,154.63 130.94,154.38 129.94,154.38 129.69,154.63 129.69,162.3 127.86,164.14 124.02,164.14 122.22,165.94 121.23,165.94 120.73,166.44 120.73,166.9 120.75,166.92 120.75,167.42 120.58,167.59 116.97,167.59 116.75,167.81 116.75,168.02 116.57,168.2 v3(116.33,168.2)
M2_MDQS_P7: length 88.8
  TOP w0.091: U22.AE11 v3(111.33,166.2)
  L3_INT_1 w0.1: J7.112 159.54,122 159.64,122.1 159.64,122.37 159.13,122.89 156.99,122.89 155.9,121.79 154.7,121.79 153.54,122.95 152.85,122.95 151.85,121.95 150.84,121.95 149.92,122.87 147.99,122.87 145.03,125.83 145.03,129.57 129.54,145.06 129.54,153.42 129.44,153.52 128.65,153.52 128.55,153.42 128.55,149.2 128.3,148.95 127.3,148.95 127.05,149.2 127.05,154.68 123.24,158.49 123.24,161.01 121.7,162.55 121.7,162.89 121.72,162.92 121.72,163.69 119.83,165.59 111.99,165.59 111.73,165.84 111.73,166.09 111.63,166.2 v3(111.33,166.2)
M2_MDQS_P8: length 82.8
  TOP w0.091: v3(112.33,173.2) U22.AM10
  L3_INT_1 w0.1: J7.43 160.4,195.45 159.98,195.45 159.39,194.87 158.7,194.87 157.48,193.65 157.48,192.15 156.84,191.52 156.01,191.52 155.65,191.87 154.78,191.87 153.79,190.88 152.91,190.88 151.89,189.87 151,189.87 150.09,188.95 148.46,188.95 148.3,189.12 147.43,189.12 146.75,188.44 146.75,185.52 143.51,182.28 143.51,177.69 142.04,176.23 134.23,176.23 133.98,176.48 133.98,177.47 134.23,177.72 139.74,177.72 139.84,177.83 139.84,178.61 139.74,178.71 133.73,178.71 133.51,178.5 130.67,178.5 129.43,179.73 124.79,179.73 122.76,177.7 121.89,177.7 121.87,177.72 121.75,177.72 121.64,177.61 116.19,177.61 115.92,177.34 115.92,176.95 115.55,176.58 115.13,176.58 114.94,176.39 114.94,173.92 114.62,173.6 112.01,173.6 111.89,173.48 111.89,173.33 112.02,173.19 112.02,173.2 v3(112.33,173.2)
M2_MDQS_P9: length 92.7
  TOP w0.091: v3(108.33,181.2) 108.33,181.19 U22.AY14
  L12_INT_5 w0.1: v3(108.33,181.2) 108.33,181.46 108.2,181.58 107.94,181.58 107.71,181.82 107.71,183.45 108.05,183.79 108.5,183.79 108.72,184.01 108.72,185.51 108.89,185.68 108.89,185.75 108.96,185.83 109.14,186.01 109.14,187.2 108.84,187.5 108.84,189.92 108.33,190.43 108.33,191.27 111.12,194.06 118.26,194.06 123.95,199.75 123.95,202.82 129.9,208.76 129.9,213.61 147.5,231.22 149.91,231.22 150.98,230.15 151.94,230.15 152.88,231.09 153.72,231.09 154.74,232.11 155.83,232.11 156.94,233.22 159.37,233.22 160.14,234 161.43,234 162.28,233.16 163.45,233.16 164.02,232.59 164.24,232.59 J7.125
M2_MDQS_P10: length 94.3
  TOP w0.091: U22.AU14 v3(108.33,178.2)
  L3_INT_1 w0.1: J7.134 163.22,224 163.4,223.82 163.4,223.51 163.03,223.14 162.17,223.14 161.2,224.1 160.53,224.1 159.61,225.03 157.1,225.03 156.18,224.1 154.77,224.1 153.84,223.17 152.78,223.17 152.59,223.36 152.59,223.39 151.9,224.08 150.89,224.08 150,223.19 148.85,223.19 147.02,225.02 142.03,225.02 128.52,211.51 128.52,208 125.37,204.85 123.89,204.85 121.26,202.22 121.26,200.32 121.09,200.15 120.52,200.15 120.16,199.79 120.16,199.01 120.52,198.65 121.1,198.65 121.29,198.46 121.29,197.57 120.14,196.42 114.32,196.42 111.78,193.88 110.88,193.88 107.75,190.74 107.75,187.23 107.62,187.1 107.62,185.56 107.72,185.46 107.72,178.79 107.98,178.54 108.23,178.54 108.33,178.44 v3(108.33,178.2)
M2_MDQS_P11: length 85.4
  TOP w0.091: U22.AU7 v3(115.33,178.2)
  L12_INT_5 w0.1: J7.143 164.25,215 164.03,214.78 164.03,213.69 163.25,212.9 162.22,212.9 161.15,213.97 160.42,213.97 159.51,214.88 157.81,214.88 156.87,213.94 154.83,213.94 153.74,212.85 152.75,212.85 151.73,213.87 150.95,213.87 149.93,212.85 147.19,212.85 145.34,211 145.34,205.98 145.09,205.73 144.09,205.73 143.84,205.98 143.84,207.94 143.74,208.04 142.95,208.04 142.85,207.94 142.85,195.05 134.24,186.44 125.6,186.44 124.92,185.75 121.36,185.75 120.19,184.58 118.47,184.58 118.44,184.61 116.19,184.61 115.94,184.36 115.94,178.83 115.72,178.61 115.44,178.61 115.33,178.5 v3(115.33,178.2)
M2_MDQS_P12: length 83.9
  TOP w0.091: U22.AY7 v3(116.33,181.2)
  L3_INT_1 w0.1: J7.152 163.27,206 163.45,205.82 163.45,205.57 162.96,205.08 162.49,205.08 161.37,206.2 160.53,206.2 159.59,207.14 157.18,207.14 156.24,206.2 154.79,206.2 153.87,207.12 152.58,207.12 151.66,206.2 150.82,206.2 149.83,207.19 148.59,207.19 146.6,209.17 146.6,212.12 145.47,213.25 140.15,213.25 138.94,212.04 138.94,202.87 140.39,201.41 140.39,197.26 137.49,194.36 133.19,194.36 129.87,191.04 129.87,190.79 128.13,189.05 118.49,189.05 115.8,186.36 115.8,184.92 115.82,184.95 115.82,184.59 115.72,184.49 115.72,181.75 115.92,181.54 116.23,181.54 116.33,181.45 v3(116.33,181.2)
M2_MDQS_P13: length 82.8
  TOP w0.091: v3(114.33,174.2) U22.AN8
  L12_INT_5 w0.1: J7.203 164.27,150.62 163.93,150.62 163.5,151.05 162.42,151.05 161.4,152.07 160.35,152.07 159.43,151.16 157.66,151.16 156.69,152.12 154.79,152.12 153.8,153.11 152.89,153.11 152.43,153.58 152.43,155.55 151.84,156.13 150.8,156.13 149.83,157.1 147.19,157.1 144.78,159.51 144.78,163.7 143.89,164.59 143.89,168.78 142.89,169.78 135.29,169.78 135.19,169.88 135.19,170.67 135.29,170.77 141.11,170.77 141.36,171.02 141.36,172.02 141.11,172.27 131.9,172.27 128.35,175.82 126.01,175.82 125.75,175.57 124.43,175.57 124.26,175.74 122.5,175.74 121.74,174.98 121.74,174.94 121.6,174.8 114.92,174.8 114.69,174.57 114.69,174.32 114.57,174.2 v3(114.33,174.2)
M2_MDQS_P14: length 82.8
  TOP w0.091: U22.AN4 v3(118.33,173.2)
  L3_INT_1 w0.1: v3(118.33,173.2) 118.05,173.2 117.93,173.08 117.93,172.9 118.05,172.78 121.68,172.78 121.7,172.81 122.09,172.81 122.43,172.47 124,172.47 124.47,172 128.35,172 131.83,168.53 132.71,168.53 133.11,168.13 133.11,167.23 133.21,167.13 134,167.13 134.1,167.23 134.1,168.28 134.35,168.53 135.35,168.53 135.6,168.28 135.6,164.71 135.7,164.61 136.49,164.61 136.59,164.71 136.59,168.3 136.84,168.55 137.84,168.55 138.09,168.3 138.09,162.25 144.91,155.43 144.91,152.58 145.01,152.48 145.85,152.48 145.9,152.53 145.9,153.04 146.15,153.29 147.15,153.29 147.4,153.04 147.4,145.72 147.95,145.16 149.84,145.16 150.83,144.17 151.76,144.17 152.68,145.09 153.87,145.09 154.75,144.21 156.12,144.21 157.28,143.05 159.45,143.05 160.39,142.11 161.44,142.11 162.48,141.07 163.39,141.07 163.7,141.38 163.7,141.75 163.45,142 J7.212
M2_MDQS_P15: length 82.7
  TOP w0.091: U22.AH4 v3(118.33,169.2)
  L12_INT_5 w0.1: J7.221 164.26,132.61 163.83,132.61 163.39,133.05 162.26,133.05 161.22,134.09 160.3,134.09 159.33,133.12 156.87,133.12 155.85,134.14 154.68,134.14 153.71,133.17 152.83,133.17 151.89,134.11 150.93,134.11 149.91,135.13 148.77,135.13 139.99,143.9 136.74,143.9 136.28,144.37 136.28,157.81 136.03,158.06 135.03,158.06 134.78,157.81 134.78,153.47 134.68,153.37 133.89,153.37 133.79,153.47 133.79,160.34 128.37,165.76 124.18,165.76 122.12,167.82 122.12,168.17 122.1,168.2 122.1,168.58 121.86,168.82 118.71,168.82 v3(118.33,169.2)
M2_MDQS_P16: length 88.8
  TOP w0.091: v3(113.33,167.2) U22.AF10
  L3_INT_1 w0.1: v3(113.33,167.2) 113.04,167.2 112.93,167.08 112.93,166.91 113.05,166.79 120.66,166.79 121.95,165.51 121.95,164.83 122.17,164.6 122.21,164.6 123.78,163.03 123.78,162.75 128.57,157.96 128.57,155.41 128.68,155.31 129.46,155.31 129.57,155.41 129.57,157.99 129.82,158.24 130.81,158.24 131.06,157.99 131.06,145.67 146.6,130.13 146.6,126.42 147.82,125.21 149.91,125.21 150.99,124.13 151.83,124.13 152.77,125.07 153.73,125.07 154.68,124.13 156.18,124.13 157.1,125.05 159.45,125.05 160.38,124.13 161.39,124.13 162.46,123.06 163.42,123.06 163.72,123.37 163.72,123.78 163.5,124 J7.230
M2_MDQS_P17: length 82.8
  TOP w0.091: v3(111.33,174.2) 111.33,174.19 U22.AN11
  L3_INT_1 w0.1: v3(111.33,174.2) 111.33,174.19 111.61,174.19 111.73,174.32 111.73,174.57 111.96,174.8 113.57,174.8 113.74,174.97 113.74,177.5 114.02,177.79 115.47,177.79 115.73,178.05 115.73,178.45 116.08,178.8 120.53,178.8 120.74,179.02 121.01,179.02 121.03,179.04 122.37,179.04 124.63,181.31 140.6,181.31 140.93,180.97 140.93,179.88 141.03,179.77 141.81,179.77 141.92,179.88 141.92,189.06 142.17,189.31 143.16,189.31 143.41,189.06 143.41,185.29 143.52,185.19 144.3,185.19 144.41,185.29 144.41,190.3 145.24,191.13 149.88,191.13 150.9,192.15 151.79,192.15 152.8,193.17 153.69,193.17 154.63,194.11 155.72,194.11 156.18,194.57 156.18,195.32 157.99,197.13 159.31,197.13 160.27,198.09 161.37,198.09 162.33,197.13 163.49,197.13 164,196.62 164.27,196.62 J7.161
M2_MECC0: length 82.8
  TOP w0.118: v3(112.33,175.2) 112.33,175.19 U22.AP11
  L3_INT_1 w0.087: J7.39 159.93,199 159.75,198.82 158.18,198.82 155.57,196.21 154.68,196.21 153.68,195.21 152.67,195.21 151.64,194.18 150.72,194.18 149.71,193.17 144.06,193.17 140.44,189.55 140.44,184.71 140.03,184.3 131.41,184.3 131.32,184.21 131.32,184 131.41,183.91 140.22,183.91 140.31,183.82 140.31,183.6 140.22,183.51 130.58,183.51 130.02,182.96 126.29,182.96 125.88,182.55 123.62,182.55 122.99,181.91 122.99,181.25 121.83,180.09 119.89,180.09 119.58,179.79 113.06,179.79 112.74,179.46 112.74,175.6 v3(112.33,175.2)
M2_MECC1: length 82.8
  TOP w0.118: v3(113.33,175.2) 113.33,175.19 U22.AP10
  L3_INT_1 w0.087: v3(113.33,175.2) 112.94,175.59 112.94,179.38 113.15,179.59 121.7,179.59 124.21,182.09 126,182.09 126.2,182.29 140.72,182.29 140.81,182.38 140.81,182.59 140.72,182.68 130.77,182.68 130.68,182.77 130.68,182.99 130.77,183.08 140.56,183.08 140.92,183.44 140.92,189.48 144.22,192.78 149.9,192.78 150.89,193.77 151.86,193.77 152.88,194.79 153.82,194.79 154.82,195.79 155.81,195.79 158.02,198 J7.40
M2_MECC2: length 82.8
  TOP w0.118: v3(111.33,171.2) U22.AK11
  L3_INT_1 w0.087: v3(111.33,171.2) 111.84,170.69 116.59,170.69 116.94,171.04 116.94,175.38 117.15,175.59 125.55,175.59 126.57,176.61 128.45,176.61 131.93,173.12 138.14,173.12 138.23,173.03 138.23,172.82 138.14,172.73 132.94,172.73 132.85,172.63 132.85,172.42 132.94,172.33 144.9,172.33 146.81,174.24 146.81,176.81 149.07,179.07 149.99,179.07 151,180.09 151.76,180.09 152.27,180.59 152.27,182.5 152.78,183.01 153.92,183.01 154.94,184.02 155.7,184.02 156.59,184.91 156.59,185.88 160.56,189.85 161.22,189.85 161.82,190.45 161.82,192.03 J7.45
M2_MECC3: length 82.8
  TOP w0.118: v3(112.33,171.2) U22.AK10
  L3_INT_1 w0.087: J7.46 158.95,191.46 155.45,187.96 154.81,187.96 153.8,186.94 152.78,186.94 151.89,186.06 150.88,186.06 149.86,185.04 148.59,185.04 148.16,184.61 148.16,182.32 146.81,180.97 146.81,178.14 146.72,178.05 146.51,178.05 146.42,178.14 146.42,179.87 146.33,179.96 146.11,179.96 146.02,179.87 146.02,177.39 145.41,176.78 145.41,174.6 144.87,174.06 132.17,174.06 132.09,174.15 132.09,174.36 132.17,174.45 138.01,174.45 138.1,174.54 138.1,174.76 138.01,174.85 131.6,174.85 128.47,177.98 124.51,177.98 122.93,176.4 121.67,176.4 121.48,176.59 116.17,176.59 115.94,176.35 115.94,172.92 115.6,172.59 112.77,172.59 112.33,172.15 v3(112.33,171.2)
M2_MECC4: length 82.8
  TOP w0.118: v3(111.33,176.2) 111.33,176.19 U22.AR11
  L3_INT_1 w0.087: J7.158 162.75,200 162.54,200.21 160.21,200.21 159.64,200.79 158.12,200.79 155.54,198.21 154.47,198.21 153.67,199.01 152.65,199.01 151.86,198.21 151.1,198.21 149.91,197.03 149.12,197.03 148.39,196.3 148.39,194.85 147.5,193.96 143.73,193.96 139.61,189.84 139.61,188.48 137.82,186.69 132.51,186.69 132.42,186.6 132.42,186.39 132.51,186.3 139.5,186.3 139.59,186.21 139.59,185.99 139.5,185.9 131.83,185.9 129.85,183.93 121.82,183.93 120.78,182.88 120.78,181.1 120.48,180.8 112.08,180.8 111.74,180.46 111.74,176.6 v3(111.33,176.2)
M2_MECC5: length 82.8
  TOP w0.118: v3(112.33,176.2) 112.33,176.19 U22.AR10
  L3_INT_1 w0.087: v3(112.33,176.2) 111.94,176.59 111.94,180.38 112.16,180.6 121.42,180.6 121.79,180.97 121.79,183.13 122.19,183.53 130.02,183.53 131.19,184.71 139.76,184.71 139.85,184.8 139.85,185.01 139.76,185.1 133.49,185.1 133.4,185.19 133.4,185.4 133.5,185.5 139.65,185.5 140,185.85 140,189.68 143.89,193.57 147.69,193.57 149.15,195.02 149.96,195.02 151.08,196.14 151.87,196.14 152.71,196.98 153.79,196.98 154.6,197.79 156.05,197.79 157.48,199.21 159.59,199.21 160.19,199.82 161.37,199.82 162.19,199 J7.159
M2_MECC6: length 82.8
  TOP w0.118: U22.AL11 v3(111.33,172.2)
  L3_INT_1 w0.087: J7.164 162.54,194.21 160.28,194.21 159.1,193.04 158.62,193.04 158.12,192.53 158.12,191.52 156.46,189.87 154.45,189.87 153.64,189.05 152.83,189.05 151.87,188.09 151,188.09 149.99,187.07 148.72,187.07 147.74,186.09 147.74,182.54 147.07,181.86 145.41,181.86 144.91,181.36 144.91,174.74 144.62,174.45 138.58,174.45 138.49,174.54 138.49,174.76 138.58,174.85 143.12,174.85 143.2,174.94 143.2,175.15 143.12,175.24 131.95,175.24 128.8,178.38 124.31,178.38 122.73,176.8 116.1,176.8 115.74,176.44 115.74,173.01 115.52,172.79 111.92,172.79 v3(111.33,172.2)
M2_MECC7: length 82.8
  TOP w0.118: U22.AL10 v3(113.33,172.2)
  L3_INT_1 w0.087: J7.165 162.22,193 161.43,193.79 160.51,193.79 159.89,193.17 159.89,189.74 156.21,186.06 154.69,186.06 153.67,185.04 152.91,185.04 151.76,183.9 150.88,183.9 149.99,183.01 149.22,183.01 148.59,182.37 148.59,179.2 145.92,176.53 145.92,174.37 144.3,172.75 138.98,172.75 138.89,172.84 138.89,173.05 138.98,173.15 143.76,173.15 143.85,173.23 143.85,173.45 143.76,173.54 132.07,173.54 128.57,177.04 125.55,177.04 125.25,177.34 124.49,177.34 123.13,175.99 121.76,175.99 121.56,175.79 117.06,175.79 116.74,175.46 116.74,172.03 116.41,171.7 113.82,171.7 v3(113.33,172.2)
M2_MODT0: length 95
  TOP w0.118: U22.AL2 v3(121.33,171.2)
  L14_INT_6 w0.087: v3(121.33,171.2) 122.16,172.03 144.22,172.03 144.31,171.94 144.31,171.72 144.22,171.63 123.44,171.63 123.36,171.55 123.36,171.33 123.44,171.24 148.55,171.24 148.87,170.92 150.04,170.92 150.75,170.21 151.99,170.21 152.62,170.83 153.58,170.83 154.28,170.13 154.28,168.71 154.79,168.2 155.65,168.2 157.68,166.17 157.68,164.01 158.75,162.94 159.51,162.94 160.53,161.93 161.29,161.93 162.31,160.91 163.51,160.91 164.65,159.77 J7.195
M2_MODT1: length 95
  TOP w0.118: U22.AG2 v3(121.33,167.2)
  L14_INT_6 w0.087: v3(121.33,167.2) 121.95,167.81 121.95,168.95 122.03,169.04 122.25,169.04 122.34,168.95 122.34,167.22 122.43,167.13 122.64,167.13 122.73,167.22 122.73,168.97 122.83,169.07 123.04,169.07 123.13,168.98 123.13,167.22 123.22,167.13 123.43,167.13 123.52,167.22 123.52,169.55 123.62,169.64 123.83,169.64 123.91,169.56 123.91,167.17 124.21,166.88 125.81,166.88 126.15,167.22 126.15,168.95 126.87,169.67 143.04,169.67 143.13,169.58 143.13,169.36 143.04,169.27 127.13,169.27 127.04,169.18 127.04,168.97 127.13,168.88 144.56,168.88 145.58,167.85 148.2,167.85 149.05,167.01 149.86,167.01 150.7,167.84 151.94,167.84 152.58,167.21 153.82,167.21 156.64,164.39 156.64,161.72 158.11,160.25 158.11,159.26 158.37,159 159.26,159 160.31,157.96 160.31,157.54 J7.77
M2_MRAS_B: length 95
  TOP w0.118: U22.AP1 v3(121.33,175.2)
  BOTTOM w0.118: v3(121.33,175.2) 121.48,175.2 123.21,173.47 123.21,172.26 123.82,171.64 127.51,171.64 128.59,170.56 128.59,160.72 129.35,159.96 137.67,159.96 137.79,159.83 137.79,159.58 137.67,159.45 129.03,159.45 128.9,159.32 128.9,159.07 129.03,158.94 145.86,158.94 146,158.8 146,158.56 145.87,158.43 137.96,158.43 137.83,158.31 137.83,158.05 137.96,157.92 146.09,157.92 148.95,155.07 149.86,155.07 150.77,155.98 151.59,155.98 152.63,157.02 153.45,157.02 154.64,158.21 154.65,158.21 154.66,158.22 156.11,158.22 156.82,158.93 156.82,159.77 158.27,161.22 159.64,161.22 160.43,162 J7.192
M2_MWE_B: length 95
  TOP w0.118: U22.AM1 v3(122.33,173.2)
  BOTTOM w0.118: v3(122.33,173.2) 122.33,173.19 122.33,172.18 123.38,171.13 127.19,171.13 127.32,171.01 127.32,170.75 127.19,170.62 123.7,170.62 123.57,170.5 123.57,170.24 123.7,170.12 127.57,170.12 127.7,169.99 127.7,169.74 127.57,169.61 126.36,169.61 126.24,169.48 126.24,169.23 126.36,169.1 127.63,169.1 127.76,168.97 127.76,168.72 127.63,168.59 126.11,168.59 125.98,168.47 125.98,168.21 126.11,168.08 127.63,168.08 127.76,167.96 127.76,167.7 127.63,167.58 126.17,167.58 126.05,167.45 126.05,167.2 126.17,167.07 127.63,167.07 127.76,166.94 127.76,166.69 127.63,166.56 126.09,166.56 125.96,166.43 125.96,166.21 126.11,166.05 127.06,166.05 128.08,165.04 128.08,158.94 128.59,158.43 136.84,158.43 136.96,158.31 136.96,158.07 136.81,157.92 129.49,157.92 129.36,157.8 129.36,157.53 129.48,157.42 145.28,157.42 147.6,155.09 147.6,153.92 148.46,153.06 149.86,153.06 150.77,153.97 151.46,153.97 152.7,155.22 153.57,155.22 154.2,155.85 154.2,157.18 154.81,157.78 156.36,157.78 158.05,159.47 158.05,160.4 158.43,160.78 160.63,160.78 J7.73
M2_PARERR_B: length 77.1
  TOP w0.118: v2(111.84,187.8) 111.85,187.81 111.85,187.99 111.63,188.22 111.18,188.22 R197.2 111.05,185.48 U22.BD11
  L14_INT_6 w0.087: v2(111.84,187.8) 112.13,187.5 121.86,187.5 123.42,189.06 123.66,189.06 125.9,191.31 147.76,191.31 148.08,190.98 149.83,190.98 150.8,191.95 151.76,191.95 152.55,191.16 153.95,191.16 154.61,191.82 157.45,191.82 158.27,191.01 159.26,191.01 160.07,191.82 161.44,191.82 162.26,191.01 163.09,191.01 166.04,188.06 167,188.06 167.39,187.68 167.39,184.05 165.33,181.99 164.21,181.99 163.25,181.03 160.88,181.03 J7.53
M2_PAROUT: length 95.1
  TOP w0.118: U22.AV1 v3(121.33,178.2)
  BOTTOM w0.118: v3(121.33,178.2) 122.9,179.77 125.48,179.77 125.79,179.45 127.79,179.45 131.13,176.12 131.13,169.99 131.51,169.61 140.06,169.61 140.18,169.48 140.18,169.23 140.06,169.1 131.25,169.1 131.13,168.97 131.13,168.72 131.25,168.59 144.51,168.59 144.64,168.47 144.64,168.21 144.51,168.08 131.65,168.08 131.52,167.96 131.52,167.7 131.65,167.58 144.97,167.58 145.41,168.02 148.08,168.02 148.89,167.21 150.07,167.21 150.88,168.02 151.76,168.02 152.78,169.04 153.67,169.04 154.81,167.89 157.05,167.89 J7.68
M2_VREF_ISO: length 3.5
  TOP w0.457: U22.AH13 v3(110.33,169.2)
  BOTTOM w0.305: R703.1 110.82,167.57 C679.1 110.85,167.74 110.85,168.56 C656.1
  BOTTOM w0.457: C656.1 v3(110.33,169.2)
M3_MA0: length 82.3
  TOP w0.118: U22.AL44 78.69,171.83 77.68,171.83 77.36,171.51 72.58,171.51 71.25,170.18 67.96,170.18 67.83,170.31 67.83,170.56 67.96,170.69 70.99,170.69 71.12,170.81 71.12,171.07 70.99,171.2 60.35,171.2 60.22,171.32 60.22,171.58 60.35,171.7 71.5,171.7 71.63,171.83 71.63,172.09 71.5,172.21 62.61,172.21 62.48,172.34 62.48,172.59 62.61,172.72 70.68,172.72 70.8,172.85 70.8,173.1 70.68,173.23 62.35,173.23 61.33,172.21 55.12,172.21 50.93,168.02 50.29,168.02 49.2,166.93 49.2,166.55 J5.188
M3_MA1: length 82.3
  TOP w0.118: J5.181 50.78,173.23 55.88,173.23 58.23,175.58 58.23,178.88 58.86,179.51 64.64,179.51 64.77,179.39 64.77,179.13 64.64,179.01 59.23,179.01 59.11,178.88 59.11,178.63 59.23,178.5 69.77,178.5 69.9,178.37 69.9,178.11 69.78,177.99 58.93,177.99 58.8,177.86 58.8,177.61 58.93,177.48 66.5,177.48 66.62,177.36 66.62,177.1 66.5,176.97 61.71,176.97 61.58,176.85 61.58,176.59 61.71,176.47 69.71,176.47 70.55,177.3 70.55,178.73 71.77,179.96 78.18,179.96 78.43,180.21 79.31,180.21 U22.AW43
M3_MA2: length 82.3
  TOP w0.118: U22.AW44 78.83,179.69 78.59,179.45 71.98,179.45 71.06,178.52 71.06,175.2 69.79,173.93 58.71,173.93 58.58,174.05 58.58,174.31 58.71,174.43 69.39,174.43 69.52,174.56 69.52,174.82 69.39,174.94 59.69,174.94 59.56,175.07 59.56,175.32 59.69,175.45 69.79,175.45 69.91,175.58 69.91,175.83 69.79,175.96 59.37,175.96 56.13,172.72 52.7,172.72 52.2,172.21 49.78,172.21 49,173 J5.61
M3_MA3: length 82.3
  TOP w0.102: U22.AY43 79.44,181.09 77.82,181.09
  TOP w0.118: 77.82,181.09 77.12,181.79 72.88,181.79 70.1,179.01 65.4,179.01 65.28,179.13 65.28,179.39 65.4,179.51 69.82,179.51 69.95,179.64 69.95,179.9 69.82,180.02 58.93,180.02 58.8,180.15 58.8,180.4 58.93,180.53 70.69,180.53 70.82,180.66 70.82,180.92 70.69,181.04 58.35,181.04 57.66,180.34 57.66,178.44 57.34,178.12 56.13,178.12 56.01,177.99 56.01,177.74 56.13,177.61 57.59,177.61 57.72,177.48 57.72,177.23 57.59,177.1 54.67,177.1 54.55,176.97 54.55,176.72 54.67,176.59 57.4,176.59 57.66,176.34 57.66,175.77 55.62,173.73 51.12,173.73 51.06,173.79 48.86,173.79 J5.180
M3_MA4: length 82.3
  TOP w0.102: 75.36,182.45 77.17,182.45 78.31,181.3 79.43,181.3 79.83,181.69 U22.BA43
  TOP w0.118: 75.36,182.45 67.74,182.45 66.67,183.51 65.51,183.51 64.83,182.84 64.83,181.93 64.45,181.55 59.32,181.55 59.19,181.67 59.19,181.93 59.32,182.05 64.2,182.05 64.33,182.18 64.33,182.44 64.2,182.56 59.31,182.56 59.18,182.69 59.18,182.94 59.31,183.07 64.33,183.07 64.45,183.2 64.45,183.45 64.33,183.58 57.38,183.58 57.25,183.71 57.25,183.96 57.38,184.09 64.94,184.09 65.06,184.21 65.06,184.47 64.94,184.59 57.04,184.59 56.72,184.28 56.72,182.04 57.15,181.61 57.15,179.96 54.8,177.61 53.95,177.61 51.82,175.48 51.82,174.75 51.28,174.22 49.91,174.22 49.35,174.78 46.97,174.78 J5.59
M3_MA5: length 82.3
  TOP w0.118: J5.58 47.14,176 47.92,175.22 49.56,175.22 50.13,175.78 51.4,175.78 53.74,178.12 54.52,178.12 56.64,180.24 56.64,181.36 56.22,181.78 56.22,187.79 56.58,188.15 59.6,188.15 59.73,188.02 59.73,187.77 59.6,187.64 56.91,187.64 56.79,187.52 56.79,187.26 56.91,187.13 63.17,187.13 63.3,187.01 63.3,186.75 63.17,186.63 56.9,186.63 56.77,186.5 56.77,186.25 56.9,186.12 64.17,186.12 64.28,186 64.28,185.75 64.14,185.61 56.86,185.61 56.73,185.48 56.73,185.23 56.86,185.1 65.21,185.1 66.29,184.02 67.18,184.02 68.25,182.96 77.19,182.96 77.77,182.38 78.15,182.38 U22.BA44
M3_MA6: length 82.3
  TOP w0.118: U22.BB44 78.4,182.7 78.4,182.69 78.19,182.69 77.37,183.51 72.95,183.51 71.87,184.59 66.48,184.59 63.44,187.64 60.36,187.64 60.24,187.77 60.24,188.02 60.36,188.15 64.09,188.15 64.21,188.28 64.21,188.53 64.09,188.66 56.39,188.66 56.26,188.79 56.26,189.04 56.39,189.17 64.06,189.17 64.19,189.29 64.19,189.55 64.06,189.67 56.39,189.67 56.26,189.8 56.26,190.06 56.39,190.18 61.92,190.18 62.05,190.31 62.05,190.56 61.92,190.69 56.07,190.69 55.71,190.33 55.71,181.57 56.13,181.15 56.13,180.45 54.31,178.63 53.53,178.63 51.12,176.22 48.87,176.22 J5.178
M3_MA7: length 82.3
  TOP w0.118: J5.56 47.17,178 48.13,177.04 49.15,177.04 49.89,177.78 51.25,177.78 53.21,179.75 54.01,179.75 54.36,180.09 54.36,181.86 54.69,182.19 54.69,194.44 55.01,194.75 55.82,194.75 55.94,194.64 55.94,192.88 56.06,192.76 60.37,192.76 60.49,192.88 60.49,193.12 60.36,193.26 56.56,193.26 56.44,193.38 56.44,193.64 56.56,193.76 59.36,193.76 59.48,193.87 59.48,194.11 59.33,194.26 56.56,194.26 56.44,194.37 56.44,194.64 56.56,194.75 59.63,194.75 61.48,192.91 63.16,192.91 66.67,189.4 66.67,187.43 67.42,186.69 74.07,186.69 74.21,186.56 74.21,186.32 74.07,186.19 70.49,186.19 70.37,186.07 70.37,185.73 70.49,185.61 78,185.61 78.4,185.21 78.57,185.21 79.52,184.25 79.52,184 U22.BC43
M3_MA8: length 82.3
  TOP w0.118: J5.177 51.18,177 53.32,179.13 54.1,179.13 54.86,179.89 54.86,181.65 55.2,181.98 55.2,191.85 55.56,192.21 62.86,192.21 62.99,192.09 62.99,191.83 62.86,191.71 56.01,191.71 55.88,191.58 55.88,191.33 56.01,191.2 63.75,191.2 63.88,191.07 63.88,190.82 63.75,190.69 62.74,190.69 62.61,190.56 62.61,190.31 62.74,190.18 64.33,190.18 64.77,189.74 64.77,187.05 65.7,186.12 69.7,186.12 69.83,185.99 69.83,185.74 69.7,185.61 66.75,185.61 66.62,185.48 66.62,185.23 66.75,185.1 77.41,185.1 77.53,184.98 77.53,184.72 77.41,184.59 73.11,184.59 72.99,184.47 72.99,184.21 73.11,184.09 77.56,184.09 78.38,183.26 80.4,183.26 80.83,183.69 U22.BC42
M3_MA9: length 82.3
  TOP w0.118: J5.175 51.11,179.56 52.07,180.52 52.07,181.11 53.68,182.71 53.68,200.49 54.1,200.91 55.56,200.91 55.69,200.79 55.69,200.53 55.56,200.41 54.36,200.41 54.23,200.28 54.23,200.03 54.36,199.9 58.67,199.9 58.8,199.77 58.8,199.52 58.67,199.39 54.36,199.39 54.23,199.26 54.23,199.01 54.36,198.88 58.67,198.88 58.8,198.75 58.8,198.5 58.67,198.37 54.36,198.37 54.23,198.25 54.23,197.99 54.36,197.87 58.67,197.87 58.8,197.74 58.8,197.42 58.67,197.29 57.91,197.29 57.78,197.17 57.78,196.91 57.91,196.79 59.12,196.79 61.98,193.93 63.6,193.93 68.81,188.72 73.53,188.72 75.63,186.63 78.42,186.63 79.37,185.67 80.64,185.67 81.62,184.69 81.62,184.7 U22.BD41
M3_MA10: length 82.3
  TOP w0.118: U22.AK44 78.83,170.69 78.63,170.5 73.47,170.5 69.02,166.05 67.3,166.05 67.17,166.18 67.17,166.43 67.3,166.56 68.78,166.56 68.91,166.69 68.91,166.94 68.78,167.07 54.86,167.07 54.74,167.2 54.74,167.45 54.86,167.58 69.81,167.58 69.93,167.7 69.93,167.96 69.81,168.08 56.18,168.08 56.06,168.21 56.06,168.47 56.18,168.59 59.77,168.59 59.89,168.72 59.89,168.97 59.77,169.1 54.4,169.1 53.73,168.44 53.73,167.65 51.74,165.66 51.21,165.66 51.09,165.78 50.21,165.78 49.22,164.8 49.19,164.8 49.19,164.79 47.83,164.79 47.03,164 J5.70
M3_MA11: length 82.3
  TOP w0.118: J5.55 49.09,179 49.89,178.21 50.95,178.21 52.7,179.96 52.7,180.92 54.18,182.4 54.18,196.8 54.67,197.29 57.15,197.29 57.28,197.17 57.28,196.91 57.15,196.79 54.93,196.79 54.8,196.66 54.8,196.41 54.93,196.28 58.66,196.28 58.79,196.15 58.79,195.9 58.66,195.77 54.86,195.77 54.74,195.64 54.74,195.39 54.86,195.26 59.88,195.26 61.72,193.42 63.37,193.42 68.58,188.21 73.3,188.21 73.43,188.09 73.43,187.83 73.3,187.71 67.63,187.71 67.5,187.58 67.5,187.32 67.63,187.2 74.29,187.2 75.37,186.12 78.21,186.12 79.16,185.17 80.36,185.17 U22.BD42
M3_MA12: length 82.3
  TOP w0.118: U22.BC40 82.3,184.23 82.3,184.91 81.03,186.18 79.6,186.18 78.36,187.43 78.36,188.59 77.72,189.23 70.1,189.23 68.02,191.31 68.02,193.34 66.8,194.56 62.1,194.56 59.31,197.36 59.31,200.03 58.93,200.41 56.39,200.41 56.26,200.53 56.26,200.79 56.39,200.91 59.05,200.91 59.18,201.04 59.18,201.29 59.05,201.42 54.43,201.42 54.3,201.55 54.3,201.8 54.43,201.93 58.93,201.93 59.05,202.06 59.05,202.31 58.93,202.44 53.97,202.44 53.17,201.63 53.17,182.92 51.56,181.32 51.56,180.73 50.83,180 J5.174
M3_MA13: length 82.3
  TOP w0.118: U22.AB44 77.17,161.04 70.45,161.04 66.8,157.38 66.8,152.02 66,151.22 52.07,151.22 51.94,151.35 51.94,151.6 52.07,151.73 65.66,151.73 65.79,151.85 65.79,152.11 65.66,152.23 52.07,152.23 51.94,152.36 51.94,152.62 52.07,152.74 58.23,152.74 58.36,152.87 58.36,153.12 58.23,153.25 53.76,153.25 51.08,155.93 50.19,155.93 48.65,157.47 J5.196
M3_MA14: length 82.3
  TOP w0.118: J5.172 48.86,181.79 51.33,181.79 52.66,183.12 52.66,201.88 53.72,202.95 61.48,202.95 61.61,203.07 61.61,203.33 61.48,203.45 56.26,203.45 56.13,203.58 56.13,203.84 56.26,203.96 65.91,203.96 68.58,201.29 68.58,191.52 70.36,189.74 80.26,189.74 82.42,187.58 82.42,186.07 83.31,185.18 83.31,184.21 U22.BC39
M3_MA15: length 82.2
  TOP w0.118: J5.171 51.11,183.56 51.64,184.09 51.64,203.15 53.47,204.98 64.07,204.98 64.19,205.1 64.19,205.36 64.07,205.49 59.44,205.49 59.31,205.61 59.31,205.87 59.44,205.99 65.4,205.99 69.6,201.8 69.6,192.02 70.87,190.75 82.85,190.75 85.14,188.47 85.14,185.01 U22.BD38
M3_MBA0: length 82.4
  TOP w0.118: J5.71 46.75,163 49.21,163 49.99,163.78 55.39,163.78 55.63,164.02 65.56,164.02 65.68,163.89 65.68,163.64 65.56,163.51 55.88,163.51 55.75,163.39 55.75,163.13 55.88,163 66.17,163 66.29,162.88 66.29,162.62 66.17,162.5 54.34,162.5 54.22,162.37 54.22,162.12 54.34,161.99 66.4,161.99 73.89,169.48 78.3,169.48 78.56,169.21 79.35,169.21 U22.AJ43
M3_MBA1: length 82.3
  TOP w0.118: J5.190 49.43,164 49.65,164.22 51.08,164.22 53.42,166.56 66.54,166.56 66.66,166.43 66.66,166.18 66.54,166.05 53.91,166.05 53.78,165.93 53.78,165.67 53.91,165.54 67.97,165.54 68.1,165.42 68.1,165.16 67.97,165.04 57.48,165.04 57.35,164.91 57.35,164.66 57.48,164.53 68.22,164.53 73.68,169.99 78.54,169.99 U22.AJ44
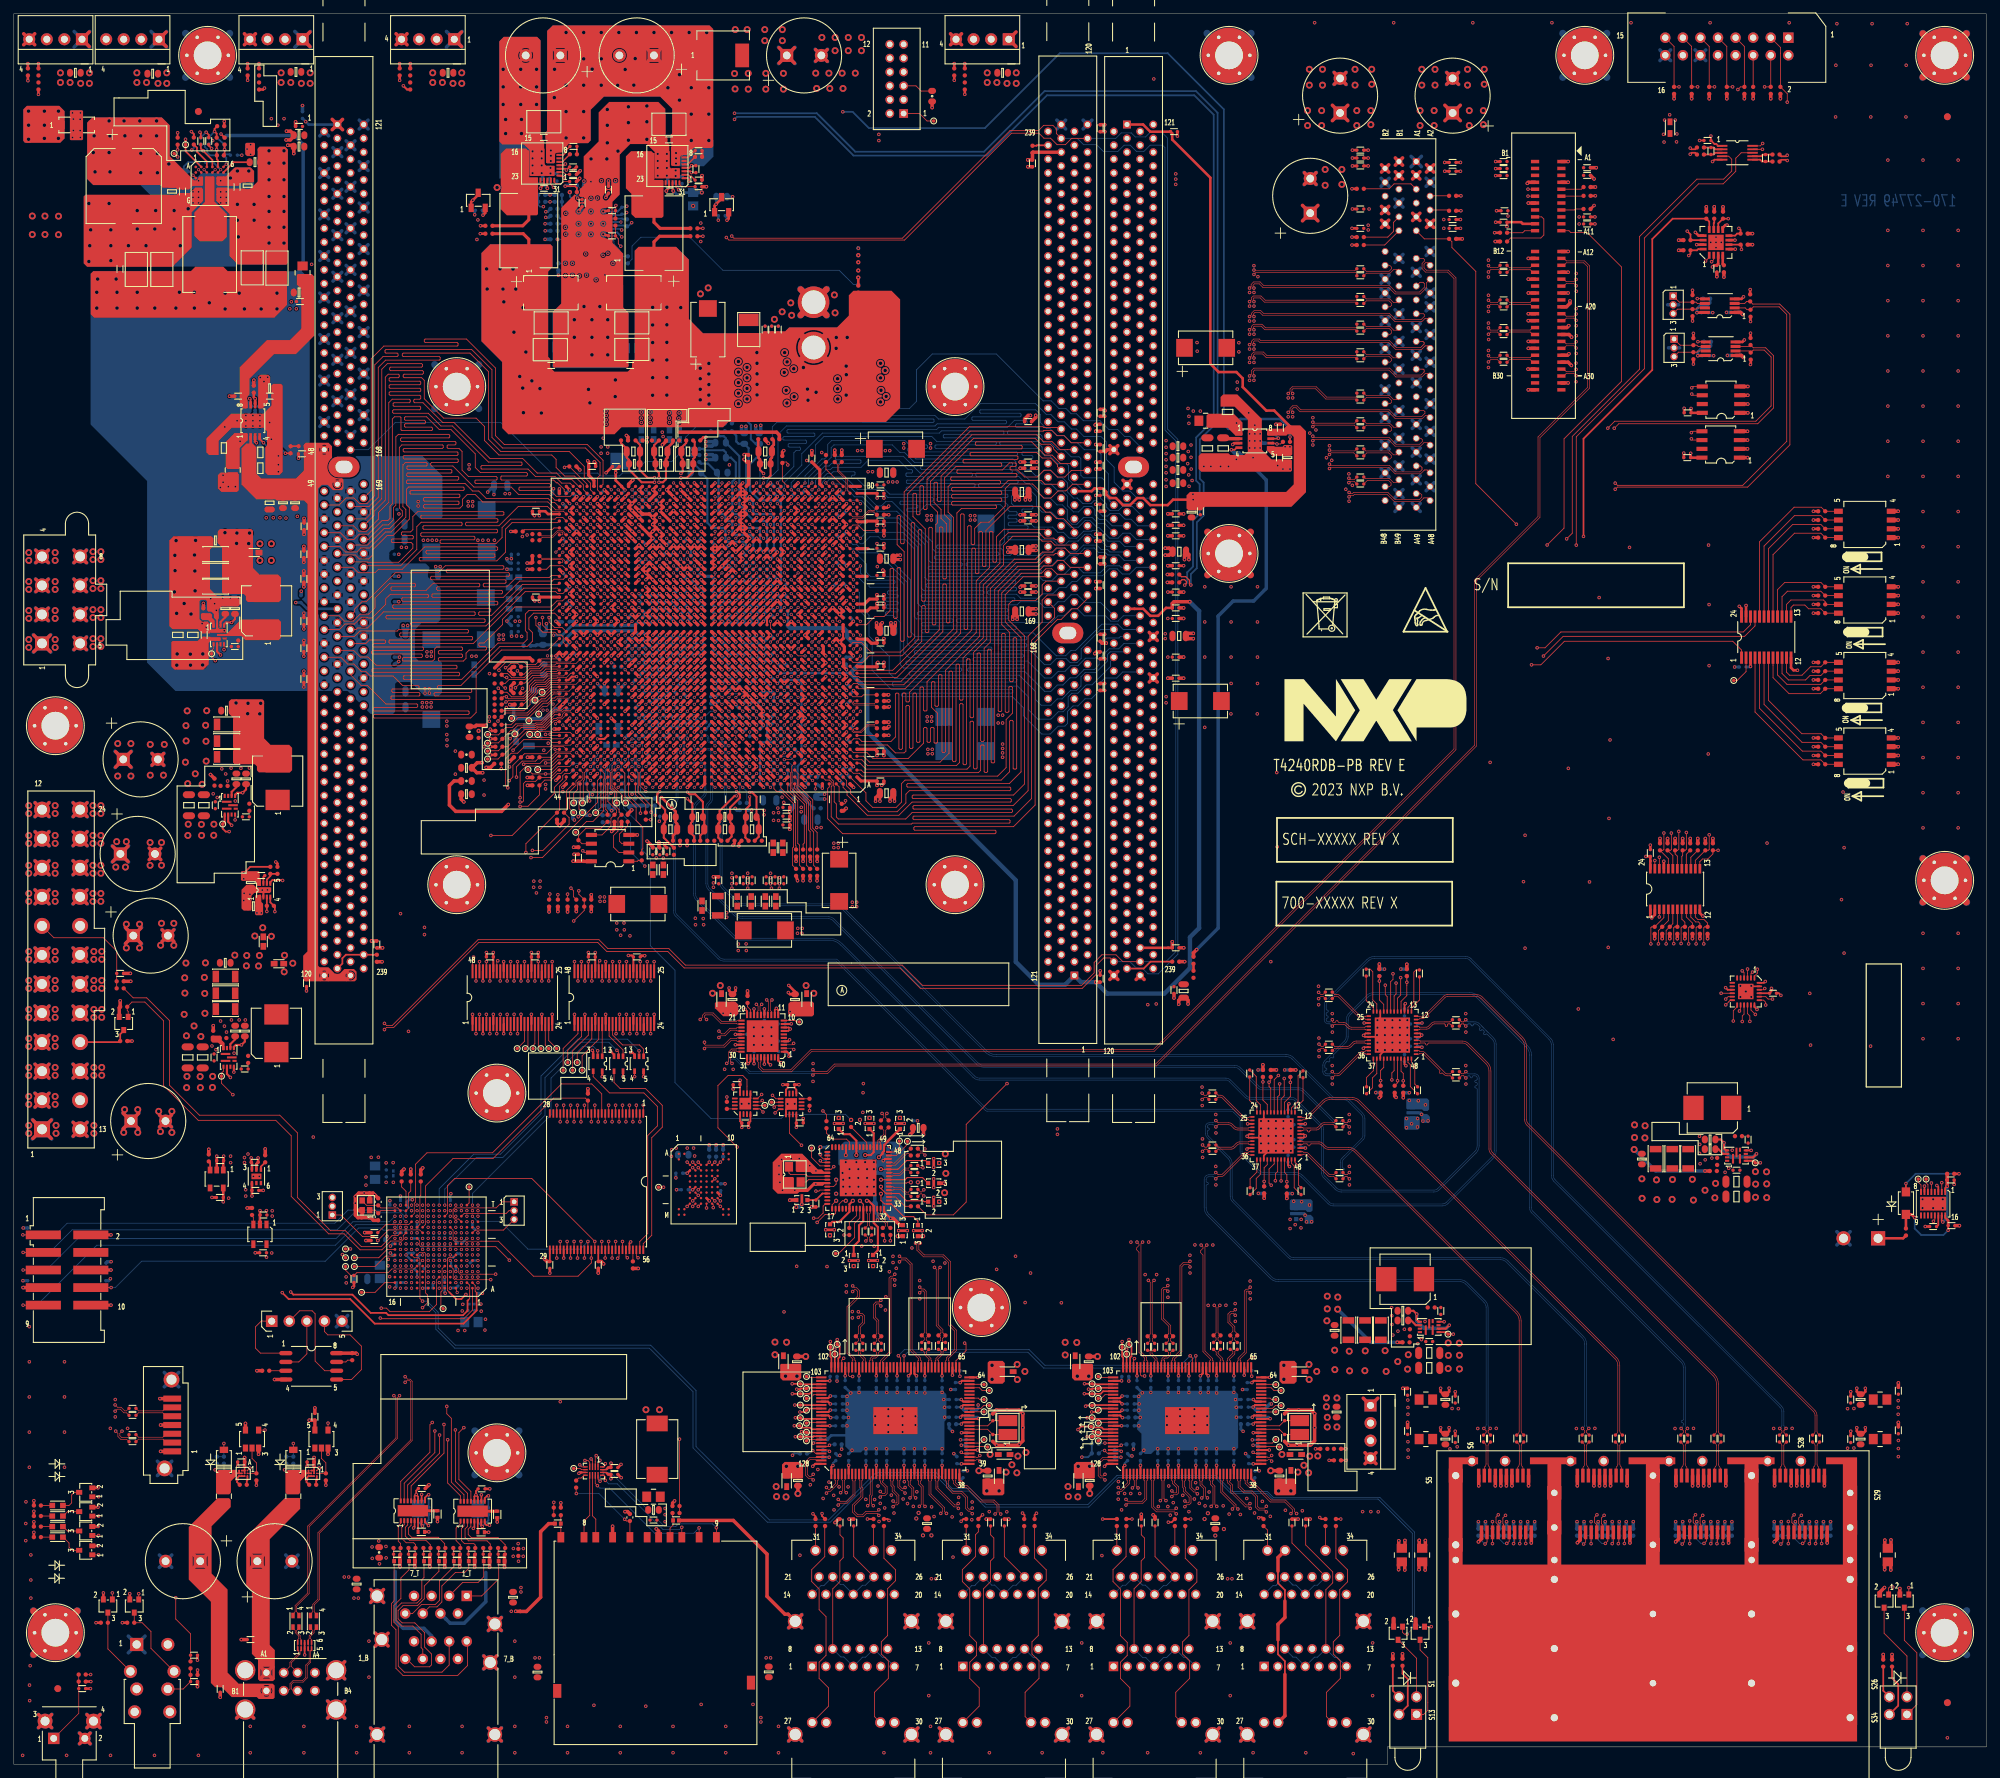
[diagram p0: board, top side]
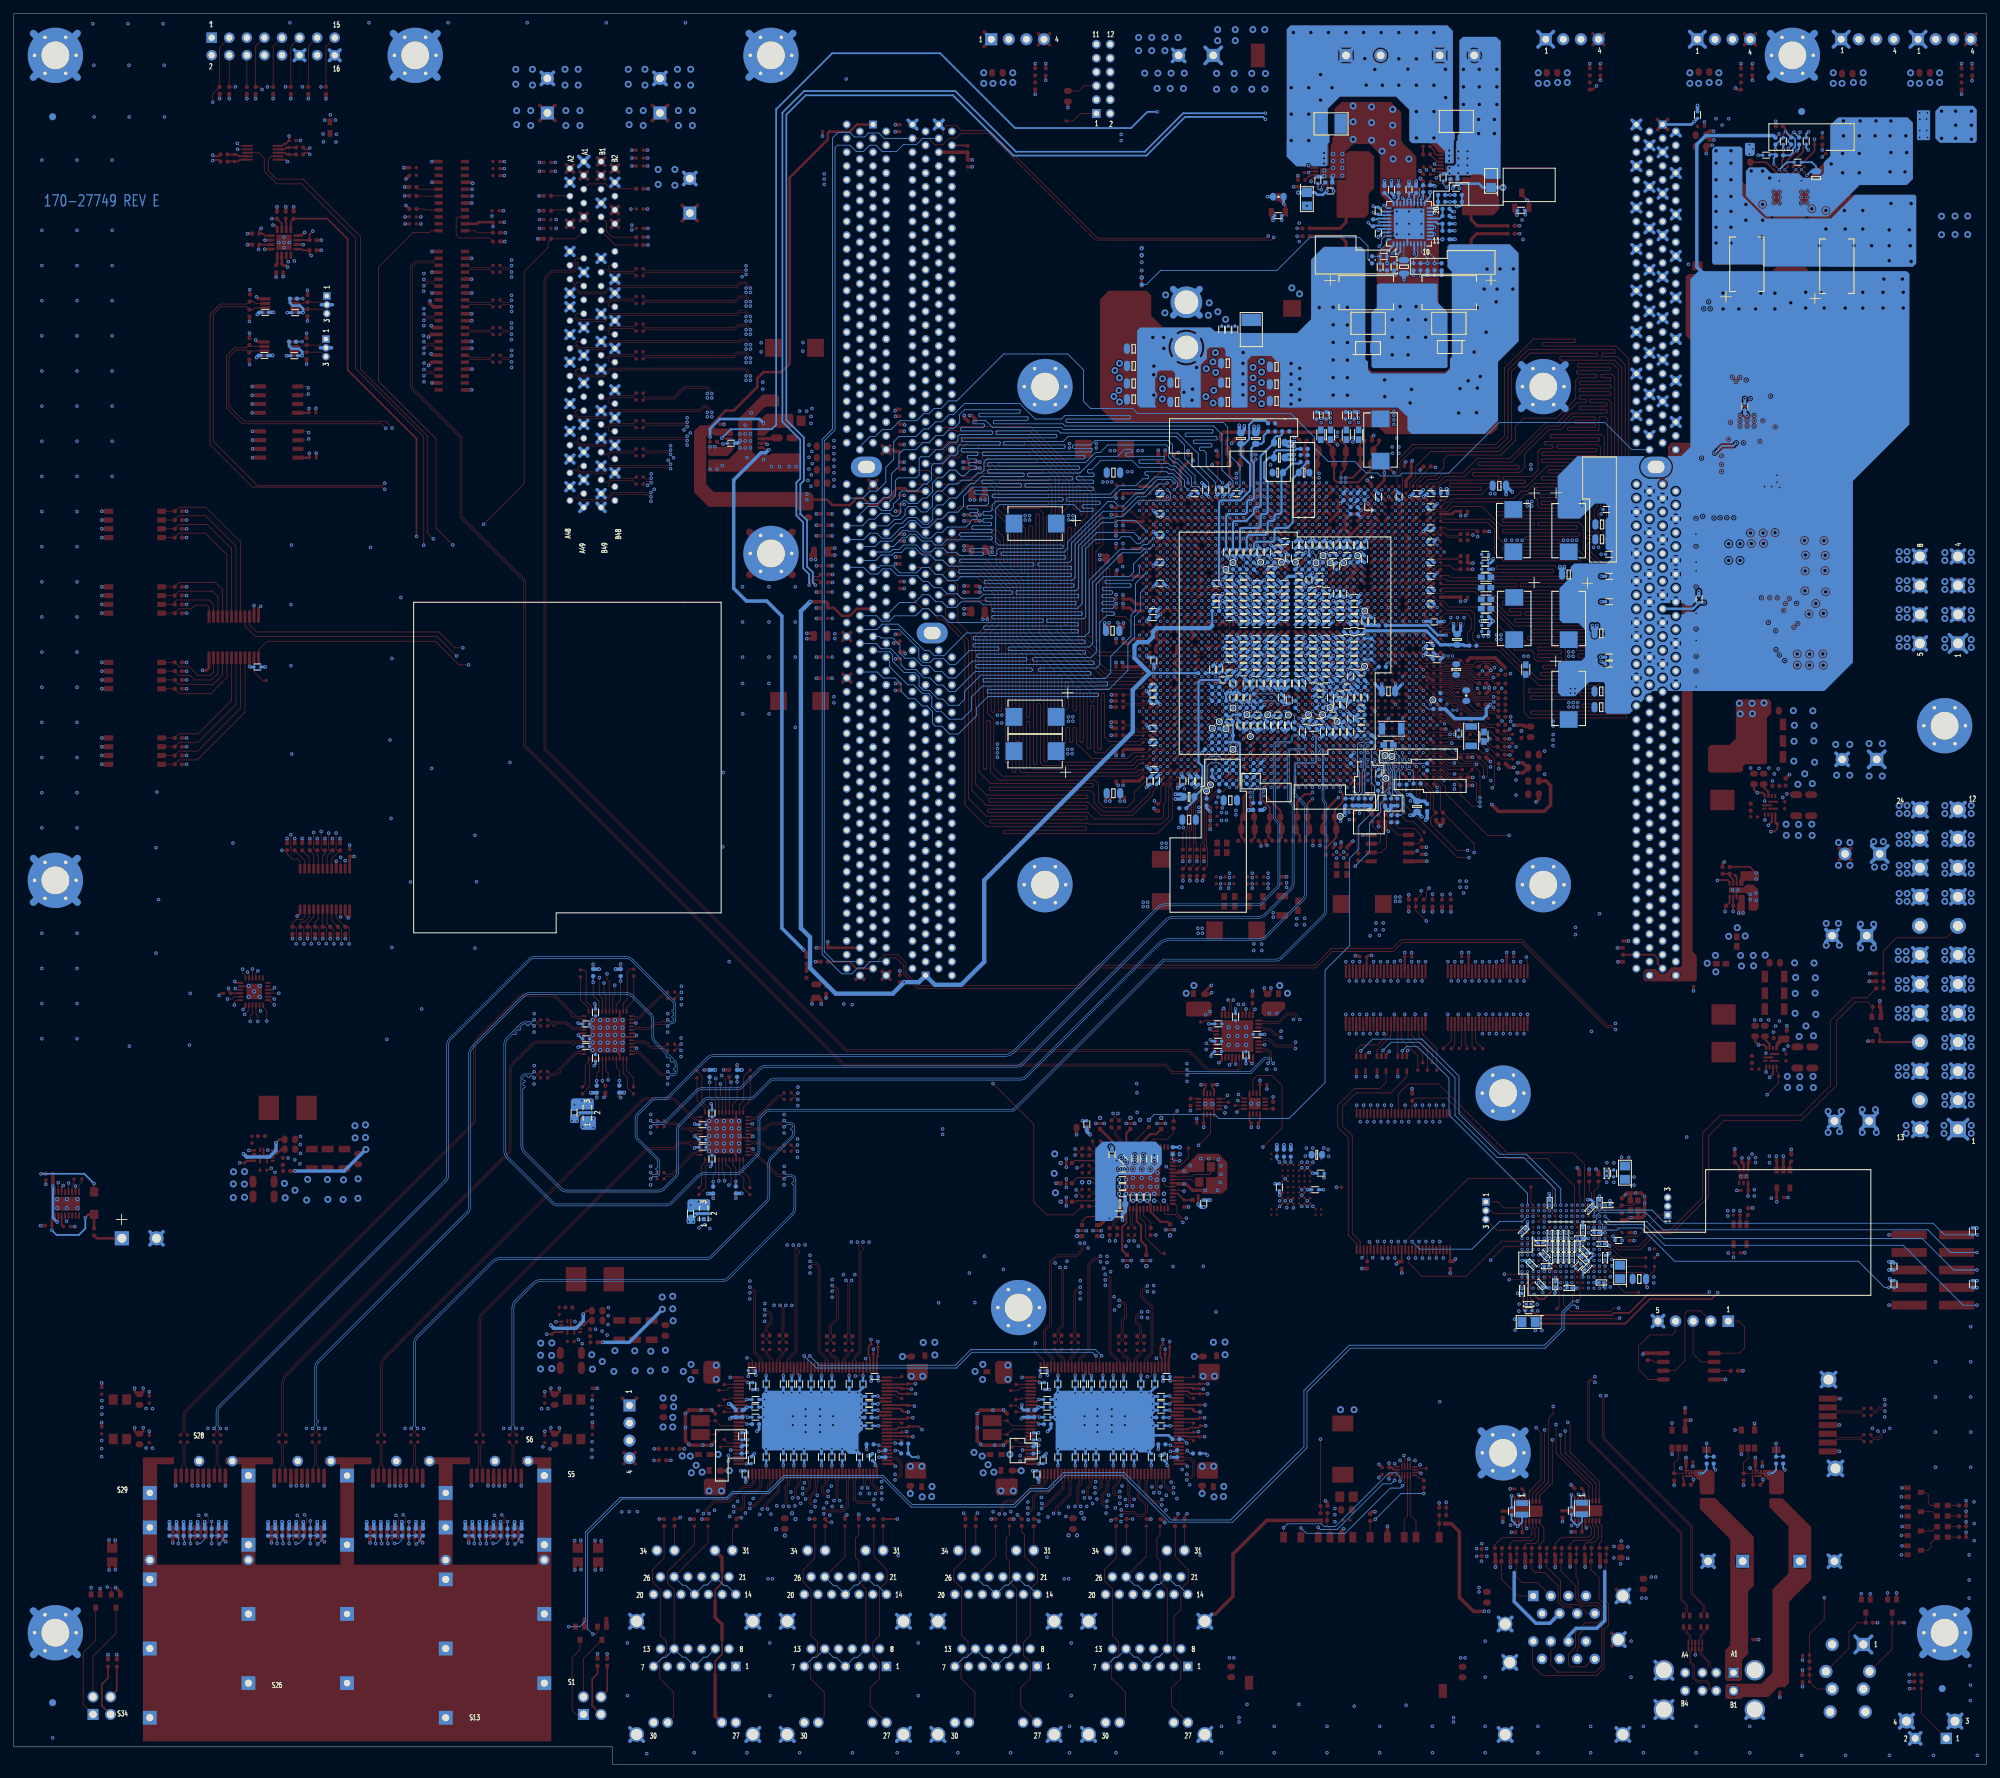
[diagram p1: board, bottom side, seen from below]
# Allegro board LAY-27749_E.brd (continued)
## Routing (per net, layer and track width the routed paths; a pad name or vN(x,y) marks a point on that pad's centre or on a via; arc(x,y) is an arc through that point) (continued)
M3_MBA2: length 82.3
  TOP w0.118: U22.BC38 84.33,184.2 84.33,185.93 84.71,186.31 84.71,188.14 82.6,190.25 70.61,190.25 69.09,191.77 69.09,201.55 66.17,204.47 53.76,204.47 53.63,204.34 53.63,204.09 53.76,203.96 55.39,203.96 55.52,203.84 55.52,203.58 55.39,203.45 53.34,203.45 52.15,202.27 52.15,183.34 51.03,182.22 49.94,182.22 49.15,183.01 48.01,183.01 47,182 J5.52
M3_MCAS_B: length 82.3
  TOP w0.118: J5.74 47.26,160 48.26,159 49.15,159 50.19,157.96 50.83,157.96 51.49,157.3 54.79,157.3 56.17,155.92 58.42,155.92 58.55,155.79 58.55,155.54 58.42,155.41 54.74,155.41 54.61,155.28 54.61,155.03 54.74,154.9 58.55,154.9 58.67,154.77 58.67,154.52 58.55,154.39 54.61,154.39 54.48,154.27 54.48,154.01 54.61,153.89 65.76,153.89 65.89,154.01 65.89,154.27 65.76,154.39 60.86,154.39 60.73,154.52 60.73,154.77 60.86,154.9 66.04,154.9 66.17,155.03 66.17,155.28 66.04,155.41 61.34,155.41 61.21,155.54 61.21,155.79 61.34,155.92 64.6,155.92 70.23,161.54 74.17,161.54 74.93,162.31 74.93,163.58 74.42,164.08 74.42,165.67 75.12,166.37 78.16,166.37 U22.AE44
M3_MCKE0: length 82.4
  TOP w0.118: v3(86.33,184.19) U22.BD37
  L3_INT_1 w0.087: J5.50 46.97,184 48.01,185.04 48.89,185.04 49.78,184.15 51.49,184.15 52.92,185.59 70.81,185.59 70.9,185.67 70.9,185.89 70.81,185.98 53.1,185.98 53.01,186.07 53.01,186.28 53.1,186.37 76.21,186.37 77.9,188.06 81.69,188.06 84.58,185.17 85.6,185.17 86.33,184.43 v3(86.33,184.19)
M3_MCKE1: length 82.3
  TOP w0.118: v3(87.33,184.19) U22.BC35
  L3_INT_1 w0.087: v3(87.33,184.19) 85.98,185.55 84.86,185.55 81.51,188.9 51.52,188.9 51.43,188.81 51.43,188.59 51.52,188.51 64.93,188.51 65.02,188.42 65.02,188.2 64.93,188.11 51.65,188.11 51.56,188.02 51.56,187.81 51.65,187.72 58.24,187.72 58.34,187.61 58.34,187.4 58.26,187.31 52.86,187.31 J5.169
M3_MCLK0_N: length 82.3
  TOP w0.091: v3(80.33,176.19) U22.AR43
  L3_INT_1 w0.1: v3(80.33,176.19) 79.93,175.8 79.93,174.7 79.45,174.22 72.74,174.22 72.49,174.47 72.49,175.47 72.74,175.72 74.18,175.72 74.28,175.82 74.28,176.61 74.18,176.71 71.7,176.71 70.1,178.31 61.7,178.31 61.59,178.21 61.59,177.42 61.7,177.32 66.37,177.32 66.62,177.07 66.62,176.09 66.37,175.84 57.68,175.84 57.58,175.74 57.58,174.96 57.68,174.85 70.56,174.85 70.81,174.6 70.81,173.61 70.56,173.35 63.1,173.35 61.7,171.96 56.9,171.96 54.79,169.85 50.14,169.85 49.83,169.54 49.83,169.29 50.12,169 J5.185
M3_MCLK0_P: length 82.3
  TOP w0.091: U22.AT43 79.33,176.2 v3(79.33,176.19)
  L3_INT_1 w0.1: J5.184 49.1,169.54 49.48,169.54 50.04,170.1 54.68,170.1 56.79,172.21 61.59,172.21 62.99,173.61 70.46,173.61 70.56,173.71 70.56,174.5 70.46,174.6 57.58,174.6 57.33,174.85 57.33,175.85 57.58,176.1 66.27,176.1 66.37,176.2 66.37,176.96 66.27,177.06 61.59,177.06 61.34,177.31 61.34,178.31 61.59,178.56 70.21,178.56 71.81,176.96 74.29,176.96 74.54,176.71 74.54,175.71 74.29,175.46 72.85,175.46 72.75,175.36 72.75,174.57 72.85,174.47 79.35,174.47 79.73,174.85 79.73,175.79 v3(79.33,176.19)
M3_MCLK1_N: length 82.5
  TOP w0.091: v3(79.33,175.19) U22.AP44
  L3_INT_1 w0.1: v3(79.33,175.19) 79.04,175.48 78.94,175.58 78.94,179.5 75.69,182.75 68.19,182.75 67.38,183.57 56.26,183.57 56.01,183.32 56.01,181.1 56.31,180.8 72.76,180.8 72.87,180.68 72.87,179.91 72.77,179.81 56.51,179.81 50.82,174.12 50.06,174.12 49.04,173.1 48.15,173.1 47.21,172.16 46.27,172.16 45.5,171.39 45.5,170.65 J5.64
M3_MCLK1_P: length 82.4
  TOP w0.091: U22.AR44 78.33,175.2 v3(78.33,175.19)
  L3_INT_1 w0.1: J5.63 46.75,170.57 46.45,170.27 46.08,170.27 45.76,170.6 45.76,171.29 46.38,171.91 47.32,171.91 48.26,172.85 49.15,172.85 50.16,173.86 50.93,173.86 56.62,179.55 72.88,179.55 73.12,179.8 73.12,180.79 72.86,181.05 56.41,181.05 56.26,181.2 56.26,183.21 56.36,183.31 67.27,183.31 68.08,182.5 75.59,182.5 78.69,179.4 78.69,175.55 v3(78.33,175.19)
M3_MCLK2_N: length 4.3
  TOP w0.091: R229.2 76.26,174.31 79.28,174.31 79.53,174.05 79.53,173.99 U22.AN43
M3_MCLK2_P: length 4.3
  TOP w0.091: U22.AN44 79.23,173.7 79.33,173.79 79.33,173.96 79.19,174.1 76.31,174.1 R230.2
M3_MCLK3_N: length 4.7
  TOP w0.091: R221.2 76.2,177.55 77.8,177.55 78.56,178.3 79.28,178.3 79.53,178.05 79.53,177.79 79.63,177.69 79.63,177.7 U22.AU43
M3_MCLK3_P: length 4.6
  TOP w0.091: R224.2 75.95,176.92 76.37,177.34 77.88,177.34 78.64,178.1 79.2,178.1 79.33,177.97 79.33,177.81 79.22,177.69 78.83,177.69 U22.AU44
M3_MCS_B0: length 82.3
  TOP w0.118: U22.AF44 v3(79.33,166.19)
  L3_INT_1 w0.087: J5.193 51.09,161.54 51.09,161.54 51.94,162.39 51.94,165.56 56.36,169.98 61.26,169.98 61.91,170.62 70.71,170.62 70.8,170.71 70.8,170.93 70.71,171.02 63.33,171.02 63.25,171.11 63.25,171.32 63.33,171.41 76.45,171.41 76.54,171.5 76.54,171.72 76.45,171.81 63.59,171.81 63.5,171.89 63.5,172.11 63.59,172.2 76.97,172.2 78.61,170.56 78.61,166.91 v3(79.33,166.19)
M3_MCS_B1: length 82.3
  TOP w0.118: U22.AC44 78.52,164 77.05,164 76.39,164.66 v2(76.39,165.74)
  L3_INT_1 w0.087: v2(76.39,165.74) 76.2,165.74 75.69,165.23 75.31,165.23 74.8,165.74 74.8,166.51 74.22,167.09 67.16,167.09 62.87,162.8 56.73,162.8 56.64,162.71 56.64,162.5 56.73,162.41 61,162.41 61.09,162.32 61.09,162.1 61,162.01 54.83,162.01 54.74,161.93 54.74,161.71 54.83,161.62 61.23,161.62 61.32,161.53 61.32,161.32 61.23,161.23 54.7,161.23 54.61,161.14 54.61,160.92 54.7,160.83 58.31,160.83 58.39,160.74 58.39,160.53 58.31,160.44 57.31,160.44 55.12,158.24 55.12,155.52 51.59,151.99 50.06,151.99 49.02,153.03 48.29,153.03 47.32,152.07 46.18,152.07 45.21,153.03 44.45,153.03 43.94,153.54 43.94,157.09 J5.76
M3_MCS_B2: length 82.3
  TOP w0.118: U22.AG43 79.33,167.2 v3(79.33,167.19)
  L3_INT_1 w0.087: J5.79 46.75,155.72 48.26,157.23 49.15,157.23 49.91,157.99 51.18,157.99 51.92,158.73 51.92,160.25 52.96,161.29 52.96,165.35 54.99,167.39 63.86,167.39 63.94,167.47 63.94,167.69 63.86,167.78 56.72,167.78 56.63,167.87 56.63,168.08 56.72,168.17 65.65,168.17 65.73,168.26 65.73,168.48 65.65,168.57 56.84,168.57 56.76,168.66 56.76,168.87 56.84,168.96 76.4,168.96 77.6,167.77 77.6,166.64 79.14,165.1 80.26,165.1 80.77,165.61 80.77,166.37 80.39,166.75 79.77,166.75 v3(79.33,167.19)
M3_MCS_B3: length 82.3
  TOP w0.118: v2(77.34,165.74) 77.34,165.1 78.15,164.29 79.24,164.29 U22.AC43
  L3_INT_1 w0.087: v2(77.34,165.74) 77.34,165.99 76.33,167 75.42,167 74.15,168.28 67.23,168.28 65.93,166.98 55.36,166.98 55.27,166.89 55.27,166.67 55.36,166.59 64.93,166.59 65.02,166.5 65.02,166.28 64.93,166.19 54.37,166.19 54.28,166.1 54.28,165.89 54.37,165.8 64.13,165.8 64.22,165.71 64.22,165.49 64.13,165.4 53.9,165.4 53.37,164.87 53.37,161.06 52.32,160.01 52.32,157.47 50.84,156 J5.198
M3_MDIC_0: length 4.3
  TOP w0.118: R232.1 76.96,172.72 77.47,173.23 79.3,173.23 U22.AM43
M3_MDIC_1: length 5.5
  TOP w0.118: U22.AV44 78.05,178.7 77.79,178.44 73.78,178.44 73.53,178.19 R219.1
M3_MDQ0: length 82.2
  TOP w0.118: U22.AY35 v3(88.33,181.19)
  L14_INT_6 w0.087: v3(88.33,181.19) 88.77,181.64 88.77,182.37 88.96,182.55 88.96,186.01 89.1,186.16 89.1,190.24 86.75,192.6 85.42,192.6 81.72,196.29 81.72,197.99 80.53,199.19 80.53,204.11 75.18,209.46 75.18,210.9 73.84,212.24 68.08,212.24 67.43,212.9 67.43,214.08 63.6,217.91 63.6,220.17 63.51,220.26 63.29,220.26 63.21,220.17 63.21,218.93 63.12,218.84 62.92,218.84 62.81,218.94 62.81,223.44 52.06,234.2 50.03,234.2 49.23,235 J5.3
M3_MDQ1: length 82.3
  TOP w0.118: v3(88.33,182.19) U22.BA35
  L14_INT_6 w0.087: v3(88.33,182.19) 88.72,182.59 88.72,184.48 88.65,184.56 88.65,190.15 86.61,192.18 85.28,192.18 81.28,196.17 81.28,197.74 80.14,198.88 80.14,203.95 74.79,209.3 74.79,209.32 74.7,209.4 74.7,210.81 74.09,211.43 72.46,211.43 72.05,211.01 72.05,209.8 71.54,209.29 70.06,209.29 66.78,212.57 66.78,213.82 62.4,218.21 62.4,223.3 51.89,233.81 49.83,233.81 49.2,233.17 48.13,233.17 47.3,234 J5.4
M3_MDQ2: length 82.3
  TOP w0.118: v3(85.33,180.19) U22.AW37
  L14_INT_6 w0.087: v3(85.33,180.19) 84.83,180.7 84.2,180.7 83.92,180.97 83.92,183.41 84.25,183.74 84.25,186.16 82.52,187.88 82.52,188.82 77.16,194.18 73.57,194.18 71.48,196.28 71.48,201.75 55.81,217.41 55.3,217.41 53.94,218.78 53.94,221.55 53.85,221.64 53.63,221.64 53.54,221.55 53.54,219.63 53.46,219.54 53.25,219.54 53.15,219.64 53.15,226.28 53.06,226.36 52.84,226.36 52.76,226.28 52.76,222.89 52.67,222.8 52.45,222.8 52.36,222.89 52.36,226.66 51.19,227.83 49.92,227.83 48.75,229 J5.9
M3_MDQ3: length 82.2
  TOP w0.118: v3(85.33,179.19) U22.AV37
  L14_INT_6 w0.087: v3(85.33,179.19) 84.82,179.71 84.07,179.71 83.72,180.06 83.72,183.67 83.82,183.77 83.82,185.98 82.12,187.68 82.12,188.67 77.27,193.52 74.3,193.52 72.89,192.11 71.71,192.11 70.99,192.82 70.99,201.67 55.64,217.02 55.14,217.02 53.38,218.78 53.02,218.78 52.76,219.04 52.76,219.63 52.76,219.63 52.76,222.32 52.67,222.4 52.45,222.4 52.36,222.32 52.36,219.06 52.27,218.97 52.06,218.97 51.97,219.06 51.97,225.27 51.23,226.01 50.19,226.01 49.1,227.1 48.26,227.1 47.36,228 J5.10
M3_MDQ4: length 82.3
  TOP w0.118: v3(87.33,178.19) U22.AU35
  L14_INT_6 w0.087: J5.122 51.37,236 64.46,222.91 64.46,218.8 68.27,214.99 72.64,214.99 76.35,211.28 76.35,209.58 81.47,204.46 81.47,201.23 82.11,200.6 83.24,200.6 85.68,198.16 85.68,197.02 90.25,192.46 90.25,184.64 89.96,184.35 89.96,180.23 89.41,179.68 89.13,179.68 88.77,179.32 88.77,179.07 88.36,178.65 87.9,178.65 87.44,178.19 v3(87.33,178.19)
M3_MDQ5: length 82.3
  TOP w0.118: v3(87.33,179.19) U22.AV35
  L14_INT_6 w0.087: v3(87.33,179.19) 87.58,179.19 88.09,179.71 88.49,179.71 88.85,180.06 88.85,180.44 89,180.59 89.48,180.59 89.77,180.88 89.77,184.63 89.85,184.72 89.85,192.21 85.22,196.85 85.22,198.06 83.13,200.15 81.84,200.15 81.03,200.96 81.03,204.33 75.79,209.57 75.79,211.19 72.5,214.47 67.84,214.47 64.03,218.29 64.03,222.21 63.95,222.3 63.74,222.3 63.64,222.2 63.64,220.74 63.55,220.65 63.33,220.65 63.25,220.74 63.25,223.57 51.82,235 J5.123
M3_MDQ6: length 82.3
  TOP w0.118: v3(85.33,182.19) U22.BA37
  L14_INT_6 w0.087: J5.128 49.38,229.27 49.38,228.98 50.14,228.22 51.76,228.22 53.54,226.44 53.54,222.12 53.63,222.03 53.85,222.03 53.94,222.12 53.94,225.88 54.03,225.97 54.27,225.97 54.36,225.88 54.36,219.1 54.44,219.01 54.65,219.01 54.75,219.11 54.75,222.16 54.84,222.25 55.05,222.25 55.14,222.16 55.14,218.13 55.46,217.81 55.97,217.81 71.87,201.91 71.87,197.37 72.77,196.47 76.68,196.47 77.32,195.83 77.32,194.58 82.67,189.23 82.67,189.08 82.92,188.84 83.15,188.84 83.41,188.57 83.41,187.99 84.71,186.69 84.71,182.82 v3(85.33,182.19)
M3_MDQ7: length 82.3
  TOP w0.118: v3(85.33,181.19) U22.AY37
  L14_INT_6 w0.087: J5.129 51.8,229 54.75,226.05 54.75,222.73 54.84,222.64 55.05,222.64 55.14,222.73 55.14,225.25 55.23,225.34 55.45,225.34 55.54,225.25 55.54,218.29 55.63,218.2 55.84,218.2 55.93,218.29 55.93,222.97 56.02,223.05 56.24,223.05 56.33,222.97 56.33,218 72.26,202.07 72.26,197.76 73.05,196.98 76.96,196.98 77.77,196.17 77.77,194.69 83.07,189.39 83.07,189.25 83.52,188.8 84,188.8 85.12,187.68 85.12,185.2 85.85,184.46 85.85,181.72 v3(85.33,181.19)
M3_MDQ8: length 80.9
  TOP w0.118: v3(87.33,175.19) U22.AP35
  L5_INT_2 w0.087: v3(87.33,175.19) 87.64,174.89 87.64,174.89 87.74,174.79 88.5,174.79 89.89,176.18 89.89,188.7 81.35,197.24 81.35,201.28 76.58,206.05 74.49,206.05 52.7,227.84 50.04,227.84 49.24,227.04 48.23,227.04 47.18,226 J5.12
M3_MDQ9: length 80.9
  TOP w0.118: v3(87.33,176.19) U22.AR35
  L5_INT_2 w0.087: v3(87.33,176.19) 87.71,176.57 87.71,189.21 85.82,191.09 84.66,191.09 80.16,195.59 80.16,200.23 77.56,202.83 73.6,202.83 65.45,210.98 63.53,210.98 63.21,211.3 63.21,215.27 63.11,215.37 62.9,215.37 62.81,215.28 62.81,212.89 62.73,212.8 62.51,212.8 62.42,212.89 62.42,216.34 52.97,225.79 49.9,225.79 49.1,225 J5.13
M3_MDQ10: length 80.9
  TOP w0.118: v3(84.33,176.19) U22.AR38
  L5_INT_2 w0.087: J5.18 47.21,220 47.98,219.23 49.31,219.23 49.84,219.77 51.76,219.77 52.51,219.02 52.51,217.11 52.6,217.02 52.81,217.02 52.9,217.11 52.9,218.48 52.99,218.57 53.21,218.57 53.3,218.48 53.3,211.77 53.38,211.68 53.6,211.68 53.69,211.77 53.69,213.86 53.78,213.94 53.99,213.94 54.08,213.86 54.08,210.88 59.85,205.11 65.26,205.11 69.01,201.36 69.01,193.06 72.76,189.31 78.05,189.31 78.56,188.8 78.56,186.35 80,184.91 81.79,184.91 82.8,183.9 82.8,180.04 83.11,179.73 83.51,179.73 83.72,179.52 83.72,178.78 83.95,178.56 83.95,176.58 84.05,176.48 84.05,176.48 v3(84.33,176.19)
M3_MDQ11: length 80.9
  TOP w0.118: U22.AP38 v3(84.33,175.19)
  L5_INT_2 w0.087: v3(84.33,175.19) 83.72,175.81 83.72,178.41 83.44,178.69 83.06,178.69 82.8,178.94 82.8,179.4 82.48,179.73 82.19,179.73 81.86,180.06 81.86,182.36 81.52,182.7 81.14,182.7 78.16,185.69 78.16,188.63 77.89,188.9 72.59,188.9 68.61,192.89 68.61,201.2 65.1,204.71 59.7,204.71 52.9,211.5 52.9,216.46 52.81,216.55 52.6,216.55 52.51,216.46 52.51,210.88 52.42,210.79 52.2,210.79 52.11,210.88 52.11,217.37 51.42,218.06 50.04,218.06 49.28,218.82 47.7,218.82 47.52,219 J5.19
M3_MDQ12: length 80.9
  TOP w0.118: v3(88.33,175.19) U22.AP34
  L5_INT_2 w0.087: J5.131 52.96,227 64.78,215.18 64.78,212.16 64.87,212.07 65.07,212.07 65.18,212.18 65.18,214.41 65.27,214.5 65.48,214.5 65.57,214.41 65.57,212.06 65.66,211.97 65.87,211.97 65.96,212.06 65.96,213.4 66.05,213.49 66.27,213.49 66.36,213.4 66.36,211.19 72.02,205.52 76.35,205.52 80.94,200.93 80.94,197.09 88.82,189.21 88.82,175.69 v3(88.33,175.19)
M3_MDQ13: length 80.9
  TOP w0.118: v3(88.33,176.19) U22.AR34
  L5_INT_2 w0.087: v3(88.33,176.19) 87.93,176.59 87.93,184.58 88.3,184.95 88.3,189.17 80.55,196.92 80.55,200.5 77.83,203.22 77.75,203.22 77.75,203.22 73.76,203.22 65.62,211.37 64.56,211.37 64.39,211.54 64.39,215.01 64.3,215.1 64.08,215.1 64,215.01 64,211.46 63.91,211.37 63.69,211.37 63.6,211.46 63.6,215.8 53.21,226.19 49.61,226.19 49.42,226 J5.132
M3_MDQ14: length 80.9
  TOP w0.118: v3(84.33,177.19) U22.AT38
  L5_INT_2 w0.087: v3(84.33,177.19) 84.84,177.7 84.84,183.31 82.1,186.05 80.47,186.05 80.14,186.39 80.14,188.36 78.38,190.12 73.1,190.12 69.82,193.39 69.82,201.7 65.56,205.97 60.14,205.97 56.44,209.67 56.44,213.33 56.36,213.42 56.14,213.42 56.05,213.33 56.05,210.53 55.96,210.44 55.75,210.44 55.66,210.53 55.66,217.97 55.57,218.06 55.35,218.06 55.26,217.97 55.26,214.59 55.17,214.5 54.96,214.5 54.87,214.59 54.87,218.67 52.79,220.75 50.8,220.75 J5.137
M3_MDQ15: length 80.9
  TOP w0.118: v3(84.33,178.19) U22.AU38
  L5_INT_2 w0.087: v3(84.33,178.19) 84.33,178.56 83.95,178.94 83.95,183.39 81.79,185.55 79.92,185.55 79.02,186.45 79.02,188.93 78.23,189.71 72.93,189.71 69.42,193.22 69.42,201.53 65.43,205.52 60.01,205.52 55.26,210.26 55.26,213.82 55.17,213.91 54.96,213.91 54.87,213.82 54.87,211.16 54.78,211.07 54.57,211.07 54.48,211.16 54.48,218.1 54.39,218.19 54.17,218.19 54.08,218.1 54.08,214.46 53.99,214.38 53.78,214.38 53.69,214.46 53.69,218.84 52.31,220.22 49.66,220.22 49.44,220 J5.138
M3_MDQ16: length 69.9
  TOP w0.118: v3(82.33,182.19) U22.BA40
  L14_INT_6 w0.087: v3(82.33,182.19) 82.05,182.48 82.05,182.48 81.94,182.58 81.94,184.2 78.87,187.27 78.87,188.68 77.69,189.87 70.59,189.87 69.23,191.22 69.23,200.91 66.31,203.82 62.26,203.82 62.17,203.91 62.17,205.16 62.09,205.24 61.87,205.24 61.78,205.16 61.78,203.92 61.69,203.84 61.48,203.84 61.39,203.92 61.39,208.03 61.29,208.13 61.08,208.13 60.99,208.04 60.99,205.06 60.9,204.97 60.69,204.97 60.6,205.06 60.6,209.01 53.38,216.23 49.83,216.23 49.06,217 J5.21
M3_MDQ17: length 69.9
  TOP w0.118: v3(82.33,181.19) U22.AY40
  L14_INT_6 w0.087: J5.22 47.07,216 47.93,215.14 49.02,215.14 49.66,215.77 53.21,215.77 59.41,209.58 59.41,207.45 59.5,207.37 59.72,207.37 59.8,207.45 59.8,208.7 59.89,208.79 60.11,208.79 60.2,208.7 60.2,203.24 60.29,203.14 60.5,203.14 60.59,203.23 60.59,204.42 60.68,204.51 60.9,204.51 60.99,204.42 60.99,203.57 61.12,203.43 66.15,203.43 68.83,200.75 68.83,190.93 70.29,189.47 77.48,189.47 78.36,188.59 78.36,186.94 80.77,184.53 80.77,183.9 80.9,183.77 81.41,183.77 81.74,183.44 81.74,181.79 82.05,181.48 82.05,181.48 v3(82.33,181.19)
M3_MDQ18: length 69.9
  TOP w0.118: v3(83.33,178.19) U22.AV40
  L14_INT_6 w0.087: v3(83.33,178.19) 82.94,178.59 79.91,178.59 76.46,182.03 68.46,182.03 63.88,186.61 63.88,188.42 55.23,197.06 55.23,197.09 54.44,197.88 54.44,200.91 54.36,201 54.14,201 54.05,200.91 54.05,198.74 53.96,198.65 53.75,198.65 53.66,198.74 53.66,205.75 53.57,205.84 53.35,205.84 53.26,205.75 53.26,202.11 53.17,202.02 52.96,202.02 52.87,202.11 52.87,205.7 52.52,206.06 50.13,206.06 49.15,207.04 48.31,207.04 47.65,207.7 47.65,210.1 J5.27
M3_MDQ19: length 69.9
  TOP w0.118: v3(82.33,178.19) U22.AU40
  L14_INT_6 w0.087: J5.28 45.82,209.03 45.82,206.53 46.33,206.02 47.24,206.02 48.31,204.95 49.07,204.95 49.94,204.09 51.05,204.09 51.69,203.45 51.69,200.75 51.78,200.66 51.99,200.66 52.08,200.75 52.08,205.52 52.17,205.61 52.39,205.61 52.48,205.52 52.48,200.09 52.57,200 52.78,200 52.87,200.09 52.87,201.54 52.96,201.63 53.17,201.63 53.26,201.54 53.26,198.47 63.46,188.28 63.46,186.47 68.3,181.64 76.15,181.64 79.98,177.8 81.94,177.8 v3(82.33,178.19)
M3_MDQ20: length 69.9
  TOP w0.118: v3(83.33,182.19) U22.BA39
  L14_INT_6 w0.087: J5.140 50.99,218 51.36,217.63 53.1,217.63 56.15,214.57 56.67,214.57 70.01,201.23 70.01,191.73 70.87,190.88 73.48,190.88 74.83,192.23 77.15,192.23 77.24,192.14 77.24,191.92 77.15,191.83 75.04,191.83 74.96,191.74 74.96,191.53 75.04,191.44 77.75,191.44 77.85,191.34 77.85,191.13 77.76,191.05 75.04,191.05 74.96,190.96 74.96,190.74 75.04,190.65 78.46,190.65 81.05,188.06 81.05,186.49 82.83,184.71 82.83,183.74 82.93,183.64 82.93,182.59 83.05,182.48 83.05,182.48 v3(83.33,182.19)
M3_MDQ21: length 69.9
  TOP w0.118: v3(83.33,181.19) U22.AY39
  L14_INT_6 w0.087: v3(83.33,181.19) 83.05,181.48 83.05,181.48 82.73,181.8 82.73,183.46 82.42,183.77 82.42,184.35 80.62,186.16 80.62,187.55 77.91,190.26 70.8,190.26 69.62,191.44 69.62,201.07 66.48,204.22 64.37,204.22 64.19,204.4 64.19,205.97 64.1,206.05 63.88,206.05 63.79,205.97 63.79,204.43 63.7,204.34 63.49,204.34 63.4,204.43 63.4,206.76 63.31,206.85 63.09,206.85 63,206.76 63,204.43 62.92,204.34 62.7,204.34 62.61,204.44 62.61,207.47 62.52,207.56 62.31,207.56 62.22,207.47 62.22,205.83 62.13,205.74 61.91,205.74 61.82,205.83 61.82,208.35 53.17,217 J5.141
M3_MDQ22: length 69.9
  TOP w0.118: U22.AW41 v3(82.33,179.19)
  L14_INT_6 w0.087: v3(82.33,179.19) 81.94,178.8 81.04,178.8 80.77,179.07 80.77,179.32 80.52,179.58 79.47,179.58 76.63,182.42 68.62,182.42 64.27,186.77 64.27,188.58 55.63,197.23 55.63,200.56 55.54,200.65 55.32,200.65 55.23,200.56 55.23,198.23 55.14,198.14 54.93,198.14 54.84,198.23 54.84,205.91 54.75,205.99 54.53,205.99 54.44,205.91 54.44,201.49 54.36,201.4 54.14,201.4 54.05,201.49 54.05,205.95 53.55,206.45 52.42,206.45 52.41,206.45 52.41,206.45 50.85,208.02 50.12,208.02 49.59,208.54 49.59,211.06 J5.146
M3_MDQ23: length 69.9
  TOP w0.118: U22.AV41 v3(81.33,179.19)
  L14_INT_6 w0.087: J5.147 50.88,211 50.9,210.98 51.95,210.98 52.2,210.74 52.2,208.18 52.1,208.09 51.89,208.09 51.8,208.17 51.8,210.27 51.71,210.36 51.5,210.36 51.41,210.28 51.41,208.01 52.57,206.85 55.04,206.85 55.23,206.65 55.23,201.16 55.32,201.07 55.54,201.07 55.63,201.16 55.63,205.94 55.73,206.04 55.91,206.04 56.02,205.93 56.02,197.39 64.67,188.74 64.67,186.93 65.12,186.49 66.93,186.49 67.51,185.9 67.51,184.09 68.79,182.82 77.09,182.82 78.04,181.86 78.04,181.56 79.79,179.81 81.15,179.81 81.33,179.63 v3(81.33,179.19)
M3_MDQ24: length 71.1
  TOP w0.118: v3(82.33,176.19) U22.AR40
  L5_INT_2 w0.087: J5.30 46.96,208 48.01,209.04 49.02,209.04 49.78,209.8 53.19,209.8 59.13,203.86 59.13,195.56 60.34,194.35 63.78,194.35 68.59,189.55 68.74,189.55 68.86,189.67 68.86,189.83 65.45,193.24 65.45,193.36 65.6,193.52 65.73,193.52 72.27,186.98 74.44,186.98 78.66,182.75 79.37,182.75 79.76,182.37 79.76,182.09 80.16,181.69 80.44,181.69 80.77,181.36 80.77,180.02 81.15,179.64 81.6,179.64 81.91,179.32 81.91,178.94 82.24,178.62 82.55,178.62 82.8,178.36 82.8,176.67 v3(82.33,176.19)
M3_MDQ25: length 71.1
  TOP w0.118: v3(81.33,176.19) U22.AR41
  L5_INT_2 w0.087: J5.31 48.88,207 49.66,207.77 53.49,207.77 56.38,204.89 56.38,193.15 56.46,193.06 56.68,193.06 56.77,193.15 56.77,198.92 56.86,199.01 57.07,199.01 57.16,198.92 57.16,193.41 57.5,193.08 59.96,193.08 61.35,191.69 61.35,187.69 63.25,185.79 73.87,185.79 78.96,180.71 78.96,178.41 79.66,177.7 80.42,177.7 80.87,177.24 80.87,176.65 81.05,176.48 81.05,176.48 v3(81.33,176.19)
M3_MDQ26: length 71.1
  TOP w0.118: v3(82.33,172.19) U22.AL40
  L5_INT_2 w0.087: v3(82.33,172.19) 81.72,172.81 80.14,172.81 80.02,172.92 78.92,172.92 75.72,176.12 72.54,176.12 70.03,178.64 64.85,178.64 64.75,178.74 64.75,178.93 64.85,179.03 70.27,179.03 70.37,179.13 70.37,179.32 70.27,179.43 55.78,179.43 54.86,180.34 54.86,182.18 52.1,184.95 52.1,198.73 50.8,200.03 49.91,200.03 48.89,201.04 48.13,201.04 47.17,202 J5.36
M3_MDQ27: length 71.1
  TOP w0.118: U22.AL41 v3(81.33,172.19)
  L5_INT_2 w0.087: v3(81.33,172.19) 80.95,172.58 78.71,172.58 75.56,175.73 72.15,175.73 69.7,178.18 57.24,178.18 57.14,178.28 57.14,178.47 57.24,178.57 64.16,178.57 64.26,178.68 64.26,178.87 64.16,178.97 54.46,178.97 51.69,181.74 51.69,197.36 51.05,197.99 50.16,197.99 49.15,199.01 48.26,199.01 47.56,199.71 47.56,200.19 J5.37
M3_MDQ28: length 71.1
  TOP w0.118: v3(82.33,177.19) U22.AT40
  L5_INT_2 w0.087: J5.149 53.42,209 53.46,208.96 57.95,204.47 57.95,196.73 58.04,196.64 58.25,196.64 58.34,196.73 58.34,203.53 58.43,203.62 58.65,203.62 58.74,203.53 58.74,195.07 59.84,193.96 63.6,193.96 70.3,187.26 70.43,187.26 70.58,187.41 70.58,187.54 68.99,189.13 68.99,189.25 69.15,189.4 69.27,189.4 72.09,186.58 74.25,186.58 79.9,180.93 79.9,179.89 80.09,179.71 80.39,179.71 80.77,179.32 80.77,179.07 81.15,178.69 81.41,178.69 81.91,178.18 81.91,177.61 82.05,177.48 82.05,177.48 v3(82.33,177.19)
M3_MDQ29: length 71.1
  TOP w0.118: v3(81.33,177.19) U22.AT41
  L5_INT_2 w0.087: v3(81.33,177.19) 81.33,177.6 80.85,178.08 80.85,178.36 80.54,178.66 80.09,178.66 79.5,179.25 79.5,180.74 74.05,186.19 63.75,186.19 61.75,188.19 61.75,191.85 60.05,193.55 58.83,193.55 58.34,194.03 58.34,196.16 58.25,196.25 58.04,196.25 57.95,196.16 57.95,193.61 57.86,193.52 57.65,193.52 57.56,193.61 57.56,204.25 57.47,204.34 57.25,204.34 57.16,204.25 57.16,199.49 57.07,199.4 56.86,199.4 56.77,199.49 56.77,205.07 53.61,208.23 48.88,208.23 J5.150
M3_MDQ30: length 71.1
  TOP w0.118: U22.AM40 v3(82.33,173.19)
  L5_INT_2 w0.087: v3(82.33,173.19) 81.74,173.79 79.17,173.79 72.7,180.26 63.36,180.26 63.26,180.37 63.26,180.56 63.36,180.66 71.78,180.66 71.88,180.76 71.88,180.95 71.78,181.05 57.41,181.05 52.91,185.55 52.91,200.64 J5.155
M3_MDQ31: length 71.1
  TOP w0.118: U22.AM41 v3(81.33,173.19)
  L5_INT_2 w0.087: v3(81.33,173.19) 80.94,173.58 80.11,173.58 79.91,173.38 79.02,173.38 75.75,176.66 73.61,176.66 73.02,177.24 73.02,178.56 72.52,179.07 70.88,179.07 70.79,179.16 70.79,179.37 70.88,179.46 72.4,179.46 72.49,179.55 72.49,179.77 72.4,179.86 56.64,179.86 56.54,179.96 56.54,180.15 56.64,180.25 62.54,180.25 62.65,180.36 62.65,180.55 62.55,180.64 57.26,180.64 52.5,185.4 52.5,200.36 50.86,202 J5.156
M3_MDQ32: length 71.1
  TOP w0.118: v3(82.33,169.19) U22.AH40
  L14_INT_6 w0.087: v3(82.33,169.19) 81.73,169.8 80.16,169.8 79.98,169.98 77.77,169.98 77.23,169.43 70.62,169.43 66.28,165.09 57.48,165.09 57.39,165 57.39,164.78 57.48,164.69 65.57,164.69 65.66,164.6 65.66,164.39 65.57,164.3 57.49,164.3 57.4,164.21 57.4,164 57.49,163.91 59.38,163.91 59.47,163.82 59.47,163.6 59.38,163.51 53.4,163.51 52.28,162.39 52.28,152.74 51.76,152.22 49.89,152.22 49.11,153 J5.81
M3_MDQ33: length 71.1
  TOP w0.118: v3(81.33,169.19) U22.AH41
  L14_INT_6 w0.087: v3(81.33,169.19) 80.95,169.57 78,169.57 77.47,169.04 70.89,169.04 65.76,163.91 60.03,163.91 59.94,163.82 59.94,163.6 60.03,163.51 62.9,163.51 62.99,163.42 62.99,163.21 62.9,163.12 53.68,163.12 53.59,163.03 53.59,162.81 53.68,162.72 60.97,162.72 61.06,162.64 61.06,162.42 60.97,162.33 55.24,162.33 52.7,159.79 52.7,152.53 51.97,151.79 49.81,151.79 49.15,151.13 47.88,151.13 47.01,152 J5.82
M3_MDQ34: length 71.1
  TOP w0.118: v3(83.33,165.19) U22.AD40
  L14_INT_6 w0.087: J5.87 48.83,147 50.07,145.77 50.98,145.77 54.23,142.52 62.73,142.52 62.81,142.61 62.81,142.82 62.73,142.91 55.24,142.91 55.16,143 55.16,143.22 55.24,143.31 63.35,143.31 64.76,144.72 64.76,148.69 65.68,149.61 65.68,156.18 70.69,161.19 77.65,161.19 79.3,162.84 79.3,163.75 81.12,165.58 82.95,165.58 v3(83.33,165.19)
M3_MDQ35: length 71.1
  TOP w0.118: v3(82.33,165.19) U22.AD41
  L14_INT_6 w0.087: J5.88 47.37,146 48.26,145.11 48.89,145.11 49.91,144.09 51.56,144.09 54.33,141.33 61.66,141.33 61.75,141.41 61.75,141.63 61.66,141.72 54.72,141.72 54.64,141.81 54.64,142.02 54.72,142.11 63.65,142.11 65.33,143.79 65.33,148.7 66.12,149.49 66.12,155.91 70.99,160.78 77.92,160.78 v3(82.33,165.19)
M3_MDQ36: length 71.1
  TOP w0.118: v3(82.33,170.19) U22.AJ40
  L14_INT_6 w0.087: v3(82.33,170.19) 81.93,170.19 81.32,170.8 77.33,170.8 76.75,170.22 70.14,170.22 67.46,167.54 54.39,167.54 54.3,167.45 54.3,167.17 54.39,167.08 65.75,167.08 65.84,166.99 65.84,166.78 65.75,166.69 52.9,166.69 51.5,165.29 51.5,154.75 50.75,154 J5.200
M3_MDQ37: length 71.1
  TOP w0.118: v3(81.33,170.19) U22.AJ41
  L14_INT_6 w0.087: J5.201 51.09,153.54 51.09,153.54 51.89,154.34 51.89,164.16 53.21,165.48 66.08,165.48 66.17,165.57 66.17,165.81 66.08,165.9 53.16,165.9 53.07,165.99 53.07,166.2 53.16,166.29 66.93,166.29 70.46,169.82 76.99,169.82 77.57,170.41 79.81,170.41 79.98,170.59 80.94,170.59 v3(81.33,170.19)
M3_MDQ38: length 71.1
  TOP w0.118: U22.AE40 v3(83.33,166.19)
  L14_INT_6 w0.087: v3(83.33,166.19) 82.95,165.81 80.72,165.81 78.87,163.96 78.87,162.97 77.56,161.67 70.48,161.67 65.25,156.44 65.25,149.74 64.36,148.85 64.36,144.91 63.96,144.5 54.2,144.5 54.11,144.41 54.11,144.2 54.2,144.11 62.75,144.11 62.84,144.02 62.84,143.8 62.75,143.71 53.64,143.71 51.13,146.23 50.16,146.23 49.4,146.99 49.4,147.19 48.65,147.95 J5.206
M3_MDQ39: length 71.1
  TOP w0.118: U22.AE41 v3(82.33,166.19)
  L14_INT_6 w0.087: J5.207 50.87,147 50.91,146.97 51.57,146.97 52.13,146.4 52.13,145.83 52.96,145.01 63.79,145.01 63.88,145.1 63.88,145.31 63.79,145.4 53.23,145.4 53.14,145.49 53.14,145.71 53.23,145.8 63.04,145.8 63.28,146.03 63.28,146.87 63.97,147.57 63.97,149.01 64.85,149.89 64.85,157.02 69.89,162.06 77.25,162.06 77.53,162.34 77.53,163.56 79.88,165.92 79.88,166.37 80.26,166.75 81.77,166.75 v3(82.33,166.19)
M3_MDQ40: length 71.4
  TOP w0.118: v3(84.33,169.19) U22.AH38
  L5_INT_2 w0.087: J5.90 44.85,143.23 45.97,142.11 47.12,142.11 47.77,142.77 49.23,142.77 50.23,143.77 51.01,143.77 52.69,145.45 52.69,157.33 53.96,158.6 53.96,162.54 55.75,164.34 55.75,166.5 56.77,167.51 56.77,170.05 58.36,171.64 60.11,171.64 60.4,171.93 68.27,171.93 68.36,172.02 68.36,172.24 68.27,172.33 66.67,172.33 66.58,172.41 66.58,172.62 66.68,172.72 69.07,172.72 69.89,171.9 77.1,171.9 78.48,170.52 78.83,170.52 79.76,169.6 83.93,169.6 v3(84.33,169.19)
M3_MDQ41: length 71.4
  TOP w0.118: v3(85.33,169.19) U22.AH37
  L5_INT_2 w0.087: J5.91 46.98,143.23 48.97,143.23 49.9,144.16 50.84,144.16 52.29,145.61 52.29,163.93 56.13,167.77 56.13,170.33 58.03,172.22 59.91,172.22 60.12,172.44 65.51,172.44 65.6,172.53 65.6,172.75 65.51,172.83 62.97,172.83 62.88,172.92 62.88,173.14 62.97,173.23 69.21,173.23 70.15,172.29 77.26,172.29 78.64,170.92 79.02,170.92 80.14,169.8 84.73,169.8 v3(85.33,169.19)
M3_MDQ42: length 71.4
  TOP w0.118: v3(85.33,165.19) U22.AD38
  L5_INT_2 w0.087: v3(85.33,165.19) 84.92,165.61 81.03,165.61 80.9,165.74 79.12,165.74 78.74,166.12 78.31,166.12 77.57,166.85 74.83,166.85 74.27,167.41 66.25,167.41 61.15,162.3 61.15,160.21 58.21,157.27 58.21,141.13 58.11,141.03 57.9,141.03 57.81,141.12 57.81,143.39 57.72,143.48 57.51,143.48 57.42,143.39 57.42,139.21 55.99,137.78 49.64,137.78 49.09,137.23 47.81,137.23 47.04,138 J5.96
M3_MDQ43: length 71.4
  TOP w0.118: v3(86.33,165.19) U22.AD37
  L5_INT_2 w0.087: v3(86.33,165.19) 85.91,164.78 81.1,164.78 80.64,165.23 78.99,165.23 78.61,165.61 78.23,165.61 77.47,166.37 74.75,166.37 74.11,167.01 66.41,167.01 61.58,162.18 61.58,160.03 58.6,157.05 58.6,138.35 58.51,138.25 58.29,138.25 58.2,138.34 58.2,140.55 58.11,140.64 57.9,140.64 57.81,140.55 57.81,138.2 55.75,136.14 49.91,136.14 49.28,136.78 46.97,136.78 J5.97
M3_MDQ44: length 71.4
  TOP w0.118: v3(84.33,170.19) U22.AJ38
  L5_INT_2 w0.087: v3(84.33,170.19) 83.84,170.69 80.26,170.69 79.64,171.31 78.81,171.31 77.4,172.72 75.65,172.72 75.18,173.18 69.84,173.18 69.4,173.62 62.22,173.62 62.13,173.71 62.13,173.92 62.23,174.02 67.12,174.02 67.21,174.1 67.21,174.32 67.12,174.41 58.97,174.41 55.05,170.5 55.05,167.32 51.9,164.17 51.9,145.88 51.02,145 J5.209
M3_MDQ45: length 71.4
  TOP w0.118: v3(85.33,170.19) U22.AJ37
  L5_INT_2 w0.087: J5.210 48.65,144.77 49.8,145.92 51.05,145.92 51.5,146.37 51.5,164.53 54.38,167.41 54.38,171.15 58.04,174.8 69.95,174.8 70.04,174.71 70.04,174.5 69.95,174.41 67.72,174.41 67.63,174.32 67.63,174.1 67.72,174.02 70.14,174.02 70.88,174.75 74.75,174.75 76.33,173.18 77.5,173.18 78.97,171.7 84.45,171.7 84.84,171.32 84.84,170.69 v3(85.33,170.19)
M3_MDQ46: length 71.4
  TOP w0.118: U22.AE38 v3(84.33,166.19)
  L5_INT_2 w0.087: v3(84.33,166.19) 84.33,166.37 83.88,166.81 78.79,166.81 77.97,167.64 75.15,167.64 74.45,168.34 66.08,168.34 57.42,159.69 57.42,148.3 57.33,148.21 57.11,148.21 57.02,148.3 57.02,154.09 56.93,154.18 56.72,154.18 56.63,154.09 56.63,139.61 55.7,138.68 50.87,138.68 J5.215
M3_MDQ47: length 71.4
  TOP w0.118: U22.AE37 v3(86.33,166.19)
  L5_INT_2 w0.087: J5.216 48.83,138.18 55.83,138.18 57.02,139.37 57.02,147.73 57.11,147.82 57.33,147.82 57.42,147.73 57.42,143.98 57.51,143.89 57.72,143.89 57.82,143.98 57.82,159.53 66.24,167.95 74.29,167.95 74.99,167.25 77.77,167.25 78.44,166.58 83.51,166.58 83.82,166.27 83.82,166.12 84.12,165.81 85.95,165.81 v3(86.33,166.19)
M3_MDQ48: length 70.9
  TOP w0.118: U22.AG35 v3(87.33,168.19)
  L3_INT_1 w0.087: v3(87.33,168.19) 86.95,167.81 84.99,167.81 83.72,166.54 83.72,164.74 82.83,163.85 74.68,163.85 74.24,164.29 66.85,164.29 61.16,158.6 61.16,153.06 56.94,148.84 56.94,139.81 56.85,139.73 56.64,139.73 56.55,139.81 56.55,141.91 56.46,142 56.24,142 56.15,141.91 56.15,138.22 52.17,134.23 49.79,134.23 49.02,135 J5.99
M3_MDQ49: length 70.9
  TOP w0.118: U22.AG34 v3(88.33,168.19)
  L3_INT_1 w0.087: v3(88.33,168.19) 87.71,167.58 85.1,167.58 83.92,166.4 83.92,164.62 82.91,163.6 74.08,163.6 73.8,163.88 67,163.88 61.56,158.44 61.56,152.84 57.33,148.62 57.33,138.65 57.24,138.56 57.03,138.56 56.94,138.65 56.94,139.09 56.85,139.18 56.64,139.18 56.55,139.09 56.55,138.05 52.33,133.84 49.66,133.84 48.92,133.1 48.03,133.1 47.13,134 J5.100
M3_MDQ50: length 70.9
  TOP w0.118: U22.AC35 v3(87.33,163.2)
  L3_INT_1 w0.087: J5.105 48.8,129 49.96,127.84 53.85,127.84 62.51,136.5 62.51,138.57 62.6,138.66 62.82,138.66 62.9,138.57 62.9,136.76 62.99,136.68 63.2,136.68 63.3,136.77 63.3,141.58 66.05,144.34 66.05,153.35 69.29,156.59 73.43,156.59 76.17,159.33 80.59,159.33 81.05,159.79 87.53,159.79 87.73,159.99 87.73,162.79 v3(87.33,163.19)
M3_MDQ51: length 70.9
  TOP w0.118: U22.AC34 v3(88.33,163.2)
  L3_INT_1 w0.087: v3(88.33,163.19) 88.77,162.75 88.77,159.99 88.35,159.57 81.36,159.57 80.74,158.94 76.34,158.94 73.57,156.17 69.43,156.17 66.47,153.22 66.47,143.91 63.7,141.14 63.7,136.62 53.25,126.17 49.98,126.17 49.15,127 48.13,127 47.13,128 J5.106
M3_MDQ52: length 70.9
  TOP w0.118: v3(87.33,169.19) U22.AH35
  L3_INT_1 w0.087: J5.218 52.05,136 55.37,139.31 55.37,149.47 55.45,149.56 55.67,149.56 55.76,149.47 55.76,146.9 55.85,146.81 56.06,146.81 56.15,146.9 56.15,154.71 67.56,166.12 73.81,166.12 75.51,164.41 81.28,164.41 81.86,165 81.86,168.48 82.19,168.81 86.94,168.81 v3(87.33,169.19)
M3_MDQ53: length 70.9
  TOP w0.118: v3(88.33,169.19) U22.AH34
  L3_INT_1 w0.087: v3(88.33,169.19) 87.73,168.59 84.57,168.59 83.69,167.72 83.18,167.72 82.93,167.46 82.93,165.13 81.89,164.08 75.06,164.08 74.42,164.72 66.72,164.72 56.55,154.54 56.55,142.71 56.46,142.62 56.24,142.62 56.15,142.71 56.15,146.12 56.06,146.21 55.85,146.21 55.76,146.12 55.76,138.56 52.2,135 J5.219
M3_MDQ54: length 70.9
  TOP w0.118: v3(88.33,165.19) U22.AD35
  L3_INT_1 w0.087: v3(88.33,165.19) 88.33,164.85 86.94,163.46 86.94,160.93 86.59,160.58 79.96,160.58 79.81,160.43 79.81,159.92 79.65,159.77 76.05,159.77 75.2,158.92 69.41,158.92 65.66,155.17 65.66,146.25 62.89,143.48 62.89,139.16 62.8,139.07 62.59,139.07 62.5,139.16 62.5,140.73 62.41,140.82 62.19,140.82 62.1,140.73 62.1,137.03 53.3,128.23 50.13,128.23 49.43,128.93 49.43,129.22 J5.224
M3_MDQ55: length 70.9
  TOP w0.118: U22.AD34 v3(89.33,165.19)
  L3_INT_1 w0.087: J5.225 50.92,128.63 52.93,128.63 61.68,137.38 61.68,143.85 61.77,143.94 61.99,143.94 62.08,143.85 62.08,141.43 62.17,141.34 62.38,141.34 62.47,141.43 62.47,143.93 65.27,146.72 65.27,155.33 69.25,159.32 74.83,159.32 76.3,160.78 86.48,160.78 86.72,161.03 86.72,163.59 87.88,164.75 87.88,165.35 88.14,165.61 88.92,165.61 v3(89.33,165.19)
M3_MDQ56: length 73.6
  TOP w0.118: v3(83.33,163.19) U22.AB40
  L5_INT_2 w0.087: J5.108 44.85,126.51 46.35,128.02 47.12,128.02 47.75,128.65 47.75,130.43 48.26,130.94 49.02,130.94 50.04,131.95 50.7,131.95 53.57,134.82 56.55,134.82 60.08,138.34 60.08,151.86 60.18,151.97 60.38,151.97 60.47,151.88 60.47,150.68 60.56,150.58 60.78,150.58 60.86,150.67 60.86,157.71 62.93,159.79 62.93,162.14 66,165.21 70.22,165.21 71.04,166.03 73.71,166.03 74.47,165.27 77.17,165.27 77.72,164.72 80.01,164.72 80.52,164.21 82.31,164.21 v3(83.33,163.19)
M3_MDQ57: length 73.6
  TOP w0.118: U22.AA40 v3(83.33,162.2)
  L5_INT_2 w0.087: v3(83.33,162.2) 83.33,162.54 82.8,163.07 82.8,163.32 82.42,163.7 79.76,163.7 79.33,164.13 77.75,164.13 77.48,164.41 75.06,164.41 74.87,164.59 65.94,164.59 63.33,161.98 63.33,159.54 61.26,157.47 61.26,148.26 61.17,148.17 60.95,148.17 60.86,148.26 60.86,149.77 60.78,149.86 60.56,149.86 60.47,149.77 60.47,138.21 60.47,138.21 60.47,138.18 56.72,134.43 53.73,134.43 51.62,132.32 51.62,130.46 51.09,129.92 50.04,129.92 49.66,129.54 49.66,127.51 49.15,127 48.13,127 46.75,125.62 J5.109
M3_MDQ58: length 73.6
  TOP w0.118: v3(86.33,162.2) U22.AB36
  L5_INT_2 w0.087: v3(86.33,162.2) 86.7,161.82 86.7,158.71 85.72,157.73 74.04,157.73 72.75,156.45 70.06,156.45 66.3,152.69 66.3,136.72 59.12,129.54 59.12,127.26 51.63,119.77 50.05,119.77 49.51,119.23 48.03,119.23 47.26,120 J5.114
M3_MDQ59: length 73.6
  TOP w0.118: U22.AA36 v3(87.33,161.2)
  L5_INT_2 w0.087: J5.115 46.98,118.77 49.39,118.77 50.22,117.94 52.24,117.94 59.51,125.21 59.51,129.35 63.22,133.07 63.85,133.07 66.96,136.18 66.96,139.25 66.69,139.52 66.69,152.37 69.26,154.94 73.97,154.94 76.05,157.02 80.87,157.02 81.13,156.77 85.33,156.77 86.94,158.38 86.94,160.81 v3(87.33,161.2)
M3_MDQ60: length 73.6
  TOP w0.118: U22.AB41 v3(82.33,162.2)
  L5_INT_2 w0.087: J5.227 52.02,128.47 52.02,132.16 53.86,134 56.89,134 60.86,137.98 60.86,147.66 60.96,147.75 61.17,147.75 61.26,147.67 61.26,142.77 61.35,142.69 61.56,142.69 61.65,142.77 61.65,157.21 63.72,159.28 63.72,161.82 66.1,164.2 74.42,164.2 74.61,164.01 77.31,164.01 77.71,163.61 78.49,163.61 78.9,163.19 80.77,163.19 81.28,162.69 81.84,162.69 v3(82.33,162.2)
M3_MDQ61: length 73.6
  TOP w0.118: v3(81.32,162.2) 81.82,161.69 U22.AA41
  L5_INT_2 w0.087: J5.228 51.6,126 52.41,126.81 52.41,131.99 54.03,133.61 55.22,133.61 55.41,133.43 55.41,132.75 55.58,132.57 56.05,132.57 61.26,137.78 61.26,142.14 61.35,142.22 61.56,142.22 61.65,142.14 61.65,138.82 61.74,138.74 61.96,138.74 62.05,138.82 62.05,156.97 64.12,159.04 64.12,161.65 66.27,163.8 74.09,163.8 74.28,163.62 76.99,163.62 77.88,162.74 80.59,162.74 81.14,162.2 v3(81.32,162.2)
M3_MDQ62: length 73.6
  TOP w0.118: U22.AB37 85.83,162.7 v3(85.33,163.19)
  L5_INT_2 w0.087: v3(85.33,163.19) 85.89,162.64 85.89,161.21 85.71,161.04 85.71,160.01 85.47,159.77 78.84,159.77 78.41,159.33 69.8,159.33 67.11,156.64 67.11,154.75 67.02,154.66 66.8,154.66 66.71,154.75 66.71,156.02 66.62,156.11 66.41,156.11 66.32,156.02 66.32,154.04 66.23,153.95 66.01,153.95 65.93,154.04 65.93,155.28 65.84,155.36 65.61,155.36 65.51,155.27 65.51,137.12 65.51,137.11 65.51,137.11 58.31,129.9 58.31,127.71 58.3,127.7 58.3,127.66 51.63,121 J5.233
M3_MDQ63: length 73.6
  TOP w0.118: U22.AA37 v3(86.33,161.2)
  L5_INT_2 w0.087: J5.234 49.42,120 49.65,120.23 51.42,120.23 58.72,127.53 58.72,129.72 65.91,136.9 65.91,152.95 67.59,154.64 67.59,156.49 67.68,156.58 67.89,156.58 67.98,156.49 67.98,155.4 68.07,155.31 68.29,155.31 68.38,155.4 68.38,157.07 68.47,157.16 68.68,157.16 68.77,157.07 68.77,156.21 68.86,156.12 69.08,156.12 69.16,156.21 69.16,158.13 69.97,158.93 76.72,158.93 76.96,158.69 85.53,158.69 85.95,159.1 85.95,160.81 v3(86.33,161.2)
M3_MDQS_N0: length 82.3
  TOP w0.091: U22.BA36 v3(87.33,182.19)
  L14_INT_6 w0.1: v3(87.33,182.19) 87.33,181.95 87.18,181.8 87.05,181.8 86.92,181.92 86.92,184.45 86.66,184.71 86.66,184.76 86.46,184.97 86.46,188.04 85.83,188.67 84.84,188.67 84.33,189.18 84.33,189.88 79.01,195.2 79.01,196.75 77.46,198.3 77.46,203.41 76.81,204.06 75.64,204.06 74.47,202.89 73.28,202.89 60.05,216.11 60.05,220.27 59.8,220.52 58.81,220.52 58.55,220.27 58.55,218.56 58.45,218.46 57.67,218.46 57.56,218.56 57.56,224.98 52.14,230.4 51.33,230.4 51.13,230.2 50.19,230.2 49.25,231.14 48.34,231.14 47.37,232.11 46.22,232.11 45.84,231.72 45.12,231.72 J5.6
M3_MDQS_N1: length 81
  TOP w0.091: v3(85.33,176.19) U22.AR37
  L5_INT_2 w0.1: J5.15 46.27,223 46.06,222.8 46.06,222.55 46.55,222.07 47.29,222.07 48.18,221.18 49.1,221.18 49.96,222.05 53.52,222.05 57.68,217.89 57.68,210.38 57.78,210.28 58.57,210.28 58.67,210.38 58.67,212.37 58.92,212.62 59.92,212.62 60.17,212.37 60.17,208.16 61.12,207.21 66.06,207.21 71.06,202.21 71.06,198.87 72.07,197.87 76.42,197.87 77.57,196.71 77.57,193.02 85.95,184.64 85.95,176.77 85.72,176.55 85.41,176.55 85.33,176.46 v3(85.33,176.19)
M3_MDQS_N2: length 69.9
  TOP w0.091: v3(83.33,180.19) U22.AW39
  L14_INT_6 w0.1: v3(83.33,180.19) 83.33,179.93 83.2,179.8 83.06,179.8 82.91,179.94 82.91,180.46 82.58,180.8 80.06,180.8 80.04,180.82 79.65,180.82 78.84,181.64 78.84,182.55 77.34,184.05 72.74,184.05 72.06,184.73 70.46,184.73 70.23,184.51 68.85,184.51 68.75,184.61 68.75,185.39 68.85,185.5 69.87,185.5 70.18,185.81 70.18,186.68 69.87,186.99 68.17,186.99 57.31,197.85 57.31,206.39 55.85,207.85 55.85,209.85 55.54,210.16 54.65,210.16 54.36,209.87 54.36,208.18 54.25,208.08 53.69,208.08 53.45,208.32 53.45,211.6 52.83,212.22 50.16,212.22 49.25,213.13 48.21,213.13 47.17,214.17 46.22,214.17 45.59,213.54 45.31,213.54 J5.24
M3_MDQS_N3: length 71.2
  TOP w0.091: v3(82.33,174.19) U22.AN40
  L5_INT_2 w0.1: v3(82.33,174.19) 82.04,174.19 81.92,174.32 81.92,174.57 81.68,174.8 79.13,174.8 78.94,174.99 78.94,175.95 72.52,182.37 68.94,182.37 67.75,183.57 57.95,183.57 56.64,184.88 56.64,190.5 56.39,190.75 55.39,190.75 55.14,190.5 55.14,186.19 55.04,186.09 54.25,186.09 54.15,186.19 54.15,201.99 51.92,204.22 50.16,204.22 49.02,203.07 48.37,203.07 47.35,204.09 46.46,204.09 46.08,204.47 46.08,204.75 46.33,205 J5.33
M3_MDQS_N4: length 71.2
  TOP w0.091: v3(82.33,167.19) U22.AF40
  L14_INT_6 w0.1: J5.84 44.87,150 45.21,149.66 45.67,149.66 46.1,150.09 47.27,150.09 48.26,149.1 49.25,149.1 50.14,148.21 52.07,148.21 53.24,147.04 61.75,147.04 61.85,147.14 61.85,147.93 61.75,148.03 54.4,148.03 54.13,148.31 54.13,149.26 54.4,149.53 62.73,149.53 63.58,150.37 63.58,159.33 65.46,161.21 66.57,161.21 69.57,164.21 73.76,164.21 74.4,164.85 74.4,165.99 75.08,166.67 77.83,166.67 79.01,167.86 79.96,167.86 80.01,167.8 81.7,167.8 82.01,167.5 82.01,167.27 82.08,167.19 v3(82.33,167.19)
M3_MDQS_N5: length 71.4
  TOP w0.091: v3(85.33,167.19) U22.AF38
  L5_INT_2 w0.1: v3(85.33,167.19) 84.96,166.83 84.76,166.83 83.77,167.81 79.81,167.81 79.78,167.84 79.15,167.84 78.39,168.61 77.24,168.61 76.18,169.67 65.65,169.67 56.18,160.2 56.18,155.46 55.08,154.36 55.08,143.07 54.58,142.57 53.09,142.57 52.84,142.32 52.84,141.32 53.09,141.07 55.29,141.07 55.39,140.97 55.39,140.18 55.29,140.08 49.91,140.08 49.02,139.19 48.24,139.19 47.22,140.21 46.21,140.21 45.9,140.52 45.9,140.82 46.08,141 J5.93
M3_MDQS_N6: length 70.9
  TOP w0.091: v3(87.33,166.19) U22.AE35
  L3_INT_1 w0.1: v3(87.33,166.19) 87.69,166.19 87.76,166.12 87.76,165.93 87.62,165.79 87.05,165.79 86.72,165.46 86.72,164.44 85.72,163.45 85.72,162.03 85.47,161.78 81,161.78 80.97,161.81 75.12,161.81 73.86,160.55 68.37,160.55 66.95,159.13 65.75,159.13 63.99,157.37 63.99,147.91 59.69,143.62 59.69,137.49 52.37,130.18 50.16,130.18 49.28,131.06 48.24,131.06 47.1,132.21 46.35,132.21 45.75,131.6 45.25,131.6 J5.102
M3_MDQS_N7: length 73.6
  TOP w0.091: U22.AB38 v3(85.33,162.2)
  L5_INT_2 w0.1: J5.111 45.96,123 45.82,122.86 45.82,122.69 46.39,122.12 47.15,122.12 48.11,121.16 49.12,121.16 50.08,122.12 50.97,122.12 57.07,128.22 57.07,130.41 64.27,137.62 64.27,155.82 67.61,159.16 67.61,161.09 67.97,161.44 68.81,161.44 69.11,161.14 69.11,160.68 69.22,160.58 76.17,160.58 76.44,160.84 81.03,160.84 81.06,160.81 84.5,160.81 84.72,161.03 84.72,161.56 84.94,161.77 85.18,161.77 85.33,161.93 v3(85.33,162.2)
M3_MDQS_N8: length 71.3
  TOP w0.091: v3(85.33,172.19) U22.AL37
  L14_INT_6 w0.1: J5.42 45.12,195.73 45.68,195.73 46.16,196.22 47.24,196.22 47.75,195.71 47.75,195.45 48.01,195.2 49,195.2 50.02,194.18 51.16,194.18 54.91,190.43 54.91,178.79 57.56,176.15 61.59,176.15 63.86,173.89 68.65,173.89 68.75,173.99 68.75,174.78 68.65,174.88 64.31,174.88 64.06,175.13 64.06,176.13 64.31,176.38 70.11,176.38 71.56,174.93 76.02,174.93 77.16,173.79 80.05,173.79 80.08,173.81 82.62,173.81 82.93,173.51 82.93,173.03 83.16,172.8 84.7,172.8 84.93,172.57 84.93,172.34 85.08,172.19 v3(85.33,172.19)
M3_MDQS_N9: length 82.2
  TOP w0.091: v3(86.33,179.19) U22.AV36
  L14_INT_6 w0.1: v3(86.33,179.19) 86.33,178.9 86.43,178.8 86.61,178.8 86.74,178.93 86.74,179.74 87.74,180.73 87.74,184.44 87.49,184.69 87.38,184.8 87.38,189.67 86.14,190.91 84.79,190.91 80,195.7 80,197.24 78.87,198.37 78.87,203.45 75.76,206.56 74.35,206.56 73.35,205.56 72.04,205.56 61.11,216.5 61.11,222.78 60.93,222.96 60.2,222.96 60.1,222.86 60.1,221.76 59.85,221.51 58.85,221.51 58.6,221.76 58.6,225.35 52.15,231.8 50.11,231.8 49.25,232.66 48.85,232.66 48.65,232.46 J5.126
M3_MDQS_N10: length 80.9
  TOP w0.091: v3(86.33,176.19) U22.AR36
  L5_INT_2 w0.1: v3(86.33,176.19) 86.33,175.83 86.42,175.74 86.58,175.74 86.75,175.91 86.75,184.5 86.71,184.53 86.71,185.09 86.23,185.57 86.23,187.86 85.68,188.42 84.7,188.42 78.82,194.31 78.82,198.06 75.58,201.29 73.38,201.29 66.47,208.2 64.08,208.2 63.65,208.64 63.65,209.64 63.55,209.74 62.76,209.74 62.66,209.64 62.66,208.66 62.41,208.41 61.41,208.41 61.16,208.66 61.16,215.8 61.06,215.9 60.27,215.9 60.17,215.8 60.17,214.09 59.92,213.84 58.92,213.84 58.67,214.09 58.67,218.31 53.09,223.9 49.89,223.9 49.45,223.47 49.45,223.19 49.64,223 J5.135
M3_MDQS_N11: length 69.9
  TOP w0.091: v3(81.33,181.19) U22.AY41
  L14_INT_6 w0.1: v3(81.33,181.19) 81.33,181.42 81.2,181.55 80.95,181.55 80.71,181.79 80.71,182.56 80.7,182.58 80.7,182.85 80.29,183.26 79.75,183.26 79.37,183.64 79.37,184.43 78.35,185.45 72.74,185.45 72.26,185.93 72.26,186.87 72.51,187.12 75.21,187.12 75.31,187.22 75.31,187.99 75.19,188.11 68.81,188.11 65.53,191.39 65.53,192.02 65.35,192.2 64.37,192.2 64.12,192.45 64.12,193.45 64.37,193.7 67.37,193.7 67.47,193.8 67.47,194.4 67.31,194.56 62,194.56 58.67,197.88 58.67,206.43 57.66,207.45 57.66,209.46 53.25,213.87 50,213.87 49.39,214.49 49.14,214.49 J5.144
M3_MDQS_N12: length 71.1
  TOP w0.091: U22.AP41 v3(81.33,175.19)
  L5_INT_2 w0.1: v3(81.33,175.19) 81.6,175.19 81.71,175.31 81.71,175.51 81.61,175.61 80.07,175.61 79.73,175.95 79.73,176.38 79.5,176.61 78.92,176.61 78.23,177.29 78.23,179.45 73.13,184.56 61.97,184.56 60.12,186.41 60.12,191.17 60.01,191.27 59.23,191.27 59.12,191.17 59.12,185.31 58.87,185.06 57.88,185.06 57.63,185.31 57.63,191.6 57.4,191.82 55.72,191.82 55.14,192.4 55.14,204.2 53.47,205.87 49.91,205.87 49.5,205.46 49.5,205.2 49.71,205 J5.153
M3_MDQS_N13: length 71.2
  TOP w0.091: U22.AG41 v3(81.33,168.19)
  L14_INT_6 w0.1: J5.204 49.09,150.44 49.56,150.44 50.16,149.85 53.25,149.85 54.08,150.67 61.8,150.67 62.22,151.09 62.22,151.92 61.97,152.17 55.27,152.17 55.17,152.27 55.17,153.06 55.27,153.16 58.3,153.16 58.55,153.41 58.55,154.41 58.3,154.66 55.45,154.66 55.24,154.87 55.24,155.44 55.45,155.65 58.25,155.65 58.5,155.9 58.5,156.9 58.25,157.15 56.57,157.15 56.46,157.25 56.46,158.04 56.57,158.14 60.99,158.14 61.72,158.88 61.72,160.15 63.78,162.2 66.09,162.2 69.26,165.38 71.14,167.26 76.99,167.26 78.33,168.61 81.6,168.61 81.75,168.45 81.75,168.27 81.68,168.19 v3(81.33,168.19)
M3_MDQS_N14: length 71.4
  TOP w0.091: U22.AG37 v3(86.33,168.19)
  L5_INT_2 w0.1: v3(86.33,168.19) 86,168.19 85.92,168.11 85.92,167.86 85.64,167.58 85.08,167.58 84.08,168.58 80.01,168.58 79.98,168.55 79.44,168.55 78.45,169.54 77.7,169.54 76.59,170.66 61.5,170.66 60.78,169.95 60.78,166.2 60.53,165.95 59.53,165.95 59.28,166.2 59.28,169.61 59.18,169.71 58.39,169.71 58.29,169.61 58.29,164.59 55.19,161.49 55.19,155.87 54.09,154.77 54.09,145.02 50.93,141.86 50.17,141.86 49.78,141.47 49.78,141.2 49.98,141 J5.213
M3_MDQS_N15: length 71
  TOP w0.091: v3(88.33,167.19) U22.AF34
  L3_INT_1 w0.1: v3(88.33,167.19) 88.04,167.19 87.94,167.1 87.94,166.81 87.71,166.58 86.07,166.58 85.93,166.44 85.93,164.66 84.93,163.66 84.93,162.87 84.66,162.6 80.92,162.6 80.89,162.57 80.52,162.57 80.42,162.67 79.32,162.67 79,162.36 74.25,162.36 73.69,161.8 66.67,161.8 62.87,158 62.87,152.28 61.16,150.57 61.16,146.65 60.86,146.34 59.99,146.34 59.66,146.66 59.66,148.02 59.44,148.24 58.9,148.24 58.67,148.02 58.67,138 52.63,131.95 49.78,131.95 49.35,132.38 49.03,132.38 J5.222
M3_MDQS_N16: length 73.6
  TOP w0.091: U22.AA39 v3(84.33,161.2)
  L5_INT_2 w0.1: v3(84.33,161.2) 83.94,161.58 80.92,161.58 80.9,161.55 79.82,161.55 79.47,161.9 69.82,161.9 69.16,162.56 67.28,162.56 65.35,160.64 65.35,158.44 63.28,156.37 63.28,138.03 56.07,130.82 56.07,128.82 55.78,128.53 54.93,128.53 54.65,128.8 54.65,131.42 54.44,131.63 53.87,131.63 53.66,131.42 53.66,126.31 51.23,123.88 50.1,123.88 49.73,123.51 49.73,123.16 49.9,123 J5.231
M3_MDQS_N17: length 71.3
  TOP w0.091: U22.AM38 v3(84.33,173.19)
  L14_INT_6 w0.1: J5.162 49.22,196.57 49.48,196.57 50.17,195.88 51.05,195.88 58.42,188.51 58.42,183.67 58.32,183.57 57.53,183.57 57.43,183.67 57.43,188.13 57.18,188.38 56.18,188.38 55.93,188.13 55.93,182.21 56.26,181.88 56.26,180.34 56.74,179.86 59.11,179.86 59.21,179.76 59.21,178.97 59.11,178.87 57.75,178.87 57.5,178.62 57.5,177.62 57.75,177.37 70.94,177.37 72.36,175.95 73.84,175.95 74.71,176.82 75.58,176.82 77.8,174.6 83.57,174.6 83.74,174.42 83.74,173.94 84.07,173.61 84.56,173.61 84.68,173.48 84.68,173.35 84.52,173.19 v3(84.33,173.19)
M3_MDQS_P0: length 82.3
  TOP w0.091: U22.AY36 v3(87.33,181.19)
  L14_INT_6 w0.1: J5.7 46.04,231 45.88,231.15 45.88,231.41 46.33,231.85 47.27,231.85 48.23,230.89 49.15,230.89 50.09,229.95 51.23,229.95 51.43,230.15 52.04,230.15 57.31,224.88 57.31,218.46 57.56,218.21 58.56,218.21 58.81,218.46 58.81,220.16 58.91,220.27 59.7,220.27 59.8,220.16 59.8,216.01 73.17,202.63 74.58,202.63 75.75,203.8 76.7,203.8 77.21,203.3 77.21,198.19 78.75,196.65 78.75,195.1 84.07,189.78 84.07,189.07 84.73,188.42 85.72,188.42 86.21,187.93 86.21,184.86 86.48,184.58 86.5,184.58 86.72,184.37 86.72,181.83 86.96,181.59 87.19,181.59 87.33,181.45 v3(87.33,181.19)
M3_MDQS_P1: length 80.9
  TOP w0.091: v3(85.33,177.19) U22.AT37
  L5_INT_2 w0.1: J5.16 45.43,222.58 45.68,222.58 46.44,221.82 47.19,221.82 48.08,220.93 49.23,220.93 50.09,221.79 53.42,221.79 57.43,217.78 57.43,210.27 57.68,210.02 58.68,210.02 58.93,210.27 58.93,212.27 59.03,212.37 59.82,212.37 59.92,212.27 59.92,208.05 61.01,206.96 65.96,206.96 70.81,202.11 70.81,198.76 71.96,197.61 76.31,197.61 77.32,196.61 77.32,192.91 85.75,184.49 85.75,176.86 85.64,176.75 85.44,176.75 85.33,176.86 v3(85.33,177.19)
M3_MDQS_P2: length 69.9
  TOP w0.091: v3(83.33,179.19) U22.AV39
  L14_INT_6 w0.1: v3(83.33,179.19) 83.33,179.46 83.2,179.59 82.97,179.59 82.71,179.86 82.71,180.37 82.49,180.59 80.04,180.59 80.01,180.57 79.55,180.57 78.59,181.53 78.59,182.45 77.23,183.8 72.63,183.8 71.95,184.48 70.56,184.48 70.33,184.25 68.75,184.25 68.5,184.5 68.5,185.5 68.75,185.75 69.77,185.75 69.93,185.91 69.93,186.58 69.77,186.74 68.06,186.74 57.05,197.75 57.05,206.29 55.6,207.74 55.6,209.74 55.43,209.91 54.76,209.91 54.61,209.76 54.61,208.08 54.36,207.83 53.58,207.83 53.2,208.21 53.2,211.49 52.73,211.96 50.06,211.96 49.14,212.88 48.11,212.88 47.07,213.92 46.33,213.92 45.82,213.41 45.82,213.16 45.98,213 J5.25
M3_MDQS_P3: length 71.2
  TOP w0.091: v3(81.33,174.19) U22.AN41
  L5_INT_2 w0.1: J5.34 45.26,204.41 45.78,204.41 46.35,203.84 47.24,203.84 48.26,202.82 49.13,202.82 50.27,203.96 51.82,203.96 53.89,201.89 53.89,186.09 54.14,185.84 55.14,185.84 55.39,186.09 55.39,190.4 55.49,190.5 56.28,190.5 56.38,190.4 56.38,184.77 57.84,183.31 67.64,183.31 68.83,182.12 72.41,182.12 78.74,175.79 78.74,174.9 79.04,174.6 81.6,174.6 81.72,174.49 81.72,174.29 81.62,174.19 v3(81.33,174.19)
M3_MDQS_P4: length 71.1
  TOP w0.091: v3(81.33,167.19) U22.AF41
  L14_INT_6 w0.1: v3(81.33,167.19) 81.72,167.19 81.8,167.28 81.8,167.41 81.62,167.6 79.11,167.6 77.93,166.42 75.18,166.42 74.65,165.89 74.65,164.74 73.86,163.96 69.67,163.96 66.67,160.96 65.56,160.96 63.83,159.23 63.83,150.27 62.84,149.28 54.51,149.28 54.38,149.15 54.38,148.41 54.51,148.29 61.85,148.29 62.1,148.04 62.1,147.04 61.85,146.79 53.14,146.79 51.97,147.96 50.04,147.96 49.15,148.84 48.15,148.84 47.16,149.83 46.21,149.83 45.78,149.4 45.78,149.22 46,149 J5.85
M3_MDQS_P5: length 71.4
  TOP w0.091: U22.AF37 85.33,166.2 v3(85.33,166.19)
  L5_INT_2 w0.1: J5.94 45.16,140.31 45.75,140.31 46.1,139.95 47.12,139.95 48.13,138.94 49.13,138.94 50.02,139.83 55.39,139.83 55.64,140.08 55.64,141.08 55.39,141.33 53.19,141.33 53.09,141.43 53.09,142.21 53.19,142.32 54.69,142.32 55.33,142.96 55.33,154.25 56.44,155.35 56.44,160.1 65.76,169.42 76.07,169.42 77.14,168.35 78.28,168.35 78.99,167.64 79.7,167.64 79.73,167.61 83.69,167.61 84.68,166.62 84.9,166.62 v3(85.33,166.19)
M3_MDQS_P6: length 70.9
  TOP w0.091: U22.AE34 v3(88.33,166.19)
  L3_INT_1 w0.1: J5.103 46.19,131 46.02,131.17 46.02,131.52 46.46,131.95 46.99,131.95 48.13,130.81 49.17,130.81 50.06,129.92 52.48,129.92 59.94,137.38 59.94,143.51 64.24,147.81 64.24,157.26 65.86,158.88 67.06,158.88 68.48,160.3 73.97,160.3 75.22,161.55 80.97,161.55 81,161.58 85.55,161.58 85.93,161.95 85.93,163.36 86.92,164.36 86.92,165.37 87.13,165.59 87.71,165.59 87.97,165.84 87.97,166.12 88.05,166.19 v3(88.33,166.19)
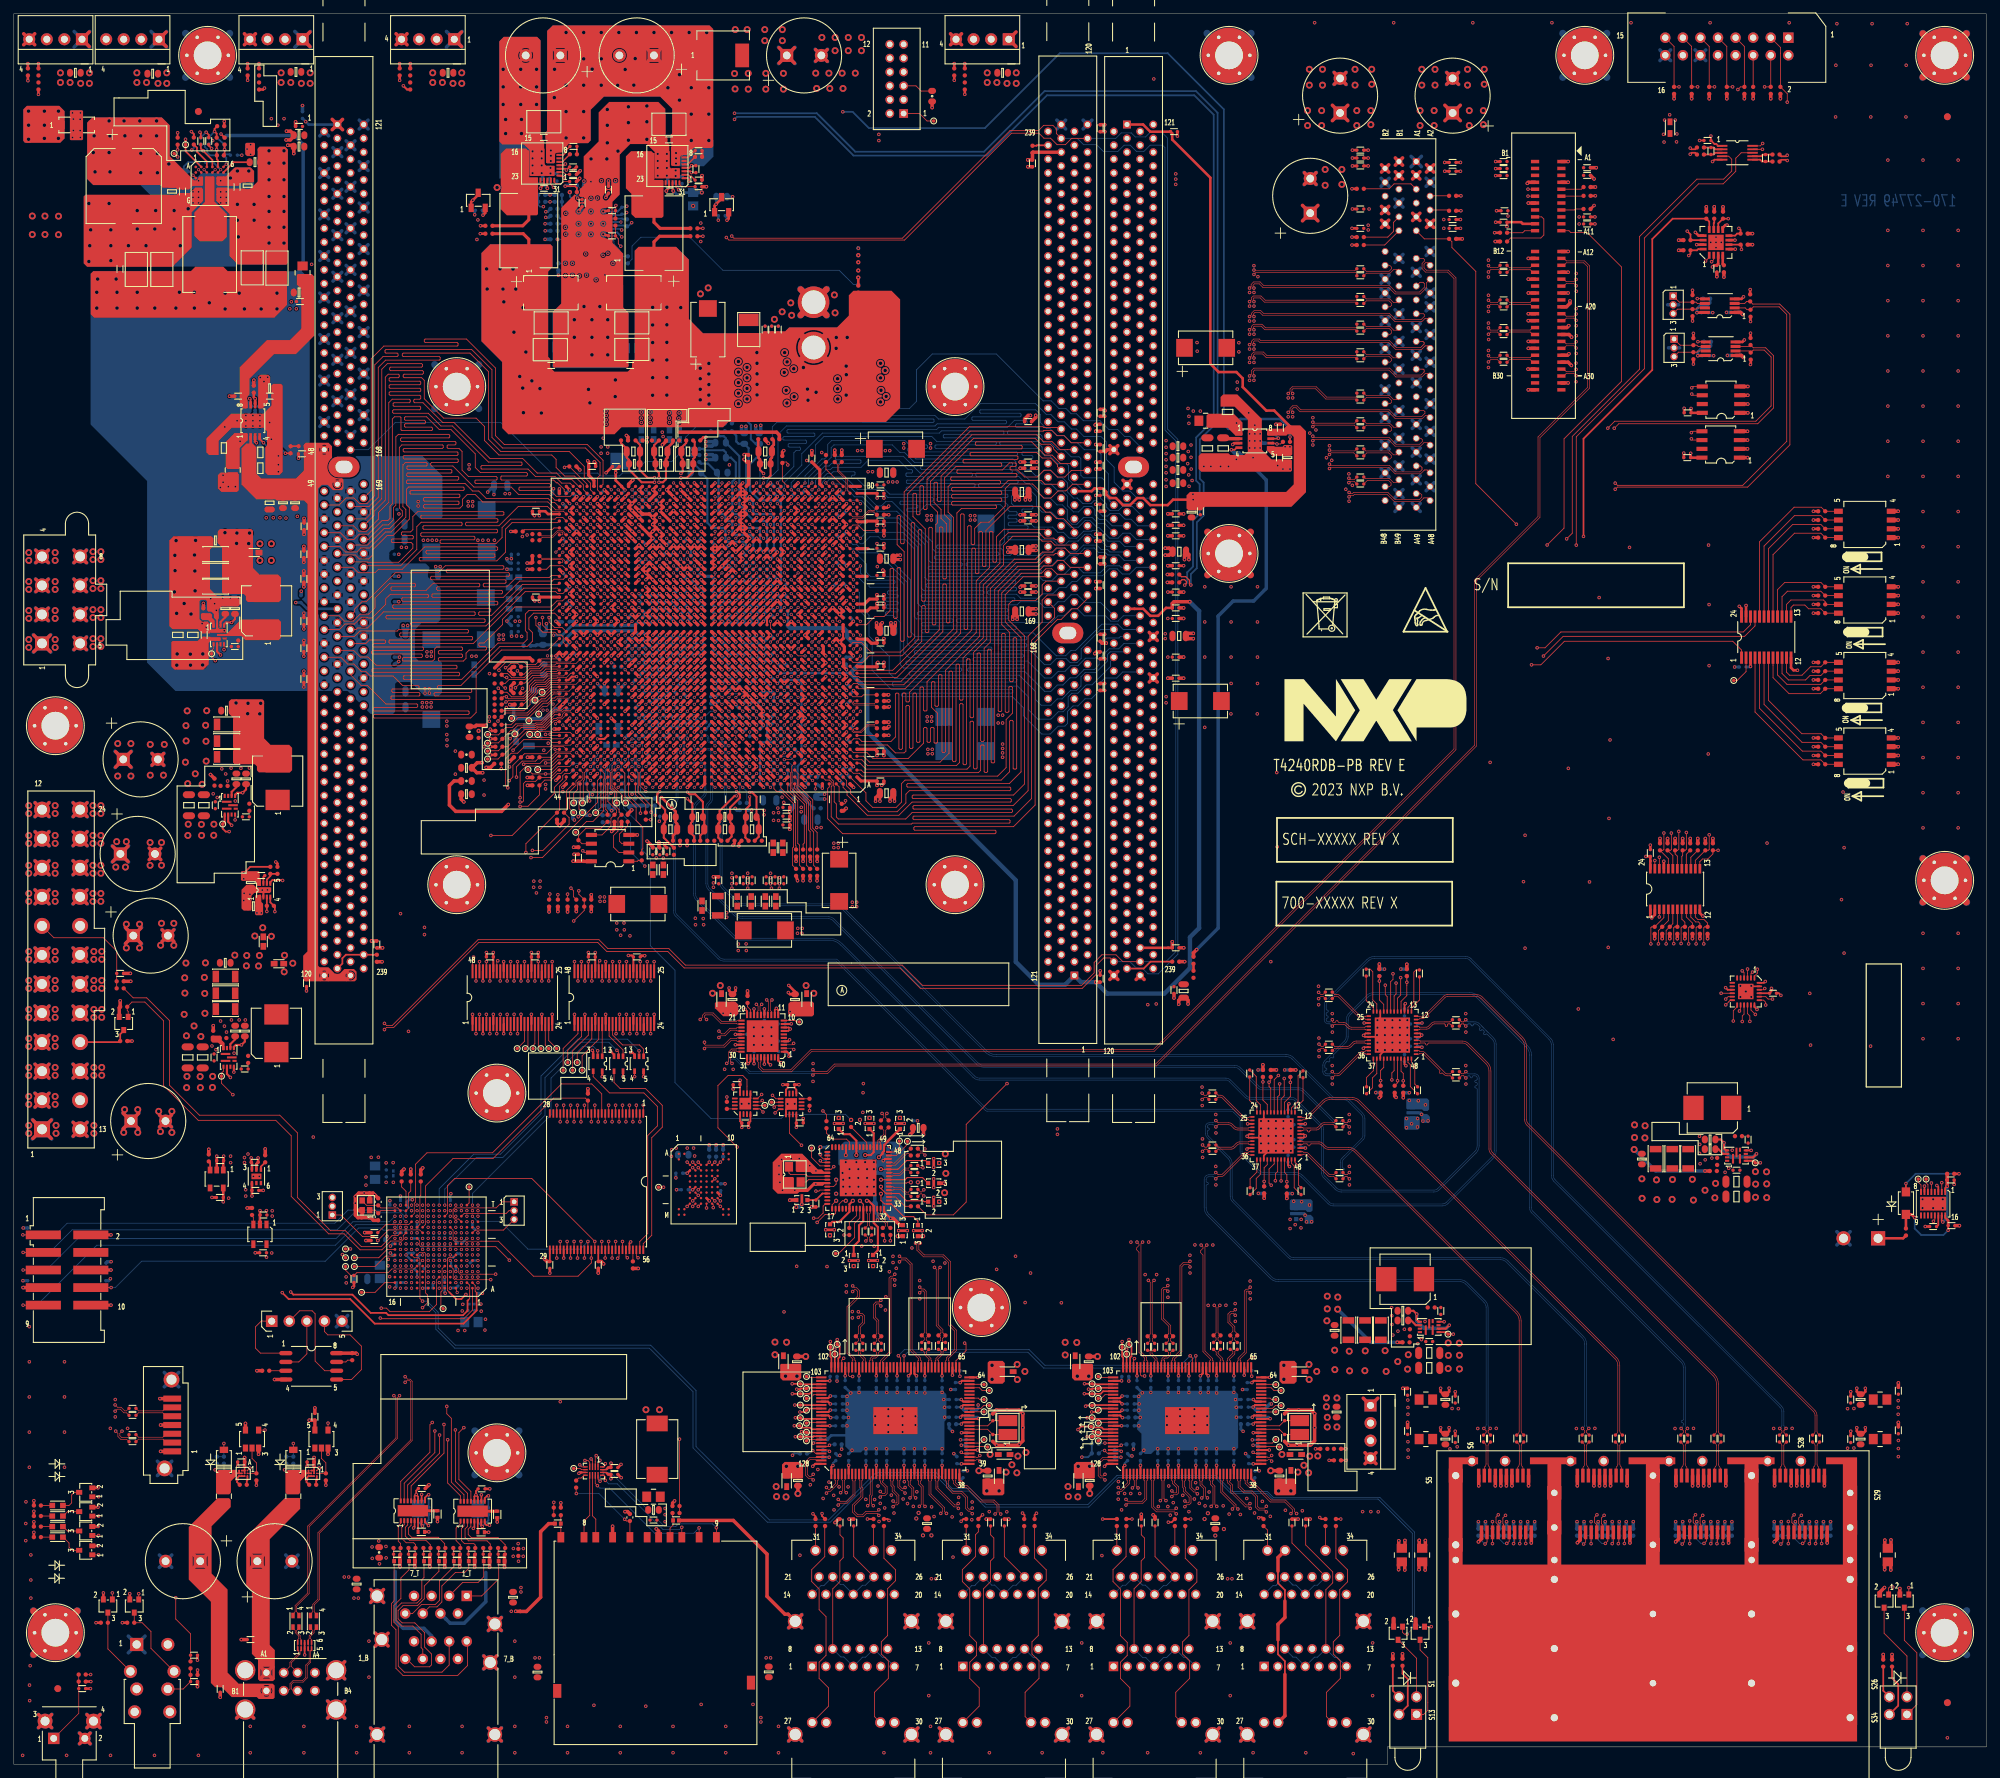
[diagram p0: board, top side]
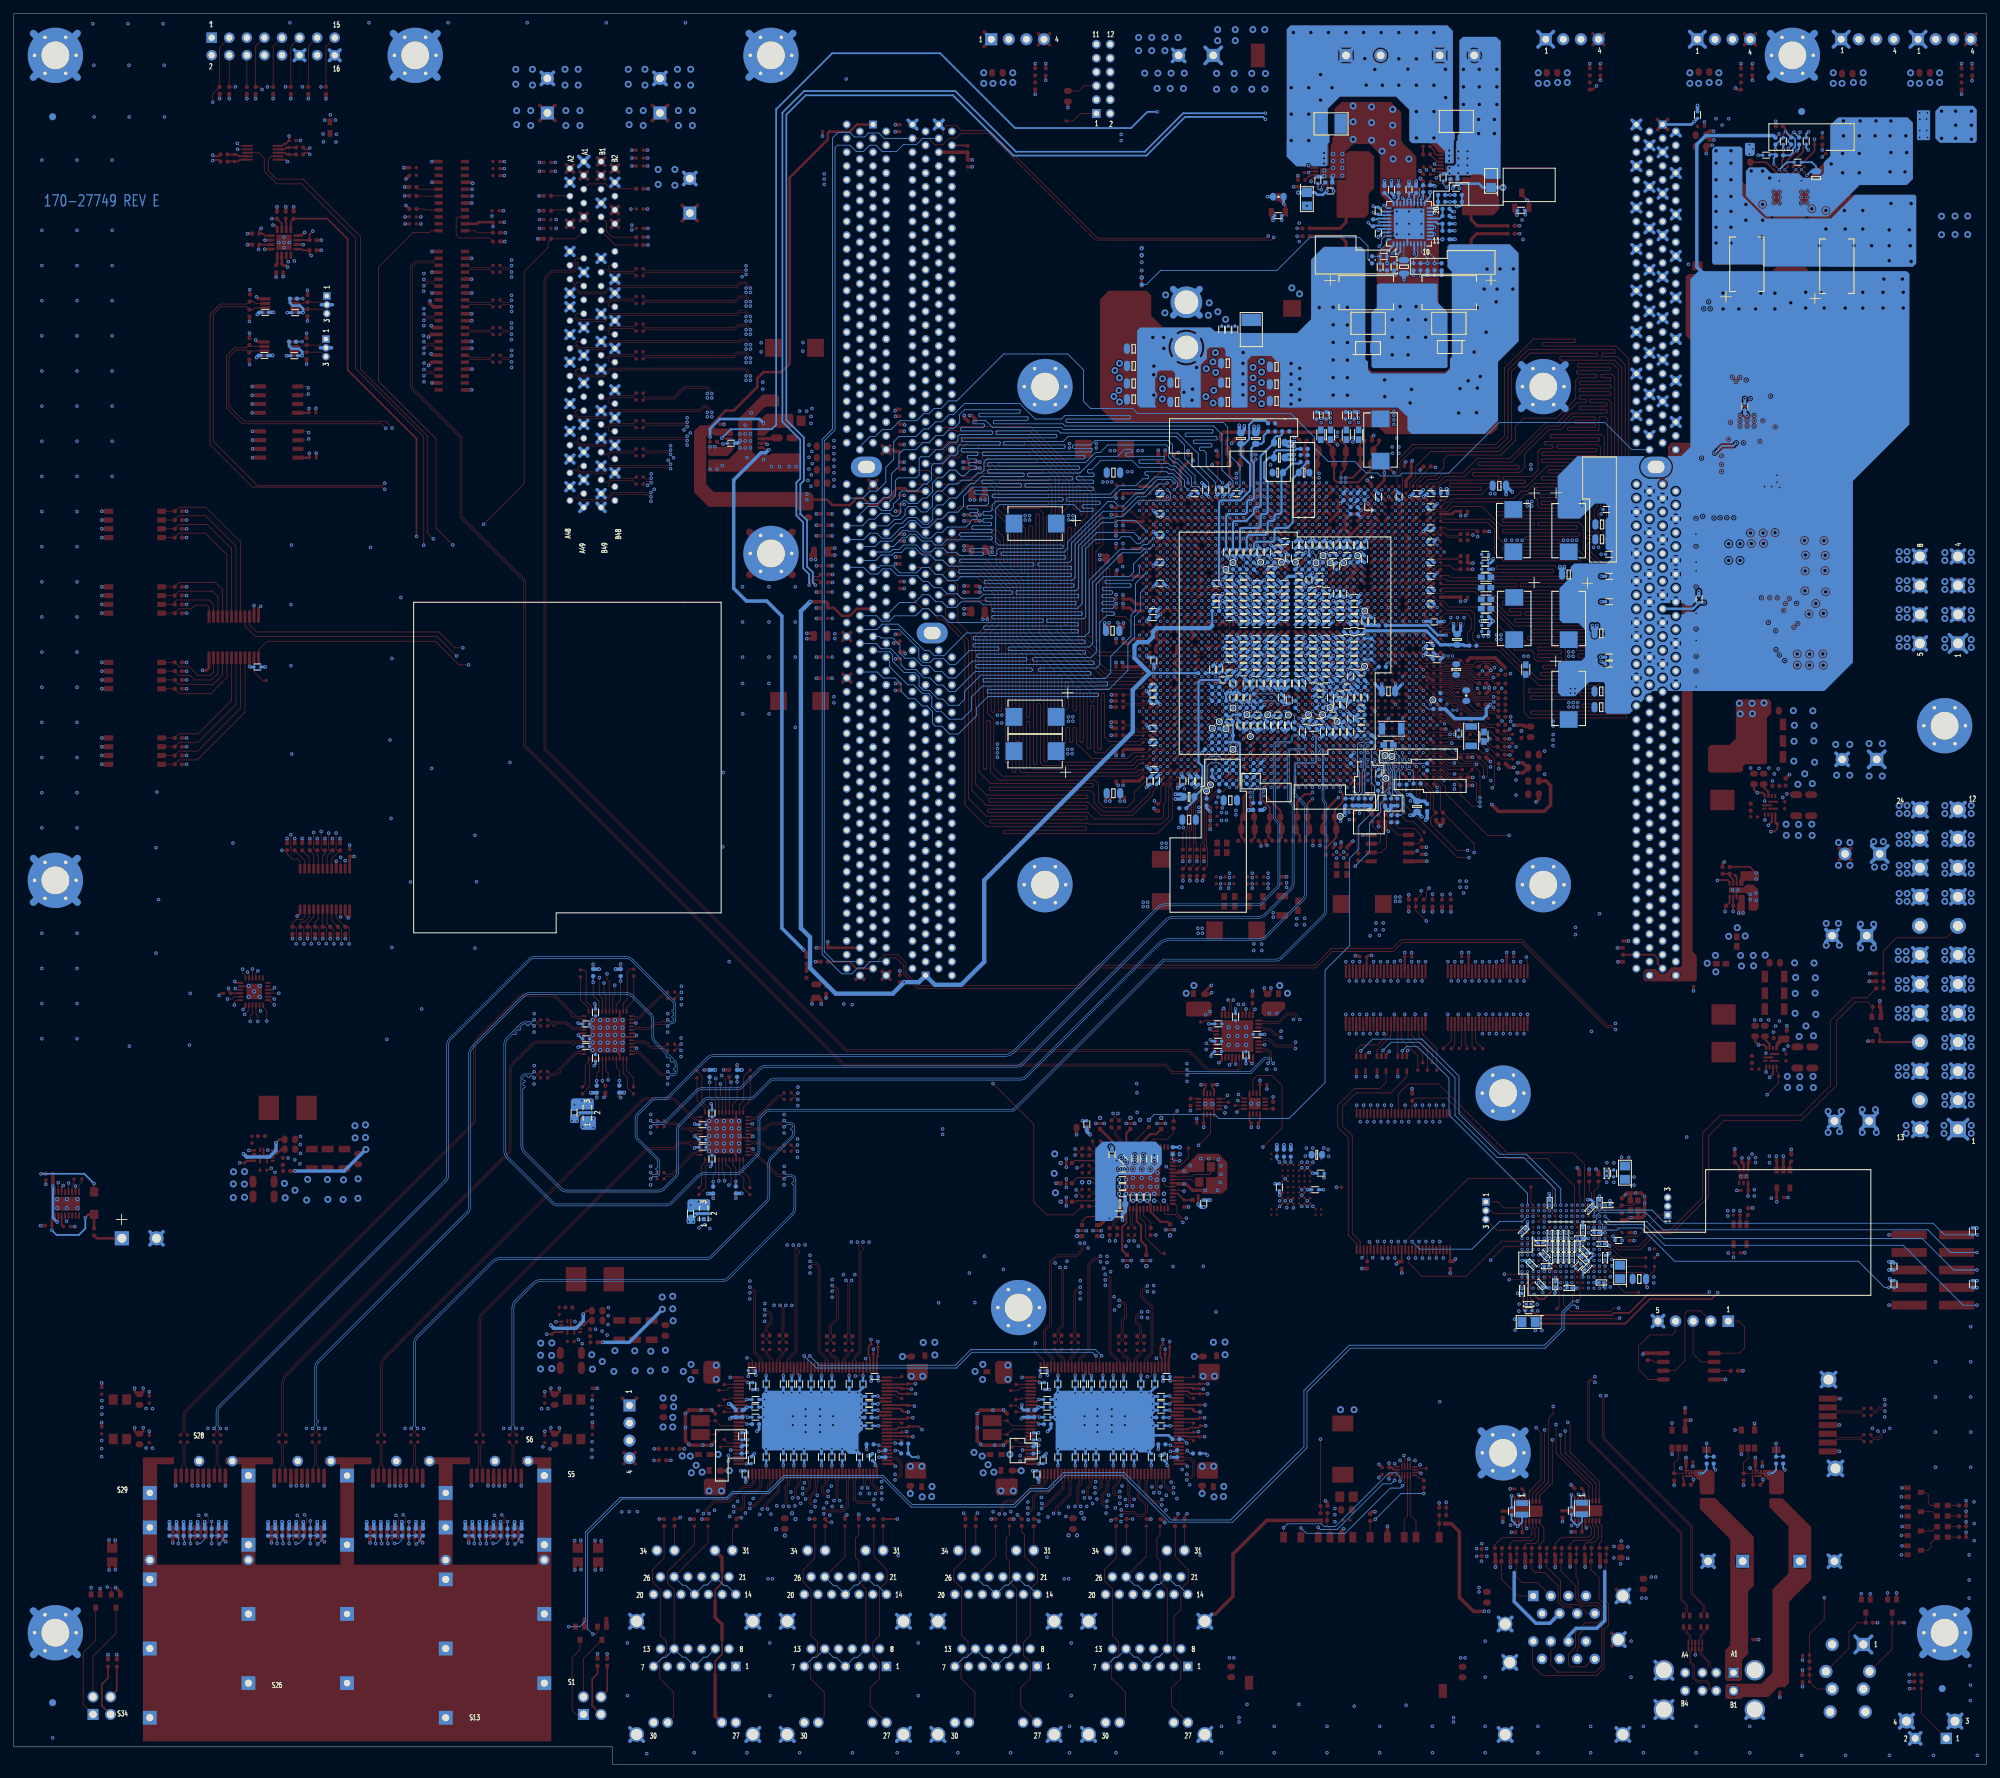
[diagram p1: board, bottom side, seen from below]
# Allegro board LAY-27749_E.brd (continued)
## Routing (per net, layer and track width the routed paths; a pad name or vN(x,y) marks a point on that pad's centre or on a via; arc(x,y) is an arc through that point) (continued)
M3_MDQS_P7: length 73.6
  TOP w0.091: v3(85.33,161.2) U22.AA38
  L5_INT_2 w0.1: J5.112 45.35,122.5 45.64,122.5 46.28,121.87 47.04,121.87 48.01,120.9 49.22,120.9 50.19,121.87 51.08,121.87 57.32,128.11 57.32,130.31 64.53,137.51 64.53,155.71 67.87,159.05 67.87,160.99 68.07,161.19 68.7,161.19 68.86,161.03 68.86,160.58 69.11,160.33 76.28,160.33 76.54,160.59 81.03,160.59 81.04,160.6 84.58,160.6 84.92,160.95 84.92,161.47 85.02,161.57 85.22,161.57 85.33,161.46 v3(85.33,161.2)
M3_MDQS_P8: length 71.3
  TOP w0.091: v3(84.33,172.19) U22.AL38
  L14_INT_6 w0.1: v3(84.33,172.19) 84.62,172.19 84.73,172.31 84.73,172.49 84.62,172.6 83.08,172.6 82.73,172.95 82.73,173.42 82.54,173.61 80.16,173.61 80.14,173.58 77.01,173.58 75.92,174.68 71.45,174.68 70,176.12 64.42,176.12 64.32,176.02 64.32,175.23 64.42,175.13 68.75,175.13 69,174.88 69,173.88 68.75,173.63 63.75,173.63 61.49,175.9 57.45,175.9 54.66,178.69 54.66,190.32 51.05,193.93 49.91,193.93 48.9,194.94 47.9,194.94 47.5,195.35 47.5,195.6 47.14,195.96 46.27,195.96 45.8,195.49 45.8,195.13 45.93,195 J5.43
M3_MDQS_P9: length 82.2
  TOP w0.091: v3(86.33,178.19) U22.AU36
  L14_INT_6 w0.1: J5.125 50.04,233 49.78,232.74 49.78,232.48 50.21,232.05 52.25,232.05 58.85,225.46 58.85,221.87 58.95,221.76 59.74,221.76 59.84,221.87 59.84,222.97 60.09,223.22 61.03,223.22 61.36,222.89 61.36,216.6 72.15,205.82 73.25,205.82 74.25,206.81 75.87,206.81 79.12,203.56 79.12,198.48 80.25,197.35 80.25,195.81 84.9,191.16 86.24,191.16 87.63,189.77 87.63,184.83 87.72,184.75 87.72,184.75 87.73,184.74 87.73,184.73 87.94,184.53 87.94,180.65 86.94,179.65 86.94,178.84 86.7,178.59 86.44,178.59 86.33,178.48 v3(86.33,178.19)
M3_MDQS_P10: length 81
  TOP w0.091: U22.AP36 v3(86.33,175.19)
  L5_INT_2 w0.1: v3(86.33,175.19) 86.33,175.43 86.43,175.54 86.66,175.54 86.95,175.83 86.95,184.51 86.97,184.53 86.97,185.19 86.49,185.67 86.49,187.97 85.79,188.67 84.81,188.67 79.07,194.41 79.07,198.17 75.69,201.55 73.49,201.55 66.58,208.46 64.19,208.46 63.91,208.74 63.91,209.74 63.66,209.99 62.66,209.99 62.41,209.74 62.41,208.76 62.31,208.66 61.52,208.66 61.42,208.76 61.42,215.9 61.17,216.15 60.17,216.15 59.92,215.9 59.92,214.2 59.82,214.1 59.03,214.1 58.93,214.2 58.93,218.42 53.19,224.16 49.78,224.16 49.38,223.75 48.9,223.75 J5.134
M3_MDQS_P11: length 70
  TOP w0.091: v3(81.33,182.19) U22.BA41
  L14_INT_6 w0.1: J5.143 49.88,215 49.65,214.77 49.65,214.58 50.11,214.12 53.36,214.12 57.91,209.57 57.91,207.55 58.93,206.54 58.93,197.99 62.11,194.81 67.42,194.81 67.72,194.51 67.72,193.7 67.47,193.45 64.47,193.45 64.37,193.34 64.37,192.56 64.47,192.46 65.46,192.46 65.79,192.13 65.79,191.49 68.91,188.37 75.29,188.37 75.56,188.1 75.56,187.12 75.31,186.87 72.61,186.87 72.51,186.77 72.51,186.04 72.84,185.71 78.46,185.71 79.63,184.53 79.63,183.74 79.86,183.51 80.39,183.51 80.95,182.96 80.95,182.59 80.91,182.55 80.91,181.88 81.03,181.76 81.21,181.76 81.33,181.88 v3(81.33,182.19)
M3_MDQS_P12: length 71.2
  TOP w0.091: U22.AP40 v3(82.33,175.19)
  L5_INT_2 w0.1: J5.152 48.99,205.66 49.35,205.66 49.81,206.12 53.57,206.12 55.39,204.3 55.39,192.51 55.82,192.07 57.51,192.07 57.88,191.7 57.88,185.42 57.98,185.32 58.77,185.32 58.87,185.42 58.87,191.28 59.12,191.53 60.12,191.53 60.37,191.28 60.37,186.52 62.08,184.81 73.23,184.81 78.49,179.56 78.49,177.33 79,176.81 79.59,176.81 79.93,176.46 79.93,176.03 80.15,175.81 81.69,175.81 81.91,175.59 81.91,175.36 82.08,175.19 v3(82.33,175.19)
M3_MDQS_P13: length 71.2
  TOP w0.091: U22.AG40 v3(82.33,168.19)
  L14_INT_6 w0.1: J5.203 49.98,151 49.78,150.8 49.78,150.58 50.26,150.1 53.15,150.1 53.97,150.93 61.69,150.93 61.96,151.2 61.96,151.82 61.86,151.92 55.16,151.92 54.91,152.17 54.91,153.17 55.16,153.42 58.19,153.42 58.29,153.52 58.29,154.31 58.19,154.41 55.34,154.41 54.98,154.77 54.98,155.55 55.34,155.91 58.14,155.91 58.24,156.01 58.24,156.79 58.14,156.9 56.46,156.9 56.21,157.15 56.21,158.14 56.46,158.39 60.88,158.39 61.47,158.98 61.47,160.25 63.67,162.46 65.99,162.46 69.01,165.48 69.01,165.48 71.04,167.51 76.88,167.51 78.23,168.86 79.96,168.86 80.01,168.81 81.69,168.81 81.96,168.54 81.96,168.28 82.04,168.19 v3(82.33,168.19)
M3_MDQS_P14: length 71.4
  TOP w0.091: U22.AG38 v3(85.33,168.19)
  L5_INT_2 w0.1: v3(85.33,168.19) 85.61,168.19 85.71,168.1 85.71,167.94 85.55,167.78 85.17,167.78 84.16,168.78 80.01,168.78 79.98,168.81 79.55,168.81 78.56,169.8 77.81,169.8 76.69,170.92 61.39,170.92 60.53,170.05 60.53,166.31 60.43,166.21 59.64,166.21 59.54,166.31 59.54,169.71 59.29,169.96 58.29,169.96 58.04,169.71 58.04,164.7 54.94,161.6 54.94,155.98 53.84,154.87 53.84,145.13 50.82,142.11 50.06,142.11 49.42,141.47 49.18,141.47 J5.212
M3_MDQS_P15: length 70.9
  TOP w0.091: v3(87.33,167.19) U22.AF35
  L3_INT_1 w0.1: J5.221 49.74,133 49.58,132.84 49.58,132.52 49.89,132.21 52.52,132.21 58.42,138.1 58.42,148.12 58.79,148.5 59.55,148.5 59.92,148.12 59.92,146.77 60.09,146.6 60.75,146.6 60.91,146.75 60.91,150.68 62.62,152.38 62.62,158.11 66.56,162.05 73.58,162.05 74.14,162.61 78.9,162.61 79.21,162.92 80.52,162.92 80.62,162.82 80.89,162.82 80.92,162.8 84.57,162.8 84.73,162.96 84.73,163.75 85.73,164.74 85.73,166.53 85.98,166.78 87.63,166.78 87.74,166.9 87.74,167.1 87.64,167.19 v3(87.33,167.19)
M3_MDQS_P16: length 73.6
  TOP w0.091: U22.AB39 v3(84.33,162.2)
  L5_INT_2 w0.1: v3(84.33,162.2) 84.33,162.19 83.92,161.78 80.92,161.78 80.9,161.81 79.92,161.81 79.58,162.15 69.92,162.15 69.26,162.81 67.17,162.81 65.1,160.74 65.1,158.54 63.03,156.47 63.03,138.13 55.82,130.92 55.82,128.93 55.67,128.78 55.03,128.78 54.91,128.91 54.91,131.52 54.54,131.88 53.77,131.88 53.41,131.52 53.41,126.41 51.12,124.13 49.99,124.13 49.59,123.72 48.93,123.72 J5.230
M3_MDQS_P17: length 71.3
  TOP w0.091: U22.AM37 v3(85.33,173.19)
  L14_INT_6 w0.1: J5.161 50.04,197 49.82,196.79 49.82,196.59 50.27,196.14 51.15,196.14 58.67,188.62 58.67,183.56 58.42,183.31 57.43,183.31 57.18,183.56 57.18,188.02 57.07,188.12 56.29,188.12 56.18,188.02 56.18,182.32 56.51,181.98 56.51,180.45 56.85,180.11 59.21,180.11 59.46,179.86 59.46,178.86 59.21,178.61 57.86,178.61 57.76,178.51 57.76,177.72 57.86,177.62 71.04,177.62 72.47,176.2 73.73,176.2 74.6,177.07 75.69,177.07 77.95,174.8 83.65,174.8 83.95,174.51 83.95,174.02 84.16,173.81 84.64,173.81 84.89,173.57 84.89,173.28 84.97,173.19 v3(85.33,173.19)
M3_MECC0: length 71.2
  TOP w0.118: v3(85.33,174.19) U22.AN37
  L14_INT_6 w0.087: J5.39 46.98,199.23 49.23,199.23 50.23,198.23 51.01,198.23 60.84,188.4 60.84,179.9 60.93,179.81 61.14,179.81 61.23,179.9 61.23,187.56 61.32,187.65 61.54,187.65 61.63,187.56 61.63,179.49 62.12,179 70.48,179 71.06,179.58 74.37,179.58 75.38,178.56 76.33,178.56 79.1,175.79 84.28,175.79 84.81,175.26 84.81,174.71 v3(85.33,174.19)
M3_MECC1: length 71.2
  TOP w0.118: v3(84.33,174.19) U22.AN38
  L14_INT_6 w0.087: v3(84.33,174.19) 84.33,174.65 83.95,175.03 83.95,175.26 83.62,175.59 78.74,175.59 76.28,178.05 75.33,178.05 74.32,179.07 71.46,179.07 70.99,178.61 61.32,178.61 60.45,179.48 60.45,188.23 60.36,188.32 60.14,188.32 60.05,188.23 60.05,181.21 59.96,181.12 59.75,181.12 59.66,181.21 59.66,189.03 50.96,197.72 50.91,197.72 50.87,197.77 50.14,197.77 49.14,198.77 48.02,198.77 47.25,198 J5.40
M3_MECC2: length 71.2
  TOP w0.118: v3(87.33,171.19) U22.AK35
  L14_INT_6 w0.087: v3(87.33,171.19) 86.93,170.79 82.17,170.79 81.94,171.02 81.94,171.46 81.59,171.81 69.75,171.81 68.67,170.73 60.43,170.73 60.34,170.63 60.34,170.42 60.42,170.33 64.49,170.33 64.58,170.24 64.58,170.03 64.49,169.94 53.56,169.94 52.02,171.48 52.02,188.14 49.15,191.01 48.26,191.01 46.75,192.52 J5.45
M3_MECC3: length 71.2
  TOP w0.118: v3(88.33,171.19) U22.AK34
  L14_INT_6 w0.087: v3(88.33,171.19) 87.72,170.59 81.97,170.59 81.71,170.84 81.71,171.4 81.53,171.58 79.94,171.58 79.77,171.41 69.94,171.41 68.86,170.33 65.08,170.33 64.99,170.24 64.99,170.03 65.07,169.94 68.02,169.94 68.11,169.85 68.11,169.63 68.02,169.54 53.71,169.54 53.71,169.55 53.39,169.55 51.62,171.32 51.62,171.63 51.62,171.64 51.62,187.01 49.4,189.23 47.24,189.23 44.85,191.62 J5.46
M3_MECC4: length 71.2
  TOP w0.118: U22.AM34 v3(88.33,173.19)
  L14_INT_6 w0.087: J5.158 51.08,200 51.82,199.26 51.82,198.54 62.48,187.87 62.48,186.06 63.23,185.31 63.23,182.71 63.32,182.63 63.54,182.63 63.63,182.71 63.63,184.4 63.72,184.49 63.93,184.49 64.02,184.4 64.02,179.91 64.11,179.82 64.33,179.82 64.41,179.91 64.41,183.73 64.5,183.81 64.72,183.81 64.81,183.73 64.81,179.96 64.9,179.87 65.11,179.87 65.2,179.96 65.2,180.62 65.29,180.71 65.51,180.71 65.6,180.62 65.6,180.28 65.79,180.09 69.98,180.09 70.52,180.63 74.44,180.63 75.5,179.58 76.94,179.58 78.93,177.59 87.51,177.59 87.86,177.24 87.86,173.67 88.05,173.48 88.05,173.48 v3(88.33,173.19)
M3_MECC5: length 71.2
  TOP w0.118: U22.AM35 v3(87.33,173.19)
  L14_INT_6 w0.087: J5.159 51.19,199 51.35,198.84 51.35,198.45 62.02,187.78 62.02,179.82 62.11,179.73 62.32,179.73 62.41,179.82 62.41,185.15 62.5,185.24 62.72,185.24 62.81,185.15 62.81,179.6 62.9,179.51 63.11,179.51 63.2,179.6 63.2,182.14 63.29,182.23 63.51,182.23 63.59,182.14 63.59,179.78 63.98,179.39 70.1,179.39 70.8,180.09 74.42,180.09 75.43,179.07 76.89,179.07 79.25,176.71 86.44,176.71 86.87,176.28 86.87,173.66 87.05,173.48 87.05,173.48 v3(87.33,173.19)
M3_MECC6: length 71.2
  TOP w0.118: v3(86.33,172.19) U22.AL36
  L14_INT_6 w0.087: J5.164 49.56,193.09 49.56,192.68 50.09,192.15 50.5,192.15 52.41,190.24 52.41,174.55 52.88,174.07 53.75,174.07 54.1,174.42 60.64,174.42 60.73,174.33 60.73,174.12 60.64,174.03 54.67,174.03 54.58,173.94 54.58,173.72 54.67,173.63 57.12,173.63 58.55,172.21 59.56,172.21 60.35,171.42 68.55,171.42 69.33,172.2 78.72,172.2 79.11,172.59 81.48,172.59 81.79,172.29 81.79,172.16 82.37,171.58 85.71,171.58 v3(86.33,172.19)
M3_MECC7: length 71.2
  TOP w0.118: v3(87.33,172.19) U22.AL35
  L14_INT_6 w0.087: J5.165 52.83,190.72 52.83,178.27 56.23,174.88 60.87,174.88 63.13,172.62 68.19,172.62 68.27,172.53 68.27,172.31 68.19,172.22 60.69,172.22 60.6,172.14 60.6,171.92 60.69,171.83 68.4,171.83 69.72,173.15 76.02,173.15 76.58,172.59 78.56,172.59 78.76,172.8 82.32,172.8 82.92,172.2 82.92,172.05 83.16,171.81 85.6,171.81 85.85,172.06 85.85,172.39 86.11,172.64 86.88,172.64 v3(87.33,172.19)
M3_MODT0: length 82.3
  TOP w0.118: U22.AE43 v3(80.33,166.19)
  L3_INT_1 w0.087: v3(80.33,166.19) 80.05,165.91 80.05,165.9 79.76,165.61 79.21,165.61 78.1,166.71 78.1,169.54 76.63,171.02 71.4,171.02 71.31,170.93 71.31,170.71 71.4,170.62 76.11,170.62 76.2,170.54 76.2,170.32 76.11,170.23 62.19,170.23 62.1,170.14 62.1,169.93 62.19,169.84 76.87,169.84 76.96,169.75 76.96,169.53 76.87,169.44 56.41,169.44 52.45,165.48 52.45,161.42 50.55,159.52 J5.195
M3_MODT1: length 82.3
  TOP w0.118: U22.AA43 79.38,162.15 79.38,162.94 79.12,163.19 78.61,163.19 78.19,163.61 76.45,163.61 75.44,164.63 v2(75.44,165.74)
  L3_INT_1 w0.087: v2(75.44,165.74) 75.44,166.43 74.08,167.79 67.3,167.79 64.35,164.85 57.49,164.85 57.4,164.76 57.4,164.54 57.49,164.45 63.54,164.45 63.63,164.36 63.63,164.15 63.54,164.06 55.59,164.06 55.5,163.97 55.5,163.75 55.59,163.66 62.56,163.66 62.65,163.58 62.65,163.36 62.56,163.27 53.91,163.27 53.82,163.18 53.82,162.97 53.91,162.88 55.77,162.88 55.85,162.79 55.85,162.57 55.77,162.48 54.66,162.48 54.15,161.98 54.15,158.42 52.45,156.72 52.45,154.74 51.76,154.05 49.91,154.05 49.02,154.94 48.01,154.94 47.07,154 46.33,154 45.97,154.36 45.97,156.22 J5.77
M3_MRAS_B: length 82.3
  TOP w0.118: U22.AH43 79.83,168.69 79.28,168.15 78.49,168.15 77.6,167.26 72.39,167.26 70.61,165.48 70.61,164.72 67.94,162.05 67.31,162.05 67.18,161.93 67.18,161.67 67.31,161.54 68.16,161.54 68.29,161.42 68.29,161.16 68.16,161.04 65.79,161.04 65.34,160.59 65.34,159.83 64.96,159.45 61.47,159.45 61.34,159.58 61.34,159.83 61.47,159.96 64.71,159.96 64.83,160.08 64.83,160.34 64.71,160.46 61.47,160.46 61.34,160.59 61.34,160.85 61.47,160.97 64.71,160.97 64.83,161.1 64.83,161.35 64.71,161.48 61.09,161.48 60.81,161.2 60.81,159.74 60.52,159.45 56.26,159.45 56.13,159.58 56.13,159.83 56.26,159.96 58.9,159.96 59.03,160.08 59.03,160.34 58.9,160.46 51.82,160.46 51.69,160.59 51.69,160.85 51.82,160.97 59.05,160.97 59.18,161.1 59.18,161.35 59.05,161.48 52.01,161.48 51.88,161.61 51.88,161.86 52.01,161.99 53.58,161.99 53.71,162.12 53.71,162.37 53.58,162.5 51.37,162.5 50.87,162 J5.192
M3_MWE_B: length 82.3
  TOP w0.118: J5.73 49.08,161 50.06,160.02 51.18,160.02 52.36,158.84 63.91,158.84 64.03,158.71 64.03,158.46 63.91,158.33 51.88,158.33 51.75,158.2 51.75,157.95 51.88,157.82 64.28,157.82 64.41,157.7 64.41,157.44 64.28,157.31 56.39,157.31 56.26,157.19 56.26,156.93 56.39,156.81 64.73,156.81 69.98,162.05 73.66,162.05 74.17,162.56 74.17,163.58 73.91,163.83 73.91,166.24 74.42,166.75 77.89,166.75 78.52,167.39 U22.AG44
M3_PARERR_B: length 40.2
  TOP w0.118: v2(79.58,187.45) 79.6,187.45 79.73,187.58 R202.2 82.83,185.01 U22.BD40
  L3_INT_1 w0.087: v2(79.58,187.45) 76.74,184.61 55.91,184.61 55.68,184.38 54.71,184.38 52.22,181.89 49.99,181.89 49.1,181 J5.53
M3_PAROUT: length 82.3
  TOP w0.118: J5.68 46.98,166 47.76,165.22 49.01,165.22 50.01,166.22 51.28,166.22 52.2,167.13 52.2,168.57 54.31,170.69 57.93,170.69 58.06,170.56 58.06,170.31 57.93,170.18 54.61,170.18 54.48,170.05 54.48,169.8 54.61,169.67 59.59,169.67 60.6,170.69 67.2,170.69 67.32,170.56 67.32,170.31 67.2,170.18 61.21,170.18 61.09,170.05 61.09,169.8 61.21,169.67 70.48,169.67 70.61,169.54 70.61,169.29 70.48,169.16 60.53,169.16 60.4,169.04 60.4,168.78 60.53,168.66 70.74,168.66 73.09,171.01 77.79,171.01 78.06,171.28 79.41,171.28 79.83,171.69 U22.AL43
M3_VREF_ISO: length 3.6
  TOP w0.457: v3(90.33,165.19) U22.AD32
  BOTTOM w0.457: v3(90.33,165.19) C703.1 89.65,164.59 88.91,164.59 C704.1 88.64,164.59 R705.1
M_VREF_A: length 251.7
  TOP w0.381: J7.1 163.18,237 164.21,235.97 C35.1 167.39,235.72 167.39,234.82 172.9,229.31 172.9,202.41 174.09,201.22 176.66,201.22 177.57,200.3 177.57,199.06 180.97,195.66 182.12,195.66 184.61,193.17 ; 169.85,182.78 167.51,182.78 166.73,181.99 164.21,181.99 163.2,183.01 162.31,183.01 161.29,181.99 160.27,181.99 159.26,183.01 158.37,183.01 157.86,183.51 157.86,183.9 157.36,184.4 C152.1 156.15,184.4 155.75,184 J6.67 ; J7.67 161.92,167 163.2,167 164.21,165.99 165.35,165.99 166.5,167.13 C197.1
  TOP w0.508: C304.1 156.34,113.04 v2(156.34,113.04) ; v2(169.93,168.02) 167.64,168.02 167.39,167.77 167.39,167.14 C197.1
  BOTTOM w0.305: R703.2 111.84,164.58 ; 120.88,157.71 120.86,157.69 R713.2
  BOTTOM w0.635: 111.84,164.58 112.2,164.21 119.89,164.21 120.4,163.7 120.4,162.94 121.16,162.18 122.56,162.18 123.06,161.67 123.06,159.89 120.88,157.71 123.32,155.27 123.32,149.22 144.78,127.76 144.78,115.98 148.11,112.65 151.9,112.65 J6.1 154.21,113.04 v2(156.34,113.04) 156.34,113.03 157.99,111.38 166.24,111.38 169.95,115.09 169.95,119.53 171.27,120.85 171.27,166.67 v2(169.93,168.02)
  vias: v2(170.38,183.57) v2(170.41,182.78)
M_VREF_B: length 112.1
  TOP w0.508: 46,237.75 J5.1 ; J5.1 47.5,237.75 ; J5.1 46,236.25 ; J5.1 47.5,236.25
  L10_INT_4 w0.381: v3(77.98,163.19) 75.56,163.19 73.86,161.49 70.1,161.49 67.56,158.95 58.98,158.95 51.92,166.01 50.09,166.01 49.1,167 46.75,167 J5.67
  L12_INT_5 w0.635: v2(40.74,167.9) 40.08,168.56 40.08,196.6 43.03,199.54 v2(43.03,216.79)
  BOTTOM w0.381: v2(40.74,167.9) C666.1 42.38,167 J5.67 ; R705.2 80.65,164.59 79.25,163.19 v3(77.98,163.19) ; C27.1 v2(42.17,237.42) 42.59,237 J5.1
M_VTT_A: length 39.3
  TOP w0.508: 163.33,113.42 J7.240 162.17,113.42 ; v2(156.21,160.53) 156.46,160.77 C215.1 ; J7.49 161.43,185.58 ; J7.49 160.27,185.58 ; J7.49 160.27,184.42 ; J7.49 161.43,184.42 ; v2(147.7,166.24) 147,166.24 C199.1 147,167 v2(147.7,167) ; 158.37,114.58 J7.120 ; J7.120 159.53,114.58 ; J7.120 159.53,113.42 ; J7.120 158.37,113.42 ; U17.2 174.88,191.59 C5144.1 ; 158.37,189.42 J7.48 ; J7.48 159.53,189.42 ; J7.48 158.37,190.58 ; J7.48 159.53,190.58 ; J7.48 158,190 157.74,189.75 C117.1 ; C28.1 v2(157.62,236.97)
  L3_INT_1 w0.508: J7.240 163.33,114.58 ; J7.240 162.17,114.58 ; J7.240 163.33,113.42 ; J7.240 162.17,113.42 ; 152.67,166.58 J6.49 ; J6.49 153.83,166.58 ; J6.49 153.83,165.42 ; J6.49 152.67,165.42 ; J6.48 155.73,160.42 ; J6.48 154.57,161.58 ; J6.48 155.73,161.58 ; J6.48 154.57,160.42 ; 160.27,184.42 J7.49 ; J7.49 160.27,185.58 ; J7.49 161.43,185.58 ; J7.49 161.43,184.42
  BOTTOM w0.508: J6.240 151.98,236.36 ; J6.240 150.71,236.36 ; J6.240 151.98,237.63 ; J6.240 150.71,237.63 ; J6.120 155.78,237.63 ; J6.120 154.51,236.36 ; J6.120 154.51,237.63
  vias: v2(166.5,191.31) v2(166.5,190.35) v2(166.5,189.43) v2(166.5,188.54) v2(166.5,187.58) v2(166.5,186.66) v2(166.5,185.65) v2(166.5,184.68) v2(167.89,229.87) v2(167.89,229.11) v2(167.89,228.35)
M_VTT_B: length 10.9
  TOP w0.381: U14.2 34.22,190.81
  TOP w0.508: J5.120 45.43,114.58 ; J5.120 44.27,113.42 ; J5.120 45.43,113.42 ; J5.120 44.27,114.58 ; 46.17,185.58 J5.49 47.33,185.58 ; 48.07,113.42 J5.240 48.07,114.58 ; 44.27,189.42 J5.48 ; J5.48 45.43,189.42 ; J5.48 45.43,190.58 ; J5.48 44.27,190.58
MON_DDRCLK: length 89.2
  TOP w0.118: U627.10 112.07,91.21 v2(113.82,89.46)
  L3_INT_1 w0.087: v1(55.87,68.8) 55.87,68.29 59.11,65.05 70.66,65.05 74.6,68.99 97.08,68.99 110.11,82.02 117.37,82.02 119.35,84 119.35,85.18 119.08,85.46 119.08,88.93 118.21,89.79 116.36,89.79 116.03,89.46 v2(113.82,89.46)
MON_SYSCLK: length 85.6
  TOP w0.118: v2(104.52,89.2) 101.74,91.99 101.74,98.08 103.2,99.54 105.33,99.54 105.94,98.94 U626.10
  L3_INT_1 w0.087: v2(104.52,89.2) 105.28,88.44 105.28,78.87 96.47,70.05 74.3,70.05 71.45,67.21 60.58,67.21 59.99,67.79 56.97,67.79 56.29,68.47 56.29,70.57 56.54,70.82 57.06,70.82 v1(57.47,70.4)
NAND_LOCK: length 6.8
  TOP w0.118: U38.G5 v2(98.9,83.02) ; TP222.1 v2(93.88,83.39)
  L3_INT_1 w0.087: v2(98.9,83.02) 98.15,83.77 94.26,83.77 v2(93.88,83.39)
ORIENT_ERR_B: length 82.2
  TOP w0.118: U22.C42 80.33,143.19 79.63,143.19 79.31,142.88 79.31,142.41 78.11,141.2 78.11,140.34 72.01,134.24 v2(68.94,134.24)
  L14_INT_6 w0.087: v1(57.47,76.8) 57.05,77.22 57.05,79.45 56.31,80.19 56.31,82.55 58.57,84.81 58.57,128.12 64.69,134.24 v2(68.94,134.24)
OVDD: length 91
  TOP w0.203: U45.15 85.58,42.57 85.69,42.67
  TOP w0.254: U37.29 C345.1 ; U627.12 C5330.1 ; U37.43 C346.1 ; U38.G4 v2(98.1,83.02) ; U626.12 C5327.1
  TOP w0.305: U593.31 C3849.1 89.32,116.89 v2(88.8,116.89) ; U594.18 v2(74.79,108.38) ; U598.5 v2(85.02,99.38) ; U593.7 v2(84.02,108.38) ; U38.D3 97.7,85.82 v2(97.3,85.42) ; U594.31 C3851.1 v2(74.79,117.32) ; v2(69.28,117.32) C3852.1 U594.42 ; U594.7 v2(69.28,108.38) ; U595.5 v2(91,99.38) ; v2(84.02,117.32) C3850.1 U593.42 ; U593.18 v2(89.52,108.38) ; U596.5 v2(88.03,99.38)
  TOP w0.381: v2(68.83,145.87) 69.53,145.87 R5856.1 ; U38.H8 v2(102.09,82.22) ; R5854.1 69.09,149.35 v2(68.83,149.61) ; R5857.1 v2(68.86,147.07) ; R5852.1 v2(79.04,37.78) ; 85.69,42.67 85.89,42.88 C5320.1 v2(86.28,43.51) ; U38.J6 v2(100.49,81.42) ; R5855.1 v2(68.88,148.21) ; C5330.1 v2(113.07,92.05) ; C5327.1 v2(104.94,98.85)
  TOP w0.457: v2(95.48,38.05) 95.17,37.74 R5851.1 ; v2(71.82,155.57) 71.82,155.82 R255.1
  TOP w0.508: FL21.3 131.38,76.31 v7(131.39,76.33) ; v2(71.63,144.91) R276.1 ; R5853.1 68.88,144.07 v2(68.25,144.07) ; R299.1 88.7,137.34 v2(89.28,137.92) ; v2(76.68,73.03) 77.05,72.66 C345.1 ; R280.1 v2(74.22,141.48) ; R279.1 v2(74.19,142.62) ; R250.1 74.55,159.89 70.92,159.89 69.48,158.45 ; v2(80.83,130.51) C276.1 82.27,130.51 82.28,130.51 U26.8 ; R252.1 72.15,157.54 v2(71.58,158.12) 72.08,158.62 R251.1 ; R5904.1 v2(77.34,123.19) ; v2(87.78,135.52) 87.8,135.54 87.8,135.56 87.81,135.56 R298.1 ; C346.1 84.87,72.66 v2(85.22,72.31) ; R294.1 78.49,136.04 v2(78.87,135.66) 79.5,136.3 R295.1 ; FL15.1 v7(127.74,76.31) ; R5703.1 v2(90.22,71.65) ; v2(129.49,90.98) 129.92,91.42 C3857.1 ; R277.1 v2(74.22,145.54) ; R297.1 86.79,135.23 v2(86.39,134.82) ; R5858.1 v2(82.95,97.62) ; v2(71.82,155.57) 71.82,155.21 R258.1 ; R5903.1 v2(78.61,123.24) ; R5771.1 v2(83.44,123.24) ; R5898.1 v2(81.28,123.24) ; v2(71.67,153.16) R263.1 ; R5902.1 v2(80.01,123.19) ; R5730.2 v2(28.82,106.74)
  L10_INT_4 w0.508: v2(89.28,137.92) 88.06,137.92
  BOTTOM w0.381: v2(102.09,82.22) 102.13,82.26 C347.1 ; v2(98.1,83.02) 97.46,83.02 C433.1 ; C5171.1 v2(97.3,85.42)
  BOTTOM w0.457: v2(71.67,153.16) 72.24,152.59 72.24,151.59 72.69,151.13 ; R768.1 R767.1 ; v2(89.28,137.92) 88.9,138.3 R765.1 ; R743.1 88.72,148.72 v3(88.29,148.29)
  BOTTOM w0.508: R766.1 86.87,138.3 v2(86.39,137.82) 85.98,138.23 R767.1 ; R524.1 v2(100.48,89.52) ; R732.2 78.17,152.53 76.77,151.13 72.69,151.13 ; R525.1 v2(101.47,89.52) ; R762.1 R763.1 R764.1 R765.1 ; v2(129.49,90.98) 129.95,91.44 C3858.1 ; R818.1 v2(102.49,89.52)
  vias: v2(68.73,157.63) v2(68.71,151.38) v2(68.71,150.75) v2(75.13,127.64) v2(75.11,126.75) v2(75.51,125.93) v2(76.05,127.64) v2(76.02,126.75) v2(97.31,89.05) v2(98.22,89.05) v2(98.37,87.91) v2(122.71,97.05) v2(122.68,94.21) v2(122.76,98.37) v2(238.38,235.59) v2(238.46,234.47) v2(240.31,235.64) v2(240.26,234.49) v4(31.93,116.94) v4(33.61,115.39) v4(33.66,116.89) v4(35.36,115.37) v4(35.49,116.89) v5(117.93,76.44) v5(119.2,93.41) v5(121.36,72) v5(123.65,93.41) v5(133.72,86.89) v5(133.72,81.31)
P1_LINKACT_P: length 7.9
  TOP w0.254: LED6.2 201.42,8.46 201.42,12.32 200.66,13.08 R994.2
P2_LINKACT_P: length 4.9
  TOP w0.254: R995.2 199.26,10.62 LED6.4
P3_LINKACT_P: length 7.8
  TOP w0.254: 271.4,14.1 271.4,12.45 272.29,11.56 272.29,8.46 LED5.2
P4_LINKACT_P: length 4.7
  TOP w0.254: 270.13,14.1 270.13,10.62 LED5.4
PCBVER0: length 4.5
  TOP w0.102: 57.05,81.33 57.05,80.38 U27.R14
  TOP w0.118: 57.05,81.33 57.05,82.55 57.35,82.85 R5770.1
PCBVER1: length 3.7
  TOP w0.118: R5769.1 56.03,83.44 56.67,82.8 U27.T14
PCBVER2: length 6.8
  TOP w0.118: U27.M12 58.67,78.01 58.67,82.09 58.8,82.22 R5897.1
PCIE_4X_TCK: length 3.3
  TOP w0.118: R124.1 226.51,227.65 U55.A5
PCIE_4X_TDI: length 3.2
  TOP w0.118: R125.1 226.78,226.65 U55.A6
PCIE_4X_TMS: length 3.3
  TOP w0.118: R143.1 225.63,224.79 225.49,224.65 U55.A8
PCIE_4X_TRST_B: length 9.4
  TOP w0.118: U55.B9 220.77,223.65 221.08,223.34 221.08,221.03 220.65,220.6 216.28,220.6 R146.2
PCIE_REFCLK_N: length 196.9
  TOP w0.091: J3.A14 204.25,217.04 204.01,217.04 203.77,216.81 203.77,216.28 204.1,215.95 207.29,215.95 208.38,214.85 208.38,146.63 164.8,103.05 115.33,103.05 112.36,100.08 108.22,100.08 107.57,100.72 107.57,101.47 107.45,101.59 U32.34
PCIE_REFCLK_P: length 197
  TOP w0.091: J3.A13 203.68,217.65 203.84,217.48 203.84,217.28 203.49,216.92 203.49,216.17 203.99,215.67 207.17,215.67 208.1,214.74 208.1,146.75 164.68,103.33 115.21,103.33 112.24,100.36 108.33,100.36 107.85,100.84 107.85,101.43 107.95,101.54 U32.35
PCIE_X4_CLK_N: length 213.2
  TOP w0.091: U55.A14 223.97,216.65 224.33,217.01 226.85,217.01 227.41,216.46 227.41,199.01 220.24,191.85 220.24,180.34 211.07,171.17 211.07,147.28 164.98,101.19 118.57,101.19 117.5,100.13 115.71,100.13 v2(115.47,100.37) ; U32.29 104.51,103.48 104.4,103.37 103.71,103.37 103.28,102.94 103.28,101.56 v2(103.01,101.29)
  BOTTOM w0.091: v2(115.47,100.37) 115.23,100.13 106.35,100.13 104.29,102.18 103.54,102.18 103.25,101.89 103.25,101.54 v2(103.01,101.29)
PCIE_X4_CLK_P: length 213.2
  TOP w0.091: U32.30 104.51,102.98 104.4,103.09 103.83,103.09 103.56,102.82 103.56,101.51 v2(103.77,101.29) ; U55.A13 223.98,217.65 224.34,217.29 226.97,217.29 227.69,216.57 227.69,198.89 220.52,191.73 220.52,180.22 211.35,171.05 211.35,147.17 165.1,100.91 118.68,100.91 117.62,99.85 115.71,99.85 v2(115.47,99.61)
  BOTTOM w0.091: v2(103.77,101.29) 103.53,101.54 103.53,101.78 103.66,101.9 104.18,101.9 106.23,99.85 115.23,99.85 v2(115.47,99.61)
PCIEX4_WAKE_B: length 4.2
  TOP w0.118: U55.B11 218.32,221.65 218.03,221.36 R206.1
PCIEX8_WAKE_B: length 5.9
  TOP w0.118: J3.B11 198.08,219.58 R151.1
PEXBUFCOREV: length 7
  TOP w0.254: v2(109.33,101.08) 109.3,101.08 108.95,101.43 U32.37
  TOP w0.305: v2(112.34,107.01) 112.32,106.98 U32.9 ; v2(112.01,102.31) 112.01,102.68 111.71,102.98 U32.1 ; U32.4 111.87,104.48 112.09,104.7 v2(112.09,104.7)
  BOTTOM w0.305: v2(112.01,102.31) 112.01,102.5 C332.1 ; v2(112.09,104.7) 112.09,104.7 111.89,104.5 C310.1 ; v2(112.34,107.01) C309.1
  vias: v2(112.17,108.79) v2(112.78,108.33)
PEXBUFIOV: length 7.5
  TOP w0.305: U32.15 v2(108.45,109.17) ; v2(106.95,101.24) U32.33 ; U32.28 v2(104.27,103.98) ; U32.40 110.45,101.7 110.76,101.4 v2(110.9,101.4) ; U32.25 v2(104.27,105.48) ; U32.18 v2(106.95,109.16)
  BOTTOM w0.305: C3892.1 106.96,101.6 106.95,101.59 v2(106.95,101.24) ; C3891.1 104.91,105.48 v2(104.27,105.48) ; C3890.1 108.45,108.5 v2(108.45,109.17)
  vias: v2(102.49,108.53) v2(103.58,108.51)
PHY0_AVDD18: length 24.5
  TOP w0.305: U42.22 v2(128.63,43.18) ; U42.70 v2(134.13,56.13) ; U42.11 v2(123.13,43.18) ; U42.128 115.8,43.41 v2(115.44,43.05) ; U42.78 130.13,56.43 v2(130.43,56.13) ; U42.39 v2(136.93,43.41) ; U42.6 v2(120.63,43.18) ; U42.17 v2(126.13,43.18) ; U42.94 v2(122.13,56.13) ; U42.75 v2(131.63,56.13) ; U42.33 v2(134.13,43.18) ; U42.89 v2(124.63,56.13) ; U42.28 v2(131.63,43.18)
  BOTTOM w0.305: v2(128.63,43.18) C5236.1 ; v2(126.13,43.18) C5242.1 ; v2(124.63,56.13) C5232.1 ; v2(120.63,43.18) C5239.1 ; C5231.1 136.31,43.41 v2(136.93,43.41) ; C5234.1 131.64,56.12 v2(131.63,56.13) ; v2(123.13,43.18) C5237.1 ; v2(131.63,43.18) C5241.1 ; v2(130.43,56.13) C5238.1 ; v2(122.13,56.13) C5240.1 ; v2(134.13,43.18) C5235.1 ; v2(134.13,56.13) C5233.1
  vias: v4(111.63,43.05) v4(113.28,43.05)
PHY0_AVDD33: length 8.1
  TOP w0.305: U42.1 118.13,42.95 v2(118.36,43.18) ; v2(136.91,40.77) 136.63,41.04 U42.38 ; U42.25 v2(130.13,43.18) ; U42.14 v2(124.63,43.18)
  BOTTOM w0.305: C5228.1 118.36,43.48 v2(118.36,43.18) ; C5230.1 136.91,41.15 v2(136.91,40.77) ; v2(130.13,43.18) C5229.1 ; v2(124.63,43.18) C5227.1
  vias: v4(140.59,39.5) v4(142.37,39.5)
PHY0_CF0: length 2.4
  TOP w0.118: U42.122 v2(115.52,46.41)
  BOTTOM w0.118: v2(115.52,46.41) 116.1,46.99 R5793.2
PHY0_CF1: length 2.1
  TOP w0.118: v2(117.86,46.1) 117.66,45.91 U42.123
  BOTTOM w0.118: v2(117.86,46.1) 117.98,46.23 R5794.2
PHY0_CF2: length 2.3
  TOP w0.118: U42.124 117.66,45.41 v2(117.86,45.21)
  BOTTOM w0.118: R5795.2 117.07,45.21 v2(117.86,45.21)
PHY0_CF3: length 2.4
  TOP w0.118: U42.125 115.88,44.91 v2(115.44,45.34)
  BOTTOM w0.118: v2(115.44,45.34) 115.02,44.92 R5796.2
PHY0_CKRN: length 2.2
  TOP w0.118: v2(136.71,56.07) 136.63,56.14 U42.65
  BOTTOM w0.118: v2(136.71,56.07) C5176.1
PHY0_CLKSEL0: length 2
  TOP w0.254: v2(136.92,49.16) 137.16,49.41 U42.51
  BOTTOM w0.254: R5755.2 136.91,49.15 v2(136.92,49.16)
PHY0_CLKSEL1: length 3.3
  TOP w0.254: U42.52 139.37,49.91 v2(139.42,49.96)
  BOTTOM w0.381: v2(139.42,49.96) 139.22,50.16 R5754.1 R5753.2
PHY0_HTN: length 2.7
  TOP w0.118: TP224.1 140.65,45.91 U42.44
PHY0_HTP: length 2.3
  TOP w0.118: TP223.1 139.67,46.41 U42.45
PHY0_NTRST: length 2.1
  TOP w0.118: TP229.1 140.15,54.91 U42.62
PHY0_RSET: length 2.1
  TOP w0.118: v2(136.91,45.09) 137.08,44.91 U42.42
  BOTTOM w0.118: v2(136.91,45.09) 137.1,44.89 R5751.1
PHY0_TCK: length 2.1
  TOP w0.118: TP225.1 138.1,50.93 U42.54
PHY0_TDI: length 2.2
  TOP w0.118: TP226.1 139.57,52.7 139.37,52.91 U42.58
PHY0_TDO: length 3
  TOP w0.118: U42.61 139.52,54.41 139.92,54.01 TP227.1
PHY0_TMS: length 3
  TOP w0.118: TP228.1 140.15,51.83 139.72,51.41 U42.55
PHY0_VDDORL: length 15
  TOP w0.305: U42.98 v2(120.13,56.13) ; v2(136.91,51.61) 137.2,51.91 U42.56 ; U42.64 v2(139.32,55.91) ; U42.83 v2(127.63,56.13) ; U42.110 117.65,52.41 v2(117.98,52.07) ; U42.117 v2(117.9,48.91)
  BOTTOM w0.305: C5214.1 v2(117.9,48.91) ; v2(127.63,56.13) C5217.1 ; v2(136.91,51.61) C5216.1 ; v2(117.98,52.07) C5218.1 ; v2(120.13,56.13) C5215.1
  BOTTOM w0.381: R5795.1 v2(117.81,44.37)
  BOTTOM w0.406: R5794.1 v2(119.62,45.53) ; v2(135.64,48.09) 135.14,48.58 R5755.1
  BOTTOM w0.508: 137.54,51.18 137.33,51.18 v2(136.91,51.61)
  vias: v4(141.35,57.66) v4(141.35,55.63)
PHY1_AVDD18: length 24.5
  TOP w0.305: U620.89 v2(166.79,56.13) ; U620.22 v2(170.79,43.18) ; U620.70 v2(176.3,56.13) ; U620.75 v2(173.79,56.13) ; U620.28 v2(173.79,43.18) ; U620.6 v2(162.79,43.18) ; v2(157.61,43.05) 157.96,43.41 U620.128 ; U620.17 v2(168.3,43.18) ; U620.78 172.3,56.43 v2(172.59,56.13) ; U620.33 v2(176.3,43.18) ; U620.39 v2(179.1,43.41) ; U620.94 v2(164.3,56.13) ; U620.11 v2(165.3,43.18)
  BOTTOM w0.305: v2(164.3,56.13) C5191.1 ; C5187.1 173.81,56.12 v2(173.79,56.13) ; v2(172.59,56.13) C5185.1 ; v2(170.79,43.18) C5190.1 ; v2(179.1,43.41) 178.47,43.41 C5186.1 ; v2(173.79,43.18) C5189.1 ; v2(162.79,43.18) C5193.1 ; v2(165.3,43.18) C5194.1 ; v2(166.79,56.13) C5188.1 ; v2(168.3,43.18) C5192.1 ; v2(176.3,56.13) C5196.1 ; v2(176.3,43.18) C5195.1
  vias: v4(153.8,43.05) v4(155.45,43.05)
PHY1_AVDD33: length 8.1
  TOP w0.305: U620.25 v2(172.3,43.18) ; U620.14 v2(166.79,43.18) ; v2(160.53,43.18) 160.3,42.95 U620.1 ; v2(179.25,40.77) 179.25,40.8 178.79,41.25 U620.38
  BOTTOM w0.305: v2(172.3,43.18) C5181.1 ; v2(166.79,43.18) C5182.1 ; v2(179.25,40.77) 179.25,41.32 C5180.1 ; C5183.1 160.53,43.48 v2(160.53,43.18)
  vias: v4(182.75,39.5) v4(184.53,39.5)
PHY1_CF0: length 2.1
  TOP w0.118: U620.122 v2(157.66,46.41)
  BOTTOM w0.118: v2(157.66,46.41) 157.58,46.33 R5797.2
PHY1_CF1: length 2.1
  TOP w0.118: U620.123 159.83,45.91 v2(160.02,46.1)
  BOTTOM w0.118: v2(160.02,46.1) 160.15,46.23 R5798.2
PHY1_CF2: length 2.3
  TOP w0.118: U620.124 159.82,45.41 v2(160.02,45.21)
  BOTTOM w0.118: R5799.2 159.24,45.21 v2(160.02,45.21)
PHY1_CF3: length 2.4
  TOP w0.118: v2(157.61,45.34) 158.04,44.91 U620.125
  BOTTOM w0.118: R5800.2 157.21,45.34 v2(157.61,45.34)
PHY1_CKRN: length 2.1
  TOP w0.118: U620.65 178.79,56.16 v2(178.87,56.08)
  BOTTOM w0.118: C5253.1 v2(178.87,56.08)
PHY1_CLKSEL0: length 2
  TOP w0.254: v2(179.08,49.16) 179.33,49.41 U620.51
  BOTTOM w0.254: v2(179.08,49.16) 179.07,49.15 R5803.2
PHY1_CLKSEL1: length 3.2
  TOP w0.254: v2(181.53,49.94) 181.5,49.91 U620.52
  BOTTOM w0.381: v2(181.53,49.94) 181.31,50.16 R5804.1 R5802.2
PHY1_HTN: length 2.7
  TOP w0.118: TP262.1 182.82,45.91 U620.44
PHY1_HTP: length 2.3
  TOP w0.118: TP261.1 181.83,46.41 U620.45
PHY1_NTRST: length 2.1
  TOP w0.118: TP267.1 182.31,54.91 U620.62
PHY1_RSET: length 2.1
  TOP w0.118: v2(179.07,45.09) 179.25,44.91 U620.42
  BOTTOM w0.118: R5805.1 179.26,44.89 v2(179.07,45.09)
PHY1_TCK: length 2.1
  TOP w0.118: U620.54 182.33,50.91 TP263.1
PHY1_TDI: length 2.2
  TOP w0.118: TP264.1 181.74,52.7 181.54,52.91 U620.58
PHY1_TDO: length 3
  TOP w0.118: TP265.1 182.08,54.01 181.69,54.41 U620.61
PHY1_TMS: length 3
  TOP w0.118: U620.55 180.27,51.44 181.89,51.44 182.28,51.83 TP266.1
PHY1_VDDORL: length 14.9
  TOP w0.305: v2(179.07,51.61) 179.37,51.91 U620.56 ; U620.64 v2(181.48,55.91) ; U620.83 v2(169.79,56.13) ; U620.117 v2(160.07,48.91) ; U620.98 v2(162.3,56.13) ; U620.110 159.81,52.41 v2(160.15,52.07)
  BOTTOM w0.305: v2(162.3,56.13) C5199.1 ; v2(169.79,56.13) C5200.1 ; v2(179.07,51.61) C5198.1 ; C5179.1 v2(160.07,48.91) ; v2(160.15,52.07) C5178.1
  BOTTOM w0.381: R5799.1 v2(159.98,44.37)
  BOTTOM w0.406: R5803.1 177.3,48.43 v2(177.62,48.11) ; R5798.1 v2(161.78,45.53)
  BOTTOM w0.508: 179.71,51.18 179.5,51.18 v2(179.07,51.61)
  vias: v4(183.51,57.66) v4(183.51,55.63)
PHY_1V0:
  vias: v4(35.56,176.4) v4(35.56,173.99) v4(37.21,176.4) v4(37.21,173.99) v4(109.98,61.01) v4(109.98,59.18) v4(111.66,60.99) v4(151.92,60.98) v4(151.92,59.15) v4(153.59,60.95)
PHY_1V8: length 11.4
  TOP w0.508: R5766.2 v2(199.9,60.97)
  BOTTOM w0.508: v4(191.29,65.76) 196.08,60.97 v2(199.9,60.97)
  vias: v4(110.16,40.13) v4(110.21,38.68) v4(111.58,38.63) v4(145.08,44.53) v4(146.25,45.06) v4(152.32,40.13) v4(152.37,38.68) v4(153.75,38.63) v4(187.25,44.53) v4(188.42,44.55) v4(189.74,64.09) v4(189.79,67.64) v4(189.79,65.81) v4(191.31,67.51)
PHY_EMI1_MDC: length 179
  TOP w0.118: v2(169.98,59.03) 170.3,58.71 U620.82 ; U42.82 128.13,58.71 v2(127.81,59.03)
  L3_INT_1 w0.087: v2(165.07,109.88) 163.83,111.12 143,111.12 119.38,134.75 115.95,134.75 113.28,137.41 113.28,138.38 112.27,139.4 112.27,145.41 111.89,145.8 111.89,146.64 v3(111.33,147.2)
  L5_INT_2 w0.087: v2(169.98,59.03) 170.74,59.79 170.74,65.79 173.91,68.96 173.91,77.72 166.34,85.29 166.34,108.61 v2(165.07,109.88)
  BOTTOM w0.118: R744.2 v3(111.33,147.2) 110.85,146.71 R745.2 ; v2(127.81,59.03) 128.7,59.92 146.71,59.92 148.97,57.66 168.61,57.66 v2(169.98,59.03)
PHY_EMI1_MDIO: length 181.7
  TOP w0.118: U620.81 v2(170.79,59.02) ; U22.H13 v3(110.33,148.2) ; U42.81 v2(128.63,59.02)
  L3_INT_1 w0.087: v3(110.33,148.2) 110.72,147.81 110.72,145.95 111,145.67 111.51,145.67 112.01,145.16 112.01,139.32 113.03,138.3 113.03,137.29 115.82,134.49 119.25,134.49 143.13,110.62 163.02,110.62 v2(163.86,109.78)
  L5_INT_2 w0.087: v2(170.79,59.02) 171.35,59.58 171.35,65.86 174.29,68.81 174.29,78.16 166.93,85.52 166.93,108.97 165.51,110.39 164.47,110.39 v2(163.86,109.78)
  BOTTOM w0.118: 109.86,148.72 v3(110.33,148.2) ; v2(128.63,59.02) 129.14,59.54 146.53,59.54 148.82,57.25 169.02,57.25 v2(170.79,59.02)
PLED_P0WER_ON_GRE: length 9.9
  TOP w0.118: SW5.5 13.59,16.66 R665.2 Q12.3
PLED_POWER_ON: length 77.7
  TOP w0.118: U27.A5 v3(64.06,68.17) ; Q12.1 v2(14.24,24.75)
  L12_INT_5 w0.087: v2(14.24,24.75) 14.24,27.7 20.42,33.88 41.02,33.88 63.7,56.57 63.7,67.82 v3(64.06,68.17)
PLED_STANDBY: length 85.3
  TOP w0.118: Q11.1 v2(18.05,24.64)
  L12_INT_5 w0.087: v1(63.87,69.6) 63.87,68.77 63.25,68.15 63.25,56.74 40.6,34.1 19.09,34.1 13.46,28.47 13.46,24.05 14.15,23.37 16.78,23.37 v2(18.05,24.64)
PLED_STANDBY_YEL: length 11.6
  TOP w0.118: SW5.6 19.81,16.74 19.81,19.18 18.54,20.45 17.4,20.45 Q11.3
PORT1_TX_DISABLE: length 102.2
  TOP w0.118: v2(251.94,114.91) 251.94,114.33 251.52,113.91 U624.1
  L3_INT_1 w0.087: v2(251.94,114.91) 251.18,115.67 246.84,115.67 233.38,102.21 233.38,69.04 217.45,53.11 217.45,40.46 213.66,36.68 v2(213.66,35.05)
  BOTTOM w0.118: R928.1 v2(213.66,35.05)
PORT1_TXFAULT: length 100.4
  TOP w0.118: U624.10 v2(246.7,111.43) ; v2(212.58,31.81) 212.88,32.11 J16.2A
  L3_INT_1 w0.087: v2(246.7,111.43) 245.17,111.43 237.26,103.53 237.26,86.84 236.37,85.95 236.37,69.51 218.72,51.87 218.72,40.92 216.2,38.4 216.2,34.14 215.24,33.17 213.94,33.17 v2(212.58,31.81)
  BOTTOM w0.118: R1082.2 211.99,32.66 211.99,32.41 v2(212.58,31.81)
PORT2_TX_DISABLE: length 107.4
  TOP w0.118: v2(251.24,114.49) 251.02,114.26 U624.2
  L3_INT_1 w0.087: v2(227.91,35.05) 229.16,33.81 237.79,33.81 240.28,31.32 242.44,31.32 244.73,33.6 244.73,35.59 245.29,36.14 245.29,38.86 245.72,39.29 245.72,43.28 248.95,46.51 248.95,103.53 247.52,104.95 247.52,107.42 248.51,108.41 250.14,108.41 251.74,110.01 251.74,114 v2(251.24,114.49)
  BOTTOM w0.118: R937.1 v2(227.91,35.05)
PORT2_TXFAULT: length 91.8
  TOP w0.118: U624.11 247.71,110.93 v2(247.37,110.59) ; J16.2B 227.13,32.11 v2(226.83,31.81)
  L3_INT_1 w0.087: v2(226.83,31.81) 226.83,34.07 227.33,34.57 227.33,36.07 237.33,46.06 237.33,65.11 241.53,69.32 241.53,104.75 v2(247.37,110.59)
  BOTTOM w0.118: v2(226.83,31.81) 226.24,32.41 226.24,32.66 R938.2
PORT3_TX_DISABLE: length 91.4
  TOP w0.118: v2(250.52,114.94) 250.52,114.3 250.52,114.29 U624.3
  L5_INT_2 w0.087: v2(242.16,35.15) 242.92,34.39 245.44,34.39 245.72,34.67 245.72,37.59 247.93,39.8 247.93,84.25 246.53,85.65 246.53,107.47 247.93,108.86 247.93,114.53 248.72,115.32 250.14,115.32 v2(250.52,114.94)
  BOTTOM w0.118: R946.1 v2(242.16,35.15)
PORT3_TXFAULT: length 85.7
  TOP w0.118: v2(241.08,31.81) 241.38,32.11 J16.2C ; U624.12 248.04,110.43 247.81,110.2 247.81,110.19 v2(247.37,109.75)
  L3_INT_1 w0.087: v2(247.37,109.75) 242.85,105.23 242.85,86.33 243.48,85.7 243.48,45.82 241.66,43.99 241.66,32.39 v2(241.08,31.81)
  BOTTOM w0.118: R947.2 240.49,32.66 240.49,32.41 v2(241.08,31.81)
PORT4_TX_DISABLE: length 86.5
  TOP w0.118: U624.4 250.02,114.4 v2(249.75,114.67)
  L5_INT_2 w0.087: v2(249.75,114.67) 251.71,112.7 251.71,110.06 254.84,106.93 254.84,80.52 252.45,78.13 252.45,47.27 255.02,44.7 255.02,36.5 256.11,35.41 256.11,35.37 v2(256.41,35.07)
  BOTTOM w0.118: R955.2 v2(256.41,35.07)
PORT4_TXFAULT: length 87.8
  TOP w0.118: J16.2D 255.63,32.11 v2(255.33,31.81) ; v2(248.46,107.42) 248.46,108.91 249.02,109.46 U624.13
  L3_INT_1 w0.087: v2(255.33,31.81) 255.93,32.41 255.93,39.52 250.62,44.83 250.62,103.32 251.46,104.17 251.46,107.49 251.03,107.92 248.97,107.92 v2(248.46,107.42)
  BOTTOM w0.118: R956.2 254.74,32.66 254.74,32.41 v2(255.33,31.81)
POVDD: length 4.2
  TOP w0.254: v2(33.25,128.8) 34.15,129.7 R5747.1
  vias: v2(33.22,127.97) v2(59.33,120.95) v2(59.33,119.91) v2(63.8,146.43) v2(63.8,143.1)
PROC_IFC_CLK1: length 5.6
  TOP w0.118: TP10.1 76.15,149.3 77.65,149.3 77.8,149.15 80.38,149.15 80.83,148.7 U22.H42
PROC_IFC_CLK2: length 4.5
  TOP w0.118: U22.A38 84.83,138.3 TP22.1
PROC_IFC_NDDDR_CLK: length 5.7
  TOP w0.118: U22.H43 79.34,148.21 77.79,148.21 77.6,148.4 74.99,148.4 TP11.1
PROC_IFC_NDDQS: length 1.4
  TOP w0.118: v3(86.33,145.2) U22.E36
  BOTTOM w0.118: v3(86.33,145.2) TP101.1
PROC_IFC_PAR0: length 5
  TOP w0.118: v3(84.33,145.2) U22.E38
  BOTTOM w0.118: R759.2 82.74,143.3 83.2,143.76 83.57,143.76 83.82,144.02 83.82,144.4 84.33,144.91 v3(84.33,145.2)
PROC_IFC_PAR1: length 3.5
  TOP w0.118: v3(84.33,144.2) U22.D38
  BOTTOM w0.118: R758.2 84.77,143.45 84.33,143.89 v3(84.33,144.2)
PROC_IFC_PAR2: length 5.3
  TOP w0.118: v3(84.33,146.2) U22.F38
  BOTTOM w0.118: v3(84.33,146.2) 84.33,145.77 83.87,145.31 83.87,145.08 83.44,144.65 80.77,144.65
PROC_IFC_PAR3: length 11.3
  TOP w0.118: v3(85.33,146.2) U22.F37
  BOTTOM w0.118: v3(85.33,146.2) 84.84,145.7 84.84,143.95 85.27,143.52 85.27,140.98 84.07,139.79 84.07,137.67 84.58,137.16 R772.2
PROC_IFC_PERR_B: length 10.5
  TOP w0.118: v3(85.33,145.2) U22.E37
  BOTTOM w0.118: R771.2 85.32,137.82 84.71,137.82 84.44,138.09 84.44,139.73 85.52,140.8 85.52,143.81 85.79,144.08 85.79,144.74 v3(85.33,145.2)
PROG_MTR: length 3.9
  TOP w0.457: v3(93.33,156.2) U22.T29
  TOP w0.508: v2(68.27,150.16) 66.83,150.16 66.65,149.99 R273.1
  BOTTOM w0.305: v3(93.33,156.2) 93.31,156.2 92.82,156.68 R714.1
PROG_SFP: length 1.4
  TOP w0.457: v3(93.33,155.2) U22.R29
  BOTTOM w0.457: C825.1 v3(93.33,155.2)
  vias: v2(67.93,147.06)
PS_1V0_EN: length 136.5
  TOP w0.118: U23.3 28.87,161.28 28.57,160.99 TP218.1 28.57,160.05 v2(29.11,159.51)
  L5_INT_2 w0.087: v2(29.11,159.51) 29.35,159.28 29.35,141.75 30.02,141.07 30.02,133.2 28.57,131.75 28.57,117.02 34.57,111.02 34.57,97.87 32.41,95.71 32.41,64.95 37.63,59.73 47.71,59.73 51.61,63.63 51.61,68.58 52.48,69.44 55.18,69.44 56.56,70.83 57.09,70.83 v1(57.47,71.2)
PS_1V0_PG: length 134.9
  TOP w0.118: U23.6 v2(30.37,161.1)
  L5_INT_2 w0.087: v2(30.37,161.1) 30.37,158.77 29.59,157.99 29.59,142.21 30.38,141.43 30.38,133.02 28.93,131.57 28.93,117.22 34.99,111.16 34.99,97.83 32.72,95.56 32.72,65.13 37.9,59.94 46.84,59.94 50.95,64.06 50.95,68.68 52.2,69.93 55.14,69.93 56.42,71.2 v1(56.67,71.2)
PS_2V5_EN: length 213.1
  TOP w0.254: v2(252.37,86.92) TP260.1
  TOP w0.305: U68.3 251.34,87.21 TP260.1
  L12_INT_5 w0.254: v1(67.07,70.4) 67.35,70.12 67.95,70.12 69.98,68.09 114.71,68.09 124.3,58.5 139.19,58.5 140.17,59.47 147.33,59.47 150.61,62.75 162.53,62.75 163.7,61.57 194.74,61.57 197.38,64.21 199.8,64.21 200.08,64.49 204.29,64.49 207.14,61.65 210.92,61.65 219.86,70.59 242.87,70.59 247.83,75.54 247.83,85.04 249.71,86.92 v2(252.37,86.92)
PS_2V5_PG: length 218.9
  TOP w0.305: U68.6 v2(251.04,88.71)
  L12_INT_5 w0.254: v2(251.04,88.71) 251.34,89.01 253.13,89.01 254.58,87.55 254.58,78.21 245.57,69.19 219.99,69.19 210.79,59.99 206.58,59.99 203.17,63.4 199.9,63.4 199.36,62.87 197.1,62.87 195.3,61.06 163.49,61.06 162.32,62.24 150.82,62.24 147.54,58.97 140.4,58.97 139.45,58.01 124.02,58.01 114.53,67.51 69.5,67.51 67.4,69.6 v1(67.07,69.6)
PS_GVDD_EN: length 221.7
  TOP w0.118: U27.A2 66.27,65.63 65.02,64.39 53.06,64.39 v2(52.96,64.48)
  TOP w0.152: U631.B2 v3(26.69,230.47)
  TOP w0.254: TP215.1 v2(23.67,232.31)
  L3_INT_1 w0.254: v3(26.69,230.47) 24.84,232.31 v2(23.67,232.31)
  L5_INT_2 w0.254: v2(23.67,232.31) 24.23,231.75 24.23,224.43 26.86,221.81 26.86,209.33 27.65,208.53 27.65,168.43 28.32,167.76 28.32,159.28 28.92,158.68 28.92,141.37 28.04,140.49 28.04,116.87 34.06,110.85 34.06,97.97 31.9,95.81 31.9,64.74 37.62,59.03 48.18,59.03 52.96,63.81 v2(52.96,64.48)
PS_GVDD_PG: length 203.8
  TOP w0.254: v2(24.81,234.87) TP216.1 24.81,233.15 U631.A2
  L5_INT_2 w0.102: 54.78,76.41 59.25,76.41 59.47,76.2 59.47,75.87 59.71,75.62 60.79,75.62 61.08,75.33 61.08,75.32 61.08,75.32 61.08,72.6 61.28,72.4 61.91,72.4 62.33,71.98 63.32,71.98 63.69,71.62 66.65,71.62 v1(67.07,71.2)
  L5_INT_2 w0.254: v2(24.81,234.87) 26.49,234.87 29.49,231.88 29.49,231.63 30.46,230.67 30.46,228.64 31.54,227.56 31.54,209.71 29.24,207.41 29.24,171.87 31.89,169.22 31.89,167.77 32.44,167.23 32.44,158.44 31.15,157.15 31.15,148.76 34.85,145.06 34.85,124.69 34.42,124.26 34.42,122.73 35.02,122.13 36.35,122.13 38.2,120.27 38.2,118.87 37.5,118.16 37.5,112.61 38.58,111.52 38.58,83.05 45.36,76.27 53.18,76.27 53.71,76.81 54.2,76.81 54.6,76.41 54.78,76.41
PS_ON: length 68.9
  TOP w0.118: U27.L14 56.27,76.41 56.27,75.84 56.04,75.61 54.45,75.61 53.19,74.35 50.04,74.35 47.73,76.66 45.49,76.66 40.08,82.07 40.08,90.83 37.85,93.07 26.64,93.07 21.62,98.09 21.62,107.47 18.92,110.16 17.07,110.16 R748.1 16.38,108.94 16.52,108.8 Q13.1
PS_ON_B: length 7.7
  TOP w0.254: J9.16 15.22,104.37 R394.1 15.37,105.51 15.88,106.02 Q13.3
PS_OVDD_EN: length 87.3
  TOP w0.118: U1.3 30.29,100.17 30,99.88 TP217.1 30,98.42 v2(31.65,96.77)
  L14_INT_6 w0.087: v2(31.65,96.77) 31.65,88.15 31.74,88.06 31.74,87.71 31.65,87.61 31.65,87.21 31.74,87.12 31.74,86.77 31.65,86.67 31.65,71.75 37.31,66.09 46.98,66.09 51.5,61.56 68.04,61.56 69.45,62.98 69.45,70.3 69.14,70.61 69.14,71.91 67.82,73.23 66.5,73.23 65.89,72.62 65.89,71.58 v1(66.27,71.2)
PS_OVDD_PG: length 80.9
  TOP w0.305: U1.6 v2(31.79,100.03)
  L14_INT_6 w0.102: 67.47,72.4 66.66,72.4 66.27,72.01 v1(66.27,72)
  L14_INT_6 w0.203: 67.47,72.4 67.71,72.4 68.39,71.72 68.39,69.66 68.83,69.22 68.83,64.16 67.89,63.22 67.87,63.22 66.77,62.12 51.54,62.12 47.17,66.49 37.57,66.49 32.28,71.77 32.28,99.54 v2(31.79,100.03)
PS_PHY_1V8_EN: length 155.7
  TOP w0.254: U69.3 206.94,62.45 TP246.1 v2(208,62.16)
  L12_INT_5 w0.127: v1(64.67,71.2) 64.67,71.2 65.08,70.8 67.92,70.8
  L12_INT_5 w0.254: 67.92,70.8 68.9,70.8 69.6,70.1 70.97,70.1 72.47,68.6 114.95,68.6 123.6,59.95 133.62,59.95 134.48,59.09 138.86,59.09 139.76,59.98 147.11,59.98 150.38,63.25 162.74,63.25 163.73,62.26 194.36,62.26 197.51,65.41 200.28,65.41 200.66,65.79 203.81,65.79 207.44,62.16 v2(208,62.16)
PS_PHY_1V8_PG: length 151.8
  TOP w0.254: U69.6 v2(206.68,63.95)
  L12_INT_5 w0.127: v1(65.47,71.2) 65.86,71.6 67.62,71.6
  L12_INT_5 w0.254: 67.62,71.6 70.47,71.6 72.88,69.19 115.1,69.19 123.71,60.57 133.94,60.57 134.78,59.73 138.65,59.73 139.41,60.49 146.89,60.49 150.16,63.76 162.95,63.76 163.95,62.76 193.78,62.76 197.51,66.5 204.13,66.5 v2(206.68,63.95)
PS_POVDD_EN: length 72.1
  TOP w0.254: U630.3 R5768.1 v2(36.56,123.25)
  L5_INT_2 w0.102: 54.28,77.39 54.46,77.22 58.9,77.22 59.72,76.4 63.22,76.4 63.49,76.67 63.49,76.96 63.49,76.96 63.49,77.22 v1(63.87,77.6)
  L5_INT_2 w0.254: 54.28,77.39 54.14,77.53 44.92,77.53 39.23,83.22 39.23,111.82 38.15,112.9 38.15,117.77 38.84,118.46 38.84,120.97 v2(36.56,123.25)
PS_POVDD_PG: length 72.7
  TOP w0.254: U630.5 37.06,127.48 37.36,127.79 38.79,127.79 v2(38.84,127.74)
  L5_INT_2 w0.102: 54.32,78.81 57.66,78.81 57.87,78.6 57.87,78.2 58.08,77.98 60.03,77.98 60.28,77.73 60.28,77.35 60.45,77.18 62.53,77.18 62.68,77.34 62.68,77.77 62.9,77.99 65.05,77.99 v1(65.47,78.4)
  L5_INT_2 w0.254: v2(38.84,127.74) 38.84,126.47 41.62,123.68 41.62,87.67 49.31,79.97 51.9,79.97 53.07,78.81 54.32,78.81
PS_VDD_EN: length 280.3
  TOP w0.127: 65.7,67.13 65.87,67.3 65.87,69.23 65.5,69.6 U27.B3
  TOP w0.254: v2(40.01,68.25) 40.39,67.87 48.92,67.87 51.56,65.23 53.8,65.23 54.12,64.9 64.91,64.9 65.56,65.55 65.56,66.99 65.7,67.13
  L5_INT_2 w0.254: v2(79.71,222.15) 80.44,221.41 80.44,220.7 80.12,220.38 79.52,220.38 78.89,221.01 78.13,221.01 77.75,220.62 77.75,220.19 77.31,219.75 74.76,219.75 55.4,239.12 25.8,239.12 24.26,237.57 24.26,234.4 24.66,233.99 25.79,233.99 28.51,231.28 28.51,229.67 29.32,228.86 29.32,209.73 28.69,209.1 28.69,171.46 30.71,169.44 30.71,164.41 31.76,163.36 31.76,158.71 30.59,157.54 30.59,148.37 33.32,145.64 33.32,143.21 33.76,142.77 33.76,131.98 32.33,130.56 32.33,123.37 36.9,118.8 36.9,112.34 38.03,111.2 38.03,82.44 39.52,80.95 39.52,68.73 v2(40.01,68.25)
  BOTTOM w0.254: U3.14 79.95,221.91 v2(79.71,222.15) 79.96,222.41 U3.15
PS_VDD_PG: length 282.5
  TOP w0.127: U27.B2 66.27,69.6 66.67,69.2 66.67,68.36 66.88,68.15
  TOP w0.254: v2(38.79,68.15) 39.7,67.23 48.59,67.23 52.15,63.68 64.97,63.68 66.88,65.58 66.88,68.15
  L5_INT_2 w0.254: v2(38.79,68.15) 38.79,80.97 37.43,82.33 37.43,110.98 36.32,112.09 36.32,117.99 35.67,118.64 34.42,118.64 33.66,119.41 33.66,120.94 31.7,122.89 31.7,130.89 32.69,131.87 32.69,139.7 32.05,140.34 32.05,145.95 30.09,147.92 30.09,157.85 31.14,158.9 31.14,161.26 29.79,162.61 29.79,168.1 28.16,169.73 28.16,209.02 27.46,209.73 27.46,228.86 25.96,230.36 25.96,231.99 25.12,232.82 23.36,232.82 22.89,233.3 22.89,237.28 26.12,240.51 54.91,240.51 74.35,221.08 77.39,221.08 77.87,221.55 79.34,221.55 v2(79.74,221.15)
  BOTTOM w0.254: U3.12 79.98,220.91 v2(79.74,221.15) 79.74,221.15 79.99,221.41 U3.13
PS_VTT_EN: length 429.4
  TOP w0.254: v2(34.09,197.38) 34.22,197.25 U14.7 ; U17.7 182.65,191.59 v2(182.73,191.67)
  L3_INT_1 w0.254: v2(119.79,238.84) 114.45,233.5 99.31,233.5 96.72,230.91 96.72,229.54 95.96,228.78 91.59,228.78 90.58,229.79 78.49,229.79 77.55,228.85 64.19,228.85 55.17,237.87 44.2,237.87 41.78,235.46 41.78,209.3 34.09,201.6 v2(34.09,197.38)
  L14_INT_6 w0.254: v1(67.07,72) 67.74,71.33 67.74,69.6 68.3,69.04 68.3,65.35 67.08,64.14 63.96,64.14 62.61,62.78 51.59,62.78 46.86,67.51 43.36,67.51 40.31,70.56 40.31,113.77 41.38,114.83 41.38,122.68 30.3,133.76 30.3,140.26 31.98,141.93 31.98,151.51 30.96,152.53 30.96,156.26 39.83,165.13 39.83,193.24 36.93,196.14 35.33,196.14 v2(34.09,197.38)
  BOTTOM w0.254: v2(182.73,191.67) 182.7,191.67 181.41,192.96 175.49,192.96 174.85,193.6 174.85,239.19 166.74,247.31 151.14,247.31 140.32,236.49 123.56,236.49 121.21,238.84 v2(119.79,238.84)
PS_XVDD_EN: length 112.9
  TOP w0.127: 62.94,68.2 62.66,68.48 62.66,73.05 62.81,73.2 63.47,73.2 U27.G5
  TOP w0.254: v2(31.11,134.8) 30.61,134.8 30.18,135.23 TP219.1 ; 62.94,68.2 63.91,67.23 64.67,67.23 v2(65.33,67.89)
  TOP w0.305: TP219.1 30.47,136.18 U25.3
  L14_INT_6 w0.254: v2(65.33,67.89) 65.66,67.56 65.66,65.48 64.99,64.81 63.82,64.81 62.32,63.31 51.9,63.31 47.07,68.15 43.64,68.15 40.94,70.84 40.94,113.31 42.01,114.38 42.01,122.96 31.11,133.86 v2(31.11,134.8)
PS_XVDD_PG: length 105
  TOP w0.118: U25.6 v2(31.97,136.48)
  L14_INT_6 w0.087: v1(63.87,72.8) 64.26,72.41 64.26,71.02 64.45,70.83 64.76,70.83 64.81,70.78 64.82,70.78 65.04,70.56 65.04,68.4 64.85,68.2 64.85,67.51 61.16,63.83 52.1,63.83 47.32,68.61 43.97,68.61 41.48,71.09 41.48,113 42.65,114.17 42.65,123.16 32.84,132.97 32.84,135.61 v2(31.97,136.48)
QSC_CLK: length 6.6
  TOP w0.118: U27.G16 54.9,73.43 53.7,73.43 52.2,71.93 TP193.1
QSC_SDI: length 9.7
  TOP w0.118: v2(47.47,73.66) TP194.1
  L5_INT_2 w0.087: v1(55.87,73.6) 55.07,74.4 53.52,74.4 52.78,73.66 v2(47.47,73.66)
QSC_SDO: length 6.4
  TOP w0.118: U27.H16 53.93,74.4 52.73,73.2 TP195.1
QSC_SS: length 8.7
  TOP w0.118: TP192.1 v2(48.64,74.47)
  L5_INT_2 w0.087: v1(55.87,74.4) 54.95,75.32 53.58,75.32 52.73,74.47 v2(48.64,74.47)
QT2: length 5.4
  TOP w0.118: U27.B16 53.6,69.6 52.2,68.2 TP290.1
QT3: length 2.8
  TOP w0.118: U27.T3 65.79,81.12 TP259.1
R_SD1_RX0_N: length 1.4
  TOP w0.102: U22.D15 v3(108.33,144.2)
  BOTTOM w0.118: R5877.2 108.83,144.69 v3(108.33,144.2)
R_SD1_RX0_P: length 1.4
  TOP w0.102: U22.C15 v3(108.33,143.2)
  BOTTOM w0.118: v3(108.33,143.2) 108.83,143.69 R5876.2
R_SD1_RX1_N: length 1.4
  TOP w0.118: U22.B16 v3(107.33,143.2)
  BOTTOM w0.118: R5879.2 106.84,142.7 v3(107.33,143.2)
R_SD1_RX1_P: length 1.4
  TOP w0.118: U22.A16 v3(107.33,142.2)
  BOTTOM w0.118: R5878.2 106.84,141.7 v3(107.33,142.2)
R_SD1_RX2_N: length 1.4
  TOP w0.102: U22.D17 v3(106.33,144.2)
  BOTTOM w0.118: v3(106.33,144.2) 105.84,144.69 R5881.2
R_SD1_RX2_P: length 1.4
  TOP w0.102: U22.C17 v3(106.33,143.2)
  BOTTOM w0.118: R5880.2 105.84,143.69 v3(106.33,143.2)
R_SD1_RX3_N: length 4.1
  TOP w0.102: U22.B18 v3(105.33,142.2)
  BOTTOM w0.118: v3(105.33,142.2) 104.9,141.77 R5883.2
R_SD1_RX3_P: length 3.2
  TOP w0.102: U22.A18 v3(105.33,141.2)
  BOTTOM w0.118: v3(105.33,141.2) 105.92,140.61 R5882.2
R_SD1_RX4_N: length 118.2
  TOP w0.091: U22.D19 v3(104.33,144.2) ; C443.1 122.31,61.19 122.31,61.48 R532.2 122.31,62.22 122.31,63.16 122.91,63.75 122.91,64.84 122.62,65.13 122.3,65.13 v2(122.03,65.39)
  L5_INT_2 w0.086: v2(122.03,65.39) 122.27,65.16 132.05,65.16 132.36,65.47 132.37,65.47 139.42,72.52 139.42,75.17 142.49,78.24 142.49,98.2 115.96,124.73 113.09,124.73 112.36,125.46 112.36,129.65 108.84,133.18 108.84,134.25 103.65,139.44 103.65,140.57 103.71,140.64 103.71,143.64 103.97,143.89 104.2,143.89 104.33,144.02 v3(104.33,144.2)
R_SD1_RX4_P: length 118.2
  TOP w0.091: U22.C19 v3(104.33,143.2) ; v2(122.03,64.58) 122.3,64.85 122.5,64.85 122.63,64.72 122.63,63.87 122.03,63.27 122.03,62.22 R532.1 122.03,61.48 122.03,61.19 C444.1
  L5_INT_2 w0.086: v3(104.33,143.2) 104.33,143.59 104.24,143.68 104.06,143.68 103.93,143.55 103.93,140.64 103.99,140.57 103.99,139.58 109.18,134.39 109.18,133.32 112.71,129.8 112.71,125.6 113.24,125.07 116.11,125.07 142.84,98.34 142.84,78.1 139.76,75.02 139.76,72.37 132.51,65.12 132.5,65.12 132.19,64.81 122.27,64.81 v2(122.03,64.58)
R_SD1_RX5_N: length 112
  TOP w0.091: v3(103.33,142.2) U22.B20 ; C445.1 124.7,61.19 124.7,61.48 R533.2 124.7,62.22 124.7,64.02 124.22,64.5 124.22,66.46 124.56,66.8 125.04,66.8 v2(125.29,67.04)
  L5_INT_2 w0.086: v2(125.29,67.04) 125.53,66.8 131.84,66.8 138.1,73.06 138.1,75.72 141.17,78.79 141.17,97.18 114.95,123.41 112.55,123.41 111.04,124.91 111.04,129.11 107.45,132.69 107.45,133.72 102.64,138.53 102.64,140.8 102.7,140.86 102.7,141.56 102.99,141.84 103.24,141.84 103.33,141.94 v3(103.33,142.2)
R_SD1_RX5_P: length 111.9
  TOP w0.091: C446.1 124.98,61.19 124.98,61.48 R533.1 124.98,62.22 124.98,64.14 124.5,64.62 124.5,66.35 124.67,66.52 125.02,66.52 125.29,66.26 v2(125.29,66.23) ; v3(103.33,141.2) U22.A20
  L5_INT_2 w0.086: v2(125.29,66.23) 125.52,66.46 131.98,66.46 138.44,72.92 138.44,75.58 141.52,78.65 141.52,97.32 115.09,123.75 112.69,123.75 111.39,125.05 111.39,129.25 107.8,132.84 107.8,133.86 102.98,138.67 102.98,140.8 102.92,140.86 102.92,141.47 103.08,141.63 103.24,141.63 103.33,141.55 v3(103.33,141.2)
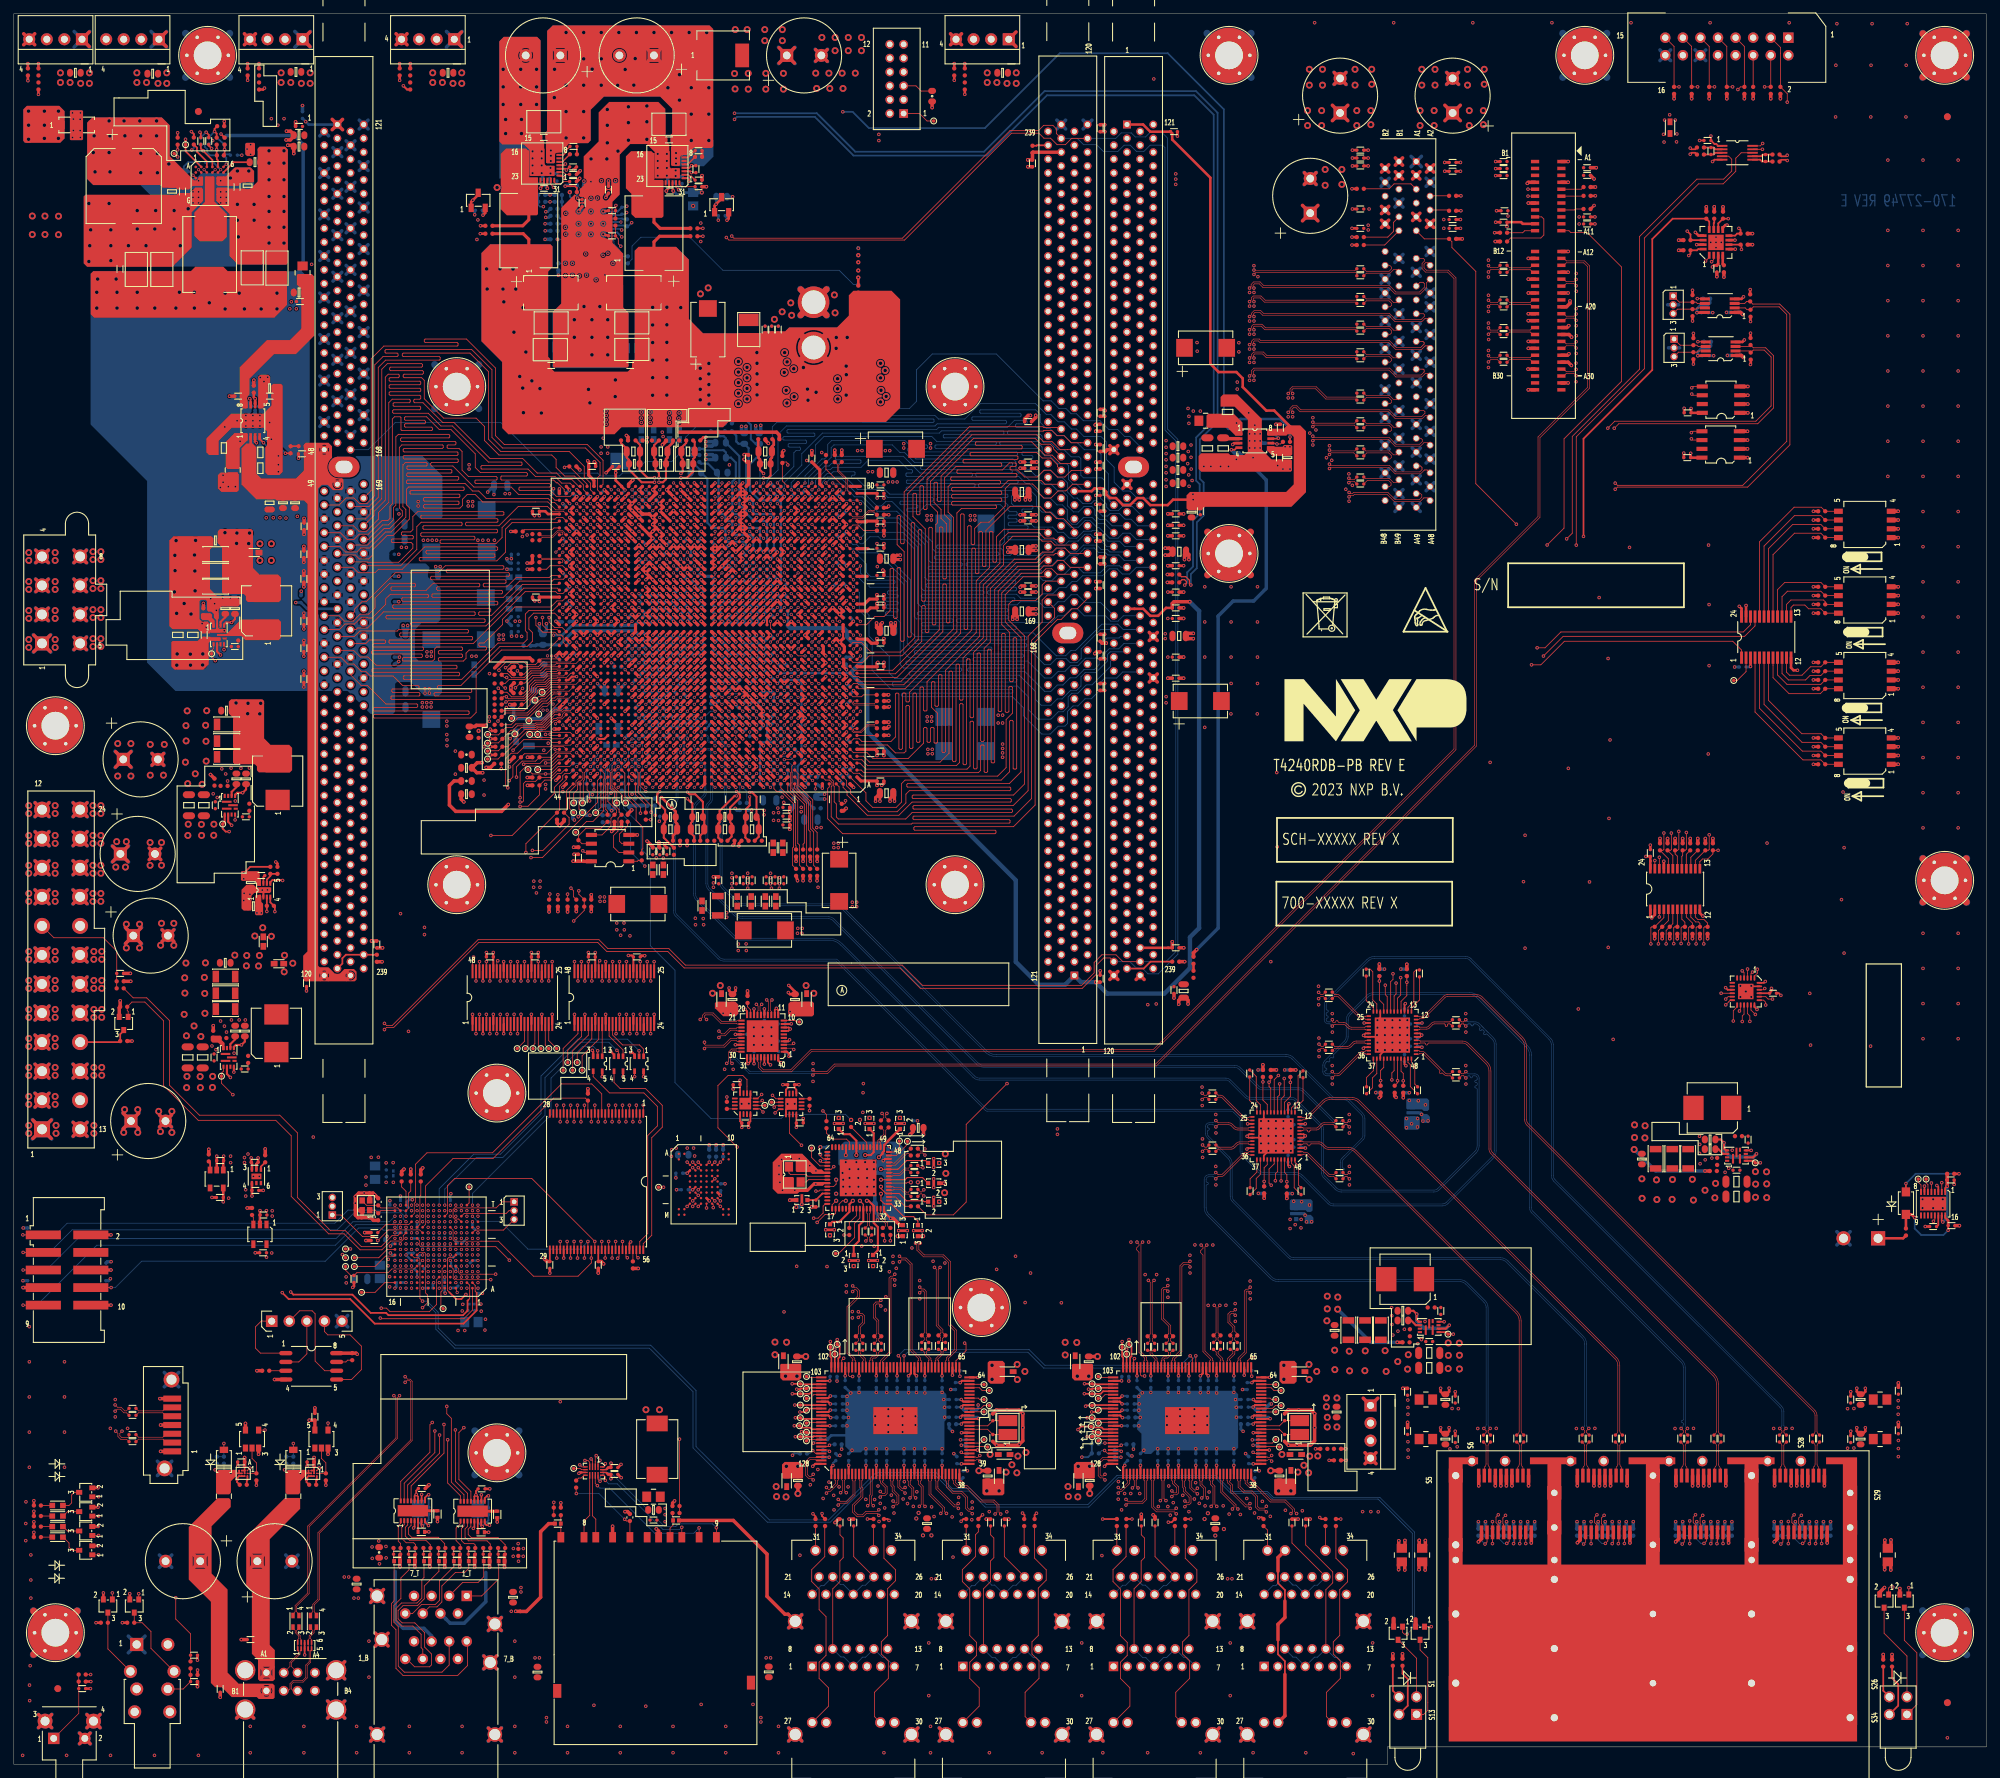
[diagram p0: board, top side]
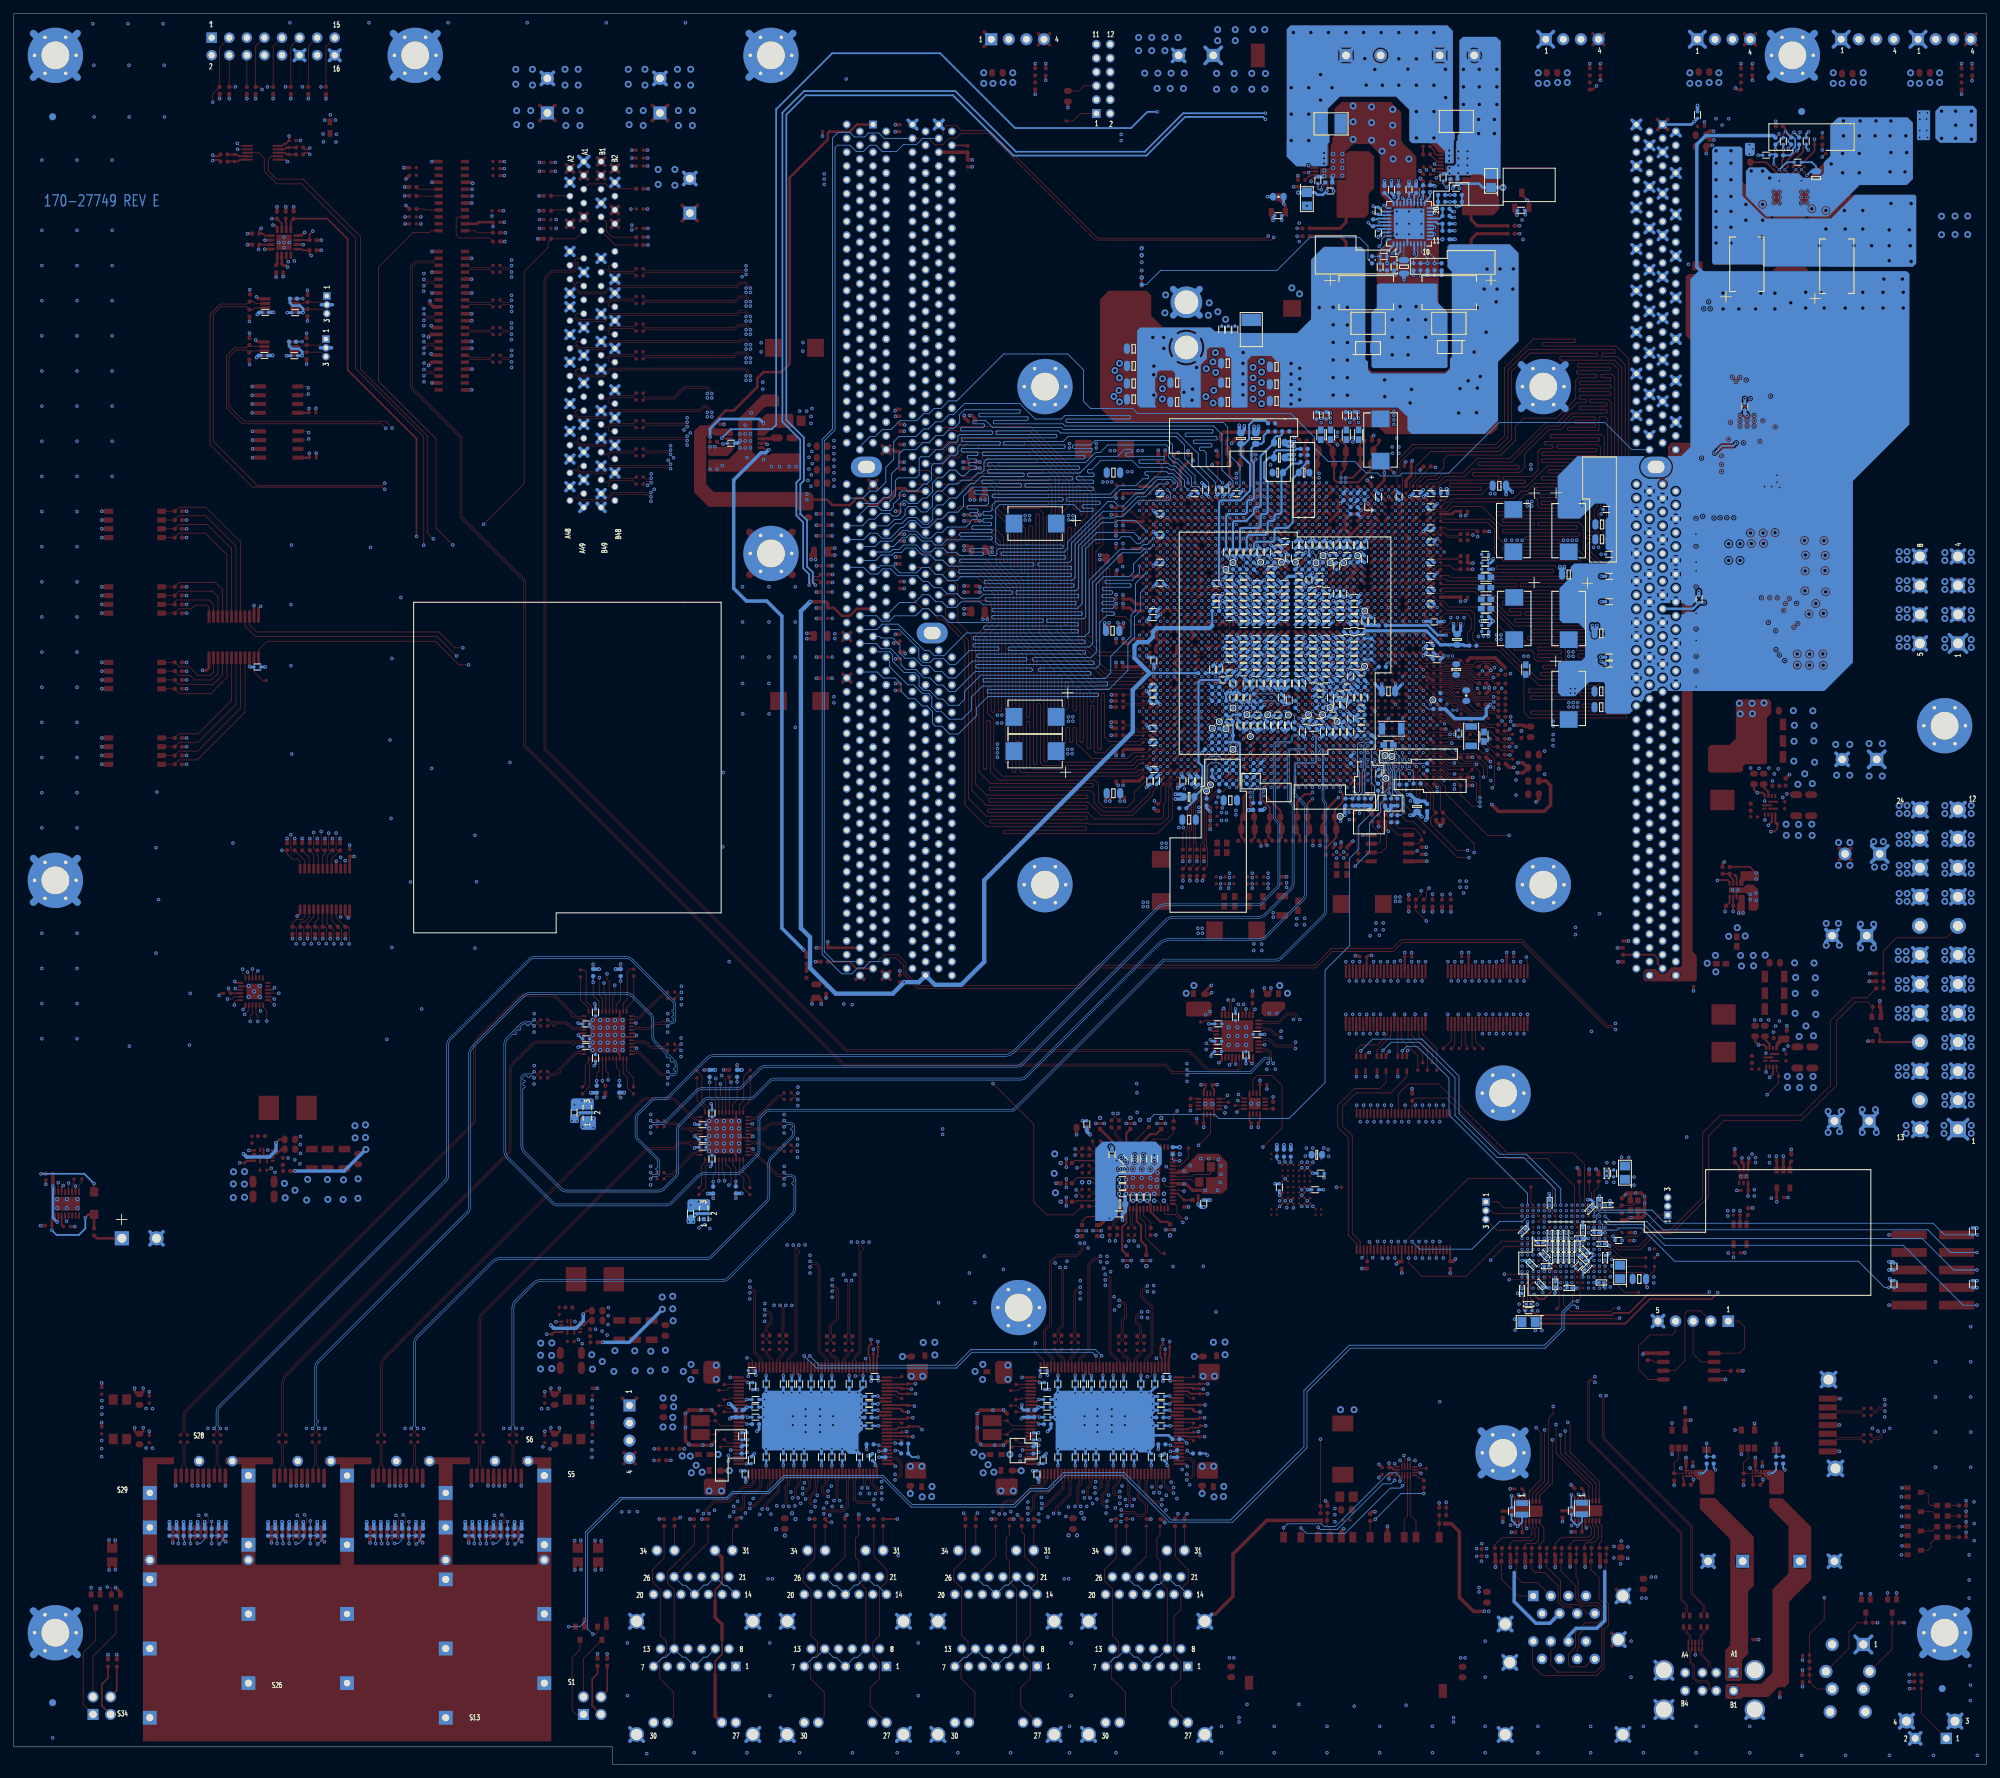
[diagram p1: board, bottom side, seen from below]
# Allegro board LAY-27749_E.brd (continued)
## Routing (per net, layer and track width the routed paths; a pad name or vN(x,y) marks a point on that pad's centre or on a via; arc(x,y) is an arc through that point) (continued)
R_SD1_RX6_N: length 107.1
  TOP w0.091: C448.1 131.84,61.32 131.84,61.62 132.19,61.98 R534.2 131.84,62.34 131.84,68.36 131.52,68.68 131.17,68.68 v2(130.9,68.95) ; v3(102.33,144.2) U22.D21
  L5_INT_2 w0.086: v2(130.9,68.95) 131.14,68.71 131.77,68.71 136.49,73.42 136.49,76.06 139.65,79.23 139.65,96.83 114.4,122.09 112,122.09 108.13,125.96 108.13,129.89 106.06,131.96 106.06,133.28 101.65,137.69 101.65,140.73 101.72,140.79 101.72,143.66 101.93,143.87 102.24,143.87 102.33,143.96 v3(102.33,144.2)
R_SD1_RX6_P: length 107
  TOP w0.091: v3(102.33,143.2) U22.C21 ; v2(130.9,68.14) 131.17,68.4 131.41,68.4 131.56,68.25 131.56,62.34 R534.1 131.2,61.98 131.56,61.62 131.56,61.32 C447.1
  L5_INT_2 w0.086: v3(102.33,143.2) 102.33,143.57 102.24,143.66 102.01,143.66 101.93,143.57 101.93,140.79 101.99,140.73 101.99,137.83 106.4,133.43 106.4,132.11 108.47,130.04 108.47,126.1 112.14,122.43 114.54,122.43 139.99,96.98 139.99,79.08 136.83,75.92 136.83,73.28 131.92,68.36 131.13,68.36 v2(130.9,68.14)
R_SD1_RX7_N: length 102.8
  TOP w0.091: C449.1 133.91,61.26 133.91,61.67 R535.2 133.97,62.34 133.97,62.7 133.29,63.38 133.29,71.55 v2(133.03,71.8) ; v3(101.33,142.2) U22.B22
  L5_INT_2 w0.086: v3(101.33,142.2) 101.12,141.98 100.86,141.98 100.56,141.68 100.56,140.64 100.81,140.38 100.81,136.65 103.01,134.45 103.01,132.5 106.65,128.85 106.65,124.58 112.37,118.87 115.42,118.87 138.3,95.98 138.3,79.78 134.82,76.3 134.82,73.91 133.27,72.35 133.27,72.04 v2(133.03,71.8)
R_SD1_RX7_P: length 102.8
  TOP w0.091: C450.1 134.38,60.95 134.19,61.14 134.19,61.55 R535.1 134.25,62.35 134.25,62.82 133.57,63.5 133.57,71.53 v2(133.85,71.8) ; v3(101.33,141.2) U22.A22
  L5_INT_2 w0.086: v3(101.33,141.2) 101.33,141.55 101.24,141.64 101,141.64 100.9,141.54 100.9,140.78 101.16,140.53 101.16,136.79 103.35,134.59 103.35,132.64 107,128.99 107,124.73 112.51,119.21 115.56,119.21 138.65,96.13 138.65,79.64 135.16,76.16 135.16,73.77 133.61,72.21 133.61,72.04 v2(133.85,71.8)
R_SD2_RX4_N: length 117
  TOP w0.091: v3(95.33,144.2) U22.D27 ; C451.1 164.52,61.15 164.52,61.52 R536.2 164.82,61.85 164.49,62.18 164.49,69.66 v2(164.76,69.93)
  L12_INT_5 w0.086: v2(164.76,69.93) 164.52,70.16 164.52,70.96 163.82,71.67 160.06,71.67 114.19,117.54 112,117.54 102.77,126.77 102.77,128.36 100.2,130.93 100.2,133.1 96.52,136.78 96.52,138.36 96.01,138.87 96.01,139.58 95.94,139.64 95.94,143.67 95.71,143.9 95.49,143.9 95.33,144.06 v3(95.33,144.2)
R_SD2_RX4_P: length 116.9
  TOP w0.091: v2(163.94,69.93) 164.21,69.66 164.21,62.18 163.88,61.85 R536.1 164.16,61.52 164.16,61.16 C452.1 ; v3(95.33,143.2) U22.C27
  L12_INT_5 w0.086: v2(163.94,69.93) 164.18,70.16 164.18,70.82 163.68,71.32 159.92,71.32 114.05,117.2 111.86,117.2 102.43,126.63 102.43,128.22 99.86,130.79 99.86,132.95 96.18,136.64 96.18,138.22 95.67,138.73 95.67,139.51 95.73,139.58 95.73,143.58 95.63,143.69 95.44,143.69 95.33,143.58 v3(95.33,143.2)
R_SD2_RX5_N: length 119.7
  TOP w0.091: v2(166.75,69.18) 166.48,68.91 166.1,68.91 165.84,68.65 165.84,64.34 166.89,63.28 166.89,62.24 R537.2 166.87,61.48 166.87,61.19 C453.1 ; v3(94.33,142.2) U22.B28
  L12_INT_5 w0.086: v2(166.75,69.18) 166.52,68.95 160.87,68.95 113.6,116.22 111.44,116.22 103.76,123.9 102.21,123.9 98.45,127.66 98.45,132.94 95.37,136.03 95.37,138.26 95.12,138.5 95.12,138.79 95.05,138.85 95.05,140.19 94.95,140.3 94.95,141.65 94.73,141.86 94.43,141.86 94.33,141.96 v3(94.33,142.2)
R_SD2_RX5_P: length 119.6
  TOP w0.091: v2(166.75,68.36) 166.48,68.63 166.22,68.63 166.12,68.53 166.12,64.45 167.17,63.4 167.17,62.19 R537.1 167.14,61.48 167.14,61.19 C454.1 ; v3(94.33,141.2) U22.A28
  L12_INT_5 w0.086: v2(166.75,68.36) 166.51,68.61 160.73,68.61 113.46,115.87 111.3,115.87 103.62,123.56 102.07,123.56 98.11,127.52 98.11,132.8 95.02,135.89 95.02,138.12 94.78,138.36 94.78,138.75 94.84,138.81 94.84,140.1 94.73,140.21 94.73,141.56 94.64,141.65 94.42,141.65 94.33,141.56 v3(94.33,141.2)
R_SD2_RX6_N: length 129.6
  TOP w0.091: v2(174.27,66.32) 174,66.05 174,62.34 R538.2 174,61.61 174,61.32 C456.1 ; v3(93.33,144.2) U22.D29
  L12_INT_5 w0.086: v3(93.33,144.2) 93.33,144.04 93.46,143.91 93.71,143.91 93.95,143.68 93.95,140.33 94.26,140.02 94.26,139.23 94.06,139.03 94.06,138.66 94.12,138.59 94.12,134.38 95.71,132.8 95.71,127.41 102.31,120.8 104.99,120.8 116.61,109.18 118.27,109.18 160.41,67.04 169.25,67.04 170.01,67.81 173.42,67.81 174.03,67.19 174.03,66.55 v2(174.27,66.32)
R_SD2_RX6_P: length 129.5
  TOP w0.091: C455.1 173.72,61.32 173.72,61.61 R538.1 173.72,62.34 173.72,66.05 v2(173.46,66.32) ; v3(93.33,143.2) U22.C29
  L12_INT_5 w0.086: v2(173.46,66.32) 173.69,66.55 173.69,67.05 173.28,67.46 170.15,67.46 169.39,66.7 160.27,66.7 118.13,108.84 116.47,108.84 104.85,120.46 102.17,120.46 95.36,127.26 95.36,132.65 93.78,134.24 93.78,138.53 93.84,138.59 93.84,139.12 94.05,139.32 94.05,139.93 93.74,140.24 93.74,143.59 93.63,143.7 93.42,143.7 93.33,143.61 v3(93.33,143.2)
R_SD2_RX7_N: length 133.4
  TOP w0.091: v2(176.49,65.7) 176.23,65.43 175.8,65.43 175.44,65.06 175.44,63.84 176.15,63.13 176.15,62.56 175.77,62.18 R539.2 176.14,61.61 176.14,61.32 C457.1 ; v3(92.33,142.2) U22.B30
  L12_INT_5 w0.086: v2(176.49,65.7) 176.26,65.46 159.69,65.46 118.85,106.3 116.28,106.3 105.73,116.85 102.21,116.85 92.34,126.72 92.34,134.33 91.52,135.15 91.52,137.77 93.02,139.27 93.02,140.02 93.02,140.14 92.94,140.21 92.94,141.69 92.73,141.9 92.42,141.9 92.33,141.98 v3(92.33,142.2)
R_SD2_RX7_P: length 133.4
  TOP w0.091: v3(92.33,141.2) U22.A30 ; v2(176.49,64.88) 176.23,65.15 175.92,65.15 175.72,64.95 175.72,63.96 176.43,63.25 176.43,62.56 176.78,62.2 R539.1 176.42,61.61 176.42,61.32 C458.1
  L12_INT_5 w0.086: v3(92.33,141.2) 92.33,141.6 92.42,141.69 92.64,141.69 92.73,141.6 92.73,140.2 92.67,140.14 92.67,140.02 92.67,139.41 91.17,137.91 91.17,135.01 92,134.19 92,126.58 102.07,116.51 105.59,116.51 116.14,105.96 118.71,105.96 159.54,65.12 176.26,65.12 v2(176.49,64.88)
R_SD2_TX0_N: length 144.8
  TOP w0.091: v3(99.33,149.2) U22.J23 ; C230.1 192.35,85.23 arc(192.38,85.21) 192.41,85.2 192.63,85.2 arc(192.66,85.21) 192.69,85.23 v2(192.99,85.52)
  BOTTOM w0.091: v2(192.99,85.52) 192.69,85.23 arc(192.66,85.21) 192.63,85.2 192.16,85.2 arc(192.01,85.27) 191.95,85.42 191.95,85.7 arc(191.99,85.81) 192.1,85.85 arc(192.25,86) 192.1,86.16 arc(191.99,86.2) 191.95,86.31 191.95,87.02 arc(191.99,87.22) 192.1,87.39 194.98,90.26 arc(195.16,90.54) 195.22,90.86 195.22,93.3 arc(195.14,93.74) 194.89,94.12 193.03,95.97 arc(192.65,96.23) 192.2,96.32 190.97,96.32 arc(190.74,96.36) 190.54,96.5 184.9,102.13 arc(184.42,102.45) 183.86,102.57 141.93,102.57 arc(141.18,102.71) 140.55,103.14 119.77,123.92 arc(119.28,124.24) 118.7,124.36 105.27,124.36 arc(105,124.41) 104.77,124.57 102.52,126.81 arc(102.38,127.02) 102.34,127.26 102.34,135.79 arc(102.37,135.95) 102.46,136.09 102.77,136.4 arc(102.91,136.61) 102.96,136.87 102.96,140.83 arc(102.96,140.86) 102.94,140.88 arc(102.93,140.91) 102.92,140.93 102.92,147.35 arc(102.79,147.67) 102.46,147.8 100.63,147.8 arc(100.49,147.86) 100.43,148.01 100.43,148.29 arc(100.27,148.67) 99.88,148.83 99.56,148.83 arc(99.4,148.9) 99.33,149.06 v3(99.33,149.2)
R_SD2_TX0_P: length 144.7
  TOP w0.091: C231.1 192.35,84.9 arc(192.38,84.92) 192.41,84.92 192.61,84.92 arc(192.66,84.91) 192.71,84.88 v2(192.99,84.61) ; v3(99.33,148.2) U22.H23
  BOTTOM w0.091: v2(192.99,84.61) 192.69,84.9 arc(192.66,84.92) 192.63,84.92 192.16,84.92 arc(191.81,85.07) 191.67,85.42 191.67,87.02 arc(191.73,87.33) 191.9,87.59 194.78,90.46 arc(194.9,90.64) 194.94,90.86 194.94,93.3 arc(194.88,93.63) 194.69,93.92 192.83,95.78 arc(192.54,95.97) 192.2,96.04 190.97,96.04 arc(190.63,96.11) 190.34,96.3 184.7,101.94 arc(184.32,102.2) 183.86,102.29 141.93,102.29 arc(141.08,102.46) 140.35,102.94 119.57,123.72 arc(119.17,123.99) 118.7,124.08 105.27,124.08 arc(104.89,124.15) 104.57,124.37 102.32,126.62 arc(102.13,126.91) 102.06,127.26 102.06,135.79 arc(102.11,136.06) 102.26,136.29 102.57,136.6 arc(102.66,136.72) 102.68,136.87 102.68,140.83 arc(102.69,140.86) 102.71,140.88 arc(102.72,140.91) 102.73,140.93 102.73,147.35 arc(102.65,147.53) 102.46,147.61 100.63,147.61 arc(100.35,147.73) 100.24,148.01 100.24,148.29 arc(100.13,148.54) 99.88,148.64 99.46,148.64 arc(99.37,148.6) 99.33,148.51 v3(99.33,148.2)
R_SD2_TX1_N: length 131.7
  TOP w0.091: v3(98.33,147.2) U22.G24 ; C228.1 192.33,92.74 arc(192.37,92.72) 192.42,92.71 192.62,92.71 arc(192.66,92.72) 192.69,92.74 v2(192.98,93.03)
  BOTTOM w0.091: v2(192.98,93.03) 192.69,92.74 arc(192.66,92.72) 192.61,92.71 192.15,92.71 arc(192.04,92.75) 192,92.86 arc(191.85,93.01) 191.69,92.86 arc(191.65,92.75) 191.54,92.71 191.41,92.71 arc(191.18,92.76) 190.99,92.88 186.43,97.44 arc(186.07,97.68) 185.65,97.76 180.44,97.76 arc(180.16,97.82) 179.92,97.98 177.26,100.64 arc(176.85,100.92) 176.35,101.02 140.13,101.02 arc(139.71,101.1) 139.35,101.34 118.55,122.14 arc(118.15,122.41) 117.67,122.5 105.34,122.5 arc(104.7,122.63) 104.16,122.99 100.58,126.57 arc(100.36,126.91) 100.28,127.3 100.28,138.36 arc(100.32,138.54) 100.42,138.7 100.72,139 arc(100.87,139.23) 100.93,139.49 100.93,145.68 arc(100.92,145.71) 100.91,145.73 arc(100.89,145.76) 100.88,145.78 100.88,146.31 arc(100.74,146.65) 100.4,146.79 98.42,146.79 arc(98.36,146.82) 98.33,146.88 v3(98.33,147.2)
R_SD2_TX1_P: length 131.5
  TOP w0.091: v3(98.33,146.2) U22.F24 ; C229.1 192.33,92.4 arc(192.37,92.42) 192.42,92.43 192.61,92.43 arc(192.66,92.42) 192.69,92.4 v2(192.98,92.11)
  BOTTOM w0.091: v2(192.98,92.11) 192.78,92.3 arc(192.65,92.4) 192.48,92.43 191.41,92.43 arc(191.07,92.5) 190.79,92.69 186.23,97.24 arc(185.96,97.42) 185.65,97.49 180.44,97.49 arc(180.05,97.56) 179.73,97.78 177.06,100.44 arc(176.74,100.66) 176.35,100.74 140.13,100.74 arc(139.6,100.84) 139.15,101.14 118.35,121.94 arc(118.04,122.15) 117.67,122.22 105.34,122.22 arc(104.59,122.37) 103.96,122.8 100.39,126.37 arc(100.1,126.8) 100,127.3 100,138.36 arc(100.06,138.65) 100.22,138.89 100.53,139.2 arc(100.62,139.33) 100.65,139.49 100.65,145.68 arc(100.65,145.71) 100.67,145.73 arc(100.69,145.76) 100.69,145.78 100.69,146.31 arc(100.61,146.51) 100.4,146.6 98.42,146.6 arc(98.36,146.57) 98.33,146.51 v3(98.33,146.2)
R_SD2_TX2_N: length 179.5
  TOP w0.091: C226.1 209.16,99.82 arc(209.19,99.8) 209.23,99.79 209.47,99.79 arc(209.51,99.8) 209.54,99.82 v2(209.81,100.1) ; v3(97.33,149.2) U22.J25
  BOTTOM w0.091: v3(97.33,149.2) 97.33,148.88 arc(97.3,148.82) 97.24,148.79 97.05,148.79 arc(96.82,148.69) 96.72,148.46 96.72,145.06 arc(96.86,144.74) 97.18,144.6 99.54,144.6 arc(99.72,144.53) 99.8,144.35 99.8,140.91 arc(99.79,140.88) 99.78,140.86 arc(99.76,140.83) 99.75,140.8 99.75,140.31 arc(99.73,140.19) 99.66,140.09 98.53,138.96 arc(98.28,138.59) 98.2,138.15 98.2,125.9 arc(98.31,125.33) 98.63,124.85 104.07,119.41 arc(104.41,119.18) 104.82,119.1 117.8,119.1 arc(118.71,118.92) 119.47,118.41 138.59,99.29 arc(139.04,98.99) 139.58,98.88 175.14,98.88 arc(175.4,98.83) 175.62,98.68 177.94,96.37 arc(178.22,96.18) 178.55,96.11 184.61,96.11 arc(184.88,96.06) 185.1,95.91 188.81,92.2 arc(188.93,92.02) 188.98,91.8 188.98,85.45 arc(189.05,85.08) 189.26,84.77 190.94,83.09 arc(191.37,82.8) 191.87,82.7 205.21,82.7 arc(205.62,82.78) 205.96,83.01 211.29,88.34 arc(211.62,88.83) 211.73,89.42 211.73,99.18 arc(211.56,99.61) 211.13,99.78 210.25,99.78 arc(210.14,99.8) 210.05,99.87 v2(209.81,100.1)
R_SD2_TX2_P: length 179.2
  TOP w0.091: v2(209.81,99.18) 209.51,99.49 arc(209.48,99.51) 209.44,99.51 209.25,99.51 arc(209.22,99.51) 209.19,99.49 C227.1 ; v3(97.33,148.2) U22.H25
  BOTTOM w0.091: v3(97.33,148.2) 97.33,148.51 arc(97.3,148.57) 97.24,148.6 97.05,148.6 arc(96.96,148.56) 96.92,148.46 96.92,145.06 arc(96.99,144.87) 97.18,144.8 99.54,144.8 arc(99.86,144.66) 99.99,144.35 99.99,140.91 arc(100,140.88) 100.01,140.86 arc(100.03,140.83) 100.03,140.8 100.03,140.31 arc(99.99,140.08) 99.86,139.89 98.73,138.76 arc(98.54,138.48) 98.48,138.15 98.48,125.9 arc(98.57,125.44) 98.83,125.05 104.27,119.61 arc(104.52,119.44) 104.82,119.38 117.8,119.38 arc(118.81,119.18) 119.67,118.61 138.79,99.49 arc(139.15,99.25) 139.58,99.16 175.14,99.16 arc(175.51,99.09) 175.82,98.88 178.13,96.57 arc(178.33,96.44) 178.55,96.39 184.61,96.39 arc(184.98,96.32) 185.3,96.11 189.01,92.4 arc(189.19,92.12) 189.26,91.8 189.26,85.45 arc(189.31,85.19) 189.46,84.96 191.13,83.29 arc(191.47,83.06) 191.87,82.98 205.21,82.98 arc(205.51,83.04) 205.76,83.21 211.09,88.53 arc(211.36,88.94) 211.46,89.42 211.46,97.54 arc(211.4,97.68) 211.25,97.74 arc(211.1,97.89) 211.25,98.04 arc(211.4,98.1) 211.46,98.25 211.46,98.4 arc(211.41,98.51) 211.3,98.55 211.25,98.55 arc(211.1,98.7) 211.25,98.86 211.3,98.86 arc(211.41,98.9) 211.46,99.01 211.46,99.18 arc(211.36,99.41) 211.13,99.5 210.9,99.5 arc(210.79,99.46) 210.74,99.35 arc(210.59,99.2) 210.44,99.35 arc(210.39,99.46) 210.29,99.5 210.23,99.5 arc(210.14,99.48) 210.07,99.43 v2(209.81,99.18)
R_SD2_TX3_N: length 190.8
  TOP w0.091: C224.1 209.16,107.32 arc(209.2,107.3) 209.24,107.29 209.45,107.29 arc(209.48,107.29) 209.51,107.31 v2(209.81,107.61) ; v3(96.33,147.2) U22.G26
  BOTTOM w0.091: v2(209.81,107.61) 210.05,107.37 arc(210.13,107.31) 210.24,107.29 211.2,107.29 arc(211.49,107.23) 211.73,107.07 213.83,104.97 arc(214.1,104.56) 214.2,104.08 214.2,88.67 arc(214.08,88.05) 213.72,87.52 207.24,81.04 arc(206.86,80.79) 206.41,80.7 190.67,80.7 arc(190.27,80.78) 189.92,81.01 186.06,84.86 arc(185.64,85.14) 185.15,85.24 180.54,85.24 arc(180.18,85.32) 179.87,85.52 177.42,87.97 arc(177.25,88.23) 177.19,88.53 177.19,93.09 arc(177.16,93.27) 177.06,93.41 176.25,94.22 arc(176.07,94.34) 175.85,94.39 140.66,94.39 arc(140.51,94.42) 140.38,94.5 118.8,116.08 102.64,116.08 arc(102.16,116.17) 101.75,116.44 95.63,122.57 arc(95.38,122.95) 95.29,123.39 95.29,138.72 arc(95.33,138.93) 95.45,139.12 95.58,139.24 95.59,139.26 arc(95.67,139.36) 95.69,139.49 95.69,140.78 arc(95.7,140.81) 95.71,140.83 arc(95.73,140.86) 95.73,140.88 95.73,146.44 arc(95.84,146.69) 96.09,146.79 96.24,146.79 arc(96.3,146.82) 96.33,146.88 v3(96.33,147.2)
R_SD2_TX3_P: length 190.3
  TOP w0.091: v2(209.81,106.69) 209.52,106.97 arc(209.48,107) 209.44,107.01 209.24,107.01 arc(209.2,107) 209.16,106.97 C225.1 ; v3(96.33,146.2) U22.F26
  BOTTOM w0.091: v3(96.33,146.2) 96.33,146.51 arc(96.3,146.57) 96.24,146.6 96.09,146.6 arc(95.97,146.55) 95.93,146.44 95.93,140.88 arc(95.93,140.87) 95.93,140.86 arc(95.96,140.83) 95.97,140.78 95.97,139.49 arc(95.92,139.26) 95.79,139.06 95.65,138.92 arc(95.59,138.83) 95.57,138.72 95.57,123.39 arc(95.64,123.05) 95.83,122.76 101.95,116.64 arc(102.27,116.43) 102.64,116.36 118.92,116.36 140.58,94.7 arc(140.61,94.67) 140.66,94.67 175.85,94.67 arc(176.17,94.6) 176.45,94.42 177.25,93.61 arc(177.41,93.37) 177.47,93.09 177.47,88.53 arc(177.51,88.33) 177.62,88.16 180.07,85.72 arc(180.29,85.57) 180.54,85.52 185.15,85.52 arc(185.75,85.4) 186.26,85.06 190.12,81.21 arc(190.37,81.04) 190.67,80.98 206.41,80.98 arc(206.75,81.04) 207.04,81.24 213.53,87.72 arc(213.82,88.15) 213.92,88.67 213.92,104.08 arc(213.84,104.45) 213.63,104.77 212.91,105.49 arc(212.77,105.54) 212.64,105.49 arc(212.42,105.49) 212.42,105.7 arc(212.48,105.84) 212.42,105.98 212.29,106.11 arc(212.17,106.16) 212.04,106.11 arc(211.82,106.11) 211.82,106.32 arc(211.88,106.45) 211.82,106.58 211.53,106.87 arc(211.38,106.97) 211.2,107.01 211.02,107.01 arc(210.92,106.96) 210.87,106.85 arc(210.72,106.7) 210.57,106.85 arc(210.52,106.96) 210.41,107.01 210.25,107.01 arc(210.13,106.98) 210.04,106.92 v2(209.81,106.69)
R_SD4_RX4_N: length 1.4
  TOP w0.102: v3(92.33,181.19) U22.BA30
  BOTTOM w0.118: R5885.2 91.83,180.7 v3(92.33,181.19)
R_SD4_RX4_P: length 1.4
  TOP w0.102: v3(92.33,182.19) U22.BB30
  BOTTOM w0.118: v3(92.33,182.19) 91.83,181.7 R5884.2
R_SD4_RX5_N: length 1.4
  TOP w0.102: v3(91.33,183.2) U22.BC31
  BOTTOM w0.118: R5887.2 91.8,182.73 v3(91.33,183.2)
R_SD4_RX5_P: length 1.4
  TOP w0.102: v3(91.33,184.2) U22.BD31
  BOTTOM w0.118: v3(91.33,184.2) 91.82,183.7 R5886.2
R_SD4_RX7_N: length 1.4
  TOP w0.102: v3(89.33,183.2) U22.BC33
  BOTTOM w0.118: R5889.2 89.35,183.2 v3(89.33,183.2)
R_SD4_RX7_P: length 1.4
  TOP w0.102: v3(89.33,184.2) U22.BD33
  BOTTOM w0.118: v3(89.33,184.2) 89.82,183.7 R5888.2
RST_CLKGEN_B: length 66.3
  TOP w0.118: v2(118.48,86.37) 118.1,85.98 U36.6
  L3_INT_1 w0.087: v2(118.48,86.37) 116.3,86.37 113.03,89.64 103.43,89.64 102.39,88.6 100.79,88.6 99.69,87.5 99.69,85.85 99.42,85.57 97.89,85.57 97.61,85.85 93.75,85.85 88.2,80.3 82.51,80.3 69.75,67.54 66.73,67.54 v1(65.47,68.8)
RST_I2CMUX_B: length 289.8
  TOP w0.118: v2(237.78,122.46) 237.77,122.46 U82.3 ; U624.22 252.83,111.93 v2(253.01,112.12)
  L3_INT_1 w0.087: v2(253.01,112.12) 253.95,113.06 253.95,118.06 250.16,121.84 238.39,121.84 v2(237.78,122.46)
  L5_INT_2 w0.087: v1(64.67,68.8) 65.12,68.35 65.71,68.35 66.17,67.89 66.17,58.67 76.38,48.46 76.38,43.33 79.07,40.64 82.3,40.64 83.29,39.65 90.4,39.65 108.41,57.66 117.55,57.66 119.25,59.36 120.35,59.36 120.95,58.75 120.95,56.69 120.73,56.46 120.73,55.76 121.09,55.4 122.58,55.4 124.79,57.61 138.48,57.61 140.7,59.83 159.4,59.83 159.72,59.51 162.2,59.51 162.92,58.8 162.92,55.88 163.93,54.86 174.17,54.86 174.96,55.65 174.96,56.72 177.44,59.21 177.44,99.09 187.4,109.04 191.41,109.04 205.4,123.04 237.2,123.04 v2(237.78,122.46)
RST_IFC_B: length 31.2
  TOP w0.118: U37.14 v2(84.45,92.85)
  L5_INT_2 w0.087: v2(84.45,92.85) 84.45,91.54 80.16,87.25 80.16,80.24 74.6,74.68 67.59,74.68 v1(67.07,75.2)
RST_MEM_B: length 324.8
  L5_INT_2 w0.087: v2(43.27,90.64) 43.27,90.71 42.85,91.14 42.85,123.3 40.06,126.09 40.06,172.3 41.4,173.64 41.4,185.39 46.02,190 J5.168 ; J6.168 153.43,161 156.95,164.52 156.95,186.23 160.71,190 J7.168
  L14_INT_6 w0.087: v1(63.87,70.4) 64.24,70.03 64.24,68.57 64.54,68.28 64.54,67.61 60.99,64.06 52.3,64.06 46.96,69.39 46.96,86.95 v2(43.27,90.64)
  BOTTOM w0.118: J5.168 51.19,190 55.12,193.93 70.36,193.93 77.67,186.61 84.35,186.61 84.76,186.21 87.53,186.21 87.96,186.64 89.59,186.64 91.22,188.28 95.06,188.28 97.05,190.27 97.05,191.8 100.48,195.22 122.6,195.22 123.33,195.95 129.4,195.95 130.43,196.98 130.43,201.55 132.72,203.84 141.96,203.84 148.74,197.05 149.91,197.05 151,195.96 152.02,195.96 152.78,195.2 153.54,195.2 154.56,194.18 156.97,194.18 158.24,192.91 159.51,192.91 160.53,191.9 161.29,191.9 162.75,190.44 J7.168
RST_PCIE_X4_B: length 275.5
  TOP w0.102: 67.39,70.82 64.51,70.82 64.29,71.05 64.29,71.58 63.87,72 U27.E5
  TOP w0.118: U55.A11 224.71,221.65 224.98,221.39 227.33,221.39 232.31,216.41 232.31,199.87 224,191.57 224,178.66 v2(221.56,176.23) ; v2(69.62,70.83) 69.62,70.82 67.39,70.82
  L3_INT_1 w0.087: v2(69.62,70.83) 71.11,70.83 82.66,82.38 87.19,82.38 95.15,90.35 114.93,90.35 119.61,95.02 162.59,95.02 167.87,100.3 174.07,100.3 223.01,149.25 223.01,174.78 v2(221.56,176.23)
RST_PCIE_X8_B: length 280.4
  TOP w0.102: U27.E6 63.07,72 63.49,71.59 63.49,70.24 63.71,70.02 68.9,70.02 v2(68.91,70.03)
  TOP w0.118: J3.A11 203.83,220.47 R145.1 207.8,220.07 207.8,219.23 211.25,215.77 211.25,185.09 v2(217.12,179.22)
  L3_INT_1 w0.087: v2(68.91,70.03) 70.89,70.03 82.85,81.99 87.3,81.99 95.33,90.02 115.09,90.02 119.79,94.72 162.94,94.72 168.15,99.92 174.22,99.92 223.85,149.56 223.85,176.1 220.73,179.22 v2(217.12,179.22)
RST_PHY_1G_B: length 138.2
  TOP w0.118: U42.97 120.63,56.17 120.76,56.03 v2(121.21,56.03) ; U620.97 162.79,56.27 162.95,56.11 v2(163.4,56.11)
  L5_INT_2 w0.087: v1(65.47,70.4) 66.52,69.35 66.52,59.41 77.04,48.9 77.04,44.27 79.77,41.53 82.98,41.53 83.39,41.94 92.2,41.94 108.18,57.91 117.4,57.91 119.1,59.61 120.47,59.61 121.21,58.88 v2(121.21,56.03) 121.51,55.73 121.61,55.73 121.61,55.73 122.46,55.73 124.64,57.91 138.18,57.91 140.44,60.17 159.49,60.17 159.79,60.48 161.85,60.48 163.4,58.93 v2(163.4,56.11)
RST_SPI_B: length 68
  TOP w0.118: v2(82.22,132.02) 82.47,131.78 U26.7
  L5_INT_2 w0.087: v1(66.27,75.2) 66.65,75.59 72.19,75.59 76.78,80.19 76.78,113.51 77.29,114.02 77.29,120.95 79.5,123.16 79.5,126.49 82.22,129.21 v2(82.22,132.02)
RT1_2V5: length 9.9
  TOP w0.254: U65.15 184.12,95.32 v2(184.25,95.45) ; v2(184.33,86.39) 184.12,86.59 U65.46 ; U65.6 186.36,90.56 v2(186.61,90.81) 186.36,91.05 U65.7 ; U65.3 v2(186.64,89.05) ; U65.10 v2(186.61,92.56)
  BOTTOM w0.254: C1109.1 186.46,92.43 186.59,92.56 v2(186.61,92.56) ; C1113.1 186.51,89.18 v2(186.64,89.05) ; v2(186.61,90.81) 186.08,90.27 C1111.1 ; v2(184.25,95.45) 184.12,95.32 C1110.1 ; C5302.1 184.12,86.59 v2(184.33,86.39)
  vias: v2(184.94,81.36) v2(186.08,81.31) v2(187.22,80.82)
RT1_ADDR0: length 4.8
  TOP w0.118: R5829.1 v2(183.95,84.2) 183.95,85.19 183.62,85.52 U65.45
  BOTTOM w0.118: R5829.1 v2(183.95,84.2)
RT1_ADDR1: length 4.8
  TOP w0.118: R5830.1 v2(180.67,84.23) 180.67,86.21 181.12,86.66 U65.40
  BOTTOM w0.118: R5830.1 v2(180.67,84.23)
RT1_ADDR2: length 6.1
  TOP w0.118: U65.21 181.12,95.36 180.49,95.99 v2(180.49,98.62) R5831.1
  BOTTOM w0.118: R5831.1 v2(180.49,98.62)
RT1_ADDR3: length 6.3
  TOP w0.118: U65.16 183.62,95.69 184.46,96.53 v2(184.46,98.55) R5832.1
  BOTTOM w0.118: v2(184.46,98.55) R5832.1
RT2_2V5: length 9.7
  TOP w0.254: v2(201.16,100.96) 200.95,101.17 U622.46 ; U622.15 200.95,109.81 v2(201.07,109.93) ; U622.7 203.19,105.63 v2(203.44,105.38) 203.19,105.13 U622.6 ; U622.10 v2(203.48,107.13) ; U622.3 v2(203.46,103.63)
  BOTTOM w0.254: C5306.1 202.91,104.85 v2(203.44,105.38) ; v2(203.48,107.13) 203.33,106.98 C5307.1 ; C5304.1 203.34,103.76 v2(203.46,103.63) ; C5303.1 200.95,101.17 v2(201.16,100.96) ; v2(201.07,109.93) 200.95,109.81 C5305.1
  vias: v2(201.65,95.94) v2(202.95,95.89) v2(203.97,95.3)
RT2_ADDR0: length 4.8
  TOP w0.118: R5837.1 v2(200.77,98.78) 200.77,99.84 200.45,100.17 U622.45
  BOTTOM w0.118: R5837.1 v2(200.77,98.78)
RT2_ADDR1: length 4.8
  TOP w0.118: U622.40 197.95,100.72 197.5,100.27 v2(197.5,98.8) R5818.1
  BOTTOM w0.118: R5838.2 v2(197.5,98.8)
RT2_ADDR2: length 6.1
  TOP w0.118: U622.21 197.95,109.82 197.32,110.45 v2(197.32,113.2) R5819.1
  BOTTOM w0.118: R5819.1 v2(197.32,113.2)
RT2_ADDR3: length 6.4
  TOP w0.118: U622.16 200.45,110.25 201.28,111.09 201.28,112.59 201.29,112.6 v2(201.29,113.01) R5820.1
  BOTTOM w0.118: v2(201.29,113.01) R5820.1
RTCCLK_DUT: length 122
  TOP w0.118: v2(143.51,98.37) 137.62,92.48 137.62,81.25 135.76,79.4 131.88,79.4 R5722.2 ; v3(89.33,158.2) U22.V33
  L3_INT_1 w0.087: v3(89.33,158.2) 88.85,157.71 88.85,151.71 89.76,150.8 89.76,141.63 92.81,138.58 94.49,138.58 96.09,136.98 107.39,136.98 111.53,132.84 117.04,132.84 120.47,129.41 120.47,121.41 v2(143.51,98.37)
RTCLK: length 2
  TOP w0.118: U16.6 276.59,83.76 276.32,84.03 TP115.1
RTCTS: length 2
  TOP w0.118: U16.8 275.59,83.72 275.18,84.13 TP289.1
RTCVSB: length 9.2
  TOP w0.254: v2(278.74,78.36) 278.57,78.53 278.57,79.3 U16.15 ; v2(279.37,83.56) 279.09,83.27 U16.1
  TOP w0.508: v2(279.37,83.56) 279.37,84.44 C1158.1 279.37,84.45 R1969.2
  BOTTOM w0.381: v2(278.74,78.36) 279.37,78.98 v2(279.37,83.56)
RX1_L0_N: length 59.7
  TOP w0.091: U65.5 186.16,90.05 arc(186.19,90.05) 186.22,90.03 186.28,89.98 arc(186.31,89.95) 186.36,89.94 188.6,89.94 arc(188.9,89.88) 189.15,89.71 189.54,89.33 arc(189.73,89.2) 189.96,89.15 192.84,89.15 arc(193.44,89.03) 193.94,88.7 217.27,65.37 arc(217.67,64.78) 217.81,64.08 217.81,48.14 arc(217.84,47.96) 217.94,47.81 C1209.1
RX1_L0_N_DC: length 5.1
  TOP w0.091: C1209.2 217.92,46.3 arc(217.84,46.19) 217.82,46.05 217.82,43.38 arc(217.86,43.17) 217.97,42.99 arc(218.05,42.88) 218.08,42.75 J16.12A
RX1_L0_P: length 59.6
  TOP w0.091: C1208.1 217.37,47.77 arc(217.49,47.94) 217.53,48.14 217.53,64.08 arc(217.41,64.67) 217.07,65.17 193.75,88.5 arc(193.33,88.78) 192.84,88.87 189.96,88.87 arc(189.62,88.94) 189.34,89.13 188.95,89.52 arc(188.79,89.62) 188.6,89.66 187.45,89.66 arc(187.34,89.62) 187.3,89.51 arc(187.15,89.36) 186.99,89.51 arc(186.95,89.62) 186.84,89.66 186.33,89.66 arc(186.29,89.65) 186.25,89.63 186.2,89.58 arc(186.17,89.56) 186.14,89.56 U65.4
RX1_L0_P_DC: length 5.1
  TOP w0.091: C1208.2 217.42,46.31 arc(217.51,46.19) 217.54,46.04 217.54,43.38 arc(217.49,43.17) 217.38,42.99 arc(217.3,42.88) 217.28,42.75 J16.13A
RX1_LOS: length 99.6
  TOP w0.118: v2(249.35,108.86) 249.52,109.03 U624.14 ; v2(217.6,31.88) 217.68,31.95 J16.8A
  L3_INT_1 w0.087: v2(217.6,31.88) 218.26,32.54 218.26,38.84 219.76,40.34 219.76,50.37 238.61,69.22 238.61,103.76 245.44,110.59 246.63,110.59 247.14,111.1 248.03,111.1 249.35,109.78 v2(249.35,108.86)
  BOTTOM w0.118: R922.2 217.73,32.45 217.6,32.32 v2(217.6,31.88)
RX2_L0_N: length 74
  TOP w0.091: C1212.1 232.21,47.79 arc(232.1,47.96) 232.05,48.17 232.05,57.64 arc(231.93,58.26) 231.58,58.78 194.44,95.92 arc(193.97,96.23) 193.42,96.34 190.16,96.34 arc(189.62,96.23) 189.15,95.93 186.7,93.47 arc(186.65,93.43) 186.58,93.42 186.31,93.42 arc(186.26,93.43) 186.22,93.46 186.16,93.52 arc(186.12,93.55) 186.08,93.56 U65.12
RX2_L0_N_DC: length 5.1
  TOP w0.091: J16.12B 232.33,42.75 arc(232.33,42.75) 232.33,42.75 arc(232.3,42.88) 232.22,42.99 arc(232.11,43.17) 232.07,43.38 232.07,46.05 arc(232.09,46.18) 232.17,46.3 C1212.2
RX2_L0_P: length 73.8
  TOP w0.091: C1213.1 231.6,47.75 arc(231.73,47.94) 231.78,48.17 231.78,57.64 arc(231.67,58.15) 231.39,58.58 194.24,95.72 arc(193.87,95.97) 193.42,96.06 190.16,96.06 arc(189.72,95.98) 189.35,95.73 187.44,93.81 arc(187.39,93.71) 187.44,93.6 arc(187.44,93.38) 187.22,93.38 arc(187.12,93.43) 187.01,93.38 186.9,93.27 arc(186.75,93.18) 186.58,93.14 186.27,93.14 arc(186.24,93.13) 186.21,93.12 186.17,93.08 arc(186.14,93.06) 186.11,93.05 U65.11
RX2_L0_P_DC: length 5.1
  TOP w0.091: J16.13B 231.53,42.75 arc(231.53,42.75) 231.53,42.75 arc(231.55,42.88) 231.62,42.99 231.63,42.99 arc(231.74,43.17) 231.79,43.38 231.79,46.05 arc(231.76,46.19) 231.68,46.31 C1213.2
RX2_LOS: length 97.1
  TOP w0.118: v2(249.76,107.34) 249.76,108.15 250.02,108.41 U624.15 ; J16.8B 231.93,31.95 v2(231.85,31.88)
  L3_INT_1 w0.087: v2(231.85,31.88) 233.42,33.45 237.59,33.45 240.03,31.01 242.72,31.01 245.75,34.04 245.75,38.68 246.2,39.14 246.2,42.09 249.76,45.64 v2(249.76,107.34)
  BOTTOM w0.118: v2(231.85,31.88) 231.85,32.32 231.98,32.45 R931.2
RX3_L0_N: length 79.2
  TOP w0.091: C1217.1 246.4,47.85 arc(246.33,47.96) 246.3,48.08 246.3,54.96 arc(246.15,55.72) 245.72,56.36 213.63,88.45 arc(213.49,88.67) 213.44,88.92 213.44,100.2 arc(213.3,100.86) 212.93,101.42 210.19,104.16 arc(209.79,104.43) 209.32,104.52 203.22,104.52 203.22,104.52 arc(203.18,104.53) 203.14,104.56 203.09,104.6 arc(203.06,104.62) 203.03,104.63 U622.5
RX3_L0_N_DC: length 5.1
  TOP w0.091: C1217.2 246.42,46.3 arc(246.34,46.18) 246.31,46.05 246.31,43.38 arc(246.36,43.17) 246.47,42.99 arc(246.55,42.88) 246.57,42.75 arc(246.58,42.75) 246.58,42.75 J16.12C
RX3_L0_P: length 79.1
  TOP w0.091: U622.4 203.03,104.13 arc(203.06,104.14) 203.09,104.16 203.14,104.21 arc(203.18,104.23) 203.22,104.24 203.86,104.24 arc(203.97,104.2) 204.01,104.09 arc(204.17,103.94) 204.32,104.09 arc(204.36,104.2) 204.47,104.24 209.32,104.24 arc(209.68,104.17) 209.99,103.97 212.73,101.22 arc(213.05,100.75) 213.16,100.2 213.16,88.92 arc(213.23,88.56) 213.43,88.25 245.53,56.16 arc(245.89,55.61) 246.02,54.96 246.02,48.08 arc(246,47.93) 245.91,47.81 C1216.1
RX3_L0_P_DC: length 5.1
  TOP w0.091: C1216.2 245.93,46.31 arc(246.01,46.19) 246.04,46.05 246.04,43.38 arc(245.99,43.17) 245.88,42.99 245.87,42.99 arc(245.8,42.88) 245.77,42.75 arc(245.78,42.75) 245.78,42.75 J16.13C
RX3_LOS: length 82.8
  TOP w0.118: U624.16 250.52,108.49 250.85,108.15 v2(250.85,107.37) ; v2(246.1,31.88) 246.18,31.95 J16.8C
  L3_INT_1 w0.087: v2(246.1,31.88) 246.74,32.51 246.74,41.73 250.19,45.19 250.19,103.76 250.85,104.42 v2(250.85,107.37)
  BOTTOM w0.118: v2(246.1,31.88) 246.1,32.32 246.23,32.45 R940.2
RX4_L0_N: length 94.3
  TOP w0.091: C1220.1 260.66,47.84 arc(260.58,47.96) 260.55,48.09 260.55,50.39 arc(260.47,50.81) 260.24,51.16 218.84,92.55 arc(218.66,92.83) 218.59,93.15 218.59,103.67 arc(218.44,104.43) 218.01,105.08 212.22,110.86 arc(211.79,111.15) 211.29,111.25 207.21,111.25 arc(206.88,111.19) 206.59,111 203.69,108.1 arc(203.61,108.04) 203.52,108.03 203.11,108.03 arc(203.08,108.03) 203.05,108.05 202.99,108.1 arc(202.96,108.12) 202.93,108.13 U622.12
RX4_L0_N_DC: length 5.1
  TOP w0.091: C1220.2 260.67,46.3 arc(260.59,46.18) 260.56,46.05 260.56,43.38 arc(260.61,43.17) 260.72,42.99 arc(260.8,42.88) 260.82,42.75 arc(260.83,42.75) 260.83,42.74 J16.12D
RX4_L0_P: length 94.2
  TOP w0.091: C1221.1 260.13,47.78 arc(260.24,47.94) 260.27,48.12 260.27,50.39 arc(260.21,50.7) 260.04,50.96 218.64,92.35 arc(218.4,92.72) 218.31,93.15 218.31,103.67 arc(218.18,104.33) 217.81,104.88 212.03,110.67 arc(211.69,110.89) 211.29,110.97 207.21,110.97 arc(206.98,110.93) 206.79,110.8 204.45,108.46 arc(204.4,108.35) 204.45,108.24 arc(204.45,108.02) 204.23,108.02 arc(204.12,108.07) 204.02,108.02 203.89,107.9 arc(203.72,107.79) 203.52,107.75 203.15,107.75 arc(203.1,107.74) 203.06,107.71 203.01,107.66 arc(202.98,107.64) 202.95,107.63 U622.11
RX4_L0_P_DC: length 5.1
  TOP w0.091: C1221.2 260.18,46.31 arc(260.26,46.19) 260.28,46.05 260.28,43.38 arc(260.24,43.17) 260.12,42.99 260.12,42.99 arc(260.05,42.88) 260.02,42.75 arc(260.03,42.75) 260.03,42.75 J16.13D
RX4_LOS: length 85.1
  TOP w0.118: J16.8D 260.43,31.95 v2(260.35,31.88) ; U624.17 251.02,109 v2(251.65,108.37)
  L3_INT_1 w0.087: v2(251.65,108.37) 261.04,98.98 261.04,33.07 260.35,32.38 v2(260.35,31.88)
  BOTTOM w0.118: v2(260.35,31.88) 260.35,32.32 260.48,32.45 R949.2
SCANMODE: length 6.5
  TOP w0.118: v3(89.33,145.2) U22.E33
  BOTTOM w0.102: 89.71,143.66 89.71,144.4 89.33,144.78 v3(89.33,145.2)
  BOTTOM w0.118: R764.2 89.79,143.58 89.71,143.66
SD1_IMP_CAL_RX: length 1.4
  TOP w0.118: U22.M16 v3(107.33,152.2)
  BOTTOM w0.118: R733.1 v3(107.33,152.2)
SD1_IMP_CAL_TX: length 3.3
  TOP w0.118: v3(101.33,152.2) U22.M22
  BOTTOM w0.118: R738.1 99.95,151.51 100.63,152.2 v3(101.33,152.2)
SD1_PLL1_TPA: length 4.8
  TOP w0.118: U22.M18 v3(105.33,152.2)
  L12_INT_5 w0.087: v3(105.33,152.2) 105.84,151.68 105.84,149.68 v3(106.33,149.2)
  BOTTOM w0.118: TP88.1 106.33,148.55 v3(106.33,149.2)
SD1_PLL1_TPD: length 1.4
  TOP w0.118: U22.L16 v3(107.33,151.2)
  BOTTOM w0.118: TP91.1 v3(107.33,151.2)
SD1_PLL2_TPA: length 1.4
  TOP w0.118: U22.M20 v3(103.33,152.2)
  BOTTOM w0.118: TP92.1 v3(103.33,152.2)
SD1_PLL2_TPD: length 1.4
  TOP w0.118: U22.L22 v3(101.33,151.2)
  BOTTOM w0.118: TP95.1 v3(101.33,151.2)
SD1_REF_CLK2_N: length 3.4
  TOP w0.118: U22.N21 v3(102.33,153.2)
  BOTTOM w0.118: v3(102.33,153.2) 102.83,153.7 R5891.1
SD1_REF_CLK2_P: length 4.4
  TOP w0.118: U22.P21 v3(102.33,154.2)
  BOTTOM w0.118: R5890.1 102.85,154.71 v3(102.33,154.2)
SD1_REFCLK1_N: length 65.6
  TOP w0.091: U32.13 109.45,108.81 109.32,108.94 109.32,110.24 v2(109.55,110.46) ; v3(103.33,154.2) U22.P19
  L5_INT_2 w0.086: v2(109.55,110.46) 109.3,110.71 109.3,111.22 108.9,111.62 108.64,111.62 108.31,111.96 108.06,111.96 107.73,111.62 107.46,111.62 107.28,111.8 107.28,112.28 107.11,112.45 106.63,112.45 92.18,126.9 92.18,132.32 92.68,132.83 92.68,134.32 95,136.64 95,140.72 94.94,140.78 94.94,149.38 95.15,149.59 99.76,149.59 100.32,150.15 100.32,153.89 101.03,154.6 103.64,154.6 103.75,154.49 103.75,154.28 103.67,154.2 v3(103.33,154.2)
SD1_REFCLK1_P: length 65.7
  TOP w0.091: v2(108.79,110.46) 109.04,110.21 109.04,108.94 108.95,108.85 U32.14 ; v3(104.33,154.2) U22.P18
  L5_INT_2 w0.086: v3(104.33,154.2) 104.05,154.2 103.97,154.28 103.97,154.58 103.73,154.81 100.94,154.81 100.11,153.98 100.11,150.23 99.67,149.8 95.06,149.8 94.73,149.47 94.73,140.78 94.66,140.72 94.66,136.78 92.34,134.46 92.34,132.97 91.83,132.46 91.83,126.76 107.31,111.28 108.76,111.28 108.96,111.08 108.96,110.64 v2(108.79,110.46)
SD1_RX4_N: length 3.1
  TOP w0.091: C443.2 122.4,59.83 122.3,59.72 122.3,59.37 123.02,58.65 123.02,58.28 123.13,58.17 U42.92
SD1_RX4_P: length 3.1
  TOP w0.091: U42.93 122.63,58.19 122.74,58.3 122.74,58.54 122.02,59.26 122.02,59.72 121.92,59.83 C444.2
SD1_RX5_N: length 3.3
  TOP w0.091: U42.91 123.63,58.28 123.74,58.39 123.74,58.65 124.07,58.98 124.43,58.98 124.69,59.23 124.69,59.51 124.38,59.83 C445.2
SD1_RX5_P: length 3.3
  TOP w0.091: C446.2 125.28,59.83 124.97,59.51 124.97,59.12 124.55,58.7 124.18,58.7 124.02,58.54 124.02,58.39 124.13,58.28 U42.90
SD1_RX6_N: length 3.1
  TOP w0.091: C448.2 131.85,59.6 131.85,59.32 132.52,58.65 132.52,58.39 132.63,58.28 U42.73
SD1_RX6_P: length 3.1
  TOP w0.091: C447.2 131.57,59.57 131.57,59.21 132.24,58.54 132.24,58.39 132.13,58.28 U42.74
SD1_RX7_N: length 3.2
  TOP w0.091: U42.72 133.13,58.28 133.24,58.39 133.24,58.65 133.99,59.4 133.99,59.66 133.7,59.95 C449.2
SD1_RX7_P: length 3.1
  TOP w0.091: C450.2 134.55,59.95 134.26,59.66 134.26,59.28 133.52,58.54 133.52,58.39 133.63,58.28 U42.71
SD1_TX4_N: length 125.9
  TOP w0.091: U22.J19 v3(104.33,149.2) ; U42.95 121.63,58.28 121.52,58.39 121.52,58.65 120.68,59.5 120.68,66.01 122.17,67.51 122.17,68.48 121.79,68.86 121.48,68.86 v2(121.21,69.13)
  L5_INT_2 w0.086: v2(121.21,69.13) 121.58,68.75 127.8,68.75 133.44,74.39 133.44,76.91 136.78,80.25 136.78,95.58 115.28,117.08 112.28,117.08 104.88,124.49 104.88,128.6 101.51,131.97 101.51,134.07 99.8,135.79 99.8,144.15 100.51,144.87 100.94,144.87 101,144.8 103.52,144.8 103.72,144.99 103.72,148.68 103.96,148.92 104.21,148.92 104.33,149.04 v3(104.33,149.2)
SD1_TX4_P: length 125.8
  TOP w0.091: U22.H19 104.21,148.69 104.33,148.58 v3(104.33,148.2) ; v2(121.21,68.31) 121.48,68.58 121.68,68.58 121.89,68.36 121.89,67.63 120.4,66.13 120.4,59.38 121.24,58.54 121.24,58.39 121.13,58.28 U42.96
  L5_INT_2 w0.086: v2(121.21,68.31) 121.31,68.41 127.94,68.41 133.78,74.24 133.78,76.76 137.12,80.11 137.12,95.72 115.42,117.42 112.42,117.42 105.22,124.63 105.22,128.74 101.85,132.11 101.85,134.22 100.14,135.93 100.14,144.01 100.65,144.52 100.97,144.52 101.04,144.59 103.61,144.59 103.93,144.9 103.93,148.59 104.05,148.7 104.24,148.7 104.33,148.62 v3(104.33,148.2)
SD1_TX5_N: length 116.6
  TOP w0.091: v3(103.33,147.2) U22.G20 ; U42.88 125.13,57.98 125.25,58.1 125.25,58.35 126.47,59.56 126.47,70.27 126.73,70.54 127.03,70.54 v2(127.3,70.81)
  L5_INT_2 w0.086: v3(103.33,147.2) 103.33,147.07 103.2,146.94 102.98,146.94 102.71,146.67 102.71,145.98 102.53,145.8 99.05,145.8 98.72,145.48 98.72,140.95 98.65,140.88 98.65,138.53 98.48,138.35 98.48,134.95 100.22,133.21 100.22,131.39 102.35,129.26 102.35,125.14 111.67,115.82 111.67,115.82 111.73,115.76 114.46,115.76 135.31,94.92 135.31,85.72 135.35,85.68 135.35,85.11 135.31,85.07 135.31,80.64 132.12,77.46 132.12,74.94 127.73,70.56 127.55,70.56 v2(127.3,70.81)
SD1_TX5_P: length 116.6
  TOP w0.091: U22.F20 v3(103.33,146.2) ; v2(127.3,70) 127.04,70.26 126.84,70.26 126.74,70.16 126.74,59.44 125.53,58.23 125.53,58.09 125.63,57.99 U42.87
  L5_INT_2 w0.086: v2(127.3,70) 127.52,70.22 127.88,70.22 132.46,74.8 132.46,77.32 135.65,80.5 135.65,84.93 135.69,84.97 135.69,85.82 135.65,85.86 135.65,95.06 114.6,116.11 111.88,116.11 111.82,116.17 111.81,116.17 102.69,125.29 102.69,129.4 100.56,131.54 100.56,133.35 98.82,135.09 98.82,138.21 99,138.39 99,140.88 98.94,140.94 98.94,145.39 99.13,145.59 102.62,145.59 102.92,145.89 102.92,146.58 103.07,146.73 103.24,146.73 103.33,146.64 v3(103.33,146.2)
SD1_TX6_N: length 117.6
  TOP w0.091: U42.76 131.13,58.28 131.02,58.39 131.02,58.7 129.79,59.93 129.79,72.31 128.94,73.16 128.23,73.16 v2(127.97,73.42) ; U22.J21 v3(102.33,149.2)
  L5_INT_2 w0.086: v3(102.33,149.2) 102.33,148.89 102.24,148.8 97.05,148.8 96.72,148.47 96.72,140.96 96.34,140.58 96.25,140.58 95.83,140.17 95.83,135.46 95.36,134.99 95.36,127.1 100.88,121.59 100.88,119.92 105.19,115.61 107.31,115.61 109.8,113.12 112.1,113.12 123.86,101.35 123.86,94.22 127.11,90.97 127.11,81.04 128.31,79.85 128.31,76.21 128.69,75.83 128.69,73.42 128.44,73.18 128.21,73.18 v2(127.97,73.42)
SD1_TX6_P: length 117.5
  TOP w0.091: U42.77 130.63,58.28 130.74,58.39 130.74,58.59 129.51,59.81 129.51,72.19 128.82,72.88 128.25,72.88 v2(127.97,72.61) ; U22.H21 v3(102.33,148.2)
  L5_INT_2 w0.086: v2(127.97,72.61) 128.2,72.84 128.59,72.84 129.03,73.28 129.03,73.48 129.36,73.81 129.36,74.06 129.03,74.4 129.03,75.97 128.65,76.35 128.65,79.99 127.46,81.18 127.46,91.11 124.21,94.36 124.21,101.5 112.24,113.46 109.94,113.46 107.45,115.95 105.33,115.95 101.22,120.07 101.22,121.73 95.71,127.25 95.71,134.85 96.18,135.32 96.18,140.03 96.49,140.34 96.49,140.43 96.93,140.87 96.93,148.38 97.14,148.59 102.22,148.59 102.33,148.48 v3(102.33,148.2)
SD1_TX7_N: length 117.4
  TOP w0.091: v3(101.33,147.2) U22.G22 ; U42.69 134.63,58.28 134.74,58.39 134.74,58.72 135.92,59.89 135.92,62.62 135.08,63.46 135.08,72.5 134.25,73.33 131.44,73.33 130.49,74.28 130.49,75.12 v2(130.3,75.32)
  L5_INT_2 w0.086: v2(130.3,75.32) 130.47,75.49 130.47,80.63 128.65,82.46 128.65,89.33 131.8,92.48 131.8,96.56 113.92,114.44 111.19,114.44 105.95,119.68 104.66,119.68 100.11,124.22 100.11,129.63 98.46,131.28 98.46,133.31 97.16,134.62 97.16,138.58 97.82,139.24 97.82,140.12 97.88,140.19 97.88,140.59 97.72,140.75 97.72,146.45 98.07,146.8 100.2,146.8 100.38,146.98 101.12,146.98 v3(101.33,147.2)
SD1_TX7_P: length 117.5
  TOP w0.091: U22.F22 v3(101.33,146.2) ; v2(130.96,75.32) 130.77,75.13 130.77,74.4 131.56,73.61 134.37,73.61 135.36,72.62 135.36,63.58 136.19,62.74 136.19,59.78 135.02,58.6 135.02,58.39 135.13,58.28 U42.68
  L5_INT_2 w0.086: v2(130.96,75.32) 130.82,75.46 130.82,80.78 128.99,82.6 128.99,89.19 132.14,92.34 132.14,96.7 114.06,114.78 111.33,114.78 106.09,120.02 104.8,120.02 100.46,124.36 100.46,129.77 98.81,131.42 98.81,133.45 97.5,134.76 97.5,138.43 98.16,139.1 98.16,140.12 98.1,140.19 98.1,140.68 97.93,140.84 97.93,146.36 98.16,146.59 100.29,146.59 100.47,146.77 101.18,146.77 101.33,146.62 v3(101.33,146.2)
SD2_IMP_CAL_RX: length 1.4
  TOP w0.118: v3(99.33,152.2) U22.M23
  BOTTOM w0.118: R727.1 99.82,152.68 99.45,152.3 v3(99.33,152.2)
SD2_IMP_CAL_TX: length 1.4
  TOP w0.118: v3(93.33,152.2) U22.M29
  BOTTOM w0.118: v3(93.33,152.2) 92.85,151.71 R737.1
SD2_PLL1_TPA: length 2.4
  TOP w0.118: v3(97.33,152.2) U22.M25
  BOTTOM w0.118: v3(97.33,152.2) 96.83,151.69 TP94.1
SD2_PLL1_TPD: length 2.3
  TOP w0.118: v3(99.33,151.2) U22.L23
  BOTTOM w0.118: v3(99.33,151.2) 99.05,151.2 98.55,151.69 TP93.1
SD2_PLL2_TPA: length 1.4
  TOP w0.118: v3(95.33,152.2) U22.M27
  BOTTOM w0.118: v3(95.33,152.2) TP89.1
SD2_PLL2_TPD: length 1.4
  TOP w0.118: v3(93.33,151.2) U22.L29
  BOTTOM w0.118: TP97.1 v3(93.33,151.2)
SD2_REFCLK1_N: length 107
  TOP w0.091: v3(98.33,153.2) U22.N24 ; v2(123.12,75.63) 123.36,75.87 123.36,76.15 C3882.2
  L5_INT_2 w0.086: v3(98.33,153.2) 98.33,153.57 98.42,153.66 98.65,153.66 98.74,153.57 98.74,151.02 98.52,150.8 93.06,150.8 92.73,150.47 92.73,140.59 92.39,140.25 92.3,140.25 90.98,138.94 90.98,134.49 90.09,133.6 90.09,125.5 98.07,117.53 98.07,98.07 106.96,89.18 106.96,84.32 116.08,75.2 120.72,75.2 121.87,76.35 123.04,76.35 123.32,76.06 123.32,75.84 v2(123.12,75.63)
SD2_REFCLK1_P: length 107.1
  TOP w0.091: v3(98.33,154.2) U22.P24 ; v2(123.88,75.63) 123.64,75.87 123.64,76.15 C3881.2
  L5_INT_2 w0.086: v2(123.88,75.63) 123.67,75.84 123.67,76.21 123.18,76.7 121.73,76.7 120.58,75.54 116.22,75.54 107.3,84.47 107.3,89.32 98.41,98.21 98.41,117.67 90.44,125.64 90.44,133.46 91.33,134.35 91.33,138.79 92.54,140.01 92.54,140.1 92.94,140.5 92.94,150.38 93.15,150.59 98.61,150.59 98.95,150.93 98.95,153.66 98.74,153.87 98.42,153.87 98.33,153.96 v3(98.33,154.2)
SD2_REFCLK2_N: length 96.4
  TOP w0.091: U32.16 107.95,108.81 107.82,108.94 107.82,109.59 v2(108.07,109.83) ; v3(96.33,154.2) U22.P26
  L12_INT_5 w0.086: v3(96.33,154.2) 96.13,154.39 95.96,154.39 95.87,154.31 95.87,153.95 96.04,153.78 97.52,153.78 97.73,153.99 97.73,157.37 97.51,157.59 80.64,157.59 80.57,157.53 79.17,157.53 75.95,154.31 75.95,141.2 78.77,138.38 84,138.38 88.87,133.5 88.87,127.61 101.28,115.21 104.21,115.21 104.82,114.61 105.32,114.61 105.46,114.46 105.46,113.96 105.87,113.55 106.38,113.55 106.52,113.41 106.52,112.9 106.79,112.63 107.3,112.63 107.44,112.49 107.44,111.98 107.85,111.57 107.85,111.16 108.21,110.8 108.21,110.6 107.85,110.24 107.85,110.04 v2(108.07,109.83)
  BOTTOM w0.091: v3(96.33,154.2) 96.41,154.11 R730.1
SD2_REFCLK2_P: length 96.4
  TOP w0.091: U32.17 107.45,108.83 107.54,108.92 107.54,109.59 v2(107.3,109.83) ; v3(95.33,154.2) U22.P27
  L12_INT_5 w0.086: v3(95.33,154.2) 95.57,154.2 95.66,154.11 95.66,153.86 95.95,153.57 97.6,153.57 97.94,153.9 97.94,157.46 97.6,157.81 80.64,157.81 80.57,157.87 79.03,157.87 75.6,154.45 75.6,141.06 78.62,138.04 83.86,138.04 88.53,133.36 88.53,127.47 101.13,114.87 104.07,114.87 107.51,111.43 107.51,110.04 v2(107.3,109.83)
  BOTTOM w0.091: v3(95.33,154.2) 95.52,154 R731.1
SD2_RX0_N: length 98.5
  TOP w0.091: v2(171.77,89.5) 172.01,89.26 172.05,89.22 arc(172.09,89.19) 172.14,89.18 172.34,89.18 arc(172.37,89.19) 172.4,89.21 C1033.2 ; v3(99.33,144.2) U22.D23
  L14_INT_6 w0.086: v3(99.33,144.2) 99.63,143.89 arc(99.66,143.87) 99.69,143.87 99.99,143.87 arc(100.43,143.69) 100.61,143.25 100.61,141.3 arc(100.65,141.09) 100.77,140.91 107.32,134.36 arc(107.54,134.21) 107.8,134.16 114.96,134.16 arc(115.34,134.09) 115.65,133.88 160.07,89.46 arc(160.35,89.28) 160.67,89.21 171.44,89.21 arc(171.48,89.22) 171.5,89.24 v2(171.77,89.5)
SD2_RX0_P: length 98.5
  TOP w0.091: v2(171.77,88.58) 172.01,88.82 172.05,88.86 arc(172.09,88.89) 172.14,88.9 172.34,88.9 arc(172.38,88.89) 172.41,88.87 172.45,88.83 C1032.2 ; v3(99.33,143.2) U22.C23
  L14_INT_6 w0.086: v3(99.33,143.2) 99.63,143.5 arc(99.66,143.52) 99.69,143.52 99.99,143.52 arc(100.19,143.44) 100.27,143.25 100.27,141.3 arc(100.33,140.96) 100.53,140.67 107.08,134.12 arc(107.41,133.9) 107.8,133.82 114.96,133.82 arc(115.2,133.77) 115.41,133.64 159.82,89.22 arc(160.21,88.96) 160.67,88.87 171.44,88.87 arc(171.48,88.86) 171.5,88.84 v2(171.77,88.58)
SD2_RX1_N: length 116.6
  TOP w0.091: C1034.2 172.38,96.72 arc(172.32,96.68) 172.26,96.67 172.09,96.67 arc(172.03,96.68) 171.99,96.71 v2(171.71,96.99) ; v3(98.33,142.2) U22.B24
  L14_INT_6 w0.086: v2(171.71,96.99) 171.45,96.73 arc(171.42,96.71) 171.39,96.7 171.25,96.7 arc(171.14,96.75) 171.09,96.86 arc(170.94,97.01) 170.79,96.86 arc(170.74,96.75) 170.64,96.7 170.52,96.7 arc(170.01,96.49) 169.8,95.98 169.8,93.55 arc(169.84,93.36) 169.94,93.2 173.16,89.98 arc(173.22,89.89) 173.24,89.79 173.24,88.19 173.24,87.81 arc(173.19,87.56) 173.05,87.35 172.06,86.36 arc(171.85,86.22) 171.6,86.17 158.53,86.17 arc(158.16,86.24) 157.85,86.45 119.1,125.19 arc(118.72,125.45) 118.27,125.54 109.48,125.54 arc(109.18,125.6) 108.93,125.77 107.81,126.88 arc(107.63,127.15) 107.57,127.47 107.57,131.47 arc(107.46,132.04) 107.13,132.52 99.45,140.21 99.28,140.38 arc(99.24,140.4) 99.2,140.41 arc(99.16,140.42) 99.12,140.44 98.98,140.58 arc(98.96,140.62) 98.95,140.66 98.95,141.56 arc(98.86,141.78) 98.64,141.87 98.47,141.87 arc(98.37,141.91) 98.33,142.01 v3(98.33,142.2)
SD2_RX1_P: length 116.5
  TOP w0.091: v3(98.33,141.2) U22.A24 ; C1031.2 172.43,96.34 arc(172.37,96.38) 172.31,96.39 172.09,96.39 arc(172.03,96.38) 171.99,96.35 v2(171.71,96.07)
  L14_INT_6 w0.086: v3(98.33,141.2) 98.33,141.55 arc(98.36,141.63) 98.44,141.66 98.64,141.66 arc(98.71,141.63) 98.74,141.56 98.74,140.57 arc(98.74,140.53) 98.77,140.5 98.97,140.3 arc(98.99,140.26) 99.01,140.21 arc(99.02,140.17) 99.05,140.13 99.11,140.07 99.11,140.06 106.89,132.28 arc(107.14,131.91) 107.23,131.47 107.23,127.47 arc(107.32,127.02) 107.57,126.64 108.68,125.53 arc(109.05,125.28) 109.48,125.2 118.27,125.2 arc(118.59,125.13) 118.86,124.95 157.6,86.21 arc(158.03,85.93) 158.53,85.83 171.6,85.83 arc(171.98,85.9) 172.3,86.12 173.29,87.1 arc(173.51,87.43) 173.58,87.81 173.58,89.79 arc(173.54,90.02) 173.41,90.22 170.19,93.44 arc(170.15,93.49) 170.14,93.55 170.14,95.98 arc(170.25,96.25) 170.52,96.36 171.39,96.36 arc(171.42,96.35) 171.45,96.33 v2(171.71,96.07)
SD2_RX2_N: length 145.1
  TOP w0.091: v2(188.59,104.07) 188.84,103.83 188.88,103.79 arc(188.92,103.77) 188.96,103.76 189.17,103.76 arc(189.2,103.76) 189.23,103.78 C1036.1 ; v3(97.33,144.2) U22.D25
  L14_INT_6 w0.086: v3(97.33,144.2) 97.33,143.97 arc(97.37,143.87) 97.46,143.83 97.58,143.83 arc(97.84,143.73) 97.94,143.46 97.94,140.24 arc(97.95,140.2) 97.98,140.16 98.19,139.95 arc(98.26,139.85) 98.28,139.73 98.28,139.38 arc(98.29,139.34) 98.31,139.3 arc(98.34,139.27) 98.35,139.22 98.35,138.09 arc(98.39,137.86) 98.52,137.66 102.05,134.13 arc(102.3,133.76) 102.39,133.33 102.39,126.28 arc(102.44,126.01) 102.6,125.77 105.42,122.95 arc(105.58,122.85) 105.77,122.81 114.62,122.81 arc(115.08,122.72) 115.47,122.46 154.44,83.48 arc(154.73,83.29) 155.07,83.22 176.15,83.22 arc(176.49,83.29) 176.77,83.48 180.66,87.36 arc(181.07,87.64) 181.55,87.73 185.88,87.73 arc(186.14,87.78) 186.35,87.93 188.21,89.78 arc(188.36,90.01) 188.42,90.29 188.42,96.87 arc(188.37,97.11) 188.23,97.31 186.8,98.74 arc(186.64,98.98) 186.59,99.26 186.59,103.05 arc(186.8,103.55) 187.3,103.76 187.38,103.76 arc(187.48,103.8) 187.53,103.91 arc(187.68,104.06) 187.83,103.91 arc(187.88,103.8) 187.99,103.76 188.2,103.76 arc(188.27,103.77) 188.33,103.81 v2(188.59,104.07)
SD2_RX2_P: length 145
  TOP w0.091: v3(97.33,143.2) U22.C25 ; C1035.1 189.27,103.41 189.23,103.45 arc(189.2,103.47) 189.17,103.48 188.96,103.48 arc(188.92,103.47) 188.88,103.44 188.84,103.4 v2(188.59,103.16)
  L14_INT_6 w0.086: v2(188.59,103.16) 188.4,103.35 arc(188.33,103.4) 188.24,103.42 187.3,103.42 arc(187.04,103.31) 186.93,103.05 186.93,99.26 arc(186.96,99.11) 187.04,98.99 188.47,97.55 arc(188.69,97.24) 188.76,96.87 188.76,90.29 arc(188.68,89.88) 188.45,89.54 186.6,87.69 arc(186.27,87.47) 185.88,87.39 181.55,87.39 arc(181.2,87.32) 180.9,87.12 177.02,83.24 arc(176.62,82.97) 176.15,82.88 155.07,82.88 arc(154.6,82.97) 154.2,83.24 115.22,122.22 arc(114.95,122.4) 114.62,122.47 105.77,122.47 arc(105.45,122.53) 105.17,122.71 102.36,125.53 arc(102.13,125.88) 102.04,126.28 102.04,133.33 arc(101.98,133.63) 101.81,133.89 98.28,137.42 arc(98.08,137.73) 98,138.09 98,139.21 arc(98.01,139.26) 98.04,139.3 arc(98.06,139.34) 98.07,139.38 98.07,139.73 arc(98.06,139.77) 98.04,139.8 97.83,140.01 arc(97.76,140.12) 97.73,140.24 97.73,143.46 arc(97.69,143.57) 97.58,143.62 97.48,143.62 arc(97.42,143.61) 97.37,143.58 arc(97.34,143.53) 97.33,143.48 v3(97.33,143.2)
SD2_RX3_N: length 159.8
  TOP w0.091: v3(96.33,142.2) U22.B26 ; C1038.1 189.2,111.29 arc(189.15,111.26) 189.09,111.25 188.91,111.25 arc(188.86,111.26) 188.81,111.29 v2(188.54,111.57)
  L14_INT_6 w0.086: v3(96.33,142.2) 96.33,141.97 arc(96.36,141.89) 96.45,141.85 96.56,141.85 arc(96.83,141.74) 96.94,141.47 96.94,141.03 arc(96.91,140.84) 96.8,140.67 96.41,140.29 arc(96.38,140.25) 96.37,140.21 96.37,140.01 arc(96.38,139.98) 96.4,139.95 96.42,139.93 arc(96.44,139.89) 96.44,139.86 96.44,136.83 arc(96.5,136.53) 96.67,136.27 98.64,134.31 arc(98.89,133.92) 98.98,133.47 98.98,125.56 arc(99.06,125.18) 99.28,124.85 103.9,120.23 arc(104.19,120.03) 104.53,119.96 111.1,119.96 arc(111.48,119.89) 111.79,119.68 150.68,80.79 arc(150.97,80.6) 151.3,80.53 181.15,80.53 arc(181.4,80.58) 181.61,80.72 191.45,90.56 arc(191.57,90.75) 191.62,90.96 191.62,102.78 arc(191.54,103.19) 191.3,103.54 187.38,107.46 arc(187.13,107.83) 187.05,108.27 187.05,110.06 arc(187,110.17) 186.89,110.21 arc(186.74,110.37) 186.89,110.52 arc(187,110.56) 187.05,110.67 arc(187.22,111.1) 187.66,111.28 188.12,111.28 arc(188.24,111.3) 188.34,111.37 v2(188.54,111.57)
SD2_RX3_P: length 159.7
  TOP w0.091: v2(188.54,110.65) 188.81,110.93 arc(188.86,110.96) 188.91,110.97 189.14,110.97 arc(189.2,110.96) 189.25,110.92 C1037.1 ; v3(96.33,141.2) U22.A26
  L14_INT_6 w0.086: v2(188.54,110.65) 188.34,110.84 arc(188.24,110.91) 188.12,110.94 187.66,110.94 arc(187.47,110.86) 187.39,110.67 187.39,108.27 arc(187.45,107.96) 187.62,107.71 191.55,103.78 arc(191.85,103.32) 191.96,102.78 191.96,90.96 arc(191.89,90.61) 191.7,90.32 181.85,80.48 arc(181.53,80.26) 181.15,80.19 151.3,80.19 arc(150.84,80.28) 150.44,80.54 111.55,119.44 arc(111.34,119.57) 111.1,119.62 104.53,119.62 arc(104.06,119.72) 103.66,119.98 99.04,124.61 arc(98.74,125.05) 98.64,125.56 98.64,133.47 arc(98.58,133.79) 98.39,134.06 96.43,136.03 arc(96.18,136.4) 96.1,136.83 96.1,139.84 arc(96.1,139.87) 96.12,139.9 arc(96.15,139.95) 96.16,140 96.16,140.21 arc(96.19,140.33) 96.26,140.44 96.65,140.83 arc(96.71,140.92) 96.73,141.03 96.73,141.47 arc(96.68,141.59) 96.56,141.64 96.44,141.64 arc(96.36,141.61) 96.33,141.53 v3(96.33,141.2)
SD2_RX4_N: length 3.1
  TOP w0.091: U620.92 165.3,58.17 165.18,58.28 165.18,58.65 164.47,59.37 164.47,59.72 164.57,59.83 C451.2
SD2_RX4_P: length 3.1
  TOP w0.091: U620.93 164.79,58.19 164.91,58.3 164.91,58.54 164.19,59.26 164.19,59.72 164.08,59.83 C452.2
SD2_RX5_N: length 3.3
  TOP w0.091: C453.2 166.54,59.83 166.85,59.51 166.85,59.23 166.6,58.98 166.23,58.98 165.91,58.65 165.91,58.39 165.79,58.28 U620.91
SD2_RX5_P: length 3.3
  TOP w0.091: C454.2 167.44,59.83 167.13,59.51 167.13,59.12 166.71,58.7 166.35,58.7 166.18,58.54 166.18,58.39 166.3,58.28 U620.90
SD2_RX6_N: length 3.1
  TOP w0.091: C456.2 174.02,59.6 174.02,59.32 174.68,58.65 174.68,58.39 174.79,58.28 U620.73
SD2_RX6_P: length 3.1
  TOP w0.091: U620.74 174.3,58.28 174.41,58.39 174.41,58.54 173.74,59.21 173.74,59.57 C455.2
SD2_RX7_N: length 3.2
  TOP w0.091: U620.72 175.3,58.28 175.41,58.39 175.41,58.65 176.15,59.4 176.15,59.66 175.86,59.95 C457.2
SD2_RX7_P: length 3.1
  TOP w0.091: U620.71 175.79,58.28 175.68,58.39 175.68,58.54 176.43,59.28 176.43,59.66 176.72,59.95 C458.2
SD2_TX0_N: length 6.8
  TOP w0.091: C230.2 190.77,85.23 arc(190.74,85.21) 190.7,85.2 190.26,85.2 arc(190.14,85.23) 190.04,85.29 187.06,88.28 arc(186.87,88.4) 186.65,88.44 186.37,88.44 arc(186.34,88.45) 186.31,88.47 186.25,88.53 arc(186.22,88.55) 186.19,88.56 U65.2
SD2_TX0_P: length 6.8
  TOP w0.091: U65.1 186.19,88.05 arc(186.22,88.06) 186.25,88.08 186.31,88.14 arc(186.34,88.16) 186.37,88.17 186.65,88.17 arc(186.77,88.14) 186.86,88.08 189.84,85.1 arc(190.03,84.97) 190.26,84.92 190.7,84.92 arc(190.74,84.92) 190.77,84.9 C231.2
SD2_TX1_N: length 5.7
  TOP w0.091: C228.2 190.82,92.8 arc(190.72,92.73) 190.61,92.71 189.33,92.71 arc(189.11,92.67) 188.92,92.54 188.39,92.01 arc(188.32,91.96) 188.24,91.95 186.32,91.95 arc(186.29,91.95) 186.26,91.97 186.2,92.03 arc(186.17,92.05) 186.14,92.05 U65.9
SD2_TX1_P: length 6.1
  TOP w0.091: U65.8 186.16,91.56 arc(186.19,91.56) 186.22,91.58 186.27,91.63 arc(186.31,91.66) 186.36,91.67 186.82,91.67 arc(186.92,91.62) 186.97,91.52 arc(187.12,91.36) 187.27,91.52 arc(187.32,91.62) 187.43,91.67 188.24,91.67 arc(188.43,91.71) 188.59,91.81 189.12,92.34 arc(189.21,92.41) 189.33,92.43 190.61,92.43 arc(190.72,92.41) 190.82,92.34 C229.2
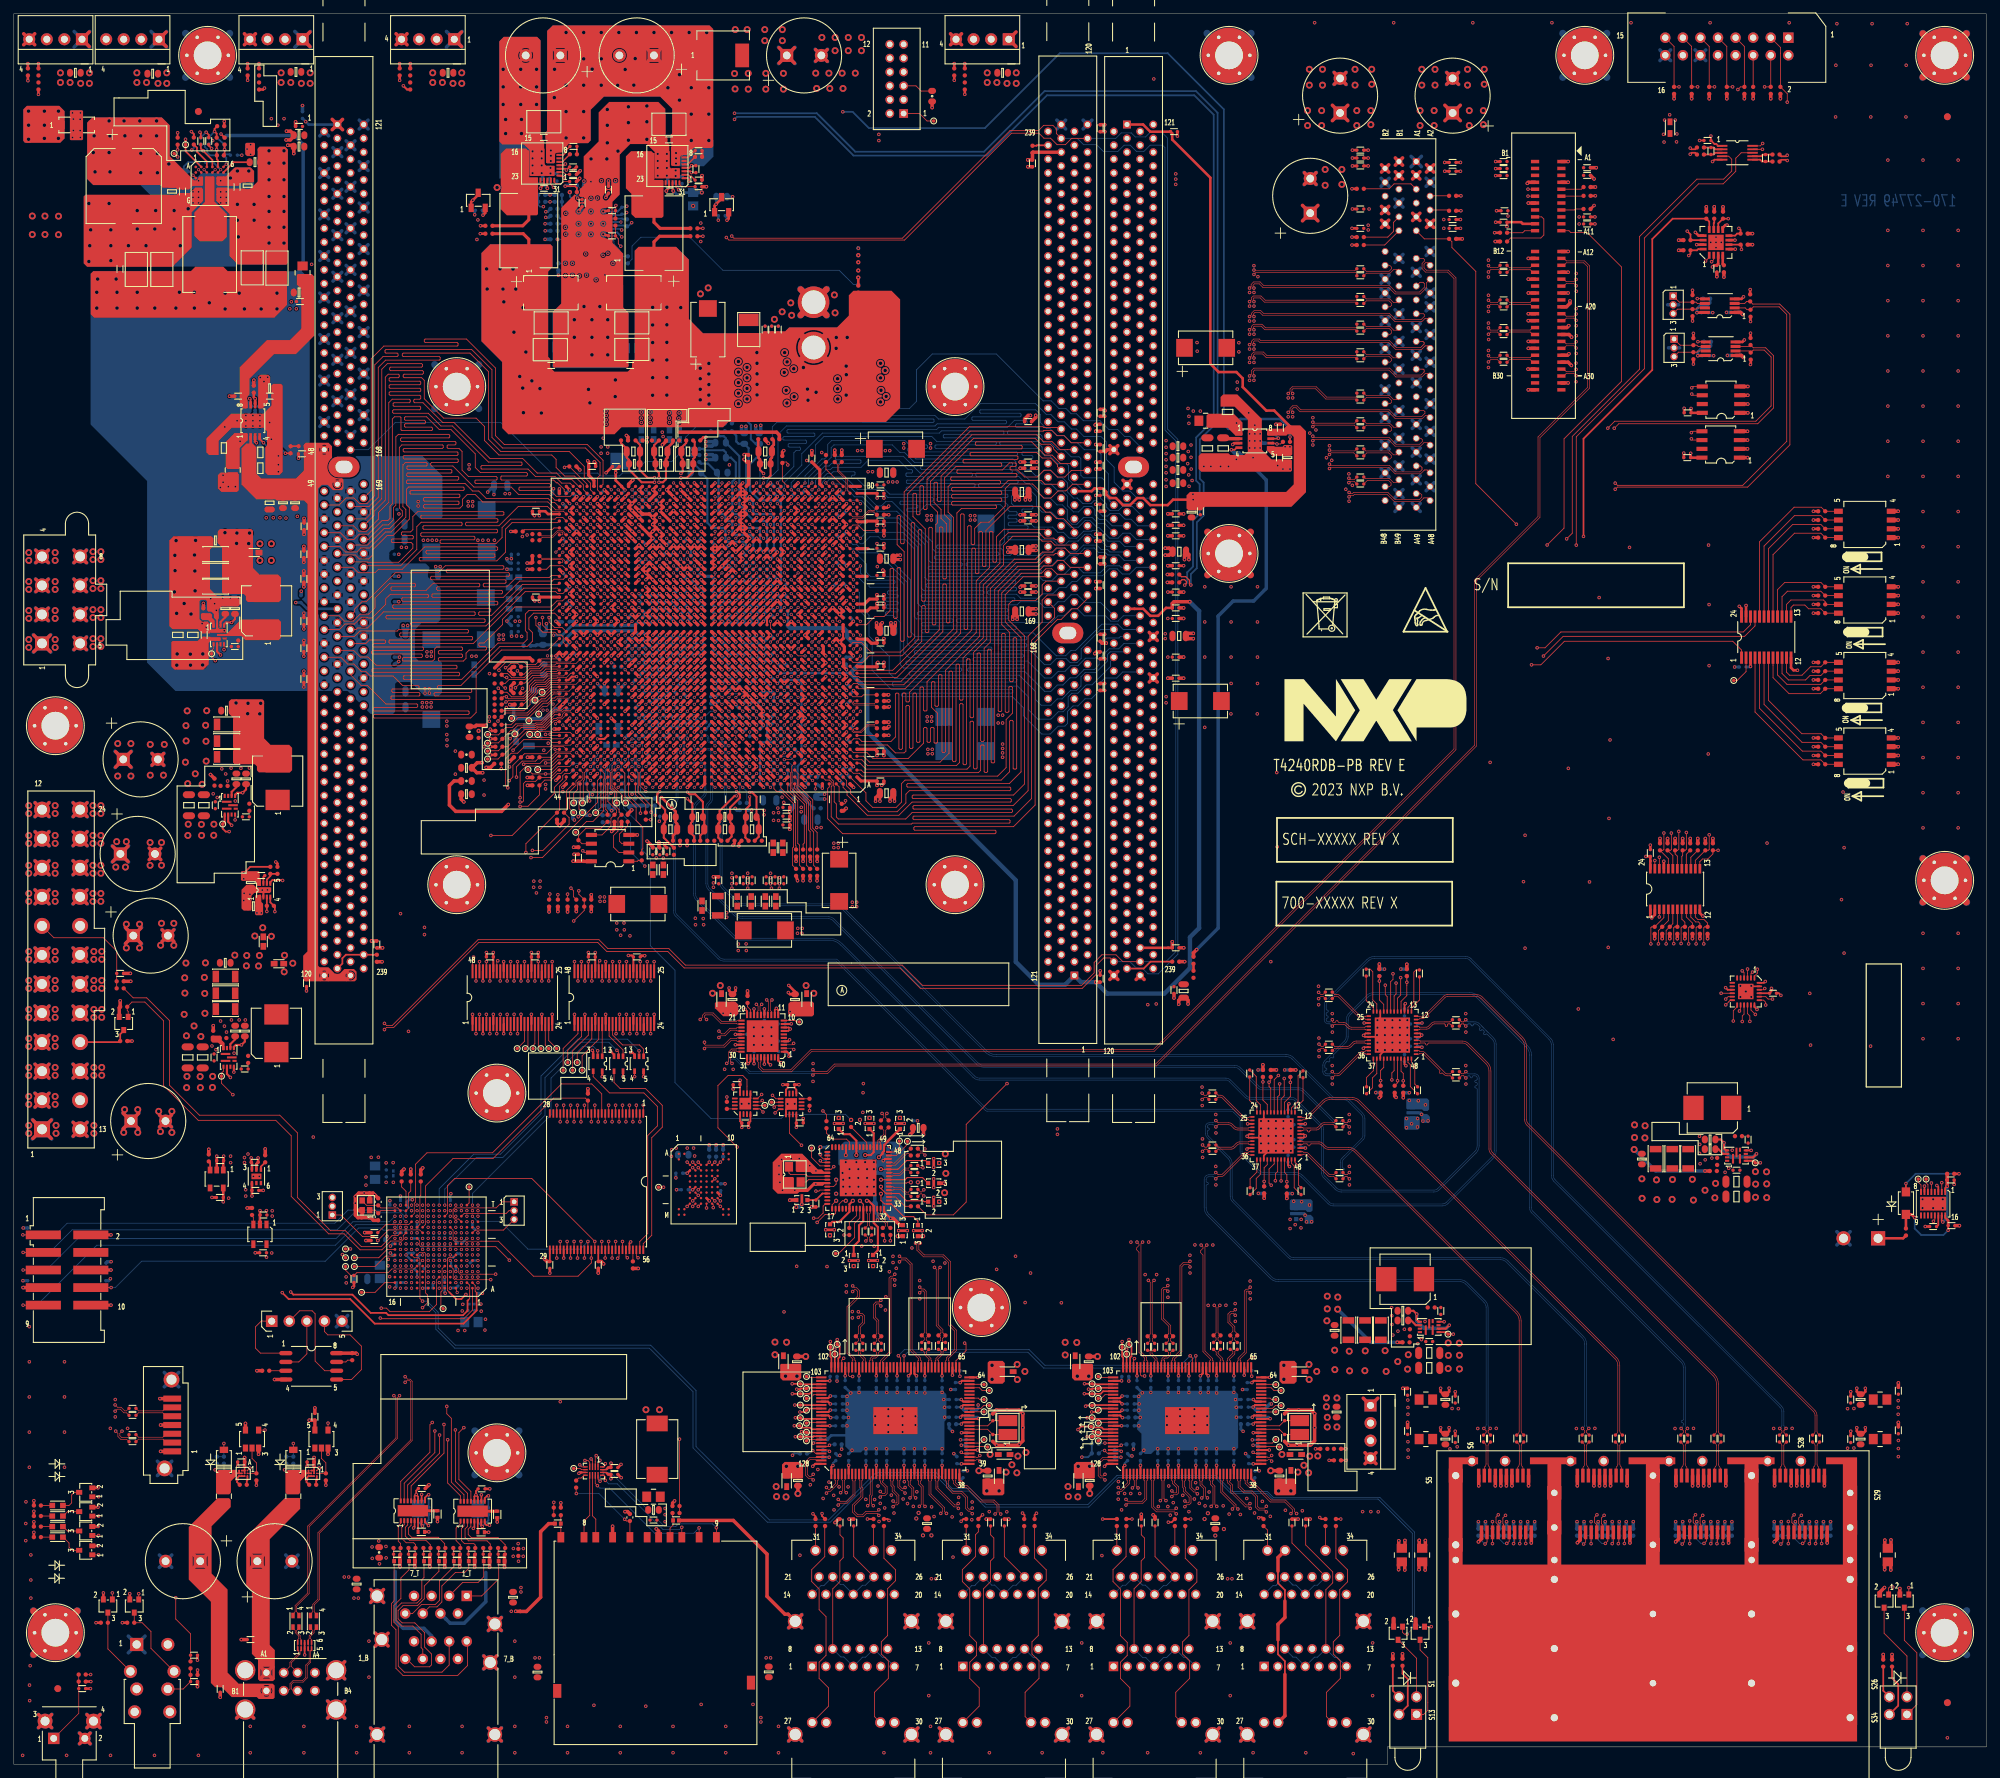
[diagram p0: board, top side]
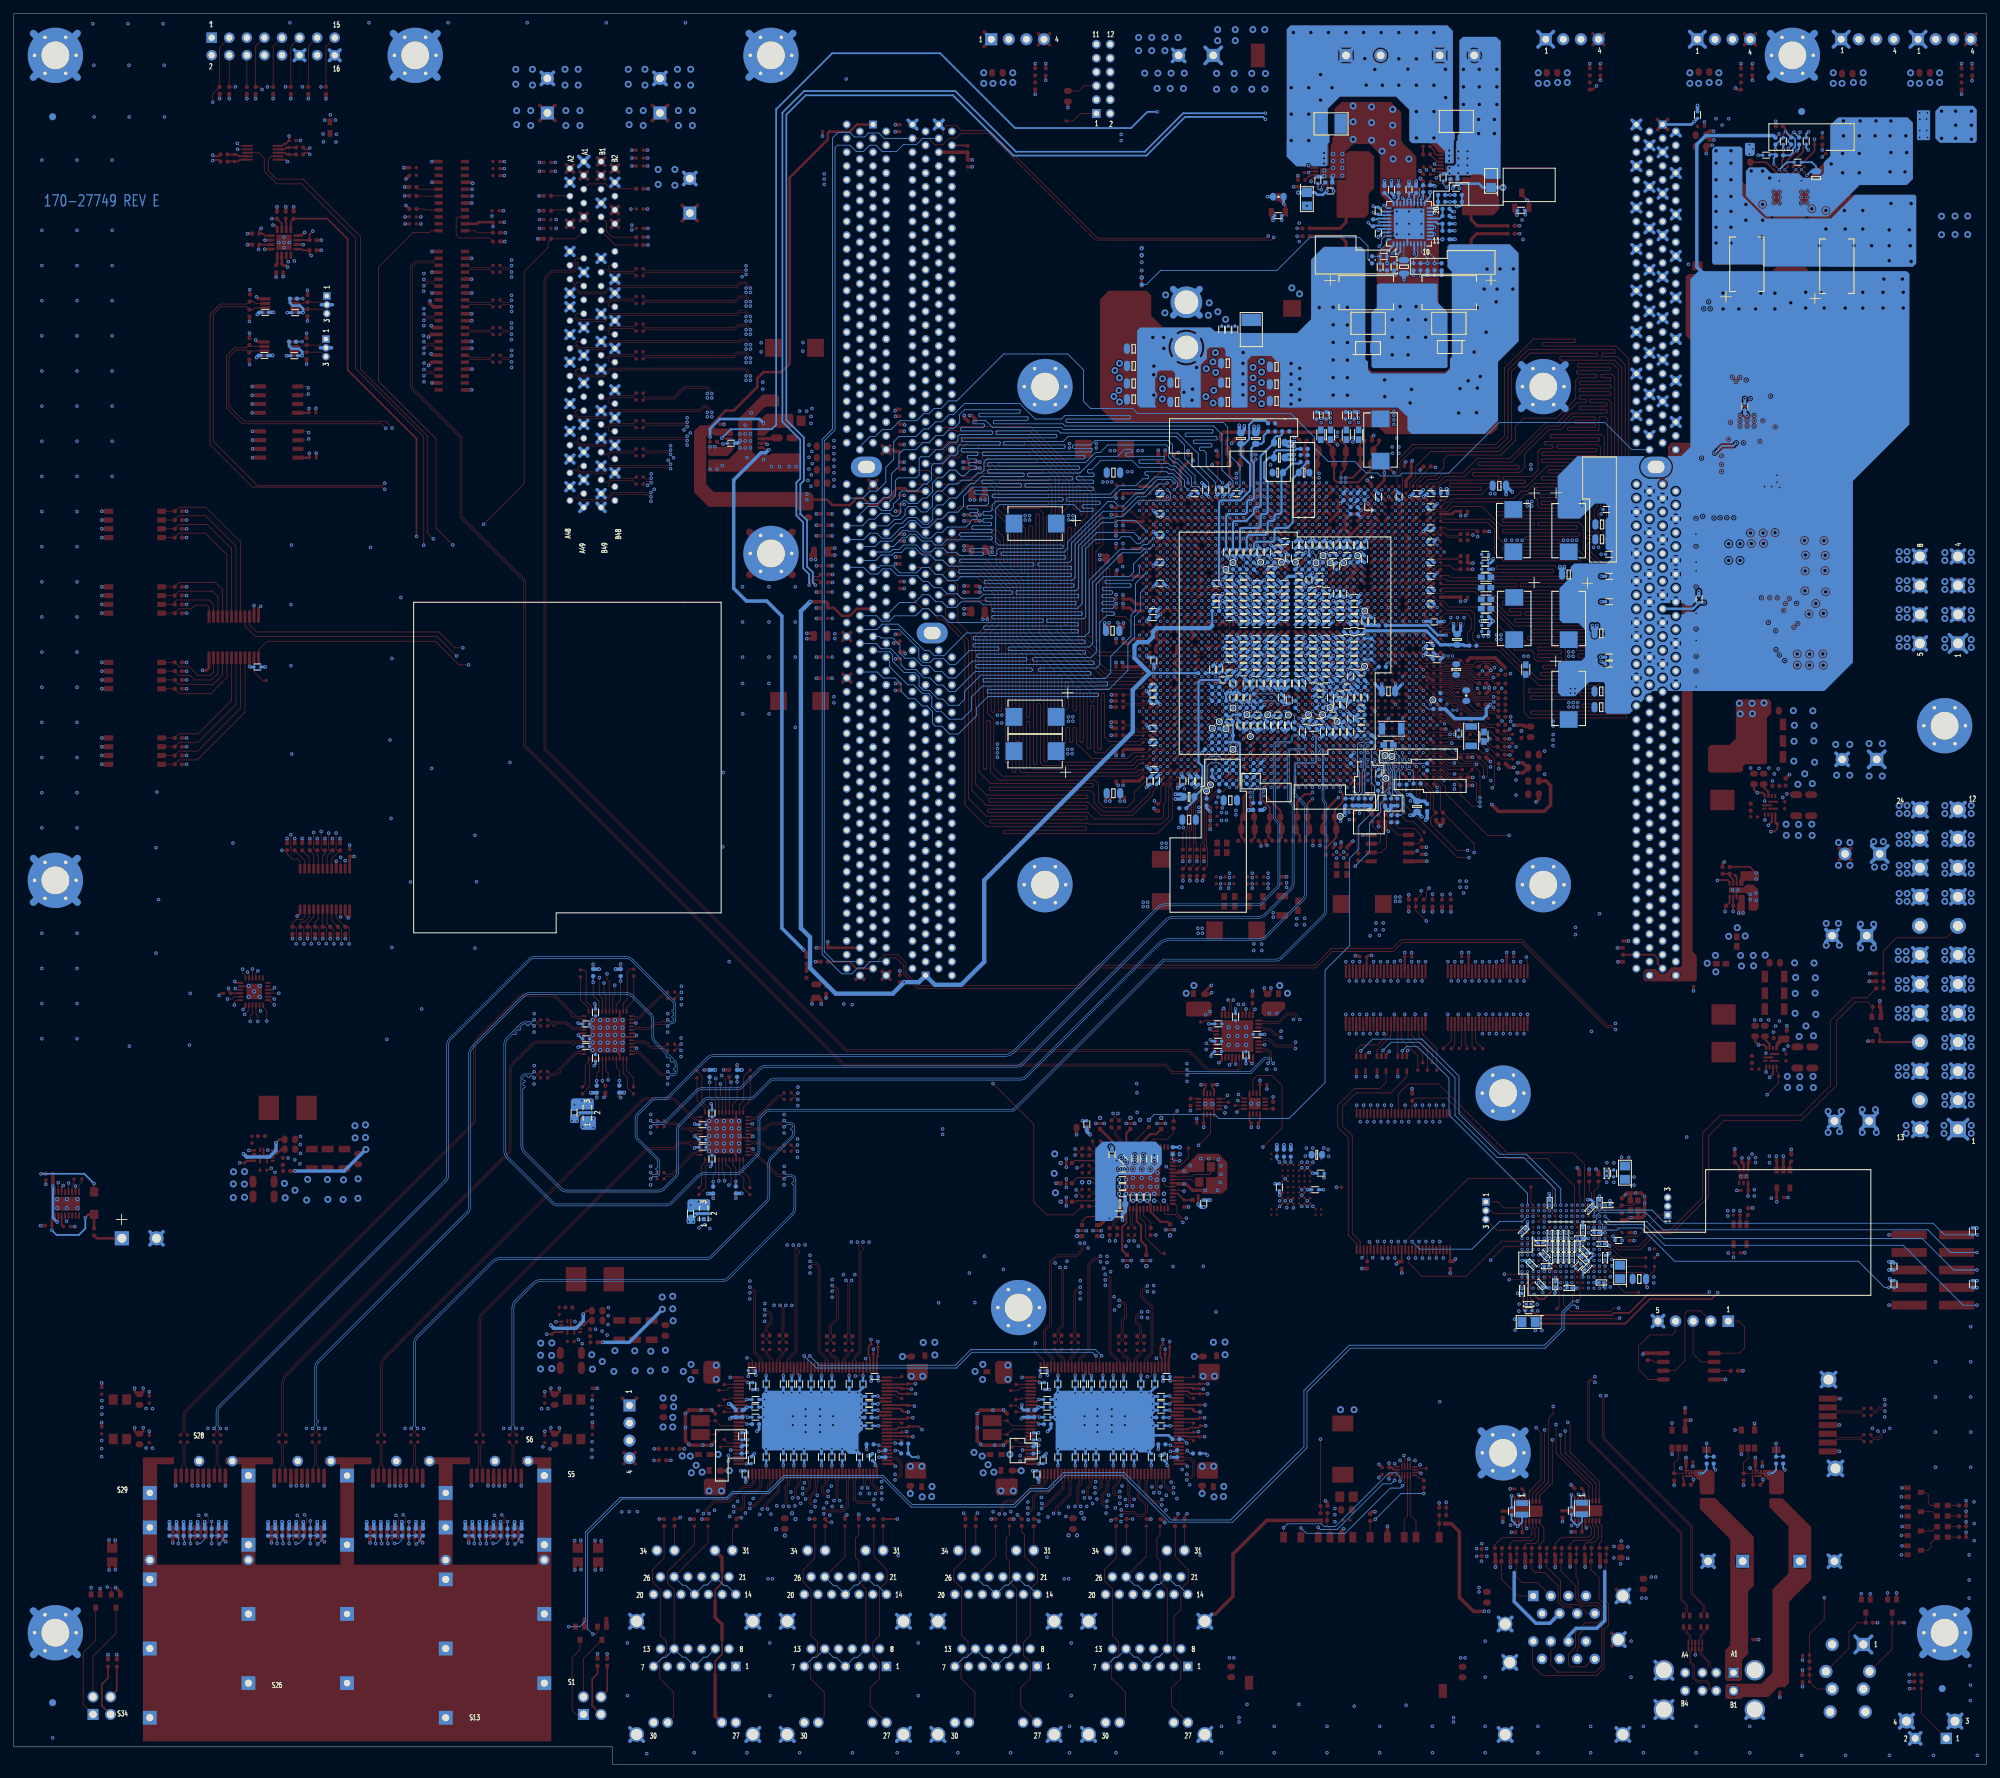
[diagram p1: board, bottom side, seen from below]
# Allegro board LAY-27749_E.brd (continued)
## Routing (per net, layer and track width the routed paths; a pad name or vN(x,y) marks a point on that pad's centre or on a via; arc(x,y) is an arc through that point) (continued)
SD2_TX2_N: length 6.8
  TOP w0.091: U622.2 203.01,103.13 arc(203.05,103.12) 203.08,103.1 203.13,103.05 arc(203.16,103.03) 203.2,103.02 203.48,103.02 arc(203.7,102.98) 203.89,102.85 206.87,99.87 arc(206.97,99.8) 207.09,99.78 207.53,99.78 arc(207.57,99.79) 207.6,99.81 C226.2
SD2_TX2_P: length 7.1
  TOP w0.091: U622.1 203.01,102.63 arc(203.05,102.64) 203.08,102.66 203.13,102.72 arc(203.16,102.73) 203.2,102.74 203.48,102.74 arc(203.59,102.72) 203.69,102.66 206.04,100.3 arc(206.09,100.19) 206.04,100.09 arc(206.04,99.87) 206.26,99.87 arc(206.37,99.92) 206.47,99.87 206.67,99.67 arc(206.86,99.55) 207.09,99.5 207.53,99.5 arc(207.57,99.49) 207.6,99.47 C227.2
SD2_TX3_N: length 5.7
  TOP w0.091: U622.9 202.97,106.63 arc(203,106.62) 203.03,106.6 203.08,106.55 arc(203.11,106.53) 203.15,106.52 204.14,106.52 arc(204.26,106.55) 204.35,106.61 204.83,107.09 arc(205.05,107.24) 205.31,107.29 207.44,107.29 arc(207.55,107.31) 207.65,107.37 C224.2
SD2_TX3_P: length 6.3
  TOP w0.091: U622.8 202.98,106.13 arc(203.02,106.14) 203.05,106.16 203.1,106.21 arc(203.14,106.24) 203.18,106.25 204.14,106.25 arc(204.36,106.29) 204.55,106.41 205.03,106.89 arc(205.16,106.98) 205.31,107.01 206.68,107.01 arc(206.79,106.96) 206.83,106.85 206.83,106.76 arc(206.98,106.6) 207.14,106.76 207.14,106.85 arc(207.18,106.96) 207.29,107.01 207.44,107.01 arc(207.55,106.98) 207.65,106.92 C225.2
SD2_TX4_N: length 125.3
  TOP w0.091: v2(163.11,75.46) 162.86,75.22 162.86,59.63 163.68,58.81 163.68,58.39 163.79,58.28 U620.95 ; v3(95.33,149.2) U22.J27
  L12_INT_5 w0.086: v3(95.33,149.2) 95.33,148.89 95.42,148.8 98.56,148.8 98.93,148.43 98.93,140.96 99.45,140.45 99.45,140.03 99.52,139.96 99.52,139.6 105.87,133.25 105.87,133.24 108.76,130.34 108.76,126.6 110.7,124.66 113.33,124.66 161.01,76.97 162.38,76.97 162.87,76.49 162.87,75.7 v2(163.11,75.46)
SD2_TX4_P: length 125.3
  TOP w0.091: v2(162.29,75.46) 162.59,75.17 162.59,74.97 162.23,74.61 162.23,74.36 162.59,74 162.59,59.51 163.41,58.69 163.41,58.39 163.3,58.28 U620.96 ; v3(95.33,148.2) U22.H27
  L12_INT_5 w0.086: v3(95.33,148.2) 95.33,148.5 95.42,148.59 98.48,148.59 98.72,148.34 98.72,140.88 99.24,140.36 99.24,140.03 99.17,139.96 99.17,139.46 105.52,133.11 105.52,133.09 108.42,130.2 108.42,126.45 110.55,124.32 113.18,124.32 160.87,76.63 162.24,76.63 162.53,76.35 162.53,75.7 v2(162.29,75.46)
SD2_TX5_N: length 130.9
  TOP w0.091: v3(94.33,147.2) U22.G28 ; v2(169.95,72.68) 169.76,72.49 168.96,72.49 168.5,72.03 168.5,59.75 167.41,58.65 167.41,58.39 167.3,58.28 U620.88
  L12_INT_5 w0.086: v3(94.33,147.2) 94.33,146.89 94.42,146.8 97.59,146.8 97.93,146.46 97.93,140.89 98.25,140.58 98.25,140.13 98.31,140.06 98.31,139.23 103.25,134.29 103.25,132.77 107.05,128.97 107.05,126.28 110.02,123.3 112.71,123.3 161.55,74.47 166.79,74.47 168.8,72.47 169.74,72.47 v2(169.95,72.68)
SD2_TX5_P: length 130.9
  TOP w0.091: v3(94.33,146.2) U22.F28 ; v2(169.95,71.87) 169.95,72.06 169.8,72.21 169.08,72.21 168.78,71.92 168.78,59.64 167.68,58.54 167.68,58.39 167.79,58.28 U620.87
  L12_INT_5 w0.086: v2(169.95,71.87) 169.7,72.12 168.65,72.12 166.65,74.13 161.4,74.13 112.57,122.96 109.88,122.96 106.71,126.13 106.71,128.83 102.91,132.62 102.91,134.15 97.97,139.09 97.97,140.06 98.03,140.13 98.03,140.49 97.72,140.8 97.72,146.37 97.5,146.59 94.42,146.59 94.33,146.5 v3(94.33,146.2)
SD2_TX6_N: length 136.3
  TOP w0.091: v2(172.38,75.03) 172.11,74.76 172.11,59.73 173.18,58.66 173.18,58.39 173.3,58.28 U620.76 ; v3(93.33,149.2) U22.J29
  L12_INT_5 w0.086: v2(172.38,75.03) 172.14,75.27 172.14,76.02 169.74,78.42 161.76,78.42 112.62,127.56 112.62,128.35 100.84,140.13 100.84,149.41 100.38,149.87 99.89,149.87 99.83,149.8 94.07,149.8 93.73,149.46 93.73,148.96 93.64,148.88 93.44,148.88 93.33,148.99 v3(93.33,149.2)
SD2_TX6_P: length 136.2
  TOP w0.091: U620.77 172.79,58.28 172.91,58.39 172.91,58.54 171.83,59.61 171.83,73.6 171.46,73.97 171.46,74.19 171.83,74.56 171.83,74.76 v2(171.56,75.03) ; v3(93.33,148.2) U22.H29
  L12_INT_5 w0.086: v3(93.33,148.2) 93.33,148.58 93.42,148.67 93.73,148.67 93.94,148.88 93.94,149.38 94.16,149.59 99.8,149.59 99.86,149.52 100.23,149.52 100.5,149.26 100.5,139.99 112.28,128.2 112.28,127.42 161.62,78.08 169.59,78.08 171.8,75.87 171.8,75.27 v2(171.56,75.03)
SD2_TX7_N: length 139.2
  TOP w0.091: v3(92.33,147.2) U22.G30 ; v2(178.65,68.95) 178.36,68.66 178.07,68.66 177.8,68.39 177.8,59.57 176.91,58.67 176.91,58.31 176.79,58.2 U620.69
  L12_INT_5 w0.086: v2(178.65,68.95) 178.39,68.69 176.98,68.69 175.41,70.26 168.71,70.26 165.81,73.15 160.73,73.15 114.89,119 112.45,119 104.65,126.8 104.65,129.39 101.6,132.44 101.6,133.53 97.6,137.53 97.6,138.55 97.11,139.04 97.02,139.04 96.94,139.12 96.94,145.45 96.58,145.8 93.07,145.8 92.94,145.92 92.94,146.7 92.72,146.92 92.47,146.92 92.33,147.07 v3(92.33,147.2)
SD2_TX7_P: length 139.1
  TOP w0.091: v2(178.65,68.14) 178.41,68.38 178.18,68.38 178.08,68.28 178.08,59.45 177.18,58.56 177.18,58.39 177.3,58.28 U620.68 ; v3(92.33,146.2) U22.F30
  L12_INT_5 w0.086: v2(178.65,68.14) 178.44,68.35 176.84,68.35 175.27,69.91 168.56,69.91 165.67,72.81 160.59,72.81 114.74,118.66 112.3,118.66 104.31,126.65 104.31,129.25 101.26,132.3 101.26,133.39 97.26,137.39 97.26,138.41 96.87,138.79 96.87,138.89 96.72,139.03 96.72,145.36 96.5,145.59 92.98,145.59 92.73,145.84 92.73,146.61 92.64,146.71 92.42,146.71 92.33,146.62 v3(92.33,146.2)
SD3_IMP_CAL_RX: length 1.4
  TOP w0.118: U22.AN19 v3(104.33,173.2)
  BOTTOM w0.118: R694.1 v3(104.33,173.2)
SD3_IMP_CAL_TX: length 1.4
  TOP w0.118: v3(97.33,174.19) U22.AN25
  BOTTOM w0.118: R693.1 v3(97.33,174.19)
SD3_PLL1_TPA: length 1.4
  TOP w0.118: U22.AN21 v3(102.33,174.2)
  BOTTOM w0.118: TP76.1 v3(102.33,174.2)
SD3_PLL1_TPD: length 1.4
  TOP w0.118: U22.AP19 v3(104.33,174.2)
  BOTTOM w0.118: TP75.1 v3(104.33,174.2)
SD3_PLL2_TPA: length 1.4
  TOP w0.118: U22.AN23 v3(99.33,174.19)
  BOTTOM w0.118: TP77.1 v3(99.33,174.19)
SD3_PLL2_TPD: length 2.4
  TOP w0.118: v3(97.33,175.19) U22.AP25
  BOTTOM w0.118: TP79.1 96.84,174.7 v3(97.33,175.19)
SD3_REFCLK1_N: length 152
  TOP w0.091: v2(99.18,107.64) 99.5,107.96 99.5,108.25 99.83,108.58 101.06,108.58 102.27,107.37 104.4,107.37 104.51,107.48 U32.21 ; U22.AL22 101.16,171.7 101.33,171.87 v3(101.33,172.2)
  L12_INT_5 w0.086: v3(101.33,172.2) 101.64,172.2 101.72,172.28 101.72,173.38 101.52,173.59 79.82,173.59 79.39,174.02 78.84,174.02 78.78,173.95 76.65,173.95 74.56,171.87 72.05,171.87 61.7,161.52 61.7,137.8 80.77,118.72 91.41,118.72 96.1,114.03 96.1,103.29 98.29,101.1 101.31,101.1 102.58,102.36 102.58,102.87 102.72,103.01 103.22,103.01 103.37,103.15 103.37,104.05 103.02,104.39 103.02,104.62 103.37,104.96 103.37,105.16 103.04,105.49 103.04,105.75 103.37,106.08 103.37,106.28 102.94,106.71 101.03,106.71 100.69,106.36 100.48,106.36 100.14,106.71 99.82,106.71 99.54,106.99 99.54,107.51 99.4,107.64 v2(99.18,107.64)
SD3_REFCLK1_P: length 152.1
  TOP w0.091: U22.AL21 v3(102.33,172.2) ; v2(100.09,107.64) 99.77,107.96 99.77,108.13 99.95,108.31 100.94,108.31 102.15,107.09 104.4,107.09 104.51,106.98 U32.22
  L12_INT_5 w0.086: v3(102.33,172.2) 102.02,172.2 101.94,172.28 101.94,173.47 101.61,173.8 79.9,173.8 79.48,174.23 78.84,174.23 78.78,174.3 76.51,174.3 74.42,172.21 71.9,172.21 61.35,161.66 61.35,137.66 80.63,118.38 91.27,118.38 95.76,113.89 95.76,103.15 98.15,100.76 101.45,100.76 103.71,103.01 103.71,106.42 103.08,107.05 99.96,107.05 99.88,107.14 99.88,107.42 v2(100.09,107.64)
SD3_REFCLK2_N: length 1.4
  TOP w0.091: v3(98.33,173.19) U22.AM24
  BOTTOM w0.091: v3(98.33,173.19) 98.83,172.69 R700.1
SD3_REFCLK2_P: length 1.4
  TOP w0.091: v3(98.33,172.19) U22.AL24
  BOTTOM w0.091: R701.1 v3(98.33,172.19)
SD3_RX0_N: length 158.7
  TOP w0.091: v2(178.56,213.36) 178.79,213.59 178.79,213.89 179.15,214.25 180.09,214.25 180.59,213.74 198.75,213.74 199.71,212.79 203.12,212.79 203.84,213.5 203.84,213.99 203.63,214.2 203.2,214.2 J3.A17 ; U22.BA18 v3(104.33,181.2)
  L14_INT_6 w0.086: v3(104.33,181.2) 104.33,181.55 104.49,181.7 104.73,181.7 104.94,181.91 104.94,185.42 105.01,185.5 105.01,185.75 105.18,185.92 106.62,185.92 108.27,187.57 110.26,187.57 113.28,190.59 123.76,190.59 130.24,197.06 130.24,204.51 145.5,219.77 145.5,233.83 149.45,237.78 165.01,237.78 166.34,236.45 166.34,226.44 178.73,214.06 178.73,213.53 v2(178.56,213.36)
SD3_RX0_P: length 158.7
  TOP w0.091: v2(179.2,213.36) 179.07,213.49 179.07,213.78 179.26,213.97 179.97,213.97 180.48,213.46 198.64,213.46 199.59,212.51 203.24,212.51 204.11,213.39 204.11,214.12 J3.A16 ; U22.BB18 v3(104.33,182.2)
  L14_INT_6 w0.086: v2(179.2,213.36) 179.07,213.49 179.07,214.2 166.69,226.58 166.69,236.59 165.15,238.12 149.31,238.12 145.16,233.98 145.16,219.92 129.9,204.65 129.9,197.21 123.62,190.93 113.14,190.93 110.12,187.91 108.13,187.91 106.48,186.26 105.03,186.26 104.67,185.9 104.67,185.5 104.75,185.42 104.75,181.99 104.65,181.89 104.47,181.89 104.33,182.03 v3(104.33,182.2)
SD3_RX1_N: length 163.7
  TOP w0.091: v2(179.2,209.25) 179.1,209.35 179.1,209.59 179.34,209.83 180.06,209.83 180.46,209.43 198.65,209.43 199.57,208.51 203.46,208.51 203.94,208.99 204.31,208.99 J3.A22 ; U22.BC19 v3(104.33,184.2)
  L14_INT_6 w0.086: v3(104.33,184.2) 104.33,184.46 104.24,184.55 103.96,184.55 103.72,184.78 103.72,185.66 103.65,185.73 103.65,186.05 104.73,187.13 105.37,187.13 107.6,189.37 108.75,189.37 111.69,192.32 122.62,192.32 128.16,197.86 128.16,205.59 143.8,221.24 143.8,234.94 148.3,239.44 165.74,239.44 168.92,236.26 168.92,228.23 180.59,216.57 180.59,211.06 179.1,209.57 179.1,209.35 v2(179.2,209.25)
SD3_RX1_P: length 163.7
  TOP w0.091: J3.A21 203.68,209.65 203.84,209.5 203.84,209.28 203.34,208.79 199.69,208.79 198.76,209.71 180.57,209.71 180.18,210.11 179.22,210.11 178.82,209.7 178.82,209.5 v2(178.56,209.25) ; U22.BD19 104.18,184.7 104.33,184.85 v3(104.33,185.2)
  L14_INT_6 w0.086: v2(178.56,209.25) 178.75,209.44 178.75,209.71 180.24,211.2 180.24,216.43 168.58,228.09 168.58,236.12 165.6,239.1 148.44,239.1 144.15,234.8 144.15,221.1 128.5,205.45 128.5,197.71 122.76,191.97 111.84,191.97 108.89,189.03 107.75,189.03 105.51,186.79 104.88,186.79 103.99,185.9 103.99,185.73 103.91,185.66 103.91,184.86 104.04,184.74 104.24,184.74 104.33,184.82 v3(104.33,185.2)
SD3_RX2_N: length 174.4
  TOP w0.091: v2(179.2,205.18) 179.1,205.28 179.1,205.55 179.26,205.71 179.84,205.71 180.05,205.51 198.63,205.51 199.63,204.51 203.44,204.51 203.93,205 204.29,205 J3.A26 ; U22.BA20 v3(103.33,182.2)
  L14_INT_6 w0.086: v3(103.33,182.2) 103.33,182.34 103.21,182.46 102.95,182.46 102.73,182.68 102.73,185.66 102.66,185.73 102.66,186.38 104.39,188.11 104.39,189.38 105.7,190.69 107.63,190.69 110.59,193.65 121.28,193.65 123.76,196.13 123.76,203.45 142.41,222.09 142.41,235.41 147.76,240.76 166.29,240.76 170.24,236.81 170.24,228.85 181.91,217.18 181.91,208.32 179.1,205.5 179.1,205.28 v2(179.2,205.18)
SD3_RX2_P: length 174.5
  TOP w0.091: v3(103.33,183.2) 103.33,182.83 103.19,182.7 U22.BB20 ; v2(178.56,205.18) 178.82,205.44 178.82,205.66 179.15,205.99 179.96,205.99 180.16,205.79 198.75,205.79 199.75,204.79 203.3,204.79 203.78,205.27 203.78,205.49 203.62,205.65 J3.A25
  L14_INT_6 w0.086: v3(103.33,183.2) 103.33,182.76 103.23,182.65 103.03,182.65 102.92,182.76 102.92,185.66 103,185.73 103,186.23 104.73,187.97 104.73,189.24 105.84,190.35 107.77,190.35 110.73,193.31 121.42,193.31 124.1,195.99 124.1,203.3 142.75,221.95 142.75,235.27 147.9,240.42 166.14,240.42 169.9,236.66 169.9,228.7 181.57,217.04 181.57,208.46 178.75,205.65 178.75,205.37 v2(178.56,205.18)
SD3_RX3_N: length 181.3
  TOP w0.091: U22.BC21 v3(102.33,184.2) ; v2(179.2,200.66) 179.1,200.76 179.1,201.31 179.3,201.51 198.7,201.51 199.7,200.51 203.46,200.51 203.94,200.99 204.31,200.99 J3.A30
  L14_INT_6 w0.086: v2(179.2,200.66) 179.1,200.76 179.1,201.24 183.23,205.38 183.23,217.92 171.56,229.59 171.56,237.35 166.8,242.11 147.24,242.11 141.08,235.96 141.08,223.1 122.24,204.25 122.24,197.91 120.03,195.69 110.77,195.69 107.08,192.01 104.9,192.01 103.07,190.18 103.07,188.62 101.67,187.22 101.67,185.88 101.74,185.8 101.74,184.71 101.97,184.48 102.23,184.48 102.33,184.38 v3(102.33,184.2)
SD3_RX3_P: length 181.2
  TOP w0.091: J3.A29 203.66,201.65 203.78,201.52 203.78,201.23 203.34,200.79 199.81,200.79 198.81,201.79 179.18,201.79 178.82,201.42 178.82,200.91 v2(178.56,200.66) ; U22.BD21 102.07,184.7 102.33,184.96 v3(102.33,185.2)
  L14_INT_6 w0.086: v2(178.56,200.66) 178.75,200.85 178.75,201.39 182.89,205.52 182.89,217.77 171.21,229.44 171.21,237.21 166.66,241.77 147.38,241.77 141.43,235.82 141.43,222.95 122.58,204.11 122.58,197.76 120.17,195.35 110.91,195.35 107.22,191.67 105.04,191.67 103.41,190.04 103.41,188.47 102.01,187.07 102.01,185.96 101.93,185.88 101.93,184.78 102.05,184.67 102.22,184.67 102.33,184.78 v3(102.33,185.2)
SD3_RX4_N: length 191.5
  TOP w0.091: J3.A36 204.35,194.94 203.98,194.94 203.57,194.54 199.57,194.54 198.63,195.49 185.86,195.49 185.29,196.06 184.9,196.06 184.68,195.85 184.68,195.5 v2(184.78,195.4) ; U22.BA22 v3(101.33,182.2)
  L14_INT_6 w0.086: v3(101.33,182.2) 101.09,182.44 100.85,182.44 100.47,182.81 100.47,187.26 101.74,188.53 101.74,191.58 104.58,194.41 107.61,194.41 110.15,196.94 110.15,204.81 113.25,207.91 123.69,207.91 139.76,223.99 139.76,236.51 150.55,247.29 163.5,247.29 172.89,237.91 172.89,230.27 185.18,217.97 185.18,202.45 183.48,200.75 183.48,197.24 184.63,196.09 184.63,195.55 v2(184.78,195.4)
SD3_RX4_P: length 191.5
  TOP w0.091: v2(184.15,195.4) 184.4,195.66 184.4,195.96 184.78,196.34 185.4,196.34 185.98,195.76 198.74,195.76 199.69,194.82 203.45,194.82 203.91,195.28 203.91,195.48 203.74,195.65 J3.A35 ; v3(101.33,183.2) 101.33,182.81 101.21,182.7 U22.BB22
  L14_INT_6 w0.086: v3(101.33,183.2) 101.33,182.91 101.19,182.78 100.99,182.78 100.81,182.96 100.81,187.12 102.08,188.39 102.08,191.43 104.72,194.07 107.76,194.07 110.36,196.67 110.41,196.67 110.49,196.75 110.49,204.67 113.39,207.57 123.83,207.57 140.11,223.85 140.11,236.37 150.69,246.95 163.36,246.95 172.54,237.77 172.54,230.12 184.84,217.83 184.84,202.59 183.13,200.89 183.13,197.1 184.29,195.95 184.29,195.54 v2(184.15,195.4)
SD3_RX5_N: length 202.1
  TOP w0.091: v3(99.33,184.19) U22.BC23 ; v2(187.71,191.31) 187.88,191.49 198.61,191.49 199.59,190.51 203.26,190.51 203.75,191.01 204.29,191.01 J3.A40
  L14_INT_6 w0.086: v3(99.33,184.19) 99.33,184.4 99.45,184.52 99.79,184.52 100.11,184.85 100.11,185.92 99.9,186.13 99.9,187.4 100.77,188.27 100.77,192.28 103.91,195.43 106.98,195.43 108.79,197.23 108.79,212.12 111.4,214.73 118.62,214.73 119.54,213.8 126.94,213.8 138.79,225.65 138.79,244.04 140.64,245.9 145.75,245.9 148.12,248.27 163.91,248.27 173.86,238.32 173.86,230.67 186.79,217.74 186.79,195.73 185.99,194.93 185.99,192.16 186.67,191.48 187.54,191.48 v2(187.71,191.31)
SD3_RX5_P: length 202
  TOP w0.091: J3.A39 203.32,191.65 203.53,191.44 203.53,191.18 203.14,190.79 199.71,190.79 198.73,191.77 187.88,191.77 v2(187.71,191.95) ; v3(99.33,185.19) U22.BD23
  L14_INT_6 w0.086: v3(99.33,185.19) 99.33,185 99.47,184.86 99.64,184.86 99.77,184.99 99.77,185.78 99.56,185.99 99.56,187.54 100.42,188.41 100.42,192.43 103.77,195.77 106.84,195.77 108.45,197.37 108.45,212.26 111.26,215.07 118.76,215.07 119.69,214.15 126.79,214.15 138.44,225.8 138.44,244.19 140.5,246.24 145.6,246.24 147.97,248.61 164.05,248.61 174.2,238.46 174.2,238.12 174.2,230.82 187.13,217.89 187.13,195.59 186.33,194.79 186.33,192.3 186.82,191.82 187.62,191.82 187.71,191.91 v2(187.71,191.95)
SD3_RX6_N: length 207.5
  TOP w0.091: v2(190.11,187.27) 190.28,187.45 198.66,187.45 199.6,186.51 203.27,186.51 203.84,187.07 204.23,187.07 J3.A44 ; v3(98.33,182.19) U22.BA24
  L14_INT_6 w0.086: v2(190.11,187.27) 189.97,187.41 189.37,187.41 188.81,187.97 188.81,217.77 175.18,231.4 175.18,238.86 164.45,249.59 146.69,249.59 144.55,247.45 140.31,247.45 136.83,243.97 136.83,226.74 126.41,216.33 108.86,216.33 103.4,210.87 103.4,196.85 98.99,192.44 98.99,185.98 98.92,185.9 98.92,182.85 98.68,182.62 98.43,182.62 98.33,182.52 v3(98.33,182.19)
SD3_RX6_P: length 207.5
  TOP w0.091: v2(190.11,187.91) 190.28,187.73 198.78,187.73 199.72,186.79 203.16,186.79 203.48,187.11 203.48,187.43 203.26,187.65 J3.A43 ; v3(98.33,183.19) U22.BB24
  L14_INT_6 w0.086: v2(190.11,187.91) 189.95,187.76 189.51,187.76 189.15,188.11 189.15,217.91 175.52,231.54 175.52,239 164.59,249.93 146.55,249.93 144.41,247.79 140.17,247.79 136.49,244.11 136.49,226.89 126.27,216.67 108.72,216.67 103.06,211.01 103.06,196.99 98.65,192.58 98.65,185.98 98.73,185.9 98.73,182.93 98.6,182.8 98.42,182.8 98.33,182.89 v3(98.33,183.19)
SD3_RX7_N: length 216
  TOP w0.091: v2(192.94,183.18) 193.12,183.36 193.54,183.36 193.68,183.51 198.46,183.51 199.46,182.51 203.21,182.51 203.73,183.03 204.27,183.03 J3.A48 ; v3(97.33,184.19) U22.BC25
  L14_INT_6 w0.086: v2(192.94,183.18) 192.79,183.34 192.07,183.34 191.48,183.93 191.48,217.23 176.5,232.22 176.5,239.41 165,250.9 135.66,250.9 134.2,249.44 134.2,226.58 128.18,220.56 120.48,220.56 118.94,219.01 108.62,219.01 97.55,207.94 97.55,186.52 97.47,186.44 97.47,186.13 97.93,185.68 97.93,184.86 97.67,184.6 97.42,184.6 97.33,184.52 v3(97.33,184.19)
SD3_RX7_P: length 216.1
  TOP w0.091: v3(97.33,185.19) U22.BD25 ; J3.A47 203.27,183.65 203.45,183.46 203.45,183.15 203.1,182.79 199.58,182.79 198.58,183.79 193.57,183.79 193.42,183.64 193.12,183.64 v2(192.94,183.82)
  L14_INT_6 w0.086: v2(192.94,183.82) 192.8,183.68 192.22,183.68 191.82,184.08 191.82,217.38 176.84,232.36 176.84,239.55 165.14,251.25 135.52,251.25 133.86,249.58 133.86,226.72 128.04,220.9 120.34,220.9 118.79,219.35 108.48,219.35 97.2,208.08 97.2,186.52 97.28,186.44 97.28,186.06 97.74,185.6 97.74,184.94 97.59,184.79 97.42,184.79 97.33,184.87 v3(97.33,185.19)
SD3_TX0_N: length 145.2
  TOP w0.091: v2(179.2,215.33) 179.45,215.58 193.94,215.58 194.06,215.46 C78.1 ; v3(105.33,177.2) 105.06,177.2 104.83,176.97 U22.AT18
  L5_INT_2 w0.086: v2(179.2,215.33) 179.06,215.47 178.15,215.47 166.67,226.95 166.67,236.37 165.22,237.83 149.04,237.83 147.83,236.61 147.83,227.74 123.14,203.05 123.14,195.68 118.89,191.43 114.36,191.43 110.46,187.53 107.05,187.53 105.26,185.74 105.17,185.74 104.94,185.5 104.94,177.28 105.02,177.2 v3(105.33,177.2)
SD3_TX0_P: length 145.1
  TOP w0.091: v2(179.2,215.96) 179.3,215.86 193.77,215.86 C76.1 ; U22.AU18 v3(104.33,177.2)
  L5_INT_2 w0.086: v3(104.33,177.2) 104.64,177.2 104.72,177.28 104.72,185.59 105.02,185.89 105.02,185.98 106.91,187.87 110.32,187.87 114.22,191.77 118.75,191.77 122.8,195.82 122.8,203.19 147.49,227.88 147.49,236.76 148.9,238.17 165.36,238.17 167.02,236.51 167.02,227.09 178.3,215.81 179.04,215.81 v2(179.2,215.96)
SD3_TX1_N: length 152.6
  TOP w0.091: v2(179.2,211.4) 179.1,211.51 179.1,211.84 179.2,211.94 180.1,211.94 180.71,211.33 193.87,211.33 C80.1 ; U22.AV19 v3(104.33,179.2)
  L5_INT_2 w0.086: v3(104.33,179.2) 104.33,179.36 104.23,179.46 103.93,179.46 103.72,179.67 103.72,185.48 103.65,185.54 103.65,186.1 107.82,190.27 109.73,190.27 112.88,193.42 118.39,193.42 121.41,196.45 121.41,203.67 145.28,227.54 145.28,236.42 148.35,239.49 165.91,239.49 169,236.4 169,228.03 180.54,216.49 180.54,212.98 179.51,211.95 179.29,211.95 179.11,211.77 179.11,211.49 v2(179.2,211.4)
SD3_TX1_P: length 152.5
  TOP w0.091: v2(178.56,211.4) 178.82,211.66 178.82,211.95 179.08,212.22 180.21,212.22 180.82,211.61 193.94,211.61 194.06,211.73 C79.1 ; v3(104.33,180.2) 104.33,179.82 104.21,179.7 U22.AW19
  L5_INT_2 w0.086: v2(178.56,211.4) 178.77,211.61 178.77,211.91 179.15,212.29 179.37,212.29 180.19,213.12 180.19,216.35 168.66,227.89 168.66,236.26 165.77,239.15 148.49,239.15 145.62,236.28 145.62,227.4 121.75,203.53 121.75,196.3 118.53,193.08 113.02,193.08 109.87,189.93 107.97,189.93 104,185.96 104,185.54 103.93,185.48 103.93,179.76 104.02,179.68 104.22,179.68 104.33,179.79 v3(104.33,180.2)
SD3_TX2_N: length 161.6
  TOP w0.091: v2(179.2,207.34) 179.1,207.44 179.1,207.71 179.24,207.85 180.25,207.85 180.76,207.34 193.86,207.34 C82.1 ; U22.AT20 v3(103.33,177.2)
  L5_INT_2 w0.086: v3(103.33,177.2) 103.33,177.34 103.16,177.51 102.93,177.51 102.72,177.72 102.72,185.57 102.66,185.63 102.66,186.38 104.58,188.31 104.58,189.43 110.22,195.07 114.3,195.07 117.31,198.08 117.31,201.64 143.93,228.26 143.93,236.94 147.8,240.81 166.46,240.81 170.32,236.95 170.32,228.58 181.86,217.04 181.86,209.9 179.78,207.82 179.22,207.82 179.08,207.68 179.08,207.45 v2(179.2,207.34)
SD3_TX2_P: length 161.5
  TOP w0.091: U22.AU20 103.22,177.7 103.33,177.8 v3(103.33,178.2) ; v2(178.56,207.34) 178.82,207.59 178.82,207.82 179.12,208.13 180.37,208.13 180.87,207.62 193.94,207.62 194.06,207.75 C81.1
  L5_INT_2 w0.086: v2(178.56,207.34) 178.74,207.52 178.74,207.82 179.08,208.17 179.64,208.17 181.51,210.04 181.51,216.9 169.98,228.44 169.98,236.8 166.31,240.47 147.94,240.47 144.27,236.8 144.27,228.12 117.65,201.5 117.65,197.94 114.44,194.73 110.36,194.73 104.93,189.29 104.93,188.16 103,186.23 103,185.63 102.93,185.56 102.93,177.81 103.01,177.73 103.24,177.73 103.33,177.81 v3(103.33,178.2)
SD3_TX3_N: length 171.6
  TOP w0.091: U22.AV21 v3(102.33,179.2) ; C90.1 193.86,203.34 180.95,203.34 180.45,203.84 179.29,203.84 179.1,203.64 179.1,203.35 v2(179.2,203.25)
  L5_INT_2 w0.086: v3(102.33,179.2) 102.33,179.32 102.16,179.49 101.92,179.49 101.71,179.7 101.71,185.51 101.65,185.58 101.65,188.44 106.26,193.05 106.26,193.74 110.07,197.55 110.07,205.15 113.29,208.37 121.98,208.37 142.53,228.92 142.53,237.41 147.25,242.13 167,242.13 167.11,242.03 167.13,242.03 171.64,237.52 171.64,229.12 183.18,217.59 183.18,206.6 180.33,203.76 179.14,203.76 179.05,203.67 179.05,203.4 v2(179.2,203.25)
SD3_TX3_P: length 171.5
  TOP w0.091: C88.1 194.06,203.77 193.92,203.62 181.06,203.62 180.57,204.11 179.17,204.11 178.82,203.76 178.82,203.5 v2(178.56,203.25) ; U22.AW21 102.22,179.7 102.33,179.8 v3(102.33,180.2)
  L5_INT_2 w0.086: v3(102.33,180.2) 102.33,179.8 102.24,179.7 102.01,179.7 101.93,179.79 101.93,185.51 101.99,185.58 101.99,188.3 106.6,192.91 106.6,193.6 110.41,197.41 110.41,205 113.44,208.03 122.12,208.03 142.88,228.78 142.88,237.27 147.4,241.79 166.86,241.79 166.96,241.69 166.99,241.69 171.3,237.37 171.3,228.98 182.84,217.44 182.84,206.74 180.19,204.1 178.99,204.1 178.71,203.82 178.71,203.4 v2(178.56,203.25)
SD3_TX4_N: length 183.4
  TOP w0.091: v2(184.78,198.12) 184.68,198.22 184.68,198.65 184.84,198.81 188.1,198.81 189.58,197.32 193.91,197.32 C96.1 ; U22.AT22 v3(101.33,177.2)
  L5_INT_2 w0.086: v3(101.33,177.2) 101.17,177.36 100.7,177.36 100.24,177.81 100.24,178.91 100.59,179.25 100.59,191.64 104.63,195.68 106.3,195.68 108.41,197.79 108.41,209.01 114.16,214.77 118,214.77 119.76,213 123.99,213 140.94,229.96 140.94,237.69 150.51,247.25 163.8,247.25 172.96,238.09 172.96,229.67 184.68,217.95 184.68,198.22 v2(184.78,198.12)
SD3_TX4_P: length 183.2
  TOP w0.091: U22.AU22 101.22,177.7 101.33,177.81 v3(101.33,178.2) ; v2(184.15,198.12) 184.4,198.37 184.4,198.77 184.72,199.09 188.21,199.09 189.7,197.6 193.9,197.6 194.06,197.76 C95.1
  L5_INT_2 w0.086: v2(184.15,198.12) 184.34,198.31 184.34,217.81 172.62,229.53 172.62,237.94 163.66,246.91 150.65,246.91 141.29,237.55 141.29,229.81 124.14,212.66 119.62,212.66 117.86,214.43 114.31,214.43 108.75,208.87 108.75,197.65 106.44,195.34 104.77,195.34 100.93,191.5 100.93,179.11 100.58,178.77 100.58,177.95 100.84,177.7 101.22,177.7 101.33,177.81 v3(101.33,178.2)
SD3_TX5_N: length 189.7
  TOP w0.091: v3(99.33,179.19) U22.AV23 ; C108.1 193.68,193.55 187.91,193.55 v2(187.71,193.34)
  L5_INT_2 w0.086: v3(99.33,179.19) 99.33,179.42 99.42,179.5 99.77,179.5 100.09,179.82 100.09,187.87 99.31,188.65 99.31,191.74 103.35,195.79 103.35,205.34 113.76,215.75 118.4,215.75 120.17,213.98 123.59,213.98 139.35,229.74 139.35,244.58 140.93,246.15 146.25,246.15 148.32,248.23 164.21,248.23 173.94,238.5 173.94,230.08 186.3,217.72 186.3,194.12 186.93,193.48 187.57,193.48 v2(187.71,193.34)
SD3_TX5_P: length 189.7
  TOP w0.091: C103.1 193.71,193.83 187.86,193.83 v2(187.71,193.98) ; v3(99.33,180.19) U22.AW23
  L5_INT_2 w0.086: v3(99.33,180.19) 99.33,179.94 99.43,179.84 99.63,179.84 99.74,179.96 99.74,187.73 98.96,188.51 98.96,191.88 103.01,195.93 103.01,205.48 113.62,216.09 118.55,216.09 120.31,214.33 123.45,214.33 139.01,229.89 139.01,244.72 140.78,246.49 146.1,246.49 148.18,248.57 164.36,248.57 174.28,238.65 174.28,230.22 186.64,217.86 186.64,194.26 187.07,193.83 187.55,193.83 v2(187.71,193.98)
SD3_TX6_N: length 198.8
  TOP w0.091: v3(98.33,177.19) U22.AT24 ; C126.1 193.62,189.55 190.35,189.55 v2(190.11,189.31)
  L5_INT_2 w0.086: v2(190.11,189.31) 189.97,189.45 189.47,189.45 189.01,189.9 189.01,216.87 175.26,230.62 175.26,239.06 164.77,249.55 147.18,249.55 145.15,247.52 138.04,247.52 136.88,246.37 136.88,229.32 123.89,216.33 119.69,216.33 118.95,217.07 112.9,217.07 101.82,205.98 101.82,196.12 97.99,192.29 97.99,188.38 99.01,187.36 99.01,185.58 98.94,185.51 98.94,177.83 98.69,177.58 98.42,177.58 98.33,177.5 v3(98.33,177.19)
SD3_TX6_P: length 198.9
  TOP w0.091: v3(98.33,178.19) U22.AU24 ; v2(190.11,189.94) 190.22,189.83 193.77,189.83 C118.1
  L5_INT_2 w0.086: v3(98.33,178.19) 98.33,177.89 98.42,177.8 98.6,177.8 98.73,177.92 98.73,185.51 98.67,185.58 98.67,187.21 97.64,188.24 97.64,192.43 101.47,196.26 101.47,206.12 112.76,217.41 119.09,217.41 119.84,216.67 123.74,216.67 136.54,229.46 136.54,246.51 137.9,247.87 145.01,247.87 147.03,249.89 164.92,249.89 175.6,239.2 175.6,230.77 189.36,217.01 189.36,190.04 189.61,189.79 189.95,189.79 v2(190.11,189.94)
SD3_TX7_N: length 206
  TOP w0.091: C149.1 193.68,185.42 193.09,185.42 v2(192.91,185.24) ; v3(97.33,179.19) U22.AV25
  L5_INT_2 w0.086: v3(97.33,179.19) 97.33,179.55 97.42,179.63 97.71,179.63 97.95,179.88 97.95,185.46 98.02,185.53 98.02,186.66 96.67,188.01 96.67,192.84 97.71,193.88 97.71,205.6 111.9,219.79 125.33,219.79 133.71,228.17 133.71,248.84 135.73,250.87 165.32,250.87 176.81,239.38 176.81,230.94 191.08,216.67 191.08,186.13 191.83,185.38 192.77,185.38 v2(192.91,185.24)
SD3_TX7_P: length 206.1
  TOP w0.091: v2(192.91,185.88) 193.09,185.7 193.71,185.7 C147.1 ; U22.AW25 v3(97.33,180.19)
  L5_INT_2 w0.086: v3(97.33,180.19) 97.33,179.95 97.44,179.85 97.62,179.85 97.74,179.97 97.74,185.46 97.67,185.53 97.67,186.52 96.32,187.87 96.32,192.98 97.37,194.03 97.37,205.74 111.76,220.13 125.18,220.13 133.36,228.31 133.36,248.99 135.59,251.21 165.46,251.21 177.15,239.52 177.15,231.09 191.43,216.81 191.43,186.27 191.97,185.72 192.76,185.72 v2(192.91,185.88)
SD3_TXC0_N: length 5.6
  TOP w0.091: J3.B15 199.77,216.03 199.36,216.03 198.84,215.51 195.44,215.51 C78.2
SD3_TXC0_P: length 5.6
  TOP w0.091: C76.2 195.43,215.79 198.73,215.79 199.09,216.15 199.09,216.38 198.82,216.65 J3.B14
SD3_TXC1_N: length 5.6
  TOP w0.091: J3.B20 198.87,210.65 199.07,210.86 199.07,211.16 198.73,211.51 195.44,211.51 C80.2
SD3_TXC1_P: length 5.6
  TOP w0.091: J3.B19 199.75,211.25 199.38,211.25 198.84,211.79 195.43,211.79 C79.2
SD3_TXC2_N: length 5.6
  TOP w0.091: J3.B24 198.84,206.65 199.06,206.87 199.06,207.2 198.75,207.51 195.44,207.51 C82.2
SD3_TXC2_P: length 5.6
  TOP w0.091: C81.2 195.43,207.79 198.86,207.79 199.39,207.26 199.76,207.26 J3.B23
SD3_TXC3_N: length 5.6
  TOP w0.091: J3.B28 198.84,202.65 199.06,202.87 199.06,203.16 198.71,203.51 195.44,203.51 C90.2
SD3_TXC3_P: length 5.6
  TOP w0.091: J3.B27 199.77,203.28 199.34,203.28 198.82,203.79 195.43,203.79 C88.2
SD3_TXC4_N: length 5.6
  TOP w0.091: J3.B34 198.86,196.65 199.06,196.85 199.06,197.14 198.66,197.54 195.43,197.54 C96.2
SD3_TXC4_P: length 5.6
  TOP w0.091: C95.2 195.43,197.82 198.78,197.82 199.31,197.28 199.78,197.28 J3.B33
SD3_TXC5_N: length 5.6
  TOP w0.091: J3.B38 198.9,192.65 199.06,192.81 199.06,193.18 198.7,193.54 195.43,193.54 C108.2
SD3_TXC5_P: length 5.6
  TOP w0.091: J3.B37 199.74,193.24 199.39,193.24 198.82,193.82 195.43,193.82 C103.2
SD3_TXC6_N: length 5.6
  TOP w0.091: J3.B42 198.84,188.65 199.03,188.85 199.03,189.17 198.67,189.54 195.5,189.54 C126.2
SD3_TXC6_P: length 5.6
  TOP w0.091: J3.B41 199.75,189.26 199.35,189.26 198.79,189.82 195.37,189.82 C118.2
SD3_TXC7_N: length 5.6
  TOP w0.091: C149.2 195.59,185.56 198.65,185.56 199.01,185.2 199.01,184.88 198.78,184.65 J3.B46
SD3_TXC7_P: length 5.6
  TOP w0.091: C147.2 195.28,185.84 198.76,185.84 199.34,185.27 199.76,185.27 J3.B45
SD4_IMP_CAL_RX: length 1.4
  TOP w0.118: v3(96.33,174.19) U22.AN26
  BOTTOM w0.118: R697.1 v3(96.33,174.19)
SD4_IMP_CAL_TX: length 1.4
  TOP w0.118: v3(91.33,174.19) U22.AN32
  BOTTOM w0.118: v3(91.33,174.19) 91.86,173.7 R695.1
SD4_PLL1_TPA: length 1.4
  TOP w0.118: v3(94.33,174.19) U22.AN28
  BOTTOM w0.118: v3(94.33,174.19) TP80.1
SD4_PLL1_TPD: length 1.4
  TOP w0.118: U22.AP26 v3(96.33,175.19)
  BOTTOM w0.118: TP73.1 95.82,174.69 v3(96.33,175.19)
SD4_PLL2_TPA: length 1.4
  TOP w0.118: v3(93.33,174.19) U22.AN30
  BOTTOM w0.118: v3(93.33,174.19) 92.84,173.7 TP81.1
SD4_PLL2_TPD: length 1.4
  TOP w0.118: U22.AP32 v3(91.33,175.19)
  BOTTOM w0.118: TP74.1 90.82,174.69 v3(91.33,175.19)
SD4_REFCLK1_N: length 128.1
  TOP w0.091: v3(95.33,173.19) U22.AM27 ; U32.23 104.51,106.48 104.4,106.37 103.47,106.37 102.66,105.56 102.27,105.56 v2(101.88,105.95)
  L12_INT_5 w0.086: v3(95.33,173.19) 95.33,172.89 95.45,172.77 95.7,172.77 95.95,172.52 95.95,171.88 95.64,171.57 94.05,171.57 93.72,171.9 93.72,172.42 93.56,172.58 78.65,172.58 78.58,172.51 76.86,172.51 75.07,170.73 72.63,170.73 63.27,161.37 63.27,152.12 64.72,150.67 64.72,142.65 67.09,140.27 67.09,137.91 77.22,127.79 84.25,127.79 97.29,114.74 97.29,103.87 98.64,102.53 100.4,102.53 100.88,103.01 100.88,105.22 101.26,105.6 101.78,105.6 101.88,105.71 v2(101.88,105.95)
SD4_REFCLK1_P: length 128.2
  TOP w0.091: v2(101.88,105.04) 101.89,105.04 102.13,105.28 102.78,105.28 103.59,106.09 104.4,106.09 104.51,105.98 U32.24 ; v3(95.33,172.19) U22.AL27
  L12_INT_5 w0.086: v3(95.33,172.19) 95.33,172.45 95.44,172.56 95.61,172.56 95.74,172.44 95.74,171.97 95.55,171.78 94.14,171.78 93.93,171.99 93.93,172.5 93.65,172.79 78.65,172.79 78.58,172.86 76.72,172.86 74.93,171.07 72.49,171.07 62.93,161.51 62.93,151.98 64.38,150.53 64.38,142.51 66.75,140.13 66.75,137.77 77.07,127.44 84.11,127.44 96.95,114.6 96.95,103.73 98.5,102.18 100.54,102.18 101.23,102.87 101.23,105.08 101.4,105.26 101.66,105.26 v2(101.88,105.04)
SD4_REFCLK2_N: length 115.4
  TOP w0.091: v3(93.33,172.19) U22.AL29 ; v2(99.8,104.36) 99.8,104.05 99.92,103.93 102.58,103.93 103.53,104.87 104.4,104.87 104.51,104.98 U32.26
  L12_INT_5 w0.086: v3(93.33,172.19) 92.97,172.19 92.88,172.1 92.88,171.81 92.65,171.58 79,171.58 78.99,171.59 78.98,171.59 78.92,171.53 77.52,171.53 75.58,169.58 73.34,169.58 64.69,160.93 64.69,152.93 65.91,151.71 65.91,143.33 79.5,129.74 84,129.74 98.36,115.38 98.36,104.51 98.94,103.93 99.67,103.93 99.8,104.05 v2(99.8,104.36)
SD4_REFCLK2_P: length 115.5
  TOP w0.091: U32.27 104.51,104.48 104.4,104.59 103.64,104.59 102.7,103.65 100,103.65 v2(99.8,103.44) ; v3(92.33,172.19) U22.AL30
  L12_INT_5 w0.086: v3(92.33,172.19) 92.58,172.19 92.66,172.11 92.66,171.89 92.56,171.79 79,171.79 78.92,171.87 77.38,171.87 75.44,169.93 73.2,169.93 64.35,161.08 64.35,152.79 65.57,151.57 65.57,143.19 79.36,129.4 83.86,129.4 98.02,115.24 98.02,104.37 98.8,103.59 99.65,103.59 v2(99.8,103.44)
SD4_RX0_N: length 184.5
  TOP w0.091: v3(96.33,182.19) U22.BA26 ; U55.A17 223.96,213.65 224.33,214.02 225.42,214.02 v2(225.75,213.69)
  L3_INT_1 w0.086: v3(96.33,182.19) 96.33,182.5 96.42,182.6 96.69,182.6 96.94,182.85 96.94,185.49 97.12,185.66 97.21,185.66 97.52,185.97 100.88,185.97 103.43,188.52 103.43,203.3 107.85,207.72 119.64,207.72 149.7,237.78 165.22,237.78 166.33,236.66 166.33,234.48 168.95,231.86 187.49,231.86 189.59,233.96 213.92,233.96 223.66,224.22 223.66,214.79 224.44,214.01 225.43,214.01 v2(225.75,213.69)
SD4_RX0_P: length 184.5
  TOP w0.091: v3(96.33,183.19) U22.BB26 ; v2(225.75,214.61) 225.44,214.3 224.31,214.3 223.96,214.65 U55.A16
  L3_INT_1 w0.086: v2(225.75,214.61) 225.49,214.35 224.59,214.35 224,214.93 224,224.36 214.06,234.3 189.45,234.3 187.35,232.21 169.09,232.21 166.67,234.62 166.67,236.81 165.36,238.12 149.55,238.12 119.49,208.06 107.71,208.06 103.09,203.44 103.09,188.66 100.73,186.31 97.37,186.31 96.97,185.9 96.97,185.81 96.73,185.57 96.73,182.93 96.61,182.81 96.42,182.81 96.33,182.89 v3(96.33,183.19)
SD4_RX1_N: length 195.7
  TOP w0.091: v2(225.75,208.69) 225.42,209.02 224.33,209.02 223.96,208.65 U55.A22 ; v3(95.33,184.19) U22.BC27
  L3_INT_1 w0.086: v3(95.33,184.19) 95.33,184.55 95.43,184.65 95.74,184.65 95.95,184.86 95.95,186.8 96.01,186.87 96.01,187.07 96.27,187.32 100.33,187.32 101.87,188.86 101.87,206.56 109.78,214.48 117.14,214.48 118.43,213.19 123.24,213.19 149.16,239.12 165.76,239.12 171.64,233.24 186.68,233.24 188.78,235.33 215.67,235.33 226.96,224.04 226.96,212.92 224.4,210.35 224.4,209.46 224.85,209 225.44,209 v2(225.75,208.69)
SD4_RX1_P: length 195.8
  TOP w0.091: U55.A21 223.96,209.65 224.31,209.3 225.44,209.3 v2(225.75,209.61) ; v3(95.33,185.19) U22.BD27
  L3_INT_1 w0.086: v3(95.33,185.19) 95.33,184.97 95.44,184.86 95.65,184.86 95.74,184.95 95.74,186.84 95.67,186.9 95.67,187.21 96.12,187.67 100.19,187.67 101.52,189 101.52,206.71 109.64,214.82 117.29,214.82 118.57,213.54 123.1,213.54 149.02,239.46 165.9,239.46 171.78,233.58 186.54,233.58 188.63,235.67 215.81,235.67 227.3,224.18 227.3,212.78 224.74,210.21 224.74,209.6 224.99,209.35 225.49,209.35 v2(225.75,209.61)
SD4_RX2_N: length 211.5
  TOP w0.091: v2(225.75,204.69) 225.42,205.02 224.33,205.02 223.96,204.65 U55.A26 ; v3(94.33,181.19) U22.BA28
  L3_INT_1 w0.086: v2(225.75,204.69) 225.44,205 224.87,205 224.33,205.54 224.33,206.7 224.99,207.37 226.49,207.37 229.15,210.02 229.15,228.99 218.11,240.03 186.74,240.03 181.75,235.04 171.77,235.04 166.37,240.44 148.57,240.44 124.46,216.33 109.21,216.33 98.36,205.47 98.36,191.71 95.01,188.36 95.01,186.3 94.95,186.24 94.95,181.86 94.71,181.62 94.4,181.62 94.33,181.55 v3(94.33,181.19)
SD4_RX2_P: length 211.6
  TOP w0.091: v2(225.75,205.61) 225.44,205.3 224.31,205.3 223.96,205.65 U55.A25 ; v3(94.33,182.19) U22.BB28
  L3_INT_1 w0.086: v3(94.33,182.19) 94.33,181.92 94.42,181.83 94.62,181.83 94.74,181.95 94.74,186.23 94.67,186.3 94.67,188.5 98.02,191.85 98.02,205.62 109.07,216.67 124.31,216.67 148.42,240.78 166.51,240.78 171.91,235.38 181.61,235.38 186.6,240.37 218.25,240.37 229.49,229.13 229.49,209.88 226.63,207.02 225.13,207.02 224.67,206.56 224.67,205.69 225.01,205.35 225.49,205.35 v2(225.75,205.61)
SD4_RX3_N: length 218.9
  TOP w0.091: U22.BC29 93.33,183.2 v3(93.33,183.19) ; v2(225.75,200.69) 225.45,200.99 224.3,200.99 223.96,200.65 U55.A30
  L3_INT_1 w0.086: v2(225.75,200.69) 225.46,200.98 224.77,200.98 224.27,201.48 224.27,202.76 224.84,203.33 226.62,203.33 230.89,207.59 230.89,229.35 218.88,241.35 185.57,241.35 180.8,236.58 172.1,236.58 166.92,241.76 147.9,241.76 126.71,220.56 122.21,220.56 120.56,218.91 109.77,218.91 97,206.15 97,192.53 94.01,189.53 94.01,186.2 93.94,186.13 93.94,183.92 93.68,183.66 93.42,183.66 93.33,183.58 v3(93.33,183.19)
SD4_RX3_P: length 219
  TOP w0.091: U22.BD29 93.33,184.2 v3(93.33,184.19) ; v2(225.75,201.61) 225.41,201.27 224.34,201.27 223.96,201.65 U55.A29
  L3_INT_1 w0.086: v3(93.33,184.19) 93.33,183.96 93.41,183.88 93.6,183.88 93.73,184.01 93.73,186.13 93.66,186.2 93.66,189.68 96.66,192.67 96.66,206.29 109.62,219.25 120.42,219.25 122.07,220.9 126.57,220.9 147.76,242.1 167.06,242.1 172.24,236.92 180.66,236.92 185.43,241.69 219.03,241.69 231.23,229.49 231.23,207.45 226.76,202.98 224.98,202.98 224.61,202.62 224.61,201.63 224.92,201.32 225.46,201.32 v2(225.75,201.61)
SD4_RX6_N: length 188.3
  TOP w0.091: v2(14.64,51.93) 14.98,51.59 15.49,51.59 16.01,51.07 16.28,51.07 C402.1 ; v3(90.33,182.19) U22.BA32
  L12_INT_5 w0.086: v3(90.33,182.19) 90.33,182.48 90.42,182.57 90.74,182.57 90.95,182.78 90.95,184.71 90.63,185.04 90.2,185.04 90.13,185.1 80.2,185.1 78.24,183.15 78.24,178.35 75.23,175.34 70.99,175.34 57.98,162.32 57.98,113.74 54.19,109.95 54.19,103.88 40.78,90.46 28.03,90.46 15.9,78.33 15.9,52.07 15.47,51.64 14.91,51.64 14.64,51.91 v2(14.64,51.93)
SD4_RX6_P: length 188.2
  TOP w0.091: C406.1 16.28,50.79 15.9,50.79 15.38,51.31 14.93,51.31 v2(14.64,51.02) ; v3(90.33,183.19) U22.BB32
  L12_INT_5 w0.086: v2(14.64,51.02) 14.91,51.3 15.61,51.3 16.24,51.93 16.24,52.44 16.42,52.62 16.42,53.12 16.24,53.3 16.24,53.81 16.42,53.99 16.42,54.5 16.24,54.67 16.24,55.18 16.42,55.36 16.42,55.87 16.24,56.05 16.24,56.55 16.42,56.73 16.42,57.24 16.24,57.42 16.24,78.19 28.17,90.12 40.92,90.12 54.53,103.73 54.53,109.81 58.32,113.59 58.32,162.18 71.13,174.99 75.37,174.99 78.59,178.21 78.59,183 80.34,184.76 90.13,184.76 90.2,184.82 90.54,184.82 90.73,184.63 90.73,182.87 90.65,182.78 90.42,182.78 90.33,182.87 v3(90.33,183.19)
SD4_RXC6_N: length 5.6
  TOP w0.091: C406.2 18.01,50.79 21.53,50.79 22.02,50.29 J10.5
SD4_RXC6_P: length 5.6
  TOP w0.091: C402.2 18.01,51.07 21.53,51.07 22.02,51.56 J10.6
SD4_TX0_N: length 181.2
  TOP w0.091: U22.AT26 v3(96.33,177.19) ; C482.1 214.77,215.8 214.53,216.03 213.42,216.03 v2(213.08,215.69)
  L7_INT_3 w0.086: v3(96.33,177.19) 96.33,177.5 96.42,177.59 97.63,177.59 97.94,177.9 97.94,185.87 98,185.93 98,195 97.17,195.84 97.17,206.46 103.46,212.75 112.45,212.75 113.76,214.06 117.99,214.06 119.3,212.75 124.46,212.75 149.54,237.83 178.93,237.83 182.45,234.31 207.77,234.31 211.05,231.04 211.05,216.94 211.98,216.01 212.75,216.01 v2(213.08,215.69)
SD4_TX0_P: length 181.3
  TOP w0.091: C481.1 214.42,216.31 213.38,216.31 v2(213.08,216.6) ; v3(96.33,178.19) U22.AU26
  L7_INT_3 w0.086: v3(96.33,178.19) 96.33,177.89 96.42,177.8 97.54,177.8 97.73,177.99 97.73,185.87 97.66,185.93 97.66,194.86 96.82,195.7 96.82,206.6 103.31,213.09 112.3,213.09 113.61,214.4 118.13,214.4 119.44,213.09 124.32,213.09 149.4,238.18 179.07,238.18 182.59,234.66 207.91,234.66 211.39,231.18 211.39,217.08 212.12,216.36 212.83,216.36 v2(213.08,216.6)
SD4_TX1_N: length 190.9
  TOP w0.091: v3(95.33,179.19) U22.AV27 ; C997.1 214.4,211.01 213.4,211.01 v2(213.08,210.69)
  L7_INT_3 w0.086: v2(213.08,210.69) 212.78,210.99 212.2,210.99 211.79,211.4 211.79,212.98 212.29,213.49 213.89,213.49 214.66,214.25 214.66,217.47 212.83,219.3 212.83,231.83 209.02,235.64 183.7,235.64 180.19,239.15 148.62,239.15 123.53,214.07 119.85,214.07 118.54,215.38 113.12,215.38 111.81,214.07 102.83,214.07 95.59,206.83 95.59,193.68 96.39,192.88 96.39,187.87 96.01,187.48 96.01,186.7 95.95,186.64 95.95,179.84 95.74,179.63 95.42,179.63 95.33,179.55 v3(95.33,179.19)
SD4_TX1_P: length 191
  TOP w0.091: C996.1 214.4,211.28 213.4,211.28 v2(213.08,211.6) ; v3(95.33,180.19) U22.AW27
  L7_INT_3 w0.086: v3(95.33,180.19) 95.33,179.93 95.42,179.84 95.65,179.84 95.74,179.93 95.74,186.64 95.67,186.7 95.67,187.63 96.05,188.01 96.05,192.74 95.25,193.54 95.25,206.97 102.69,214.41 111.67,214.41 112.98,215.72 118.68,215.72 119.99,214.41 123.39,214.41 148.47,239.5 180.33,239.5 183.85,235.98 209.16,235.98 213.17,231.97 213.17,219.45 215,217.62 215,214.11 214.04,213.14 212.44,213.14 212.13,212.84 212.13,211.55 212.35,211.33 212.81,211.33 v2(213.08,211.6)
SD4_TX2_N: length 208.7
  TOP w0.091: U22.AT28 v3(94.33,177.19) ; v2(213.08,206.69) 213.4,207.01 214.4,207.01 C999.1
  L7_INT_3 w0.086: v2(213.08,206.69) 212.77,207 212.2,207 211.73,207.47 211.73,208.79 212.24,209.3 214.43,209.3 216.46,211.33 216.46,236.35 212.7,240.11 182.18,240.11 181.81,240.47 147.89,240.47 123.74,216.33 119.46,216.33 119.09,216.7 112.57,216.7 111.27,215.39 97.69,215.39 93.48,211.19 93.48,197 94.2,196.29 94.2,193.21 95,192.4 95,185.83 94.95,185.78 94.95,177.85 94.74,177.64 94.42,177.64 94.33,177.55 v3(94.33,177.19)
SD4_TX2_P: length 208.8
  TOP w0.091: v2(213.08,207.6) 213.4,207.28 214.4,207.28 C998.1 ; v3(94.33,178.19) U22.AU28
  L7_INT_3 w0.086: v2(213.08,207.6) 212.82,207.34 212.35,207.34 212.08,207.61 212.08,208.65 212.38,208.95 214.57,208.95 216.8,211.19 216.8,236.49 212.84,240.45 182.32,240.45 181.95,240.82 147.75,240.82 123.6,216.67 119.6,216.67 119.23,217.04 112.43,217.04 111.13,215.73 97.55,215.73 93.14,211.33 93.14,196.86 93.85,196.15 93.85,193.07 94.66,192.26 94.66,185.83 94.73,185.76 94.73,177.93 94.65,177.85 94.42,177.85 94.33,177.93 v3(94.33,178.19)
SD4_TX3_N: length 217.4
  TOP w0.091: v2(213.08,202.69) 213.4,203.01 214.4,203.01 C1001.1 ; v3(93.33,179.19) U22.AV29
  L7_INT_3 w0.086: v3(93.33,179.19) 93.33,179.56 93.42,179.64 93.74,179.64 93.95,179.85 93.95,184.55 94.02,184.61 94.02,186.35 92.88,187.49 92.88,195.75 91.16,197.46 91.16,211.91 96.06,216.81 108.75,216.81 111.63,219.7 124.24,219.7 146.33,241.8 182.36,241.8 182.73,241.43 213.54,241.43 217.81,237.16 217.81,207.65 215.42,205.26 212.49,205.26 211.87,204.64 211.87,203.39 212.29,202.97 212.8,202.97 v2(213.08,202.69)
SD4_TX3_P: length 217.5
  TOP w0.091: v2(213.08,203.6) 213.4,203.28 214.4,203.28 C1000.1 ; v3(93.33,180.19) U22.AW29
  L7_INT_3 w0.086: v3(93.33,180.19) 93.33,179.94 93.42,179.85 93.65,179.85 93.74,179.94 93.74,184.55 93.67,184.61 93.67,186.21 92.53,187.35 92.53,195.6 90.82,197.32 90.82,212.05 95.92,217.16 108.6,217.16 111.49,220.05 124.09,220.05 146.19,242.14 182.5,242.14 182.87,241.77 213.68,241.77 218.15,237.3 218.15,207.5 215.56,204.91 212.64,204.91 212.22,204.5 212.22,203.53 212.43,203.31 212.79,203.31 v2(213.08,203.6)
SD4_TX6_N: length 208.6
  TOP w0.091: v3(90.33,177.19) U22.AT32 ; v2(15.63,48.14) 15.32,47.82 15.32,47.47 15.56,47.23 16.5,47.23 16.65,47.38 C422.1
  L12_INT_5 w0.086: v3(90.33,177.19) 90.33,177.5 90.42,177.59 90.85,177.59 91.94,178.68 91.94,184.72 92.01,184.79 92.01,185.28 91.29,186 89.75,187.54 84.52,187.54 83.51,186.54 78.97,186.54 76.49,184.06 76.49,178.98 74.18,176.67 70.42,176.67 56.46,162.71 56.46,114.76 52.21,110.5 52.21,105.12 40,92.91 27.07,92.91 12.71,78.55 12.71,50.43 13.93,49.21 16.47,49.21 17.02,48.67 17.02,47.7 16.64,47.32 15.57,47.32 15.35,47.54 15.35,47.86 v2(15.63,48.14)
SD4_TX6_P: length 208.6
  TOP w0.091: U22.AU32 v3(90.33,178.19) ; C425.1 16.3,46.95 15.44,46.95 15.04,47.36 15.04,47.82 v2(14.72,48.14)
  L12_INT_5 w0.086: v2(14.72,48.14) 15.01,47.85 15.01,47.39 15.43,46.98 16.78,46.98 17.36,47.56 17.36,48.81 16.61,49.56 14.07,49.56 13.06,50.57 13.06,78.41 27.22,92.57 40.14,92.57 52.55,104.98 52.55,110.36 56.81,114.61 56.81,162.57 70.56,176.33 74.32,176.33 76.83,178.84 76.83,183.92 79.11,186.19 83.65,186.19 84.66,187.2 89.6,187.2 90.48,186.32 91.05,185.75 91.66,185.14 91.66,184.79 91.73,184.72 91.73,178.77 90.76,177.8 90.42,177.8 90.33,177.89 v3(90.33,178.19)
SD4_TXC0_N: length 4.4
  TOP w0.091: C482.2 216.14,216.01 219.12,216.01 219.48,215.65 U55.B15
SD4_TXC0_P: length 4.4
  TOP w0.091: C481.2 216.13,216.29 219.11,216.29 219.47,216.65 U55.B14
SD4_TXC1_N: length 4.4
  TOP w0.091: C997.2 216.14,211.01 219.12,211.01 219.48,210.65 U55.B20
SD4_TXC1_P: length 4.4
  TOP w0.091: U55.B19 219.47,211.65 219.11,211.29 216.13,211.29 C996.2
SD4_TXC2_N: length 4.4
  TOP w0.091: C999.2 216.14,207.01 219.12,207.01 219.48,206.65 U55.B24
SD4_TXC2_P: length 4.4
  TOP w0.091: U55.B23 219.47,207.65 219.11,207.29 216.13,207.29 C998.2
SD4_TXC3_N: length 4.4
  TOP w0.091: C1001.2 216.14,203.01 219.12,203.01 219.48,202.65 U55.B28
SD4_TXC3_P: length 4.4
  TOP w0.091: U55.B27 219.47,203.65 219.11,203.29 216.13,203.29 C1000.2
SD4_TXC6_N: length 5.6
  TOP w0.091: J10.3 22.02,47.75 21.53,47.26 18.01,47.26 C422.2
SD4_TXC6_P: length 5.6
  TOP w0.091: C425.2 18.01,46.98 21.55,46.98 22.05,46.48 J10.2
SD_CD#: length 3.7
  TOP w0.118: CN3.10 94.82,34.11 95.26,34.55 ESD10.1 95.26,35.76 95.17,35.84 R637.2
SD_WP: length 3.2
  TOP w0.118: CN3.11 ESD9.1 R667.2
SDCK: length 12.6
  TOP w0.118: v2(81.28,39.12) 81.25,39.14 R614.2 ; CN3.5 C485.1 88.51,35.15 v2(88.27,35.4)
  BOTTOM w0.118: v2(81.28,39.12) 84.55,39.12 v2(88.27,35.4)
SDHC_CD_B: length 163.2
  TOP w0.118: R637.1 R5851.2 v2(96.19,46.98) ; U22.A34 88.83,140.02 90.55,138.3 v2(90.55,137.46) ; v3(110.33,153.2) U22.N13
  L14_INT_6 w0.087: v2(96.19,46.98) 96.75,47.54 96.75,55.5 108.61,67.36 108.61,91.97 106.2,94.39 105.44,94.39 104.49,95.33 104.49,101.5 103.68,102.31 103.68,106.22 104.55,107.09 104.55,110.01 104.95,110.41 104.95,113 93.85,124.1 93.85,128.47 90.85,131.47 90.85,137.16 v2(90.55,137.46) 90.55,137.72 92.99,140.16 93.52,140.16 93.73,140.36 93.73,157.25 94.21,157.73 109.42,157.73 109.86,157.3 109.86,153.67 v3(110.33,153.2)
SDHC_CLK: length 122.3
  TOP w0.118: U45.5 82.09,42.97 v2(81.79,43.26) ; R301.2 v2(92.02,136.53)
  L14_INT_6 w0.087: v2(92.02,136.53) 92.02,131.19 94.65,128.56 94.65,124.22 105.54,113.33 105.54,109.96 105.18,109.6 105.18,100.46 106.68,98.96 106.68,95.02 109.25,92.46 109.25,66.24 97.89,54.89 97.89,46.63 93.19,41.94 83.12,41.94 v2(81.79,43.26)
SDHC_CMD: length 127.1
  TOP w0.118: v3(90.33,144.2) U22.D33 ; U45.16 85.25,42.97 85.47,43.18 v2(85.47,43.43)
  L5_INT_2 w0.087: v2(85.47,43.43) 85.47,43.54 86.06,44.12 90.6,44.12 95.5,49.02 95.5,68.76 104.37,77.62 104.37,84.33 103.45,85.24 103.45,90.05 96.62,96.88 96.62,117.09 87.3,126.42 87.3,137.46 88.11,138.28 88.11,143.36 88.77,144.02 88.77,144.4 89.1,144.73 89.8,144.73 v3(90.33,144.2)
  BOTTOM w0.118: v3(90.33,144.2) 90.33,144.61 89.92,145.02 89.92,147.26 89.48,147.7 R743.2
SDHC_DAT0: length 121.6
  TOP w0.118: v3(89.33,142.2) U22.B34 ; U45.3 83.62,43.92 v2(83.41,44.12)
  L5_INT_2 w0.087: v3(89.33,142.2) 89.33,141.65 88.44,140.77 88.44,125.6 96.84,117.21 96.84,96.97 103.73,90.07 103.73,85.42 104.64,84.52 104.64,77.41 96.04,68.81 96.04,48.79 90.07,42.82 84.81,42.82 83.52,44.12 v2(83.41,44.12)
SDHC_DAT1: length 125.7
  TOP w0.118: v3(89.33,144.2) 88.83,143.7 U22.C34 ; U45.4 83.22,43.63 82.96,43.89 v2(82.52,43.89)
  L5_INT_2 w0.087: v3(89.33,144.2) 89.79,143.74 89.79,139.14 88.67,138.02 88.67,125.76 97.05,117.37 97.05,97.13 104.04,90.14 104.04,85.52 104.85,84.71 104.85,77.09 96.42,68.66 96.42,48.36 90.63,42.57 84.02,42.57 82.7,43.89 v2(82.52,43.89)
SDHC_DAT2: length 117.4
  TOP w0.118: U45.1 84.42,43.65 v2(84.68,43.92) ; v3(87.33,141.2) U22.A35
  L5_INT_2 w0.087: v3(87.33,141.2) 87.02,140.89 87.02,137.92 86.84,137.74 86.84,126.54 96.41,116.98 96.41,96.76 103.2,89.97 103.2,85.12 104.09,84.23 104.09,77.85 95.12,68.88 95.12,49.33 90.98,45.19 86.23,45.19 84.96,43.92 v2(84.68,43.92)
SDHC_DAT3: length 120.1
  TOP w0.118: v3(87.33,142.2) U22.B35 ; U45.2 84.02,43.69 84.01,43.7 84.01,44.39 84.15,44.53 v2(84.15,44.6)
  L5_INT_2 w0.087: v3(87.33,142.2) 86.69,141.56 86.69,138.94 85.7,137.95 85.7,125.6 85.77,125.53 85.77,125.48 91.4,119.85 92.54,119.85 95.63,116.76 95.63,97.23 102.92,89.94 102.92,85.04 103.84,84.12 103.84,78.16 94.91,69.23 94.91,49.97 90.81,45.87 85.88,45.87 84.61,44.6 v2(84.15,44.6)
SDHC_WP: length 177.2
  TOP w0.102: U22.C33 90.23,143.29 90.23,141.26 90.22,141.25
  TOP w0.118: v2(78.02,37.84) R5852.2 R667.1 ; v2(92.08,137.59) 92.08,138.56 90.22,140.41 90.22,141.25 ; v3(109.33,154.2) U22.P13
  L14_INT_6 w0.087: v3(109.33,154.2) 109.2,154.2 108.84,154.56 108.84,156.41 108.53,156.72 94.23,156.72 93.95,156.44 93.95,140.72 94.31,140.36 94.31,139.83 v2(92.08,137.59) 91.08,136.59 91.08,131.65 94.26,128.47 94.26,124.1 105.23,113.13 105.23,110.26 104.88,109.91 104.88,100.1 105.73,99.25 105.73,95.26 108.94,92.05 108.94,66.85 97.31,55.22 97.31,46.99 92.56,42.24 83.52,42.24 81.97,43.79 80.21,43.79 78.02,41.6 v2(78.02,37.84)
SDP1_CLKF: length 1.8
  TOP w0.118: TP72.1 81.84,42.75 82.02,42.57 U45.6
SENSEGND_CA_S_N: length 1.4
  TOP w0.118: U22.R13 v3(110.33,155.2)
  BOTTOM w0.118: R716.1 v3(110.33,155.2)
SENSEGND_CB_S_N: length 1.4
  TOP w0.118: U22.AM17 v3(106.33,173.2)
  BOTTOM w0.118: R696.1 v3(106.33,173.2)
SENSEGND_CC_S_N: length 1.4
  TOP w0.118: v3(89.33,161.2) U22.AA33
  BOTTOM w0.118: R707.1 v3(89.33,161.2)
SENSEGND_PL_S_N: length 1.4
  TOP w0.118: v3(90.33,161.2) U22.AA32
  BOTTOM w0.118: R706.1 v3(90.33,161.2)
SENSEVDD_CA_S_P: length 1.4
  TOP w0.118: U22.R12 v3(111.33,155.2)
  BOTTOM w0.118: v3(111.33,155.2) R725.1
SENSEVDD_CB_S_P: length 1.4
  TOP w0.118: U22.AM16 v3(107.33,173.2)
  BOTTOM w0.118: R699.1 v3(107.33,173.2)
SENSEVDD_CC_S_P: length 1.4
  TOP w0.118: v3(89.33,160.2) U22.Y33
  BOTTOM w0.118: R710.1 v3(89.33,160.2)
SENSEVDD_PL_S_P: length 1.4
  TOP w0.118: v3(90.33,160.2) U22.Y32
  BOTTOM w0.118: R709.1 v3(90.33,160.2)
SER1_CTS_B: length 4.4
  TOP w0.118: U46.1 64.54,34.77 63.91,34.13 63.91,32.31 64.52,31.7 R1055.1
SER1_CTS_B_T: length 14.2
  TOP w0.118: LAN1.8_T 57.62,21.78 58.9,23.06 60.88,23.06 61.49,23.67 61.49,26.47 63.58,28.56 ESD3.1 63.51,29.41 C1226.1 63.5,30.36 R1055.2
SER1_GND: length 20.3
  TOP w0.508: C1227.2 66.59,30.28 ESD4.2 v2(66.59,28.45) ; v2(68.75,28.45) ESD2.2 68.75,30.28 C1225.2 ; v2(64.43,28.5) ESD3.2 64.43,30.28 C1226.2 ; C1224.2 70.91,30.28 ESD1.2 v2(70.91,28.45)
  BOTTOM w0.508: 68.2,27.71 68.2,23.5 65.07,20.37 63.04,20.37 62.44,20.97 LAN1.4_T
  vias: v2(72.16,30.05) v2(72.92,29.34) v2(73.61,30.05)
SER1_RTS_B: length 8.5
  TOP w0.118: R1052.1 70.99,31.72 69.97,32.74 66.11,32.74 65.66,33.19 65.66,33.98 66.04,34.36 U46.4
SER1_RTS_B_T: length 10.1
  TOP w0.118: LAN1.1_T 67.6,24.32 70.06,26.78 ESD1.1 69.99,29.41 C1224.1 69.98,30.36 R1052.2
SER1_RXD: length 5.7
  TOP w0.118: U46.2 65.04,34.43 64.69,34.08 64.69,32.3 65.12,31.88 66.47,31.88 66.67,31.67 R1054.1
SER1_RXD_T: length 13.7
  TOP w0.118: LAN1.6_T 60.05,22.73 61.14,22.73 61.85,23.44 61.85,25.76 63.8,27.71 65.15,27.71 65.74,28.3 ESD4.1 65.67,29.41 C1227.1 65.66,30.36 R1054.2
SER1_TXD: length 7.1
  TOP w0.118: U46.3 65.54,34.35 65.2,34 65.2,32.79 65.7,32.28 68.38,32.28 68.84,31.82 R1053.1
SER1_TXD_T: length 10.3
  TOP w0.118: LAN1.3_T 64.85,26.26 67.08,26.26 67.9,27.08 ESD2.1 67.83,29.41 C1225.1 R1053.2
SER2_CTS_B: length 4.2
  TOP w0.118: U95.1 55.91,34.83 55.55,34.47 55.55,32.23 55.88,31.9 R1059.1
SER2_CTS_B_T: length 32.7
  TOP w0.118: R1059.2 54.86,30.36 C1232.1 54.87,29.41 ESD8.1 54.95,23.6 54.58,23.24 54.58,20.07 55.22,19.43 55.22,13.84 56.24,12.83 64.14,12.83 65.56,14.25 65.56,17.64 LAN1.8_B
SER2_GND: length 21.6
  TOP w0.508: C1231.2 57.96,30.28 ESD7.2 v2(57.96,28.48) ; C1232.2 55.8,30.28 ESD8.2 v2(55.8,28.52) ; C1230.2 60.11,30.28 ESD6.2 v2(60.11,28.52) ; C1229.2 62.27,30.28 ESD5.2 v2(62.27,28.45)
  BOTTOM w0.508: 55.12,27.86 55.12,20.78 56.26,19.63 59.26,19.63 60.37,18.53 LAN1.4_B
  vias: v2(51.79,29.74) v2(52.83,28.96) v2(53.8,29.82)
SER2_RTS_B: length 8.6
  TOP w0.118: U95.4 57.41,34.52 57.02,34.14 57.02,33.25 57.48,32.79 61.34,32.79 62.26,31.88 62.26,31.34 R1056.1
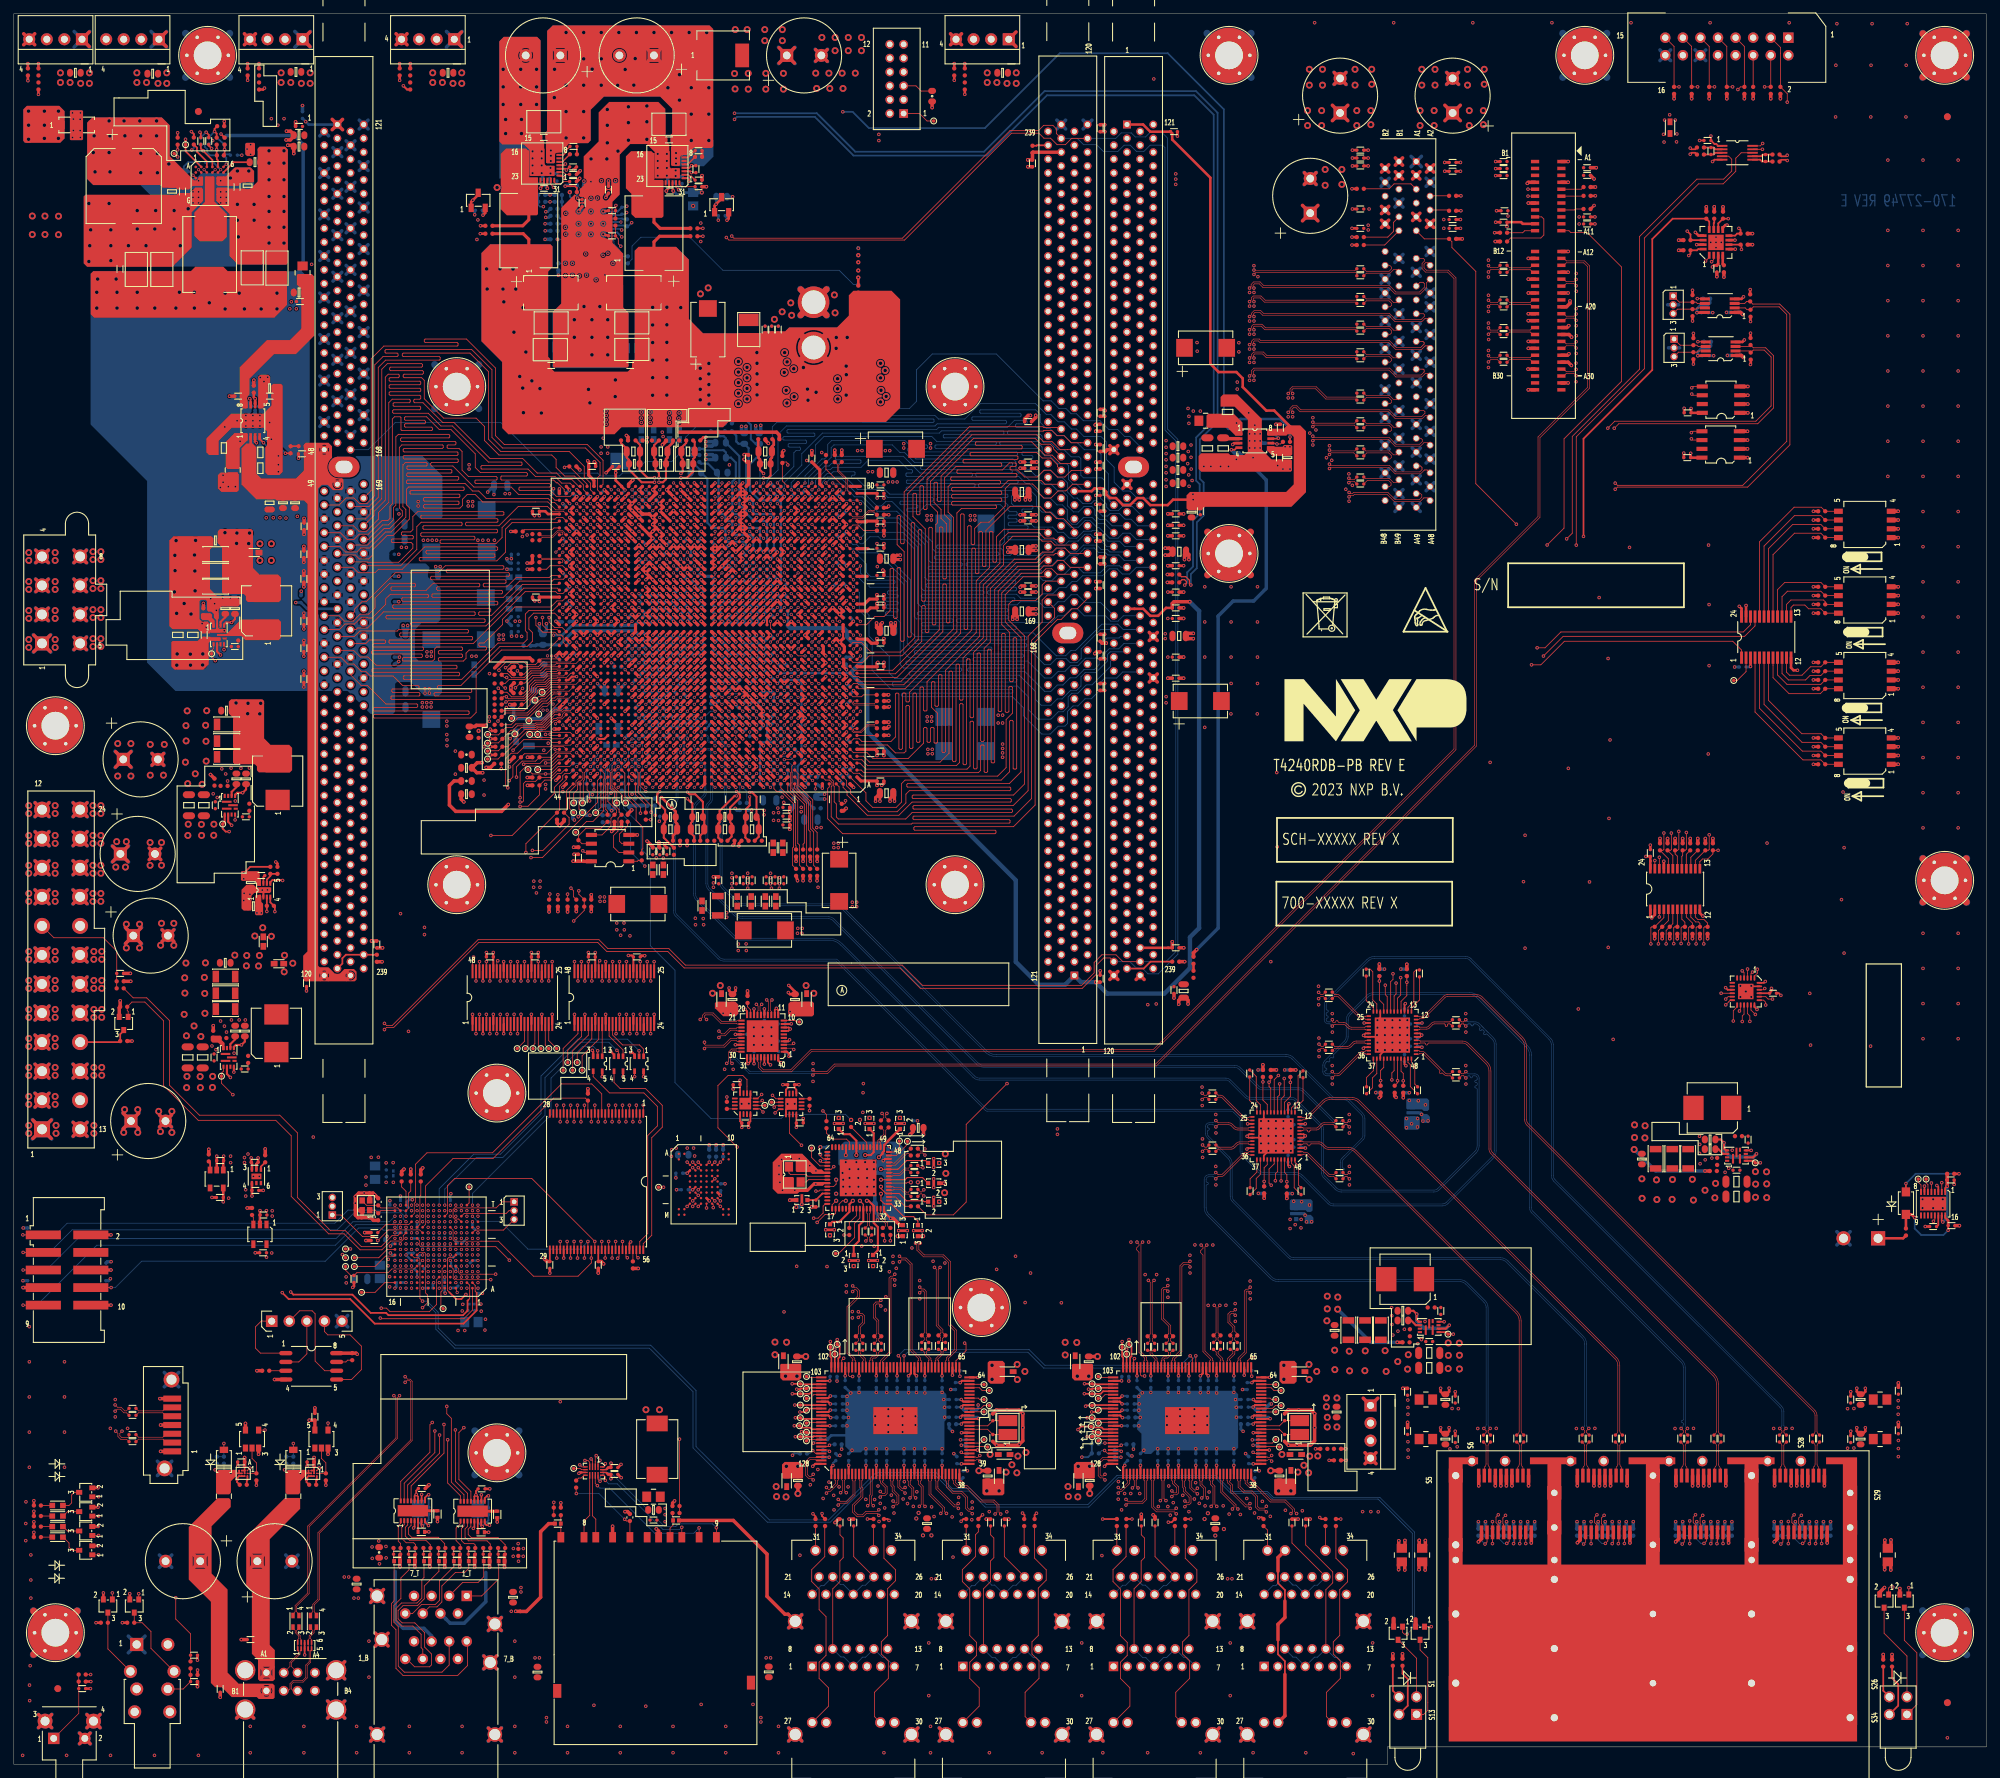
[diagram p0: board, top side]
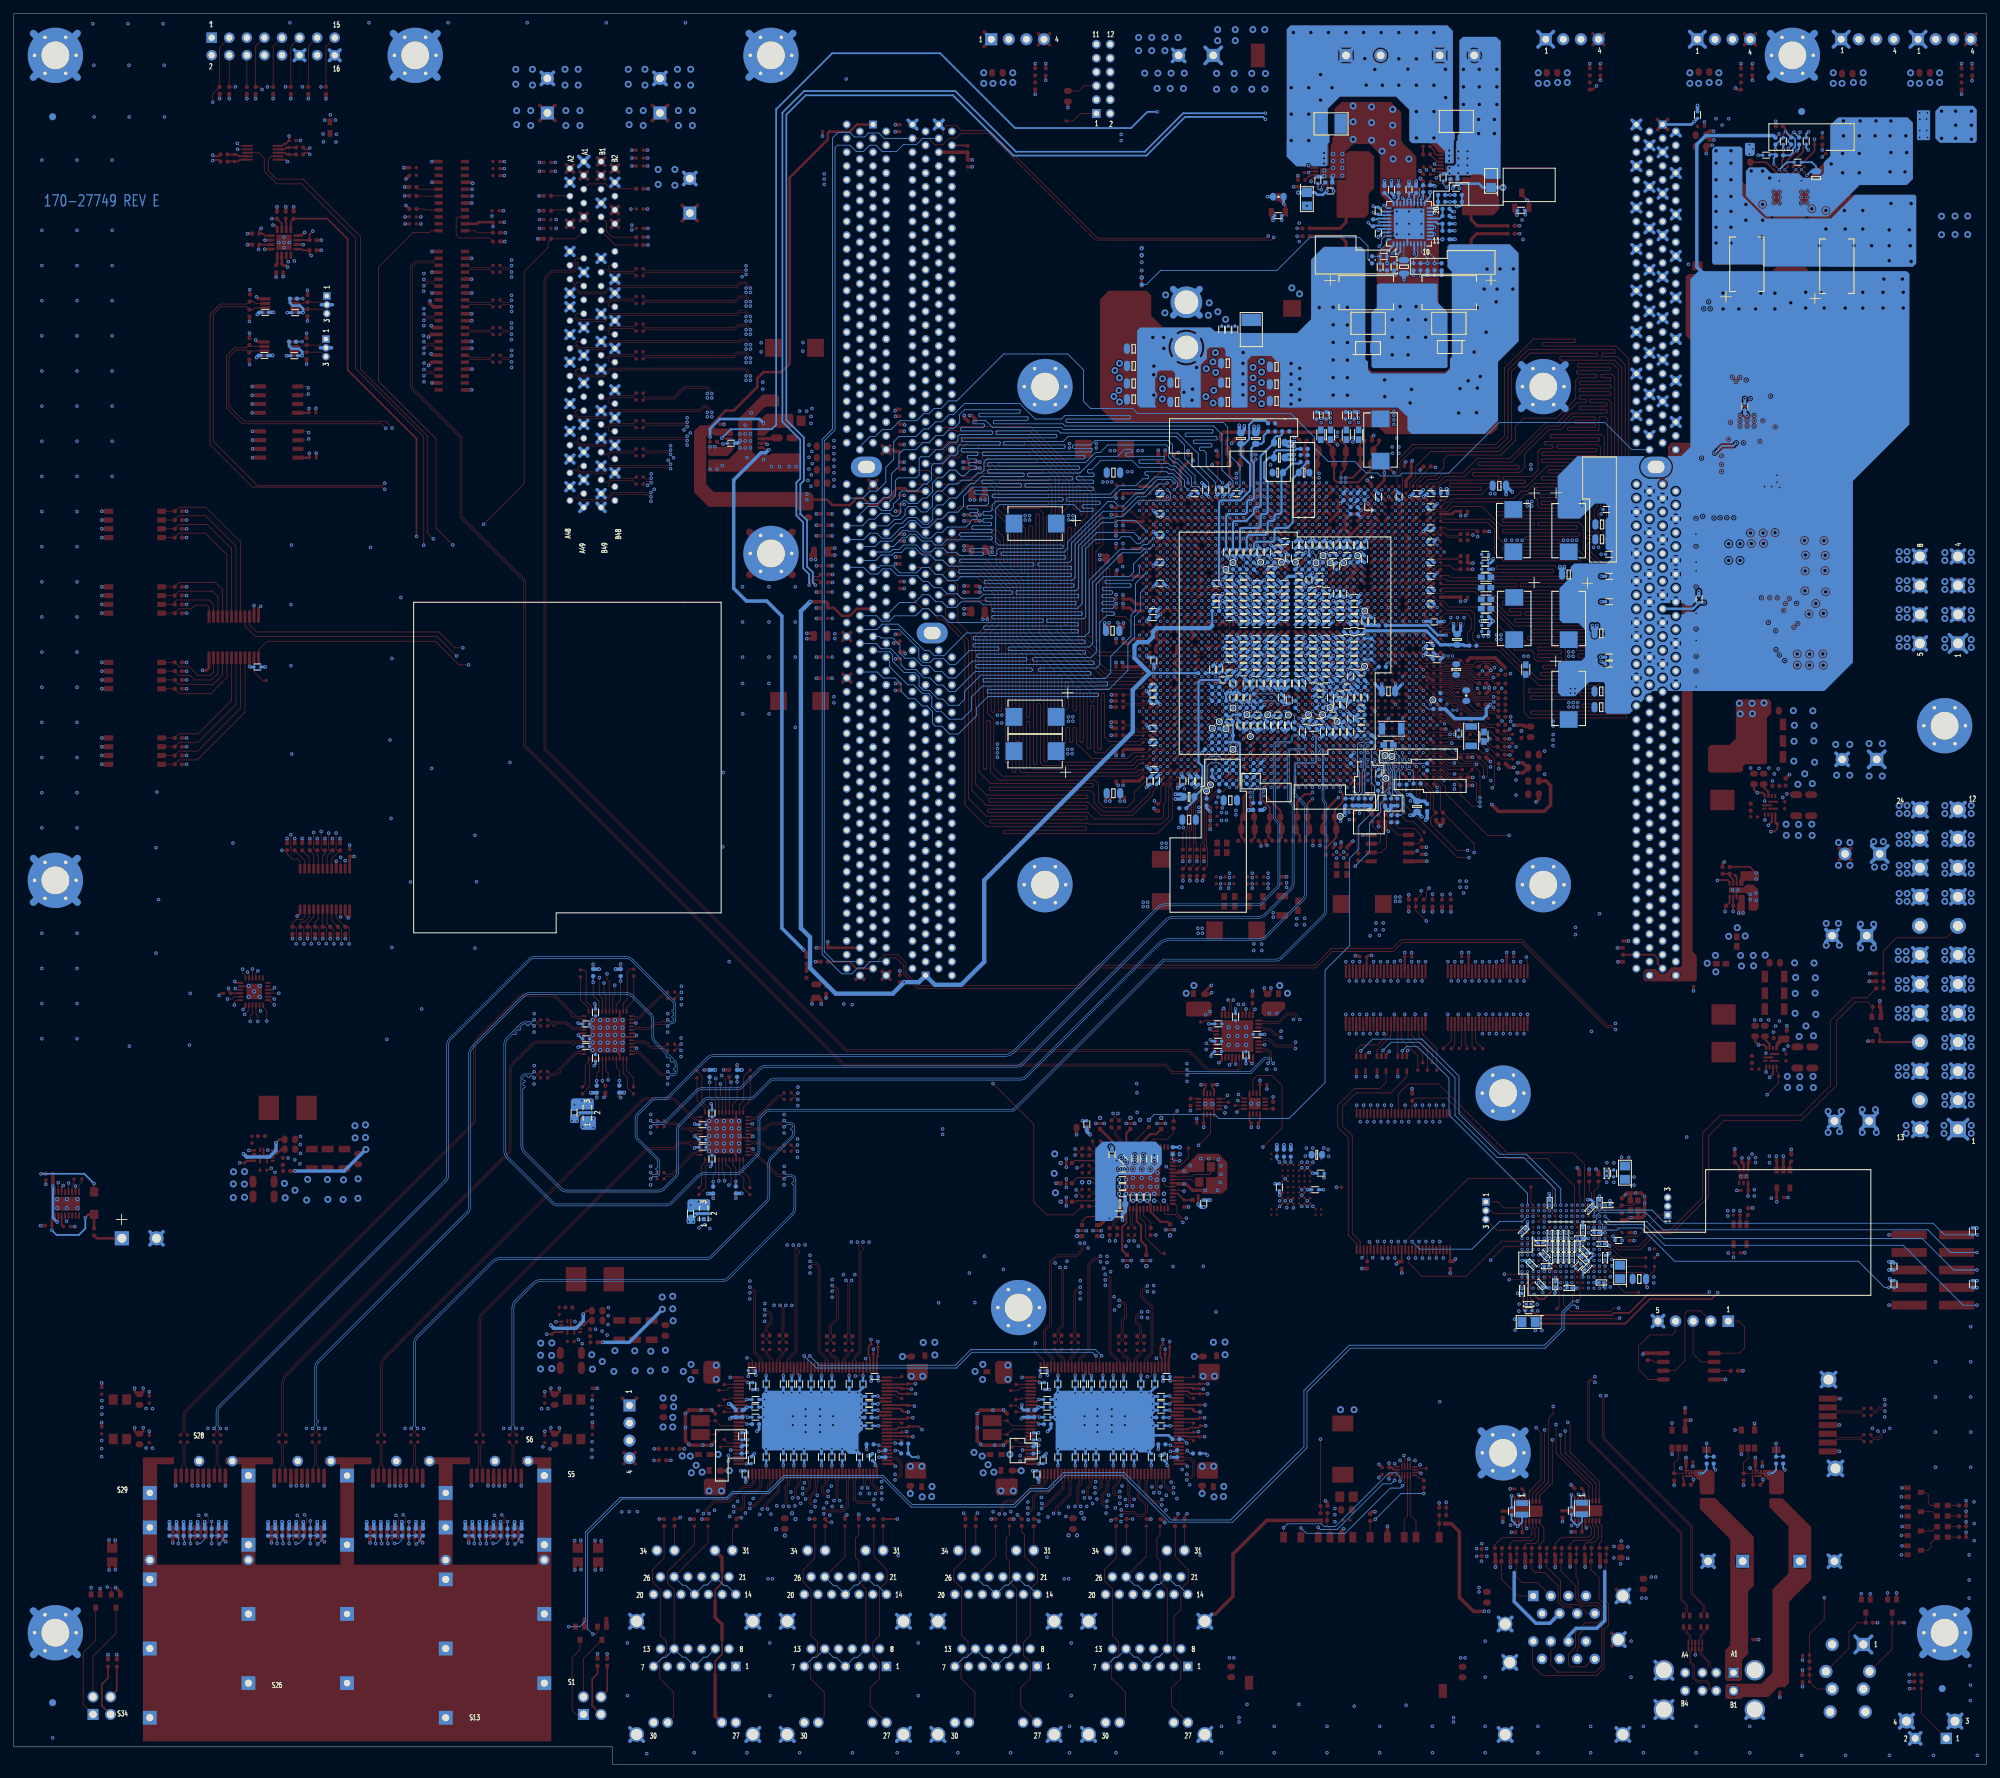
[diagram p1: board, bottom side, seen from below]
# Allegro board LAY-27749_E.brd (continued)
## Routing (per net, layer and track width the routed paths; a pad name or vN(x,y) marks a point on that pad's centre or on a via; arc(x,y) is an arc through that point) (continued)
SER2_RTS_B_T: length 28
  TOP w0.118: LAN1.1_B 56.78,15.21 57.91,14.07 60.07,14.07 60.35,14.35 60.35,15.93 59.36,16.92 59.36,19 57.94,20.42 56.11,20.42 55.52,21.01 55.52,22.2 56.24,22.91 58.32,22.91 59.31,23.9 59.31,25.76 61.42,27.87 ESD5.1 61.35,29.41 C1229.1 61.34,30.36 R1056.2
SER2_RXD: length 5.6
  TOP w0.118: U95.2 56.41,34.61 56.06,34.26 56.06,32.64 56.69,32 57.78,32 58.04,31.75 R1058.1
SER2_RXD_T: length 29.8
  TOP w0.118: LAN1.6_B 62.91,14.34 61.86,13.3 56.43,13.3 55.55,14.17 55.55,19.89 54.91,20.52 54.91,22.94 55.93,23.95 55.93,26.92 57.11,28.1 ESD7.1 57.11,30.28 C1231.1 57.02,30.36 57.02,31.24
SER2_TXD: length 7
  TOP w0.118: U95.3 56.91,34.58 56.57,34.24 56.57,32.97 57.18,32.36 59.54,32.36 60.17,31.72 60.17,31.27 R1057.1
SER2_TXD_T: length 21.6
  TOP w0.118: R1057.2 59.18,30.36 C1230.1 59.19,29.41 ESD6.1 59.27,26.98 58.95,26.67 58.95,24 58.24,23.29 56.01,23.29 55.22,22.5 55.22,20.78 56.03,19.96 57.66,19.96 58.85,18.77 58.85,16.84 59.1,16.6 LAN1.3_B
SI5341_A0CS: length 1.8
  TOP w0.118: v5(120.22,81.43) 119.73,81.43 119.25,80.95 U36.19
SI5341_A1SDO: length 1.4
  TOP w0.118: v5(118.82,81.43) 118.25,80.86 U36.17
SI5341_FDEC: length 8.2
  TOP w0.118: U36.25 122.25,78.94 121.49,78.18 121.49,76.12 119.18,73.81 TP209.1
SI5341_FINC: length 2.7
  TOP w0.118: U36.48 127.27,88.48 127.97,89.18 TP208.1
SI5341_I2CSEL: length 3.2
  TOP w0.118: U36.39 129,83.98 129.13,84.11 v5(129.62,84.11)
SI5341_INSEL0: length 1.4
  TOP w0.118: U36.3 116.97,87.48 116.54,87.92 v6(116.54,88.16)
SI5341_INSEL1: length 3
  TOP w0.118: U36.4 116.77,86.98 v2(116.54,87.22)
  BOTTOM w0.118: R5705.2 117.55,87.4 117.37,87.22 v2(116.54,87.22)
SI5341_LOL_B: length 3.8
  TOP w0.118: TP214.1 129.12,89.58 127.52,87.98 U36.47
SI5341_OE_B: length 2.1
  TOP w0.118: v5(118.82,84.48) 118.82,83.85 118.46,83.48 U36.11
SI5341_SYNC_B: length 4.1
  TOP w0.118: U36.5 116.49,86.48 115.27,87.71 TP210.1
SI5341_VDD: length 6.9
  TOP w0.305: v2(126.7,78.89) 125.75,79.84 U36.32 ; U36.46 125.89,87.48 v2(125.63,87.22) ; v5(120.22,88.04) 120.25,88.06 U36.60
  TOP w0.508: FL15.3 128.05,77.91 127.08,78.89 v2(126.7,78.89)
  BOTTOM w0.305: v2(125.63,87.22) 125.96,87.22 C3860.1
SI5341_VDDA: length 3.3
  TOP w0.254: U36.13 116.84,82.48 C3866.1 FL20.3
SLOT6_TCK: length 8.2
  TOP w0.118: R119.1 198.73,227.71 199.44,228.42 201.88,228.42 J3.A5
SLOT6_TDI: length 2.8
  TOP w0.118: R120.1 204.69,226.69 J3.A6
SLOT6_TMS: length 2.8
  TOP w0.118: J3.A8 207.28,224.65 R128.1
SLOT6_TRST_B: length 7.1
  TOP w0.118: R142.2 198.53,220.73 199.36,221.56 199.36,222.87 J3.B9
SP1_MODA: length 3.6
  TOP w0.118: v2(215.73,31.91) 215.79,31.91 216.08,32.19 J16.6A
  BOTTOM w0.118: R925.2 214.68,32.51 215.28,31.91 v2(215.73,31.91)
SP1_RS0: length 3.9
  TOP w0.118: J16.9A v2(218.48,31.89)
  BOTTOM w0.118: R926.2 R923.1 218.48,32.75 v2(218.48,31.89)
SP1_RS1: length 3.9
  TOP w0.118: J16.7A 216.88,32.04 v2(216.71,31.88)
  BOTTOM w0.118: v2(216.71,31.88) R924.1 R927.2
SP1_TXDIS: length 3.8
  TOP w0.118: J16.3A 213.68,31.89 v2(213.66,31.88)
  BOTTOM w0.118: R930.2 R928.2 v2(213.66,31.88)
SP2_MODA: length 3.6
  TOP w0.118: v2(229.98,31.91) 230.33,32.26 J16.6B
  BOTTOM w0.118: v2(229.98,31.91) 229.46,31.91 228.93,32.44 R934.2
SP2_RS0: length 3.9
  TOP w0.118: v2(232.73,31.89) J16.9B
  BOTTOM w0.118: R935.2 R932.1 232.73,32.75 v2(232.73,31.89)
SP2_RS1: length 3.9
  TOP w0.118: J16.7B 231.13,32.04 v2(230.96,31.88)
  BOTTOM w0.118: v2(230.96,31.88) R933.1 R936.2
SP2_TXDIS: length 3.8
  TOP w0.118: J16.3B 227.91,33.5 v2(227.91,31.88)
  BOTTOM w0.118: R939.2 R937.2 v2(227.91,31.88)
SP3_MODA: length 3.6
  TOP w0.118: J16.6C 244.58,32.26 v2(244.23,31.91)
  BOTTOM w0.118: R943.2 243.18,32.51 243.78,31.91 v2(244.23,31.91)
SP3_RS0: length 3.9
  TOP w0.118: J16.9C v2(246.98,31.89)
  BOTTOM w0.118: v2(246.98,31.89) 246.98,32.75 R941.1 R944.2
SP3_RS1: length 3.9
  TOP w0.118: v2(245.21,31.88) 245.38,32.04 J16.7C
  BOTTOM w0.118: v2(245.21,31.88) R942.1 R945.2
SP3_TXDIS: length 3.8
  TOP w0.118: J16.3C 242.18,31.89 v2(242.16,31.88)
  BOTTOM w0.118: R948.2 R946.2 v2(242.16,31.88)
SP4_MODA: length 3.6
  TOP w0.118: J16.6D 258.83,32.19 258.54,31.91 v2(258.48,31.91)
  BOTTOM w0.118: R952.2 257.43,32.51 258.03,31.91 v2(258.48,31.91)
SP4_RS0: length 3.9
  TOP w0.118: J16.9D v2(261.23,31.89)
  BOTTOM w0.118: R954.2 R951.1 261.23,32.75 v2(261.23,31.89)
SP4_RS1: length 3.9
  TOP w0.118: J16.7D 259.63,32.04 v2(259.46,31.88)
  BOTTOM w0.118: v2(259.46,31.88) R950.1 R953.2
SP4_TXDIS: length 3.8
  TOP w0.118: J16.3D 256.41,33.5 v2(256.41,31.88)
  BOTTOM w0.118: R957.2 R955.1 v2(256.41,31.88)
SPI_CE_B: length 1.9
  TOP w0.118: R318.1 90.22,130.63 90.09,130.51 U26.1
SPI_CLK: length 7.8
  TOP w0.118: R296.1 84.84,135.28 82.68,135.28 81.58,134.19 R310.1 82.09,133.05 U26.6
SPI_CS0_B: length 13.4
  TOP w0.118: U22.C35 88.29,143.23 88.29,139.93 89.92,138.3 89.92,136.4 90.88,135.43 90.88,132.31 90.73,132.16 R318.2
SPI_CS1_B: length 3.4
  TOP w0.118: U22.A36 86.83,141.13 87.93,140.03 87.93,139.4 TP19.1
SPI_CS2_B: length 2.7
  TOP w0.118: v3(87.33,144.2) 86.83,143.7 U22.C36
  BOTTOM w0.118: v3(87.33,144.2) 87.33,143.82 86.74,143.23 TP103.1
SPI_CS3_B: length 6.2
  TOP w0.102: U22.D36 86.44,144.3 86.44,141.43 86.56,141.3 86.56,141.05
  TOP w0.118: 86.56,141.05 87.12,140.49 TP18.1
SPI_MISO: length 15.2
  TOP w0.102: 86.23,141.35 86.23,143.29 U22.C37
  TOP w0.118: U26.2 87.43,131.78 86.66,132.54 86.66,134.24 87.3,134.87 87.3,136.73 R298.2 87.45,137.6 87.45,137.98 86.49,138.94 86.49,139.55 86.79,139.85 86.79,140.48 86.23,141.04 86.23,141.35
SPI_MOSI: length 10.3
  TOP w0.118: U22.A37 85.83,139.16 87.07,137.92 87.07,137.52 R297.2 86.28,136.73 86.28,135.61 84.99,134.32 U26.5
SPI_WP_B: length 4.8
  TOP w0.118: U26.3 87.87,133.05 87.53,133.38 87.53,134.47 88.7,135.64 R299.2
SW1_1: length 23
  TOP w0.118: SW1.8 R5772.2 261.11,145.16 258.52,145.16 251.6,152.08 U610.4
SW1_2: length 21.5
  TOP w0.118: SW1.7 R5773.2 261.11,146.43 258.44,146.43 252.25,152.62 U610.5
SW1_3: length 20
  TOP w0.118: U610.6 252.9,153.19 258.39,147.7 261.11,147.7 R5774.2 SW1.6
SW1_4: length 18.5
  TOP w0.118: SW1.5 R5775.2 261.14,148.95 258.37,148.95 253.55,153.76 U610.7
SW1_5: length 13.6
  TOP w0.118: U610.8 254.2,158.86 254.2,158.86 254.2,157.05 256.51,154.74 261.04,154.74 R5776.2 SW2.8
SW1_6: length 12.1
  TOP w0.118: U610.9 254.85,157.44 256.21,156.08 261.11,156.08 R5777.2 SW2.7
SW1_7: length 11.3
  TOP w0.118: U610.10 255.5,157.65 256.44,156.72 258.9,156.72 259.54,157.35 261.11,157.35 R5778.2 SW2.6
SW1_8: length 10.5
  TOP w0.118: SW2.5 R5779.2 261.11,158.62 259.61,158.62 258.39,157.4 256.59,157.4 256.15,157.84 U610.11
SW2_1: length 8.8
  TOP w0.118: U610.13 256.8,167.19 257.15,167.54 258.8,167.54 259.33,167 261.11,167 R5780.2 SW3.8
SW2_2: length 10
  TOP w0.118: SW3.7 R5781.2 261.75,168.02 261.49,168.28 256.79,168.28 256.15,167.63 U610.14
SW2_3: length 11.6
  TOP w0.118: U610.15 255.5,168.76 256.29,169.54 261.11,169.54 R5782.2 SW3.6
SW2_4: length 13.4
  TOP w0.118: U610.16 254.85,169.76 255.88,170.79 261.14,170.79 R5783.2 SW3.5
SW2_5: length 19.9
  TOP w0.118: U610.17 254.2,174.83 257.3,177.93 261.11,177.93 R5784.2 SW4.8
SW2_6: length 21.6
  TOP w0.118: SW4.7 R5785.2 261.11,179.2 257.05,179.2 253.55,175.7 U610.18
SW2_7: length 23
  TOP w0.118: U610.19 252.9,176.07 257.3,180.47 261.11,180.47 R5786.2 SW4.6
SW2_8: length 24.5
  TOP w0.118: SW4.5 R5787.2 261.16,181.69 257.25,181.69 252.25,176.69 U610.20
SW_PWR_B: length 82.3
  TOP w0.118: R670.1 25.53,15.74 C520.1 25.54,18.84 23.39,20.98 v2(23.39,24.05)
  L12_INT_5 w0.087: v2(23.39,24.05) 31.9,24.05 64.67,56.82 64.67,63.32 64.26,63.73 64.26,67.34 64.62,67.69 64.62,68.28 64.26,68.63 64.26,72.36 64.7,72.8 v1(65.47,72.8)
SW_PWR_OUT: length 5.6
  TOP w0.118: SW5.4 24.46,10.86 C523.1 25.54,12.38 25.53,12.39 R672.2 R670.2
SW_RST_B: length 101.9
  TOP w0.118: R669.2 v2(11.1,12.95)
  L12_INT_5 w0.087: v1(65.47,76.8) 65.05,76.38 65.05,75.67 64.26,74.88 64.26,74.17 64.08,73.99 62.87,73.99 62.66,73.78 62.66,68.68 62.92,68.42 62.92,57.12 40.46,34.67 18.29,34.67 12.17,28.55 12.17,23.01 13.23,21.95 13.23,15.09 v2(11.1,12.95)
SWS_CLK: length 233.6
  TOP w0.118: U610.22 250.95,164.69 249.91,163.65 223.55,163.65 221.26,161.37 v2(220.12,161.37)
  L3_INT_1 w0.087: v1(65.47,73.6) 66.66,72.42 69.9,72.42 81.31,83.83 87.25,83.83 94.46,91.03 114.63,91.03 119.16,95.57 161.73,95.57 167.47,101.3 174.12,101.3 220.12,147.29 v2(220.12,161.37)
SWS_CS_B: length 234.2
  TOP w0.118: U610.21 251.6,164.53 250.09,163.02 223.88,163.02 v2(221.03,160.17)
  L3_INT_1 w0.087: v1(64.67,72) 65.04,71.63 71.27,71.63 82.93,83.29 87.48,83.29 94.84,90.65 114.76,90.65 119.38,95.28 162.2,95.28 167.69,100.76 174.04,100.76 220.73,147.45 220.73,159.87 v2(221.03,160.17)
SWS_IRQ_B: length 4.3
  TOP w0.118: TP249.1 249.02,156.64 250.3,157.92 U610.2
SWS_MISO: length 229.1
  TOP w0.118: U610.1 249.65,161.04 248.39,162.31 224.05,162.31 220.65,158.9 v2(219.3,158.9)
  L3_INT_1 w0.087: v2(219.3,158.9) 219.3,146.94 174.19,101.82 167.43,101.82 161.42,95.81 118.9,95.81 114.43,91.34 94.03,91.34 87.04,84.35 81.09,84.35 69.98,73.23 66.64,73.23 v1(66.27,73.6)
SYSCLK: length 76.4
  TOP w0.118: R5895.2 v2(103.03,96.44)
  L14_INT_6 w0.087: v2(103.03,96.44) 98.6,100.87 98.6,118.47 93.45,123.62 93.45,128.53 90.55,131.42 90.55,136.58 90.11,137.02 90.11,138.06 92.89,140.84 92.89,156.29 92.38,156.79 87.5,156.79 86.33,157.97 v3(86.33,159.2)
  BOTTOM w0.118: R711.1 86.74,159.07 86.61,159.2 v3(86.33,159.2)
TEMP_ANODE1_ADT: length 2.7
  TOP w0.254: R30.1 245.23,233.68 C9.1 245.63,233.67 245.88,233.42 U2.2
TEMP_ANODE2_ADT: length 3
  TOP w0.254: 254.13,232.66 253.12,232.66 C12.1 252.72,232.66 252.48,232.42 U2.7
TEMP_CATHODE1_ADT: length 2.7
  TOP w0.254: R35.1 245.23,232.66 C9.2 245.63,232.67 245.87,232.92 U2.3
TEMP_CATHODE2_ADT: length 3
  TOP w0.254: 254.13,231.65 254.12,231.66 C12.2 252.59,231.66 252.33,231.92 U2.6
TEMP_DIODE1_N: length 223.5
  TOP w0.254: v3(88.33,160.2) U22.Y34 ; v2(242.24,232.7) 242.46,232.92 242.95,232.92 R35.2
  L5_INT_2 w0.102: 91.1,185.71 91.1,185.35 90.93,185.18 90.93,160.87 90.65,160.59 88.73,160.59 v3(88.33,160.2)
  L5_INT_2 w0.254: v2(124.99,234.68) 124.8,234.87 121.95,234.87 101.55,214.48 94.08,214.48 89.71,210.11 89.71,191.8 91.1,190.41 91.1,185.71
  L12_INT_5 w0.254: v2(124.99,234.68) 125.21,234.9 135.21,234.9 141.26,240.94 226.46,240.94 234.51,232.89 242.05,232.89 v2(242.24,232.7)
TEMP_DIODE1_P: length 223.9
  TOP w0.254: R30.2 242.95,233.43 242.4,233.43 v2(242.24,233.59) ; v3(88.33,161.2) U22.AA34
  L5_INT_2 w0.102: 90.59,185.67 90.59,185.37 90.73,185.24 90.73,160.96 90.57,160.8 88.73,160.8 v3(88.33,161.2)
  L5_INT_2 w0.254: 90.59,185.67 90.59,190.2 89.2,191.59 89.2,210.32 93.87,214.99 101.34,214.99 121.74,235.38 124.8,235.38 v2(124.99,235.57)
  L12_INT_5 w0.254: v2(242.24,233.59) 242.05,233.4 234.72,233.4 226.67,241.45 141.05,241.45 135,235.41 125.16,235.41 v2(124.99,235.57)
TEMP_DIODE2_N: length 217.1
  TOP w0.254: U22.AL17 v3(106.33,172.2) ; R51.2 255.4,231.9 256.08,231.9 256.18,231.79 v2(256.25,231.79)
  L12_INT_5 w0.102: 104.14,187.2 104.14,187.16 104.17,187.13 104.19,187.13 104.29,187.03 104.29,186.67 104.74,186.22 104.74,177.94 105.08,177.6 106.52,177.6 106.73,177.39 106.73,172.6 v3(106.33,172.2)
  L12_INT_5 w0.254: 104.14,187.2 104.14,194.77 105.28,195.91 107.01,195.91 108.81,197.71 108.81,204.09 112.95,208.23 120.49,208.23 123.3,211.04 123.3,214 131.79,222.49 131.79,228.19 142.84,239.24 176.71,239.24 180.54,235.41 228.55,235.41 235.45,228.5 254.82,228.5 255.32,229 255.82,229 256.32,228.5 257.23,228.5 257.59,228.86 257.59,229.42 257.08,229.93 257.08,230.43 257.59,230.94 257.59,231.64 257.28,231.95 256.41,231.95 v2(256.25,231.79)
TEMP_DIODE2_P: length 217
  TOP w0.254: R36.2 255.4,232.41 256.11,232.41 v2(256.25,232.56) ; U22.AL16 v3(107.33,172.2)
  L12_INT_5 w0.102: v3(107.33,172.2) 106.93,172.59 106.93,177.47 106.6,177.8 105.17,177.8 104.94,178.03 104.94,186.31 104.5,186.75 104.5,187.05 104.65,187.2
  L12_INT_5 w0.254: v2(256.25,232.56) 256.35,232.46 257.49,232.46 258.1,231.85 258.1,228.65 257.44,228 235.24,228 228.34,234.9 180.33,234.9 176.5,238.73 143.05,238.73 132.3,227.98 132.3,222.28 123.81,213.79 123.81,210.83 120.7,207.72 113.16,207.72 109.32,203.88 109.32,197.5 107.22,195.4 105.49,195.4 104.65,194.56 104.65,187.2
TH_TPA: length 1.4
  TOP w0.118: v3(90.33,159.2) U22.W32
  BOTTOM w0.118: TP84.1 89.82,158.69 v3(90.33,159.2)
THERM_FAULT_B: length 316.2
  TOP w0.118: U2.4 247.8,232.42 248.23,231.99 248.23,230.28 247.07,229.11 243.21,229.11 234.9,220.8 234.9,201.63 225.2,191.92 225.2,177.93 v2(224.38,177.11)
  L3_INT_1 w0.087: v1(57.47,77.6) 57.07,77.21 57.07,71.78 56.87,71.58 55.71,71.58 55.44,71.31 55.44,68.13 58.83,64.74 71.91,64.74 75.21,68.05 101.17,68.05 108.41,75.29 121.21,75.29 122.45,76.53 123.55,76.53 128.03,81.02 128.03,87.38 131.05,90.4 159.74,90.4 168.88,99.54 174.14,99.54 224.38,149.78 v2(224.38,177.11)
THERM_WARN_B: length 325.9
  TOP w0.118: U2.8 249.61,232.92 248.82,232.13 248.82,230.25 246.99,228.42 243.43,228.42 235.61,220.6 235.61,201.7 225.77,191.87 v2(225.77,176.2)
  L3_INT_1 w0.087: v2(225.77,176.2) 225.77,148.94 189.61,112.78 189.61,111.84 188.87,111.1 187.38,111.1 174.75,98.47 169.31,98.47 160.27,89.43 131.5,89.43 129.03,86.97 129.03,78.33 129.57,77.79 129.57,76.19 127.29,73.91 110.64,73.91 100.03,63.3 58.45,63.3 52.88,68.86 52.88,75.06 53.26,75.44 53.26,76.5 54.36,77.6 v1(55.07,77.6)
TSEC_1588_ALARM1_S: length 1.4
  TOP w0.118: U22.K13 v3(110.33,150.2)
  BOTTOM w0.118: TP99.1 v3(110.33,150.2)
TSEC_1588_ALARM2_S: length 1.4
  TOP w0.118: U22.J12 v3(111.33,149.2)
  BOTTOM w0.118: TP98.1 v3(111.33,149.2)
TSEC_1588_CLK_IN: length 1.4
  TOP w0.118: U22.A14 v3(109.33,141.2)
  BOTTOM w0.118: R757.2 v3(109.33,141.2)
TSEC_1588_CLKOUT_S: length 1.4
  TOP w0.118: U22.F14 v3(109.33,146.2)
  BOTTOM w0.118: v3(109.33,146.2) TP100.1
TSEC_1588_PULSE1_S: length 1.4
  TOP w0.118: U22.M14 v3(109.33,152.2)
  BOTTOM w0.118: TP90.1 v3(109.33,152.2)
TSEC_1588_PULSE2_S: length 1.4
  TOP w0.118: U22.L13 v3(110.33,151.2)
  BOTTOM w0.118: v3(110.33,151.2) 110.81,150.72 TP96.1
TSEC_1588_TRIG_IN1: length 1.4
  TOP w0.118: U22.N15 v3(108.33,153.2)
  BOTTOM w0.118: R735.2 107.85,152.71 108.2,153.06 v3(108.33,153.2)
TSEC_1588_TRIG_IN2: length 1.4
  TOP w0.118: U22.N14 v3(109.33,153.2)
  BOTTOM w0.118: R734.2 v3(109.33,153.2)
TX1_L0_N: length 79
  TOP w0.091: U65.35 178.56,88.56 arc(178.52,88.55) 178.49,88.53 178.44,88.47 arc(178.41,88.45) 178.37,88.44 178.05,88.44 arc(177.82,88.4) 177.62,88.27 174.67,85.31 arc(174.55,85.23) 174.41,85.21 174.04,85.21 arc(174.01,85.21) 173.98,85.23 v2(173.69,85.52) ; C1211.1 212.71,47.91 arc(212.74,47.95) 212.75,48.01 212.75,48.16 arc(212.74,48.19) 212.72,48.22 v2(212.42,48.53)
  BOTTOM w0.091: v2(212.42,48.53) 212.64,48.74 arc(212.72,48.87) 212.75,49.02 212.75,65.96 arc(212.66,66.41) 212.41,66.79 209.79,69.41 arc(209.41,69.66) 208.97,69.75 182.72,69.75 arc(182.08,69.88) 181.54,70.24 172.49,79.28 arc(172.13,79.82) 172.01,80.45 172.01,84.52 arc(172.2,85) 172.68,85.19 173.24,85.19 arc(173.34,85.21) 173.43,85.27 v2(173.69,85.52)
TX1_L0_N_DC: length 5.1
  TOP w0.091: C1211.2 212.63,46.31 arc(212.71,46.19) 212.74,46.05 212.74,43.38 arc(212.69,43.17) 212.58,42.99 212.57,42.99 arc(212.5,42.88) 212.48,42.75 arc(212.48,42.75) 212.48,42.75 J16.19A
TX1_L0_P: length 78.9
  TOP w0.091: v2(213.34,48.53) 213.06,48.25 arc(213.04,48.22) 213.03,48.18 213.03,47.96 arc(213.04,47.92) 213.06,47.89 C1210.1 ; v2(173.69,84.61) 173.98,84.9 arc(174.01,84.92) 174.04,84.93 174.41,84.93 arc(174.66,84.97) 174.87,85.11 177.82,88.07 arc(177.93,88.14) 178.05,88.17 178.37,88.17 arc(178.41,88.16) 178.44,88.14 178.49,88.08 arc(178.52,88.06) 178.56,88.05 U65.36
  BOTTOM w0.091: v2(213.34,48.53) 213.16,48.7 arc(213.06,48.85) 213.03,49.02 213.03,65.96 arc(212.92,66.52) 212.61,66.99 209.98,69.61 arc(209.52,69.92) 208.97,70.03 182.72,70.03 arc(182.19,70.13) 181.74,70.44 172.69,79.48 arc(172.39,79.93) 172.29,80.45 172.29,83.62 arc(172.34,83.74) 172.46,83.79 arc(172.61,83.94) 172.46,84.1 arc(172.34,84.15) 172.29,84.27 172.29,84.52 arc(172.4,84.8) 172.68,84.91 173.26,84.91 arc(173.37,84.89) 173.46,84.83 v2(173.69,84.61)
TX1_L0_P_DC: length 5.1
  TOP w0.091: J16.18A 213.28,42.75 arc(213.28,42.75) 213.28,42.75 arc(213.25,42.88) 213.17,42.99 arc(213.06,43.17) 213.02,43.38 213.02,46.05 arc(213.04,46.18) 213.12,46.3 C1210.2
TX2_L0_N: length 93.1
  TOP w0.091: v2(226.67,48.53) 226.97,48.22 arc(226.99,48.19) 227,48.16 227,48.01 arc(226.99,47.95) 226.96,47.91 C1215.1 ; v2(173.69,93.03) 173.99,92.74 arc(174.01,92.72) 174.05,92.71 175.55,92.71 arc(175.84,92.65) 176.1,92.48 176.46,92.12 arc(176.65,91.99) 176.89,91.94 178.37,91.94 arc(178.41,91.95) 178.44,91.97 178.49,92.03 arc(178.52,92.05) 178.56,92.05 U65.28
  BOTTOM w0.091: v2(173.69,93.03) 173.52,92.85 arc(173.36,92.75) 173.18,92.71 172.75,92.71 arc(172.35,92.54) 172.19,92.15 172.19,91.18 arc(172.25,90.84) 172.45,90.56 175.45,87.56 arc(175.68,87.2) 175.77,86.78 175.77,82.09 arc(175.85,81.66) 176.1,81.29 184.15,73.24 arc(184.5,73.01) 184.91,72.92 214.81,72.92 arc(215.29,72.83) 215.69,72.56 226.61,61.64 arc(226.89,61.22) 226.99,60.73 226.99,48.96 arc(226.97,48.85) 226.91,48.77 v2(226.67,48.53)
TX2_L0_N_DC: length 5.1
  TOP w0.091: C1215.2 226.88,46.31 arc(226.96,46.19) 226.99,46.05 226.99,43.38 arc(226.94,43.17) 226.83,42.99 226.82,42.99 arc(226.75,42.88) 226.72,42.75 arc(226.73,42.75) 226.73,42.75 J16.19B
TX2_L0_P: length 93
  TOP w0.091: v2(173.69,92.11) 173.99,92.4 arc(174.01,92.42) 174.05,92.43 175.55,92.43 arc(175.74,92.39) 175.9,92.28 176.26,91.92 arc(176.55,91.73) 176.89,91.67 178.37,91.67 arc(178.41,91.66) 178.44,91.64 178.49,91.58 arc(178.52,91.56) 178.56,91.56 U65.29 ; C1214.1 227.31,47.89 arc(227.29,47.92) 227.28,47.96 227.28,48.18 arc(227.29,48.22) 227.31,48.25 v2(227.59,48.53)
  BOTTOM w0.091: v2(227.59,48.53) 227.36,48.76 arc(227.29,48.86) 227.27,48.97 227.27,60.73 arc(227.15,61.33) 226.81,61.84 215.89,72.76 arc(215.39,73.09) 214.81,73.2 184.91,73.2 arc(184.61,73.26) 184.35,73.44 176.3,81.49 arc(176.11,81.76) 176.05,82.09 176.05,86.78 arc(175.94,87.31) 175.64,87.75 172.64,90.75 arc(172.51,90.95) 172.47,91.18 172.47,91.49 arc(172.51,91.6) 172.62,91.64 arc(172.77,91.8) 172.62,91.95 arc(172.51,91.99) 172.47,92.1 172.47,92.15 arc(172.55,92.35) 172.75,92.43 173.18,92.43 arc(173.36,92.39) 173.52,92.29 v2(173.69,92.11)
TX2_L0_P_DC: length 5.1
  TOP w0.091: C1214.2 227.37,46.3 arc(227.29,46.18) 227.26,46.05 227.26,43.38 arc(227.31,43.17) 227.42,42.99 arc(227.5,42.88) 227.52,42.75 arc(227.53,42.75) 227.53,42.75 J16.18B
TX3_L0_N: length 114.6
  TOP w0.091: U622.35 195.39,103.13 arc(195.35,103.12) 195.32,103.1 195.26,103.05 arc(195.24,103.03) 195.2,103.02 194.88,103.02 arc(194.65,102.97) 194.45,102.84 191.5,99.89 arc(191.38,99.81) 191.24,99.78 190.87,99.78 arc(190.83,99.79) 190.81,99.81 v2(190.51,100.1) ; v2(240.92,48.53) 241.22,48.22 arc(241.24,48.19) 241.25,48.16 241.25,48.01 arc(241.24,47.95) 241.21,47.91 C1219.1
  BOTTOM w0.091: v2(190.51,100.1) 190.24,99.83 arc(190.18,99.79) 190.11,99.78 189.75,99.78 arc(189.53,99.87) 189.43,100.09 189.43,100.15 arc(189.48,100.26) 189.59,100.3 arc(189.74,100.46) 189.59,100.61 arc(189.48,100.65) 189.43,100.76 189.43,101 arc(189.48,101.26) 189.63,101.48 189.69,101.54 arc(189.8,101.59) 189.91,101.54 arc(190.13,101.54) 190.13,101.76 arc(190.08,101.87) 190.13,101.97 190.27,102.11 arc(190.37,102.16) 190.48,102.11 arc(190.7,102.11) 190.7,102.33 arc(190.65,102.44) 190.7,102.55 192.44,104.29 arc(192.71,104.7) 192.81,105.19 192.81,107.57 arc(192.9,107.99) 193.13,108.35 195.7,110.91 arc(196.07,111.16) 196.52,111.25 210.39,111.25 arc(210.89,111.15) 211.31,110.87 218.56,103.62 arc(218.9,103.11) 219.02,102.5 219.02,80.43 arc(219.1,80.03) 219.33,79.69 240.94,58.08 arc(241.16,57.75) 241.24,57.36 241.24,49.83 arc(241.19,49.73) 241.08,49.68 arc(240.93,49.53) 241.08,49.38 arc(241.19,49.33) 241.24,49.23 241.24,49.07 arc(241.2,48.86) 241.08,48.69 v2(240.92,48.53)
TX3_L0_N_DC: length 5.1
  TOP w0.091: C1219.2 241.13,46.31 arc(241.21,46.19) 241.23,46.05 241.23,43.38 arc(241.19,43.17) 241.07,42.99 241.07,42.99 arc(241,42.88) 240.97,42.75 arc(240.98,42.75) 240.98,42.75 J16.19C
TX3_L0_P: length 114.5
  TOP w0.091: U622.36 195.39,102.63 arc(195.35,102.64) 195.32,102.66 195.27,102.72 arc(195.24,102.73) 195.2,102.74 194.88,102.74 arc(194.76,102.72) 194.65,102.65 191.69,99.69 arc(191.49,99.55) 191.24,99.5 190.87,99.5 arc(190.83,99.5) 190.81,99.48 v2(190.51,99.18) ; v2(241.83,48.53) 241.56,48.25 arc(241.54,48.22) 241.53,48.18 241.53,47.96 arc(241.54,47.92) 241.56,47.89 C1218.1
  BOTTOM w0.091: v2(241.83,48.53) 241.68,48.69 arc(241.56,48.86) 241.52,49.07 241.52,57.36 arc(241.42,57.86) 241.14,58.28 219.53,79.89 arc(219.36,80.14) 219.3,80.43 219.3,102.5 arc(219.16,103.22) 218.76,103.82 211.51,111.07 arc(211,111.41) 210.39,111.53 196.52,111.53 arc(195.97,111.42) 195.5,111.11 192.94,108.55 arc(192.64,108.1) 192.53,107.57 192.53,105.19 arc(192.46,104.81) 192.24,104.48 189.43,101.68 arc(189.23,101.37) 189.15,101 189.15,100.09 arc(189.33,99.67) 189.75,99.5 190.06,99.5 arc(190.18,99.47) 190.28,99.4 190.5,99.18 v2(190.51,99.18)
TX3_L0_P_DC: length 5.1
  TOP w0.091: C1218.2 241.62,46.3 arc(241.54,46.18) 241.51,46.05 241.51,43.38 arc(241.56,43.17) 241.67,42.99 arc(241.75,42.88) 241.77,42.75 arc(241.78,42.75) 241.78,42.74 J16.18C
TX4_L0_N: length 121.5
  TOP w0.091: C1223.1 255.46,47.91 arc(255.49,47.95) 255.5,48.01 255.5,48.16 arc(255.49,48.19) 255.47,48.22 v2(255.17,48.53) ; v2(190.52,107.6) 190.52,107.37 arc(190.57,107.26) 190.68,107.21 190.88,107.21 arc(190.99,107.25) 191.03,107.36 arc(191.19,107.52) 191.34,107.36 arc(191.38,107.25) 191.49,107.21 192.15,107.21 arc(192.39,107.16) 192.59,107.03 192.98,106.64 arc(193.11,106.55) 193.27,106.52 195.2,106.52 arc(195.24,106.53) 195.27,106.55 195.32,106.6 arc(195.35,106.62) 195.39,106.63 U622.28
  BOTTOM w0.091: v2(190.52,107.6) 190.25,107.33 arc(190.2,107.3) 190.15,107.29 189.92,107.29 arc(189.72,107.37) 189.64,107.58 189.64,107.7 arc(189.68,107.8) 189.79,107.85 arc(189.94,108) 189.79,108.15 arc(189.68,108.2) 189.64,108.31 189.64,108.53 arc(189.68,108.64) 189.79,108.69 arc(189.94,108.84) 189.79,108.99 arc(189.68,109.04) 189.64,109.14 189.64,109.72 arc(189.69,110) 189.85,110.23 195.72,116.11 arc(196.11,116.37) 196.57,116.46 209.82,116.46 arc(210.11,116.4) 210.36,116.24 221.86,104.73 arc(222.09,104.39) 222.17,103.97 222.17,85.1 arc(222.26,84.64) 222.52,84.26 255.25,51.53 arc(255.43,51.27) 255.49,50.97 255.49,49 arc(255.46,48.86) 255.38,48.74 v2(255.17,48.53)
TX4_L0_N_DC: length 5.1
  TOP w0.091: J16.19D 255.23,42.75 arc(255.23,42.75) 255.22,42.75 arc(255.25,42.88) 255.32,42.99 255.32,42.99 arc(255.44,43.17) 255.48,43.38 255.48,46.05 arc(255.46,46.19) 255.38,46.31 C1223.2
TX4_L0_P: length 121.6
  TOP w0.091: C1222.1 255.8,47.89 arc(255.78,47.92) 255.78,47.96 255.78,48.18 arc(255.78,48.22) 255.8,48.25 v2(256.08,48.53) ; U622.29 195.39,106.13 arc(195.35,106.14) 195.32,106.16 195.27,106.22 arc(195.24,106.23) 195.2,106.24 193.27,106.24 arc(193,106.29) 192.78,106.44 192.39,106.83 arc(192.28,106.9) 192.15,106.93 190.93,106.93 arc(190.91,106.93) 190.89,106.93 arc(190.76,106.89) 190.64,106.81 v2(190.52,106.69)
  BOTTOM w0.091: v2(190.52,106.69) 190.24,106.98 arc(190.2,107) 190.15,107.01 189.92,107.01 arc(189.52,107.18) 189.36,107.58 189.36,109.72 arc(189.43,110.1) 189.65,110.43 195.53,116.3 arc(196.01,116.63) 196.57,116.74 209.82,116.74 arc(210.22,116.66) 210.55,116.44 222.06,104.93 arc(222.35,104.49) 222.45,103.97 222.45,85.1 arc(222.52,84.75) 222.72,84.46 255.45,51.73 arc(255.68,51.38) 255.77,50.97 255.77,49 arc(255.79,48.86) 255.87,48.74 v2(256.08,48.53)
TX4_L0_P_DC: length 5.1
  TOP w0.091: C1222.2 255.87,46.3 arc(255.79,46.18) 255.76,46.05 255.76,43.38 arc(255.8,43.17) 255.92,42.99 arc(256,42.88) 256.02,42.75 arc(256.03,42.75) 256.03,42.74 J16.18D
UART1_SW: length 4.9
  TOP w0.254: v2(67.69,34.36) 67.54,34.51 U46.7
  BOTTOM w0.254: L52.2 67.06,35 v2(67.69,34.36) 68.58,35.25 C3893.2
UART2_SW: length 4.9
  TOP w0.254: U95.7 58.91,34.56 v2(59.05,34.42)
  BOTTOM w0.254: L53.2 58.42,35.05 v2(59.05,34.42) 59.94,35.31 C3896.2
USB1_DN: length 182
  TOP w0.091: U22.J31 v3(91.33,149.2) ; L23.1 42.85,21.69 43.2,22.04 43.2,23.11 43.94,23.85 43.94,33.45 57.35,46.86 57.35,55.27 57.18,55.45 56.79,55.45 v2(56.54,55.19)
  L14_INT_6 w0.1: v3(91.33,149.2) 91.35,149.22 91.35,149.63 91.21,149.76 90.89,149.76 90.72,149.59 88.41,149.59 86.92,148.1 86.92,142.82 86.42,142.32 86.42,142.29 85.7,141.57 85.7,129.98 88.77,126.91 88.77,122.4 94.89,116.28 94.89,98.13 104.58,88.44 104.58,79.71 80.31,55.45 56.79,55.45 v2(56.54,55.19)
USB1_DP: length 181.9
  TOP w0.091: v2(56.54,56.01) 56.9,55.65 57.26,55.65 57.56,55.35 57.56,46.78 44.15,33.37 44.15,23.77 43.4,23.03 43.4,22.01 43.72,21.7 L23.4 ; v3(91.33,150.2) U22.K31
  L14_INT_6 w0.1: v2(56.54,56.01) 56.85,55.7 80.21,55.7 104.32,79.82 104.32,88.33 94.63,98.02 94.63,116.18 88.52,122.29 88.52,126.8 85.45,129.88 85.45,141.67 86.24,142.47 86.28,142.47 86.72,142.91 86.72,148.19 88.33,149.79 90.64,149.79 90.81,149.96 91.1,149.96 v3(91.33,150.2)
USB1_ID: length 1.4
  TOP w0.118: v3(90.33,151.2) U22.L32
  BOTTOM w0.118: R736.1 v3(90.33,151.2)
USB1_ILIM: length 1.3
  TOP w0.254: R5725.1 33.66,40.96 33.75,41.05 U48.A3
USB1_ISON: length 12.4
  TOP w0.091: CN4.B2 39.64,10.6 39.91,10.87 39.91,11.64 40.34,12.06 41.71,12.06 42.19,12.55 42.19,14.33 42.67,14.81 42.67,16.4 42.52,16.55 U608.4 U608.7 42.52,17.98 42.68,18.13 42.68,18.57 43.18,19.07 43.18,19.33 42.85,19.66 L23.2
USB1_ISOP: length 12.4
  TOP w0.091: L23.3 43.72,19.66 43.38,19.33 43.38,18.99 42.88,18.48 42.88,18.15 43.02,18 U608.6 U608.5 43.02,16.55 42.88,16.4 42.88,14.73 42.39,14.24 42.39,12.46 41.79,11.86 40.42,11.86 40.11,11.55 40.11,10.87 40.38,10.6 CN4.B3
USB1_ISOPWR: length 10.2
  TOP w0.508: CN4.B1 37.18,11.28 ; CN4.B1 35.82,11.28 ; CN4.B1 37.18,9.93 ; CN4.B1 35.82,9.93 ; 25.81,30.46 C5342.1 ; C5342.1 25.81,28.22 ; C5342.1 28.04,30.46 ; C5342.1 28.04,28.22
USB1_PWREN: length 171.6
  TOP w0.118: U48.A1 v2(34.11,42.8) ; v3(90.33,145.2) U22.E32
  L14_INT_6 w0.087: v3(90.33,145.2) 89.94,144.81 89.94,140.18 88.21,138.45 88.21,130.63 91.54,127.3 91.54,122.81 97.15,117.2 97.15,99.14 106.93,89.36 106.93,70.84 87.1,51 37.26,51 34.11,47.85 v2(34.11,42.8)
USB1_PWRFAULT: length 166.3
  TOP w0.118: U629.4 v2(36.29,48.29) ; v3(90.33,146.2) U22.F32
  L14_INT_6 w0.087: v2(36.29,48.29) 43.08,48.29 45.58,50.79 87.19,50.79 107.15,70.75 107.15,89.45 97.39,99.21 97.39,117.26 91.75,122.9 91.75,127.39 88.42,130.72 88.42,138.36 90.18,140.12 90.18,143.27 90.93,144.02 90.93,145.59 v3(90.33,146.2)
USB1_PWRFLT_B: length 5.2
  TOP w0.118: U48.A2 35.05,42.04 35.05,43.56 34.42,44.2 U629.2
USB1_VBUSCLMP: length 183.9
  TOP w0.118: v3(90.33,147.2) U22.G32 ; D9.A v2(30.35,46.35)
  L14_INT_6 w0.087: v3(90.33,147.2) 90.84,146.69 91.5,146.69 91.82,146.37 91.82,143 91.5,142.68 91.07,142.68 90.7,142.32 90.7,140 88.83,138.13 88.83,137.43 88.98,137.28 88.98,130.77 92.18,127.57 92.18,123.08 97.75,117.51 97.75,117.51 97.82,117.44 97.82,100.07 104.67,93.22 105.87,93.22 107.58,91.5 107.58,70.57 87.37,50.36 47.38,50.36 44.12,47.09 39.14,47.09 34.42,42.37 32.21,42.37 30.35,44.22 v2(30.35,46.35)
  BOTTOM w0.118: R659.1 R662.2 v2(30.35,46.35)
USB2_DN: length 186
  TOP w0.091: v2(54.91,53.26) 55.22,52.96 55.22,47.17 42.47,34.42 42.47,24.74 40.64,22.92 40.64,22.03 40.33,21.72 L24.1 ; U22.M31 v3(91.33,152.2)
  L14_INT_6 w0.1: v2(54.91,53.26) 55.21,53.56 55.21,53.92 55.49,54.2 80.75,54.2 105.57,79.02 105.57,88.95 95.91,98.61 95.91,116.68 89.94,122.65 89.94,127.14 86.94,130.14 86.94,139.98 87.88,140.92 87.88,143.04 88.37,143.53 88.41,143.53 88.73,143.85 88.73,147.51 89.01,147.79 91.57,147.79 91.74,147.96 91.74,152.58 91.64,152.68 91.43,152.68 91.33,152.58 v3(91.33,152.2)
USB2_DP: length 186.1
  TOP w0.091: v3(91.33,153.2) U22.N31 ; v2(55.73,53.26) 55.42,52.96 55.42,47.08 42.67,34.33 42.67,24.66 40.85,22.84 40.85,22.04 41.2,21.68 L24.4
  L14_INT_6 w0.1: v2(55.73,53.26) 55.46,53.53 55.46,53.82 55.59,53.95 80.85,53.95 105.82,78.92 105.82,89.06 96.16,98.71 96.16,116.79 90.2,122.76 90.2,127.25 87.2,130.24 87.2,139.87 88.14,140.81 88.14,142.94 88.55,143.35 88.55,143.39 88.93,143.77 88.93,147.43 89.09,147.59 91.65,147.59 91.94,147.87 91.94,152.67 91.72,152.89 91.47,152.89 91.33,153.02 v3(91.33,153.2)
USB2_ID: length 1.4
  TOP w0.118: v3(90.33,148.2) U22.H32
  BOTTOM w0.118: R741.1 v3(90.33,148.2)
USB2_ILIM: length 1.3
  TOP w0.254: U47.A3 43.78,41.05 43.69,40.96 R508.1
USB2_ISON: length 8
  TOP w0.091: CN4.A2 39.9,14.12 39.9,14.73 41.17,16 41.17,16.41 41.02,16.56 U608.1 U608.10 41.02,17.99 41.17,18.14 41.17,18.51 40.66,19.02 40.66,19.33 40.33,19.66 L24.2
USB2_ISOP: length 8
  TOP w0.091: CN4.A3 40.1,14.12 40.1,14.64 41.37,15.91 41.37,16.38 41.52,16.53 U608.2 U608.9 41.52,17.99 41.37,18.13 41.37,18.59 40.86,19.1 40.86,19.31 41.2,19.65 L24.3
USB2_ISOPWR: length 11.4
  TOP w0.508: 34.06,28.22 C5341.1 ; C5341.1 34.06,30.46 ; C5341.1 36.3,28.22 ; C5341.1 36.3,30.46 ; 35.61,14.11 CN4.A1 ; CN4.A1 37.39,14.11 ; CN4.A1 37.39,12.34 ; CN4.A1 35.61,12.34
USB2_PWREN: length 159.8
  TOP w0.118: U22.A32 v3(91.33,141.2) ; U47.A1 v2(44.14,42.8)
  L14_INT_6 w0.087: v2(44.14,42.8) 44.09,42.85 44.09,45.62 48.15,49.67 59.93,49.67 60.04,49.57 60.04,49.21 60.29,48.97 60.64,48.97 60.89,49.21 60.89,49.57 61,49.67 87.65,49.67 108.26,70.29 108.26,91.79 106.15,93.9 104.96,93.9 98.31,100.55 98.31,117.92 92.74,123.49 92.74,127.65 89.66,130.72 89.66,137.21 89.87,137.42 89.87,138.51 91.76,140.4 91.76,140.77 v3(91.33,141.2)
USB2_PWRFAULT: length 154.6
  TOP w0.118: U22.B32 90.83,142.7 v3(91.33,143.2) ; U628.4 v2(45.4,49.29)
  L14_INT_6 w0.087: v3(91.33,143.2) 90.79,143.2 90.37,142.77 90.37,139.95 88.64,138.22 88.64,130.8 91.97,127.48 91.97,122.99 97.61,117.35 97.61,99.93 104.6,92.94 105.26,92.94 105.74,92.46 105.74,91.59 107.37,89.97 107.37,70.66 87.28,50.57 46.68,50.57 v2(45.4,49.29)
USB2_PWRFLT_B: length 5.2
  TOP w0.118: U47.A2 45.09,42.04 45.09,43.56 44.45,44.2 U628.2
USB2_VBUSCLMP: length 164.4
  TOP w0.102: v3(91.33,140.59) 90.44,141.48 90.44,143.3 U22.C32
  TOP w0.118: D10.A v2(40.39,46.35)
  L14_INT_6 w0.087: v2(40.39,46.35) 40.72,46.69 44.48,46.69 47.8,50.01 87.51,50.01 107.92,70.43 107.92,91.64 106.01,93.56 104.82,93.56 98.03,100.34 98.03,117.53 98.02,117.55 98.02,117.73 92.52,123.22 92.52,127.56 89.32,130.76 89.32,137.27 89.68,137.63 89.68,138.63 91.33,140.28 v3(91.33,140.59)
  BOTTOM w0.118: v2(40.39,46.35) R664.2 R663.1
USB_BIAS: length 1.4
  TOP w0.118: v3(91.33,144.2) U22.D31
  BOTTOM w0.118: R747.1 91.81,144.68 v3(91.33,144.2)
USB_HVDD: length 2.2
  TOP w0.457: v3(90.33,150.2) U22.K32 ; U22.N32 v3(90.33,153.2)
  BOTTOM w0.457: C840.1 v3(90.33,153.2)
USB_OVDD: length 1.4
  TOP w0.457: v3(91.33,154.2) U22.P31 ; v3(90.33,154.2) U22.P32
USB_SVDD: length 3.6
  TOP w0.457: v3(92.33,154.2) U22.P30 ; v3(93.33,154.2) U22.P29
  BOTTOM w0.457: v3(92.33,154.2) C838.1 v3(93.33,154.2) C837.1
  vias: v2(101.09,127.38) v2(101.09,126.75)
UT_SDHCCLK: length 4.8
  TOP w0.118: U22.A33 89.83,140.17 91.31,138.68 R301.1
UT_SPICLK: length 5.8
  TOP w0.102: U22.B37 85.43,142.29 85.43,141.46 85.53,141.35
  TOP w0.118: R296.2 85.78,137.74 85.53,137.99 85.53,141.35
UTCKO: length 5.7
  TOP w0.102: U22.N44 78.83,153.51
  TOP w0.118: 78.83,153.51 76.15,150.83 TP5.1
UTEMI1_MDC: length 1.4
  TOP w0.118: U22.G13 v3(110.33,147.2)
  BOTTOM w0.118: v3(110.33,147.2) 110.2,147.06 R745.1
VBBS: length 1.7
  TOP w0.254: U16.14 278.09,77.96 C5334.1
VTT_A_SENSE: length 1
  TOP w0.381: R5905.2 R5734.1
VTT_B_SENSE: length 1.2
  TOP w0.254: R5735.1 R5906.2
X1_GND:
  vias: v2(110.56,86.48) v2(110.57,85.24) v2(110.69,84.1) v2(110.95,87.4) v2(111.07,82.96) v2(112.34,87.53) v2(112.85,82.96) v2(113.49,87.53) v2(115.01,86.51) v2(115.9,85.75) v2(115.89,83.86)
XA_SI5341B: length 6.6
  TOP w0.118: Y7.1 112,85.46 112.22,85.24 114.45,85.24 114.71,84.98 U36.8
XB_SI5341B: length 4
  TOP w0.118: U36.9 114.83,84.48 114.48,84.14 Y7.3
XFCFG_CLKO: length 54.6
  TOP w0.118: U65.42 182.12,86.77 181.38,86.02 181.38,84 v2(181.69,83.69) ; v2(199.29,114.25) 199.29,113.44 198.95,113.1 U622.19
  L3_INT_1 w0.087: v2(199.29,114.25) 194.05,114.25 185.76,105.95 185.76,98.81 184.41,97.46 181.31,97.46 179.13,95.29 179.13,86.88 181.39,84.63 181.39,83.99 v2(181.69,83.69)
XFCFG_ENSMB: length 33.1
  TOP w0.118: v2(198.17,112.59) 198.17,111.22 198.45,110.95 U622.20 ; U65.20 181.62,97.7 181.38,97.94 v2(181.38,98.58) 181.62,98.82 R5815.2
  L5_INT_2 w0.087: v2(181.38,98.58) 181.38,100.71 186.06,105.38 190.96,105.38 v2(198.17,112.59)
XFCFG_READEN: length 31.1
  TOP w0.118: R5816.1 199.95,98.48 v2(199.95,98.78) U622.44 ; v2(183.12,84.3) U65.44
  L5_INT_2 w0.087: v2(199.95,98.78) 199.09,97.92 199.09,96.14 188.3,85.36 184.18,85.36 v2(183.12,84.3)
XIFC_A26: length 4
  TOP w0.118: U594.16 73.79,104.48 TP253.1
XIFC_A27: length 3.7
  TOP w0.118: TP254.1 74.29,103.81 U594.17
XIFC_A28: length 3.7
  TOP w0.118: TP255.1 75.02,103.87 75.29,104.14 U594.19
XIFC_A29: length 3.7
  TOP w0.118: U594.20 75.79,103.8 TP256.1
XIFC_A30: length 3.8
  TOP w0.118: TP257.1 76.79,103.94 U594.22
XIFC_A31: length 4
  TOP w0.118: TP252.1 77.29,104.59 U594.23
XRT_CP0: length 5.6
  TOP w0.118: C5316.1 185.01,83.32 185.01,86.46 184.62,86.85 U65.47
XRT_CP1: length 5.7
  TOP w0.118: U65.38 180.12,85.25 179.53,84.66 179.53,83.22 C5317.1
XRT_CP2: length 6.8
  TOP w0.118: C5318.1 179.53,99.4 179.53,95.91 180.12,95.32 U65.23
XRT_CP3: length 6.7
  TOP w0.118: U65.14 184.62,94.86 185.57,95.81 185.57,99.51 C5319.1
XRT_CP4: length 5.6
  TOP w0.118: U622.47 201.45,101.45 201.79,101.1 201.79,97.95 C5312.1
XRT_CP5: length 5.7
  TOP w0.118: U622.38 196.95,99.83 196.32,99.2 196.32,97.76 C5313.1
XRT_CP6: length 7.1
  TOP w0.118: C5314.1 195.99,114.92 196.37,114.53 196.37,110.46 196.95,109.88 U622.23
XRT_CP7: length 7
  TOP w0.118: C5315.1 202.6,114.8 202.3,114.49 202.3,110.25 201.45,109.4 U622.14
XRT_REF0: length 4.4
  TOP w0.118: U65.48 185.12,87.01 185.65,86.49 185.65,83.68 C5316.2
XRT_REF1: length 4.5
  TOP w0.118: C5317.2 178.64,84.61 179.62,85.59 U65.37
XRT_REF2: length 5.6
  TOP w0.118: U65.24 179.62,94.88 178.59,95.91 C5318.2
XRT_REF3: length 5.5
  TOP w0.118: C5319.2 186.28,95.93 185.12,94.76 U65.13
XRT_REF4: length 4.4
  TOP w0.118: U622.48 201.95,101.49 202.44,101 202.44,98.3 C5312.2
XRT_REF5: length 4.5
  TOP w0.118: C5313.2 195.47,99.25 196.45,100.23 U622.37
XRT_REF6: length 5.6
  TOP w0.118: U622.24 196.45,109.34 195.41,110.38 C5314.2
XRT_REF7: length 5.5
  TOP w0.118: C5315.2 203.11,110.45 201.95,109.29 U622.13
XRX1_DOUTN: length 5.7
  TOP w0.091: U65.32 178.56,90.05 arc(178.52,90.05) 178.49,90.03 178.44,89.97 arc(178.41,89.95) 178.37,89.94 177.15,89.94 arc(176.86,89.89) 176.62,89.73 176.19,89.3 arc(176.06,89.21) 175.9,89.18 174.05,89.18 arc(174.01,89.19) 173.99,89.21 C1033.1
XRX1_DOUTP: length 5.7
  TOP w0.091: U65.33 178.56,89.56 arc(178.52,89.56) 178.49,89.58 178.44,89.64 arc(178.41,89.66) 178.37,89.67 177.15,89.67 arc(176.97,89.63) 176.82,89.53 176.39,89.1 arc(176.17,88.95) 175.9,88.9 174.05,88.9 arc(174.01,88.89) 173.99,88.87 C1032.1
XRX2_DOUTN: length 6.8
  TOP w0.091: C1034.1 173.99,96.72 arc(174.02,96.7) 174.05,96.7 174.35,96.7 arc(174.58,96.65) 174.78,96.52 177.67,93.63 arc(177.87,93.49) 178.12,93.44 178.37,93.44 arc(178.41,93.45) 178.44,93.47 178.49,93.53 arc(178.52,93.55) 178.56,93.56 U65.25
XRX2_DOUTP: length 6.8
  TOP w0.091: C1031.1 173.99,96.39 arc(174.02,96.41) 174.05,96.42 174.35,96.42 arc(174.47,96.39) 174.58,96.32 177.47,93.43 arc(177.77,93.23) 178.12,93.17 178.37,93.17 arc(178.41,93.16) 178.44,93.14 178.49,93.08 arc(178.52,93.06) 178.56,93.05 U65.26
XRX3_DOUTN: length 5.7
  TOP w0.091: U622.32 195.39,104.63 arc(195.35,104.62) 195.32,104.6 195.27,104.55 arc(195.24,104.53) 195.2,104.52 193.97,104.52 arc(193.69,104.46) 193.45,104.3 193.02,103.88 arc(192.89,103.79) 192.73,103.76 190.88,103.76 arc(190.84,103.76) 190.81,103.78 C1036.2
XRX3_DOUTP: length 5.7
  TOP w0.091: C1035.2 190.81,103.45 arc(190.84,103.47) 190.88,103.48 192.73,103.48 arc(192.99,103.53) 193.22,103.68 193.65,104.11 arc(193.8,104.21) 193.97,104.24 195.2,104.24 arc(195.24,104.23) 195.27,104.22 195.32,104.16 arc(195.35,104.14) 195.39,104.13 U622.33
XRX4_DOUTN: length 6.8
  TOP w0.091: U622.25 195.39,108.13 arc(195.35,108.12) 195.32,108.1 195.26,108.05 arc(195.24,108.03) 195.2,108.02 194.94,108.02 arc(194.7,108.07) 194.49,108.21 191.61,111.09 arc(191.41,111.23) 191.17,111.27 190.88,111.27 arc(190.85,111.28) 190.82,111.3 C1038.2
XRX4_DOUTP: length 6.8
  TOP w0.091: U622.26 195.39,107.63 arc(195.35,107.64) 195.32,107.66 195.27,107.72 arc(195.24,107.73) 195.2,107.74 194.94,107.74 arc(194.59,107.81) 194.3,108.01 191.41,110.89 arc(191.3,110.97) 191.17,110.99 190.88,110.99 arc(190.85,110.99) 190.82,110.97 C1037.2
XVDD: length 16.1
  TOP w0.508: 96.14,192.53 110.21,192.53 110.62,192.13 R182.2 ; v2(28.41,143.04) 28.42,143.04 R5894.1
  vias: v2(84.86,190.4) v2(84.86,189.48) v2(85.17,191.67) v2(85.83,190.4) v2(85.8,189.48) v2(87.12,121.59) v2(87.12,120.6) v2(87.68,119.81) v2(88.16,121.59) v2(88.21,120.6) v2(89.03,119.74) v2(91.52,191.74) v2(91.52,191.11) v2(93.7,192.53) v2(93.82,191.9) v4(32.11,153.39) v4(33.83,153.34) v4(33.78,151.84) v4(35.54,151.82) v4(35.66,153.34)
Z4901: length 1.6
  TOP w0.118: R341.2 LED4.A
Z4902: length 1.6
  TOP w0.118: LED3.A R335.2
Z4903: length 1.6
  TOP w0.118: LED2.A R333.2
Z4904: length 1.6
  TOP w0.118: R332.2 LED1.A
Z5402: length 5.6
  TOP w0.508: R68.2 v2(242.44,240.73) ; R73.2 v2(253.87,240.73) ; R67.2 v2(239.9,240.73) ; R70.2 v2(247.52,240.73) ; R69.2 v2(244.98,240.73) ; R74.2 v2(255.27,240.73) ; R72.1 v2(251.33,240.73) ; R71.2 v2(250.06,240.73)
  vias: v2(238.53,237.64) v2(239.27,238.4) v2(240.08,237.64)
N16862198: length 8.3
  TOP w0.118: U22.E35 87.33,146.19 v3(87.33,146.2)
  BOTTOM w0.118: v3(87.33,146.2) 87.27,146.2 TP205.1 86.8,145.73 86.8,145.03 86.11,144.34 86.11,143.95 85.78,143.62 85.78,140.26 R768.2
N18838531: length 4
  BOTTOM w0.118: C94.1 85.08,217.4 R43.1 U3.4
N18839314: length 1.1
  TOP w0.254: R44.2 C87.2
N18839320: length 2.3
  TOP w0.203: U9.7 79.43,232.61 79.73,232.92 79.73,233.21 C87.1
N18839399: length 1
  BOTTOM w0.118: C5271.1 87.07,215.93 87.07,215.93 R55.2
N18839410: length 38.8
  BOTTOM w0.118: C5272.2 89.33,217.54 89.33,219.43 90.6,220.7 97.69,220.7 102.46,215.93 119.28,215.93 121.34,213.87 R56.1
N18839524: length 2
  TOP w0.203: U7.5 97.35,231.24 R77.1
N18839526: length 0.9
  TOP w0.381: R77.2 99.44,232.34 C124.2
N18839532: length 2
  TOP w0.203: U7.7 97.47,232.24 C124.1
N20471515: length 32
  TOP w0.118: J11.27 117.73,8.39 117.73,11.02 116.36,12.39 116.36,14.73 117.36,15.73 117.36,21.32 116.36,22.32 116.36,25.32 115.29,26.39 115.29,28.12 117.18,30 117.18,34.37 R641.2
N20471595: length 31.5
  TOP w0.118: J11.29 124.36,6.88 124.36,10.39 126.36,12.4 126.36,14.91 125.35,15.93 125.35,17.68 126.26,18.59 126.26,25.37 127.41,26.52 127.41,28.09 125.73,29.77 R643.2
N30740588: length 6.5
  TOP w0.102: 61.89,68.43 61.89,71.62 U27.E7
  TOP w0.118: 61.89,68.43 61.71,68.25 61.71,66.15 TP196.1
N30741197: length 0.7
  BOTTOM w0.118: v1(59.07,72.8) 59.05,72.8 C3698.2
  vias: v2(54.1,72.97) v2(54.08,72.03)
N30744842: length 2.4
  TOP w0.118: R5588.2 48.23,58.39 47.98,58.14 U250.7
N30744844: length 2.4
  TOP w0.118: U250.3 R5589.2
N30954766: length 1.7
  TOP w0.118: U37.53 R5703.2
N31081508: length 2.3
  TOP w0.118: U32.10 112.88,107.48 113.07,107.29 TP212.1
N31116021: length 1.9
  TOP w0.118: R5721.1 106.02,109.47 106.45,109.04 U32.19
N31148954: length 1.6
  TOP w0.254: U46.6 C3894.1
N31148956: length 3.6
  TOP w0.457: U46.17 C3895.1
N31149103: length 1.6
  TOP w0.254: U95.6 C3897.1
N31149105: length 3.6
  TOP w0.457: U95.17 C3898.1
N31714319: length 10.6
  TOP w0.305: U1.4 30.79,99.76 v2(31.29,99.26) ; C1.2 33.38,104.44 v2(32.89,103.96) 32.08,103.96 31.79,103.67 U1.9
  L12_INT_5 w0.508: v2(32.89,103.96) 32.89,99.77 32.39,99.26 v2(31.29,99.26)
N31714572: length 2
  TOP w0.305: U1.10 31.29,104.09 31.98,104.78 C10.1
N31717308: length 10.4
  TOP w0.254: R5788.1 v2(184.4,191.83)
  BOTTOM w0.381: v2(176.68,193.85) 177.27,194.44 182.98,194.44 184.4,193.01 v2(184.4,191.83)
N31718323: length 11.6
  TOP w0.508: v2(34.68,200.05) R5789.1
  L14_INT_6 w0.508: v2(32.69,191.21) 31.34,192.56 31.34,196.44 34.68,199.77 v2(34.68,200.05)
N31722569: length 2.6
  TOP w0.118: U17.6 182.26,190.94 182.37,190.83 v2(182.52,190.83) 183.06,190.83 183.36,191.13 R5788.2
  BOTTOM w0.118: C5141.2 181.97,190.83 v2(182.52,190.83)
N31724252: length 2.5
  TOP w0.381: U14.6 v2(34.87,197.37) 34.68,197.57 R5789.2
  BOTTOM w0.381: v2(34.87,197.37) C5143.2
N31726596: length 83.1
  TOP w0.254: U17.4 176.7,190.29 176.4,189.99 v2(175.92,189.99)
  TOP w0.508: R5734.2 170.46,117.28 v2(170.91,117.73)
  BOTTOM w0.508: v2(175.92,189.99) 176.37,189.54 177.06,189.54 180.97,185.62 180.97,169.95 179.15,168.12 176.2,168.12 174.02,165.94 174.02,120.83 v2(170.91,117.73)
N31727679: length 5.7
  TOP w0.254: v2(36.07,191.01) 35.52,191.56 U14.4 ; v2(39.24,189.48) 39.99,189.48 R5735.2
  BOTTOM w0.254: v2(39.24,189.48) 38.18,190.55 36.53,190.55 v2(36.07,191.01)
N31789752: length 10.5
  TOP w0.305: U23.9 30.37,164.72 30.67,165.02 v2(31.47,165.02) 31.95,165.51 C5150.2 ; U23.4 29.37,160.83 v2(29.87,160.32)
  L14_INT_6 w0.508: v2(31.47,165.02) 31.47,160.91 30.89,160.32 v2(29.87,160.32)
N31790039: length 2
  TOP w0.305: C5158.1 30.56,165.77 29.87,165.08 U23.10
N31884769: length 10.5
  TOP w0.305: v2(31.47,135.71) 30.97,136.21 U25.4 ; U25.9 31.97,140.11 32.28,140.41 v2(33.07,140.41) 33.55,140.89 C5160.2
  L3_INT_1 w0.508: v2(31.47,135.71) 32.51,135.71 33.07,136.27 v2(33.07,140.41)
N31885020: length 2
  TOP w0.305: U25.10 31.47,140.54 32.16,141.22 C5168.1
N31888256: length 11
  TOP w0.305: U68.4 251.31,87.71 v2(251.82,88.22) ; C5244.2 246.63,90.3 v2(247.12,89.82) 247.12,89 247.41,88.71 U68.9
  BOTTOM w0.508: v2(251.82,88.22) 251.37,87.77 248.07,87.77 247.12,88.72 v2(247.12,89.82)
N31888301: length 2
  TOP w0.305: U68.10 246.99,88.21 246.3,88.9 C5249.1
N32062690: length 3.5
  TOP w0.118: R644.2 J11.33
N32062836: length 3.5
  TOP w0.118: J11.31 R642.2
N32065877: length 3.5
  TOP w0.118: J12.31 137.61,31.84 137.61,31.84 R646.2
N32065910: length 3.5
  TOP w0.118: J12.33 R648.2
N32070236: length 3.5
  TOP w0.118: R650.2 J13.31
N32070242: length 3.5
  TOP w0.118: R652.2 J13.33
N32070301: length 32
  TOP w0.118: R649.2 160.72,34.37 160.72,30 158.83,28.12 158.83,26.39 159.9,25.32 159.9,18.59 160.88,17.61 160.88,15.72 159.9,14.73 159.9,12.39 161.27,11.02 161.27,8.39 J13.27
N32070307: length 31.5
  TOP w0.118: R651.2 169.27,29.77 170.95,28.09 170.95,26.34 169.8,25.19 169.8,18.59 168.89,17.68 168.89,15.93 169.9,14.91 169.9,12.4 167.9,10.39 167.9,6.88 J13.29
N32070366: length 3.8
  TOP w0.118: J14.31 181.15,33.84 R654.2
N32070372: length 3.5
  TOP w0.118: R656.2 J14.33
N32070429: length 31.5
  TOP w0.118: J14.29 189.67,6.88 189.67,10.39 191.68,12.4 191.68,14.91 190.66,15.93 190.66,17.68 191.59,18.61 191.59,25.23 192.72,26.35 192.72,28.09 191.04,29.77 R655.2
N32074017: length 31.5
  TOP w0.118: J12.29 146.13,6.88 146.13,10.39 148.13,12.4 148.13,14.91 147.12,15.93 147.12,17.68 148.03,18.59 148.03,25.45 149.18,26.6 149.18,28.09 147.5,29.77 R647.2
N32074023: length 32.2
  TOP w0.118: R645.2 139.37,33.58 138.95,33.15 138.95,30 137.06,28.12 137.06,26.39 138.13,25.32 138.13,18.59 139.12,17.6 139.12,15.72 138.13,14.73 138.13,12.39 139.5,11.02 139.5,8.39 J12.27
N32074313: length 5.9
  TOP w0.118: U42.49 140.7,48.41 141.45,47.65 C5174.2 Y20.1
N32074325: length 5.9
  TOP w0.118: U42.50 140.72,48.91 C5175.2 Y20.2
N32105138: length 16.4
  TOP w0.254: U42.104 v2(117.9,55.41)
  TOP w0.305: U42.109 117.68,52.91 v2(117.98,53.21) ; U42.79 129.63,56.48 v2(129.29,56.13) ; v2(136.74,55.15) 137,55.41 U42.63 ; U42.113 117.71,50.91 v2(117.98,51.18) ; U42.57 137.2,52.41 v2(136.91,52.7) ; v2(136.8,50.15) 137.05,50.41 U42.53 ; U42.86 v2(126.13,56.13)
  BOTTOM w0.305: v2(136.74,55.15) C5225.1 ; v2(136.91,52.7) C5223.1 ; v2(129.29,56.13) C5224.1 ; v2(117.9,55.41) 117.9,56 C5221.1 ; v2(117.98,53.21) 118.69,53.21 C5220.1 ; C5219.1 118,51.16 v2(117.98,51.18) ; v2(136.8,50.15) C5222.1 ; v2(126.13,56.13) C5226.1
  vias: v4(111.51,56.08) v4(113.16,56.08)
N32110539: length 2.3
  TOP w0.305: U42.114 117.71,50.41 v2(118.03,50.09)
  BOTTOM w0.254: R5791.2 118.06,50.11 v2(118.03,50.09)
N32112200: length 3.1
  TOP w0.305: U42.43 v2(139.25,45.41) ; U42.48 v2(136.93,47.91)
  BOTTOM w0.305: v2(136.93,47.91) 137.64,47.91 C5213.1
  vias: v4(141.07,44.78)
N32113835: length 2.2
  TOP w0.118: U42.103 114.67,55.91 TP233.1
N32113861: length 2.4
  TOP w0.118: U42.108 115.59,53.41 115.05,52.87 TP234.1
N32113887: length 2.2
  TOP w0.118: TP238.1 114.65,49.41 U42.116
N32114066: length 2.2
  TOP w0.118: TP242.1 114.71,46.91 U42.121
N32114156: length 5.9
  TOP w0.118: Y21.1 C5254.2 183.61,47.65 182.86,48.41 U620.49
N32114159: length 5.9
  TOP w0.118: U620.50 182.89,48.91 C5255.2 Y21.2
N32114233: length 16.4
  TOP w0.305: U620.109 159.84,52.91 v2(160.15,53.21) ; v2(179.12,52.7) 179.12,52.7 179.42,52.41 U620.57 ; U620.79 171.79,56.48 v2(171.45,56.13) ; U620.53 179.22,50.41 v2(178.96,50.15) ; v2(178.91,55.15) 179.16,55.41 U620.63 ; U620.104 v2(160.07,55.41) ; v2(160.15,51.18) 159.87,50.91 U620.113 ; U620.86 v2(168.3,56.13)
  BOTTOM w0.305: C940.1 160.85,53.21 v2(160.15,53.21) ; v2(168.3,56.13) C924.1 ; v2(179.12,52.7) C947.1 ; v2(160.15,51.18) 160.17,51.16 C932.1 ; v2(171.45,56.13) C961.1 ; v2(160.07,55.41) 160.07,56 C936.1 ; v2(178.96,50.15) C950.1 ; v2(178.91,55.15) C944.1
  vias: v4(153.67,56.08) v4(155.32,56.08)
N32114429: length 2.3
  TOP w0.305: U620.114 159.87,50.41 v2(160.19,50.09)
  BOTTOM w0.254: R5792.2 161.02,50.09 v2(160.19,50.09)
N32114439: length 3.1
  TOP w0.305: U620.43 v2(181.41,45.41) ; U620.48 v2(179.1,47.91)
  BOTTOM w0.305: v2(179.1,47.91) 179.8,47.91 C5201.1
  vias: v4(183.24,44.78)
N32114457: length 2.2
  TOP w0.118: U620.103 156.83,55.91 TP280.1
N32114465: length 2.4
  TOP w0.118: U620.108 157.67,53.41 157.14,52.87 TP276.1
N32114473: length 2.2
  TOP w0.118: TP272.1 156.81,49.41 U620.116
N32114475: length 2.2
  TOP w0.118: TP268.1 156.87,46.91 U620.121
N32122553: length 1.2
  TOP w0.254: C254.2 36.06,128.24 U630.7
N32122566: length 2.6
  TOP w0.254: R5748.1 R5747.2 37.06,128.38 36.56,127.87 U630.6
N32123048: length 10.9
  TOP w0.305: U69.9 203.01,63.95 202.72,64.24 v2(202.72,65.05) 202.23,65.53 C5203.2 ; U69.4 206.92,62.95 v2(207.42,63.45)
  BOTTOM w0.508: v2(202.72,65.05) 202.72,64.06 203.77,63 206.97,63 v2(207.42,63.45)
N32123323: length 2
  TOP w0.305: U69.10 202.59,63.45 201.9,64.14 C5211.1
N32124491: length 11.9
  TOP w0.118: U27.N4 64.27,78.8 63.72,78.8 63.47,79.04 63.47,80.17 63.72,80.41 69.69,80.41 70.56,81.28 JP8.1
N32124494: length 8
  TOP w0.118: JP8.2 71.55,80.01 71.15,79.61 65.07,79.61 U27.P4
N33496283: length 2
  TOP w0.203: R44.1 79.26,231.61 U9.5
N33510179: length 2.7
  TOP w0.118: R40.2 79.44,228.76 79.15,228.47 78.34,228.47 78.09,228.72 U9.31
N33510235: length 1.7
  TOP w0.118: U9.2 79.42,230.11 79.74,229.79 R41.2
N33521269: length 2.6
  TOP w0.118: U7.31 96.18,228.35 96.51,228.01 R5812.2
N33521274: length 1.9
  TOP w0.203: U7.2 97.46,229.74 97.69,229.52 97.89,229.52 R5811.2
N33883272: length 30.6
  TOP w0.118: C5294.1 119.38,33.15 119.84,32.69 119.84,29.84 119.36,29.37 119.36,26.37 118.33,25.34 J11.9
  BOTTOM w0.118: J11.9 119.5,15.49 119.94,15.49 J11.4 122.65,15.47 123.08,15.47 J11.12 125.5,15.44 125.93,15.44 J11.7
N33883466: length 20.6
  TOP w0.118: J11.25 121.36,30 C5295.1
  BOTTOM w0.118: J11.14 116.63,25.81 117.06,25.81 J11.22 119.45,25.96 119.88,25.96 J11.17 122.62,25.86 123.05,25.86 J11.25
N33883565: length 30.6
  TOP w0.118: C5296.1 141.15,33.15 141.61,32.69 141.61,29.84 141.13,29.37 141.13,26.37 140.1,25.34 J12.9
  BOTTOM w0.118: J12.7 147.75,15.39 147.32,15.39 J12.12 144.8,15.42 144.37,15.42 J12.4 141.81,15.39 141.38,15.39 J12.9
N33883665: length 20.6
  TOP w0.118: J12.25 143.13,30 C5297.1
  BOTTOM w0.118: J12.14 138.4,25.81 138.85,25.81 138.96,25.92 138.96,25.94 J12.22 141.3,25.88 141.73,25.88 J12.17 144.39,25.86 144.82,25.86 J12.25
N33884495: length 30.6
  TOP w0.118: J13.9 161.87,25.34 162.9,26.37 162.9,29.37 163.38,29.84 163.38,32.69 162.92,33.15 C5298.1
  BOTTOM w0.118: J13.9 163.15,15.39 163.58,15.39 J13.4 166.14,15.42 166.57,15.42 J13.12 169.04,15.44 169.47,15.44 J13.7
N33884597: length 20.6
  TOP w0.118: C5299.1 164.9,30 J13.25
  BOTTOM w0.118: J13.25 166.54,25.81 166.11,25.81 J13.17 163.5,25.88 163.07,25.88 J13.22 160.65,25.86 160.22,25.86 J13.14
N33884700: length 31.9
  TOP w0.118: C5300.1 186.67,31.69 190.58,27.79 190.58,26.21 189.59,25.22 J14.12
  BOTTOM w0.118: J14.7 191.27,15.42 190.83,15.42 J14.12 188.39,15.47 187.96,15.47 J14.4 185.27,15.47 184.84,15.47 J14.9
N33884804: length 21.5
  TOP w0.118: J14.25 184.69,31.98 C5301.1
  BOTTOM w0.118: J14.25 188.36,25.86 187.93,25.86 J14.17 185.27,25.88 184.83,25.88 184.71,26 184.71,26.01 J14.22 182.5,25.94 182.5,25.92 182.38,25.81 181.94,25.81 J14.14
N34046443: length 6.8
  TOP w0.118: U27.L2 66.66,77.2 70.75,77.2 JP8.3
N34055964: length 4.8
  TOP w0.118: J106.1 130.87,238.59 131.95,237.52 TP286.1
N34055974: length 4.4
  TOP w0.118: J106.5 130.35,242.59 131.11,241.83 132.66,241.83 R42.2
N34216244: length 1.2
  TOP w0.118: U626.16 R5895.1
N34216367: length 1.3
  TOP w0.118: U626.6 TP287.1
N34216393: length 1.3
  TOP w0.118: U627.6 TP288.1
N34216534: length 1.2
  TOP w0.118: U627.16 R5896.1
N34325441: length 12.9
  TOP w0.254: 279.34,78.73 279.09,78.98 U16.16 ; C3847.1 v2(279.5,77.17)
  TOP w0.381: C3847.1 279.5,78.57 279.34,78.73 ; R5907.1 D46.C 274.2,79.47 v2(274.68,78.99)
  BOTTOM w0.254: v2(274.68,78.99) 274.68,77.42 275.6,76.49 278.83,76.49 v2(279.5,77.17)
N37212649: length 4.2
  TOP w0.381: C5345.1 273,76.01 R5907.2
N311488790: length 2.8
  TOP w0.254: U46.9 68.04,38.45 68.38,38.79 v2(68.58,38.79)
  BOTTOM w0.254: v2(68.58,38.79) C3893.1
N311490280: length 3
  TOP w0.254: U95.9 59.41,38.53 59.82,38.94 v2(59.94,38.94)
  BOTTOM w0.254: v2(59.94,38.94) C3896.1
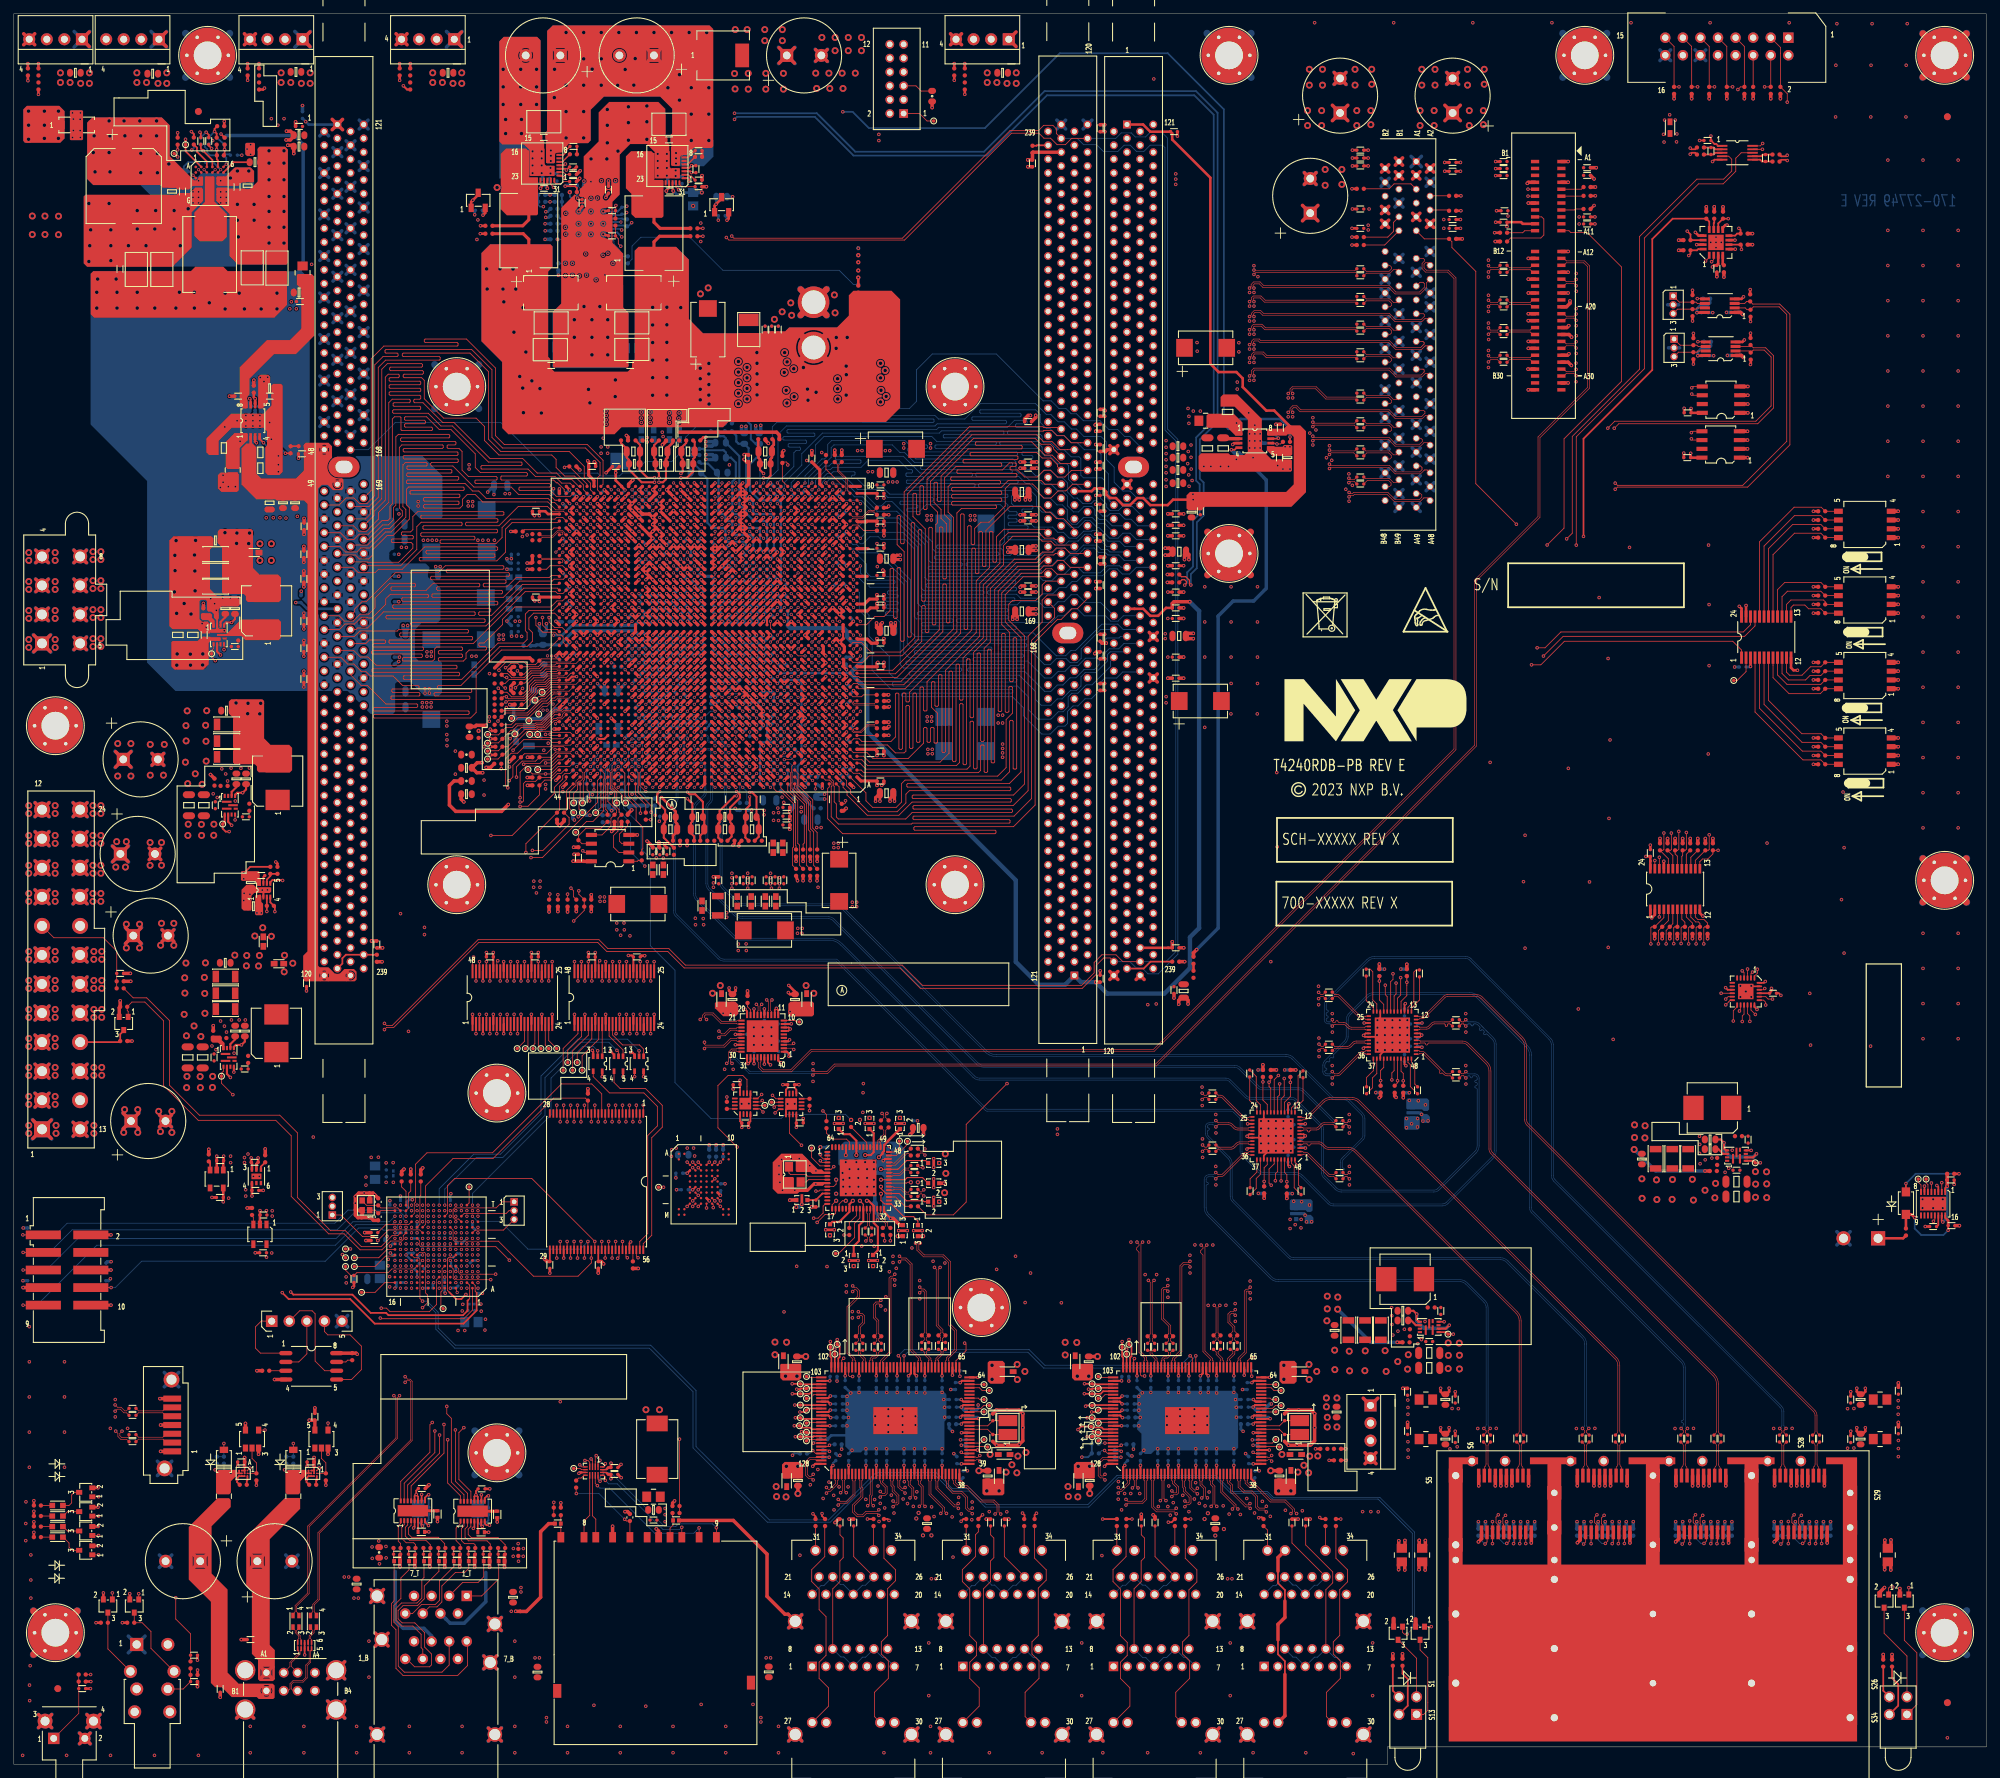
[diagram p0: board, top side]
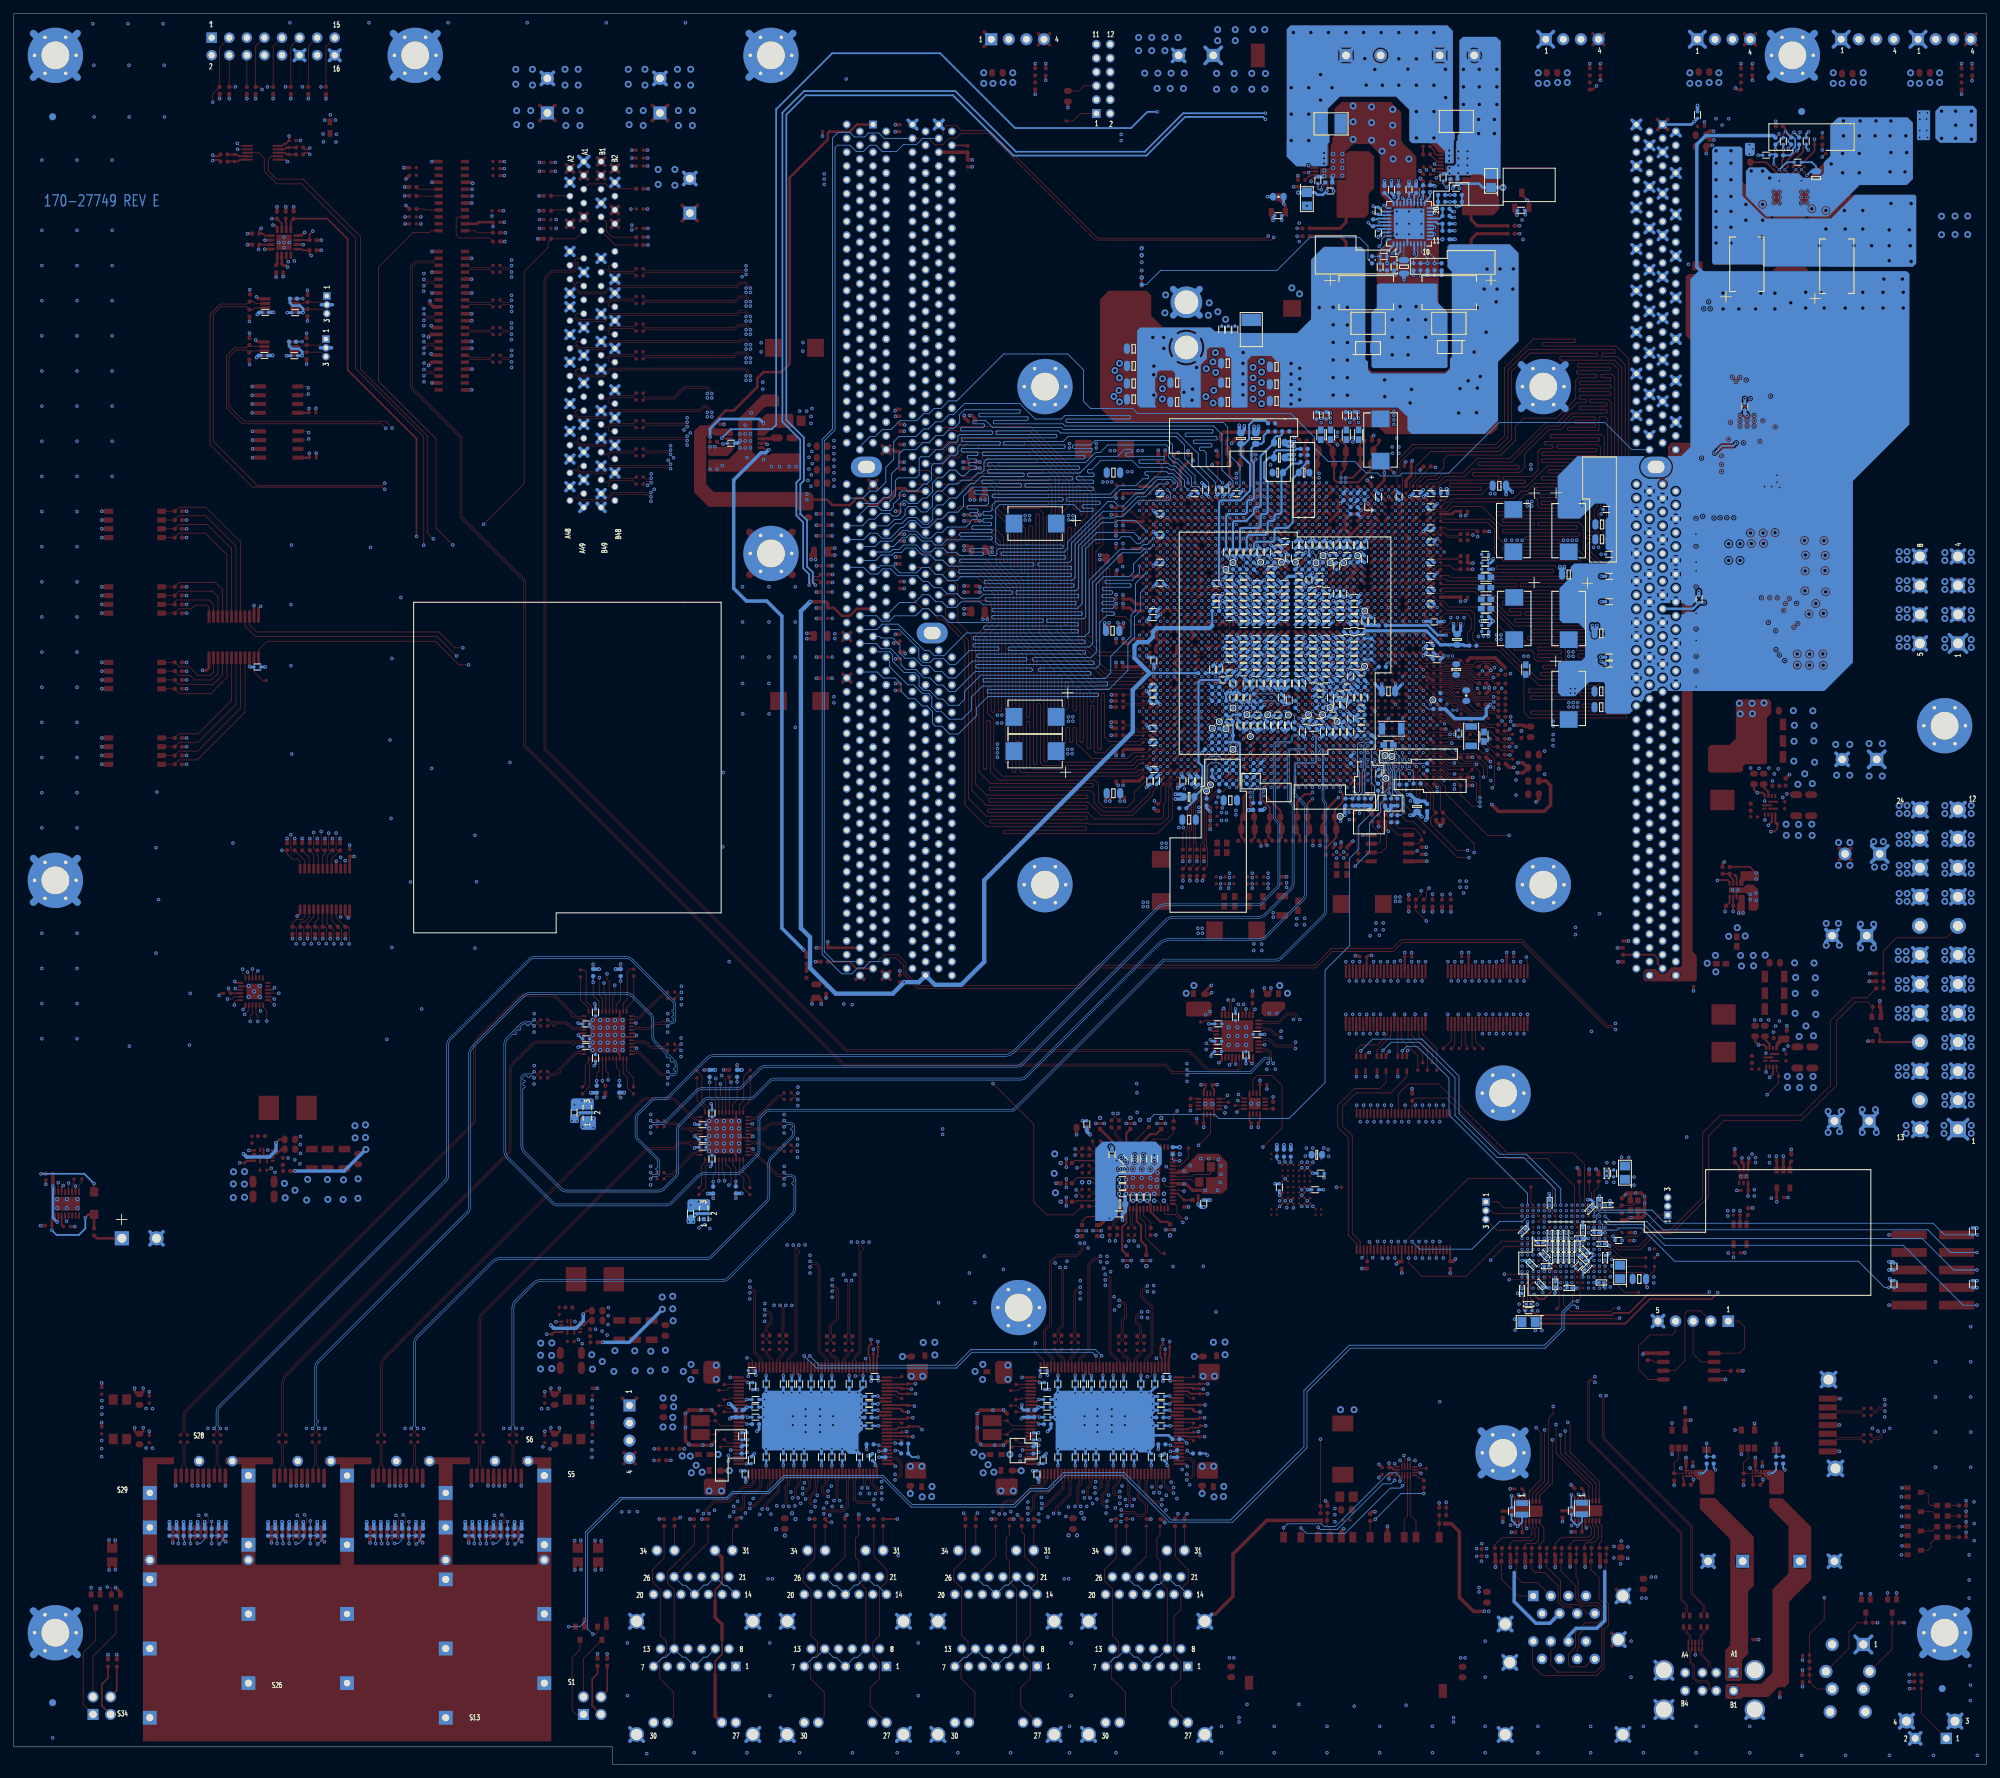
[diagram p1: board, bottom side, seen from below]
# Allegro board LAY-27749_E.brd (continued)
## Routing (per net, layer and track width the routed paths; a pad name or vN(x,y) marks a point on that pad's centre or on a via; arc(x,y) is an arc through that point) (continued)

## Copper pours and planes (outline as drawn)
1V2_SB on TOP: 36.2,75.77 37.44,75.77 37.57,75.64 37.57,73.36 37.21,73 36.32,73 36.12,73.2 36.12,75.69
1V2_SB on BOTTOM: 64.14,67.01 65.71,67.01 66.01,66.7 66.01,65.96 65.86,65.81 65.86,62.61 65.48,62.23 64.08,62.23 63.73,62.59 63.73,66.6
1V2_SB on L7_INT_3: 36.12,76.15 41.07,76.15 41.48,75.74 41.48,69.27 44.3,66.45 57.51,66.45 59.39,68.33 59.39,76.99 59.64,77.24 66.5,77.24 66.7,77.04 66.7,61.54 63.37,58.22 40.28,58.22 35.38,63.12 35.38,75.41
1V8_SB on TOP: 29.92,83.79 31.27,83.79 31.37,83.69 31.37,81.2 31.17,81 30.02,81 29.9,81.13 29.9,83.77
1V8_SB on L9_PWR_2: 30.07,82.75 37.31,82.75 42.42,77.65 49.4,77.65 53.06,81.31 67.34,81.31 67.61,81.03 67.61,74.32 61.54,68.25 54.31,68.25 53.06,69.49 33.53,69.49 29.08,73.94 29.08,81.76
2V5 on BOTTOM (solid shape): 203.15,93.41 203.15,91.95 202.9,91.69 201.09,91.69 200.89,91.9 200.89,93.47 201.06,93.65 202.91,93.65
2V5 on TOP: 244.17,96.65 244.17,92.15 243.89,91.87 243.31,91.87 243,91.57 243,88.67 242.77,88.44 236.3,88.44 235.66,87.81 233.93,87.81 233.6,88.14 233.6,92.66 233.86,92.91 239.27,92.91 240.18,93.83 240.18,96.52 240.61,96.95 243.87,96.95
2V5 on BOTTOM: 107.47,137.03 107.59,136.91 108.58,136.91 108.97,137.29 108.97,141.3 109.14,141.48 109.14,141.88 109.04,141.99 107.67,141.99 107.47,141.78
2V5 on BOTTOM: 186.08,79.07 184.24,79.07 184.06,78.9 184.06,77.32 184.26,77.12 186.07,77.12 186.28,77.33 186.28,78.87
2V5 on L7_INT_3: 106.15,155.57 109.37,155.57 109.91,155.04 109.91,147.29 108.99,146.38 108.99,127.03 114.48,121.54 114.48,114.07 116.81,111.73 116.81,96.93 114.6,94.72 114.6,93.6 115.54,92.66 126.09,92.66 127.2,93.78 132.61,93.78 135.23,91.16 135.23,81.1 132.99,78.87 124.17,78.87 120.65,75.35 108.6,75.35 105.26,78.69 105.26,95.99 108,98.73 108,119.18 101.9,125.27 101.9,140.61 101.85,140.67 101.85,154.38 102.18,154.71 105.28,154.71
2V5 on L10_INT_4: 240.97,107.87 240.97,78.69 232.69,70.41 132.97,70.41 131.78,71.6 131.78,88.14 133.53,89.89 168.3,89.89 193.95,115.54 233.3,115.54
3V3_SB on TOP: 33.38,84.33 34.57,84.33 34.7,84.2 34.7,81.94 34.39,81.64 33.32,81.64 33.12,81.84 33.12,84.07
3V3_SB on TOP: 36.22,77.44 37.29,77.44 37.62,77.77 37.62,80.14 37.44,80.31 36.3,80.31 36.17,80.19 36.17,77.5
3V3_SB on TOP: 195.2,223.52 198.75,223.52 199.01,223.27 199.01,221.74 198.75,221.49 194.94,221.49 194.82,221.62 194.82,223.14
3V3_SB on BOTTOM: 54.46,85.19 54.56,85.29 55.27,85.29 55.45,85.12 55.45,83.52 54.94,83.01 50.75,83.01 50.29,83.46 50.29,84.99 50.5,85.19
3V3_SB on BOTTOM: 47.73,71.15 49.2,71.15 49.58,70.76 49.58,68.91 49.28,68.61 47.9,68.61 47.55,68.96 47.55,70.97
3V3_SB on BOTTOM: 198.81,14.78 200.66,14.78 201.24,15.37 201.24,18.01 200.91,18.34 200.91,26.77 197.46,30.23 197.46,36.6 197.1,36.96 194.67,36.96 194.21,36.5 194.21,28.07 198.22,24.05 198.22,15.37
3V3_SB on L3_INT_1: 213.59,223.44 216.08,223.44 216.61,222.91 216.61,220.78 215.6,219.76 208.05,219.76 205.56,222.25 199.29,222.25 195.78,218.74 193.14,218.74 192.1,219.79 192.1,224.59 193.9,226.39 210.64,226.39
3V3_SB on L8_PWR_1: 183.57,231.62 204.29,231.62 205.94,229.97 205.94,205.41 210.54,200.81 218.03,200.81 220.18,202.96 220.18,234.2 222.17,236.19 278.29,236.19 280.62,233.87 280.62,142.42 274.04,135.84 274.04,96.29 281.53,88.8 281.53,28.83 273.71,21.01 273.71,12.62 272.97,11.89 269.09,11.89 268.3,12.67 268.3,22.33 272.52,26.54 272.52,40.89 266.85,46.56 209.85,46.56 198.65,35.36 21.46,35.36 13.61,27.51 3.81,27.51 1.09,30.23 1.09,83.72 3.45,86.08 60.02,86.08 79.93,66.17 123.56,66.17 130.44,59.29 148.64,59.29 170.38,81.03 217.04,81.03 225.15,89.13 225.15,149.99 208.79,166.34 188.16,166.34 182.73,171.78 182.73,230.78
5V0_SB on TOP: 34.57,85.62 33.27,85.62 32.94,85.95 32.94,88.21 33.27,88.54 34.37,88.54 34.62,88.29 34.62,85.67
5V0_SB on TOP: 30.05,85.37 31.24,85.37 31.6,85.72 31.6,88.14 31.37,88.37 30.2,88.37 29.92,88.09 29.92,85.5
5V0_SB on TOP, BOTTOM: 18.29,117.35 16.13,117.35 15.49,117.98 15.49,121.41 16.26,122.17 18.29,122.17 19.05,121.41 19.05,118.11
5V0_SB on TOP, L3_INT_1: 5.97,123.44 1.78,123.44 1.27,123.95 1.27,126.62 1.78,127.13 5.97,127.13 6.48,126.62 6.48,123.95
5V0_SB on BOTTOM: 1.27,126.62 1.78,127.13 6.1,127.13 6.53,126.7 6.53,123.57 6.02,123.06 1.91,123.06 1.27,123.7
5V0_SB on L5_INT_2: 5.97,123.44 1.78,123.44 1.27,123.95 1.27,126.62 1.78,127.13 5.97,127.13 6.48,126.62 6.48,123.95
5V0_SB on L10_INT_4: 1.6,127.3 20.17,127.3 24.21,123.27 24.21,116.56 24.05,116.41 24.05,105.18 38.15,91.08 38.15,76.96 19.08,57.89 19.08,20.45 17.91,19.28 12.01,19.28 11.15,20.14 11.15,62.38 25.2,76.43 25.2,85.88 14.17,96.9 14.17,117.81 13,118.97 7.39,118.97 7.37,118.95 2.26,118.95 1.24,119.96 1.24,126.95
5V0_SB on L14_INT_6: 5.97,123.44 1.78,123.44 1.27,123.95 1.27,126.62 1.78,127.13 5.97,127.13 6.5,126.59 6.5,123.98
12V0_2_VDD_FLT on TOP (solid shape): outline of 237 points within 76.81,231.02 101.07,251.33
12V0_2_VDD_FLT on BOTTOM (solid shape): outline of 225 points within 76.81,230.96 101.09,251.33
12V0_2_VDD_FLT on L5_INT_2: 93.73,239.83 92.52,241.03 85.26,241.03 83.36,239.13 83.36,234.69 82.77,234.11 80.29,234.11 79.09,232.91 78.46,232.91 78.2,232.66 78.2,231.52 78.08,231.39 77.06,231.39 76.93,231.52 76.93,234.69 76.81,234.82 76.81,235.83 77.06,236.09 77.06,250.52 77.86,251.33 100.54,251.33 101.07,250.8 101.07,226.95 88.09,213.97 83.74,213.97 83.44,214.27 83.44,215.82 83.77,216.15 87.05,216.15 93.73,222.83
12V0_FILTERED_PS_GVDD on TOP (solid shape): 22.53,236.89 22.53,232.44 26.03,228.94 26.44,228.94 26.64,229.14 26.64,229.32 26.82,229.5 27.25,229.5 27.35,229.39 27.35,228.25 27.22,228.12 25.83,228.12 25.32,227.62 23.67,227.62 23.41,227.87 21.51,227.87 21.13,228.25 11.48,228.25 10.59,229.14 10.59,237.27 11.35,238.03 21.38,238.03
12V0_FILTERED_PS_GVDD on TOP (solid shape): 34.72,230.28 34.72,228.76 34.59,228.63 34.12,228.63 34.01,228.67 33.89,228.68 33.67,228.68 33.55,228.67 33.44,228.63 32.94,228.63 32.43,228.12 29.51,228.12 29.26,228.38 29.26,229.39 29.38,229.52 30.65,229.52 31.92,230.79 34.21,230.79
12V0_FILTERED_PS_GVDD on BOTTOM (solid shape): outline of 530 points within 10.59,223.72 34.72,238.03
AVDD_PLAT on L12_INT_5: 95,156.46 95,155.07 94.49,154.56 88.9,154.56 87.88,153.54 87.88,140.34 87.38,139.83 83.44,139.83 82.68,140.59 82.68,141.35 83.19,141.86 84.96,141.86 85.72,142.62 85.72,156.08 86.49,156.84 94.61,156.84
GND on TOP (solid shape): 10,238.93 10,234.87 9.87,234.74 8.22,234.74 8.1,234.87 8.1,238.93 8.22,239.06 9.87,239.06
GND on TOP (solid shape): 35.03,126.75 37.11,126.75 37.19,126.67 37.19,126.11 37.01,125.93 34.75,125.93 34.34,125.53 34.34,123.49 34.21,123.37 33.22,123.37 32.89,123.7 32.89,126.39 33.63,127.13 34.65,127.13
GND on TOP (solid shape): 180.34,194.44 180.34,189.99 181.74,188.59 183.51,188.59 183.51,188.59 184.53,188.59 184.68,188.44 184.68,186.97 184.53,186.82 171.58,186.82 171.2,187.2 171.2,189.1 171.58,189.48 175.51,189.48 175.77,189.23 177.8,189.23 178.31,189.74 178.31,194.31 176.4,196.22 174.37,196.22 174.37,197.61 174.75,197.99 176.78,197.99
GND on TOP (solid shape): 27.35,227.62 27.35,225.96 25.7,224.31 25.7,219.23 22.9,216.43 10.59,216.43 10.08,216.94 10.08,226.6 10.33,226.85 22.53,226.85 22.64,226.82 22.74,226.81 22.97,226.81 23.08,226.82 23.19,226.85 23.54,226.85 23.8,227.11 25.45,227.11 26.21,227.87 27.1,227.87
GND on TOP (solid shape): 38.86,199.26 38.86,189.5 38.86,189.47 38.86,186.81 38.39,186.33 36.7,186.33 36.33,186.71 36.33,190.37 36.58,190.62 36.58,192.66 36.07,193.16 31.5,193.16 29.6,191.26 29.6,189.23 28.2,189.23 27.82,189.61 27.82,191.64 31.37,195.2 36.07,195.2 37.21,196.34 37.21,198.37 37.22,198.37 37.22,199.27 37.47,199.52 38.61,199.52
GND on TOP (solid shape): 39.59,233.38 39.59,217 39.37,216.77 32.38,216.77 31.16,217.99 31.16,224.06 29.26,225.96 29.26,227.74 29.38,227.87 30.91,227.87 31.03,227.74 33.35,227.74 33.5,227.67 33.67,227.64 33.89,227.64 34.13,227.69 34.31,227.85 34.32,227.85 35.23,228.76 35.23,233.52 35.51,233.81 39.17,233.81
GND on TOP (solid shape): 28.85,177.16 28.85,176.07 28.35,175.56 28.35,169.85 29.36,168.83 32.59,168.83 32.74,168.68 32.74,167.67 32.44,167.36 30.05,167.36 29.62,166.93 29.62,165.58 29.51,165.48 29.51,164.29 29.69,164.11 30.61,164.11 30.71,164.01 30.71,163.68 30.58,163.55 28.4,163.55 28.3,163.45 27.18,163.45 26.57,164.06 22.91,164.06 22.45,164.52 22.45,166.3 26.82,166.3 26.82,165.52 27.2,165.15 28.01,165.15 28.45,164.71 28.45,164.23 28.62,164.06 29.09,164.06 29.24,164.2 29.24,165.39 28.91,165.72 28.91,166.22 28.55,166.57 28.51,166.57 28.12,166.57 27.91,166.78 27.91,168.1 27.71,168.3 27.03,168.3 26.82,168.1 26.82,166.3 22.45,166.3 22.45,176.89 23.06,177.5 28.52,177.5
GND on TOP (solid shape): outline of 102 points within 70.15,229.57 78.13,249.67
GND on TOP (solid shape): outline of 1528 points within 77.89,201.88 96.24,240.27
GND on BOTTOM (solid shape): 10,238.93 10,234.87 9.87,234.74 8.22,234.74 8.1,234.87 8.1,238.93 8.22,239.06 9.87,239.06
GND on BOTTOM (solid shape): 88.05,213.75 88.05,210.55 88.82,209.79 88.82,202.04 88.56,201.79 78.02,201.79 77.83,201.98 77.83,209.85 79.29,211.31 79.29,213.91 79.4,214.02 87.78,214.02
GND on BOTTOM (solid shape): 186.94,79.4 187.4,79.4 187.78,79.02 187.78,78.26 187.63,78.11 186.66,78.11 186.54,78.23 186.54,79.02 186.21,79.35 184.48,79.35 184.4,79.43 184.4,79.76 184.45,79.81 186.54,79.81
GND on BOTTOM (solid shape): 203.77,93.98 204.23,93.98 204.61,93.6 204.61,92.83 204.46,92.68 203.49,92.68 203.37,92.81 203.37,93.6 203.03,93.93 201.31,93.93 201.23,94 201.23,94.33 201.28,94.38 203.37,94.38
GND on BOTTOM (solid shape): 134.75,53.47 134.75,49.81 134.47,49.53 134.47,45.47 134.34,45.34 122.68,45.34 122.4,45.06 121.01,45.06 120.14,45.92 120.14,49.4 120.4,49.66 120.4,50.55 120.14,50.8 120.14,53.21 120.9,53.98 134.24,53.98
GND on BOTTOM (solid shape): 39.59,233.4 39.59,217 39.37,216.77 32.38,216.77 32.07,216.46 22.93,216.46 22.9,216.43 10.59,216.43 10.11,216.92 10.11,226.63 10.33,226.85 18.97,226.85 22.4,223.42 31.93,223.42 35.23,226.72 35.23,233.52 35.51,233.81 39.19,233.81
GND on BOTTOM (solid shape): 176.91,53.47 176.91,49.36 176.87,49.26 176.86,49.15 176.87,49.04 176.91,48.94 176.91,45.72 176.53,45.34 164.85,45.34 164.34,44.83 163.45,44.83 162.94,45.34 162.94,47.75 162.31,48.39 162.31,49.4 162.56,49.66 162.56,50.55 162.31,50.8 162.31,53.37 162.92,53.98 176.4,53.98
GND on BOTTOM (solid shape): outline of 100 points within 70.15,229.16 77.88,249.67
GND on TOP: 128.78,192.41 131.95,192.41 132.84,191.52 132.84,189.1 131.83,188.09 128.91,188.09 127.89,189.1 127.89,191.52
GND on TOP: 53.8,30.91 51.84,30.91 51.49,31.27 51.49,32.36 51.79,32.66 53.7,32.66 54.05,32.31 54.05,31.17
GND on TOP: 50.42,26.42 50.67,26.67 50.67,27.69 50.42,27.94 47.75,27.94 47.37,27.56 47.37,26.8 47.75,26.42
GND on TOP: 185.78,227.46 191.9,227.46 192.79,228.35 192.79,231.9 191.9,232.79 186.11,232.79 186.11,232.77 185.34,232 185.34,227.89
GND on TOP: 21.59,129.41 19.43,129.41 18.92,129.92 18.92,133.35 19.3,133.73 21.59,133.73 21.97,133.35 21.97,129.79
GND on TOP: 130.33,36.63 132.41,36.63 132.54,36.5 132.54,35.23 132.38,35.08 130.18,35.08 130.07,35.18 130.07,36.37
GND on TOP: 108.58,129.03 111.51,129.03 111.76,128.78 111.76,128.14 111.51,127.89 108.58,127.89 108.33,128.14 108.33,128.78
GND on TOP: 1.45,59.5 11.55,59.5 12.48,58.57 12.48,42.33 14.42,40.38 14.42,29.46 11.37,26.41 11.37,16.42 13.69,14.1 13.69,3.32 12.49,2.13 2.73,2.13 0.89,3.96 0.89,58.93 ; 2 cut-outs
GND on TOP: 92.96,37.34 94.36,37.34 94.49,37.21 94.49,34.8 94.36,34.67 92.96,34.67 92.71,34.92 92.71,37.08
GND on TOP: 125.6,184.53 125.35,184.78 125.35,185.04 126.49,186.18 126.49,187.45 126.75,187.71 128.52,187.71 128.91,187.32 128.91,185.42 128.02,184.53
GND on TOP: 176.53,45.34 164.85,45.34 164.34,44.83 163.45,44.83 162.94,45.34 162.94,47.75 162.31,48.39 162.31,49.4 162.56,49.66 162.56,50.55 162.31,50.8 162.31,53.37 162.92,53.98 176.4,53.98 176.91,53.47 176.91,45.72
GND on TOP: 142.69,251.21 145.1,251.21 145.35,250.95 145.35,242.57 145.23,242.44 143.19,242.44 143.07,242.57 143.07,247.65 142.56,248.16 142.56,251.08
GND on TOP: 40.66,251.21 43.07,251.21 43.32,250.95 43.32,242.57 43.2,242.44 41.16,242.44 41.04,242.57 41.04,247.65 40.53,248.16 40.53,251.08
GND on TOP: 24.49,116.43 29.95,116.43 30.28,116.1 30.28,115.01 29.77,114.5 29.77,108.79 30.79,107.77 34.01,107.77 34.16,107.62 34.16,106.6 33.86,106.3 31.47,106.3 31.04,105.87 31.04,104.52 30.94,104.42 30.94,103.23 31.12,103.05 32.03,103.05 32.13,102.95 32.13,102.62 32.01,102.49 29.82,102.49 29.72,102.39 28.6,102.39 27.99,103 24.33,103 23.88,103.45 23.88,115.82 ; 1 cut-out
GND on TOP: 203.33,241.94 212.34,241.94 213.23,242.82 213.23,246.38 212.34,247.27 203.45,247.27 202.69,246.51 202.69,242.57
GND on TOP: 167.34,111.63 167.92,111.63 168.33,111.23 169.98,111.23 170.18,111.02 170.18,109.63 169.88,109.32 167.41,109.32 167.13,109.6 167.13,111.43
GND on TOP: 134.34,45.34 122.68,45.34 122.4,45.06 121.01,45.06 120.14,45.92 120.14,49.4 120.4,49.66 120.4,50.55 120.14,50.8 120.14,53.21 120.9,53.98 134.24,53.98 134.75,53.47 134.75,49.81 134.47,49.53 134.47,45.47
GND on TOP: 62.56,251.21 64.98,251.21 65.23,250.95 65.23,242.57 65.1,242.44 63.07,242.44 62.95,242.57 62.95,247.65 62.44,248.16 62.44,251.08
GND on TOP: 88.01,126.36 88.39,125.98 88.39,122.94 88.29,122.83 84.81,122.83 84.33,123.32 84.33,125.73 84.96,126.36
GND on TOP: 114.17,119.38 113.41,118.62 110.87,118.62 110.36,119.13 110.36,121.92 111,122.56 113.67,122.56 114.17,122.05
GND on TOP: 24.66,152.88 30.13,152.88 30.46,152.55 30.46,151.46 29.95,150.95 29.95,145.24 30.96,144.22 34.19,144.22 34.34,144.07 34.34,143.05 34.04,142.75 31.65,142.75 31.22,142.32 31.22,140.97 31.12,140.87 31.12,139.67 31.29,139.5 32.21,139.5 32.31,139.4 32.31,139.06 32.18,138.94 30,138.94 29.9,138.84 28.78,138.84 28.17,139.45 24.51,139.45 24.06,139.9 24.06,152.27 ; 1 cut-out
GND on TOP: 74.3,178.18 75.06,178.18 75.31,177.93 75.31,176.78 75.06,176.53 73.43,176.53 73.15,176.81 73.15,177.52 73.33,177.7 73.81,177.7
GND on TOP: 204.22,30.56 199.11,30.56 197.61,29.06 197.61,24.31 200.15,21.77 203.15,21.77 203.33,21.59 203.33,20.75 203.17,20.6 199.11,20.6 196.19,23.52 196.19,29.74 199.06,32.61 204.24,32.61 204.44,32.41 204.44,30.78
GND on TOP: 174.04,206.4 174.04,203.23 174.5,202.77 177.42,202.77 177.9,203.25 177.9,206.45 177.47,206.88 174.52,206.88
GND on TOP: 108.2,13.84 108.33,13.72 109.73,13.72 110.11,14.1 110.11,15.49 109.73,15.88 108.46,15.88 108.2,15.62
GND on TOP: 234.65,81.41 234.65,86.87 234.98,87.2 236.07,87.2 236.58,86.69 242.29,86.69 243.31,87.71 243.31,90.93 243.46,91.09 244.47,91.09 244.78,90.78 244.78,88.39 245.21,87.96 246.56,87.96 246.66,87.86 247.85,87.86 248.03,88.04 248.03,88.95 248.13,89.05 248.46,89.05 248.59,88.93 248.59,86.74 248.69,86.64 248.69,85.52 248.08,84.91 248.08,81.26 247.62,80.8 235.25,80.8 ; 1 cut-out
GND on TOP: 1.78,98.17 1.27,98.68 1.27,101.47 1.78,101.98 6.22,101.98 6.99,102.74 6.99,105.79 6.22,106.55 1.78,106.55 1.27,107.06 1.27,109.86 1.78,110.36 6.22,110.36 6.99,111.12 6.99,114.17 6.22,114.94 1.78,114.94 1.27,115.44 1.27,117.98 1.91,118.62 12.83,118.62 13.46,117.98 13.46,106.3 12.95,105.79 8.76,105.79 8.13,105.16 8.13,103.5 8.76,102.87 12.95,102.87 13.46,102.36 13.46,98.81 12.83,98.17
GND on TOP: 73.71,30.76 72.09,30.76 71.91,30.94 71.91,32.03 72.06,32.18 73.74,32.18 73.94,31.98 73.94,30.99
GND on TOP: 74.68,13.97 74.93,13.72 76.45,13.72 76.71,13.97 76.71,15.37 76.33,15.75 75.06,15.75 74.68,15.37
GND on TOP: 197.92,50.77 197.92,53.18 197.67,53.44 189.28,53.44 189.16,53.31 189.16,51.28 189.28,51.15 194.36,51.15 194.87,50.64 197.79,50.64
GND on TOP: 36.14,181.79 38.15,181.79 38.35,181.99 41.12,181.99 41.38,181.74 41.38,180.26 40.82,179.71 36.35,179.71 35.94,180.11 35.94,181.58
GND on TOP: 262.64,252.24 283.93,252.24 284.24,251.93 284.24,105.48 281.68,102.93 230.54,102.93 216.02,117.45 216.02,162.05 234.72,180.75 248.71,180.75 260.12,192.16 260.12,249.72 ; 3 cut-outs
GND on TOP: 19.88,251.21 22.29,251.21 22.73,250.77 22.73,242.76 22.42,242.44 20.39,242.44 20.32,242.51 20.32,247.59 19.75,248.16 19.75,251.08
GND on TOP: 40.01,213.41 40.74,213.41 40.94,213.21 40.94,211.91 41.12,211.73 41.12,210.13 41.02,210.03 39.73,210.03 39.6,210.16 39.6,210.57 39.83,210.79 39.83,213.23
GND on TOP: 187.2,241.94 196.22,241.94 197.1,242.82 197.1,246.38 196.22,247.27 187.32,247.27 186.56,246.51 186.56,242.57
GND on TOP: 20.19,94.61 20.7,95.12 23.37,95.12 23.85,94.64 23.85,91.29 23.24,90.68 20.7,90.68 20.19,91.19
GND on TOP: 169.77,180.7 171.09,180.7 171.3,180.9 178,180.9 182.09,176.81 182.09,152.43 180.85,151.18 173.76,151.18 173.15,151.79 173.15,157.28 170.97,159.46 170.97,177.7 169.62,179.04 169.62,180.54
GND on TOP: 168.68,191.06 170.15,191.06 170.79,190.42 170.79,184.86 170.33,184.4 168.76,184.4 168.45,184.71 168.45,190.83
GND on TOP: 100.71,123.44 100.71,121.79 100.84,121.67 103,121.67 103.25,121.92 103.25,123.44 102.87,123.83 101.09,123.83
GND on TOP: 107.06,127.89 103.5,127.89 103.25,128.14 103.25,128.78 103.5,129.03 106.93,129.03 107.31,128.65 107.31,128.14
GND on TOP: 190.25,56.64 190.25,62.1 190.58,62.43 191.67,62.43 192.18,61.93 197.89,61.93 198.78,62.82 198.78,66.19 198.91,66.32 200.28,66.32 200.38,66.22 200.38,63.63 200.81,63.2 202.16,63.2 202.26,63.1 203.45,63.1 203.63,63.27 203.63,64.19 203.73,64.29 204.06,64.29 204.19,64.16 204.19,61.98 204.29,61.88 204.29,60.76 203.68,60.15 203.68,56.49 203.23,56.03 190.86,56.03 ; 1 cut-out
GND on TOP: 99.19,214.86 118.59,214.86 119.33,214.12 119.33,209.02 118.59,208.28 111.68,208.28 111.02,207.62 108.23,207.62 107.98,207.87 103.63,207.87 102.54,208.97 99.01,208.97 98.65,209.32 98.65,214.33
GND on TOP: 8.76,251.21 11.18,251.21 11.43,250.95 11.43,242.57 11.3,242.44 9.27,242.44 9.14,242.57 9.14,247.65 8.64,248.16 8.64,251.08
GND on TOP: 171.98,36.63 174.07,36.63 174.19,36.5 174.19,35.23 174.04,35.08 171.83,35.08 171.73,35.18 171.73,36.37
GND on TOP: 117.47,125.6 117.47,123.44 117.86,123.06 121.54,123.06 122.17,123.7 122.17,125.22 121.28,126.11 117.98,126.11
GND on TOP: 71.37,24.51 73.41,24.51 73.79,24.89 73.79,25.65 73.41,26.04 71.37,26.04 71.12,25.78 71.12,24.77
GND on TOP, BOTTOM: 22.12,142.32 19.33,142.32 18.95,142.7 18.95,147.78 19.33,148.16 22,148.16 22.5,147.65 22.5,142.7
GND on TOP, BOTTOM: 1.65,159.77 0.89,160.53 0.89,176.15 1.52,176.78 5.97,176.78 6.6,176.15 6.6,160.53 5.84,159.77
GND on TOP, BOTTOM: 115.24,250.44 115.24,242.04 115.8,241.48 123.32,241.48 124.18,242.34 124.18,250.47 123.34,251.31 116.1,251.31
GND on TOP, BOTTOM: 23.37,117.73 21.08,117.73 20.57,118.24 20.57,121.67 21.08,122.17 23.5,122.17 24,121.67 24,118.36
GND on TOP, L14_INT_6: 6.99,136.53 6.99,139.19 7.49,139.7 12.57,139.7 13.21,139.06 13.21,136.65 12.57,136.02 7.49,136.02
GND on BOTTOM: 70.74,164.08 71.25,163.58 71.25,161.8 70.76,161.32 66.52,161.32 66.29,161.54 66.29,163.58 66.8,164.08
GND on BOTTOM: 180.11,93.85 184.51,93.85 185.27,93.09 185.27,88.34 184.66,87.73 180.49,87.73 179.76,88.47 179.76,93.5
GND on BOTTOM: 14.04,63.83 16.57,66.36 54.45,66.36 62.88,57.92 73.09,57.92 76.46,54.55 76.46,42.74 74.14,40.42 63.64,40.42 62.04,42.02 54.83,42.02 45.46,32.66 45.46,25.95 44.16,24.65 31.25,24.65 28.26,21.65 28.26,3.6 26.74,2.08 4.05,2.08 0.84,5.29 0.84,61.8 2.87,63.83 3.54,63.83
GND on BOTTOM: 66.22,66.85 66.22,66.01 66.37,65.86 66.37,62.79 66.73,62.43 68.38,62.43 68.55,62.61 68.55,66.55 68.02,67.08 66.45,67.08
GND on BOTTOM: 115.44,137.29 115.44,135.38 115.82,135 116.71,135 116.97,135.25 116.97,137.29 116.71,137.54 115.7,137.54
GND on BOTTOM: 6.99,136.53 6.99,139.19 7.49,139.7 12.57,139.7 13.21,139.06 13.21,136.65 12.57,136.02 7.49,136.02
GND on BOTTOM: 171.65,252.19 281.69,252.19 283.88,249.99 283.88,8.41 280.6,5.12 270.3,5.12 268.62,6.8 268.62,39.45 262.04,46.03 262.04,52.35 231.67,82.72 231.5,82.72 229.82,84.41 229.82,108.53 216.15,122.2 181.69,122.2 177.98,125.91 177.98,164.12 186.42,172.56 186.42,195 184.77,196.64 178.11,196.64 176.29,198.45 176.29,236.41 176.29,239.62 170.68,245.23 170.68,251.22
GND on BOTTOM: 195.94,108.38 201.68,108.38 202.08,107.98 202.08,102.74 201.6,102.26 196.29,102.26 195.71,102.84 195.71,108.15
GND on BOTTOM: 99.19,214.86 118.64,214.86 119.3,214.2 119.3,208.99 118.59,208.28 111.68,208.28 111.02,207.62 108.23,207.62 107.98,207.87 103.63,207.87 102.54,208.97 99.39,208.97 98.65,209.7 98.65,214.33
GND on BOTTOM: 76.07,160.53 77.72,160.53 77.98,160.27 77.98,159 77.47,158.5 75.95,158.5 75.69,158.75 75.69,160.15
GND on BOTTOM: 85.09,192.91 85.47,192.53 88.9,192.53 89.41,193.04 89.41,195.45 89,195.86 85.37,195.86 85.09,195.58
GND on BOTTOM: 103.4,203.35 106.02,203.35 106.53,202.84 106.53,196.34 106.3,196.11 103.28,196.11 103.07,196.32 103.07,203.02
GND on BOTTOM: 62.23,174.5 61.72,173.99 55.37,173.99 54.61,174.75 54.61,175.01 54.86,175.26 55.37,175.26 55.75,175.64 55.75,176.3 56.03,176.58 56.03,179.68 54.99,180.72 54.99,181.48 55.24,181.74 55.88,181.74 58.42,179.2 61.59,179.2 62.23,178.56
GND on BOTTOM: 109.47,140.72 109.47,138.3 109.86,137.92 111.12,137.92 111.57,138.37 111.57,140.89 111.4,141.06 109.82,141.06
GND on BOTTOM: 86.02,240.27 93.13,240.27 94.15,239.25 94.15,235.44 94.44,235.16 94.44,234.42 94.72,234.14 94.72,230.91 94.95,230.68 96.19,230.68 96.24,230.63 96.24,229.26 96.19,229.21 92.71,229.21 92.61,229.31 92.61,233.02 91.45,234.17 89.07,234.17 87.17,232.27 87.17,230.91 82.34,230.91 82.34,232.4 84.5,234.56 84.5,238.75
GND on BOTTOM: 127.97,187.58 126.77,187.58 126.62,187.43 126.62,186.18 126.09,185.65 126.09,185.19 126.24,185.04 127.76,185.04 128.14,185.42 128.14,187.4
GND on BOTTOM: 138.68,153.29 142.75,153.29 143.26,152.78 143.26,144.91 142.62,144.27 138.81,144.27 138.18,144.91 138.18,152.78
GND on BOTTOM: 97.08,187.58 98.04,187.58 98.25,187.38 98.25,186.16 98.63,185.78 98.63,183.82 98.45,183.64 96.27,183.64 95.89,184.02 95.89,185.17 96.19,185.47 96.57,185.47 96.77,185.67 96.77,187.27
GND on BOTTOM: 85.34,148.59 84.73,148.59 84.53,148.39 84.53,148.06 84.43,147.96 82.93,147.96 82.68,148.21 82.68,149.48 82.93,149.73 83.44,149.73 83.69,149.99 83.69,150.5 83.95,150.75 85.22,150.75 85.47,150.5 85.47,148.72
GND on BOTTOM: 61.59,163.83 58.8,163.83 58.55,163.58 58.55,160.53 59.18,159.89 60.96,159.89 61.75,160.68 61.75,163.68
GND on BOTTOM: 57.71,149.81 56.13,151.38 56.13,155.63 56.39,155.88 56.95,155.88 59.08,153.75 61.42,153.75 61.77,153.39 61.77,150.01 61.57,149.81
GND on BOTTOM: 142.24,180.59 142.24,178.18 141.86,177.8 138.3,177.8 137.79,178.31 137.79,180.59 138.3,181.1 141.73,181.1
GND on BOTTOM: 77.47,146.81 76.96,146.3 73.81,146.3 73.56,146.56 73.56,148.13 74.14,148.72 76.33,148.72 76.71,149.1 76.96,149.1 77.09,148.97 77.09,148.59 77.47,148.21
GND on BOTTOM: 106.1,107.87 110.29,107.87 110.85,107.31 110.85,102.87 110.59,102.62 106.02,102.62 105.54,103.1 105.54,107.31
GND on BOTTOM: 102.92,188.06 103.73,188.06 103.89,187.91 103.89,186.39 103.56,186.06 103.56,184.07 103.38,183.9 102.87,183.9 102.74,184.02 102.74,186.11 102.67,186.18 102.67,187.81
GND on BOTTOM: 127.64,138.81 126.62,138.81 126.36,139.06 126.36,140.97 126.62,141.22 127.64,141.22 127.89,140.97 127.89,139.06
GND on BOTTOM: 94.93,89.33 96.24,89.33 96.42,89.15 96.42,87.6 96.22,87.4 94.87,87.4 94.65,87.62 94.65,89.06
GND on BOTTOM: 117.7,201.24 119.43,201.24 119.86,200.81 119.86,196.47 119.51,196.11 117.68,196.11 117.42,196.37 117.42,200.96
GND on BOTTOM: 66.93,177.29 69.6,177.29 70.1,176.78 70.1,174.37 69.72,173.99 66.67,173.99 66.29,174.37 66.29,176.66
GND on BOTTOM: 2.21,251.58 65.08,251.58 68.79,247.87 68.79,221.08 65.58,217.88 65.58,205.92 68.7,202.8 68.7,196.05 67.14,194.49 53.91,194.49 51.23,191.81 51.23,191.7 45.2,191.7 44.02,192.88 44.02,233.54 40.9,236.66 26.27,236.66 22.89,240.03 7.48,240.03 6.74,240.77 1.8,240.77 1.21,241.36 1.21,250.58
GND on BOTTOM: 124.13,205.54 126.64,205.54 126.95,205.23 126.95,197.23 126.24,196.52 123.95,196.52 123.72,196.75 123.72,205.13
GND on BOTTOM: 76.86,154.15 79.25,154.15 79.48,153.92 79.48,153.38 79.57,153.29 79.57,153.1 79.43,152.96 78.03,152.96 77.09,152.02 76.33,152.02 76.17,152.17 76.17,153.47
GND on BOTTOM: 110.34,204.57 112.17,204.57 112.39,204.34 112.39,203.07 113.28,202.18 113.28,196.34 113.03,196.09 110.36,196.09 110.13,196.32 110.13,204.37
GND on BOTTOM: 1.78,98.17 1.27,98.68 1.27,101.47 1.78,101.98 6.22,101.98 6.99,102.74 6.99,105.79 6.22,106.55 1.78,106.55 1.27,107.06 1.27,109.86 1.78,110.36 6.22,110.36 6.99,111.12 6.99,114.17 6.22,114.94 1.78,114.94 1.27,115.44 1.27,117.98 1.91,118.62 12.83,118.62 13.46,117.98 13.46,99.19 12.45,98.17
GND on BOTTOM: 20.19,94.61 20.7,95.12 23.37,95.12 23.88,94.61 23.88,91.31 23.24,90.68 20.7,90.68 20.19,91.19
GND on BOTTOM: 50.95,85.78 53.37,85.78 53.52,85.62 54.41,85.62 54.53,85.5 55.24,85.5 55.4,85.65 55.4,87.68 54.91,88.16 51,88.16 50.6,87.76 50.6,86.13
GND on L2_GND_1: 1.19,252.24 283.93,252.24 284.24,251.93 284.24,3.72 283.78,3.26 268.17,3.26 267.72,3.71 267.72,23.47 269.09,24.84 270.48,26.24 271.37,26.24 272.16,27.03 272.16,30.28 271.58,30.86 200.69,30.86 195.41,25.59 195.41,7.58 192.71,4.88 115.06,4.88 110.11,9.83 110.11,14.13 109.7,13.72 74.45,13.72 74.04,14.13 74.04,23.5 74.01,23.64 73.93,23.76 73.29,24.4 73.17,24.48 73.03,24.51 69.85,24.51 69.7,24.48 69.58,24.4 66.66,21.48 66.58,21.35 66.55,21.21 66.55,14.13 64.87,12.45 56.67,12.45 55.14,13.98 55.14,19.43 54.48,20.09 54.48,25.81 53.99,26.3 53.87,26.39 53.72,26.42 48.84,26.42 48.84,26.39 48.11,25.65 48.11,18.8 46.61,17.3 44.43,15.13 44.35,15 44.32,14.86 44.32,9.17 43.15,8 36.99,8 35.69,9.3 35.69,14.99 35.66,15.13 35.58,15.26 34.69,16.14 34.56,16.23 34.42,16.26 32.13,16.26 31.99,16.23 31.86,16.14 30.85,15.13 30.76,15 30.73,14.86 30.73,1.49 30.01,0.76 1.3,0.76 0.76,1.3 0.76,251.81 ; 7 cut-outs
GND on L3_INT_1: 216.71,47.43 216.71,54.1 231.96,69.34 231.96,124.6 227.15,129.4 209.86,129.4 186.49,106.04 186.49,100.72 189.36,97.86 189.62,97.86 189.62,80.81 188.46,79.65 176.29,79.65 171.01,84.93 135.58,84.93 132.5,81.85 132.5,76.45 129.5,73.46 112.4,73.46 100.13,61.18 66.85,61.18 63.52,57.85 63.52,45.11 67.86,40.77 75.45,40.77 80.64,45.96 112.4,45.96 113.67,47.22 113.67,56.8 118.14,61.27 181.15,61.27 184.95,65.06 184.95,69.2 187.56,71.81 199.29,71.81 203.12,67.97 203.12,46.16 204.64,44.64 213.87,44.64 216.66,47.43
GND on L3_INT_1: 262.64,252.24 283.93,252.24 284.24,251.93 284.24,116.38 281.87,114.02 264.54,114.02 249.32,129.24 242.18,129.24 238.16,133.26 238.16,178.64 240.27,180.75 240.27,185.45 248.06,193.24 248.06,210.81 249.79,212.53 254.43,212.53 260.12,218.23 260.12,249.72
GND on L3_INT_1: 1.74,239.75 19.54,239.75 21.69,237.59 21.69,230.51 23.97,228.23 28.37,228.23 32.04,231.9 32.04,232.96 34.62,235.53 39.95,235.53 41.15,234.33 41.15,209.65 32.95,201.45 32.95,196.81 33.46,196.3 34.78,196.3 35.92,197.44 35.92,200.97 42.8,207.84 42.8,234.75 44.02,235.97 54.4,235.97 57.6,232.77 57.6,196.22 50.68,189.31 43.56,189.31 43.09,188.84 43.09,137.91 38.2,133.02 25.51,133.02 22.52,136 7.47,136 7,136.47 7,136.51 6.99,136.53 6.99,139.32 6.1,140.21 1.88,140.21 0.88,141.21 0.88,238.89
GND on L3_INT_1: 175.08,230.85 187.97,230.85 188.56,231.44 192.29,231.44 192.78,230.95 192.78,227.15 191.11,225.49 191.11,218.95 192.17,217.9 219.71,217.9 222.51,215.09 222.51,195.1 207.67,180.26 207.67,155.46 197.95,145.74 175.81,145.74 173.59,147.96 173.59,170.64 171.82,172.41 171.82,177.3 173.97,179.45 173.97,229.78 175.03,230.85
GND on L3_INT_1, L7_INT_3, L14_INT_6: 1.45,59.5 11.55,59.5 12.48,58.57 12.48,42.33 14.42,40.38 14.42,29.46 11.37,26.41 11.37,16.42 13.69,14.1 13.69,3.32 12.49,2.13 2.73,2.13 0.89,3.96 0.89,58.93 ; 1 cut-out
GND on L4_GND_2: 1.19,252.24 283.93,252.24 284.24,251.93 284.24,3.72 283.78,3.26 268.17,3.26 267.72,3.71 267.72,23.47 269.09,24.84 270.48,26.24 271.37,26.24 272.16,27.03 272.16,30.28 271.58,30.86 200.69,30.86 195.41,25.59 195.41,7.58 192.71,4.88 115.06,4.88 110.11,9.83 110.11,14.13 109.7,13.72 74.45,13.72 74.04,14.13 74.04,23.5 74.01,23.64 73.93,23.76 73.29,24.4 73.17,24.48 73.03,24.51 69.85,24.51 69.7,24.48 69.58,24.4 66.66,21.48 66.58,21.35 66.55,21.21 66.55,14.13 64.87,12.45 56.67,12.45 55.14,13.98 55.14,19.43 54.48,20.09 54.48,25.81 53.99,26.3 53.87,26.39 53.72,26.42 48.84,26.42 48.84,26.39 48.11,25.65 48.11,18.8 46.61,17.3 44.43,15.13 44.35,15 44.32,14.86 44.32,9.17 43.15,8 36.99,8 35.69,9.3 35.69,14.99 35.66,15.13 35.58,15.26 34.69,16.14 34.56,16.23 34.42,16.26 32.13,16.26 31.99,16.23 31.86,16.14 30.85,15.13 30.76,15 30.73,14.86 30.73,1.49 30.01,0.76 1.3,0.76 0.76,1.3 0.76,251.81 ; 8 cut-outs
GND on L5_INT_2: 2.49,83.63 28.97,83.63 30.58,82.01 30.58,63.89 36.59,57.88 52.66,57.88 56.58,53.95 56.58,44.42 64.95,36.05 92.03,36.05 98,42.02 107.83,42.02 109.01,40.84 109.01,37.46 110.13,36.35 110.13,14.14 109.69,13.7 74.45,13.7 73.92,14.23 73.92,23.51 72.99,24.44 69.7,24.44 66.63,21.37 66.63,14.1 64.96,12.43 56.66,12.43 55.12,13.96 55.12,19.36 55.12,19.42 54.47,20.07 54.47,25.6 54.48,25.61 54.48,25.72 53.86,26.34 48.68,26.34 48,25.66 48,18.55 44.18,14.73 44.18,8.95 43.23,8.01 36.84,8.01 35.62,9.23 35.62,15.07 34.59,16.1 31.42,16.1 30.5,15.18 30.5,1.33 29.93,0.76 1.36,0.76 0.79,1.33 0.79,81.93
GND on L5_INT_2: 6.99,136.53 6.99,139.32 6.1,140.21 1.91,140.21 0.89,141.22 0.89,249.19 2.77,251.07 67.26,251.07 68.14,250.19 68.14,242.47 67.26,241.59 24.58,241.59 21.75,238.76 21.75,224.53 25.1,221.17 25.1,168.85 26.49,167.46 26.49,144.24 27.74,143 27.74,139.77 23.98,136.02 7.49,136.02
GND on L5_INT_2: 201.66,113.19 235.63,113.19 237.91,110.91 237.91,78.5 214.92,55.51 214.92,46.78 212.52,44.38 212.52,36.96 211.46,35.9 202.59,35.9 190.72,47.76 181.55,47.76 180.56,48.76 180.56,79.29 185.41,84.14 189.15,84.14 201.11,96.1 201.11,99.54 199.47,101.18 197.26,101.18 196.42,102.02 196.42,107.94
GND on L5_INT_2: 183.4,252.22 283.92,252.22 284.22,251.92 284.22,45.35 280.93,42.06 264.44,42.06 255.54,50.96 255.54,76.77 258.2,79.43 258.2,124.56 227.62,155.13 227.62,223.84 222.05,229.41 218.8,229.41 217.66,228.27 217.66,224.05 219.9,221.81 219.9,199.59 222.83,196.66 222.83,150.71 227.05,146.49 227.05,130.88 225.36,129.2 192.89,129.2 184.2,120.51 158.96,120.51 157.06,122.41 157.06,163.65 157.8,164.39 157.8,184.31 159.35,185.86 163.93,185.86 167.91,189.84 183.54,189.84 190.52,182.86 193.27,182.86 194.91,184.5 194.91,216.98 182.01,229.88 182.01,250.83
GND on L5_INT_2, L14_INT_6: 1.78,98.17 1.27,98.68 1.27,101.47 1.78,101.98 6.22,101.98 6.99,102.74 6.99,105.79 6.22,106.55 1.78,106.55 1.27,107.06 1.27,109.86 1.78,110.36 6.22,110.36 6.99,111.12 6.99,114.17 6.22,114.94 1.78,114.94 1.27,115.44 1.27,117.98 1.91,118.62 12.83,118.62 13.46,117.98 13.46,98.81 12.83,98.17
GND on L6_GND_3, L11_GND_4, L13_GND_5, L15_GND_6: 1.19,252.24 283.93,252.24 284.24,251.93 284.24,3.72 283.78,3.26 268.17,3.26 267.72,3.71 267.72,23.47 269.09,24.84 270.48,26.24 271.37,26.24 272.16,27.03 272.16,30.28 271.58,30.86 200.69,30.86 195.41,25.59 195.41,7.58 192.71,4.88 115.06,4.88 110.11,9.83 110.11,14.13 109.7,13.72 74.45,13.72 74.04,14.13 74.04,23.5 74.01,23.64 73.93,23.76 73.29,24.4 73.17,24.48 73.03,24.51 69.85,24.51 69.7,24.48 69.58,24.4 66.66,21.48 66.58,21.35 66.55,21.21 66.55,14.13 64.87,12.45 56.67,12.45 55.14,13.98 55.14,19.43 54.48,20.09 54.48,25.81 53.99,26.3 53.87,26.39 53.72,26.42 48.84,26.42 48.84,26.39 48.11,25.65 48.11,18.8 46.61,17.3 44.43,15.13 44.35,15 44.32,14.86 44.32,9.17 43.15,8 36.99,8 35.69,9.3 35.69,14.99 35.66,15.13 35.58,15.26 34.69,16.14 34.56,16.23 34.42,16.26 32.13,16.26 31.99,16.23 31.86,16.14 30.85,15.13 30.76,15 30.73,14.86 30.73,1.49 30.01,0.76 1.3,0.76 0.76,1.3 0.76,251.81 ; 7 cut-outs
GND on L7_INT_3: 31.88,185.6 61.73,185.6 67.48,191.35 67.48,203.96 65.69,205.75 65.69,218.03 64.12,219.6 45.37,219.6 30.02,204.25 30.02,187.47
GND on L7_INT_3: 216.03,252.09 283.3,252.09 284.19,251.21 284.19,65.42 278.07,59.3 266.26,59.3 262.55,63.02 262.55,83.43 258.76,87.22 248.34,87.22 246.53,85.41 246.53,81.45 239.19,74.11 200.6,74.11 189.84,63.35 153.06,63.35 144.08,72.34 144.08,95.87 120.93,119.03 120.93,133.64 122.76,135.47 125.5,135.47 125.54,135.43 126.94,135.43 132.04,140.54 154.14,140.54 157.11,143.51 157.11,191.25 158.19,192.33 158.19,234.63 159.37,235.81 179.11,235.81 182.42,232.5 208.48,232.5 209.6,231.39 209.6,201.8 211.96,199.44 217.95,199.44 220.57,202.05 220.57,237.14 214.49,243.22 214.49,250.56
GND on L8_PWR_1: 80.26,222.47 109.76,222.47 115.54,228.25 115.54,247.63 119.86,251.94 282.2,251.94 283.43,250.71 283.43,239.81 280.58,236.96 222.06,236.96 219.6,234.5 219.6,203.33 217.51,201.24 210.65,201.24 206.46,205.43 206.46,230.29 204.57,232.19 183.42,232.19 179.56,236.04 158.31,236.04 156.04,233.77 156.04,142.91 154.23,141.1 132.77,141.1 127.7,136.03 118.28,136.03 114.5,139.81 109.72,139.81 107.86,141.67 107.86,174.97 114.57,181.67 114.57,189.8 121.58,196.82 121.58,207.24 120.56,208.26 99.33,208.26 97.67,206.61 97.67,195.95 98.25,195.37 98.25,195.37 98.6,195.02 98.6,178.05 94.25,173.7 91.37,173.7 90.71,174.36 90.71,186.73 78.64,198.81 78.64,220.84
GND on L8_PWR_1: 185.55,162.5 208.16,162.5 220.81,149.85 220.81,91.06 212.63,82.87 169.46,82.87 146.72,60.13 132.37,60.13 129.78,62.73 129.78,69.37 138.37,77.96 138.37,99.97 142.45,104.05 168.34,104.05 183.11,118.81 183.11,160.06
GND on L10_INT_4: 282.45,252.17 284.12,250.5 284.12,56.49 272.9,45.27 254,45.27 252.57,46.71 205.76,46.71 203.73,48.73 203.73,66.87 205.42,68.55 234.73,68.55 242.07,75.89 242.07,109.09 234.58,116.57 234.58,154.87 267.73,188.02 267.73,226.32 255.92,238.13 237.11,238.13 237.11,238.11 236.27,237.27 236.27,232.13 238.47,229.94 244.75,229.94 246.52,228.17 246.52,206.15 189.86,149.49 177.88,149.49 173.75,153.62 173.75,191.92 175.52,193.69 175.52,216.13 179.82,220.43 214.49,220.43 218.62,224.56 218.62,249.61 221.18,252.17
GND on L10_INT_4: 58.77,132.01 66.58,132.01 68.31,130.28 68.31,126.1 86.74,107.67 109.01,107.67 110.04,106.64 110.04,100.73 99.54,90.24 99.54,71.59 87.9,59.95 66.81,59.95 62,64.76 62,74.29 61.43,74.86 53.74,74.86 52.93,75.66 52.93,98.12 47.2,103.86 47.2,109.8 52.18,114.78 52.18,125.41
GND on L10_INT_4: 3.78,220.24 60.36,220.24 65.67,214.93 65.67,205.14 68.29,202.53 68.29,196.12 61.67,189.49 61.67,173.22 57.3,168.86 48.95,168.86 48.79,169.01 43.87,169.01 36.6,161.75 36.6,143.79 20.92,128.11 8.74,128.11 6.27,130.58 1.09,130.58 0.72,130.95 0.72,217.18
GND on L12_INT_5: 280.5,77.42 281.22,76.7 281.22,36.04 276.58,31.4 196.83,31.4 194.4,33.83 194.4,37.31 189.26,42.45 189.26,56.5 191.2,58.44 203.26,58.44 205.79,55.91 211.95,55.91 221.48,65.44 247.12,65.44 259.1,77.42 261.52,77.42
GND on L12_INT_5: 67.29,64.86 101.98,64.86 105.94,60.9 105.94,35.59 110.1,31.43 110.1,14.05 109.69,13.64 74.43,13.64 73.98,14.08 73.98,23.68 73.18,24.48 69.68,24.48 66.56,21.36 66.56,14.13 64.87,12.45 56.65,12.45 55.12,13.97 55.12,19.4 54.49,20.04 54.49,25.77 53.86,26.4 48.72,26.4 48.02,25.7 48.02,18.63 44.1,14.71 44.1,8.93 43.17,8 36.92,8 35.61,9.32 35.61,14.45 35.62,14.46 35.62,15.12 34.59,16.15 31.44,16.15 30.43,15.14 30.43,1.4 29.8,0.78 1.3,0.78 0.77,1.3 0.77,78.06 3.03,80.31 7.88,80.31 10.28,77.91 10.28,32.17 11.08,31.37 11.08,15.68 9.82,14.41 9.82,11.55 10.79,10.58 14.12,10.58 15.43,11.88 15.43,17.41 15.39,17.45 15.39,19.18 19.31,23.1 32.05,23.1 66.38,57.43 66.38,63.95
GND on L12_INT_5: 168.58,232.75 195.79,232.75 196.91,231.63 196.91,221.53 198.49,219.95 205.57,219.95 206.75,218.77 206.75,192.2 212.11,186.84 230.92,186.84 242.98,198.9 242.98,205.65 240.96,207.68 239.44,207.68 237.78,206.01 237.78,198.71 231.49,192.43 213.99,192.43 209.6,196.82 209.6,224.17 211.33,225.9 259.26,225.9 262.3,228.93 262.3,248.8 265.46,251.96 281.79,251.96 283.98,249.77 283.98,84.44 279.34,79.8 260.15,79.8 256.1,83.85 256.1,87.6 253.49,90.21 248.97,90.21 246.82,88.06 246.82,78.03 241.55,72.75 181.32,72.75 173.39,80.68 165.13,80.68 148.59,97.22 148.59,107.84 152.64,111.89 162.85,111.89 167.41,116.45 167.41,160.31 165.34,162.38 155.98,162.38 155.05,163.31 155.05,200 157.87,202.83 165.09,202.83 167.36,205.1 167.36,231.53
GND on L14_INT_6: 186.33,252.33 281.94,252.33 283.97,250.31 283.97,43.47 271.76,31.27 197.8,31.27 197.15,31.92 197.15,38.08 192.3,42.93 188.16,42.93 180.7,50.39 180.7,69.84 196.64,85.78 196.64,109.9 190.99,115.56 187.36,115.56 180.36,108.55 159.53,108.55 157.42,110.66 157.42,151.53 158.68,152.8 161.7,152.8 161.72,152.78 163.79,152.78 167.33,156.32 167.33,162.86 169.1,164.63 179.1,164.63 195.33,180.87 195.33,219.75 184.2,230.89 184.2,250.2
P1V8_AVDD on BOTTOM: 90.63,184.61 83.85,184.61 83.41,185.04 73.66,185.04 71.88,186.82 65.66,186.82 65.41,187.07 65.41,188.32 65.79,188.7 72.54,188.7 74.88,186.36 84,186.36 84.45,185.9 87.73,185.9 88.19,186.36 90.17,186.36 91.59,187.78 95.17,187.78 97.31,189.92 97.31,191.49 100,194.18 102.87,194.18 103.12,193.93 103.12,192.53 103,192.41 102.62,192.41 102.36,192.66 102.36,192.91 102.11,193.17 101.47,193.17 101.22,192.91 101.22,192.66 100.84,192.28 99.69,192.28 98.42,191.01 98.42,189.92 98.73,189.61 99.26,189.61 99.4,189.47 99.4,188.99 99.26,188.85 97.92,188.85 95.5,186.44 92.46,186.44
P1V8_AVDD on BOTTOM: 72.52,162.18 73.66,162.18 74.04,161.8 74.04,160.02 73,158.98 68.17,158.98 67.61,158.42 66.09,158.42 65.86,158.65 65.86,160.76 66.14,161.04 71.37,161.04
P1V8_AVDD on BOTTOM: 116.46,138.79 118.08,138.79 118.69,138.18 118.69,134.34 118.06,133.71 118.06,127.13 117.17,126.24 115.95,126.24 115.82,126.36 115.82,126.97 116.05,127.2 116.61,127.2 116.94,127.53 116.94,134.37 117.53,134.95 117.53,137.46 117.14,137.85 116.41,137.85 116.31,137.95 116.31,138.63
P1V8_AVDD on L3_INT_1: 80.64,136.83 81.38,136.83 85.62,132.59 93.09,132.59 99.52,126.16 114.35,126.16 115.39,127.2 116.46,127.2 116.76,126.9 116.76,125.53 115.34,124.1 97.89,124.1 91.41,130.58 85.06,130.58 80.42,135.23 80.42,136.6
P1V8_AVDD on L10_INT_4: 63.5,188.32 66.55,188.32 67.11,187.76 67.11,159.94 66.83,159.66 63.17,159.66 62.89,159.94 62.89,187.71
P1V8_AVDD on L12_INT_5: 65.99,160.73 67.54,160.73 68.35,159.92 68.35,154.84 71.2,151.99 71.2,142.04 71.58,141.66 73.58,141.66 78.23,137.01 80.98,137.01 81.31,136.68 81.31,135.43 80.95,135.08 77.7,135.08 72.85,139.93 70.79,139.93 69.29,141.43 69.29,151.43 66.62,154.1 66.62,158.47 65.68,159.41 65.68,160.43
P3V3_SFP+_1 on TOP: 205.82,47.8 205.82,47.04 206.12,46.74 208.81,46.74 209.04,46.51 209.04,45.67 208.48,45.11 204.83,45.11 204.34,45.59 204.34,47.8 204.44,47.9 205.71,47.9
P3V3_SFP+_1 on L7_INT_3: 207.19,47.37 216.66,47.37 218.52,45.52 218.52,36.91 219.33,36.09 219.33,33.43 218.62,32.72 210.11,32.72 206.38,36.45 206.38,46.56
P3V3_SFP+_2 on TOP: 205.82,53.52 205.82,52.76 206.12,52.45 208.81,52.45 209.04,52.22 209.04,51.05 208.81,50.83 204.83,50.83 204.34,51.31 204.34,53.52 204.44,53.62 205.71,53.62
P3V3_SFP+_2 on L7_INT_3: 207.31,55.12 222.73,55.12 232.69,45.16 232.69,37.13 233.55,36.27 233.55,33.38 233.12,32.94 225.68,32.94 224.92,33.71 224.92,35.33 226.34,36.75 226.34,39.22 216.48,49.07 207.26,49.07 206.73,49.61 206.73,54.53
P3V3_SFP+_3 on TOP: 267.89,53.52 267.89,52.76 267.59,52.45 264.9,52.45 264.67,52.22 264.67,51.05 264.9,50.83 268.88,50.83 269.37,51.31 269.37,53.52 269.27,53.62 268,53.62
P3V3_SFP+_3 on L7_INT_3: 239.09,32.99 246.74,32.99 247.62,33.88 247.62,41.81 255.45,49.63 266.8,49.63 267.84,50.67 267.84,55.17 266.88,56.13 250.75,56.13 240.56,45.95 240.56,37.29 238.73,35.46 238.73,33.35
P3V3_SFP+_4 on TOP: 267.89,47.8 267.89,47.04 267.59,46.74 264.9,46.74 264.67,46.51 264.67,45.34 264.9,45.11 268.88,45.11 269.37,45.59 269.37,47.8 269.27,47.9 268,47.9
P3V3_SFP+_4 on L7_INT_3: 258.17,47.02 266.88,47.02 267.67,46.23 267.67,42.44 266.6,41.38 262.05,41.38 261.19,40.51 261.19,37.03 262.08,36.14 262.08,33.27 261.52,32.72 253.95,32.72 253.42,33.25 253.42,34.82 255.02,36.42 255.02,43.87
SVDD on TOP (solid shape): 34.57,178.28 34.57,172.87 35.48,171.96 38.18,171.96 38.61,171.53 38.61,168.28 38.3,167.97 33.81,167.97 33.53,168.25 33.53,168.83 33.22,169.14 30.33,169.14 30.1,169.37 30.1,175.84 29.46,176.48 29.46,178.21 29.79,178.54 34.32,178.54
SVDD on TOP: 103.89,124.46 110.49,124.46 110.74,124.21 110.74,123.06 108.74,121.06 108.74,117.53 108.18,116.97 104.01,116.97 103.63,117.35 103.63,124.21
SVDD on BOTTOM: 62.26,169.19 62.26,149.5 61.67,148.92 61.67,147.35 62.1,146.91 65.02,146.91 65.56,147.45 65.56,163.78 67.51,165.74 71.12,165.74 72.01,166.62 72.01,171.96 71.75,172.21 67.44,172.21 65.41,170.18 63.25,170.18
SVDD on L7_INT_3: 31.83,183.03 57.02,183.03 64.06,176 64.06,141.78 71.58,134.26 71.58,123.06 76.43,118.21 100.18,118.21 101.96,119.99 106.4,119.99 107.21,119.18 107.21,99.36 104.62,96.77 77.47,96.77 75.72,98.53 45.14,98.53 36.55,107.11 36.55,159.03 29.69,165.89 29.69,180.9
VBUS_POWER1 on TOP (solid shape): 32.26,42.42 32.26,41.78 31.37,40.89 31.37,39.24 31.11,38.99 29.46,38.99 29.21,39.24 29.21,42.16 29.25,42.2 29.25,42.2 29.35,42.28 29.42,42.37 29.43,42.38 29.59,42.55 32.13,42.55
VBUS_POWER2 on TOP (solid shape): 42.29,42.42 42.29,41.78 41.4,40.89 41.4,39.24 41.15,38.99 39.5,38.99 39.24,39.24 39.24,42.16 39.28,42.2 39.29,42.2 39.39,42.28 39.46,42.37 39.46,42.38 39.62,42.55 42.16,42.55
VCC_3.3 on TOP (solid shape): 37.03,200.56 37.03,199.72 36.7,199.39 36.71,199.39 36.71,198.37 36.71,196.72 35.95,195.96 35.44,195.96 35.31,196.09 35.31,200.56 35.59,200.84 36.75,200.84
VCC_3.3 on TOP (solid shape): 35.76,125.53 35.76,124.64 36.02,124.38 36.02,122.89 35.84,122.71 35,122.71 34.87,122.83 34.87,123.49 34.87,124.51 34.87,125.53 35,125.65 35.64,125.65
VCC_3.3 on TOP (solid shape): 184.73,190.5 184.73,189.31 184.53,189.1 183.51,189.1 181.86,189.1 181.05,189.92 181.05,190.47 181.08,190.5 182.14,190.5 182.22,190.42 183.31,190.42 183.57,190.68 184.56,190.68
VCC_3.3 on TOP: 186.31,58.32 188.34,58.32 188.77,57.89 188.77,55.32 188.52,55.07 186.31,55.07 186.08,55.3 186.08,58.09
VCC_3.3 on TOP: 270.15,53.77 273.2,53.77 273.58,53.39 273.58,44.5 273.18,44.09 270.43,44.09 269.98,44.55 269.98,53.59
VCC_3.3 on TOP: 186.23,226.47 191.8,226.47 192.48,227.15 195.78,227.15 196.01,227.38 202.01,227.38 203.84,225.55 203.84,224.41 204.22,224.03 207.9,224.03 208.03,224.16 208.03,226.82 208.28,227.08 217.81,227.08 218.19,226.69 218.19,225.55 218.82,224.92 220.34,224.92 220.47,224.79 220.47,224.41 220.34,224.28 218.57,224.28 217.81,223.52 213.61,223.52 212.6,222.5 212.6,221.74 211.84,220.98 204.47,220.98 203.07,222.38 202.08,222.38 200.69,223.77 194.26,223.77 191.97,221.49 185.8,221.49 185.22,222.07 185.22,225.45
VCC_3.3 on TOP: 142.16,43.81 145.06,43.81 145.49,43.38 145.49,41.83 145.26,41.61 142.16,41.61 141.73,42.04 141.73,43.38
VCC_3.3 on TOP: 100.38,110.97 100.38,112.62 100.86,113.11 102.51,113.11 102.67,112.95 102.67,110.95 102.54,110.82 100.53,110.82
VCC_3.3 on TOP: 144.15,58.32 146.18,58.32 146.61,57.89 146.61,55.32 146.35,55.07 144.15,55.07 143.81,55.4 143.81,57.99
VCC_3.3 on TOP: 187.32,43.71 187.66,43.38 187.66,41.83 187.43,41.61 184.33,41.61 183.9,42.04 183.9,43.41 184.2,43.71
VCC_3.3 on TOP: 223.01,223.9 224.41,223.9 224.66,224.16 226.95,224.16 227.08,224.03 227.08,222.25 226.82,222 225.04,222 224.66,222.38 223.01,222.38 222.88,222.5 222.88,223.77
VCC_3.3 on TOP: 90.58,48.11 94.77,48.11 95.04,48.38 95.04,51.85 94.82,52.07 90.68,52.07 90.42,51.82 90.42,48.26
VCC_3.3 on TOP: 18.16,97.66 18.8,97.03 18.8,90.04 17.53,88.77 2.54,88.77 1.27,90.04 1.27,97.16 1.78,97.66
VCC_3.3 on TOP: 199.69,53.64 203.53,53.64 203.71,53.47 203.71,44.4 203.3,43.99 199.9,43.99 199.44,44.45 199.44,53.39
VCC_3.3 on TOP: 114.02,113.13 115.67,113.13 116.15,112.65 116.15,111 116,110.85 114,110.85 113.87,110.97 113.87,112.98
VCC_3.3 on TOP, BOTTOM, L3_INT_1, L5_INT_2: 1.27,139.19 1.78,139.7 5.97,139.7 6.48,139.19 6.48,136.53 5.97,136.02 1.78,136.02 1.27,136.53
VCC_3.3 on BOTTOM: 2.54,88.77 1.27,90.04 1.27,97.16 1.78,97.66 18.16,97.66 18.8,97.03 18.8,90.04 17.53,88.77
VCC_3.3 on BOTTOM: 84.58,147.7 84.76,147.88 84.76,148.13 84.84,148.21 85.85,148.21 86.16,147.9 86.16,146.74 85.98,146.56 84.2,146.56 83.95,146.3 83.95,145.8 83.69,145.54 80.01,145.54 77.72,143.26 77.72,141.1 77.22,140.59 75.82,140.59 75.31,141.1 75.31,144.91 76.33,145.92 78.23,145.92 80.01,147.7
VCC_3.3 on L3_INT_1: 17.27,97.66 18.5,96.43 18.5,90.01 17.27,88.77 2.54,88.77 1.27,90.04 1.27,97.16 1.78,97.66
VCC_3.3 on L5_INT_2: 17.27,97.66 18.29,96.65 18.29,89.79 17.27,88.77 2.54,88.77 1.27,90.04 1.27,97.16 1.78,97.66
VCC_3.3 on L5_INT_2: 39.67,198.78 33.73,198.78 33.05,199.47 33.05,237.77 33.78,238.51 39.22,238.51 40.28,237.44 40.28,199.39
VCC_3.3 on L7_INT_3, L12_INT_5: 12.19,89.15 2.03,89.15 1.27,89.92 1.27,97.54 2.03,98.3 12.19,98.3 12.95,97.54 12.95,89.92
VCC_3.3 on L9_PWR_2: 183.15,227.37 183.15,119.47 173.28,109.6 128.27,109.6 122.96,114.91 60.15,114.91 55.4,119.66 40.74,119.66 37.59,122.81 37.59,153.34 32.87,158.06 3.99,158.06 1.02,155.09 1.02,31.32 4.93,27.41 102.77,27.41 104.98,29.62 192.74,29.62 209.68,46.56 268.74,46.56 271.78,43.53 276.99,43.53 277.77,44.31 277.77,112.98 267.39,123.37 267.39,239.73 256.74,250.37 2.08,250.37 1.17,249.45 1.17,227.28 5.94,222.5 125.43,222.5 133.15,230.23 180.29,230.23
VCC_3.3 on L10_INT_4: 71.68,143.74 77.34,143.74 77.88,143.21 77.88,138.96 76.94,138.02 76.94,128.57 91.36,114.15 102.44,114.15 102.87,113.72 102.87,109.45 102.39,108.97 87,108.97 70.08,125.88 70.08,142.14
VCC_3.3 on L10_INT_4: 11.05,89.15 2.03,89.15 1.27,89.92 1.27,97.54 2.03,98.3 12.19,98.3 12.95,97.54 12.95,91.06
VCC_3.3 on L14_INT_6: 77.75,214.1 83.03,214.1 83.57,214.63 83.57,217.81 83.54,217.83 83.54,224.74 84.53,225.73 87.02,225.73 87.66,226.36 87.66,230.4 87.2,230.86 78.94,230.86 78.33,230.25 78.33,222.58 76.45,220.7 76.45,215.39
VCC_3.3 on L14_INT_6: 1.27,139.19 1.91,139.83 5.84,139.83 6.48,139.19 6.48,136.53 5.97,136.02 1.78,136.02 1.27,136.53
VCC_3.3 on L14_INT_6: 17.27,97.66 18.29,96.65 18.29,96.62 18.54,96.37 18.54,90.17 17.4,89.03 2.29,89.03 1.27,90.04 1.27,97.16 1.78,97.66
VCC_3.3_F on TOP: 92.79,37.82 94.67,37.82 95.22,38.38 95.22,42.67 94.72,43.18 90.88,43.18 90.55,42.85 90.55,40.77 90.93,40.39 92.18,40.39 92.68,39.88 92.68,37.92
VCC_3.3_SD on TOP: 92.02,31.85 90.81,31.85 90.42,32.23 90.42,39.4 90.58,39.55 92.02,39.55 92.13,39.45 92.13,31.95
VCC_5 on TOP: 6.99,124.71 6.99,135 7.49,135.51 16.26,135.51 17.14,134.62 17.14,126.36 16,125.22 14.35,125.22 12.83,123.7 8,123.7
VCC_5 on TOP, BOTTOM, L5_INT_2, L14_INT_6: 1.78,102.49 1.27,103 1.27,105.54 1.78,106.05 5.97,106.05 6.48,105.54 6.48,103 5.97,102.49
VCC_5 on TOP, BOTTOM, L5_INT_2, L14_INT_6: 1.78,110.87 1.27,111.38 1.27,113.92 1.78,114.43 5.97,114.43 6.48,113.92 6.48,111.38 5.97,110.87
VCC_5 on BOTTOM: 8,123.7 6.99,124.71 6.99,135 7.49,135.51 16.26,135.51 17.14,134.62 17.14,126.36 16,125.22 14.35,125.22 12.83,123.7
VCC_5 on L3_INT_1: 7.49,135.51 21.87,135.51 25.04,132.33 25.04,117.96 31.11,111.89 31.11,84.49 29.31,82.69 29.31,65.43 44.88,49.86 44.88,42.67 44.15,41.94 32.56,41.94 16.96,57.54 16.96,86.73 19.39,89.17 19.39,99.43 16.61,102.21 2.03,102.21 1.27,102.97 1.27,117.81 6.99,123.52 6.99,135
VCC_5 on L5_INT_2, L14_INT_6: 6.99,124.71 6.99,135 7.49,135.51 15.88,135.51 16.89,134.49 16.89,126.11 16,125.22 14.35,125.22 12.83,123.7 8,123.7
VCC_5 on L7_INT_3, L10_INT_4: 1.27,102.74 2.03,101.98 6.99,101.98 7.75,102.74 7.75,114.3 6.99,115.06 2.03,115.06 1.27,114.3
VCC_5 on L12_INT_5: 1.27,102.74 2.03,101.98 28.75,101.98 34.87,108.1 34.87,142.77 29.72,147.93 29.72,209.25 46.81,226.34 93.32,226.34 95.76,223.9 101.3,223.9 103.1,225.7 103.1,249.96 101.83,251.23 5.79,251.23 1.28,246.72 1.28,114.31 1.27,114.3
VCC_12 on TOP (solid shape): 7.33,238.93 7.33,235 6.7,234.36 1.62,234.36 1.37,234.62 1.37,239.19 1.87,239.7 6.57,239.7
VCC_12 on TOP (solid shape): 28.47,162.89 28.47,162.86 29.84,162.86 29.9,162.81 29.9,162.41 29.84,162.36 28.45,162.36 28.17,162.08 28.17,158.98 27.38,158.19 23.22,158.19 22.76,158.65 22.76,162.18 22.94,162.36 26.54,162.36 27.15,162.97 28.4,162.97
VCC_12 on BOTTOM (solid shape): 7.33,238.93 7.33,235 6.7,234.36 1.62,234.36 1.37,234.62 1.37,239.19 1.87,239.7 6.57,239.7
VCC_12 on TOP: 186.44,240.66 225.93,240.66 227.08,239.52 227.08,229.49 226.69,229.11 206.12,229.11 205.74,229.49 204.34,229.49 203.66,228.8 199.44,228.8 198.88,229.36 195.71,229.36 194.82,230.25 194.82,233.55 194.44,233.93 186.31,233.93 185.67,234.57 185.67,239.9
VCC_12 on TOP: 30.08,138.25 31.45,138.25 31.5,138.2 31.5,137.79 31.45,137.74 30.05,137.74 29.77,137.46 29.77,134.37 28.98,133.58 24.82,133.58 24.36,134.04 24.36,137.57 24.54,137.74 28.14,137.74 28.75,138.35 30,138.35 30.08,138.28
VCC_12 on TOP: 38.5,251.21 39.89,251.21 40.15,250.95 40.15,247.9 40.53,247.52 40.53,242.57 40.4,242.44 38.37,242.44 38.12,242.7 38.12,250.82
VCC_12 on TOP: 29.9,101.8 31.27,101.8 31.32,101.75 31.32,101.35 31.27,101.3 29.87,101.3 29.59,101.02 29.59,97.92 28.81,97.13 24.64,97.13 24.18,97.59 24.18,101.12 24.36,101.3 27.97,101.3 28.58,101.9 29.82,101.9 29.9,101.83
VCC_12 on TOP: 197.92,48.61 197.92,50.01 197.67,50.26 194.62,50.26 194.24,50.64 189.28,50.64 189.16,50.52 189.16,48.48 189.41,48.23 197.54,48.23
VCC_12 on TOP: 204.88,62.05 204.88,63.43 204.93,63.48 205.33,63.48 205.38,63.43 205.38,62.03 205.66,61.75 208.76,61.75 209.55,60.96 209.55,56.8 209.09,56.34 205.56,56.34 205.38,56.52 205.38,60.12 204.77,60.73 204.77,61.98 204.85,62.05
VCC_12 on TOP: 6.48,251.08 7.87,251.08 8.26,250.7 8.26,247.9 8.64,247.52 8.64,242.57 8.51,242.44 6.48,242.44 6.22,242.7 6.22,250.82
VCC_12 on TOP: 249.28,86.82 249.28,88.19 249.33,88.24 249.73,88.24 249.78,88.19 249.78,86.79 250.06,86.51 253.16,86.51 253.95,85.73 253.95,81.56 253.49,81.1 249.96,81.1 249.78,81.28 249.78,84.89 249.17,85.5 249.17,86.74 249.25,86.82
VCC_12 on TOP: 60.41,251.21 61.8,251.21 62.06,250.95 62.06,247.9 62.44,247.52 62.44,242.57 62.31,242.44 60.28,242.44 60.02,242.7 60.02,250.82
VCC_12 on TOP: 17.59,251.08 18.99,251.08 19.37,250.7 19.37,247.9 19.75,247.52 19.75,242.57 19.63,242.44 17.59,242.44 17.27,242.77 17.27,250.76
VCC_12 on TOP: 140.53,251.21 141.92,251.21 142.18,250.95 142.18,247.9 142.56,247.52 142.56,242.57 142.43,242.44 140.4,242.44 140.15,242.7 140.15,250.82
VCC_12 on TOP, BOTTOM: 14.38,148.16 17.3,148.16 17.68,147.78 17.68,142.44 17.42,142.19 14.25,142.19 14,142.44 14,147.78
VCC_12 on TOP, BOTTOM, L3_INT_1, L5_INT_2, L14_INT_6: 1.27,135 1.78,135.51 5.97,135.51 6.48,135 6.48,128.14 5.97,127.64 1.78,127.64 1.27,128.14
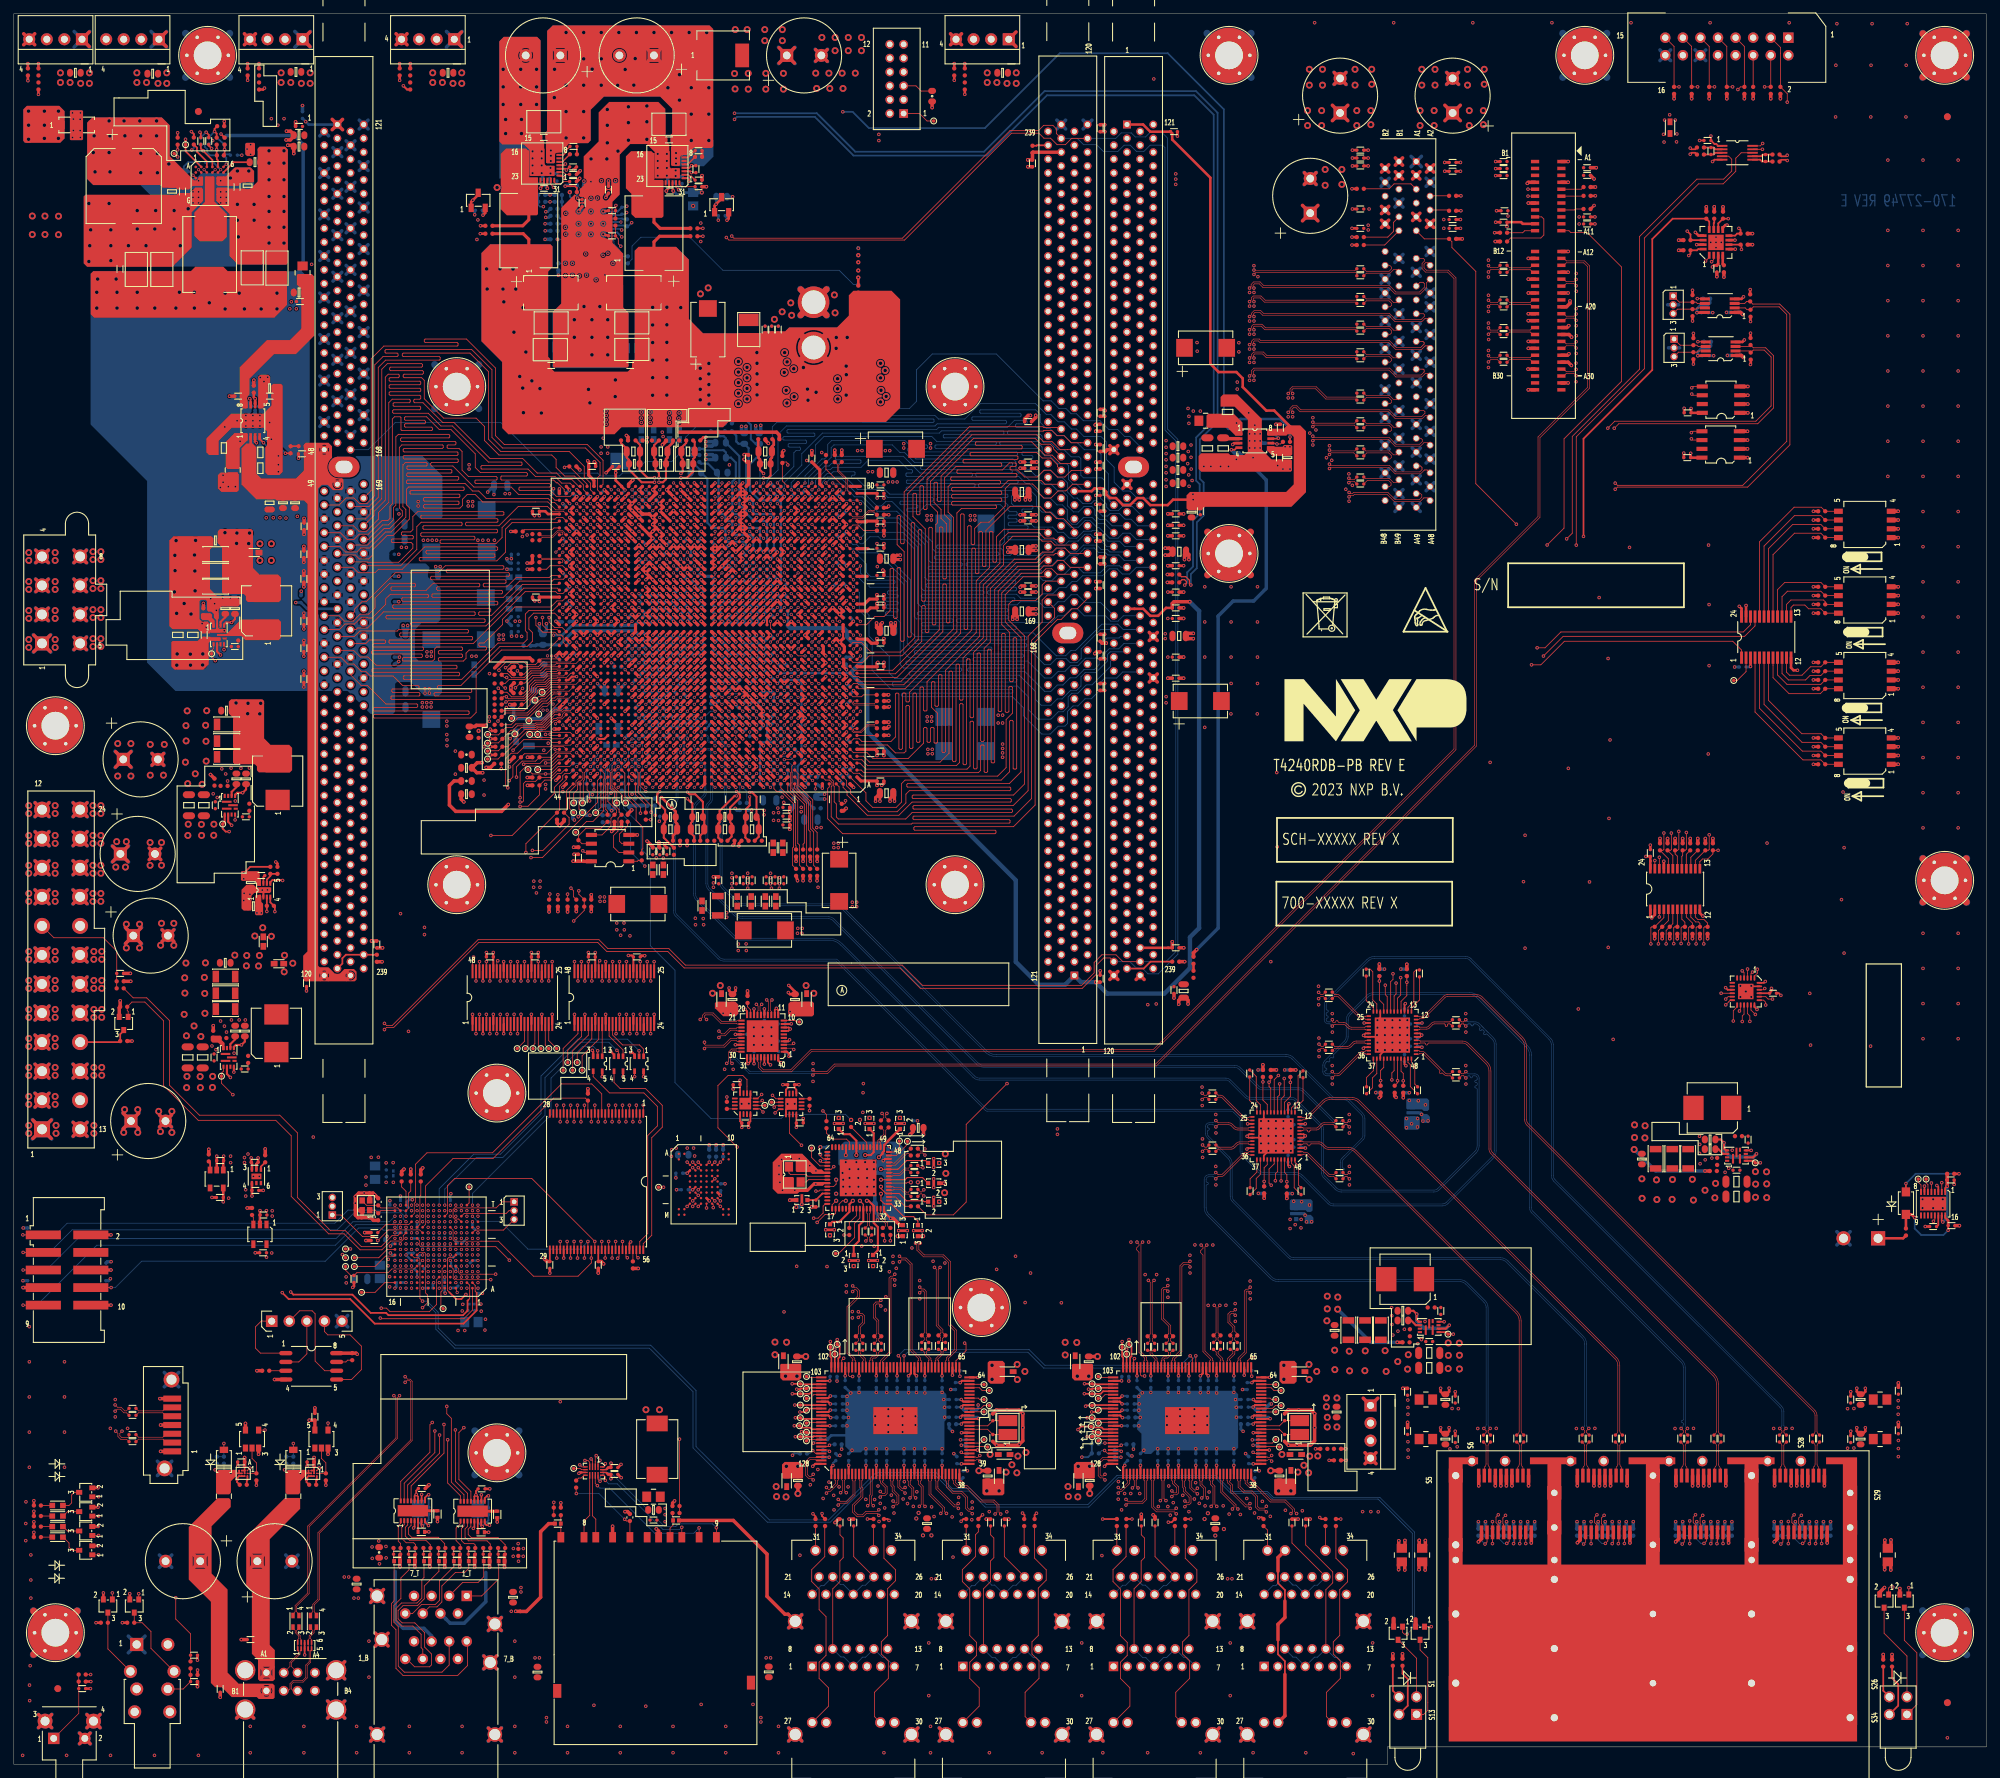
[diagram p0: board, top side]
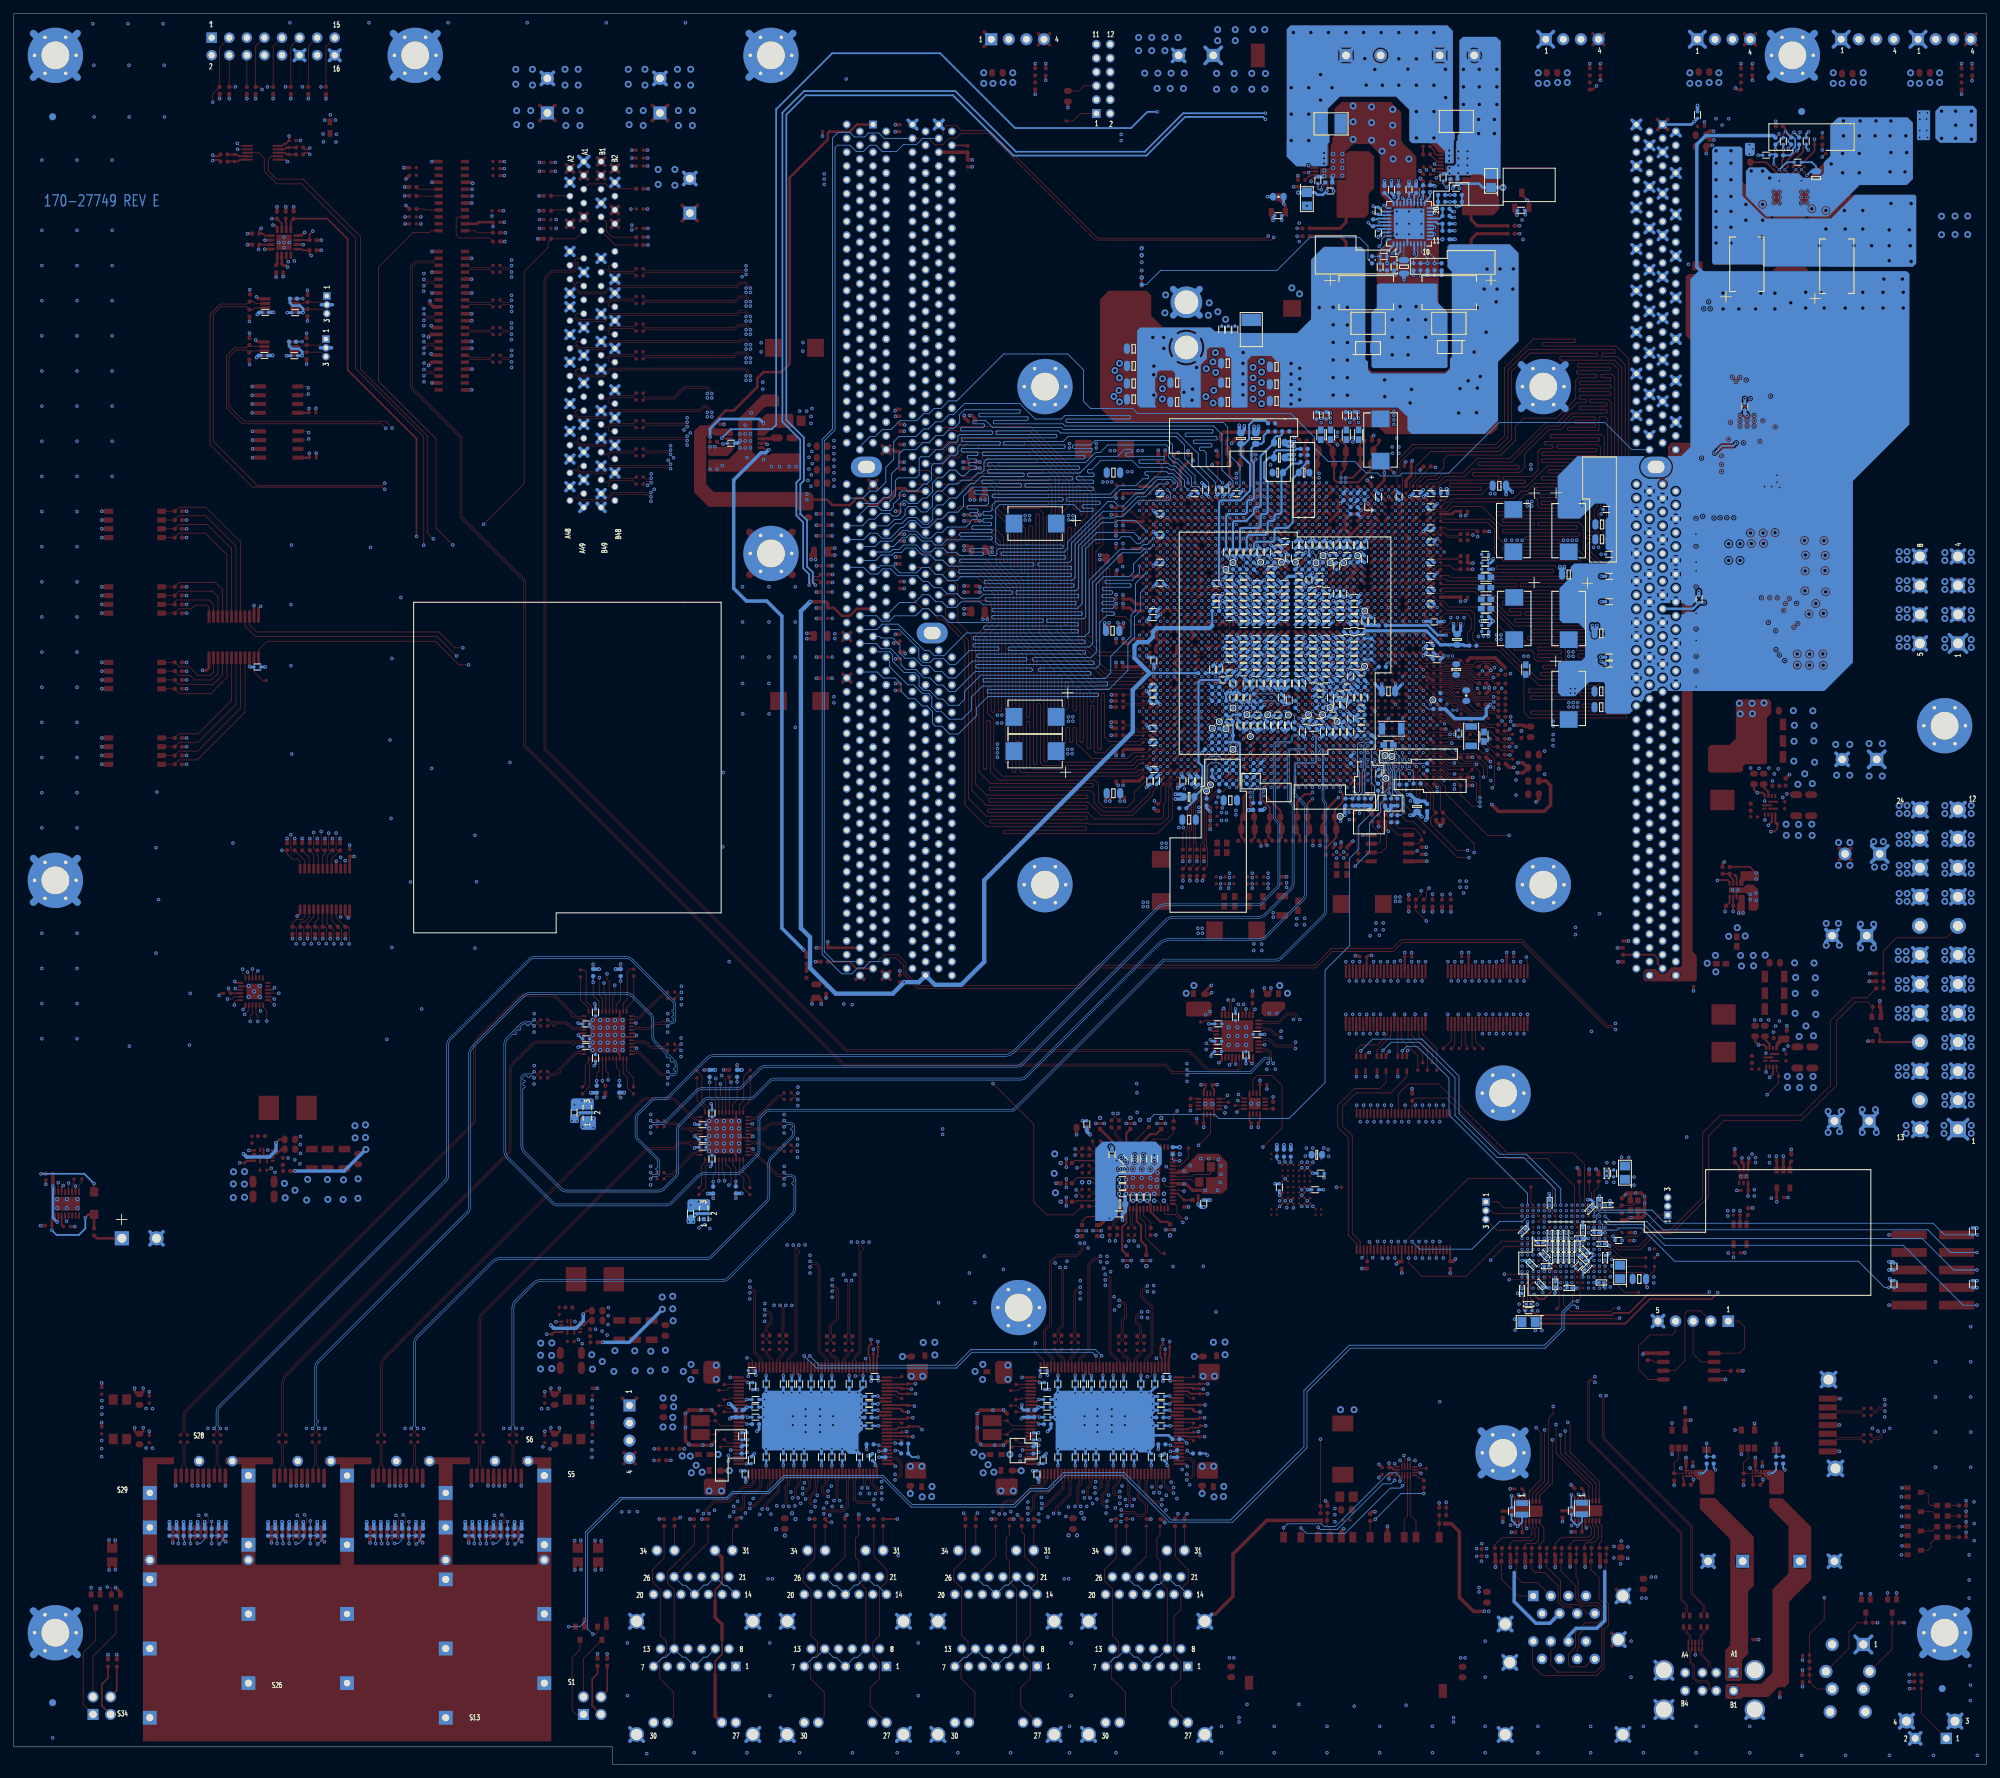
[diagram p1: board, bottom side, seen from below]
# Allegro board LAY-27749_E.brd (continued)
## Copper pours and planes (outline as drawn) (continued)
VCC_12 on L7_INT_3: 142.7,250.49 142.7,241.86 135.2,234.37 135.18,234.37 131.98,231.17 63.86,231.17 56.21,223.52 47.22,223.52 31.67,207.98 31.67,207.75 28.75,204.83 28.75,164.82 31.75,161.82 31.75,57.81 43.94,45.62 85.9,45.62 101.8,61.52 190.02,61.52 200.13,71.63 240.11,71.63 247.52,79.04 247.52,84.76 247.55,84.76 249.07,86.28 258.17,86.28 259.03,85.42 259.03,70.97 244.22,56.16 207.49,56.16 196.67,45.34 114.33,45.34 96.39,27.41 29.24,27.41 14.83,41.81 14.83,111.61 1.12,125.32 1.12,245.62 2.62,247.12 20.78,247.12 25.04,242.85 31.65,242.85 32.89,244.09 32.89,251.03 33.55,251.69 141.5,251.69
VCC_12 on L10_INT_4: 3.23,222.12 214.02,222.12 216.79,224.89 216.79,248.11 214.25,250.65 1.68,250.65 1.19,250.16 1.19,224.16
VCC_12_8P on TOP: 104.01,251.38 112.55,251.38 113.46,250.47 113.46,242.47 112.5,241.5 104.01,241.5 103.56,241.96 103.56,250.93
VCC_12_8P on TOP, BOTTOM: 7.11,160.3 7.11,176.91 0.89,183.13 0.89,224.41 1.65,225.17 9.04,225.17 9.86,224.36 9.86,192.33 18.14,184.05 18.14,160.35 17.63,159.84 7.57,159.84
VCC_12_8P on BOTTOM: 104.01,251.38 112.55,251.38 113.46,250.47 113.46,242.44 112.52,241.5 103.91,241.5 103.56,241.86 103.56,250.93
VCC_12_8P on L8_PWR_1: 2.26,219.43 37.52,219.43 39.46,221.37 76.63,221.37 78.47,223.22 109.12,223.22 113.26,227.36 113.26,250.14 112.01,251.38 10.59,251.38 1.5,242.29 1.5,220.19
VCC_12_8P on L14_INT_6: 0.89,242.27 10.72,252.09 113.06,252.09 113.84,251.31 113.89,251.31 113.89,237.54 112.5,236.14 56.97,236.14 55.42,237.69 43.99,237.69 41.3,235 41.3,229.92 38.84,227.46 24.56,227.46 18.54,221.44 18.54,159.77 18.21,159.44 2.34,159.44 0.89,160.88
VCC_DVDD on TOP: 38.51,117.25 38.51,114.17 38.73,113.94 40.87,113.94 41.17,114.25 41.17,117.32 40.92,117.58 38.84,117.58
VCC_DVDD on BOTTOM: 114.3,138.68 113.67,138.68 113.41,138.43 113.41,135.89 113.67,135.64 114.43,135.64 114.68,135.89 114.68,138.3
VCC_DVDD on BOTTOM: 66.17,37.26 67.94,37.26 68,37.31 68,39.17 67.84,39.32 66.29,39.32 66.14,39.17 66.14,37.29
VCC_DVDD on BOTTOM: 57.51,37.34 59.28,37.34 59.33,37.39 59.33,39.07 59.05,39.34 57.71,39.34 57.4,39.04 57.4,37.44
VCC_DVDD on L10_INT_4: 107.98,157.76 113.67,157.76 113.94,157.48 113.94,140 117.7,136.25 117.7,115.57 121.21,112.06 157.89,112.06 248.16,202.34 248.16,213.31 248.87,214.02 255.14,214.02 255.8,213.36 255.8,194.92 161.67,100.79 122.78,100.79 109.02,87.02 109.02,66.75 74.83,32.56 57.12,32.56 50.52,39.17 50.52,52.48 40.84,62.15 40.84,96.95 36.42,101.37 36.42,117.2 36.96,117.73 43.26,117.73 43.94,117.04 43.94,105.26 51.79,97.41 51.79,68.48 58.72,61.54 58.72,43.05 62.18,39.6 70.97,39.6 101.83,70.46 101.83,90.86 111.39,100.42 111.39,113.07 111.94,113.61 111.94,134.44 110.16,136.22 110.16,141.48 109.7,141.94 109.7,154.33 109.45,154.58 107.98,154.58 107.72,154.84 107.72,157.51
VDD on TOP (solid shape): outline of 2188 points within 67.56,192.23 128.07,219.7
VDD on BOTTOM (solid shape): outline of 268 points within 67.56,192.28 122.68,219.7
VDD on TOP: 100.2,123.83 100.2,119.51 99.95,119.25 97.16,119.25 96.52,119.89 96.52,123.44 97.03,123.95 100.08,123.95
VDD on L3_INT_1: 107.82,172.39 107.8,172.42 107.8,175.36 106.48,176.68 93.4,176.68 92.84,177.24 92.84,194.21 95.17,196.55 95.17,215.54 95.15,215.54 94.74,215.95 78.28,215.95 75.06,219.18 68.78,219.18 67.56,217.96 67.56,205.69 68.73,204.52 68.73,191.59 69.9,190.42 82.45,190.42 87.71,185.17 87.71,171.96 90.83,168.83 90.83,152.63 90.93,152.53 107.52,152.53 107.82,152.83
VDD on L7_INT_3: 107.49,155.96 107.57,156.03 107.57,175.54 113.87,181.84 113.87,190.12 120.9,197.15 120.9,207.01 120.22,207.7 99.8,207.7 98.37,206.27 98.37,196.52 99.11,195.78 99.11,177.75 97.1,175.74 91.16,175.74 89.96,176.94 89.96,187.3 88.04,189.23 88.04,218.44 87.25,219.23 68.83,219.23 67.56,217.96 67.56,205.69 68.73,204.52 68.73,140.82 73.76,135.79 73.76,124.08 78.69,119.15 98.42,119.15 100.05,120.78 100.05,128.37 99.19,129.24 90.35,129.24 88.9,130.68 88.9,155.32 89.15,155.57 105.66,155.57 106.05,155.96
VDD on L8_PWR_1: 99.81,207.7 120.22,207.7 120.95,206.97 120.95,197.2 113.87,190.12 113.87,181.84 107.58,175.55 107.58,156.01 107.14,155.57 93.27,155.57 93.07,155.78 93.07,171.7 99.11,177.75 99.11,195.78 98.37,196.52 98.37,206.26
VDD on L9_PWR_2: 93.32,154.76 107.24,154.76 107.59,155.12 107.59,177.29 104.06,180.82 104.06,192.38 106.58,194.89 125.53,194.89 127.05,196.42 127.05,217.32 125.04,219.33 61.67,219.33 61.04,218.69 61.04,207.26 63.35,204.95 68.07,204.95 70.56,202.46 70.56,193.24 71.58,192.23 86.41,192.23 89.76,188.87 89.76,174.27 93.01,171.02 93.01,155.07
VDD on L10_INT_4: 107.85,160.91 107.85,192.25 111.12,195.53 126.16,195.53 127.05,196.42 127.05,217.35 125.07,219.33 68.61,219.33 67.46,218.19 67.46,205.56 69.37,203.66 69.37,195.66 67.84,194.13 67.82,185.02 67.82,165.23 69.11,163.93 78.28,163.93 79.6,162.61 93.4,162.61 93.68,162.33 93.68,160.93 94.01,160.6 107.54,160.6
VDD_2V5_AUX on L3_INT_1: 76.12,226.8 81.66,226.8 82.14,226.31 82.14,225.02 82.04,224.92 81.46,224.92 80.21,223.67 78.61,223.67 78.13,223.19 78.13,220.45 77.5,219.81 75.64,219.81 75.11,220.34 75.11,225.78
VDD_FA_VDD on BOTTOM: 82.04,155.83 83.82,155.83 84.33,155.32 84.33,154.31 84.52,154.11 88.07,154.11 88.27,154.31 88.27,154.69 89.03,155.45 89.41,155.45 89.6,155.26 89.6,155.13 88.9,154.43 88.9,154.05 88.39,153.54 80.9,153.54 80.01,154.43 78.71,154.43 78.54,154.61 78.54,155.88 78.74,156.08 81.79,156.08
VDD_LP on TOP: 65.86,142.75 68.1,142.75 68.35,142.49 68.35,139.93 67.97,139.55 65.81,139.55 65.68,139.67 65.68,142.57
VDD_LP on L5_INT_2: 93.66,153.99 93.66,154.37 93.98,154.69 93.98,155.38 94.23,155.64 94.81,155.64 95,155.45 95,152.78 94.74,152.53 89.79,152.53 89.03,151.76 89.03,150.5 85.09,146.56 79.76,146.56 78.38,145.19 75.9,145.19 74.9,144.2 74.9,141.91 72.77,139.78 67.74,139.78 67.67,139.85 67.67,142.37 67.94,142.65 71.65,142.65 72.14,143.13 72.14,145.59 74.63,148.08 78.33,148.08 79.1,148.84 83.57,148.84 83.82,149.1 84.84,149.1 86.74,151 86.74,151.64 88.9,153.8 93.47,153.8
VDD_OVDD_P1V8 on TOP: 34.49,119.1 37.57,119.1 37.8,119.33 37.8,121.46 37.49,121.77 34.42,121.77 34.16,121.51 34.16,119.43
VDD_OVDD_P1V8 on L10_INT_4: 108.94,171.75 109.7,171.75 109.93,171.53 109.93,158.85 109.63,158.55 94.21,158.55 93.95,158.29 93.95,154.99 93.65,154.69 89.15,154.69 88.85,154.38 88.85,151.31 88.19,150.65 75.44,150.65 49.86,125.07 49.86,119.61 48.95,118.69 34.72,118.69 34.21,119.2 34.21,132.46 60.15,158.39 68.94,158.39 69.77,159.23 77.17,159.23 79.76,161.82 92.53,161.82 92.99,161.37 92.99,160.07 93.22,159.84 108.46,159.84 108.69,160.07 108.69,171.5
VDD_PH1_FLT on TOP (solid shape): 74.27,233.29 74.27,229.61 74.52,229.36 75.7,229.36 75.74,229.31 75.74,229.31 75.74,227.91 75.72,227.85 75.72,227.79 75.72,227.73 75.74,227.66 75.74,224.06 75.56,223.88 71.24,223.88 70.35,224.76 70.35,227.54 70.46,227.9 70.35,228.25 70.35,232.77 71.11,233.53 74.03,233.53
VDD_PH2_FLT on TOP (solid shape): 92.35,232.92 92.35,229.24 92.61,228.99 93.75,228.99 93.88,228.86 93.88,223.74 93.64,223.51 89.79,223.51 89.39,223.9 89.38,223.9 89.23,224.05 89.23,226.99 88.44,227.79 88.44,232.4 89.2,233.16 92.12,233.16
VDD_S1VDD on TOP: 108.2,127.51 111.51,127.51 111.89,127.13 111.89,125.48 111.51,125.09 108.08,125.09 107.95,125.22 107.95,127.25
VDD_S1VDD on L10_INT_4: 100.84,157.48 101.09,157.73 106.68,157.73 106.93,157.48 106.93,154.05 107.19,153.8 108.71,153.8 108.97,153.54 108.97,140.97 109.35,140.59 109.35,136.4 111.38,134.37 111.38,126.36 111.12,126.11 108.08,126.11 107.57,126.62 107.57,132.21 102.49,137.29 102.49,138.94 100.84,140.59
VDD_S2VDD on TOP: 103.5,127.51 107.19,127.51 107.44,127.25 107.44,125.22 107.19,124.97 103.63,124.97 103.25,125.35 103.25,127.25
VDD_S2VDD on BOTTOM: 99.73,153.38 99.06,154.05 99.06,154.31 99.19,154.43 99.44,154.43 99.69,154.18 99.95,154.18 100.46,154.69 100.84,154.69 100.97,154.56 100.97,154.05 100.71,153.8 100.58,153.8 100.17,153.38
VDD_S2VDD on L10_INT_4: 100.58,154.31 100.58,140.08 101.98,138.68 101.98,137.16 107.06,132.08 107.06,126.62 106.55,126.11 102.87,126.11 102.36,126.62 102.36,128.78 95.63,135.51 95.63,138.68 94.68,139.64 94.68,157.42 95,157.73 100.2,157.73 100.58,157.35 100.58,155.96 99.95,155.32 99.95,154.94
VDD_S3VDD on BOTTOM: 72.52,165.74 72.16,165.38 72.16,165 72.36,164.8 72.36,162.92 72.59,162.69 74.55,162.69 74.93,163.07 74.93,167.89 74.8,168.02 74.8,168.66 74.42,169.04 72.77,169.04 72.52,168.78
VDD_S3VDD on L12_INT_5: 72.39,162.92 72.39,164.64 72.11,164.92 72.11,165.71 74.17,167.77 76.23,167.77 79.25,170.79 96.47,170.79 96.7,171.02 96.7,172.54 96.98,172.82 99.69,172.82 100.91,171.6 100.91,170.97 101.04,170.84 103.53,170.84 103.71,171.02 103.71,172.36 103.5,172.57 103.17,172.57 102.84,172.9 102.84,173.58 103.12,173.86 104.65,173.86 104.98,173.53 104.98,161.98 104.75,161.75 73.56,161.75
VDD_S4VDD on BOTTOM: 76.58,167.39 76.58,168.28 75.31,169.54 72.77,169.54 72.52,169.8 72.52,177.67 73.91,179.07 75.95,179.07 77.7,180.82 88.65,180.82 88.98,180.49 88.98,176.96 89.41,176.53 89.41,173.48 90.07,172.82 93.5,172.82 93.7,173.02 93.98,173.02 94.18,172.82 95.48,172.82 95.76,173.1 95.91,173.1 96.67,172.34 96.67,172.09 95.96,171.37 95.96,171.02 96.62,170.36 96.62,170.03 96.47,169.88 96.24,169.88 96.04,170.08 95.68,170.08 95,169.39 94.72,169.39 94.54,169.57 94.16,169.57 93.98,169.39 93.7,169.39 93.52,169.57 93.19,169.57 92.98,169.35 92.71,169.35 92.52,169.54 90.17,169.54 89.92,169.29 89.92,167.89 89.61,167.59 88.21,167.59 87.99,167.36 87.99,165.96 87.6,165.58 78.38,165.58 ; 6 cut-outs
VDD_SGND on L7_INT_3: 64.92,229.57 102.97,229.57 103.53,229.01 103.53,221.96 102.79,221.22 98.29,221.22 97.13,220.07 65.46,220.07 64.19,221.34 64.19,228.83
VDD_TH_VDD on BOTTOM: 85.72,158.75 86.68,157.8 89.47,157.8 90.12,158.45 90.45,158.45 90.58,158.32 90.58,158.08 89.09,156.59 77.52,156.59 75.67,154.74 74.78,154.74 74.47,155.04 74.47,156.51 75.95,157.99 78.38,157.99 79.15,158.75
VDD_X1VDD on TOP: 111.63,132.74 111.53,132.64 109.3,132.64 108.97,132.97 108.97,138.3 109.35,138.68 111.25,138.68 111.63,138.3
VDD_X1VDD on L5_INT_2: 104.9,153.8 108.71,153.8 108.97,153.54 108.97,153.03 109.22,152.78 112.65,152.78 112.9,152.53 112.9,136.02 112.52,135.64 109.86,135.64 109.09,136.4 109.09,138.05 108.58,138.56 106.55,138.56 105.66,139.45 105.66,149.35 105.16,149.86 101.09,149.86 100.84,150.11 100.84,152.53 101.16,152.84 104.46,152.84 104.71,153.1 104.71,153.61
VDD_X2VDD on TOP: 94.61,131.7 94.61,129.92 94.23,129.54 91.95,129.54 91.82,129.67 91.82,131.57 92.2,131.95 92.52,131.95 92.71,132.14 92.96,132.14 93.15,131.95 93.54,131.95 93.73,132.14 93.98,132.14 94.17,131.95 94.36,131.95
VDD_X2VDD on L7_INT_3: 89.66,152.53 89.92,152.78 100.33,152.78 100.84,152.27 100.84,131.32 99.82,130.3 90.42,130.3 89.66,131.06
VDD_X3VDD on BOTTOM: 93.98,194.44 93.98,192.91 94.49,192.41 96.52,192.41 97.16,193.04 97.16,194.56 96.9,194.82 94.36,194.82
VDD_X3VDD on L12_INT_5: 104.6,174.57 104.95,174.93 104.95,175.59 104.71,175.83 103.19,175.83 103,176.02 103,184.35 101.85,185.5 101.85,193.8 100.76,194.89 94.69,194.89 94.46,194.67 94.46,191.16 95.62,190 95.62,183.93 97.66,181.89 97.66,177.04 97.49,176.86 97.35,176.86 96.7,176.21 96.7,174.9 97.03,174.57
VDD_X4VDD on BOTTOM: 89.92,194.56 89.92,192.79 90.3,192.41 92.84,192.41 93.09,192.66 93.09,194.69 92.84,194.94 90.3,194.94
VDD_X4VDD on L14_INT_6: 96.95,182.63 96.72,182.85 96.16,182.85 95.96,183.06 95.96,192.96 95.5,193.42 94.61,193.42 94.23,193.8 94.23,194.56 93.85,194.94 90.68,194.94 90.42,194.69 90.42,193.04 90.87,192.6 90.87,178.12 90.55,177.8 89.03,177.8 88.8,177.57 88.8,174.09 89.33,173.56 96.52,173.56 96.95,173.99
(no net) on TOP: 94.15,239.25 94.15,235.44 94.45,235.15 94.45,234.41 94.72,234.14 94.72,230.91 94.95,230.68 96.19,230.68 96.24,230.63 96.24,229.26 96.19,229.21 92.71,229.21 92.61,229.31 92.61,233.02 91.45,234.17 89.07,234.17 87.56,232.66 87.56,226.88 86.51,225.83 86.51,219.88 88.05,218.34 88.05,210.55 88.82,209.79 88.82,202.04 88.65,201.88 78.06,201.88 77.89,202.04 77.89,209.92 79.09,211.11 79.09,224.95 82.34,228.21 82.34,232.4 84.5,234.56 84.5,238.75 86.02,240.27 93.13,240.27
(no net) on TOP: 41.27,38.48 41.38,38.38 41.38,36.91 36.98,32.51 36.98,17.22 37.72,16.48 37.72,12.29 37.44,12.01 35.56,12.01 35.28,12.29 35.28,15.05 34.39,15.94 34.39,24.97 33.58,25.78 33.58,32.89 39.17,38.48
(no net) on TOP: 112.24,110.24 115.39,110.24 115.62,110.01 115.62,108.33 115.37,108.08 112.19,108.08 111.91,108.36 111.91,109.91
(no net) on TOP: 101.5,110.21 104.27,110.21 104.7,109.78 104.7,108.48 104.32,108.1 101.5,108.1 101.3,108.31 101.3,110.01
(no net) on TOP: 110.87,57.86 113.67,57.86 113.79,57.73 113.79,55.83 113.41,55.45 111.12,55.45 110.74,55.83 110.74,57.73
(no net) on TOP: 42.16,191.01 45.47,191.01 45.97,190.5 45.97,186.82 46.74,186.06 47.24,186.06 47.62,185.67 47.62,184.4 47.37,184.15 46.1,184.15 45.34,184.91 44.5,184.91 43.97,184.38 43.97,115.42 44.2,115.19 45.47,115.19 46.35,114.3 47.12,114.3 47.75,114.94 49.15,114.94 49.53,114.55 49.53,113.41 49.28,113.16 42.04,113.16 41.81,113.39 41.81,116.87 42.42,117.47 42.42,182.17 41.94,182.65 38,182.65 37.82,182.83 35.03,182.83 32.9,184.96 32.9,190.24 33.53,190.88 34.52,190.88 35.05,190.35 35.05,186.54 35.74,185.85 40.77,185.85 41.91,186.99 41.91,190.75
(no net) on TOP: 181.08,190.5 181.05,190.47 181.05,189.92 181.86,189.1 184.53,189.1 184.73,189.31 184.73,190.5 184.56,190.68 183.57,190.68 183.31,190.42 182.22,190.42 182.14,190.5
(no net) on TOP: 140.21,38.86 139.95,39.12 139.95,41.15 140.08,41.27 142.88,41.27 143.13,41.02 143.13,39.12 142.88,38.86
(no net) on TOP: 28.47,162.86 29.84,162.86 29.9,162.81 29.9,162.41 29.84,162.36 28.45,162.36 28.17,162.08 28.17,158.98 27.38,158.19 23.22,158.19 22.76,158.65 22.76,162.18 22.94,162.36 26.54,162.36 27.15,162.97 28.4,162.97 28.47,162.89
(no net) on TOP: 185.37,55.32 185.37,57.96 185.04,58.29 183.13,58.29 182.88,58.04 182.88,55.37 183.26,54.99 185.04,54.99
(no net) on TOP: 26.21,227.87 27.1,227.87 27.35,227.62 27.35,225.96 25.7,224.31 25.7,219.23 22.9,216.43 10.59,216.43 10.08,216.94 10.08,226.6 10.33,226.85 23.54,226.85 23.8,227.11 25.45,227.11
(no net) on TOP: 101.07,233.83 100.84,233.6 98.24,233.6 97.18,232.54 96.54,232.54 96.29,232.29 96.29,231.15 96.16,231.02 95.15,231.02 95.02,231.15 95.02,234.32 94.89,234.45 94.89,235.46 95.15,235.72 95.15,239.28 93.39,241.03 85.26,241.03 83.36,239.13 83.36,234.69 82.98,234.31 80.49,234.31 79.09,232.91 78.46,232.91 78.2,232.66 78.2,231.52 78.08,231.39 77.06,231.39 76.93,231.52 76.93,234.69 76.81,234.82 76.81,235.83 77.06,236.09 77.06,250.52 77.86,251.33 100.54,251.33 101.07,250.8
(no net) on TOP: 34.34,123.49 34.34,125.53 34.75,125.93 37.01,125.93 37.19,126.11 37.19,126.67 37.11,126.75 35.03,126.75 34.65,127.13 33.63,127.13 32.89,126.39 32.89,123.7 33.22,123.37 34.21,123.37
(no net) on TOP: 97.55,217.47 97.55,208.89 98.45,207.98 98.45,207.98 99.59,206.83 108.03,206.83 108.31,207.11 111.46,207.11 112.03,207.68 118.94,207.68 120.65,209.38 120.65,212.32 121.31,212.98 126.82,212.98 128.07,211.73 128.07,196.04 126.03,194.01 103.25,194.01 102.49,193.24 87.81,193.24 86.79,192.23 71.45,192.23 70.56,193.12 70.56,202.69 67.56,205.69 67.56,216.33 67.56,216.34 67.56,218.42 68.84,219.7 77.54,219.7 77.84,219.39 77.84,216.38 77.21,215.75 77.21,203.43 77.51,203.12 77.51,201.89 78.12,201.28 88.71,201.28 89.32,201.9 89.32,202.68 89.71,203.07 89.71,218.77 90.27,219.33 95.69,219.33
(no net) on TOP: 35.31,196.09 35.44,195.96 35.95,195.96 36.71,196.72 36.71,199.39 36.7,199.39 37.03,199.72 37.03,200.56 36.75,200.84 35.59,200.84 35.31,200.56
(no net) on TOP: 113.92,41.27 111.12,41.27 111,41.4 111,43.31 111.38,43.69 113.67,43.69 114.05,43.31 114.05,41.4
(no net) on TOP: 26.44,228.94 26.64,229.14 26.64,229.32 26.82,229.5 27.25,229.5 27.35,229.39 27.35,228.25 27.22,228.12 25.83,228.12 25.32,227.62 23.67,227.62 23.41,227.87 21.51,227.87 21.13,228.25 11.48,228.25 10.59,229.14 10.59,237.27 11.35,238.03 21.38,238.03 22.53,236.89 22.53,232.44 26.03,228.94
(no net) on TOP: 34.87,122.83 34.87,125.53 35,125.65 35.64,125.65 35.76,125.53 35.76,124.64 36.02,124.38 36.02,122.89 35.84,122.71 35,122.71
(no net) on TOP: 39.9,143.36 35.41,143.36 35.13,143.64 35.13,144.22 34.82,144.53 31.93,144.53 31.7,144.75 31.7,151.23 31.07,151.87 31.07,153.59 31.4,153.92 35.92,153.92 36.17,153.67 36.17,148.26 37.09,147.35 39.78,147.35 40.21,146.91 40.21,143.66
(no net) on TOP: 29.39,163.37 30.73,163.37 32.82,165.46 38.28,165.46 38.61,165.13 38.61,162.81 38.25,162.46 33.48,162.46 32.87,163.07 29.39,163.07 29.36,163.09 29.36,163.35
(no net) on TOP: 31.88,192.4 33.66,192.4 33.79,192.27 33.79,191.39 32.64,190.24 32.64,187.32 32.52,187.19 30.87,187.19 30.61,187.45 30.61,191.13
(no net) on TOP: 29.01,164.26 28.7,164.26 28.65,164.31 28.65,164.8 28.09,165.35 27.28,165.35 27.03,165.61 27.03,166.22 27.18,166.37 28.42,166.37 28.63,166.17 28.63,165.71 29.03,165.3 29.03,164.29
(no net) on TOP: 156.08,41.27 153.29,41.27 153.16,41.4 153.16,43.31 153.54,43.69 155.83,43.69 156.21,43.31 156.21,41.4
(no net) on TOP: 31.11,38.43 31.34,38.2 31.34,37.16 28.57,34.39 28.57,27.56 30.89,25.25 30.89,13.23 32.49,11.63 37.41,11.63 37.69,11.35 37.69,9.63 37.49,9.42 35.38,9.42 35.1,9.7 31.47,9.7 30.05,11.13 29.08,11.13 28.47,11.73 28.47,23.47 25.27,26.67 25.27,34.29 29.41,38.43
(no net) on TOP: 143.21,55.32 143.21,57.96 142.88,58.29 140.97,58.29 140.72,58.04 140.72,55.37 141.1,54.99 142.88,54.99
(no net) on TOP: 29.59,42.55 32.13,42.55 32.26,42.42 32.26,41.78 31.37,40.89 31.37,39.24 31.11,38.99 29.46,38.99 29.21,39.24 29.21,42.16
(no net) on TOP: 182.37,38.86 182.12,39.12 182.12,41.15 182.25,41.27 185.04,41.27 185.29,41.02 185.29,39.12 185.04,38.86
(no net) on TOP: 30.43,103.2 30.13,103.2 30.08,103.25 30.08,103.73 29.52,104.29 28.7,104.29 28.45,104.55 28.45,105.16 28.6,105.31 29.85,105.31 30.05,105.11 30.05,104.65 30.46,104.24 30.46,103.23
(no net) on TOP: 153.03,57.86 155.83,57.86 155.96,57.73 155.96,55.83 155.57,55.45 153.29,55.45 152.91,55.83 152.91,57.73
(no net) on TOP: 31.37,195.2 36.07,195.2 37.21,196.34 37.21,199.26 37.47,199.52 38.61,199.52 38.86,199.26 38.86,186.81 38.39,186.33 36.7,186.33 36.33,186.71 36.33,190.37 36.58,190.62 36.58,192.66 36.07,193.16 31.5,193.16 29.6,191.26 29.6,189.23 28.2,189.23 27.82,189.61 27.82,191.64
(no net) on TOP: 34.04,197.97 33.78,197.71 33.78,196.08 33.66,195.96 33.15,195.96 32.9,196.21 32.9,196.21 32.64,196.47 32.64,201.93 36.55,205.84 39.88,205.84 41.53,207.49 41.53,213.23 40.89,213.87 40.89,215.26 41.02,215.39 43.05,215.39 43.43,215.01 43.43,206.5 40.74,203.81 37.62,203.81 34.04,200.23
(no net) on TOP: 29.85,186.69 32.26,186.69 32.52,186.43 32.52,184.15 32.26,183.89 29.98,183.89 29.47,184.4 29.47,186.31
(no net) on TOP: 184,193.52 185.88,193.52 186.72,192.68 186.72,183.85 184.61,181.74 172.14,181.74 171.63,181.23 169.72,181.23 169.44,181.51 169.44,183.39 169.95,183.9 183.85,183.9 184.94,184.99 184.94,191.85 184.56,192.23 184.07,192.23 183.87,192.02 181.23,192.02 181.1,192.15 181.1,192.84 181.31,193.04 183.51,193.04
(no net) on TOP: 92.35,232.92 92.35,229.24 92.61,228.99 93.75,228.99 93.88,228.86 93.88,223.74 93.64,223.51 89.79,223.51 89.39,223.9 89.38,223.9 89.23,224.05 89.23,226.99 88.44,227.79 88.44,232.4 89.2,233.16 92.12,233.16
(no net) on TOP: 180.34,194.44 180.34,189.99 181.74,188.59 184.53,188.59 184.68,188.44 184.68,186.97 184.53,186.82 171.58,186.82 171.2,187.2 171.2,189.1 171.58,189.48 175.51,189.48 175.77,189.23 177.8,189.23 178.31,189.74 178.31,194.31 176.4,196.22 174.37,196.22 174.37,197.61 174.75,197.99 176.78,197.99
(no net) on TOP: 74.27,233.29 74.27,229.61 74.52,229.36 75.7,229.36 75.74,229.31 75.74,229.31 75.74,224.06 75.56,223.88 71.24,223.88 70.35,224.76 70.35,232.77 71.11,233.53 74.03,233.53
(no net) on TOP: 31.92,230.79 34.21,230.79 34.72,230.28 34.72,228.76 34.59,228.63 32.94,228.63 32.43,228.12 29.51,228.12 29.26,228.38 29.26,229.39 29.38,229.52 30.65,229.52
(no net) on TOP: 39.62,42.55 42.16,42.55 42.29,42.42 42.29,41.78 41.4,40.89 41.4,39.24 41.15,38.99 39.5,38.99 39.24,39.24 39.24,42.16
(no net) on TOP: 115.36,85.32 115.1,85.58 113.15,85.58 112.98,85.75 112.98,87.15 112.85,87.27 111.33,87.27 111.07,87.02 111.07,84.99 111.2,84.86 112.6,84.86 112.73,84.73 112.73,83.34 112.85,83.21 114.63,83.21 115.57,84.15 117.88,84.15 118.01,84.02 118.01,83.92 117.91,83.82 117.12,83.82 116.89,83.59 115.65,83.59 114.76,82.7 113.49,82.7 113.23,82.45 110.38,82.45 109.65,83.17 109.65,87 110.9,88.24 113.92,88.24 116.19,85.97 116.75,85.97 117.07,85.65 117.9,85.65 117.98,85.57 117.98,85.39 117.91,85.32
(no net) on TOP: 30.78,224.06 30.78,220.76 30.15,220.12 26.84,220.12 26.08,220.88 26.08,224.31 27.61,225.84 27.61,229.39 27.73,229.52 28.88,229.52 29,229.39 29,225.84
(no net) on TOP: 38.3,167.97 33.81,167.97 33.53,168.25 33.53,168.83 33.22,169.14 30.33,169.14 30.1,169.37 30.1,175.84 29.46,176.48 29.46,178.21 29.79,178.54 34.32,178.54 34.57,178.28 34.57,172.87 35.48,171.96 38.18,171.96 38.61,171.53 38.61,168.28
(no net) on TOP: 35.51,233.81 39.17,233.81 39.59,233.38 39.59,217 39.37,216.77 32.38,216.77 31.16,217.99 31.16,224.06 29.26,225.96 29.26,227.74 29.38,227.87 30.91,227.87 31.03,227.74 34.21,227.74 35.23,228.76 35.23,233.52
(no net) on TOP: 35.71,126.97 35.71,127.86 35.51,128.07 35.51,128.96 35.38,129.08 32.92,129.08 32.82,128.98 32.82,127.81 32.94,127.69 34.87,127.69 35.05,127.51 35.05,127.05 35.15,126.95 35.69,126.95
(no net) on TOP: 23.06,177.5 28.52,177.5 28.85,177.16 28.85,176.07 28.35,175.56 28.35,169.85 29.36,168.83 32.59,168.83 32.74,168.68 32.74,167.67 32.44,167.36 30.05,167.36 29.62,166.93 29.62,165.58 29.51,165.48 29.51,164.29 29.69,164.11 30.61,164.11 30.71,164.01 30.71,163.68 30.58,163.55 28.4,163.55 28.3,163.45 27.18,163.45 26.57,164.06 22.91,164.06 22.45,164.52 22.45,176.89 ; 1 cut-out
(no net) on TOP: 76.12,249.16 76.12,235.7 76.37,235.44 76.37,234.81 76.63,234.55 76.63,231.34 76.94,231.04 78.08,231.04 78.13,230.99 78.13,229.62 78.08,229.57 74.63,229.57 74.55,229.64 74.55,233.27 73.71,234.11 71.23,234.11 71.22,234.11 70.56,234.11 70.15,234.53 70.15,249.03 70.78,249.67 75.61,249.67
(no net) on TOP: 11.48,215.8 25.57,215.8 26.21,216.44 30.27,216.44 30.91,215.8 39.39,215.8 39.47,215.72 39.47,210.91 37.64,209.07 11.6,209.07 11.1,209.58 11.1,215.42
(no net) on TOP: 177.55,193.93 177.55,192.15 177.42,192.02 176.53,192.02 175.39,193.17 172.47,193.17 172.34,193.29 172.34,194.94 172.59,195.2 176.28,195.2
(no net) on TOP, BOTTOM: 8.1,234.87 8.1,238.93 8.22,239.06 9.87,239.06 10,238.93 10,234.87 9.87,234.74 8.22,234.74
(no net) on TOP, BOTTOM: 7.33,238.93 7.33,235 6.7,234.36 1.62,234.36 1.37,234.62 1.37,239.19 1.87,239.7 6.57,239.7
(no net) on TOP, BOTTOM: 33.57,234.35 34.72,234.35 34.84,234.22 34.84,232.7 34.59,232.44 33.7,232.44 33.45,232.7 33.45,234.22
(no net) on BOTTOM: 204.28,94.41 203.72,94.41 203.49,94.64 201.36,94.64 201.21,94.79 201.21,96.03 201.41,96.24 204.23,96.24 204.51,95.96 204.51,94.64
(no net) on BOTTOM: 11.47,215.8 41.61,215.8 42.75,214.66 42.75,190.4 44.07,189.08 59.05,189.08 61.93,186.21 61.93,180.26 61.7,180.04 58.7,180.04 56.52,182.22 55.07,182.22 54.64,181.79 54.64,180.24 54.99,179.88 54.99,175.69 54.79,175.49 54.58,175.49 54.25,175.16 54.25,174.17 54.86,173.56 59.51,173.56 60.05,173.02 60.05,171.58 61.65,169.98 61.65,165.4 61.16,164.92 58.9,164.92 57.96,163.98 57.96,160.02 58.5,159.49 61.57,159.49 61.87,159.18 61.87,154.86 61.37,154.36 59.39,154.36 57.33,156.41 55.35,156.41 55.09,156.16 55.09,152.12 54.79,151.82 51.54,151.82 48.23,155.12 23.37,155.12 19.25,159.23 19.25,185.47 11.1,193.63 11.1,215.42
(no net) on BOTTOM: 134.34,45.34 122.68,45.34 122.4,45.06 121.01,45.06 120.14,45.92 120.14,49.4 120.4,49.66 120.4,50.55 120.14,50.8 120.14,53.21 120.9,53.98 134.24,53.98 134.75,53.47 134.75,49.81 134.47,49.53 134.47,45.47
(no net) on BOTTOM: 35.51,233.81 39.19,233.81 39.59,233.4 39.59,217 39.37,216.77 32.38,216.77 32.07,216.46 22.93,216.46 22.9,216.43 10.59,216.43 10.11,216.92 10.11,226.63 10.33,226.85 18.97,226.85 22.4,223.42 31.93,223.42 35.23,226.72 35.23,233.52
(no net) on BOTTOM: 95.17,231.22 95.17,234.17 94.89,234.45 94.89,235.46 95.15,235.72 95.15,239.28 93.39,241.03 85.26,241.03 83.36,239.13 83.36,234.69 82.98,234.31 79.38,234.31 78.2,233.14 78.2,231.52 78.08,231.39 77.06,231.39 76.93,231.52 76.93,234.69 76.81,234.82 76.81,235.83 77.06,236.09 77.06,250.52 77.86,251.33 100.51,251.33 101.07,250.77 101.07,234.67 101.09,234.65 101.09,232.36 99.69,230.96 95.43,230.96
(no net) on BOTTOM: 187.45,79.83 186.89,79.83 186.66,80.06 184.53,80.06 184.38,80.21 184.38,81.46 184.58,81.66 187.4,81.66 187.68,81.38 187.68,80.06
(no net) on BOTTOM: 202.91,93.65 201.06,93.65 200.89,93.47 200.89,91.9 201.09,91.69 202.9,91.69 203.15,91.95 203.15,93.41
(no net) on BOTTOM: 203.03,93.93 201.31,93.93 201.23,94 201.23,94.33 201.28,94.38 203.37,94.38 203.77,93.98 204.23,93.98 204.61,93.6 204.61,92.83 204.46,92.68 203.49,92.68 203.37,92.81 203.37,93.6
(no net) on BOTTOM: 119.13,89.1 119.13,86.69 120.65,85.17 125.4,85.17 125.76,84.81 125.76,82.17 125.48,81.89 125.48,79.35 126.31,78.51 128.73,78.51 128.75,78.54 128.75,88.93 127.69,89.99 120.02,89.99
(no net) on BOTTOM: 11.35,238.03 21.38,238.03 22.53,236.89 22.53,232.44 23.47,231.5 23.47,229.97 24.13,229.31 26.44,229.31 27.1,229.97 31.1,229.97 31.92,230.79 34.21,230.79 34.72,230.28 34.72,226.64 31.8,223.72 22.81,223.72 18.28,228.25 11.48,228.25 10.59,229.14 10.59,237.27
(no net) on BOTTOM: 176.53,45.34 164.85,45.34 164.34,44.83 163.45,44.83 162.94,45.34 162.94,47.75 162.31,48.39 162.31,49.4 162.56,49.66 162.56,50.55 162.31,50.8 162.31,53.37 162.92,53.98 176.4,53.98 176.91,53.47 176.91,45.72
(no net) on BOTTOM: 88.05,213.75 88.05,210.55 88.82,209.79 88.82,202.04 88.56,201.79 78.02,201.79 77.83,201.98 77.83,209.85 79.29,211.31 79.29,213.91 79.4,214.02 87.78,214.02
(no net) on BOTTOM: 186.21,79.35 184.48,79.35 184.4,79.43 184.4,79.76 184.45,79.81 186.54,79.81 186.94,79.4 187.4,79.4 187.78,79.02 187.78,78.26 187.63,78.11 186.66,78.11 186.54,78.23 186.54,79.02
(no net) on BOTTOM: 68.84,219.7 77.54,219.7 77.84,219.39 77.84,216.38 77.21,215.75 77.21,203.43 77.47,203.17 77.47,201.71 78.15,201.03 88.82,201.03 89.32,201.54 89.32,202.68 89.71,203.07 89.71,218.77 90.27,219.33 95.69,219.33 97.55,217.47 97.55,208.86 99.54,206.87 99.54,206.86 108.05,206.86 108.31,207.11 111.48,207.11 112.04,207.67 122.22,207.67 122.66,207.24 122.68,207.24 122.68,196.52 122.25,196.09 117.65,196.09 117.4,196.34 117.4,200.43 117.25,200.58 117.07,200.41 116.69,200.41 116.38,200.1 116.38,196.27 116.2,196.09 110.13,196.09 110.13,203.99 110.06,204.06 110.06,203.68 109.83,203.45 109.37,203.45 109.07,203.15 109.07,196.24 108.92,196.09 102.97,196.09 103,196.11 103,202.54 103.05,202.59 103.05,202.77 102.95,202.87 102.95,203.17 102.49,202.72 102.16,202.72 102.01,202.56 102.01,198.55 102.03,198.53 102.03,196.16 101.96,196.09 84.99,196.09 83.9,195 83.87,195 83.62,194.74 83.62,192.81 83.08,192.28 71.45,192.28 70.54,193.19 70.54,202.69 67.56,205.66 67.56,218.42
(no net) on BOTTOM: 76.12,249.16 76.12,235.7 76.37,235.44 76.37,234.75 76.58,234.54 76.58,231.37 76.91,231.04 77.72,231.04 77.88,230.89 77.88,229.72 77.83,229.67 74.42,229.67 74.32,229.77 72.87,229.77 72.26,229.16 70.23,229.16 70.15,229.24 70.15,229.94 70.15,229.95 70.15,249.03 70.78,249.67 75.61,249.67
CGND on TOP (solid shape): 221.4,23.81 209.35,23.81 209.35,25.81 221.4,25.81
CGND on TOP (solid shape): 249.9,23.81 237.85,23.81 237.85,25.81 249.9,25.81
CGND on TOP (solid shape): 264.15,23.81 252.1,23.81 252.1,25.81 264.15,25.81
CGND on TOP (solid shape): 235.65,23.81 223.6,23.81 223.6,25.58 223.73,25.58 223.73,25.81 235.65,25.81
CGND on TOP (solid shape): 211.58,43.35 209.35,43.35 209.35,28.85 221.6,28.85 221.6,43.35 219.07,43.35 219.07,44.35 225.78,44.35 225.78,43.35 223.6,43.35 223.6,28.85 235.83,28.85 235.83,43.35 233.32,43.35 233.32,44.35 240.08,44.35 240.08,43.35 237.83,43.35 237.83,28.85 250.08,28.85 250.08,43.35 247.57,43.35 247.57,44.35 254.43,44.35 254.43,43.35 252.11,43.35 252.11,28.85 264.29,28.85 264.29,43.35 261.87,43.35 261.87,44.35 266.35,44.35 266.35,3.28 207.34,3.28 207.34,44.35 211.58,44.35
CGND on TOP, BOTTOM: outline of 98 points within 31.17,0.76 198.04,34.44
CGND on L2_GND_1, L3_INT_1, L4_GND_2, L5_INT_2, L6_GND_3, L7_INT_3, L10_INT_4, L11_GND_4, L12_INT_5, L13_GND_5, L14_INT_6, L15_GND_6: outline of 122 points within 31.17,0.76 271.58,34.44
CGND on L8_PWR_1: outline of 125 points within 31.5,0.76 271.75,45.49
CGND on L9_PWR_2: outline of 127 points within 31.5,0.76 271.75,45.49
FAN1_PWM on TOP: 197.79,43.02 197.79,45.18 197.54,45.44 193.98,45.44 193.35,44.8 191.7,44.8 191.44,44.55 191.44,43.28 191.82,42.9 197.67,42.9
FAN1_TACH on TOP: 197.79,45.94 197.79,47.6 197.54,47.85 190.17,47.85 189.41,47.09 189.41,45.18 189.54,45.06 191.06,45.06 191.19,45.18 191.19,45.82 191.44,46.07 193.73,46.07 193.98,45.82 197.67,45.82
FAN2_PWM on TOP: 134.94,251.08 137.1,251.08 137.35,250.82 137.35,247.27 136.72,246.63 136.72,244.98 136.46,244.73 135.19,244.73 134.81,245.11 134.81,250.95
FAN2_TACH on TOP: 137.86,251.08 139.51,251.08 139.77,250.82 139.77,243.46 139,242.7 137.1,242.7 136.97,242.82 136.97,244.35 137.1,244.47 137.73,244.47 137.99,244.73 137.99,247.01 137.73,247.27 137.73,250.95
FAN3_PWM on TOP: 32.91,251.08 35.07,251.08 35.32,250.82 35.32,247.27 34.69,246.63 34.69,244.98 34.43,244.73 33.16,244.73 32.64,245.25 32.64,250.81
FAN3_TACH on TOP: 35.83,251.08 37.48,251.08 37.73,250.82 37.73,243.46 36.97,242.7 35.07,242.7 34.94,242.82 34.94,244.35 35.07,244.47 35.7,244.47 35.96,244.73 35.96,247.01 35.7,247.27 35.7,250.95
FAN4_PWM on TOP: 54.82,251.08 56.98,251.08 57.23,250.82 57.23,247.27 56.6,246.63 56.6,244.98 56.34,244.73 55.07,244.73 54.69,245.11 54.69,250.95
FAN4_TACH on TOP: 57.74,251.08 59.39,251.08 59.64,250.82 59.64,243.46 58.88,242.7 56.98,242.7 56.85,242.82 56.85,244.35 56.98,244.47 57.61,244.47 57.87,244.73 57.87,247.01 57.61,247.27 57.61,250.95
FAN5_PWM on TOP: 1.02,251.08 3.17,251.08 3.43,250.82 3.43,247.27 2.79,246.63 2.79,244.98 2.54,244.73 1.27,244.73 0.89,245.11 0.89,250.95
FAN5_TACH on TOP: 3.94,251.08 5.59,251.08 5.84,250.82 5.84,243.46 5.08,242.7 3.17,242.7 3.05,242.82 3.05,244.35 3.17,244.47 3.81,244.47 4.06,244.73 4.06,247.01 3.81,247.27 3.81,250.95
FPGA_PLL on BOTTOM: 50.65,70.84 54.41,70.84 54.69,70.56 54.69,68.76 54.23,68.3 51.16,68.3 50.6,68.86 50.6,70.79
FPGA_PLL on L10_INT_4: 53.9,70.84 58.29,70.84 59.89,72.44 60.96,72.44 61.11,72.29 61.11,69.42 60.05,68.35 54,68.35 53.54,68.81 53.54,70.48
GVDD on TOP (solid shape): 32.52,186.43 32.52,184.15 32.26,183.89 29.98,183.89 29.47,184.4 29.47,186.31 29.85,186.69 32.26,186.69
GVDD on TOP (solid shape): 30.91,215.8 39.39,215.8 39.47,215.72 39.47,210.91 37.64,209.07 11.6,209.07 11.1,209.58 11.1,215.42 11.48,215.8 25.57,215.8 26.21,216.44 30.27,216.44
GVDD on BOTTOM (solid shape): outline of 8504 points within 11.1,151.82 61.93,215.8
GVDD on TOP: 166.5,166.12 167.51,166.12 167.89,165.74 167.89,164.47 168.15,164.21 168.15,161.04 167.77,160.66 167.77,156.21 168.15,155.83 169.8,155.83 170.18,155.45 170.18,151.64 169.67,151.13 166.37,151.13 165.99,151.51 165.99,155.19 165.35,155.83 163.83,155.83 163.58,156.08 163.58,157.73 163.96,158.12 165.23,158.12 165.61,158.5 165.61,161.42 165.1,161.93 163.96,161.93 163.58,162.31 163.58,163.45 164.08,163.96 165.23,163.96 165.86,164.59 165.86,165.48
GVDD on TOP: 167.13,207.95 171.07,207.95 171.6,207.42 171.6,198.68 171.83,198.45 171.83,193.55 171.58,193.29 167.84,193.29 166.67,194.46 166.67,207.49
GVDD on TOP: 120.65,189.61 119.89,190.37 118.49,190.37 118.11,189.99 118.11,189.23 117.6,188.72 116.84,188.72 115.7,187.58 113.28,187.58 112.06,188.8 110.87,188.8 110.62,189.05 110.62,190.63 111.25,191.26 111.25,192.41 111.89,193.04 125.73,193.04 126.87,191.9 126.87,188.59 125.98,187.71 125.98,186.06 125.09,185.17 125.09,184.78 124.84,184.53 121.92,184.53 121.79,184.66 121.79,184.78 121.92,184.91 121.92,185.8 120.65,187.07
GVDD on TOP: 123.95,176.78 124.84,176.78 125.09,176.53 125.09,175.39 125.35,175.13 125.73,175.13 125.98,174.88 125.98,173.48 125.86,173.35 125.35,173.35 125.09,173.1 125.09,171.58 124.97,171.45 123.19,171.45 123.06,171.58 123.06,171.83 123.44,172.21 123.44,175.01 122.94,175.51 122.94,175.77
GVDD on TOP: 120.65,133.73 121.16,133.22 121.16,129.79 120.65,129.29 117.73,129.29 117.22,129.79 117.22,133.22 117.73,133.73
GVDD on BOTTOM: 124.08,139.19 124.08,140.72 124.46,141.1 125.73,141.1 125.86,140.97 125.86,139.19 125.48,138.81 124.46,138.81
GVDD on BOTTOM: 131.7,153.29 135.51,153.29 136.02,152.78 136.02,144.91 135.51,144.4 131.7,144.4 131.19,144.91 131.19,152.78
GVDD on BOTTOM: 125.27,185.8 123.44,185.8 123.19,186.06 123.19,187.2 123.47,187.48 125.37,187.48 125.6,187.25 125.6,186.13
GVDD on BOTTOM: 66.17,186.31 71.63,186.31 73.91,184.02 77.47,184.02 77.72,183.77 78.61,183.77 78.74,183.9 80.01,183.9 80.26,183.64 80.26,183.26 80.64,182.88 80.64,182.25 79.76,181.36 77.47,181.36 75.69,179.58 73.66,179.58 71.88,177.8 66.29,177.8 65.41,178.69 65.41,185.55 ; 1 cut-out
GVDD on BOTTOM: 135.51,177.8 132.97,177.8 131.57,179.2 131.57,180.59 132.08,181.1 135.38,181.1 135.76,180.72 135.76,178.05
GVDD on BOTTOM: 124.33,163.32 124.33,165.1 124.49,165.25 125.58,165.25 125.73,165.1 125.73,163.14 125.65,163.07 124.59,163.07
GVDD on L8_PWR_1: 1.63,216.26 37.85,216.26 41.46,219.87 74.79,219.87 77.77,216.89 77.77,198.37 89.92,186.23 89.92,174.5 92.74,171.68 92.74,155.04 93.22,154.56 106.55,154.56 107.65,153.47 107.65,141.25 109.73,139.17 114.02,139.17 117.91,135.28 128.42,135.28 133.53,140.39 155.6,140.39 157.02,141.81 157.02,234.14 157.89,235 179.12,235 180.39,233.73 180.39,120.42 169.06,109.09 101.32,109.09 80.7,129.72 67.54,129.72 58.57,120.75 41.66,120.75 39.04,123.37 39.04,154.18 32.84,160.38 1.82,160.38 1.2,161 1.2,215.83
GVDD on L9_PWR_2: 1.78,218.92 55.4,218.92 57.43,216.89 57.43,193.12 60.78,189.76 86.69,189.76 88.82,187.63 88.82,174.17 92.61,170.38 92.61,155.17 93.22,154.56 107.42,154.56 108.03,155.17 108.03,178.13 104.88,181.28 104.88,190.02 107.09,192.23 127.13,192.23 129.26,194.36 129.26,223.42 133.58,227.74 177.75,227.74 180.39,225.09 180.39,120.42 171.5,111.53 128.96,111.53 123.62,116.87 60.86,116.87 56.77,120.95 41.35,120.95 39.04,123.27 39.04,154.18 32.84,160.38 1.47,160.38 0.79,161.06 0.79,217.93
GVDD on L10_INT_4: 140.21,197.23 149.86,197.23 150.88,196.22 151.76,196.22 152.65,197.1 153.54,197.1 154.56,198.12 157.61,198.12 158.5,197.23 159.38,197.23 160.27,198.12 161.16,198.12 162.18,199.14 163.32,199.14 164.21,198.25 165.23,198.25 166.24,199.26 166.24,203.58 166.27,203.61 166.27,205.87 168.07,207.67 172.09,207.67 173.2,206.55 173.2,193.04 171.45,191.29 171.45,155.07 169.04,152.65 166.24,152.65 165.1,153.8 164.34,153.8 163.32,152.78 162.18,152.78 161.16,153.8 160.53,153.8 159.51,152.78 156.46,152.78 155.45,153.8 154.56,153.8 153.54,154.81 152.91,154.81 151.89,153.8 151,153.8 149.99,152.78 148.84,152.78 147.96,151.89 147.96,135.51 143.89,131.44 118.69,131.44 118.08,132.05 118.08,136.42 114.81,139.7 114.81,158.24 114.43,158.62 111.12,158.62 110.74,159 110.74,172.34 110.49,172.59 109.09,172.59 108.71,172.97 108.71,191.44 112.09,194.82 137.79,194.82
GVDD_GND on TOP (solid shape): 34.84,234.22 34.84,232.7 34.59,232.44 33.7,232.44 33.45,232.7 33.45,234.22 33.57,234.35 34.72,234.35
GVDD_GND on BOTTOM (solid shape): 34.84,234.22 34.84,232.7 34.59,232.44 33.7,232.44 33.45,232.7 33.45,234.22 33.57,234.35 34.72,234.35
GVDD_GND on L2_GND_1: 23.27,236.42 34.21,236.42 34.85,235.79 34.85,231.34 34.47,230.96 31.83,230.96 30.71,229.84 25.22,229.84 22.81,232.26 22.81,235.97
GVDD_SW on TOP (solid shape): 29,229.39 29,225.84 30.78,224.06 30.78,220.76 30.15,220.12 26.84,220.12 26.08,220.88 26.08,224.31 27.61,225.84 27.61,229.39 27.73,229.52 28.88,229.52
M_VREF_A on TOP (solid shape): 186.72,192.68 186.72,183.85 184.61,181.74 172.14,181.74 171.63,181.23 170.69,181.23 170.69,181.23 169.72,181.23 169.44,181.51 169.44,183.39 169.95,183.9 183.85,183.9 184.94,184.99 184.94,189.22 184.94,190.58 184.94,191.85 184.56,192.23 184.07,192.23 183.87,192.02 182.87,192.02 182.79,192.04 182.73,192.05 182.66,192.04 182.59,192.02 181.23,192.02 181.1,192.15 181.1,192.84 181.31,193.04 183.51,193.04 184,193.52 185.88,193.52
M_VREF_A on L14_INT_6: 168.71,184.02 170.94,184.02 171.15,183.82 171.15,167.16 170.89,166.9 169.88,166.9 168.33,168.45 168.33,183.64
M_VREF_B on TOP: 40.89,215.9 42.67,215.9 43.28,216.51 43.28,235.69 44.37,236.78 45.03,236.78 45.85,235.97 47.6,235.97 48.26,236.63 48.26,238.51 47.75,239.01 42.67,239.01 41.5,237.85 41.5,219.18 40.77,218.44 40.77,216.03
M_VTT_A on TOP: 175.17,192.98 175.62,192.53 175.62,191.47 175.16,191.01 170.76,191.01 170.46,191.31 168.28,191.31 167.89,190.93 167.89,184.28 167.64,184.02 164.13,184.02 163.45,184.71 162.43,184.71 161.65,183.92 160.2,183.92 157.89,186.23 157.89,190.78 158.24,191.13 159.21,191.13 160.3,192.23 165.35,192.23 166.1,192.98
M_VTT_A on TOP: 158.12,115.06 159.64,115.06 160.53,114.17 161.16,114.17 161.54,114.55 163.96,114.55 164.47,114.05 170.56,114.05 170.81,113.79 170.81,112.52 170.43,112.14 158.24,112.14 157.86,112.52 157.86,114.81
M_VTT_A on BOTTOM: 151.33,240.59 169.82,240.59 172.36,238.05 172.36,229.34 170.84,227.81 167.59,227.81 167.26,228.14 167.26,236.07 165.48,237.85 159.64,237.85 158.32,236.52 156.29,236.52 155.7,235.94 154.56,235.94 153.67,236.83 152.83,236.83 152.1,236.09 150.55,236.09 150.22,236.42 150.22,239.47
M_VTT_A on L3_INT_1: 152.78,167.13 153.8,167.13 154.81,168.15 155.96,168.15 156.97,169.16 156.97,183.77 159.26,186.06 164.08,186.06 165.54,187.52 165.54,193.1 166.62,194.18 166.62,197.87 166.24,198.25 166.24,230.38 166.62,230.76 170.05,230.76 172.09,228.73 172.09,182.37 172.05,182.33 172.05,179.69 171.09,178.74 171.09,116.56 171.15,116.51 171.15,115.49 168,112.34 161.7,112.34 161.54,112.5 161.54,114.71 162,115.16 163.4,115.16 164.39,114.17 165.35,114.17 166.24,115.06 166.24,147.19 167.26,148.21 167.26,163.32 166.75,163.83 163.96,163.83 162.94,162.81 162.31,162.81 161.29,161.8 160.53,161.8 159.51,160.78 158.12,160.78 157.73,160.4 156.72,160.4 156.34,160.02 154.56,160.02 152.91,161.67 149.22,161.67 147.19,163.7 147.19,167 147.45,167.26 149.86,167.26 151,166.12 151.76,166.12
M_VTT_B on TOP (solid shape): outline of 374 points within 32.9,113.16 49.53,191.01
OVDD on TOP: 238.35,236.4 240.33,236.4 240.64,236.09 240.64,234.24 240.31,233.91 238.38,233.91 238,234.29 238,236.04
OVDD on TOP: 39.73,106.91 35.23,106.91 34.95,107.19 34.95,107.77 34.65,108.08 31.75,108.08 31.52,108.31 31.52,114.78 30.89,115.42 30.89,118.54 31.04,118.69 37.34,118.69 38.1,117.93 38.1,113.31 40.03,111.38 40.03,107.21
OVDD on TOP: 69.8,156.01 69.6,155.8 69.6,155.27 69.8,155.07 69.8,153.92 69.6,153.72 69.6,153.49 69.8,153.29 69.8,153.03 69.6,152.83 69.6,152.6 69.85,152.35 69.85,150.09 69.62,149.86 69.14,149.86 68.28,150.72 68.28,158.24 68.81,158.78 69.42,158.78 69.8,158.39
OVDD on BOTTOM: 68.43,158.6 73.05,158.6 73.41,158.24 73.41,154.71 73.94,154.18 75.59,154.18 75.74,154.03 75.74,151.51 75.11,150.88 71.32,150.88 70.94,150.5 70.94,148.72 71.22,148.44 72.9,148.44 73.03,148.31 73.03,146.18 73.41,145.8 74.55,145.8 74.8,145.54 74.8,140.84 75.56,140.08 77.47,140.08 78.74,141.35 78.74,143.26 79.45,143.97 80.95,143.97 81.1,143.81 81.1,143.51 80.9,143.31 80.9,142.49 81.28,142.11 81.92,142.11 82.17,141.86 82.17,141.6 82.49,141.29 82.93,141.29 83.63,141.99 83.95,141.99 84.07,141.86 84.07,141.35 84,141.27 83.55,141.27 82.74,140.46 80.9,140.46 80.26,139.83 80.26,135.83 81.09,135 83.82,135 84.71,135.89 84.71,136.27 84.96,136.53 87.63,136.53 88.14,136.02 88.14,124.94 85.78,122.58 72.59,122.58 69.22,125.96 69.22,129.44 66.04,132.61 66.04,157.94 66.14,158.04 67.87,158.04
OVDD on BOTTOM: 97.23,87.45 98.4,87.45 98.63,87.68 98.63,89.05 98.32,89.36 97.21,89.36 97.03,89.18 97.03,87.66
OVDD on L3_INT_1: 31.47,117.7 35.76,117.7 36.35,117.12 36.35,104.17 43.97,96.55 43.97,76.05 62.26,57.76 62.26,45.11 67.97,39.4 75.95,39.4 81.81,45.26 91.62,45.26 96.88,40.01 96.88,38.23 96.16,37.52 94.44,37.52 90.27,41.68 84.76,41.68 78.64,35.56 65.51,35.56 57.81,43.26 57.81,55.58 39.32,74.07 39.32,95.91 32.92,102.31 32.92,112.62 31.04,114.5 31.04,117.27
OVDD on L8_PWR_1: 21.34,123.09 35.79,123.09 41.48,117.4 60.63,117.4 71.15,127.91 80.04,127.91 100.38,107.57 133.93,107.57 136.7,104.8 136.7,77.56 126.48,67.34 82.02,67.34 60.48,88.87 21.56,88.87 19.28,91.16 19.28,121.03
OVDD on L10_INT_4: 237.74,236.07 253.75,236.07 265.43,224.38 265.43,188.85 168.99,92.41 124.03,92.41 122.35,94.08 122.35,98.45 123.09,99.19 163.5,99.19 257.76,193.45 257.76,220.55 247.29,231.01 238.3,231.01 237.39,231.93 237.39,235.71
OVDD on L10_INT_4: 85.98,149 88.72,149 88.95,148.77 88.95,139.57 88.54,139.17 88.54,135.1 87.68,134.24 78.77,134.24 78.16,134.85 78.16,137.06 78.88,137.78 82.97,137.78 85.67,140.49 85.67,148.69
PEXBUFCOREV on TOP (solid shape): 115.62,110.01 115.62,108.33 115.37,108.08 112.19,108.08 111.91,108.36 111.91,109.91 112.24,110.24 115.39,110.24
PEXBUFCOREV on L3_INT_1: 112.34,109.6 113.84,109.6 114.55,108.89 114.55,98.4 113.74,97.59 108.92,97.59 107.7,98.81 107.7,101.32 108.18,101.8 109.07,101.8 109.68,101.19 109.68,100.03 109.91,99.8 111.71,99.8 112.22,100.3 112.22,101.7 111.56,102.36 111.56,108.81
PEXBUFIOV on TOP (solid shape): 104.7,109.78 104.7,108.48 104.32,108.1 102.5,108.1 101.54,109.07 101.43,109.16 101.3,109.22 101.3,110.01 101.5,110.21 104.27,110.21
PEXBUFIOV on L3_INT_1: 101.98,110.08 106.17,110.08 106.81,109.45 108.66,109.45 109.17,108.94 109.17,107.82 108.84,107.49 106.71,107.49 106.17,106.96 106.17,103.81 106.45,103.53 109.96,103.53 111.38,102.11 111.38,100.97 111.23,100.81 110.24,100.81 110.11,100.94 110.11,101.52 109.55,102.08 108.18,102.08 106.73,100.63 105.28,100.63 103.63,102.29 103.63,106.58 102.74,107.47 101.5,107.47 100.97,108 100.97,109.73 101.35,110.11 101.96,110.11
PHY0_AVDD18 on TOP (solid shape): 114.05,43.31 114.05,41.4 113.92,41.27 111.12,41.27 111,41.4 111,43.31 111.38,43.69 113.67,43.69
PHY0_AVDD18 on L10_INT_4: 123.09,61.06 140.77,61.06 143.61,58.22 143.61,43.87 141.63,41.88 111.35,41.88 110.67,42.57 110.67,47.6 111.66,48.59 137.54,48.59 138.33,49.38 138.33,56.01 137.77,56.57 135.15,56.57 134.37,55.78 130.43,55.78 129.21,57 125.86,57 124.46,55.6 122.02,55.6 121.36,56.26 121.36,59.33
PHY0_AVDD33 on TOP (solid shape): 143.13,41.02 143.13,39.12 142.88,38.86 140.21,38.86 139.95,39.12 139.95,41.15 140.08,41.27 142.88,41.27
PHY0_AVDD33 on L7_INT_3: 117.47,43.99 135.36,43.99 137.77,41.58 144.07,41.58 144.45,41.2 144.45,37.03 143.76,36.35 135.48,36.35 131.72,40.11 117.25,40.11 116.79,40.56 116.79,43.31
PHY0_VDDORL on TOP (solid shape): 143.21,57.96 143.21,55.32 142.88,54.99 141.1,54.99 140.72,55.37 140.72,58.04 140.97,58.29 142.88,58.29
PHY0_VDDORL on L3_INT_1: 142.11,59.64 142.62,59.13 142.62,53.26 140.44,51.08 140.44,48.34 139.5,47.4 134.11,47.4 133.58,47.93 133.58,52.6 131.98,54.2 123.95,54.2 122.43,52.68 122.43,44.88 121.44,43.89 117.55,43.89 116.15,45.29 116.15,56.41 119.38,59.64
PHY1_AVDD18 on TOP (solid shape): 156.21,43.31 156.21,41.4 156.08,41.27 153.29,41.27 153.16,41.4 153.16,43.31 153.54,43.69 155.83,43.69
PHY1_AVDD18 on L10_INT_4: 165.25,61.06 182.93,61.06 185.78,58.22 185.78,43.21 184.48,41.91 153.29,41.91 152.83,42.37 152.83,47.65 153.92,48.74 179.78,48.74 180.49,49.45 180.49,56.01 179.93,56.57 177.32,56.57 176.53,55.78 172.59,55.78 171.37,57 168.02,57 166.62,55.6 164.19,55.6 163.53,56.26 163.53,59.33
PHY1_AVDD33 on TOP (solid shape): 185.29,41.02 185.29,39.12 185.04,38.86 182.37,38.86 182.12,39.12 182.12,41.15 182.25,41.27 185.04,41.27
PHY1_AVDD33 on L7_INT_3: 159.82,43.92 181.28,43.92 183.97,41.22 186.23,41.22 187.12,40.34 187.12,35.66 186.82,35.36 179.04,35.36 175.29,39.12 159.51,39.12 159.13,39.5 159.13,43.23
PHY1_VDDORL on TOP (solid shape): 185.37,57.96 185.37,55.32 185.04,54.99 183.26,54.99 182.88,55.37 182.88,58.04 183.13,58.29 185.04,58.29
PHY1_VDDORL on L3_INT_1: 184.28,59.64 184.78,59.13 184.78,53.44 184.25,52.91 180.75,52.91 180.14,52.3 180.14,47.62 179.83,47.32 176.23,47.32 175.74,47.8 175.74,51.46 174.35,52.86 165.38,52.86 164.52,51.99 164.52,45.06 163.53,44.07 159.54,44.07 158.32,45.29 158.32,55.96 162,59.64
PHY_1V0 on TOP: 153.87,58.51 151.64,58.51 151.36,58.79 151.36,61.38 151.61,61.64 153.8,61.64 154.15,61.28 154.15,58.79
PHY_1V0 on TOP: 34.92,176.66 34.92,173.86 35.31,173.48 37.34,173.48 37.72,173.86 37.72,176.66 37.47,176.91 35.18,176.91
PHY_1V0 on TOP: 111.94,58.55 109.7,58.55 109.42,58.83 109.42,61.42 109.68,61.67 111.86,61.67 112.22,61.32 112.22,58.83
PHY_1V0 on L14_INT_6: 147.65,62.31 157.58,62.31 158.06,61.82 158.06,51.21 156.97,50.11 117.3,50.11 95.94,28.75 29.44,28.75 19.76,38.43 19.76,176.63 22.99,179.86 37.44,179.86 38.35,178.94 38.35,170.21 37.31,169.16 31.6,169.16 28.96,166.52 28.96,40.28 32.77,36.47 89.56,36.47 108.03,54.94 108.03,60.76 109.3,62.03 117.35,62.03 120.8,58.57 143.92,58.57
PHY_1V8 on TOP: 109.98,40.69 112.22,40.69 112.39,40.51 112.39,38.4 112.04,38.05 110.03,38.05 109.65,38.43 109.65,40.36
PHY_1V8 on TOP: 185.75,45.52 187.3,45.52 187.73,45.09 188.75,45.09 188.93,44.91 188.93,44.12 188.8,43.99 185.78,43.99 185.57,44.2 185.57,45.34
PHY_1V8 on TOP: 152.15,40.69 154.38,40.69 154.56,40.51 154.56,38.4 154.2,38.05 152.2,38.05 151.82,38.43 151.82,40.36
PHY_1V8 on TOP: 199.77,71.88 199.77,67.39 199.49,67.11 198.91,67.11 198.53,66.73 198.53,63.83 198.37,63.68 191.9,63.68 191.26,63.04 189.53,63.04 189.2,63.37 189.2,67.9 189.46,68.15 194.87,68.15 195.78,69.06 195.78,71.76 196.22,72.19 199.47,72.19
PHY_1V8 on TOP: 143.59,45.52 145.57,45.52 145.72,45.67 146.53,45.67 146.76,45.44 146.76,44.27 146.48,43.99 143.61,43.99 143.41,44.2 143.41,45.34
PHY_1V8 on L3_INT_1: 189.13,70.21 199.19,70.21 201.68,67.72 201.68,33.68 197.51,29.51 183.29,29.51 177.62,35.18 170.76,35.18 165.1,29.51 140.28,29.51 134.52,35.28 129.29,35.28 123.52,29.51 109.65,29.51 105.18,33.99 105.18,42.09 107.11,44.02 116.03,44.02 117.65,42.39 121.44,42.39 125.43,46.38 151.64,46.38 154.25,43.76 165.68,43.76 168.35,46.43 182.8,46.43 186.79,50.42 186.79,67.87
PHY_1V8 on L10_INT_4: 108.41,40.82 142.6,40.82 144.42,42.65 144.42,45.16 145.21,45.95 150.55,45.95 151.16,45.34 151.16,42.44 152.55,41.05 185.98,41.05 186.77,41.83 186.77,45.16 188.82,47.22 188.82,59.89 187.25,61.47 187.25,67.84 188.47,69.06 199.97,69.06 201.68,67.36 201.68,33.66 197.46,29.44 183.34,29.44 177.57,35.2 170.84,35.2 165.13,29.49 140.36,29.49 134.57,35.28 129.11,35.28 123.77,29.95 109.7,29.95 106.71,32.94 106.71,39.12
POVDD on TOP (solid shape): 35.51,128.96 35.51,128.07 35.71,127.86 35.71,126.97 35.69,126.95 35.15,126.95 35.05,127.05 35.05,127.51 34.87,127.69 33.73,127.69 32.94,127.69 32.82,127.81 32.82,128.98 32.92,129.08 35.38,129.08
POVDD on TOP: 64.72,146.74 65.13,146.33 65.13,143.21 64.74,142.82 63.55,142.82 63.17,143.21 63.17,146.28 63.63,146.74
POVDD on BOTTOM: 63.09,146.69 64.14,146.69 64.34,146.48 64.34,142.42 59.64,137.72 59.64,119.79 59.26,119.41 57.05,119.41 56.67,119.79 56.67,137.82 62.81,143.97 62.81,146.41
POVDD on L3_INT_1: 32.74,131.11 39.24,131.11 42.29,128.07 42.29,115.06 44.55,112.8 55.3,112.8 57.73,115.24 57.73,121.11 58.27,121.64 60.35,121.64 60.78,121.21 60.78,112.7 57.35,109.27 42.01,109.27 38.02,113.26 38.02,126.11 37.08,127.05 32.74,127.05 31.95,127.84 31.95,130.33
PROG_MTR on L5_INT_2: 93.98,156.21 93.73,155.96 93.09,155.96 92.46,156.59 88.14,156.59 88.01,156.46 88.01,155.96 85.6,153.54 77.09,153.54 74.17,150.62 70.61,150.62 70.23,150.24 70.23,149.43 69.9,149.1 68,149.1 67.59,149.5 67.59,151.79 68.4,152.6 73.36,152.6 76.58,155.83 85.47,155.83 87.38,157.73 88.39,157.73 88.65,157.99 88.65,158.5 88.9,158.75 93.6,158.75 93.98,158.37
PROG_SFP on TOP: 67.64,148.67 68.05,148.26 68.05,147.4 68.17,147.27 68.17,146.76 67.97,146.56 67.97,145.57 67.69,145.29 65.91,145.29 65.66,145.54 65.66,146.79 65.23,147.22 65.23,148.62 65.53,148.92 66.5,148.92 66.75,148.67
PROG_SFP on L5_INT_2: 92.96,155.57 93.47,155.57 93.73,155.32 93.73,154.94 93.34,154.56 89.15,154.56 84.2,149.61 81.15,149.61 80.64,149.1 76.68,149.1 76.12,148.54 73.58,148.54 70.26,145.21 67.89,145.21 67.39,145.72 67.39,147.4 67.79,147.8 69.37,147.8 71.81,150.24 74.35,150.24 76,151.89 77.22,151.89 78.11,152.78 85.47,152.78 88.52,155.83 92.71,155.83
RT1_2V5 on BOTTOM (solid shape): 187.68,81.38 187.68,80.06 187.45,79.83 186.89,79.83 186.66,80.06 184.53,80.06 184.38,80.21 184.38,81.46 184.58,81.66 187.4,81.66
RT1_2V5 on L3_INT_1: 183.57,96.39 187.45,96.39 188.54,95.3 188.54,80.62 188.14,80.21 184.81,80.21 184.53,80.49 184.53,84.66 183.97,85.22 183.97,86.56 185.45,88.04 185.45,93.57 184.81,94.21 183.57,94.21 183.13,94.64 183.13,95.96
RT2_2V5 on BOTTOM (solid shape): 204.51,95.96 204.51,94.64 204.28,94.41 203.72,94.41 203.49,94.64 201.36,94.64 201.21,94.79 201.21,96.03 201.41,96.24 204.23,96.24
RT2_2V5 on L3_INT_1: 200.23,110.9 204.11,110.9 205.21,109.8 205.21,95.12 204.8,94.72 201.44,94.72 201.13,95.03 201.13,99.23 200.63,99.72 200.63,101.07 202.11,102.54 202.11,108.08 201.47,108.71 200.23,108.71 199.8,109.14 199.8,110.46
SER1_GND on TOP: 72.09,30.45 73.71,30.45 73.89,30.28 73.89,29.18 73.74,29.03 72.06,29.03 71.86,29.24 71.86,30.23
SER1_GND on BOTTOM: 64.36,30.66 73.94,30.66 74.42,30.18 74.42,28.02 73.76,27.36 64.16,27.36 63.8,27.71 63.8,30.1
SER2_GND on TOP: 51.77,30.3 53.72,30.3 54.08,29.95 54.08,28.85 53.77,28.55 51.87,28.55 51.51,28.91 51.51,30.05
SER2_GND on BOTTOM: 51.79,30.63 62.15,30.63 62.59,30.2 62.59,27.97 62,27.38 52.04,27.38 51.31,28.12 51.31,30.15
SI5341_VDD on BOTTOM (solid shape): outline of 662 points within 119.13,78.51 128.75,89.99
USB1_ISOPWR on TOP (solid shape): outline of 124 points within 25.27,9.42 37.69,38.43
USB2_ISOPWR on TOP (solid shape): outline of 86 points within 33.58,12.01 41.38,38.48
USB_HVDD on BOTTOM: 90.04,152.78 90.04,152.53 89.41,151.89 89.41,151.51 90.55,150.37 90.55,150.05 89.92,149.42 89.6,149.42 89.47,149.54 88.76,149.54 87.91,148.69 87.91,146.56 86.74,146.56 86.54,146.76 86.54,148.29 86.36,148.46 86.36,150.62 87.5,151.76 88.39,151.76 89.53,152.91 89.92,152.91
